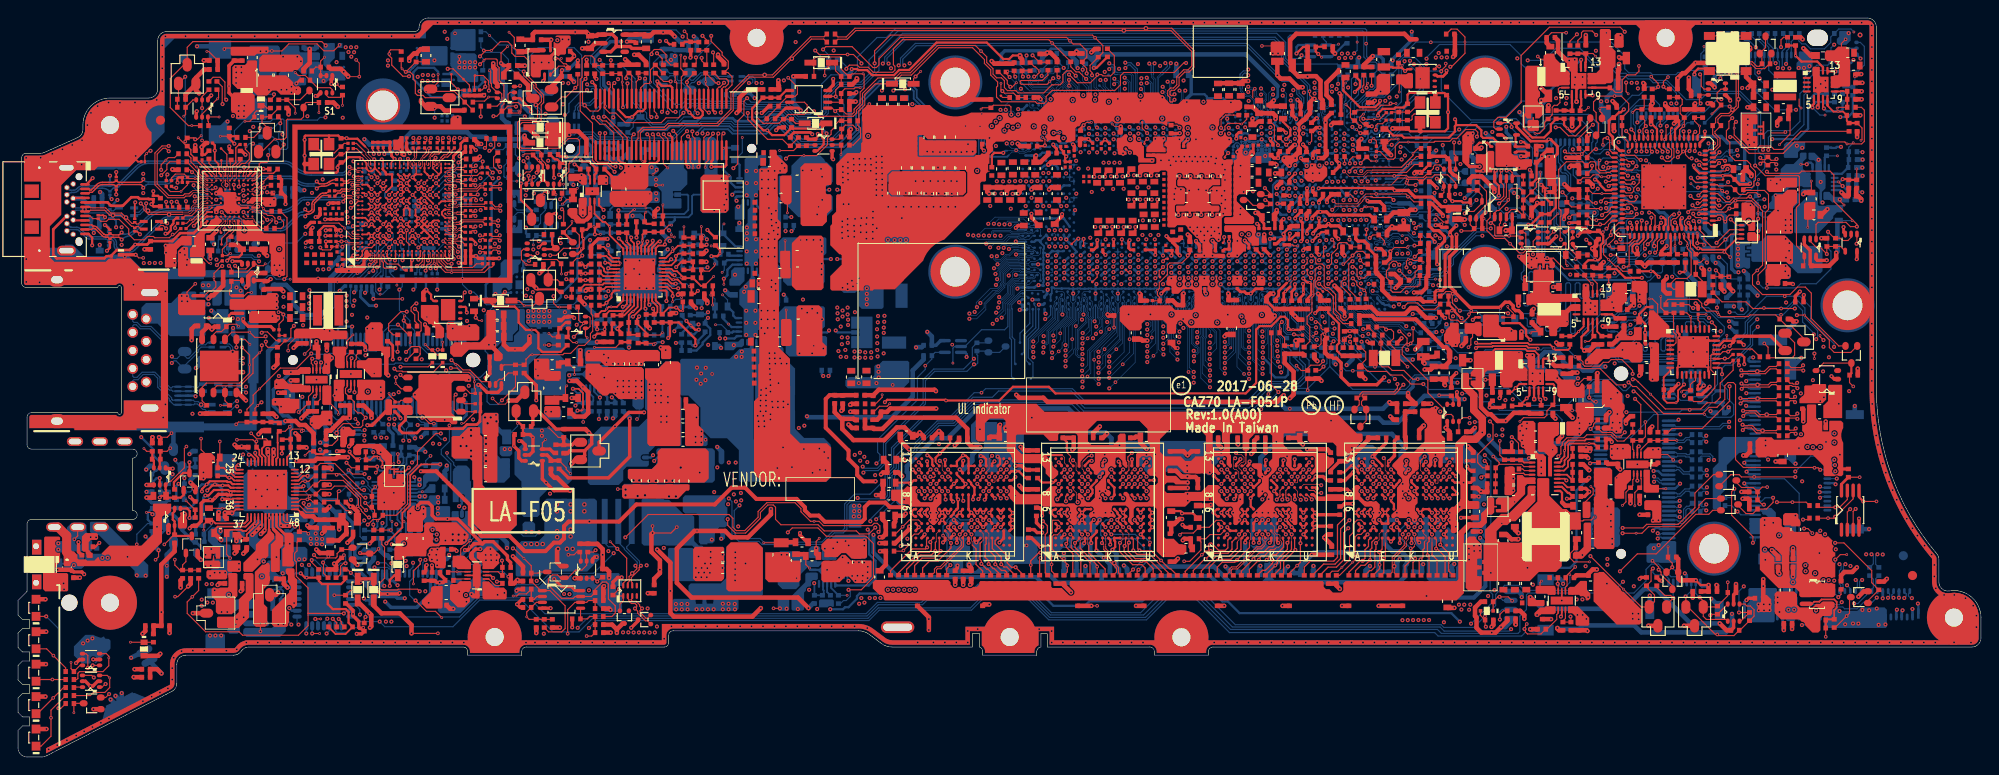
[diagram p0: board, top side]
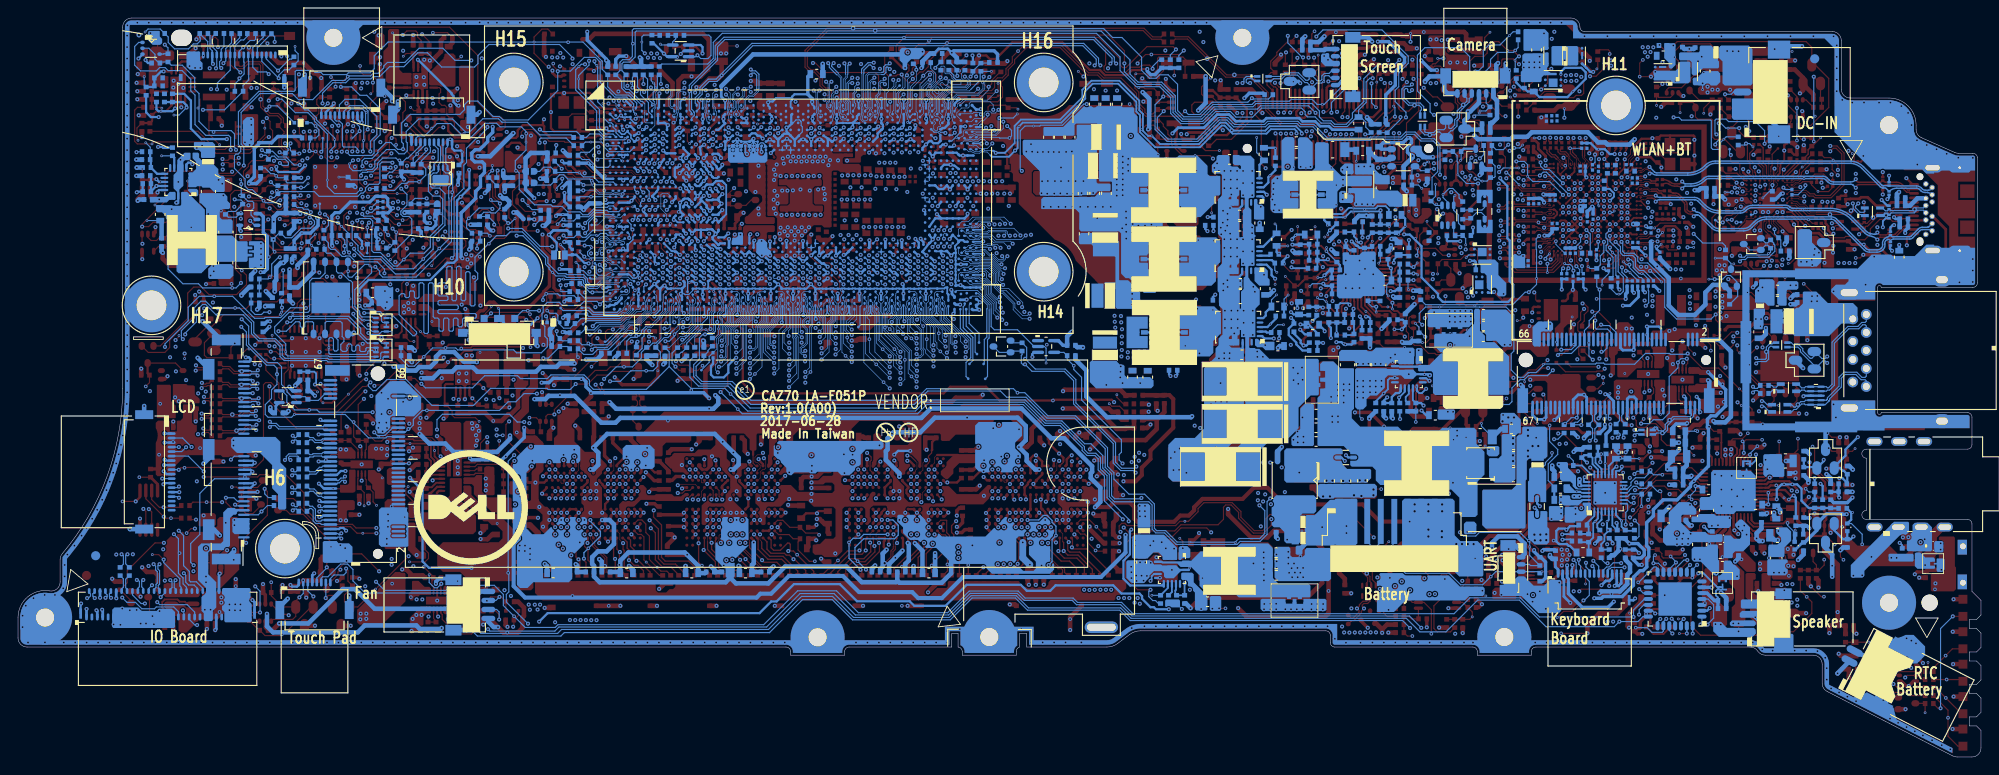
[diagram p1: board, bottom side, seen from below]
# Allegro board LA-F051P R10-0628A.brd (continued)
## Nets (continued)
DDI2_PTX_TBRX_N2_C: CT34.1 UT1.AC19
DDI2_PTX_TBRX_N3: CT36.2 UCPU1.D51
DDI2_PTX_TBRX_N3_C: CT36.1 UT1.AC21
DDI2_PTX_TBRX_P0: CT29.2 UCPU1.D50
DDI2_PTX_TBRX_P0_C: CT29.1 UT1.AB15
DDI2_PTX_TBRX_P1: CT31.2 UCPU1.D52
DDI2_PTX_TBRX_P1_C: CT31.1 UT1.AB17
DDI2_PTX_TBRX_P2: CT33.2 UCPU1.B50
DDI2_PTX_TBRX_P2_C: CT33.1 UT1.AB19
DDI2_PTX_TBRX_P3: CT35.2 UCPU1.C51
DDI2_PTX_TBRX_P3_C: CT35.1 UT1.AB21
DDR_A0_ZQ0: RD51.1 UD19.B3
DDR_A0_ZQ1: RD53.1 UD19.B4
DDR_A1_ZQ0: RD52.1 UD20.B3
DDR_A1_ZQ1: RD54.1 UD20.B4
DDR_A_CA1_0: RD59.1 UCPU1.BA51 UD19.R2
DDR_A_CA1_1: RD61.1 UCPU1.BB54 UD19.P2
DDR_A_CA1_2: RD63.1 UCPU1.BA52 UD19.N2
DDR_A_CA1_3: RD65.1 UCPU1.AY52 UD19.N3
DDR_A_CA1_4: RD67.1 UCPU1.AW52 UD19.M3
DDR_A_CA1_5: RD69.1 UCPU1.AY55 UD19.F3
DDR_A_CA1_6: RD71.1 UCPU1.AW54 UD19.E3
DDR_A_CA1_7: RD73.1 UCPU1.BA54 UD19.E2
DDR_A_CA1_8: RD75.1 UCPU1.BA55 UD19.D2
DDR_A_CA1_9: RD77.1 UCPU1.AY54 UD19.C2
DDR_A_CA2_0: RD79.1 UCPU1.AU46 UD20.R2
DDR_A_CA2_1: RD81.1 UCPU1.AU48 UD20.P2
DDR_A_CA2_2: RD83.1 UCPU1.AT46 UD20.N2
DDR_A_CA2_3: RD85.1 UCPU1.AU50 UD20.N3
DDR_A_CA2_4: RD87.1 UCPU1.AU52 UD20.M3
DDR_A_CA2_5: RD89.1 UCPU1.AY51 UD20.F3
DDR_A_CA2_6: RD91.1 UCPU1.AT48 UD20.E3
DDR_A_CA2_7: RD93.1 UCPU1.AT50 UD20.E2
DDR_A_CA2_8: RD95.1 UCPU1.BB50 UD20.D2
DDR_A_CA2_9: RD97.1 UCPU1.AY50 UD20.C2
DDR_A_CKE0: RD103.1 UCPU1.BA56 UD19.K3
DDR_A_CKE1: RD105.1 UCPU1.BB56 UD19.K4
DDR_A_CKE2: RD107.1 UCPU1.AW56 UD20.K3
DDR_A_CKE3: RD109.1 UCPU1.AY56 UD20.K4
DDR_A_CLK0: RD35.1 UCPU1.AT53 UD19.J3
DDR_A_CLK1: RD46.1 UCPU1.AT55 UD20.J3
DDR_A_CLK#0: RD37.1 UCPU1.AU53 UD19.J2
DDR_A_CLK#1: RD45.1 UCPU1.AU55 UD20.J2
DDR_A_CS#0: RD99.1 UCPU1.AU45 UD19.L3 UD20.L3
DDR_A_CS#1: RD101.1 UCPU1.AU43 UD19.L4 UD20.L4
DDR_A_D0: UCPU1.AL71 UD19.C8
DDR_A_D1: UCPU1.AL68 UD19.B11
DDR_A_D2: UCPU1.AN68 UD19.C9
DDR_A_D3: UCPU1.AN69 UD19.B10
DDR_A_D4: UCPU1.AL70 UD19.B9
DDR_A_D5: UCPU1.AL69 UD19.B8
DDR_A_D6: UCPU1.AN70 UD19.C11
DDR_A_D7: UCPU1.AN71 UD19.C10
DDR_A_D8: UCPU1.AR70 UD19.R10
DDR_A_D9: UCPU1.AR68 UD19.R11
DDR_A_D10: UCPU1.AU71 UD19.R9
DDR_A_D11: UCPU1.AU68 UD19.T10
DDR_A_D12: UCPU1.AR71 UD19.T11
DDR_A_D13: UCPU1.AR69 UD19.R8
DDR_A_D14: UCPU1.AU70 UD19.T9
DDR_A_D15: UCPU1.AU69 UD19.T8
DDR_A_D16: UCPU1.AF65 UD19.N9
DDR_A_D17: UCPU1.AF64 UD19.M8
DDR_A_D18: UCPU1.AK65 UD19.N11
DDR_A_D19: UCPU1.AK64 UD19.N10
DDR_A_D20: UCPU1.AF66 UD19.M9
DDR_A_D21: UCPU1.AF67 UD19.P9
DDR_A_D22: UCPU1.AK67 UD19.M11
DDR_A_D23: UCPU1.AK66 UD19.M10
DDR_A_D24: UCPU1.AF70 UD19.F11
DDR_A_D25: UCPU1.AF68 UD19.F10
DDR_A_D26: UCPU1.AH71 UD19.D9
DDR_A_D27: UCPU1.AH68 UD19.F8
DDR_A_D28: UCPU1.AF71 UD19.E10
DDR_A_D29: UCPU1.AF69 UD19.E11
DDR_A_D30: UCPU1.AH70 UD19.E9
DDR_A_D31: UCPU1.AH69 UD19.F9
DDR_A_D32: UCPU1.BB65 UD20.B9
DDR_A_D33: UCPU1.AW65 UD20.C11
DDR_A_D34: UCPU1.AW63 UD20.B11
DDR_A_D35: UCPU1.AY63 UD20.C8
DDR_A_D36: UCPU1.BA65 UD20.B8
DDR_A_D37: UCPU1.AY65 UD20.B10
DDR_A_D38: UCPU1.BA63 UD20.C10
DDR_A_D39: UCPU1.BB63 UD20.C9
DDR_A_D40: UCPU1.BA61 UD20.T9
DDR_A_D41: UCPU1.AW61 UD20.R9
DDR_A_D42: UCPU1.BB59 UD20.T11
DDR_A_D43: UCPU1.AW59 UD20.T10
DDR_A_D44: UCPU1.BB61 UD20.R8
DDR_A_D45: UCPU1.AY61 UD20.T8
DDR_A_D46: UCPU1.BA59 UD20.R10
DDR_A_D47: UCPU1.AY59 UD20.R11
DDR_A_D48: UCPU1.AT66 UD20.E10
DDR_A_D49: UCPU1.AU66 UD20.F10
DDR_A_D50: UCPU1.AP65 UD20.F8
DDR_A_D51: UCPU1.AN65 UD20.D9
DDR_A_D52: UCPU1.AN66 UD20.E9
DDR_A_D53: UCPU1.AP66 UD20.E11
DDR_A_D54: UCPU1.AT65 UD20.F9
DDR_A_D55: UCPU1.AU65 UD20.F11
DDR_A_D56: UCPU1.AT61 UD20.N9
DDR_A_D57: UCPU1.AU61 UD20.M9
DDR_A_D58: UCPU1.AP60 UD20.N11
DDR_A_D59: UCPU1.AN60 UD20.N10
DDR_A_D60: UCPU1.AN61 UD20.M8
DDR_A_D61: UCPU1.AP61 UD20.P9
DDR_A_D62: UCPU1.AT60 UD20.M10
DDR_A_D63: UCPU1.AU60 UD20.M11
DDR_A_DQS0: UCPU1.AM69 UD19.D10
DDR_A_DQS1: UCPU1.AT70 UD19.P10
DDR_A_DQS2: UCPU1.AH65 UD19.L10
DDR_A_DQS3: UCPU1.AG70 UD19.G10
DDR_A_DQS4: UCPU1.AY64 UD20.D10
DDR_A_DQS5: UCPU1.BA60 UD20.P10
DDR_A_DQS6: UCPU1.AR65 UD20.G10
DDR_A_DQS7: UCPU1.AR60 UD20.L10
DDR_A_DQS#0: UCPU1.AM70 UD19.D11
DDR_A_DQS#1: UCPU1.AT69 UD19.P11
DDR_A_DQS#2: UCPU1.AH66 UD19.L11
DDR_A_DQS#3: UCPU1.AG69 UD19.G11
DDR_A_DQS#4: UCPU1.BA64 UD20.D11
DDR_A_DQS#5: UCPU1.AY60 UD20.P11
DDR_A_DQS#6: UCPU1.AR66 UD20.G11
DDR_A_DQS#7: UCPU1.AR61 UD20.L11
DDR_A_ODT0: RD117.1 UCPU1.AT45 UD19.J8 UD20.J8
DDR_B0_ZQ0: RD57.1 UD21.B3
DDR_B0_ZQ1: RD58.1 UD21.B4
DDR_B1_ZQ0: RD55.1 UD22.B3
DDR_B1_ZQ1: RD56.1 UD22.B4
DDR_B_CA1_0: RD60.1 UCPU1.AY48 UD21.R2
DDR_B_CA1_1: RD62.1 UCPU1.AP50 UD21.P2
DDR_B_CA1_2: RD64.1 UCPU1.BA48 UD21.N2
DDR_B_CA1_3: RD66.1 UCPU1.BB48 UD21.N3
DDR_B_CA1_4: RD68.1 UCPU1.AP48 UD21.M3
DDR_B_CA1_5: RD70.1 UCPU1.AP52 UD21.F3
DDR_B_CA1_6: RD72.1 UCPU1.AN50 UD21.E3
DDR_B_CA1_7: RD74.1 UCPU1.AN48 UD21.E2
DDR_B_CA1_8: RD76.1 UCPU1.AN53 UD21.D2
DDR_B_CA1_9: RD78.1 UCPU1.AN52 UD21.C2
DDR_B_CA2_0: RD80.1 UCPU1.BA43 UD22.R2
DDR_B_CA2_1: RD82.1 UCPU1.AY43 UD22.P2
DDR_B_CA2_2: RD84.1 UCPU1.AY44 UD22.N2
DDR_B_CA2_3: RD86.1 UCPU1.AW44 UD22.N3
DDR_B_CA2_4: RD88.1 UCPU1.BB44 UD22.M3
DDR_B_CA2_5: RD90.1 UCPU1.AY47 UD22.F3
DDR_B_CA2_6: RD92.1 UCPU1.BA44 UD22.E3
DDR_B_CA2_7: RD94.1 UCPU1.AW46 UD22.E2
DDR_B_CA2_8: RD96.1 UCPU1.AY46 UD22.D2
DDR_B_CA2_9: RD98.1 UCPU1.BA46 UD22.C2
DDR_B_CKE0: RD104.1 UCPU1.AN56 UD21.K3
DDR_B_CKE1: RD106.1 UCPU1.AP55 UD21.K4
DDR_B_CKE2: RD108.1 UCPU1.AN55 UD22.K3
DDR_B_CKE3: RD110.1 UCPU1.AP53 UD22.K4
DDR_B_CLK0: RD36.1 UCPU1.AP45 UD21.J3
DDR_B_CLK1: RD47.1 UCPU1.AP46 UD22.J3
DDR_B_CLK#0: RD38.1 UCPU1.AN45 UD21.J2
DDR_B_CLK#1: RD48.1 UCPU1.AN46 UD22.J2
DDR_B_CS#0: RD100.1 UCPU1.BB42 UD21.L3 UD22.L3
DDR_B_CS#1: RD102.1 UCPU1.AY42 UD21.L4 UD22.L4
DDR_B_D0: UCPU1.AY39 UD21.E11
DDR_B_D1: UCPU1.AW39 UD21.F10
DDR_B_D2: UCPU1.AY37 UD21.F11
DDR_B_D3: UCPU1.AW37 UD21.D9
DDR_B_D4: UCPU1.BB39 UD21.F9
DDR_B_D5: UCPU1.BA39 UD21.E10
DDR_B_D6: UCPU1.BA37 UD21.F8
DDR_B_D7: UCPU1.BB37 UD21.E9
DDR_B_D8: UCPU1.AY35 UD21.T11
DDR_B_D9: UCPU1.AW35 UD21.T10
DDR_B_D10: UCPU1.AY33 UD21.T9
DDR_B_D11: UCPU1.AW33 UD21.R9
DDR_B_D12: UCPU1.BB35 UD21.R11
DDR_B_D13: UCPU1.BA35 UD21.R10
DDR_B_D14: UCPU1.BA33 UD21.T8
DDR_B_D15: UCPU1.BB33 UD21.R8
DDR_B_D16: UCPU1.AU40 UD21.B10
DDR_B_D17: UCPU1.AT40 UD21.B9
DDR_B_D18: UCPU1.AT37 UD21.C11
DDR_B_D19: UCPU1.AU37 UD21.B11
DDR_B_D20: UCPU1.AR40 UD21.B8
DDR_B_D21: UCPU1.AP40 UD21.C8
DDR_B_D22: UCPU1.AP37 UD21.C9
DDR_B_D23: UCPU1.AR37 UD21.C10
DDR_B_D24: UCPU1.AT33 UD21.N11
DDR_B_D25: UCPU1.AU33 UD21.M10
DDR_B_D26: UCPU1.AU30 UD21.N9
DDR_B_D27: UCPU1.AT30 UD21.P9
DDR_B_D28: UCPU1.AR33 UD21.M11
DDR_B_D29: UCPU1.AP33 UD21.N10
DDR_B_D30: UCPU1.AR30 UD21.M8
DDR_B_D31: UCPU1.AP30 UD21.M9
DDR_B_D32: UCPU1.AY31 UD22.E11
DDR_B_D33: UCPU1.AW31 UD22.F8
DDR_B_D34: UCPU1.AY29 UD22.F9
DDR_B_D35: UCPU1.AW29 UD22.E9
DDR_B_D36: UCPU1.BB31 UD22.D9
DDR_B_D37: UCPU1.BA31 UD22.E10
DDR_B_D38: UCPU1.BA29 UD22.F10
DDR_B_D39: UCPU1.BB29 UD22.F11
DDR_B_D40: UCPU1.AY27 UD22.B8
DDR_B_D41: UCPU1.AW27 UD22.C8
DDR_B_D42: UCPU1.AY25 UD22.B9
DDR_B_D43: UCPU1.AW25 UD22.B10
DDR_B_D44: UCPU1.BB27 UD22.C10
DDR_B_D45: UCPU1.BA27 UD22.C9
DDR_B_D46: UCPU1.BA25 UD22.C11
DDR_B_D47: UCPU1.BB25 UD22.B11
DDR_B_D48: UCPU1.AU27 UD22.T10
DDR_B_D49: UCPU1.AT27 UD22.T11
DDR_B_D50: UCPU1.AT25 UD22.T9
DDR_B_D51: UCPU1.AU25 UD22.R9
DDR_B_D52: UCPU1.AP27 UD22.R11
DDR_B_D53: UCPU1.AN27 UD22.R10
DDR_B_D54: UCPU1.AN25 UD22.R8
DDR_B_D55: UCPU1.AP25 UD22.T8
DDR_B_D56: UCPU1.AT22 UD22.M9
DDR_B_D57: UCPU1.AU22 UD22.N9
DDR_B_D58: UCPU1.AU21 UD22.M11
DDR_B_D59: UCPU1.AT21 UD22.N11
DDR_B_D60: UCPU1.AN22 UD22.M8
DDR_B_D61: UCPU1.AP22 UD22.P9
DDR_B_D62: UCPU1.AP21 UD22.M10
DDR_B_D63: UCPU1.AN21 UD22.N10
DDR_B_DQS0: UCPU1.AY38 UD21.G10
DDR_B_DQS1: UCPU1.BA34 UD21.P10
DDR_B_DQS2: UCPU1.AR38 UD21.D10
DDR_B_DQS3: UCPU1.AR32 UD21.L10
DDR_B_DQS4: UCPU1.AY30 UD22.G10
DDR_B_DQS5: UCPU1.BA26 UD22.D10
DDR_B_DQS6: UCPU1.AR27 UD22.P10
DDR_B_DQS7: UCPU1.AR21 UD22.L10
DDR_B_DQS#0: UCPU1.BA38 UD21.G11
DDR_B_DQS#1: UCPU1.AY34 UD21.P11
DDR_B_DQS#2: UCPU1.AT38 UD21.D11
DDR_B_DQS#3: UCPU1.AT32 UD21.L11
DDR_B_DQS#4: UCPU1.BA30 UD22.G11
DDR_B_DQS#5: UCPU1.AY26 UD22.D11
DDR_B_DQS#6: UCPU1.AR25 UD22.P11
DDR_B_DQS#7: UCPU1.AR22 UD22.L11
DDR_B_ODT0: RD118.1 UCPU1.BA42 UD21.J8 UD22.J8
DDR_CHA_EN: RH440.1 RH442.1 UCPU1.U2
DDR_CHB_EN: RH441.1 RH443.1 UCPU1.U1
DDR_ILMT: PR604.2 PR606.1 PU600.17
DDR_VTT_CNTL: UC2.2 UCPU1.AW67
DDR_XDP_SMBCLK: JXDP1.53 QC2.1 RN20.2
DDR_XDP_SMBDAT: JXDP1.51 QC2.4 RN19.2
DISPOFF#: D72.1 JEDP.9 R540.1
DMIC_CLK_CODEC: CA23.2 JKB1.12 RA58.1
DMIC_CLK_CODEC_R: RA58.2 UA2.3
DMIC_DAT_CODEC: CA25.2 JKB1.11 UA2.2
DPSRC_RBIAS: RT2.2 UT1.N6
EC_SLP_S0IX#: RC246.2 UCPU1.AY5 UE5.A43
EDP_AUXN: C1065.1 UCPU1.E45
EDP_AUXN_CONN: C1065.2 JEDP.25
EDP_AUXP: C1064.1 UCPU1.F45
EDP_AUXP_CONN: C1064.2 JEDP.26
EDP_BIA_PWM: D73.2 UCPU1.R11
EDP_COMP: RC2.2 UCPU1.E52
EDP_HPD: JEDP.14 RC1.2 UCPU1.L10
EDP_TXN_P0: C1062.1 UCPU1.C47
EDP_TXN_P0_CONN: C1062.2 JEDP.29
EDP_TXN_P1: C1063.1 UCPU1.D46
EDP_TXN_P1_CONN: C1063.2 JEDP.32
EDP_TXN_P2: C1066.1 UCPU1.A45
EDP_TXN_P2_CONN: C1066.2 JEDP.35
EDP_TXN_P3: C1068.1 UCPU1.A47
EDP_TXN_P3_CONN: C1068.2 JEDP.38
EDP_TXP_P0: C1060.1 UCPU1.C46
EDP_TXP_P0_CONN: C1060.2 JEDP.28
EDP_TXP_P1: C1061.1 UCPU1.C45
EDP_TXP_P1_CONN: C1061.2 JEDP.31
EDP_TXP_P2: C1067.1 UCPU1.B45
EDP_TXP_P2_CONN: C1067.2 JEDP.34
EDP_TXP_P3: C1069.1 UCPU1.B47
EDP_TXP_P3_CONN: C1069.2 JEDP.37
EDRAM_OPIO_RCOMP: RC90.1 UCPU1.H66
EMMC_RCOMP: RC4.1 UCPU1.AT1
EN_INVPWR: Q71.2 R1161.1 UE5.A25
EN_INVPWR_R: C613.2 Q70.3 R535.2 R536.1
EN_PD_HV: PR291.1 R1436.2
ENVDD: D94.1 R1027.2 UZ24.4
ENVDD_PCH: D94.3 UCPU1.U13 UE5.A7
EOPIO_RCOMP: RC91.1 UCPU1.H65
FAN1_PWM: JFAN1.3 R1103.1 UE5.A24
FAN1_TACH: D81.2 R884.1 UE5.B22
FB_GT: PR1079.2 PR1081.2 PR1096.1 PU1000.17
FB_IA: PR1065.2 PR1093.2 PR1098.2 PU1000.5
FB_VSA: PR1060.1 PR1073.1 PR1077.1 PU1000.25
FCCM_GT: PR1103.2 PU1000.21
FCCM_IA: PR1110.2 PR1119.2 PU1000.11
FCCM_VSA: PR1059.2 PU1000.29
FIVR_EN: RC217.1 RC218.2 RC219.2
FIVR_EN_R: JXDP1.45 RC126.2 RC132.2 RC217.2
FWP#: RE81.2 RE82.2 UE5.B65
GPP_B22: RC184.2 UCPU1.AN5
GPP_B23: RC26.1 UCPU1.AM7
GPP_C5: RC25.1 UCPU1.W1
GPP_E1: RC51.1 UCPU1.H3
GT_BST: PC1106.2 PU1100.3
GT_BST_R: PC1106.1 PR1100.1
GT_FCCM: PR1103.1 PU1100.2
GT_SNUB: PC1115.1 PR1101.2
GT_SW: PL1100.1 PR1101.1 PU1100.8
GT_SWH: PR1100.2 PU1100.5
GTP: PL1100.2 PR1102.1
H_CATERR#: RC79.2 UCPU1.D63
H_CPU_SVIDALRT#: RC153.1 UCPU1.B63
H_CPUPWRGD: CA35.1 RC77.2 UCPU1.A68
H_CPUPWRGD_R: RC77.1 T9.1(TP-1)
H_PROCHOT#: PC1006.2 PR316.1 PR405.2 PR1124.1 RC83.2 RC84.1 RE96.2
H_PROCHOT#_EC: RE96.1 UE5.A46
H_PROCHOT#_R: RC84.2 UCPU1.C65
H_THERMTRIP#: QE9.3 RC80.2 UCPU1.C63
H_VCCST_PWRGD: RE93.1 RE94.2 U729.2 UE5.A44
H_VCCST_PWRGD_P: CA32.1 RC71.2 RC78.1 RC123.1 RE94.1 U729.4
H_VCCST_PWRGD_XDP: JXDP1.39 RC123.2 RC124.2
HDA_AUDIO_PD#: RA59.2 UA2.47
HDA_BIT_CLK: RC93.2 UCPU1.AY22
HDA_BIT_CLK_R: CA30.2 CC27.1 RC93.1 UA2.6
HDA_RST#: CR26.2 T192.1(TP-1) UCPU1.AW22
HDA_SDIN0: CR25.2 RA62.1 UCPU1.BA21
HDA_SDIN0_R: RA62.2 UA2.8
HDA_SDOUT: CR24.2 RC94.2 RC187.2 RH24.2 UCPU1.BB22
HDA_SDOUT_R: CA27.2 RC94.1 UA2.5
HDA_SYNC: RC92.2 UCPU1.BA22
HDA_SYNC_R: CA24.2 RC92.1 UA2.10
HOST_DEBUG_TX: JDEG1.8 RE74.2 UE5.B44
HOST_SD_WP#: JIO1.37 RC292.2 UCPU1.AB3
HP2_D_L: RA17.1 RA48.2 RA50.2 RA61.1 UA2.32
HP2_D_L_C: CA29.2 DA2.3 JHP1.1 LA7.2
HP2_D_L_R1: LA7.1 RA17.2
HP2_D_R: RA15.1 RA49.2 RA51.2 RA60.1 UA2.33
HP2_D_R_C: CA69.1 DA2.2 JHP1.2 LA6.2
HP2_D_R_R2: LA6.1 RA15.2
I2C0_SCK_EDP: JEDP.1 R287.2 R291.2 U48.7
I2C0_SCK_EDP_PCH: R291.1 UCPU1.U6
I2C0_SDA_EDP: JEDP.6 R288.2 R292.2 U48.6
I2C0_SDA_EDP_PCH: R292.1 UCPU1.U7
I2C1_SCK: JTP1.3 MD10.3 QH7.4 R1105.1 RH456.2
I2C1_SCK_TP: QH7.3 RC285.2 RH456.1 UCPU1.U9
I2C1_SDA: JTP1.2 MD10.2 QH7.1 R1104.1 RH461.2
I2C1_SDA_TP: QH7.6 RC284.2 RH461.1 UCPU1.U8
I_ADP: PR315.1 UE5.A12
I_BATT: PR318.1 RE64.2
IA1N: PL1102.3 PR1112.1 PR1115.1
IA1P: PL1102.2 PR1116.2 PR1118.1
IA2N: PL1101.3 PR1107.1 PR1120.2
IA2P: PL1101.2 PR1109.1 PR1111.2
IA_BST1: PC1126.2 PU1102.3
IA_BST1_R: PC1126.1 PR1113.1
IA_BST2: PC1116.2 PU1101.3
IA_BST2_R: PC1116.1 PR1105.1
IA_FCCM1: PR1119.1 PU1102.2
IA_FCCM2: PR1110.1 PU1101.2
IA_SNUB1: PC1130.1 PR1114.2
IA_SNUB2: PC1125.1 PR1106.2
IA_SW1: PL1102.1 PR1114.1 PU1102.8
IA_SW2: PL1101.1 PR1106.1 PU1101.8
IA_SWH1: PR1113.2 PU1102.5
IA_SWH2: PR1105.2 PU1101.5
IMON_GT: PC1065.2 PR1071.2 PU1000.14
IMON_IA: PC1131.2 PR1099.2 PU1000.2
IMON_VSA: PC1080.1 PR1069.1 PU1000.23
IMVP_VR_ON: RE100.2 UC11.2 UE5.A1
IMVP_VR_ON_P: PR1029.1 RE100.1 RE101.1 UC11.4
INA199_OUT: PC204.1 PD201.1 PR214.1 PR227.1 PU201.3
INTRUDER#: RC69.1 UCPU1.AP16
INV_PWM_R: D73.1 JEDP.8 MC3.1 R545.1
IRQ_SERIRQ: RC21.2 UCPU1.AY11 UE5.A28
ISEN1_IA: PC1070.2 PR1118.2 PR1120.1 PR1127.1 PU1000.9
ISEN2_IA: PC1133.2 PR1109.2 PR1112.2 PR1128.1 PU1000.10
ISUMN_GT: PC1067.2 PC1075.2 PC1083.1 PH1009.2 PL1100.3 PR1068.2 PR1078.2 PR1085.2
ISUMN_GT_R: PC1069.1 PR1085.1 PU1000.20
ISUMN_IA: PC1070.1 PC1084.1 PC1085.2 PC1094.2 PC1133.1 PH1005.2 PR1061.1 PR1062.2 PR1087.1 PR1107.2 PR1115.2
ISUMN_IA_R: PC1088.2 PR1061.2 PU1000.8
ISUMN_VSA: PC1071.2 PC1078.2 PC1087.1 PH1006.2 PL1005.3 PR1058.2 PR1075.2 PR1092.2
ISUMN_VSA_R: PC1068.1 PR1075.1 PU1000.28
ISUMP_GT: PC1067.1 PC1075.1 PR1078.1 PR1097.1 PR1102.2 PU1000.19
ISUMP_IA: PC1085.1 PC1094.1 PR1062.1 PR1088.1 PR1111.1 PR1116.1 PU1000.7
ISUMP_VSA: PC1071.1 PC1078.1 PR1058.1 PR1089.1 PR1091.2 PU1000.27
ITP_PMODE: JXDP1.46 RC115.1 UCPU1.E8
JACK_PLUG: DA1.3 JHP1.6 QA3.5 RA26.1 RA35.1
JACK_PLUG_DL: CA74.1 QA3.6 QA6.2 RA20.1 RA26.2 RA31.1 RA38.2
JACK_PLUG_DL#: QA6.1 RA31.2 RA75.1
JTAG_CLK: JDEG1.4 RPE7.3 UE5.B56
JTAG_RST#: CE59.1 JTAG1.1 RE65.2 RE66.1 UE5.B47
JTAG_TDI: JDEG1.2 RPE7.1 UE5.A51
JTAG_TDO: JDEG1.5 RPE7.4 UE5.B55
JTAG_TMS: JDEG1.3 RPE7.2 UE5.A53
K52: T199.1(TP-1) UCPU1.K52
KB_DET#: JKB1.5 RC288.2 UCPU1.BB7
LANWAKE#: RC95.2 UCPU1.AM15 UE5.B27
LCD_TST: JEDP.19 RE58.2 UE5.A38
LCD_VCC_TEST_EN: D94.2 UE5.A39
LDO_EN: PC209.1 PD204.1 PD205.1 PR240.2 PU202.1
LID_CL_SIO#: CE13.1 RE25.2 RE26.2 UE5.A21
LID_SW_IN#: JIO1.44 RE26.1
LINE1-VREFO_L: RA48.1 UA2.31
LINE1-VREFO_R: RA49.1 UA2.30
LINE1_L: CA70.1 UA2.22
LINE1_L_C: CA70.2 RA50.1
LINE1_R: CA71.1 UA2.21
LINE1_R_C: CA71.2 RA51.1
LPC_LAD0: JLPDE1.3 UCPU1.AY13 UE5.A30
LPC_LAD1: JLPDE1.4 UCPU1.BA13 UE5.B32
LPC_LAD2: JLPDE1.5 UCPU1.BB13 UE5.A31
LPC_LAD3: JLPDE1.6 UCPU1.AY12 UE5.B33
LPC_LFRAME#: JLPDE1.7 UCPU1.BA12 UE5.B31
LPM_ZVM_N: T200.1(TP-1) UCPU1.AR56
LPS_PROTECT#: PD206.1 PR274.2 PR287.1 UE5.B2
MCARD_PCIE_SATA#: JNGFF2.61 R220.2 R2665.2 U683.2
ME_EN: R1191.1 RH24.1 SW1.2
ME_FWP_EC: R1191.2 SW1.3 UE5.B1
ME_RESET#: RC225.2 RC227.1 UC12.2
ME_SUS_PWR_ACK: RC74.2 UCPU1.AR13 UE5.A8
MEC_XTAL1: CE62.1 UE5.A61 YE1.1
MEC_XTAL2: CE53.1 RE62.2 YE1.2
MEC_XTAL2_R: RE62.1 UE5.A62
MEDIACARD_IRQ#: JIO1.42 RC13.2 UCPU1.M1
MEM_CONFIG0: RH129.2 RH144.1 UCPU1.AP2
MEM_CONFIG1: RH139.2 RH150.1 UCPU1.AP1
MEM_CONFIG2: RH145.2 RH149.1 UCPU1.AP3
MEM_CONFIG3: RH146.2 RH151.1 UCPU1.AN3
MEM_CONFIG4: RH147.2 RH152.1 UCPU1.AN1
MEM_SMBCLK: QC2.6 RC12.1 UCPU1.R7
MEM_SMBDATA: QC2.3 RC14.1 UCPU1.R8
MIC2-VREFO: RA27.1 RA28.1 UA2.29
MONO_IN: CA34.2 UA2.16
MPHYP_PWR_EN: RH557.1 UCPU1.AM10
MSCLK: JDEG1.6 RE72.2 RE105.1
MSDATA: JDEG1.7 RE75.2 RE85.1 RE104.1
MSM_N: T201.1(TP-1) UCPU1.AP56
NB_MUTE#: RA57.1 RA59.1 UE4.20
NB_PSID: JP100.3 PR108.2
NC: U728.4
NC_B4: RT50.2 UT1.B4
NC_B5: RT48.2 UT1.B5
NC_G2: RT49.2 UT1.G2
NRB_BIT: RC186.2 UCPU1.AR7
NTC_GT: PR1064.2 PU1000.15
NTC_IA: PR1072.2 PU1000.3
P_SYS: PC1538.1 PR319.1 PR1083.1 PR1425.1 UE5.A57
PANEL_BKEN_EC: D72.3 UE4.4
PANEL_BKLEN: D72.2 UCPU1.R12
PBAT_PRES#: PD100.3 PR100.2 PR326.1 PRP100.1 UE5.A49
PBAT_SMBCLK: PD101.3 PRP100.3 RE53.2 UE5.A56
PBAT_SMBDAT: PD101.2 PRP100.2 RE52.2 UE5.B59
PBATT+_C: JBATT1.1 JBATT1.2 PC101.1 PC102.2 PL100.2 PL101.2
PBTN_SW#: CE21.1 JAPS1.11 JIO1.35 RE33.2 SW2.2 SW2.4
PCH_ALW_ON: R1443.1 UE5.A34
PCH_BATLOW#: RC72.1 UCPU1.AU13
PCH_DPWROK: RC221.2 UE5.A36
PCH_DPWROK_R: CC266.1 RC215.1 RC220.1 RC221.1 UCPU1.BB20
PCH_JTAG_TCLK: JXDP1.55 RC86.2 UCPU1.B56
PCH_PCIE_WAKE#: RC67.2 UCPU1.BB15 UE5.B46
PCH_PLTRST#: RC85.2 RC226.2 UC7.1 UC7.2 UCPU1.AN10
PCH_PLTRST#_EC: JIO1.38 JLPDE1.8 JNGFF1.44 JNGFF2.50 R104.1 RC65.1 RC226.1 RE54.2 U15.17 UC7.4 UE5.B30
PCH_POPIRCOMP: RC89.1 UCPU1.AU16
PCH_PWR_EN: R1187.2 R1443.2 R1444.2 U717.3
PCH_PWROK: PR1027.1 RC313.2 UCPU1.BA20
PCH_RSMRST#: RC75.2 RC124.1 RC215.2 UCPU1.AY17 UE5.A45
PCH_RTCRST#: CC25.1 CMOS1.1 JAPS1.9 RC57.1 UCPU1.AM16
PCH_RTCX1: CC23.1 RC54.2 UCPU1.AM18 YC2.1
PCH_RTCX2: RC54.1 RC296.1 UCPU1.AM20
PCH_RTCX2_R: CC26.1 RC296.2 YC2.2
PCH_RTD3_CIO_PWR_EN: RC248.1 UCPU1.H5
PCH_SMB_ALERT#: RC23.1 UCPU1.R10
PCH_SPI_CLK: JSPI1.8 RC60.1 UCPU1.AV2
PCH_SPI_CLK_R: JSPI1.7 RC60.2 RP5.6 RP5.7
PCH_SPI_CLK_TPM: C135.1 RP5.3 U15.19
PCH_SPI_CS0#: JSPI1.10 RC58.1 UCPU1.AU3
PCH_SPI_CS0#_R: JSPI1.9 RC58.2 U18.1
PCH_SPI_CS2#: RC230.2 RH127.1 U15.20 UCPU1.AU1
PCH_SPI_DO2_XDP: JXDP1.60 RC11.1
PCH_SPI_DO_XDP: RC10.1 RC128.1 RC133.2
PCH_SPI_IO2: JSPI1.12 RC11.2 RC61.1 RH59.2 UCPU1.AW2
PCH_SPI_IO2_R: JSPI1.11 RC61.2 RP6.6
PCH_SPI_IO3: JSPI1.14 RC62.1 RH56.2 RH58.2 UCPU1.AU4
PCH_SPI_IO3_R: JSPI1.13 RC62.2 RP6.5
PCH_SPI_SI: JSPI1.4 RC10.2 RC55.1 UCPU1.AV3
PCH_SPI_SI_R: JSPI1.3 RC55.2 RP5.5 RP5.8
PCH_SPI_SI_TPM: RP5.4 U15.21
PCH_SPI_SO: JSPI1.6 RC53.1 UCPU1.AW3
PCH_SPI_SO_R: JSPI1.5 RC53.2 RP6.7 RP6.8
PCH_SPI_SO_TPM: RP6.1 U15.24
PCH_TBT_FORCE_PWR: RC247.1 UCPU1.D7
PCI_CLK_LPC0: RC18.1 UCPU1.AW9
PCI_CLK_LPC1: RC22.1 UCPU1.AY9
PCIE_PRX_CARDTX_N6: JIO1.28 UCPU1.G18
PCIE_PRX_CARDTX_P6: JIO1.26 UCPU1.F18
PCIE_PRX_SSDTX_N9: JNGFF2.5 UCPU1.E22
PCIE_PRX_SSDTX_N10: JNGFF2.17 UCPU1.F25
PCIE_PRX_SSDTX_N11: JNGFF2.29 UCPU1.E28
PCIE_PRX_SSDTX_P9: JNGFF2.7 UCPU1.E23
PCIE_PRX_SSDTX_P10: JNGFF2.19 UCPU1.E25
PCIE_PRX_SSDTX_P11: JNGFF2.31 UCPU1.E27
PCIE_PRX_TBTX_N1: CT3.1 UCPU1.H13
PCIE_PRX_TBTX_N1_C: CT3.2 UT1.V22
PCIE_PRX_TBTX_N2: CT7.1 UCPU1.G11
PCIE_PRX_TBTX_N2_C: CT7.2 UT1.P22
PCIE_PRX_TBTX_P1: CT1.1 UCPU1.G13
PCIE_PRX_TBTX_P1_C: CT1.2 UT1.V23
PCIE_PRX_TBTX_P2: CT5.1 UCPU1.F11
PCIE_PRX_TBTX_P2_C: CT5.2 UT1.P23
PCIE_PRX_WLANTX_N5: JNGFF1.35 UCPU1.F16
PCIE_PRX_WLANTX_P5: JNGFF1.33 UCPU1.E16
PCIE_PTX_CARDRX_N6: CH14.1 UCPU1.D20
PCIE_PTX_CARDRX_N6_C: CH14.2 JIO1.16
PCIE_PTX_CARDRX_P6: CH13.1 UCPU1.C20
PCIE_PTX_CARDRX_P6_C: CH13.2 JIO1.14
PCIE_PTX_SSDRX_N9: CD39.1 UCPU1.B23
PCIE_PTX_SSDRX_N9_C: CD39.2 JNGFF2.11
PCIE_PTX_SSDRX_N10: CD45.1 UCPU1.D23
PCIE_PTX_SSDRX_N10_C: CD45.2 JNGFF2.23
PCIE_PTX_SSDRX_N11: CD53.1 UCPU1.D24
PCIE_PTX_SSDRX_N11_C: CD53.2 JNGFF2.35
PCIE_PTX_SSDRX_P9: CD43.1 UCPU1.A23
PCIE_PTX_SSDRX_P9_C: CD43.2 JNGFF2.13
PCIE_PTX_SSDRX_P10: CD46.1 UCPU1.C23
PCIE_PTX_SSDRX_P10_C: CD46.2 JNGFF2.25
PCIE_PTX_SSDRX_P11: CD51.1 UCPU1.C24
PCIE_PTX_SSDRX_P11_C: CD51.2 JNGFF2.37
PCIE_PTX_TBRX_N1: CT4.2 UCPU1.B17
PCIE_PTX_TBRX_N1_C: CT4.1 UT1.Y22
PCIE_PTX_TBRX_N2: CT8.2 UCPU1.D16
PCIE_PTX_TBRX_N2_C: CT8.1 UT1.T22
PCIE_PTX_TBRX_P1: CT2.2 UCPU1.A17
PCIE_PTX_TBRX_P1_C: CT2.1 UT1.Y23
PCIE_PTX_TBRX_P2: CT6.2 UCPU1.C16
PCIE_PTX_TBRX_P2_C: CT6.1 UT1.T23
PCIE_PTX_WLANRX_N5: CH11.1 UCPU1.C19
PCIE_PTX_WLANRX_N5_C: CH11.2 JNGFF1.29
PCIE_PTX_WLANRX_P5: CH12.1 UCPU1.D19
PCIE_PTX_WLANRX_P5_C: CH12.2 JNGFF1.27
PCIE_RBIAS: RT1.2 UT1.N16
PCIE_RCOMPN: RC45.1 UCPU1.F5
PCIE_RCOMPP: RC45.2 UCPU1.E5
PCIE_WAKE#: JNGFF1.47 RE86.1 RE120.2 UE5.B8
PD_EE_CLK: U722.A3 UT6.6
PD_EE_CS#: R1477.2 U722.B3 UT6.1
PD_EE_DI: U722.B4 UT6.5
PD_EE_DO: R1475.2 U722.A4 UT6.2
PD_EE_WP#: R1474.2 UT6.3
PD_HOLD#: R1476.2 UT6.7
PD_OVP: PQ218.6 PR253.2 PR288.1
PD_SENSEN: TC45.1(TP-1) U722.A10
PD_SENSEP: TC44.1(TP-1) U722.B10
PECI_EC: RE61.2 UCPU1.A54
PECI_EC_R: CE68.1 RE61.1 UE5.A48
PME#: T115.1(TP-1) UCPU1.AU11
POWER_SW_IN#: CE49.1 RE31.2 RE33.1 RE35.1 UE5.B67
PRIM_CORE_B+: PC1413.1 PC1414.1 PC1417.1 PC1418.1 PL1402.2 PU1401.10 PU1401.11 PU1401.12
PRIM_CORE_EN: PC1412.1 PR1412.2 PR1413.1 PU1401.13
PRIM_CORE_FBS: PR1421.1 PR1422.1 PU1401.5
PRIM_CORE_LPM: PR1411.2 PR1424.2 PU1401.14
PRIM_CORE_LX: PL1403.1 PR1416.1 PU1401.2 PU1401.3
PRIM_CORE_SNUB: PC1419.1 PR1416.2
PRIM_CORE_SS: PC1420.1 PU1401.7
PROG1_CORE: PR1094.1 PU1000.32
PROG2_CORE: PR1121.1 PU1000.31
PS_ID: PR102.2 PR103.2 UE5.B24
PSYS_CORE: PR1083.2 PU1000.1
PTP_DIS#: JTP1.6 UE4.21
PTP_INT#_EC: DZ3.1 Q40.1 RPE5.2 UE5.B37
PTP_INT#_R: JTP1.5 Q40.3 R1299.2
PWM1_IA: PU1000.12 PU1102.1
PWM2_IA: PU1000.13 PU1101.1
PWM_GT: PU1000.22 PU1100.1
PWM_VSA: PU1000.30 PU1305.3
PWR_SRC_LIMIT: PC205.1 PD201.2 PR216.1 PR226.2 PR227.2 PU201.1 U722.G10
PWR_SRC_ON: PR218.2 UE5.B42
PWR_SRC_ON_PC: PR229.2 U722.D10
PWR_TB_DOCK#: R1440.2 RE35.2
REM_DIODE1_N: CE47.1 CE58.1 QE3.3 UE5.B13
REM_DIODE1_P: CE47.2 CE58.2 QE3.1 QE3.2 UE5.A13
REM_DIODE2_N: CE48.2 CE57.2 CE67.1 QE4.3 QE11.1 QE11.2 UE5.B14
REM_DIODE2_P: CE48.1 CE57.1 CE67.2 QE4.1 QE4.2 QE11.3 UE5.A14
REM_DIODE3_N: CE39.1 CE66.2 QE10.3 UE5.A15
REM_DIODE3_P: CE39.2 CE66.1 QE10.1 QE10.2 UE5.B16
REM_DIODE4_N: CE51.1 CE60.1 QE8.3 UE5.A16
REM_DIODE4_P: CE51.2 CE60.2 QE8.1 QE8.2 UE5.B17
RESET_OUT#: RC129.1 RE2.2 UCPU1.B6 UE5.B39
RESET_OUT#_R: CC33.1 JXDP1.47 RC128.2 RC129.2
RING2: RA28.2 RA64.1 UA2.17
RING2_R: CA68.2 DA7.1 JHP1.4 QA1.6 RA64.2
RTD3_CIO_PWR_EN: RC248.2 RT26.2 RT39.2 UT1.F1
RTD3_USB_PWR_EN: RT40.2 RT52.2 UT1.D4
RUN_ON: R250.2 UE5.B9
RUN_ON#: QE12.5 QE12.6 RE84.2
RUN_ON_EC: QE12.2 R249.1 R250.1 RE98.2 UC10.2
RUN_ON_P: PR611.1 PR901.1 R290.2 R1445.1 RE98.1 RE99.1 U719.3 U720.5 UC9.2 UC10.4
RUNPWROK: QE12.3 RE83.2 UE5.B26
SA_B+: PC1066.1 PC1076.1 PC1079.1 PC1093.1 PL1004.1 PQ1302.2 PQ1302.3 PQ1302.4 PQ1302.10
SA_BST: PC1082.2 PU1305.2
SA_BST_R: PC1082.1 PR1082.1
SA_FCCM: PR1059.1 PU1305.7
SA_LGATE: PQ1302.8 PU1305.5
SA_SNUB: PC1086.1 PR1086.2
SA_SW: PL1005.1 PQ1302.9 PR1082.2 PR1086.1 PU1305.8
SA_UGATE: PQ1302.1 PU1305.1
SAP: PL1005.2 PR1091.1
SATA_PRX_SSDTX_N2: R2664.1 UCPU1.E30
SATA_PRX_SSDTX_N2_C: JNGFF2.43 R2664.2
SATA_PRX_SSDTX_P2: R2663.1 UCPU1.F30
SATA_PRX_SSDTX_P2_C: JNGFF2.41 R2663.2
SATA_PTX_SSDRX_N2: CD47.1 UCPU1.A25
SATA_PTX_SSDRX_N2_C: CD47.2 JNGFF2.47
SATA_PTX_SSDRX_P2: CD44.1 UCPU1.B25
SATA_PTX_SSDRX_P2_C: CD44.2 JNGFF2.49
SCLK_CORE: PR1070.2 PU1000.37
SD_PWR_EN: R1176.1 R1178.1 U716.5 UCPU1.BA9
SD_RCOMP: RC96.1 UCPU1.AB7
SDA_CORE: PR1028.2 PU1000.35
SIO_EXT_SCI#: RC237.2 UCPU1.AN7 UE5.A33
SIO_EXT_SMI#: RC236.2 UCPU1.A6 UE5.A6
SIO_EXT_WAKE#: RC283.2 UCPU1.AD3 UE5.B5
SIO_PWRBTN#: CC269.1 JXDP1.41 RC241.2 UCPU1.BA15 UE5.B58
SIO_RCIN#: RC16.2 UCPU1.AW13 UE5.A27
SIO_SLP_A#: JAPS1.6 UCPU1.AN16 UE5.B28
SIO_SLP_S0#: JAPS1.15 PR1400.1 PR1411.1 R1006.1 RE92.1 UC9.1 UCPU1.AT11
SIO_SLP_S3#: JAPS1.2 R249.2 RT119.1 U729.1 UC10.1 UC11.1 UCPU1.AP15 UE5.A35
SIO_SLP_S4#: JAPS1.5 R252.2 UC8.1 UCPU1.BA16 UE5.B36
SIO_SLP_S5#: JAPS1.4 UCPU1.AY16 UE5.A18
SIO_SLP_SUS#: PR700.1 PR801.1 PR1412.1 QE13.2 R1444.1 RC97.1 UC13.1 UCPU1.AN15
SIO_SLP_SUS#_R: RC97.2 UE5.B52
SIO_SLP_WLAN#: UCPU1.BB17 UE5.B45
SLEEVE: RA27.2 RA65.1 UA2.18
SLEEVE_R: CA28.1 DA5.1 JHP1.3 QA1.3 RA65.2
SM_PG_CTRL: PR609.1 RE60.2 UC2.4
SM_RCOMP0: RC5.1 UCPU1.AR18
SM_RCOMP1: RC6.1 UCPU1.AT18
SM_RCOMP2: RC7.1 UCPU1.AU18
SML1_SMBCLK: RC15.1 UCPU1.W3 UE5.B6
SML1_SMBDAT: RC17.1 UCPU1.V3 UE5.A5
SPI_CLK_VROM: RC29.2 RP5.2 U18.6
SPI_IO2_VROM: RP6.3 U18.3
SPI_IO3_VROM: RP6.4 U18.7
SPI_SI_VROM: RP5.1 U18.5
SPI_SO_VROM: RP6.2 U18.2
SPK_L+_C: CA55.2 DA3.3 JSPK1.4 L2.2
SPK_L-_C: CA53.2 DA3.2 JSPK1.3 L3.2
SPK_OUT_L+: L2.1 UA2.42
SPK_OUT_L-: L3.1 UA2.43
SPK_OUT_R+: L5.1 UA2.45
SPK_OUT_R-: L4.1 UA2.44
SPK_R+_C: CA56.2 DA4.3 JSPK1.1 L5.2
SPK_R-_C: CA54.2 DA4.2 JSPK1.2 L4.2
SPKR: RA25.1 RC183.2 UCPU1.AW5
SRTCRST#: CC24.1 RC56.1 UCPU1.AN18
SSD_DEVSLP: JNGFF2.38 R1376.2 UCPU1.J3
SSD_IFDET: R2665.1 RC51.2 U683.4 UCPU1.G4
SSD_PCIE_WAKE#: JNGFF2.54 R1377.1
SSD_PWR_EN: R1188.2 R1446.1 UCPU1.W12
SUS_ON_EC: R251.1 R252.1 RE68.1 RE95.2 UC8.2
SUS_ON_P: PR607.1 PR800.1 PR900.1 RE95.1 RE97.1 UC8.4 UC13.2 UZ23.4
SUSACK#: UCPU1.AP11 UE5.B7
SUSCLK: R1255.2 R2662.2 RC48.1 UCPU1.BA17
SYS_RESET#: JAPS1.13 RC224.2 RC291.2 UCPU1.B5
SYS_RESET#_R: RC224.1 RC290.2 UC12.4
SYSTEM_WAKE#: QT19.3 R1439.2 R1462.2
TBT_AUX_N: CT42.2 R1478.2 U722.J2
TBT_AUX_N_C: CT42.1 UT1.W15
TBT_AUX_P: CT41.2 R1472.2 U722.J1
TBT_AUX_P_C: CT41.1 UT1.Y15
TBT_BATLOW#: RT25.2 UT1.F2
TBT_CC1: C1279.1 D77.1 JUSBC1.A5 U722.K9 U722.L9
TBT_CC2: C1280.1 D86.1 JUSBC1.B5 U722.K10 U722.L10
TBT_CIO_PLUG_EVENT#: RT23.2 UCPU1.AB12 UT1.W2
TBT_DBG_CTL1: R1454.2 U722.E4
TBT_DBG_CTL2: R1460.2 U722.D5
TBT_DDC_CLK: RT33.2 UT1.Y2
TBT_DDC_DATA: RT34.2 UT1.Y1
TBT_DEBUG3: R1463.2 RT188.1 U722.L3
TBT_DEBUG4: R1464.2 RT187.1 U722.K3
TBT_FORCE_PWR: RC247.2 RT38.2 UT1.H4
TBT_HPD: R1437.2 RT43.2 UT1.M4
TBT_I2C_B_N: ML7.4 U722.L7
TBT_I2C_B_N_R: D90.1 JUSBC1.B7 ML7.3
TBT_I2C_B_P: ML7.1 U722.K7
TBT_I2C_B_P_R: D91.1 JUSBC1.B6 ML7.2
TBT_I2C_CLK: RT36.2 U722.D2 UT1.U2
TBT_I2C_DATA: RT35.2 U722.D1 UT1.U1
TBT_I2C_INT#: RT47.2 U722.C1 UT1.J4
TBT_JTAG_TCK: RT7.2 TC41.1(TP-1) UT1.T4
TBT_JTAG_TDI: RT9.2 TC39.1(TP-1) UT1.Y4
TBT_JTAG_TDO: RT6.2 TC42.1(TP-1) UT1.W4
TBT_JTAG_TMS: RT8.2 TC40.1(TP-1) UT1.V4
TBT_LDO_BMC: CT144.1 U722.E1
TBT_LSRX: R1461.1 R1464.1 RT45.2 UT1.A4
TBT_LSRX_R: R1461.2 U722.K4
TBT_LSTX: R1459.1 R1463.1 RT44.2 UT1.A5
TBT_LSTX_R: R1459.2 U722.L4
TBT_PCIE_WAKE#: RE120.1 RT22.2 UT1.W1
TBT_PD_SBU1: R1457.1 U722.K8
TBT_PD_SBU2: R1458.1 U722.L8
TBT_PERST_N: R104.2 UT1.L4
TBT_PWR_EN: RH556.1 UCPU1.AW7
TBT_RBIAS: RT10.1 UT1.H6
TBT_RESET_N: RT120.1 U722.F11
TBT_RESET_N_EC: R1465.2 RE90.1 RT121.1 UE5.A4
TBT_RESET_N_R: RT51.2 RT120.2 RT121.2 UT1.F4
TBT_ROM_CLK: UT1.AB4 UT5.6
TBT_ROM_CS#: RT18.2 UT1.AC3 UT5.1
TBT_ROM_DI: UT1.AB3 UT5.5
TBT_ROM_DO: RT16.2 UT1.AC4 UT5.2
TBT_ROM_HOLD#: RT15.2 UT5.7
TBT_ROM_WP#: RT17.2 UT1.V1 UT5.3
TBT_RSENSE: RT10.2 UT1.J6
TBT_SBU1: D78.1 JUSBC1.A8 R1457.2
TBT_SBU2: D87.1 JUSBC1.B8 R1458.2
TBT_SLP_S3#: RT119.2 UT1.D2
TBT_SRC_CFG1: R1403.1 UT1.AA1
TBT_SRC_HPD: R1405.1 UT1.G1
TBT_SVR_IND: CT172.1 CT173.1 LT1.1 UT1.C1 UT1.C2 UT1.D1
TBT_TEST_EN: RT3.2 UT1.E1
TBT_TEST_PWRG: RT4.2 UT1.AB5
TBT_TMU_CLK_OUT: RT37.2 UT1.V2
TBT_USB2_D_N: U722.K5 UT1.D20
TBT_USB2_D_P: U722.L5 UT1.E20
TBT_USB2_T_N: ML6.4 U722.L6
TBT_USB2_T_N_R: D83.1 JUSBC1.A7 ML6.3
TBT_USB2_T_P: ML6.1 U722.K6
TBT_USB2_T_P_R: D82.1 JUSBC1.A6 ML6.2
TBT_USB3_RX0_N: D85.1 JUSBC1.B10 UT1.A21
TBT_USB3_RX0_P: D84.1 JUSBC1.B11 UT1.B21
TBT_USB3_RX1_N: D79.1 JUSBC1.A10 UT1.B15
TBT_USB3_RX1_P: D80.1 JUSBC1.A11 UT1.A15
TBT_USB3_TX0_N: CT40.2 D76.1 JUSBC1.A3
TBT_USB3_TX0_N_C: CT40.1 UT1.B19
TBT_USB3_TX0_P: CT39.2 D75.1 JUSBC1.A2
TBT_USB3_TX0_P_C: CT39.1 UT1.A19
TBT_USB3_TX1_N: CT38.2 D89.1 JUSBC1.B3
TBT_USB3_TX1_N_C: CT38.1 UT1.B17
TBT_USB3_TX1_P: CT37.2 D88.1 JUSBC1.B2
TBT_USB3_TX1_P_C: CT37.1 UT1.A17
TBT_USB_OC0#: R1438.2 RC189.1 UCPU1.A9
TBT_VBUS: C397.2 C398.2 C401.2 C402.2 C1353.1 CT9.1 D123.1 DI7.2 DI7.3 JUSBC1.A4 JUSBC1.A9 JUSBC1.B4 JUSBC1.B9 LT106.2 PQ210.1 PQ210.2 PQ210.5 PQ210.6 PQ210.7 PR264.1
TBT_VBUS_L: C1339.1 LT106.1 U722.H11 U722.J10 U722.J11 U722.K11
TCLK_XDP: JXDP1.57 RC87.1 RC139.2 UCPU1.A59 UCPU1.B61
TDI_XDP: JXDP1.56 RC81.2 RC134.2 UCPU1.D59 UCPU1.D60
TDO_XDP: JXDP1.52 RC82.2 RC135.2 UCPU1.A56 UCPU1.A61
THERMATRIP2#: CE61.1 QE9.1 RE69.2 UE5.B34
THERMATRIP3#: RE67.1 UE5.A2
THERMDA: UT1.AB23 UT1.AC23
THSEL_STRAP: RE78.1 UE5.B29
TMS_XDP: JXDP1.58 RC130.2 RC131.2 UCPU1.C59 UCPU1.C60
TOUCH_SCREEN_PD#: JTS.5 RC277.2 UCPU1.A7
TOUCHPAD_INTR#: DZ3.2 RC272.2 UCPU1.BA5
TP_PW_EN: R1175.2 U716.3 UE4.24
TPM_DET: RH148.2 RH153.1 UCPU1.AP13
TPM_GPIO2: R1006.2 R1873.2 U15.3
TPM_LPM#: Q72.1 R1873.1 RE91.1
TPM_PIRQ#: RH126.2 U15.18 UCPU1.M3
TRST#_XDP: JXDP1.54 RC136.2 UCPU1.B59 UCPU1.C61
UART0_TX: JDEG1.9 UCPU1.AB2
UART1_RXD: JUART.3 RH563.2 UCPU1.AC1
UART1_TXD: JUART.2 RH562.2 UCPU1.AC2
UPD_EN1_4#: RE107.2 UE5.B53
UPD_SMBCLK: CE71.1 RE88.1 U722.B5 UE5.B49
UPD_SMBDAT: CE70.1 RE87.1 U722.A5 UE5.B48
UPD_SMBUS_ALRT#: CE72.2 RE3.2 U722.B6 UE5.A42
USB1_DET#: CE22.1 JIO1.36 RE34.2
USB2_EN: R1216.1 U699.4 US2.4
USB2_ID: RC19.1 UCPU1.AG3
USB2_PWR_EN: RC293.2 U699.1 UCPU1.AY7
USB3RN1: JIO1.2 UCPU1.H8
USB3RN2: ML13.1 UCPU1.J6
USB3RN2_RC_CON: DI1.1 DI1.10 JUSB2.5 ML13.2
USB3RP1: JIO1.4 UCPU1.G8
USB3RP2: ML13.4 UCPU1.H6
USB3RP2_RC_CON: DI1.2 DI1.9 JUSB2.6 ML13.3
USB3TN1: JIO1.8 UCPU1.C13
USB3TN2: C621.1 UCPU1.B13
USB3TN2_C: C621.2 ML12.1
USB3TN2_RC_CON: DI1.4 DI1.7 JUSB2.8 ML12.2
USB3TP1: JIO1.10 UCPU1.D13
USB3TP2: C623.1 UCPU1.A13
USB3TP2_C: C623.2 ML12.4
USB3TP2_RC_CON: DI1.5 DI1.6 JUSB2.9 ML12.3
USB20_N1: JIO1.34 UCPU1.AB9
USB20_N2: ML11.1 UCPU1.AD6
USB20_N2_CONN: DI2.3 JUSB2.2 ML11.2
USB20_N3: ML10.1 UCPU1.AH3
USB20_N3_R: JNGFF1.5 ML10.2
USB20_N4: ML9.1 UCPU1.AD9
USB20_N4_CONN: DI4.3 JTS.3 ML9.2
USB20_N5: L55.4 UCPU1.AJ1
USB20_N5_CONN: DI3.3 JCAM.4 L55.3
USB20_P1: JIO1.32 UCPU1.AB10
USB20_P2: ML11.4 UCPU1.AD7
USB20_P2_CONN: DI2.2 JUSB2.3 ML11.3
USB20_P3: ML10.4 UCPU1.AJ3
USB20_P3_R: JNGFF1.3 ML10.3
USB20_P4: ML9.4 UCPU1.AD10
USB20_P4_CONN: DI4.2 JTS.2 ML9.3
USB20_P5: L55.1 UCPU1.AJ2
USB20_P5_CONN: DI3.2 JCAM.5 L55.2
USB_OC1#: JIO1.24 RC185.1 UCPU1.C9
USB_OC2#: RC188.1 UCPU1.D9 US2.5
USB_OC3#: RC191.1 UCPU1.B9
USB_PWR_SHR_DET_R#: CE56.1 RE34.1 RE36.2 UE5.B63
USB_PWR_SHR_EN_R#: JIO1.18 UE4.19
USB_PWR_SHR_VBUS_EN_R: JIO1.39 RE89.1 UE4.18
USB_VBUS_EN_L: RE59.1 U699.2 UE4.17
USBC_MCP23017_SMBCLK: R1441.1 RE73.1 U48.2 UE4.8 UE5.B4
USBC_MCP23017_SMBCLK_R: R1441.2 U722.L2
USBC_MCP23017_SMBDAT: R1442.1 RE71.1 U48.3 UE4.9 UE5.A3
USBC_MCP23017_SMBDAT_R: R1442.2 U722.K2
USBCOMP: RC44.1 UCPU1.AB6
VCI_IN3#: RPE5.3 UE5.B68
VID0_PRIM_CORE: PR1415.2 PR1418.1 PR1419.2 PU1401.9
VID0_VCCIO: PR1405.2 PR1407.1 PU1400.9
VID1_PRIM_CORE: PR1414.2 PR1417.1 PR1420.2 PU1401.8
VID1_VCCIO: PR1404.2 PR1406.1 PU1400.8
VIDALERT_N: PR1024.1 RC152.2 RC153.2
VIDSCLK: PR1125.1 RC155.2 RC158.2
VIDSCLK_R: RC155.1 UCPU1.A63
VIDSOUT: PR1025.1 RC154.2 RC157.2
VIDSOUT_R: RC154.1 UCPU1.D64
VL: PC523.1 PU501.15
VR_EN_CORE: PR1029.2 PU1000.40
VR_HOT_CORE: PR1124.2 PU1000.38
VR_READY_CORE: PR1027.2 PR1095.2 PU1000.39
VRALERT#: RC73.1 UCPU1.AM11
VSA_SEN+: PC1072.2 PC1077.2 PC1091.1 PR1077.2 RC168.2 UCPU1.H20
VSA_SEN-: PC1074.1 PC1077.1 PU1000.26 RC166.1 UCPU1.H21
VSET_5085: CE55.1 RE77.1 UE5.A17
WLAN_WIGIG60GHZ_DIS#: DZ1.1 RE14.2 UE4.22
WLAN_WIGIG60GHZ_DIS#_R: DZ1.2 JNGFF1.48
XCLK_BIASREF: RC52.1 UCPU1.E42
XDP_DBRESET#: CC32.1 JXDP1.48 RC137.2 RC290.1 UC12.1
XDP_OBS0: JXDP1.21 RC239.2
XDP_OBS0_R: RC239.1 UCPU1.C55
XDP_OBS1: JXDP1.23 RC240.2
XDP_OBS1_R: RC240.1 UCPU1.D55
XDP_OBS2_R: T10.1(TP-1) UCPU1.B54
XDP_OBS3_R: T11.1(TP-1) UCPU1.C56
XDP_PRSNT_PIN1: JXDP1.1 RC121.1 RC122.1
XTAL24_IN: RC316.2 UCPU1.E3
XTAL24_IN_R: CC21.1 RC46.2 RC316.1 YC1.3
XTAL24_OUT: RC317.2 UCPU1.C7
XTAL24_OUT_R: CC22.1 RC46.1 RC317.1 YC1.1
XTAL_25_IN: RT243.2 UT1.D22
XTAL_25_IN_R: CT43.1 RT243.1 YT1.1
XTAL_25_OUT: RT11.2 UT1.D23
XTAL_25_OUT_R: CT44.1 RT11.1 YT1.3
N18292747: PQ100.2 PQ101.1 PR105.1
N22878624: PL102.2 PQ100.1 PR101.1 PR104.1
N22878630: PQ100.3 PR101.2 PR103.1
N22878645: PQ101.2 PR104.2 PR106.1
N28314143: T7.1(TP-1) UCPU1.AT52
N28323796: T8.1(TP-1) UCPU1.AP43
N28323807: T21.1(TP-1) UCPU1.AN43
N28344853: T18.1(TP-1) UCPU1.AT13
N28375965: T1.1(TP-1) UCPU1.G46
N28375966: T2.1(TP-1) UCPU1.F46
N28424999: T113.1(TP-1) UCPU1.AW71
N28425002: T114.1(TP-1) UCPU1.AW70
N28842863: CC204.1 UCPU1.AL1
N28843886: CC214.1 UCPU1.BB10
N28856399: T16.1(TP-1) UCPU1.BA70
N28856402: T17.1(TP-1) UCPU1.BA68
N28857231: T12.1(TP-1) UCPU1.BB68
N28857234: T13.1(TP-1) UCPU1.BB69
N28857237: T14.1(TP-1) UCPU1.AK13
N28857240: T15.1(TP-1) UCPU1.AK12
N28861827: RC120.1 UCPU1.C64
N28891648: RC245.2 UCPU1.BB11
N28938912: CC8.2 RC29.1
N29708559: T126.1(TP-1) UCPU1.AY4
N29708561: T127.1(TP-1) UCPU1.BB3
N29708599: T128.1(TP-1) UCPU1.AU5
N29708601: T129.1(TP-1) UCPU1.AT5
N29708639: T130.1(TP-1) UCPU1.BB5
N31739843: T121.1(TP-1) UCPU1.AY8
N40373163: CD186.2 RD115.1
N40373501: CD187.2 RD116.1
N40376778: CD185.2 RD112.1
N49753304: QA1.2 QA1.5 QA9.1 RA16.2
N49753333: QA9.2 RA18.2 RA41.1 RA57.2
N49753452: QA3.3 RA37.2 RA39.1
N49753456: CA40.1 QA3.2 RA39.2
N49755927: CA33.1 CA34.1 R7.1 RA24.2 RA25.2
N49756342: CA106.1 RA75.2 RA76.2 UA2.13
N49981946: DA1.2 JHP1.5 RA19.2 RA30.1
N50165058: PQ400.1 PR400.2 PR403.2 PU400.7
N50165456: PC406.1 PR408.1 PR409.2 PR412.1 PU400.3
N50165462: PQ400.2 PR408.2 PR411.2 PU400.1
N50170477: PC404.1 PQ400.5 PU401.4
N50170488: PC404.2 PR407.1 PU402.1 PU402.2
N50180903: PD102.1 PL102.1 PR108.1
N50196545: PU401.2 PU402.4
N50196918: PQ400.6 PR404.2 PU401.1
N50197891: PC403.1 PR400.1 PR402.2 PR406.1 PU400.5
N50203343: PQ400.3 PR401.2 PR405.1
N50266801: PD301.1 PD302.1 PR305.1 PR307.1
N50638473: QH8.3 R916.1
N52012213: CE50.1 RT242.2 UE5.B51
N52012553: RE57.1 RE63.1 UE5.A59
N52091760: QE9.2 RE70.2
N52092863: CE52.1 RE80.2
N52116668: RE64.1 UE5.B61
N52475257: JNGFF1.42 R1255.1
N52558730: RE22.2 UE4.13
N52558748: RE23.2 UE4.12
N52558768: RE27.2 UE4.11
N52571191: RE24.2 UE4.14
N52708219: D81.1 JFAN1.2 R886.1
N52893865: R1343.1 U716.8 U716.9
N52893895: R1323.1 U716.13 U716.14
N52893916: C1258.1 U716.10
N52894141: C1257.1 U716.12
N52922903: R1326.1 U717.8 U717.9
N52922958: R1342.1 U717.13 U717.14
N52922960: C1292.1 U717.10
N52923110: C1163.1 U717.12
N52925836: R1320.1 U719.8 U719.9
N52925896: R2669.1 U719.13 U719.14
N52925901: C1278.1 U719.10
N52926051: C355.1 U719.12
N52930519: R1329.1 U720.8 U720.9
N52930575: R1344.1 U720.13 U720.14
N52930580: C1293.1 U720.10
N52930730: C1167.1 U720.12
N52934489: R1125.1 U664.8 U664.9
N52934545: R1318.1 U664.13 U664.14
N52934547: C1214.1 U664.10
N52934693: C1212.1 U664.12
N54529025: JNGFF2.60 R2662.1
N55952962: PR906.2 PU900.7
N56036060: PR806.2 PU800.7
N56242723: T19.1(TP-1) UCPU1.AW50
N56561744: CA86.2 UA2.35
N56561748: CA86.1 UA2.37
N56563648: CA107.2 UA2.19
N56565297: CA108.2 UA2.7
N56565952: CA109.1 RA77.1 UA2.27
N56567001: CA110.2 UA2.39
N56594221: RA54.2 UA2.20
N56696147: PR200.3 PR221.2 PR222.2
N56696285: PR221.1 PU200.5
N56699994: PQ204.2 PR201.2 PR207.1
N56700271: PQ206.6 PR207.2
N56700855: PD200.1 PQ206.2 PR290.1
N56701480: PD200.2 PR213.2 PR289.2
N56701483: PD200.3 PR216.2
N56704066: PC206.2 PQ210.3 PR232.2 PR241.1
N56704068: PC202.2 PQ203.3 PQ205.1 PR205.2 PR212.1
N56704069: PC208.2 PQ212.3 PQ214.1 PR237.2 PR244.1
N56704070: PC200.2 PD202.1 PQ200.3 PQ201.3 PR202.2 PR210.1
N56704076: PR200.2 PR222.1 PR225.2
N56704097: PD202.2 PQ204.1
N56712400: PQ215.2 PR287.2 PR288.2
N56713700: PQ213.2 PR233.2 PR242.1
N56715138: PC207.2 PQ211.3 PR234.2 PR239.2 PR243.1
N56715373: PQ207.2 PQ207.3 PR208.2 PR219.1
N56726680: PQ208.6 PR210.2
N56726937: PC216.1 PR263.1 PR267.2 PR272.1 PU203.3
N56728350: PC200.1 PQ200.4 PQ200.8 PQ201.4 PQ201.8 PR202.1
N56729247: PQ205.2 PR204.2 PR211.1
N56731386: PQ214.2 PR235.2 PR245.1
N56741861: PC203.1 PR223.2 PU200.3
N56821674: R1437.1 U722.C10
N56821678: R1438.1 U722.H6
N56822218: R1465.1 R1468.1 U722.E11
N56822254: C618.1 U722.H7
N56822270: R1473.1 U722.G2
N56822627: TC29.1(TP-1) U722.G4
N56822629: TC25.1(TP-1) U722.F4
N56822683: TC36.1(TP-1) U722.E10
N56822685: TC38.1(TP-1) U722.G11
N56856077: RT190.1 U722.F1
N56859240: R1471.2 U722.F2
N56859647: R1471.1 U722.E2
N56975718: T183.1(TP-1) UE5.A10
N56975734: T184.1(TP-1) UE5.A23
N56977728: R60.1 U15.27
N56984382: T187.1(TP-1) UE5.B23
N56984414: T189.1(TP-1) UE5.B62
N57034346: T124.1(TP-1) UCPU1.AC3
N57034424: R1439.1 U722.D7
N57037386: QT19.1 R1440.1
N57177583: R1327.1 UZ25.6
N57177874: RZ76.2 UZ22.4
N57177931: R1333.1 UZ22.6
N57178338: R1325.1 UZ19.6
N57182329: PQ207.5 PR228.2
N57280922: T193.1(TP-1) U722.B9
N57280925: T194.1(TP-1) U722.A9
N57281646: T185.1(TP-1) UE5.A55
N57313034: RC49.2 UCPU1.AT8
N57313074: RC50.2 UCPU1.AU8
N57317696: RC9.2 SW1.1
N57319429: T195.1(TP-1) UCPU1.AK62
N57319432: T196.1(TP-1) UCPU1.AL61
N57408632: RT164.2 UT1.F19
N57526872: RT199.1 RT200.1 RT201.1 U722.F10
N57670088: T116.1(TP-1) UCPU1.AW15
N57965459: PQ201.1 PQ201.2 PQ201.5 PQ201.6 PQ201.7 PR200.1
N58401690: RE107.1 T197.1(TP-1)
N58453857: Q71.1 R536.2
N58842401: T125.1(TP-1) UCPU1.AD4
N58864976: R1445.2 R1446.2 U717.5
N59418764: R1436.1 U722.C2
N59418771: TC35.1(TP-1) U722.B2
N59894012: RE92.2 U15.29
N59894959: RC230.1 U15.13
N60736253: PQ221.2 PQ223.5 PR275.1 PR281.2
N60750271: PC218.2 PQ222.2 PR278.1 PR279.1
N60753752: PC1536.1 PQ223.2 PR277.2
N60757042: PQ206.5 PR280.1
N60757502: PQ223.6 PR281.1
N60799582: PH1007.2 PR1067.2 PR1072.1
N60799590: PC1014.2 PR1098.1
N60799629: PC1095.2 PR1065.1
N60799636: PC1020.2 PR1122.1
N60799669: PC1088.1 PR1087.2
N60799687: PR1025.2 PR1028.1 PR1074.2
N60799689: PR1024.2 PR1063.2 PR1076.1
N60799691: PR1070.1 PR1084.2 PR1125.2
N60799808: PC1069.2 PR1068.1
N60799810: PH1009.1 PR1097.2
N60799848: PH1008.2 PR1064.1 PR1126.2
N60799854: PC1064.2 PR1123.1
N60799887: PC1096.1 PR1096.2
N60799936: PC1134.1 PR1060.2
N60799960: PC1068.2 PR1092.1
N60799970: PH1006.1 PR1089.2
N61450237: R289.2 U48.8
N61547946: QZ9.1 R2670.1
N61553916: R2671.1 UZ26.6
N62098363: R1322.1 UZ24.1
N63073614: PQ216.5 PR248.2
N63073655: PQ217.5 PR251.2
N63092271: PQ209.2 PR217.2
N63092515: PQ209.5 PR220.2
N63216045: QH8.6 R913.1
N63216077: QH9.3 R912.1
N63216109: QH9.6 R911.1
N63239426: Q41.1 R910.1
N63254653: PQ208.2 PR218.1 PR283.1
N63877984: PQ208.5 PR229.1 PR282.1
N64008725: QE13.5 QE13.6 R78.2
N64008885: QE13.3 R79.2
N64546397: PQ215.5 PR284.2
N64546409: PD206.2 PR285.1 PR291.2
N64570632: PQ215.4 PQ216.6 PR286.2
N64571386: PQ216.2 PR247.1 PR285.2
N64571512: PQ215.3 PR243.2 PR286.1
N64625473: PC211.1 PD203.1 PQ218.3 PR258.1 PR264.2 PR268.1 PU201.5
N64625477: PC212.1 PD203.2 PR252.2 PR258.2 PR265.1 PU201.7
N64625485: PC213.1 PQ218.2 PR265.2
N64625491: PQ218.5 PR274.1
N64625687: PR254.2 PR269.1 PU201.6
N65247919: QE14.5 QE14.6 R81.2
N65247927: QE14.3 R80.2
N65482285: CC125.1 R9.2
N66491485: JSPI1.16 RC64.2 RC66.2
N67232079: PC1535.1 PQ206.3 PR240.1 PR246.1 PU202.4
N67365065: PQ223.3 PR279.2
N67601016: CC225.1 R10.2
N67857646: PH1005.1 PR1088.2
N67859167: PC1090.2 PR1081.1
N67859352: PC1089.1 PR1090.2
N67859430: PC1072.1 PR1073.2
N67997563: D122.1 RTCR2.1
N68203781: Q72.2 RH127.2
N119009545: PQ209.6 PR212.2
N119009632: PC201.2 PQ202.3 PR203.2 PR209.1
N119967293: PQ216.3 PR244.2
N119982384: PR214.2 PU200.6
N122715521: PQ209.3 PR211.2
N122716790: PQ224.1 PR242.2
N122717029: PQ213.1 PR239.1
N122717329: PQ216.4 PQ217.3
N122717720: PQ217.6 PR245.2
N122719403: PQ215.6 PR241.2
N122723381: PR224.2 PR230.1 PU201.2
N122728402: PQ208.1 PQ208.3
N122733349: PC214.1 PR262.1 PR266.2 PR270.1 PU203.5
N122733365: PR259.2 PR271.1 PU203.6
N122733968: PQ219.6 PR257.2
N122734452: PR260.2 PR273.1 PU203.2
N122772225: PQ207.6 PR209.2
N122777610: PQ217.2 PR250.2
N122777613: PQ224.2 PR249.2
N123360127: RT12.1 UT1.H19
N123360144: RT5.1 UT1.Y18
N123959194: PR225.1 PU200.4

Pads without a net: FD1 1; FD2 1; FD3 1; FD4 1; H26 1; JAPS1 16 17 18; JEDP 24 39; JIO1 3 9 40 43 51; JNGFF1 6 8 9 11 12 13 14 17 18 19 20 23 24 26 36 38 40 50 51 52 53 54 56 57 58 59 60 62 63 65; JNGFF2 6 8 10 20 22 24 26 28 30 32 34 36 40 42 44 46 48 56 58 59; JSPI1 1 2 17; JUSBC1 7 8; PD100 2; PRP100 4 5; PU202 3; PU300 4 13 14; PU500 10 15; PU501 10 16; PU700 10 12; PU1100 4 9 10 13; PU1101 4 9 10 13; PU1102 4 9 10 13; PU1400 4; PU1401 4; U15 2 4 5 6 7 10 11 12 15 25 26 28 30 31; U18 9; U48 1; U683 1; UA2 4 11 12 14 15 23 24 48; UC2 1; UCPU1 A3 A4 A11 A15 A19 A21 A26 A27 A29 A31 A33 A36 A38 A40 A52 A65 A69 AB1 AB4 AB13 AB62 AC63 AD1 AD2 AD11 AD12 AE62 AE63 AF6 AF7 AF8 AF9 AF11 AF12 AF13 AG1 AG2 AG62 AH1 AH2 AH7 AH8 AH9 AH10 AH11 AH12 AJ62 AK6 AK7 AK9 AK10 AL25 AL27 AL63 AM1 AM2 AM3 AM4 AM5 AN2 AN8 AP4 AP7 AP8 AT43 AU2 AU56 AW1 AW17 AW20 AW42 AW48 AW68 AW69 AY1 AY2 AY20 AY21 B2 B3 B7 B11 B15 B19 B21 B26 B27 B29 B31 B33 B36 B38 B40 B52 B69 B70 BA3 BA4 BA8 BA11 BA47 BA50 BB2 BB4 BB9 BB46 BB52 C2 C4 C8 C11 C12 C15 C17 C21 C27 C28 C29 C31 C32 C33 C36 C37 C38 C41 C54 C70 C71 D1 D3 D4 D5 D8 D12 D15 D17 D21 D27 D28 D29 D31 D32 D33 D36 D37 D38 D41 D54 D71 E1 E2 E10 E20 E35 E37 E61 F6 F10 F15 F20 F21 F52 F60 F61 G15 G16 G21 G61 H1 H2 H10 H11 H16 H63 J1 J2 J4 J5 J10 J68 J71 K45 K46 L6 M2 M4 N1 N2 N3 N9 N11 N12 P1 P2 P3 P4 P62 R9 U3 U4 U11 U12 V1 V2 V62 W2 W4 W7 W8 W10 W11; UD19 A1 A2 A12 A13 B1 B13 C4 K9 R3 T1 T13 U1 U2 U12 U13; UD20 A1 A2 A12 A13 B1 B13 C4 K9 R3 T1 T13 U1 U2 U12 U13; UD21 A1 A2 A12 A13 B1 B13 C4 K9 R3 T1 T13 U1 U2 U12 U13; UD22 A1 A2 A12 A13 B1 B13 C4 K9 R3 T1 T13 U1 U2 U12 U13; UE4 3 7 10 15 16 29; UE5 B15; UT1 A7 A9 A11 A13 A23 B7 B9 B11 B13 B23 D19 E2 E18 E19 F22 F23 H22 H23 J1 J2 K22 K23 L1 L2 M22 M23 N1 N2 R1 R2 V18 W16 W19 Y16 Y19; UZ24 3

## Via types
v1: diameter 0.305, hole 0.152, TOP to BOTTOM, 447 vias
v2: diameter 0.457, hole 0.203, TOP to BOTTOM, 4979 vias
v3: diameter 0.406, hole 0.203, TOP to BOTTOM, 369 vias
v4: diameter 0.508, hole 0.254, TOP to BOTTOM, 80 vias
v5: diameter 0.559, hole 0.254, TOP to BOTTOM, 1 via

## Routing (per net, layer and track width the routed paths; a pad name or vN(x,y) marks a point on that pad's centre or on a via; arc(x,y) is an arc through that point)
0.6V_DDR_VTTREF: length 1.5
  TOP w0.127: PC614.1 166.95,31.96 167.14,31.77 PU600.3
0.6V_EN: length 8.1
  TOP w0.127: 164.35,32.48 166.84,32.48 167.1,32.22 167.99,32.22 PU600.2 ; 164.35,32.48 PR611.2 PR609.2 163.96,30.34 PR610.1 PC618.1 ; 164.35,32.48 164.35,32.68 v3(163.69,33.34)
1.0V_B+:
  vias: v1(194.49,63.99) v2(195.15,63.61) v2(195.56,64.04)
1.0V_BST: length 2.2
  TOP w0.127: PR703.1 v1(198.98,63.92)
  TOP w0.508: v2(198.1,62.45) 198.27,62.63 PR703.1
1.0V_BST_R: length 1.4
  TOP w0.127: PC703.2 v1(198.59,58.77)
1.0V_EN: length 4.8
  BOTTOM w0.127: PR700.2 203.14,67.66 v1(203.63,68.16)
  BOTTOM w0.254: PR700.2 203.15,67.15 PR701.1 203.07,66.21 PC700.1 202.37,64.71 PU700.11
1.0V_FB: length 4.2
  TOP w0.127: v2(202.46,63.36) 202.46,63.36 v1(202.01,63.81)
  BOTTOM w0.254: PR707.1 203.06,64.44 PC707.2 203.06,62.76 ; 203.06,62.76 PR704.2 ; 203.06,62.76 v2(202.46,63.36) PU700.14
1.0V_ILMT: length 3.8
  TOP w0.127: PR709.1 v1(204.03,65.25)
  TOP w0.254: v2(202.46,64.12) 203.06,64.12 PR708.2 PR709.1
  BOTTOM w0.254: PU700.13 202.16,63.81 v2(202.46,64.12)
1.0V_LDO: length 9.4
  TOP w0.127: v2(202.15,61.87) 202.15,61.72 v1(202.62,61.25)
  IN1 w0.254: v2(202.27,67.7) 201.71,67.7 201.28,67.27 201.28,62.73 v2(202.15,61.87)
  BOTTOM w0.254: PR705.2 201.18,67.62 201.22,67.59 201.7,67.59 201.82,67.7 v2(202.27,67.7)
1.0V_LX: length 9.3
  TOP w0.127: v2(198.48,65.77) v1(197.82,65.77)
  TOP w0.508: v2(200.76,60.79) 200.13,60.16 PC703.1
  IN4 w0.254: v2(198.48,65.77) 199.06,65.19 199.06,61.65 199.85,60.87 200.69,60.87 v2(200.76,60.79)
  BOTTOM w0.254: PU700.6 199.13,65.75 198.93,65.95 198.65,65.95 v2(198.48,65.77)
1.0V_PG: length 2.6
  BOTTOM w0.127: PR705.1 v1(201.88,66.71)
  BOTTOM w0.254: PR705.1 200.48,66.51 PU700.9
1.0V_SNUB: length 3.5
  BOTTOM w0.127: PR702.2 v1(203.51,59.52)
  BOTTOM w0.508: PR702.2 201.88,59.37 PC701.1
1.2V_DDR_B+:
  vias: v1(170.28,34.1)
1.2V_DDR_BS: length 3.1
  TOP w0.254: 171.32,28.26 171.32,29.32 171.12,29.52 PU600.12
  TOP w0.508: 171.32,28.26 171.68,27.9 172.52,27.9 PR612.1
1.2V_DDR_BS_R: length 2.6
  TOP w0.127: v1(174.52,30.01) 174.78,29.75 174.78,29.17 173.94,28.33 PR612.2
1.2V_DDR_FB: length 3.7
  TOP w0.203: PU600.16 171.86,31.32 PC609.2 PR603.2 PR605.1
1.2V_DDR_OT: length 6.4
  TOP w0.203: PU600.19 171.09,32.67 171.25,32.83 171.25,33.02 171.59,33.37 v1(171.59,34.01) 171.67,34.08 171.67,34.75 172.03,35.12 173.86,35.12 174,35.26 PR600.1
1.2V_DDR_PG: length 6.8
  TOP w0.203: PR601.1 174.88,34.78 v1(174.32,34.78) 172.16,34.78 172,34.62 172,33.31 171.6,32.91 171.6,32.44 171.38,32.22 PU600.18
1.2V_DDR_SNUB: length 4.7
  TOP w0.127: v1(174.37,21.65) 172.64,21.65 172.26,22.03 172.26,22.61 PC604.1
  TOP w0.508: PR602.2 172.83,24.06 PC604.1
1.2V_DDR_VCC: length 2
  TOP w0.203: PU600.14 171.41,30.42 171.91,29.93 172.36,29.93 PC607.1
1.2V_EN: length 5.5
  TOP w0.127: v3(164.41,35.08) 164.41,33.51 PC617.1
  TOP w0.203: PU600.1 167.11,32.67 166.83,32.95 PR607.2
  TOP w0.254: PC617.1 PR608.1 166.7,32.98 PR607.2
1.8VA_B+:
  vias: v1(176.25,80.35)
1.8VA_EN: length 4.6
  TOP w0.127: v1(175.06,77.76) 174.75,78.06 PC800.1
  TOP w0.254: PU800.13 173.92,77.08 173.97,77.12 PC800.1 173.1,78.06 PR800.2 PR801.2
1.8VA_FB: length 3.6
  TOP w0.254: PU800.5 172.42,72.55 172.44,72.53 PR804.1 171.91,71.71 171.88,71.74 PR802.2 PC801.2
1.8VA_PG: length 7.5
  TOP w0.127: PU800.4 171.68,74.28 171.07,74.28 170.92,74.13 170.92,73.75 171.09,73.57 171.09,72.62 170.79,72.32 170.45,72.32 170.23,72.09 170.23,71.26 PR805.1 169.39,70.42 169.39,69.76 168.83,69.2 v1(168.33,69.2)
1.8VA_SNUB: length 3.6
  TOP w0.127: v3(171.78,80.37) 170.15,80.37 PC807.1
  TOP w0.508: PR803.2 169.62,79.23 PC807.1
1.8VA_SS: length 7.7
  TOP w0.127: PC806.1 176.74,74.25 177.25,73.74 177.87,73.74 178,73.87 178,75.13 178.57,75.7 179.46,75.7 179.86,76.1 v3(179.86,76.68)
  TOP w0.254: PC806.1 176.61,74.28 174.66,74.28 PU800.9
1.8VA_SW: length 1.5
  TOP w0.127: v3(168.63,77.73) 168.94,77.43 PR803.1
1.8VU_B+:
  vias: v2(170.79,42.04)
1.8VU_EN: length 4.8
  TOP w0.254: PU900.13 169.22,44.11 169.32,44.2 169.72,44.2 v2(170.1,43.82)
  TOP w0.508: v2(170.1,43.82) 170.54,43.39 PC900.1 171.45,43.37 172.26,43.37 172.29,43.39 PR900.2 PR901.2
1.8VU_FB: length 3.8
  TOP w0.203: PR904.1 166.57,38.95 PC901.2 ; PR902.2 PC901.2 ; PC901.2 166.73,39.12 v2(167.4,39.8) 167.72,40.11 167.72,40.65 PU900.5
1.8VU_PG: length 2
  TOP w0.203: PU900.4 166.98,41.38 166.6,41.38 166.18,40.97 v2(166.18,40.94) 165.71,40.47 PR905.1
1.8VU_SNUB: length 2.2
  TOP w0.127: PR903.2 v2(162.83,41.87)
  TOP w0.508: PC907.1 163.59,40.46 PR903.2
1.8VU_SS: length 7.5
  TOP w0.127: v1(166.65,37.25) 167.06,37.65 169.37,37.65 169.65,37.93 169.65,38.41 PC906.1
  TOP w0.203: PU900.9 170.33,41.38 170.47,41.25 170.47,39.23 PC906.1
1.8VU_SW:
  vias: v1(166.55,44.89)
3.3V_CAM_EN#: length 247.6
  TOP w0.127: QZ9.2 60.31,73.24 60.81,73.24 v2(61.83,74.26) 62.12,74.54 R1179.1
  IN4 w0.081: v2(61.83,74.26) 61.6,74.02 61.6,69.85 60.14,68.39 60.14,65.06 60.46,64.74 60.46,63.3 57.89,60.73 57.89,58.3 59.45,56.74 59.45,55.38 58.47,54.4 58.47,53.23 58.08,52.84 56.87,52.84 50.21,46.18 49.66,46.18 44.7,41.22 44.7,38.93 42.28,36.5 42.28,33.63 42.97,32.94 42.97,31.42 44.13,30.25 44.13,28.72 44.73,28.11 45.44,28.11 45.86,27.7 45.86,26.77 46.07,26.56 52.44,26.56 55.97,23.02 58.93,23.02 60.17,21.78 65.85,21.78 68.7,24.63 68.7,25.83 70.75,27.88 70.75,28.09 72.05,29.38 74.71,29.38 76.69,31.37 77.53,31.37 78.23,32.07 78.23,33.04 79.5,34.3 81.49,34.3 81.68,34.11 83.52,34.11 85.22,35.82 90.16,35.82 90.98,34.99 95.77,34.99 97.08,33.68 97.08,31.16 97.87,30.37 97.87,26.98 98.37,26.48 98.65,26.48 99.32,25.81 99.32,23.94 101.06,22.2 110.71,22.2 111.81,21.1 116.87,21.1 117.61,21.85 124.15,21.85 125.55,20.45 144.41,20.45 144.9,20.93 147.75,20.93 148.15,20.53 160.43,20.53 162.92,23.02 162.92,25.6 161.44,27.08 161.44,31.12 161.79,31.47 161.79,33.21 161.14,33.85 160.39,33.85 159.8,34.44 159.8,37.07 156.41,40.46 155.94,40.46 155.29,41.12 155.29,41.49 153.69,43.09 153.69,44.87 152.53,46.03 150.34,46.03 149.91,45.6 148.95,45.6 148.67,45.88 148.67,48.83 145.63,51.87 145.15,51.87 144.78,52.24 144.78,53.35 v2(144.42,53.7)
  BOTTOM w0.127: v2(144.42,53.7) 144.17,53.7 143.97,53.5 UCPU1.AT15
3.3V_TS_EN: length 266
  TOP w0.127: v2(59.65,77.51) 59.93,77.51 60.52,76.92 60.81,76.92 61.06,76.67 R1162.1 60.82,76.46 60.61,76.67 60.01,76.67 59.51,76.16 59.51,76.16 UZ26.4
  IN3 w0.089: v2(59.65,77.51) 56.21,77.51 53.74,75.05 53.74,68.31 53.38,67.94 v2(53.37,67.94)
  IN4 w0.081: v2(149,54.37) 149,54.3 151.01,52.29 151.01,50.46 152.64,48.83 154.51,48.83 154.65,48.7 155.25,48.7 155.86,48.08 155.86,46.74 156.77,45.83 156.77,45.02 157.75,44.04 157.75,42.58 158.79,41.54 158.79,40.45 161.16,38.08 163.34,38.08 164.08,37.33 164.08,35.22 165.1,34.2 165.1,23.43 160.95,19.28 147.63,19.28 147.23,19.68 145.42,19.68 144.91,19.18 123.61,19.18 123.21,19.58 106.86,19.58 106.35,20.09 101.35,20.09 99.33,22.11 97.5,22.11 96.69,22.92 96.69,25.1 96.59,25.2 96.59,28.92 95.63,29.89 94.31,29.89 92.99,31.21 92.99,31.81 92.02,32.79 88.12,32.79 87.92,32.59 85.54,32.59 85.35,32.4 85.35,31.81 84.25,30.71 79.41,30.71 75.43,26.74 72.87,26.74 67.44,21.3 67.44,19.82 67,19.38 64.86,19.38 64.37,18.9 63.08,18.9 61.85,17.67 60.06,17.67 56.54,21.19 54.31,21.19 54.1,20.97 53.25,20.97 53.21,21.02 50.55,21.02 49.47,19.93 43.72,19.93 42.37,21.28 42.37,22.36 42.11,22.61 42.11,24.09 41.57,24.63 41.57,26.57 40.02,28.13 40.02,31.46 38.33,33.15 38.33,34.33 37.17,35.49 37.17,37 39.29,39.12 40.45,39.12 41.08,39.75 41.08,40.21 42.66,41.79 42.69,41.79 43.99,43.09 43.99,45.9 44.29,46.2 48.8,46.2 51.18,48.59 51.18,51.05 54.59,54.46 54.59,61.37 53.95,62.01 53.27,62.01 51.92,63.35 51.92,65.47 53.37,66.91 v2(53.37,67.94)
  BOTTOM w0.076: v2(149,54.37) 149.38,54.75 UCPU1.AP5
  BOTTOM w0.127: v2(59.65,77.51) v1(60.28,77.51)
3V5V_ENLDO: length 53.7
  IN1 w0.254: v2(65.89,39.91) 66.43,39.37 68.35,39.37 68.35,39.37 68.76,39.37 68.76,39.37 69.55,39.37 70.08,38.85 76.66,38.85 79.97,35.54 81.64,35.54 82,35.9 89.37,35.9 90.49,34.78 92.05,34.78 92.85,33.99 v2(92.85,33.52)
  IN2 w0.254: v2(94.29,25.23) 93.85,25.66 93.85,28.91 92.85,29.92 v2(92.85,33.52)
  BOTTOM w0.254: v2(65.89,39.91) 66.27,39.53 PR508.2 PR509.1 65.38,39.94 64.93,40.38 64.58,40.38 64.39,40.58 PU501.11 ; v2(94.29,25.23) 94.44,25.08 94.44,22.49 95.15,21.78 95.15,19.78 94.4,19.03 90.85,19.03 PU500.11
3V_B+:
  vias: v2(89.53,23.11) v2(90.45,23.15) v2(91.82,23.96) v2(92.18,23.48) v2(93.9,24.04) v2(93.91,23.45) v3(90.91,23.83)
3V_BST: length 2.2
  TOP w0.127: v1(88.9,24.27) 88.56,23.93 v2(88.56,23.17)
  TOP w0.508: v2(88.56,23.17) 88.56,22.56 PR500.1
3V_BST_R: length 2.7
  TOP w0.127: PR500.2 87.41,21.36 v1(87.81,20.96)
  TOP w0.508: PR500.2 87.22,22.5 PC504.1
3V_EN: length 2.6
  BOTTOM w0.127: v1(92,17.94) PR503.2
  BOTTOM w0.203: PU500.12 90.23,18.75 PR503.2
3V_FB: length 1.4
  BOTTOM w0.203: PU500.13 89.77,18.31 PC511.1
3V_FB_R: length 0.9
  BOTTOM w0.127: PR504.1 89.26,17 v2(88.67,16.42)
3V_LX:
  vias: v1(86.39,19.85) v2(84.71,22.44) v2(85.32,22.44)
3V_SNUB: length 3.6
  TOP w0.127: PR501.2 v1(82.74,23.77)
  TOP w0.508: PC510.1 84.75,23.83 PR501.2
5V_B+:
  vias: v1(65.3,43.8) v2(63.35,44.92) v2(65.01,44.66) v2(65.51,44.29) v2(66.02,43.62) v2(66.61,43.62) v2(67.2,43.62) v2(67.97,43.63) v2(68.56,43.62) v2(69.15,43.63)
5V_BST: length 1.3
  TOP w0.508: v2(62.4,45.13) 62.4,43.8 PR505.1
5V_BST_R: length 2.8
  TOP w0.127: v1(61.75,42.43) 61.75,43.05 PR505.2
  TOP w0.508: PR505.2 60.22,43.79 PC512.1
5V_EN: length 1.9
  BOTTOM w0.203: PU501.12 63.94,40.52 v2(64.57,39.89) 64.57,39.35 PR510.2
5V_FB: length 1.9
  BOTTOM w0.203: PU501.13 63.49,40.29 63.83,39.95 63.83,39.51 PC525.1
5V_FB_R: length 2.1
  BOTTOM w0.127: PR511.1 v3(62.71,37.18)
  BOTTOM w0.508: PC525.2 PR511.1
5V_LX:
  vias: v1(57.46,43.04) v2(57.7,43.96) v2(57.7,42.31)
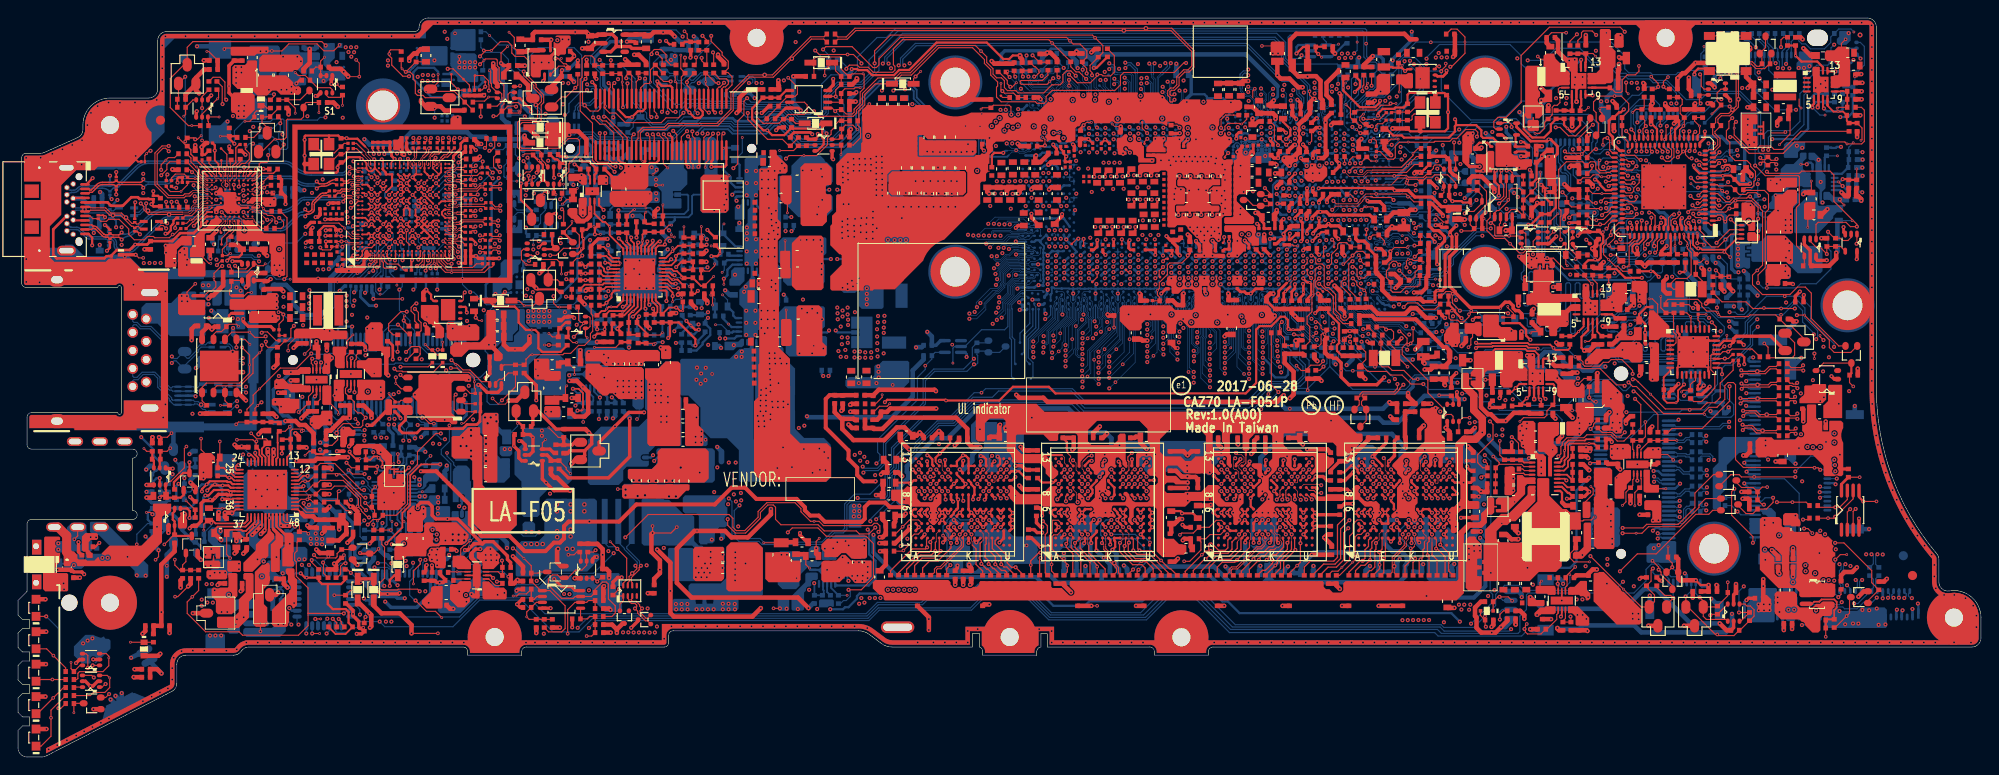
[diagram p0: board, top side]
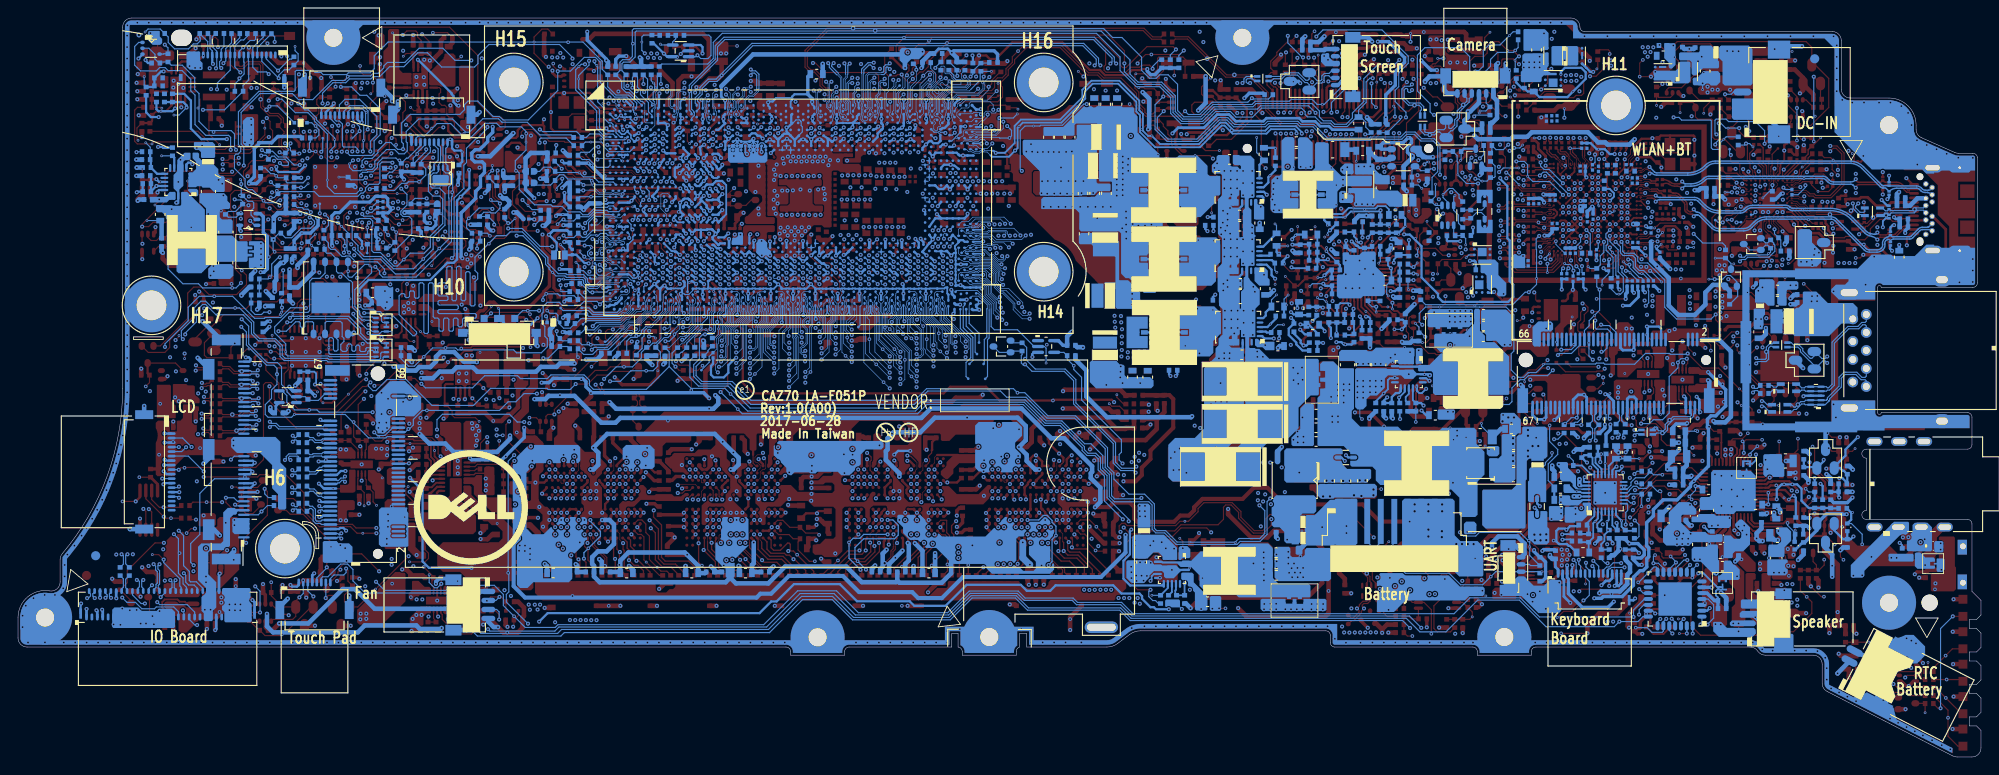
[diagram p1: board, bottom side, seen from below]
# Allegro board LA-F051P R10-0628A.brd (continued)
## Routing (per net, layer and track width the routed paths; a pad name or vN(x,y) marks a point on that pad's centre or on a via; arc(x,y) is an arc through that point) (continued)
5V_PG: length 4
  BOTTOM w0.203: PU501.9 65.6,42.03 65.81,41.82 65.81,40.8 v3(66.28,40.33) 67.16,39.46 PR506.2
5V_SNUB: length 3
  TOP w0.127: v1(60.88,41.18) 60.74,41.04 PC524.1
  TOP w0.508: PR507.2 59.5,39.84 PC524.1
5V_VCC: length 8.2
  TOP w0.508: v2(61.19,41.74) 62,41.74 v1(62.68,41.07) 63.27,40.47 63.27,38.18 62.87,37.78 61.79,37.78 PC517.1
  BOTTOM w0.203: PU501.17 61.55,42.03 61.26,41.74 v2(61.19,41.74)
+0.6VS: length 10.6
  TOP w0.635: 160.12,18.96 160.12,24.86 161,25.74 162.28,25.74 162.66,26.12 162.66,26.88 163.3,27.52
  vias: v3(156.29,17.87)
+0.6VSP:
  vias: v1(166.07,28.3)
+1.0V_AMPHYPLL: length 7.1
  TOP w0.457: RC169.2 145.71,71.46 145.09,70.84 v3(145.09,70.39) 145.09,67.28 CC264.1
  TOP w0.508: v2(144.33,66.46) 144.85,66.46 145.18,66.79 CC264.1
  BOTTOM w0.254: UCPU1.L15 143.99,66.12 v2(144.33,66.46) 143.99,66.8 UCPU1.K15
+1.0V_APLL: length 15.8
  TOP w0.254: 149.69,63.1 149.65,63.14 144.36,63.14 v2(144.32,63.1)
  TOP w0.381: 158.71,61.07 157.94,61.07 156.88,62.14 154.99,62.14 154.25,62.87 v3(152.76,62.87) 152.53,63.1 149.69,63.1
  BOTTOM w0.127: v2(144.32,63.1) 143.99,62.77 UCPU1.V15
+1.0V_APLLEBB: length 16.4
  TOP w0.254: CC218.1 141.07,64.1 v2(141.71,64.74) ; v2(148.34,73.8) 148.9,74.35 148.9,75.04 148.44,75.5 RC310.2
  IN3 w0.254: v2(141.71,64.74) 141.71,64.96 142.88,66.13 142.88,66.48 143.71,67.32 144.58,67.32 145.06,67.8 145.06,70.52 v2(148.34,73.8)
  BOTTOM w0.254: v2(141.71,64.74) 141.71,64.81 142.02,65.2 UCPU1.N18
+1.0V_CLK: length 34.3
  TOP w0.127: v3(143.31,73.87) 143.31,73.47 143.74,73.03
  TOP w0.381: CC220.1 146.79,73.47 146.63,73.62 v2(146.63,73.64) ; v2(128.91,69.22) 128.88,69.2 RC52.2
  TOP w0.457: v2(143.87,73.03) 143.73,73.03 143.36,72.67 RC170.2
  TOP w0.508: RC170.2 143.36,71.42 142.95,71.01 142.95,70.92 142.73,70.69 142.63,70.69 142.42,70.48
  IN1 w0.254: v2(146.63,73.64) 146.63,73.62 146.03,73.01 143.89,73.01 v2(143.87,73.03)
  IN2 w0.254: v2(128.91,69.22) 128.6,69.22 128.28,69.54 128.28,69.96 128.64,70.32 130.06,70.32 130.52,70.78 133.34,70.78 133.79,70.32 134.46,70.32 134.68,70.54 136.41,70.54 137.06,69.9 137.06,68.18 137.73,67.51 137.73,66.11 138.61,65.24 140.26,65.24 140.59,65.57
  BOTTOM w0.203: UCPU1.A14 144.31,72.73 144.01,73.03 v2(143.87,73.03)
  BOTTOM w0.254: UCPU1.L21 v2(140.49,66.46) ; v2(146.63,73.64) 146.63,73.62 146.69,73.57 146.69,72.09 UCPU1.A10 ; v2(141.71,66.46) 141.39,66.78 UCPU1.K19 ; UCPU1.N20 140.74,65.32 v2(141.08,65.66) 141.09,65.66 141.09,65.67 141.38,66.04 UCPU1.L19
+1.0V_DTS: length 4.6
  BOTTOM w0.254: 152.81,64.18 152.79,64.16 UCPU1.T1
  BOTTOM w0.381: 152.81,64.18 v1(154.52,65.9) RC301.2
+1.0V_MPHYAON: length 5.3
  TOP w0.127: RC299.2 152.07,68.28 152.35,68.56 v1(153.14,68.56)
  TOP w0.381: CC203.1 142.59,66.23 v2(142.36,66.46)
  TOP w0.508: RC299.2 151.61,67.53 v2(152.36,66.79)
  BOTTOM w0.254: UCPU1.K17 v2(142.36,66.46) ; v2(152.36,66.79) 151.82,66.79 UCPU1.L1
+1.0V_MPHYGT: length 7.5
  TOP w0.508: RC169.1 145.73,72.91 145.19,73.45 145.19,74.8 146.41,76.02 146.55,76.02 146.55,76.23
  BOTTOM w0.254: UCPU1.P16 143.34,64.46 v2(143.66,64.78) ; UCPU1.N15 143.99,65.19 v2(144.4,64.78) ; v2(143.66,63.94) 143.99,64.27 UCPU1.P15 ; UCPU1.N16 143.34,65.28 143.59,65.52 v2(143.59,65.62) ; UCPU1.N17 142.99,64.89 v2(142.99,64.77)
  vias: v2(146.58,77.56) v2(146.9,78.05) v2(147.26,77.57) v2(147.55,78.08) v2(147.92,77.61) v3(149.58,79.16)
+1.0V_PRIM_CORE: length 8.1
  TOP w0.305: CC205.1 142.34,60.49 141.71,59.86 v2(141.71,59.75)
  TOP w0.508: v2(142.54,74.32) 142.05,74.32 141.08,75.28 140.1,75.28 v3(139.74,75.64) CC274.1
  BOTTOM w0.254: UCPU1.AF18 141.71,59.66 v2(141.71,59.75) ; UCPU1.AF19 v2(141.07,59.78) ; UCPU1.V21 v2(140.39,63.08) ; UCPU1.V20 141.04,63.08 v2(141.04,63.07)
  vias: v2(142.68,73.73) v2(191.95,70.77) v2(191.92,70.14) v2(191.92,69.12) v2(191.95,68.51) v2(192.11,67.93) v2(192.63,68.21)
+1.0V_PRIM_COREP: length 11.5
  TOP w0.127: 194.62,69.25 196.01,69.25 v3(196.11,69.35)
  BOTTOM w0.254: v2(194.64,68.56) 197.46,68.56 198.63,69.73 198.63,72.84 199.38,73.59 PR1421.2
+1.0V_SRAM: length 35.1
  TOP w0.254: v2(151.13,72.82) 151.13,72.65 150.58,72.11 148.89,72.11 147.04,73.96 v1(147.04,74.25) 147.04,75.14 RC309.2
  TOP w0.381: v2(140.42,59.7) 140.18,59.47 CC217.1
  IN3 w0.254: v2(141.76,63.1) 142.34,63.1 142.88,62.57 144.63,62.57 144.93,62.88 144.93,63.38 144.76,63.56 144.76,64.02 145.16,64.42 149.15,64.42 149.71,64.98 149.71,67.69 149.54,67.85 149.54,68.56 149.71,68.73 149.71,70.32 149.99,70.6 149.99,71.41 151.13,72.55 v2(151.13,72.82)
  BOTTOM w0.203: 139.54,59.92 139.23,60.23 139.23,63.46 139.43,63.66
  BOTTOM w0.254: 139.43,63.66 139.69,63.92 140.34,63.92 UCPU1.T20 UCPU1.T19 v2(141.76,63.1) ; UCPU1.AF20 140.42,59.65 v2(140.42,59.7) 140.09,59.37 UCPU1.AF21 139.76,59.66 139.76,59.7 139.54,59.92
+1.0V_VCCST: length 232.9
  TOP w0.254: RC218.1 72.29,79.08 v2(71.91,79.46) ; v2(182.05,53.28) 181.44,53.9 v3(181.18,53.9) RT242.1
  TOP w0.381: v2(141.96,72.93) 142.31,72.58 CC282.1 CC195.1 ; CC283.1 139.82,67 v2(139.82,66.46) 139.37,66.46 CC202.1
  TOP w0.508: RC158.1 114.07,78.01 v2(114.2,78.14) 114.57,78.14 115.29,77.43 RC80.1
  IN1 w0.254: v2(139.82,66.46) 139.82,66.67 140.41,67.27 142.75,67.27 143.28,67.8 143.28,69.96 142.93,70.32 142.93,71.5 141.96,72.47 v2(141.96,72.93) ; v2(86.28,79.33) 85.53,79.33 83.18,76.98 79.73,76.98 77.91,78.8 72.47,78.8 71.91,79.37 v2(71.91,79.46)
  IN2 w0.254: v2(151.19,73.85) 151.19,73.66 150.88,73.34 150.38,73.34 150.06,73.02 150.06,72.62 150.34,72.34 151.49,72.34 151.92,71.9 151.92,71.45 152.32,71.05 153.82,71.05 154.15,70.72 154.15,69.99 155.3,68.84 158.77,68.84 158.99,69.06 160.16,69.06 160.57,69.47 161.11,69.47 161.38,69.2 161.38,68.44 161.66,68.15 165.92,68.15 166.49,68.73 167.03,68.73 167.19,68.56 173.48,68.56 173.53,68.5 174.53,68.5 174.9,68.88 175.69,68.88 175.99,69.17 176.54,69.17 177.49,68.23 v2(177.61,68.23) ; v2(60.11,59.89) 60.02,59.8 59.97,59.8 59.72,59.55 59.72,58.64 59.22,58.15 59.22,56.8 59.75,56.27 64.44,56.27 65.96,54.75 65.96,52.16 v2(65.51,51.7) ; v2(90.51,78.4) 90.71,78.19 91.28,78.19 92.19,79.11 113.23,79.11 v2(114.2,78.14)
  IN2 w0.305: 150.06,72.62 149.64,72.62 149.44,72.42 142.57,72.42 142.06,72.93 v2(141.96,72.93)
  IN3 w0.254: v2(177.61,68.23) 177.64,68.19 182.5,68.19 183.13,68.83 186.24,68.83 186.62,69.21 186.62,69.66 186.87,69.91 187.62,69.91 188.81,68.72 188.81,67.91 187.47,66.57 187.47,65.89 186.49,64.91 184.88,64.91 183.38,63.41 183.38,60.81 183.04,60.46 183.04,58.2 183.76,57.48 183.76,55.56 182.23,54.03 182.23,53.86 182.05,53.68 v2(182.05,53.28)
  IN4 w0.254: v2(86.28,79.33) 86.53,79.09 89.81,79.09 v2(90.51,78.4) ; v2(71.91,79.46) 71.91,79.41 71.31,78.81 65.99,78.81 64.93,79.87 62.46,79.87 62.1,79.51 62.1,78.27 62.61,77.76 62.61,76.21 62.17,75.77 62.17,74.6 62.32,74.46 62.32,67.3 61.27,66.25 61.27,64.3 60.75,63.78 60.75,63.18 58.7,61.12 58.7,60.27 59.16,59.81 60.03,59.81 v2(60.11,59.89) ; 125.4,70.39 124.61,70.39 122.48,72.53 121.85,72.53 121.56,72.81 121.56,72.87 119.68,74.75 118.3,74.75 117.98,75.07 117.98,75.7 117.58,76.11 v2(117.58,76.45) ; 125.76,67.95 126.11,67.6 128.15,67.6 128.23,67.52 133.08,67.52 134.09,66.52 134.74,66.52 135.1,66.15 138.99,66.15 139.3,66.46 v2(139.82,66.46)
  BOTTOM w0.152: UCPU1.A18 141.83,72.76 141.96,72.88 v2(141.96,72.93)
  BOTTOM w0.203: PC1004.1 PR1084.1 PR1063.1 PR1074.1
  BOTTOM w0.254: UCPU1.K20 140.67,66.94 140.15,66.94 UCPU1.K21 139.78,66.57 139.78,66.49 v2(139.82,66.46) ; v2(65.51,51.7) 65,51.7 64.8,51.9 PC1004.1
  BOTTOM w0.305: RC152.1 115.66,78.58 114.64,78.58 v2(114.2,78.14)
  BOTTOM w0.381: RC71.1 109.12,77.99 109.5,78.37 113.98,78.37 v2(114.2,78.14) ; v2(117.58,76.45) 117.45,76.58 RC79.1
  BOTTOM w0.508: RC152.1 116.59,78.06 117.45,77.2 RC79.1 ; RC120.2 RC157.1 113.64,77.59 v2(114.2,78.14)
+1.0V_VCCSTG: length 106.4
  TOP w0.254: v2(92.51,76.34) 93.12,76.34 93.23,76.22 94.2,76.22 94.76,75.66 97.2,75.66 97.77,76.23 98.88,76.23 101.92,79.28 107.5,79.28 109.32,77.45 109.98,77.45 110.38,77.85 111.16,77.85 ; v2(119.38,76.46) 119.66,76.46 RC82.1
  TOP w0.381: R1325.2 160.69,65.9 161.07,65.52 v2(162.18,65.52)
  TOP w0.508: 138.83,72.35 v2(139.34,72.86) ; 138.83,72.35 CC199.1 ; 138.83,72.35 138.96,72.22 RC143.2 ; RC81.1 117.65,78.06 v2(117.45,78.27) 117.25,78.06 RC130.1 ; 111.16,77.85 v2(111.18,77.85) 111.2,77.82 111.2,77.63 111.42,77.42 RC83.1
  IN2 w0.254: v2(160.9,68.96) 160.62,68.68 159.15,68.68 158.93,68.46 155.14,68.46 153.36,70.24 152.1,70.24 151.54,70.79 151.54,71.74 151.33,71.95 150.18,71.95 150.12,72.02 140.18,72.02 v2(139.34,72.86)
  IN4 w0.254: v2(162.18,65.52) 162.18,64.39 163.37,63.2 164.39,63.2 164.82,62.77 164.82,62.17 165.88,61.12 165.88,58.17 v2(167.73,56.32)
  IN4 w0.457: v2(111.18,77.85) 111.2,77.87 111.2,78.01 111.63,78.44 112.83,78.44 113.74,77.53 115.81,77.53 116.55,78.27 v2(117.45,78.27) 117.58,78.27 v2(119.38,76.46)
  BOTTOM w0.203: v2(139.34,72.86) 139.36,72.84 UCPU1.A22
  BOTTOM w0.305: v2(139.34,72.86) 139.78,73.29 139.78,74.43
  BOTTOM w0.381: RC135.1 RC134.1 RC131.1 91.65,75.72 92.12,75.72 92.51,76.1 v2(92.51,76.34)
  BOTTOM w0.508: 119.36,77.12 119.41,77.07 119.41,76.49 v2(119.38,76.46) ; 139.78,74.43 136.25,77.96 119.76,77.96 ; v2(167.73,56.32) 167.55,56.5 167.55,57.12 PR401.1
  vias: v3(161.42,69.17)
+1.0V_VCCSTG_R: length 3.5
  TOP w0.254: v2(140.7,68.58) 140.69,68.58 140.69,68.57 140.74,68.57 141.17,69 141.17,69.68 v1(141.07,69.78) 140.36,70.49 RC143.1
  BOTTOM w0.254: v2(140.7,68.58) 140.94,68.58 UCPU1.G20
+1.0VA: length 188.5
  TOP w0.254: RC299.1 151.87,69.68 152.58,68.97 153.54,68.97 153.78,68.73 158.76,68.73 159.43,69.39 159.43,69.98 159.56,70.11 ; 159.56,70.11 159.56,70.65 v2(159.45,70.76) ; 159.56,70.11 161.8,70.11 162.37,69.54 162.37,68.89 162.56,68.7 163.67,68.7 164.19,68.18
  TOP w0.381: v2(141.04,60.61) 141.04,61.14 CC206.1
  TOP w0.508: RC172.1 160.26,59.69 160.3,59.65 v2(160.53,59.65) ; RC170.1 144.76,72.88 144.53,73.11 144.53,75.04 144.02,75.55 143.1,75.55 v2(143.08,75.52) 142.06,75.52 141.39,76.2 CC273.1 141.16,77 141.16,79.57 141.83,80.25 153.84,80.25 154.45,79.64 155.18,79.64
  IN1 w0.254: v2(157.45,66.12) 157.06,66.12 156.78,66.39 156.78,68.27 157.21,68.7 158.28,68.7 159.17,69.59 159.17,70.48 v2(159.45,70.76) 159.72,71.03 159.72,72.37 158.93,73.16 158.93,74.32 158.13,75.11 157.36,75.11 156.27,76.19 v2(156.27,76.88)
  IN1 w0.305: v2(141.71,62.27) 141.71,62.13 142.11,61.73 142.62,61.73 143.08,62.19 145.64,62.19 146.63,63.17 150.67,63.17 151.17,63.67 151.17,67.47 151.94,68.24 151.94,69.98 152.92,70.96 152.92,72.64 152.37,73.19 v2(152.18,73.19)
  IN1 w0.508: v2(166.6,65.4) 165.61,64.41 163.29,64.41 162.44,63.57 162.44,61.36 160.73,59.65 v2(160.53,59.65)
  IN3 w0.381: v2(89.71,69.2) 91.11,69.2 92.26,70.34 96.07,70.34 97.57,68.84 111.04,68.84 111.98,69.78 111.98,70.96 112.62,71.61 117.83,71.61 118.22,71.21 120.57,71.21 121.15,71.79 122.72,71.79 123.11,71.4 125.99,71.4 126.41,71.82 127.37,71.82 127.53,71.66 129.11,71.66 129.24,71.8 135.18,71.8 135.36,71.62 137.95,71.62 138.71,72.37 138.71,74.46 139.82,75.57 143.03,75.57 v2(143.08,75.52) 143.18,75.62 144.92,75.62 145.27,75.27 151.03,75.27 152.19,74.11 152.19,73.2 v2(152.18,73.19)
  BOTTOM w0.254: UCPU1.Y18 141.39,61.2 UCPU1.AB19 141.39,60.99 141.04,60.64 141.04,60.64 ; UCPU1.Y18 142.04,61.66 UCPU1.AB17 ; UCPU1.Y18 142.04,61.94 v2(141.71,62.27) ; CC281.1 160.58,59.7 v2(160.53,59.65) ; v2(142.42,63.94) 142.04,64.32 UCPU1.P18 ; UCPU1.AK20 140.63,56.82 140.26,56.45 139.95,56.45 v2(139.85,56.35) ; 141.04,60.64 140.96,60.64 140.74,60.86 UCPU1.AB20 ; 141.04,60.64 v2(141.04,60.61)
  BOTTOM w0.305: v2(157.45,66.12) 157.23,65.9 RC301.1 ; RC216.1 71.97,69.62 72.35,70 73.34,70 73.87,70.53 75.3,70.53 75.65,70.88 79.29,70.88 79.62,70.55 82.69,70.55 83.43,71.29 84.76,71.29 86.22,69.83 89.08,69.83 v2(89.71,69.2)
  vias: v2(157.32,77.61) v2(157.64,78.12) v2(157.96,77.63) v2(158.55,77.63) v2(190.85,56.4) v2(190.85,55.79) v2(190.86,56.98) v2(190.86,55.2) v2(190.86,54.57) v3(156.77,79.31)
+1.0VA_XDP: length 115.3
  TOP w0.127: v2(67.49,75.32) 67.49,75.6 CC28.1 68.1,75.6 JXDP1.43 ; v2(77.11,78.19) 77.19,78.11 RC138.1 ; v2(68.33,69.1) 68.1,68.87 JXDP1.44
  IN1 w0.081: v2(77.11,78.19) 76.84,78.47 72.31,78.47 70.69,76.85 70.15,76.85 69.67,76.36 68.55,76.36 67.49,75.31 67.49,75.32 v2(67.49,75.32)
  BOTTOM w0.127: v2(68.33,69.1) 67.87,69.1 CC29.1 68.26,69.9 68.26,70.44 68.83,71.01 RC216.2 ; RC216.2 69.27,71.01 70.32,69.96 71.83,69.96 72.21,70.34 73.19,70.34 73.88,71.03 74.74,71.03 74.99,71.28 74.99,71.61 75.39,72.01 79.82,72.01 80.82,71.01 82.67,71.01 83.29,71.63 84.91,71.63 86.26,70.28 88.77,70.28 89.91,71.41 89.91,73.16 91.12,74.38 93.74,74.38 95.53,76.17 95.53,77.68 98.15,80.3 139.66,80.3 140.67,79.3 140.67,77.5 141.28,76.89 146.38,76.89 RC115.2 ; RC216.2 69.06,71.79 68.22,72.62 68.22,74.91 67.82,75.32 v2(67.49,75.32)
+1.0VAP: length 18.9
  IN1 w0.203: v2(204.64,62.66) 203.64,62.66 203.43,62.44 203.43,58.76 202.46,57.79 202.46,54.97 200.46,52.97 198.69,52.97 196.25,55.41 v2(196.17,55.41)
  BOTTOM w0.254: v2(204.64,62.66) 204.56,62.73 PR704.1 PC707.1
  vias: v2(196.13,57.49) v2(196.55,57.02) v2(196.52,56.17) v3(196.7,55.15)
+1.0VS_VCCIO: length 148.4
  TOP w0.127: v2(75.95,80.02) 76.43,79.54 RC132.1
  TOP w0.381: v2(127.43,57.79) 127.86,57.36 CC252.1 128.12,57.11 128.63,56.6 CC186.1 128.63,55.94 v2(128.91,55.66)
  TOP w0.508: v2(176.94,72.78) 177.39,72.32 RE70.1 ; CC252.1 128.75,57.36 CC249.1 ; CC253.1 CC250.1 CC251.1 CC248.1 ; RC2.1 122.28,67.33 v2(122.62,66.99)
  IN1 w0.381: v2(60.45,74.8) 60.45,74.98 61.75,76.27 66.58,76.27 67.05,76.74 67.57,76.74 68.13,77.31 68.64,77.31 69.08,77.75 69.08,79.07 70.54,80.53 75.44,80.53 v2(75.95,80.02) ; v2(122.62,66.99) 122.16,67.45 122.16,69.36 120.82,70.7 118.16,70.7 117.22,71.64 114.28,71.64 113.28,70.64 113.28,69.7 113,69.43 112.49,69.43 112.49,69.43 111.23,69.43 110.52,68.72 108.18,68.72 107.65,68.18 99.79,68.18 99.52,68.46 94.8,68.46 v2(94.34,68.92)
  IN1 w0.508: v2(125.82,66.18) 125.91,66.18 127.18,64.91 127.18,58.05 v2(127.43,57.79)
  IN2 w0.381: v2(60.45,74.8) 58.38,72.73 58.38,71.52 v2(58.53,71.37) ; v2(165.14,69.94) 165.14,70.46 165.52,70.84 166.75,70.84 167.32,71.41 174.25,71.41 174.68,71.84 176.15,71.84 176.94,72.63 v2(176.94,72.78)
  IN3 w0.381: v2(58.53,71.37) 58.58,71.42 59.12,71.42 60.77,69.77 71.87,69.77 72.12,70.02 73.08,70.02 73.46,69.64 73.46,68.57 74.05,67.97 79.38,67.97 79.95,68.54 81.93,68.54 82.33,68.15 87.09,68.15 87.97,67.27 92.41,67.27 94.06,68.92 v2(94.34,68.92)
  BOTTOM w0.254: UCPU1.AM42 128.51,56.05 v2(128.91,55.66) 128.91,56.5 UCPU1.AL42
  BOTTOM w0.381: v2(165.14,69.94) 165.14,69.3 165.7,68.74 165.7,68.29 166.6,67.39 167.08,67.39 167.46,67.01 167.46,66.37 167.13,66.04 166.31,66.04 166.05,65.78 166.05,64.84 166.5,64.4 166.5,63.29 167.03,62.76 167.03,61.98 168.64,60.37 168.64,55.47 v2(168.51,55.34)
  vias: v2(134.37,55.66) v2(135.3,57.26) v2(135.28,55.66) v2(167.5,55.65) v2(167.54,54.77) v2(167.94,55.2) v2(167.94,54.34) v3(166.57,55.51)
+1.0VS_VCCIOP: length 7.5
  TOP w0.508: PR1408.1 171.27,45.78 170.89,45.78 v2(170.69,45.98)
  IN4 w0.254: v2(170.69,45.98) 168.99,47.68 168.98,47.68 167.46,49.2 167.46,50.2 167.64,50.38 168.4,50.38 168.4,50.37 v2(168.58,50.2)
+1.2V_DDR: length 207.5
  TOP w0.076: 115.83,33.51 115.88,33.46 115.9,33.46 116.1,33.26 116.1,32.64 116.44,32.3 UD20.C12
  TOP w0.127: UD21.E12 135.94,32.3 136.25,32.6 136.25,33.54 ; UD19.E12 101.97,32.56 101.82,32.71 101.82,32.83 ; 141.27,28.3 141.27,28.89 141.06,29.1 UD21.N8 ; UD19.H3 104.17,25.1 ; UD22.F2 152.02,24.3
  TOP w0.152: UD21.M2 140.35,24.12 140.43,24.05 140.43,23.29 139.57,22.44 139.12,22.44 v2(138.56,21.88)
  TOP w0.254: v2(159.56,31.15) 159.21,31.5 UD22.U11 ; UD20.H11 UD20.H12 ; UD20.H12 UD20.G12 ; UD20.H12 119.69,33.34 119.84,33.49 120.52,33.49 v2(120.58,33.55) ; v2(100.87,32.81) 100.92,32.76 100.92,32.3 UD19.C12 ; CD57.1 147.17,31.58 147.93,32.34 v2(148.16,32.34) 148.16,32.34 148.64,31.86 148.64,31.63 UD22.A11 ; UD21.F2 136.43,24.3 136.18,24.04 v2(136.18,23.8) ; v2(104.5,27.1) 104.82,27.43 UD19.J6 ; v2(104.5,27.1) 104.82,26.78 UD19.J5 ; v2(104.5,27.1) 104.17,26.78 UD19.H5 ; UD20.J10 UD20.J9 120.02,29.58 v2(120.02,29.5) 119.69,29.83 UD20.H9 ; UD22.K12 UD22.L12 155.27,33.36 156.01,34.09 v2(156.09,34.09) ; v2(129.72,32.32) 129.04,33 CD7.1 ; v2(153,25.5) 153.32,25.18 UD22.H3 ; UD21.A8 132.72,29.1 v2(132.24,28.63) 132.24,29.5 132.64,29.9 UD21.A9 ; UD19.L2 106.12,24.01 v2(106.32,23.81) 106.77,24.26 UD19.M2 ; UD20.H8 119.69,29.03 v2(120.02,28.7) ; UD19.A9 99.55,29.83 99.24,29.83 99.09,29.68 99.09,28.33 v2(99.11,28.3) 99.62,28.82 UD19.A8 ; v2(101.9,28.7) 102.22,29.03 UD19.E8 ; UD20.U11 v2(126.11,31.5) ; v2(139.83,23.76) 139.7,23.88 UD21.L2 ; UD22.C12 150.07,32.22 v2(149.75,31.9) ; v2(107.26,28.56) 107.42,28.72 UD19.N8 ; UD19.D6 101.57,27.43 v2(101.9,27.1) ; UD22.P6 157.22,27.46 157.32,27.36 157.32,27.33 v2(157.55,27.1) 157.22,26.78 UD22.P5 157.55,26.37 v2(157.55,26.3) 157.22,25.98 UD22.P4 ; 154.96,26.31 v2(154.96,26.3) ; UD19.P4 108.07,25.97 v2(107.75,26.29) ; 117.74,32.3 UD20.E12 ; v2(119.08,23.74) 119.04,23.79 119.04,24.3 UD20.G2 119.69,24.95 UD20.H3 ; v2(118.29,23.72) 118.39,23.82 118.39,24.3 UD20.F2 ; v2(101.9,26.3) 101.9,26.21 101.75,26.07 101.74,26.07 UD19.D4 ; v2(138.06,31.11) 137.75,31.42 UD21.H11 ; v2(135.48,26.3) 135.15,26.63 UD21.D5 134.83,27.02 v2(134.83,27.1) ; v2(99.26,31.89) 99.62,31.53 UD19.A11 ; v2(116.77,27.1) 116.77,27.02 UD20.D5 116.77,26.38 v2(116.77,26.3) ; UD19.N12 107.42,32.3 107.42,33.05 107.14,33.33 106.9,33.33 v2(106.84,33.4) ; UD19.P6 108.07,27.4 v2(107.77,27.1) 108.07,26.8 UD19.P5 ; 104.17,25.1 103.99,25.28 103.99,25.29 103.85,25.43 v2(103.85,25.5) ; UD21.G2 137.1,24.3 137.1,23.77 v2(137.1,23.77) ; v2(129.74,31.73) CD175.1 ; CD158.1 128.45,30.84 128.81,30.48 129.73,30.48 129.76,30.45 v2(129.76,30.46) ; v2(118.07,28.67) 117.74,29 UD20.E8 ; UD19.K11 UD19.K12 ; UD19.K12 105.47,33.12 105.16,33.44 104.9,33.44 v2(104.86,33.47) 104.17,32.79 104.17,32.3 UD19.H12 UD19.G12 ; UD19.K12 UD19.L12 ; UD19.L5 106.12,26.77 v2(105.78,27.11) 105.47,27.42 UD19.K6 UD19.K8 ; 136.25,34.25 136.25,33.54 ; CD60.1 157.28,35.34 v2(157.28,33.52) ; v2(129.8,28.43) 129.29,28.94 CD157.1 ; 101.82,32.83 101.82,33.2 v2(102.29,33.68) 103.42,34.81 CD152.1 ; UD21.H3 137.75,25.03 v2(137.43,24.7) ; CD155.1 113.53,33.51 115.83,33.51 ; UD19.U11 110.23,31.71 110.23,31.71 v2(110.67,31.71) 111.06,31.71 111.82,30.95 CD29.1 ; v2(150.29,33.34) 150.43,33.34 151.37,32.4 UD22.E12 ; UD20.K8 120.99,29.18 v2(120.67,29.5) ; v2(108.71,33.33) 108.97,33.08 108.97,32.55 UD19.R12 ; 101.25,27.04 v2(101.25,27.1) ; UD22.U9 159.17,29.82 159.64,29.35 159.64,29.24 v2(159.66,29.22) 159.54,29.1 UD22.U8 ; UD22.E8 151.7,28.77 v2(151.7,28.7) ; v2(155.47,23.81) 155.47,23.83 155.27,24.03 UD22.L2 UD22.M2 ; v2(126.17,33.58) 125.93,33.82 CD6.1 ; v2(144.13,29.79) 144.02,29.9 UD21.U9 ; v2(156.9,28.7) 156.9,28.77 UD22.N8 ; UD19.H9 UD19.J9 104.83,29.9 105.15,30.21 v2(105.15,30.3) 104.82,30.63 UD19.J10 104.17,31.35 UD19.H11 ; UD19.G5 103.84,27.02 103.84,27.17 104.17,27.5 UD19.H6 104.19,27.5 104.29,27.6 104.29,28.55 v2(104.32,28.57) 104.17,28.72 104.17,29.1 UD19.H8 ; UD20.P6 UD20.P5 ; UD20.R12 124.24,33.22 124.57,33.55 v2(125.2,33.55) ; 152.02,24.3 152.02,24.23 v2(152.35,23.9) 152.67,24.22 UD22.G2 ; v2(121.44,23) 121.74,23.3 121.74,23.91 121.64,24.01 UD20.L2 UD20.M2 ; 142.3,32.3 UD21.R12
  TOP w0.305: UD19.G2 103.52,24.38 v2(103.85,24.7) ; UD19.K5 105.47,26.8 v2(105.78,27.11) ; UD19.F2 102.87,24.04 v2(102.64,23.81)
  TOP w0.32: CD169.1 v2(160.73,32.87) ; CD170.1 162.03,28.94 v2(162.08,28.89) ; CC258.1 127.61,52.75 v2(127.97,53.1) ; CC257.1 131.67,53.06 v2(131.63,53.1) ; v2(134.24,49.08) 134.34,49.18 CC178.1 CC176.1
  TOP w0.381: CD172.1 156.38,34.65 156.13,34.4 156.13,34.13 v2(156.09,34.09) ; CD179.1 151.81,34.86 v2(150.29,33.34) ; CD1.1 118.05,34.72 v2(118.81,33.97) ; CD5.1 122.5,34.86 v2(122.22,34.58) ; CD155.1 CD148.1
  TOP w0.508: v2(106.74,36.36) 106.85,36.24 CD37.1 ; 91.47,37.41 91.47,36.39 92.7,35.16 96.11,35.16 97.52,36.57 98.36,36.57 CD2.1 99.7,35.65 v2(100.05,36) 100.5,35.55 CD33.1 ; 91.47,37.41 90.62,38.26 RD17.1 ; 91.47,37.41 91.58,37.52 92.71,37.52 92.84,37.4 RD21.1 ; CD91.1 v2(143.56,22.44) ; v2(157.3,38.72) 156.89,38.31 RD22.1 ; CD63.1 CD175.1 ; v2(98.4,32.9) 98.32,32.98 CD8.1 ; CD59.1 148.89,35.18 v2(148.01,34.3) 147.45,33.74 CD168.1 ; CD86.1 110.28,35.8 v2(109.6,36.48) ; v2(129.79,57.97) 130.02,57.74 RC171.1 ; CD154.1 CD160.1 v2(127.13,22.59) ; CD151.1 CD149.1 105.77,20.96 105.54,21.19 v2(105.54,21.34) ; CD153.1 97.33,23.73 98.91,25.31 v2(98.91,25.56) ; v2(123.23,49.11) 123.1,48.98 CC179.1 ; CD3.1 97.68,31.58 v2(98.11,31.15)
  IN2 w0.254: v2(118.07,28.67) 118.07,28.01 117.16,27.1 v2(116.77,27.1) v2(116.77,26.3)
  IN3 w0.508: v2(157.3,38.72) 157.45,38.87 157.45,41.76 159.21,43.52 159.66,43.52 160.83,44.69 160.83,45.88 161.64,46.68 162.3,46.68 162.89,47.28 v2(165.71,47.28)
  BOTTOM w0.127: v2(138.03,53.1) 138.33,52.8 UCPU1.AU23
  BOTTOM w0.152: UCPU1.BB41 129.33,49.21 ; v2(134.24,49.08) 134.29,49.13 UCPU1.BB32
  BOTTOM w0.178: v2(123.23,49.11) 123.22,49.12 123.22,49.66 123.22,49.95 UCPU1.BB51 ; v2(139.44,48.96) 139.29,49.12 139.29,49.85 139.27,49.9 UCPU1.BB23
  BOTTOM w0.254: v2(120.58,33.55) 120.16,33.97 v2(118.81,33.97) ; 129.33,49.21 129.33,48.64 129.29,48.6 v2(129.29,48.6) ; v2(125.65,49.11) 125.58,49.19 125.58,49.91 UCPU1.BB47 ; UCPU1.AU35 v2(131.63,53.1) ; UCPU1.AU28 v2(135.28,53.1) ; UCPU1.AU42 v2(127.97,53.1)
  BOTTOM w0.381: UC2.5 102.38,46.2 101.85,45.68 CC240.1
  BOTTOM w0.508: CC240.1 101.4,46.67 v2(100.89,47.18) ; CD34.1 117.45,22.87 v2(118.29,23.72) ; v2(119.08,23.74) 118.97,23.64 118.97,21.8 119.36,21.42 CD41.1 ; v2(136.18,23.8) 136.18,21.49 136.37,21.29 CD62.1 136.25,20.53 CD85.1 ; CD156.1 122.15,20.84 121.87,21.12 121.87,22.56 v2(121.44,23) ; CD171.1 151.11,20.53 CD64.1 150.98,21.8 150.09,22.69 143.82,22.69 v2(143.56,22.44) 142.34,21.22 CD58.1 141.58,20.41 CD89.1
  BOTTOM w0.762: v2(105.54,21.34) 105.56,21.34 106.32,22.11 v2(106.32,23.81)
  vias: v2(98.32,28.58) v2(101.25,26.3) v2(110.62,32.93) v2(110.64,28.98) v2(119.37,27.1) v2(120.67,27.1) v2(121.32,27.1) v2(129.77,29.19) v2(132.24,31.58) v2(133.5,33.74) v2(135.62,28.61) v2(137.44,27.11) v2(138.07,29.49) v2(138.08,27.11) v2(138.73,27.09) v2(138.78,28.61) v2(139.38,27.09) v2(140.81,33.36) v2(141.33,27.1) v2(141.33,26.3) v2(144.15,32.39) v2(150.4,27.1) v2(150.4,26.3) v2(151.05,27.1) v2(153,27.1) v2(153.65,30.3) v2(153.65,29.5) v2(153.65,28.7) v2(154.3,29.5) v2(154.3,27.1) v2(154.95,28.7) v2(160.99,23.13) v2(161,22.51) v2(161.01,21.9) v2(161.55,23.45) v2(161.57,22.86) v2(162.14,23.47) v2(162.22,22.88) v3(145.69,37.32)
+1.2V_DDRP: length 17.5
  TOP w0.508: v2(174.32,30.97) 174.04,30.69 PC609.1 PR603.1
  BOTTOM w0.254: v2(167.49,20.99) 172.21,20.99 172.92,21.7 172.92,29.57 v2(174.32,30.97)
  vias: v1(164.64,25.92)
+1.2V_MEM_CPUCLK: length 9.4
  TOP w0.127: v2(129.79,55.66) 129.79,55.47 129.15,54.82 127.79,54.82 127.53,54.57 127.53,53.54 126.63,52.64 126.63,51.99 v1(126.43,51.79) 126.43,51.25 126.67,51.02 CC194.1 125.91,50.62 CC260.1
  TOP w0.254: v2(129.79,55.66) 130.02,55.89 RC171.2
  BOTTOM w0.254: UCPU1.AM40 129.4,56.05 v2(129.79,55.66)
+1.8V_PGPP: length 8.1
  TOP w0.381: v2(143.6,59.75) 143.6,59.89 144.2,60.49 v3(144.5,60.49) 145.19,60.49 145.53,60.14 149.98,60.14 RC304.2
  BOTTOM w0.254: v2(143.6,59.75) 143.6,59.59 UCPU1.AF16
+1.8VA: length 274.8
  TOP w0.457: RH150.2 156.26,53.22 156.26,52.08 155.73,51.55 v2(154.89,51.55)
  TOP w0.508: C1169.1 v2(30.28,42.71) ; v2(70.92,23.02) 72.39,21.55 v3(72.39,18.42) 72.39,15.96 72.77,15.58 81.48,15.58 v2(82.42,16.52) ; RH150.2 RH144.2 156.52,54.36 RH149.2 RH152.2 RH151.2 ; R79.1 161.2,36.09 v2(161.65,36.53) ; RC304.1 152.63,60.41 CC272.1 154.15,60.41 154.46,60.71 v2(155.05,60.71)
  IN1 w0.508: v2(158.37,61.68) 158.37,62.24 159.57,63.45 160.54,63.45 161.56,64.47 161.56,65.76 161.93,66.13 163.09,66.13 163.81,66.84 164.49,66.84 166.51,68.85 167,68.85 167.89,69.75 v2(167.89,69.91)
  IN2 w0.381: v2(161.65,36.53) 161.9,36.53 162.22,36.85 162.22,38.42 161.84,38.8 161.84,41.78 163.36,43.31 163.36,46.43 161.84,47.95 161.17,47.95 160.83,48.29 160.83,49.55 160.26,50.12 158.92,50.12 157.49,51.55 v2(154.89,51.55) ; v2(167.66,33.15) 167.92,33.41 170.05,33.41 171.17,32.29 171.17,28.36 171.91,27.62 171.91,21.09 170.18,19.36 170.18,18.83 168.3,16.95 164.01,16.95 163.89,16.84 162.81,16.84 161.33,15.35 160.79,15.35 160.55,15.11 160.55,14.6 160.34,14.4 158.56,14.4 158.22,14.74 v2(158.22,14.95)
  IN2 w0.457: v2(70.92,23.02) 70.13,22.23 67.92,22.23 66.31,20.62 64.11,20.62 62.22,18.74 60.36,18.74 60.15,18.53 57.37,18.53 56.83,19.06 53.57,19.06 53.31,18.8 49.53,18.8 49.19,18.46 46.6,18.46 45.59,19.47 43.97,19.47 42.93,18.42 42.93,17.63 v2(42.91,17.61)
  IN3 w0.381: v2(82.42,16.52) 83.24,15.71 94.97,15.71 95.53,16.26 99.59,16.26 100.27,15.59 125.36,15.59 125.53,15.77 131.16,15.77 133.25,13.67 157.11,13.67 158.22,14.78 v2(158.22,14.95)
  IN3 w0.508: v2(155.05,60.71) 155.38,61.05 157.73,61.05 v2(158.37,61.68)
  IN4 w0.356: v2(155.05,60.71) 153.98,60.71 153.09,59.83 153.09,58.58 151.56,57.06 151.56,54.87 153.36,53.08 154.23,53.08 154.89,52.41 v2(154.89,51.55)
  BOTTOM w0.203: 153.18,61.43 153.13,61.38 152.44,61.38 152.31,61.51 UCPU1.AA1
  BOTTOM w0.381: v2(161.65,36.53) 161.65,35.45 164.12,32.98 167.49,32.98 v2(167.66,33.15) ; v2(30.28,42.71) 28.32,40.75 28.32,38.96 29.43,37.85 29.97,37.85 30.35,37.47 30.35,36.6 30.24,36.48 30.24,32.28 32.23,30.29 32.23,30.01 33.71,28.53 35.27,28.53 36.35,27.46 36.35,26.76 37.1,26.01 37.1,23.42 36.86,23.18 36.86,22.23 37.08,22 37.08,21.09 37.5,20.67 37.83,20.67 38.57,19.94 38.57,19.05 39.82,17.8 41.92,17.8 42.11,17.61 v2(42.91,17.61)
  BOTTOM w0.508: 153.18,61.43 154.41,61.43 155.05,60.78 v2(155.05,60.71) 155.38,61.05 CC212.1
+1.8VAP: length 19.7
  TOP w0.254: PR806.1 173.33,70.12 172.64,69.42 172.25,69.42 v1(171.9,69.77) 171.55,70.12 PR802.1 PC801.1 170.66,70.77 170.08,70.19 170.08,69.48 169.34,68.74 168.02,68.74 167.08,69.68 167.08,71.15 167.36,71.43 ; PU800.14 173.42,77.34 v2(173.44,77.36)
  BOTTOM w0.254: v2(173.44,77.36) 173.41,77.36 169.7,73.65 169.7,73.55 169.49,73.35 169.49,72.68 169.21,72.4 169.09,72.27 v2(168.94,72.27)
+1.8VS_AUDIO: length 39.7
  TOP w0.203: v2(23.75,27.06) 24.17,27.48 UA2.36
  TOP w0.508: v2(33.1,23.02) 33.49,22.63 RA81.1 ; v2(23.75,27.06) 23.7,27.11 v2(22.96,27.11) 22.96,26.64 CA78.1
  IN3 w0.508: v2(33.52,34.88) 32.82,35.58 32.82,36.28 33.3,36.76 33.3,37.42 32.94,37.78 32.18,37.78 31.75,38.21 29.86,38.21 v2(29.19,38.88) ; v2(33.1,23.02) 32.39,23.02 32.21,22.84 31.01,22.84 26.8,27.06 v2(23.75,27.06)
  IN4 w0.508: v2(23.75,27.06) 24.41,27.06 26.34,28.99 29.82,28.99 30.91,30.08 30.91,31.61 32.84,33.54 32.84,34.41 33.31,34.88 v2(33.52,34.88)
  BOTTOM w0.508: RA63.1 23.85,26.96 v2(23.75,27.06) ; v2(22.96,27.11) 22.96,26.69 CA83.1 ; RA82.1 v2(33.52,34.88)
  vias: v3(28.55,39.4)
+1.8VU: length 61.9
  TOP w0.254: v2(143.98,31.11) 143.98,31.08 UD21.U10 ; UD22.A5 148.77,26.73 v2(148.39,27.11) 148.77,27.49 UD22.A6 ; UD19.A3 99.62,25.16 99.95,25.48 v2(99.95,25.5) 99.95,25.54 99.62,25.86 UD19.A4 ; CD145.1 113.61,30.46 v2(114.69,30.46) 114.9,30.46 UD20.A10 ; UD20.U10 126.03,30.7 v2(126.05,30.72) ; UD22.A4 148.77,25.83 v2(149.1,25.5) 148.77,25.17 UD22.A3 ; UD20.A3 115.14,25.19 115.45,25.5 v2(115.47,25.5) 115.47,25.55 115.14,25.87 UD20.A4 ; UD20.A6 115.05,27.41 114.88,27.41 v2(114.59,27.12) 115.01,26.7 UD20.A5 ; UD21.U3 143.6,25.17 v2(143.93,25.5) 143.89,25.54 143.76,25.54 143.6,25.7 UD21.U4 143.6,25.98 v2(143.93,26.3) 143.6,26.63 143.6,26.7 ; UD21.A5 133.07,26.7 v2(132.65,27.12) 133.02,27.5 UD21.A6 ; UD19.U10 110.3,30.7 v2(110.67,31.07) ; v2(132.69,31.19) 133.18,30.7 UD21.A10 ; UD20.U6 125.54,27.43 v2(125.87,27.1) 125.54,26.78 UD20.U5 125.54,26.63 v2(125.87,26.3) 125.54,25.98 UD20.U4 125.54,25.83 v2(125.87,25.5) 125.54,25.17 UD20.U3 ; UD19.A5 99.47,26.7 99.07,27.1 99.08,27.12 v2(99.09,27.12) 99.09,27.17 99.42,27.5 UD19.A6 ; v2(160.4,30.45) 159.42,30.45 UD22.U10 ; UD21.U6 143.6,27.43 v2(143.93,27.1) 143.6,26.77 143.6,26.7 ; CD90.1 130.37,27.04 v2(129.16,27.04) 129.16,27.1 128.98,27.28 CD42.1 ; UD21.A3 133.2,25.17 v2(133.53,25.5) 133.2,25.83 UD21.A4 ; UD19.A10 99.4,30.7 v2(99.01,30.31) 98.88,30.44 CD147.1 ; 143.6,26.7 UD21.U5 ; UD22.A10 148.77,30.7 v2(148.4,31.07) ; v2(110.35,26.3) 110.02,26.63 110.02,26.7 UD19.U5 110.03,26.7 v2(110.4,27.08) 110.02,27.46 UD19.U6
  TOP w0.305: v2(110.35,26.3) 110.02,25.98 UD19.U4 110.02,25.83 v2(110.35,25.5) 110.35,25.43 UD19.U3
  TOP w0.32: CD144.1 161.46,30.73 161.19,30.45 v2(160.4,30.45)
  TOP w0.381: v2(113.64,25.54) 113.46,25.54 113.01,25.99 CD143.1 ; CD163.1 145.24,30.69 144.81,31.12 143.98,31.12 v2(143.98,31.11) ; v2(143.93,27.1) 144.15,26.88 CD165.1 ; CD164.1 112.75,25.23 113.08,24.9 v2(113.64,24.9) ; v2(143.93,25.5) 144.04,25.61 CD162.1
  TOP w0.508: CD146.1 97.2,25.99 97.33,26.12 CD92.1 98.27,26.78 v2(98.49,27.01)
  TOP w0.838: 160.57,41.17 160.57,41.09 161.53,40.13 161.53,38.48 162.47,37.54 v3(162.47,36.01) 161.72,35.26 160.5,35.26 159.92,34.68 159.92,31.96 160.4,31.48 v2(160.4,30.45) 160.47,30.39 160.47,28.24 v2(159.97,27.75)
  vias: v2(158.86,27.1) v2(158.86,26.3) v2(159.55,25.55)
+1.8VUP: length 17.5
  TOP w0.203: PL901.2 163.33,44.69 163.91,45.27 167.25,45.27 167.48,45.04 168.3,45.04 168.72,44.63 PU900.14
  TOP w0.508: 162.08,40.9 162.33,40.65 162.33,38.81 163.11,38.03 163.42,38.03 164.17,37.29 v3(165.08,37.29) 165.98,38.19 PC901.1 PR902.1 167.69,38.11 PR906.1
+3.3V_ALW_DEG: length 3.6
  BOTTOM w0.254: RE76.2 168.52,66.06 v1(168.52,67.13) 168.68,67.29 169.39,67.29 169.65,67.55 JDEG1.1
+3.3V_PGPP: length 14.9
  TOP w0.305: v2(143.7,58.07) 143.7,58.2 144.37,58.87 CC268.1 144.37,59.75 v2(144.35,59.78)
  TOP w0.381: RC211.2 147.04,58.44 146.55,58.94 145.66,58.94 v1(145.41,59.18) 145.4,59.18 145.1,58.89 CC268.1 ; v2(143.03,61.4) CC265.1 v2(143.03,63.1) ; v2(144.36,61.51) 144.36,61.7 144.81,62.15 CC267.1
  IN4 w0.381: v2(144.44,57.28) 144.44,57.61 143.98,58.07 v2(143.7,58.07)
  BOTTOM w0.254: v2(143.03,61.4) 143.03,61.55 143.32,61.85 UCPU1.Y16 143.45,61.96 143.88,61.96 UCPU1.Y15 144.02,61.85 v2(144.36,61.51) 144.36,61.16 144.36,61.16 144.36,60.86 144.36,60.85 144.36,60.54 UCPU1.AD15 143.99,60.16 144.35,59.8 v2(144.35,59.78) ; v2(144.44,57.28) 143.99,56.83 UCPU1.AK15 ; v2(143.7,58.07) 143.99,58.36 UCPU1.AG15 ; UCPU1.T16 143.34,63.42 v2(143.03,63.1)
+3.3V_SPI: length 2.5
  TOP w0.254: RC213.2 144.63,58.25 144.26,57.89 ; 144.26,57.89 v2(143.63,57.26) ; 144.26,57.89 v3(144.26,57.89)
  BOTTOM w0.254: v2(143.63,57.26) 143.63,57.36 143.34,57.65 UCPU1.AJ16
+3.3VDX_SSD:
  vias: v2(176.74,26.2) v2(176.75,39.74) v2(176.76,26.91) v2(176.76,25.54) v2(176.95,37.1) v2(176.86,36.5) v2(176.88,24.22) v2(176.89,23.62) v2(177.36,36.14) v2(177.74,37.1) v2(177.82,36.52) v3(176.36,27.8) v3(177.48,40.41) v3(177.47,38.06)
+3V_LDO: length 54.9
  TOP w0.254: PC210.1 60.14,66.65 60.35,66.65 60.4,66.59 v2(60.82,66.59)
  TOP w0.381: v2(69.47,38.24) 67.78,38.24 v3(66.24,36.69) 64.48,34.93 PQ222.1
  IN3 w0.508: v2(60.82,66.59) 60.37,66.59 58.86,65.08 58.86,64.04 61.49,61.41 61.49,57.63 62.52,56.6 63.13,56.6 64.17,55.56 66.38,55.56 66.56,55.74 70.74,55.74 71.34,55.14 71.34,49.59 74.65,46.27 76.27,46.27 76.58,45.96 v2(76.58,45.73)
  IN4 w0.381: v2(76.58,45.73) 76.52,45.67 76.29,45.67 73.64,43.01 73.64,40.08 72.2,38.64 70.89,38.64 70.49,38.24 v2(69.47,38.24)
+3V_PCH: length 339.1
  TOP w0.254: CC223.1 141.79,58 141.22,57.43 R9.1 141.07,58.02 v2(141.12,58.07) ; RC23.2 156.24,65.39 156.23,65.39 156.08,65.24 156.08,65.24 155.7,64.86 RC12.2
  TOP w0.305: RC26.2 150.67,55.61 149.78,56.5 RH148.1
  TOP w0.356: v2(159.59,58.96) 158.9,58.28 v2(158.9,57.95) 159.12,57.73 159.12,56.48 158.35,55.71 158.35,52.07 158.03,51.76 157.41,51.76 157.23,51.57 157.23,50.55 v2(157.2,50.53)
  TOP w0.381: v2(64.19,75.24) 63.98,75.45 RC133.1 ; 155.93,50.53 v2(157.2,50.53) ; v2(141.09,62.26) 141.03,62.32 CC209.1 ; v2(157.44,63.15) 156.75,63.84 RC14.2 ; v2(146.51,57.49) 146.15,57.85 RC213.1 ; CC224.1 142.79,56.42 v2(142.6,56.23) ; RH148.1 149.78,56.83 149.37,57.24 148.68,57.24 148.44,57.49 RC211.1
  TOP w0.508: 155.93,50.53 155.6,50.86 152.34,50.86 151.39,51.82 RC183.1 151.39,53.09 RC186.1 150.67,53.81 RC184.1 RC26.2 ; v2(141.12,39.81) 141.53,40.22 141.53,42.75 140.54,43.75 RC187.1 142.55,44.74 RC74.1 ; v2(154.94,64.78) 155.06,64.9 155.63,64.9 RC12.2
  IN1 w0.254: v2(86.69,80.48) 86.11,80.48 82.99,77.36 79.89,77.36 78.07,79.18 72.69,79.18 72.39,79.48 72.39,79.69 72.14,79.94 70.9,79.94 69.52,78.56 69.52,77.5 68.88,76.87 68.34,76.87 67.77,76.3 67.24,76.3 66.74,75.8 64.75,75.8 v2(64.19,75.24)
  IN1 w0.381: v2(154.94,64.78) 156.11,65.95 156.11,68.58 156.81,69.27 158.22,69.27 158.73,69.78 158.73,70.84 159.27,71.38 159.27,72.19 158.36,73.1 158.36,74.26 157.95,74.67 156.14,74.67 154.14,76.67 153.16,76.67 v2(152.53,77.3) ; v2(158.9,57.95) 157.64,56.69 157.64,55.91 154.99,53.25 153.22,53.25 152.68,53.79 v2(152.68,54.57)
  IN1 w0.508: v2(187.68,54.09) 187.13,53.54 186.53,53.54 185.21,54.87 182.67,54.87 181.44,53.63 181.44,46.61 180.48,45.65 179.76,45.65 v2(179.56,45.85)
  IN2 w0.381: v2(159.59,58.96) 159.59,59.37 158.33,60.63 157.74,60.63 157.42,60.95 155.69,60.95 155.03,61.61 154.88,61.61 153.9,62.59 153.9,63.99 154.69,64.78 v2(154.94,64.78)
  IN2 w0.508: v2(154.76,44.1) 155.14,44.48 156.77,44.48 v2(159.72,41.54)
  IN3 w0.254: v2(196.18,76.91) 196.18,77.21 194.89,78.5 194.89,78.82 193.11,80.6 188.47,80.6 184.76,76.9 179.71,76.9 177.7,78.9 171.63,78.9 170.05,80.49 v2(154.65,80.49) 154.53,80.6 86.82,80.6 v2(86.69,80.48)
  IN3 w0.508: v2(181.41,26.24) 181.41,26.39 180.82,26.99 180.82,28.08 178.77,30.13 178.21,30.13 177.04,31.3 177.04,32.29 178.08,33.33 182.25,33.33 184,35.09 184.86,35.09 186.18,36.41 187.52,36.41 189.5,34.43 192.31,34.43 193.71,35.82 195.81,35.82 196.42,35.21 198.38,35.21 199.06,35.89 201.54,35.89 v2(201.55,35.9)
  BOTTOM w0.127: JSPI1.15 196.26,78.36 196.51,78.61 196.51,80.04 RC64.1
  BOTTOM w0.203: v2(141.09,62.26) 141.39,62.56 UCPU1.V19
  BOTTOM w0.254: RC318.1 158.33,55.95 158.04,56.24 158.04,57.08 v2(158.9,57.95) ; v2(142.6,56.23) 142.69,56.32 UCPU1.AK17 ; JAPS1.1 201.54,35.89 v2(201.55,35.9) ; JSPI1.15 196.26,76.99 v2(196.18,76.91) ; UCPU1.AJ21 139.44,57.66 v2(139,58.1)
  BOTTOM w0.305: RC283.1 156.87,58.43 158.42,58.43 v2(158.9,57.95) ; RH59.1 156.97,50.76 v2(157.2,50.53)
  BOTTOM w0.381: RC288.1 157.05,47.08 157.12,47.15 v2(157.38,47.15) ; v2(152.53,77.3) 152.53,77.43 154.65,79.55 v2(154.65,80.49) ; v2(157.44,63.15) 156.87,63.71 RC17.2 ; v2(141.12,39.81) 141.73,40.42 154.13,40.42 154.79,41.08 154.79,41.65 155.16,42.02 158.42,42.02 158.9,41.54 v2(159.72,41.54)
  BOTTOM w0.508: v2(152.53,77.3) 152.35,77.12 152.35,76.64 RC236.1 ; RH58.1 174.4,44.13 174.11,43.84 v2(174.11,43.83) ; v2(159.59,58.96) 159.36,58.96 158.9,59.42 RC284.1 RC285.1 ; v2(157.35,67.31) 156.82,66.77 RC13.1 ; U18.8 185.01,53.85 186.76,52.1 CC10.1 v2(187.68,54.09) ; RC188.2 RC185.2 RC189.2 ; RC73.2 153.09,44.61 153.6,44.1 v2(154.76,44.1) ; RC189.2 RC191.2 ; RC189.2 148.67,76.85 148.67,77.49 v2(148.81,77.62) ; RC17.2 RC15.2 RC25.2
  vias: v2(182.02,26.27) v3(178.03,45.17)
+3V_PCH_DSW: length 366.7
  TOP w0.305: v2(142.36,57.24) 142.36,57.21 142.52,57.36 142.52,59.29 142.35,59.46 v2(142.35,59.73)
  TOP w0.381: v2(151.6,42.13) 150.77,41.31 147.68,41.31 146.81,42.17 v1(146.81,42.86) 146.81,43.73 146.29,44.26 145.92,44.26 RC67.1
  TOP w0.457: RC214.2 158.85,45.09 158.47,45.47 158.19,45.47 155.09,48.57 150.62,48.57 150.24,48.95 148.84,48.95
  TOP w0.508: RC95.1 148.84,48.95 RC72.2 ; RC67.1 145.41,44.48 145.03,44.86 145.03,46.31 RC243.2 ; v2(68.37,77.92) 68.87,77.92 69.7,77.1 RC241.1 ; v2(156.08,43) 156.74,43 CC280.1 CC279.1 158.85,43.9 RC214.2
  IN1 w0.457: v2(68.37,77.92) 68.37,79.77 67.84,80.3 57.3,80.3 55.89,78.89 ; v2(23.85,71.13) 22.8,71.13 21.36,69.69 17.73,69.69 15.29,67.25 15.29,64.13 15.65,63.77 16.79,63.77 17.44,64.42 18.38,64.42 18.72,64.08 20.22,64.08 20.68,63.62 20.68,61.6 18.92,59.84 18.92,58.64 18.35,58.64 17.23,57.53 17.23,55.75 16.7,55.22 16.7,54.38 18.05,53.03 21.91,53.03 22.4,52.53 22.4,38.95 20.96,37.5 19.94,37.5 v2(19.36,38.08)
  IN1 w0.508: v2(47.63,79.69) 47.63,79.39 48.13,78.89 55.89,78.89 ; v2(151.6,42.13) 152.04,42.58 155.66,42.58 v2(156.08,43)
  IN2 w0.381: v2(156.08,43) 154.93,43 149.56,48.37 149.56,51.98
  IN3 w0.457: v2(78.79,28.05) 77.47,28.05 76.56,28.97 76.56,30.85 72.07,35.34 66.17,35.34 64.92,36.59 63.11,36.59 62.65,36.13 62.65,31.94 60.52,29.8 46.36,29.8 45.82,29.27 45.82,26.48 44.27,24.93 37.69,24.93 35.54,27.09 35.54,32.43 34.76,33.21 34.76,36.93 33.1,38.59 32.37,38.59 31.61,39.35 29.87,39.35 29.55,39.68 28.34,39.68 26.16,37.5 19.94,37.5 v2(19.36,38.08)
  IN4 w0.457: v2(151.6,42.13) 151.99,42.53 153.33,42.53 154.55,41.31 154.55,40.62 157.77,37.4 158.78,37.4 159.39,36.79 159.39,34.28 160.21,33.46 160.98,33.46 161.39,33.04 161.39,31.71 160.99,31.31 160.99,25.35 162.03,24.32 v2(162.23,24.32) ; v2(47.63,79.69) 47.42,79.69 46.37,78.65 42.37,78.65 42.03,78.31 38.42,78.31 36.5,76.39 27.64,76.39 23.85,72.6 v2(23.85,71.13) ; v2(78.79,28.05) 78.79,27.72 79.25,27.26 82.6,27.26 83.44,26.42 91.75,26.42 92.56,25.61 92.99,25.61 93.96,24.65 v2(94.92,24.65)
  BOTTOM w0.254: UCPU1.AD18 142.32,59.88 142.32,59.75 v2(142.35,59.73) ; v2(142.36,57.24) 142.36,57.33 UCPU1.AJ17
  BOTTOM w0.305: v2(142.35,59.73) 142.35,59.83 UCPU1.AD17
  BOTTOM w0.457: v2(162.23,24.32) 162.23,24.22 162.82,23.63 162.82,18.96 161.54,17.69 135.87,17.69 135.43,18.12 134.24,18.12 132.27,20.09 126.28,20.09 124.49,18.3 118.59,18.3 117.93,17.64 115.29,17.64 112.96,19.97 97.64,19.97 94.92,22.69 v2(94.92,24.65)
+3V_TBT: length 19.5
  TOP w0.127: v2(37.25,56.46) 37.57,56.15 UT1.A2 ; v2(39.43,50.83) v3(42.65,50.83)
  TOP w0.203: UT1.H9 40.53,59.12 v2(40.53,59.12)
  TOP w0.254: v2(50.78,56.92) 50.76,56.92 50.76,57.1 50.39,57.46 RT21.1
  TOP w0.356: RT51.1 28.37,47.44 28.04,47.77 25.55,47.77 24.98,48.35 v2(24.98,48.6)
  TOP w0.381: v2(45.16,48.01) 45.16,47.89 45.44,47.61 RT114.2 ; RT46.2 32.51,58.56 v2(32.69,58.74) ; RT33.1 RT34.1 53.35,55.32 v2(53.38,55.34)
  IN1 w0.381: v2(53.38,55.34) 52.76,54.72 50.72,54.72 50.1,55.34 50.1,56.35 50.67,56.92 v2(50.78,56.92)
  IN4 w0.081: 41.38,53.41 41.35,53.39 41.35,53.23
  BOTTOM w0.381: v2(39.43,50.83) 39.43,51.38 39.27,51.54 RT26.1
  vias: v2(24.4,48.59)
+3V_TBT_PWR:
  vias: v1(45.36,48.83)
+3V_TBT_S0: length 1.1
  TOP w0.203: UT1.R13 v2(44.43,61.07)
  BOTTOM w0.127: v2(32.56,56.55) v1(31.88,56.55)
  vias: v2(24.24,52.1) v2(24.7,51.74)
+3V_VC: length 133.4
  TOP w0.203: v2(25.81,64.96) 25.81,64.77 U722.B1 ; U722.H1 22.51,64.6 22.31,64.79 22.31,65.38 22.24,65.45 22.24,65.8 21.83,66.21 v2(21.83,67.29)
  TOP w0.254: C1354.1 21.83,67.88 v2(21.83,67.29)
  TOP w0.305: v2(59.49,19.74) 60.35,18.88 61.39,18.88 61.81,18.46 PU203.8
  TOP w0.381: v2(63.36,35.98) 63.65,35.69 63.65,34.76 62.88,33.98 ; 62.88,33.98 61.23,33.98 60.96,33.71 ; 62.88,33.98 62.88,33.47 PQ222.3 ; v2(55.32,18.45) 55.47,18.6 56.01,18.6 PR260.1 ; PR275.2 57.13,36.86 57.13,38.31 PQ221.3 57.71,38.39 59.71,36.38 PC218.1
  TOP w0.508: PC218.1 62.96,36.38 v2(63.36,35.98) ; PR261.1 56.03,21.14 v2(54.92,22.26) ; PR278.2 60.96,33.71 ; v2(65.74,16.33) 65.59,16.47 PR259.1 ; PQ222.3 61.86,32.99 v2(61.41,32.53) ; PR257.1 PR255.1 64.29,23.66 64.87,23.07 v3(64.87,22.44) PR256.1 65.3,20.86 65.59,20.58 v2(65.59,19.88)
  IN1 w0.508: v2(25.81,64.96) 25.78,64.98 25.78,65.88 25.49,66.18 23.02,66.18 21.9,67.29 v2(21.83,67.29)
  IN2 w0.381: v2(31.62,47.91) 31.62,47.98 30.48,49.12 30.48,55.73 29.71,56.51 29.71,59.87 29.1,60.48 29.1,62.2 28.47,62.82 28.47,63.31 27.33,64.45 26.19,64.45 25.81,64.83 v2(25.81,64.96)
  IN3 w0.381: v2(61.41,32.53) 59.87,32.53 56.25,36.15 56.25,36.53 54.41,38.38 51.56,38.38 50.85,39.09 41.63,39.09 41.07,39.65 41.07,40.99 39.35,42.72 38.58,42.72 38.01,43.29 36.61,43.29 35.43,44.47 35.43,44.72 32.24,47.91 v2(31.62,47.91)
  IN3 w0.508: v2(63.36,35.98) 64.61,34.73 71.81,34.73 75.05,31.5 75.05,28.31 69.6,22.86 68.01,22.86 65.59,20.44 v2(65.59,19.88)
  IN4 w0.508: v2(59.49,19.74) 59.49,19.85 57.07,22.26 v2(54.92,22.26)
+3VA_TBT: length 51.6
  TOP w0.254: v2(39.88,58.47) 40.2,58.79 UT1.F8 ; RT113.1 RT46.1 33.43,58.4 33.94,58.91 35.03,58.91 35.26,58.68 CT57.1
  TOP w0.381: v2(35.8,58.4) 35.73,58.48 CT57.1
  IN2 w0.508: v2(35.8,58.4) 35.64,58.4 35.13,57.9 35.13,54.24 36.28,53.08 36.93,53.08 37.9,52.12 37.9,51.1 38.87,50.12 39.69,50.12 v2(39.73,50.08)
  IN3 w0.508: v2(46.52,51.86) 46.47,51.86 45.89,52.45 44.45,52.45 v2(43.87,51.86) 43.64,51.86 43.21,51.43 43.12,51.43 42.75,51.06 40.91,51.06 v2(40.11,51.86) 40.04,51.79 40.04,50.39 v2(39.73,50.08)
  BOTTOM w0.254: RT35.1 RT36.1 44.12,52.12 v2(43.87,51.86) ; v2(46.52,51.86) 46.52,51.98 46.53,52 RT23.1 RT22.1 ; v2(40.11,51.86) 40.3,52.05 RT47.1
  BOTTOM w0.305: v2(39.73,50.08) 38.97,50.08 38,51.05 38,51.71 38.09,51.79 RT25.1
  BOTTOM w0.508: 36.55,57.2 36.61,57.13 36.6,57.12 36.6,55.11 v3(35.92,54.43) 34.65,53.16 34.65,50.09 33.6,49.04 31.75,49.04 30.58,50.21 30.58,51.55 29.74,52.38 28.53,52.38 QT19.2 27.89,51.74 R1462.1
+3VA_TBT_LC: length 23.6
  TOP w0.127: v2(44.42,57.83) UT1.R6
  IN2 w0.457: 49.01,69.19 v2(49.01,68.69)
  IN2 w0.508: v2(51.71,73.43) 51.47,73.43 50.24,72.2 50.24,70.42 49.01,69.19
  IN3 w0.203: v2(49.01,68.69) 49.01,68.53 45.63,65.15 45.26,65.15 43.7,63.59 43.7,62.94 43.32,62.56 43.32,62.17 43.65,61.85 43.65,59.25 44.42,58.48 v2(44.42,57.83)
  BOTTOM w0.127: v2(44.42,57.83) 44.42,57.16 45,56.59 CT150.1 ; v2(49.01,68.69) v1(49.58,68.69)
  BOTTOM w0.381: CT50.1 CT179.1 45.01,56.47 CT150.1
+3VALW: length 387.3
  TOP w0.102: v3(52.65,39.79) 53.29,39.15 54.05,39.15 54.45,39.55 v2(54.46,39.55) ; v3(183.66,32.96) 183.06,33.56 C1162.1
  TOP w0.127: v2(95.12,25.46) 94.41,24.75 93.36,24.75 93.02,25.09 89.46,25.09 88.77,25.77 84.65,25.77 84.05,26.37 84.05,27.72 83.81,27.96 83.2,27.96 82.37,27.14 82.37,26.49 80.73,24.85 79.6,24.85 78.75,25.71 v2(78.75,26.39)
  TOP w0.254: v2(163.97,65.07) 163.85,64.94 PU400.8 163.85,63.85 164.31,63.38 v2(164.31,62.31) ; PJP15.1 170.36,62.72 170.62,62.46 170.62,60.95 PR404.1 PR403.1 168.44,59.66 168.44,59.63 167.87,59.06 v2(167.59,59.06) ; PU600.13 171.31,29.97 171.98,29.3 172.11,29.3 PC606.1 172.24,28.66 v2(171.86,28.66) ; PU401.5 171.8,58.27 172.26,58.73 173.94,58.73 PU402.5 175.25,58.27 PC405.1 175.9,57.84 175.9,57.1 175.62,56.82 175.62,55.38 175.36,55.12 174.24,55.12 173.84,54.72 PR1423.1
  TOP w0.305: v2(86.86,71.75) 86.6,72.01 PU201.8 85.18,72.01 PR254.1 ; UC9.5 166.28,69.91 167.85,68.33 169.64,68.33 v3(169.85,68.54) 170.05,68.54 170.82,67.78 170.82,66.94 170.41,66.53 ; v2(88.13,69.11) 87.93,69.3 86.11,69.3 85.7,68.89 PR252.1
  TOP w0.381: v2(28.04,53.02) 27.97,53.02 27.74,52.79 C1289.1 27.32,52.88 U699.5 ; v2(45.92,21.27) 45.92,21.22 45.95,21.19 C375.1 ; v2(31.93,57.06) 32.08,57.21 RT113.2 ; QH8.5 7.48,8.4 v2(8.01,7.87) 8.31,7.87 8.84,8.4 QH8.2 ; v2(8.34,10.83) 8.36,10.82 QH9.2 ; v2(66.98,19.92) 66.54,19.92 66.02,19.4 PR100.1 ; PR224.1 92.87,73.62 v2(93.02,73.77) ; PU402.5 173.49,58.27 v2(173.07,57.85) ; QH9.5 7.15,10.82 6.83,10.82 v2(6.44,10.42) ; v2(204.03,55.24) 204.05,55.27 UC8.5 ; v2(200.7,55.11) 200.7,55.11 200.7,55.11 199.67,55.11 199.51,55.27 UC13.5
  TOP w0.406: v2(51.88,42.07) 52.34,42.53 UC11.5 CZ91.1
  TOP w0.508: C1322.1 v2(195.94,14.08) ; PR708.1 203.14,62.34 PC713.1 202.73,62.25 v2(202.34,62.65) ; v2(86.03,75.54) 87.39,75.54 PR226.1 ; v2(156.07,43.67) 155.93,43.8 CC271.1 157.2,44.41 RC214.1 ; PR253.1 92.25,69.5 v2(92.41,69.66) ; PR1424.1 197.78,79.87 v2(198.01,79.64) ; v2(204.06,68.79) PR1414.1 ; RE84.1 187.88,72.53 v2(187.48,72.53) ; PQ221.1 55.32,39.55 v2(54.46,39.55) ; PR1415.1 v2(204.57,72.98) ; Q41.2 v2(8.37,5.3)
  IN1 w0.381: v2(27.06,20.05) 27.39,19.72 35.47,19.72 38.14,17.05 38.61,17.05 38.8,17.24 v2(40.74,17.24)
  IN1 w0.508: v2(27.06,20.05) 26.14,19.12 23.53,19.12 22.61,18.2 19.24,18.2 16.33,15.29 14.25,15.29 13.77,15.77 13.77,18.22 11.01,20.98 6.81,20.98 6.1,20.27 5.04,20.27 4.01,19.24 4.01,13.47 5.77,11.72 7.85,11.72 8.34,11.22 v2(8.34,10.83) 6.85,10.83 v2(6.44,10.42) 6.44,9.44 v2(8.01,7.87) 8.37,7.51 v2(8.37,5.3) ; v2(202.34,62.65) 202.64,62.65 203.4,63.41 203.4,67.7 204.06,68.36 v2(204.06,68.79) 203.66,69.2 203.66,72.07 v2(204.57,72.98)
  IN2 w0.508: v2(49.82,48.38) 51.64,46.57 51.64,45.07 51.88,44.83 v2(51.88,42.07) ; 203.02,78.65 203.02,80.23 v2(203.12,80.32) ; 203.02,78.65 201.99,78.65 201.59,78.25 199.1,78.25 198.88,78.03 197.84,78.03 197.49,78.39 197.49,79.11 v2(198.01,79.64) 197.48,80.17 195,80.17 194.18,79.36 194.18,75.83 194.65,75.36 v2(194.65,74.05) ; 203.02,78.65 203.02,77 203.33,76.69 203.33,74.23 v2(204.57,72.98)
  IN3 w0.381: v2(59.03,29.22) 55.88,26.07 48.79,26.07 47.6,24.88 47.6,24.3 47.22,23.92 47.22,21.16 46.73,20.67 46.28,20.67 45.92,21.03 v2(45.92,21.27)
  IN3 w0.457: v2(86.86,71.75) 85.26,71.75 84.93,72.07 80.5,72.07 78.92,73.65 64.34,73.65 63.61,72.93 62.18,72.93 61.06,74.05 v2(61.06,74.76)
  IN3 w0.508: v2(169.9,66.58) 169.9,66.41 169.52,66.04 164.53,66.04 163.97,65.48 v2(163.97,65.07) ; v2(88.13,69.11) 88.13,68.83 88.47,68.49 91.24,68.49 v2(92.41,69.66) ; v2(167.59,59.06) 170.51,59.06 171.67,57.9 173.01,57.9 v2(173.07,57.85) ; v2(86.86,71.75) 87.38,72.27 90.88,72.27 91.51,72.9 92.15,72.9 v2(93.02,73.77)
  IN4 w0.508: v2(61.09,79.61) 61.1,79.6 61.1,77.39 61.1,77.39 61.1,75.97 61.06,75.93 v2(61.06,74.76) ; v2(194.65,74.05) 194.23,73.63 191.96,73.63 191.11,72.78 191.11,72.16 190.48,71.52 189.19,71.52 188.19,72.53 v2(187.48,72.53) ; 199.83,48.75 203.18,45.4 v2(203.18,40.6) ; 199.83,48.75 199.83,54.24 v2(200.7,55.11) 203.9,55.11 v2(204.03,55.24) 204.65,55.86 204.65,59.39 203.11,60.93 203.11,62.02 202.49,62.65 v2(202.34,62.65) ; 199.83,48.75 199.33,48.75 195.39,52.69 195.39,56.28 193.3,58.37 v2(193.08,58.37)
  IN4 w1.016: 38.66,76.31 36.09,73.75 34.74,73.75 33.48,72.49 32.66,72.49 32.29,72.86 29.57,72.86 28.7,71.99 27.76,71.99 26.63,70.86
  BOTTOM w0.254: PU700.15 202.18,62.91 202.34,62.76 v2(202.34,62.65) ; JAPS1.3 v2(201.54,34.89) ; v2(201.54,32.99) 201.44,32.89 200.76,32.89 JAPS1.7
  BOTTOM w0.305: JIO1.49 195.81,15.54 195.81,14.2 v2(195.94,14.08) ; v2(45.92,21.27) 45.92,21.22 45.92,21.21 JKB1.3 45.92,19.92 45.77,19.77 45.77,19.31
  BOTTOM w0.381: UC10.5 193.2,58.49 v2(193.08,58.37) ; v2(173.07,57.85) 173.07,57.85 173.08,57.85 173.08,58.3 PC402.1 ; 45.77,19.31 45.77,18.13 44.24,16.6 41.38,16.6 v2(40.74,17.24)
  BOTTOM w0.508: v2(86.86,71.75) 86.03,72.57 v2(86.03,75.54) ; PR411.1 163.3,61.29 163.3,61.64 163.64,61.98 163.99,61.98 164.31,62.31 v2(164.31,62.31) ; v2(93.02,73.77) 92.3,73.05 92.3,69.77 v2(92.41,69.66) ; v2(173.09,42.03) 171.77,42.03 171.04,42.77 169.63,42.77 169.16,43.24 167.34,43.24 166.85,42.75 160.33,42.75 159.79,43.29 158.06,43.29 157.69,43.67 v2(156.07,43.67) ; PC400.1 PC401.1 163.97,64.46 v2(163.97,65.07) ; PR410.1 v2(167.59,59.06)
  vias: v2(25.72,69.45) v2(26.1,69.92) v2(34.19,43.6) v2(34.82,44.28) v2(35.13,40.1) v2(35.33,40.75) v2(40.25,41.04) v2(40.27,40.46) v2(40.28,39.87) v2(41.05,77.3) v2(41.05,76.72) v2(57.25,77.05) v2(58.1,77.08) v2(58.9,77.05) v2(60.42,79.64) v2(73,16.98) v2(73.03,16.38) v2(73.64,16.98) v2(73.66,16.38) v2(74.27,16.98) v2(74.3,16.38) v2(75.29,16.39) v2(75.92,16.39) v2(76.56,16.39) v2(77.19,16.39) v2(78.21,17) v2(78.21,16.39) v2(78.84,17) v2(78.84,16.39) v2(79.53,16.98) v2(79.55,16.39) v2(168.55,15.76) v2(173.03,15.76) v2(173.61,15.76) v2(173.99,34.32) v2(174.03,15.32) v2(174.42,33.93) v2(176.84,34.18) v2(176.86,33.48) v2(177.49,46.57) v2(177.47,34.21) v2(178.09,34.21) v2(181.41,34.1) v2(182.02,34.15) v2(199.97,39.48) v2(200.38,39.91)
+3VALW_5085: length 162.2
  TOP w0.203: UE5.A52 180.36,57.82 180.36,57.46 179.85,56.95 179.45,56.95 179.15,56.65 179.15,56.12 179.48,55.79 CE41.1
  TOP w0.254: UE5.A11 188.06,64.52 190.05,64.52 CE38.1 ; UE5.B3 187.21,60.27 186.53,60.27 v2(186.51,60.28) ; CE64.1 183.38,55.94 183.38,57.52 183.36,57.54 183.36,57.82 UE5.A58 ; CE63.1 184.32,70.63 184.32,70.07 183.86,69.61 183.86,68.72 UE5.A22 ; v2(174.98,64.08) 174.99,64.07 175.1,64.07 175.56,63.61 175.56,63.48 176.16,62.88 176.78,62.88 176.91,63.02 UE5.A41 ; RE69.1 177.65,71.54 177.85,71.54 v2(178.18,71.87) ; v2(169,63.48) 169.09,63.48 PJP15.2 169.44,62.09 CE46.1 ; UE5.A26 181.86,68.72 181.86,69.68 181.32,70.21 v2(181.2,70.21)
  TOP w0.305: RE69.1 176.89,70.95 176.53,70.6 176.53,69.22 176.96,68.8 176.96,68.04 177.72,67.27 UE5.B35 ; v2(172.11,59.24) 172.16,59.29 173.15,59.29 RE55.2 ; v2(192.19,63.63) 192.09,63.53 191.02,63.53 190.48,64.08 CE38.1
  TOP w0.381: v2(182.93,56.71) 182.35,56.13 CE17.1 CE64.1 ; CE41.1 179.68,56.46 v2(179.65,56.49)
  TOP w0.508: CE14.1 CE63.1 184,70.54 v2(183.74,70.29) ; v2(171.59,63.55) 172.18,62.96 CE72.1 RE3.1 ; v2(181.2,70.21) CE40.1 ; v2(192.19,78.71) 192.19,78.52 191.68,78.01 189.89,78.01 188.9,77.02 v1(186.13,77.02) 184.98,75.88 184.71,75.88 v2(184.18,75.35) 184.13,75.29 RE25.1
  IN1 w0.381: v2(186.51,60.28) 186.72,60.28 187.1,59.9 187.1,59.17 186.64,58.71 185.32,58.71 183.61,57 183.22,57 v2(182.93,56.71)
  IN2 w0.381: 173.79,63.41 173.79,63.05 174.63,62.21 176.43,62.21 176.81,61.83 176.81,61.29 176.43,60.91 v2(176.21,60.91)
  IN2 w0.508: v2(179.65,56.49) 179.64,56.5 179.64,56.86 180.42,57.64 181.13,57.64 181.61,57.16 181.61,56.85 181.98,56.49 182.72,56.49 182.93,56.7 v2(182.93,56.71)
  IN3 w0.381: v2(186.51,60.28) 190.41,60.28 191.34,61.22 v2(192.24,61.22)
  IN3 w0.508: v2(174.98,64.08) 174.97,64.07 174.92,64.07 174.91,64.06 174.46,64.06 173.18,62.78 173.18,59.9 172.53,59.24 v2(172.11,59.24)
  IN4 w0.508: v2(192.19,78.71) 192.19,78.37 192.96,77.6 199.06,77.6 199.52,78.06 202.94,78.06 v2(203.66,77.34) 203.66,75.72 202.26,74.32 202.26,72.97 200.87,71.58 200.87,69.43 197.61,66.18 197.61,63.8 196.63,62.82 193.19,62.82 ; v2(192.19,63.63) 192.19,63.57 192.93,62.82 193.19,62.82 ; 193.19,62.82 192.81,62.44 192.81,61.82 192.24,61.24 v2(192.24,61.22) ; v2(184.18,75.35) 181.84,75.35 178.36,71.87 v2(178.18,71.87)
  BOTTOM w0.254: v2(203.66,77.34) 203.66,77.28 203.39,77.01 RE93.2 ; v2(179.65,56.49) 179.65,57.23 RE52.1
  BOTTOM w0.356: RE88.2 CE71.2 ; RE88.2 176.75,60.37 v2(176.21,60.91) 176.47,60.91 176.78,61.22 176.78,61.95 177.05,62.21 RE87.2 CE70.2 178.14,62.21 178.78,61.58 180.95,61.58 182.12,60.4 182.63,60.4 182.98,60.05 RE53.1 ; RE88.2 177.31,60.04 176.91,59.65 RE56.2
  BOTTOM w0.381: v2(174.98,64.08) 174.98,64.12 175.29,64.43 RE74.1 174.07,64.96 RE75.1 ; RE76.1 168.89,64.15 168.97,64.07 168.97,63.51 v2(169,63.48) ; RE53.1 182.98,56.85 182.93,56.8 v2(182.93,56.71) ; RE79.1 190.89,64.09 191.35,63.63 v2(192.19,63.63) 192.19,63.8 191.59,64.39 191.59,67.53 191.11,68.02 191.11,68.17 189.68,68.17 189.68,68.17 189.66,68.17 188.98,68.86 186.46,68.86 RE102.1 ; v2(172.11,59.24) 172.47,59.24 172.72,59.5 172.72,60.18 RE65.1
  BOTTOM w0.508: v2(186.51,60.28) 186.59,60.36 CE43.1 187.18,60.35 188.09,60.35 ; RE72.1 RE75.1 ; RE81.1 189.44,58.41 189.44,59.9 188.98,60.35 188.09,60.35 ; 188.09,60.35 RE73.2 188.09,62.17 RE86.2
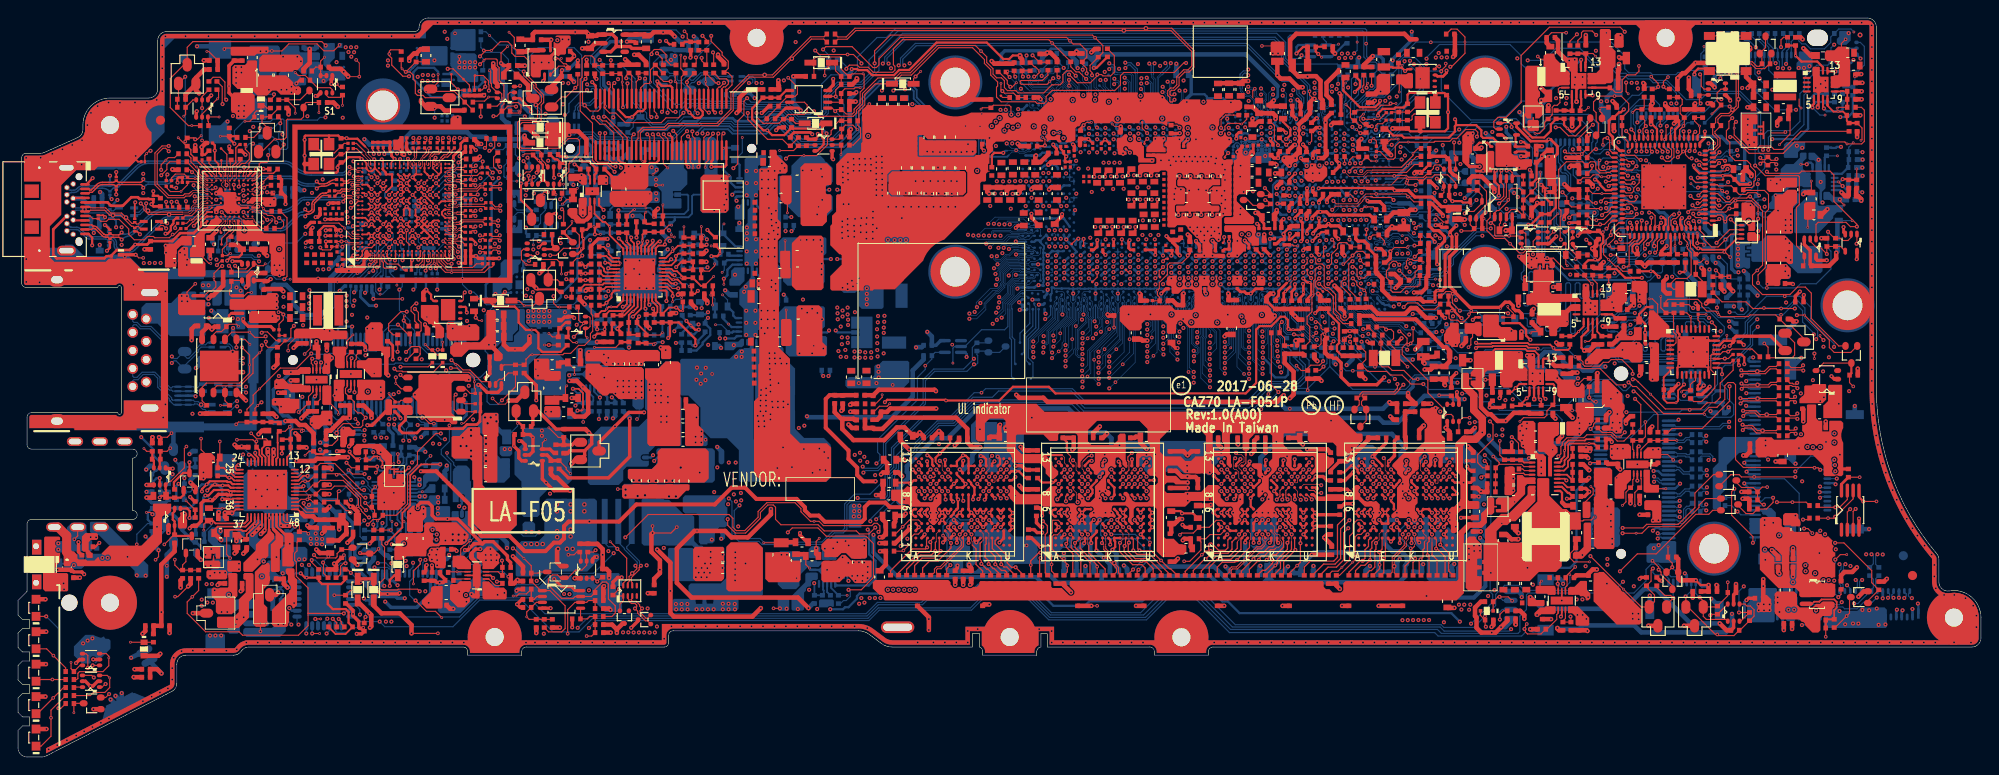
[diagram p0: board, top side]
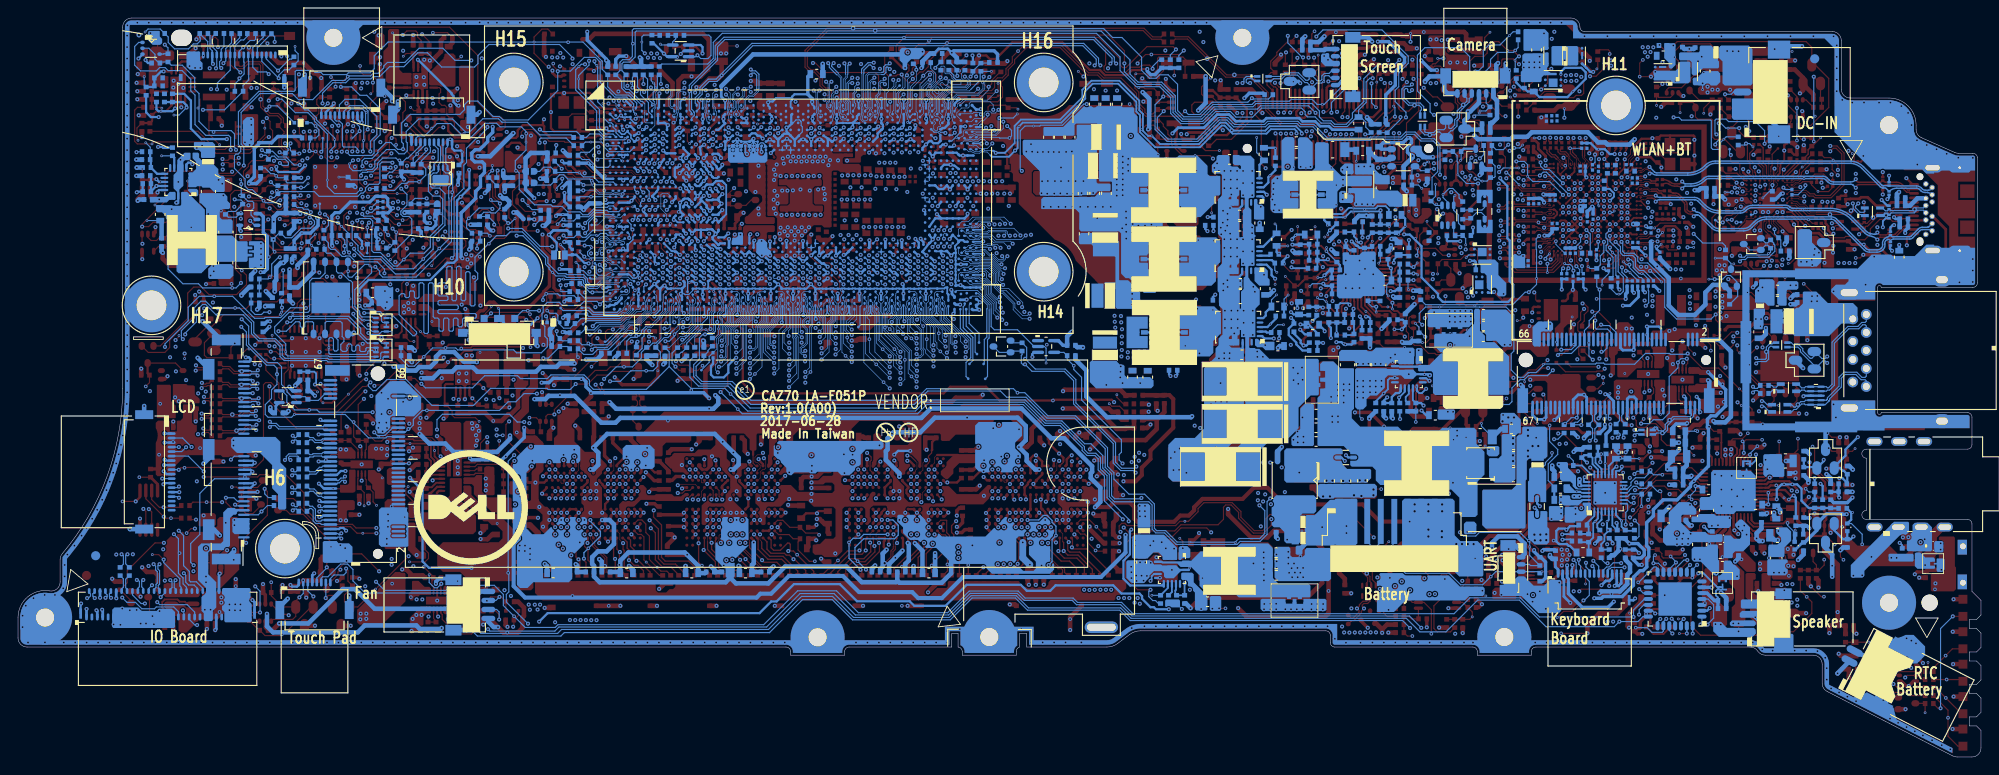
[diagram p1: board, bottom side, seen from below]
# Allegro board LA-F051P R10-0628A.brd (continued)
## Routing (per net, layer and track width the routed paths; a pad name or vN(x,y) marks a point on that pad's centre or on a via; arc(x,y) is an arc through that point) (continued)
+3VALW_23017: length 24.2
  TOP w0.203: RE13.1 35.23,13.65 36.34,13.65 RE14.1
  TOP w0.254: 34.37,19.19 35.84,19.19 36.3,19.64 RE24.1 ; 34.37,19.19 34.37,16.96 34.93,16.41 36.36,16.41 36.68,16.09 36.68,14.88 RE14.1 ; 34.37,19.19 33.73,19.19 33.38,19.54 RE27.1 v3(32.03,19.9) 31.85,19.9 v2(31.37,20.38)
  BOTTOM w0.203: CE3.1 29.19,17.7 29.41,17.93 29.41,18.42 28.98,18.86 ; 28.98,18.86 29.26,18.86 30.79,20.38 v2(31.37,20.38) ; 28.98,18.86 PJP14.2
  BOTTOM w0.381: CE10.1 CE3.1 29.58,17.36 30.4,18.18 30.96,18.18 UE4.5
+3VALW_TPM: length 3
  TOP w0.127: v1(180.98,50.83) 181.36,50.83 181.94,50.25 181.94,48.5
+3VALWP: length 12.7
  IN1 w0.203: v2(88.34,19.29) 88.09,19.03 80.12,19.03 v2(79.57,19.59)
  BOTTOM w0.203: PU500.14 89.33,18.56 89.4,18.48 89.4,18.09 PR504.2 PR502.1 88.37,19.26 v2(88.34,19.29)
  vias: v2(79.59,22.71) v2(79.59,22.11) v2(79.58,21.53) v2(79.57,20.84) v2(79.57,20.2) v3(80.72,21.47)
+3VLP: length 225
  TOP w0.254: v2(184.38,53.76) 184.44,53.81 184.87,53.81 v1(184.99,53.93) 185.01,53.96 RE57.2
  TOP w0.508: v2(15.79,11.45) 15.57,11.23 D122.2
  IN1 w0.254: v2(159.99,15.02) 160.69,14.31 161.48,14.31 162.9,15.73 164.63,15.73 165.19,15.17 166.59,15.17 166.97,14.8 167.85,14.8 168.1,14.55 170.23,14.55 170.47,14.8 175.82,14.8 180.48,19.46 180.48,20.35 180.09,20.74 180.09,25.13 175.95,29.27 175.95,34.89 175.68,35.16 175.68,40.31 176.48,41.11 176.48,42.92 176.68,43.12 176.68,43.88 177.15,44.35 180.73,44.35 182.55,46.17 182.55,48.14 184.38,49.97 v2(184.38,53.76) ; v2(15.79,11.45) 18.49,14.16 26.95,14.16 27,14.21 29.85,14.21 30.14,13.91 31.12,13.91 31.42,14.21 37.98,14.21 38.53,13.65 39.16,13.65 39.65,14.14 39.65,14.82 39.64,14.82 39.64,15.22 39.65,15.22 39.65,15.33 39.84,15.52 41.66,15.52 42.38,14.81 44.26,14.81 44.51,14.56 49.86,14.56 50.86,15.56 54.17,15.56 54.5,15.24 58.47,15.24 58.82,15.59 65.94,15.59 66.15,15.8 70.16,15.8 71.88,17.53 85.42,17.53 v2(86.53,16.42) 87.13,17.02 89.5,17.02 v2(90.12,16.39)
  BOTTOM w0.254: v2(90.12,16.39) 91.54,16.39 91.77,16.62 92.15,16.62 93.09,17.56 93.09,17.85 93.38,18.14 95.38,18.14 96.28,19.04 102.68,19.04 103.28,18.44 105.88,18.44 106.54,19.1 112.55,19.1 114.88,16.77 118.36,16.77 118.87,17.28 124.72,17.28 126.62,19.18 131.71,19.18 133.64,17.26 134.24,17.26 135.53,15.96 159.04,15.96 v2(159.99,15.02)
+3VS: length 645.1
  TOP w0.254: v2(159.16,61.68) 160.17,61.68 160.33,61.53 160.99,61.53 UC7.5
  TOP w0.305: QC2.2 158.8,63.27 RN20.1 158.8,62.04 v2(159.16,61.68)
  TOP w0.356: RC280.2 156.59,58.91 157.1,58.4 157.64,58.4 158.29,57.76 158.29,57.25 157.43,56.39 157.43,54.72 v2(157.47,54.68)
  TOP w0.381: v2(60.36,76.22) 60.3,76.16 C1204.1 ; R1141.2 54.66,21.58 54.31,21.93 54.31,22.31 52.72,23.9 51.78,23.9 51.54,23.65 ; 156.84,48.74 v2(157.33,48.74) ; v2(158.12,60.03) 158.12,60.17 156.86,61.43 RC280.2 ; v2(159.87,64.18) 159.51,64.54 159.37,64.54 159.27,64.64 159.25,64.64 158.87,65.02 158.87,65.23 QC2.5 158.87,65.23 158.87,66.16 RN19.1 158.37,66.66 156.98,66.66 156.95,66.63 RC176.2 RC177.2 ; PR905.2 164.49,39.98 164.39,39.89 v2(164.39,39.81) ; 51.54,23.65 48.78,26.41 v3(47.65,26.41) 46.36,26.41 45.95,26.82 45.95,27.8 45.52,28.23 44.68,28.23 44.35,27.9 v2(44.35,27.62) ; 51.54,23.65 50.58,23.65 49.89,22.96 v2(49.58,22.96) ; PR601.2 PR600.2 176.63,35.26 176.84,35.06 v2(176.84,34.96) ; C377.1 45.24,20.66 45.24,21.19 v2(45.34,21.29) ; v2(62.12,77.3) R1179.2
  TOP w0.457: v2(36.73,34.46) 37.06,34.79 R81.1
  TOP w0.508: 171.43,14.06 170.99,14.06 170.81,14.24 v2(170.81,14.31) ; v2(62.99,51.75) 63.14,51.9 PR1095.1 ; v2(204.04,21.04) 203.53,20.53 202.67,20.53 202.29,20.15 RC190.1 ; RC225.1 145.89,78.3 v2(146.14,78.05) ; v2(41.08,42.35) 40.87,42.56 40.87,44.41 41,44.54 ; C1204.1 60.2,75.41 59.2,74.41 QZ9.3 ; 169.77,71.71 169.77,72.24 v2(169.83,72.3) ; RC49.1 RC237.1 149.53,49.87 RC50.1 150.14,49.92 150.88,49.18 153.92,49.18 154.56,49.82 155.14,49.82 156.23,48.74 156.84,48.74 ; R884.2 163.7,14.64 v2(163.5,14.44) ; v2(176.58,38.26) 176.2,37.88 RC59.1 ; v2(185.39,75.38) 185.39,74.13 185.65,73.87 RE83.1 ; C1324.1 195.3,20.48 v2(195.43,20.35) ; R1103.2 166.68,16.21 167.14,15.75 v2(167.14,15.33) ; v2(150.32,77.78) 149.33,76.78 RC178.2 RC175.2
  IN1 w0.381: v2(185.39,75.38) 185.39,75.46 184.95,75.91 176.08,75.91 175.8,76.19 171.5,76.19 169.83,74.51 v2(169.83,72.3) ; 167.41,66.52 167.17,66.28 167.17,65.16 165.85,63.84 163.52,63.84 163.1,63.42 163.1,61.45 163.37,61.18 163.37,60.19 162.99,59.81 162.57,59.81 157.47,54.72 v2(157.47,54.68) ; v2(150.32,77.78) 150.18,77.63 150.18,76.18 152.75,73.6 152.75,73.52 v2(152.99,73.29) ; v2(196.19,50.43) 196.19,49.13 192.54,45.48 v2(192.54,44.35) ; v2(149.07,46.08) 149.07,45.93 150.78,44.23 v2(151.61,44.23)
  IN1 w0.406: v2(169.83,72.3) 169.83,71.45 168.87,70.49 168.87,69 167.41,67.54 167.41,66.52
  IN1 w0.457: v2(41.08,42.35) 40.89,42.16 40.16,42.16 39.51,41.51 39.51,39.4 38.86,38.76 36.79,38.76 36.14,38.11 36.14,35.54 36.73,34.96 v2(36.73,34.46)
  IN1 w0.508: v2(66.93,79.38) 65.61,78.06 62.88,78.06 v2(62.12,77.3) ; v2(176.84,34.96) 178.1,34.96 179.17,36.03 179.17,39.05 178.82,39.4 178.82,39.85 v2(178.6,40.06) 178.38,40.06 v2(176.58,38.26)
  IN2 w0.381: v2(157.47,54.68) 157.13,54.68 155.33,52.88 154.41,52.88 153.38,51.85 153.38,51.31 154.28,50.41 155.19,50.41 156.86,48.74 v2(157.33,48.74) ; v2(179.68,70.42) 178.31,70.42 177.28,71.45 177.28,72.21 177.55,72.48 177.55,73.02 177.16,73.41 175.53,73.41 174.04,71.92 170.21,71.92 169.83,72.3 v2(169.83,72.3) ; v2(124.27,76.89) 124.25,76.92 124.25,77.62 121.34,80.53 91.57,80.53 91.06,80.02 88.24,80.02 86.66,78.44 85,78.44 83.89,77.34 80.72,77.34 78.61,79.44 76.18,79.44 75.84,79.1 72.33,79.1 71.89,78.66 70.1,78.66 68.59,80.17 67.41,80.17 66.93,79.69 v2(66.93,79.38) ; 145.11,77.02 145.11,77.48 145.47,77.83 145.92,77.83 v2(146.14,78.05) ; 145.11,77.02 145.12,77.01 149.7,77.01 150.32,77.64 v2(150.32,77.78) ; 145.11,77.02 138.76,77.02 138.15,77.63 135.5,77.63 134.86,77 134.86,74.58 134.25,73.97 130.26,73.97 129.74,74.5 128.5,74.5 127.59,73.58 127.59,72.98 126.97,72.36 125.25,72.36 125.02,72.13 124.33,72.13 123.95,72.5 123.95,73.06 124.28,73.39 v2(124.56,73.39)
  IN2 w0.508: v2(44.35,27.62) 43.87,28.1 43.87,30.29 43.11,31.04 42.04,31.04 41.1,31.99 41.1,33.12 42.21,34.23 43.85,34.23 44.73,35.1 v2(44.73,35.49) 44.73,35.6 44.32,36.01 43.99,36.01 43.06,36.94 43.06,40.59 42.32,41.33 41.85,41.33 41.08,42.1 v2(41.08,42.35) ; v2(178.6,40.06) 178.6,39.7 179.86,38.44 183.22,38.44 v2(184.86,40.09) 185.1,39.84 185.1,34.98 186.42,33.66 188.44,33.66 188.92,33.19 188.92,28.24 193.19,23.98 193.19,22.59 v2(195.43,20.35) ; v2(163.5,14.44) 163.5,15.27 164.09,15.86 165.26,15.86 165.8,15.33 v2(167.14,15.33) 167.84,15.33 168.67,14.5 170.62,14.5 v2(170.81,14.31)
  IN3 w0.381: v2(62.99,51.75) 62.47,52.27 60.52,52.27 60.21,51.96 60.21,50.47 59.79,50.04 53.22,50.04 48.64,45.46 48.64,42.57 47.65,41.58 41.7,41.58 41.08,42.19 v2(41.08,42.35) ; v2(158.12,60.03) 159.16,61.07 v2(159.16,61.68) 159.16,61.91 158.91,62.15 158.91,62.69 159.87,63.65 v2(159.87,64.18) ; v2(169.83,72.3) 169.83,72.33 169.22,71.71 167.72,71.71 167.28,72.14 166.41,72.14 165.35,71.08 160.62,71.08 157.46,74.25 153.95,74.25 v2(152.99,73.29)
  IN3 w0.508: v2(164.39,39.81) 164.39,40.01 164.7,40.32 166.92,40.32 167.02,40.42 170.97,40.42 171.05,40.34 173.54,40.34 174.18,40.98 176.72,40.98 177.64,40.06 v2(178.6,40.06) ; v2(147.42,43.49) 147.42,43.58 149.07,45.23 v2(149.07,46.08) ; v2(151.61,44.23) 152.69,44.23 153.11,44.65 153.11,45.51 153.41,45.81 154.4,45.81 v2(157.33,48.74) ; v2(204.04,21.04) 203.51,20.51 200.94,20.51 199.47,21.98 197.05,21.98 v2(195.43,20.35) 193.19,20.35 192.3,19.47 192.3,18.8 190.19,16.69 v2(190.19,15.87)
  IN4 w0.356: v2(45.34,21.29) 45.34,21.09 45.7,20.73 47.36,20.73 v2(49.58,22.96)
  IN4 w0.381: v2(62.99,51.75) 61.74,50.49 60.59,50.49 60.21,50.88 60.21,51.12 59.74,51.58 59.74,53.87 60.71,54.84 60.71,54.97 61.21,55.46 61.21,56.06 61.56,56.42 61.56,60.61 62.89,61.93 62.89,62.74 63.75,63.6 63.75,65.25 66.04,67.54 v2(66.04,70.98) ; v2(196.19,50.43) 194.39,52.22 194.39,54.96 192.08,57.28 192.08,58.06 191.05,59.09 191.05,65.85 191.84,66.64 191.84,67.24 190.93,68.14 190.93,68.61 188.2,71.34 185.57,71.34 185.06,71.85 185.06,72.92 187.31,75.17 187.31,76.23 186.84,76.7 185.71,76.7 185.39,76.38 185.39,75.38 v2(185.39,75.38) ; v2(124.56,73.39) 124.4,73.39 123.95,73.83 123.95,76.58 v2(124.27,76.89)
  IN4 w0.508: v2(62.99,51.75) 63.25,51.75 64.18,50.81 64.18,48.93 62.74,47.48 62.74,46.44 61.65,45.35 61.65,42.88 63.2,41.33 63.2,39.59 63.76,39.02 67.39,39.02 68.94,37.47 69.23,37.47 70.95,35.75 73.21,35.75 74.17,36.71 76.81,36.71 77.82,37.72 78.54,37.72 79.69,36.57 80.55,36.57 81.1,36.02 83.23,36.02 83.82,36.61 83.82,36.88 84.75,37.8 v2(87.54,37.8)
  BOTTOM w0.203: JKB1.4 45.42,20.86 45.34,20.94 v2(45.34,21.29)
  BOTTOM w0.254: JLPDE1.2 180.15,70.74 179.83,70.42 v2(179.68,70.42) 179.65,70.45 JLPDE1.1 ; UC12.5 145.8,77.71 v2(146.14,78.05) 147.28,79.19 RC291.1 ; v2(192.54,44.35) 192.19,44.35 192.02,44.17 192.02,43.97 192.11,43.87 JEDP.40
  BOTTOM w0.305: CS44.1 189.21,38.31 189.21,38.95 188.82,39.33 U683.5 ; v2(149.07,46.08) 149.2,45.96 RC245.1 ; RC292.1 156.82,60.18 157.96,60.18 v2(158.12,60.03) ; JIO1.50 195.51,18.41 195.51,20.27 v2(195.43,20.35)
  BOTTOM w0.381: v2(157.33,48.74) 157.1,48.97 RC246.1 156.73,48.3 RC272.1 ; RH440.2 RH441.2 ; v2(62.12,77.3) 61.04,76.22 v2(60.36,76.22) ; v2(66.93,79.38) 65.74,79.38 63.96,77.6 63.96,77.1 64.99,76.07 64.99,74.54 66.04,73.48 v2(66.04,70.98) ; RH563.1 48.69,19.49 48.31,19.87 48.31,21.63 48.84,22.16 RH562.1 49.58,22.8 v2(49.58,22.96) ; v2(184.86,40.09) 185.37,40.6 R220.1 ; v2(150.32,77.78) 151.12,77.78 151.49,77.41 RC277.1
  BOTTOM w0.457: RC47.1 45.19,35.95 v2(44.73,35.49)
  BOTTOM w0.483: RT241.1 24.32,46.47 23.86,46.92 v2(23.86,47.6)
  BOTTOM w0.508: RH441.2 159.16,63.97 159.38,64.18 v2(159.87,64.18) ; RE60.1 100.48,44.1 99.28,42.9 99.28,40 96.98,37.7 87.64,37.7 v2(87.54,37.8) ; v2(189.81,38.79) 189.81,38.44 189.56,38.19 CS44.1 ; RC63.1 62.27,51.75 v2(62.99,51.75) ; v2(170.81,14.31) 170.91,14.21 173.23,14.21 173.62,14.6 179.34,14.6 180.11,13.83 189.51,13.83 190.19,14.5 v2(190.19,15.87) ; RC27.1 151.18,44.69 151.59,44.28 151.61,44.28 v2(151.61,44.23) ; RC137.1 66.04,70.34 v2(66.04,70.98) ; RC16.1 RC21.1 148.06,44.13 v2(147.42,43.49) ; RC228.1 R220.1
  vias: v2(38.75,47.54) v2(39.34,47.55)
+3VS_AUDIO: length 270.1
  TOP w0.127: v2(18.87,18.93) 17.73,17.79 v3(17.42,17.79)
  TOP w0.381: v2(158.35,48.72) 158.27,48.72 157.99,49.01 157.99,49.08 RC9.1
  TOP w0.457: LA14.1 37.18,24.41 36.55,23.78 v2(36.55,23.78)
  TOP w0.508: RA37.1 14.9,35.45 v2(14.92,35.48) ; RA18.1 19.15,19.21 v2(18.87,18.93)
  IN1 w0.508: v2(14.92,35.48) 14.92,34.95 15.37,34.51 15.37,32.57 16.56,31.38 v2(17.14,31.38) ; v2(36.55,23.78) 36.55,23.78 36.14,23.78 35.03,24.9 35.03,25.89 35.56,26.42 35.56,32.24 34.73,33.07 34.73,36.04 33.73,37.04 v2(32.61,37.04)
  IN2 w0.381: v2(57.56,19.54) 58.03,19.07 59.91,19.07 60.12,19.28 62,19.28 63.88,21.17 64.46,21.17 65.51,22.21 v2(65.51,22.84) ; v2(161.07,37.04) 161.07,37.49 161.32,37.73 161.32,41.99 162.8,43.47 162.8,46.28 161.65,47.43 159.93,47.43 158.64,48.72 v2(158.35,48.72) ; v2(162.66,28.03) 163.53,27.16 163.53,21.54 161.8,19.81 158.44,19.81 156.49,17.87 132.31,17.87 131.34,18.84 126.81,18.84 125.3,17.33 118.61,17.33 116.94,19 108.26,19 106.89,19 106.23,18.34 103.39,18.34 99.16,22.57 99.16,23.72 98.86,24.02 98.86,24.04 v2(98.68,24.22)
  IN3 w0.508: v2(41.48,23.61) 41.48,23.44 40.72,22.69 40.72,20.91 39.58,19.77 38.41,19.77 ; v2(98.68,24.22) 97.48,25.42 97.48,34.23 96.37,35.34 90.86,35.34 89.68,36.52 87.49,36.52 v2(87.25,36.76) ; v2(36.55,23.78) 36.55,22.85 37.39,22.01 37.9,22.01 38.51,21.4 38.51,19.87 38.41,19.77 ; 38.41,19.77 30.84,19.77 30.46,20.15 30.46,21.17 28.93,22.69 27.03,22.69 25.25,20.91 25.25,20.66 24.43,19.84 19.78,19.84 v2(18.87,18.93) ; v2(19.03,33.61) 22.07,36.66 30.49,36.66 30.59,36.76 32.33,36.76 v2(32.61,37.04)
  IN4 w0.381: v2(41.48,23.61) 41.48,22.74 42.01,22.21 42.01,21.13 43.57,19.58 45.74,19.58 46.85,18.46 48.5,18.46 50.7,20.66 53.06,20.66 53.1,20.62 54.25,20.62 54.46,20.83 56.34,20.83 57.56,19.62 v2(57.56,19.54) ; v2(161.07,37.04) 161.07,36.17 162.54,34.71 163.24,34.71 164.3,33.65 164.3,29.66 v2(162.66,28.03)
  IN4 w0.508: v2(87.25,36.76) 86.84,37.17 85.29,37.17 83.5,35.38 79.54,35.38 74.05,29.89 71.9,29.89 65.51,23.5 v2(65.51,22.84) ; v2(17.14,31.38) 17.47,31.38 18.09,32 18.09,32.67 v2(19.03,33.61)
  BOTTOM w0.381: RA80.2 34.2,36.57 33.82,36.95 32.7,36.95 v2(32.61,37.04)
  BOTTOM w0.508: RA38.1 16.68,30.92 v2(17.14,31.38) ; RA19.1 19.36,33.94 v2(19.03,33.61)
+3VS_CAM: length 12.9
  TOP w0.127: v2(53.59,77) 53.59,78.1 v1(54.32,78.83)
  TOP w0.381: v2(53.59,77) 53.86,76.73 C1220.1 54.48,76.54 53.91,75.97 R2670.2
  BOTTOM w0.508: C1221.1 C4.1 54.33,70.38 54.21,70.38 53.7,70.89 53.7,72.82 54.1,73.22 JCAM.1 54.1,74.48 53.78,74.8 53.78,76.81 v2(53.59,77)
+3VS_CR: length 1.1
  TOP w0.508: C1325.1 v2(196.95,20.02)
  vias: v2(179.16,15.91) v2(179.17,15.33) v2(179.8,15.9) v2(179.83,15.27) v2(196.44,16.34) v2(196.95,19.39) v2(197.08,16.34) v3(176.3,19.24)
+3VS_NGFF: length 22.4
  TOP w0.102: C715.1 29.97,45.7 v3(29.97,45.09) ; v3(31.8,44.71) 32.44,45.35 32.44,46.67
  TOP w0.508: R80.1 32.79,35.91 31.86,36.84 31.23,36.84 30.79,37.28 v2(29.68,37.28)
  BOTTOM w0.508: v2(29.68,37.28) 29.53,37.13 28.39,37.13 27.75,37.76 27.75,45.01 29.03,46.29 30.99,46.29
  vias: v2(33.99,47.47) v2(34.58,47.28) v2(47.8,48.05) v2(48.24,47.54) v3(50.09,47.81)
+3VS_TP: length 100.4
  TOP w0.254: v2(187.58,19.08) 186.69,19.08 v3(186.17,19.6)
  TOP w0.381: QH7.2 190.36,15.07 190.36,14.35 R1105.2 ; R1104.2 190.36,17.98 190.36,16.97 QH7.5
  TOP w0.508: RE7.1 173.2,65.54 RE6.1 173.11,65.6 172.3,65.6 v2(172.14,65.44) ; v2(190.63,19.19) R1104.2 ; R1105.2 189.59,14.06 v2(188.82,14.82) ; v3(186.17,19.6) 184.44,19.6 184.22,19.83 Q40.2 184.22,21.96 R1299.1 ; C7.1 C1225.1 187.58,18.4 v2(187.58,19.08)
  IN1 w0.508: v2(172.14,65.44) 172.14,65.26 170.76,63.88 170.76,61.55 168.71,59.5 168.71,56.4 v2(168.1,55.79) ; v2(173.94,21.17) 173.94,20.7 171.84,18.6 168.68,18.6 v2(167.82,17.74)
  IN2 w0.508: v2(173.94,21.17) 172.92,22.19 172.92,32.57 169.92,35.58 169.92,37.77 171.31,39.16 171.31,40.51 170.18,41.64 170.18,42.76 171.3,43.88 171.3,55.23 170.16,56.37 168.68,56.37 v2(168.1,55.79)
  BOTTOM w0.254: v2(187.58,19.08) 187.4,18.91 186.84,18.91 186.66,19.09 JTP1.1
  BOTTOM w0.508: v2(167.82,17.74) 169.11,16.45 178.23,16.45 180.41,18.63 181.79,18.63 185.6,14.82 v2(188.82,14.82)
+3VS_TPM: length 20.9
  TOP w0.127: 189.61,46.19 v1(189.61,46.8)
  TOP w0.254: v2(189.92,45.62) 190.31,46.01 C96.1 190.18,46.19 189.28,46.19 188.79,45.69 U15.22 ; RH126.1 190.89,43.53 v2(190.96,43.47) ; v2(187.05,41.23) 186.63,40.81 C95.1 186.39,41.23 186.62,41.47 186.62,41.72 186.63,41.72 U15.14
  TOP w0.381: C96.1 190.31,46.1 190.39,46.17 190.39,46.43 190.65,46.69 194.48,46.69 Q72.3
  IN2 w0.508: v2(181.36,41.9) 181.82,42.35 186.69,42.35 187.05,42 v2(187.05,41.23)
  BOTTOM w0.508: v2(187.05,41.23) 186.54,41.74 RC229.1
+3VS_TS: length 17.8
  TOP w0.381: RH357.1 68.11,78.63 67.91,78.84 66.36,78.84 ; 66.36,78.84 66.37,78.85 66.37,79.76 65.94,80.2 65.01,80.2 U728.1 ; 66.36,78.84 65.78,78.26 U728.3
  TOP w0.508: R2671.2 55.79,79.59 C1208.1 57.13,80.22 57.35,80.45 v3(61.82,80.45) 63.06,80.45 C8.1 64.22,80.03 64.34,80.16 U728.1
+3VS_TSLDO: length 11.4
  TOP w0.508: v2(72.86,79.96) 72.39,80.43 v3(71.58,80.43) 70.54,80.43 70.14,80.03 RH357.2 69.56,80.17 C1223.1 68.54,80.16 U728.5
  BOTTOM w0.508: JTS.6 71.65,78.56 72.76,78.56 72.87,78.44 C5.1 C1222.1 73.48,79.33 v2(72.86,79.96)
+5V_USB_P2: length 1.7
  TOP w0.127: v3(19.67,52.51) 18.75,51.58 v2(18.75,51.14)
  vias: v2(18.16,51.16) v2(18.19,50.58) v2(18.8,50.56)
+5VALW: length 220.8
  TOP w0.076: 22.32,58.87 22.76,59.31 22.76,59.72 U722.H10
  TOP w0.127: 22.32,58.87 22.01,58.56 v2(22.01,58.33)
  TOP w0.203: v2(179.84,34.48) 179.76,34.48 179.68,34.4 179.68,33.5 U717.4 ; U720.4 36.93,41.48 36.93,40.8 v2(36.78,40.65) ; U719.4 51.93,20.15 52.43,20.15 52.61,19.96 52.61,19.95 52.63,19.93 52.61,19.91 52.61,19.89 52.64,19.92 52.67,19.92 v2(52.72,19.86) ; U664.4 33.12,42.9 33.12,43.7 v2(33.05,43.77) ; v2(171.2,15.58) 171.3,15.68 171.3,16.33 U716.4
  TOP w0.254: UZ19.3 166.28,67.19 167.23,67.19 CZ86.1 ; UZ23.3 49.61,49.95 49.73,49.83 49.73,49.39 v2(49.8,49.32) ; v2(167.81,46.29) 167.34,46.76 167.34,47.41 166.61,48.14 UZ22.3
  TOP w0.305: UZ26.3 58.42,75.17 v2(58.27,75.02) ; v2(158.51,76.16) 158.51,75.92 158.12,75.52 157.51,75.52 157.35,75.68 157.21,75.68 UZ25.3
  TOP w0.381: CZ86.1 167.31,66.66 v2(166.78,66.66)
  TOP w0.457: v2(22.01,58.33) 21.34,57.66 C1347.1
  TOP w0.508: PR1128.2 74.68,50.35 v2(75.22,49.81) ; LED10.2 v2(3.09,10.3) ; LED12.2 v2(3.04,17.5) ; LED14.2 v2(3.12,13.9) ; LED11.2 v2(3.04,6.7) ; v2(35.49,72.14) 35,72.62 PR105.2 ; PR1127.2 69.7,47.96 v2(70.1,47.56) ; v2(193.65,19.73) v3(193.65,18.96) C1321.1 ; LED13.2 v2(3.15,3.1)
  IN1 w0.508: 160.01,76.97 161.2,78.16 164.62,78.16 165.79,77 165.79,76.92 166.36,76.35 166.36,74.48 166.65,74.19 ; v2(166.9,43.82) 166.75,43.98 166.75,44.76 167.81,45.82 v2(167.81,46.29) ; 166.65,74.19 162.86,70.4 v2(162.86,69.23) ; 166.65,74.19 170.73,78.27 174.12,78.27 174.63,77.76 176.16,77.76 176.74,78.34 177.96,78.34 179.37,76.92 186.19,76.92 187.84,78.57 190.38,78.57 191.24,79.42 195.84,79.42 197.93,77.34 199.48,77.34 199.91,76.91 202.05,76.91 202.47,76.49 202.47,73.16 201.49,72.17 201.49,70.45 198.97,67.92 198.97,67.48 196.43,64.95 196.43,62.71 195.1,61.38 195.1,53.31 198.22,50.19 198.22,44.96 200.29,42.89 v2(200.29,42.79)
  IN2 w0.508: v2(179.84,34.48) 179.89,34.43 179.89,34.43 182.28,32.04 184.71,32.04 186.36,30.39 186.36,27.31 187.22,26.45 189.81,26.45 191.87,24.39 191.87,21.51 v2(193.65,19.73) ; v2(35.49,72.14) 35.04,71.69 35.04,70.97 38.37,67.64 41.39,67.64 v2(42.06,66.96)
  IN3 w0.508: v2(200.29,42.79) 200.29,41.45 197.59,38.74 195.73,38.74 192.05,35.06 189.76,35.06 187.71,37.12 185.7,37.12 185.29,36.71 184.2,36.71 182.52,35.04 181.1,35.04 180.49,34.43 179.89,34.43 v2(179.84,34.48)
  IN4 w0.508: v2(22.01,58.33) 22.39,57.95 24.02,57.95 v2(24.51,58.44) ; v2(176.13,43.32) 176.13,42.05 177.93,40.25 177.93,39.3 178.31,38.92 178.74,38.92 179.25,38.41 179.25,34.88 179.65,34.48 v2(179.84,34.48)
  BOTTOM w0.305: C376.1 47.22,21.09 46.92,20.79 JKB1.1
  BOTTOM w0.508: v2(176.13,43.32) 175.07,43.32 174.63,42.88 173.68,42.88 173.3,43.27 172.06,43.27 171.43,43.9 171.43,44.43 170.92,44.94 169.42,44.94 168.35,43.87 166.95,43.87 v2(166.9,43.82) ; v2(162.86,69.23) 162.86,69.22 165.42,66.66 v2(166.78,66.66) ; PR1080.2 65.47,56.47 v2(65.47,56.79) ; v2(47.83,22.41) 47.83,22.25 47.56,21.98 C376.1
  vias: v2(28.45,54.57) v2(28.73,54.01) v2(28.7,51.17) v2(28.7,50.51) v2(28.7,49.9) v2(29.03,54.57) v2(29.01,53.45) v2(29.31,54.01) v2(51.89,22.42) v2(51.92,21.83) v2(52.48,22.42) v2(52.5,21.84) v2(53.13,22.42) v2(53.09,21.83) v2(53.97,18.21) v2(56.61,49.48) v2(56.61,48.89) v2(56.61,48.31) v2(57.2,49.5) v2(57.2,48.9) v2(57.2,48.31) v2(57.78,49.5) v2(57.79,48.9) v2(57.79,48.29) v2(58.37,49.48) v2(58.37,48.85) v2(58.37,48.27) v2(58.97,49.5) v2(58.95,48.91) v2(58.95,48.29) v2(60.68,49.36) v2(67.13,13.83) v2(67.73,13.83) v2(68.31,13.81) v2(68.89,13.81) v2(69.48,13.81) v2(70.08,13.8) v2(70.66,13.82) v2(96.51,18.56) v2(97.1,18.56) v2(97.71,18.56) v2(98.33,18.55) v2(98.93,18.53) v2(99.51,18.56) v2(153.62,15.18) v2(154.21,15.18) v2(154.8,15.19) v2(155.39,15.19) v2(155.98,15.19) v2(156.57,15.2) v2(193.13,16.93) v2(193.15,16.27) v2(193.71,16.94) v2(193.74,16.27) v2(194.35,16.93) v2(194.35,16.3) v3(52.42,23.07) v3(53.21,17.99)
+5VALWP: length 23.4
  TOP w0.508: PC522.1 PC527.1 53.91,47.81 PC521.1 53.91,45.75 54.42,45.25 v1(55.14,45.25) 56.02,45.25 56.74,45.97 v2(56.74,46.69)
  IN1 w0.254: v2(56.74,46.69) 56.13,46.08 56.13,39.71 56.85,39 v2(61.85,39)
  BOTTOM w0.203: PR511.2 63.04,39.6 PU501.14
  BOTTOM w0.254: PR511.2 62.13,39.28 v2(61.85,39)
+5VS: length 265.2
  TOP w0.254: PU1305.6 63.97,64.6 64.16,64.79 PC1097.1 64.16,65.29 63.38,66.07 62.59,66.07 v2(62.43,66.23)
  TOP w0.508: C1102.2 165.25,15.11 v2(164.55,14.41) 163.94,13.8 v3(163.53,13.8) 162.37,13.8 161.84,14.33 161.84,15.48 161.67,15.65 161.67,16.58 162.32,17.23 R886.2
  IN1 w0.508: v2(79.43,45.7) 79.43,53.39 v2(79.55,53.51) ; v2(44.79,44.13) 44.31,44.13 43.8,44.64 43.8,47.99 45.18,49.37 45.47,49.37 49.26,53.16 53.01,53.16 54.3,54.45 59.33,54.45 v2(60.66,55.78) 60.79,55.9 60.79,56.34 61.09,56.65 61.09,59.28 61.47,59.66 61.47,62.45 61.01,62.91 61.01,64.11 62.43,65.52 v2(62.43,66.23)
  IN2 w0.508: v2(79.91,61.05) 79.91,61.05 79.91,60.08 79.4,59.57 79.4,53.67 v2(79.55,53.51)
  IN3 w0.508: v2(54.25,23.2) 54.28,23.17 54.28,21.98 54.69,21.57 54.69,17.82 ; v2(164.55,14.41) 164.52,14.37 164.52,14.36 163.91,13.75 159.68,13.75 158.9,14.53 158.9,15.14 158.43,15.6 157.88,15.6 156.59,14.31 133.43,14.31 131.4,16.34 125.3,16.34 125.12,16.16 100.5,16.16 99.83,16.84 95.19,16.84 94.69,16.34 92.69,16.34 91.8,17.23 80.19,17.23 78.08,19.34 68.94,19.34 67.09,17.49 62.22,17.49 61.85,17.12 60.14,17.12 59.49,17.77 54.74,17.77 54.69,17.82 ; 54.69,17.82 54.69,17.36 54.23,16.9 50.52,16.9 49.71,17.71 v2(49.71,17.97) ; v2(79.43,45.7) 78.27,44.54 71.36,44.54 66.24,49.66 66.24,51.95 63.17,55.03 61.42,55.03 v2(60.66,55.78)
  IN4 w0.508: v2(44.79,44.13) 44.93,43.99 44.93,42.93 43.19,41.2 43.19,40.19 41.14,38.13 40.95,38.13 40.51,37.7 40.51,36.64 41.12,36.03 41.15,36.03 41.5,35.67 41.5,35.65 41.51,35.64 41.51,31.95 42.06,31.41 42.06,30.13 43.38,28.81 43.38,27.05 44.5,25.93 51.53,25.93 v2(54.25,23.2) ; v2(49.71,17.97) 48.84,17.1 v2(45.57,17.1)
  BOTTOM w0.305: JKB1.2 46.42,19.8 46.28,19.65 46.28,17.81 v2(45.57,17.1)
  BOTTOM w0.508: v2(164.55,14.41) 165.03,14.41 165.62,15 JFAN1.4 ; v2(54.25,23.2) 54.25,23.76 53.54,24.47 51.44,24.47 50.65,23.68 50.65,22.55 JUART.1
+5VS_AUDIO:
  vias: v2(21.81,20.45) v2(22.4,20.45) v2(22.98,20.45) v2(32.28,27.97) v2(32.48,24.23) v2(32.51,23.64) v2(33.03,24.8) v2(33.14,24.21) v2(33.15,23.63) v2(33.74,24.19) v2(33.74,23.6) v2(45.66,22.44) v2(45.92,22.97) v2(45.92,21.92) v2(46.41,22.43) v2(46.53,23.02) v2(46.51,21.85) v2(46.51,21.27) v3(21.31,20.1)
+AVDD1: length 15.2
  TOP w0.203: v2(23.7,31.94) 24.16,31.48 UA2.26
  IN2 w0.508: v2(22.48,25.08) 21.46,25.08 18.28,28.26 18.28,29.18 18.87,29.78 19.38,29.78 19.81,30.2 19.81,31.75 20.27,32.22 21.06,32.22 21.34,31.94 v2(23.7,31.94)
  vias: v3(23.9,32.98)
+AVDD2: length 7.9
  TOP w0.203: UA2.40 26.66,25.98 25.38,24.7 CA80.1
  TOP w0.508: CA80.1 25.36,24.15 24.93,24.15 24.42,24.66 CA82.1 v2(24.23,23.96)
  BOTTOM w0.508: v2(24.23,23.96) 24.61,23.96 24.9,24.25 v3(24.9,24.25) 24.9,24.83 24.36,25.36 RA63.2
+DVDD: length 22.3
  TOP w0.203: 31.46,27.06 31.04,27.48 UA2.1
  TOP w0.508: CA5.1 36.43,25.9 36.43,24.85 ; CA5.1 35.9,26.32 CA31.1 CA42.1 CA4.1 32.74,26.7 31.82,26.7 31.46,27.06 ; CA5.1 35.94,26.37 35.64,26.07 v2(35.64,25.26) ; 36.43,24.85 LA14.2 ; 36.43,24.85 35.61,24.02 RA81.2 ; RA76.1 31.95,34.38 v2(32,34.32)
  IN3 w0.508: v2(35.64,25.26) 33.25,27.64 33.25,33.08 v2(32,34.32)
+DVDDIO: length 10.1
  TOP w0.203: v2(32.13,31.2) 31.65,31.2 31.13,30.68 UA2.9
  BOTTOM w0.127: v3(31.47,36.15) RA80.1
  BOTTOM w0.508: RA80.1 RA82.2 32.8,33.51 CA6.1 32.65,32.36 CA7.1 CA104.1 ; CA104.1 33.02,31.1 32.23,31.1 v2(32.13,31.2) ; CA104.1 CA105.1
+PVDD1: length 1.1
  TOP w0.203: v2(26.9,25.56) 27.06,25.72 UA2.41
  vias: v2(26.01,24.67) v2(26.47,25.12) v3(26.27,25.68)
+PVDD2:
  vias: v2(29.19,25.71) v2(29.86,25.64) v3(27.9,26.52)
+VBUS_DC_SS: length 139.9
  TOP w0.127: v2(43.66,13.72) v3(46.59,13.72)
  TOP w0.508: v2(43.66,13.72) 43.66,14.65 42.38,15.94 40.33,15.94 39.47,16.79 PD302.2 ; PR267.1 v2(60.12,14.36)
  IN2 w0.508: v2(28.95,42.27) 29.02,42.35 29.02,46.35 26.75,48.62 26.75,52.43 25.15,54.04 25.15,54.73 23.6,56.28 20.8,56.28 18.9,58.19 18.9,59.89 20.65,61.64 20.65,63.71 19.94,64.43 19.94,65.4 21.21,66.67 21.21,67.81 22.63,69.23 22.63,71.26 24.48,73.11 26.23,73.11 27.09,72.25 30.6,72.25 31.75,71.1 v2(32.11,71.1)
  IN4 w0.508: v2(60.12,14.36) 58.01,14.36 56.44,15.93 51.84,15.93 49.63,13.72 v2(43.66,13.72) 38.39,13.72 37.47,14.64 32.56,14.64 32.09,15.11 32.09,15.71 33.2,16.81 33.2,21.86 34.52,23.18 34.52,26.37 33.3,27.59 33.3,32.88 34.16,33.74 34.16,34.95 34.42,35.2 34.42,38.92 34.06,39.28 34.06,40.45 33.48,41.03 29.93,41.03 28.95,42.02 v2(28.95,42.27) ; v2(46.2,77.3) 45.54,77.96 42.88,77.96 41.76,76.84 41.76,75.78 41.52,75.54 39.14,75.54 36.46,72.86 35.1,72.86 33.85,71.6 32.6,71.6 v2(32.11,71.1)
+VCC0V9_CIO: length 4.7
  TOP w0.203: UT1.R12 UT1.R11 v2(44.43,59.77)
  TOP w0.254: v2(44.43,59.77) 44.11,59.45 ; 44.11,59.45 v2(44.43,59.12) 44.11,58.8 UT1.R8 ; 44.11,59.45 UT1.R9
  TOP w0.305: v2(48.88,54.85) 48.93,54.8 CT101.1
  TOP w0.356: CT101.1 CT102.1 CT103.1
+VCC0V9_DP: length 5
  TOP w0.203: 45.08,60.42 v2(45.08,60.42) ; 45.08,60.42 45.08,60.42 UT1.T11 ; 45.08,60.42 UT1.V11 ; UT1.V12 v2(45.09,61.06) 45.07,61.06 UT1.T12 ; UT1.M6 42.79,58.15 v2(42.48,58.46) 42.17,58.15 UT1.L6 ; UT1.L12 v2(41.83,60.42) 42.15,60.1 UT1.L11
  TOP w0.254: UT1.V13 v2(45.09,61.71) ; UT1.M8 42.79,58.8 v2(42.47,59.11) 42.16,58.8 UT1.L8
  vias: v3(49.1,59.32)
+VCC0V9_PCIE: length 6.5
  TOP w0.203: v2(42.48,63.67) 42.48,63.67 UT1.L19 ; v2(42.48,63.67) UT1.L18 ; v2(42.48,63.67) UT1.M18 v2(42.48,63.02) UT1.M16 v2(42.48,62.37) ; UT1.N18 v2(43.13,63.67) UT1.N19 ; UT1.M15 42.64,61.88 42.62,61.88 42.48,61.74 v2(42.48,61.72) UT1.M13
  BOTTOM w0.127: v2(42.82,66.86) 42.82,66 CT158.1 ; v1(42.39,61.15) 42.48,61.23 v2(42.48,61.72)
+VCC0V9_USB: length 2.4
  TOP w0.127: UT1.R16 44.1,62.69 v2(43.78,62.37) UT1.R15
  TOP w0.381: CT93.1 CT94.1 49.45,67.12 v2(49,66.66)
  vias: v3(46.13,65.62)
+VCC_CORE: length 27.2
  BOTTOM w0.127: UCPU1.K35 132.08,66.97 ; UCPU1.K35 132.39,67.36 ; UCPU1.K35 131.72,67.36 131.7,67.34 ; UCPU1.K35 132.08,67.69 ; 133.35,67.34 133.33,67.36 UCPU1.K33 ; 130.82,56.05 UCPU1.AM37 ; UCPU1.AM37 131.17,55.74 ; UCPU1.AM37 131.17,56.39 131.17,56.4 ; UCPU1.AM37 131.48,56.05 ; UCPU1.K33 132.69,67.36 ; UCPU1.K33 133,67.69 ; UCPU1.AL40 129.8,56.19 ; UCPU1.AL40 129.8,56.82 ; UCPU1.AL40 130.14,56.53 ; UCPU1.AL40 129.46,56.53 ; 129.02,56.99 UCPU1.AK40 ; UCPU1.AK40 129.34,56.61 ; UCPU1.AK40 129.34,57.41 ; UCPU1.J33 132.2,67.83 ; UCPU1.J33 132.54,68.13 ; UCPU1.J33 132.85,67.83 ; UCPU1.J33 132.54,67.5 ; 130.25,57.28 UCPU1.AK38 130.25,56.69 ; v2(130.7,68.54) 130.71,68.53 ; 134.06,67.83 UCPU1.J30 134.37,68.12 ; 131.17,57.34 131.17,57.33
  BOTTOM w0.203: UCPU1.A53 121.97,72.03 121.97,72.96 v2(122.04,73.02) ; v2(134.58,72.64) 134.57,72.63 134.57,72.26 134.4,72.09 UCPU1.A30 ; UCPU1.A34 132.08,72.15 132.08,72.74 131.92,72.9 131.92,73.1 ; UCPU1.G33 133,68.32 v2(132.49,68.6) 132.08,68.37 UCPU1.G35 ; UCPU1.G32 133.97,68.29 v2(134.39,68.52) 134.8,68.29 UCPU1.G30 ; UCPU1.A39 129.44,72.16 129.69,72.41 v2(129.69,72.68) ; UCPU1.A44 v2(126.97,73.17) ; UCPU1.A48 124.54,72.04 v2(124.54,72.8)
  BOTTOM w0.254: UCPU1.G37 130.92,68.54 v2(130.7,68.54) 130.5,68.54 UCPU1.G38 ; v2(134.58,72.64) 134.48,72.74 134.07,72.74 133.71,73.1 131.92,73.1 131.92,73.27 131.65,73.54 130.18,73.54 ; UCPU1.G40 129.09,68.54 v2(128.87,68.54) 128.67,68.54 UCPU1.G42
  BOTTOM w0.381: PC1237.1 130.18,75.5 130.18,73.54 129.69,73.06 v2(129.69,72.68)
  vias: v2(91.43,58.19) v2(91.53,65.52) v2(91.53,64.89) v2(91.53,64.31) v2(91.53,63.72) v2(91.45,59.44) v2(91.45,58.81) v2(91.45,57.58) v2(91.49,52.07) v2(91.59,61.35) v2(92.04,52.5) v2(92.09,66) v2(92.09,65.37) v2(92.09,64.73) v2(92.1,64.05) v2(92.05,59.71) v2(92.05,59.08) v2(92.08,58.4) v2(92.11,57.78) v2(92.06,51.9) v2(92.18,61.35) v2(92.53,52.85) v2(92.65,52.22) v2(92.71,66.38) v2(92.75,65.72) v2(92.71,65.05) v2(92.76,58.96) v2(92.8,58.35) v2(92.79,57.72) v2(92.88,59.71) v2(93.14,52.55) v2(93.35,66.38) v2(93.35,65.05) v2(93.29,53.13) v2(93.38,65.72) v2(93.5,58.96) v2(93.51,58.23) v2(93.57,59.8) v2(93.98,66.38) v2(94.02,65.72) v2(93.98,65.05) v2(94.12,59.14) v2(94.15,58.23) v2(94.13,57.51) v2(94.17,59.81) v2(94.62,66.38) v2(94.62,65.05) v2(94.65,65.72) v2(94.84,58.28) v2(94.84,57.53) v2(94.87,60.52) v2(94.86,59.83) v2(94.86,59.08) v2(95.23,66.63) v2(95.23,66) v2(95.23,65.36) v2(95.23,64.73) v2(95.23,64.09) v2(95.23,63.51) v2(95.24,62.92) v2(95.24,62.34) v2(95.29,58.67) v2(95.86,66.63) v2(95.86,66) v2(95.86,65.36) v2(95.89,64.73) v2(95.89,64.09) v2(95.89,63.51) v2(95.89,62.91) v2(95.9,62.29) v2(96.56,61.05) v2(97.43,61.05) v2(98.26,61.05) v2(99.1,61.05) v2(99.95,61.05) v2(100.81,61.05) v2(101.59,61.05) v2(102.35,61.05) v2(103.21,61.05) v2(104,61.05) v2(123.38,55.67) v2(124.29,57.42) v2(124.31,55.73) v2(124.49,64.55) v2(124.77,57.92) v2(125.19,57.44) v2(125.73,64.55) v2(125.65,57.92) v2(126.14,57.44) v2(126.54,57.92) v2(126.82,66.2) v2(127.71,66.23) v2(127.89,65.67) v2(128.19,66.62) v2(128.3,62.47) v2(128.3,61.88) v2(128.42,63.08) v2(128.48,66.1) v2(128.8,66.62) v2(129.03,62.98) v2(129.07,66.09) v2(129.34,60.13) v2(129.41,66.62) v2(129.52,64.47) v2(129.65,66.08) v2(130,66.62) v2(130.05,58.78) v2(130.29,66.11) v2(130.44,58.35) v2(130.61,66.62) v2(130.72,64.48) v2(130.66,60.16) v2(130.71,55.61) v2(130.85,58.77) v2(130.83,57.87) v2(130.87,66.07) v2(131.19,66.59) v2(131.24,58.32) v2(131.49,66.09) v2(131.6,58.78) v2(131.63,57.89) v2(131.64,57.3) v2(131.62,55.63) v2(131.8,66.62) v2(131.93,64.47) v2(131.93,60.16) v2(132.01,58.33) v2(132.08,66.1) v2(132.39,66.62) v2(132.44,62.85) v2(132.4,58.78) v2(132.4,57.87) v2(132.54,55.63) v2(132.84,65.85) v2(132.77,58.33) v2(132.94,66.43) v2(133.02,62.85) v2(133.1,60.13) v2(133.2,64.47) v2(133.2,58.73) v2(133.23,57.43) v2(133.3,58.08) v2(133.53,61.43) v2(133.63,65.74) v2(133.57,62.28) v2(133.73,60.28) v2(133.77,64.6) v2(133.92,65.17) v2(133.92,64.03) v2(133.87,62.82) v2(133.93,60.87) v2(133.96,61.83) v3(98.07,59.8)
+VCC_CORE_G0: length 1.1
  TOP w0.127: v2(134.28,67.02) 133.91,66.65 T122.1
  BOTTOM w0.254: UCPU1.K32 133.93,67.36 v2(134.28,67.02)
+VCC_CORE_G1: length 1.4
  TOP w0.127: T123.1 133.83,57.18 v2(133.83,57.69)
  BOTTOM w0.127: UCPU1.AK32 133.83,57.07 v2(133.83,57.69)
+VCC_GT: length 27.9
  TOP w0.254: v2(126.42,61.86) 126.42,61.5 PC1225.1 ; v2(123.98,58.81) 123.98,58.43 PC1220.1 ; v2(121.41,58.84) 121.41,58.4 PC1344.1 ; v2(120.14,58.81) 120.14,58.4 PC1333.1 ; v2(125.12,61.86) 125.12,61.48 PC1330.1 ; PC1223.1 123.19,64.88 v2(123.19,64.55) ; v2(122.68,58.81) 122.68,58.4 PC1337.1 ; v2(121.92,64.42) 121.92,64.75 PC1347.1 ; v2(119.43,64.39) 119.43,64.8 PC1349.1 ; PC1348.1 120.63,64.73 v2(120.63,64.39) ; v2(123.85,61.86) 123.85,61.48 PC1228.1
  BOTTOM w0.127: 117.03,61.59 UCPU1.AA63 116.69,61.96 ; 116.76,66.51 116.69,66.43 UCPU1.L63 ; v2(119.46,48.35) 119.56,48.45 UCPU1.BB57 ; v2(113.97,48.6) 114.12,48.6 114.58,49.06 114.58,50.01 UCPU1.BB66 ; 116.82,65.71 UCPU1.M62 ; UCPU1.M62 117.52,65.71 ; UCPU1.M62 117.16,65.4 ; UCPU1.R63 116.98,64.34 ; UCPU1.R63 116.37,64.34 ; UCPU1.R63 116.69,63.97 ; UCPU1.R63 116.69,64.68 ; 117.16,61.72 UCPU1.Y62 ; UCPU1.Y62 117.52,62.05 ; UCPU1.Y62 116.83,62.05 ; 122.02,56.39 UCPU1.AM53 ; UCPU1.AM53 122.02,55.74 ; UCPU1.AM53 121.71,56.05 ; UCPU1.AM53 122.36,56.05 ; 117.16,64.16 UCPU1.T62 ; UCPU1.T62 116.82,63.88 ; UCPU1.T62 117.16,63.55 ; 118.41,56.53 118.36,56.57 118.37,56.58 UCPU1.AK60 ; UCPU1.AK56 120.2,57.36 120.19,57.36 ; UCPU1.AK56 120.48,56.99 ; UCPU1.AK56 120.2,56.65 ; UCPU1.AU63 116.23,53.1 v2(116.08,53.1) ; UCPU1.N63 116.69,64.93 ; UCPU1.N63 117.01,65.25 ; UCPU1.N63 116.69,65.56 ; UCPU1.L63 116.69,65.82 ; UCPU1.L63 116.98,66.17 ; UCPU1.AU58 119.13,52.8 v2(118.82,53.1)
  BOTTOM w0.152: 118.63,56.99 UCPU1.AK60
  BOTTOM w0.178: UCPU1.AK70 111.8,57.19 110.89,57.19 v2(110.71,57.21)
  BOTTOM w0.203: UCPU1.A66 v2(114.58,73) ; v2(119.51,72.94) 119.54,72.91 119.54,71.99 UCPU1.A58 ; v2(117.03,72.9) 117.05,72.87 UCPU1.A62
  BOTTOM w0.254: 113.44,63.56 UCPU1.U68
  vias: v2(90.91,49.87) v2(90.93,49.23) v2(90.96,48.57) v2(91.03,45.04) v2(91.29,47.76) v2(91.29,44.41) v2(91.42,46.57) v2(91.42,45.81) v2(91.49,49.54) v2(91.49,48.88) v2(91.8,45.17) v2(91.9,44.38) v2(92.05,49.87) v2(92.05,49.11) v2(92.1,48.52) v2(92.1,47.94) v2(92.05,46.54) v2(92.08,45.96) v2(92.81,44.99) v2(92.81,44.33) v2(92.86,49.36) v2(93.42,44.99) v2(93.4,44.31) v2(94.01,44.9) v2(94.01,44.31) v2(94.67,44.92) v2(94.67,44.31) v2(95.31,47.47) v2(95.33,46.66) v2(95.34,45.92) v2(95.34,45.16) v2(95.43,48.93) v2(95.4,48.23) v2(95.38,44.45) v2(96.14,48.95) v2(96.11,48.29) v2(96.06,47.65) v2(96.06,47.06) v2(96.05,44.79) v2(105.41,57.95) v2(107.87,61.15) v2(108.38,62.52) v2(108.61,63.89) v2(109.12,62.52) v2(109.3,63.88) v2(110,63.88) v2(110.16,60.84) v2(110.36,62.49) v2(110.63,63.9) v2(111.23,63.92) v2(111.81,61.14) v2(111.86,63.87) v2(112.46,63.88) v2(112.46,62.05) v2(113.11,63.91) v2(113.11,61.14) v2(113.76,64.8) v2(113.76,63.88) v2(114.35,64.8) v2(114.43,63.92) v2(114.41,61.14) v2(116.29,64.76) v2(116.31,62.05) v2(116.36,61.15) v2(117.41,66.15) v2(117.42,62.51) v2(117.68,65.29) v2(117.91,67.12) v2(118.74,65.3) v2(118.85,67.09) v2(118.88,55.67) v2(118.97,57.62) v2(119.74,67.09) v2(119.72,55.63) v2(120.45,65.95) v2(120.65,67.06) v2(120.68,57.43) v2(121.04,65.95) v2(121.59,55.67) v2(121.67,66.99) v2(121.66,65.95) v2(122.25,65.95) v2(122.47,55.67) v3(103.66,45.75)
+VCC_SA: length 19.3
  TOP w0.127: v3(137.24,74.15) 137.01,73.92 137.01,73.16
  TOP w0.305: v2(140.69,69.27) 140.34,69.62 RC168.1 ; PC1323.1 PC1322.1 138.25,58.66 138.25,59.19 138.02,59.42 PC1317.1
  TOP w0.508: PC1317.1 137.54,60.38 v2(137.31,60.38)
  IN4 w0.254: v2(140.69,69.27) 140.36,69.27 139.19,68.11 138.44,68.11 v2(138,68.54)
  BOTTOM w0.127: UCPU1.J23 138.03,67.53 ; UCPU1.J23 138.03,68.15 ; UCPU1.J23 137.67,67.83 ; UCPU1.J23 138.32,67.83 ; UCPU1.J27 136.2,68.18 136.2,68.18 ; UCPU1.J27 136.2,67.52 ; UCPU1.J27 135.89,67.83 ; UCPU1.J27 136.5,67.83 ; 136.65,67.67 UCPU1.K27 ; UCPU1.K27 136.65,67.2 136.54,67.09 ; UCPU1.K27 136.35,67.36 ; 138.18,67.36 UCPU1.K23 ; UCPU1.K23 138.48,67.67 ; UCPU1.K23 138.48,67.06 ; UCPU1.K23 138.82,67.36 138.84,67.34 ; 135.74,67.06 UCPU1.K28 ; UCPU1.K28 136.06,67.36 136.07,67.37 ; UCPU1.K28 135.74,67.67 ; 134.83,67.06 UCPU1.K30 134.83,67.67 ; 136.07,68.29 UCPU1.G28 135.74,67.97 ; 138.94,67.53 UCPU1.J22 138.64,67.83 ; UCPU1.K25 137.87,67.36 ; UCPU1.K25 137.57,67.67 ; UCPU1.K25 137.57,67.06
  BOTTOM w0.203: UCPU1.G23 138.43,68.29 138.43,68.3 v2(138,68.54) 137.59,68.32 137.57,68.32 UCPU1.G25 UCPU1.G27
  BOTTOM w0.254: UCPU1.G27 136.58,68.29 136.27,68.57 136.27,68.6 136.27,68.6 v2(136.2,68.6)
  vias: v2(77.24,60.66) v2(77.88,60.68) v2(78.07,64.21) v2(78.36,61.27) v2(78.49,63.66) v2(78.51,63.03) v2(78.54,62.44) v2(78.49,60.66) v2(78.63,61.86) v2(136.22,67.06) v2(136.55,72.8) v2(137.03,62.77) v2(137.65,57.97) v2(138.38,66.68) v2(138.97,64.05)
+VCCPLL_OC: length 35
  TOP w0.305: v2(138.91,57.48) 138.95,57.48 138.97,57.5 139.39,57.5 CC261.1
  IN4 w0.457: v2(159.52,45.74) 159.52,47.09 160.81,48.39 160.81,49.56 160.26,50.11 158.99,50.11 157.73,51.37 156.13,51.37 155.36,50.6 153.69,50.6 153.31,50.98 152.72,50.98 152.06,51.64 152.06,52.78 150.65,54.18 150.65,55.51 149.16,57 149.16,57.73 148.58,58.31 145.31,58.31 144.89,58.73 140.19,58.73 139.73,58.27 139.73,57.77 139.32,57.36 139.04,57.36 v2(138.91,57.48)
  BOTTOM w0.305: UCPU1.AL23 138.92,56.55 138.92,57.45 138.91,57.45 v2(138.91,57.48)
  vias: v3(158.6,46.06)
AGND: length 37.4
  TOP w0.127: v2(15.65,35.48) 16.57,35.48 v3(17.03,35.94) ; v3(15.26,21.88) 15.6,22.22 v2(15.6,22.95) ; v3(20.31,35.33) 20.31,34.1 20.99,33.42 CA109.2
  TOP w0.203: v2(24.46,32.39) 24.31,32.39 24.16,32.24 24.16,31.98 24.26,31.88 UA2.25 ; UA2.38 25.86,26.17 25.25,25.56 22.15,25.56 21.76,25.17 CA110.1
  TOP w0.254: QA1.4 18.77,27.58 19.05,27.3 19.05,26.55 v2(19.03,26.53)
  TOP w0.381: v2(6.71,23.83) 6.71,22.77 CA68.1 ; v2(17.16,32) 16.46,32 QA3.1
  TOP w0.457: QA9.3 19.93,22.23 v2(20.3,21.87)
  TOP w0.508: CA80.2 25.38,22.95 v2(24.99,22.56) ; CA110.1 21.77,24.85 v2(22.54,24.08) ; CA82.2 24.23,22.79 v2(24.03,22.59) ; v2(26.69,35.82) 27.08,36.22 CA107.1 ; QA3.4 v2(14.27,30.19) ; QA1.1 16.69,25.64 v2(16.69,24.88) ; CA74.2 14.83,28.79 v2(14.26,28.79) ; QA6.3 19.68,29.92 v2(19.15,30.44) ; CA40.2 15.79,35.34 v2(15.65,35.48)
  BOTTOM w0.203: JPA1.1 25.37,32.55 24.97,32.95 v2(24.97,33.56)
  BOTTOM w0.381: v2(19.03,26.53) 19.61,26.53 RA61.2 ; CA103.2 21.17,31.52 20.63,31.52 v2(20.57,31.57) ; v2(14.26,28.79) 14.82,28.23 16.36,28.23 RA60.2
  BOTTOM w0.508: CA69.2 15.29,23.25 v2(15.6,22.95) ; v2(22.54,24.08) 22.91,24.08 CA101.2 ; CA29.1 19.69,22.48 v2(20.3,21.87) ; CA102.2 v2(21.64,32.85) ; v2(14.22,31.89) 14.62,32.29 RA35.2 ; RA20.2 v2(14.26,29.42) ; v2(19.15,30.44) 19.15,30.74 RA30.2
  vias: v2(6.2,21.29) v2(20.57,30.91) v2(20.8,22.44) v2(21.44,23.07)
GND: length 2685.4
  TOP w0.089: v2(39.53,66.32) 39.47,66.32 38.9,66.89 38.9,67.36 38.52,67.74
  TOP w0.102: RC220.2 v3(143.1,40.7) ; CC274.2 v3(138.02,78.9) ; v4(67.41,29.68) 67.36,29.73 v3(66.55,29.73) ; CC179.2 v3(121.62,47.66) ; v2(119.1,16.77) v3(119.74,16.77)
  TOP w0.127: UD20.D12 116.81,32.58 116.81,32.64 116.66,32.79 116.66,33.07 116.79,33.21 116.79,33.38 116.43,33.74 116.43,34.01 ; UT1.A16 37.26,62.59 v2(37.26,62.58) ; v3(83.83,16.49) v2(84.54,16.49) ; UT1.C22 UT1.B22 UT1.A22
  TOP w0.152: UT1.AB12 UT1.AC12 ; UT1.AB8 47.41,58.91 UT1.AC8 48.31,58.91 v2(48.48,58.74) ; UT1.AB18 UT1.AC18 48.31,63.51 v2(48.49,63.33) ; PU600.4 167.21,31.32 167.06,31.48 166.03,31.48 ; UT1.L22 UT1.L23 42.34,66.3 v2(42.39,66.34) ; UT1.B12 37.75,60.75 UT1.A12 ; UT1.R20 44.18,64.72 UT1.R22 44.18,65.8 UT1.R23 ; UT1.AA23 UT1.AA22 ; UT1.B20 37.75,64.43 ; 37.75,64.43 UT1.A20 ; 37.75,64.43 UT1.A20 ; v2(41.8,66.35) 41.43,65.98 41.43,65.81 ; UT1.AC2 UT1.AC1 ; UT1.T2 44.64,56.14 UT1.T1 44.64,55.57 44.44,55.37 44.44,55.21 v2(44.43,55.19) ; 41.43,65.81 41.43,65.35 UT1.J22 ; 41.43,65.81 UT1.J23 ; v2(37.65,55.24) 37.76,55.24 38.01,55.49 UT1.B1 UT1.B2 38.58,56.52 39.23,56.52 UT1.E4 ; UT1.H2 40.97,56.14 40.97,55.69 ; UT1.AB20 UT1.AC20 48.33,64.43 v2(48.36,64.46) ; 40.97,55.69 40.97,55.52 41.22,55.27 41.22,55.26 41.25,55.23 v2(41.25,55.21) ; 40.97,55.69 UT1.H1 ; UT1.B14 UT1.A14 37.4,61.32 37.4,61.31 37.13,61.05 37.04,61.05 v2(36.92,60.93) ; UT1.N22 UT1.N23 v2(43.26,66.37) ; v2(48.48,61.52) 48.48,61.46 48.28,61.66 47.87,61.66 ; UT1.U23 UT1.U22 ; UT1.W23 46.03,65.81 46.03,66.19 v2(46.33,66.49) ; v2(47.75,55.2) 47.4,55.55 UT1.AB1 UT1.AB2 ; UT1.A6 37.43,57.99 v2(37.22,58.19) ; UT1.P2 43.72,56.14 43.72,55.68 ; v2(48.49,59.78) 48.44,59.83 UT1.AC10 UT1.AB10 ; v2(37.26,64.43) 37.74,64.43 UT1.A20 ; UT1.AB22 UT1.AC22 48.04,65.35 v2(48.31,65.62) ; v2(42.66,55.12) 42.67,55.12 42.8,55.26 UT1.M1 UT1.M2 ; UT1.AB16 47.41,62.58 47.86,62.58 UT1.AC16 47.87,62.58 48.3,62.58 48.44,62.44 v2(48.56,62.44) ; 47.87,61.66 47.4,61.66 ; 47.87,61.66 UT1.AC14 ; 43.72,55.68 v2(43.72,55.14) ; 43.72,55.68 UT1.P1 ; UT1.A8 v2(37.17,58.91) ; UT1.A18 v2(37.11,63.51) ; UT1.Y20 46.02,65.33 UT1.W22 ; v2(41.82,55.11) 41.82,55.2 41.88,55.26 UT1.K1 UT1.K2 ; v2(48.44,57.86) 48.31,57.99 UT1.AC6 UT1.AB6 ; UT1.A10 37.26,59.83 v2(37.24,59.85)
  TOP w0.178: UT1.E23 39.58,66.26 v2(39.53,66.32) ; UT1.C22 UT1.C23 38.66,65.9 38.22,66.35 v2(38.12,66.35) ; UT1.G22 UT1.G23 40.5,66.17 v2(40.36,66.31)
  TOP w0.203: UT1.A10 UT1.B10 38.52,59.83 UT1.D9 v2(39.23,59.77) UT1.E9 ; v2(39.88,59.77) 40.2,59.45 UT1.F9 ; UT1.E5 39.55,57.5 v2(39.23,57.82) ; UT1.E16 39.55,62.66 39.88,62.34 v2(39.88,62.37) 39.88,62.39 40.18,62.7 UT1.F16 ; 40.53,61.07 40.85,60.75 UT1.H12 ; 40.53,61.07 v2(40.53,61.07) ; 40.53,61.07 UT1.H13 ; UT1.B16 38.39,62.59 38.61,62.37 v2(38.6,62.37) ; UT1.W6 46.05,58.15 v2(45.73,58.47) ; U716.11 v2(171.3,17.36) ; UT1.N9 43.45,59.45 v2(43.13,59.12) ; UT1.D16 v2(39.23,62.37) ; UT1.W18 46.05,63.35 v2(45.73,63.02) 45.73,63.02 UT1.V16 ; v2(39.23,63.02) UT1.D18 38.9,63.38 38.78,63.51 UT1.B18 ; v2(43.36,32.11) 43.36,32.11 42.91,31.66 PJP300.2 ; UT1.E11 v2(39.23,60.42) UT1.D11 ; UT1.N5 v2(43.78,57.82) 44.1,57.5 UT1.R5 ; UT1.Y13 46.97,61.66 47.4,61.66 UT1.AB14 ; v2(38.6,59.12) 38.38,58.91 UT1.B8 ; UT1.R18 v2(44.43,63.02) 44.62,63.21 UT1.T18 v2(45.08,63.02) ; UT1.E6 v2(39.23,57.82) ; v2(39.23,57.82) UT1.D5 ; v2(39.23,57.82) 38.91,58.15 UT1.D6 38.74,57.99 UT1.B6 ; UT1.J5 41.36,57.35 41,57.35 UT1.H5 ; v2(13.06,66.7) 13.06,66.32 13.31,66.06 D87.2 ; D76.2 v2(10.9,62.42) ; UT1.D8 38.91,58.8 v2(39.23,59.12) 39.55,58.8 UT1.E8 ; UT1.J15 v2(41.18,61.72) 41.18,61.72 UT1.H15 ; UT1.E22 39.58,65.31 39.27,64.99 38.94,64.99 38.66,65.27 UT1.C22 ; UT1.E22 UT1.E23 ; UT1.E22 40.2,64.73 UT1.F20 ; UT1.E15 39.55,62.05 v2(39.23,61.72) 38.9,62.04 UT1.D15 ; UT1.W5 45.73,57.82 ; 45.73,57.82 UT1.V6 ; 45.73,57.82 45.41,57.5 UT1.V5 45.34,57.5 45.25,57.58 44.92,57.58 44.84,57.5 UT1.T5 ; UT1.L5 42.16,57.5 v2(42.48,57.82) 42.8,57.5 UT1.M5 ; v2(32.94,40.01) 33.12,40.19 33.12,40.84 U664.11 ; U719.11 U719.15 ; UT1.T20 UT1.R20 ; PU600.15 171.63,30.87 v2(171.81,30.69) ; UT1.J12 41.5,60.75 v2(41.18,61.07) 41.5,61.4 UT1.J13 ; v2(13.53,58.01) 13.53,58.01 13.21,58.33 12.96,58.33 D83.2 ; U720.11 36.93,44.18 v2(37.01,44.26) ; UT1.F6 v2(39.88,57.82) UT1.F5 ; UT1.J19 UT1.J18 UT1.H16 ; v2(179.68,30.66) 179.68,31.45 U717.11 ; UT1.T9 44.76,59.45 45.08,59.12 45.4,59.44 UT1.V9 ; UT1.L13 42.15,61.39 v2(41.83,61.07) ; UT1.W9 46.16,59.55 46.6,59.55 UT1.Y9 ; UT1.AB12 47.31,60.75 47.03,60.46 47.03,60.2 UT1.AB10 ; UT1.B12 UT1.D12 38.91,60.75 v2(39.23,61.07) UT1.D13 ; D82.2 12.95,61.5 v2(13.01,61.55) ; UT1.T16 v2(45.08,62.37) UT1.V15 UT1.W13 ; v2(37.21,55.65) 37.25,55.69 UT1.A1 ; UT1.L15 v2(41.83,61.72) ; UT1.N15 43.45,62.03 43.15,61.72 43.15,61.73 43.14,61.74 43.13,61.73 v2(43.13,61.72) 43.15,61.74 43.45,61.43 UT1.N13 ; v2(46.37,64.32) 46.69,64.65 UT1.Y20 46.94,64.89 UT1.AA22 ; UT1.T6 44.76,58.15 45.08,58.47 ; PU1305.4 64.47,61.68 64.47,61.22 v2(64.97,60.71) ; D75.2 v2(10.9,64.91) ; UT1.W20 46.04,64.65 v2(45.73,64.33) 45.42,64.65 UT1.V20 45.1,64.95 UT1.U22 ; D78.2 9.41,60.12 arc(9.46,60.11) 9.5,60.08 9.65,59.93 v2(9.65,59.9) ; CT157.2 43.12,68.68 CT80.2 ; UT1.M11 UT1.M12 v2(43.13,61.07) UT1.N12 UT1.N11 ; v2(47.75,55.2) 47.86,55.31 UT1.AC1 ; v2(70.94,74.96) 70.94,74.4 71.1,74.25 JXDP1.31 ; v2(169.49,39.73) 169.22,40.01 PU900.8
  TOP w0.254: UD21.G8 136.78,28.78 v2(136.78,28.7) 136.78,27.82 UD21.G6 ; CD159.2 116.38,34.95 116.38,34.07 116.43,34.01 ; UZ23.5 46.11,50.6 45.83,50.87 45.83,51.29 v2(45.29,51.84) ; v2(155.6,26.3) 155.92,25.98 UD22.M4 ; UD19.N4 107.42,25.83 v2(107.1,25.51) 106.77,25.83 UD19.M4 106.45,26.22 v2(106.45,26.3) ; UD19.T12 109.37,32.37 109.37,32.37 v2(109.7,32.7) ; UD19.G9 103.52,29.99 v2(103.85,30.32) 103.87,30.32 104.17,30.62 UD19.H10 ; v2(150.9,71.18) 150.9,71.4 151.44,71.93 152.69,71.93 152.83,72.07 153.76,72.07 CC22.2 154.18,73.49 154.38,73.69 157.2,73.69 v2(157.21,73.68) 158.27,73.68 CZ92.2 158.53,73.44 158.67,73.3 v2(158.67,71.56) 158.67,69.77 158.33,69.43 154.48,69.43 CC21.2 ; v2(122.62,27.1) 122.62,27.02 UD20.N5 122.62,26.38 v2(122.62,26.3) 122.94,25.98 UD20.N4 ; v2(122.62,27.1) 122.29,27.43 UD20.M6 ; v2(122.62,27.1) 122.94,27.43 UD20.N6 ; UD22.E6 151.37,27.5 151.37,27.43 v2(151.7,27.1) ; v2(23.82,48.69) 23.49,48.69 23.41,48.77 23.41,48.99 23.65,49.23 US2.1 ; UD21.P12 141.65,32.3 141.65,33.03 v2(141.66,33.04) ; UT1.T15 44.75,62.04 v2(44.43,61.72) 44.75,61.4 UT1.T13 ; U15.32 184.13,47.15 184.36,46.92 v2(184.36,46.47) ; PC1205.2 132.51,60.55 v2(132.51,60.16) ; 34.51,68.96 35.54,68.96 CT44.2 36.45,68.65 v2(36.46,68.67) 36.53,68.6 37.66,68.6 38.52,67.74 ; 34.51,68.96 31.89,68.96 31.8,68.87 v2(31.8,68.49) v2(31.8,66.73) 31.8,64.93 31.89,64.84 35.34,64.84 35.48,64.98 35.48,65.38 v2(35.46,65.4) 35.48,65.43 35.48,65.62 CT43.2 36.07,65.97 36.65,66.56 37.91,66.56 v2(38.12,66.35) ; 34.51,68.96 YT1.2 ; v2(105.97,28.58) 105.97,28.95 UD19.L8 UD19.L9 105.76,30.26 105.76,30.41 UD19.K10 ; UD21.T5 142.95,26.63 v2(142.63,26.3) 142.3,26.63 UD21.R5 ; 134.5,25.1 UD21.C3 ; 134.5,25.1 UD21.D3 ; 134.5,25.1 134.5,25.12 134.18,25.45 v2(134.18,25.5) ; UD21.T3 142.95,25.03 v2(142.63,24.7) 142.95,24.38 UD21.T2 ; v2(140.41,58.01) 140.41,58.1 141.08,58.76 CC217.2 ; UD22.H10 153.32,30.62 152.94,30.24 152.94,30.17 UD22.G9 152.67,29.9 152.67,29.98 v2(152.35,30.3) ; CZ85.2 153.18,76.51 153.15,76.49 ; UD20.T2 124.89,24.38 v2(124.57,24.7) 124.89,25.03 UD20.T3 ; v2(143.28,32.7) 142.95,32.37 142.95,32.3 UD21.T12 ; v2(140.68,27.1) 140.35,27.43 UD21.M6 ; v2(140.68,27.1) 140.68,27.15 141,27.47 141,27.5 UD21.N6 ; v2(140.68,27.1) 141,26.78 UD21.N5 141,26.63 v2(140.68,26.3) 140.9,26.08 140.9,26 UD21.N4 141.33,25.57 v2(141.33,25.5) 141.65,25.18 141.65,25.1 UD21.P3 ; UD21.K10 139.33,30.42 139.7,30.05 UD21.L9 139.7,29.82 v2(139.38,29.5) 139.7,29.18 UD21.L8 ; UD22.D12 150.3,32.72 v2(150.3,32.75) ; v2(88.75,69.14) 88.75,68.87 PQ218.1 ; v2(34.16,57.21) 34.16,56.7 RT40.1 ; JXDP1.13 75.6,71.98 75.97,71.61 75.97,71.23 75.67,70.93 75.08,70.93 v2(74.5,71.51) 74.1,71.91 JXDP1.19 ; D79.2 9.68,59.03 v2(9.64,59.03) ; UZ19.5 163.05,68.16 162.15,68.16 161.72,67.73 CZ82.2 ; UT1.W8 46.05,58.8 v2(45.73,59.12) ; v2(157.55,28.7) 157.55,28.77 UD22.P8 ; JXDP1.38 69.6,66.08 69.16,65.64 69.16,65.49 69.09,65.41 ; U722.L11 20.75,59.21 v2(20.75,59.09) ; UD20.E6 117.74,27.43 v2(118.07,27.1) ; UD22.R4 157.87,25.82 v2(157.55,25.5) ; 152.02,26.7 152.02,26.78 v2(151.7,27.1) ; 152.02,26.7 UD22.F5 ; 152.02,26.7 152.02,25.9 UD22.F4 151.37,25.9 ; PC1204.2 131.29,60.6 v2(131.29,60.16) ; UD22.T5 158.52,26.7 158.52,26.62 v2(158.2,26.3) 157.87,26.63 157.87,26.7 UD22.R5 ; v2(138.46,32.94) 138.4,32.88 138.4,32.3 UD21.J12 ; UD19.P3 108.07,25.17 v2(108.4,25.5) 108.72,25.82 UD19.R4 ; v2(118.78,68.55) 119.22,68.11 PC1338.2 ; v2(130.02,60.16) 130.02,60.6 PC1203.2 ; v2(77.34,71.51) 77.1,71.76 JXDP1.7 ; UT1.G22 40.45,65.29 40.45,65.22 40.8,64.87 40.8,64.7 UT1.H20 UT1.J20 UT1.J19 ; v2(109.05,26.31) 109.37,26.63 UD19.T5 ; CT152.2 27.25,65.24 v2(27.23,65.26) ; UD20.M12 122.29,32.3 122.29,32.61 v2(122.12,32.77) ; v2(26.39,65.24) 26.39,64.86 U722.A1 ; v2(102.55,27.1) 102.22,27.43 UD19.E6 ; v2(102.55,27.1) 102.22,26.78 UD19.E5 ; v2(102.55,27.1) 102.55,27.2 102.85,27.5 UD19.F6 ; v2(102.55,27.1) 102.87,26.78 UD19.F5 102.87,26.63 v2(102.55,26.3) ; UD22.B2 149.42,24.38 v2(149.75,24.7) ; UD21.L6 140.03,27.17 v2(140.03,27.1) 140.03,27.02 140.21,26.84 UD21.M5 ; v2(124.57,25.5) 124.57,25.58 UD20.T4 ; UD19.F12 102.87,32.3 102.87,32.96 v2(102.87,32.96) ; CT52.2 36.78,55.22 v2(37.21,55.65) ; C1279.2 15.53,62.28 D77.2 v2(15.01,62.78) ; v2(123.92,28.7) 123.59,29.03 UD20.P8 ; v2(63.7,74.89) 64.1,74.49 JXDP1.59 ; v2(186.39,64.28) 186.38,64.27 187.21,64.27 UE5.B11 ; UD21.B12 133.85,32.38 v2(133.53,32.7) ; v2(103.2,25.5) 103.52,25.82 UD19.G4 ; 67.16,65.87 67.09,65.94 66.93,65.94 66.6,66.28 66.6,67.33 JXDP1.50 ; PC1276.2 115.7,67.48 PC1284.2 116,66.94 v2(116.31,66.63) 116.19,66.52 PC1277.2 116.21,66.05 PC1343.2 ; UD21.G3 UD21.G4 137.1,25.97 v2(137.43,26.3) ; v2(45.73,59.12) 46.05,59.44 UT1.W9 ; v2(45.73,59.12) 45.41,58.8 UT1.V8 45.08,59.12 44.76,58.8 UT1.T8 44.75,58.79 45.4,58.15 UT1.V6 ; UD21.F4 136.45,25.98 v2(136.13,26.3) 135.8,25.98 UD21.E4 ; UT1.N20 v2(43.13,64.32) UT1.M20 ; v2(123.92,26.29) 123.92,26.22 UD20.R4 ; v2(128.75,60.16) 128.75,60.6 PC1202.2 ; v2(153.32,23.74) 153.32,23.75 UD22.H2 ; UD19.D12 101.45,32.42 101.45,33.03 101,33.48 v2(100.89,33.48) ; v2(121.19,23.57) 121.21,23.58 121.21,24.08 UD20.K2 ; v2(106.84,32.81) 106.77,32.74 106.77,32.3 UD19.M12 ; UD21.C6 134.49,27.5 134.18,27.19 v2(134.18,27.1) 134.18,27.01 134.49,26.7 UD21.C5 ; UD22.B12 149.42,32.3 149.42,32.38 v2(149.1,32.7) ; UD20.G6 UD20.F6 118.39,27.43 v2(118.07,27.1) ; UD21.P8 141.65,29.1 141.65,28.63 v2(141.69,28.59) ; JXDP1.2 78.6,65.68 78.42,65.5 v2(76.94,65.5) 76.94,66.1 77.1,66.26 JXDP1.8 ; UD22.G8 152.67,29.02 v2(152.35,28.7) 152.35,28.38 152.67,28.06 152.67,27.5 UD22.G6 ; UD21.T4 142.95,25.82 v2(142.63,25.5) 142.3,25.83 UD21.R4 ; v2(134.18,24.7) 133.85,24.38 UD21.B2 ; UD20.R6 124.24,27.43 v2(124.57,27.1) 124.57,27.18 UD20.T6 ; UD22.P3 157.22,25.18 v2(156.9,25.5) 156.9,25.57 UD22.N4 ; UD21.E5 135.8,26.78 v2(136.13,27.1) ; v2(180.54,47.09) 180.54,48.07 180.18,48.43 C1985.2 179.87,49.13 180.67,49.93 C1984.2 ; v2(182.34,59.87) 182.57,59.87 182.8,59.63 182.8,59.09 182.61,58.9 UE5.B60 ; v2(141.86,78.06) 142.58,78.79 RC227.2 ; UD22.B5 149.42,26.78 v2(149.1,27.1) 149.1,27.18 UD22.B6 ; UD22.R6 157.87,27.5 157.87,27.43 v2(158.2,27.1) 158.52,27.42 158.52,27.5 UD22.T6 ; v2(75.49,65.49) 75.6,65.6 JXDP1.14 ; v2(23.2,55.08) 23.6,55.47 24.52,55.47 24.84,55.79 C1348.2 ; UD19.P12 108.07,32.3 108.07,32.54 v2(108.34,32.81) ; v2(158.21,25.5) 158.21,25.59 UD22.T4 ; R1405.2 43.65,55.07 v2(43.72,55.14) ; v2(132.56,64.45) 132.56,64.16 PC1206.2 ; UD19.G6 103.52,27.43 v2(103.2,27.1) ; JXDP1.20 74.1,65.79 v2(74.4,65.49) ; v2(157.21,57.16) 157.21,57.25 156.59,57.87 RH146.1 ; UD20.C5 116.12,27.02 v2(116.12,27.1) 116.44,27.43 UD20.C6 ; UD22.D3 150.72,25.18 v2(150.4,25.5) 150.07,25.18 150.07,25.1 UD22.C3 ; v2(109.05,25.5) 109.37,25.82 UD19.T4 ; v2(120.67,25.5) 120.43,25.74 120.43,25.82 UD20.J4 ; v2(174.73,73.41) 174.04,73.41 PU800.8 ; v2(179.63,59.31) 179.63,59.3 179.61,59.28 UE5.B54 ; v2(118.07,27.1) 117.74,26.78 UD20.E5 ; v2(118.07,27.1) 118.07,27.02 UD20.F5 118.07,26.38 v2(118.07,26.3) ; UD22.M5 155.92,26.78 v2(155.6,27.1) ; UD20.D8 116.77,28.78 v2(116.77,28.7) ; UD19.E4 102.22,25.98 v2(102.55,26.3) ; UD22.N5 156.57,26.7 156.57,26.63 v2(156.9,26.3) ; UD21.D12 135.15,32.3 135.15,32.49 135.59,32.93 135.59,33 v2(135.64,33.05) ; UD20.H2 119.61,24.22 119.61,22.95 v2(119.67,22.89) ; UD22.E5 151.37,26.78 v2(151.7,27.1) ; UD22.F12 152.02,32.3 152.02,32.71 v2(152.13,32.81) ; JXDP1.49 66.6,73.05 66.6,71.85 67.45,71 v2(68.12,71) 68.78,71.66 69.29,71.66 69.6,71.97 JXDP1.37 ; UD21.H10 137.75,30.55 UD21.G9 137.1,29.9 137.1,29.98 v2(136.78,30.3) ; 151.37,25.9 UD22.E4 ; 151.37,25.9 151.37,25.95 151.05,26.28 v2(151.05,26.3) ; v2(151.7,27.1) 152.02,27.43 152.02,27.5 UD22.F6 ; v2(16.37,58.07) 16.59,58.07 16.97,58.45 16.97,58.48 16.95,58.5 16.95,58.9 17.11,59.06 17.11,59.08 17.25,59.21 17.25,59.52 17.54,59.81 C618.2 ; PC1339.2 121.07,68.09 v2(120.63,68.54) 120.19,68.11 PC1340.2 ; JUSBC1.A1 7.59,63.54 v2(8.28,64.23) ; PC1209.2 128.88,64.03 v2(128.88,64.47) ; v2(120.58,32.9) 120.34,32.66 UD20.J12 ; v2(137.7,23.77) 137.75,23.82 UD21.H2 ; U722.L1 20.55,64.93 v2(20.55,64.91) ; v2(118.07,26.3) 118.39,25.98 UD20.F4 ; v2(118.07,26.3) 117.74,25.98 UD20.E4 ; UD20.H10 119.69,30.62 119.04,29.97 UD20.G9 119.04,29.84 119.22,29.66 119.22,29.28 UD20.G8 119.04,29.03 v2(118.72,28.7) ; JXDP1.26 72.6,68.74 v2(72.24,69.1) ; v2(155.6,27.1) 155.6,27.13 155.92,27.46 UD22.M6 UD22.N6 156.57,27.5 156.57,27.43 v2(156.9,27.1) ; v2(155.6,27.1) 155.27,27.43 UD22.L6 ; v2(134.37,57.21) 134.37,57.24 134.39,57.26 CC181.2 ; UD19.N6 107.42,27.43 v2(107.1,27.11) 106.77,27.44 UD19.M6 106.61,27.34 106.61,27.33 106.44,27.16 v2(106.44,27.12) 106.12,27.44 UD19.L6 ; UD20.B5 115.79,26.78 v2(115.47,27.1) 115.47,27.2 115.76,27.5 UD20.B6 ; UT1.R20 v2(43.78,64.32) UT1.R19 ; UT1.N8 v2(43.13,59.12) ; v2(173.79,45.09) 173.48,45.4 173.48,46.62 174.22,47.36 PU1400.6 ; v2(56.92,71.63) 56.92,71.85 55.68,73.1 PQ217.1 ; v2(99.95,32.7) 99.97,32.7 100.27,32.4 UD19.B12 ; v2(17.7,63.74) 17.67,63.77 17.67,64.19 17.81,64.32 RT188.2 RT187.2 ; UD20.F12 118.39,32.37 118.88,32.86 v2(119.13,32.86) ; v2(139.74,61.4) 139.74,61.4 CC209.2 ; UD21.E6 135.8,27.43 v2(136.13,27.1) ; 153.15,76.49 153.54,76.49 v2(153.91,76.12) 153.96,76.12 154.17,76.33 UZ25.5 ; 153.15,76.49 152.55,76.49 152.48,76.56 CC210.2 ; UD20.L6 122,27.14 122,26.99 UD20.M5 122.29,26.64 v2(121.96,26.32) 121.96,26.23 UD20.M4 122.62,25.57 v2(122.62,25.5) ; U15.23 187.68,46.19 v2(187.4,46.47) ; v2(154.62,23.74) 154.62,23.75 UD22.K2 ; UD21.F5 136.45,26.78 v2(136.13,27.1) ; UD22.T3 158.52,25.03 v2(158.2,24.7) 158.52,24.38 UD22.T2 ; UT1.M19 v2(42.48,64.32) UT1.L20 ; R1472.1 20.74,66.84 C1345.2 ; PC210.2 59.04,66.85 59.57,66.32 59.83,66.32 60.08,66.06 60.08,65.78 ; v2(136.13,27.1) 136.45,27.43 UD21.F6 ; v2(187.4,43.42) 187.55,43.27 187.55,42.82 187.63,42.74 U15.16 ; PR406.2 167.95,63.59 168.5,64.14 168.5,65.95 CZ87.2 ; v2(191.55,43.58) 191.55,44.35 191.24,44.66 C135.2 ; SW2.3 187.4,76.39 186.42,76.39 186.01,75.97 v2(186.01,75.74) ; UD22.C5 150.07,26.74 149.73,27.08 v2(149.75,27.1) 149.75,27.18 UD22.C6 ; v2(116.12,24.7) 115.79,24.38 UD20.B2 ; UD21.R6 142.3,27.43 v2(142.63,27.1) 142.95,27.43 UD21.T6 ; v2(101.25,28.66) 101.25,28.74 101.57,29.07 UD19.D8 ; JUSBC1.A12 7.82,58.04 8.23,57.63 v2(8.23,56.78) ; UE5.B66 185.61,58.67 185.61,58.92 185.35,59.18 v2(185.35,59.28) ; UD21.M4 140.52,25.73 140.53,25.73 140.68,25.57 v2(140.68,25.5) ; v2(123.27,25.5) 123.59,25.18 UD20.P3 ; v2(158.85,32.7) 158.52,32.37 158.52,32.3 UD22.T12 ; UD20.D3 117.09,25.18 v2(116.77,25.5) 116.44,25.17 UD20.C3 ; U15.9 184.13,43.19 v2(184.36,43.42) ; v2(150.4,28.7) 150.4,28.78 UD22.D8 ; UD22.K10 154.62,30.48 155.2,29.9 UD22.L9 155.27,29.82 v2(154.95,29.5) 155.27,29.18 UD22.L8 ; v2(102.55,26.3) 102.87,25.98 UD19.F4 ; 69.72,65.41 69.72,65.54 70.1,65.92 70.82,65.92 71.1,66.2 JXDP1.32 ; v2(40.53,57.82) UT1.H5 ; UD21.B6 133.53,27.18 v2(133.53,27.1) 133.53,27.02 UD21.B5 ; UD20.B12 115.79,32.39 v2(115.48,32.7) ; D80.2 10.2,56.5 v2(9.87,56.17) ; UD22.J4 154.3,25.57 v2(154.3,25.5) ; v2(156.22,32.76) 155.92,32.47 155.92,32.3 UD22.M12 ; v2(161.42,48.51) 161.7,48.79 UZ22.5 ; UD22.G3 152.35,25.42 v2(152.35,25.5) 152.35,25.56 152.67,25.88 UD22.G4 ; v2(70.94,74.96) 71.42,74.48 72.39,74.48 72.6,74.27 JXDP1.25 ; UD20.K10 120.99,30.55 UD20.L9 UD20.L8 121.64,29.03 v2(121.32,28.7) ; v2(134.94,28.62) 135.15,28.83 UD21.D8 ; UD19.N5 107.42,26.61 v2(107.1,26.28) 107.1,26.43 106.82,26.7 UD19.M5 ; UD20.G3 119.04,25.1 119.04,25.9 UD20.G4 119.04,25.98 v2(119.37,26.3) ; v2(140.42,32.91) 140.35,32.84 140.35,32.3 UD21.M12 ; UD22.P12 157.22,32.3 157.22,32.88 v2(157.28,32.94) ; PC1207.2 131.32,64.13 v2(131.32,64.47) ; UD20.T5 124.89,26.7 124.89,26.62 v2(124.57,26.3) 124.24,26.63 UD20.R5 ; v2(138.89,23.77) 139.05,23.93 UD21.K2 ; UD22.J12 154.06,32.39 v2(154.06,32.84) ; UT1.J8 41.5,58.8 v2(41.18,59.12) 40.85,58.8 UT1.H8 ; v2(138.73,26.3) 138.4,25.97 UD21.J4 ; v2(45.08,59.77) UT1.T9
  TOP w0.305: PC1322.2 137.69,59.01 137.49,59.22 137.49,59.17 v2(137.49,59.17) ; UD19.H2 104.17,23.77 v2(104.17,23.77) ; v2(104.5,25.5) 104.82,25.82 UD19.J4 ; CC177.2 138.58,50.58 139.45,49.72 RC5.2 ; C96.2 191.16,46.06 v2(191.49,45.73) ; v2(41.8,66.35) 41.45,66.7 41.45,67.05 41.26,67.24 CT71.2 CT81.2 ; v2(121.57,57.42) 121.57,56.78 PC1279.2 ; v2(143.03,58.07) 143.03,58.45 CC268.2 ; 109.05,27.17 108.9,27.32 108.9,27.32 UD19.R6 ; 109.05,27.17 109.05,27.18 109.21,27.34 109.22,27.34 UD19.T6 ; 109.05,27.17 v2(109.05,27.1) ; UD20.T12 124.89,32.3 124.89,32.37 v2(125.22,32.7) ; v2(135.18,68.62) 135.18,68.62 135.18,69.02 135.47,69.31 PC1327.2 ; v2(136.93,66.91) 137.06,67.04 PC1325.2 ; v2(162.83,60.42) 162.44,60.04 UC7.3 ; v2(120.66,55.71) 120.37,56 PC1278.2 ; PC1324.2 139.24,68.09 138.96,68.38 v2(138.96,68.59) ; UC9.3 164.69,69.03 v2(165.09,68.64) ; PC1301.2 133.88,56.35 CC185.2 134.38,57.2 v2(134.37,57.21) ; v2(126.19,55.71) 126.21,55.73 PC1281.2 PC1283.2 ; C1216.2 41.1,46.14 41.58,45.65 v2(41.58,44.12) ; v2(129.8,68.54) 129.34,68.08 PC1275.2 ; v2(103.2,25.5) 103.2,25.42 UD19.G3 ; PC1285.2 127.39,56.22 CC186.2 128.04,55.71 v2(127.97,55.63) ; RT44.1 v2(34.11,57.84) ; v2(103.76,28.33) 103.76,28.36 103.52,28.59 103.52,29.1 UD19.G8 ; UD19.B2 100.46,24.49 100.6,24.63 v2(100.6,24.7) ; U699.3 24.85,54.89 24.73,55.01 v2(23.79,55.01) ; UD19.K2 105.47,24.3 v2(105.47,23.77) ; v2(109.05,26.31) 108.72,26.64 UD19.R5 ; UD19.F6 103.17,27.21 103.17,27.13 v2(103.2,27.1) ; PC407.2 165.8,58.46 PU400.4 ; UD19.B5 100.1,26.87 100.1,26.88 99.95,27.03 v2(99.95,27.1) 99.95,27.18 100.09,27.32 UD19.B6 ; v2(108.9,23.8) 109.37,24.27 UD19.T2 UD19.T3 ; v2(34.07,59.67) 34.69,59.67 CT83.2 CT84.2 CT74.2 ; UD19.C5 100.72,26.9 100.72,26.91 100.6,27.03 v2(100.6,27.1) 100.6,27.18 100.71,27.29 UD19.C6 ; v2(123.34,57.34) 123.23,57.22 123.23,56.48 123.44,56.27 PC1280.2 ; PC1282.2 119.36,56.27 119.74,56.65 119.74,57.21 119.76,57.24 v2(119.76,57.35) ; CC182.2 136.58,56.84 136.2,57.22 136.2,57.22 v2(136.11,57.3) ; RT164.1 RT12.2 CT100.2 ; v2(123.6,33.04) 123.59,33.03 123.59,32.3 UD20.P12 ; v2(59.16,79.59) 59.07,79.5 UZ26.5 ; v2(187.17,69.4) 187.17,68.69 186.61,68.13 186.61,67.87 UE5.B18 ; UD19.D3 101.57,25.25 101.32,25.5 v2(101.25,25.5) 101.15,25.5 100.92,25.27 UD19.C3 ; v2(42.44,37.58) 42.44,37.69 CT47.2 ; CT94.2 CT93.2 50.39,67.75 v2(50.8,67.34) ; 65.89,64.25 65.89,64.42 PC1097.2 ; UD21.F12 136.6,32.45 136.6,32.73 v2(136.66,32.79) ; RT45.1 v2(34.16,57.21) ; v2(34.14,58.43) 34.19,58.48 CT57.2 ; v2(202.56,58.8) 202.56,58.21 UC8.3 ; v2(108.4,28.7) 108.07,29.03 UD19.P8 ; UD19.J12 104.82,32.3 104.82,32.8 v2(104.88,32.86)
  TOP w0.32: CC256.2 135.64,51.62 136.09,51.62 136.29,51.43 v2(136.79,51.43) 137.31,51.95 CC259.2 ; CC257.2 131.67,51.56 v2(131.81,51.43) ; CD144.2 161.19,31.75 160.81,32.14 v2(160.81,32.24) ; CC258.2 127.38,51.95 v2(126.85,51.43)
  TOP w0.356: CC261.2 139.64,56.94 140.12,57.43 CC125.2 140.49,57.94 v2(140.41,58.01) ; PC1021.1 66.9,47.91 v2(66.51,47.52) 66.9,47.12 PC1095.1 ; CT102.2 50.78,55.56 v2(50.82,55.59) 51.09,55.32 R1403.2 ; CT102.2 CT101.2 ; CT102.2 CT103.2 RT4.1 ; PC1305.2 132.87,56.18 PC1291.2 132.87,56.95 v2(132.54,57.27)
  TOP w0.381: 61.07,48.87 60.96,48.87 60.91,48.81 60.64,48.81 60.31,48.48 PR282.2 ; 61.07,48.87 PQ208.4 ; 61.07,48.87 61.55,48.87 v2(61.71,48.71) ; CD168.2 145.64,31.81 CD163.2 ; v2(110.69,32.32) 111.35,32.32 111.81,31.86 CD29.2 CD145.2 ; v2(179.93,19.77) 180.09,19.92 C1229.2 ; PQ209.1 21.07,73.05 v2(21.44,73.41) ; RE103.2 198.86,54.64 198.86,56.22 198.21,56.87 198.21,57.49 UC13.3 ; CC267.2 145.72,62.37 145.24,61.89 v2(145.24,61.56) ; v2(160.11,26.53) 160.14,26.56 CD38.2 ; C1200.2 48.49,23.05 v2(48.67,22.87) ; v2(74.61,77.61) 74.65,77.65 RC219.1 ; v2(201.22,42.25) 201.54,41.93 UZ24.2 ; v2(60.71,65.88) 60.19,65.88 60.08,65.78 PQ215.1 ; v2(152.13,32.81) 152.73,33.42 152.73,35.09 CD120.2 ; C614.2 198.12,51.23 v2(198.16,51.27) ; v2(147.78,29.42) 147.5,29.7 CD87.2 ; v2(113.64,26.78) 113.64,27.34 113.31,27.67 CD143.2 ; v2(7.34,20.28) 7.09,20.53 6.17,20.53 5.93,20.77 v2(4.39,20.77) ; v2(182.42,19.53) 182.37,19.58 182.18,19.58 C1226.2 ; PC510.2 87.55,23.83 86.77,24.62 v2(86.77,24.85) ; C95.2 186.84,40.23 v2(187.7,41.09) ; CC202.2 139.51,65.87 v2(139.66,65.72) ; CD164.2 112.45,24.32 v2(113.46,23.3) ; v2(51.07,41.3) 51.2,41.3 52.04,40.46 53.24,40.46 53.64,40.85 UC11.3 ; QE13.1 158.58,36.71 v2(158.41,36.53) ; CC224.2 144.12,55.97 v2(144.37,55.72) ; CC204.2 151.61,56.03 151.23,56.41 v2(150.67,56.41) ; C1203.2 61.71,77.87 v2(61.71,77.77) 61.32,77.38 R1162.2 ; v2(37.58,13.66) 38.12,13.66 RE89.2 38.1,14.27 37.9,14.27 37.82,14.36 37.82,15.03 37.17,15.68 v3(37.17,15.88) 37.17,16.27 36.4,17.04 RE59.2 ; CE42.2 169.67,67.32 169.1,66.74 v2(169.1,66.66) 169.1,66.5 168.59,66 CZ87.2 ; C1321.2 192,17.61 v2(191.8,17.41) ; PQ219.4 63.74,21.94 63.98,22.18 v2(64.21,22.18) ; v2(130.1,64.45) 130.1,64.08 PC1208.2 ; v2(142.4,62.24) 142.24,62.08 CC206.2 ; PC212.2 84.43,69.86 v2(84.12,69.56) ; PQ209.4 19.77,71.6 v2(19.84,71.66) ; PR904.2 164.71,38.78 v2(163.29,38.78) 163.29,39.22 PC907.2 ; v2(65.41,57.49) 64.38,57.49 63.58,56.69 PR1121.2 ; v2(157.3,59.01) 157.73,59.01 157.97,58.77 CC225.2 ; v2(43.46,66.99) 43.46,67.12 43.12,67.46 CT72.2 CT80.2 ; PR412.2 168.13,60.92 168.56,61.34 168.56,61.44 ; v2(112.45,60.28) 112.45,59.83 PC1352.2 ; v2(143.68,63.1) 143.68,62.71 CC265.2 ; v2(128.65,45.37) 128.45,45.37 127.99,45.83 CC34.2 ; 168.56,61.44 v2(168.56,61.5) ; 168.56,61.44 168.57,61.43 CE46.2 ; CC25.2 148.39,47.28 v2(147.78,47.28) 147.22,47.28 CC24.2 ; v2(153.52,46.47) 153.04,45.99 CC23.2 ; v2(90.45,75.24) 90.45,74.55 PU201.4 ; v2(118.78,68.55) 118.74,68.59 117.91,68.59 RC114.2 ; v2(55.6,35.06) 55.86,35.06 56.28,34.64 PQ223.4 ; PR273.2 55.91,17.48 v2(55.37,16.95) 55.73,16.6 PC216.2 ; CT144.2 24.81,67.26 v2(25.24,66.83) ; C1223.2 68.43,79.38 v2(67.56,79.38) ; CT92.2 CT91.2 34.54,61.48 v2(34.42,61.35) ; v2(82.53,71.46) 82.5,71.48 82.58,71.48 83.31,72.22 PR269.2 ; v2(61.25,29.55) 59.47,29.55 v3(58.59,30.43) 58.18,30.84 PQ223.1 ; U48.4 v2(204.28,26.45) ; C377.2 C375.2 46.28,19.57 46.49,19.36 v2(46.79,19.36) 47.16,19.36 C355.2 47.4,19.69 46.81,20.28 C1278.2 ; RT190.2 23.65,67.23 23.45,67.43 v2(23.45,67.75) ; PC1326.2 135.83,67.66 v2(135.31,67.14) ; PQ400.4 169.71,56.97 ; 169.71,56.97 PU401.3 ; 169.71,56.97 169.89,56.97 v2(170.69,57.77) ; CA23.1 36.89,27.76 v2(36.89,27.76) ; PU203.4 58.18,16.51 v2(59.1,16.51) ; v2(179.29,50.11) 179.03,50.11 PC1408.2 ; v2(20.37,67.67) 20.42,67.62 C1345.2 ; v2(142.59,67.97) 142.59,67.94 142.98,67.55 CC203.2 ; PC1317.2 139.46,59.86 PC1323.2 ; v2(90.45,66.33) 90.33,66.45 PQ218.4 ; v2(115.85,60.23) 115.85,60.02 115.04,59.21 PC1351.2 ; v2(143.68,66.46) 143.68,66.99 143.88,67.18 CC264.2 ; v2(144.12,70.87) 144.02,70.87 RC3.2 ; R60.2 186.42,50.04 186.14,50.32 v2(186.14,50.33) ; v2(35.08,21.45) 35.23,21.45 35.89,22.11 PR301.2 ; v2(189.99,72.83) 189.99,72.94 189.61,73.32 189.59,73.32 QE12.4 ; v2(110.71,58.72) 110.96,58.97 PC1350.2 ; 162.44,59.77 UC7.3 162.44,59.77 ; 162.44,59.77 162.44,58.68 RC85.1 ; PC607.2 173.97,29.8 v2(174.35,29.42) 173.84,28.91 PC606.2 ; CT100.2 41.25,68.21 CT81.2 ; v2(149.71,46.11) 149.89,45.93 CC26.2 ; v2(129.21,25.76) 129.49,25.49 RD58.2 ; v2(68.04,14.34) 68.81,15.11 PD101.1 ; v2(165.74,34.91) 165.74,33.99 PR608.2 ; PC1292.2 131.09,56.18 PC1303.2 131.09,56.79 130.71,57.17 v2(130.71,57.26) ; RC44.2 151.59,61.13 151.11,61.62 149.85,61.62 v2(149.74,61.72) ; C97.2 180.58,45.92 180.54,45.96 v2(180.54,47.09) ; v2(184.24,41.4) 183.59,40.75 CA72.2 183.2,40.42 C98.2 ; CC282.2 CC195.2 141.4,71.23 v2(141.83,70.79) ; C1167.2 C1293.2 38.23,45.84 38.54,45.53 v2(38.54,45.16) ; v2(33.02,59.9) 33.25,59.9 33.52,60.17 CT85.2 33.52,60.8 CT86.2 ; PU402.3 172.51,56.84 v2(172.84,56.51) ; v2(57.51,39.58) 57.51,41.23 56.16,42.58 RE101.2 ; v2(31.93,58.84) 32.02,58.84 32.5,59.32 RT48.1 ; C1199.2 50.32,22.61 50.78,23.07 v2(51.28,23.07) ; RE85.2 171.86,60.35 171.58,60.08 171.58,59.78 171.54,59.74 v2(171.54,59.68) ; CD57.2 147.22,30.67 v2(148.15,31.6) ; PQ218.1 87.67,68.55 PC213.2 ; PC1342.2 117.2,67.83 v2(117.06,67.97) ; CC211.2 146.61,65.54 v2(146.61,65.87) 146.28,66.2 RC1.1 ; C1347.2 21.34,55.69 21.34,55.68 v2(21.34,55.31) ; C1204.2 61.22,75.38 v2(61.69,74.91) ; v2(148.08,28.1) 147.17,28.1 146.86,27.8 CD165.2 ; v2(159.66,40.48) 159.64,40.46 159.64,40 159.88,39.76 159.88,39.14 QE13.4 ; RC139.1 v2(63.09,77.38) ; v2(57.54,64.84) 57.7,64.99 PQ216.1 ; PC214.2 v2(61.49,14.39)
  TOP w0.406: v2(34.76,74.68) 34.76,75.17 34.87,75.28 PQ207.1 ; PQ207.4 33.22,73.35 v2(33.02,73.35) ; QE14.4 v2(35.38,33.93)
  TOP w0.457: v2(150.54,72.82) 150.34,72.61 CZ78.2 ; QE12.1 187.8,74.76 v2(188.25,74.31) ; CC283.2 140.92,67.26 141.6,67.93 v2(141.68,67.93) ; v2(136.99,70.86) 136.97,70.84 PC1315.2 137.29,70.19 137.63,70.53 RC166.2
  TOP w0.508: v2(77.67,77.94) 77.67,77.71 78.33,77.05 RC122.2 ; v2(71.01,60.84) 70.64,60.47 PC1134.2 ; v2(191.36,28.66) 191.97,28.66 MC3.2 R540.2 ; v2(204.52,61.73) 204.52,61.91 204.18,62.25 PC713.2 203.96,63.06 PR709.2 ; PC603.2 170.89,35.18 v2(171.32,35.61) ; v2(188.47,19.08) 188.52,19.03 C1225.2 ; RH557.2 159.44,80.17 CZ84.2 159.44,77.89 v2(159.23,77.68) ; RC88.2 RC89.2 RC7.2 ; PQ217.4 53.18,74.67 52.95,74.9 52.95,76.3 52.73,76.52 v2(52.73,76.96) ; CE63.2 CE14.2 183.11,71.99 182.78,72.32 v2(182.78,72.53) ; v2(129.33,51.43) 129.26,51.36 CC175.2 128.63,50.15 128.12,50.66 127.62,50.66 CC194.2 ; CC176.2 CC178.2 134.34,51.37 v2(134.29,51.43) ; CD166.2 145.26,34.15 v2(143.05,34.15) ; v2(32.11,25.69) 32.33,25.46 33.07,25.46 CA4.2 ; v2(95.76,31.35) 95.98,31.58 CD3.2 96.44,32.59 CD8.2 ; CD118.2 119.3,35.94 v2(120.04,36.68) ; v2(13.82,13.67) 14.12,13.98 CH95.2 ; v2(175.84,47.81) 175.9,47.76 PR1407.2 ; PC1536.2 59.13,31.38 59.53,30.98 59.82,30.98 v2(61.25,29.55) ; R7.2 CA33.2 28.33,38.08 v2(28.68,37.74) ; PR219.2 31.69,76.34 32.36,77.02 v2(32.36,78.57) ; CA53.1 24.87,18.55 v2(24.71,18.4) ; C1164.2 176.4,32.52 C1158.2 177.52,32.17 v2(177.78,31.91) ; CD176.2 142.08,35.41 CD30.2 142.21,35.04 v2(142.57,34.68) ; v2(92.35,38.31) 92.75,38.31 92.77,38.29 RD115.2 ; v2(76.38,54.95) PC1132.1 ; CD168.2 147.45,32.83 v2(148.23,33.61) 149.8,35.18 CD59.2 CD179.2 ; v2(112.45,62.98) 112.67,63.2 PC1354.2 ; v2(191.9,72.09) PC1406.2 ; CC223.2 141.25,58.91 CC217.2 ; v2(174.14,13.98) 174.07,14.06 172.31,14.06 ; CD167.2 135.33,34.74 v2(135.38,34.68) ; v2(142.98,59.73) 142.98,60.26 CC205.2 ; CD173.2 133.17,34.67 133.48,34.36 v2(133.48,34.38) ; v2(136.5,75.02) 135.93,75.02 135.67,74.76 133.17,74.76 PC1310.2 ; MD10.1 v2(184.86,14.56) ; PR610.2 PC618.2 162.38,29.42 v2(162.33,29.47) 162.32,29.46 161.92,29.85 CD170.2 ; R545.2 v2(191.24,29.42) ; v2(175.94,54.92) 175.62,54.59 PR1402.2 174.85,54.26 PC1400.2 ; H16.1 105.89,72.96 RC109.1 ; CD5.2 123.91,35.41 124.04,35.54 CD6.2 124.53,34.87 v2(125.22,34.18) ; C1215.2 v2(34.27,45.12) ; v2(62.6,78.63) C8.2 64.05,79.21 U728.2 ; v2(204.52,75.78) 203.96,75.78 PC1418.2 ; v2(120.9,49.09) 121.02,48.98 CC179.2 ; PC1316.2 140.08,64.75 v2(139.49,64.75) ; PC1341.2 117.83,68.52 RC114.2 ; PC1405.2 167.23,53.21 v2(167.23,53.22) ; QE14.1 34.18,36.11 C1218.2 34.67,36.2 36.09,37.63 v2(36.78,37.63) 36.81,37.65 R1186.1 C1166.2 ; v2(33.73,24.8) 34.01,25.08 CA42.2 CA31.2 ; v2(179.9,42.33) 180.06,42.49 180.06,43.14 ; CC28.2 66.85,76.82 CC33.2 ; CC28.2 67.79,77 v2(67.36,77.43) ; CC28.2 CC269.2 ; v2(20.63,77.29) 20.64,77.3 PR215.2 ; v2(157.21,73.68) 157.26,73.63 YC1.4 ; C1304.2 C721.2 175.21,42.55 v2(175.26,42.6) ; v2(110.92,68.06) 111.2,67.78 RC90.2 ; PC616.2 165.27,31.59 PC614.2 ; v2(174.35,31.84) 174.31,31.84 173.68,32.47 PR605.2 ; CD60.2 158.85,36.09 v2(158.41,36.53) ; C1324.2 195.3,22.26 v2(194.62,22.95) ; v2(152.86,52.05) 153.43,52.62 RH129.1 152.74,53.59 RH139.1 ; v2(169.01,72.88) 169.02,72.89 169.35,72.89 PC802.2 169.82,73.41 v2(169.06,74.18) ; R1468.2 24.36,56.83 C1348.2 ; CD155.2 CD148.2 111.65,34.02 v2(111.25,34.42) ; CD37.2 107.89,35.54 CD86.2 108.89,36.78 v2(108.97,36.86) ; CD162.2 145.3,24.7 v2(144.96,24.36) 144.96,24.35 145.77,23.53 CD91.2 ; v2(178.41,37.02) 178.41,37.32 178.91,37.82 R1188.1 ; v2(174.22,33.17) 174.03,33.36 PR606.2 ; C352.2 47.96,16.44 v2(48.29,16.44) ; v2(30.79,35.92) 31.17,35.54 CA106.2 ; C1162.2 181.79,32.47 v2(179.68,32.47) ; CA54.1 CA56.1 29.49,19.21 v2(29.9,18.8) ; v2(18.03,18.8) 18.03,19.59 RA41.2 ; v2(177.66,76.89) 177.65,76.89 177.65,76.23 177.56,76.14 PC803.2 PC804.2 PC806.2 ; v2(161.16,44.03) PC902.2 ; v2(163.81,62.7) 163.81,63.03 162.41,64.42 161.39,64.42 161.01,64.04 RC65.2 ; v2(204.57,73.87) PR1418.2 ; v2(192.33,64.45) 192.33,64.65 CE45.2 191.39,64.88 CE38.2 ; v2(172.49,37.65) 171.81,38.34 PC905.2 ; v2(149.5,41.94) 149.05,42.4 CMOS1.2 ; v2(162.38,67.62) 162.28,67.52 CZ82.2 ; v2(34.56,27.78) 34.17,27.39 CA25.1 ; v2(191.44,33.46) 191.77,33.46 C6.2 C1145.2 ; PR106.2 30.02,71.81 v2(30.02,71.31) ; v2(165.08,58.41) 165.11,58.44 PC407.2 ; v2(128.7,22.01) 128.37,21.67 CD160.2 ; PC1402.2 179.29,50.79 v2(179.29,50.11) ; v2(166.83,47.2) 166.8,47.18 CZ89.2 ; CD136.2 v2(133.83,16.77) ; v2(190.31,51.69) 189.84,52.16 CE49.2 ; RC313.1 142.09,48.52 v2(141.71,48.9) 141.33,49.28 RC7.2 ; C1213.2 33.3,45.25 C712.2 v2(33.12,46.11) ; PC1096.2 76.15,50.91 76.48,50.58 v2(76.48,50.35) ; PQ220.3 60.23,21.18 59.82,21.6 59.82,23 v4(59.92,23.1) ; C1220.2 55.56,76.73 55.58,76.72 v2(56.24,76.72) ; CE13.2 CE55.2 ; CE55.2 186.03,72.46 v2(186.09,72.53) ; CE55.2 RE77.2 ; v2(177.11,69.45) 177.11,69.48 177.06,69.53 CE61.2 ; v2(19.26,46.25) 19.26,47.48 19.62,47.84 C1346.2 ; PR407.2 175.06,56.04 v2(174.68,56.42) 174.78,56.42 175.11,56.75 175.11,57.21 PC405.2 ; v2(132.36,27.97) 132.28,27.9 CD90.2 ; C1258.2 172.9,20.15 C1264.2 174.27,20.35 174.73,20.81 v2(175.18,20.81) ; RC7.2 RC6.2 RC5.2 ; CA24.1 34.65,32.09 v2(34.8,31.94) ; v2(173.03,42.66) 172.44,42.66 PC904.2 PC903.2 ; CZ83.2 160.66,46.08 v2(160.17,45.6) ; v2(113.45,73) 113.27,73.19 CA35.2 ; CR25.1 141.83,46.24 v4(141.78,46.19) 141.92,46.04 CR24.1 ; DA4.1 28.6,17.99 v2(28.85,18.25) ; 74.49,38.31 74.11,38.69 C1275.2 ; C1217.2 v2(28.87,40.42) ; C1163.2 v2(179.93,28.09) ; v2(129.25,24.05) 129.41,24.22 RD57.2 130.12,23.32 CD182.2 ; CZ86.2 RZ75.2 v2(169.09,67.78) ; DA3.1 v2(19.41,15.96) ; RC20.2 151.9,58.3 v2(152.46,58.86) 152.61,58.71 CC272.2 153.77,59.52 v2(153.73,59.56) ; v2(177.65,77.66) 177.75,77.56 PC805.2 ; SW2.1 191.75,75.45 PC1416.2 ; CE52.2 180.44,74.68 v2(180.34,74.79) ; v2(191.92,74.24) 192.32,74.63 PC1416.2 ; PC608.2 166.09,25.22 166.47,24.85 v2(166.5,24.85) ; v2(27.64,55.61) 27.28,55.97 C1349.2 C1350.2 ; CD169.2 161.46,33.91 v2(160.91,34.46) ; PC1410.2 168,49.54 v2(168.17,49.72) ; v2(35.08,21.45) 35.28,21.24 RE22.1 RE23.1 ; Q71.3 204.82,18.39 v2(204.22,17.79) ; CD161.2 CD150.2 111.51,29.7 v2(111.1,30.11) ; v2(146.08,52.31) 146.79,51.6 CC214.2 ; PR412.2 PC406.2 ; RE54.1 181.23,71.84 CE40.2 181.2,72.37 v2(181.36,72.53) 181.33,72.55 RE78.2 ; v2(116.99,34.1) 117.14,34.24 CD1.2 CD159.2 ; v2(173.79,45.09) 173.81,45.12 174.37,45.12 174.85,45.6 PC1411.2 PR1406.2 ; PC1419.2 195.2,70.49 v2(195.2,70.06) ; PD100.1 67.11,14.82 66.45,14.16 ; RC227.2 143.09,78.77 CC273.2 ; C2973.2 v2(12.93,9.74) ; CD172.2 155.47,36.28 155.96,36.76 v2(155.98,36.76) ; CC21.2 152.54,69.74 v2(152.53,69.76) ; PC204.2 92.58,74.63 93.09,75.14 93.09,75.28 v2(93.07,75.31) ; C2.2 27.36,51.93 29.19,51.93 v2(29.44,51.67) ; v2(65.02,18.96) 64.95,18.88 PC215.2 PR271.2 ; v2(101.07,14.09) v3(101.07,15.3) 101.07,15.5 CD133.2 ; v2(61.44,39.84) PC524.2 ; MD9.1 v2(180.9,14.56) ; PC1227.2 114.61,66 v2(114.33,65.72) ; v2(30.59,45.4) C715.2 C1297.2 ; RC113.1 110.4,76.93 RC110.1 RC112.1 108.32,76.93 v2(108.03,77.22) ; PC604.2 173.44,22.27 v2(173.58,22.41) ; v2(95.64,22.84) RD51.2 96.29,21.34 CD197.2 ; v2(150.98,16.77) v3(152.26,16.77) CD140.2 ; v2(155.04,45.23) 155.92,46.11 CC271.2 ; PR804.2 172.44,69.98 v2(172.45,69.97) ; CE53.2 187.07,54 v2(186.79,54.28) ; RD56.2 RD55.2 146.28,19.04 v2(146.67,18.65) ; v2(111,62.52) 111.13,62.65 111.13,62.86 111.35,63.09 PC1345.2 PC1346.2 ; CE62.2 182.93,51.44 182.58,51.8 182.58,52.77 182.93,53.12 v2(182.93,53.3) ; v2(50.32,18.07) 50.52,17.87 C1201.2 50.95,20.1 U719.15 50.9,21.52 50.32,22.11 C1199.2 ; v2(167.79,14.18) 167.97,14.18 167.97,14.18 R1175.1 ; CD139.2 v2(140.31,16.77) ; PC1417.2 v2(204.65,74.81) ; CD158.2 128.49,31.75 129.13,31.12 v2(129.75,31.12) 129.8,31.07 130.01,31.07 130.02,31.07 130.65,31.07 CD175.2 CD174.2 ; v2(91.36,38.41) 91.5,38.55 RD19.2 ; PC906.2 170.31,37.83 v2(170.59,37.55) ; v2(105.64,19.11) 105.77,19.23 CD149.2 ; RD54.2 RD52.2 116.05,19.06 v2(116.84,18.27) ; CD178.2 v2(162.3,25.02) ; RE63.2 CE64.2 CE17.2 180.92,54.87 v2(180.51,54.46) 180.09,54.87 CE41.2 ; CC177.2 138.53,51.01 138.94,51.42 v2(139.29,51.42) ; RC242.1 RC312.1 148.76,68.31 v2(149.05,68.59) ; PC1099.1 76.04,55.84 v2(76.38,56.18) ; CD63.2 130.2,33.91 v2(129.77,33.49) 129.34,33.91 CD7.2 ; v2(159.37,16.54) 158.65,16.54 CD196.2 ; v2(129.17,26.41) 128.85,26.41 128.6,26.16 128.6,26.16 128.33,25.89 CD42.2 127.96,24.9 CD154.2 ; v2(139.67,63.14) 139.67,63.28 CC218.2 ; RC220.2 143.97,41.97 RC75.1 144.37,42 v2(144.63,41.74) ; RD25.2 92.53,36.51 v2(92.15,36.89) ; YC1.2 155.56,69.49 155.63,69.43 ; CE21.2 187.58,50.61 v2(187.3,50.33) ; C1169.2 v2(30.28,41.79) ; PC1353.2 114.63,63.2 v2(114.4,62.98) ; v2(112.95,66.74) 112.88,66.67 PC1229.2 113.45,66 114.33,66.87 RC91.2 ; CA5.2 37.66,27.23 37.13,27.76 v2(36.89,27.76) ; CA55.1 22.33,19.26 v2(22.15,19.08) ; v2(147.17,55.64) 146.96,55.85 RH153.2 ; CT151.2 v2(19.66,67.89) ; v2(92.33,39.09) 92.39,39.09 92.49,39.19 RD112.2 ; R1027.1 v2(204.14,43.09) ; v2(181.33,36.66) 181.08,36.41 R1187.1 ; C2983.2 v2(6.86,19.9) ; RE90.2 28.78,43.62 28.37,43.21 v2(28.36,43.21) ; RC293.1 R1216.2 22.76,52.31 21.69,51.24 21.49,51.24 v2(21.13,50.89) ; v2(107.75,62.52) 107.54,62.72 PC1258.2 PC1334.2 PC1346.2 ; PC1416.2 PC1415.2 ; PC217.2 55.55,19.52 v2(55.42,19.64) 55.04,19.26 R290.1 R1140.2 ; v2(22.28,27.15) 22.23,27.1 CA78.2 ; 66.45,14.16 65.91,14.69 PR270.2 ; 66.45,14.16 v2(66.45,13.78) ; v2(62.87,50.24) 62.33,50.77 PC1006.1 ; C1208.2 v2(59.16,79.59) ; PC1346.2 109.73,62.85 v2(109.73,62.52) ; PC1317.2 139.42,60.23 139.66,60.48 v2(139.66,60.69) ; v2(20.37,67.67) 20.83,68.13 C1354.2 ; RE97.2 v2(200.1,57.57) ; v2(207.37,19.77) 207.06,19.47 R1161.2 ; RE91.2 196.72,48.6 196.98,48.35 v2(197.33,48.35) ; v2(51.23,66.62) 50.97,66.35 RT5.2 ; PR268.2 PC211.2 84.43,74.48 84.37,74.55 v2(84.37,75.09) ; v2(144.17,43.93) 143.84,44.26 RC319.2 ; v2(39.22,37.63) 39.22,38.13 38.35,39 C1160.2 ; C1254.2 v2(170.1,15.3) ; v2(107.77,16.93) 107.19,16.93 CD132.2 ; v2(95.2,29.06) CD4.2 95.99,29.12 CD147.2 ; RC167.2 v2(138.28,57.97) ; CC260.2 124.57,50.64 CC174.2 124.56,51.32 v2(124.45,51.43) ; CD151.2 v2(104.88,19.1) ; PC807.2 170.88,79.5 170.88,78.27 171.87,77.28 v2(172.12,77.28) ; CD117.2 104.42,35.06 v2(103.95,34.59) ; PC1084.2 72.49,49.26 v2(73.02,49.26) ; RE2.1 v2(171.76,66.51) ; CA27.1 v2(34.54,29.17) ; C1211.2 v2(200.58,37.22) ; CD135.2 v2(119.1,16.77) ; C1143.2 v2(195.02,32.79) ; PR1094.2 PR1121.2 ; v2(166.48,24.19) 166.45,24.16 165.72,24.16 165.19,24.69 PC610.2 ; YT1.4 31.81,65.79 31.8,65.81 ; CC220.2 145.95,70.37 v2(145.7,70.12) ; CD33.2 101.44,35.41 v2(102.19,36.16) 102.51,35.84 CD152.2 ; v2(129.77,29.85) 129.77,29.85 CD157.2 ; C7.2 v2(185.83,17.69) ; RE68.2 174.12,68.86 v2(174.29,69.03) ; RE58.1 174.33,63.84 174.73,63.44 v2(174.73,63.28) ; PC1404.2 166.47,50.13 v2(166.5,50.1) ; v2(133.89,46.68) 134.09,46.88 CC31.2 ; C1102.1 166.17,14.72 v2(166.19,14.69) ; RD116.2 v2(156.82,39.2) ; C1292.2 v2(178.92,28.15) ; CD2.2 97.89,35.11 v2(98.87,34.14) ; v2(125.3,46.21) 124.76,46.21 124.59,46.38 CC35.2 ; v2(24.97,42.71) 24.22,42.71 23.53,43.39 UT6.9 ; RC141.2 137.01,72.13 PC1311.2 CC199.2 139.24,71.43 139.54,71.14 v2(139.54,70.81) ; PR1126.1 73.33,51.39 v2(73.23,51.29) ; PR272.2 v2(57.51,13.75) ; v2(95.61,24.39) 95.93,24.39 RD53.2 CD146.2 96.29,25.99 95.93,26.35 CD92.2 ; v2(64.24,46.06) PR1067.1 PC1020.1 ; PR1417.2 v2(204.42,71.21) ; C1325.2 v2(196.95,23.15) ; v2(34.6,30.21) 33.99,30.21 CA30.1 ; v2(92.94,72.73) PR230.2 PC205.2 ; C1322.2 v2(196.85,14.21) ; CD153.2 v2(95.58,23.73) ; PC102.1 v2(69.88,18.17) ; CC213.2 CC270.2 144.5,51.16 v2(144.26,51.4) ; v2(45.29,51.84) 44.98,51.52 44.98,50.81 CZ90.2 ; v2(119.1,78.19) 119.48,78.57 RC86.1 ; RD26.2 152.63,37.42 v2(152.27,37.79) ; CD180.2 v2(103.99,19.12) ; PQ219.1 v2(61.76,19.84) ; v2(31.45,37.58) C1214.2 C1212.2 ; C1168.2 198.1,38.57 v2(198.1,37.25) ; CD142.2 v2(124.05,16.77) ; RC96.2 CC267.2 ; RE103.2 200.95,54.5 201.75,55.3 v2(201.75,55.95) ; RT1.1 51.14,68.02 v2(51.39,68.02) ; v2(136.84,33.63) 137.17,33.96 137.17,35.1 CD119.2 ; C1289.2 25.93,53.7 25.54,53.31 25.54,52.36 v2(25.3,52.12) ; CD61.2 CD87.2 ; v2(25.29,39.57) 24.41,40.44 UT6.4 ; PC900.2 v2(170.56,44.31) ; CC280.2 CC279.2 158.28,41.32 v2(158.34,41.26) ; C1280.2 v2(14.03,56.33) ; v2(173.97,80.11) PC800.2 ; CD129.2 v2(146.91,16.77) ; v2(170.33,52.16) PC1403.2 ; C1309.2 v2(16.82,13.75) ; C1161.2 v2(179.93,26.88) ; PC617.2 PR608.2
  GND1 w0.203: H4.1 83.03,78.73 ; H4.1 80.89,80.87 ; H4.1 81.96,78.36 ; H4.1 83.4,79.8 ; H4.1 80.89,78.73 ; H4.1 80.52,79.8 ; H4.1 83.03,80.87 ; H4.1 81.96,81.24 ; JUSB2.11 14.61,39.68 ; JUSB2.11 16.13,38.73 ; JUSB2.11 13.1,39.68 ; JUSB2.11 14.61,37.78 ; JUSB2.11 13.1,38.73 ; JUSB2.11 16.13,37.78 ; JUSB2.11 13.1,37.78 ; JUSB2.11 16.13,39.68 ; 214.81,14.03 H13.1 ; H13.1 214.81,16.91 ; H13.1 215.88,14.4 ; H13.1 213.74,16.54 ; H13.1 213.74,14.4 ; H13.1 213.37,15.47 ; H13.1 216.25,15.47 ; H13.1 215.88,16.54 ; H18.1 53.96,14.38 ; H18.1 53.96,12.24 ; H18.1 51.82,14.38 ; H18.1 52.89,14.75 ; H18.1 51.45,13.31 ; H18.1 52.89,11.87 ; H18.1 54.33,13.31 ; H18.1 51.82,12.24 ; JUSB2.10 14.61,52.48 ; JUSB2.10 13.1,50.58 ; JUSB2.10 16.13,51.53 ; JUSB2.10 14.61,50.58 ; JUSB2.10 16.13,50.58 ; JUSB2.10 16.13,52.48 ; JUSB2.10 13.1,52.48 ; JUSB2.10 13.1,51.53 ; 102.48,76.37 H16.1 ; H16.1 102.48,73.33 ; H16.1 105.52,76.37 ; H16.1 105.52,73.33 ; H16.1 104,76.93 ; H16.1 104,72.77 ; H16.1 101.92,74.85 ; H16.1 106.08,74.85 ; JUSBC1.1 2.37,66.12 ; JUSBC1.1 0.84,65.39 ; JUSBC1.1 0.84,64.66 ; JUSBC1.1 3.6,66.12 ; JUSBC1.1 0.84,66.12 ; JUSBC1.1 3.6,65.39 ; JUSBC1.1 2.37,64.66 ; JUSBC1.1 3.6,64.66 ; H1.1 11.27,71.19 ; H1.1 11.27,69.05 ; H1.1 9.13,71.19 ; H1.1 10.2,68.68 ; H1.1 10.2,71.56 ; H1.1 9.13,69.05 ; H1.1 8.76,70.12 ; H1.1 11.64,70.12 ; 128.02,12.21 H7.1 ; H7.1 130.16,14.35 ; H7.1 127.65,13.28 ; H7.1 130.16,12.21 ; H7.1 128.02,14.35 ; H7.1 129.09,14.72 ; H7.1 130.53,13.28 ; H7.1 129.09,11.84 ; JUSB2.7 13.5,45.11 ; JUSB2.7 12.13,45.71 ; JUSB2.7 13.32,44.51 ; JUSB2.7 13.32,45.71 ; JUSB2.7 12.72,44.33 ; JUSB2.7 11.95,45.11 ; JUSB2.7 12.72,45.89 ; JUSB2.7 12.13,44.51 ; 162.8,72.77 H15.1 ; H15.1 164.88,74.85 ; H15.1 161.28,76.37 ; H15.1 160.72,74.85 ; H15.1 161.28,73.33 ; H15.1 164.32,73.33 ; H15.1 164.32,76.37 ; H15.1 162.8,76.93 ; 201.48,48.6 H17.1 ; H17.1 204.52,51.64 ; H17.1 205.08,50.12 ; H17.1 204.52,48.6 ; H17.1 201.48,51.64 ; H17.1 203,48.04 ; H17.1 200.92,50.12 ; H17.1 203,52.2 ; H19.1 111.11,12.24 ; H19.1 108.6,13.31 ; H19.1 111.48,13.31 ; H19.1 108.97,12.24 ; H19.1 108.97,14.38 ; H19.1 110.04,11.87 ; H19.1 110.04,14.75 ; H19.1 111.11,14.38 ; 38.42,72.3 H11.1 ; H11.1 38.98,70.78 ; H11.1 40.5,70.22 ; H11.1 40.5,74.38 ; H11.1 38.98,73.82 ; H11.1 42.58,72.3 ; H11.1 42.02,70.78 ; H11.1 42.02,73.82 ; H14.1 104,55.93 ; H14.1 104,51.77 ; H14.1 101.92,53.85 ; H14.1 105.52,55.37 ; H14.1 102.48,55.37 ; H14.1 102.48,52.33 ; H14.1 105.52,52.33 ; H14.1 106.08,53.85 ; JUSB2.12 5.53,53.92 ; JUSB2.12 5.53,52.97 ; JUSB2.12 3.12,52.97 ; JUSB2.12 4.33,53.92 ; JUSB2.12 3.12,53.92 ; 161.28,55.37 H10.1 ; H10.1 164.32,55.37 ; H10.1 160.72,53.85 ; H10.1 161.28,52.33 ; H10.1 164.32,52.33 ; H10.1 162.8,55.93 ; H10.1 164.88,53.85 ; H10.1 162.8,51.77 ; 188.2,21.04 H6.1 ; H6.1 188.2,25.2 ; H6.1 186.68,24.64 ; H6.1 186.12,23.12 ; H6.1 189.72,24.64 ; H6.1 190.28,23.12 ; H6.1 186.68,21.6 ; H6.1 189.72,21.6 ; JUSBC1.2 6.6,65.39 ; JUSBC1.2 4.14,66.11 ; JUSBC1.2 4.14,65.39 ; JUSBC1.2 5.37,64.67 ; JUSBC1.2 6.6,66.11 ; JUSBC1.2 5.37,66.11 ; JUSBC1.2 4.14,64.67 ; 1.45,19.88 SW3.4 ; SW3.4 2.54,19.88 ; SW3.4 2.7,19.33 ; SW3.4 2,20.03 ; SW3.4 1.45,18.79 ; SW3.4 2,18.63 ; SW3.4 2.54,18.79 ; JUSB2.4 14.82,41.01 ; JUSB2.4 13.63,42.21 ; JUSB2.4 14.23,40.83 ; JUSB2.4 13.45,41.61 ; JUSB2.4 14.23,42.39 ; JUSB2.4 15,41.61 ; JUSB2.4 14.82,42.21 ; JUSB2.4 13.63,41.01 ; 8.76,17.12 H12.1 ; H12.1 10.2,18.56 ; H12.1 10.2,15.68 ; H12.1 9.13,18.19 ; H12.1 11.64,17.12 ; H12.1 11.27,18.19 ; H12.1 11.27,16.05 ; H12.1 9.13,16.05 ; 5.37,55.47 JUSBC1.3 ; JUSBC1.3 5.37,56.91 ; JUSBC1.3 6.6,55.47 ; JUSBC1.3 4.14,55.47 ; JUSBC1.3 6.6,56.19 ; JUSBC1.3 4.14,56.19 ; JUSBC1.3 4.14,56.91 ; 2.37,55.46 JUSBC1.4 ; JUSBC1.4 3.6,56.92 ; JUSBC1.4 3.6,56.19 ; JUSBC1.4 3.6,55.46 ; JUSBC1.4 0.84,56.92 ; JUSBC1.4 0.84,55.46 ; JUSBC1.4 2.37,56.92 ; JUSBC1.4 0.84,56.19 ; 3.12,36.79 JUSB2.13 ; JUSB2.13 3.12,37.27 ; JUSB2.13 5.53,37.27 ; SW3.3 2.54,22.84 ; SW3.3 1.45,22.84 ; SW3.3 2.54,23.93 ; SW3.3 2,22.68 ; SW3.3 2.7,23.38 ; JUSBC1.B12 6.6,63.59 ; JUSBC1.B12 6.51,63.2 ; JUSBC1.B12 6.12,63.11 ; JUSBC1.B12 5.73,63.98 ; 182.82,78.36 H9.1 ; H9.1 181.75,80.87 ; H9.1 181.75,78.73 ; H9.1 183.89,80.87 ; H9.1 181.38,79.8 ; H9.1 183.89,78.73 ; H9.1 184.26,79.8 ; H9.1 182.82,81.24 ; 5.73,57.6 JUSBC1.B1 ; JUSBC1.B1 6.12,58.47 ; JUSBC1.B1 6.51,58.38
  GND2 w0.203: H14.1 106.08,53.85 ; H14.1 104,51.77 ; H14.1 105.52,52.33 ; H14.1 101.92,53.85 ; H14.1 102.48,55.37 ; H14.1 104,55.93 ; H14.1 102.48,52.33 ; H14.1 105.52,55.37 ; 14.61,50.58 JUSB2.10 ; JUSB2.10 13.1,50.58 ; JUSB2.10 13.1,52.48 ; JUSB2.10 16.13,52.48 ; JUSB2.10 16.13,50.58 ; JUSB2.10 14.61,52.48 ; JUSB2.10 16.13,51.53 ; JUSB2.10 13.1,51.53 ; H1.1 11.64,70.12 ; H1.1 9.13,69.05 ; H1.1 10.2,68.68 ; H1.1 11.27,69.05 ; H1.1 10.2,71.56 ; H1.1 9.13,71.19 ; H1.1 8.76,70.12 ; H1.1 11.27,71.19 ; SW3.4 2.54,19.88 ; SW3.4 2,20.03 ; SW3.4 1.45,18.79 ; SW3.4 2,18.63 ; SW3.4 1.45,19.88 ; SW3.4 2.54,18.79 ; SW3.4 2.7,19.33 ; H11.1 42.02,73.82 ; H11.1 40.5,70.22 ; H11.1 38.98,70.78 ; H11.1 42.02,70.78 ; H11.1 42.58,72.3 ; H11.1 38.98,73.82 ; H11.1 40.5,74.38 ; H11.1 38.42,72.3 ; 161.28,52.33 H10.1 ; H10.1 160.72,53.85 ; H10.1 162.8,51.77 ; H10.1 162.8,55.93 ; H10.1 161.28,55.37 ; H10.1 164.32,55.37 ; H10.1 164.88,53.85 ; H10.1 164.32,52.33 ; 3.12,37.27 JUSB2.13 ; JUSB2.13 5.53,37.27 ; JUSB2.13 3.12,36.79 ; 13.45,41.61 JUSB2.4 ; JUSB2.4 13.63,42.21 ; JUSB2.4 15,41.61 ; JUSB2.4 14.82,42.21 ; JUSB2.4 14.23,40.83 ; JUSB2.4 14.23,42.39 ; JUSB2.4 14.82,41.01 ; JUSB2.4 13.63,41.01 ; SW3.3 2.54,23.93 ; SW3.3 2,22.68 ; SW3.3 2.54,22.84 ; SW3.3 2.7,23.38 ; SW3.3 1.45,22.84 ; 5.37,64.67 JUSBC1.2 ; JUSBC1.2 6.6,66.11 ; JUSBC1.2 4.14,64.67 ; JUSBC1.2 4.14,66.11 ; JUSBC1.2 4.14,65.39 ; JUSBC1.2 5.37,66.11 ; JUSBC1.2 6.6,65.39 ; JUSBC1.3 6.6,55.47 ; JUSBC1.3 5.37,56.91 ; JUSBC1.3 4.14,55.47 ; JUSBC1.3 4.14,56.19 ; JUSBC1.3 4.14,56.91 ; JUSBC1.3 6.6,56.19 ; JUSBC1.3 5.37,55.47 ; JUSB2.12 5.53,52.97 ; JUSB2.12 3.12,53.92 ; JUSB2.12 3.12,52.97 ; JUSB2.12 4.33,53.92 ; JUSB2.12 5.53,53.92 ; 213.74,14.4 H13.1 ; H13.1 214.81,14.03 ; H13.1 215.88,14.4 ; H13.1 214.81,16.91 ; H13.1 215.88,16.54 ; H13.1 216.25,15.47 ; H13.1 213.74,16.54 ; H13.1 213.37,15.47 ; JUSB2.11 16.13,37.78 ; JUSB2.11 16.13,38.73 ; JUSB2.11 14.61,37.78 ; JUSB2.11 13.1,37.78 ; JUSB2.11 14.61,39.68 ; JUSB2.11 13.1,38.73 ; JUSB2.11 13.1,39.68 ; JUSB2.11 16.13,39.68 ; 161.28,76.37 H15.1 ; H15.1 160.72,74.85 ; H15.1 164.88,74.85 ; H15.1 162.8,72.77 ; H15.1 162.8,76.93 ; H15.1 164.32,73.33 ; H15.1 164.32,76.37 ; H15.1 161.28,73.33 ; H4.1 81.96,81.24 ; H4.1 80.89,78.73 ; H4.1 80.89,80.87 ; H4.1 81.96,78.36 ; H4.1 83.03,80.87 ; H4.1 83.4,79.8 ; H4.1 83.03,78.73 ; H4.1 80.52,79.8 ; H19.1 111.11,12.24 ; H19.1 108.97,12.24 ; H19.1 108.6,13.31 ; H19.1 111.11,14.38 ; H19.1 111.48,13.31 ; H19.1 110.04,11.87 ; H19.1 110.04,14.75 ; H19.1 108.97,14.38 ; H12.1 10.2,18.56 ; H12.1 11.27,16.05 ; H12.1 9.13,18.19 ; H12.1 8.76,17.12 ; H12.1 9.13,16.05 ; H12.1 11.27,18.19 ; H12.1 10.2,15.68 ; H12.1 11.64,17.12 ; 181.75,78.73 H9.1 ; H9.1 182.82,78.36 ; H9.1 184.26,79.8 ; H9.1 181.75,80.87 ; H9.1 183.89,78.73 ; H9.1 181.38,79.8 ; H9.1 183.89,80.87 ; H9.1 182.82,81.24 ; 102.48,76.37 H16.1 ; H16.1 104,76.93 ; H16.1 105.52,73.33 ; H16.1 106.08,74.85 ; H16.1 104,72.77 ; H16.1 105.52,76.37 ; H16.1 101.92,74.85 ; H16.1 102.48,73.33 ; 0.84,65.39 JUSBC1.1 ; JUSBC1.1 2.37,64.66 ; JUSBC1.1 0.84,66.12 ; JUSBC1.1 2.37,66.12 ; JUSBC1.1 3.6,65.39 ; JUSBC1.1 0.84,64.66 ; JUSBC1.1 3.6,64.66 ; JUSBC1.1 3.6,66.12 ; H18.1 53.96,12.24 ; H18.1 51.45,13.31 ; H18.1 52.89,11.87 ; H18.1 52.89,14.75 ; H18.1 51.82,12.24 ; H18.1 53.96,14.38 ; H18.1 51.82,14.38 ; H18.1 54.33,13.31 ; 200.92,50.12 H17.1 ; H17.1 204.52,48.6 ; H17.1 201.48,51.64 ; H17.1 203,52.2 ; H17.1 205.08,50.12 ; H17.1 201.48,48.6 ; H17.1 204.52,51.64 ; H17.1 203,48.04 ; 0.84,56.92 JUSBC1.4 ; JUSBC1.4 3.6,56.92 ; JUSBC1.4 0.84,56.19 ; JUSBC1.4 3.6,56.19 ; JUSBC1.4 0.84,55.46 ; JUSBC1.4 3.6,55.46 ; JUSBC1.4 2.37,56.92 ; JUSBC1.4 2.37,55.46 ; H7.1 129.09,14.72 ; H7.1 130.16,12.21 ; H7.1 130.16,14.35 ; H7.1 127.65,13.28 ; H7.1 128.02,14.35 ; H7.1 128.02,12.21 ; H7.1 130.53,13.28 ; H7.1 129.09,11.84 ; H6.1 189.72,21.6 ; H6.1 188.2,25.2 ; H6.1 186.68,24.64 ; H6.1 186.12,23.12 ; H6.1 188.2,21.04 ; H6.1 189.72,24.64 ; H6.1 190.28,23.12 ; H6.1 186.68,21.6 ; 5.73,63.98 JUSBC1.B12 ; JUSBC1.B12 6.6,63.59 ; JUSBC1.B12 6.51,63.2 ; JUSBC1.B12 6.12,63.11 ; JUSB2.7 13.32,44.51 ; JUSB2.7 11.95,45.11 ; JUSB2.7 12.72,45.89 ; JUSB2.7 13.5,45.11 ; JUSB2.7 12.13,44.51 ; JUSB2.7 12.13,45.71 ; JUSB2.7 12.72,44.33 ; JUSB2.7 13.32,45.71 ; JUSBC1.B1 6.12,58.47 ; JUSBC1.B1 6.51,58.38 ; JUSBC1.B1 5.73,57.6
  VCC w0.203: 102.48,52.33 H14.1 ; H14.1 104,51.77 ; H14.1 101.92,53.85 ; H14.1 105.52,55.37 ; H14.1 105.52,52.33 ; H14.1 102.48,55.37 ; H14.1 106.08,53.85 ; H14.1 104,55.93 ; 13.63,42.21 JUSB2.4 ; JUSB2.4 14.82,42.21 ; JUSB2.4 14.82,41.01 ; JUSB2.4 14.23,42.39 ; JUSB2.4 15,41.61 ; JUSB2.4 14.23,40.83 ; JUSB2.4 13.63,41.01 ; JUSB2.4 13.45,41.61 ; H17.1 204.52,51.64 ; H17.1 200.92,50.12 ; H17.1 201.48,51.64 ; H17.1 201.48,48.6 ; H17.1 204.52,48.6 ; H17.1 203,52.2 ; H17.1 203,48.04 ; 13.1,52.48 JUSB2.10 ; JUSB2.10 14.61,52.48 ; JUSB2.10 14.61,50.58 ; JUSB2.10 16.13,50.58 ; JUSB2.10 16.13,52.48 ; JUSB2.10 13.1,50.58 ; JUSB2.10 13.1,51.53 ; JUSB2.10 16.13,51.53 ; 14.61,37.78 JUSB2.11 ; JUSB2.11 16.13,37.78 ; JUSB2.11 13.1,39.68 ; JUSB2.11 13.1,37.78 ; JUSB2.11 14.61,39.68 ; JUSB2.11 16.13,38.73 ; JUSB2.11 13.1,38.73 ; JUSB2.11 16.13,39.68 ; JUSBC1.4 3.6,55.46 ; JUSBC1.4 3.6,56.19 ; JUSBC1.4 2.37,55.46 ; JUSBC1.4 3.6,56.92 ; JUSBC1.4 2.37,56.92 ; JUSBC1.1 3.6,64.66 ; JUSBC1.1 2.37,64.66 ; JUSBC1.1 3.6,65.39 ; 4.14,56.19 JUSBC1.3 ; JUSBC1.3 5.37,56.91 ; JUSBC1.3 6.6,55.47 ; JUSBC1.3 4.14,55.47 ; JUSBC1.3 4.14,56.91 ; JUSBC1.3 5.37,55.47 ; JUSB2.12 4.33,53.92 ; JUSB2.12 3.12,53.92 ; JUSB2.12 5.53,53.92 ; JUSB2.7 13.32,44.51 ; JUSB2.7 13.32,45.71 ; JUSB2.7 13.5,45.11 ; 4.14,64.67 JUSBC1.2 ; JUSBC1.2 4.14,65.39 ; JUSBC1.2 4.14,66.11
  GND3 w0.203: SW3.4 2,20.03 ; SW3.4 2.7,19.33 ; SW3.4 1.45,19.88 ; SW3.4 2,18.63 ; SW3.4 2.54,18.79 ; SW3.4 2.54,19.88 ; SW3.4 1.45,18.79 ; H7.1 130.16,14.35 ; H7.1 128.02,12.21 ; H7.1 129.09,11.84 ; H7.1 130.53,13.28 ; H7.1 127.65,13.28 ; H7.1 130.16,12.21 ; H7.1 128.02,14.35 ; H10.1 164.88,53.85 ; H10.1 164.32,52.33 ; H10.1 160.72,53.85 ; H10.1 162.8,55.93 ; H10.1 164.32,55.37 ; H10.1 161.28,55.37 ; H10.1 162.8,51.77 ; H10.1 161.28,52.33 ; H18.1 54.33,13.31 ; H18.1 53.96,14.38 ; H18.1 51.82,14.38 ; H18.1 52.89,11.87 ; H18.1 53.96,12.24 ; H18.1 51.82,12.24 ; H18.1 51.45,13.31 ; H18.1 52.89,14.75 ; 182.82,78.36 H9.1 ; H9.1 183.89,78.73 ; H9.1 181.38,79.8 ; H9.1 182.82,81.24 ; H9.1 183.89,80.87 ; H9.1 181.75,78.73 ; H9.1 181.75,80.87 ; H9.1 184.26,79.8 ; H12.1 10.2,18.56 ; H12.1 11.27,16.05 ; H12.1 11.27,18.19 ; H12.1 9.13,18.19 ; H12.1 11.64,17.12 ; H12.1 8.76,17.12 ; H12.1 10.2,15.68 ; H12.1 9.13,16.05 ; H4.1 83.03,80.87 ; H4.1 83.4,79.8 ; H4.1 83.03,78.73 ; H4.1 81.96,81.24 ; H4.1 81.96,78.36 ; H4.1 80.89,78.73 ; H4.1 80.52,79.8 ; H4.1 80.89,80.87 ; 14.61,50.58 JUSB2.10 ; JUSB2.10 16.13,51.53 ; JUSB2.10 16.13,52.48 ; JUSB2.10 13.1,52.48 ; JUSB2.10 14.61,52.48 ; JUSB2.10 13.1,50.58 ; JUSB2.10 16.13,50.58 ; JUSB2.10 13.1,51.53 ; 101.92,74.85 H16.1 ; H16.1 104,76.93 ; H16.1 104,72.77 ; H16.1 102.48,73.33 ; H16.1 105.52,73.33 ; H16.1 102.48,76.37 ; H16.1 105.52,76.37 ; H16.1 106.08,74.85 ; 4.14,55.47 JUSBC1.3 ; JUSBC1.3 6.6,56.19 ; JUSBC1.3 5.37,55.47 ; JUSBC1.3 4.14,56.91 ; JUSBC1.3 4.14,56.19 ; JUSBC1.3 5.37,56.91 ; JUSBC1.3 6.6,55.47 ; 5.37,64.67 JUSBC1.2 ; JUSBC1.2 6.6,65.39 ; JUSBC1.2 4.14,66.11 ; JUSBC1.2 6.6,66.11 ; JUSBC1.2 5.37,66.11 ; JUSBC1.2 4.14,65.39 ; JUSBC1.2 4.14,64.67 ; 108.97,12.24 H19.1 ; H19.1 111.11,12.24 ; H19.1 110.04,11.87 ; H19.1 111.48,13.31 ; H19.1 108.97,14.38 ; H19.1 108.6,13.31 ; H19.1 111.11,14.38 ; H15.1 164.32,73.33 ; H15.1 164.32,76.37 ; H15.1 162.8,76.93 ; H15.1 161.28,73.33 ; H15.1 162.8,72.77 ; H15.1 160.72,74.85 ; H15.1 161.28,76.37 ; H15.1 164.88,74.85 ; SW3.3 2.7,23.38 ; SW3.3 2.54,22.84 ; SW3.3 2.54,23.93 ; SW3.3 2,22.68 ; SW3.3 1.45,22.84 ; 12.13,44.51 JUSB2.7 ; JUSB2.7 13.32,44.51 ; JUSB2.7 12.13,45.71 ; JUSB2.7 12.72,44.33 ; JUSB2.7 11.95,45.11 ; JUSB2.7 12.72,45.89 ; JUSB2.7 13.5,45.11 ; JUSB2.7 13.32,45.71 ; 3.12,36.79 JUSB2.13 ; JUSB2.13 5.53,37.27 ; JUSB2.13 3.12,37.27 ; JUSBC1.1 2.37,66.12 ; JUSBC1.1 0.84,65.39 ; JUSBC1.1 0.84,64.66 ; JUSBC1.1 3.6,64.66 ; JUSBC1.1 3.6,65.39 ; JUSBC1.1 2.37,64.66 ; JUSBC1.1 3.6,66.12 ; JUSBC1.1 0.84,66.12 ; JUSB2.11 14.61,39.68 ; JUSB2.11 16.13,37.78 ; JUSB2.11 13.1,37.78 ; JUSB2.11 13.1,38.73 ; JUSB2.11 14.61,37.78 ; JUSB2.11 13.1,39.68 ; JUSB2.11 16.13,39.68 ; JUSB2.11 16.13,38.73 ; 186.12,23.12 H6.1 ; H6.1 186.68,24.64 ; H6.1 190.28,23.12 ; H6.1 186.68,21.6 ; H6.1 189.72,21.6 ; H6.1 189.72,24.64 ; H6.1 188.2,25.2 ; H6.1 188.2,21.04 ; 13.45,41.61 JUSB2.4 ; JUSB2.4 15,41.61 ; JUSB2.4 13.63,41.01 ; JUSB2.4 14.23,42.39 ; JUSB2.4 14.23,40.83 ; JUSB2.4 14.82,41.01 ; JUSB2.4 14.82,42.21 ; JUSB2.4 13.63,42.21 ; 2.37,55.46 JUSBC1.4 ; JUSBC1.4 3.6,55.46 ; JUSBC1.4 2.37,56.92 ; JUSBC1.4 3.6,56.92 ; JUSBC1.4 3.6,56.19 ; JUSBC1.4 0.84,56.19 ; JUSBC1.4 0.84,55.46 ; JUSBC1.4 0.84,56.92 ; 9.13,69.05 H1.1 ; H1.1 11.27,69.05 ; H1.1 10.2,68.68 ; H1.1 11.27,71.19 ; H1.1 8.76,70.12 ; H1.1 9.13,71.19 ; H1.1 10.2,71.56 ; H1.1 11.64,70.12 ; H14.1 106.08,53.85 ; H14.1 104,55.93 ; H14.1 104,51.77 ; H14.1 102.48,55.37 ; H14.1 102.48,52.33 ; H14.1 105.52,52.33 ; H14.1 105.52,55.37 ; H14.1 101.92,53.85 ; 201.48,51.64 H17.1 ; H17.1 204.52,48.6 ; H17.1 200.92,50.12 ; H17.1 203,52.2 ; H17.1 201.48,48.6 ; H17.1 203,48.04 ; H17.1 204.52,51.64 ; H17.1 205.08,50.12 ; 214.81,14.03 H13.1 ; H13.1 213.74,14.4 ; H13.1 215.88,16.54 ; H13.1 216.25,15.47 ; H13.1 213.74,16.54 ; H13.1 215.88,14.4 ; H13.1 213.37,15.47 ; H13.1 214.81,16.91 ; H11.1 42.58,72.3 ; H11.1 42.02,73.82 ; H11.1 40.5,70.22 ; H11.1 42.02,70.78 ; H11.1 38.98,73.82 ; H11.1 38.42,72.3 ; H11.1 40.5,74.38 ; H11.1 38.98,70.78 ; JUSB2.12 4.33,53.92 ; JUSB2.12 5.53,53.92 ; JUSB2.12 3.12,53.92 ; JUSB2.12 3.12,52.97 ; JUSB2.12 5.53,52.97
  BOTTOM w0.102: v3(47.17,57.24) 47.17,56.88 46.18,55.89 CT50.2 ; CT169.2 v3(45.59,67.55) ; v3(68.68,37.5) 68.92,37.74 C1273.2
  BOTTOM w0.127: UCPU1.AW16 142.95,51.75 143.38,51.32 143.82,51.32 143.91,51.4 v2(144.26,51.4) ; UCPU1.F37 131.17,68.98 130.79,69.36 130.79,69.94 130.91,70.06 130.91,70.48 130.99,70.56 130.99,70.58 131.1,70.7 131.48,70.7 131.86,70.32 UCPU1.D34 ; UCPU1.G66 114.21,68.35 113.24,69.32 UCPU1.F68 ; UCPU1.AK18 142.04,56.79
  BOTTOM w0.152: v2(118.22,49.09) 118.25,49.12 118.25,49.99 UCPU1.BB60 ; v2(149,53.74) 149,53.4 149.27,53.13 149.59,53.13 150.02,53.55 UCPU1.AT4 ; v2(150.9,71.18) 151.03,71.18 151.38,70.82 151.61,70.82 152.12,71.33 UCPU1.C1 ; UCPU1.AJ4 150.12,56.87 149.58,57.41 149.58,57.74 UCPU1.AH6
  BOTTOM w0.178: v2(110.71,58.72) 110.73,58.66 110.89,58.5 UCPU1.AG71 ; v2(141.71,48.9) 141.67,48.94 141.67,49.06 141.64,49.09 141.64,49.93 UCPU1.BB18 ; UCPU1.D6 149.38,70.32 149.85,70.79 UCPU1.C5 150.27,71.01 150.28,71 150.72,71 v2(150.9,71.18) ; UCPU1.G5 149.46,68.35 149.8,68.69 149.8,69.01 150.17,69.38 UCPU1.F4 150.52,69.11 150.83,69.11 151.14,69.42 UCPU1.F2 ; UCPU1.BB26 137.97,49.61 137.97,49.1 v2(138.02,49.05) ; UCPU1.BB64 115.92,50 115.9,49.97 115.9,49.11 v2(115.88,49.09) ; v2(130.67,49.03) 130.64,49.05 130.64,50 UCPU1.BB38 ; v2(110.72,53.5) 110.72,53.49 110.89,53.49 UCPU1.AT71 ; v2(110.74,55.76) 110.82,55.84 111.53,55.84 UCPU1.AM71 ; v2(133.07,48.22) 132.99,48.3 132.99,49.71 UCPU1.BB34 ; UCPU1.BB43 128.03,49.15 v2(127.99,49.11) ; UCPU1.BB30 135.62,49.93 135.61,49.92 135.61,49.03 v2(135.76,48.88) ; UCPU1.H71 110.96,68.09 v2(110.92,68.06)
  BOTTOM w0.203: UCPU1.AM13 144.95,56.12 145.16,56.12 145.21,56.17 145.31,56.17 UCPU1.AK11 ; 113.76,52.3 113.76,52.67 113.81,52.72 113.81,52.9 113.76,53.07 UCPU1.AT68 113.76,53.88 113.79,53.91 113.79,54.2 113.76,54.23 UCPU1.AP68 113.76,55.1 113.79,55.13 113.79,55.43 113.76,55.46 UCPU1.AM68 ; UCPU1.G10 146.56,68.29 v2(146.25,67.98) ; UCPU1.P20 140.63,64.25 140.23,64.25 140.11,64.36 UCPU1.P21 ; UCPU1.BA66 UCPU1.AY66 114.71,51.44 UCPU1.AW66 114.91,52.1 115.02,51.98 115.78,51.98 UCPU1.AW64 115.84,51.99 116.62,51.99 116.65,51.96 UCPU1.AW62 117.52,51.96 117.55,51.99 117.85,51.99 117.88,51.96 UCPU1.AW60 118.75,51.96 118.78,51.99 119.07,51.99 119.1,51.96 UCPU1.AW57 120.02,51.96 120.05,51.99 120.35,51.99 120.38,51.96 UCPU1.AW55 121.25,51.96 121.28,51.99 121.57,51.99 121.6,51.96 UCPU1.AW53 122.48,51.96 122.51,51.99 122.8,51.99 122.83,51.96 UCPU1.AW51 123.64,51.96 123.67,51.99 123.97,51.99 124,51.96 UCPU1.AW49 124.9,51.96 124.93,51.99 125.22,51.99 125.25,51.96 UCPU1.AW47 126.06,51.96 126.09,51.99 126.39,51.99 126.42,51.96 UCPU1.AW45 127.29,51.96 127.32,51.99 127.61,51.99 127.64,51.96 UCPU1.AW43 128.52,51.96 128.53,51.98 128.85,51.98 128.87,51.96 UCPU1.AW41 129.33,51.98 v2(129.82,52.47) 130.33,51.96 UCPU1.AW38 131.02,51.96 131.05,51.99 131.34,51.99 131.37,51.96 UCPU1.AW36 132.24,51.96 132.28,51.99 132.57,51.99 132.6,51.96 UCPU1.AW34 133.09,52.08 v2(133.45,52.45) 133.95,51.96 UCPU1.AW32 134.77,51.96 134.8,51.99 135.1,51.99 135.13,51.96 UCPU1.AW30 136,51.96 136.03,51.99 136.32,51.99 136.35,51.96 UCPU1.AW28 137.23,51.96 137.26,51.99 137.55,51.99 137.58,51.96 UCPU1.AW26 138.45,51.96 138.48,51.99 138.78,51.99 138.81,51.96 UCPU1.AW23 139.78,51.96 139.81,51.99 140.1,51.99 140.13,51.96 UCPU1.AW21 140.93,51.96 140.96,51.99 141.25,51.99 ; UCPU1.AM68 113.76,56.33 113.85,56.42 113.85,56.69 113.44,57.1 UCPU1.AK68 113.44,57.29 UCPU1.AH67 ; UCPU1.AM68 113.95,55.94 v2(114.25,55.64) ; UCPU1.BB55 120.86,49.14 v2(120.9,49.09) ; UCPU1.AL66 114.83,56.15 114.88,56.11 115.26,56.11 115.3,56.15 UCPU1.AL65 115.47,56.15 115.51,56.11 115.89,56.11 115.94,56.15 UCPU1.AL64 ; UCPU1.AW12 145.34,51.99 144.16,51.99 UCPU1.AW14 ; UCPU1.J28 135.34,67.77 135.34,67.17 v2(135.31,67.14) ; UCPU1.T21 139.7,63.14 v2(139.67,63.14) ; 141.25,51.99 141.28,51.96 UCPU1.AW18 142.2,51.96 142.23,51.99 142.52,51.99 142.55,51.96 UCPU1.AW16 ; 141.25,51.99 141.23,52.02 UCPU1.AU20 ; UCPU1.AF15 144.62,59.33 144.89,59.6 v2(145.04,59.6) ; PU300.22 43.97,30.51 44.07,30.62 44.07,30.95 v2(43.97,31.05) ; v2(41.18,61.72) 40.72,62.18 40.72,62.56 41.2,63.04 CT97.2 ; UCPU1.J25 137.11,67.09 v2(136.93,66.91) ; v2(152.53,69.76) 152.5,69.73 152.5,69.67 152.3,69.46 UCPU1.F1 ; JEDP.27 v2(191.06,37.37) ; UCPU1.D44 UCPU1.D45 126.28,70.36 125.9,70.36 125.88,70.33 125.58,70.33 125.55,70.36 UCPU1.D47 UCPU1.D48 ; v2(10.88,58.78) 10.88,59.47 10.57,59.78 D91.2 ; v2(191.76,41.72) 191.91,41.87 JEDP.36 ; UCPU1.F38 v2(129.8,68.54) UCPU1.F40 ; D84.2 v2(10.2,64.5)
  BOTTOM w0.254: UCPU1.U10 146.79,62.99 146.97,62.72 146.97,62.7 147.44,62.24 UCPU1.W9 147.41,62.2 147.08,61.87 v2(147.08,61.79) ; v2(150.54,72.82) 150.36,72.82 UCPU1.A5 ; UCPU1.AT35 v2(131.63,53.74) UCPU1.AR35 ; UCPU1.E65 115.37,69.65 115.23,69.8 115,69.8 114.58,70.22 UCPU1.D66 v2(114.58,70.84) UCPU1.B66 ; JNGFF2.27 183.89,29.79 184.38,30.29 184.38,30.33 v2(184.42,30.33) ; UCPU1.AG18 UCPU1.AG19 141.33,58.55 140.79,58.55 UCPU1.AG20 140.41,58.17 v2(140.41,58.01) ; UCPU1.AG18 UCPU1.AG17 142.69,58.41 v2(143.03,58.07) 143.03,58.18 UCPU1.AG16 ; UCPU1.AG18 UCPU1.AJ18 ; UCPU1.AM27 v2(136.2,55.66) ; UCPU1.AA65 v2(115.75,61.12) ; v2(138.96,68.59) 139.27,68.29 UCPU1.G22 139.33,68.22 139.33,67.43 UCPU1.K22 ; v2(138.96,68.59) 139.05,68.59 139.4,68.94 UCPU1.F22 ; v2(138.96,68.59) 138.9,68.59 138.56,68.94 UCPU1.F23 ; UCPU1.AP35 v2(131.63,54.37) ; UCPU1.BA57 v2(119.56,51.43) UCPU1.AW57 119.56,52.38 v2(119.66,52.48) ; UCPU1.AW62 v2(117.08,51.43) UCPU1.BA62 ; UCPU1.B62 117.05,70.84 v2(117.04,70.82) 116.95,70.73 116.95,70.42 UCPU1.D62 ; UCPU1.AR5 v2(149,53.74) ; UCPU1.AW28 v2(136.79,51.43) UCPU1.BA28 ; v2(191.75,38.97) 191.84,38.87 192.75,38.87 JEDP.30 ; UCPU1.G48 v2(124.38,68.59) ; UCPU1.AU32 v2(133.45,52.45) ; v2(145.04,59.6) 145.04,59.86 UCPU1.AD13 ; PU1102.11 81.99,61.18 82.45,60.71 ; v2(184.38,26.63) 184.13,26.63 183.96,26.79 JNGFF2.15 ; v2(125.25,53.74) 125.68,54.08 UCPU1.AR46 ; UCPU1.AL35 v2(132.54,57.27) ; UCPU1.AP28 v2(135.28,55.01) UCPU1.AN28 ; UCPU1.AR20 141.23,54.1 141.23,53.98 140.92,53.74 v2(140.77,53.74) ; v2(141.67,69.78) 141.95,69.78 UCPU1.E18 ; UCPU1.AH63 116.67,57.93 116.67,57.89 v2(116.31,57.43) ; v2(105.25,44.39) 105.28,44.42 105.28,44.69 105.07,44.9 104.88,44.9 104.88,44.9 UC2.3 ; v2(149.74,61.72) 149.74,61.73 ; 149.74,61.73 149.96,61.51 UCPU1.AA4 UCPU1.AA2 ; 149.74,61.73 149.39,62.08 UCPU1.W6 ; UCPU1.BA49 v2(124.45,51.43) UCPU1.AW49 ; v2(204.45,77.5) 204,77.95 U729.3 ; UCPU1.AF2 150.85,58.86 v2(150.62,58.63) 150.4,58.86 UCPU1.AF4 ; UCPU1.E46 125.59,69.68 125.42,69.68 v2(125.22,69.88) 125.16,69.94 UCPU1.D47 124.72,70.8 124.72,71.11 124.52,71.31 124.52,71.31 UCPU1.B48 ; UCPU1.F8 v2(147.17,69.18) ; v2(10.39,61.91) 10.2,62.1 D85.2 ; v2(152.86,52.05) 152.5,52.05 152.38,52.17 UCPU1.AV1 ; UCPU1.F65 UCPU1.G65 115.48,68.35 115.72,68.11 116.24,68.11 UCPU1.G63 116.68,68.35 v2(117.06,67.97) 117.45,67.58 UCPU1.K61 ; UCPU1.AP20 141.23,54.72 v2(140.74,54.32) ; v2(147.2,52.5) 147.07,52.5 146.77,52.8 UCPU1.AU10 ; v2(147.2,52.5) 147.74,51.96 UCPU1.AW8 ; v2(147.2,52.5) 146.66,51.96 UCPU1.AW10 ; v2(148.06,69.91) 148.06,69.88 148.35,69.59 UCPU1.E6 ; v2(114.43,57.48) 114.18,57.82 114.09,57.91 UCPU1.AH67 ; UCPU1.AL48 125.68,56.07 UCPU1.AM46 126.03,55.71 v2(126.19,55.71) ; UCPU1.B18 v2(141.83,70.79) UCPU1.D18 ; UCPU1.D44 v2(126.97,70.84) UCPU1.B44 ; UCPU1.B10 UCPU1.D10 UCPU1.D11 146.04,70.36 v2(145.7,70.12) 145.8,70.02 UCPU1.E11 ; UCPU1.G52 122.43,68.8 122.43,69.19 UCPU1.E53 121.99,69.59 121.84,69.73 121.84,70.16 UCPU1.D53 v2(122.01,70.81) UCPU1.B53 ; v2(140.41,58.01) 140.09,58.34 UCPU1.AG21 ; v2(140.41,58.01) 140.74,57.69 UCPU1.AJ20 140.74,57.47 UCPU1.AK21 139.92,56.99 UCPU1.AK22 ; UCPU1.AN63 116.42,55.3 116.28,55.16 116.26,55.16 v2(116.08,55.01) ; JEDP.11 192.75,29.37 191.29,29.37 v2(191.24,29.42) ; UCPU1.AU15 143.85,52.68 143.85,52.25 UCPU1.AW14 144.13,51.53 v2(144.26,51.4) 144.26,51.23 144.13,51.1 UCPU1.BA14 ; 131.67,68.55 131.69,68.55 UCPU1.F35 132.3,69.16 ; 131.67,68.55 131.63,68.51 UCPU1.J35 ; 131.67,68.55 131.56,68.55 UCPU1.F37 ; UCPU1.AP58 v2(118.82,54.37) ; v2(147.09,67.32) 147.1,67.32 UCPU1.J8 ; UCPU1.AF1 151.84,58.91 152.41,58.91 v2(152.46,58.86) ; v2(45.73,58.47) 45.25,58.47 TC43.1 ; v2(126.18,53.74) 126.18,53.76 126.53,54.1 UCPU1.AR45 ; v2(142.4,62.24) 142.69,62.53 UCPU1.V17 ; v2(142.4,62.24) 142.04,62.6 UCPU1.V18 ; v2(142.4,62.24) 142.69,61.95 UCPU1.Y17 ; UCPU1.AW12 145.73,51.96 v2(146.08,52.31) 146.21,52.31 UCPU1.AW10 ; UCPU1.B34 132.01,71.25 132.01,70.41 UCPU1.D34 132.39,69.86 v2(132.54,69.86) 132.54,69.4 132.3,69.16 ; UCPU1.AP68 v2(113.19,54.67) UCPU1.AP70 ; v2(117.29,60.68) 117.16,60.55 UCPU1.AD62 ; UCPU1.G55 v2(120.63,68.54) ; JEDP.17 192.75,32.37 191.82,32.37 v2(191.54,32.65) 191.76,32.87 192.75,32.87 JEDP.18 ; UCPU1.AV68 113.72,52.34 113.26,52.34 v2(113.24,52.36) 113.12,52.25 112.94,52.25 UCPU1.AV69 UCPU1.AV70 UCPU1.AV71 111.02,52.1 v2(110.89,51.97) ; v2(126.85,51.43) UCPU1.BA45 ; UCPU1.K18 UCPU1.H18 142.14,67.67 v2(141.68,67.93) ; v2(145.24,61.56) 145.24,61.57 144.84,61.98 UCPU1.W13 ; UCPU1.L4 150.48,66.81 v2(150.65,66.64) 150.83,66.81 UCPU1.L2 ; UCPU1.Y21 140.09,61.75 v2(139.74,61.4) 140.09,61.05 UCPU1.AB21 ; UCPU1.Y21 140.09,62.03 v2(139.65,62.46) ; UCPU1.Y21 UCPU1.Y20 140.8,61.79 141.33,61.79 UCPU1.Y19 ; UCPU1.L20 140.74,65.98 140.29,65.54 140.29,65.4 UCPU1.N21 140.04,65.2 139.66,65.57 v2(139.66,65.72) ; UCPU1.T4 150.48,64.16 v2(150.65,63.98) 150.83,64.16 UCPU1.T2 ; 139.32,51.42 139.32,51.91 UCPU1.AW23 ; 139.32,51.42 v2(139.29,51.42) ; 139.32,51.42 139.32,50.79 UCPU1.BA23 ; UCPU1.BA41 v2(129.33,51.43) UCPU1.AW41 ; UCPU1.L16 143.29,66.04 142.99,65.65 v2(142.99,65.59) 142.69,65.98 UCPU1.L17 ; UCPU1.AM45 v2(127.05,55.63) UCPU1.AL45 ; JAPS1.10 201.33,31.39 v2(201.65,31.71) ; RT37.1 45.26,51.86 v2(45.29,51.84) ; JEDP.15 192.08,31.37 v2(191.8,31.66) 192.01,31.87 JEDP.16 ; D90.2 10.39,61.17 v2(11.02,61.81) ; UCPU1.AD19 141.39,60.22 141.69,60.52 v2(141.69,60.59) 142.04,60.94 UCPU1.AB18 ; UCPU1.AD20 UCPU1.AD21 140.09,60.28 139.66,60.7 v2(139.66,60.69) ; v2(148.37,65.88) UCPU1.L8 ; UCPU1.B39 129.65,71.13 v2(129.65,70.82) 129.65,70.52 UCPU1.D39 ; UCPU1.AM43 v2(127.97,55.63) 128.19,55.63 UCPU1.AN42 ; UCPU1.U70 v2(112.45,62.98) UCPU1.U69 ; UCPU1.AB16 143.68,61.35 v2(143.68,61.43) 143.99,61.12 UCPU1.AB15 ; v2(123.34,69.9) 123.65,69.59 UCPU1.E50 ; UCPU1.AN20 141.2,55.4 140.85,55.09 140.81,55.09 v2(140.79,55.11) ; v2(127.97,54.4) 128.4,54.75 UCPU1.AP42 128.63,54.75 128.88,55.01 UCPU1.AN40 ; v2(124.32,53.74) 124.77,54.09 UCPU1.AR48 ; UCPU1.AL32 v2(134.37,57.21) ; UCPU1.N65 115.39,65.39 115.06,65.72 v2(114.33,65.72) 113.89,65.62 UCPU1.N68 ; 142.04,56.79 142.04,56.61 v2(141.68,56.25) ; UCPU1.AW10 UCPU1.BA10 ; v2(116.31,57.43) 116.06,57.82 116.06,57.93 UCPU1.AH64 ; v2(116.31,57.43) 116.61,57.04 116.69,57.04 UCPU1.AK63 UCPU1.AM61 v2(116.99,55.66) ; UCPU1.E21 140.09,69.59 UCPU1.D22 139.54,70.5 v2(139.54,70.81) 139.54,71.15 139.36,71.33 UCPU1.B22 ; v2(112.45,60.28) 112.47,60.26 112.47,60.08 UCPU1.AE69 UCPU1.AE68 UCPU1.AE67 UCPU1.AE66 UCPU1.AE65 ; UCPU1.AT63 v2(116.08,53.74) UCPU1.AR63 ; v2(138.13,44.31) 138.17,44.31 138.99,43.49 138.99,42.63 139.5,42.12 140.61,42.12 140.92,42.43 140.92,43.39 140.69,43.62 CR26.1 ; v2(37.17,58.91) 36.99,58.73 CT171.2 ; UCPU1.AK16 143.04,57.12 v2(143.04,57.24) ; UCPU1.AU20 141.23,52.8 v2(140.77,53.1) 141.23,53.45 UCPU1.AT20 ; PU1100.11 81.92,45.32 82.08,45.16 ; RT49.1 41.31,55.14 v2(41.25,55.21) ; UCPU1.K65 UCPU1.K64 v2(116.31,66.63) UCPU1.K63 ; 136.99,70.86 v2(136.99,70.86) ; 136.99,70.86 136.99,70.44 136.92,70.36 ; 136.99,70.86 137.4,70.86 UCPU1.C25 ; v2(112.71,69.97) 112.72,69.97 UCPU1.D69 UCPU1.F68 ; UCPU1.AW36 v2(131.81,51.43) UCPU1.BA36 ; UCPU1.AP18 142.12,54.73 v2(141.68,54.37) ; JAPS1.12 200.76,30.39 201.55,30.39 v2(201.68,30.26) ; 133.37,68.6 133.03,68.94 UCPU1.F33 133,68.98 132.82,69.16 132.3,69.16 ; 133.37,68.6 133.37,68.59 133.58,68.59 133.91,68.92 UCPU1.F32 ; 133.37,68.6 133.45,68.52 UCPU1.J32 ; UCPU1.F42 128.41,68.94 127.9,68.59 ; UCPU1.AA68 v2(113.77,61.12) ; UCPU1.AR42 v2(127.97,53.74) UCPU1.AT42 ; UCPU1.AN38 130.25,55.31 130.6,55.01 v2(130.71,55.01) UCPU1.AN37 ; UCPU1.BA53 v2(122.04,51.43) UCPU1.AW53 ; UCPU1.A67 113.9,72.49 113.45,72.94 v2(113.45,73) ; 127.9,68.59 127.95,68.54 127.95,67.84 UCPU1.J42 ; 127.9,68.59 127.51,68.31 UCPU1.G43 127.43,68.29 v2(127.1,68.62) ; UCPU1.AM21 v2(139.85,55.64) ; UCPU1.AL65 115.39,55.87 v2(115.17,55.64) ; v2(149.76,63.88) 149.49,64.33 UCPU1.R6 ; v2(184.46,34.3) 183.15,34.3 JNGFF2.45 ; UCPU1.E56 120.07,69.71 119.85,69.71 v2(119.72,69.85) 119.72,69.85 119.53,70.04 UCPU1.D58 UCPU1.B58 ; v2(184.25,37.42) 184.12,37.3 JNGFF2.57 ; UCPU1.AR23 v2(138.03,53.74) UCPU1.AT23 ; v2(145.16,57.36) 144.84,57.69 UCPU1.AH13 144.8,57.97 144.31,57.97 UCPU1.AJ15 ; CC95.2 156.34,56.32 156.59,56.57 156.59,57.06 RC19.2 ; v2(114.02,49.18) 113.9,49.3 UCPU1.BB67 ; v2(137.11,55.66) UCPU1.AM25 ; UCPU1.AL38 v2(130.71,57.26) ; UCPU1.AT58 v2(118.82,53.74) UCPU1.AR58 ; v2(191.36,28.66) 191.58,28.87 192.75,28.87 JEDP.10 ; UCPU1.AE65 UCPU1.AE64 UCPU1.AF63 ; UCPU1.AE65 115.39,59.8 115.82,60.23 v2(115.85,60.23) ; v2(43.78,64.32) 43.89,64.43 CT161.2 CT160.2 ; UCPU1.AT28 v2(135.28,53.74) UCPU1.AR28 ; UCPU1.AP23 v2(138.03,55.01) UCPU1.AN23 ; UCPU1.AD16 142.98,59.81 v2(142.98,59.73) 142.98,59.62 UCPU1.AF17 ; UCPU1.B30 134.17,71.11 v2(134.17,70.82) 134.17,70.55 UCPU1.D30 ; UCPU1.AR43 v2(127.05,53.74) ; v2(143.51,53.74) UCPU1.AR15 ; UCPU1.AR11 145.8,54.08 145.8,54.06 v2(145.39,53.74) ; v2(146.49,59.58) 146.49,59.51 146.79,59.22 UCPU1.AF10 ; 82.35,53.25 81.99,53.61 PU1101.11 ; 191.57,30.34 191.6,30.37 JEDP.13 ; 191.57,30.34 191.57,30.29 191.98,29.87 192.75,29.87 JEDP.12 ; 191.57,30.34 v2(191.54,30.36) ; UCPU1.A70 UCPU1.B71 111.01,71.85 v2(110.97,71.89) ; UCPU1.AK27 136.65,57.91 v2(136.55,58.01) ; v2(122.46,53.74) 122.58,53.74 UCPU1.AR52 ; JAPS1.14 v2(199.92,29.39) ; v2(114.25,55.64) 114.74,56.13 UCPU1.AL66 ; UCPU1.G6 148.26,68.57 v2(148.06,68.57) ; v2(31.55,39.96) 31.25,39.67 JNGFF1.1 ; UCPU1.AN32 v2(133.45,55.01) ; UCPU1.T17 142.52,63.36 142.21,63.36 UCPU1.T18 142.04,63.58 v2(141.71,63.92) 141.39,64.23 UCPU1.P19 ; UCPU1.AK69 112.77,57.17 112.95,57.35 113.26,57.35 UCPU1.AK68 ; UCPU1.F13 144.59,69.23 v2(144.43,69.23) 144.33,69.23 UCPU1.E15 ; UCPU1.BA32 v2(134.29,51.43) UCPU1.AW32 ; v2(37.21,55.65) 38.05,56.49 CT178.2 ; UCPU1.G5 149.35,68.29 v2(149.05,68.59) ; UCPU1.AN30 v2(134.37,55.01) ; JNGFF1.10 35.5,47.52 35.74,47.76 37.07,47.76 ; v2(182.78,72.53) 182.78,72.42 183.65,71.55 JLPDE1.9 ; v2(129.82,52.47) 130.25,52.78 UCPU1.AU38 ; 136.92,70.36 UCPU1.D25 ; 136.92,70.36 UCPU1.D26 ; JEDP.33 v2(191.77,40.37) ; UCPU1.AY71 111.42,50.8 v2(111.08,50.46) 111.39,50.15 UCPU1.BA71 111.49,49.95 v2(111.15,49.62) 111.18,49.59 111.85,49.59 UCPU1.BB70 ; UCPU1.AN35 v2(131.63,55.01) ; D89.2 10.05,58.77 9.79,59.03 v2(9.64,59.03) ; JNGFF2.9 182.18,25.29 182.07,25.41 181.71,25.41 v2(181.41,25.11) ; UCPU1.L11 146.53,65.79 v2(146.61,65.87) 146.61,65.58 UCPU1.N10 ; v2(120.63,53.74) 120.75,53.74 UCPU1.AR55 ; UCPU1.AR53 121.94,54.1 121.64,53.81 v2(121.54,53.81) ; v2(9.87,56.17) 10.08,56.38 10.08,56.74 D88.2 ; UCPU1.G60 118.37,68.32 v2(118.78,68.55) 119.25,68.29 UCPU1.G58 ; v2(111.9,77.85) 111.86,77.81 CA32.2 ; JAPS1.8 v2(201.61,32.39) ; v2(184.38,28.43) 184.28,28.43 184.14,28.29 183.15,28.29 JNGFF2.21 ; UCPU1.AR16 v2(142.6,53.74) ; RT43.1 42.66,55.13 v2(42.66,55.12) ; UCPU1.AL2 150.84,56.21 150.67,56.37 v2(150.67,56.41) 150.67,56.42 150.46,56.21 UCPU1.AL4 UCPU1.AJ4 ; v2(110.93,70.06) 111.1,69.9 UCPU1.E71 ; UC12.3 142.08,79.01 141.86,78.79 v2(141.86,78.06) ; v2(120.66,55.71) 121,56.05 UCPU1.AM55 ; v2(136.11,57.3) 136.2,57.22 UCPU1.AL28 ; UCPU1.J38 v2(129.8,68.54) ; UCPU1.J13 UCPU1.J11 145.92,66.99 v2(146.23,67.3) ; UCPU1.K66 UCPU1.K67 113.66,67.05 UCPU1.K68 113.35,66.74 v2(112.95,66.74) UCPU1.K70 UCPU1.K71 ; UCPU1.AN33 v2(132.54,55.01) ; UCPU1.AP63 v2(116.08,54.37) ; CA111.2 30.2,25.03 v2(30.73,25.56) ; v2(210.81,17.02) 210.86,16.97 JIO1.62 ; v2(147.74,57.43) 148.09,57.08 UCPU1.AK8 ; v2(143.68,66.46) UCPU1.K16 143.97,67.51 UCPU1.H15 ; UCPU1.L18 142,66.04 v2(141.73,65.67) 141.39,65.25 UCPU1.N19 141.39,65.18 v2(141.04,64.75) 140.75,64.36 UCPU1.P20 ; UCPU1.AY3 150.83,50.85 151.37,50.31 UCPU1.BA2 151.65,50.15 UCPU1.BA1 152.27,49.99 v2(152.66,49.99) ; UCPU1.U67 v2(114.4,62.98) UCPU1.U66 115.14,63.02 115.64,63.02 UCPU1.U64 UCPU1.U63 ; PC203.2 59.26,57.32 59.17,57.23 v2(57.78,57.23) ; JNGFF2.51 183.15,35.79 v2(184.46,35.79) ; UCPU1.R13 144.93,64.43 144.93,65.3 UCPU1.N13 144.65,65.4 v2(144.41,65.65) ; UCPU1.B14 144.31,71.07 v2(144.12,70.87) 144.31,70.68 UCPU1.D14 ; UCPU1.AW6 148.95,51.94 v2(148.95,51.4) 148.98,51.38 UCPU1.BA6 UCPU1.BB6 ; UCPU1.BA18 141.84,50.87 v2(141.84,51.32) 141.84,51.83 UCPU1.AW18 ; UCPU1.AN58 v2(118.82,55.01) ; UCPU1.T15 143.68,63.21 v2(143.68,63.1) 143.34,62.77 UCPU1.V16 ; UCPU1.AT4 UCPU1.AT2 ; UCPU1.P17 v2(142.36,64.78) ; UCPU1.AM60 v2(117.91,55.66) ; v2(19.7,40.03) 19.63,40.09 DI1.8 DI1.3 ; v2(181.48,31.73) 181.99,31.73 182.43,31.3 183.15,31.3 JNGFF2.33 ; UCPU1.F27 136.39,69.2 136,69.2 UCPU1.F28 135.5,68.94 v2(135.18,68.62) ; UCPU1.AP38 v2(129.8,54.37) ; JNGFF2.39 v2(184.46,32.79) ; UCPU1.G45 v2(126.19,68.59) ; UCPU1.AP10 146.98,54.75 147.17,54.95 v2(147.17,55.64) UCPU1.AM8 ; UCPU1.N6 149.39,65.37 v2(149.03,65.02) ; v2(144.37,55.72) 144.4,55.72 144.78,56.06 144.79,56.06 UCPU1.AM13 ; UCPU1.AP32 v2(133.45,54.37) ; UCPU1.AB8 148.11,61.13 148.4,60.85 v2(148.4,60.7) 148.4,60.49 148.09,60.18 UCPU1.AD8 ; v2(147.17,53.74) UCPU1.AR8
  BOTTOM w0.305: v2(38.38,17.59) 38.58,17.4 39.03,17.4 JKB1.16 ; JDEG1.10 174.15,68.9 v2(174.29,69.03) ; v2(39.22,37.63) 39.25,37.66 JNGFF1.25 39.25,39.74 39.03,39.96 38.5,39.96 38.25,39.71 JNGFF1.21 ; JIO1.1 210.21,16.42 v2(210.21,16.42) ; v2(206.91,17.61) 206.91,17.62 206.91,18.41 JIO1.12 ; UCPU1.AT56 120.49,53.74 v2(120.63,53.74) ; JKB1.14 40.42,20.36 40.42,19.2 v2(40.64,18.98) 40.21,18.98 39.92,19.27 39.92,20.36 JKB1.15 ; v2(191.8,17.41) 191.56,17.18 191.56,15.91 JIO1.63 ; JNGFF1.22 38.5,46.32 38.5,45.21 v2(38.54,45.16) 38.57,45.14 39.75,45.14 40,45.39 JNGFF1.28 ; JNGFF1.31 40.75,38.78 40.75,39.49 41.52,40.26 v2(41.69,40.26) ; v2(9.65,59.9) 9.46,59.71 C401.1 ; JNGFF1.55 46.75,38.77 46.75,37.92 47.27,37.4 v2(47.35,37.4) ; v2(208.7,17.67) 208.71,17.68 JIO1.6 ; JTP1.4 185.16,19.36 185.16,20.17 v2(184.95,20.38) ; JNGFF1.61 48.25,37.69 48.48,37.46 ; UCPU1.AL52 123.34,56.58 v2(123.34,57.34) ; JNGFF1.16 37,47.69 v2(37.07,47.76) ; v2(32.94,40.01) 32.75,39.82 32.75,38.78 JNGFF1.7 ; RC4.2 156.67,54.11 157.69,54.11 v2(157.73,54.15) ; v2(209.11,16.28) 209.01,16.18 209.01,15.54 JIO1.5 ; JKB1.13 40.92,19.85 41.22,19.54 41.63,19.54 v2(42.11,19.06) ; v2(42.44,37.58) 42.25,37.77 JNGFF1.37 ; UCPU1.AL58 119.74,57.33 v2(119.76,57.35) ; 48.48,37.46 49.29,37.46 49.75,37.92 JNGFF1.67 ; 48.48,37.46 v2(48.46,37.45) ; JIO1.7 208.41,15.54 208.41,16.27 v2(208.48,16.34) ; v2(36.78,37.63) 36.75,37.66 36.75,38.77 JNGFF1.15 ; UCPU1.AM27 136.72,56.05 v2(137.11,55.66) ; JNGFF1.43 43.75,39.56 43.75,39.56 43.75,39.9 v2(44.04,40.19) 44.7,40.19 45.25,39.65 45.25,38.78 JNGFF1.49 ; CC212.2 157.18,61.63 v2(157.18,62.59) ; UCPU1.AR50 123.87,54.1 124.23,53.74 v2(124.32,53.74) ; UCPU1.AL55 v2(121.57,57.42)
  BOTTOM w0.356: v2(171.54,59.68) 171.48,59.62 171.48,59.6 171.44,59.56 171.44,59.04 171.85,58.63 PC402.2 ; v2(37.29,51.56) 37.49,51.76 RT3.1 ; v2(35.69,51.72) 36.22,52.26 RT38.1 ; v2(48.48,61.52) 48.48,61.63 48.83,61.98 CT62.2 49.62,61.98 CT68.2 CT67.2 ; RT39.1 38.68,51.69 v2(38.51,51.51)
  BOTTOM w0.381: UE4.6 30.96,18.83 29.92,18.83 v2(29.9,18.8) ; U683.3 187.3,40.63 187.7,41.03 v2(187.7,41.09) ; v2(81.74,73.11) 81.19,73.66 79.65,73.66 RC136.1 ; PR413.2 165.71,58.8 165.32,58.41 v2(165.08,58.41) ; PC1401.2 179.17,51.29 178.56,50.68 PC1409.2 178.83,50.11 v2(179.29,50.11) ; CT149.2 44.42,61.73 v2(44.43,61.72) ; v2(48.67,22.87) 48.54,23 47.32,23 C376.2 ; v2(189.92,47.74) 190.48,47.17 C616.2 ; CT63.2 CT66.2 47.59,58.24 47.97,57.86 v2(48.44,57.86) ; CE68.2 177.98,56.6 177.98,57.26 v2(177.8,57.44) 178.12,57.76 178.12,58.49 CE50.2 ; v2(190.9,53.79) 190.52,53.79 190.14,54.17 190.14,57.75 190.59,58.19 190.59,59.96 190.93,60.3 191.3,60.3 UC10.3 ; R1473.2 22.81,61.86 22.14,62.52 v2(21.99,62.52) ; v2(157.3,59.01) RH556.2 ; CT153.2 CT178.2 ; RH443.2 161.49,62.98 v2(160.53,62.01) ; CT176.2 43.04,60.98 v2(43.13,61.07) 43.65,60.55 CT154.2 CT175.2 ; C1302.2 42.29,35.95 41.73,36.51 v2(41.73,36.89) ; CE54.2 186.4,64.27 v2(186.39,64.28) ; RC19.2 156.64,57.16 v2(157.21,57.16) ; v2(25.3,52.12) 24.96,52.46 CT163.2 ; v2(75.54,74.77) 75.73,74.97 DI4.1 ; CT155.2 CT156.2 48.5,62.38 v2(48.56,62.44) ; v2(70.94,74.96) 71.35,74.56 JTS.1
  BOTTOM w0.432: v2(171.44,19.22) 171.44,19.45 171.09,19.8 169.63,19.8 JFAN1.6
  BOTTOM w0.457: PC403.2 165.58,63 v2(166.01,62.58) ; v2(69.57,75.27) 69.57,73.38 JTS.8 ; CC266.2 143.61,44.48 v2(144.17,43.93)
  BOTTOM w0.508: PC1312.2 75.34,66.96 75.34,65.62 75.46,65.49 v2(75.49,65.49) ; RH56.1 174.12,45.42 v2(173.79,45.09) ; v2(64.24,46.06) 64.14,45.96 63.32,45.96 63.12,46.16 PR283.2 ; PC712.2 204.39,61.86 v2(204.52,61.73) ; DI2.1 20.57,43.99 v2(19.74,43.15) ; CD34.2 v3(116.05,22) v2(116.05,22.61) ; v2(160.17,45.6) 160.32,45.75 SW1.5 ; v2(171.54,59.68) 171.48,59.74 171.48,60.25 JTAG1.2 ; JCAM.6 59.19,73.63 59.55,73.99 59.55,75.43 59.46,75.52 ; CA83.2 22.29,27.42 22.29,27.16 v2(22.28,27.15) ; JFAN1.5 168.08,14.07 168.05,14.1 167.87,14.1 v2(167.79,14.18) ; CE65.2 187.4,55.28 v2(187.4,54.87) ; 59.46,75.52 JCAM.7 ; 59.46,75.52 61.18,75.52 61.69,75.01 v2(61.69,74.91) ; CD156.2 123.06,20.89 v2(122.71,21.24) ; v2(197.23,32.55) 196.65,33.13 196.65,34.12 JEDP.43 ; JEDP.44 196.65,43.07 v2(197.88,44.29) ; v2(65.41,57.49) 65,57.49 PC1005.2 ; PC1083.2 76.14,55.94 v2(76.38,56.18) ; v2(188.25,74.31) 188.26,74.32 JSPI1.21 ; JTP1.9 188.76,16.68 v2(187.88,17.56) ; v2(67.56,79.38) 68.04,79.86 69.7,79.86 JTS.7 ; JP100.7 22.41,69.69 v2(23.24,70.52) ; CA2.2 31.13,22.82 CA112.2 ; v2(63.72,62.78) 64.06,63.12 PC1535.2 ; PR701.2 v2(204.67,66.29) ; v2(31.77,62.9) 31.32,62.9 31.12,63.1 C1341.2 C2984.2 ; DA2.1 17.25,23.2 16.51,22.46 v3(16.51,21.22) v2(16.51,20) ; CD41.2 v2(118.44,21.19) ; v2(166.85,17.74) 166.85,17.99 166.48,18.37 JFAN1.1 ; CA3.2 26.9,22.06 v2(27.26,21.7) ; PR247.2 55.02,65.21 PQ224.3 55.41,64.78 v2(55.63,64.56) ; v2(78,45.4) 77.8,45.6 PC1114.2 ; PC1064.1 71.6,55.84 v2(72.09,56.32) ; v2(28.85,18.25) 28.27,17.66 CE3.2 CE10.2 ; C398.1 C401.1 ; CA104.2 CA7.2 33.99,31.94 v2(34.8,31.94) 34.8,32.37 34.35,32.81 CA6.2 34.24,33.36 v2(33.5,34.1) ; DA1.1 17.25,36.56 H22.1 ; RT50.1 35.62,55.28 v2(34.49,54.15) ; 14.02,11.75 v2(12.55,11.01) ; PC1538.2 65.66,48.36 v2(66.51,47.52) ; v2(204.67,64.49) 204.08,64.49 PR707.2 ; v2(78.46,51.79) 78.97,51.28 PC1119.2 ; v2(195.43,24.6) 196.05,25.22 196.65,25.22 JEDP.42 ; CC10.2 187.68,50.71 v2(187.3,50.33) ; v2(10.28,6.37) 10.28,6.4 10.82,5.86 JRTC1.3 11.51,6.1 ; v2(159.36,21.42) 159.11,21.17 CD88.2 ; C4.2 C1221.2 55.66,69.62 57.02,69.62 57.1,69.69 DI3.1 57.25,69.77 57.3,69.82 57.3,70.63 56.92,71.01 v2(56.92,71.63) 56.66,71.63 55.7,72.59 JCAM.3 ; v2(133.99,21.14) 134.44,20.68 CD85.2 ; C617.2 v2(190.31,51.69) ; v2(176.3,72.78) 176.3,73.17 177.4,74.27 JLPDE1.12 ; v2(180.54,47.09) 180.69,46.94 U18.4 ; v2(38.6,59.12) 38.56,59.15 CT170.2 ; v2(34.6,30.21) 33.99,30.21 CA30.1 ; v2(67.75,65.53) 67.92,65.7 PC1086.2 66.97,66.32 PC209.2 65.59,66.32 PU202.2 ; v2(201.75,55.95) 201.88,56.08 PC701.2 ; C5.2 C1222.2 75.31,79.64 v2(74.99,79.96) ; PC100.2 78.21,24.39 v2(78.03,24.22) ; JTP1.10 181.06,16.31 v2(181.06,17.91) ; JDEG1.12 166.89,71.27 v2(166.6,71.56) ; v2(10.82,6.78) 10.82,6.79 11.51,6.1 ; v2(146.2,43.57) 146.03,43.75 RC48.2 ; v2(186.79,54.28) 186.79,54.57 185.65,55.71 CC8.1 ; v2(128.52,76.92) 128.52,75.8 PC1237.2 ; v2(65.27,37.57) 65.38,37.68 PR509.2 ; v2(186.01,75.74) 186.01,75.41 186.25,75.16 186.25,74.27 JLPDE1.11 ; v2(52.73,76.96) 52.73,75.65 JCAM.8 ; RT200.2 21.25,56.11 21.25,55.39 v2(21.34,55.31) ; PC107.2 31.88,78.57 v2(32.36,78.57) 32.92,78.57 PC106.2 ; CD64.2 149.58,20.76 v2(150.01,21.19) ; v2(21.13,50.89) 20.75,51.27 20.45,51.27 C3.2 ; PC700.2 204.62,65.41 v2(204.64,65.4) ; v2(51.28,23.07) 51.68,23.47 JUART.6 ; v2(203.81,38.94) 203.81,37.99 JAPS1.19 ; CE22.2 191.03,49.9 v2(191.27,49.66) ; CC32.2 CC29.2 67.67,70.48 68.12,70.93 v2(68.12,71) ; JDEG1.11 175.66,71.86 v2(175.66,72.75) ; v2(180.4,63.25) 180.58,63.43 RE121.1 ; JEDP.41 193.84,22.83 v2(193.84,23.01) ; v2(61.62,63.5) 61.44,63.68 PR246.2 ; 11.51,6.1 v2(11.51,7.09) ; JAPS1.20 205.39,25.29 v2(205.39,25.29) ; PC1087.2 68.17,60.03 v2(68.2,60.05) 69.02,60.05 69.52,59.55 PC1091.2 ; v2(44.04,35.37) 44.04,35.44 C1301.2 ; v2(155.92,21.39) 155.78,21.26 CD177.2 CD184.2 ; v2(163.81,62.7) PC401.2 PC400.2 ; v2(47.57,32.33) 47.57,31.93 47.35,31.71 PC312.2 ; PR1425.2 63.88,49.22 v2(62.87,50.24) ; CD62.2 137.77,21.13 v2(137.85,21.21) ; CS44.2 188.41,38.17 188.02,38.17 187.8,38.39 v2(187.8,38.38) ; CC27.2 141.71,46.12 v4(141.78,46.19) ; CE4.2 v2(29.38,20.39) ; v2(51.07,41.3) 50.85,41.08 50.85,39.55 JNGFF1.69 ; RH147.1 159.07,66.23 RH145.1 160.91,67.03 161.49,66.44 RH442.2 RH443.2 ; v2(197.33,48.35) 195.26,46.27 JEDP.45 ; v2(166.83,47.2) 168.33,47.2 SW1.4 ; CC4.1 CC5.1 158.6,46.64 158.78,46.82 158.78,47.46 158.5,47.74 v2(158.5,48.01) ; v2(191.49,53.93) 191.95,53.48 CE56.2 ; v2(72.31,57.27) 71.5,58.09 PC1074.2 ; PC1129.2 v2(80.04,59.27) ; v2(65.23,51.11) 65.1,50.99 PC1004.2 ; v2(174.92,60.4) 174.86,60.46 CE59.2 RE66.2 ; v2(67.79,45.45) PC1019.1 PC1098.1 ; CD181.2 121.16,21.41 v3(120.46,22.1) v2(119.67,22.89) ; v2(162.83,60.42) 162.45,60.42 CC281.2 ; v2(99.64,45.45) 99.67,45.47 100.28,45.47 CC240.2 ; CA98.2 35.5,26.85 v2(34.56,27.78) ; v2(32.11,25.69) 32.28,25.69 32.74,26.15 CA97.2 ; v2(19.86,78.86) 22.04,78.86 JP100.6 ; v2(21.44,49.51) 21.52,49.51 22.69,48.35 C303.2 21.55,48.35 v2(21.18,48.71) ; C265.2 20.59,50.24 v2(21.13,50.24) ; CD58.2 v2(143.74,21.2) ; CD183.2 CD89.2 140.54,20.76 v2(140.92,21.14) ; CD171.2 153.04,21.68 v2(153.31,21.95) ; RE82.1 187.17,58.68 CE43.2 186.56,59.44 v2(186.54,59.42) ; v2(9.1,62.69) 9.32,62.47 C402.1 C397.1 ; v2(30.28,41.79) 30.15,41.66 JNGFF1.68 ; v2(23.39,17.99) 23.27,18.12 JSPK1.5
  vias: v2(0.9,66.48) v2(0.91,55.25) v2(0.91,53.98) v2(0.91,52.71) v2(2.39,52.66) v2(2.51,66.5) v2(3.4,0.85) v2(3.8,66.93) v2(4.35,1.31) v2(4.47,23.71) v2(4.47,23.01) v2(4.93,67.44) v2(5.43,1.86) v2(6.01,67.91) v2(6.45,2.39) v2(7.1,68.44) v2(7.06,65.74) v2(7.21,12.61) v2(7.34,2.85) v2(7.7,70.12) v2(7.72,12.91) v2(8.09,71.47) v2(8.26,13.17) v2(8.26,3.32) v2(8.83,72.23) v2(9.2,3.79) v2(10.05,72.63) v2(10.09,4.26) v2(11.31,72.61) v2(11.5,58.78) v2(11.5,56.83) v2(12.8,52.41) v2(12.98,72.63) v2(13.18,20.16) v2(13.89,64.71) v2(13.89,62.58) v2(13.86,6.19) v2(13.96,54.81) v2(14.16,20.12) v2(14.28,72.61) v2(14.59,54.81) v2(14.83,6.69) v2(15.19,54.82) v2(15.39,72.91) v2(15.75,7.16) v2(15.82,54.82) v2(16,78.96) v2(16,77.69) v2(16,76.42) v2(16,75.15) v2(16,73.88) v2(16.1,37.68) v2(16.36,79.97) v2(16.38,56.73) v2(16.42,55.97) v2(16.36,51.67) v2(16.36,39.12) v2(16.63,7.61) v2(17.11,9.86) v2(17.11,8.59) v2(17.28,11.01) v2(17.36,54.84) v2(18.15,11.74) v2(18.59,79.99) v2(19.4,11.81) v2(20.52,52.34) v2(20.67,11.81) v2(20.8,21.17) v2(21.13,79.99) v2(21.14,52.34) v2(21.3,13.47) v2(21.39,21.22) v2(21.91,13.47) v2(22.01,60.46) v2(22.54,13.47) v2(23.12,11.8) v2(23.6,60.47) v2(23.69,79.99) v2(24.17,76.55) v2(24.21,75.97) v2(24.19,75.37) v2(24.19,74.79) v2(24.2,60.47) v2(24.28,11.94) v2(24.64,38.37) v2(24.78,76.55) v2(24.79,75.94) v2(25.34,12.7) v2(26.26,79.97) v2(26.39,31.2) v2(26.39,29.68) v2(26.39,27.77) v2(26.61,12.7) v2(27.66,31.2) v2(27.66,29.68) v2(27.66,27.77) v2(27.84,74.04) v2(27.88,12.7) v2(28.24,48.92) v2(28.8,79.97) v2(28.84,48.71) v2(28.8,31.2) v2(28.8,29.68) v2(28.8,27.87) v2(29.15,12.7) v2(29.21,74.04) v2(29.46,51.06) v2(29.46,49.96) v2(29.81,74.05) v2(30.34,74.38) v2(30.34,73.75) v2(30.42,12.7) v2(31.18,21.94) v2(31.31,79.99) v2(31.69,12.7) v2(31.79,21.94) v2(32.16,61.4) v2(32.61,62.59) v2(32.96,12.7) v2(33.12,41.87) v2(33.26,54.09) v2(33.78,79.99) v2(33.81,64.09) v2(33.87,54.11) v2(34.23,12.7) v2(35.5,12.7) v2(36.32,79.99) v2(36.77,12.7) v2(36.93,42.5) v2(36.96,61.55) v2(37.21,66.1) v2(38.04,12.7) v2(38.43,35.11) v2(38.93,79.99) v2(39.31,12.7) v2(40.58,12.7) v2(40.89,35.42) v2(41.45,79.99) v2(41.85,12.7) v2(43.12,12.7) v2(43.99,79.99) v2(44.39,12.7) v2(45.66,12.7) v2(46.55,81.48) v2(46.58,27.62) v2(46.59,26.99) v2(46.93,12.7) v2(47.35,80.48) v2(47.77,81.49) v2(48.2,12.7) v2(48.79,70.97) v2(48.95,81.48) v2(49.47,12.7) v2(50.01,41.87) v2(50.19,81.49) v2(51.32,64.23) v2(51.33,60.69) v2(51.33,58.92) v2(51.4,61.88) v2(51.49,81.48) v2(52.25,45.74) v2(52.81,81.47) v2(52.91,56.96) v2(52.86,45.74) v2(53.08,58.35) v2(54.17,81.48) v2(55.42,81.49) v2(56.37,12.7) v2(56.78,81.48) v2(57.18,56.32) v2(57.37,12.7) v2(57.63,55.91) v2(58.15,81.49) v2(58.57,38.3) v2(58.64,12.7) v2(59.16,38.31) v2(59.32,81.48) v2(59.91,12.7) v2(60.55,81.48) v2(61.16,42.36) v2(61.18,12.7) v2(61.79,81.48) v2(62.45,12.7) v2(63.07,81.49) v2(63.49,42.48) v2(63.72,12.7) v2(64.41,81.5) v2(64.99,12.7) v2(65.7,81.48) v2(66.26,12.7) v2(66.52,41.74) v2(66.52,41.11) v2(66.95,81.5) v2(67.16,41.74) v2(67.16,41.11) v2(67.16,40.47) v2(67.32,64.83) v2(67.43,55.09) v2(67.43,53.56) v2(67.43,52.04) v2(67.53,12.7) v2(67.79,41.74) v2(67.79,41.11) v2(67.79,40.47) v2(68.2,81.48) v2(68.44,65.53) v2(68.56,41.74) v2(68.56,41.11) v2(68.56,40.47) v2(68.56,39.85) v2(68.85,12.68) v2(68.96,55.09) v2(68.96,53.56) v2(68.96,52.04) v2(69.06,65.53) v2(69.19,41.74) v2(69.19,41.11) v2(69.19,40.47) v2(69.2,39.89) v2(69.41,81.48) v2(69.75,21.27) v2(69.86,16.48) v2(70.48,55.09) v2(70.48,53.56) v2(70.48,52.04) v2(70.46,12.68) v2(70.65,81.48) v2(71.32,45.45) v2(71.69,13.12) v2(71.87,45.15) v2(71.96,81.48) v2(72.45,77.35) v2(72.5,14.5) v2(72.89,77.78) v2(73.25,81.48) v2(73.77,14.5) v2(74.5,81.48) v2(75.04,14.5) v2(75.18,35.54) v2(75.18,34.91) v2(75.22,20.97) v2(75.21,19.95) v2(75.29,37.68) v2(75.53,20.45) v2(75.79,81.48) v2(75.81,35.54) v2(75.81,34.91) v2(75.85,20.98) v2(75.82,19.95) v2(76.13,20.46) v2(76.23,21.47) v2(76.31,14.5) v2(76.43,19.95) v2(76.49,20.95) v2(76.77,20.44) v2(76.86,22.76) v2(76.85,22.12) v2(76.86,21.46) v2(77.03,81.48) v2(77.58,14.5) v2(78.18,22.46) v2(78.16,21.71) v2(78.16,20.97) v2(78.85,14.5) v2(79.65,28.36) v2(80.12,14.5) v2(81.39,14.5) v2(82.07,37.85) v2(82.19,52.82) v2(82.19,52.16) v2(82.16,37.26) v2(82.19,36.67) v2(82.45,40.73) v2(82.42,40.14) v2(82.4,39.56) v2(82.37,38.97) v2(82.37,38.36) v2(82.53,74.79) v2(82.54,65.03) v2(82.54,64.07) v2(82.54,63.11) v2(82.54,57.45) v2(82.54,56.49) v2(82.54,55.53) v2(82.48,49.53) v2(82.48,48.57) v2(82.48,47.6) v2(82.69,37.85) v2(82.66,14.5) v2(82.8,37.27) v2(82.82,36.69) v2(82.86,47) v2(83.01,40.9) v2(83.01,40.14) v2(82.98,39.56) v2(83.01,38.97) v2(82.98,38.36) v2(83.25,65.03) v2(83.25,64.07) v2(83.25,63.11) v2(83.19,62.42) v2(83.25,57.45) v2(83.25,56.49) v2(83.25,55.53) v2(83.19,49.53) v2(83.19,48.57) v2(83.19,47.6) v2(83.33,60.92) v2(83.31,58.07) v2(83.36,44.81) v2(83.39,44.23) v2(83.39,43.65) v2(83.41,43.06) v2(83.44,42.48) v2(83.46,41.87) v2(83.49,41.26) v2(83.49,40.55) v2(83.49,38.03) v2(83.49,37.45) v2(83.6,60.27) v2(83.59,59.62) v2(83.64,58.96) v2(83.62,52.9) v2(83.59,52.16) v2(83.67,39.43) v2(83.73,38.81) v2(83.85,58.4) v2(83.89,49.53) v2(83.89,48.57) v2(83.89,47.6) v2(83.93,14.5) v2(83.96,65.03) v2(83.96,64.07) v2(83.96,63.11) v2(83.96,57.45) v2(83.96,56.49) v2(83.96,55.53) v2(83.97,44.81) v2(83.97,44.23) v2(84.02,43.65) v2(84.1,60.61) v2(84.13,59.29) v2(84.06,52.51) v2(84.07,51.77) v2(84.3,58) v2(84.32,39.44) v2(84.32,38.79) v2(84.25,32.06) v2(84.35,58.73) v2(84.56,65.03) v2(84.56,44.23) v2(84.7,43.66) v2(84.76,65.87) v2(84.93,39.46) v2(84.93,38.81) v2(84.89,34.35) v2(85.07,65.36) v2(85.2,14.5) v2(85.29,43.65) v2(85.29,16.46) v2(85.43,39.14) v2(85.93,81.48) v2(85.88,32.17) v2(86.47,14.5) v2(87.1,50.76) v2(87.17,81.49) v2(87.2,34.17) v2(87.74,14.5) v2(88.51,81.48) v2(88.91,34.22) v2(88.98,31.86) v2(89.01,14.5) v2(89.46,33.84) v2(89.6,31.84) v2(89.74,81.49) v2(89.78,20.76) v2(90.28,14.5) v2(91.05,81.48) v2(91.49,22.16) v2(91.55,14.5) v2(92.12,21.54) v2(92.28,81.49) v2(92.55,20.09) v2(92.72,21.6) v2(92.82,14.5) v2(92.92,19.56) v2(93.14,20.12) v2(93.29,41.49) v2(93.31,21.6) v2(93.45,32.88) v2(93.55,81.48) v2(93.74,20.12) v2(93.69,19.54) v2(93.89,21.58) v2(94.18,52) v2(94.18,51.39) v2(94.18,50.81) v2(94.18,50.22) v2(94.23,14.3) v2(94.29,21.11) v2(94.27,20.51) v2(94.27,19.85) v2(94.84,81.49) v2(95.25,41.49) v2(95.45,43.34) v2(95.48,42.74) v2(95.5,42.12) v2(95.86,73.95) v2(96.09,81.48) v2(96.52,57.39) v2(96.87,76.42) v2(97.13,73.95) v2(97.27,57.36) v2(97.4,81.49) v2(97.9,57.36) v2(98.43,74.1) v2(98.51,62.58) v2(98.53,57.36) v2(98.63,81.48) v2(98.93,76.97) v2(99.59,63.9) v2(99.8,62.57) v2(99.82,12.71) v2(99.9,81.48) v2(100.47,63.9) v2(100.76,62.54) v2(100.88,67.19) v2(101.17,81.48) v2(101.24,63.92) v2(101.41,62.51) v2(101.52,67.15) v2(101.58,12.71) v2(102.08,63.9) v2(102.16,62.54) v2(102.19,34.72) v2(102.29,67.12) v2(102.43,81.49) v2(102.76,63.9) v2(102.83,62.52) v2(102.85,12.71) v2(102.89,67.14) v2(103.47,67.13) v2(103.54,63.92) v2(103.61,62.51) v2(103.71,81.48) v2(104.08,67.14) v2(104.12,12.71) v2(104.18,63.89) v2(104.24,62.56) v2(104.67,67.12) v2(104.98,81.49) v2(105.28,67.17) v2(105.39,13.98) v2(105.39,12.71) v2(105.93,67.18) v2(106.15,49.39) v2(106.25,81.48) v2(106.49,14.19) v2(107.16,57.87) v2(107.54,81.48) v2(108.15,48.07) v2(108.51,67.8) v2(108.79,81.48) v2(108.76,49.87) v2(108.86,59.11) v2(109.02,57.84) v2(109.22,55.91) v2(110.06,81.49) v2(111.33,81.48) v2(112.51,81.48) v2(112.67,44.36) v2(113.3,14.19) v2(113.81,46.7) v2(113.76,44.87) v2(113.87,81.48) v2(114.7,13.97) v2(114.7,12.7) v2(115.15,81.48) v2(115.94,12.7) v2(116.23,43.34) v2(116.41,81.48) v2(117.21,12.7) v2(117.64,81.48) v2(118.09,45.3) v2(118.09,43.52) v2(118.11,41.03) v2(118.48,12.7) v2(118.95,81.48) v2(119.14,62.7) v2(119.28,46.47) v2(119.53,58.81) v2(119.75,12.7) v2(119.91,43.8) v2(119.91,41.97) v2(120.02,64.37) v2(120.22,81.48) v2(120.35,63) v2(120.58,76.02) v2(120.8,58.81) v2(121.02,12.7) v2(121.08,43.87) v2(121.28,64.44) v2(121.49,81.48) v2(121.51,63.03) v2(122.07,58.81) v2(122.17,76.36) v2(122.29,12.7) v2(122.56,64.42) v2(122.75,81.48) v2(122.68,63.05) v2(122.81,74.15) v2(123.24,61.86) v2(123.37,58.81) v2(123.56,12.7) v2(123.83,64.55) v2(124.03,81.48) v2(124.21,63.2) v2(124.51,61.86) v2(124.65,75.32) v2(124.82,59.55) v2(124.83,12.7) v2(125.12,64.55) v2(125.31,81.49) v2(125.3,44.41) v2(125.45,63.2) v2(125.81,61.86) v2(126.09,59.55) v2(126.37,64.52) v2(126.57,81.48) v2(126.72,76.69) v2(127.08,47.13) v2(127.08,45.27) v2(127.8,81.49) v2(129.11,81.48) v2(129.33,75.06) v2(129.31,47.61) v2(129.95,62.85) v2(130.4,81.48) v2(130.48,43.9) v2(130.45,41.54) v2(130.86,45.98) v2(130.99,62.98) v2(131.65,81.48) v2(131.83,62.88) v2(132.23,45.98) v2(132.23,44.15) v2(132.26,42.33) v2(132.73,12.7) v2(132.89,81.48) v2(133.91,43.14) v2(134,12.7) v2(134.19,81.48) v2(135.27,12.7) v2(135.47,81.49) v2(135.61,64.4) v2(135.61,60.21) v2(135.66,65.62) v2(135.66,60.87) v2(135.99,62.7) v2(136.54,12.7) v2(136.6,47.3) v2(136.58,46.11) v2(136.6,44.28) v2(136.6,42.53) v2(136.73,81.48) v2(137.81,12.7) v2(138,81.48) v2(138.07,47.23) v2(139.08,12.7) v2(139.23,78.08) v2(139.27,81.48) v2(139.73,45.04) v2(139.81,78.08) v2(140.35,12.7) v2(140.53,81.47) v2(140.51,74.58) v2(141.5,74) v2(141.62,12.7) v2(141.81,81.48) v2(142.89,12.7) v2(143.05,81.47) v2(143.87,74.84) v2(144.16,12.7) v2(144.35,81.48) v2(145.43,12.7) v2(145.64,81.48) v2(146.3,74.13) v2(146.7,12.7) v2(146.89,81.48) v2(147.97,12.7) v2(148.21,81.48) v2(148.4,59.58) v2(149.24,12.7) v2(149.43,81.48) v2(150.51,12.7) v2(150.72,81.47) v2(151.78,12.7) v2(151.97,81.48) v2(153.05,12.7) v2(153.26,81.48) v2(154.06,57.47) v2(154.23,55.89) v2(154.32,12.7) v2(154.51,81.48) v2(155.59,12.7) v2(155.78,81.48) v2(156.86,12.7) v2(157.05,81.48) v2(158.13,12.7) v2(158.27,81.48) v2(159.4,12.7) v2(159.59,81.48) v2(160.67,12.7) v2(160.87,81.48) v2(161.94,12.7) v2(162.13,81.48) v2(163.21,12.7) v2(163.41,81.48) v2(163.83,18.51) v2(164.48,12.7) v2(164.67,81.48) v2(165.65,81.48) v2(165.75,12.7) v2(165.91,30.9) v2(165.87,30.18) v2(165.91,29.58) v2(166.59,81.5) v2(166.67,36.19) v2(166.87,36.74) v2(166.89,35.13) v2(166.99,35.7) v2(167.01,34.55) v2(167.02,12.7) v2(167.44,44.54) v2(167.44,37.04) v2(167.37,36.43) v2(168.04,44.57) v2(168.04,41.7) v2(168.15,81.48) v2(168.06,42.57) v2(168.09,19.12) v2(168.22,39.71) v2(168.29,12.7) v2(168.89,42.56) v2(168.9,41.71) v2(169.01,32.85) v2(169.02,32.15) v2(169.01,31.45) v2(169.56,12.7) v2(169.75,81.48) v2(170.83,12.7) v2(170.99,81.48) v2(172.1,12.7) v2(172.29,81.48) v2(172.74,77.37) v2(172.73,74.59) v2(172.78,75.43) v2(172.93,72.7) v2(173.37,12.7) v2(173.6,81.49) v2(173.6,75.46) v2(173.59,74.59) v2(173.93,50.38) v2(173.93,49.36) v2(173.97,52.28) v2(174.51,50.38) v2(174.46,49.69) v2(174.64,12.7) v2(174.83,81.48) v2(174.98,50.02) v2(174.98,49.34) v2(175.91,12.7) v2(176.02,81.48) v2(177.06,81.47) v2(177.18,12.7) v2(178.45,12.7) v2(179.72,12.7) v2(180.43,65.49) v2(180.42,61.03) v2(180.99,12.7) v2(181.51,23.17) v2(182.04,23.5) v2(182.26,12.7) v2(182.58,65.53) v2(182.61,63.27) v2(182.6,61.02) v2(183.53,12.7) v2(184.36,44.94) v2(184.85,65.48) v2(184.79,63.23) v2(184.84,61.17) v2(184.8,12.7) v2(185.88,46.47) v2(185.88,44.94) v2(185.88,43.42) v2(186.07,12.7) v2(186.79,81.48) v2(187.34,12.7) v2(187.4,44.94) v2(188.07,81.49) v2(188.61,12.7) v2(189.33,81.48) v2(189.88,12.7) v2(190.63,81.49) v2(191.15,12.7) v2(191.87,81.48) v2(192.42,12.7) v2(193.15,81.49) v2(193.69,12.7) v2(194.41,81.48) v2(194.96,12.7) v2(195.1,65.19) v2(195.68,81.48) v2(196.13,59.6) v2(196.13,59) v2(196.13,58.42) v2(196.13,54.48) v2(196.09,53.9) v2(196.23,12.7) v2(196.44,53.43) v2(196.71,60.25) v2(196.71,59.61) v2(196.71,59.02) v2(196.71,58.43) v2(196.95,81.48) v2(196.98,40.55) v2(197.22,26.8) v2(197.5,12.7) v2(197.59,76.46) v2(197.82,40.35) v2(197.84,35.82) v2(198.22,81.48) v2(198.17,76.46) v2(198.35,20.61) v2(198.78,76.67) v2(198.77,12.7) v2(199.16,41.82) v2(199.49,81.48) v2(199.47,74.25) v2(199.7,72.09) v2(199.78,66.26) v2(200.03,74.68) v2(200.03,63.81) v2(200.04,12.7) v2(200.23,61.53) v2(200.54,75.05) v2(200.58,74.28) v2(200.76,81.48) v2(201.31,12.7) v2(201.52,19.57) v2(202.03,81.48) v2(202.11,16.19) v2(202.58,12.7) v2(202.73,14.73) v2(203.3,81.48) v2(203.33,21.19) v2(203.61,14.81) v2(203.85,12.7) v2(204.21,14.8) v2(204.57,81.48) v2(204.65,16.32) v2(205.07,22.49) v2(205.12,12.7) v2(205.41,16.29) v2(205.67,81.19) v2(205.71,80.05) v2(205.71,78.78) v2(205.71,77.51) v2(205.71,76.24) v2(205.71,74.97) v2(205.71,73.7) v2(205.71,72.43) v2(205.71,71.16) v2(205.71,69.89) v2(205.71,68.62) v2(205.71,67.35) v2(205.71,66.08) v2(205.71,64.81) v2(205.71,63.54) v2(205.71,62.27) v2(205.71,61) v2(205.71,59.73) v2(205.71,58.46) v2(205.71,57.19) v2(205.71,55.92) v2(205.71,54.65) v2(205.71,53.38) v2(205.71,52.11) v2(205.7,48.08) v2(205.7,46.81) v2(205.7,45.54) v2(205.7,44.27) v2(205.7,43) v2(205.7,41.73) v2(205.7,40.46) v2(205.75,39.17) v2(205.85,37.91) v2(206,36.8) v2(206.18,35.67) v2(206.25,16.47) v2(206.38,34.63) v2(206.39,12.7) v2(206.45,14.66) v2(206.64,33.59) v2(206.92,32.57) v2(206.91,22.47) v2(207.21,14.71) v2(207.25,31.54) v2(207.62,30.54) v2(207.66,12.7) v2(208,29.62) v2(208.47,28.54) v2(208.93,12.7) v2(209.03,27.43) v2(209.58,26.44) v2(210.21,25.38) v2(210.2,12.7) v2(210.76,24.56) v2(211.47,12.7) v2(211.55,23.46) v2(212.34,22.47) v2(212.64,21.31) v2(212.64,20.04) v2(212.74,12.7) v2(212.8,18.72) v2(213.72,17.98) v2(214.85,17.98) v2(214.82,12.72) v2(216.09,17.62) v2(216.7,12.7) v2(216.95,16.79) v2(217.31,15.68) v2(217.31,14.41) v3(11.85,55.52) v3(12.15,22.21) v3(27.05,28.94) v3(29.52,31.36) v3(48.95,18.38) v3(53.04,37.96) v3(65.05,42.1) v3(68.35,54.16) v3(69.75,52) v3(75.51,22.25) v3(75.84,36.13) v3(76.29,35.2) v3(84.38,41.49) v3(88.16,31.53) v3(89.89,33.18) v3(91.11,19.9) v3(94.46,72.45) v3(97.05,41.28) v3(102.08,65.41) v3(105.41,68) v3(110.74,67.32) v3(194.12,52.5) v3(195.02,62.32) v3(195.29,60.63) v4(51.82,37.68) v4(51.92,35.37) v4(51.92,34.73) v4(51.92,34.1) v4(51.92,33.46) v4(51.92,32.83) v4(51.92,32.19) v4(52.11,37.03) v4(52.45,37.68) v4(53.09,37.25) v4(56.3,23.62) v4(56.95,23.63) v4(57.58,23.63) v4(58.22,23.63) v4(59.79,28.03) v4(59.79,27.26) v4(59.82,25.05) v4(59.83,24.39) v4(60.91,23.1) v4(61.32,28.03) v4(61.32,27.26) v4(61.32,25.23) v4(61.32,24.47) v4(61.54,23.1) v4(62.84,28.03) v4(62.84,27.26) v4(67.41,29.04) v4(68.75,28.96) v4(69.57,29.04) v4(72.24,28.91) v4(73,28.91)
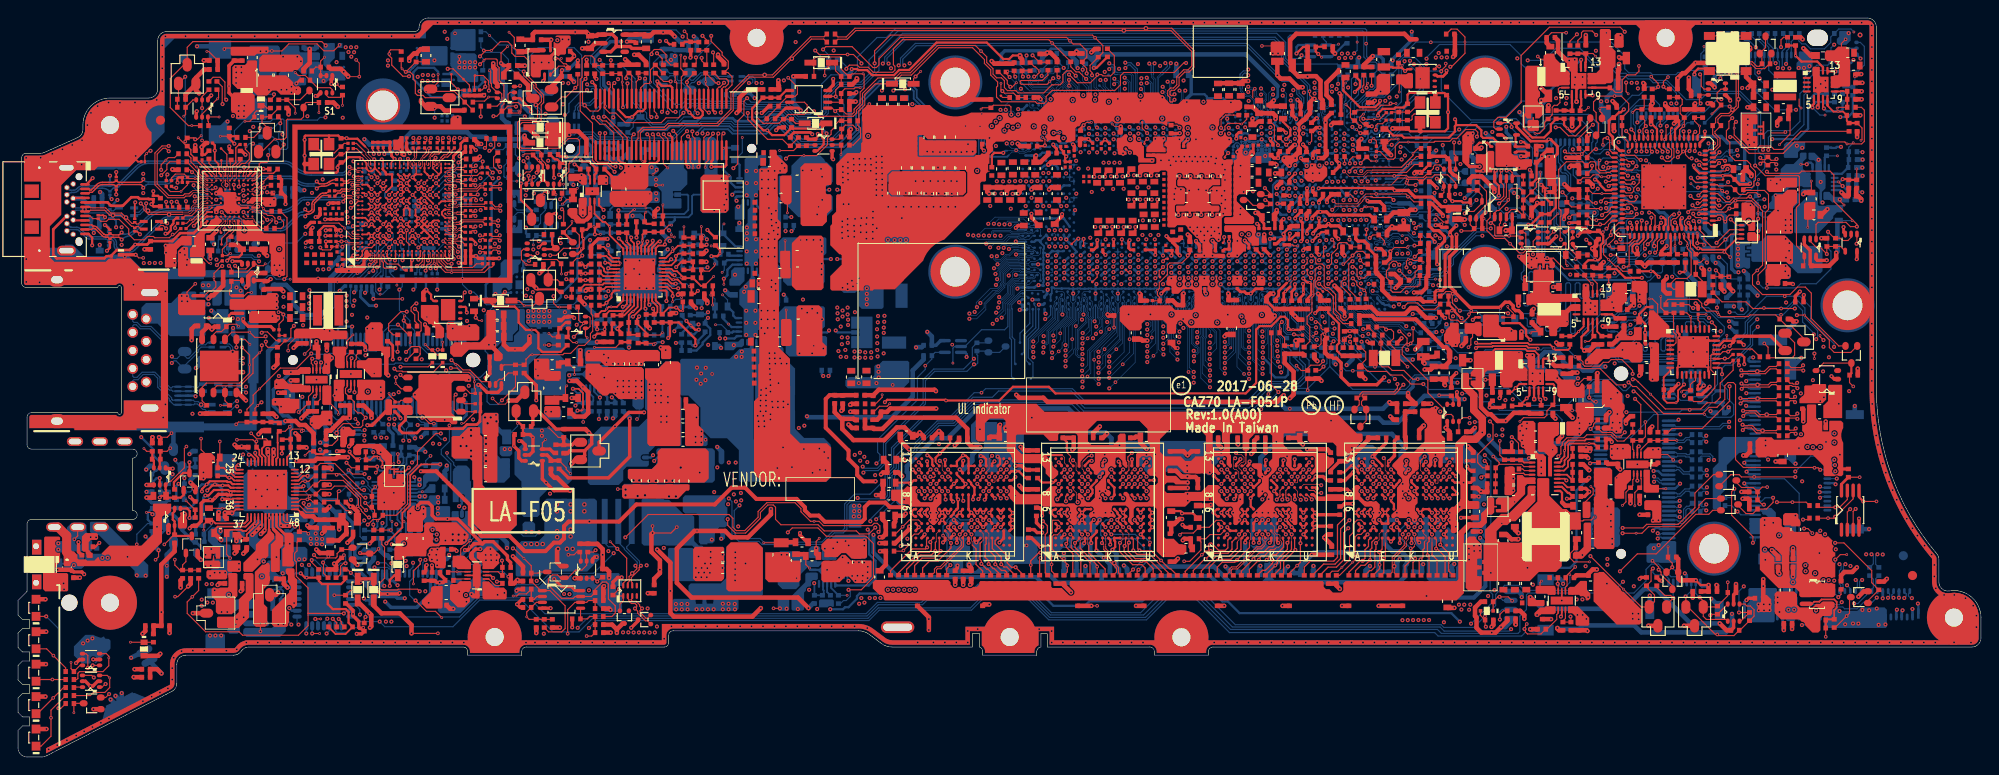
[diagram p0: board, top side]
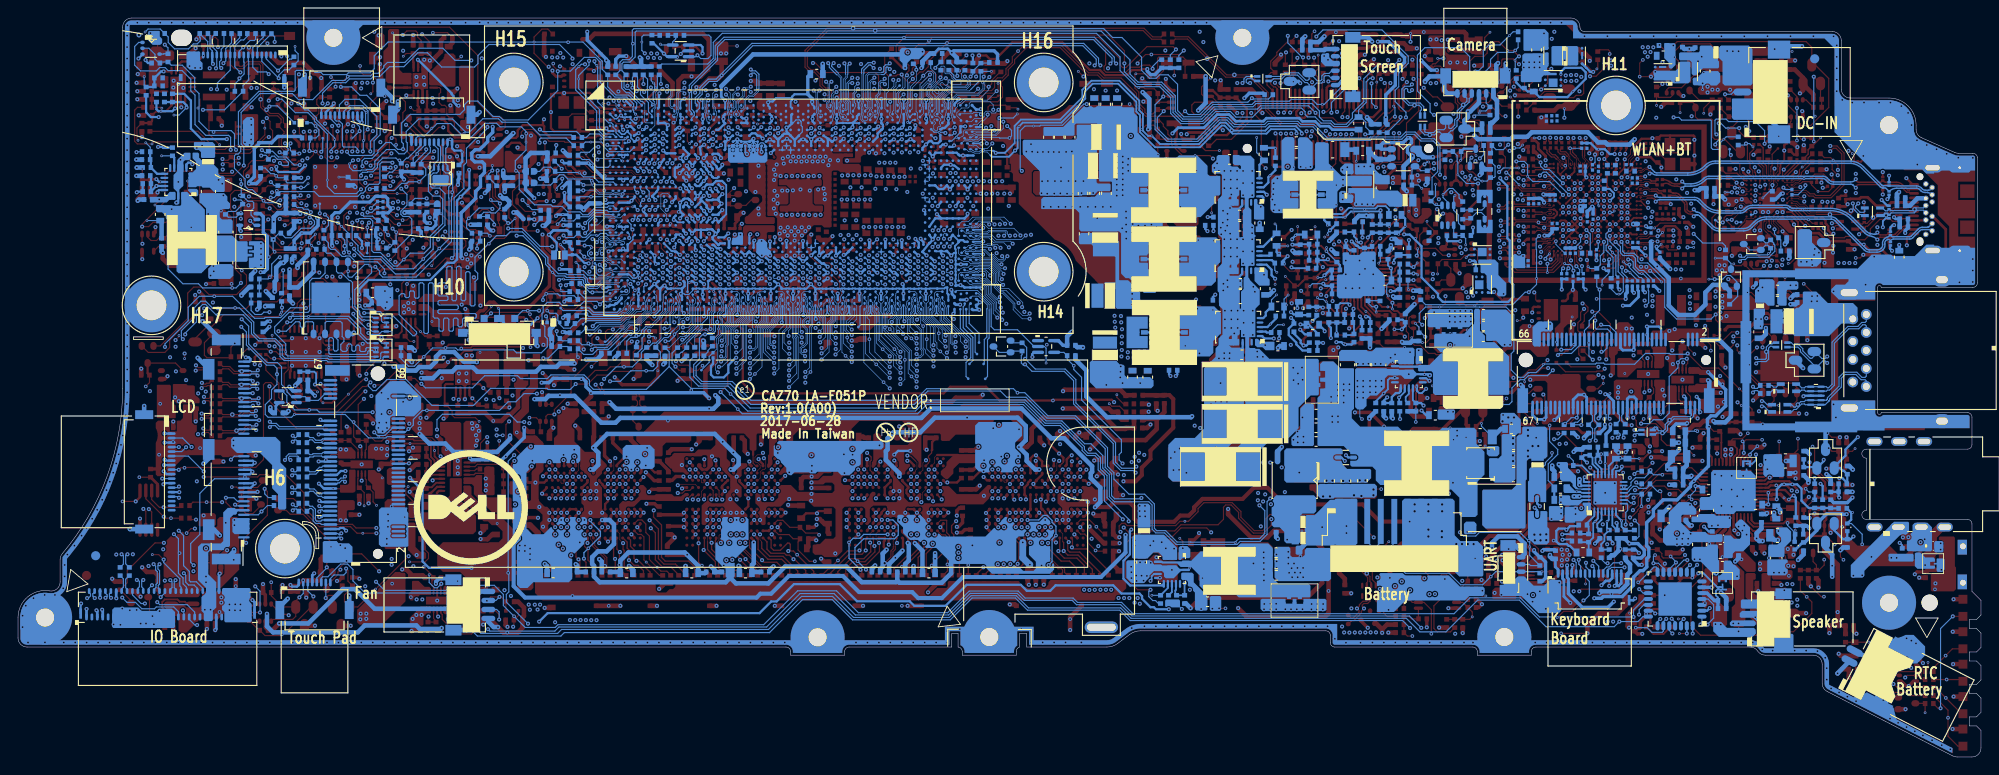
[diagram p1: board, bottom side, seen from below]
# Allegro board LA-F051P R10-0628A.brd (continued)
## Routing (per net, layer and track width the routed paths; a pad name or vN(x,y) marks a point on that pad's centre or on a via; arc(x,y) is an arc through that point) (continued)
GNDA_CHG: length 40.8
  TOP w0.381: PC331.2 39.47,24.14 v2(39.01,23.68)
  TOP w0.508: PQ302.3 37.12,21.84 v2(37.64,21.32)
  IN3 w0.508: v2(45.19,33.87) 44.76,34.3 40.73,34.3 v2(40.23,33.8) ; v2(39.01,23.68) 39.65,24.32 45.11,24.32 v2(46,25.21)
  IN4 w0.508: v2(41.7,29.31) 41.7,27.68 44.15,25.23 45.97,25.23 v2(46,25.21)
  BOTTOM w0.254: PC309.1 45.61,23.43 45.75,23.43 45.95,23.63 46.84,23.63 47.12,23.91 47.12,25.09 46.86,25.34 46.14,25.34 v2(46,25.21) 45.59,25.61 44.76,25.61 PC311.2
  BOTTOM w0.381: v2(37.64,21.32) 38,21.32 38.58,21.9 PR310.1 38.56,22.08 37.72,22.08 37.36,22.44 37.36,22.97 38.08,23.68 v2(39.01,23.68) 39.47,24.14 PC331.2
  BOTTOM w0.508: v2(45.19,33.87) 44.92,34.13 PC334.1 44.06,34.38 PC336.2 ; v2(40.23,33.8) 40.49,34.06 PC337.2 ; PR317.2 40.97,22.39 40.73,22.39 40.21,22.9 40.21,24.11 PC318.1 PC331.2
  vias: v2(40.63,30.38) v2(40.63,28.25) v2(42.77,30.38) v2(42.77,28.25)
VBUS_ACOK: length 88.8
  TOP w0.127: v2(54.92,23.15) 55.02,23.15 v1(56.13,22.03) 56.95,21.22 PR261.2 ; PR248.1 53.24,65.62 53.37,65.49 v2(53.5,65.49) ; PR261.2 PC217.1 58,18.46 PU203.1 59.02,18.46 60.71,16.77 60.71,14.26 60.33,13.88 58.88,13.88 PR263.2 ; PR261.2 57.73,20.41 57.86,20.53 PQ220.1 ; PR213.1 62.28,57.91 62.28,56.59 62.14,56.45 60.51,56.45 59.74,55.67 v2(59.06,55.67)
  IN4 w0.081: v2(53.5,65.49) 53.4,65.39 52.38,65.39 52.15,65.16 52.15,63.61 53.41,62.35 55.46,62.35 56.34,61.46 57.19,61.46 57.67,60.98 57.67,58.22 59.06,56.84 v2(59.06,55.67) 59.06,55.28 58.26,54.48 58.26,53.31 57.99,53.04 56.36,53.04 49.71,46.39 49.57,46.39 44.5,41.32 44.5,39.02 42.07,36.59 42.07,33.54 42.76,32.85 42.76,31.33 43.92,30.17 43.92,27.11 44.68,26.35 52.07,26.35 54.92,23.5 v2(54.92,23.15)
VBUSSENSE: length 3.1
  TOP w0.127: v2(149.99,57.59) 150.32,57.93 RC20.1 151.61,57.29 v1(151.61,56.92)
  BOTTOM w0.127: UCPU1.AG4 149.99,58.02 v2(149.99,57.59)
VCC0V9_LVR_OUT: length 2.4
  TOP w0.203: UT1.H11 40.85,60.1 v2(41.18,60.42) ; UT1.H18 40.53,63.02 v2(40.53,63.02) 40.53,63.02 UT1.F18
  TOP w0.254: UT1.J11 v2(41.18,60.42)
  BOTTOM w0.127: v2(41.18,60.42) 40.86,60.42 v1(40.7,60.59)
VCC0V9_SVR: length 4.1
  TOP w0.203: UT1.F12 39.88,60.42 v2(39.88,60.42) 39.88,60.42 UT1.F11 ; UT1.E12 v2(39.88,61.07) ; v2(39.88,61.07) 39.56,61.4 UT1.E13 ; v2(39.88,61.07) UT1.F13 ; v2(39.88,61.72) 40.2,62.04 UT1.F15
  TOP w0.229: v2(42.48,59.77) 42.8,59.45 UT1.M9 ; UT1.J9 41.51,59.45 v2(41.83,59.77) 42.15,59.45 UT1.L9
  vias: v2(32.33,51.8) v2(32.3,51.08) v2(32.3,50.34) v2(32.28,49.72) v2(36.46,60.51) v2(36.55,59.91) v2(36.67,59.32) v3(33.3,53.09)
VCC1V8A_TBT_LDO: length 5.8
  TOP w0.127: v1(17.78,68.72) 18.71,67.78 RT201.2
  TOP w0.152: RT201.2 19.18,67.38 19.18,66.9 19.66,66.41 CT151.1 20.04,65.99 20.04,65.98 20.16,65.86 20.17,65.86 20.71,65.31 20.72,65.31 20.82,65.21 20.82,65.21 21.4,64.64 21.4,64.59 U722.K1
VCC1V8D_TBT_LDO: length 3.3
  TOP w0.152: CT152.1 28.35,64.78 27.08,64.78 26.27,63.97 U722.A2
VCC3V3_TBT_LDO: length 106.5
  TOP w0.203: U722.G1 23.01,64.48 23.01,65.19 v2(22.91,65.29)
  TOP w0.305: RT17.1 RT16.1 RT18.1 51.26,38.25 51.26,37.25 50.9,36.89 49.81,36.89 49.35,36.43 44.73,36.43 44.26,35.96 42.66,35.96 42.31,36.31 42.31,36.71 43,37.39 43,38.05 UT5.8
  TOP w0.381: R1475.1 29.24,64.07 29.24,63.51 29.19,63.46 29.01,63.46 28.99,63.44 R1454.1 28.98,63.43 29.19,63.23 R1460.1 29.3,62.57 29.68,62.19 v2(29.68,61.35) ; v2(38.76,36.81) 39.29,36.81 40.79,38.31 CT47.1
  TOP w0.508: R1474.1 R1477.1 v2(20.19,38.11) ; v2(17.13,65.21) 17.19,65.16 R1478.1 ; UT6.8 20.42,47.14 20.88,47.6 C1346.1 21.13,47.84 v2(21.51,47.46) 21.81,47.75 R1476.1
  IN1 w0.508: v2(20.19,38.11) 21.51,39.43 v2(21.51,47.46)
  IN2 w0.508: v2(29.68,61.35) 29.68,63.23 28.17,64.74 28.17,65.26 27.31,66.13 24.38,66.13 23.54,65.29 v2(22.91,65.29)
  IN3 w0.381: v2(38.76,36.81) 38.68,36.81 37.31,38.19 34.58,38.19 33.42,39.35 32.82,39.35 32.36,39.81 32.36,40.34 31.52,41.18 28.27,41.18 27.45,42.01 24.09,42.01 v2(20.19,38.11)
  IN3 w0.508: v2(22.91,65.29) 22.25,65.95 17.87,65.95 v2(17.13,65.21) 16.55,65.8 15.62,65.8 15.09,65.27 15.09,63.59 15.81,62.86 15.81,61.2 16.31,60.7 18.52,60.7 19.28,59.94 19.6,59.94 20.13,59.41 20.13,58.59 21.75,56.98 v2(21.75,56.89)
  IN4 w0.508: v2(21.75,56.89) 21.75,56.86 20.73,55.84 20.73,54.54 22.71,52.56 22.71,48.65 v2(21.51,47.46)
  BOTTOM w0.508: RT199.2 21.55,57.17 21.75,56.98 v2(21.75,56.89)
VCC3V3_TBT_SX: length 3.3
  TOP w0.076: 21.76,64.66 21.76,64.38 21.92,64.22 22.26,64.22 U722.H2
  TOP w0.152: C1345.1 20.42,66 21.76,64.66
VCC_3V3_PCIE: length 13
  TOP w0.203: UT1.L16 v2(41.83,62.37)
  IN3 w0.381: v2(41.83,62.37) 41.83,65.03 41.25,65.6 41.25,66.66 41.42,66.82 41.42,67.18 45.12,70.89 46.08,70.89 46.13,70.94 v2(46.23,70.94)
  BOTTOM w0.127: v2(46.23,70.94) v1(46.23,71.94)
VCC_3V3_USB2: length 10.5
  TOP w0.127: CT100.1 40.53,67.38 40.64,67.26 v2(40.64,66.91) ; UT1.J16 v2(41.18,62.37)
  IN4 w0.081: v2(41.18,62.37) 41.18,62.37 41.65,62.83 41.65,64.9 40.92,65.62 40.92,66.63 v2(40.64,66.91)
  BOTTOM w0.254: v2(40.64,66.91) 41.19,66.91 41.73,67.45 v1(42.44,67.45) 42.63,67.45 43.31,68.12 CT168.1 44.29,68.12 CT169.1
VCC_CORE: length 5.5
  TOP w0.203: PU1000.34 65.56,54.16 v2(65.48,54.24)
  BOTTOM w0.127: PC1007.1 65.94,52.36 65.94,51.34 v1(65.76,51.16)
  BOTTOM w0.203: PC1007.1 65.42,54.17 v2(65.48,54.24) 65.8,54.56 PR1080.1
VCC_GT_SENSE: length 79.6
  TOP w0.203: PR1079.1 PC1090.1 74.91,54.92 PC1132.2 PC1092.1 73.61,54.95 v2(73.03,54.36)
  TOP w0.254: v2(109.32,67.04) 108.33,67.04 108.05,66.76 RC161.2
  IN2 w0.254: v2(75.36,69.17) 75.46,69.07 75.46,67.88 73.41,65.83 73.41,62.37 70.46,59.42 67.74,59.42 67.16,58.84 67.16,56.92 68.28,55.8 70.82,55.8 71.88,54.75 72.64,54.75 v2(73.03,54.36)
  BOTTOM w0.076: UCPU1.J70 111.99,67.43 111.85,67.29 111.84,67.29 111.84,67.28 111.59,67.17 111.17,67.17 111.01,67.32 109.81,67.32 109.76,67.27
  BOTTOM w0.203: 109.76,67.27 109.55,67.27 v2(109.32,67.04) 108.31,67.04 107.23,68.12 107.23,70.03 106.52,70.73 102.17,70.73 99.72,73.19 99.72,74.02 98.7,75.04 95.61,75.04 93.4,72.83 93.4,71.76 92.99,71.36 92.99,69.49 92.43,68.92 v1(92,68.92) 91.09,68.02 86.77,68.02 84.39,70.4 83.8,70.4 82.91,69.5 79.41,69.5 78.93,69.99 76.02,69.99 75.36,69.34 v2(75.36,69.17)
VCCHDA: length 26.9
  IN3 w0.089: v2(141.71,57.24) 141.71,56.87 142.2,56.39 142.2,52.02 143.51,50.71 144.59,50.71 145.26,51.38 147.92,51.38 148.51,51.98 149.92,51.98 150.55,52.6 151.59,52.6 152.31,53.33 154.54,53.33 155.34,54.13 155.34,54.53 155.06,54.81 154.53,54.81 v2(154.5,54.77)
  BOTTOM w0.127: v1(157.63,56.88) 157.13,56.38 RC318.2 ; UCPU1.AJ19 141.39,57.56 v2(141.71,57.24)
  BOTTOM w0.254: v2(154.5,54.77) 154.53,54.81 154.95,54.81 155.87,55.74 CC95.1 156.35,55.7 RC318.2
VCCIO_B+:
  vias: v1(176.51,50.99) v2(176.88,50.48) v2(177.04,49.83) v2(177.09,51.7)
VCCIO_EN: length 5
  TOP w0.127: v2(176.51,52.45) PR1401.2 PR1402.1 175.49,53.48 PC1400.1 174.73,53.04 175.22,52.55 PU1400.13
VCCIO_FBS: length 3.4
  TOP w0.203: PU1400.5 173.72,47.77 v1(173.15,47.2) 172.64,46.69 PR1409.1 171.32,46.69 PR1408.2
VCCIO_LPM: length 3.3
  TOP w0.127: PR1400.2 PR1423.2 173.84,53.3 v3(174.65,52.49) 174.72,52.41 PU1400.14
VCCIO_LX:
  vias: v1(171.88,48.32)
VCCIO_SENSE: length 48
  TOP w0.203: v2(161.78,45.97) 161.84,45.91 161.89,45.86 163.45,45.86 163.52,45.93 167.52,45.93 167.69,45.76 170,45.76 v3(170.38,45.39) 170.6,45.17 171.98,45.17 172.19,45.37 PR1409.2
  TOP w0.254: RC165.2 137.39,56.3 v2(138.03,55.66)
  IN2 w0.254: v2(138.03,55.66) 138.03,55.76 139.55,57.29 139.55,58.38 140.18,59.01 147.55,59.01 148.63,57.93 148.63,56.69 151.7,53.62 151.7,49.78 152.81,48.67 155.25,48.67 155.92,47.99 155.92,47.53 157.5,45.96 158.52,45.96 159.36,45.12 160.56,45.12 161.31,45.86 161.68,45.86 v2(161.78,45.97)
  BOTTOM w0.254: v2(138.03,55.66) 138.42,56.05 UCPU1.AM23
VCCIO_SNUB: length 2.6
  TOP w0.127: PR1403.2 168,47.2 v1(167.85,47.06)
  TOP w0.508: PC1410.1 168,48.15 PR1403.2
VCCIO_SS: length 2.9
  TOP w0.127: PC1411.1 174.85,46.64 174.32,46.11 v1(173.89,46.11)
  TOP w0.203: PC1411.1 174.72,46.82 PU1400.7
VCCSENSE: length 98.6
  TOP w0.127: v1(71.5,47.08) 71.25,46.82 PC1014.1 ; v2(133.49,69.81) 133.49,70.73 134,71.24 134.88,71.24 134.9,71.22 RC140.2
  TOP w0.203: PC1014.1 69.7,47.08 68.68,48.09 PR1093.1 68.68,48.6 68.91,48.83 v2(68.91,48.89)
  IN2 w0.089: v2(68.91,48.89) 68.66,49.15 68.66,50.73 68.75,50.82 70.75,50.82 71.67,49.91 72.3,49.91 72.86,50.47 73.27,50.47 73.89,51.08 73.89,58.01 75.34,59.46 75.34,63.53 76.04,64.23 77,64.23 77.85,65.08 77.85,66.02 78.21,66.38 79.3,66.38 79.74,65.93 82.08,65.93 83.19,67.04 96.09,67.04 97.03,66.1 97.03,64.6 98.41,63.22 110.91,63.22 111.61,62.52 114.99,62.52 117.08,64.61 117.97,64.61 118.3,64.94 118.3,65.5 118.84,66.04 119.93,66.04 120.26,66.37 124.09,66.37 125.25,67.53 127.29,67.53 127.6,67.84 132.83,67.84 133.86,68.87 133.86,69.43 v2(133.49,69.81)
  BOTTOM w0.127: v2(133.49,69.81) 133.71,69.59 UCPU1.E32
  BOTTOM w0.254: v2(68.91,48.89) 68.91,48.78 68.68,48.55 PR1093.1 PC1098.2
VCCST_EN: length 63.1
  TOP w0.127: 198.21,55.59 UC13.4 ; 198.21,55.59 198.21,54.63 RE103.1 ; 198.21,55.59 198.21,55.87 197.33,56.74 197.33,60.98 197.65,61.3 197.65,64.39 197.52,64.51 193.87,64.51 v2(192.75,65.63) ; UZ25.4 157.2,76.39 157.42,76.61 157.66,76.61 v2(157.68,76.64)
  IN3 w0.089: v2(167.51,77.3) 167.2,76.98 167.16,77.02 165.67,77.02 164.85,77.85 161.23,77.85 161.16,77.78 161.16,77.76 160.4,76.99 158.03,76.99 v2(157.68,76.64)
  BOTTOM w0.127: v2(167.51,77.3) 169.32,77.3 170.66,78.65 173.31,78.65 174.88,77.07 176.82,77.07 177.23,76.67 177.23,76.46 177.83,75.87 178.4,75.87 178.69,75.57 181.05,75.57 181.55,75.08 182.97,75.08 185.1,72.94 186.7,72.94 187.36,73.61 190.97,73.61 193.05,71.53 193.05,68.01 192.75,67.71 v2(192.75,65.63)
VCCST_PWRGD: length 8.8
  BOTTOM w0.076: UCPU1.B65 115.04,71.87 115.04,72.09 114.99,72.21 114.99,72.47 115.18,72.66 115.18,73.2 114.47,73.91 112.26,73.91 112.09,74.08
  BOTTOM w0.127: v1(109.8,76.08) RC78.2 111.05,76.01 111.05,75.12 112.09,74.08
VCCSTG_EN: length 71.2
  TOP w0.254: UC9.4 166.17,68.92 UZ19.4 166.17,67.74 167.5,67.74 RZ75.1 167.07,68.25 v2(166.76,68.25) ; PR1401.1 176.61,54.15 177.35,54.15 178.33,53.17 v2(180.18,53.17)
  TOP w0.381: v2(159.61,57.97) 159.61,56.27 158.85,55.5 158.85,52.25 159.48,51.62 159.48,51.52 161.1,49.89 164.44,49.89 165.01,50.47 165.5,50.47 165.9,50.06 165.9,49.79 166.17,49.53 166.51,49.53 166.85,49.18 RZ76.1
  IN1 w0.381: v2(166.76,68.25) 166.76,67.58 165.44,66.26 164.21,66.26 163.5,65.55 163.03,65.55 162.13,64.65 162.13,64.18 161.16,63.21 161.16,61.77 159.44,60.05 159.44,59.71 158.97,59.24 158.97,58.71 159.61,58.06 v2(159.61,57.97)
  IN2 w0.254: v2(180.18,53.17) 180.03,53.17 177.75,50.89 177.75,49.86 177.24,49.35 176.84,49.35 174.61,51.58 174.61,55.7 173.53,56.78 173.53,57.59 173.56,57.62 173.56,58.03 173.07,58.52 172.74,58.52 172.54,58.33 171.31,58.33 170.85,58.78 169.41,58.78 168.56,57.93 164.88,57.93 164.06,58.75 164.06,59.29 163.62,59.72 163.09,59.72 161.27,57.9 159.84,57.9 159.76,57.97 v2(159.61,57.97)
VSS_GT_SENSE: length 77.3
  TOP w0.203: PU1000.18 72.49,54.56 73,55.08 v2(73,55.58) 73.28,55.86 PC1092.2 74.85,55.86 PC1099.2
  TOP w0.254: RC163.1 106.91,67.93 106.91,67.55 107.17,67.29 v2(107.17,67.29)
  IN2 w0.254: v2(75.95,69.2) 75.87,69.12 75.87,67.75 73.79,65.67 73.79,62.21 70.62,59.04 67.9,59.04 67.54,58.68 67.54,57.08 68.44,56.18 70.98,56.18 71.45,55.71 72.87,55.71 v2(73,55.58)
  BOTTOM w0.076: UCPU1.J69 112.58,67.43 112.32,67.17 112.04,67.17 111.62,67 111.1,67 110.96,67.13 110.28,67.13 109.91,66.76
  BOTTOM w0.203: 109.91,66.76 109.76,66.61 107.86,66.61 v2(107.17,67.29) 106.9,67.57 106.9,69.82 v1(106.74,69.97) 106.33,70.39 102.05,70.39 99.39,73.05 99.39,73.89 98.57,74.71 95.74,74.71 93.73,72.69 93.73,71.63 93.32,71.22 93.32,69.35 91.63,67.66 86.66,67.66 84.26,70.07 83.94,70.07 83.04,69.17 79.27,69.17 78.79,69.66 76.15,69.66 75.95,69.45 v2(75.95,69.2)
VSSIO_SENSE: length 42.9
  TOP w0.203: v3(168.63,45.33) 168.54,45.41 167.57,45.41 167.38,45.6 163.66,45.6 163.59,45.53 161.99,45.53 161.97,45.51 161.9,45.51 v2(161.78,45.38)
  TOP w0.381: RC167.1 138.28,56.32 v2(138.94,55.66)
  IN2 w0.254: v2(138.94,55.66) 138.94,56.14 139.93,57.13 139.93,58.22 140.34,58.63 147.36,58.63 148.25,57.74 148.25,56.54 151.32,53.46 151.32,49.62 152.66,48.29 155.09,48.29 155.54,47.83 155.54,47.38 157.34,45.58 158.37,45.58 159.2,44.74 160.72,44.74 161.46,45.48 161.67,45.48 v2(161.78,45.38)
  BOTTOM w0.254: v2(138.94,55.66) UCPU1.AM22
VSSSENSE: length 96.7
  TOP w0.127: v2(133.46,69.21) 133.49,69.21 133.91,69.64 133.91,69.97 134.25,70.31 135.51,70.31 135.58,70.24 v1(135.76,70.24) 135.81,70.24 136.34,70.77 RC141.1
  TOP w0.203: v2(68.24,48.86) 69.16,49.78 PU1000.6
  IN2 w0.089: v2(68.24,48.86) 68.44,49.06 68.44,50.82 68.66,51.04 70.84,51.04 71.76,50.12 72.21,50.12 72.77,50.68 73.19,50.68 73.67,51.17 73.67,58.1 75.12,59.55 75.12,63.62 75.95,64.45 76.89,64.45 77.64,65.2 77.64,66.24 77.99,66.59 79.39,66.59 79.83,66.15 81.99,66.15 83.1,67.26 96.18,67.26 97.24,66.19 97.24,64.69 98.5,63.43 115.57,63.43 116.97,64.83 117.88,64.83 118.09,65.03 118.09,65.59 118.75,66.25 119.84,66.25 120.18,66.59 124,66.59 125.16,67.75 127.2,67.75 127.51,68.06 132.61,68.06 132.92,68.36 132.92,68.73 133.41,69.21 v2(133.46,69.21)
  BOTTOM w0.127: UCPU1.E33 133.09,69.59 v2(133.46,69.21)
  BOTTOM w0.203: PC1019.2 67.77,47.38 PC1022.2 67.77,48.66 67.97,48.86 v2(68.24,48.86)
1.2_DDR_LX: length 2.2
  TOP w0.127: 172.92,26.2 173.63,26.2 173.74,26.3 174.57,26.3 v1(174.9,26.63)
+AC_IN: length 1.7
  TOP w0.127: v2(48.97,77.1) v3(48.97,77.71)
  TOP w0.254: PQ213.3 58.93,59.83 59.4,60.3 v2(59.69,60.3)
  vias: v2(48.97,76.51) v2(49.56,77.1) v2(49.56,76.51) v2(50.14,77.1) v2(50.14,76.51) v2(50.72,77.1) v2(50.72,76.51) v2(56.33,62.33) v2(56.4,62.92) v2(58.83,66.16)
+DC_IN: length 41
  TOP w0.102: v3(37.52,77.35) 37.87,77 v3(37.87,75.49) v2(36.62,75.49)
  TOP w0.508: v2(56.21,68.94) 56.21,68.67 PD204.2 ; v2(36.62,75.49) 36.62,75.55 v3(36.14,76.03) 35.81,76.36 34.68,76.36 PR208.1
  IN1 w0.508: v2(36.62,75.49) 36.62,77.11 35.92,77.81 32.01,77.81 v2(31.39,77.2)
  IN2 w0.508: v2(36.62,75.49) 37.26,74.85 37.26,69.71 v2(38.42,68.54)
  BOTTOM w0.508: v2(38.42,68.54) 39.01,67.95 41.44,67.95 41.68,68.2 42.48,68.2 43.62,69.33 49.83,69.33 50.34,68.82 51.92,68.82 52.18,68.55 55.82,68.55 v2(56.21,68.94)
  vias: v2(29.41,77.71) v2(30.99,77.71)
+DC_IN_SS: length 120.5
  TOP w0.508: PR266.1 v2(65.76,13.8) ; PD301.2 37.69,17.26 v1(38.99,15.96) 39.2,15.75 39.2,14.5 v2(39.05,14.35)
  IN2 w0.508: v2(65.76,13.8) 64.75,13.8 63.51,15.04 54.51,15.04 53.91,15.63 51.8,15.63 50.9,14.73 42.31,14.73 41.77,14.19 39.21,14.19 v2(39.05,14.35) 38.48,14.93 37.95,14.93 37.26,15.62 37.26,15.81 33.4,19.67 31.22,19.67 30.53,20.35 30.53,22.44 31.47,23.37 31.47,24.19 33.15,25.87 33.15,31.76 34.13,32.74 34.13,38.58 33.55,39.15 33.55,40.85 32.26,40.85 31.33,41.78 31.33,42.31 31.89,42.87 31.89,43.59 31.55,43.92 31.55,45.3 28.76,48.1 28.17,48.1 27.39,48.88 27.39,52.7 25.79,54.3 25.79,56.08 24.2,57.67 21.13,57.67 20.13,58.67 20.13,60.22 21.29,61.38 21.29,63.98 21.22,64.04 21.22,65.38 21.86,66.02 23,66.02 24.79,67.81 24.79,69.94 26.34,71.48 28.88,71.48 29.9,70.47 32.46,70.47 33.9,71.9 v2(33.9,75.02)
+DCIN_JACK: length 13.2
  TOP w0.127: v2(27.53,78.32) 27.56,78.34 v3(28.17,78.34) 29.26,78.34 30.05,79.13 33.17,79.13 33.93,78.37 35.04,78.37 v3(35.68,79.01) ; 23.98,78.67 23.01,78.67 v3(22.89,78.55)
  TOP w0.508: v2(26.9,78.32) PC103.1 24.99,78.32 PC104.1 PC105.1
+INV_PWR_SRC:
  vias: v2(193.8,26.3) v2(193.8,25.72) v3(193.88,21.88) v3(194.76,25.98) v3(199.88,22.62)
+LCDVDD: length 0.9
  TOP w0.381: 202.16,31.96 202.16,31.96 R289.1
  vias: v2(193.9,35.14) v2(193.91,34.55) v3(197.61,34.27) v3(200.61,34.96) v3(202.16,33.54)
+PBATT: length 65.8
  TOP w0.254: PD300.2 41.77,20.16 41.25,19.64 v2(41.25,18.98)
  IN1 w0.254: v2(41.25,18.98) 41.25,19.11 40.08,20.28 38.94,20.28 38.25,20.96 38.25,21.47 37.43,22.3 37.43,23.95 36.36,25.02 36.36,30.95 39.23,33.82 v2(39.42,33.82)
  IN4 w0.406: v2(76.99,24.11) 74.17,24.11 67.01,16.95 65.35,16.95 64.21,15.81 58.88,15.81 55.63,19.06 55.09,19.06 54.74,18.7 54.74,18.11 53.78,17.15 51.34,17.15 49.76,15.58 43.56,15.58 41.25,17.89 v2(41.25,18.98)
  BOTTOM w0.254: v2(39.42,33.82) 39.22,34.02 PR324.2
+PP_HV: length 91.6
  TOP w0.127: v2(64.01,58) v1(64.62,58)
  TOP w0.254: v2(26.65,61.07) 26.55,60.97 U722.A8 ; PR289.1 64.01,58.64 v2(64.01,58)
  TOP w0.508: v2(57.65,68.84) 57.63,68.86 57.57,68.86 56.74,69.68 PD205.2
  IN1 w0.508: v2(57.65,68.84) 57.65,66.17 56.79,65.31 55.09,65.31 54.03,64.25 v2(53.34,64.25) ; v2(28.4,61.87) 28.4,68.18 28.25,68.33 28.25,71.18 29.72,72.65 34.82,72.65 37.65,75.48 42.47,75.48 44.07,73.87 v2(44.55,73.87)
  IN4 w0.508: v2(53.34,64.25) 53.92,64.25 54.29,64.61 54.29,67.88 53.52,68.65 53.52,71.21 53.01,71.71 46.75,71.71 44.59,73.87 v2(44.55,73.87)
  BOTTOM w0.254: v2(64.01,58) 63.98,57.97 63.37,57.97 62.08,56.68 62.08,53.22 60.25,51.39 60.25,51.04 59.72,50.5 52.45,50.5 51.89,51.06 51.89,52.41 52.3,52.82 52.3,57.31 52.55,57.57 52.55,63.36 53.34,64.14 v2(53.34,64.25)
  BOTTOM w0.508: v2(28.4,61.87) 28.74,62.21 C2984.1 C1341.1
  vias: v2(26.54,61.88) v2(27.14,61.68) v2(27.99,61.3)
+PWR_SRC_AC: length 2.8
  BOTTOM w0.127: v3(47.6,33.74) 47.6,33.4 48.34,32.66 48.34,32.43 PL300.1
+RTC_CELL_VBAT: length 7.3
  TOP w0.254: v2(184.63,59.81) 184.45,59.63 184.45,59.1 184.61,58.93 UE5.B64
  BOTTOM w0.381: CE65.1 187.17,57.34 186.38,58.14 v1(186.3,58.14) 185.35,58.14 184.52,58.96 184.52,59.71 v2(184.63,59.81)
  BOTTOM w0.508: CE65.1 RE32.2
+RTCBATT: length 4.2
  TOP w0.508: v2(15.91,9.28) 15.45,9.74 C2973.1 RTCR1.2
  BOTTOM w0.508: v2(15.91,9.28) 15.91,9.28 JRTC1.1
+RTCVCC: length 307.6
  TOP w0.254: 147.17,44.51 RC56.2 146.91,44.51 146.36,45.07 146.36,45.7 146.58,45.93 146.58,48.08 145.39,49.27 CC213.1
  TOP w0.305: v2(143.93,49.25) 144.42,49.74 CC270.1
  TOP w0.457: v2(98.3,27.72) 96.75,27.72 96.24,28.23 94.45,28.23 93.95,27.73 93.95,26.43 93.62,26.1 89.53,26.1 88.84,26.79 87.9,26.79 87.31,27.37 87.31,27.72 86.39,28.63 81.93,28.63 80.68,29.88 79.17,29.88 77.32,28.03 68.61,28.03 66.7,26.12 v3(63.4,26.12) 61.09,26.12 60.58,25.61 60.58,24.24 60.12,23.78 59.46,23.78 58.52,22.84 56.21,22.84 54.53,24.52 51.44,24.52 50.14,25.82 50.14,27.97 46.41,31.71 v2(44.7,31.71)
  TOP w0.508: RTCR2.2 15.04,13.66 CH95.1 C1309.1 v2(15.9,16.07) 15.9,21.34 17.37,22.82 RA16.1 ; v2(189.33,51.65) 188.95,52.03 RE31.1 ; v2(24.03,34.65) 24.31,34.38 RA54.1 ; 147.17,44.51 RC69.2 RC57.2 ; v2(12.84,8.87) 12.87,8.85 RTCR1.1 ; CC270.1 CC213.1 ; v2(36.6,33.24) 36.58,33.27 35.45,33.27 35.28,33.11 33.16,33.11 32.91,32.85 v2(30.91,32.85)
  IN1 w0.508: v2(24.03,34.65) 26.25,34.65 26.46,34.87 28.94,34.87 30.23,33.59 30.23,33.54 v2(30.91,32.85) 30.91,27.95 31.4,27.46 31.4,24.95 27.45,20.99 26.98,20.99 25.8,19.82 17.49,19.82 15.9,18.23 v2(15.9,16.07)
  IN2 w0.508: v2(183.54,53.29) 183.54,53.73 182.21,55.06 180.12,55.06 178.12,53.06 176.13,53.06 175.72,52.65 v2(175.72,51.8) ; 144.07,50.07 144.83,50.07 146.89,48.02 146.89,45.4 149.53,42.76 154.05,42.76 154.66,42.15 156.16,42.15 158.79,39.52 160.31,39.52 v2(160.5,39.71) ; v2(15.9,16.07) 14.96,15.13 14.96,9.61 14.22,8.87 v2(12.84,8.87)
  IN3 w0.508: v2(175.72,51.8) 175.63,51.71 175.63,48.68 175.16,48.22 175.16,43.9 174.45,43.19 173.71,43.19 173.25,43.65 172.32,43.65 171.71,43.04 169.76,43.04 169.39,43.41 167.38,43.41 166.69,42.72 164.57,42.72 163.03,41.18 162.22,41.18 160.76,39.71 v2(160.5,39.71) ; v2(44.7,31.71) 44.7,32.6 43.97,33.33 41.22,33.33 40.71,32.83 39.07,32.83 38.65,33.24 v2(36.6,33.24) ; v2(193.05,57.7) 193.78,56.97 193.78,51.97 v2(193.02,51.21) 192.06,51.21 190.97,52.29 189.98,52.29 v2(189.33,51.65) ; v2(188.37,54.83) 187.57,55.63 185.24,55.63 183.54,53.93 v2(183.54,53.29)
  BOTTOM w0.152: v2(143.93,49.25) 144.13,49.46 UCPU1.BB14
  BOTTOM w0.254: UCPU1.AK19 141.39,56.82 v2(140.79,56.3)
  BOTTOM w0.508: v2(189.33,51.65) 189.33,52.75 189.16,52.92 189.16,54.32 188.65,54.83 v2(188.37,54.83) 188.06,55.14 RE32.1 ; v2(193.02,51.21) 193.02,51.28 192.14,52.16 RE36.1 ; v2(98.3,27.72) 97.71,28.3 97.71,29.88 98.78,30.95 98.78,31.48 98.63,31.63 98.63,32.27 101.73,35.37 103.15,35.37 106.45,38.67 116.54,38.67 117.58,37.63 150.98,37.63 151.51,37.09 153.09,37.09 156.06,40.07 158.93,40.07 159.3,39.71 v2(160.5,39.71)
+SDC_IN: length 90.4
  TOP w0.508: 19.74,74.66 18.59,73.52 PR204.1 ; 19.74,74.66 PQ205.3 19.74,75.36 20.66,76.29 PR206.1 ; 19.74,74.66 19.74,74 v2(20.09,73.64) ; PR235.1 49.48,71.74 47.35,71.74 46.89,72.2 PQ214.3 45.76,72.21 45.23,72.21 44.72,72.72 v2(44.72,72.88) ; v2(43.41,77.25) 43.41,77.54 43.92,78.05 PR237.1 44.67,78.55 PC208.1
  IN1 w0.508: v2(51.68,49.58) 51.68,48.23 48.81,45.36 48.81,42.95 46.74,40.88 46.74,36.64 43.94,33.84 42.45,33.84 41.4,32.8 41.4,32.19 39.68,30.47 39.68,27.74 41.17,26.25 41.17,25.66 41.63,25.21 44.55,25.21 45.16,25.82 47.13,25.82 v4(48.24,24.71) ; v2(35.35,77.1) 34.68,76.44 29.49,76.44 28.37,77.56 23.85,77.56 22.66,76.36 21.72,76.36 20.09,74.74 v2(20.09,73.64)
  IN2 w0.508: v2(44.72,72.88) 44.88,72.88 46.77,74.77 46.77,75.9 46.08,76.59 44.53,76.59 43.87,77.25 v2(43.41,77.25)
  IN4 w0.508: v2(56.36,58.75) 56.36,55.63 51.83,51.1 51.83,49.73 v2(51.68,49.58)
  BOTTOM w0.254: v2(56.36,58.75) 56.36,58.11 PR223.1
  vias: v2(20.39,17.46) v2(20.38,16.79) v2(20.92,19.18) v2(21.01,17.14) v2(21.51,19.2) v2(21.62,17.13) v2(36.36,78.75) v2(36.67,78.23) v2(36.94,78.76) v2(36.98,77.71) v2(37.29,78.21) v2(37.54,78.76) v3(47.42,24.01) v4(48.24,24.06) v4(48.9,24.67) v4(48.87,24.04) v4(49.51,24.04) v4(49.56,24.67)
+TPM_LPM: length 10.9
  TOP w0.203: v2(184.86,41.33) 184.2,40.68 184.2,39.53 v1(183.97,39.3) 182.98,39.3 182.61,39.67 C98.1 CA72.1 182.61,41.23 182.6,41.25 182.6,42.13 183.33,42.86 U15.8
  BOTTOM w0.203: v2(184.86,41.33) 184.73,41.46 184.73,42.55 184.94,42.76 RC228.2 RC229.2
+V_DDR_REF_CA: length 29.4
  TOP w0.508: RD111.1 94.82,40.14 CD185.1 94.88,40.13 95.5,40.75 101.7,40.75 v2(101.85,40.6)
  IN2 w0.508: v2(114.26,51.84) 113.99,51.57 113.14,51.57 112.93,51.79 111.9,51.79 111.33,51.22 110.9,51.22 110.41,50.73 110.41,48.01 108.54,46.14 108.54,44 106.58,42.05 104.81,42.05 103.69,40.93 102.18,40.93 v2(101.85,40.6)
  BOTTOM w0.305: v2(114.26,51.84) 114.18,51.76 114.18,51.38 113.9,51.1 UCPU1.AY67
+V_DDR_REFA_R: length 26.8
  TOP w0.508: RD113.1 95.33,37.42 95.73,37.83 95.73,38.25 CD186.1 96.42,38.29 96.8,38.67 v2(101.88,38.67)
  IN2 w0.508: v2(112.56,50.75) 112.22,50.42 112.22,48.35 109.73,45.86 109.73,43.49 107.26,41.03 105.23,41.03 102.87,38.67 v2(101.88,38.67)
  BOTTOM w0.305: v2(112.56,50.75) 112.58,50.73 UCPU1.AY68
+V_DDR_REFB_R: length 57.5
  TOP w0.508: v2(140.44,40.14) 139.7,39.4 114.22,39.4 113.77,39.86 111.1,39.86 v2(110.77,40.19) ; RD114.1 CD187.1 152.34,39.2 v2(152.17,39.36)
  IN2 w0.508: v2(110.77,40.19) 110.77,45.4 113.27,47.9 v2(113.27,50.19)
  BOTTOM w0.305: UCPU1.BA67 113.76,50.19 v2(113.27,50.19)
  BOTTOM w0.508: v2(152.17,39.36) 151.45,38.64 v3(141.12,38.64) 140.64,38.64 140.11,39.18 140.11,39.81 v2(140.44,40.14)
+VCHGR:
  vias: v3(75.64,31.56) v4(68.3,30.69) v4(68.94,30.69) v4(70.03,30.65) v4(70.78,30.64) v4(71.95,30.66) v4(72.63,30.66) v4(73.53,32.11)
+VR_CAP: length 7.2
  TOP w0.254: CE45.1 189.89,65.69 189.45,65.69 189.23,65.48 v2(189.15,65.48) ; UE5.B12 187.21,64.77 186.55,64.77 185.95,65.37 v2(185.95,65.64)
  BOTTOM w0.254: v2(189.15,65.48) 189.15,65.14 188.91,64.91 186.66,64.91 185.95,65.61 v2(185.95,65.64)
+VREFCA: length 80.8
  TOP w0.254: v2(120.02,26.3) 119.76,26.04 119.76,25.97 UD20.H4 ; v2(103.84,26.29) 104.17,25.96 UD19.H4 ; UD22.H4 153.32,25.98 v2(153,26.3) ; v2(138.08,26.3) 137.75,25.97 UD21.H4
  TOP w0.381: CD180.1 103.99,20.74 104.22,20.98 104.22,21.23 v2(104.24,21.24)
  TOP w0.457: v2(95.15,30.59) 93.8,30.59 93.12,31.28 93.12,32.1 92.15,33.07 92.15,34.01 89.62,36.53 89.62,39.72 90.06,40.15 RD17.2
  TOP w0.508: RD17.2 90.64,40.13 RD19.1 91.52,40.14 RD111.2
  IN2 w0.508: 100.1,26.37 98.78,26.37 98.57,26.16 98,26.16 96.98,27.19 96.98,28.76 v2(95.15,30.59)
  BOTTOM w0.508: v2(153,26.3) 152.18,26.3 151.69,25.81 151.69,23.63 152.5,22.82 153.47,22.82 154.1,22.18 154.1,21.42 153.9,21.22 CD184.1 153.9,20.02 153.26,19.39 139.29,19.39 138.79,19.9 ; 120.24,19.57 120.41,19.4 124.17,19.4 125.9,21.13 132.7,21.13 134.57,19.26 138.15,19.26 138.79,19.9 ; 120.24,19.57 120.02,19.34 115.32,19.34 114.28,20.38 114.28,21.8 ; 120.24,19.57 CD181.1 ; 138.79,19.9 CD183.1
  vias: v3(111.91,23.48)
+VREFDQ_A: length 46.3
  TOP w0.127: v2(120.02,31.1) 120.34,31.42 UD20.J11
  TOP w0.254: UD19.J11 104.82,31.58 v2(104.5,31.9)
  TOP w0.508: CD118.1 120.37,35.41 v2(120.83,35.87) ; RD21.2 RD25.1 RD113.2 94.95,36.41 95.92,36.41 97.16,37.65 104.09,37.65 105.33,36.41 CD117.1 105.33,34.93 105.88,34.39 v2(106.75,34.39)
  BOTTOM w0.508: v2(120.02,31.1) 120.02,31.47 121.51,32.97 121.51,33.93 121.33,34.12 121.33,35.37 v2(120.83,35.87) 120.67,36.03 117.7,36.03 116.08,37.65 v3(112.5,37.65) 106.91,37.65 105.99,36.74 105.99,35.14 v2(106.75,34.39) 105.89,33.54 105.89,32.85 104.94,31.9 v2(104.5,31.9)
+VREFDQ_B: length 30.7
  TOP w0.254: v2(138.73,31.9) 138.4,31.57 UD21.J11 ; v2(154.3,31.9) 153.97,31.57 153.97,31.5 UD22.J11
  TOP w0.508: v2(153.97,34.31) CD120.1 153.9,35.48 RD26.1 153.9,38.29 RD114.2 RD22.2 ; v2(138.44,33.79) 138.4,33.82 CD119.1
  BOTTOM w0.508: v2(138.73,31.9) 138.41,31.9 137.85,32.46 137.85,33.2 v2(138.44,33.79) v3(139.62,34.97) 140.5,35.85 152.44,35.85 v2(153.97,34.31) 153.42,33.77 153.42,32.43 153.95,31.9 v2(154.3,31.9)
-DCIN_JACK: length 6.6
  TOP w0.381: v2(24.51,72.26) 24.51,72.61 23.41,73.71 v1(23.41,74.45)
  TOP w0.406: PC105.2 23.41,76.71 v1(23.41,74.45)
  TOP w0.508: PC104.2 PC105.2
  vias: v2(24.47,71.68) v2(24.47,71.08) v2(25.11,72.27) v2(25.07,71.69) v2(25.07,71.09)
AC_DET: length 2.6
  TOP w0.127: v1(20.96,78.29) 21.16,78.29 PR215.1
  TOP w0.508: PR206.2 PR215.1
AC_DIS: length 262.2
  TOP w0.127: PQ302.2 36.92,23.02 PR301.1 35.85,23.02 35.41,22.58 35.41,22.23 35.26,22.08 33.17,22.08 v2(32.84,22.41) ; PR228.1 35.68,74.35 v2(35.35,74.69) ; UE5.A50 179.36,57.82 179.36,57.64 178.75,57.02 177.41,57.02 v2(177.32,57.11)
  IN1 w0.081: v2(32.84,22.41) 33.12,22.41 34.39,23.68 34.39,25.65 33.89,26.15 33.89,32.19 32.89,33.2 32.89,35.25 29.87,38.27 28.42,38.27 27.48,37.33 24.22,37.33 23.22,38.34 23.22,52.87 20.32,55.77 20.32,60.09 21.49,61.26 21.49,65.05 18.92,67.62 18.92,68.55 19.41,69.04 20.53,69.04 21.05,68.52 22.87,68.52 25.05,70.69 26.62,70.69 26.62,70.7 29.27,73.35 30.62,73.35 31.29,74.02 31.29,75.68 31.56,75.94 34.09,75.94 v2(35.35,74.69)
  IN2 w0.089: v2(35.35,74.69) 35.35,73.2 36.03,72.51 v2(36.03,70.94)
  IN3 w0.089: v2(170.66,73.11) 171.16,73.61 171.16,76.49 168.94,78.71 152.29,78.71 151.88,79.12 129.11,79.12 129.02,79.03 92.36,79.03 90.16,76.83 84.41,76.83 83.54,75.97 80.37,75.97 79.4,76.94 72.18,76.94 71.53,77.6 70.13,77.6 68.77,78.96 62.97,78.96 62.79,79.14 61.98,79.14 61.75,78.92 56.7,78.92 53.1,75.32 53.1,72.28 52.66,71.84 44.9,71.84 42.07,69.02 39.28,69.02 37.58,70.72 36.25,70.72 v2(36.03,70.94)
  IN4 w0.081: v2(177.32,57.11) 177.29,57.11 177.17,57.24 177.17,58.61 176.26,59.52 176.1,59.52 ; v2(170.66,73.11) 170.66,73.02 171.66,72.02
  IN4 w0.089: 176.1,59.52 175.03,59.52 174.4,60.15 174.4,61.49 173.23,62.66 173.23,64.27 173.14,64.36 173.14,66.4 173.6,66.86 173.6,68.02 172.96,68.65 172.96,71.36 172.3,72.02 171.66,72.02
AC_PRESENT: length 65.1
  TOP w0.127: v2(143.99,48.27) 144.2,48.27 144.58,47.89 144.58,47.6 144.77,47.41 RC243.1 145.21,47.15 145.09,47.02 144.76,47.02 144.59,46.86 144.59,45.84 144.3,45.55 RC319.1 ; UE5.A54 181.36,57.41 v2(180.84,56.89)
  IN3 w0.089: v2(143.99,48.27) 143.82,48.09 143.19,48.09 142.89,48.4 141.68,48.4 141.17,48.9 140.03,48.9 139.52,48.4 139.52,47.48 144.31,42.69 151.19,42.69 151.46,42.96 154.56,42.96 159.88,48.28 160.32,48.28 161.25,49.22 164.7,49.22 168.91,53.43 171.21,53.43 171.54,53.09 172.64,53.09 173.49,53.95 175.65,53.95 178.6,56.89 180.84,56.89 v2(180.84,56.89)
  BOTTOM w0.076: v2(143.99,48.27) 143.72,48 143.45,48 143.14,48.31 143.14,50.14 143.25,50.25 143.25,50.53 UCPU1.AY15
ACAV_IN: length 201.7
  TOP w0.127: v3(187.09,56.81) 186.89,57.01 186.32,57.01 186.32,57.02 v2(186.33,57.02) 186.36,57.05 UE5.A64
  IN1 w0.081: v2(41.44,21.5) 41.44,20.66 43.1,19 43.1,18.02 43.35,17.78 43.35,17.5 43.88,16.96 45.15,16.96 45.4,16.71 45.73,16.71 46.76,17.74 47.49,17.74 48.25,18.51 53.45,18.51 55.17,20.23 62.22,20.23 64.85,17.6 67.17,17.6 69.53,19.96 71.61,19.96 76.26,24.61 78.48,24.61 79.02,24.07 89.33,24.07 89.97,23.43 89.97,22.79 91.2,21.56 91.2,18.36 91.63,17.94 92.41,17.94 93.17,18.7 94.53,18.7 94.78,18.96 101.15,18.96 102.26,17.84 106.97,17.84 107.09,17.96 109.37,17.96 109.49,17.84 115.79,17.84 117.91,15.72 125.63,15.72 127.13,17.21 131.6,17.21 132.44,16.38 147.08,16.38 148.28,17.58 158.5,17.58 159.1,18.19 161.74,18.19 163.25,19.7 172.06,19.7 173.17,20.81 173.17,33.12 171.91,34.39 171.91,36.58 171.46,37.03 171.46,38.08 172.57,39.19 172.57,42.81 172.97,43.21 172.97,44.87 174.59,46.48 174.59,47.15 176.82,49.38 177.16,49.38 178.1,50.33 178.1,52.55 179.28,53.73 179.28,55.37 178.94,55.71 178.94,56.34 179.93,57.33 181.04,57.33 182.72,55.65 184.74,55.65 186.1,57.01 186.32,57.01 186.32,57.02 v2(186.33,57.02)
  BOTTOM w0.127: PR314.1 42.14,21.95 41.68,21.5 v2(41.44,21.5)
ACAV_IN_NB: length 6.2
  TOP w0.127: v2(185.47,67.24) 185.61,67.38 185.61,67.87 UE5.B20
  BOTTOM w0.127: v3(184.79,67.19) 185.42,67.19 v2(185.47,67.24) 185.47,68.16 185.38,68.25 RE102.2 184.75,68.69 184.43,69.01 184.43,69.59 185.22,70.38 DE11.2
AK52: length 1.2
  TOP w0.127: v2(122.48,57.44) 122.48,56.91 T198.1
  BOTTOM w0.127: UCPU1.AK52 v2(122.48,57.44)
ALERT_CORE: length 2.1
  TOP w0.203: PU1000.36 64.96,53.36 PR1076.2
ALW_PWRGD_3V_5V: length 120.2
  TOP w0.381: PR277.1 60.06,31.97 61.06,30.97 65.52,30.97 67.87,33.32 v2(67.87,37.55)
  TOP w0.508: v2(83.54,27.52) 83.54,26.93 80.98,24.37 79.17,24.37 78.46,25.08 v1(75.34,25.08) 75.06,25.08 73.1,23.12 73.1,19.33 74.75,17.69 86.54,17.69 v2(87.71,16.52) ; PR280.2 58.29,54.11 v2(57.86,53.68)
  IN1 w0.508: v2(67.87,37.55) 69.77,35.65 72.01,35.65 74.35,33.31 79.27,33.31 79.63,32.95 v2(79.63,32.67)
  IN2 w0.406: v2(50.02,41.19) 49.9,41.19 49.14,41.95 49.14,49.87 49.78,50.5 50.24,50.5 52.88,53.15 57.33,53.15 v2(57.86,53.68)
  IN2 w0.508: v2(83.54,27.52) 83.54,28.43 79.63,32.34 v2(79.63,32.67) ; v2(92.15,19.54) 91.59,20.1 87.48,20.1 86.72,19.34 86.72,17.51 v2(87.71,16.52)
  IN4 w0.508: v2(50.02,41.19) 50.02,41.2 51,40.22 58.9,40.22 61.32,37.8 63.29,37.8 64.53,36.56 66.88,36.56 v2(67.87,37.55)
  BOTTOM w0.203: v2(92.15,19.54) 92.15,19.57 92.02,19.69 92.02,20.06 91.77,20.31 PU500.9
  BOTTOM w0.508: v2(87.71,16.52) 88.21,17.03 PR502.2 ; v2(67.87,37.55) 67.87,37.65 PR506.1
ALWON: length 181.3
  TOP w0.127: v2(184.46,57.03) 184.36,57.13 UE5.A60 ; v2(92.15,18.55) 93.56,18.55 94.92,19.91 94.92,23.68 94.11,24.49 89.69,24.49 88.77,25.41 85.91,25.41 v2(85.42,24.93)
  IN1 w0.081: v2(64.46,37.5) 66.73,35.22 71.83,35.22 74.17,32.89 78.65,32.89 v2(78.87,32.67)
  IN1 w0.089: v2(184.46,57.03) 183.5,56.08 182.89,56.08 181.15,57.82 179.69,57.82 178.51,56.65 178.51,55.52 178.86,55.17 178.86,53.91 177.56,52.61 177.56,51.51 177.31,51.26 176.66,51.26 175.97,50.57 175.97,49.14 174.16,47.33 174.16,46.66 172.54,45.04 172.54,43.39 172.14,42.99 172.14,39.36 171.03,38.26 171.03,37.26 170.54,36.76 170.54,35.15 172.75,32.94 172.75,20.99 171.88,20.13 163.07,20.13 161.57,18.63 158.92,18.63 158.3,18.01 147.98,18.01 147.37,17.4 132.03,17.4 131.78,17.65 126.95,17.65 125.45,16.15 118.09,16.15 115.97,18.27 109.66,18.27 109.54,18.39 106.91,18.39 106.8,18.27 102.44,18.27 101.23,19.48 94.7,19.48 94.36,19.14 92.74,19.14 v2(92.15,18.55)
  IN2 w0.089: v2(78.87,32.67) 78.87,32.42 82.88,28.41 82.88,27.47 v2(85.42,24.93)
  BOTTOM w0.127: v2(92.15,18.55) 92.34,18.36 92.34,17.8 91.9,17.36 91.59,17.36 91.26,17.03 PR503.1
  BOTTOM w0.203: PR510.1 64.49,37.53 v2(64.46,37.5)
AUD_PWR_EN: length 214.3
  TOP w0.127: v2(33.63,43.77) 33.52,43.66 U664.3 ; U664.5 32.72,43.49 32.54,43.67 32.54,44.1 v2(32.64,44.19) ; v2(37.72,36.99) 37.72,37.22 v3(37.43,37.51) ; v2(53.7,21.79) 53.75,21.74 R1141.1 R1140.1 53.67,20.15 53.27,20.55 U719.5
  IN4 w0.081: v2(37.72,36.99) 37.38,36.65 37.38,35.58 38.54,34.42 38.54,33.98 39.15,33.36 40.39,33.36 40.88,32.86 40.88,31.69 41.03,31.54 41.03,27.46 44.98,23.51 47.8,23.51 47.94,23.38 50.88,23.38 51,23.5 52.83,23.5 53.8,22.54 53.8,21.89 53.72,21.82 ; 53.72,21.82 56.8,21.82 59.3,19.31 61.85,19.31 63.89,21.36 66.02,21.36 69.12,24.46 69.12,25.65 71.57,28.1 74.03,28.1 76.85,30.92 77.7,30.92 78.8,32.02 82.57,32.02 84.03,33.48 84.03,33.48 84.39,33.84 85.63,33.84 85.96,34.17 85.96,34.79 86.55,35.38 90,35.38 90.81,34.57 95.54,34.57 96.61,33.5 96.61,30.08 97.43,29.26 97.43,25.54 97.52,25.45 97.52,23.26 97.84,22.94 99.68,22.94 100.85,21.77 105.85,21.77 107.2,20.41 123.6,20.41 124,20.01 144.57,20.01 145.07,20.51 147.57,20.51 147.98,20.11 160.6,20.11 163.46,22.97 163.46,26.05 162.06,27.44 162.06,28.3 163.73,29.97 163.73,33.41 163,34.14 162.31,34.14 160.44,36.01 160.44,37.32 156.71,41.05 156.71,43.61 155.73,44.59 155.73,45.4 154.82,46.31 154.82,46.99 154.04,47.77 v2(154.04,47.8) ; 53.72,21.82 v2(53.7,21.79)
  BOTTOM w0.076: UCPU1.BA7 148.72,50.03 148.72,49.84 148.87,49.69 149.17,49.69 150.09,48.78 150.34,48.78 150.93,48.19
  BOTTOM w0.127: v2(37.72,36.99) 36.78,36.99 36.35,37.42 35.33,37.42 34.6,38.16 34.6,42.21 33.63,43.18 v2(33.63,43.77) 33.63,43.86 33.29,44.19 v2(32.64,44.19) ; v2(154.04,47.8) 153.65,48.19 150.93,48.19
AUDIO_VREF: length 2.7
  TOP w0.203: UA2.28 23.99,30.68 23.67,31 v2(23.44,31) 23.25,31 23.05,31.2 CA87.1
AUX_EN_WOWL: length 201.9
  TOP w0.127: v2(178.69,65.63) 178.68,65.63 178.53,65.77 178.01,65.77 UE5.B38 ; U720.3 36.53,41.1 36.33,40.89 36.33,40.39 R1186.2 37.31,39.4 37.31,38.56 37.68,38.19 38.05,38.19 v2(38.58,37.65) 38.25,37.32 38.25,36.79 38.04,36.57 37.22,36.57 36.81,36.99 36.09,36.99 35.47,36.38 35.47,35.2 34.85,34.58 QE14.2
  IN2 w0.089: v2(38.58,37.65) 38.58,39.38 39.35,40.14 39.35,46.62 40.56,47.84 40.56,48.37 41.38,49.19 41.38,51.49 42.29,52.4 42.29,54.18 43.1,55 43.1,55.09 43.61,55.59 46.96,55.59 47.91,56.54 47.91,66.39 48.93,67.41 48.93,68.02 51.75,70.84 51.75,72.16 53.15,73.57 53.15,74.93 56.81,78.58 58.89,78.58 v2(59.84,79.54)
  IN3 w0.089: v2(59.84,79.54) 59.84,79.63 60.26,80.04 69.89,80.04 71.3,78.63 72.26,78.63 72.44,78.81 73.24,78.81 73.36,78.69 78.57,78.69 80.64,76.62 83.28,76.62 84.14,77.48 89.2,77.48 89.95,78.24 89.95,78.51 91.12,79.68 152.36,79.68 152.52,79.51 169.99,79.51 171.73,77.77 174.22,77.77 177.77,74.22 179.71,74.22 v2(179.74,74.19)
  IN4 w0.089: v2(179.74,74.19) 179.74,74.09 177.71,72.05 177.71,71.32 177.91,71.13 177.91,69.37 178.32,68.96 178.32,65.99 178.68,65.63 v2(178.69,65.63)
B+: length 100.1
  TOP w0.254: v2(167.75,65.15) 167.95,64.96 PR402.1 ; v2(168.69,62.16) 168.53,62.16 168.18,61.81 PR409.1 ; v2(57.51,52.02) 57.64,51.89 59.77,51.89 60.05,51.61 PR201.1
  TOP w0.381: v2(159.59,42.6) 159.04,42.06 R78.1 ; C615.1 196.89,52.54 v2(196.95,52.47) ; v2(197.71,51.65) 197.21,51.14 C614.1
  TOP w0.508: v2(198.11,78.64) 198.92,77.83 PL1402.1 ; PQ204.3 56.9,52.63 v2(57.51,52.02)
  IN1 w0.381: v2(163.22,35.66) 163.22,36.33 162.36,37.19 162.36,40.47 160.22,42.6 v2(159.59,42.6)
  IN1 w0.508: v2(177.8,80.07) 179.9,77.97 185.76,77.97 188.26,80.48 196.27,80.48 v2(198.11,78.64) 198.36,78.39 202.46,78.39 204.19,80.12 v5(204.39,80.12)
  IN3 w0.762: 198.9,72.83 199.2,73.12 200.27,73.12 200.81,72.58 201.89,72.58 202.65,73.34 202.65,78.37 v5(204.39,80.12)
  BOTTOM w0.254: v2(167.75,65.15) 167.73,65.12 167.73,63.13 v2(168.69,62.16) 169.1,61.75 169.1,55.21 169.47,54.84 170.17,54.84 172.07,52.94 178.93,52.94 179.95,51.91 v2(179.95,51.33)
  BOTTOM w0.381: v2(189.84,48.35) 190.15,48.35 190.41,48.09 C616.1
  BOTTOM w0.508: v2(66.02,37.58) 66.27,37.83 PR508.1 ; v2(163.22,35.66) 163.22,35.29 164.67,33.84 169.47,33.84 170.41,34.78 172.18,34.78 v2(173.25,35.85) ; v2(190.4,50) 190.35,50.05 C617.1
  vias: v2(56.36,51.19) v2(56.51,51.92) v2(56.92,51.02) v2(57.12,51.58) v2(70.08,41.36) v2(70.08,40.73) v2(70.71,41.36) v2(70.71,40.73) v2(70.71,40.09) v2(70.71,39.33) v2(71.35,41.36) v2(71.35,40.73) v2(71.35,40.09) v2(71.35,39.33) v2(71.35,37.8) v2(71.35,37.17) v2(71.98,37.8) v2(71.98,37.17) v2(72.11,39.96) v2(72.11,39.33) v2(92.74,26.7) v2(92.76,27.86) v2(92.77,27.28) v2(93.35,27.87) v2(93.33,26.71) v2(93.33,17) v2(93.36,27.29) v2(93.57,17.64) v2(93.92,17.13) v2(94.5,17.64) v2(95.09,17.64) v2(95.7,17.64) v2(159.89,16.9) v2(160.16,16.36) v2(160.47,16.9) v2(161.01,16.34) v2(161.15,16.91) v2(163.12,17.87) v2(172.95,17.48) v2(173.15,37.63) v2(173.25,36.45) v2(173.26,37.05) v2(173.58,17.48) v2(174.39,36.99) v2(176.35,21.97) v2(176.35,21.33) v2(179.94,50.71) v2(195.25,17.71) v2(195.25,17.13) v2(197.38,67.83) v2(197.97,67.6) v3(195.45,16.09)
BAT1_LED#: length 186.3
  TOP w0.127: v2(175.63,60.86) 174.3,60.86 RE104.2 ; UE5.A40 177.16,63.52 176.63,63.52 176.5,63.39 v2(176.5,63.37)
  IN1 w0.081: v2(175.63,60.86) 175.36,60.59 175.36,59.98 174.88,59.5 174.88,58.33 175.5,57.71 175.5,55.4 174.91,54.82 174.91,54.4 172.57,52.05 172.57,47.2 169.65,44.28 169.65,41.52 168.78,40.66 167.17,40.66 166.52,40.01 166.52,37.96 166.07,37.51 166.07,35.94 166.17,35.84 166.17,32.12 166.31,31.97 166.31,27.76 163.68,25.13 163.68,22.88 160.9,20.1 158.22,20.1 157.6,19.49 126.66,19.49 125.48,18.31 118.97,18.31 117.51,19.77 110.29,19.77 109.44,20.62 103.12,20.62 102.76,20.98 96.94,20.98 94.93,23 94.93,23.57 92.47,26.03 91.93,26.03 91.31,26.64 83.52,26.64 82.88,27.29 76.5,27.29 71.54,22.32 67.99,22.32 67.23,21.57 63.89,21.57 63.04,22.41 56.25,22.41 55.07,23.6 51.25,23.6 50.88,23.23 50.88,22.43 48.65,20.2 43.47,20.2 42.7,20.97 42.7,21.45 v2(43.01,21.77)
  IN2 w0.089: v2(175.63,60.86) 175.98,60.51 176.54,60.51 177.2,61.16 177.2,62.64 176.5,63.33 v2(176.5,63.37)
  BOTTOM w0.127: v2(43.01,21.77) 42.42,21.17 JKB1.10
BAT2_LED#: length 183.8
  TOP w0.127: v2(178.78,63.01) 178.52,63.27 178.01,63.27 UE5.B43
  IN1 w0.081: v2(43.12,21.19) 43.9,20.4 48.56,20.4 50.66,22.5 50.66,23.4 51.07,23.81 55.16,23.81 56.34,22.63 63.13,22.63 63.98,21.78 67.14,21.78 67.9,22.54 71.4,22.54 71.65,22.79 v2(71.65,23.2) 75.95,27.49 82.98,27.49 83.62,26.85 91.94,26.85 95.17,23.63 95.17,23.59 95.5,23.25 95.89,23.25 97.94,21.19 102.88,21.19 103.24,20.84 109.53,20.84 110.39,19.98 117.61,19.98 118.81,18.78 125.65,18.78 126.56,19.7 157.52,19.7 158.13,20.31 160.81,20.31 163.47,22.97 163.47,25.22 165.16,26.91 165.16,34.02 165.31,34.17 165.31,37.09 166.31,38.08 166.31,40.09 167.08,40.87 168.7,40.87 169.44,41.61 169.44,45.33 172.35,48.24 172.35,52.18 174.71,54.53 174.71,54.91 175.28,55.48 175.28,57.63 174.52,58.39 174.52,60.77 174.65,60.9 174.65,61.89 174.8,62.04 177.32,62.04 178.4,63.13 178.66,63.13 v2(178.78,63.01)
  BOTTOM w0.127: v2(178.78,63.01) 178.71,63.08 RE105.2 ; JKB1.9 42.92,20.99 v2(43.12,21.19)
BAT_LED#_LV1: length 12.9
  TOP w0.127: v2(4.49,5.41) 4.76,5.41 R910.2 ; LED12.1 v2(3.13,15.6)
  BOTTOM w0.127: v2(3.13,15.6) 4.49,14.24 v2(4.49,5.41)
BAT_LED#_LV2: length 4.6
  TOP w0.127: LED14.1 3.17,12 v3(3.93,11.25) 5.28,9.89 R911.2
BAT_LED#_LV3: length 3.4
  TOP w0.127: R912.2 v3(3.81,8.59) 2.19,8.59 LED10.1
BAT_LED#_LV4: length 4.5
  TOP w0.127: R913.2 5.06,7.71 v3(3.9,6.55) 2.15,4.8 LED11.1
BAT_LED#_LV5: length 7.3
  TOP w0.127: LED13.1 2.55,1.2 3.66,2.31 v3(3.66,4.35) 3.66,5.19 R916.2
BATBTN#: length 243.4
  TOP w0.203: RPE5.4 190.7,57.51 189.48,56.29 186.87,56.29 186.72,56.44 v2(186.45,56.44) 186.26,56.44 185.86,56.83 UE5.A63
  IN1 w0.508: v2(5.06,19.26) 5.55,19.26 7.26,17.55 7.26,16.49 10.95,12.8 14.92,12.8 17.2,15.07 20.57,15.07 22.89,17.38 36.48,17.38 37.45,16.41 38.78,16.41 39,16.63 42.12,16.63 42.83,15.91 44.72,15.91 44.97,15.66 49.33,15.66 50.34,16.67 54.63,16.67 54.95,16.34 57.45,16.34 58.67,17.56 59.95,17.56 60.34,17.18 65.52,17.18 65.52,17.18 67.35,17.18 69.26,19.09 77.14,19.09 78.79,20.74 78.79,22.78 79.33,23.32 85.64,23.32 91.49,17.48 92.54,17.48 93.35,18.28 95.93,18.28 96.3,17.91 101.07,17.91 101.56,17.42 107.14,17.42 107.26,17.54 109.19,17.54 109.31,17.42 115.61,17.42 117.74,15.3 125.81,15.3 127.31,16.79 131.42,16.79 132.26,15.96 151.02,15.96 152.23,17.16 158.69,17.16 159.3,17.77 161.92,17.77 163.28,19.13 164.48,19.13 166.5,17.1 168.12,17.1 168.98,17.97 172.1,17.97 174.57,20.44 174.57,21.24 175.08,21.75 175.08,25.2 173.6,26.68 173.6,33.3 172.33,34.57 172.33,36.76 171.88,37.21 171.88,37.9 172.99,39.01 172.99,40.49 173.7,41.2 173.7,43 173.46,43.24 173.46,44.05 173.86,44.46 174.01,44.46 174.79,45.24 174.79,45.87 176.76,47.83 176.76,48.05 178.59,49.87 178.59,52.44 179.71,53.55 179.71,54.88 v2(180.5,55.67)
  IN4 w0.381: v2(180.5,55.67) 180.84,55.34 183.06,55.34 183.41,55.69 185.7,55.69 v2(186.45,56.44)
  vias: v3(5.11,18.6)
BATDRV#: length 45.2
  IN3 w0.508: v2(41.12,36.89) 40.87,36.89 40.59,37.17 40.59,37.93 41.17,38.52 49.43,38.52 v2(50.5,37.45)
  IN4 w0.406: v2(77.58,34.4) 77.23,34.04 71.83,34.04 69.9,35.98 64.29,35.98 63.65,36.61 58.83,36.61 58.46,36.97 54.25,36.97 52.96,38.26 51.21,38.26 50.5,37.55 v2(50.5,37.45)
  BOTTOM w0.381: v2(41.12,36.89) 41.12,36.31 41.61,35.82 PR323.2
  BOTTOM w0.508: v2(77.58,34.4) 78.05,33.93 PQ305.4
BATT_LED#_LV1: length 39.9
  TOP w0.127: Q41.3 9.73,6.6 v2(10.11,6.98)
  IN3 w0.089: v2(34.32,15.34) 33.62,16.04 24.17,16.04 23.26,15.13 16.89,15.13 14.88,13.13 11.11,13.13 10.39,12.4 7.79,12.4 6.01,10.63 6.01,8.28 7.3,6.98 v2(10.11,6.98)
  BOTTOM w0.127: UE4.25 33.94,14.97 v2(34.32,15.34)
BATT_LED#_LV2: length 29.5
  TOP w0.127: v2(8.28,10.17) QH9.1 ; v2(32.98,15.32) v1(33.59,15.32)
  IN3 w0.089: v2(32.98,15.32) 32.47,15.83 24.26,15.83 23.35,14.92 16.98,14.92 14.97,12.91 11.28,12.91 8.53,10.17 v2(8.28,10.17)
  BOTTOM w0.127: UE4.26 33.29,15.01 v2(32.98,15.32)
BATT_LED#_LV3: length 32.4
  TOP w0.127: QH9.4 7.54,11.47 7.75,11.26 v2(7.75,9.89) ; v2(32.64,13.7) v1(33.47,13.7)
  IN3 w0.089: v2(7.75,9.89) 7.96,9.67 8.36,9.67 11.38,12.7 16.33,12.7 17.88,14.25 23.95,14.25 23.96,14.24 24.3,14.24 24.31,14.25 24.5,14.25 25.79,15.54 31.61,15.54 32.64,14.51 v2(32.64,13.7)
  BOTTOM w0.127: UE4.27 v2(32.64,13.7)
BATT_LED#_LV4: length 31.9
  TOP w0.127: v2(9.72,8.1) 9.68,8.1 9.33,7.75 QH8.1
  IN3 w0.089: v2(31.99,13.7) 31.99,14.81 31.47,15.33 25.88,15.33 23.53,12.98 16.91,12.98 16.42,12.48 11.49,12.48 7.99,8.98 7.99,8.67 8.26,8.4 9.41,8.4 v2(9.72,8.1)
  BOTTOM w0.127: UE4.28 v2(31.99,13.7)
BATT_LED#_LV5: length 27.6
  TOP w0.127: QH8.4 8.18,9.05 v2(8.41,8.82)
  IN3 w0.089: v2(31.13,14.69) 31.13,14.62 30.35,13.84 24.7,13.84 23.62,12.76 17,12.76 16.49,12.25 11.6,12.25 8.41,9.06 v2(8.41,8.82)
  BOTTOM w0.127: UE4.1 30.96,14.86 v2(31.13,14.69)
BATT_PRS: length 9.9
  TOP w0.127: PRP100.8 67.16,19.29 67.54,19.67 67.54,22.06 v2(66.5,23.1) v1(65.71,23.89)
  BOTTOM w0.127: v2(66.5,23.1) 66.27,23.33 65.51,23.33 65.1,23.73 65.1,26.14 JBATT1.5
BATT_VREF: length 12.1
  TOP w0.127: 164.38,58.47 164.38,58.47 v2(164.97,59.06) ; 164.38,58.47 164.38,59.12 164.5,59.24 PU400.2 ; 164.38,58.47 PC407.1 ; v2(164.34,61.41) 164.4,61.41 165.15,62.16 PU400.6
  BOTTOM w0.127: v3(165.35,61.82) 165.21,61.67 164.55,61.67 164.34,61.45 v2(164.34,61.41) 164.34,60.87 164.84,60.37 165.33,60.37 165.41,60.45 166.13,60.45 PR410.2 PR413.1 165.63,59.98 164.97,59.32 v2(164.97,59.06)
BC_CLK_ECE1117: length 212.6
  TOP w0.127: UE5.A20 184.86,68.72 184.86,69.33 184.81,69.38 v2(184.81,69.43)
  IN1 w0.081: v2(184.81,69.43) 184.81,66.34 183.4,64.92 180.26,64.92 180.03,65.16 178.1,65.16 177.65,64.7 177.65,63.31 177.01,62.66 174.54,62.66 174,62.12 174,61.13 173.9,61.03 173.9,58.13 174.41,57.62 174.41,57.08 174.06,56.74 174.06,56.62 173.98,56.54 173.31,56.54 173.23,56.47 173.23,56.29 173.31,56.22 173.98,56.22 174.06,56.14 174.06,55.97 173.98,55.89 173.26,55.89 173.18,55.81 173.18,55.65 173.26,55.57 173.98,55.57 174.06,55.49 174.06,55.32 173.98,55.24 173.26,55.24 173.18,55.16 173.18,55 173.26,54.92 173.84,54.92 173.91,54.84 173.91,54.64 171.71,52.44 171.71,48.5 168.79,45.58 168.79,44.76 167.04,43.01 166.93,43.01 165.92,44.02 165.8,44.02 165.69,43.9 165.69,43.79 166.7,42.78 166.7,42.67 166.58,42.55 166.47,42.55 165.46,43.56 165.34,43.56 165.23,43.44 165.23,43.33 166.24,42.32 166.24,42.21 166.12,42.09 166.01,42.09 165,43.1 164.88,43.1 164.77,42.98 164.77,42.87 165.78,41.86 165.78,41.75 165.66,41.63 165.55,41.63 164.54,42.64 164.42,42.64 164.31,42.52 164.31,42.41 165.32,41.4 165.32,41.29 165.08,41.05 164.8,41.05 163.93,41.05 163.79,40.91 163.79,39.56 164.06,39.29 164.06,37.12 163.87,36.94 163.87,33.91 164.06,33.73 164.06,28.49 156.1,20.53 126.21,20.53 125.29,19.61 119.15,19.61 117.95,20.82 112.45,20.82 110.8,22.46 102.9,22.46 102.66,22.23 98.09,22.23 96.66,23.65 96.66,26.68 92.26,31.09 91.85,31.09 90.25,32.69 88.19,32.69 87.85,33.03 83.88,33.03 81.59,30.74 76.62,30.74 72.87,27 63.95,27 63.24,26.29 60.14,26.29 58.29,24.44 50.81,24.44 50.03,23.66 50.03,22.82 49.68,22.47 48.38,22.47 47.3,23.55 44.63,23.55 44.52,23.45 44.52,22.73 43.83,22.05 v2(43.83,21.55)
  BOTTOM w0.127: JKB1.8 43.42,20.67 43.83,21.09 v2(43.83,21.55)
BC_DAT_ECE1117: length 217.9
  TOP w0.127: RPE5.1 190.68,59.01 v2(190.05,59.65) ; v2(44.11,17.37) 45.31,16.16 46.32,16.16 v1(47.02,15.46) ; UE5.B21 185.11,67.46 185.02,67.37 185.02,66.84 185.44,66.42 185.69,66.42 v2(185.7,66.43)
  IN1 w0.089: v2(190.05,59.65) 188.12,57.72 186.32,57.72 184.46,55.86 182.8,55.86 181.13,57.54 179.84,57.54 178.73,56.43 178.73,55.63 179.07,55.29 179.07,53.82 177.78,52.52 177.78,51.42 177.4,51.04 176.75,51.04 176.19,50.48 176.19,49.05 174.37,47.24 174.37,46.57 172.76,44.95 172.76,43.3 172.35,42.9 172.35,39.27 171.25,38.17 171.25,37.17 170.92,36.84 170.92,35.07 172.96,33.03 172.96,20.9 171.97,19.91 163.16,19.91 161.65,18.4 159.01,18.4 158.4,17.8 148.07,17.8 147.46,17.18 131.94,17.18 131.69,17.43 127.03,17.43 125.54,15.93 118,15.93 115.88,18.06 109.57,18.06 109.45,18.17 107,18.17 106.88,18.06 102.35,18.06 101.24,19.17 94.7,19.17 94.45,18.92 93.09,18.92 92.32,18.15 91.71,18.15 91.42,18.45 91.42,21.65 91.03,22.03 91.03,23.13 89.88,24.28 79.11,24.28 78.57,24.82 76.17,24.82 71.52,20.18 69.44,20.18 67.08,17.81 64.95,17.81 62.32,20.44 55.09,20.44 53.36,18.72 48.17,18.72 47.4,17.95 45.98,17.95 45.59,17.55 44.34,17.55 44.16,17.37 v2(44.11,17.37)
  IN4 w0.089: v2(185.7,66.43) 186,66.73 186.25,66.73 186.43,66.56 186.76,66.56 186.76,66.56 187.54,65.78 187.54,64.69 189.15,63.08 189.15,61.8 189.46,61.5 189.46,60.58 190.05,59.99 v2(190.05,59.65)
  BOTTOM w0.127: JKB1.7 43.92,19.95 43.46,19.49 43.46,17.94 44.03,17.37 v2(44.11,17.37)
BC_INT#_ECE1117: length 198.4
  TOP w0.127: v1(43.87,19.21) 43.87,20.64 44.63,21.4 v2(44.63,21.88) ; v2(185.45,69.43) 185.36,69.34 UE5.A19
  IN1 w0.081: v2(185.45,69.43) 185.06,69.05 185.06,66.26 183.52,64.72 180.18,64.72 179.94,64.95 178.19,64.95 177.86,64.62 177.86,63.19 177.13,62.46 174.63,62.46 174.21,62.04 174.21,61.05 174.11,60.95 174.11,58.22 174.63,57.69 174.63,57.01 174.27,56.65 174.27,54.69 171.92,52.34 171.92,48.42 169,45.5 169,44.68 165.17,40.84 164.72,40.84 164,40.12 164,39.65 164.27,39.38 164.27,37.04 164.08,36.85 164.08,34 164.27,33.81 164.27,28.34 156.25,20.32 126.29,20.32 125.38,19.4 119.07,19.4 117.86,20.61 112.36,20.61 110.72,22.25 103,22.25 102.76,22.01 98.01,22.01 96.45,23.56 96.45,26.6 92.17,30.88 91.76,30.88 90.17,32.47 88.11,32.47 87.76,32.82 83.97,32.82 81.68,30.53 76.71,30.53 72.96,26.78 64.04,26.78 63.33,26.07 60.22,26.07 58.21,24.06 55.5,24.06 55.33,24.23 50.9,24.23 50.24,23.57 50.24,22.68 48.39,20.82 45.15,20.82 44.63,21.34 v2(44.63,21.88)
  BOTTOM w0.127: JKB1.6 44.42,20.36 44.42,21.19 44.63,21.4 v2(44.63,21.88)
BEEP: length 244.4
  TOP w0.127: RA24.1 25.4,38.59 26.09,39.28 26.09,40.14 v1(26.79,40.85) 29.11,43.16 30.94,43.16 v2(32.54,44.77) ; UE5.B19 186.11,67.29 v2(186.06,67.24)
  IN3 w0.089: v2(61.99,47.96) 62.9,47.05 64.67,47.05 65.55,46.17 68.39,46.17 70.91,43.65 80.63,43.65 82.19,45.21 84.59,45.21 86.03,43.78 86.03,36.48 87.69,34.83 89.87,34.83 90.07,34.63 95.26,34.63 96.74,33.16 96.74,24.04 98.9,21.88 105.79,21.88 107.03,20.64 116.73,20.64 118.19,22.11 124.51,22.11 125.17,21.45 133.22,21.45 133.32,21.54 134.42,21.54 135.22,20.74 155.83,20.74 158.95,23.85 158.95,25.63 159.45,26.13 159.45,27.79 160.53,28.88 160.53,29.83 162.46,31.76 162.64,31.76 163.16,32.28 163.16,33.7 162.2,34.66 162.2,37.45 162.87,38.11 163.22,38.11 163.57,38.46 163.75,38.46 165.9,38.46 166.43,38.99 170.52,38.99 171.23,39.7 173.97,39.7 174.33,39.34 179.81,39.34 180.3,39.83 180.3,42.82 180.21,42.91 179.07,42.91 176.26,45.72 176.26,50.73 176.79,51.26 177.22,51.26 177.49,51.53 177.49,52.42 179.08,54.01 180.63,54.01 181.33,54.71 182.19,54.71 183.45,55.98 183.45,57.37 182.74,58.08 182.74,60.59 183.08,60.94 183.08,63.53 184.38,64.83 184.38,65.68 185.54,66.84 185.66,66.84 v2(186.06,67.24)
  BOTTOM w0.127: v2(61.99,47.96) 62.33,48.3 62.33,49.23 61.63,49.93 55.65,49.93 55.64,49.92 52.69,49.92 51.83,49.06 51.83,45.05 52.13,44.75 52.13,42.95 51.31,42.13 50.76,42.13 50.24,42.65 49.36,42.65 48.41,43.61 42.77,43.61 42.67,43.71 41.87,43.71 41.75,43.58 38.43,43.58 37.24,44.78 34.56,44.78 34.47,44.69 32.63,44.69 v2(32.54,44.77)
BIA_PWM_EC: length 53.8
  TOP w0.127: UE5.B25 183.11,67.72 183.48,67.35 183.48,66.74 183.29,66.56 v2(183.03,66.56) ; D73.3 190.05,31.33 190.98,31.33 191.24,31.07 v3(192.63,31.07) v2(197.21,31.07)
  IN4 w0.089: v2(183.03,66.56) 183.03,66.25 185.5,63.78 186.46,63.78 187.5,62.74 187.5,60.79 187.66,60.64 187.66,58.99 188.3,58.35 188.98,58.35 190.01,57.32 190.01,53.4 190.66,52.76 190.79,52.76 193.21,50.33 193.45,50.33 195.22,48.56 195.22,35.87 197.67,33.42 197.67,31.54 v2(197.21,31.07)
BOARD_ID: length 8.2
  TOP w0.127: UE5.B10 186.12,63.77 v2(185.62,64.27)
  BOTTOM w0.127: v2(185.62,64.27) 186.18,63.71 187.95,63.71 188.06,63.83 CE54.1 188.95,64.27 v3(189.17,64.49) 189.41,64.73 189.76,64.73 190.39,65.35 RE79.2
BQ24777_REGN: length 25.6
  TOP w0.203: v2(36.79,33.88) 36.79,33.75 37.57,32.98 PR325.1 ; v2(46.84,32.47) 44.73,32.47 43.51,31.25 43.51,27.95 42.65,27.09 42.65,25.48 v2(40.87,23.7)
  IN3 w0.203: v2(36.79,33.88) 38.7,33.88 39.26,33.32 40.53,33.32 41.02,33.82 44.35,33.82 45.7,32.47 v2(46.84,32.47)
  BOTTOM w0.203: v2(40.87,23.7) 40.87,23.88 PR312.1
BREATH_LED#: length 68.3
  TOP w0.127: UE5.B57 181.11,58.97 181.24,59.1 v2(181.24,59.85)
  IN4 w0.081: v2(202.36,17.18) 202.5,17.32 203.09,17.32 205.16,19.39 205.16,20.68 203.2,22.64 201.47,22.64 200.4,23.71 198.17,23.71 195.8,26.08 195.8,33.09 194.96,33.93 193.82,33.93 193.5,34.25 193.5,46.1 190.85,48.75 190.85,50.15 190.54,50.45 188.79,50.45 185.89,53.35 185.89,54.59 187.53,56.22 187.53,57 186.39,58.14 182.23,58.14 181.51,58.87 181.51,59.58 v2(181.24,59.85)
  BOTTOM w0.127: v2(202.36,17.18) 202.08,16.9 199.03,16.9 198.21,16.08 198.21,15.54 JIO1.41
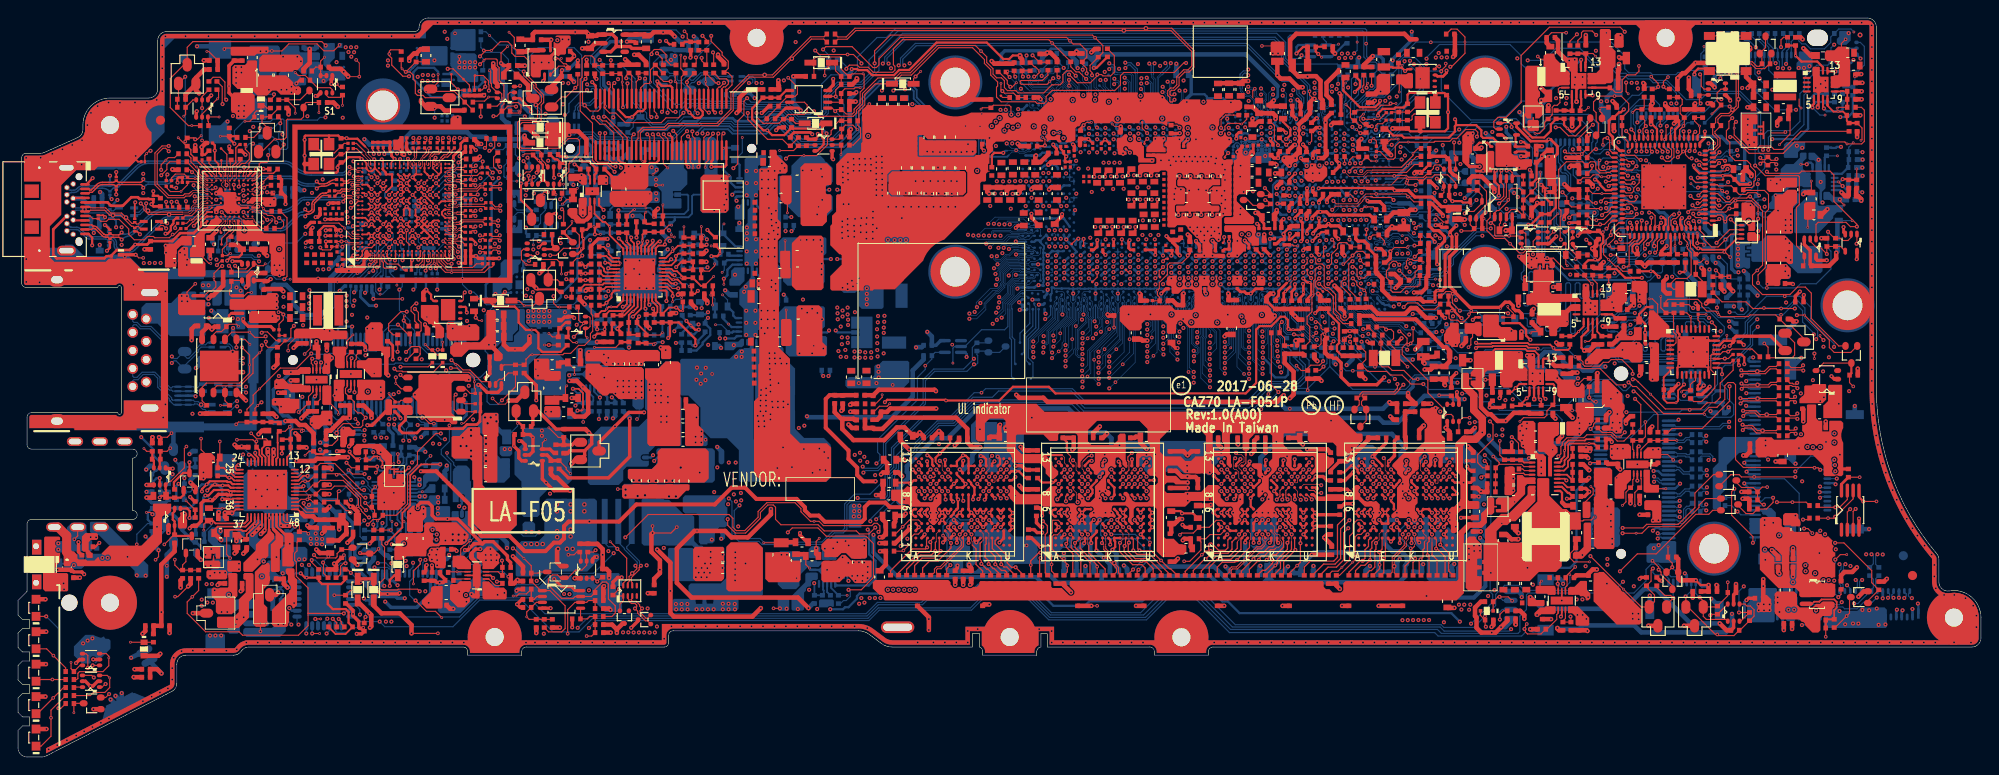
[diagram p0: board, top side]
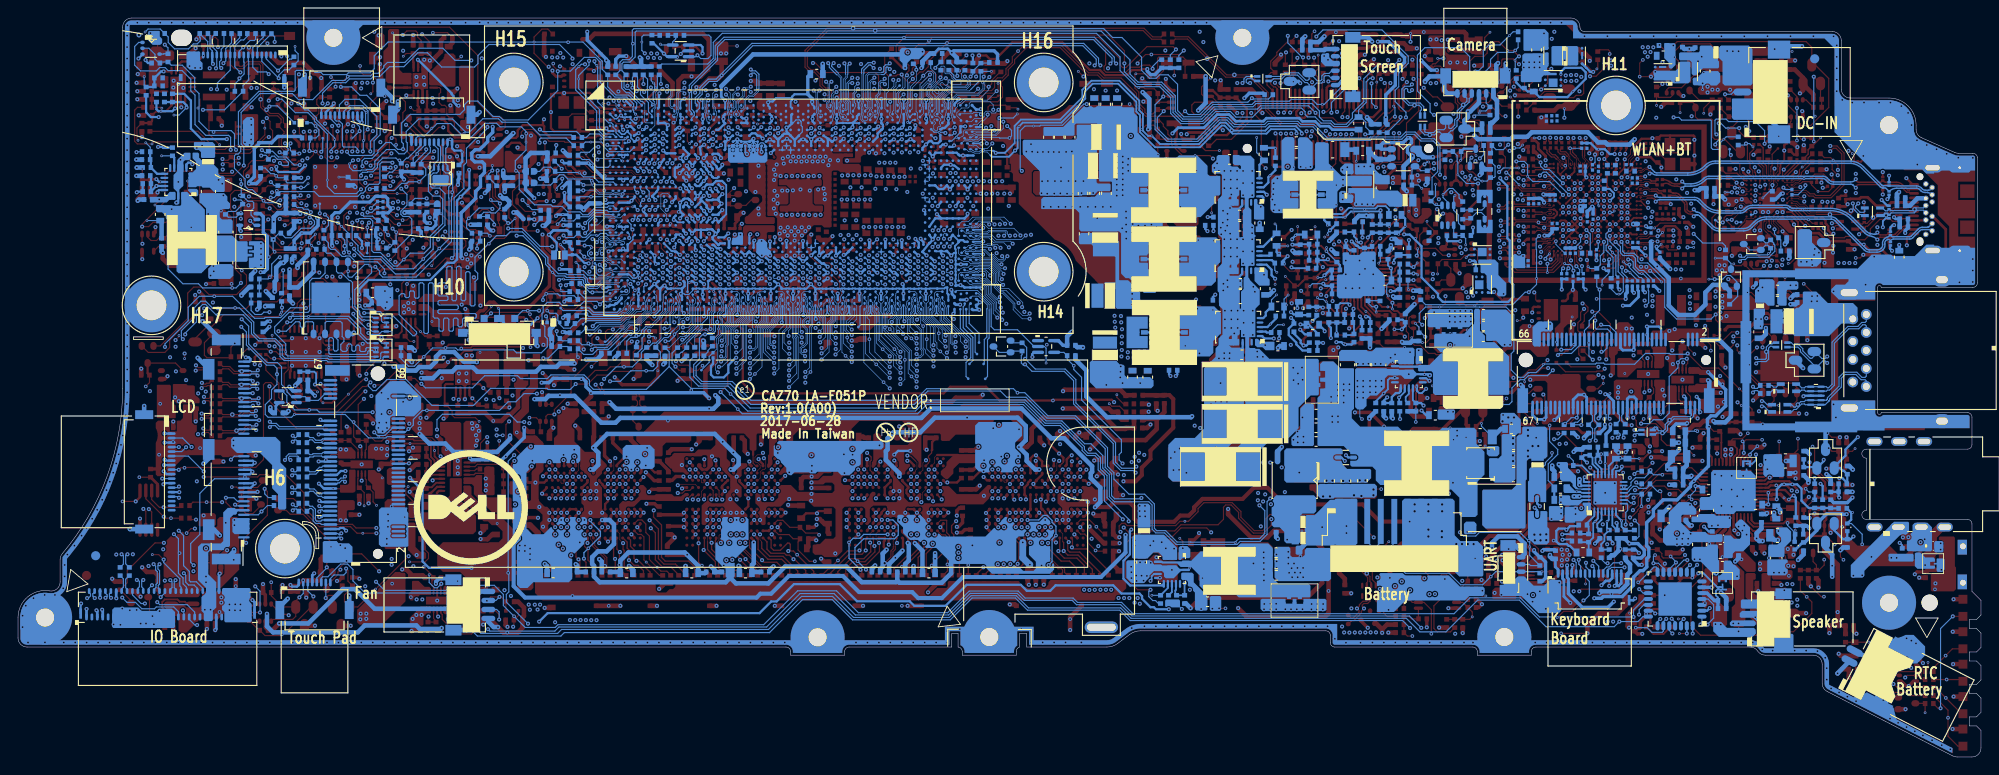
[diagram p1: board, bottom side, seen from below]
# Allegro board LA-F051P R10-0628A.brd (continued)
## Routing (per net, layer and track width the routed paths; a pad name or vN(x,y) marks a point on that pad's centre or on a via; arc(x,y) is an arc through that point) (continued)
BT_RADIO_DIS#: length 46.7
  TOP w0.127: DZ2.1 45.5,43.29 v2(42.44,43.29) ; RE13.2 35.36,14.89 v2(34.93,15.33)
  IN4 w0.081: v2(34.93,15.33) 34.93,16.11 34.44,16.6 34.44,21.76 34.95,22.27 34.95,26.54 33.72,27.77 33.72,32.7 34.59,33.57 34.59,34.77 34.84,35.03 34.84,39.15 34.52,39.47 34.52,41.37 34.65,41.49 34.65,42.54 35.59,43.49 42.25,43.49 v2(42.44,43.29)
  BOTTOM w0.127: v2(34.93,15.33) 35.24,15.01 UE4.23 35.24,13.97 35.37,13.84 36.52,13.84 37.04,14.35 v3(38.31,14.35)
BT_RADIO_DIS#_R: length 5.8
  TOP w0.127: v1(45.19,45.78) 45.81,45.16 DZ2.2 46.53,44.6 v2(46.95,44.6)
  BOTTOM w0.127: JNGFF1.46 44.5,45.72 45.44,44.78 46.77,44.78 v2(46.95,44.6)
CAM_CBL_DET#: length 139
  TOP w0.102: 150.09,62.48 149.54,62.48 148.9,61.84 148.9,61.71 148.57,61.38 146.27,61.38 145.96,61.69 v2(145.96,61.71)
  TOP w0.127: RC280.1 155.5,61.6 154.89,61.6 154.02,62.48 v3(150.7,62.48) 150.09,62.48
  IN3 w0.089: v2(56.24,71.08) 56.24,71.6 57.29,72.65 59.34,72.65 60.35,71.65 64.1,71.65 64.86,72.4 77.88,72.4 79.6,70.68 89.25,70.68 89.59,71.02 90.91,71.02 91.6,71.71 96.63,71.71 97.74,70.6 106.36,70.6 108.57,72.82 109.68,72.82 109.83,72.97 111.58,72.97 112.24,73.63 116.91,73.63 117.21,73.94 118.28,73.94 118.87,73.35 118.87,72.65 119.21,72.31 119.75,72.31 120.98,73.54 123.07,73.54 123.43,73.9 123.43,75.15 124.14,75.86 129.78,75.86 131.86,73.78 134.73,73.78 135.31,73.2 136.64,73.2 137.36,73.92 137.36,75.02 138.47,76.13 145.34,76.13 145.6,75.87 150.95,75.87 152.59,74.23 152.59,73.13 152.95,72.77 152.95,66.24 153.15,66.03 153.15,65.65 150.61,63.11 147.36,63.11 v2(145.96,61.71)
  BOTTOM w0.127: UCPU1.AB11 146.14,61.53 v2(145.96,61.71) ; v2(56.24,71.08) 56.08,71.23 RH438.1
CAM_CBL_DET#_R: length 2.9
  BOTTOM w0.127: v1(55.58,71.69) 54.94,71.69 RH438.2 54.9,72.56 JCAM.2
CFG0: length 51
  TOP w0.127: RC113.2 110.53,75.61 v2(110.66,75.48) ; v2(77.72,74.78) 77.7,74.8 77.41,74.8 RC126.1 v1(76.3,74.93) 76.3,74.6 76.6,74.3 JXDP1.9
  IN4 w0.081: v2(110.66,75.48) 110.34,75.81 108.58,75.81 107.35,74.57 107.35,73.37 105.71,71.73 105.37,71.73 105.03,71.39 101.65,71.39 100.07,72.98 95.6,72.98 95.26,73.31 92.61,73.31 92.11,73.81 87.8,73.81 87.42,73.43 82.61,73.43 82.46,73.58 78.91,73.58 77.98,74.52 77.98,74.52 v2(77.72,74.78)
  BOTTOM w0.076: v2(110.66,75.48) 110.74,75.4 110.74,74.17 111.34,73.57 113.66,73.57 114.18,73.04 114.18,72.84 114.33,72.69 114.33,72.54 114.34,72.54 114.34,72.18 114.33,72.17 114.3,72.08 114.3,71.94 114.31,71.85 114.33,71.77 114.34,71.71 114.34,71.6 114.33,71.59 114.33,71.55 114.31,71.49 114.28,71.4 114.24,71.21 114.2,70.96 114.12,70.69 114.12,70.58 UCPU1.E68
CFG1: length 47.4
  TOP w0.127: v1(110.78,74.82) 110.33,74.37 v2(110.1,74.37) 109.77,74.71 109.77,75.08 108.83,76.02 RC112.2 ; JXDP1.11 76.1,71.93 76.52,71.51 v2(76.66,71.51)
  IN4 w0.081: v2(76.66,71.51) 77.06,71.92 78.61,71.92 79.48,71.04 84.44,71.04 84.59,70.9 91.22,70.9 91.63,71.31 95.37,71.31 96.1,70.58 98.91,70.58 99.31,70.18 105.49,70.18 105.86,70.54 106.2,70.54 108.33,72.68 109.5,72.68 110.1,73.28 v2(110.1,74.37)
  BOTTOM w0.076: UCPU1.B67 113.77,71.79 113.77,71.97 113.54,72.2 113.54,72.43 113.35,72.63 113.23,72.63 112.8,73.06 111.08,73.06 110.1,74.03 v2(110.1,74.37)
CFG2: length 49.2
  TOP w0.127: JXDP1.15 75.1,71.75 v2(75.41,71.43)
  IN4 w0.081: v2(75.41,71.43) 75.41,71.44 76.45,72.48 79.35,72.48 79.97,71.87 83.91,71.87 84.67,71.1 91.13,71.1 91.55,71.52 95.46,71.52 96.19,70.79 99,70.79 99.4,70.39 105.41,70.39 105.77,70.75 106.11,70.75 108.29,72.93 109.37,72.93 109.68,73.24 109.68,74.5 109.99,74.82 110.61,74.82 v2(111.28,74.15)
  BOTTOM w0.076: v2(111.28,74.15) 111.68,73.75 114.39,73.75 114.99,73.14 114.99,72.71 114.82,72.54 114.82,72.18 114.86,72.08 114.86,71.89 114.82,71.8 114.82,71.55 114.83,71.5 114.93,71.18 114.96,71.07 114.96,70.96 115.04,70.69 115.04,70.58 UCPU1.D65
CFG3: length 50.8
  TOP w0.127: JXDP1.17 74.6,74.17 74.22,74.54 v2(74.22,74.88) 74.22,75.07 RC121.2 ; v2(110.03,75.45) 109.64,75.84 RC110.2
  IN4 w0.081: v2(110.03,75.45) 109.58,75.45 108.05,73.92 108.05,73.79 105.79,71.53 105.45,71.53 105.11,71.18 100.08,71.18 99.29,71.97 97.97,71.97 97.61,72.32 92.41,72.32 92.04,72.69 80.24,72.69 79.66,73.27 75.84,73.27 v2(74.22,74.88)
  BOTTOM w0.076: v2(110.03,75.45) 110.54,74.94 110.54,74.14 111.29,73.38 113.61,73.38 114.02,72.97 114.02,72.77 114.17,72.62 114.17,72.21 114.11,72.09 114.11,71.94 114.17,71.75 114.17,71.57 114.08,71.32 114.05,71.26 114.05,71.16 UCPU1.D67
CFG4: length 49.3
  TOP w0.127: v2(110.22,71.29) 110.18,71.33 110.18,72.13 109.98,72.32 108.23,72.32 RC109.2 107.01,72.04 v1(106.86,71.89) ; JXDP1.27 72.1,72.93 72.1,72.09 72.6,71.59 v2(72.96,71.59)
  IN4 w0.081: v2(72.96,71.59) 73.52,71.03 75.79,71.03 75.87,71.1 79.13,71.1 79.4,70.83 84.35,70.83 84.5,70.69 91.3,70.69 91.72,71.1 95.29,71.1 96.02,70.37 98.83,70.37 99.23,69.97 105.58,69.97 105.95,70.34 106.28,70.34 108.4,72.45 109.81,72.45 110.22,72.04 v2(110.22,71.29)
  BOTTOM w0.076: v2(110.22,71.29) 110.22,71.04 110.67,70.6 110.94,70.6 111.33,70.21 111.74,70.21 111.93,70.01 UCPU1.E70
CFG5: length 48.6
  TOP w0.127: v2(71.45,71.59) 71.6,71.73 JXDP1.29
  IN4 w0.081: v2(109.6,71.81) 109.2,72.22 108.46,72.22 106.37,70.13 106.03,70.13 105.67,69.76 99.14,69.76 98.74,70.16 95.93,70.16 95.2,70.9 91.81,70.9 91.39,70.48 84.41,70.48 84.27,70.63 79.31,70.63 79.08,70.85 75.92,70.85 75.88,70.82 72.14,70.82 71.45,71.51 v2(71.45,71.59)
  BOTTOM w0.076: v2(109.6,71.81) 109.6,72.37 109.94,72.71 112.09,72.71 112.27,72.53 112.27,72.14 112.4,72.02 113.11,72.02 113.64,71.48 113.64,71.15 113.18,70.69 UCPU1.C68
CFG6: length 47.6
  TOP w0.127: v2(70.87,71) 70.87,71.4 70.6,71.66 JXDP1.33
  IN4 w0.081: v2(70.87,71) 71.28,70.59 76.56,70.59 76.62,70.65 78.99,70.65 79.22,70.42 84.18,70.42 84.33,70.27 91.48,70.27 91.89,70.69 95.11,70.69 95.84,69.96 98.65,69.96 99.66,68.95 105.53,68.95 105.61,69.03 105.61,69.41 106.12,69.92 106.49,69.92 108.57,72 108.84,72 v2(109.02,71.81)
  BOTTOM w0.076: v2(109.02,71.81) 109.37,71.46 109.78,71.46 109.98,71.66 110.39,71.66 110.62,71.43 110.62,71.05 110.82,70.85 111.67,70.85 111.99,70.53 UCPU1.D68
CFG7: length 48.6
  TOP w0.127: JXDP1.35 70.1,73.05 70.1,71.18 v2(70.28,71)
  IN4 w0.081: v2(110.97,71.31) 110.55,70.88 109.95,70.88 109.45,71.38 108.25,71.38 107.2,70.34 107.2,69.82 106.12,68.74 99.58,68.74 98.57,69.75 95.76,69.75 95.03,70.48 91.98,70.48 91.56,70.06 84.24,70.06 84.09,70.21 79.14,70.21 78.91,70.44 76.71,70.44 76.65,70.38 71.44,70.38 71.35,70.29 70.99,70.29 v2(70.28,71)
  BOTTOM w0.076: v2(110.97,71.31) 110.97,71.4 111.08,71.51 111.77,71.51 111.9,71.38 113.23,71.38 UCPU1.C67
CFG8: length 43.1
  TOP w0.127: v2(77.11,69.17) 77.11,69.07 76.6,68.56 76.6,67.33 JXDP1.10 76.6,66.22 76.25,65.87 v1(76.25,65.44)
  IN4 w0.081: v2(77.11,69.17) 77.11,68.94 77.32,68.74 78.54,68.74 78.76,68.96 82.07,68.96 82.99,68.05 91.43,68.05 91.88,68.5 98.05,68.5 99.83,66.71 107.26,66.71 107.7,67.15 107.7,68.16 109.02,69.48 109.02,69.74 109.28,70 v2(109.82,70)
  BOTTOM w0.076: UCPU1.F71 111.87,69.45 110.19,69.45 109.82,69.82 v2(109.82,70)
CFG9: length 43.3
  TOP w0.127: v2(76.53,69.17) 76.1,68.74 76.1,67.33 JXDP1.12
  IN4 w0.081: v2(108.05,70.01) 108.05,69.66 107.67,69.27 107.54,69.27 106.38,68.11 99.32,68.11 98.31,69.12 95.5,69.12 94.87,69.75 93.74,69.75 93.11,69.12 91.62,69.12 91.17,68.67 83.25,68.67 82.33,69.58 78.88,69.58 78.65,69.81 76.97,69.81 76.53,69.38 v2(76.53,69.17)
  BOTTOM w0.076: UCPU1.G69 112.69,68.56 112.43,68.56 112.22,68.48 112.08,68.48 111.85,68.55 111.71,68.55 111.6,68.49 111.33,68.49 111.07,68.75 108.96,68.75
  BOTTOM w0.127: 108.96,68.75 108.88,68.67 107.81,68.67 v3(107.79,68.69) 107.57,68.91 107.57,69.53 v2(108.05,70.01)
CFG10: length 44.1
  TOP w0.127: JXDP1.16 75.1,68.65 74.83,68.92 v2(74.83,69.43)
  IN4 w0.081: v2(74.83,69.43) 74.83,68.92 75.21,68.53 78.62,68.53 78.84,68.75 81.99,68.75 82.9,67.84 91.51,67.84 91.96,68.29 97.96,68.29 99.75,66.51 107.34,66.51 107.9,67.07 107.9,68.05 108.29,68.44 108.3,68.44 109.37,69.52 v2(109.45,69.52)
  BOTTOM w0.076: v2(109.45,69.52) 109.7,69.27 111.47,69.27 112.04,69.02 112.3,69.02 UCPU1.F70
CFG11: length 47.4
  TOP w0.127: v2(74.35,68.87) 74.6,68.62 JXDP1.18 74.6,66.05 74.91,65.74 v1(74.91,65.36)
  IN4 w0.081: v2(110.4,69.82) 110.4,69.59 109.71,68.9 109.05,68.9 108.38,68.23 108.38,68.23 108.11,67.97 108.11,66.98 107.43,66.3 99.66,66.3 97.88,68.07 92.04,68.07 91.6,67.63 82.81,67.63 81.9,68.54 78.93,68.54 78.71,68.32 74.89,68.32 v2(74.35,68.87)
  BOTTOM w0.076: UCPU1.G68 113.01,68.88 112.93,68.95 112.93,69.43 112.78,69.58 112.17,69.58 112.1,69.65 111.66,69.65 111.64,69.63 110.59,69.63 v2(110.4,69.82)
CFG12: length 47.5
  TOP w0.127: JXDP1.28 72.1,68.58 71.64,69.04 v2(71.64,69.11)
  IN4 w0.081: v2(109.7,68.08) 109.75,68.03 109.75,66.61 108.82,65.67 99.4,65.67 97.63,67.45 92.3,67.45 91.86,67 83.32,67 82.78,66.47 81.03,66.47 79.84,67.65 73.1,67.65 v2(71.64,69.11)
  BOTTOM w0.076: v2(109.7,68.08) 110.26,67.52 111.13,67.52 111.47,67.86 111.62,67.86 111.76,67.81 111.87,67.81 112,67.86 112.23,67.86 UCPU1.H70
CFG13: length 49
  TOP w0.127: v1(72.09,65.36) 71.6,65.85 JXDP1.30 71.6,68.54 v2(71.04,69.1)
  IN4 w0.081: v2(108.48,70.49) 107.95,70.49 107.62,70.16 107.62,69.65 106.3,68.32 99.4,68.32 98.4,69.33 95.59,69.33 94.85,70.06 92.15,70.06 91.74,69.65 88.05,69.65 87.35,68.94 83.27,68.94 82.42,69.79 78.96,69.79 78.74,70.02 76.88,70.02 76.82,69.96 71.91,69.96 v2(71.04,69.1)
  BOTTOM w0.076: UCPU1.G71 111.31,68.94 109.3,68.94 108.48,69.75 v2(108.48,70.49)
CFG14: length 49.4
  TOP w0.127: v2(70.43,69.1) 70.6,68.93 70.6,67.33 JXDP1.34
  IN4 w0.081: v2(70.43,69.1) 70.43,68.69 71.68,67.45 79.75,67.45 80.94,66.26 82.87,66.26 83.41,66.8 91.94,66.8 92.39,67.24 97.54,67.24 99.31,65.46 108.99,65.46 110.31,66.79 v2(110.31,68.08)
  BOTTOM w0.076: UCPU1.H69 112.84,68.36 112.38,68.36 112.22,68.31 112.08,68.31 111.86,68.37 111.74,68.37 111.63,68.33 111.22,68.33 111.03,68.51 110.59,68.51 110.31,68.23 v2(110.31,68.08)
CFG15: length 51.4
  TOP w0.127: v2(69.82,69.1) 70.1,68.82 70.1,67.33 JXDP1.36
  IN4 w0.081: v2(69.82,69.1) 70.63,69.91 71.26,69.91 71.52,70.17 76.73,70.17 76.79,70.23 78.82,70.23 79.05,70 82.5,70 83.35,69.15 87.27,69.15 87.97,69.85 91.65,69.85 92.07,70.27 94.94,70.27 95.67,69.54 98.48,69.54 99.49,68.53 106.21,68.53 107.41,69.73 107.41,70.25 108.06,70.9 v2(108.92,70.9)
  BOTTOM w0.076: UCPU1.G70 111.99,68.76 111.85,68.9 111.84,68.9 111.84,68.91 111.43,69.1 109.37,69.1 109.07,69.4 109.07,70.75 v2(108.92,70.9)
  BOTTOM w0.127: v1(106.93,71.36) 107.39,70.9 v2(108.92,70.9)
CFG16: length 46.4
  TOP w0.127: JXDP1.6 77.6,67.33 77.6,69.07 v2(77.7,69.17) ; v2(114.91,69.25) 115.54,69.25 v1(115.6,69.3)
  IN4 w0.081: v2(114.91,69.25) 115.11,69.25 115.39,69.53 115.39,70.04 115.01,70.42 114.25,70.42 114.18,70.49 111.5,70.49 111.32,70.67 109.36,70.67 107.75,69.07 107.63,69.07 106.47,67.91 99.23,67.91 98.22,68.91 95.41,68.91 94.79,69.54 93.82,69.54 93.2,68.91 91.7,68.91 91.25,68.46 83.16,68.46 82.25,69.38 78.79,69.38 78.56,69.6 78.05,69.6 77.7,69.26 v2(77.7,69.17)
  BOTTOM w0.127: v2(114.91,69.25) 114.99,69.33 116.15,69.33 116.48,69.65 UCPU1.E63
CFG17: length 44.9
  TOP w0.127: JXDP1.4 78.1,69.01 v2(78.28,69.2)
  IN4 w0.081: v2(78.28,69.2) 78.31,69.2 78.34,69.17 82.16,69.17 83.07,68.25 91.34,68.25 91.79,68.71 93.28,68.71 93.91,69.33 94.7,69.33 95.33,68.71 98.14,68.71 99.14,67.7 106.56,67.7 107.72,68.86 107.84,68.86 109.44,70.46 111.15,70.46 112.07,69.55 112.99,69.55 113.24,69.8 113.24,69.88 113.63,70.27 114.1,70.27 114.48,69.89 114.48,69 114.84,68.64 115.98,68.64 v2(116,68.67)
  BOTTOM w0.127: v2(116,68.67) 116.15,68.67 UCPU1.F63
CFG18: length 49.6
  TOP w0.127: v2(72.7,69.48) 73.1,69.07 73.1,67.33 JXDP1.24
  IN4 w0.081: v2(72.7,69.48) 74.31,67.86 79.92,67.86 81.11,66.67 82.7,66.67 83.24,67.21 91.77,67.21 92.22,67.66 97.71,67.66 99.49,65.88 107.6,65.88 109.27,67.55 109.27,68.33 109.42,68.49 113.05,68.49 113.43,68.87 114.02,68.87 114.28,69.12 114.28,69.46 v2(113.87,69.86)
  BOTTOM w0.076: v2(113.87,69.86) 114.45,69.68 UCPU1.E66
CFG19: length 47.4
  TOP w0.127: v2(74.24,69.45) 73.6,68.81 73.6,67.33 JXDP1.22
  IN4 w0.081: v2(113.87,69.28) 113.54,69.28 112.96,68.7 109.33,68.7 109.04,68.41 109.04,67.62 107.52,66.09 99.57,66.09 97.8,67.86 92.13,67.86 91.69,67.42 82.73,67.42 81.81,68.33 79.01,68.33 78.8,68.12 74.51,68.12 73.89,68.74 73.89,69.1 v2(74.24,69.45)
  BOTTOM w0.127: UCPU1.F66 114.15,69 v2(113.87,69.28)
CFG_RCOMP: length 2.3
  TOP w0.127: v1(119.1,70.42) 118.55,70.42 v2(118.24,70.11)
  TOP w0.254: RC114.1 117.9,69.77 v2(118.24,70.11)
  BOTTOM w0.254: UCPU1.E60 118.24,69.72 v2(118.24,70.11)
CHAGER_SRC:
  vias: v3(49.35,35.42) v4(49.12,34.5) v4(49.76,34.5) v4(50.27,36.28) v4(50.27,35.65) v4(50.27,33.99) v4(50.27,33.36)
CHARGER_SMBCLK: length 199.7
  TOP w0.127: v3(36.67,31.85) 37.11,31.4 v2(38.46,31.4) ; UE5.B50 179.22,59.77 179.61,60.17 v2(179.61,60.25)
  IN1 w0.081: v2(38.46,31.4) 37.79,30.74 37.79,29.27 37.8,29.26 37.8,25.91 41.32,22.39 41.74,22.39 42.27,21.87 42.27,20.81 43.3,19.78 49.16,19.78 49.38,20 50.64,20 51.71,21.06 54.2,21.06 54.72,21.58 62.7,21.58 63.45,20.82 67.1,20.82 68.17,21.89 71.72,21.89 76.7,26.87 82.69,26.87 83.33,26.23 91.13,26.23 91.77,25.59 92.23,25.59 93.01,24.81 93.01,23.49 93.66,22.85 94.47,22.85 96.75,20.57 102.52,20.57 102.9,20.19 109.26,20.19 110.11,19.34 117.34,19.34 118.8,17.87 125.65,17.87 126.86,19.07 157.79,19.07 158.4,19.69 161.1,19.69 164.11,22.69 164.11,24.95 166.75,27.59 166.75,32.15 166.66,32.24 166.66,33.32 168.14,34.79 168.14,37.21 170.19,39.26 170.19,42.55 171.47,43.84 171.47,45.49 173,47.02 173,51.9 174.74,53.64 176.04,53.64 177.34,54.94 177.34,56.01 176.34,57.01 176.34,57.79 175.75,58.37 175.75,58.71 176.14,59.09 176.73,59.09 177.63,59.99 179.35,59.99 v2(179.61,60.25)
  BOTTOM w0.127: PR311.1 38.15,31.71 v2(38.46,31.4) ; RE56.1 178,59.55 178.47,60.02 179.46,60.02 179.61,60.17 v2(179.61,60.25)
CHARGER_SMBDAT: length 191.1
  TOP w0.127: RE55.1 174.37,58.99 175.43,58.99 v2(175.55,59.1) 176.03,59.1 176.95,60.02 UE5.A47
  IN1 w0.081: v2(38.25,30.46) 38,30.21 38,29.32 38.01,29.31 38.01,26 41.41,22.6 41.83,22.6 42.47,21.95 42.47,20.9 43.39,19.99 49.07,19.99 49.29,20.21 50.56,20.21 51.62,21.27 54.11,21.27 54.64,21.79 62.78,21.79 63.54,21.03 67.01,21.03 68.08,22.1 71.62,22.1 76.6,27.08 82.79,27.08 83.43,26.44 91.22,26.44 91.85,25.8 92.31,25.8 93.23,24.89 93.23,23.57 93.74,23.05 94.56,23.05 96.84,20.77 102.61,20.77 102.98,20.41 109.35,20.41 110.19,19.56 111.55,19.56 111.55,19.55 117.42,19.55 118.88,18.1 125.58,18.1 126.76,19.28 157.7,19.28 158.31,19.9 160.98,19.9 163.89,22.81 163.89,25.04 166.52,27.67 166.52,32.07 166.43,32.16 166.43,33.39 167.93,34.88 167.93,37.3 169.98,39.35 169.98,42.65 171.25,43.93 171.25,45.58 172.78,47.11 172.78,51.98 174.65,53.85 175.95,53.85 177.13,55.03 177.13,55.92 176.13,56.92 176.13,57.7 175.55,58.28 v2(175.55,59.1)
  BOTTOM w0.127: PR309.1 38.1,30.31 v2(38.25,30.46)
CHG_ACDET: length 11.5
  TOP w0.127: PQ302.1 39.05,22.61 39.52,22.61 v3(40,23.09)
  TOP w0.254: v2(37.95,22.64) 38.02,22.56 39.01,22.56 PQ302.1
  IN2 w0.254: v2(37.95,22.64) 38.53,23.22 38.53,24.06 v2(40.44,25.97)
  BOTTOM w0.203: PC318.2 40.39,25.18 40.9,25.7 40.9,27.26 PU300.6
  BOTTOM w0.254: v2(40.44,25.97) 40.36,25.89 PC318.2 ; v2(37.95,22.64) 38.33,23.02 PR310.2 PR307.2
CHG_ACN: length 3.9
  BOTTOM w0.203: PR304.2 44.37,24.75 PC310.2 43.54,25.56 PC311.1 43.71,25.94 42.9,26.76 PU300.1
CHG_ACOK: length 5.7
  BOTTOM w0.203: PU300.5 41.3,27.26 41.3,26.32 v1(41.49,26.12) 41.49,25.42 PR312.2 41.78,24.65 41.78,23.96 42.14,23.61 PR314.2 PR317.1
CHG_ACP: length 6
  BOTTOM w0.203: PC309.2 43.54,22.75 PC310.1 ; PC310.1 44.35,23.83 PR303.2 ; PC310.1 43.03,24.34 43.03,25.94 v1(42.82,26.14) 42.5,26.47 PU300.2
CHG_BAT: length 4.6
  BOTTOM w0.127: PR324.1 v1(37.93,33.11)
  BOTTOM w0.203: PU300.17 41.3,31.36 41.3,32.29 PC337.1 PR324.1
CHG_BATDRV: length 2.3
  BOTTOM w0.203: PR323.1 41.7,33.54 v1(41.7,32.57) PU300.18
CHG_BATPRES: length 3.3
  TOP w0.127: v2(39.85,32.22) 39.85,31.71 v3(39.7,31.55)
  TOP w0.203: PR326.2 38.74,32.22 v2(39.85,32.22)
  BOTTOM w0.203: v2(39.85,32.22) 39.85,32.04 40.13,31.76 40.42,31.76 40.5,31.68 PU300.15
CHG_BTS:
  vias: v1(44.85,29.43)
CHG_BTS_C: length 9.3
  BOTTOM w0.127: PR308.2 47.35,30 48.02,30.67 48.02,32.53 46.97,33.58 46.97,34.12 47.86,35.02 v3(47.86,36.79)
  BOTTOM w0.254: PC322.1 PR308.2
CHG_CELL: length 4.8
  TOP w0.203: v2(40.44,32.22) 40.44,32.77 v3(40.02,33.2) 39.85,33.36 39.47,33.36 39.09,32.98 PR325.2 38.58,33 PR327.1
  BOTTOM w0.203: PU300.16 40.9,31.83 40.51,32.22 v2(40.44,32.22)
CHG_CMSRC: length 2.4
  BOTTOM w0.203: PU300.3 42.1,26.33 42.57,25.86 42.57,25.46 PR305.2
CHG_IADP: length 3.6
  BOTTOM w0.203: PU300.7 40.5,26.84 39.88,26.22 v1(39.88,26.2) 39.88,25.55 39.69,25.36 39.66,25.36 PC330.1 39.4,25.1 38.53,25.1 PR315.2
CHG_IBAT: length 5.4
  TOP w0.127: v3(41.38,25.18) PR318.2 PC331.1 39.47,25.74 39.44,25.77 39.44,25.79 v2(39.42,25.79)
  BOTTOM w0.127: PU300.8 39.31,28.11 39.21,28.01 39.21,27.35 39.42,27.14 39.42,25.82 39.44,25.8 39.44,25.79 v2(39.42,25.79)
CHG_ILIM: length 4
  BOTTOM w0.127: v3(45.77,33.41) 45.24,32.88 PR320.1
  BOTTOM w0.203: PU300.21 43.29,31.36 44.27,32.34 PR320.1
CHG_LGATE: length 10.3
  IN1 w1.016: 45.44,31.07 45.66,31.29 53.5,31.29 54.29,32.08 54.29,33.15
  vias: v2(44.54,30.79) v2(44.55,30.18) v2(54,34.17) v2(54.59,34.16)
CHG_PMON: length 5.6
  TOP w0.127: v2(38.52,28.19) 39,27.71 PR322.1 ; PR322.1 39.56,27.4 PR319.2 ; PR322.1 39.27,27.73 PC332.1 39.27,29.6 v3(39.63,29.97)
  BOTTOM w0.127: PU300.9 39.47,28.51 39.22,28.51 38.9,28.19 v2(38.52,28.19)
CHG_PROCHOT: length 3.5
  BOTTOM w0.127: v3(37.67,27.82) 37.64,27.85 PR316.2 37.67,29.2 38.91,29.2 39.19,28.91 39.65,28.91 PU300.10
CHG_SCL: length 5.6
  BOTTOM w0.127: v3(35.35,31.32) 36.34,31.32 PR311.2 36.93,31.5 36.93,31.38 37.33,30.98 38.34,30.98 38.84,30.48 38.84,30.15 39.27,29.71 PU300.12
CHG_SDA: length 5.1
  BOTTOM w0.127: v3(35.56,29.46) 35.88,29.46 PR309.2 36.92,30.12 36.92,30.02 37.13,29.81 37.96,29.81 38.19,30.04 38.59,30.04 39.01,29.61 39.01,29.55 39.25,29.31 39.65,29.31 PU300.11
CHG_SNUB: length 3.8
  BOTTOM w0.127: PR321.2 55.42,36.71 v1(55.42,37.02)
  BOTTOM w0.508: PR321.2 54.15,35.52 53.26,36.41 PC333.1
CHG_SRN: length 43
  TOP w0.127: v3(42.14,33.61) 42.14,32.83 v2(42.25,32.72)
  IN2 w0.203: v2(70.59,32.85) 70.59,32.93 71.63,33.98 71.63,34.94 69.66,36.92 58.69,36.92 56.73,38.87 50.57,38.87 48.04,36.34 48.04,34.98 46.19,33.13 43.2,33.13 42.79,32.72 v2(42.25,32.72)
  BOTTOM w0.203: PU300.19 42.1,31.97 42.77,32.64 42.77,33.22 PC335.2 42.25,33.23 42.25,32.73 v2(42.25,32.72)
  BOTTOM w0.254: PC335.2 PC336.1 ; v2(70.59,32.85) 70.97,33.23 PR313.2
CHG_SRP: length 39.4
  IN2 w0.203: v2(43.71,32.67) 46.2,32.67 48.37,34.84 48.37,36.17 50.75,38.54 56.6,38.54 58.55,36.58 69.52,36.58 71.3,34.81 71.3,34.11 70.73,33.55 70.65,33.55 70.59,33.49 v2(70.46,33.49)
  BOTTOM w0.203: PU300.20 42.5,31.9 43.1,32.5 43.1,33.19 43.4,33.49 PC335.1
  BOTTOM w0.254: v2(43.71,32.67) 43.75,32.67 PC334.2 44.03,33.49 PC335.1 ; v2(70.46,33.49) 70.21,33.23 PR313.3
CHG_SW: length 14.8
  IN1 w1.016: 58.14,34.76 58.14,32.2 54.65,28.71 47.78,28.71 47.47,28.41
  vias: v2(46.6,28.84) v2(46.62,28.25) v2(58.13,36.22) v2(58.13,35.64)
CHG_UGATE: length 11
  IN4 w1.016: 55.44,25.39 50.9,29.93 46.46,29.93
  BOTTOM w0.127: v2(57,24.98) 56.87,25.1
  vias: v2(44.55,28.91) v2(45.14,28.92) v2(56.36,24.98)
CHG_VCC:
  vias: v2(45,27.55) v2(44.98,26.95) v3(43.54,27.01)
CL_CK: length 162.5
  TOP w0.127: v2(43.14,49.42) 42.48,49.42 41.12,48.07 41.12,47.34 41.62,46.85 R1212.2
  IN3 w0.089: v2(153.85,77.21) 153.85,77.2 153.54,76.89 151.86,76.89 151.75,77 145.99,77 145.53,77.46 138.02,77.46 137.22,78.26 130.28,78.26 130.01,77.99 121.44,77.99 120.45,77 115.8,77 113.85,75.05 109.19,75.05 106.33,77.91 101.17,77.91 100.91,77.66 92.21,77.66 89.41,74.86 89.41,74.82 88.75,74.17 80.58,74.17 78.88,75.86 71.73,75.86 71.08,76.52 66.88,76.52 66.19,77.2 66.19,77.5 65.96,77.73 65.58,77.73 65.25,77.4 65.25,77.1 64.29,76.13 61.15,76.13 60.62,75.61 60.04,75.61 58.95,74.52 58.95,73.4 58.84,73.3 58.7,73.3 58.59,73.4 58.59,74.08 58.5,74.17 58.21,74.17 58.12,74.08 58.12,73.4 58.01,73.3 57.87,73.3 57.76,73.4 57.76,74.08 57.67,74.17 57.18,74.17 56.44,74.91 55.09,74.91 54.39,74.21 54.39,69.22 55.7,67.9 56.31,67.9 57.36,66.85 57.36,66.16 56.48,65.29 55.48,65.29 54.64,64.45 54.64,55.25 53.59,54.19 51.47,54.19 48.21,50.94 46.55,50.94 44.58,48.97 43.58,48.97 v2(43.14,49.42)
  BOTTOM w0.127: v2(153.85,77.21) 153.85,77 v1(153.58,76.73) 153.5,76.64 153.5,72.71 152.82,72.03 152.82,70.91 152.27,70.37 151.97,70.37 151.79,70.19 151.79,69.92 151.46,69.59 151.46,69.27 150.99,68.8 UCPU1.G3
CL_CK_R: length 2.7
  TOP w0.127: R1212.1 42.14,44.99 v2(42.11,44.96)
  BOTTOM w0.127: JNGFF1.34 41.5,46.32 41.5,45.37 41.91,44.96 v2(42.11,44.96)
CL_DAT: length 160.2
  TOP w0.127: R1210.2 44.27,48.12 44.02,48.37 44.02,49.08 43.61,49.49 43.61,49.89 44.04,50.33 v2(44.21,50.33)
  IN3 w0.089: v2(44.21,50.33) 44.21,50.71 44.65,51.15 48.06,51.15 51.31,54.41 53.5,54.41 54.43,55.34 54.43,64.54 55.39,65.5 56.4,65.5 57.14,66.25 57.14,66.76 56.22,67.69 55.61,67.69 54.18,69.13 54.18,74.58 54.74,75.14 56.64,75.14 57.32,75.82 60.53,75.82 61.06,76.35 64.2,76.35 65.04,77.19 65.04,77.49 65.49,77.95 66.05,77.95 66.41,77.59 66.41,77.29 66.97,76.73 71.17,76.73 71.82,76.08 79.04,76.08 80.73,74.39 88.63,74.39 92.19,77.95 94.53,77.95 94.7,78.13 106.42,78.13 107.73,76.82 115.32,76.82 115.71,77.21 120.36,77.21 121.35,78.21 129.88,78.21 130.12,78.45 144.81,78.45 149.22,78.45 149.31,78.36 149.31,77.36 149.4,77.27 149.58,77.27 149.67,77.36 149.67,78.36 149.76,78.44 150.67,78.44 150.75,78.37 150.75,77.3 150.83,77.22 151.06,77.22 151.14,77.3 151.14,77.63 151.21,77.71 151.43,77.71 151.52,77.62 151.52,77.31 151.61,77.22 151.78,77.22 151.87,77.31 151.87,77.62 151.96,77.71 154.08,77.71 154.45,77.33 v2(154.45,77.25)
  BOTTOM w0.127: UCPU1.G2 151.79,69.13 152.6,69.13 153.29,69.82 153.29,71.84 155.6,74.15 v1(155.6,75.24) 155.6,75.62 154.45,76.77 v2(154.45,77.25)
CL_DAT_R: length 5
  TOP w0.127: v1(42.9,48.95) 42.8,48.85 v2(42.8,48.43) 42.8,48.37 R1210.1
  BOTTOM w0.127: JNGFF1.32 41,47.03 41.15,47.18 41.15,47.19 41.44,47.48 42.67,47.48 42.8,47.61 v2(42.8,48.43)
CL_RST#: length 158.1
  TOP w0.127: R1200.2 44.73,47.3 44.73,48.19 44.43,48.5 44.43,49.34 v2(44.04,49.72)
  IN3 w0.089: v2(154.9,76.87) 154.99,76.96 154.99,77.69 154.8,77.89 151.66,77.89 150.92,78.63 129.93,78.63 129.73,78.42 120.01,78.42 119.02,77.44 108.88,77.44 107.72,78.6 92.54,78.6 88.62,74.68 84.21,74.68 83.57,75.32 80.1,75.32 79.13,76.29 71.91,76.29 71.26,76.95 67.06,76.95 66.62,77.38 66.62,77.68 66.14,78.16 64.57,78.16 62.97,76.56 61.61,76.56 61.24,76.93 60.07,76.93 59.2,76.06 57.19,76.06 56.58,75.45 54.74,75.45 53.96,74.67 53.96,69.01 55.5,67.47 56.13,67.47 56.93,66.67 56.93,66.34 56.31,65.72 55.3,65.72 54.21,64.63 54.21,55.43 53.41,54.62 51.07,54.62 47.82,51.37 44.56,51.37 43.79,50.59 43.79,49.97 v2(44.04,49.72)
  BOTTOM w0.127: UCPU1.G1 152.67,68.8 153.61,69.75 153.61,71.69 155.93,74.01 155.93,76.25 v1(155.58,76.61) 155.32,76.87 v2(154.9,76.87)
CL_RST#_R: length 5.6
  TOP w0.127: v1(43.51,45.96) 43.51,46.9 R1200.1 43.23,46.95 42.21,47.97 v2(42.16,47.97)
  BOTTOM w0.127: v2(42.16,47.97) 41.99,47.97 41.9,47.88 41.25,47.88 40.81,47.43 40.79,47.43 40.5,47.14 JNGFF1.30
CLK0_PCIE_TBT: length 116.5
  TOP w0.127: UT1.V19 v2(45.08,63.67)
  IN4 w0.091: v2(45.08,63.67) 45,63.67 44.69,63.98 44.69,64.96 44.3,65.34 44.3,67.2 43.13,68.36 43.13,69.72 43.66,70.25 43.66,73.87 42.63,74.9 42.63,76.35 42.71,76.43 46.57,76.43 47.17,77.03 47.17,78.24 48.69,79.76 53.61,79.76 54.33,80.49 77.72,80.49 80.93,77.28 83.24,77.28 85.92,79.96 86.37,79.96 86.44,79.88 90.93,79.88 91.52,80.48 126.32,80.48 128.99,77.81 128.99,75.86 128.64,75.5 128.64,74.66 128.07,74.09 127.51,74.09 127.43,74.17 127.43,74.41 127.36,74.48 127.13,74.48 v2(127.02,74.37)
  BOTTOM w0.076: UCPU1.C42 127.53,71.13 127.53,71.19 127.47,71.28 127.38,71.57 127.38,71.75 127.43,71.94 127.43,72.09 127.38,72.21 127.38,72.49 127.53,72.65 127.53,73.54 127.36,73.71 127.36,74.03 v2(127.02,74.37)
CLK0_PCIE_TBT#: length 117
  TOP w0.127: UT1.T19 v2(44.43,63.67)
  IN4 w0.091: v2(126.99,73.79) 127.11,73.9 128.15,73.9 128.83,74.58 128.83,75.42 129.18,75.78 129.18,77.89 126.4,80.67 91.44,80.67 90.85,80.07 86.52,80.07 86.45,80.15 85.84,80.15 83.16,77.47 81.01,77.47 77.8,80.68 54.25,80.68 53.53,79.96 48.61,79.96 46.98,78.32 46.98,77.11 46.49,76.62 42.63,76.62 42.44,76.43 42.44,74.82 43.47,73.79 43.47,70.33 42.94,69.8 42.94,68.28 44.11,67.12 44.11,65.26 44.49,64.88 44.49,63.73 v2(44.43,63.67)
  BOTTOM w0.076: UCPU1.D42 127.43,70.58 127.43,70.69 127.35,70.96 127.35,71.07 127.32,71.18 127.22,71.5 127.21,71.55 127.21,71.8 127.25,71.89 127.25,72.08 127.21,72.18 127.21,72.56 127.37,72.72 127.37,73.41 v2(126.99,73.79)
CLK1_PCIE_WLAN: length 130.3
  IN4 w0.091: v2(127.56,74.93) 127.77,75.14 127.77,75.24 127.3,75.71 125.83,75.71 124.93,76.61 124.93,77.42 122.48,79.88 93.23,79.88 90.78,77.43 88.08,77.43 87.32,76.66 80.71,76.66 78.22,79.15 72.83,79.15 70.38,76.69 66.82,76.69 65.1,74.97 65.1,72.88 63.32,71.1 63.32,70.69 64.09,69.92 64.09,66.46 63.13,65.5 63.13,63.85 62.27,62.99 62.27,62.2 60.95,60.88 60.95,56.69 60.11,55.85 60.11,55.11 59.13,54.12 59.13,52.95 58.79,52.62 58.79,52.04 56.68,49.93 55.14,49.93 50.52,45.31 50.14,45.31 49.09,44.25 49.09,43.29 45.49,39.7 45.49,35.36 44.48,34.35 43.26,34.35 42.99,34.62 42.99,34.87 v2(42.75,35.11)
  BOTTOM w0.076: UCPU1.A42 127.64,72.09 127.69,72.04 127.82,72.04 127.95,72.18 127.95,72.51 127.76,72.7 127.76,74.73 v2(127.56,74.93)
  BOTTOM w0.127: v2(42.75,35.11) 42.85,35.21 42.85,36.41 C1302.1 42.87,37.34 42.87,37.94 42.75,38.06 JNGFF1.39
CLK1_PCIE_WLAN#: length 130.5
  IN4 w0.091: v2(43.41,35.09) 43.18,34.86 43.18,34.7 43.34,34.54 44.4,34.54 45.3,35.44 45.3,39.78 48.9,43.37 48.9,44.33 50.06,45.5 50.44,45.5 55.06,50.13 56.6,50.13 58.6,52.12 58.6,52.7 58.93,53.03 58.93,54.2 59.92,55.19 59.92,55.93 60.75,56.77 60.75,60.96 62.08,62.28 62.08,63.07 62.94,63.93 62.94,65.58 63.9,66.54 63.9,69.84 63.13,70.61 63.13,71.18 64.91,72.96 64.91,75.05 66.74,76.88 70.3,76.88 72.75,79.34 78.3,79.34 80.79,76.85 87.24,76.85 88,77.62 90.7,77.62 93.15,80.07 122.56,80.07 125.13,77.5 125.13,76.69 125.91,75.9 127.38,75.9 127.96,75.32 127.96,75.12 v2(128.14,74.93)
  BOTTOM w0.076: UCPU1.B42 127.67,71.66 128.12,72.11 128.12,72.58 127.93,72.77 127.93,74.72 v2(128.14,74.93)
  BOTTOM w0.127: v2(43.41,35.09) 43.1,35.4 43.1,36.43 C1301.1 43.12,37.28 43.12,37.9 43.25,38.03 JNGFF1.41
CLK_ITPXDP_N: length 28.6
  TOP w0.127: RC297.2 89.44,79.92 87.94,79.92 83.7,75.69 v4(82.84,75.69) 81.05,75.69 79.11,73.74 79.11,71.87 77.54,70.31 72.14,70.31 71.7,69.87 69.33,69.87 68.8,69.34 68.8,68.61 68.6,68.41 JXDP1.42
CLK_ITPXDP_N_R: length 55.3
  TOP w0.127: RC297.1 90.97,79.9 91.9,79.9 92.86,80.87 v4(125.15,80.87) 128.03,80.87 130.48,78.41 130.48,76.55 129.93,76 129.45,76 128.83,75.38 128.83,74.49 128.31,73.98 127.98,73.98 127.82,73.82 127.82,73.53 127.96,73.39 128.17,73.39 v2(128.32,73.54)
  IN4 w0.091: v2(128.32,73.54) 128.5,73.36 129.06,73.36 129.26,73.16 129.26,72.45 129.17,72.36 129.17,70.74 127.74,69.31 127.16,69.31 v2(127.08,69.23)
  BOTTOM w0.127: v2(127.08,69.23) 127.38,68.94 UCPU1.F43
CLK_ITPXDP_P: length 28.2
  TOP w0.127: JXDP1.40 69.1,68.53 69.05,68.58 69.05,69.23 69.44,69.62 71.81,69.62 72.24,70.05 77.65,70.05 79.36,71.77 79.36,73.64 81.16,75.44 83.81,75.44 v4(85.86,77.49) 88.04,79.67 89.4,79.67 RC298.2
CLK_ITPXDP_P_R: length 55.7
  TOP w0.127: v2(128.32,72.93) 128.07,72.68 127.91,72.68 127.81,72.79 127.81,73.19 127.57,73.42 127.57,73.92 127.88,74.23 128.21,74.23 128.58,74.6 128.58,75.49 129.34,76.25 129.83,76.25 130.23,76.65 130.23,78.31 127.92,80.61 v4(122.7,80.61) 92.97,80.61 92,79.65 90.97,79.65 RC298.1
  IN4 w0.091: v2(128.32,72.93) 128.47,72.78 128.65,72.78 128.73,72.86 128.73,73.09 128.8,73.17 128.98,73.17 129.07,73.08 129.07,72.53 128.98,72.44 128.98,70.82 127.66,69.5 127.46,69.5 127.38,69.58 127.38,69.76 127.31,69.83 v2(127.08,69.83)
  BOTTOM w0.127: v2(127.08,69.83) 127.41,69.83 127.51,69.73 UCPU1.E43
CLK_LPC_DEBUG: length 46
  IN1 w0.081: v2(158.04,47.25) 158.38,47.25 159.17,48.04 162.75,48.04 166.48,51.76 166.48,56.61 167.19,57.32 167.19,59.23 169.88,61.92 169.88,64.25 171.21,65.58 171.21,67.37 172.22,68.38 172.94,68.38 174.16,69.6 176.35,69.6 176.85,70.11 177.58,70.11 178.06,70.59 178.45,70.59 179.19,71.34 182.25,71.34 v2(183.44,72.53)
  BOTTOM w0.127: RC22.2 157.43,46.19 CC5.2 158.04,46.8 v2(158.04,47.25) ; v2(183.44,72.53) 184.15,71.81 JLPDE1.10
CLK_PCI_MEC: length 45.8
  TOP w0.127: UE5.A29 180.36,68.72 180.36,69.18 180.3,69.24 180.3,69.69 v2(180.62,70.01) 180.49,70.14 180.49,70.65 RE80.1
  IN1 w0.081: v2(159.53,44.26) 159.77,44.5 164.48,44.5 166.43,46.46 166.43,47.37 167.78,48.71 167.78,50.16 170.98,53.36 170.98,56.33 170.01,57.3 170.01,58.96 172.89,61.84 172.89,63.59 174.25,64.95 174.25,65.77 175.9,67.42 177.37,67.42 178.68,68.72 179.92,68.72 180.32,69.12 180.32,69.71 v2(180.62,70.01)
  BOTTOM w0.127: RC18.2 156.85,45.55 CC4.2 158.98,44.26 v2(159.53,44.26)
CLK_PCIE_MMI: length 130.4
  IN4 w0.091: v2(129.8,69.79) 129.96,69.62 130.13,69.62 130.29,69.77 130.29,72.16 130.74,72.61 130.74,73.42 131.21,73.89 134.46,73.89 134.81,74.23 134.81,77.56 137.24,79.98 152.59,79.98 153.2,79.37 155.46,79.37 156.14,80.05 168.01,80.05 168.62,79.43 169.19,79.43 172.22,76.41 172.22,74.25 175.35,71.12 175.35,68.55 174.69,67.89 174.69,66.29 174.24,65.84 174.24,64.88 174.31,64.81 174.31,63.11 175.19,62.24 176.3,62.24 176.85,61.69 176.85,59.86 178.66,58.05 178.66,57.5 178.45,57.28 178.45,56.03 179.43,55.05 179.43,53.23 179.93,52.72 180.97,52.72 186.61,47.08 186.61,38.99 190.47,35.14 190.6,35.14 193.84,31.9 193.84,28.79 194.79,27.84 194.79,24.47 196.53,22.73 200.09,22.73 202.04,20.78 203.71,20.78 204.43,20.05 204.43,19.83 v2(204.62,19.64)
  BOTTOM w0.127: JIO1.20 204.51,18.72 204.34,18.89 204.34,19.49 204.5,19.64 v2(204.62,19.64) ; UCPU1.E38 129.99,69.59 v2(129.8,69.79)
CLK_PCIE_MMI#: length 130.3
  IN4 w0.091: v2(129.8,69.18) 130.04,69.43 130.21,69.43 130.48,69.69 130.48,72.08 130.94,72.53 130.94,73.34 131.29,73.69 134.54,73.69 135,74.15 135,77.48 137.32,79.79 152.51,79.79 153.12,79.18 155.54,79.18 156.22,79.86 167.93,79.86 168.54,79.24 169.11,79.24 172.02,76.33 172.02,74.17 175.16,71.04 175.16,68.63 174.5,67.97 174.5,66.37 174.05,65.92 174.05,64.8 174.12,64.73 174.12,63.03 175.11,62.04 176.22,62.04 176.66,61.61 176.66,59.78 178.47,57.97 178.47,57.58 178.26,57.36 178.26,55.95 179.23,54.97 179.23,53.15 179.85,52.53 180.89,52.53 186.42,47 186.42,38.91 190.39,34.94 190.52,34.94 193.65,31.82 193.65,28.71 194.6,27.76 194.6,24.39 196.45,22.54 200.01,22.54 201.96,20.58 203.63,20.58 204.24,19.97 204.24,19.8 204.09,19.64 v2(203.91,19.64)
  BOTTOM w0.127: v2(203.91,19.64) 203.99,19.64 204.09,19.54 204.09,18.88 203.91,18.7 JIO1.22 ; UCPU1.E40 129.39,69.59 v2(129.8,69.18)
CLK_PCIE_SSD: length 112.1
  IN4 w0.091: v2(128.88,73.95) 129.08,74.15 129.08,74.27 129.36,74.55 129.87,74.55 130.23,74.91 130.23,79.14 131.7,80.62 152.83,80.62 153.43,80.02 155.02,80.02 155.65,80.64 170.09,80.64 171.86,78.87 173.36,78.87 175.48,76.75 175.48,73.21 175.2,72.93 175.2,72.54 175.94,71.8 175.94,67.14 175.39,66.59 175.39,65 175.71,64.68 175.71,63.49 176.37,62.83 176.55,62.83 177.49,61.89 177.49,60.08 179.26,58.31 179.26,57.13 179.14,57.01 179.14,56.18 180.01,55.3 180.01,54.11 180.29,53.84 180.68,53.84 186.74,47.79 187.29,47.79 188.52,46.56 188.52,37.93 189.33,37.12 189.79,37.12 v2(189.87,37.19)
  BOTTOM w0.076: v2(128.88,73.95) 129.11,73.72 129.11,72.96 129.04,72.89 129.04,72.19 128.99,72.05 128.99,71.94 129,71.9 129,71.85 129.02,71.82 129.04,71.77 129.04,71.57 128.98,71.41 128.83,71.32 128.59,71.32 128.52,71.26 128.52,71.08 128.59,71.01 UCPU1.C40
  BOTTOM w0.127: JNGFF2.55 183.81,36.79 183.95,36.66 188.79,36.66 189.16,37.02 189.69,37.02 v2(189.87,37.19)
CLK_PCIE_SSD#: length 112.1
  IN4 w0.091: v2(189.87,36.61) 189.55,36.93 189.25,36.93 188.33,37.85 188.33,46.48 187.21,47.59 186.66,47.59 180.6,53.65 180.21,53.65 179.82,54.03 179.82,55.22 178.94,56.1 178.94,57.09 179.07,57.21 179.07,58.23 177.29,60 177.29,61.81 176.47,62.63 176.29,62.63 175.51,63.41 175.51,64.6 175.19,64.92 175.19,66.67 175.75,67.22 175.75,71.72 175.01,72.46 175.01,73.01 175.29,73.29 175.29,76.67 173.28,78.67 171.78,78.67 170.01,80.45 155.73,80.45 155.1,79.83 153.35,79.83 152.75,80.43 131.78,80.43 130.42,79.06 130.42,74.83 129.95,74.35 129.44,74.35 129.28,74.19 129.28,74.1 129.43,73.95 v2(129.52,73.95)
  BOTTOM w0.076: UCPU1.D40 129.06,70.65 129.06,71.07 129.12,71.27 129.14,71.35 129.19,71.5 129.19,71.52 129.2,71.55 129.2,71.8 129.17,71.89 129.17,71.89 129.17,71.92 129.15,71.97 129.15,72.02 129.2,72.16 129.2,72.82 129.27,72.89 129.27,73.71 v2(129.52,73.95)
  BOTTOM w0.127: JNGFF2.53 183.86,36.29 183.97,36.4 188.9,36.4 189.26,36.77 189.71,36.77 v2(189.87,36.61)
CLK_SMB: length 8.5
  TOP w0.127: v2(69.11,21.22) 68.92,21.02 68.92,20.77 68.05,19.91 68.05,19.44 68.16,19.33 PRP100.6
  BOTTOM w0.127: v2(69.11,21.22) 68.96,21.37 68.96,21.72 67.54,23.14 67.54,23.33 68.1,23.89 JBATT1.3
CLK_TP_SIO: length 70
  TOP w0.127: v2(181.41,20.91) 181.2,20.71 181.2,19.52 C1229.1 180.7,18.87 181.59,17.98 181.59,17.23 MD9.3 180.11,16.65 v1(178.13,18.63) v2(174.47,22.28) ; UE5.A37 177.16,65.02 176.78,65.02 176.62,64.86 176.28,64.86 176.24,64.82 175.5,64.82 175.07,65.24 175.07,65.91 174.92,66.05 174.48,66.05 RE6.2 173.61,66.05 171.81,66.05 170.96,65.2 170.96,60.91 171.2,60.66 171.2,60.03 171.12,59.96 171.12,57.49 v2(171.2,57.41)
  IN2 w0.089: v2(174.47,22.28) 174.47,26.34 173.48,27.34 173.48,32.83 170.84,35.47 170.84,36.43 171.13,36.72 171.13,38.38 171.74,38.99 171.74,56.87 v2(171.2,57.41)
  BOTTOM w0.127: v2(181.41,20.91) 181.41,20.46 181.67,20.2 182.75,20.2 183.16,19.79 JTP1.8
CLKREQ_PCIE#0: length 260.4
  TOP w0.127: 49.02,57.81 49.13,57.81 49.48,57.46 RT21.2 ; 49.02,57.81 48.69,57.48 48.3,57.48 48.25,57.52 47.87,57.52 UT1.AC5 ; 49.02,57.81 v2(49.02,57.82)
  IN1 w0.081: v2(63.35,18.5) 62.28,18.5 61.72,19.06 54.99,19.06 54.58,18.66 54.58,18.05 54.06,17.53 46.85,17.53 45.82,16.5 45.32,16.5 45.06,16.75 43.19,16.75 41.37,18.57 39.76,18.57 37.08,21.24 37.08,23.85 36.06,24.87 36.06,31.07 37.52,32.53 37.52,35.3 37.06,35.76 37.06,36.99 38.3,38.24 40.12,38.24 41.39,39.51 41.95,39.51 43.49,41.04 43.49,41.53 45.31,43.35 45.31,44.22 44.62,44.92 44.62,48.2 45.36,48.94 45.64,48.94 48.7,52 49.75,52 v2(50.17,51.58)
  IN4 w0.081: v2(146.26,53.74) 146.44,53.74 146.77,54.07 146.77,55.94 147.03,56.19 148.7,56.19 149.64,55.25 149.64,54.01 151.22,52.43 151.22,50.55 152.5,49.27 154.24,49.27 154.56,49.59 154.91,49.59 156.07,48.43 156.07,46.83 156.98,45.92 156.98,45.1 157.96,44.13 157.96,42.67 159.04,41.58 159.04,40.49 161.24,38.29 163.42,38.29 164.29,37.42 164.29,35.3 165.31,34.28 165.31,23.35 161.03,19.07 147.54,19.07 147.14,19.47 145.5,19.47 145,18.97 123.53,18.97 123.12,19.37 106.77,19.37 106.26,19.88 101.27,19.88 99.24,21.9 97.41,21.9 96.48,22.83 96.48,25.02 96.38,25.11 96.38,28.84 95.54,29.68 94.22,29.68 92.78,31.12 92.78,31.73 91.93,32.58 88.2,32.58 87.39,31.76 85.6,31.76 84.32,30.48 79.47,30.48 75.52,26.53 72.96,26.53 67.65,21.22 67.65,19.63 67.11,19.09 66.46,19.09 65.87,18.5 v2(63.35,18.5)
  BOTTOM w0.076: UCPU1.AR10 146.35,53.74 v2(146.26,53.74)
  BOTTOM w0.127: RC63.2 61.62,50.19 51.97,50.19 50.58,51.58 v2(50.17,51.58) 49.31,52.43 v1(49.31,53.09) 49.31,56.31 49.35,56.35 49.35,57.49 v2(49.02,57.82)
CLKREQ_PCIE#1: length 195.1
  IN2 w0.089: v2(44.35,36.84) 44.58,36.84 45.49,35.92 45.49,34.96 44.12,33.59 42.48,33.59 41.74,32.85 41.74,32.34 42.39,31.68 43.66,31.68 44.35,32.37 46.23,32.37 53.54,25.05 55.68,25.05 56.21,24.52 58.01,24.52 60.02,26.53 63.07,26.53 64.43,27.89 75.73,27.89 v2(77.24,29.4)
  IN4 w0.081: v2(148.08,53.74) 148.72,53.1 149.81,53.1 150.8,52.11 150.8,50.38 152.56,48.62 154.43,48.62 154.56,48.49 155.16,48.49 155.65,48 155.65,47.65 155.65,46.66 156.57,45.74 156.57,44.93 157.54,43.96 157.54,41.4 161.07,37.87 163.25,37.87 163.87,37.25 163.87,35.12 164.89,34.1 164.89,23.52 160.86,19.49 147.72,19.49 147.32,19.89 145.33,19.89 144.83,19.38 123.7,19.38 123.3,19.79 106.94,19.79 106.44,20.29 101.44,20.29 99.42,22.32 97.59,22.32 96.9,23 96.9,25.19 96.8,25.29 96.8,29.01 95.71,30.1 94.4,30.1 93.2,31.3 93.2,31.9 91.9,33.19 88.99,33.19 88.58,33.61 88.16,33.61 87.35,32.79 85.44,32.79 85.15,32.5 85.15,31.9 84.17,30.92 79.33,30.92 77.8,29.4 v2(77.24,29.4)
  BOTTOM w0.127: UCPU1.AT7 148.25,53.74 v2(148.08,53.74) ; JNGFF1.45 44.25,37.66 44.76,37.14 45.03,37.14 RC47.2 44.37,36.86 v2(44.35,36.84)
CLKREQ_PCIE#3: length 42.9
  TOP w0.127: v2(174.49,36.4) 174.83,36.73 174.83,36.94 RC59.2
  IN2 w0.089: v2(146.26,53.1) 146.53,52.83 146.53,51.14 148.69,48.98 148.69,46.82 148.57,46.69 148.57,44.32 149.71,43.18 154.23,43.18 154.83,42.58 156.37,42.58 158.98,39.96 159.88,39.96 v2(160.24,40.32)
  BOTTOM w0.076: UCPU1.AT10 146.6,53.45 v2(146.26,53.1)
  BOTTOM w0.127: v2(160.24,40.32) 161.67,40.32 162.57,39.42 163.42,39.42 164.39,38.45 v3(172.44,38.45) 172.94,38.45 173.94,37.45 173.94,36.84 174.38,36.4 v2(174.49,36.4) 174.84,36.05 175.6,36.05 JNGFF2.52
CLKREQ_PCIE#5: length 80.8
  TOP w0.127: v2(201.98,17.74) 202.29,18.04 RC190.2
  IN4 w0.081: v2(149,52.54) 149,51.95 149.42,51.53 149.42,51.1 152.31,48.21 154.25,48.21 154.39,48.07 154.99,48.07 155.24,47.82 155.24,47.04 155.24,46.48 156.15,45.57 156.15,44.76 157.12,43.78 157.12,41.23 160.9,37.45 161.36,37.45 v2(161.65,37.17) ; v2(171.32,36.33) 170.47,35.47 170.47,31.36 173.75,28.07 173.75,26.94 175.83,24.86 175.83,23.19 180.35,18.67 186.55,18.67 187.01,18.21 193.47,18.21 193.65,18.39 196.79,18.39 197.9,17.28 201.52,17.28 v2(201.98,17.74)
  BOTTOM w0.076: v2(149,52.54) 148.93,52.54 148.67,52.8 UCPU1.AU7
  BOTTOM w0.127: v2(171.32,36.33) 171.32,37.42 170.72,38.03 163.27,38.03 162.41,37.17 v2(161.65,37.17) ; JIO1.30 201.51,18.41 201.51,18.21 v2(201.98,17.74)
CLKRUN#: length 57.6
  TOP w0.127: v2(178.44,69.46) 178.51,69.38 178.51,69.38 178.86,69.03 UE5.A32
  IN1 w0.081: v2(178.44,69.46) 178.27,69.46 176.69,67.88 174.73,67.88 173.79,66.94 173.79,65.14 172.43,63.78 172.43,62.53 172.07,62.17 172.07,61.67 169.55,59.15 169.55,57.1 170.52,56.14 170.52,53.55 167.32,50.35 167.32,49.44 162.84,44.97 159.33,44.97 158.63,45.66 150.74,45.66 149.84,46.57 149.35,46.57 v2(149.2,46.72)
  BOTTOM w0.076: UCPU1.AW11 145.95,51.57 146.23,51.29 146.23,50.48 146.28,50.43 146.28,49.45 146.79,48.94 146.79,48.7 147.69,47.8 148.12,47.8 148.13,47.79
  BOTTOM w0.127: 148.13,47.79 148.64,47.28 148.64,46.97 148.9,46.72 v2(149.2,46.72) 149.35,46.57 149.84,46.57 150.27,46.14 RC27.2
COMP_GT: length 4.2
  TOP w0.203: PU1000.16 72.3,53.76 72.61,53.45 v2(72.85,53.45)
  BOTTOM w0.127: v1(73.58,53.2) 73.1,53.2 v2(72.85,53.45)
  BOTTOM w0.254: v2(72.85,53.45) 72.25,54.05 PR1123.2 PC1056.2
COMP_IA: length 3.7
  TOP w0.203: PR1122.2 PC1021.2 67.27,49.01 68.36,50.09 68.36,51.01 PU1000.4
COMP_VSA: length 3.8
  TOP w0.203: v2(69.83,57.21) 69.83,57.21 69.83,56.92 69.56,56.66 PU1000.24
  BOTTOM w0.254: PR1090.1 67.74,56.49 PC1081.1 68.94,56.49 69.18,56.73 69.31,56.73 69.78,57.21 v2(69.83,57.21)
CORE_VID0: length 78.6
  TOP w0.127: v2(189.98,68.79) 190.28,68.79 192.08,66.99 195.89,66.99 195.89,67 197.13,68.25 202.71,68.25 202.92,68.03 v1(202.95,68.03) 204.57,68.03 204.86,68.32 204.86,71.78 204.55,72.09 PR1419.1
  IN3 w0.089: v2(189.98,68.79) 189.93,68.79 187.74,70.99 184.31,70.99 183.83,71.47 179.11,71.47 178.71,71.08 174.82,71.08 173.47,69.74 173.47,69.17 171.93,67.62 171.3,67.62 170.83,67.15 164.06,67.15 162.82,65.92 161.67,65.92 161.15,65.4 161.15,61.59 160.7,61.15 160.17,61.15 159.69,60.67 159.69,60.41 157.6,58.31 157.14,58.31 156.27,57.44 154.67,57.44 154.13,57.98 151.27,57.98 150.03,56.74 145.77,56.74 144.83,55.8 144.83,55.22 145.01,55.03 v2(145.37,55.03)
  BOTTOM w0.076: v2(145.37,55.03) 145.74,55.4 UCPU1.AN11
CORE_VID1: length 88.1
  TOP w0.127: PR1420.1 197.84,69.43 195.83,67.42 194.84,67.42 194.46,67.8 193.31,67.8 192.91,67.4 192.04,67.4 190.42,69.02 v1(190.42,69.78) 190.42,70.27 v2(190.63,70.48)
  IN1 w0.081: v2(144.38,55.14) 144.88,55.64 144.88,55.8 145.33,56.24 148.31,56.24 148.59,55.97 148.59,55.58 148.53,55.52 148.53,53.05 148.55,53.03 148.55,51.18 150.57,49.16 154.05,49.16 155.98,51.09 157.89,51.09 158.88,50.1 163.75,50.1 166.02,52.36 166.02,56.8 166.73,57.51 166.73,59.42 168,60.68 168,62.02 168.77,62.79 169.07,62.79 169.42,63.14 169.42,64.44 170.75,65.77 170.75,67.56 172.03,68.85 172.75,68.85 174.7,70.79 177.32,70.79 177.79,71.26 178.17,71.26 178.92,72.01 181.46,72.01 182.58,73.13 187.47,73.13 189.31,71.3 190.59,71.3 190.74,71.14 190.74,70.59 v2(190.63,70.48)
  BOTTOM w0.127: UCPU1.AN13 144.64,55.4 v2(144.38,55.14)
CPU_B+: length 19.8
  IN1 w0.203: v2(80.86,57.45) 80.57,57.74 77.45,57.74 77.17,58.02 75.77,58.02 75.49,57.74 72,57.74 70.95,58.79 65.8,58.79 64.12,57.11 63.73,57.11 v2(63.48,57.36)
  BOTTOM w0.203: PR1066.2 v2(63.48,57.36)
  vias: v2(75.34,43.21) v2(75.27,41.86) v2(75.79,42.55) v2(75.76,41.41) v2(76.31,43.19) v2(76.28,41.82) v2(79.68,44.41) v2(80.32,44.99) v2(80.29,44.4) v2(80.57,51.62) v2(80.75,52.18) v2(80.8,49.52) v2(80.8,48.18) v2(80.8,46.83) v2(80.86,65.03) v2(80.86,63.68) v2(80.86,62.34) v2(80.87,58.76) v2(80.87,58.12) v2(80.86,56.1) v2(80.86,54.76) v2(81.82,49.52) v2(81.82,48.18) v2(81.82,46.83) v2(81.88,65.03) v2(81.88,63.68) v2(81.88,62.34) v2(81.88,57.45) v2(81.88,56.1) v2(81.88,54.76) v3(77.01,42.5)
CPU_B+_CORE: length 3.7
  TOP w0.203: PU1000.33 66.41,54.56 65.82,54.56 65.53,54.85 v2(65.15,54.85)
  BOTTOM w0.203: v2(65.15,54.85) 65.15,55.18 PC1005.1 63.6,55.71 PR1066.1
CPU_DDI1_AUXN: length 100.3
  TOP w0.127: CT26.2 52.73,56.24 53.11,56.24 v2(53.36,56)
  IN2 w0.076: 122.73,70.54 122.73,70.53 122.76,70.5 122.76,68.26 122.82,68.2 122.92,68.2 122.99,68.27 122.99,68.83 123.04,68.88 123.14,68.88 123.4,68.62 v2(123.4,68.57)
  IN2 w0.102: v2(53.36,56) 53.63,56.26 53.77,56.26 53.89,56.15 53.89,54.96 53.79,54.86 50.97,54.86 50.34,55.49 50.34,60.96 50.44,61.06 51.47,61.06 52.79,62.37 54.51,62.37 55.02,62.88 55.02,64.86 55.28,65.12 57.17,65.12 59.36,67.31 59.57,67.31 63.66,71.41 64.35,71.41 65.07,72.12 67.82,72.12 68.97,73.27 70.44,73.27 70.58,73.4 78.73,73.4 79.38,72.75 80.33,72.75 80.91,72.18 90.91,72.18 91.25,71.84 96.95,71.84 100.25,68.54 107.04,68.54 107.77,69.27 108.38,69.27 109.7,70.6 111.21,70.6 111.64,71.02 111.64,71.71 112.22,72.29 115.43,72.29 115.73,71.99 121.59,71.99 122.73,70.85 122.73,70.54
  BOTTOM w0.127: v2(123.4,68.57) 123.64,68.57 123.85,68.36 UCPU1.G50
CPU_DDI1_AUXN_C: length 9.8
  TOP w0.127: UT1.W11 46.05,60.1 v2(45.73,60.42) ; v2(51.26,55.99) 51.33,56.07 51.71,56.07 CT26.1
  IN4 w0.091: v2(51.26,55.99) 51.25,56 50.39,56 49.79,56.59 49.79,56.99 49.69,57.09 47.74,57.09 47,57.83 47,59.24 46.73,59.52 46.23,59.52 45.97,59.77 45.97,60.18 v2(45.73,60.42)
CPU_DDI1_AUXP: length 100.1
  TOP w0.127: v2(53.36,56.58) 53.28,56.5 52.5,56.5 CT25.2
  IN2 w0.076: 122.95,70.54 122.95,70.53 122.92,70.5 122.92,69.12 123,69.05 123.25,69.05 v2(123.39,69.19)
  IN2 w0.102: 122.95,70.54 122.95,70.95 121.68,72.22 115.82,72.22 115.53,72.51 112.13,72.51 111.42,71.8 111.42,71.12 111.12,70.82 109.61,70.82 108.29,69.5 107.68,69.5 106.94,68.76 100.35,68.76 97.05,72.06 91.34,72.06 91,72.4 81,72.4 80.42,72.98 79.47,72.98 78.82,73.63 70.48,73.63 70.35,73.49 68.87,73.49 67.73,72.35 64.97,72.35 64.26,71.63 63.57,71.63 59.47,67.53 59.27,67.53 57.08,65.35 55.19,65.35 54.8,64.96 54.8,62.97 54.42,62.59 52.69,62.59 51.38,61.28 50.35,61.28 50.12,61.05 50.12,55.4 50.88,54.64 53.88,54.64 54.11,54.87 54.11,56.24 53.87,56.49 53.46,56.49 v2(53.36,56.58)
  BOTTOM w0.127: UCPU1.F50 v2(123.39,69.19)
CPU_DDI1_AUXP_C: length 9.7
  TOP w0.127: UT1.Y11 46.7,60.1 v2(46.38,60.42) ; v2(51.26,56.58) 51.51,56.32 51.59,56.32 CT25.1
  IN4 w0.091: v2(51.26,56.58) 50.87,56.19 50.47,56.19 49.99,56.67 49.99,57.07 49.77,57.29 47.82,57.29 47.2,57.91 47.2,59.32 46.81,59.71 46.31,59.71 46.17,59.85 46.17,60.2 v2(46.38,60.42)
CPU_DDI2_AUXN: length 117.7
  TOP w0.127: v2(53.45,57.89) 53.32,57.76 52.64,57.76 CT107.2
  IN2 w0.076: 123.93,70.46 123.93,70.45 123.9,70.42 123.9,70.22 v2(124.31,69.81)
  IN2 w0.102: v2(53.45,57.89) 54.18,57.89 54.82,57.26 54.82,54.48 54.27,53.93 50.52,53.93 49.4,55.05 49.4,60.84 49.29,60.96 49.29,63.63 49.4,63.75 49.4,67.82 51.14,69.56 52.4,69.56 54.63,71.79 54.63,72.43 55.12,72.93 55.91,72.93 57.59,74.6 57.59,75.48 58.42,76.31 59.06,76.31 59.6,76.86 64.72,76.86 65.13,77.27 65.13,77.71 66.14,78.72 68.75,78.72 69.9,77.57 71.69,77.57 72.6,78.48 76.1,78.48 76.44,78.82 78.35,78.82 80.48,76.69 84.35,76.69 84.85,77.19 87.07,77.19 87.8,77.91 89.56,77.91 89.82,78.17 89.82,78.69 90.49,79.35 91.31,79.35 91.85,79.89 121.09,79.89 123.63,77.36 123.63,76.13 123.52,76.03 123.52,73.81 123.24,73.53 123.24,71.68 123.93,70.98 123.93,70.46
  BOTTOM w0.127: v2(124.31,69.81) 124.53,69.59 UCPU1.E48
CPU_DDI2_AUXN_C: length 9.8
  TOP w0.127: UT1.W12 46.05,60.75 v2(45.73,61.07) ; v2(51.26,57.88) 51.35,57.79 51.66,57.79 CT107.1
  IN4 w0.091: v2(51.26,57.88) 51.22,57.84 50.39,57.84 49.3,58.93 49.3,59.8 48.36,60.74 47.79,60.74 47.64,60.89 47.64,61.4 47.07,61.96 46.21,61.96 45.87,61.62 45.87,61.21 v2(45.73,61.07)
CPU_DDI2_AUXP: length 117.6
  TOP w0.127: v2(53.45,57.31) 53.25,57.51 52.6,57.51 CT108.2
  IN2 w0.076: v2(124.31,69.18) 124.31,69.07 124.08,68.84 123.97,68.84 123.81,69.01 123.81,70.08 123.74,70.15 123.74,70.42 123.71,70.45 123.71,70.46
  IN2 w0.102: v2(53.45,57.31) 53.45,57.37 53.75,57.67 54.09,57.67 54.59,57.16 54.59,54.58 54.17,54.16 50.61,54.16 49.63,55.14 49.63,60.93 49.51,61.05 49.51,63.54 49.63,63.66 49.63,67.73 51.24,69.34 52.49,69.34 54.85,71.7 54.85,72.34 55.22,72.7 56.01,72.7 57.81,74.51 57.81,75.39 58.51,76.09 59.15,76.09 59.69,76.63 64.81,76.63 65.35,77.17 65.35,77.62 66.23,78.49 68.66,78.49 69.81,77.34 71.78,77.34 72.69,78.25 76.19,78.25 76.53,78.6 78.26,78.6 80.39,76.46 84.44,76.46 84.94,76.96 87.17,76.96 87.89,77.69 89.65,77.69 90.04,78.08 90.04,78.6 90.58,79.13 91.4,79.13 91.94,79.67 121,79.67 123.4,77.27 123.4,76.23 123.3,76.12 123.3,73.91 123.01,73.62 123.01,71.59 123.71,70.89 123.71,70.46
  BOTTOM w0.127: UCPU1.F48 124.77,69.05 124.57,69.25 124.39,69.25 v2(124.31,69.18)
CPU_DDI2_AUXP_C: length 9.8
  TOP w0.127: v2(46.38,61.07) 46.38,61.05 46.68,60.75 UT1.Y12 ; CT108.1 51.64,57.54 51.5,57.54 v2(51.26,57.3)
  IN4 w0.091: v2(51.26,57.3) 51.06,57.49 51.06,57.5 50.91,57.65 50.31,57.65 49.11,58.85 49.11,59.72 48.28,60.55 47.71,60.55 47.45,60.81 47.45,61.32 46.99,61.77 46.29,61.77 46.07,61.54 46.07,61.31 46.31,61.07 v2(46.38,61.07)
CPU_DP1_CTRL_CLK: length 265.5
  TOP w0.127: UT1.Y5 46.7,57.52 46.42,57.81 v2(46.38,57.81) ; v2(150.19,74.49) 150.19,75.62 RC175.1
  IN2 w0.089: v2(145.2,65.88) 146.76,64.32 147.33,64.32 147.63,64.02 147.63,63.63 148.11,63.15 149.49,63.15 152.04,60.6 152.04,58.63 152.58,58.1 152.58,56.99 152.83,56.73 154.09,56.73 154.54,57.18 155.7,57.18 156.77,56.11 157.13,56.11 157.13,56.11 157.54,56.11 159.01,54.64 159.01,52.79 164.62,47.19 164.62,41.49 163.77,40.65 163.77,39.53 165.1,38.2 165.1,34.85 164.61,34.35 164.61,21.16 162.13,18.68 158.88,18.68 157.04,16.84 152.03,16.84 151.06,15.86 132.88,15.86 130.92,17.83 127.23,17.83 125.12,15.72 118.22,15.72 115.95,17.99 107.85,17.99 107.31,17.99 106.87,17.55 102.6,17.55 97.84,22.31 96.14,22.31 95.56,22.31 94.97,22.89 93.79,22.89 93.46,23.23 93.46,24.51 92.64,25.33 90.07,25.33 89.17,24.43 87.82,24.43 87.78,24.39 86.13,24.39 86,24.52 79.72,24.52 79.17,25.07 75.79,25.07 70.39,19.67 68.68,19.67 67.13,18.12 63.88,18.12 63.17,17.41 60.04,17.41 59.66,17.79 55.17,17.79 50.91,17.79 50.47,17.35 49.45,17.35 49.03,17.77 43.94,17.77 43.11,16.94 42.68,16.94 42.16,17.46 42.16,17.46 41.33,18.28 39.84,18.28 38.24,19.88 36.62,19.88 35.93,20.57 35.93,24.03 36.79,24.9 36.79,25.48 36.04,26.23 36.04,29.14 36.79,29.89 36.79,31.22 37.88,32.31 37.88,34.48 37.52,34.85 37.52,35.3 36.79,36.03 36.79,37.06 37.19,37.45 37.19,39.4 37.74,39.96 37.74,40.96 38.36,41.58 38.36,42.75 37.9,43.21 37.9,48.48 38.59,49.16 40.02,49.16 40.95,50.09 40.95,51.89 40,52.84 39.94,52.84 38.55,54.23 38.55,55.18 39.08,55.71 42.8,55.71 42.9,55.81 44.28,55.81 44.82,56.35 44.82,56.77 44.69,56.91 44.69,57.29 44.95,57.56 46.13,57.56 v2(46.38,57.81)
  IN3 w0.089: v2(145.2,65.88) 145.2,66.11 145.77,66.68 145.77,69.4 146.43,70.06 146.43,71.18 148.73,73.48 148.73,73.62 148.74,73.63 148.74,73.96 148.73,73.97 148.73,74.13 149.27,74.67 150.01,74.67 v2(150.19,74.49)
  BOTTOM w0.076: v2(145.2,65.88) 144.84,66.28 UCPU1.L13
CPU_DP1_CTRL_DATA: length 259.6
  TOP w0.127: UT1.R4 44.09,56.85 v2(43.78,57.16) ; v2(149.17,73.88) 149.21,73.92 149.21,74.45 149.33,74.56 RC178.1
  IN2 w0.089: v2(145.78,65.88) 145.83,65.83 145.83,65.68 146.96,64.56 147.43,64.56 147.87,64.12 147.87,63.77 148.25,63.39 149.56,63.39 152.23,60.73 152.77,60.73 153.05,60.45 153.05,59.25 153.05,59.07 154.72,57.4 155.79,57.4 156.86,56.33 157.04,56.33 157.63,56.33 159.23,54.73 159.23,52.88 164.84,47.27 164.84,41.41 163.99,40.56 163.99,39.62 165.32,38.29 165.32,34.76 164.82,34.26 164.82,21.07 162.22,18.46 159.08,18.46 157.24,16.62 152.15,16.62 151.17,15.64 132.79,15.64 130.83,17.61 127.32,17.61 125.21,15.5 118.13,15.5 115.86,17.77 107.76,17.77 107.4,17.77 106.96,17.33 102.51,17.33 97.75,22.09 96.23,22.09 95.47,22.09 94.88,22.68 93.7,22.68 93.24,23.14 93.24,24.42 92.55,25.12 90.16,25.12 89.26,24.22 87.91,24.22 87.87,24.18 86.04,24.18 85.92,24.3 79.63,24.3 79.08,24.85 75.88,24.85 70.48,19.45 68.77,19.45 67.22,17.9 63.97,17.9 63.26,17.19 59.95,17.19 59.57,17.57 55.08,17.57 51,17.57 50.56,17.13 49.36,17.13 48.99,17.51 45.22,17.51 44.39,16.68 42.63,16.68 41.24,18.07 39.75,18.07 38.15,19.67 36.53,19.67 35.71,20.48 35.71,24.12 36.58,24.99 36.58,25.39 35.83,26.14 35.83,29.23 36.58,29.98 36.58,31.31 37.67,32.4 37.67,34.39 37.3,34.76 37.3,35.21 36.38,36.13 36.38,40.81 37.47,41.9 37.47,43.8 37.69,44.02 37.69,48.57 38.5,49.38 39.93,49.38 40.73,50.18 40.73,51.8 39.91,52.62 39.85,52.62 38.34,54.14 38.34,55.27 38.99,55.92 42.63,55.92 43.43,56.73 43.43,56.81 v2(43.78,57.16)
  IN3 w0.089: v2(145.78,65.88) 146.71,66.81 146.71,71.15 149.17,73.62 v2(149.17,73.88)
  BOTTOM w0.127: v2(145.78,65.88) 145.49,66.18 UCPU1.L12
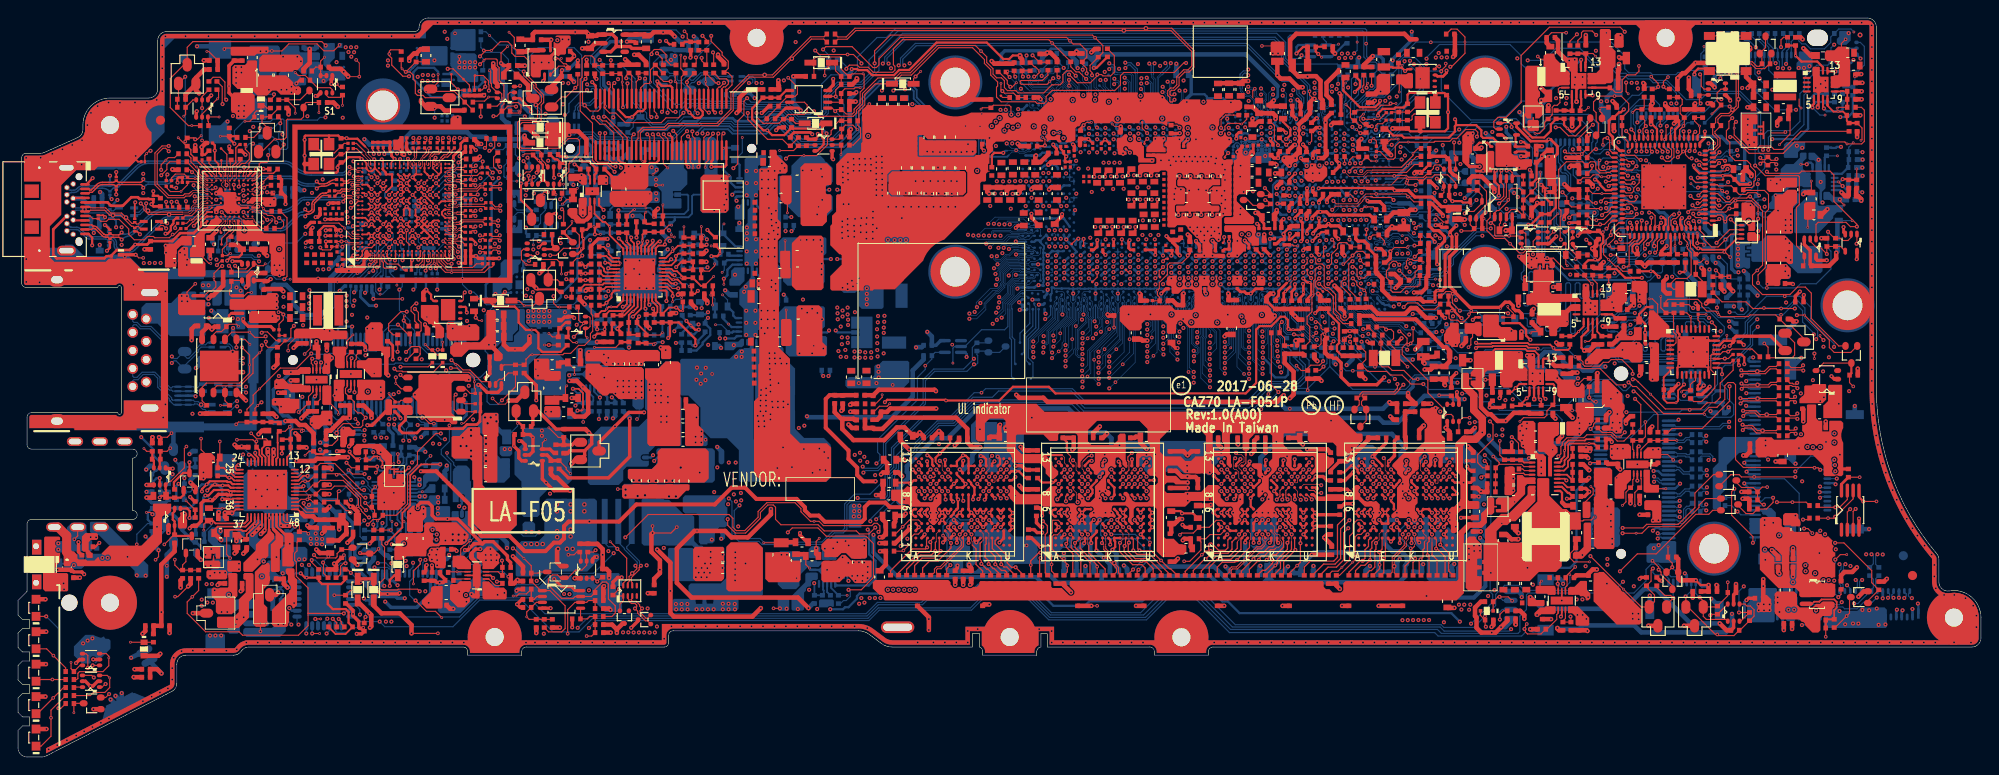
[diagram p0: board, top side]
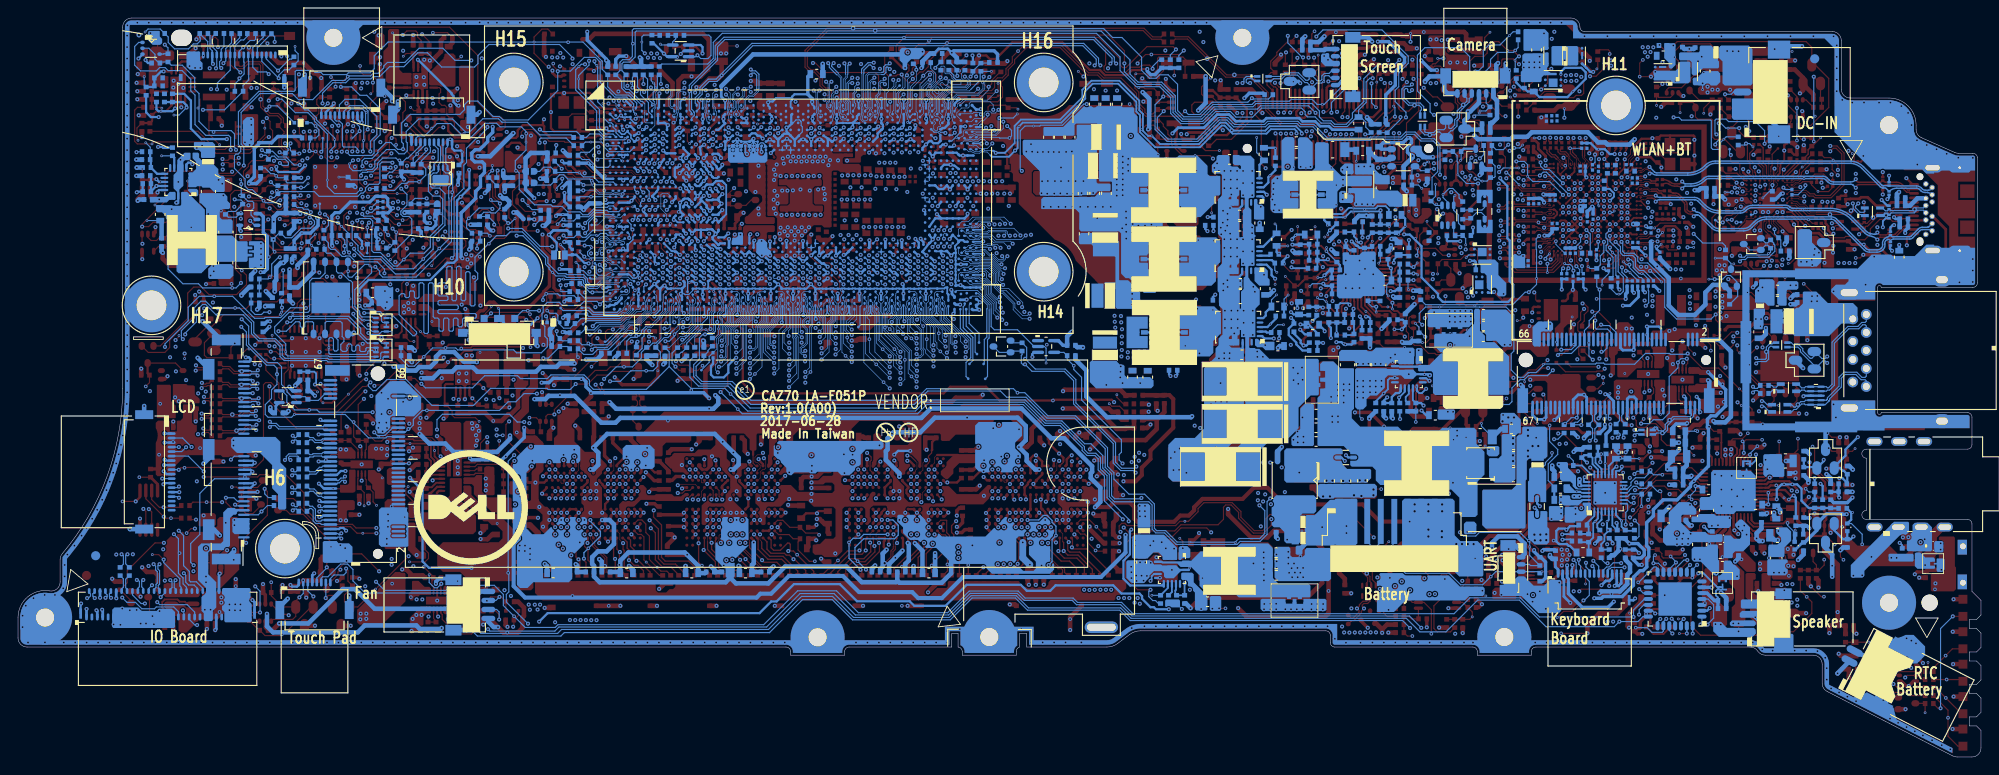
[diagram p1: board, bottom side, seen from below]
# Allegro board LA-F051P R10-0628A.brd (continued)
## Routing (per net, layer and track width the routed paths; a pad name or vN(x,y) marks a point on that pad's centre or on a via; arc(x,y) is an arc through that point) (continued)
CPU_DP1_HPD: length 256.7
  TOP w0.076: 47.17,55.36 47.17,55.92 UT1.AA2
  TOP w0.127: v2(147.78,65.87) 147.78,66.28 148.09,66.59 RC312.2 ; v2(48.11,54.73) 48.1,54.72 47.63,54.72 47.17,55.19 47.17,55.36
  IN1 w0.081: v2(36.45,48.33) 36.58,48.46 37.72,48.46 38.42,49.16 38.71,49.16 38.71,49.16 40.28,49.16 40.93,49.81 40.93,51.37 42.06,52.51 45.66,52.51 46.06,52.92 46.46,52.92 48.11,54.57 v2(48.11,54.73)
  IN2 w0.089: v2(147.78,65.87) 148.18,65.46 150.22,65.46 151.56,64.12 151.56,62.31 152.49,61.38 153.09,61.38 154.61,59.86 155.59,59.86 157.05,58.4 157.35,58.4 157.94,57.81 157.94,57.68 158.51,57.11 164.05,57.11 165.99,55.16 165.99,48.24 166.18,48.05 166.18,42.67 166.58,42.27 166.58,40.78 166.49,40.69 166.49,39.47 168.28,37.68 168.28,34.95 166.49,33.16 166.49,27.16 165.57,26.25 165.57,20.9 162.49,17.81 159.51,17.81 157.58,15.88 152.33,15.88 151.44,15 132.52,15 130.56,16.96 127.59,16.96 125.48,14.86 117.86,14.86 115.59,17.12 108.67,17.12 108.07,16.53 102.4,16.53 97.48,21.45 95.2,21.45 94.61,22.03 93.43,22.03 92.6,22.87 92.6,24.15 92.36,24.39 90.35,24.39 89.53,23.57 88.18,23.57 83.42,18.8 69.04,18.8 67.49,17.26 64.24,17.26 63.53,16.54 59.68,16.54 59.32,16.91 56.42,16.91 55.84,16.32 55.13,16.32 54.53,16.92 51.27,16.92 50.83,16.49 49.09,16.49 48.72,16.86 46.69,16.86 45.86,16.03 42.36,16.03 42.32,16.07 40.3,16.07 39.18,17.19 38.09,17.19 34.46,20.82 34.46,21.7 35.02,22.26 35.02,27.26 35.18,27.41 35.18,29.5 35.93,30.25 35.93,32.29 35.69,32.53 35.69,33.26 36,33.57 36,34.56 35.73,34.82 35.73,41.58 35.52,41.79 35.52,43.7 36.4,44.59 36.4,48.28 v2(36.45,48.33)
  BOTTOM w0.127: UCPU1.L9 147.44,66.26 147.78,65.92 v2(147.78,65.87) ; v2(48.11,54.73) v1(48.11,53.76)
CPU_DP2_CTRL_CLK: length 265
  TOP w0.076: 150.3,65.13 150.28,65.13 150.26,65.11 149.7,65.11 149.21,64.62 148.72,64.62 v2(148.37,64.97)
  TOP w0.127: 150.3,65.13 153.67,65.13 v1(154.18,65.64) 155.17,66.63 RC176.1 ; UT1.Y8 46.7,58.8 v2(46.38,59.11)
  IN1 w0.081: v2(37.06,49.06) 37.96,49.06 38.26,49.37 40.16,49.37 40.72,49.92 40.72,51.46 42,52.74 45.53,52.74 47.36,54.57 47.36,55.95 47.94,56.54 47.94,57.55 v2(46.38,59.11)
  IN2 w0.089: v2(37.06,49.06) 37.06,48.31 36.67,47.93 36.67,44.55 36.22,44.1 36.22,41.54 35.95,41.27 35.95,34.91 36.21,34.64 36.21,33.48 35.9,33.17 35.9,32.62 36.14,32.38 36.14,30.16 35.4,29.41 35.4,27.33 35.24,27.17 35.24,22.17 34.68,21.61 34.68,20.91 37.59,17.99 38.63,17.99 38.99,17.64 41.06,17.64 42.45,16.25 45.63,16.25 46.46,17.07 48.81,17.07 49.18,16.7 50.74,16.7 51.18,17.14 54.62,17.14 55.22,16.54 55.75,16.54 56.35,17.14 59.39,17.14 59.77,16.76 63.44,16.76 64.15,17.47 67.4,17.47 68.95,19.02 70.66,19.02 75.23,23.59 78.75,23.59 79.03,23.87 85.74,23.87 85.86,23.75 88.05,23.75 88.09,23.78 89.44,23.78 90.34,24.68 92.37,24.68 92.81,24.24 92.81,22.96 93.52,22.25 94.7,22.25 95.29,21.66 97.57,21.66 102.49,16.74 106.98,16.74 107.58,17.34 115.68,17.34 117.95,15.07 125.39,15.07 127.5,17.18 130.65,17.18 132.61,15.21 151.35,15.21 152.33,16.19 157.54,16.19 159.38,18.03 162.4,18.03 165.25,20.89 165.25,32.23 168.06,35.04 168.06,37.59 166.27,39.38 166.27,40.23 165.68,40.81 165.68,46.43 165.3,46.81 165.3,48.57 164.88,48.99 164.88,49.91 165.78,50.81 165.78,55.07 163.96,56.89 159.94,56.89 159.28,56.23 158.35,56.23 157.82,56.76 157.04,56.76 156.78,57.02 156.78,57.96 155.1,59.64 154.52,59.64 153,61.16 152.41,61.16 151.35,62.22 151.35,64.03 150.82,64.55 148.79,64.55 v2(148.37,64.97)
  BOTTOM w0.127: UCPU1.N7 148.74,65.33 v2(148.37,64.97)
CPU_DP2_CTRL_DATA: length 258.5
  TOP w0.127: v2(147.74,64.97) 147.74,65.04 148.15,65.45 153.5,65.45 154.78,66.73 v1(154.78,66.97) 155.33,67.52 RC177.1 ; UT1.N4 43.44,56.85 43.08,57.2 43.08,58.41 v2(43.13,58.45)
  IN2 w0.089: v2(147.74,64.97) 148.37,64.33 149.96,64.33 150.22,64.08 150.22,63.04 152.32,60.94 152.86,60.94 153.26,60.54 153.26,59.16 154.81,57.62 155.88,57.62 156.95,56.54 157.72,56.54 159.45,54.82 159.45,52.97 165.08,47.34 165.08,46.72 165.45,46.36 165.45,38.95 166.21,38.2 166.21,33.88 165.04,32.71 165.04,20.98 162.31,18.25 159.26,18.25 157.42,16.4 152.24,16.4 151.26,15.43 132.7,15.43 130.74,17.4 127.41,17.4 125.3,15.29 118.04,15.29 115.77,17.55 107.67,17.55 107.49,17.55 107.05,17.12 102.42,17.12 97.66,21.88 96.32,21.88 95.38,21.88 94.79,22.46 93.61,22.46 93.03,23.05 93.03,24.33 92.46,24.9 90.25,24.9 89.35,24 88,24 87.96,23.96 85.95,23.96 85.83,24.09 79.54,24.09 78.99,24.63 75.97,24.63 70.57,19.24 68.86,19.24 67.31,17.69 64.06,17.69 63.35,16.98 59.86,16.98 59.48,17.35 51.09,17.35 50.65,16.92 49.27,16.92 48.9,17.29 46.37,17.29 45.54,16.46 42.54,16.46 41.15,17.85 39.08,17.85 38.72,18.21 37.68,18.21 35.5,20.39 35.5,24.21 36.36,25.08 36.36,25.3 35.61,26.05 35.61,29.32 36.36,30.07 36.36,31.4 37.45,32.49 37.45,34.3 37.08,34.67 37.08,35.12 36.16,36.04 36.16,41.18 36.5,41.51 36.5,43.14 37.47,44.11 37.47,48.66 38.41,49.6 39.84,49.6 40.52,50.27 40.52,50.89 39.59,51.82 39.59,52.58 38.12,54.05 38.12,55.36 38.9,56.14 41.99,56.14 43.13,57.28 v2(43.13,58.45)
  BOTTOM w0.127: v2(147.74,64.97) 148.09,65.32 UCPU1.N8
CPU_DP2_HPD: length 257.6
  TOP w0.127: v1(150.72,66.13) 150.11,66.13 RC242.2 148.98,65.92 v2(148.98,65.88) ; UT1.Y6 46.7,58.16 v2(46.38,58.48)
  IN1 w0.081: v2(37.33,50.65) 37.33,51.04 37.68,51.4 37.68,51.66 39.87,53.85 42.56,53.85 43.12,54.4 43.12,55.43 43.46,55.77 46.89,55.77 47.73,56.62 47.73,57.47 46.72,58.48 v2(46.38,58.48)
  IN2 w0.089: v2(148.98,65.88) 150.1,65.88 151.79,64.2 151.79,63.29 154.79,60.29 157.28,60.29 158.37,59.2 158.37,57.86 158.69,57.54 161.33,57.54 162.14,58.35 162.88,58.35 163.69,57.54 164.23,57.54 166.42,55.34 166.42,51.11 167.2,50.34 167.2,48.54 168.44,47.3 168.44,43.74 167.01,42.31 167.01,40.6 166.95,40.54 166.95,39.61 168.71,37.86 168.71,34.77 166.97,33.04 166.97,19.78 164.54,17.35 163.78,17.35 163.64,17.21 162.5,17.21 161.15,15.87 158.42,15.87 157.12,14.57 132.24,14.57 130.36,16.44 127.78,16.44 125.76,14.42 117.68,14.42 115.66,16.44 108.71,16.44 108.36,16.1 100.88,16.1 100.05,16.93 95.35,16.93 94.98,16.56 91.45,16.56 91.22,16.79 89.95,16.79 89.18,16.02 83.49,16.02 81.61,17.9 70.83,17.9 69.96,17.04 64.33,17.04 63.4,16.11 55.04,16.11 54.44,16.71 51.36,16.71 50.47,15.82 42.27,15.82 42.23,15.86 40.21,15.86 39.09,16.98 38,16.98 34.25,20.73 34.25,21.79 34.8,22.35 34.8,27.41 34.96,27.57 34.96,29.59 35.71,30.34 35.71,32.2 35.47,32.44 35.47,33.35 35.78,33.66 35.78,34.47 35.51,34.74 35.51,38.72 34.73,39.5 34.73,40.71 35.3,41.28 35.3,43.79 35.91,44.41 35.91,48.49 36.89,49.46 37.49,49.46 37.73,49.7 37.73,50.42 37.5,50.65 v2(37.33,50.65)
  BOTTOM w0.127: UCPU1.L7 148.74,66.13 v2(148.98,65.88)
CPU_ID: length 4.6
  TOP w0.127: UE5.B41 178.01,64.27 178.16,64.27 178.41,64.02 178.94,64.02 179.19,64.26 179.19,64.28 v2(179.2,64.28)
  BOTTOM w0.127: v2(179.2,64.28) 179.28,64.28 179.53,64.04 180.87,64.04 RE121.2 v1(182.21,64.35)
CPU_POPIRCOMP: length 3.8
  TOP w0.254: v2(142.6,53.1) 143.04,52.66 v1(143.33,52.66) 143.5,52.5 143.5,51.31 143.1,50.91 RC88.1
  BOTTOM w0.305: UCPU1.AT16 v2(142.6,53.1)
CPU_XDP_PRDY#: length 51.6
  TOP w0.127: v2(78.34,74.81) 78.34,74.79 77.89,74.34 77.78,74.34 77.6,74.16 JXDP1.5
  IN3 w0.089: v2(119.55,73.52) 119.3,73.52 118.46,74.37 117.03,74.37 116.73,74.06 112.06,74.06 111.4,73.4 109.65,73.4 109.5,73.25 108.34,73.25 106.12,71.03 102.1,71.03 100.08,73.06 95.3,73.06 93.94,74.42 91.67,74.42 91.45,74.2 90,74.2 88.72,72.91 82.59,72.91 82.37,72.69 80.75,72.69 78.63,74.81 v2(78.34,74.81)
  BOTTOM w0.076: v2(119.55,73.52) 119.93,73.15 119.93,72.69 119.78,72.54 119.78,72.17 119.81,72.1 119.81,71.89 119.8,71.86 119.8,71.83 119.79,71.82 119.78,71.8 119.78,71.55 119.92,71.07 119.92,70.96 119.99,70.69 119.99,70.58 UCPU1.D56
CPU_XDP_PREQ#: length 52.1
  TOP w0.127: RC138.2 77.85,75.24 78.61,75.24 78.83,75.03 78.83,74.7 78.48,74.35 78.3,74.35 78.1,74.16 JXDP1.3 78.1,71.63 v2(77.98,71.51)
  IN3 w0.089: v2(77.98,71.51) 78.47,71.51 79.51,70.46 89.34,70.46 89.68,70.8 91,70.8 91.69,71.49 96.54,71.49 97.65,70.38 106.45,70.38 108.28,72.21 110.02,72.21 110.56,72.75 112.52,72.75 113.18,73.41 118.17,73.41 v2(118.2,73.45)
  BOTTOM w0.076: UCPU1.D61 117.73,70.55 118.03,70.85 118.03,71.18 118.01,71.21 118.01,71.48 118.16,71.64 118.16,73.41 v2(118.2,73.45)
CPVEE: length 3.1
  TOP w0.203: UA2.34 23.85,28.28 v2(23.6,28.03)
  BOTTOM w0.127: v2(23.6,28.03) v3(23.6,29.32)
  BOTTOM w0.254: v2(23.6,28.03) 23.62,28 C1205.1
CSI2_COMP: length 3.1
  TOP w0.127: v1(143.28,68.08) 143.54,68.34 143.54,69.46 RC3.1
  TOP w0.381: RC3.1 143.68,69.47 144.05,69.84 v2(144.43,69.84)
  BOTTOM w0.254: UCPU1.E13 144.64,69.84 v2(144.43,69.84)
CSSN_1: length 6.5
  IN3 w0.203: v2(48.95,27.82) 49.05,27.72 49.05,27.47 46.84,25.25 46.84,24.81 46.69,24.67 46.49,24.67 v2(46.46,24.7)
  BOTTOM w0.203: PR304.1 45.52,24.72 46.43,24.72 v2(46.46,24.7)
  BOTTOM w0.254: PR300.2 49.25,28.13 v2(48.95,27.82)
CSSP_1: length 7.1
  IN3 w0.203: v2(46.43,24.11) 46.82,24.11 47.17,24.46 47.17,25.11 49.38,27.33 49.38,27.52 v2(49.53,27.67)
  BOTTOM w0.203: PR303.1 45.57,24.14 46.41,24.14 v2(46.43,24.11)
  BOTTOM w0.254: PR300.3 49.25,27.39 v2(49.53,27.67)
CV2_ON: length 5.8
  TOP w0.127: UE5.A9 188.53,63.52 188.67,63.38 190.09,63.38 R251.2 190.53,62.88 190.98,62.42 191.74,62.42 191.93,62.61 192.88,62.61 v3(193.19,62.3)
DAT_SMB: length 8.6
  TOP w0.127: PRP100.7 67.66,19.32 67.8,19.46 67.8,20.01 v4(68.15,20.37) 68.66,20.88 68.66,21.06 v2(68.5,21.22)
  BOTTOM w0.127: v2(68.5,21.22) 68.71,21.42 68.71,21.62 67.28,23.04 67.28,23.15 66.6,23.83 JBATT1.4
DAT_TP_SIO: length 91.9
  TOP w0.127: UE5.B40 178.01,64.77 178.32,64.77 178.58,64.5 v2(178.64,64.5) ; MD9.2 182.93,16.9 v2(183.67,17.64) 183.38,17.93 182.72,17.93 181.84,18.8 C1226.1 ; RE7.2 174.65,65.26 v2(174.65,65.61)
  IN2 w0.089: v2(174.65,65.61) 174.93,65.33 175.43,65.33 175.76,65 177.25,65 177.8,64.45 178.58,64.45 v2(178.64,64.5)
  IN3 w0.089: v2(183.67,17.64) 184.28,18.24 190.27,18.24 191.03,19.01 191.03,19.65 193.1,21.71 194.83,21.71 196.7,23.58 199.87,23.58 200.41,23.05 v2(201.7,23.05)
  IN4 w0.089: v2(178.64,64.5) 178.69,64.5 179.13,64.94 179.92,64.94 180.56,64.31 180.56,63.88 181.72,62.72 181.72,58.95 182.31,58.36 186.48,58.36 187.74,57.09 187.74,56.13 186.1,54.5 186.1,53.44 188.88,50.67 191.05,50.67 191.93,49.78 191.93,47.97 193.99,45.91 193.99,35.88 196.01,33.86 196.01,26.17 198.22,23.96 200.79,23.96 v2(201.7,23.05)
  BOTTOM w0.127: v2(183.67,17.64) 183.66,17.64 JTP1.7
DBC_I2C_EN: length 193.7
  TOP w0.127: v2(204.75,28.36) v3(206.22,28.36)
  TOP w0.254: U48.5 204.28,28.84 v2(204.75,28.36)
  IN1 w0.254: v2(204.75,28.36) 204.75,27.66 201.67,24.57 201.32,24.57 200.08,23.33 198.81,23.33 197.45,21.97 197.45,20.44 197.87,20.02 197.87,18.8 192.66,13.6 175.38,13.6 175.24,13.46 160.16,13.46 159.57,14.06 132.1,14.06 130.82,15.33 127.91,15.33 126.44,13.86 117.23,13.86 115.04,16.05 109.69,16.05 109.22,15.58 101.23,15.58 100.59,16.21 94.96,16.21 94.16,15.41 71.15,15.41 70.56,14.82 66.55,14.82 66.35,14.62 64.75,14.62 63.93,13.8 58.47,13.8 v2(58.34,13.67)
  IN2 w0.254: v2(30.1,16.52) 30.76,16.52 33.02,14.26 38.18,14.26 38.75,13.69 42.16,13.69 42.7,14.22 51.11,14.22 52.01,15.13 53.7,15.13 54.3,14.53 57.49,14.53 v2(58.34,13.67)
  BOTTOM w0.254: v2(30.1,16.52) 30.39,16.23 30.96,16.23 UE4.2
DCIN_ACOK: length 319.7
  TOP w0.127: v2(52.3,67.27) 52.47,67.27 52.9,67.69 PR249.1 ; v2(55.26,72.17) 55.21,72.23 54.35,72.23 53.79,71.66 PR250.1 ; v2(23.1,72.93) 22.96,73.07 22.96,74.89 22.42,75.43 21.65,75.43 PR217.1 ; PR262.2 65.89,15.58 66.27,15.96 66.27,16.78 65.51,17.54 65.51,19.19 65.28,19.41 64.85,19.41 64.03,18.6 PC215.1 63.6,17.81 PU203.7 61.82,17.81 61.63,17.61 60.31,17.61 58.85,19.07 58.85,19.76 59.29,20.2 59.87,20.2 60.19,19.88 PQ220.2 61.02,19.88 61.87,20.74 62.56,20.74 63.09,21.27 PQ219.5 63.09,22.61 PR255.2 63.88,22.74 v2(64.08,22.95) ; v2(52.76,71.1) 53.12,71.1 PR250.1 ; PR250.1 53.68,72.23 53.93,72.48 53.93,73.92 53.91,73.94 53.91,74.57 53.39,75.09 53.39,76.49 53.18,76.7 53.18,77.33 53.05,77.45 51.85,77.45 v1(51.7,77.31) v2(51.26,76.87)
  IN2 w0.089: v2(64.08,22.95) 64.08,22.94 61.64,20.49 51.78,20.49 51.25,19.96 42.18,19.96 42.11,19.9 38.84,19.9 38.37,20.37 37.91,20.37 37.02,21.26 37.02,21.73 36.88,21.87 36.88,23.06 37.22,23.4 37.22,25.66 36.48,26.41 36.48,28.96 37.22,29.71 37.22,31.04 38.32,32.13 38.32,34.66 37.95,35.03 37.95,36.64 38.18,36.86 38.18,37.14 37.8,37.52 37.8,39.4 38.18,39.78 38.18,40.78 38.91,41.52 38.91,44.21 v2(38.55,44.57) ; v2(51.26,76.87) 51.12,77.01 51.12,77.26 50.41,77.97 40.42,77.97 38.58,76.14 36.36,76.14 35.95,75.73 34.6,75.73 34.2,76.14 33.56,76.14 33.12,75.7 33.12,74.71 31.33,72.92 27.39,72.92 26.55,73.76 23.93,73.76 v2(23.1,72.93)
  IN3 w0.089: v2(189.92,72.18) 190.44,72.7 190.44,73.45 190.19,73.7 185,73.7 183.68,75.01 181.76,75.01 180.15,73.4 176.88,73.4 176.22,74.06 174.52,74.06 173.98,73.52 173.98,73.01 172.75,71.78 170.92,71.78 169.31,73.39 168.55,73.39 167.66,72.51 166.26,72.51 165.2,71.45 160.77,71.45 157.61,74.62 152.92,74.62 151.45,76.08 145.69,76.08 145.43,76.34 137.01,76.34 136.62,76.73 131.79,76.73 131.14,76.08 124.05,76.08 123.21,75.24 123.21,73.99 122.98,73.75 120.89,73.75 119.66,72.52 119.3,72.52 119.08,72.74 119.08,73.44 118.37,74.15 117.12,74.15 116.82,73.85 112.15,73.85 111.49,73.19 109.74,73.19 109.59,73.03 108.48,73.03 106.27,70.82 97.83,70.82 96.72,71.92 91.51,71.92 90.82,71.23 89.5,71.23 89.16,70.9 79.69,70.9 77.97,72.62 64.77,72.62 64.01,71.87 60.43,71.87 59.43,72.87 56,72.87 55.31,72.17 v2(55.26,72.17)
  IN4 w0.081: v2(52.76,71.1) 52.76,68.46 52.93,68.28 52.93,67.83 52.37,67.27 v2(52.3,67.27) 52.3,66.96 52.07,66.73 52.07,65.92 51.71,65.56 51.71,63.18 53.1,61.8 53.81,61.8 54.38,61.23 54.38,54.54 51.83,51.99 49.31,51.99 48.45,51.13 48.45,49.58 45.6,46.72 40.7,46.72 v2(38.55,44.57)
  BOTTOM w0.127: DE11.1 189.03,72.26 189.84,72.26 v2(189.92,72.18)
DCIN_ACOK#: length 186.4
  TOP w0.127: PR256.2 64.74,19.95 v2(64.27,19.48) 63.91,19.84 PQ219.3 PQ219.2 ; PR220.1 22.66,74.38 22.66,72.53 22.7,72.49 v2(22.7,72.45) ; v2(60.15,61.89) 60.36,62.11 PR284.1 ; PR251.1 v2(51.35,71.07)
  IN1 w0.081: v2(51.84,62.43) 52.61,61.66 59.86,61.66 60.09,61.89 v2(60.15,61.89)
  IN2 w0.089: v2(63.3,79.36) 63.3,79.66 62.6,80.36 58.06,80.36 54.15,76.45 51.47,76.45 51.08,76.06 48.76,76.06 47.09,77.72 40.47,77.72 38.67,75.92 36.44,75.92 36.04,75.51 34.51,75.51 34.11,75.92 33.65,75.92 33.34,75.61 33.34,74.62 31.42,72.7 27.3,72.7 26.46,73.54 24.28,73.54 23.19,72.45 v2(22.7,72.45) ; v2(38.75,48.76) 38.12,48.13 38.12,43.38 38.7,42.8 38.7,41.61 37.96,40.87 37.96,39.87 37.4,39.31 37.4,37.36 37.01,36.97 37.01,36.11 37.73,35.39 37.73,34.94 38.1,34.57 38.1,32.22 37.01,31.13 37.01,29.8 36.26,29.05 36.26,26.32 37.01,25.57 37.01,24.81 36.15,23.95 36.15,22.3 36.81,21.64 36.81,21.17 37.82,20.15 38.28,20.15 39.93,18.5 41.42,18.5 42.77,17.15 43.02,17.15 43.85,17.99 49.12,17.99 49.54,17.57 50.38,17.57 51.22,18.4 53.48,18.4 53.73,18.66 54.36,18.66 54.97,18.04 59.71,18.04 60.13,17.62 63.08,17.62 64.27,18.81 v2(64.27,19.48)
  IN4 w0.081: v2(51.35,71.07) 51.36,71.05 51.36,70.13 49.95,68.72 49.95,63.29 50.27,62.98 51.19,62.98 51.74,62.43 v2(51.84,62.43) 52.68,61.59 53.72,61.59 54.09,61.22 54.09,54.55 51.74,52.2 49.19,52.2 48.24,51.25 48.24,49.66 45.51,46.93 40.58,46.93 v2(38.75,48.76) ; v2(60.15,61.89) 61.05,62.79 61.05,63.66 61.77,64.39 61.77,64.97 62.28,65.48 62.28,65.81 62.03,66.06 62.03,66.39 62.64,66.99 62.64,74.55 62.47,74.73 62.47,75.54 63.86,76.93 63.86,78.8 v2(63.3,79.36)
  BOTTOM w0.127: v2(63.3,79.36) v1(63.3,80.3)
DDI1_PTX_TBRX_N0: length 82.8
  TOP w0.127: v2(50.75,58.86) 50.57,58.68 50.41,58.68 CT18.2
  IN2 w0.102: v2(120.65,69.81) 120.52,69.81 120.42,69.91 120.42,70.07 119.69,70.8 117.95,70.8 117.38,70.23 116.6,70.23 116.37,70.46 114.77,70.46 114.69,70.39 114.39,70.39 114.27,70.51 113.6,70.51 113.16,70.08 113.16,69.7 110.98,67.52 109.83,67.52 109.67,67.67 108.96,67.67 108,66.71 100.37,66.71 96.53,70.54 87.3,70.54 86.94,70.19 80.23,70.19 78.2,72.22 71.12,72.22 70.97,72.07 69.93,72.07 68.35,70.49 67.51,70.49 57.21,60.2 53.01,60.2 52.24,59.43 52.24,58.64 52.11,58.52 51.09,58.52 v2(50.75,58.86)
  BOTTOM w0.127: UCPU1.E55 121.07,69.55 120.91,69.55 v2(120.65,69.81)
DDI1_PTX_TBRX_N0_C: length 2.7
  TOP w0.076: UT1.AC7 47.74,58.45 47.65,58.53 47.65,58.61 47.73,58.68 48.03,58.68 48.34,58.38 48.62,58.38 48.93,58.69 48.97,58.69
  TOP w0.127: CT18.1 49.3,58.86 49.13,58.69 48.97,58.69
DDI1_PTX_TBRX_N1: length 77.7
  TOP w0.127: CT20.2 52.44,59.64 52.6,59.48 53.12,59.48 53.16,59.52 v2(53.28,59.52)
  IN2 w0.102: v2(53.28,59.52) 53.31,59.5 57.51,59.5 59.43,61.42 60.44,61.42 63.16,64.13 63.16,65.14 67.79,69.78 68.66,69.78 69.11,70.24 71.6,70.24 72.26,70.9 78.5,70.9 80.13,69.27 82.49,69.27 82.62,69.14 86.93,69.14 87.61,69.83 90.38,69.83 91.01,69.19 93.18,69.19 93.53,69.55 96.51,69.55 100.06,66 110.47,66 111.88,67.42 115.03,67.42 115.37,67.76 115.37,69.08 115.67,69.37 118.03,69.37 118.14,69.48 118.53,69.48 v2(118.84,69.79)
  BOTTOM w0.127: v2(118.84,69.79) 119.04,69.59 UCPU1.E58
DDI1_PTX_TBRX_N1_C: length 4.7
  TOP w0.076: UT1.AC9 47.78,59.45 47.78,59.55 47.82,59.6 48.08,59.6 48.18,59.5 48.18,59.38 48.27,59.29 48.59,59.29 48.65,59.35 48.67,59.35
  TOP w0.127: CT20.1 51.7,59.6 49.25,59.6 49,59.35 48.67,59.35
DDI1_PTX_TBRX_N2: length 85.8
  TOP w0.127: CT22.2 50.23,60.64 50.42,60.45 50.59,60.45 v2(50.75,60.61)
  IN2 w0.102: v2(50.75,60.61) 51.07,60.3 51.61,60.3 51.8,60.49 51.8,60.65 52.98,61.82 57.5,61.82 57.86,62.19 57.86,63.2 58.35,63.69 59.71,63.69 61.12,65.11 61.12,66.21 63.58,68.67 63.58,69.42 64.53,70.37 66.08,70.37 66.48,70.76 66.48,71.22 66.89,71.64 68.04,71.64 69.17,72.77 70.63,72.77 70.78,72.92 78.51,72.92 79.34,72.09 80.02,72.09 80.54,71.57 80.54,71.21 80.83,70.92 86.67,70.92 87.01,71.26 96.84,71.26 100.09,68 107.22,68 107.98,68.76 110.28,68.76 112.14,70.62 112.14,71.33 112.59,71.78 115.12,71.78 115.4,71.5 120.01,71.5 121.36,70.15 121.36,69.71 121.44,69.63 121.67,69.63 121.77,69.53 121.77,69.38 v2(121.57,69.18)
  BOTTOM w0.127: v2(121.57,69.18) 121.81,68.94 UCPU1.F53
DDI1_PTX_TBRX_N2_C: length 2.5
  TOP w0.076: UT1.AC11 47.72,60.29 47.65,60.36 47.65,60.46 47.72,60.53 48.13,60.53 48.23,60.43 48.67,60.43 48.71,60.46 48.72,60.46
  TOP w0.127: 48.72,60.46 48.72,60.47 49.47,60.47 CT22.1
DDI1_PTX_TBRX_N3: length 82.3
  TOP w0.127: v2(53.52,61.19) 53.38,61.06 52.95,61.06 52.49,61.51 CT24.2
  IN1 w0.091: v2(60.2,57.6) 60.05,57.45 59.41,57.45 55.85,61.02 53.71,61 v2(53.52,61.19)
  IN2 w0.102: v2(60.2,57.6) 60.2,57.53 60.3,57.43 60.96,57.43 61.84,58.31 61.84,61.81 63.86,63.83 63.86,64.85 67.32,68.31 72.13,68.31 74,70.18 78.2,70.18 79.82,68.56 82.1,68.56 82.24,68.43 96.61,68.43 99.81,65.24 104.81,65.24 105.43,64.62 107.47,64.62 108.1,65.24 110.71,65.24 111.39,65.92 112.76,65.92 113.19,66.35 114.75,66.35 114.88,66.22 115.18,66.22 115.65,66.69 115.65,66.93 116.27,67.55 117.24,67.55 117.82,68.13 119.01,68.13 119.33,68.45 119.33,68.72 119.74,69.13 119.74,69.13 v2(119.74,69.13)
  BOTTOM w0.127: UCPU1.F56 119.93,68.94 119.74,69.12 119.74,69.13 v2(119.74,69.13)
DDI1_PTX_TBRX_N3_C: length 4.5
  TOP w0.076: 49.18,61.34 49.12,61.28 48.81,61.28 48.66,61.13 48.35,61.13 48.08,61.4 47.88,61.4 47.83,61.35 47.83,61.24 UT1.AC13
  TOP w0.127: CT24.1 51.74,61.34 49.18,61.34
DDI1_PTX_TBRX_P0: length 83
  TOP w0.127: CT17.2 50.43,58.42 50.6,58.42 v2(50.75,58.28)
  IN2 w0.102: v2(50.75,58.28) 50.77,58.29 52.2,58.29 52.46,58.55 52.46,59.34 53.1,59.98 57.31,59.98 67.6,70.27 68.44,70.27 70.02,71.85 71.06,71.85 71.21,71.99 78.11,71.99 80.14,69.96 87.03,69.96 87.39,70.32 96.44,70.32 100.27,66.49 108.09,66.49 109.05,67.45 109.58,67.45 109.73,67.29 111.07,67.29 113.39,69.6 113.39,69.99 113.69,70.29 114.17,70.29 114.3,70.16 114.78,70.16 114.86,70.24 116.28,70.24 116.51,70.01 117.48,70.01 118.04,70.58 119.59,70.58 120.19,69.97 120.19,69.61 v2(120.63,69.18)
  BOTTOM w0.127: v2(120.63,69.18) 120.87,69.18 UCPU1.F55
DDI1_PTX_TBRX_P0_C: length 2.5
  TOP w0.076: UT1.AB7 47.56,58.29 47.64,58.29 47.71,58.21 48.69,58.21 48.91,58.43 48.97,58.43
  TOP w0.127: CT17.1 49.45,58.23 49.25,58.43 48.97,58.43
DDI1_PTX_TBRX_P1: length 77.7
  TOP w0.127: CT19.2 52.55,59.23 52.93,59.23 53.22,58.94 v2(53.28,58.94)
  IN2 w0.102: v2(118.84,69.14) 118.72,69.26 118.23,69.26 118.12,69.15 115.76,69.15 115.6,68.98 115.6,67.67 115.12,67.19 111.98,67.19 110.56,65.77 99.97,65.77 96.42,69.33 93.62,69.33 93.27,68.97 90.92,68.97 90.29,69.6 87.71,69.6 87.02,68.92 82.53,68.92 82.4,69.05 80.04,69.05 78.41,70.67 72.35,70.67 71.7,70.02 69.21,70.02 68.75,69.56 67.89,69.56 63.38,65.05 63.38,64.04 60.54,61.19 59.52,61.19 57.6,59.27 53.61,59.27 v2(53.28,58.94)
  BOTTOM w0.127: v2(118.84,69.14) 119.04,68.94 UCPU1.F58
DDI1_PTX_TBRX_P1_C: length 4.8
  TOP w0.076: UT1.AB9 47.63,59.15 48.18,59.15 48.2,59.12 48.63,59.12 48.66,59.09 48.67,59.09
  TOP w0.127: CT19.1 51.59,59.38 49.39,59.38 49.1,59.09 48.67,59.09
DDI1_PTX_TBRX_P2: length 85.7
  TOP w0.127: v2(50.75,60.03) 50.58,60.2 50.42,60.2 CT21.2
  IN2 w0.102: v2(121.57,68.54) 121.13,68.98 121.13,70.06 119.91,71.28 115.3,71.28 115.03,71.56 112.68,71.56 112.37,71.24 112.37,70.53 110.37,68.54 108.08,68.54 107.32,67.78 100,67.78 96.74,71.03 87.1,71.03 86.77,70.7 80.74,70.7 80.32,71.12 80.32,71.47 79.92,71.87 79.25,71.87 78.42,72.7 70.87,72.7 70.73,72.55 69.27,72.55 68.13,71.41 66.99,71.41 66.7,71.13 66.7,70.67 66.17,70.14 64.62,70.14 63.81,69.33 63.81,68.58 61.34,66.12 61.34,65.01 59.8,63.47 58.44,63.47 58.09,63.11 58.09,62.1 57.59,61.6 53.07,61.6 52.03,60.56 52.03,60.39 51.71,60.07 50.79,60.07 v2(50.75,60.03)
  BOTTOM w0.127: v2(121.57,68.54) 121.77,68.54 UCPU1.G53
DDI1_PTX_TBRX_P2_C: length 2.5
  TOP w0.076: 48.72,60.21 48.71,60.21 48.67,60.26 48.32,60.26 48.11,60.05 47.64,60.05 UT1.AB11
  TOP w0.127: CT21.1 49.43,60.21 48.72,60.21
DDI1_PTX_TBRX_P3: length 82
  TOP w0.127: CT23.2 52.56,60.95 52.69,60.95 52.84,60.8 53.33,60.8 v2(53.52,60.61)
  IN1 w0.091: v2(53.52,60.61) 53.72,60.81 55.77,60.82 59.33,57.26 59.99,57.26 v2(60.23,57.02)
  IN2 w0.102: v2(119.74,68.54) 119.74,68.34 119.56,68.16 119.36,68.16 119.11,67.91 117.91,67.91 117.33,67.32 116.36,67.32 115.88,66.84 115.88,66.6 115.28,66 114.78,66 114.66,66.13 113.28,66.13 112.85,65.69 111.48,65.69 110.8,65.01 108.19,65.01 107.57,64.39 105.34,64.39 104.72,65.01 99.71,65.01 96.52,68.21 82.14,68.21 82.01,68.34 79.73,68.34 78.11,69.96 74.09,69.96 72.22,68.09 67.41,68.09 64.08,64.76 64.08,63.74 62.07,61.72 62.07,58.22 61.05,57.2 60.41,57.2 v2(60.23,57.02)
  BOTTOM w0.127: v2(119.74,68.54) 119.9,68.54 120.15,68.29 UCPU1.G56
DDI1_PTX_TBRX_P3_C: length 4.8
  TOP w0.076: UT1.AB13 47.64,60.97 48.73,60.97 48.88,61.12 49.14,61.12 49.17,61.09 49.18,61.09
  TOP w0.127: 49.18,61.09 49.19,61.08 51.7,61.08 CT23.1
DDI2_PTX_TBRX_N0: length 95.5
  TOP w0.127: CT30.2 50.33,62.32 50.91,62.32 v2(51.01,62.42)
  IN2 w0.102: v2(51.01,62.42) 50.89,62.42 50.47,62.01 50.29,62.01 50.14,62.16 50.14,63.22 50.26,63.33 50.26,67.47 51.5,68.71 52.9,68.71 59.75,75.55 61.64,75.55 61.88,75.8 64.88,75.8 65.71,76.63 79.31,76.63 80.11,75.83 84.97,75.83 85.23,76.1 87.45,76.1 88.35,77 91.25,77 92.54,78.29 108.37,78.29 109.44,77.22 114.38,77.22 115.94,78.78 120.85,78.78 122.15,77.48 122.15,77.2 122.52,76.83 122.52,76.82 122.87,76.46 v2(122.87,76.45)
  BOTTOM w0.076: UCPU1.C50 123.64,71.01 123.52,70.9 123.52,70.74 123.62,70.64 123.98,70.64 124.12,70.79 124.12,71.07 124.04,71.22 124.04,71.42 124.07,71.49 124.07,71.82 arc(124.05,72.01) 124.09,72.2 arc(124.11,72.34) 124.06,72.48 arc(124,72.62) 123.98,72.78 123.98,73 123.98,73 123.98,73.02 123.99,73.09 123.99,73.1 124,73.17 124,75.79 123.96,75.84 123.96,75.86
  BOTTOM w0.127: v2(122.87,76.45) 123.21,76.79 123.39,76.79 123.96,76.22 123.96,75.86
DDI2_PTX_TBRX_N0_C: length 2.7
  TOP w0.076: UT1.AC15 47.72,62.13 47.65,62.2 47.65,62.32 47.7,62.37 48.03,62.37 48.34,62.05 48.66,62.05 48.69,62.08 48.71,62.08
  TOP w0.127: 48.71,62.08 48.99,62.08 49.03,62.12 49.35,62.12 CT30.1
DDI2_PTX_TBRX_N1: length 84.9
  TOP w0.127: CT32.2 52.44,63.62 52.65,63.41 53.28,63.41 53.49,63.62 v2(53.52,63.62)
  IN2 w0.102: v2(53.52,63.62) 53.71,63.43 53.8,63.43 54.09,63.72 54.09,66.26 55.07,67.24 57.97,67.24 59,68.27 59.21,68.27 63.28,72.34 63.93,72.34 64.67,73.08 67.45,73.08 68.59,74.23 70.08,74.23 70.2,74.35 79.14,74.35 79.74,73.75 82.42,73.75 83.01,73.16 89.42,73.16 90.24,73.97 91.23,73.97 91.84,73.36 96.79,73.36 99.63,70.52 106.22,70.52 108.26,72.55 110.74,72.55 112.17,73.97 113.82,73.97 114.43,74.58 120.74,74.58 121.19,75.04 121.43,75.04 v2(121.65,75.26)
  BOTTOM w0.076: UCPU1.C52 122.76,71.09 122.76,71.28 122.7,71.34 122.53,71.34 122.47,71.39 122.43,71.55 122.42,71.57 122.42,71.75 122.48,71.94 122.48,72.09 122.42,72.21 122.42,72.47 122.57,72.62
  BOTTOM w0.089: v2(121.65,75.26) 121.65,75.16 121.78,75.03 122.1,75.03 122.33,74.81 122.33,73.65 122.63,73.35 122.63,72.9 122.57,72.83 122.57,72.62
DDI2_PTX_TBRX_N1_C: length 4.8
  TOP w0.076: 48.83,63.01 48.82,63.01 48.78,62.97 48.28,62.97 48.17,63.07 48.17,63.16 48.06,63.28 47.83,63.28 47.78,63.23 47.78,63.13 UT1.AC17
  TOP w0.127: 48.83,63.01 48.88,63.05 50.91,63.05 51.23,63.37 51.65,63.37 51.84,63.56 CT32.1
DDI2_PTX_TBRX_N2: length 89.8
  TOP w0.127: v2(50.75,64.02) 50.61,63.88 50.42,63.88 CT34.2
  IN2 w0.102: v2(50.75,64.02) 50.95,63.81 51.65,63.81 51.75,63.92 51.75,64.81 55.04,68.09 57.9,68.09 58.92,69.11 59.16,69.11 63.02,72.97 63.64,72.97 64.39,73.72 67.17,73.72 68.32,74.86 69.77,74.86 70.51,75.59 78.83,75.59 80.05,74.38 82.7,74.38 83.26,73.82 89.09,73.82 90.06,74.79 98.67,74.79 102.27,71.18 105.51,71.18 107.56,73.23 109.86,73.23 110.52,73.89 110.52,74.52 110.91,74.91 113.55,74.91 115.76,77.12 120.24,77.12 120.59,76.76 120.87,76.76 v2(121.08,76.97)
  BOTTOM w0.076: 121.97,75.98 121.99,75.98 122.03,75.93 123.45,75.93 123.74,75.65 123.74,72.88 123.54,72.69 123.54,72.14 123.62,72.06 123.72,72.06 123.81,72.15 UCPU1.A50
  BOTTOM w0.127: 121.97,75.98 121.84,75.98 121.76,76.06 121.76,76.6 121.54,76.82 121.24,76.82 v2(121.08,76.97)
DDI2_PTX_TBRX_N2_C: length 2.5
  TOP w0.076: 48.69,64.07 48.68,64.07 48.63,64.01 48.24,64.01 48.06,64.19 47.75,64.19 47.68,64.12 47.68,64.04 47.75,63.97 UT1.AC19
  TOP w0.127: 48.69,64.07 49.05,64.07 49.24,63.88 49.46,63.88 CT34.1
DDI2_PTX_TBRX_N3: length 91.1
  TOP w0.127: CT36.2 50.43,65.16 50.68,65.16 v2(50.8,65.03)
  IN2 w0.102: v2(50.8,65.03) 50.98,65.22 51.58,65.22 52.98,66.61 52.98,66.61 55.89,69.52 57.3,69.52 58.36,70.58 58.64,70.58 59.29,71.24 59.29,72.29 60.38,73.38 63.42,73.38 66.05,76 79.02,76 79.83,75.2 82.75,75.2 83.71,74.23 88.21,74.23 89.64,75.67 91.11,75.67 91.28,75.5 92.62,75.5 92.9,75.78 98.27,75.78 102.41,71.64 105.33,71.64 107.41,73.71 108.22,73.71 109.37,74.86 109.37,75.68 110.19,76.49 114.54,76.49 115.59,77.53 121.13,77.53 121.52,77.14 121.52,76.03 122.1,75.45 122.1,75.23 122.36,74.97 122.61,74.97 v2(122.79,74.79)
  BOTTOM w0.076: UCPU1.D51 123.25,70.88 122.94,71.18 122.94,71.49 123.15,71.7 123.15,71.81 123,71.97 123,72.96 123.24,73.21 123.24,74.81 123.06,74.99 122.91,74.99 122.79,74.87 v2(122.79,74.79)
DDI2_PTX_TBRX_N3_C: length 2.7
  TOP w0.076: 48.81,65.16 48.8,65.16 48.75,65.21 48.67,65.21 48.4,64.94 48.32,64.94 48.03,64.65 47.7,64.65 47.65,64.7 47.65,64.8 47.73,64.89 UT1.AC21
  TOP w0.127: CT36.1 49.44,65.16 48.81,65.16
DDI2_PTX_TBRX_P0: length 95.6
  TOP w0.127: v2(50.83,61.78) 50.83,61.98 50.75,62.06 50.42,62.06 50.23,61.87 CT29.2
  IN2 w0.102: v2(122.86,77.05) 122.62,77.05 122.37,77.29 122.37,77.57 120.94,79 115.85,79 114.29,77.44 109.53,77.44 108.46,78.51 92.45,78.51 91.16,77.22 88.25,77.22 87.35,76.32 85.14,76.32 84.87,76.06 80.2,76.06 79.4,76.85 65.62,76.85 64.79,76.02 61.79,76.02 61.54,75.78 59.65,75.78 52.81,68.93 51.41,68.93 50.03,67.56 50.03,63.43 49.92,63.31 49.92,62.06 50.2,61.78 v2(50.83,61.78)
  BOTTOM w0.076: 124.21,75.86 124.21,75.84 124.17,75.79 124.17,73.16 124.16,73.08 124.16,73.07 124.16,73 124.15,73 124.15,72.78 arc(124.16,72.67) 124.21,72.56 arc(124.27,72.35) 124.24,72.14 arc(124.21,72) 124.23,71.87 124.23,71.84 124.23,71.46 124.21,71.39 124.21,71.26 124.29,71.11 124.29,70.72 124.05,70.48 123.93,70.48 UCPU1.D50
  BOTTOM w0.127: 124.21,75.86 124.21,76.32 123.49,77.04 122.87,77.04 v2(122.86,77.05)
DDI2_PTX_TBRX_P0_C: length 2.4
  TOP w0.076: UT1.AB15 47.58,61.95 47.58,61.94 47.64,61.89 48.65,61.89 48.7,61.83 48.71,61.83
  TOP w0.127: 48.71,61.83 49.1,61.83 49.18,61.91 49.52,61.91 CT29.1
DDI2_PTX_TBRX_P1: length 84.9
  TOP w0.127: CT31.2 52.59,63.15 53.36,63.15 53.4,63.12 53.4,63.12 v2(53.49,63.03)
  IN2 w0.102: v2(121.62,74.66) 121.47,74.81 121.28,74.81 120.83,74.36 114.52,74.36 113.91,73.75 112.26,73.75 110.84,72.33 108.35,72.33 106.32,70.3 99.54,70.3 96.7,73.14 91.75,73.14 91.14,73.75 90.33,73.75 89.51,72.93 82.92,72.93 82.33,73.52 79.65,73.52 79.05,74.13 70.29,74.13 70.17,74 68.69,74 67.54,72.86 64.76,72.86 64.02,72.12 63.37,72.12 59.3,68.05 59.1,68.05 58.06,67.01 55.16,67.01 54.32,66.17 54.32,63.63 53.9,63.21 53.68,63.21 v2(53.49,63.03)
  BOTTOM w0.076: UCPU1.D52 122.42,70.87 122.34,71.26 122.27,71.5 122.25,71.55 122.25,71.77 122.31,71.96 122.31,72.05 122.27,72.13 122.25,72.17 122.25,72.54 122.39,72.67 122.39,72.68
  BOTTOM w0.089: 122.39,72.68 122.39,72.91 122.45,72.97 122.45,73.28 122.15,73.58 122.15,74.74 122.03,74.85 121.82,74.85 v2(121.62,74.66)
DDI2_PTX_TBRX_P1_C: length 4.8
  TOP w0.076: 48.84,62.76 48.84,62.76 48.8,62.8 48.19,62.8 48.16,62.83 47.62,62.83 UT1.AB17
  TOP w0.127: 48.84,62.76 48.87,62.79 50.96,62.79 51.32,63.15 51.68,63.15 CT31.1
DDI2_PTX_TBRX_P2: length 89.8
  TOP w0.127: v2(50.75,63.43) 50.56,63.62 50.42,63.62 CT33.2
  IN2 w0.102: v2(50.75,63.43) 50.91,63.59 51.74,63.59 51.98,63.82 51.98,64.72 55.13,67.87 57.99,67.87 59.01,68.89 59.25,68.89 63.11,72.75 63.73,72.75 64.48,73.5 67.26,73.5 68.41,74.64 69.87,74.64 70.6,75.37 78.74,75.37 79.95,74.16 82.61,74.16 83.17,73.59 89.18,73.59 90.15,74.56 98.57,74.56 102.18,70.96 105.6,70.96 107.66,73.01 109.96,73.01 110.74,73.8 110.74,74.43 111,74.69 113.65,74.69 115.85,76.89 120.14,76.89 120.5,76.54 120.88,76.54 v2(121.08,76.34)
  BOTTOM w0.076: UCPU1.B50 123.81,71.78 123.69,71.9 123.55,71.9 123.38,72.07 123.38,72.76 123.57,72.95 123.57,75.58 123.39,75.77 122.03,75.77 121.99,75.72 121.97,75.72
  BOTTOM w0.127: v2(121.08,76.34) 121.31,76.56 121.43,76.56 121.5,76.49 121.5,75.95 121.74,75.72 121.97,75.72
DDI2_PTX_TBRX_P2_C: length 2.6
  TOP w0.076: 48.69,63.82 48.68,63.82 48.65,63.85 48.18,63.85 48.06,63.72 47.65,63.72 47.54,63.83 UT1.AB19
  TOP w0.127: CT33.1 49.45,63.63 49.14,63.63 48.95,63.82 48.69,63.82
DDI2_PTX_TBRX_P3: length 91.3
  TOP w0.127: v2(50.8,65.62) 50.59,65.41 50.41,65.41 CT35.2
  IN2 w0.102: v2(50.8,65.62) 50.98,65.44 51.49,65.44 52.89,66.84 55.8,69.74 57.21,69.74 58.27,70.81 58.54,70.81 59.07,71.33 59.07,72.39 60.28,73.6 63.33,73.6 65.95,76.22 79.12,76.22 79.92,75.42 82.84,75.42 83.81,74.46 88.11,74.46 89.55,75.89 91.2,75.89 91.37,75.72 92.53,75.72 92.81,76 98.37,76 102.51,71.86 105.24,71.86 107.32,73.93 108.13,73.93 109.15,74.96 109.15,75.77 110.09,76.71 114.45,76.71 115.49,77.75 121.23,77.75 121.74,77.24 121.74,76.12 122.33,75.54 122.33,75.32 122.45,75.19 122.6,75.19 v2(122.79,75.39)
  BOTTOM w0.076: v2(122.79,75.39) 123.02,75.15 123.13,75.15 123.41,74.88 123.41,73.14 123.16,72.89 123.16,72.04 123.32,71.88 123.32,71.71 123.55,71.47 123.55,71.21 123.45,71.11 123.3,71.11 123.25,71.16 UCPU1.C51
DDI2_PTX_TBRX_P3_C: length 2.5
  TOP w0.076: 48.81,65.42 48.8,65.42 48.75,65.37 48.6,65.37 48.33,65.11 47.63,65.11 UT1.AB21
  TOP w0.127: 48.81,65.42 49.47,65.42 CT35.1
DDR_A0_ZQ0: length 4.4
  TOP w0.127: UD19.B3 99.91,24.73 99.45,24.73 99.16,24.44 99.16,23.83 v3(98.25,22.92) 98.17,22.84 RD51.1
DDR_A0_ZQ1: length 3.9
  TOP w0.127: UD19.B4 100.27,25.96 99.93,26.3 98.91,26.3 v3(98.16,25.55) 97.35,24.74 RD53.1
DDR_A1_ZQ0: length 6.5
  TOP w0.127: UD20.B3 115.34,24.65 114.92,24.65 114.77,24.49 114.77,23.04 116.43,21.38 v3(116.43,21.24) 116.43,20.53 RD52.1
DDR_A1_ZQ1: length 7.7
  TOP w0.127: UD20.B4 115.42,26.27 114.81,26.27 114.76,26.23 114.76,24.89 114.45,24.58 114.45,22.68 114.68,22.45 v3(114.68,21.37) 114.68,20.63 RD54.1
DDR_A_CA1_0: length 44.6
  TOP w0.142: UD19.R2 108.72,24.3 108.41,23.99 108.41,23.64 109.76,22.29 109.76,21.53 110.24,21.05 v2(110.69,21.05) 111.48,20.26 RD59.1
  IN2 w0.102: v2(121.08,43.29) 120.66,42.87 120.66,39.47 120.13,38.94 119.99,38.94 119.65,39.28 119.51,39.28 119.36,39.13 119.36,38.99 119.7,38.65 119.7,38.51 119.56,38.36 119.41,38.36 119.07,38.7 118.93,38.7 118.79,38.56 118.79,38.41 119.13,38.07 119.13,37.93 118.98,37.79 118.84,37.79 118.5,38.13 118.36,38.13 118.21,37.98 118.21,37.84 118.55,37.5 118.55,37.36 116.05,34.86 116.05,32.47 115.65,32.07 115.65,30.88 115.96,30.57 115.96,29.01 115.79,28.83 115.79,28.42 115.45,28.09 114.93,28.09 114.15,27.3 114.15,24.62 110.72,21.19 110.69,21.19 v2(110.69,21.05)
  BOTTOM w0.076: UCPU1.BA51 122.99,50.44 122.99,50.21 122.99,50.2 122.99,50.2 122.99,50.2 122.95,50.11 122.95,49.91 122.99,49.82 122.99,49.46 122.73,49.21 122.73,44.94 v2(121.08,43.29)
DDR_A_CA1_1: length 45.4
  TOP w0.142: UD19.P2 108.11,24.26 108.11,23.14 109.1,22.14 v2(109.1,21.38) 109.4,21.08 109.72,21.08 110.59,20.21 RD61.1
  IN2 w0.102: v2(109.1,21.38) 109.86,21.38 110.33,21.85 110.41,21.85 110.88,22.32 110.88,22.47 110.68,22.67 110.68,22.82 110.82,22.96 110.96,22.96 111.17,22.75 111.32,22.75 112.81,24.25 112.81,27.13 113.98,28.3 113.98,31.86 114.08,31.96 114.59,31.96 114.7,32.07 114.7,32.27 114.59,32.37 114.08,32.37 113.98,32.47 113.98,32.72 114.09,32.83 114.61,32.83 115.47,33.69 115.47,34.62 115.37,34.72 114.91,34.72 114.81,34.82 114.81,35.02 114.91,35.13 115.37,35.13 115.47,35.23 115.47,36.08 115.7,36.31 115.84,36.31 116.16,35.99 116.3,35.99 116.45,36.14 116.45,36.28 116.13,36.6 116.13,36.74 116.27,36.88 116.42,36.88 116.73,36.57 116.88,36.57 117.02,36.71 117.02,36.85 116.7,37.17 116.7,37.32 119.76,40.37 119.76,41.18 119.91,41.34 v2(119.91,41.39)
  BOTTOM w0.076: UCPU1.BB54 121.63,49.58 121.63,49.2 121.72,49.11 121.72,47.3 119.41,44.99 v3(119.41,44.08) 119.41,41.89 v2(119.91,41.39)
DDR_A_CA1_2: length 46.5
  TOP w0.142: UD19.N2 107.42,24.3 107.42,23.63 107.32,23.53 107.32,22.15 107.7,21.77 v2(107.7,21.41) 108.19,20.92 108.3,20.92 108.81,20.41 RD63.1
  IN2 w0.102: v2(119.89,42.63) 119.62,42.63 119.47,42.48 119.47,40.49 114.49,35.51 114.49,34.82 114.42,34.75 113.78,34.75 113.65,34.62 113.65,34.44 113.75,34.34 115.06,34.34 115.17,34.22 115.17,34.06 115.06,33.94 113.75,33.94 113.65,33.83 113.65,33.63 113.75,33.53 114.51,33.53 114.63,33.41 114.63,33.26 114.49,33.12 113.75,33.12 113.65,33.02 113.65,28.43 112.48,27.26 112.48,24.41 111.37,23.31 110.22,23.31 109.89,22.97 109.89,22.2 109.69,22.01 108.3,22.01 v2(107.7,21.41)
  BOTTOM w0.076: UCPU1.BA52 122.55,50.11 122.29,49.85 122.29,49.48 122.38,49.39 122.38,46.28 120.68,44.57 120.68,43.42 v2(119.89,42.63)
DDR_A_CA1_3: length 46.1
  TOP w0.076: 107.73,23.72 107.73,24.79 UD19.N3
  TOP w0.142: RD65.1 109.7,20.5 109.51,20.7 109.12,20.7 v2(108.44,21.38) 108.44,22.22 107.73,22.93 107.73,23.72
  IN2 w0.102: v2(108.44,21.38) 108.9,20.93 109.87,20.93 110.47,21.52 110.57,21.52 113.16,24.11 113.16,27.01 114.3,28.15 114.3,29.37 114.4,29.47 114.81,29.47 114.91,29.57 114.91,29.77 114.81,29.87 114.4,29.87 114.4,29.89 114.27,30.03 114.27,31.16 114.99,31.89 114.99,32.8 115.76,33.57 115.76,35.57 115.87,35.68 116.46,35.68 117.48,36.71 117.48,36.85 117.14,37.19 117.14,37.34 117.29,37.48 117.43,37.48 117.77,37.14 117.92,37.14 118.06,37.28 118.06,37.42 117.72,37.77 117.72,37.91 120.37,40.56 120.37,43.75 v2(121.08,44.46)
  BOTTOM w0.076: UCPU1.AY52 122.65,50.72 122.75,50.62 122.82,50.43 122.82,50.23 122.79,50.14 122.79,49.89 122.79,49.88 122.82,49.79 122.82,49.53 122.56,49.26 122.56,45.93 v3(121.87,45.24) v2(121.08,44.46)
DDR_A_CA1_4: length 48.2
  TOP w0.076: UD19.M3 107.09,24.78 107.09,24.05 106.92,23.87
  TOP w0.142: RD67.1 107.93,20.54 107.61,20.85 107.47,20.85 v2(106.89,21.43) 106.89,21.76 106.76,21.89 106.76,23.71 106.92,23.87
  IN2 w0.102: v2(106.89,21.43) 106.45,21.43 106.32,21.56 106.32,21.84 106.45,21.96 107.09,21.96 107.26,22.13 107.4,22.13 107.64,21.89 107.77,21.89 107.93,22.04 107.93,22.18 107.69,22.42 107.69,22.56 107.91,22.79 108.14,22.79 108.24,22.68 108.24,22.4 108.34,22.3 108.42,22.3 108.55,22.3 108.65,22.4 108.65,22.68 108.75,22.79 109.02,22.79 109.11,22.69 109.11,22.4 109.21,22.3 109.49,22.3 109.59,22.4 109.59,23.09 110.1,23.6 111.2,23.6 112.15,24.55 112.15,27.4 113.32,28.57 113.32,34.76 119.18,40.61 119.18,43.23 119.31,43.37 119.74,43.37 v2(119.89,43.21)
  BOTTOM w0.076: v2(119.89,43.21) 120.37,43.7 120.37,44.51 122.21,46.35 122.21,49.32 122.12,49.41 122.12,50.37 122.33,50.58 122.33,51.2 122.65,51.52 UCPU1.AW52
DDR_A_CA1_5: length 50.6
  TOP w0.076: v2(103.52,23.74) 103.21,24.06 103.21,24.76 UD19.F3
  TOP w0.142: RD69.1 100.38,20.98 101.14,21.74 102.06,21.74 103.52,23.2 v2(103.52,23.74)
  IN2 w0.102: v2(118.09,42.25) 117.33,42.25 115.87,40.79 115.87,40.64 116.54,39.97 116.54,39.83 116.39,39.69 116.25,39.69 115.58,40.36 115.43,40.36 115.29,40.21 115.29,40.07 115.96,39.4 115.96,39.26 115.82,39.11 115.67,39.11 115.25,39.53 115.08,39.53 114.96,39.42 114.96,39.25 115.39,38.82 115.39,38.68 112,35.29 112,29.12 110.83,27.95 110.83,25.11 110.48,24.77 108.12,24.77 106.63,23.27 104,23.27 v2(103.52,23.74)
  BOTTOM w0.076: UCPU1.AY55 120.76,51.21 121.06,50.92 121.13,50.76 121.13,50.58 121.08,50.42 121.08,50.27 121.14,50.06 121.14,49.94 121.11,49.86 121.09,49.83 121.09,49.46 121.3,49.26 121.3,49.06 121.39,48.98 121.39,47.79 v3(121.08,47.48) 120.83,47.23 120.83,47 118.87,45.04 118.87,43.04 v2(118.09,42.25)
DDR_A_CA1_6: length 49.9
  TOP w0.076: UD19.E3 101.89,24.76 101.89,23.9
  TOP w0.142: 101.89,23.9 101.78,23.8 v2(101.78,22.86) 101.33,22.4 100.18,22.4 98.6,20.82 RD71.1
  IN2 w0.102: v2(119.91,44.38) 118.85,43.32 118.85,40.72 112.99,34.86 112.99,28.71 111.82,27.54 111.82,24.68 111.02,23.89 109.98,23.89 109.17,23.08 107.79,23.08 106.97,22.25 102.28,22.25 101.78,22.75 v2(101.78,22.86)
  BOTTOM w0.076: UCPU1.AW54 121.43,51.42 121.74,51.11 121.74,50.56 121.96,50.34 121.96,49.34 122.05,49.25 122.05,46.74 v3(120.56,45.25) 120.31,45 120.31,44.78 v2(119.91,44.38)
DDR_A_CA1_7: length 48.7
  TOP w0.142: RD73.1 99.49,21.24 100.32,22.07 101.72,22.07 102.37,22.72 v2(102.37,22.86) 102.22,23 102.22,24.3 UD19.E2
  IN2 w0.102: v2(102.37,22.86) 102.64,22.58 106.89,22.58 107.67,23.37 107.94,23.37 108.08,23.5 108.08,23.78 108.19,23.88 108.36,23.88 108.48,23.76 108.48,23.5 108.61,23.37 109.05,23.37 109.86,24.18 110.85,24.18 111.49,24.82 111.49,27.67 112.66,28.85 112.66,35.01 118.27,40.62 118.28,40.62 118.52,40.86 118.52,44.59 118.64,44.71 118.82,44.71 118.95,44.59 118.95,44.18 119.05,44.08 119.18,44.08 119.38,44.28 119.38,44.7 119.65,44.97 v2(119.89,44.97)
  BOTTOM w0.076: v2(119.89,44.97) 120.2,45.27 120.2,45.41 121.88,47.09 121.88,49.18 121.79,49.27 121.79,49.86 121.53,50.12 UCPU1.BA54
DDR_A_CA1_8: length 49.2
  TOP w0.142: RD75.1 97.71,20.44 100,22.74 101.11,22.74 101.33,22.96 101.33,23.74 v2(101.23,23.85) 101.23,23.95 UD19.D2
  IN2 w0.102: v2(101.23,23.85) 101.56,23.85 101.97,24.25 107.08,24.25 107.89,25.06 109.43,25.06 109.92,25.55 109.92,27.51 111.67,29.26 111.67,35.39 114.3,38.01 114.3,38.16 113.63,38.82 113.63,38.97 113.78,39.11 113.92,39.11 114.58,38.44 114.73,38.44 114.87,38.59 114.87,38.73 114.21,39.4 114.21,39.54 117.52,42.86 v2(118.06,42.86)
  BOTTOM w0.076: v2(118.06,42.86) 118.69,43.49 118.69,45.1 120.63,47.03 120.63,47.58 120.85,47.81 120.9,47.81 121.21,48.12 121.21,48.48 120.99,48.7 120.74,48.7 120.49,48.95 120.49,49.27 120.63,49.41 120.63,49.82 120.58,49.96 120.58,50.06 120.63,50.19 120.63,50.43 UCPU1.BA55
DDR_A_CA1_9: length 51
  TOP w0.142: RD77.1 96.82,20.68 99.23,23.09 100.69,23.09 v2(100.87,23.26) 100.81,23.32 100.81,24.19 UD19.C2
  IN2 w0.102: v2(100.87,23.26) 100.92,23.31 102.73,23.31 103.13,22.91 106.8,22.91 108.36,24.48 110.67,24.48 111.16,24.96 111.16,27.81 112.33,28.98 112.33,35.21 117.08,39.96 117.08,40.1 116.41,40.77 116.41,40.92 116.55,41.06 116.69,41.06 117.36,40.39 117.51,40.39 117.65,40.53 117.65,40.68 117.44,40.89 117.44,41.35 117.75,41.66 v2(118.11,41.66)
  BOTTOM w0.076: UCPU1.AY54 121.33,50.88 121.33,50.63 121.25,50.41 121.25,50.28 121.31,50.05 121.31,49.91 121.26,49.79 121.26,49.53 121.46,49.33 121.46,49.13 121.55,49.04 121.55,47.42 119.04,44.91 119.04,42.59 v3(118.67,42.22) v2(118.11,41.66)
DDR_A_CA2_0: length 47.5
  TOP w0.127: v2(124.44,22.92) 124.24,23.12 124.24,24.3 UD20.R2
  TOP w0.142: RD79.1 127.88,20.89 127.74,20.89 v3(126.83,21.81) 125.77,22.87 124.49,22.87 v2(124.44,22.92)
  IN1 w0.117: v2(124.44,22.92) 124.92,23.4 125.42,23.4 125.58,23.24 125.75,23.24 125.91,23.41 125.91,23.57 125.32,24.17 125.32,24.33 125.51,24.53 125.67,24.53 126.21,23.99 126.5,23.99 127.95,25.44 127.95,35.45 127.64,35.76 127.47,35.76 127.28,35.57 127.12,35.57 126.95,35.74 126.95,35.9 127.14,36.1 127.14,36.26 126.98,36.43 126.81,36.43 126.62,36.23 126.45,36.23 126.29,36.4 126.29,36.56 126.48,36.76 126.48,36.92 126.32,37.09 126.15,37.09 125.96,36.89 125.79,36.89 125.63,37.06 125.63,37.22 125.82,37.42 125.82,37.58 125.65,37.75 125.49,37.75 125.3,37.56 125.13,37.56 124.97,37.72 124.97,37.89 125.16,38.08 125.16,38.25 124.99,38.41 124.83,38.41 124.63,38.22 124.47,38.22 124.3,38.38 124.3,38.55 124.5,38.74 124.5,38.91 124.14,39.27 124.14,50.53 124.31,50.71 124.67,50.71 124.91,50.94 124.91,51.3 125.08,51.48 125.45,51.48 125.62,51.65 125.62,52.29 125.44,52.47 v2(125.25,52.47)
  BOTTOM w0.076: UCPU1.AU46 125.58,52.8 v2(125.25,52.47)
DDR_A_CA2_1: length 44.9
  TOP w0.142: RD81.1 127.74,20.33 125.58,22.49 124.18,22.49 v2(123.75,22.92) 123.75,24.14 UD20.P2
  IN2 w0.102: v2(124.32,52.47) 124.31,52.47 124.21,52.37 124.21,51.95 124,51.75 124,51.27 124.12,51.15 124.12,39 127.79,35.33 127.79,28.6 127.69,28.5 127.36,28.5 127.25,28.4 127.25,28.19 127.36,28.09 127.95,28.09 128.07,27.97 128.07,27.8 127.95,27.69 127.36,27.69 127.25,27.58 127.25,27.38 127.36,27.28 127.95,27.28 128.07,27.16 128.07,26.99 127.95,26.87 127.36,26.87 127.25,26.77 127.25,26.57 127.36,26.47 127.69,26.47 127.79,26.36 127.79,25.59 124.69,22.49 124.18,22.49 v2(123.75,22.92)
  BOTTOM w0.076: UCPU1.AU48 124.66,52.8 v2(124.32,52.47)
DDR_A_CA2_2: length 44.7
  TOP w0.127: UD20.N2 122.89,24.24 122.89,23.52 v2(122.78,23.41)
  TOP w0.142: RD83.1 125.96,20.9 125.18,21.67 123.82,21.67 122.73,22.76 122.73,23.36 v2(122.78,23.41)
  IN1 w0.117: v2(122.78,23.41) 122.69,23.41 122.75,23.35 123.9,23.35 125.38,24.83 126.91,24.83 127.3,25.22 127.3,26.82 127.19,26.94 126.71,26.94 126.59,27.06 126.59,27.29 126.71,27.41 127.19,27.41 127.3,27.52 127.3,27.76 127.19,27.87 126.71,27.87 126.59,27.99 126.59,28.23 126.71,28.34 127.19,28.34 127.3,28.46 127.3,34.83 123.83,38.31 123.83,51.48 124.33,51.99 124.45,51.99 124.82,52.36 124.82,52.67 v2(125.25,53.1)
  BOTTOM w0.076: v2(125.25,53.1) 125.6,53.45 UCPU1.AT46
DDR_A_CA2_3: length 44.9
  TOP w0.076: UD20.N3 123.27,24.77 123.27,23.94
  TOP w0.142: 123.27,23.94 v2(123.27,23.78) 123.19,23.71 123.19,22.77 123.96,22 125.41,22 126.85,20.56 RD85.1
  IN2 w0.102: v2(123.27,23.78) 123.41,23.64 123.82,23.64 123.92,23.75 123.92,23.85 124.02,23.95 124.22,23.95 124.32,23.85 124.93,23.85 126.6,25.52 126.6,27.6 126.5,27.7 126.09,27.7 125.98,27.8 125.98,28.01 126.09,28.11 126.5,28.11 126.6,28.21 126.6,28.41 126.5,28.52 126.09,28.52 125.98,28.62 125.98,28.82 126.09,28.92 126.5,28.92 126.6,29.02 126.6,31.85 126.5,31.95 126.16,31.95 126.06,32.05 126.06,32.25 126.16,32.36 126.5,32.36 126.6,32.46 126.6,32.66 126.5,32.76 126.16,32.76 126.06,32.86 126.06,33.07 126.16,33.17 126.5,33.17 126.6,33.27 126.6,35.59 123.46,38.73 123.46,48.05 122.73,48.78 122.73,49.43 122.83,49.53 122.83,51.91 v2(123.4,52.47)
  BOTTOM w0.076: UCPU1.AU50 123.73,52.8 v2(123.4,52.47)
DDR_A_CA2_4: length 42.7
  TOP w0.076: 122.28,23.83 122.61,24.16 122.61,24.78 UD20.M3
  TOP w0.142: RD87.1 125.07,20.97 124.7,21.34 123.68,21.34 122.23,22.8 122.23,23.78 122.28,23.83 v2(122.28,23.76)
  IN2 w0.102: v2(122.42,52.47) 122.5,52.39 122.5,49.67 122.4,49.56 122.4,48.64 123.13,47.91 123.13,38.59 125.64,36.08 125.64,35.64 125.74,35.53 126.19,35.53 126.29,35.43 126.29,35.23 126.19,35.13 125.74,35.13 125.64,35.03 125.64,34.82 125.74,34.72 126.19,34.72 126.29,34.62 126.29,34.42 126.19,34.32 125.74,34.32 125.64,34.21 125.64,28.2 125.16,27.73 125.16,24.5 124.91,24.24 122.71,24.24 122.28,23.81 v2(122.28,23.76)
  BOTTOM w0.076: v2(122.42,52.47) 122.75,52.8 UCPU1.AU52
DDR_A_CA2_5: length 44
  TOP w0.076: 118.81,23.46 118.7,23.57 118.7,24.68 v2(118.72,24.7)
  TOP w0.142: 118.81,23.46 118.81,22.68 120.63,20.86 RD89.1 ; UD20.F3 118.39,25.03 v2(118.72,24.7)
  IN2 w0.102: v2(118.72,24.7) 118.9,24.89 118.9,27.43 119.47,28 119.47,29.69 120.51,30.73 120.51,32.04 121.16,32.69 121.16,33.92 121.03,34.04 119.98,34.04 119.85,34.17 119.85,34.94 119.98,35.07 120.29,35.07 120.39,34.97 120.39,34.63 120.49,34.53 120.7,34.53 120.8,34.63 120.8,34.97 120.9,35.07 121.1,35.07 121.2,34.97 121.2,34.63 121.31,34.53 121.51,34.53 121.61,34.63 121.61,34.97 121.71,35.07 122.07,35.07 122.2,35.19 122.2,35.38 122.07,35.51 121.46,35.51 121.36,35.61 121.36,35.81 121.46,35.91 122.2,35.91 122.3,36.02 122.3,36.22 122.2,36.32 121.46,36.32 121.36,36.42 121.36,36.63 121.46,36.73 121.81,36.73 121.91,36.83 121.91,41.84 121.62,42.13 121.62,42.4 121.91,42.69 121.91,42.9 121.82,42.99 121.41,42.99 v2(121.08,42.66)
  BOTTOM w0.076: UCPU1.AY51 123.49,51.08 123.49,50.58 123.43,50.42 123.43,50.27 123.49,50.06 123.49,49.94 123.45,49.83 123.45,49.46 123.6,49.31 123.6,48.75 123.34,48.5 v3(123.34,46.36) 123.34,44.92 v2(121.08,42.66)
DDR_A_CA2_6: length 46.8
  TOP w0.076: v2(118.07,24.7) 118.07,24.18 117.86,23.97 117.86,23.74
  TOP w0.142: RD91.1 v3(119.74,21.12) 119.74,21.28 117.86,23.16 117.86,23.74 117.86,23.74 ; UD20.E3 117.74,25.03 v2(118.07,24.7)
  IN2 w0.102: v2(118.07,24.7) 118.54,24.23 119.21,24.23 120.14,23.31 120.31,23.31 121.03,22.59 122.2,22.59 122.61,23 123.22,23 123.57,23.35 124.84,23.35 126.89,25.4 126.89,35.76 123.79,38.86 123.79,51.01 123.67,51.13 123.67,52.1 123.83,52.26 123.83,52.71 124.22,53.1 v2(124.32,53.1)
  BOTTOM w0.076: v2(124.32,53.1) 124.67,53.45 UCPU1.AT48
DDR_A_CA2_7: length 45
  TOP w0.142: RD93.1 118.95,20.25 118.95,21.6 117.28,23.27 v2(117.28,23.74) 117.74,24.21 UD20.E2
  IN1 w0.117: v2(123.39,53.07) 123.83,52.64 123.83,52.28 123.11,51.57 123.11,49.67 122.81,49.36 122.81,48.85 123.52,48.14 123.52,38.18 127,34.71 127,29.29 125.22,27.52 118.95,27.52 118.62,27.19 118.62,26.25 117.28,24.91 v2(117.28,23.74)
  BOTTOM w0.076: v2(123.39,53.07) 123.78,53.45 UCPU1.AT50
DDR_A_CA2_8: length 43.2
  TOP w0.076: 116.87,23.45 116.87,24.07 UD20.D2
  TOP w0.142: UD20.D2 117.09,24.38 v2(116.77,24.7) ; RD95.1 117.93,22.15 116.87,23.21 116.87,23.45
  IN2 w0.102: v2(116.77,24.7) 116.17,24.1 115.5,24.1 115.01,24.59 115.01,27.42 115.23,27.64 116.33,27.64 117.19,28.5 117.19,31.65 117.68,32.14 117.68,32.97 117.78,33.07 118.23,33.07 118.34,33.17 118.34,33.37 118.23,33.47 117.78,33.47 117.68,33.58 117.68,33.78 117.78,33.88 118.23,33.88 118.34,33.98 118.34,34.19 118.23,34.29 117.78,34.29 117.68,34.39 117.68,35.14 118,35.46 118,35.6 117.68,35.92 117.68,36.06 117.83,36.2 117.97,36.2 118.28,35.89 118.43,35.89 118.55,36.01 118.55,36.15 118.26,36.44 118.26,36.6 118.38,36.72 118.55,36.72 118.83,36.44 118.98,36.44 119.12,36.58 119.12,36.73 118.84,37.01 118.84,37.18 118.96,37.3 119.13,37.3 119.41,37.01 119.55,37.01 119.7,37.16 119.7,37.3 119.56,37.44 119.56,37.58 119.71,37.72 119.85,37.72 119.99,37.59 120.13,37.59 120.27,37.73 120.27,37.88 120.14,38.01 120.14,38.18 120.26,38.3 120.43,38.3 120.56,38.16 120.7,38.16 121.13,38.59 121.13,40.85 v2(121.08,40.9)
  BOTTOM w0.076: v2(121.08,40.9) v3(121.77,41.59) 123.96,43.78 123.96,49.61 UCPU1.BB50
DDR_A_CA2_9: length 40.2
  TOP w0.142: UD20.C2 116.44,23.79 v2(116.32,23.66) 116.32,23.29 117.04,22.57 RD97.1
  IN2 w0.102: v2(116.32,23.66) 116.56,23.66 117.58,24.67 117.58,25.1 118.52,26.05 118.52,27.75 119.14,28.37 119.14,30.83 119.56,31.25 119.56,34.66 119.46,34.76 118.46,34.76 118.34,34.88 118.34,35.05 118.46,35.17 119.46,35.17 119.56,35.27 119.56,35.42 119.7,35.56 119.7,35.7 119.46,35.94 119.46,36.08 119.6,36.22 119.75,36.22 119.99,35.99 120.13,35.99 120.97,36.83 120.97,36.98 120.52,37.43 120.52,37.57 120.67,37.71 120.81,37.71 121.26,37.26 121.4,37.26 121.58,37.44 121.58,41.67 121.18,42.07 v2(121.08,42.07)
  BOTTOM w0.076: UCPU1.AY50 123.88,50.83 123.68,50.63 123.61,50.41 123.61,50.28 123.67,50.05 123.67,49.91 123.66,49.88 123.65,49.87 123.61,49.79 123.61,49.53 123.79,49.35 123.79,44.78 v3(122.58,43.57) v2(121.08,42.07)
DDR_A_CKE0: length 59.4
  TOP w0.076: 105.87,23.52 105.87,23.9 105.8,23.98 v2(105.8,24.7)
  TOP w0.142: UD19.K3 105.47,25.03 v2(105.8,24.7) ; 105.87,23.52 106.3,23.09 106.3,21.37 107.04,20.63 RD103.1
  IN2 w0.102: v2(105.8,24.7) 106.15,25.05 107.31,25.05 108.16,25.91 108.48,25.91 108.48,25.9 109.27,25.9 109.51,26.15 109.51,27.68 110.16,28.32 110.16,29.93 111.14,30.91 111.14,33.41 110.71,33.84 109.47,33.84 109.37,33.94 109.37,34.15 109.47,34.25 110.69,34.25 110.8,34.35 110.8,34.55 110.69,34.65 108.86,34.65 108.76,34.76 108.76,34.96 108.86,35.06 110.59,35.06 110.69,35.16 110.69,35.37 110.59,35.47 108.86,35.47 108.76,35.57 108.76,35.77 108.86,35.87 111.4,35.87 111.51,35.98 111.51,36.18 111.4,36.28 110.19,36.28 110.08,36.38 110.08,36.58 110.19,36.69 111.79,36.69 111.91,36.81 111.91,36.97 111.79,37.09 109.39,37.09 109.27,37.21 109.27,37.38 109.39,37.5 111.59,37.5 117.29,43.19 117.29,47.41 117.46,47.58 118.81,47.58 119.45,46.95 v2(119.61,46.95)
  BOTTOM w0.076: UCPU1.BA56 120.2,50.19 120.06,50.04 120.06,50.04 120.05,50.04 119.93,49.79 119.93,49.79 119.93,48.81 120.19,48.55 120.19,47.75 119.61,47.17 v2(119.61,46.95)
DDR_A_CKE1: length 63.7
  TOP w0.142: UD19.K4 105.47,25.98 v2(105.8,26.3) ; v2(103.45,21.29) 103.04,20.88 RD105.1
  IN2 w0.102: v2(105.8,26.3) 106.2,26.71 106.79,26.71 106.8,26.7 107.27,26.7 107.28,26.69 107.56,26.69 107.57,26.68 107.58,26.69 107.92,26.69 107.93,26.69 107.93,26.69 108.19,26.69 108.36,26.87 108.36,27.76 107.77,28.35 107.77,28.71 108.56,29.5 108.56,29.8 109.25,30.49 109.7,30.49 110.18,30.97 110.18,33.34 109.98,33.54 109.27,33.54 108.86,33.94 107.24,33.94 107.14,34.04 107.14,34.25 107.24,34.35 108.26,34.35 108.36,34.45 108.36,34.71 108.26,34.81 106.75,34.81 106.63,34.93 106.63,35.1 106.75,35.22 108.26,35.22 108.36,35.32 108.36,35.52 108.26,35.62 107.24,35.62 107.14,35.72 107.14,35.93 107.24,36.03 108.26,36.03 108.36,36.13 108.36,36.33 108.26,36.43 107.24,36.43 107.14,36.54 107.14,36.74 107.24,36.84 108.44,36.84 108.56,36.96 108.56,37.13 108.44,37.25 106.55,37.25 106.43,37.37 106.43,37.53 106.55,37.65 108.26,37.65 108.36,37.76 108.36,38.21 108.46,38.31 108.73,38.31 108.83,38.21 108.83,37.8 108.93,37.7 109.13,37.7 109.24,37.8 109.24,38.21 109.34,38.31 111.94,38.31 116.99,43.36 116.99,47.53 117.35,47.89 118.92,47.89 119.46,47.35 119.99,47.35 v2(120.16,47.19)
  BOTTOM w0.076: UCPU1.BB56 120.16,49.65 120.16,48.81 120.37,48.6 120.37,47.4 v2(120.16,47.19)
  BOTTOM w0.142: v2(105.8,26.3) 104.54,26.3 104.04,26.81 103.63,26.81 103.07,26.25 103.07,26.04 102.64,25.61 v3(102.64,24.57) 103.07,24.14 103.07,21.68 v2(103.45,21.29)
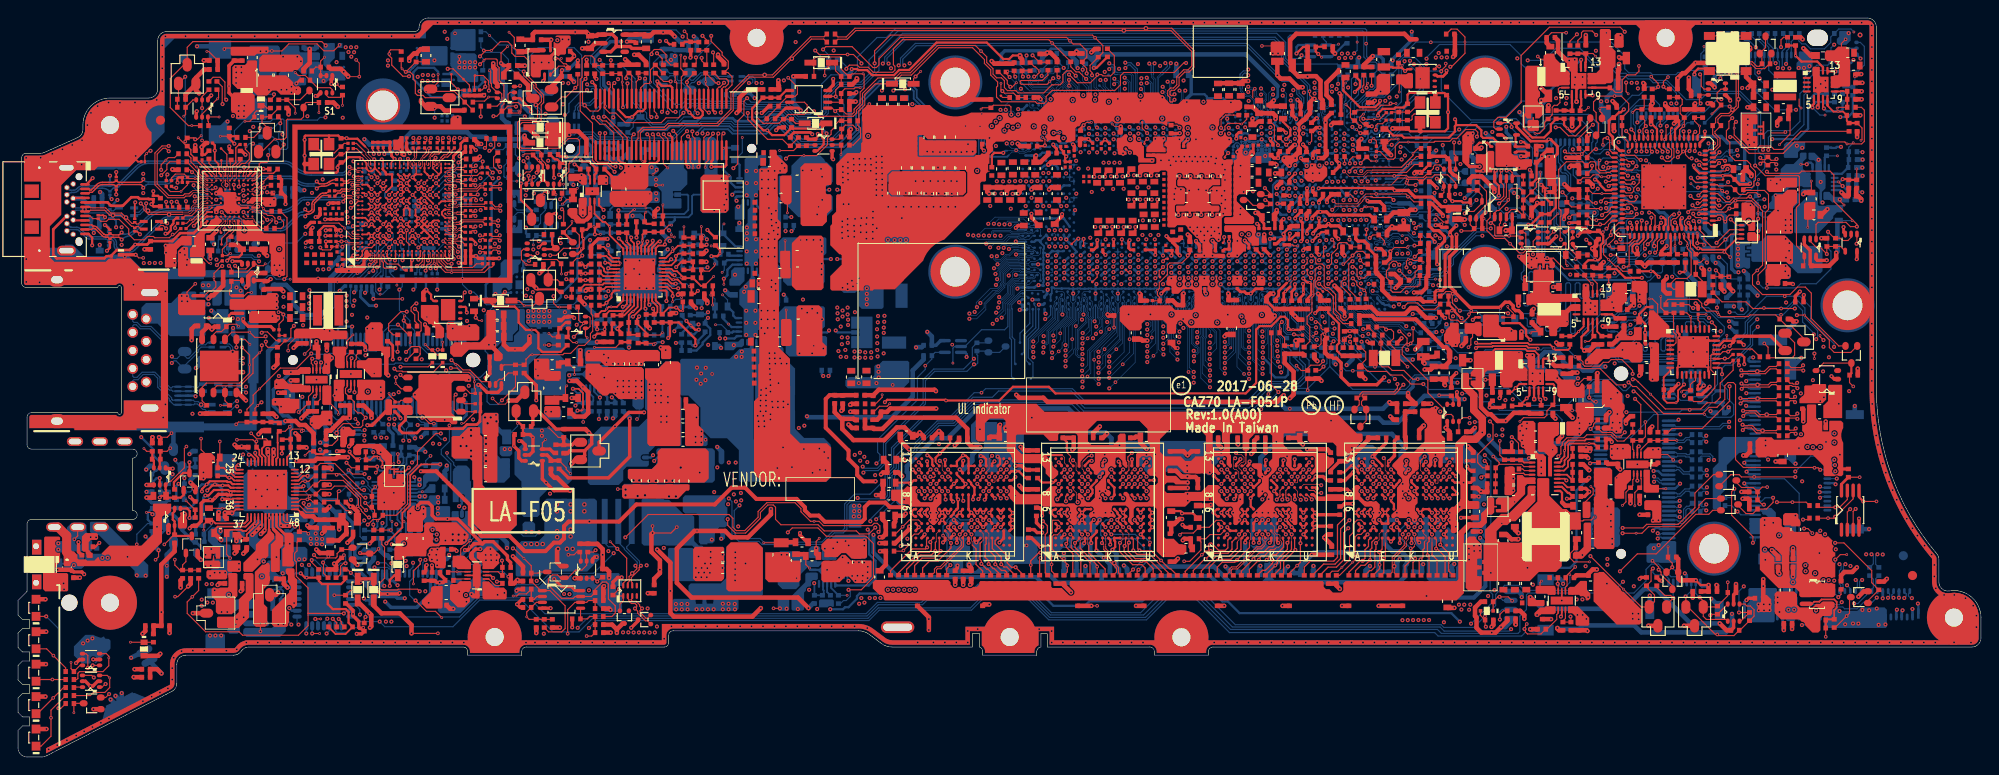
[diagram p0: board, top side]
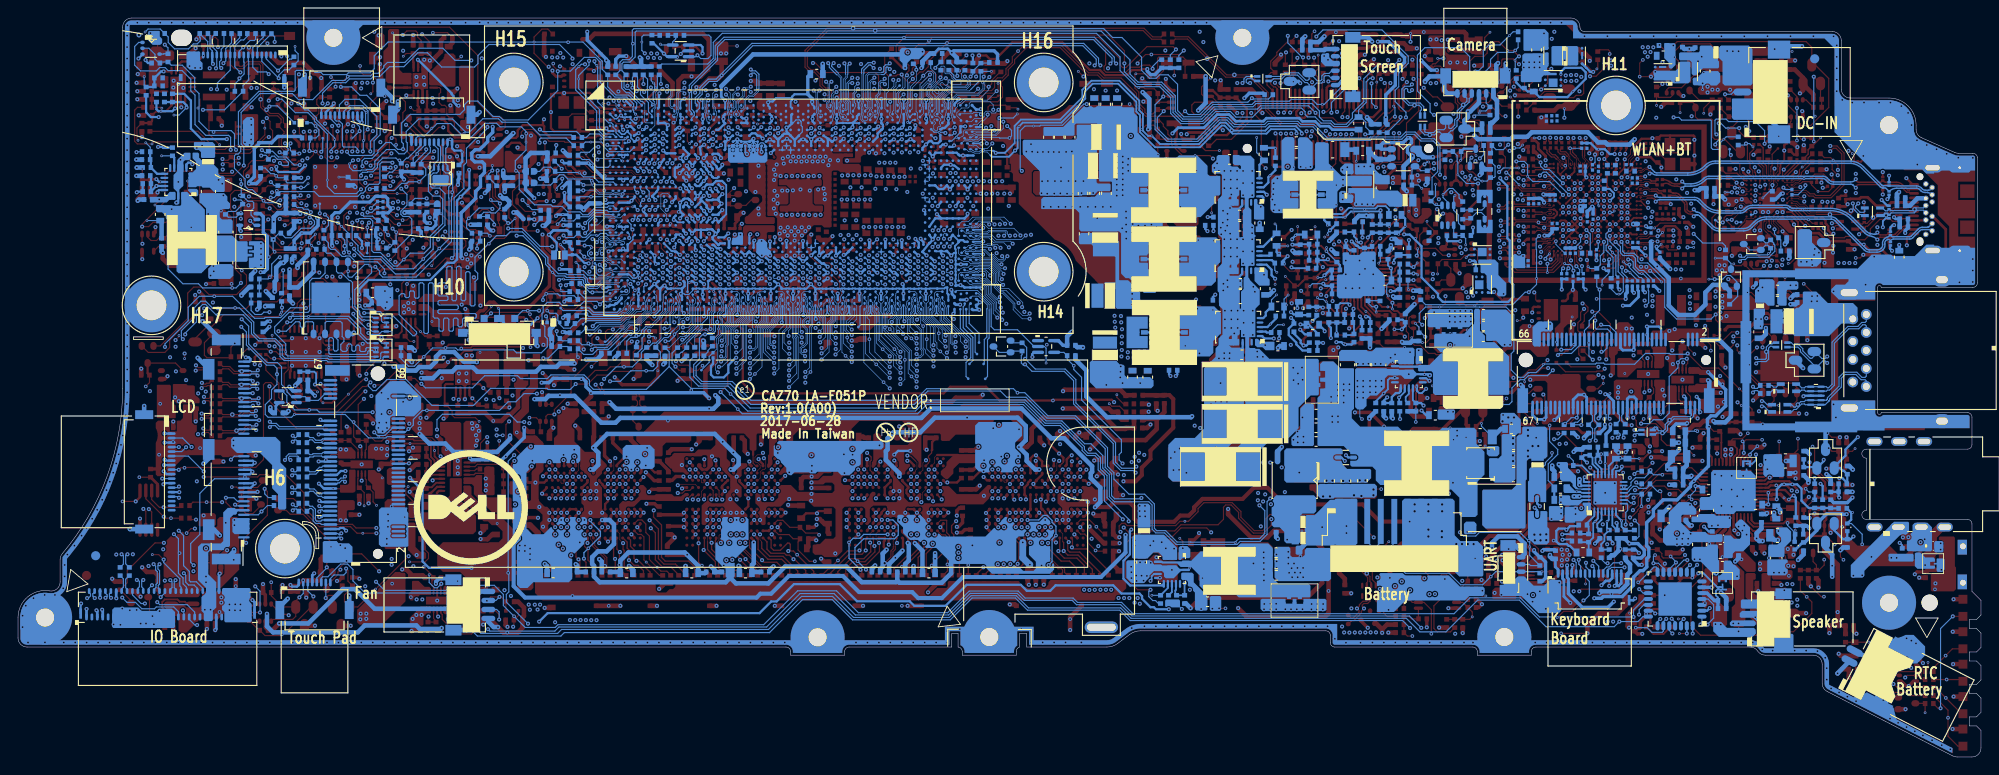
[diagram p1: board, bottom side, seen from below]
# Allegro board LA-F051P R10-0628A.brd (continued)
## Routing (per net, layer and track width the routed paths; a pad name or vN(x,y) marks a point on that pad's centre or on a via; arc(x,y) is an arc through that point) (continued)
DDR_A_CKE2: length 63.8
  TOP w0.142: v2(121.32,24.7) 120.99,25.03 UD20.K3 ; RD107.1 124.18,20.63 v2(124.33,20.78)
  IN2 w0.102: v2(121.32,24.7) 121.32,24.03 121.56,23.78 121.77,23.78 121.87,23.88 121.87,24.88 121.99,25 122.16,25 122.28,24.88 122.28,24.77 122.4,24.65 123.95,24.65 124.1,24.8 124.1,25.71 124,25.82 123.66,25.82 123.37,26.1 123.37,26.98 122.07,28.27 122.07,31.96 122.57,32.46 122.95,32.46 123.06,32.34 123.06,31.71 123.19,31.58 123.37,31.58 123.5,31.71 123.5,32.33 123.62,32.46 123.88,32.46 124,32.59 124,32.93 124.1,33.03 124.31,33.03 124.41,32.93 124.41,32.43 124.52,32.32 124.68,32.32 124.79,32.43 124.79,33.31 124.66,33.44 124.12,33.44 124,33.55 124,33.72 124.12,33.84 124.6,33.84 124.71,33.96 124.71,34.13 124.6,34.25 123.19,34.25 123.09,34.35 123.09,34.55 123.19,34.65 125.12,34.65 125.24,34.77 125.24,34.95 125.12,35.06 123.19,35.06 123.09,35.16 123.09,35.37 123.19,35.47 125.13,35.47 125.24,35.57 125.24,35.77 125.13,35.87 123.19,35.87 123.09,35.98 123.09,36.18 123.19,36.28 124.39,36.28 124.51,36.4 124.51,36.57 124.39,36.69 122.99,36.69 122.89,36.79 122.89,36.99 122.99,37.09 123.58,37.09 123.7,37.21 123.7,37.38 123.58,37.5 122.78,37.5 122.69,37.59 122.69,46.74 121.16,48.27 v2(120.85,48.27)
  BOTTOM w0.076: UCPU1.AW56 120.42,51.42 120.42,51.22 120.47,51.17 120.47,50.86 120.44,50.8 120.43,50.79 120.43,50.52 120.47,50.44 120.47,50.23 120.41,50.12 120.41,49.9 120.47,49.79 120.47,49.49 120.33,49.35 120.33,48.88 120.75,48.46 120.75,48.4 120.88,48.27 v2(120.85,48.27)
  BOTTOM w0.142: v2(124.33,20.78) 125.6,22.05 v3(125.6,23.81) 125.14,24.27 124.39,24.27 123.96,24.7 v2(121.32,24.7)
DDR_A_CKE3: length 65.2
  TOP w0.142: UD20.K4 120.99,26.03 121.26,26.3 v2(121.32,26.3) ; RD109.1 123.29,20.37 v2(123.72,20.8)
  IN2 w0.102: v2(121.32,26.3) 121.32,26.46 121.74,26.88 121.74,27.64 121.64,27.75 121.07,27.75 120.96,27.86 120.96,28.03 121.07,28.15 121.67,28.15 121.74,28.23 121.74,29.17 121.64,29.27 121.26,29.27 121.16,29.37 121.16,29.57 121.26,29.68 121.65,29.68 121.77,29.8 121.77,29.96 121.65,30.08 120.85,30.08 120.75,30.18 120.75,30.39 120.85,30.49 121.56,30.49 121.74,30.67 121.74,32.14 121.56,32.31 121.56,33.23 121.67,33.33 122.68,33.33 122.78,33.23 122.78,32.93 122.89,32.83 123.09,32.83 123.19,32.93 123.19,33.64 123.09,33.74 121.67,33.74 121.56,33.84 121.56,34.02 121.69,34.15 122.51,34.15 122.71,34.35 122.71,36.5 122.35,36.86 122.35,43.29 122.25,43.39 121.67,43.39 121.56,43.49 121.56,43.7 121.67,43.8 122.28,43.8 122.35,43.87 122.35,44.1 122.25,44.2 121.67,44.2 121.56,44.31 121.56,44.51 121.67,44.61 122.26,44.61 122.38,44.73 122.38,44.9 122.26,45.02 120.45,45.02 120.35,45.12 120.35,45.32 120.45,45.42 122.25,45.42 122.35,45.53 122.35,45.75 122.28,45.83 119.94,45.83 119.23,45.12 118.62,45.12 118.52,45.22 118.52,45.42 118.62,45.53 119.13,45.53 119.84,46.24 122.26,46.24 122.38,46.36 122.38,46.52 122.26,46.64 121.61,46.64 121.46,46.79 121.46,47.46 121.36,47.56 121.16,47.56 121.06,47.46 121.06,46.74 120.96,46.64 120.75,46.64 120.65,46.74 120.65,47.66 120.55,47.76 v2(119.63,47.76)
  BOTTOM w0.076: v2(119.63,47.76) 120.03,48.15 120.03,48.48 119.77,48.74 119.77,49.82 119.79,49.87 119.79,49.87 119.93,50.23 119.93,50.52 120.2,50.78 UCPU1.AY56
  BOTTOM w0.142: v2(121.32,26.3) 120.73,26.3 120.14,25.71 120.14,24.62 120.55,24.22 123.96,24.22 124.94,23.24 124.94,22.02 v3(124.65,21.72) v2(123.72,20.8)
DDR_A_CLK0: length 49
  TOP w0.076: v2(104.5,24.7) 104.5,24.11 104.67,23.94 104.67,23.83
  TOP w0.122: v2(104.5,24.7) 104.82,25.02 UD19.J3 ; RD35.1 101.38,20.17 101.68,20.48 101.68,20.85 101.94,21.11 102.32,21.11 104.67,23.46 104.67,23.83
  IN2 w0.076: 121,52.11 121,52.12 121.03,52.15 121.03,52.69 121.23,52.89 121.46,52.89 121.56,52.99 v2(121.56,53.17)
  IN2 w0.102: v2(104.5,24.7) 104.51,24.7 104.71,24.9 104.71,25.09 104.94,25.32 104.94,27.68 105.35,28.09 105.35,28.98 105.59,29.22 105.59,35.69 105.49,35.79 105.02,35.79 104.79,36.02 104.79,36.4 105.02,36.62 105.49,36.62 105.59,36.72 105.59,36.93 105.49,37.03 105.02,37.03 104.79,37.26 104.79,37.64 105.02,37.86 105.49,37.86 105.59,37.96 105.59,38.34 106.21,38.96 110.75,38.96 115.38,43.59 115.38,47.14 118.61,50.36 119.97,50.36 121,51.39 121,52.11
  BOTTOM w0.076: UCPU1.AT53 121.85,53.45 v2(121.56,53.17)
DDR_A_CLK1: length 47.6
  TOP w0.076: 120.7,23.36 120.65,23.4 120.65,23.56 120.71,23.61 120.71,23.97 120.67,24.01 v2(120.67,24.7)
  TOP w0.122: RD46.1 122.11,20.45 122.11,21.04 v4(121.65,21.5) 120.95,22.2 120.95,22.86 120.7,23.11 120.7,23.36 ; v2(120.67,24.7) 120.67,24.77 UD20.J3
  IN4 w0.076: 120.11,52.08 120.11,52.2 120.07,52.24 120.07,52.62 120.29,52.84 120.5,52.84 120.6,52.94 v2(120.6,53.12)
  IN4 w0.114: v2(120.67,24.7) 120.57,24.6 120.57,24.34 120.7,24.21 121.54,24.21 121.85,24.52 124.08,24.52 124.38,24.21 126.4,24.21 126.95,24.76 126.95,26.78 126.83,26.89 126.51,26.89 126.28,27.13 126.28,27.52 126.51,27.76 126.83,27.76 126.95,27.87 126.95,28.1 126.83,28.21 126.35,28.21 126.1,28.46 126.1,28.83 126.35,29.08 126.83,29.08 126.95,29.19 126.95,34.68 122.56,39.07 122.56,47.57 121.62,48.51 121.62,49.56 120.11,51.06 120.11,52.08
  BOTTOM w0.076: v2(120.6,53.12) 120.65,53.12 120.65,53.1 120.76,53.1 UCPU1.AT55
DDR_A_CLK#0: length 48.3
  TOP w0.122: RD37.1 102.15,20.23 101.91,20.48 101.91,20.76 102.03,20.89 102.41,20.89 104.9,23.37 104.9,24.22 UD19.J2 104.82,24.39 v2(105.13,24.7)
  IN2 w0.076: 121.21,52.11 121.2,52.12 121.2,52.62 121.3,52.72 121.48,52.72 121.59,52.61 v2(121.59,52.43)
  IN2 w0.102: 121.21,52.11 121.21,51.3 120.06,50.15 118.69,50.15 115.6,47.05 115.6,43.5 110.84,38.74 106.3,38.74 105.8,38.25 105.8,37.88 105.58,37.65 105.11,37.65 105.01,37.55 105.01,37.34 105.11,37.24 105.58,37.24 105.8,37.02 105.8,36.64 105.58,36.41 105.11,36.41 105.01,36.31 105.01,36.1 105.11,36 105.58,36 105.8,35.78 105.8,29.13 105.56,28.89 105.56,28 105.16,27.59 105.16,25.23 104.92,25 104.92,24.83 105.05,24.7 v2(105.13,24.7)
  BOTTOM w0.076: v2(121.59,52.43) 121.95,52.43 122.02,52.51 UCPU1.AU53
DDR_A_CLK#1: length 46.6
  TOP w0.076: v2(120.28,23.74) 120.3,23.74 120.49,23.56 120.49,23.39 120.47,23.38 120.47,23.32
  TOP w0.122: UD20.J2 120.34,24.3 120.34,23.81 v2(120.28,23.74) ; 120.47,23.32 120.47,23.02 120.73,22.77 120.73,22.11 121.16,21.67 121.88,20.95 121.88,20.52 RD45.1
  IN4 w0.076: v2(120.65,52.47) 120.65,52.53 120.5,52.68 120.36,52.68 120.23,52.55 120.23,52.31 120.29,52.25 120.29,52.12 120.31,52.1 120.31,52.08
  IN4 w0.114: v2(120.28,23.74) 120.54,24.01 121.62,24.01 121.93,24.32 123.99,24.32 124.3,24.01 126.49,24.01 127.15,24.67 127.15,26.86 126.92,27.1 126.6,27.1 126.48,27.21 126.48,27.44 126.6,27.55 126.92,27.55 127.15,27.79 127.15,28.18 126.92,28.42 126.43,28.42 126.31,28.54 126.31,28.75 126.43,28.87 126.92,28.87 127.15,29.11 127.15,34.76 122.76,39.15 122.76,47.66 121.82,48.6 121.82,49.64 120.31,51.15 120.31,52.08
  BOTTOM w0.076: v2(120.65,52.47) 120.78,52.47 UCPU1.AU55
DDR_A_CS#0: length 71.6
  TOP w0.076: UD20.L3 121.64,25.17 v2(121.97,25.5) ; UD19.L3 106.12,25.18 v2(106.45,25.5)
  TOP w0.142: v2(113.45,22.67) 113.28,22.67 112.37,21.76 v3(112.37,21.29) RD99.1
  IN1 w0.117: v2(113.45,22.67) 113.82,23.05 117.98,23.05 118.09,22.94 118.09,22.45 118.21,22.34 118.44,22.34 118.56,22.45 118.56,22.65 118.67,22.77 118.91,22.77 119.02,22.65 119.02,22.45 119.14,22.34 125.45,22.34 128.4,25.29 128.4,35.65 124.56,39.49 124.56,50 126.04,51.48 126.04,52.27 v2(126.22,52.44)
  IN4 w0.117: v2(106.45,25.5) 106.94,25.01 112.32,25.01 112.42,25.11 112.42,25.28 112.55,25.41 112.8,25.41 112.93,25.28 112.93,22.87 113.12,22.67 v2(113.45,22.67) 114.56,22.67 116.05,24.16 116.84,24.16 118.09,25.41 119.79,25.41 120.27,25.89 121.58,25.89 v2(121.97,25.5)
  BOTTOM w0.076: v2(126.22,52.44) 126.57,52.8 UCPU1.AU45
DDR_A_CS#1: length 71.9
  TOP w0.076: v2(105.8,25.5) 106.12,25.82 UD19.L4 ; UD20.L4 121.64,25.82 v2(121.32,25.5)
  TOP w0.142: v2(113.46,22.09) 113.36,21.98 RD101.1
  IN1 w0.117: v2(113.46,22.09) 113.52,22.03 125.58,22.03 128.71,25.16 128.71,28.77 128.83,28.89 128.9,28.89 129.02,29.01 129.02,29.24 128.9,29.36 128.83,29.36 128.71,29.47 128.71,33.43 128.83,33.55 129.27,33.55 129.39,33.66 129.39,33.9 129.27,34.02 128.83,34.02 128.71,34.13 128.71,34.37 128.83,34.48 129.27,34.48 129.39,34.6 129.39,34.83 129.27,34.95 128.83,34.95 128.71,35.07 128.71,35.78 124.87,39.62 124.87,49.87 126.35,51.35 126.35,51.71 127.05,52.42 v2(127.05,52.47)
  IN4 w0.117: v2(121.32,25.5) 120.92,25.1 120.47,25.1 119.66,24.29 119.66,23.61 119.2,23.15 115.6,23.15 114.53,22.09 v2(113.46,22.09) 113.44,22.11 113.03,22.11 112.52,22.62 112.52,23.78 111.61,24.7 106.6,24.7 v2(105.8,25.5)
  BOTTOM w0.076: UCPU1.AU43 127.39,52.8 v2(127.05,52.47)
DDR_A_D0: length 46.8
  TOP w0.142: v2(100.6,28.7) 100.92,29.03 UD19.C8
  IN1 w0.117: v2(100.6,28.7) 100.56,28.74 98.86,28.74 96.62,30.97 96.62,53.12 102.21,58.71 106.22,58.71 106.3,58.63 109.33,58.63 109.95,58.01 v2(109.95,56.37)
  BOTTOM w0.076: v2(109.95,56.37) 110.1,56.52 111.47,56.52 UCPU1.AL71
DDR_A_D1: length 45
  TOP w0.142: UD19.B11 100.27,31.58 v2(99.95,31.9)
  IN1 w0.117: v2(108.69,54.67) 107.67,54.67 107.21,54.21 107.21,52.79 105.01,50.59 102.16,50.59 98.47,46.9 98.47,38.7 98.59,38.58 99.52,38.58 99.64,38.46 99.64,38.23 99.52,38.11 98.59,38.11 98.47,38 98.47,37.76 98.59,37.65 99.52,37.65 99.64,37.53 99.64,37.3 99.52,37.18 98.59,37.18 98.47,37.06 98.47,36.83 98.59,36.71 99.52,36.71 99.64,36.59 99.64,36.36 99.52,36.24 98.59,36.24 98.47,36.13 98.47,35.89 98.59,35.78 99.52,35.78 99.64,35.66 99.64,35.43 99.52,35.31 98.59,35.31 98.47,35.19 98.47,34.84 98.6,34.71 99.28,34.71 99.47,34.53 99.47,32.38 v2(99.95,31.9)
  BOTTOM w0.076: UCPU1.AL68 113.44,55.86 113.23,55.65 112.72,55.65 112.57,55.58 112.38,55.58 112.22,55.63 112.08,55.63 111.86,55.57 111.74,55.57 111.66,55.6 111.63,55.61 111.13,55.61 110.88,55.37 109.66,55.37 108.96,54.67 v2(108.69,54.67)
DDR_A_D2: length 47.3
  TOP w0.142: v2(101.25,29.5) 100.92,29.83 UD19.C9
  IN1 w0.117: v2(108.51,52.38) 108.51,52.32 107.21,51.03 107.21,48.93 106.46,48.18 106.3,48.18 106.08,48.39 105.92,48.39 105.75,48.23 105.75,48.06 105.97,47.85 105.97,47.68 105.8,47.52 105.64,47.52 105.42,47.73 105.26,47.73 105.09,47.57 105.09,47.4 105.31,47.19 105.31,47.02 105.14,46.85 104.97,46.85 103.86,47.97 103.68,47.97 103.52,47.82 103.52,47.64 104.64,46.52 104.64,46.36 104.48,46.19 104.31,46.19 102.98,47.52 102.8,47.52 102.65,47.37 102.65,47.19 103.98,45.86 103.98,45.7 103.82,45.53 103.65,45.53 102.16,47.02 101.98,47.02 101.83,46.87 101.83,46.69 103.32,45.2 103.32,45.04 102.67,44.38 102.67,34.12 103.3,33.49 103.3,32.8 102.46,31.96 102.46,31.71 102.11,31.35 102.11,30.67 102.31,30.46 102.31,30.09 102.15,29.93 101.68,29.93 v2(101.25,29.5)
  BOTTOM w0.076: v2(108.51,52.38) 109.03,52.9 109.03,53.81 109.93,54.71 111.16,54.71 111.2,54.75 112.13,54.75 112.37,54.99 112.86,54.99 UCPU1.AN68
DDR_A_D3: length 44.7
  TOP w0.142: UD19.B10 100.27,30.78 v2(99.95,31.1)
  IN1 w0.117: v2(99.95,31.1) 99.95,31.15 100.43,31.63 100.43,34.81 100.61,34.98 100.61,36.59 100.49,36.7 100.09,36.7 99.98,36.82 99.98,37.06 100.09,37.17 100.49,37.17 100.61,37.29 100.61,37.52 100.49,37.64 100.09,37.64 99.98,37.76 99.98,37.99 100.09,38.11 100.49,38.11 100.61,38.22 100.61,38.46 100.49,38.57 100.09,38.57 99.98,38.69 99.98,38.92 100.09,39.04 100.49,39.04 100.61,39.16 100.61,39.39 100.49,39.51 98.94,39.51 98.81,39.64 98.81,39.85 98.94,39.98 100.49,39.98 100.61,40.09 100.61,40.33 100.49,40.44 98.93,40.44 98.8,40.57 98.8,40.78 98.93,40.91 99.87,40.91 100,41.04 100,41.25 99.87,41.38 99.02,41.38 98.89,41.51 98.89,46.88 102.29,50.28 105.13,50.28 107.47,52.61 107.47,53.65 108.05,54.24 v2(108.29,54.24)
  BOTTOM w0.076: v2(108.29,54.24) 108.76,54.24 109.72,55.2 110.95,55.2 111.2,55.45 111.6,55.45 111.71,55.39 111.73,55.39 111.74,55.39 111.75,55.39 111.85,55.39 112.08,55.46 112.22,55.46 112.43,55.38 112.69,55.38 UCPU1.AN69
DDR_A_D4: length 46.8
  TOP w0.142: UD19.B9 100.27,29.83 v2(100.6,29.5)
  IN1 w0.117: v2(109.37,56.5) 109.58,56.7 109.58,57.95 109.22,58.3 106.2,58.3 106.1,58.4 102.34,58.4 96.93,53 96.93,31.1 98.98,29.05 100.15,29.05 v2(100.6,29.5)
  BOTTOM w0.076: UCPU1.AL70 111.99,56.51 111.82,56.68 111.69,56.74 111.57,56.77 111.07,56.77 110.98,56.69 110.29,56.69 110.22,56.77 109.75,56.77 109.7,56.71 109.47,56.71 109.37,56.61 v2(109.37,56.5)
DDR_A_D5: length 44.2
  TOP w0.142: v2(99.95,29.5) 100.27,29.18 UD19.B8
  IN1 w0.117: v2(108.79,56.5) 108.79,57.06 108.46,57.39 105.82,57.39 105.69,57.51 101.88,57.51 97.26,52.89 97.26,31.2 98.96,29.5 v2(99.95,29.5)
  BOTTOM w0.076: v2(108.79,56.5) 109.17,56.88 109.63,56.88 109.68,56.93 110.29,56.93 110.36,56.85 110.92,56.85 111.01,56.95 111.55,56.95 111.63,56.93 111.68,56.91 111.75,56.9 111.83,56.89 111.96,56.85 111.96,56.85 112.15,56.77 112.32,56.77 112.58,56.51 UCPU1.AL69
DDR_A_D6: length 43.7
  TOP w0.142: UD19.C11 100.92,31.57 v2(101.25,31.9)
  IN1 w0.117: v2(101.25,31.9) 101.73,32.38 101.73,33.97 101.22,34.47 101.22,34.86 101.34,34.98 101.78,34.98 101.91,35.11 101.91,35.32 101.78,35.45 101.34,35.45 101.22,35.56 101.22,35.8 101.34,35.91 101.58,35.91 101.71,36.04 101.71,36.26 101.58,36.38 101.34,36.38 101.22,36.5 101.22,36.73 101.34,36.85 102.2,36.85 102.33,36.98 102.33,37.19 102.2,37.32 101.34,37.32 101.22,37.43 101.22,37.67 101.34,37.78 101.5,37.78 101.62,37.9 101.62,38.13 101.5,38.25 101.34,38.25 101.22,38.37 101.22,43.37 102.1,44.25 102.1,45 101.98,45.12 100.73,45.12 100.62,45.24 100.62,46.53 100.76,46.67 101.21,46.67 101.4,46.86 101.4,47.73 101.22,47.91 101.22,48.09 101.46,48.33 101.64,48.33 102.1,47.87 102.28,47.87 102.43,48.02 102.43,48.2 101.95,48.68 101.95,48.86 102.11,49.01 102.29,49.01 102.99,48.31 103.17,48.31 103.32,48.46 103.32,48.64 102.73,49.22 102.73,49.4 102.88,49.55 103.06,49.55 104.09,48.53 104.25,48.53 104.42,48.69 104.42,48.86 104.11,49.17 104.11,49.33 104.27,49.5 104.44,49.5 104.75,49.19 104.91,49.19 105.85,50.12 105.87,50.12 108.08,52.33 108.08,52.89 108.21,53.02 v2(108.64,53.02)
  BOTTOM w0.076: UCPU1.AN70 111.87,54.91 111.13,54.91 111.09,54.87 109.86,54.87 108.86,53.88 108.86,53.35 108.64,53.13 v2(108.64,53.02)
DDR_A_D7: length 42.8
  TOP w0.142: v2(100.6,31.1) 100.92,30.78 UD19.C10
  IN1 w0.117: v2(100.6,31.1) 100.6,31.26 100.79,31.45 100.79,32.04 101.4,32.65 101.4,33.87 100.92,34.35 100.92,40.83 100.8,40.94 100.43,40.94 100.31,41.06 100.31,41.29 100.43,41.41 100.8,41.41 100.92,41.53 100.92,41.76 100.8,41.88 99.38,41.88 99.25,42 99.25,42.22 99.38,42.34 100.8,42.34 100.92,42.46 100.92,42.69 100.8,42.81 99.37,42.81 99.24,42.94 99.24,43.15 99.37,43.28 100.8,43.28 100.92,43.4 100.92,43.63 100.8,43.75 100.14,43.75 100.01,43.87 100.01,44.09 100.14,44.21 101.4,44.21 101.53,44.34 101.53,44.55 101.4,44.68 100.43,44.68 100.31,44.8 100.31,47.87 102.42,49.97 105.26,49.97 107.77,52.48 107.77,53.22 108.15,53.6 v2(108.46,53.6)
  BOTTOM w0.076: UCPU1.AN71 111.16,55.18 111.02,55.04 109.79,55.04 108.46,53.7 v2(108.46,53.6)
DDR_A_D8: length 32.6
  TOP w0.142: UD19.R10 108.72,30.78 v2(109.05,31.1)
  IN4 w0.117: v2(106.78,50.38) 106.1,50.38 105.72,50 105.13,50 103.19,48.05 103.19,38.85 107.26,34.77 107.26,32.44 107.98,31.73 108.42,31.73 v2(109.05,31.1)
  BOTTOM w0.076: UCPU1.AR70 111.99,54.15 111.72,54.42 111.33,54.42 111.29,54.38 110.07,54.38 109.36,53.67 109.36,52.65 109.16,52.45 109.16,52.26 108.68,51.77 108.18,51.77 v2(106.78,50.38)
DDR_A_D9: length 33.2
  TOP w0.142: v2(109.05,31.9) 108.72,31.57 UD19.R11
  IN4 w0.117: v2(106.4,49.92) 106.07,49.92 105.85,49.69 105.26,49.69 103.53,47.96 103.53,38.95 107.57,34.9 107.57,32.72 108.05,32.24 108.71,32.24 v2(109.05,31.9)
  BOTTOM w0.076: UCPU1.AR68 112.91,54.35 112.37,54.35 112.13,54.58 111.26,54.58 111.22,54.54 110,54.54 109.2,53.74 109.2,52.71 109,52.52 109,52.33 108.65,51.98 107.87,51.98 106.32,50.43 106.32,50 v2(106.4,49.92)
DDR_A_D10: length 31.6
  TOP w0.142: v2(109.04,29.5) 108.72,29.82 UD19.R9
  IN4 w0.117: v2(109.04,29.5) 109.04,29.52 109.45,29.93 110.67,29.93 110.93,29.67 111.55,29.67 113.05,31.17 113.05,33.91 107.65,39.31 107.65,48.42 v2(108.53,49.31)
  BOTTOM w0.076: UCPU1.AU71 111.38,52.72 110.62,52.72 110.11,52.21 110.11,51.36 109.22,50.47 109.22,49.72 108.81,49.31 v2(108.53,49.31)
DDR_A_D11: length 32.7
  TOP w0.142: UD19.T10 109.37,30.78 v2(109.7,31.1)
  IN4 w0.117: v2(105.56,48.62) 104.55,47.61 104.55,39.6 109.73,34.41 109.73,33.59 110.13,33.19 110.13,31.53 v2(109.7,31.1)
  BOTTOM w0.076: UCPU1.AU68 113.44,53.58 113.23,53.78 112.99,53.78 112.97,53.76 112.38,53.76 112.22,53.7 112.08,53.7 111.86,53.77 111.74,53.77 111.66,53.73 111.63,53.72 111.26,53.72 111.1,53.88 110.53,53.88 110.34,53.69 110.34,53.16 109.49,52.31 109.49,52.12 108.81,51.44 108.54,51.44 107.39,50.3 107.39,49.64 106.38,48.62 v2(105.56,48.62)
DDR_A_D12: length 30.3
  TOP w0.142: UD19.T11 109.37,31.57 v2(109.7,31.9)
  IN4 w0.117: v2(105.56,49.21) 105.41,49.21 103.86,47.66 103.86,39.85 109.14,34.57 109.14,32.46 v2(109.7,31.9)
  BOTTOM w0.076: UCPU1.AR71 111.43,54.21 110.14,54.21 109.53,53.6 109.53,52.58 109.33,52.38 109.33,52.19 108.75,51.61 108.47,51.61 107.2,50.34 107.2,49.85 106.32,48.98 105.79,48.98 v2(105.56,49.21)
DDR_A_D13: length 35.1
  TOP w0.142: UD19.R8 108.72,29.03 v2(109.05,28.7)
  IN4 w0.117: v2(109.05,28.7) 109.51,28.24 112.18,28.24 113.97,30.03 113.97,34.29 109.56,38.7 109.56,53.05 v2(109.93,53.43)
  BOTTOM w0.076: UCPU1.AR69 112.69,53.95 112.43,53.95 112.22,53.88 112.08,53.88 111.85,53.94 111.75,53.94 111.74,53.95 111.73,53.94 111.71,53.94 111.6,53.89 111.33,53.89 111.17,54.05 110.43,54.05 109.93,53.55 v2(109.93,53.43)
DDR_A_D14: length 31
  TOP w0.142: v2(109.7,29.49) 109.7,29.58 109.39,29.9 UD19.T9
  IN4 w0.117: v2(108.61,48.5) 108.61,38.78 113.36,34.04 113.36,31.05 111.67,29.36 110.8,29.36 110.54,29.62 109.84,29.62 v2(109.7,29.49)
  BOTTOM w0.076: v2(108.61,48.5) 108.61,48.75 109.4,49.54 109.4,50.38 110.31,51.29 110.31,52.18 110.68,52.55 111.86,52.55 UCPU1.AU70
DDR_A_D15: length 32.2
  TOP w0.142: UD19.T8 109.37,29.03 v2(109.7,28.7)
  IN4 w0.117: v2(109.14,48.75) 109.14,38.68 113.66,34.16 113.66,30.18 112.03,28.55 109.85,28.55 v2(109.7,28.7)
  BOTTOM w0.076: UCPU1.AU69 112.58,52.83 112.2,52.44 112.02,52.44 111.94,52.37 110.73,52.37 110.52,52.15 110.52,51.22 109.6,50.3 109.6,49.21 v2(109.14,48.75)
DDR_A_D16: length 40.1
  TOP w0.142: v2(107.11,29.5) 107.42,29.81 UD19.N9
  IN1 w0.117: v2(115.68,58.45) 115.68,58.57 115.09,59.17 113.31,59.17 111.51,57.37 111.51,55.77 109.47,53.74 109.47,52.26 107.95,50.74 107.95,48.62 103.48,44.15 103.48,34.41 104.06,33.83 104.06,31.36 104.72,30.7 104.72,30.1 105.33,29.5 v2(107.11,29.5)
  BOTTOM w0.076: UCPU1.AF65 115.39,58.73 v2(115.68,58.45)
DDR_A_D17: length 41.6
  TOP w0.142: v2(106.56,28.62) 106.77,28.83 UD19.M8
  IN1 w0.117: v2(116.32,58.43) 116.32,58.41 115.26,59.48 113.18,59.48 111.2,57.5 111.2,56.95 110.16,55.91 110.16,54.86 109.14,53.84 109.14,52.36 107.65,50.86 107.65,48.75 103.17,44.28 103.17,34.28 103.76,33.7 103.76,31.23 104.39,30.59 104.39,30 105.2,29.19 105.99,29.19 v2(106.56,28.62)
  BOTTOM w0.076: v2(116.32,58.43) 116.32,58.41 116.04,58.69 UCPU1.AF64
DDR_A_D18: length 36.7
  TOP w0.076: UD19.N11 107.42,31.64 107.75,31.97 107.75,33.09 v2(108.08,33.42)
  IN1 w0.076: v2(115.73,56.64) 115.55,56.46 115.55,52.21 115.49,52.16
  IN1 w0.117: v2(108.08,33.42) 108.08,36.29 108.2,36.41 108.44,36.41 108.55,36.53 108.55,36.76 108.44,36.88 108.2,36.88 108.08,36.99 108.08,37.35 108.2,37.46 109.71,37.46 109.83,37.58 109.83,37.81 109.71,37.93 108.2,37.93 108.08,38.05 108.08,38.28 108.2,38.4 109.71,38.4 109.83,38.51 109.83,38.75 109.71,38.86 108.87,38.86 108.75,38.99 108.75,39.2 108.87,39.33 109.71,39.33 109.83,39.45 109.83,45.06 112.63,47.86 114.29,47.86 114.82,48.4 114.82,51.14 115.28,51.6 115.28,51.94 115.49,52.16
  BOTTOM w0.076: v2(115.73,56.64) 115.39,56.98 UCPU1.AK65
DDR_A_D19: length 37.1
  TOP w0.142: UD19.N10 107.75,30.37 v2(107.75,30.29)
  IN1 w0.076: v2(116.34,56.59) 116.34,56.53 115.72,55.91 115.72,52
  IN1 w0.117: 115.72,52 115.72,51.61 115.13,51.02 115.13,48.27 114.42,47.56 112.76,47.56 110.13,44.93 110.13,36.06 110.02,35.94 109.46,35.94 109.34,35.82 109.34,35.59 109.46,35.47 110.02,35.47 110.13,35.36 110.13,35.12 110.02,35.01 109.46,35.01 109.34,34.89 109.34,34.66 109.46,34.54 110.02,34.54 110.13,34.42 110.13,34.19 110.02,34.07 109.46,34.07 109.34,33.95 109.34,33.72 109.46,33.6 110.02,33.6 110.13,33.49 110.13,32.96 110.15,32.94 110.15,30.74 109.83,30.41 107.88,30.41 v2(107.75,30.29)
  BOTTOM w0.076: UCPU1.AK64 116.04,56.89 v2(116.34,56.59)
DDR_A_D20: length 37.1
  TOP w0.142: v2(106.44,30.31) 106.77,29.98 UD19.M9
  IN1 w0.117: v2(106.44,30.31) 106.43,30.3 105.78,30.3 104.93,31.15 104.93,32.11 104.39,32.65 104.39,44.63 107.22,47.45 108.48,47.45 109.7,48.67 109.7,51.85 111.15,53.3 111.15,54.97 111.81,55.64 111.81,57.24 113.43,58.86 114.63,58.86 v2(115.04,58.45)
  BOTTOM w0.076: UCPU1.AF66 114.74,58.75 v2(115.04,58.45)
DDR_A_D21: length 37.1
  TOP w0.142: v2(107.74,29.5) 108.07,29.84 UD19.P9
  IN1 w0.076: 106.02,30.74 106.89,30.74 107.21,30.43 107.21,30.09 107.74,29.56 v2(107.74,29.5)
  IN1 w0.117: v2(114.4,58.44) 113.45,58.44 112.12,57.11 112.12,55.51 111.46,54.85 111.46,53.17 110.01,51.72 110.01,48.55 108.61,47.15 107.35,47.15 104.72,44.53 104.72,34.21 105.33,33.6 105.33,31.43 106.02,30.74
  BOTTOM w0.142: UCPU1.AF67 114.09,58.82 114.43,58.47 v2(114.4,58.44)
DDR_A_D22: length 35.2
  TOP w0.142: v2(107.1,31.9) 106.77,31.57 UD19.M11
  IN1 w0.117: v2(107.1,31.9) 107.27,32.07 107.27,40.29 107.39,40.41 107.79,40.41 107.9,40.53 107.9,40.76 107.79,40.88 107.17,40.88 107.04,41 107.04,41.22 107.17,41.34 109.03,41.34 109.15,41.47 109.15,41.69 109.03,41.81 107.1,41.81 106.98,41.94 106.98,42.15 107.1,42.28 108.9,42.28 109.02,42.41 109.02,45.13 113.77,49.87 113.77,55.97 v2(114.43,56.64)
  BOTTOM w0.076: v2(114.43,56.64) 114.09,56.99 UCPU1.AK67
DDR_A_D23: length 35.6
  TOP w0.142: UD19.M10 106.77,30.78 v2(107.09,31.1)
  IN1 w0.117: v2(115.07,56.64) 114.68,56.25 114.68,51.57 114.5,51.39 114.5,48.51 114.16,48.17 112.5,48.17 109.52,45.19 109.52,40.93 109.37,40.78 108.34,40.78 108.21,40.65 108.21,40.44 108.34,40.31 109.41,40.31 109.52,40.2 109.52,39.95 109.41,39.84 107.71,39.84 107.59,39.73 107.59,39.49 107.71,39.38 108.32,39.38 108.44,39.26 108.44,39.03 108.32,38.91 107.71,38.91 107.59,38.79 107.59,31.63 107.09,31.12 v2(107.09,31.1)
  BOTTOM w0.076: UCPU1.AK66 114.74,56.95 115.07,56.62 v2(115.07,56.64)
DDR_A_D24: length 42.9
  TOP w0.076: UD19.F11 102.55,31.83 102.55,32.6 v2(102.29,32.86)
  IN4 w0.117: v2(108.28,59.17) 108.28,59.44 108.13,59.6 102.64,59.6 97.87,54.82 97.87,36.76 100.19,34.44 101.01,34.44 101.64,33.81 101.64,33.51 v2(102.29,32.86)
  BOTTOM w0.076: UCPU1.AF70 111.6,59.7 108.81,59.7 v2(108.28,59.17)
DDR_A_D25: length 45.3
  TOP w0.142: UD19.F10 102.87,30.78 v2(102.55,31.1)
  IN4 w0.117: v2(102.55,31.1) 102.78,31.33 102.78,32.18 103.31,32.71 103.31,33.27 102.38,34.2 101.68,34.2 101.13,34.75 100.32,34.75 98.18,36.89 98.18,54.7 102.77,59.29 107.53,59.29 v2(107.66,59.16)
  BOTTOM w0.076: UCPU1.AF68 113.09,59.41 112.35,59.41 111.86,59.9 108.4,59.9 v2(107.66,59.16)
DDR_A_D26: length 43.4
  TOP w0.142: v2(101.91,29.5) 101.57,29.83 UD19.D9
  IN4 w0.117: v2(105.99,57.87) 105.99,57.67 105.69,57.36 102.62,57.36 100.71,55.45 100.71,48.4 100.09,47.79 100.09,39.17 105.31,33.96 105.31,32.68 105,32.38 105,31.5 104.27,30.77 103.61,30.77 103.07,30.23 102.44,30.23 101.91,29.7 v2(101.91,29.5)
  BOTTOM w0.076: v2(105.99,57.87) 106.43,57.44 109.25,57.44 109.75,57.93 110.99,57.93 111.13,57.93 111.23,57.83 UCPU1.AH71
DDR_A_D27: length 46.1
  TOP w0.142: UD19.F8 102.87,28.63 v2(102.93,28.57)
  IN4 w0.117: v2(106.58,57.87) 106.58,57.74 106.91,57.41 108.05,57.41 108.28,57.18 108.28,56.29 108.06,56.07 107.9,56.07 107.61,55.77 107.61,52.49 105.53,50.42 104.96,50.42 102.76,48.23 102.76,38.68 106.23,35.21 106.23,32.3 105.93,31.99 105.93,29.96 105.13,29.16 103.52,29.16 v2(102.93,28.57)
  BOTTOM w0.076: UCPU1.AH68 113.47,57.86 113.47,58.54 113.32,58.69 112.79,58.69 112.69,58.76 112.37,58.76 112.25,58.72 112.02,58.72 112.01,58.72 112,58.73 112,58.73 111.91,58.76 111.71,58.76 111.62,58.73 111.26,58.73 110.86,59.13 110.61,59.13 110.15,58.67 107.3,58.67 106.58,57.95 v2(106.58,57.87)
DDR_A_D28: length 44.5
  TOP w0.142: UD19.E10 102.22,30.63 v2(101.91,30.31)
  IN4 w0.117: v2(101.91,30.31) 101.91,31.11 102.32,31.52 102.32,32.13 101.33,33.11 101.33,33.68 100.88,34.13 100.07,34.13 97.56,36.64 97.56,54.95 102.52,59.9 108.81,59.9 109.46,59.26 v2(109.46,59.1)
  BOTTOM w0.076: v2(109.46,59.1) 109.82,59.46 111.18,59.46 UCPU1.AF71
DDR_A_D29: length 44.7
  TOP w0.142: UD19.E11 102.22,31.58 v2(101.9,31.9)
  IN4 w0.117: v2(101.9,31.9) 101.46,32.34 100.53,32.34 100.41,32.46 100.41,33.36 97.26,36.51 97.26,55.08 102.39,60.21 109.14,60.21 110.04,59.31 v2(110.04,59.1)
  BOTTOM w0.076: v2(110.04,59.1) 110.24,59.3 110.93,59.3 111.33,58.89 111.59,58.89 111.68,58.93 111.7,58.93 111.94,58.93 112.03,58.89 112.24,58.89 112.32,58.92 112.32,58.92 112.42,58.96 112.69,58.96 UCPU1.AF69
DDR_A_D30: length 43.2
  TOP w0.142: UD19.E9 102.22,29.87 102.54,29.55 v2(102.54,29.5)
  IN4 w0.117: v2(107.44,56.96) 107.39,56.9 102.59,56.9 101.02,55.33 101.02,48.27 100.4,47.66 100.4,39.3 105.61,34.08 105.61,32.55 105.31,32.25 105.31,31.18 104.72,30.59 104.72,30.23 104.37,29.88 102.92,29.88 v2(102.54,29.5)
  BOTTOM w0.076: v2(107.44,56.96) 107.44,57 107.68,57.24 109.4,57.24 109.93,57.77 110.93,57.77 111.06,57.77 111.26,57.57 111.59,57.57 111.84,57.68 111.84,57.69 111.85,57.69 111.99,57.83 UCPU1.AH70
DDR_A_D31: length 43.5
  TOP w0.142: UD19.F9 102.87,29.83 v2(103.2,29.5)
  IN4 w0.117: v2(107.86,56.55) 107.79,56.55 107.08,55.85 107.08,55.56 107.25,55.39 107.25,52.57 105.4,50.73 104.83,50.73 102.46,48.36 102.46,38.55 103.19,37.82 103.19,37.65 102.92,37.38 102.92,37.22 103.08,37.05 103.25,37.05 103.52,37.32 103.68,37.32 103.85,37.16 103.85,36.99 103.58,36.72 103.58,36.56 103.74,36.39 103.91,36.39 104.18,36.66 104.34,36.66 104.51,36.5 104.51,36.33 104.24,36.06 104.24,35.9 104.4,35.73 104.57,35.73 104.84,36 105.01,36 105.17,35.84 105.17,35.67 104.9,35.4 104.9,35.23 105.07,35.07 105.23,35.07 105.5,35.34 105.67,35.34 105.92,35.08 105.92,32.43 105.62,32.12 105.62,30.09 105.01,29.48 103.22,29.48 v2(103.2,29.5)
  BOTTOM w0.076: UCPU1.AH69 112.58,57.83 112.19,57.44 111.71,57.44 111.63,57.4 111.16,57.4 110.96,57.6 110.86,57.6 110.86,57.6 110.08,57.6 109.53,57.06 108.41,57.06 107.91,56.55 v2(107.86,56.55)
DDR_A_D32: length 24.2
  TOP w0.142: v2(115.47,29.5) 115.68,29.72 115.68,29.79 UD20.B9
  IN1 w0.117: v2(112.65,45.53) 112.4,45.53 111.87,45 111.87,38.55 113.44,36.98 113.44,30.69 114.5,29.63 115.34,29.63 v2(115.47,29.5)
  BOTTOM w0.076: v2(112.65,45.53) 112.65,45.53 113.23,46.12 113.23,46.67 115.14,48.58 115.14,49.58 UCPU1.BB65
DDR_A_D33: length 24.1
  TOP w0.076: v2(116.76,31.89) 116.76,31.82 UD20.C11
  IN1 w0.117: v2(116.76,31.89) 116.76,32.09 116.23,32.62 116.23,34.53 116.74,35.04 116.74,36.56 115.11,38.19 115.11,40.96 114.99,41.07 114.7,41.07 114.58,41.19 114.58,41.43 114.7,41.54 114.99,41.54 115.15,41.7 115.15,44.52 114.8,44.87 v2(114.74,44.87)
  BOTTOM w0.076: UCPU1.AW65 115.94,51.64 116.1,51.47 116.1,50.92 116.18,50.76 116.18,50.58 116.12,50.42 116.12,50.27 116.18,50.06 116.18,49.94 116.14,49.83 116.14,49.46 116.32,49.28 116.32,48.91 114.51,47.11 114.51,45.11 v2(114.74,44.87)
DDR_A_D34: length 24.4
  TOP w0.142: UD20.B11 115.79,31.57 v2(116.12,31.9)
  IN1 w0.117: v2(114.73,44.26) 114.27,43.8 114.27,43.59 114.39,43.48 114.69,43.48 114.8,43.36 114.8,43.12 114.69,43.01 114.39,43.01 114.27,42.89 114.27,42.66 114.39,42.54 114.69,42.54 114.8,42.42 114.8,42.19 114.69,42.07 114.39,42.07 114.27,41.96 114.27,38.6 116.43,36.44 116.43,35.17 115.92,34.65 115.92,32.1 v2(116.12,31.9)
  BOTTOM w0.076: v2(114.73,44.26) v3(115.47,45.01) 115.85,45.38 115.85,45.95 116.05,46.15 116.05,47.71 117,48.66 117,50.34 116.78,50.56 116.78,51.11 116.47,51.42 UCPU1.AW63
DDR_A_D35: length 26.4
  TOP w0.142: UD20.C8 116.43,29.1 116.26,28.92 116.26,28.38 v2(116.28,28.38)
  IN1 w0.076: 117.02,29.14 116.56,29.14 116.37,28.96 116.37,28.47 v2(116.28,28.38)
  IN1 w0.117: 117.02,29.14 117.6,29.73 117.6,31.56 117.84,31.79 117.84,32.45 117.66,32.63 117.66,36.51 115.77,38.4 115.77,45.97 114.97,46.77 v2(114.87,46.77)
  BOTTOM w0.076: v2(114.87,46.77) 114.87,47.24 116.48,48.85 116.48,49.35 116.3,49.53 116.3,49.79 116.36,49.91 116.36,50.05 116.29,50.28 116.29,50.41 116.37,50.63 116.37,50.88 UCPU1.AY63
DDR_A_D36: length 25.9
  TOP w0.142: UD20.B8 115.6,28.91 115.6,28.86 v2(115.32,28.58)
  IN1 w0.117: v2(112.65,46.11) 112.54,46.11 111.56,45.13 111.56,38.42 113.14,36.85 113.14,30.56 114.38,29.32 114.86,29.32 115.32,28.86 v2(115.32,28.58)
  BOTTOM w0.076: UCPU1.BA65 115.24,50.19 115.1,50.04 115.1,50.04 115.1,50.04 114.98,49.79 114.98,48.69 112.65,46.36 v2(112.65,46.11)
DDR_A_D37: length 25.1
  TOP w0.142: v2(115.47,30.3) 115.79,30.63 UD20.B10
  IN1 w0.117: v2(115.47,30.3) 115.17,30.01 114.56,30.01 113.75,30.82 113.75,37.1 112.18,38.68 112.18,44.47 v2(112.65,44.94)
  BOTTOM w0.076: v2(112.65,44.94) 112.29,45.3 112.29,46.26 114.81,48.78 114.81,49.83 114.92,50.06 114.92,50.1 114.98,50.23 114.98,50.52 115.24,50.78 UCPU1.AY65
DDR_A_D38: length 23
  TOP w0.142: v2(116.13,31.1) 116.44,30.79 UD20.C10
  IN1 w0.117: v2(114.89,45.54) 114.87,45.54 114.85,45.56 114.85,45.59 114.26,45 114.26,44.78 113.96,44.48 113.96,38.47 116.13,36.31 116.13,35.3 115.61,34.78 115.61,33.92 115.07,33.37 115.07,32.33 116.13,31.27 v2(116.13,31.1)
  BOTTOM w0.076: v2(114.89,45.54) 115.65,46.29 v3(115.65,47.02) 115.65,47.54 116.84,48.73 116.84,49.86 116.57,50.12 UCPU1.BA63
DDR_A_D39: length 23.6
  TOP w0.142: UD20.C9 116.44,29.83 v2(116.77,29.5)
  IN1 w0.117: v2(114.94,46.17) 115.46,45.65 115.46,38.28 117.05,36.69 117.05,34.91 116.53,34.4 116.53,32.75 116.83,32.44 117.41,32.44 117.53,32.32 117.53,31.92 117.3,31.69 117.3,30.03 v2(116.77,29.5)
  BOTTOM w0.076: UCPU1.BB63 116.65,49.61 116.65,48.78 115.26,47.39 115.26,46.49 v2(114.94,46.17)
DDR_A_D40: length 27.5
  TOP w0.142: v2(125.22,29.5) 125.22,29.57 UD20.T9
  IN4 w0.117: v2(116.23,45.12) 116.26,45.12 117.27,44.11 117.27,38.55 121.61,34.21 121.61,32.6 121.95,32.26 121.95,30.74 121.83,30.62 121.83,29.96 122.29,29.5 v2(125.22,29.5)
  BOTTOM w0.076: UCPU1.BA61 117.6,50.11 117.33,49.85 117.33,48.53 116.59,47.78 116.59,45.47 v2(116.23,45.12)
DDR_A_D41: length 29.1
  TOP w0.142: UD20.R9 124.24,29.97 v2(124.57,30.3)
  IN4 w0.117: v2(116.23,45.7) 116.26,45.7 117.58,44.38 117.58,38.68 119.09,37.17 120.3,37.17 122.8,34.67 122.8,34.1 122.66,33.96 122.66,32.5 122.21,32.04 122.21,30.02 122.37,29.86 124.1,29.86 124.55,30.3 v2(124.57,30.3)
  BOTTOM w0.076: v2(116.23,45.7) 116.23,47.66 117.17,48.6 117.17,50.37 117.38,50.58 117.38,51.12 117.7,51.45 UCPU1.AW61
DDR_A_D42: length 23.9
  TOP w0.142: UD20.T11 125.22,31.17 v2(125.22,31.1)
  IN4 w0.117: v2(125.22,31.1) 125.35,31.24 125.35,32.24 125.66,32.55 125.66,32.91 125.46,33.12 125.05,33.12 125.04,33.11 124.98,33.11 124.73,33.36 124.73,35.39 121.5,38.63 121.5,44.93 120.39,46.04 119.03,46.04 118.53,46.53 118.53,46.66 v2(118.14,47.05)
  BOTTOM w0.076: v2(118.14,47.05) 118.77,47.68 118.77,48.64 119.02,48.89 119.02,49.58 UCPU1.BB59
DDR_A_D43: length 27.9
  TOP w0.142: UD20.T10 125.22,30.37 v2(125.22,30.3)
  IN4 w0.117: v2(118.06,48.53) 118.06,48.53 118.06,48.55 118.67,48.55 118.95,48.83 119.76,48.83 120.29,48.29 120.29,48.09 121.8,46.58 121.8,38.75 125.73,34.82 125.73,33.27 125.97,33.04 125.97,32.21 125.66,31.9 125.66,31.1 125.66,31.1 125.66,30.9 125.22,30.46 v2(125.22,30.3)
  BOTTOM w0.076: UCPU1.AW59 118.27,51.64 118.07,51.43 118.07,50.92 118,50.82 118,50.56 118.04,50.44 118.04,50.21 118.03,50.2 118.03,50.2 118.03,50.2 118,50.11 118,49.91 118.03,49.82 118.03,49.46 117.83,49.26 117.83,48.74 118.03,48.53 v2(118.06,48.53)
DDR_A_D44: length 26.8
  TOP w0.142: v2(124.57,28.7) 124.24,29.03 UD20.R8
  IN4 w0.117: v2(124.57,28.7) 124.08,29.18 122.17,29.18 121.52,29.83 121.52,30.66 121.7,30.84 121.7,32.08 121.3,32.47 121.3,34.08 116.96,38.42 116.96,43.83 116.26,44.54 v2(116.23,44.54)
  BOTTOM w0.076: UCPU1.BB61 117.5,49.58 117.5,48.46 116.97,47.94 v3(116.97,46.37) 116.97,45.28 v2(116.23,44.54)
DDR_A_D45: length 29.7
  TOP w0.142: v2(125.22,28.7) 124.89,29.03 UD20.T8
  IN4 w0.117: v2(125.22,28.7) 124.65,28.14 122.51,28.14 121.18,29.47 121.18,29.69 120.93,29.94 120.93,32.18 121,32.25 121,33.95 116.66,38.29 116.66,43.53 v2(116.23,43.95)
  BOTTOM w0.076: UCPU1.AY61 117.8,50.88 117.8,50.62 117.83,50.52 117.84,50.52 117.87,50.43 117.87,50.23 117.83,50.14 117.83,49.89 117.83,49.88 117.87,49.79 117.87,49.53 117.66,49.33 117.66,48.1 v3(117.37,47.81) 117.37,45.41 117.11,45.14 117.11,44.83 v2(116.23,43.95)
DDR_A_D46: length 24.2
  TOP w0.142: UD20.R10 124.24,30.78 v2(124.57,31.1)
  IN4 w0.117: v2(118.11,46.47) 118.16,46.47 118.9,45.73 120.24,45.73 120.65,45.32 120.65,39.04 124.42,35.27 124.42,32.79 125.04,32.17 125.04,31.58 v2(124.57,31.1)
  BOTTOM w0.076: UCPU1.BA59 119.13,49.93 119.19,49.78 119.19,48.83 118.94,48.57 118.94,48.56 118.94,47.29 v2(118.11,46.47)
DDR_A_D47: length 24.2
  TOP w0.142: UD20.R11 124.24,31.56 v2(124.59,31.9)
  IN4 w0.117: v2(118.11,45.88) 118.26,45.88 118.75,45.4 118.8,45.4 118.91,45.28 118.91,45.22 119.03,45.11 119.26,45.11 119.38,45.22 119.38,45.28 119.5,45.4 120.12,45.4 120.35,45.17 120.35,38.91 124.12,35.14 124.12,32.38 124.59,31.9 v2(124.59,31.9)
  BOTTOM w0.076: UCPU1.AY59 118.92,50.78 119.19,50.52 119.19,50.32 119.33,49.89 119.36,49.82 119.36,48.76 119.1,48.5 119.1,48.49 119.1,48.2 119.1,48.2 119.1,48.1 119.1,48.1 119.1,46.87 v3(118.68,46.45) v2(118.11,45.88)
DDR_A_D48: length 29.2
  TOP w0.142: v2(118.07,30.3) 118.04,30.3 117.74,30.6 UD20.E10
  IN4 w0.117: v2(118.07,30.3) 117.47,30.89 117.47,33.14 117.46,33.16 117.46,33.17 117.26,33.36 116.66,33.36 111.46,38.57 111.46,43.44 111.01,43.89 111.01,48.24 111.88,49.12 111.88,51.88 113.11,53.1 v2(114.25,53.1)
  BOTTOM w0.076: v2(114.25,53.1) 114.6,53.45 UCPU1.AT66
DDR_A_D49: length 26.9
  TOP w0.142: UD20.F10 118.39,30.78 v2(118.07,31.1)
  IN4 w0.117: v2(114.25,52.47) 114.25,52.46 113.82,52.03 113.82,51.42 112.19,49.79 112.19,48.99 111.31,48.11 111.31,44.04 112.17,43.19 112.17,38.29 116.79,33.67 117.39,33.67 117.76,33.29 117.76,33.29 117.78,33.27 117.78,31.39 v2(118.07,31.1)
  BOTTOM w0.076: v2(114.25,52.47) 114.58,52.8 UCPU1.AU66
DDR_A_D50: length 29.2
  TOP w0.142: v2(118.72,29.5) 118.39,29.17 UD20.F8
  IN4 w0.076: v2(115.17,54.37) 115.23,54.37 115.55,54.06 115.55,52.86 115.98,52.43 115.98,52.18 116.33,51.82
  IN4 w0.117: 116.33,51.82 116.33,47 115.47,46.14 115.47,38.39 119.86,33.99 119.86,31.56 119.6,31.3 119.6,30.48 118.92,29.8 118.72,29.6 v2(118.72,29.5)
  BOTTOM w0.076: UCPU1.AP65 115.54,54.75 v2(115.17,54.37)
DDR_A_D51: length 33.9
  TOP w0.076: UD20.D9 117.09,29.67 117.43,29.33 117.43,28.43 v2(117.58,28.28)
  IN4 w0.076: v2(115.17,55.01) 115.17,55 115.71,54.45 115.71,52.93 116.38,52.26
  IN4 w0.117: v2(117.58,28.28) 117.58,28.74 117.93,29.1 119.05,29.1 119.33,29.37 119.33,29.68 120.45,30.8 120.45,31.52 120.17,31.8 120.17,34.12 115.77,38.52 115.77,46.01 116.66,46.9 116.66,51.98 116.38,52.26
  BOTTOM w0.076: UCPU1.AN65 115.56,55.4 v2(115.17,55.01)
DDR_A_D52: length 33.1
  TOP w0.142: UD20.E9 117.74,29.83 v2(118.07,29.5)
  IN4 w0.117: v2(114.25,55.01) 114.13,55.01 112.27,53.15 111.25,53.15 109.98,51.87 109.98,39.17 114.52,34.63 114.52,31.95 116.55,29.92 117.65,29.92 v2(118.07,29.5)
  BOTTOM w0.076: UCPU1.AN66 114.65,55.4 v2(114.25,55.01)
DDR_A_D53: length 28.7
  TOP w0.076: UD20.E11 117.41,31.84 117.41,32.62 117.08,32.95 117.08,32.93 v2(117.06,32.93)
  IN4 w0.117: v2(114.25,54.37) 113.94,54.37 111.58,52.01 111.58,49.25 110.29,47.96 110.29,39.3 116.66,32.93 v2(117.06,32.93)
  BOTTOM w0.076: v2(114.25,54.37) 114.63,54.75 UCPU1.AP66
DDR_A_D54: length 27.2
  TOP w0.142: UD20.F9 118.39,29.98 v2(118.72,30.3)
  IN4 w0.076: 115.63,51.95 115.63,52.55 115.17,53.01 v2(115.17,53.1)
  IN4 w0.117: v2(118.72,30.3) 119.29,30.87 119.29,31.42 119.55,31.69 119.55,33.87 115.16,38.26 115.16,43.09 114.28,43.98 114.28,47.26 115.42,48.4 115.42,49.23 115.63,49.44 115.63,51.95
  BOTTOM w0.076: v2(115.17,53.1) 115.51,53.45 UCPU1.AT65
DDR_A_D55: length 26
  TOP w0.076: 118.22,32.84 118.07,32.68 118.07,31.97 118.21,31.83 118.21,31.68 UD20.F11
  TOP w0.142: 118.22,32.84 118.74,33.36 119.04,33.36 v2(119.13,33.45)
  IN4 w0.076: v2(115.17,52.47) 115.29,52.34 115.29,51.86 115.3,51.85
  IN4 w0.117: 115.3,51.85 115.32,51.83 115.32,49.57 115.09,49.34 115.09,48.98 113.23,47.13 113.23,44.35 114.1,43.48 114.1,38.52 118.34,34.27 118.34,33.79 118.69,33.45 v2(119.13,33.45)
  BOTTOM w0.076: UCPU1.AU65 115.5,52.8 v2(115.17,52.47)
DDR_A_D56: length 28.7
  TOP w0.142: v2(123.27,30.3) 122.94,29.98 UD20.N9
  IN1 w0.076: 116.54,50.61 116.52,50.63 116.52,52.55 116.99,53.02 v2(116.99,53.1)
  IN1 w0.117: v2(123.27,30.3) 122.85,29.88 121.75,29.88 121.34,30.29 120.8,30.29 120.5,30.59 120.5,31.91 119.71,32.7 119.71,35.94 117.32,38.33 117.32,49.83 116.54,50.61
  BOTTOM w0.076: v2(116.99,53.1) 117.34,53.45 UCPU1.AT61
DDR_A_D57: length 26.7
  TOP w0.142: UD20.M9 122.29,29.98 v2(122.62,30.3)
  IN1 w0.076: v2(116.99,52.47) 116.69,52.16 116.69,51.06 116.84,50.91 116.84,50.78
  IN1 w0.117: 116.84,50.78 117.63,50 117.63,38.45 120.02,36.06 120.02,32.85 120.81,32.06 120.81,30.72 120.93,30.6 122.32,30.6 v2(122.62,30.3)
  BOTTOM w0.076: UCPU1.AU61 117.33,52.8 v2(116.99,52.47)
DDR_A_D58: length 26.8
  TOP w0.127: UD20.N11 123.27,31.83 123.27,32.79 123.15,32.91 123.15,33.29 v2(123.6,33.74)
  IN1 w0.076: 118.83,52.29 118.83,52.32 118.28,52.87 118.28,54.19 118.09,54.37 v2(117.91,54.37)
  IN1 w0.117: v2(123.6,33.74) 123.6,33.72 123.62,33.75 123.62,35.99 122.04,37.57 122.04,47.53 121.33,48.24 121.33,49.7 120.02,51.01 119.36,51.01 119.08,51.29 119.08,51.83 118.83,52.08 118.83,52.29
  BOTTOM w0.076: UCPU1.AP60 118.29,54.75 v2(117.91,54.37)
DDR_A_D59: length 28.1
  TOP w0.142: v2(123.27,31.1) 123.27,31.03 UD20.N10
  IN1 w0.076: v2(117.91,55.01) 117.95,55.01 118.44,54.52 118.44,52.94 118.8,52.59 118.92,52.59 119.13,52.38
  IN1 w0.117: 119.13,52.38 119.61,51.9 119.71,51.9 121.64,49.98 121.64,48.37 122.35,47.65 122.35,37.69 124.04,36 124.04,32.79 123.36,32.11 123.36,31.2 v2(123.27,31.1)
  BOTTOM w0.076: v2(117.91,55.01) 118.3,55.4 UCPU1.AN60
DDR_A_D60: length 32.3
  TOP w0.142: v2(122.62,28.7) 122.62,28.77 UD20.M8
  IN1 w0.076: 116.03,51.44 116.15,51.57 116.15,52.65 116.46,52.95 116.46,54.59 116.87,55.01 v2(116.99,55.01)
  IN1 w0.117: v2(122.62,28.7) 122.2,29.12 119.85,29.12 119.27,29.7 119.27,31.15 118.91,31.5 118.55,31.5 118.26,31.79 118.26,32.63 118.08,32.8 118.08,36.69 116.71,38.06 116.71,49.57 115.93,50.35 115.93,51.34 116.03,51.44
  BOTTOM w0.076: UCPU1.AN61 117.39,55.4 v2(116.99,55.01)
DDR_A_D61: length 31.5
  TOP w0.142: UD20.P9 123.59,29.97 v2(123.92,30.3)
  IN1 w0.076: 116.23,51.01 116.23,51.25 116.36,51.37 116.36,52.61 116.64,52.9 116.64,54.02 v2(116.99,54.37)
  IN1 w0.117: v2(123.92,30.3) 123.19,29.57 121.62,29.57 121.21,29.98 120.54,29.98 119.58,30.94 119.58,31.73 118.39,32.93 118.39,36.82 117.01,38.19 117.01,49.7 116.23,50.48 116.23,51.01
  BOTTOM w0.076: UCPU1.AP61 117.37,54.75 v2(116.99,54.37)
DDR_A_D62: length 26.7
  TOP w0.142: UD20.M10 122.29,30.78 v2(122.62,31.1)
  IN1 w0.076: 117.91,53.01 118.47,52.45 118.47,51.75
  IN1 w0.117: v2(122.62,31.1) 123.04,31.53 123.04,32.37 123.17,32.49 123.17,36.01 121.74,37.44 121.74,39.71 121.62,39.82 121.14,39.82 121.02,39.94 121.02,40.17 121.14,40.29 121.62,40.29 121.74,40.41 121.74,46.75 120.42,48.07 120.42,49.51 118.47,51.47 118.47,51.75 ; v2(117.91,53.1) 117.91,53.01
  BOTTOM w0.076: v2(117.91,53.1) 118.26,53.45 UCPU1.AT60
DDR_A_D63: length 26
  TOP w0.127: v2(122.62,31.9) 122.39,31.67 122.39,31.6 UD20.M11
  IN1 w0.117: v2(122.62,31.9) 122.74,32.02 122.74,32.6 122.86,32.72 122.86,35.88 120.65,38.09 120.65,38.82 120.77,38.93 121.34,38.93 121.43,39.03 121.43,39.31 121.34,39.4 120.77,39.4 120.65,39.52 120.65,45.83 120.77,45.94 121.07,45.94 121.18,46.06 121.18,46.29 121.07,46.41 120.77,46.41 120.65,46.53 120.65,47.12 120.66,47.13 120.66,47.39 120.11,47.94 120.11,49.38 118.15,51.35 118.15,52.23 v2(117.91,52.47)
  BOTTOM w0.076: v2(117.91,52.47) 118.24,52.8 UCPU1.AU60
DDR_A_DQS0: length 48.8
  TOP w0.122: UD19.D10 101.57,30.63 v2(101.25,30.3)
  IN1 w0.114: v2(108.62,55.57) 108.41,55.78 108.41,55.94 108.18,56.18 106.38,56.18 105.52,57.03 102.13,57.03 97.84,52.73 97.84,51.36 98.07,51.13 99.05,51.13 99.17,51.01 99.17,50.78 99.05,50.67 98.07,50.67 97.84,50.44 97.84,50.04 98.07,49.81 99.05,49.81 99.17,49.69 99.17,49.46 99.05,49.35 98.07,49.35 97.73,49.01 97.73,32.39 99.69,30.43 101.12,30.43 v2(101.25,30.3)
  BOTTOM w0.076: v2(108.62,55.57) 108.43,55.39 108.43,55.28 108.52,55.19 109.01,55.19 109.58,55.77 109.96,55.77 110.52,56.33 110.95,56.33 111.04,56.24 111.58,56.24 111.6,56.24 111.71,56.29 111.92,56.29 112.03,56.24 112.25,56.24 112.33,56.28 112.61,56.28 112.82,56.18 112.88,56.12 112.88,56.12 113.06,55.94 UCPU1.AM69
DDR_A_DQS1: length 33.7
  TOP w0.076: UD19.P10 108.07,30.56 108.16,30.47 108.34,30.47 108.41,30.54 v2(108.41,31.1)
  IN4 w0.114: v2(108.41,31.1) 108.2,30.89 108.2,30.76 108.37,30.59 110.71,30.59 110.83,30.71 111.05,30.71 111.29,30.94 111.29,33.1 110.21,34.18 110.21,34.54 106.75,38 106.75,48.68 108.13,50.06 108.13,50.59 108.37,50.83 108.66,50.83 v2(108.86,51.04)
  BOTTOM w0.076: v2(108.86,51.04) 109,50.9 109.18,50.9 109.78,51.49 109.78,52.36 110.48,53.07 110.94,53.07 111.14,53.26 111.61,53.26 111.66,53.24 111.76,53.21 111.88,53.21 111.96,53.24 112,53.26 112.27,53.26 112.35,53.22 112.57,53.22 112.7,53.28 112.72,53.3 112.72,53.45 112.67,53.49 UCPU1.AT70
DDR_A_DQS2: length 39.5
  TOP w0.122: v2(106.45,31.1) 106.12,30.78 UD19.L10
  IN1 w0.076: 113.63,57.86 113.64,57.88 113.67,57.88 113.86,58.07 115.32,58.07 115.48,57.91 115.48,57.73 v2(115.7,57.51)
  IN1 w0.114: v2(106.45,31.1) 106.3,31.1 105.78,31.63 105.78,34.6 105.66,34.72 105.38,34.72 105.15,34.95 105.15,35.35 105.38,35.58 105.66,35.58 105.78,35.7 105.78,35.92 105.66,36.04 105.38,36.04 105.15,36.27 105.15,36.67 105.38,36.9 105.91,36.9 106.04,37.03 106.04,37.23 105.91,37.36 105.38,37.36 105.15,37.59 105.15,37.99 105.38,38.22 106.04,38.22 106.16,38.35 106.16,38.55 106.04,38.68 105.38,38.68 105.15,38.91 105.15,39.31 105.38,39.54 105.66,39.54 105.78,39.66 105.78,39.89 105.66,40 105.38,40 105.15,40.23 105.15,40.63 105.38,40.87 105.66,40.87 105.78,40.98 105.78,42.09 108.38,44.7 108.38,45.46 111.6,48.68 111.6,51.23 112.42,52.05 112.42,54.93 112.85,55.36 112.85,57.09 113.63,57.86
  BOTTOM w0.076: UCPU1.AH65 115.39,57.82 v2(115.7,57.51)
DDR_A_DQS3: length 45.3
  TOP w0.122: UD19.G10 103.57,30.75 103.57,30.95 103.41,31.1 v2(103.2,31.1)
  IN4 w0.114: v2(103.2,31.1) 103.2,31.39 103.27,31.47 103.64,31.47 103.98,31.8 103.98,33.89 102.22,35.65 101.83,35.65 98.92,38.56 98.92,47.09 99.04,47.21 99.31,47.21 99.54,47.44 99.54,47.84 99.31,48.07 99.04,48.07 98.92,48.19 98.92,48.42 99.04,48.53 99.28,48.53 99.52,48.76 99.52,49.16 99.28,49.39 99.04,49.39 98.92,49.51 98.92,54.5 102.8,58.38 107.82,58.38 107.94,58.26 107.94,58.03 v2(107.75,57.84)
  BOTTOM w0.076: UCPU1.AG70 112.59,58.37 112.59,58.29 112.53,58.23 112.35,58.23 112.27,58.27 112,58.27 111.89,58.22 111.73,58.22 111.63,58.27 110.3,58.27 110.13,58.43 108.19,58.43 108.03,58.27 108.03,58.03 107.84,57.84 v2(107.75,57.84)
DDR_A_DQS4: length 26.3
  TOP w0.122: UD20.D10 117.09,30.63 v2(116.77,30.3)
  IN1 w0.114: v2(113.77,46.06) 113.57,45.86 113.34,45.86 113.11,45.62 113.11,38.4 114.65,36.86 114.65,36.58 114.88,36.35 115.18,36.35 115.29,36.24 115.29,36.01 115.18,35.89 114.88,35.89 114.42,35.43 114.42,32.09 115.17,31.35 115.17,31.19 115.86,30.49 116.57,30.49 v2(116.77,30.3)
  BOTTOM w0.076: v2(113.77,46.06) 113.79,46.06 113.95,45.9 114.09,45.9 114.17,45.98 114.17,47.31 115.34,48.47 115.34,49.36 115.51,49.54 115.51,49.79 115.46,49.9 115.46,50.12 115.51,50.23 115.51,50.44 115.48,50.52 115.48,50.81 115.56,50.99 115.65,51.08 115.77,51.08 115.81,51.12 UCPU1.AY64
DDR_A_DQS5: length 28.3
  TOP w0.122: UD20.P10 123.59,30.77 v2(123.92,31.1)
  IN4 w0.076: 123.28,34.39 123.28,34.37 123.3,34.35 123.3,34.26 122.93,33.9 122.93,32.66 123.16,32.43 123.16,31.74 123.46,31.44 123.79,31.44 123.92,31.31 v2(123.92,31.1)
  IN4 w0.114: v2(118.11,44.13) 118.29,44.31 118.54,44.31 118.72,44.13 118.72,40.78 118.95,40.55 119.61,40.55 119.72,40.43 119.72,40.2 119.61,40.09 118.95,40.09 118.72,39.86 118.72,39.34 118.97,39.09 118.97,38.93 118.61,38.57 118.61,38.24 118.89,37.96 119.22,37.96 119.58,38.32 119.74,38.32 123.28,34.78 123.28,34.39
  BOTTOM w0.076: UCPU1.BA60 118.26,50.87 118.26,50.97 118.3,51.01 118.36,51.01 118.47,50.9 118.53,50.77 118.53,50.55 118.49,50.47 118.49,50.19 118.55,50.06 118.55,49.96 118.46,49.74 118.46,49.43 118.63,49.26 118.63,48.96 118.44,48.78 118.44,48.3 117.54,47.4 117.54,45.35 117.36,45.16 117.36,44.62 117.65,44.33 117.91,44.33 v2(118.11,44.13)
DDR_A_DQS6: length 29.7
  TOP w0.122: v2(118.72,31.1) 119.04,30.78 UD20.G10
  IN4 w0.076: v2(115.17,53.74) 115.17,53.66 114.78,53.27 114.78,51.41 114.58,51.21 114.58,51.18 114.57,51.17 ; v2(118.72,31.1) 119.1,31.49 119.1,32.13 118.53,32.71 118.53,33.34 117.96,33.91 117.96,33.93 117.95,33.95
  IN4 w0.114: 117.95,33.95 117.91,33.99 117.91,34.09 117.24,34.76 117.12,34.76 113.13,38.74 113.13,39.4 113.25,39.51 113.44,39.51 113.68,39.75 113.68,40.14 113.44,40.38 113.25,40.38 113.13,40.49 113.13,40.72 113.25,40.83 113.44,40.83 113.68,41.07 113.68,41.47 113.44,41.7 113.25,41.7 113.13,41.81 113.13,43.15 111.94,44.34 111.94,47.84 114.2,50.1 114.2,50.8 114.57,51.17
  BOTTOM w0.076: UCPU1.AR65 115.53,54.1 v2(115.17,53.74)
DDR_A_DQS7: length 29.8
  TOP w0.122: v2(121.32,31.1) 121.64,30.78 UD20.L10
  IN1 w0.076: v2(117.91,53.74) 117.55,53.37 117.55,52.02 117.69,51.88 117.69,51.3 117.7,51.29 117.7,51.27
  IN1 w0.114: v2(121.32,31.1) 121.59,31.38 121.85,31.38 122.05,31.57 122.05,32.15 121.55,32.64 121.55,36.37 120.09,37.83 120.09,39.2 119.73,39.55 118.47,39.55 118.35,39.68 118.35,39.87 118.47,39.99 119.97,39.99 120.21,40.23 120.21,40.63 119.97,40.86 119.28,40.86 119.16,40.97 119.16,44.91 118.85,45.23 118.85,49.67 117.7,50.81 117.7,51.27
  BOTTOM w0.076: UCPU1.AR60 118.27,54.1 v2(117.91,53.74)
DDR_A_DQS#0: length 48.8
  TOP w0.122: v2(101.25,31.1) 101.32,31.03 101.65,31.03 101.75,31.13 101.75,31.32 UD19.D11
  IN1 w0.114: v2(101.25,31.1) 101.25,30.83 101.06,30.63 99.78,30.63 97.94,32.48 97.94,48.93 98.15,49.14 99.14,49.14 99.37,49.38 99.37,49.78 99.14,50.01 98.15,50.01 98.04,50.12 98.04,50.35 98.15,50.47 99.14,50.47 99.37,50.7 99.37,51.1 99.14,51.33 98.15,51.33 98.04,51.44 98.04,52.65 102.22,56.83 105.44,56.83 106.29,55.97 108.09,55.97 108.2,55.86 108.2,55.68 108.09,55.57 v2(108.03,55.57)
  BOTTOM w0.076: UCPU1.AM70 112.63,55.84 112.72,55.93 112.72,56.03 112.69,56.06 112.57,56.11 112.36,56.11 112.28,56.08 112,56.08 111.87,56.13 111.76,56.13 111.66,56.09 111.62,56.07 110.97,56.07 110.88,56.16 110.59,56.16 110.03,55.6 109.65,55.6 109.07,55.03 108.46,55.03 108.27,55.21 108.27,55.33 v2(108.03,55.57)
DDR_A_DQS#1: length 33.8
  TOP w0.122: v2(107.76,31.1) 108.07,31.41 UD19.P11
  IN4 w0.114: v2(108.86,50.45) 108.69,50.63 108.46,50.63 108.33,50.5 108.33,49.97 106.95,48.59 106.95,38.09 110.42,34.62 110.42,34.26 111.49,33.19 111.49,30.86 111.13,30.5 110.91,30.5 110.8,30.39 108.28,30.39 107.99,30.67 107.99,30.87 v2(107.76,31.1)
  BOTTOM w0.076: UCPU1.AT69 112.94,53.49 112.88,53.43 112.88,53.23 112.8,53.15 112.61,53.06 112.32,53.06 112.24,53.09 112.03,53.09 111.92,53.04 111.73,53.04 111.61,53.08 111.58,53.09 111.2,53.09 111.01,52.9 110.55,52.9 109.94,52.29 109.94,51.43 109.25,50.74 109.15,50.74 v2(108.86,50.45)
DDR_A_DQS#2: length 39.5
  TOP w0.122: v2(106.45,31.9) 106.12,31.57 UD19.L11
  IN1 w0.076: 113.77,57.72 113.78,57.73 113.78,57.75 113.81,57.79 113.81,57.79 113.93,57.91 115.25,57.91 115.32,57.84 115.32,57.67 115.15,57.51 v2(115.07,57.51)
  IN1 w0.114: 113.77,57.72 113.06,57 113.06,55.28 112.62,54.85 112.62,51.96 111.81,51.15 111.81,48.59 108.59,45.37 108.59,44.61 105.98,42.01 105.98,40.9 105.75,40.66 105.46,40.66 105.35,40.55 105.35,40.32 105.46,40.2 105.75,40.2 105.98,39.97 105.98,39.57 105.75,39.34 105.46,39.34 105.35,39.23 105.35,39 105.46,38.88 106.12,38.88 106.37,38.64 106.37,38.27 106.12,38.02 105.46,38.02 105.35,37.91 105.35,37.68 105.46,37.56 106,37.56 106.24,37.32 106.24,36.95 106,36.7 105.46,36.7 105.35,36.59 105.35,36.36 105.46,36.24 105.75,36.24 105.98,36.01 105.98,35.61 105.75,35.38 105.46,35.38 105.35,35.26 105.35,35.04 105.46,34.92 105.75,34.92 105.98,34.69 105.98,31.71 106.21,31.47 106.4,31.47 106.52,31.59 106.52,31.82 v2(106.45,31.9)
  BOTTOM w0.076: UCPU1.AH66 114.74,58 114.81,58.07 115.03,58.07 115.11,58 115.11,57.55 v2(115.07,57.51)
DDR_A_DQS#3: length 45.3
  TOP w0.122: UD19.G11 103.52,31.58 v2(103.2,31.9)
  IN4 w0.114: v2(103.2,31.9) 103.43,31.67 103.55,31.67 103.77,31.89 103.77,33.81 102.13,35.45 101.75,35.45 98.72,38.47 98.72,47.18 98.95,47.41 99.23,47.41 99.34,47.53 99.34,47.76 99.23,47.87 98.95,47.87 98.72,48.1 98.72,48.5 98.95,48.73 99.2,48.73 99.31,48.85 99.31,49.08 99.2,49.19 98.95,49.19 98.72,49.42 98.72,54.58 102.72,58.58 107.9,58.58 108.14,58.34 108.14,58.1 v2(108.4,57.84)
  BOTTOM w0.076: UCPU1.AG69 112.93,58.4 112.6,58.06 112.32,58.06 112.24,58.1 112.03,58.1 111.93,58.05 111.69,58.05 111.59,58.1 110.23,58.1 110.06,58.27 108.26,58.27 108.19,58.2 108.19,58.05 v2(108.4,57.84)
DDR_A_DQS#4: length 26.4
  TOP w0.122: UD20.D11 117.09,31.21 116.99,31.1 v2(116.77,31.1)
  IN1 w0.114: v2(113.8,45.47) 113.62,45.65 113.42,45.65 113.31,45.54 113.31,38.48 114.85,36.94 114.85,36.67 114.96,36.55 115.26,36.55 115.5,36.32 115.5,35.92 115.26,35.69 114.96,35.69 114.62,35.35 114.62,32.18 115.37,31.43 115.37,31.27 115.95,30.7 116.75,30.7 116.83,30.78 116.83,31.04 v2(116.77,31.1)
  BOTTOM w0.076: v2(113.8,45.47) 113.8,45.58 113.95,45.74 114.16,45.74 114.34,45.92 114.34,47.24 115.5,48.4 115.5,49.3 115.68,49.47 115.68,49.83 115.62,49.94 115.62,50.06 115.68,50.19 115.68,50.47 115.64,50.55 115.64,50.77 115.7,50.9 115.72,50.91 115.87,50.91 115.91,50.87 UCPU1.BA64
DDR_A_DQS#5: length 28.2
  TOP w0.076: v2(123.92,31.91) 123.74,31.91 123.59,31.76 123.59,31.5 UD20.P11
  IN4 w0.076: v2(123.92,31.91) 123.92,31.68 123.86,31.61 123.53,31.61 123.32,31.81 123.32,32.5 123.1,32.73 123.1,33.83 123.46,34.2 123.46,34.35 123.48,34.37 123.48,34.39
  IN4 w0.114: v2(118.11,44.71) 118.31,44.51 118.63,44.51 118.92,44.21 118.92,40.87 119.04,40.75 119.69,40.75 119.93,40.52 119.93,40.12 119.69,39.89 119.04,39.89 118.92,39.77 118.92,39.42 119.17,39.17 119.17,38.84 118.81,38.48 118.81,38.32 118.98,38.16 119.14,38.16 119.5,38.52 119.83,38.52 123.48,34.87 123.48,34.39
  BOTTOM w0.076: v2(118.11,44.71) 117.89,44.5 117.72,44.5 117.53,44.69 117.53,45.1 117.71,45.28 117.71,47.33 118.61,48.23 118.61,48.71 118.79,48.9 118.79,49.33 118.63,49.49 118.63,49.71 118.71,49.92 118.71,50.12 118.66,50.23 118.66,50.44 118.69,50.52 118.69,50.81 118.61,50.99 118.36,51.24 UCPU1.AY60
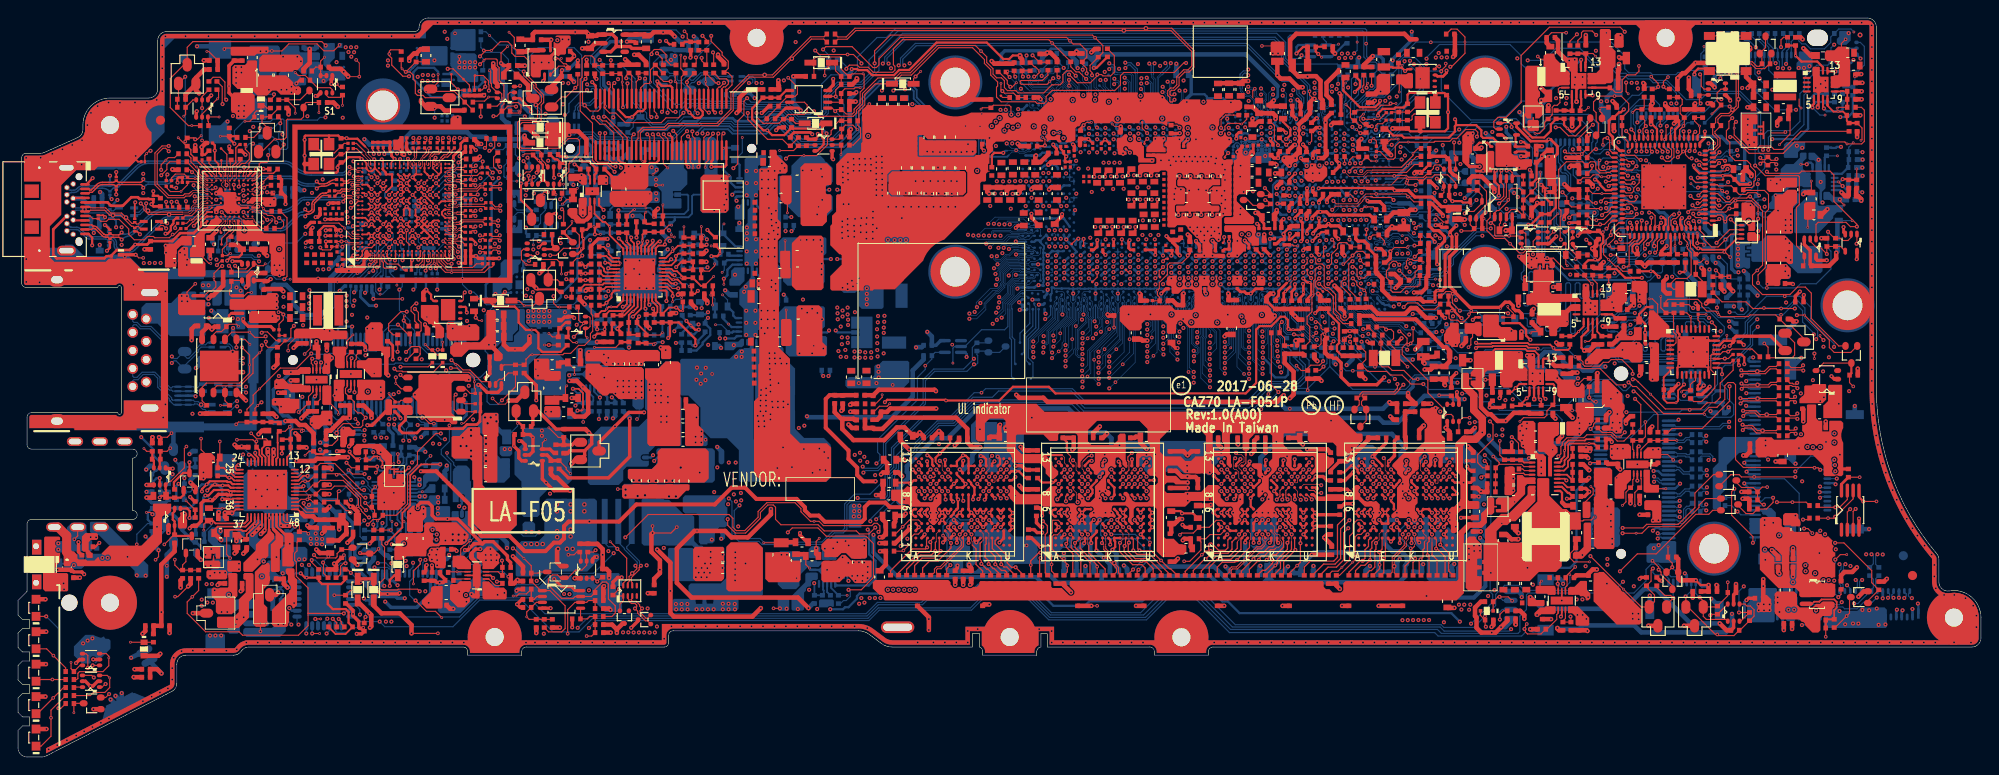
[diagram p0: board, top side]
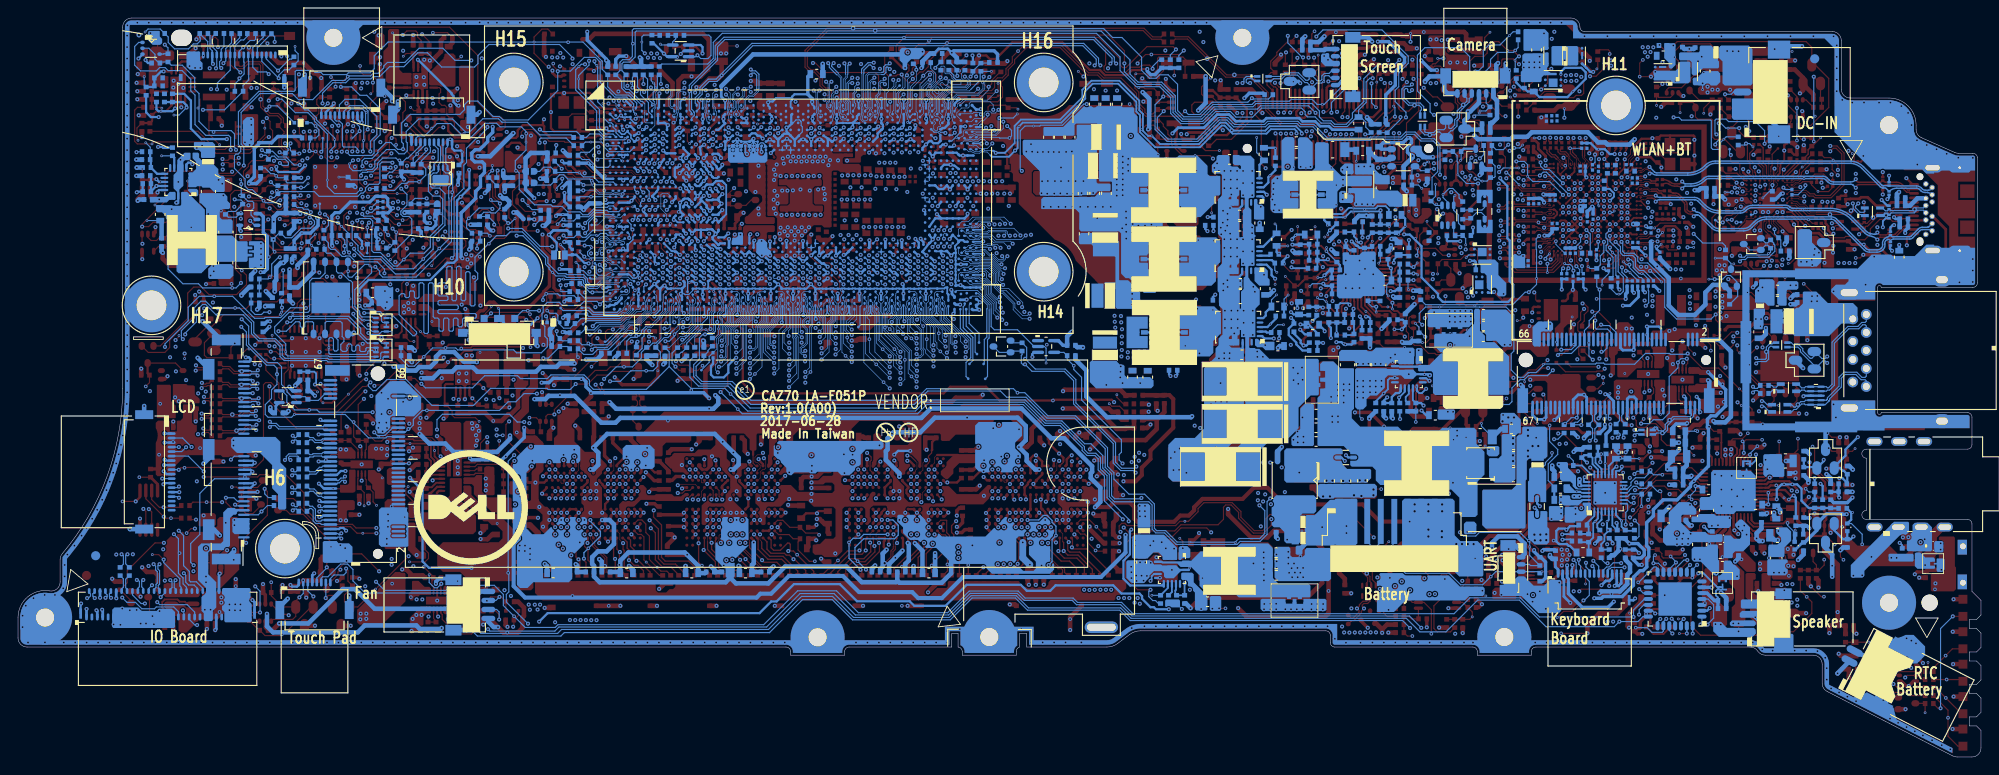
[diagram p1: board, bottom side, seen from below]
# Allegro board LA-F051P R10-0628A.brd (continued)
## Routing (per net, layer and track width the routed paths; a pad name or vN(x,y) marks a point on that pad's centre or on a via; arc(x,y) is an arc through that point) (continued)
DDR_A_DQS#6: length 29.6
  TOP w0.122: UD20.G11 119.04,31.58 v2(118.72,31.9)
  IN4 w0.076: v2(114.25,53.74) 114.25,53.76 114.38,53.88 114.71,53.88 114.79,53.8 114.79,53.51 114.61,53.34 114.61,51.48 114.46,51.33 114.44,51.33 114.42,51.31 ; v2(118.72,31.9) 118.72,32.28 118.36,32.64 118.36,33.27 117.85,33.79 117.82,33.79 117.81,33.8
  IN4 w0.114: 114.42,51.31 114,50.89 114,50.18 111.74,47.92 111.74,44.26 112.93,43.06 112.93,41.73 113.16,41.5 113.36,41.5 113.47,41.38 113.47,41.15 113.36,41.04 113.16,41.04 112.93,40.8 112.93,40.41 113.16,40.17 113.36,40.17 113.47,40.06 113.47,39.83 113.36,39.72 113.16,39.72 112.93,39.48 112.93,38.66 117.04,34.55 117.16,34.55 117.7,34.01 117.7,33.9 117.81,33.8
  BOTTOM w0.076: UCPU1.AR66 114.81,54 114.81,53.82 114.74,53.74 v2(114.25,53.74)
DDR_A_DQS#7: length 29.7
  TOP w0.122: v2(121.32,31.9) 121.64,31.58 UD20.L11
  IN1 w0.076: 117.5,51.27 117.5,51.29 117.52,51.3 117.52,51.81 117.38,51.95 117.38,53.35 v2(116.99,53.74)
  IN1 w0.114: v2(121.32,31.9) 121.32,31.77 121.51,31.58 121.77,31.58 121.84,31.66 121.84,32.06 121.35,32.56 121.35,36.29 119.89,37.75 119.89,39.11 119.65,39.35 118.39,39.35 118.14,39.6 118.14,39.95 118.39,40.2 119.89,40.2 120,40.31 120,40.54 119.89,40.66 119.19,40.66 118.96,40.89 118.96,44.83 118.65,45.14 118.65,49.58 117.5,50.73 117.5,51.27
  BOTTOM w0.076: v2(116.99,53.74) 117.38,53.74 117.45,53.82 UCPU1.AR61
DDR_A_ODT0: length 76.4
  TOP w0.142: UD20.J8 120.34,29.03 v2(120.67,28.7) ; v2(113.72,26.17) 114.22,25.67 114.22,24.91 113.98,24.68 113.98,20.44 RD117.1 ; v2(104.88,28.42) 104.82,28.48 UD19.J8
  IN1 w0.117: v2(126.19,53.13) 126.08,53.13 125.73,53.48 125.73,55.2 124.77,56.17 123.24,56.17 122.96,55.89 122.96,52.1 122.69,51.84 122.69,49.84 122.39,49.54 122.39,48.68 123.1,47.96 123.1,38.01 125.68,35.43 125.68,32.98 126.54,32.11 126.54,29.44 125.04,27.94 118.56,27.94 118.29,27.67 114.48,27.67 114.12,27.31 114.12,26.58 v2(113.72,26.17)
  IN4 w0.117: v2(104.88,28.42) 105.35,27.95 108.71,27.95 109.15,27.52 109.22,27.52 109.25,27.49 110.23,27.49 110.23,27.49 110.57,27.49 110.57,27.49 112.17,27.49 113.44,26.22 113.67,26.22 v2(113.72,26.17) 113.79,26.17 114.15,26.53 114.15,27.29 114.61,27.75 117.04,27.75 117.27,27.52 120.93,27.52 121.06,27.64 121.06,28.31 v2(120.67,28.7)
  BOTTOM w0.142: UCPU1.AT45 126.6,53.43 126.3,53.13 v2(126.19,53.13)
DDR_B0_ZQ0: length 6.9
  TOP w0.127: v3(129.39,21.72) 130.01,21.72 131.26,22.97 131.26,23.87 131.04,24.09 RD57.1 131.8,24.22 132.27,24.68 133.43,24.68 UD21.B3
DDR_B0_ZQ1: length 5.8
  TOP w0.127: UD21.B4 133.85,25.95 133.54,26.27 132.95,26.27 132.17,25.49 RD58.1 130.4,24.85 129.13,24.85 v3(128.93,24.65)
DDR_B1_ZQ0: length 6.7
  TOP w0.127: UD22.B3 149.01,24.69 148.64,24.69 148.36,24.42 148.36,21.88 v1(148.11,21.63) 146.63,20.15 RD55.1
DDR_B1_ZQ1: length 8.8
  TOP w0.127: UD22.B4 149.02,26.3 148.59,26.3 148.14,25.85 148.14,24.91 147.75,24.51 147.75,21.9 v1(146.9,21.05) 146.46,20.62 145.81,20.62 145.39,20.19 RD56.1
DDR_B_CA1_0: length 52
  TOP w0.142: RD60.1 141.07,20.38 v3(141.93,21.24) 142.29,21.6 142.29,23.72 v2(142.3,23.72) 142.3,23.72 142.3,24.3 UD21.R2
  IN4 w0.117: v2(142.3,23.72) 141.87,23.72 140.84,22.69 135.66,22.69 135.03,23.32 133.12,23.32 130.27,26.17 130.27,32.55 130.14,32.67 129.94,32.67 129.82,32.79 129.82,32.98 129.95,33.11 130.14,33.11 130.27,33.23 130.27,33.84 130.09,34.02 129.74,34.02 129.61,34.15 129.61,35.79 125.19,40.21 125.19,40.77 125.31,40.9 125.54,40.9 125.76,40.68 125.97,40.68 126.19,40.9 126.48,40.9 126.61,41.02 126.61,41.21 126.48,41.34 125.32,41.34 125.19,41.46 125.19,42.92 125.31,43.04 126.53,43.04 126.61,43.12 126.61,43.45 126.53,43.53 125.91,43.53 125.72,43.72 125.72,46.71 125.6,46.82 v2(125.3,46.82)
  BOTTOM w0.076: v2(125.3,46.82) 125.88,47.41 125.88,48.37 125.27,48.98 125.27,50.73 UCPU1.AY48
DDR_B_CA1_1: length 50.1
  TOP w0.142: RD62.1 140.44,20.41 140.44,21.68 v2(141.73,22.97) 141.65,23.05 141.65,24.3 UD21.P2
  IN4 w0.076: 123.8,51.47 123.8,54.06 123.49,54.37 v2(123.4,54.37)
  IN4 w0.117: 123.8,51.47 124.88,50.39 124.88,40.08 129.3,35.66 129.3,28.26 129.96,27.6 129.96,26.04 133,23.01 134.9,23.01 135.53,22.38 141.14,22.38 v2(141.73,22.97)
  BOTTOM w0.076: v2(123.4,54.37) 123.77,54.75 UCPU1.AP50
DDR_B_CA1_2: length 51.5
  TOP w0.127: v2(140.85,23.77) 141,23.92 UD21.N2
  TOP w0.142: RD64.1 v3(139.5,21.25) 139.75,21.49 139.75,21.94 140.85,23.04 v2(140.85,23.77)
  IN4 w0.117: v2(125.3,48.04) 125.3,48.55 125.43,48.68 126.04,48.68 126.17,48.55 126.17,48.35 126.04,48.23 125.94,48.23 125.81,48.1 125.81,47.86 125.94,47.74 126.51,47.74 126.62,47.63 126.62,47.28 126.5,47.16 126.45,47.16 126.33,47.05 126.33,46.81 126.45,46.7 126.5,46.7 126.62,46.58 126.62,46.35 126.5,46.23 126.45,46.23 126.33,46.11 126.33,45.88 126.45,45.76 126.5,45.76 126.62,45.65 126.62,45.41 126.5,45.29 126.45,45.29 126.33,45.18 126.33,44.94 126.45,44.83 126.5,44.83 126.62,44.71 126.62,44.29 126.76,44.15 126.99,44.15 127.23,43.91 127.23,42.54 127.1,42.41 125.93,42.41 125.8,42.29 125.8,42.09 125.93,41.96 127.13,41.96 127.23,41.86 127.23,40.32 127.11,40.2 126.56,40.2 126.43,40.07 126.43,39.86 126.56,39.73 127.11,39.73 127.23,39.62 127.23,39.04 130.89,35.38 130.89,35.23 130.77,35.12 130.34,35.12 130.23,35 130.23,34.77 130.34,34.65 130.77,34.65 130.89,34.53 130.89,26.43 133.38,23.93 135.28,23.93 135.92,23.3 140.38,23.3 v2(140.85,23.77)
  BOTTOM w0.076: UCPU1.BA48 124.75,50.07 124.75,48.59 v2(125.3,48.04)
DDR_B_CA1_3: length 49.9
  TOP w0.076: 141.3,23.89 141.33,23.92 v2(141.33,24.7)
  TOP w0.142: UD21.N3 141,25.03 v2(141.33,24.7) ; RD66.1 140.08,20.94 140.08,21.8 141.3,23.02 141.3,23.89
  IN4 w0.117: v2(141.33,24.7) 141.5,24.52 141.5,23.79 140.71,22.99 135.79,22.99 135.16,23.63 133.25,23.63 130.58,26.3 130.58,34.1 130.35,34.33 130.02,34.33 129.92,34.43 129.92,35.92 126.11,39.72 126.11,40.39 126.31,40.58 126.79,40.58 126.92,40.71 126.92,41.52 126.79,41.65 125.62,41.65 125.5,41.77 125.5,42.58 125.64,42.73 126.79,42.73 126.92,42.86 126.92,43.68 126.76,43.84 126.14,43.84 126.03,43.95 126.03,47.24 125.83,47.43 v2(125.3,47.43)
  BOTTOM w0.076: UCPU1.BB48 124.99,49.66 124.99,48.9 125.71,48.19 125.71,47.84 v2(125.3,47.43)
DDR_B_CA1_4: length 55
  TOP w0.142: v2(140.68,24.7) 140.68,24.77 UD21.M3 ; v2(139.21,21.83) 139.21,21.52 139.1,21.42 139.1,21.41 138.41,20.71 138.07,20.71 RD68.1
  IN2 w0.102: v2(140.68,24.7) 140.31,24.33 140.31,22.93 v2(139.21,21.83)
  IN4 w0.076: 124.18,51.95 123.97,52.17 123.97,54.02 v2(124.32,54.37)
  IN4 w0.117: v2(140.68,24.7) 140.79,24.59 140.79,24.31 140.6,24.11 140.06,24.11 139.78,24.39 139.78,24.99 139.66,25.1 139.43,25.1 139.31,24.99 139.31,24.36 139.19,24.24 133.51,24.24 131.19,26.55 131.19,35.51 127.53,39.17 127.53,48.03 126.92,48.65 126.92,48.8 126.77,48.95 126.31,48.95 126.19,49.08 126.19,49.36 126.31,49.49 126.68,49.49 126.84,49.64 126.84,49.82 126.49,50.18 126.31,50.18 125.68,49.55 125.5,49.55 125.35,49.7 125.35,49.88 125.96,50.49 125.96,50.65 125.8,50.82 125.63,50.82 125.34,50.53 125.18,50.53 125.01,50.69 125.01,50.86 125.3,51.15 125.3,51.32 124.67,51.95 124.18,51.95
  BOTTOM w0.076: UCPU1.AP48 124.7,54.75 v2(124.32,54.37)
DDR_B_CA1_5: length 51.9
  TOP w0.076: 136.63,23.8 136.63,24 136.76,24.13 136.76,24.79 UD21.F3
  TOP w0.142: RD70.1 133.07,21.06 133.61,21.6 135.02,21.6 v2(135.25,21.84) 135.25,21.85 136.63,23.24 136.63,23.8
  IN4 w0.076: 122.87,51.55 122.87,54.09 122.58,54.37 v2(122.48,54.37)
  IN4 w0.117: 122.87,51.55 122.87,50.91 123.51,50.27 124.27,49.52 124.27,39.83 128.64,35.45 128.64,23.35 128.81,23.19 129.26,23.19 129.88,23.81 130.09,23.81 130.66,23.24 130.66,23.05 130.1,22.49 130.1,22.35 130.28,22.17 130.42,22.17 130.95,22.69 131.92,22.69 132.25,22.36 132.25,22.02 132.38,21.89 132.63,21.89 132.75,22.02 132.75,22.29 132.85,22.39 134.71,22.39 v2(135.25,21.84)
  BOTTOM w0.142: UCPU1.AP52 122.86,54.75 v2(122.48,54.37)
DDR_B_CA1_6: length 55.6
  TOP w0.076: 135.29,23.8 135.29,23.85 135.31,23.87 135.31,23.92 135.48,24.09 v2(135.48,24.7)
  TOP w0.142: UD21.E3 135.8,25.02 v2(135.48,24.7) ; RD72.1 131.29,20.63 132.93,22.27 134.4,22.27 135.29,23.15 135.29,23.8
  IN4 w0.076: v2(123.4,55.01) 123.66,54.75 124.55,54.75 124.74,54.56
  IN4 w0.117: v2(135.48,24.7) 135.55,24.77 135.55,24.98 135.43,25.11 133.12,25.11 131.5,26.73 131.5,35.64 127.84,39.3 127.84,48.18 128.56,48.9 128.56,49.52 128.44,49.64 127.49,49.64 127.36,49.76 127.36,49.98 127.49,50.11 128.46,50.11 128.56,50.2 128.56,50.54 128.46,50.63 127.31,50.63 127.11,50.43 126.66,50.43 126.54,50.56 126.54,50.88 126.66,51 127.08,51 127.22,51.14 128.24,51.14 128.41,51.31 128.41,51.54 128.03,51.92 126.56,51.92 126.43,51.8 126.43,51.31 126.31,51.18 125.88,51.18 125.71,51.34 125.71,51.51 126,51.8 126,51.97 125.84,52.13 125.67,52.13 125.38,51.84 125.21,51.84 124.82,52.23 124.82,54.48 124.74,54.56
  BOTTOM w0.142: v2(123.4,55.01) 123.79,55.4 UCPU1.AN50
DDR_B_CA1_7: length 56.1
  TOP w0.142: RD74.1 132.18,21.05 133.07,21.94 134.59,21.94 135.69,23.04 135.69,24.19 UD21.E2 135.92,24.42 135.92,24.49 v2(136.14,24.7)
  IN4 w0.117: v2(136.14,24.7) 136.14,25.17 136.27,25.3 137.02,25.3 137.15,25.43 137.15,25.76 137.02,25.89 135.31,25.89 135.3,25.89 135.28,25.89 135.25,25.92 134.94,25.92 134.82,26.03 134.82,26.57 134.71,26.69 134.47,26.69 134.36,26.57 134.36,26.06 134.23,25.93 133.93,25.93 133.81,26.06 133.81,26.57 133.69,26.69 133.42,26.69 133.3,26.57 133.3,26.26 133.23,26.2 132.95,26.2 131.81,27.33 131.81,35.76 128.15,39.42 128.15,48.05 128.87,48.77 128.87,49.28 128.98,49.4 129.83,49.4 129.95,49.51 129.95,49.75 129.83,49.86 128.98,49.86 128.87,49.98 128.87,50.21 128.98,50.33 129.83,50.33 129.95,50.45 129.95,50.68 129.83,50.8 128.98,50.8 128.87,50.92 128.87,51.52 127.53,52.85 127.53,55.83 127.24,56.13 125.55,56.13 124.56,55.14 v2(124.3,55.14)
  BOTTOM w0.142: v2(124.3,55.14) 124.54,55.14 124.77,55.36 UCPU1.AN48
DDR_B_CA1_8: length 49.4
  TOP w0.142: UD21.D2 135.14,24.3 134.73,23.89 134.73,23.88 134.71,23.86 134.71,23.06 134.25,22.61 132.77,22.61 132.56,22.4 132.22,22.4 v2(131.77,21.95) 131.77,21.96 131.67,21.96 130.4,20.69 RD76.1
  IN4 w0.117: v2(121.57,55.01) 121.91,55.01 122.02,54.9 122.02,52.18 122.48,51.72 122.48,50.87 123.21,50.15 123.21,50.14 123.96,49.39 123.96,49.19 123.65,48.88 123.65,48.59 123.96,48.27 123.96,39.7 128.34,35.32 128.34,23.1 128.56,22.88 129.39,22.88 129.91,23.4 130.07,23.4 130.24,23.23 130.24,23.07 129.68,22.51 129.68,22.33 130.19,21.82 130.51,21.82 131.07,22.39 131.66,22.39 131.77,22.28 v2(131.77,21.95)
  BOTTOM w0.142: v2(121.57,55.01) 121.96,55.4 UCPU1.AN53
DDR_B_CA1_9: length 53.1
  TOP w0.142: v2(132.34,22.86) 132.25,22.86 ; 132.25,22.86 132.12,22.98 132.12,23.6 132.25,23.73 132.42,23.73 133.21,22.94 133.98,22.94 134.25,23.21 134.25,24.09 134.46,24.3 UD21.C2 ; 132.25,22.86 131.77,22.86 v3(131.36,22.45) 129.52,20.6 RD78.1
  IN4 w0.076: 123.18,51.52 123.18,52.06 123.04,52.21 123.04,54.45 v2(122.48,55.01)
  IN4 w0.117: 123.18,51.52 123.18,51.04 123.29,50.93 123.46,50.93 123.6,51.06 123.77,51.06 123.9,50.93 123.9,50.76 123.76,50.62 123.76,50.46 123.93,50.29 124.09,50.29 124.24,50.43 124.4,50.43 124.54,50.3 124.54,50.15 124.38,50 124.38,49.83 124.57,49.65 124.57,39.96 129,35.53 129,27.68 129.13,27.54 129.52,27.54 129.66,27.4 129.66,26.17 129.66,25.36 129.54,25.24 129.08,25.24 128.96,25.11 128.96,24.9 129.08,24.77 129.3,24.77 129.43,24.65 129.43,24.48 129.53,24.38 129.76,24.38 129.89,24.51 129.89,24.89 130.11,25.1 130.28,25.1 130.42,24.96 130.42,24.74 130.25,24.57 130.25,24.41 130.36,24.29 130.53,24.29 130.73,24.5 131.01,24.5 131.1,24.42 131.1,24.09 130.96,23.95 130.75,23.95 130.62,23.82 130.62,23.72 130.88,23.46 131.07,23.46 131.43,23.81 131.5,23.89 131.68,23.89 131.86,23.72 131.86,23.59 131.55,23.28 131.55,23.15 131.67,23.03 131.91,23.03 132.11,23.22 132.21,23.22 132.34,23.1 v2(132.34,22.86)
  BOTTOM w0.142: v2(122.48,55.01) 122.88,55.4 UCPU1.AN52
DDR_B_CA2_0: length 56
  TOP w0.142: RD80.1 158.75,20.63 158.75,22.61 v2(157.81,23.55) 157.87,23.62 157.87,24.3 UD22.R2
  IN2 w0.102: v2(157.81,23.55) 157.76,23.61 156.24,23.61 155.96,23.33 153.14,23.33 152.78,23.68 152.78,24.06 152.45,24.39 152.07,24.39 151.46,25 150.19,25 150.01,25.18 149.38,25.18 149.15,24.95 147.26,24.95 146.34,25.88 146.34,32.78 141.77,37.35 132.17,37.35 129.18,40.33 129.18,45.63 v2(128.8,46.01)
  BOTTOM w0.076: v2(128.8,46.01) 128.22,46.59 128.22,48.83 128.4,49.01 128.4,50.29 UCPU1.BA43
DDR_B_CA2_1: length 58.4
  TOP w0.142: 157.35,23.22 158.34,22.23 RD82.1 ; 157.35,23.22 157.38,23.24 157.38,24.14 157.22,24.3 UD22.P2 ; 157.35,23.22 v2(157.35,23.12)
  IN2 w0.102: v2(157.35,23.12) 157.28,23.05 157.28,22.61 156.49,21.83 156.31,21.83 155.58,22.56 152.45,22.56 150.83,24.19 150.42,24.19 150.17,23.94 147.35,23.94 145.68,25.6 145.68,32.51 141.42,36.76 131.92,36.76 128.22,40.47 128.22,44.36 v2(128.65,44.79)
  BOTTOM w0.076: v2(128.65,44.79) 128.58,44.79 127.98,45.39 127.98,48.2 127.61,48.56 127.61,49.27 127.8,49.45 127.8,49.83 127.79,49.86 127.75,49.94 127.75,50.06 127.82,50.27 127.82,50.42 127.76,50.58 127.76,50.76 127.84,50.92 127.84,51.02 UCPU1.AY43
DDR_B_CA2_2: length 56.5
  TOP w0.142: RD84.1 156.57,22.23 v2(156.42,22.37) 156.38,22.41 156.38,23.73 156.57,23.92 156.57,24.3 UD22.N2
  IN2 w0.102: v2(128.65,44.1) 128.6,44.05 128.6,40.5 132.04,37.05 141.65,37.05 146.01,32.7 146.01,25.74 147.48,24.27 150.01,24.27 150.27,24.52 150.97,24.52 152.51,22.97 156.01,22.97 156.36,23.31 156.74,23.31 156.87,23.19 156.87,22.82 v2(156.42,22.37)
  BOTTOM w0.076: UCPU1.AY44 127.47,50.74 127.57,50.64 127.57,50.63 127.64,50.41 127.64,50.28 127.58,50.05 127.58,49.91 127.63,49.79 127.63,49.52 127.43,49.32 127.43,48.51 127.81,48.13 127.81,44.94 v2(128.65,44.1)
DDR_B_CA2_3: length 57.8
  TOP w0.076: 156.9,23.74 v2(156.9,24.7)
  TOP w0.142: v2(156.9,24.7) 156.9,24.77 UD22.N3 ; 156.9,23.74 156.9,22.43 157.46,21.87 RD86.1
  IN2 w0.102: v2(156.9,24.7) 156.47,24.28 155.2,24.28 155.15,24.23 153.14,24.23 152.64,24.72 152.21,24.72 151.87,25.06 151.87,25.69 152.17,26 152.17,27.24 151.28,28.13 149.68,28.13 148.4,29.41 148.4,30.38 147.74,31.05 147.74,33.36 142.35,38.74 140.13,38.74 139.47,39.4 136.36,39.4 135.22,40.55 132.13,40.55 131.8,40.88 131.8,47.71 130.91,48.6 130.39,48.6 129.98,49.01 128.6,49.01 127.38,47.79 v2(127.08,47.79)
  BOTTOM w0.076: UCPU1.AW44 127.47,51.47 127.3,51.31 127.2,51.1 127.17,51.03 127.17,50.56 126.94,50.33 126.94,47.93 v2(127.08,47.79)
DDR_B_CA2_4: length 55.7
  TOP w0.076: UD22.M3 155.92,24.85 156.24,24.53 156.24,24.05 156.05,23.86
  TOP w0.142: 156.05,23.86 156.05,23.16 155.9,23.01 155.9,22.2 v2(155.62,21.93) 155.47,21.78 155.47,20.35 RD88.1
  IN2 w0.102: v2(155.62,21.93) 155.22,21.52 153.03,21.52 151.28,23.27 147.06,23.27 145.02,25.31 145.02,32.23 144.04,33.21 142.29,33.21 141.6,33.9 141.19,33.9 139.39,35.7 131.93,35.7 127.53,40.1 127.53,45.45 127.13,45.86 v2(127.08,45.86)
  BOTTOM w0.076: v2(127.08,45.86) 127.65,46.43 127.65,48.06 127.27,48.44 127.27,49.58 UCPU1.BB44
DDR_B_CA2_5: length 56
  TOP w0.076: UD22.F3 151.7,24.77 151.7,23.76 151.73,23.72
  TOP w0.142: 151.73,23.72 151.73,22.14 v2(151.56,21.98) 151.54,21.98 151.54,20.46 RD90.1
  IN2 w0.102: v2(125.3,45.6) 125.98,45.6 126.16,45.42 126.16,40.53 131.58,35.11 136.96,35.11 137.26,34.81 137.26,32.61 137.49,32.39 137.49,30.88 138.19,30.18 139.34,30.18 140.41,29.12 143.71,29.12 144.04,28.79 144.04,27.88 143.41,27.24 143.41,24.51 145.32,22.61 149.84,22.61 150.22,22.22 151.32,22.22 v2(151.56,21.98)
  BOTTOM w0.076: v2(125.3,45.6) 125.81,46.11 v3(125.81,46.54) 125.81,47.05 126.06,47.3 126.06,49.31 125.91,49.46 125.91,49.83 125.92,49.86 125.95,49.94 125.95,50.06 125.89,50.27 125.89,50.42 125.95,50.58 125.95,51 UCPU1.AY47
DDR_B_CA2_6: length 57.9
  TOP w0.076: UD22.E3 151.04,24.76 151.04,24.09 v2(150.67,23.73)
  TOP w0.142: RD92.1 149.99,20.68 150.17,20.68 150.55,21.07 150.55,22.93 150.67,23.05 v2(150.67,23.73)
  IN2 w0.102: v2(127.08,46.52) 127.53,46.52 127.86,46.19 127.86,40.23 132.11,35.99 139.92,35.99 140.39,36.46 140.56,36.46 140.68,36.34 140.68,36.17 140.11,35.61 140.11,35.44 140.23,35.32 140.4,35.32 141.36,36.28 141.49,36.28 141.65,36.12 141.65,35.99 140.67,35.02 140.67,34.85 140.79,34.73 140.96,34.73 141.93,35.7 142.07,35.7 142.22,35.56 142.22,35.41 141.46,34.65 141.46,34.51 142.43,33.54 144.18,33.54 145.35,32.37 145.35,25.45 147.2,23.6 150.55,23.6 150.67,23.73 v2(150.67,23.73)
  BOTTOM w0.076: v2(127.08,46.52) 127.48,46.92 127.48,47.99 127.1,48.37 127.1,50.07 UCPU1.BA44
DDR_B_CA2_7: length 57.3
  TOP w0.142: UD22.E2 151.36,24.29 151.36,23.07 v2(151.03,22.74) 151.09,22.68 v3(151.09,21.32) 151.09,20.89 RD94.1
  IN2 w0.102: v2(151.03,22.74) 150.83,22.94 145.49,22.94 144.37,24.06 144.37,28.92 143.85,29.45 140.49,29.45 139.43,30.51 139.3,30.51 138.18,31.63 138.18,32.24 137.59,32.83 137.59,34.15 137.69,34.25 138.82,34.25 138.94,34.37 138.94,34.54 138.82,34.65 137.82,34.65 137.72,34.76 137.72,34.96 137.82,35.06 138.84,35.06 138.94,35.16 138.94,35.3 138.84,35.4 131.76,35.4 127.05,40.11 127.05,44.61 v2(127.1,44.66)
  BOTTOM w0.076: UCPU1.AW46 126.24,51.45 126.43,51.26 126.53,51.06 126.53,50.56 126.77,50.33 126.77,49.18 126.57,48.98 126.57,45.2 v2(127.1,44.66)
DDR_B_CA2_8: length 56.9
  TOP w0.142: UD22.D2 150.67,24.3 150.22,23.85 150.22,23.18 150.04,23 150.04,21.86 v2(150.02,21.84) 149.45,21.27 149,21.27 148.41,20.68 148.41,20.3 RD96.1
  IN2 w0.102: v2(125.3,44.99) 125.78,44.51 125.78,39.91 126.11,39.58 126.25,39.58 126.4,39.73 126.55,39.73 126.69,39.59 126.69,39.44 126.54,39.29 126.54,39.15 126.68,39 126.83,39 126.98,39.16 127.12,39.16 127.26,39.01 127.26,38.87 127.11,38.72 127.11,38.57 127.26,38.43 127.4,38.43 127.55,38.58 127.7,38.58 127.84,38.44 127.84,38.29 127.69,38.14 127.69,38 127.83,37.85 127.98,37.85 128.13,38.01 128.27,38.01 128.42,37.86 128.42,37.72 128.26,37.57 128.26,37.42 128.48,37.21 128.62,37.21 128.75,37.33 128.89,37.33 129.04,37.19 129.04,37.05 128.91,36.92 128.91,36.78 129.05,36.63 129.2,36.63 129.32,36.76 129.47,36.76 129.61,36.62 129.61,36.47 129.49,36.35 129.49,36.2 129.63,36.06 129.77,36.06 129.9,36.18 130.04,36.18 130.19,36.04 130.19,35.9 130.06,35.77 130.06,35.63 131.53,34.15 131.53,30.49 133.85,28.17 136.82,28.17 136.95,28.04 142.41,28.04 143.08,27.36 143.08,24.38 145.22,22.23 149.71,22.23 150.02,21.92 v2(150.02,21.84)
  BOTTOM w0.076: v2(125.3,44.99) 126.23,45.92 126.23,49.38 126.07,49.53 126.07,49.79 126.13,49.91 126.13,50.05 126.06,50.28 126.06,50.41 126.14,50.63 126.24,50.73 UCPU1.AY46
DDR_B_CA2_9: length 55.8
  TOP w0.142: UD22.C2 149.85,24.08 149.85,23.38 149.46,22.99 149.46,22.05 v2(149.18,21.77) 149.16,21.74 148.91,21.74 147.68,20.51 RD98.1
  IN2 w0.102: v2(149.18,21.77) 149.17,21.79 144.9,21.79 141.99,24.7 141.99,27.25 141.53,27.71 138.21,27.71 138.05,27.54 134.01,27.54 131.84,29.72 131.69,29.72 131.29,29.31 131.15,29.31 131,29.46 131,29.6 131.4,30 131.4,30.15 131.09,30.47 131.09,33.73 130.63,34.19 130.63,34.33 130.69,34.39 130.69,34.53 130.54,34.68 130.4,34.68 130.34,34.62 130.2,34.62 130.05,34.76 130.05,34.91 130.11,34.96 130.11,35.11 129.97,35.25 129.82,35.25 129.77,35.19 129.62,35.19 129.48,35.34 129.48,35.48 129.54,35.54 129.54,35.68 129.39,35.83 129.25,35.83 129.19,35.77 129.05,35.77 128.9,35.91 128.9,36.06 128.96,36.11 128.96,36.26 128.82,36.4 128.67,36.4 128.62,36.34 128.47,36.34 128.33,36.49 128.33,36.63 128.39,36.69 128.39,36.83 128.24,36.98 128.1,36.98 128.04,36.92 127.9,36.92 127.75,37.06 127.75,37.21 127.81,37.26 127.81,37.41 127.67,37.55 127.52,37.55 127.47,37.49 127.32,37.49 127.18,37.64 127.18,37.78 127.24,37.84 127.24,37.98 127.09,38.13 126.95,38.13 126.89,38.07 126.75,38.07 126.6,38.21 126.6,38.36 126.66,38.41 126.66,38.56 126.52,38.7 126.37,38.7 126.32,38.64 126.17,38.64 126.03,38.79 126.03,38.93 126.09,38.99 126.09,39.13 125.94,39.28 125.8,39.28 125.74,39.22 125.6,39.22 125.3,39.52 v2(125.3,43.82)
  BOTTOM w0.076: UCPU1.BA46 126.34,50.16 126.61,49.89 126.61,49.34 126.39,49.12 126.39,44.92 v3(125.99,44.51) v2(125.3,43.82)
DDR_B_CKE0: length 58.9
  TOP w0.076: 139.4,23.48 139.4,24.67 139.05,25.02 UD21.K3
  TOP w0.142: 139.4,23.48 139.24,23.33 138.82,23.33 138.16,22.67 137.73,22.67 137.08,22.02 v2(137.08,21.95) 137.07,21.95 135.74,20.62 RD104.1
  IN4 w0.076: 121.41,51.93 121.18,52.16 121.18,55.1 120.97,55.32 120.05,55.32 v2(119.74,55.01)
  IN4 w0.117: 121.41,51.93 121.41,51.34 122.78,49.97 122.78,48.85 123.54,48.1 123.54,39.53 127.91,35.15 127.91,24.01 127.8,23.89 127.47,23.89 127.36,23.77 127.36,23.54 127.47,23.42 127.8,23.42 127.91,23.31 127.91,22.72 127.1,21.9 127.1,21.62 127.28,21.45 127.94,21.45 128.07,21.57 128.07,22.16 128.37,22.46 128.99,22.46 129.18,22.26 129.18,21.93 129.71,21.4 132.82,21.4 133.3,21.88 134.49,21.88 134.97,21.4 136.53,21.4 v2(137.08,21.95)
  BOTTOM w0.076: UCPU1.AN56 120.13,55.4 v2(119.74,55.01)
DDR_B_CKE1: length 59.1
  TOP w0.076: UD21.K4 139.4,25.55 139.4,24.92 139.62,24.7 139.9,24.7 140.03,24.57 140.03,24.06 140.2,23.89 140.2,23.61 139.84,23.25 139.64,23.25 139.54,23.15
  TOP w0.142: 139.54,23.15 139.38,22.99 138.96,22.99 138.3,22.33 138.02,22.33 137.69,22 v2(137.69,21.88) 136.63,20.81 RD106.1
  IN4 w0.076: 121.01,52.03 121.01,54.02 v2(120.65,54.37)
  IN4 w0.117: v2(137.69,21.88) 136.91,21.1 134.84,21.1 134.37,21.57 133.43,21.57 132.93,21.08 127.01,21.08 126.54,21.55 126.54,22.84 126.42,22.97 125.63,22.97 125.53,23.07 125.53,23.38 125.63,23.48 126.55,23.48 127.61,24.53 127.61,35.02 123.23,39.4 123.23,47.97 122.48,48.73 122.48,49.84 121.16,51.16 121.16,51.16 121.01,51.32 121.01,52.03
  BOTTOM w0.142: UCPU1.AP55 121.03,54.75 v2(120.65,54.37)
DDR_B_CKE2: length 65.2
  TOP w0.076: v2(154.95,24.7) 154.95,23.93 155.05,23.82 155.05,23.66 154.95,23.55 154.95,23.38
  TOP w0.142: v2(154.95,24.7) 154.62,25.03 UD22.K3 ; 154.95,23.38 154.57,23 154.57,21.85 153.9,21.18 RD108.1
  IN2 w0.102: v2(154.95,24.7) 155.38,24.7 156.08,25.41 156.08,27.66 155.73,28.01 155.73,29.85 155.27,30.31 155.07,30.31 154.53,30.84 154.53,31.47 154.71,31.65 154.71,32.83 154.28,33.26 153.75,33.26 150.98,36.03 147.3,36.03 143.1,40.22 141.96,40.22 140.84,41.33 136.63,41.33 135.17,42.8 135.17,47.17 131.36,50.98 129.19,50.98 127.53,52.64 127.53,55.74 126.7,56.57 121.76,56.57 121.15,55.97 121.15,55.51 120.64,55 v2(120.64,54.96)
  BOTTOM w0.142: v2(120.64,54.96) 120.64,55 121.05,55.4 UCPU1.AN55
DDR_B_CKE3: length 66.1
  TOP w0.142: UD22.K4 154.62,25.98 v2(154.31,26.3) ; v2(155.02,22.01) 155.02,21.82 154.79,21.6 RD110.1
  IN2 w0.102: v2(121.54,54.42) 121.59,54.42 122.03,54.85 122.03,55.95 122.36,56.28 126.35,56.28 126.63,56 126.63,52.17 126.83,51.96 127.21,51.96 128.52,50.65 131.27,50.65 134.88,47.04 134.88,42.68 136.55,41 140.67,41 141.83,39.84 142.98,39.84 147.17,35.65 150.88,35.65 153.55,32.98 153.55,31.07 154.64,29.98 155.14,29.98 155.4,29.71 155.4,28.26 155.3,28.15 154.58,28.15 154.48,28.05 154.48,27.85 154.58,27.75 155.09,27.75 155.19,27.64 155.19,27.2 154.31,26.31 154.31,26.32 154.28,26.32 154.28,26.3 v2(154.31,26.3)
  BOTTOM w0.142: v2(154.31,26.3) 154.31,26.15 153.19,25.03 153.19,24.49 v3(154.52,23.16) 155.02,22.67 v2(155.02,22.01) ; v2(121.54,54.42) 121.88,54.75 UCPU1.AP53
DDR_B_CLK0: length 57.3
  TOP w0.076: 138.3,23.43 138.3,23.48 138.43,23.61 138.43,23.88 138.71,24.16 138.71,24.68
  TOP w0.122: RD36.1 134.61,20.39 134.61,20.72 134.75,20.86 135.31,20.86 137.55,23.1 137.98,23.1 138.3,23.43 ; 138.71,24.68 v2(138.73,24.7) 138.4,25.03 UD21.J3
  IN2 w0.076: 125.14,51.23 125.11,51.26 125.11,51.91 124.87,52.15 124.87,55.24 125.04,55.42 125.55,55.42 125.81,55.16 125.81,54.87 126.16,54.51 v2(126.16,54.42)
  IN2 w0.102: 125.14,51.23 125.14,48.56 124.79,48.22 124.79,39.45 130.56,33.69 130.56,24.9 130.66,24.8 131.09,24.8 131.19,24.9 131.19,26.51 131.44,26.77 132.01,26.77 132.26,26.51 132.26,24.93 132.36,24.82 132.72,24.82 132.82,24.93 132.82,26.3 133.12,26.6 134.19,26.6 134.98,25.81 137.96,25.81 138.53,25.24 138.53,24.9 v2(138.73,24.7)
  BOTTOM w0.122: v2(126.16,54.42) 126.17,54.42 126.5,54.75 UCPU1.AP45
DDR_B_CLK1: length 57.3
  TOP w0.076: v2(153.65,24.7) 153.65,24.18 153.87,23.96 153.87,23.79 153.82,23.73
  TOP w0.122: v2(153.65,24.7) 153.65,24.85 153.89,25.1 UD22.J3 ; RD47.1 152.48,20.51 152.48,22.14 153.82,23.48 153.82,23.73
  IN2 w0.076: v2(125.24,54.35) 125.24,54.58 125.32,54.66 125.33,54.66 125.33,54.66 125.55,54.66 125.64,54.57 125.64,52.11 125.87,51.88 125.87,51.6 125.85,51.58 125.85,51.57
  IN2 w0.102: 125.85,51.57 125.85,51.05 127.24,49.66 130.74,49.66 133.15,47.25 133.15,41.98 133.58,41.55 134.79,41.55 136.49,39.85 139.6,39.85 140.3,39.15 142.65,39.15 146.79,35.01 150.54,35.01 152.88,32.67 152.88,28.33 153.54,27.66 153.54,25.31 153.9,24.95 153.9,24.78 153.82,24.7 v2(153.65,24.7)
  BOTTOM w0.122: UCPU1.AP46 125.53,54.75 125.24,54.46 v2(125.24,54.35)
DDR_B_CLK#0: length 57.3
  TOP w0.076: 138.07,24.7 138.07,24.16 138.27,23.97 138.27,23.71 138.15,23.59
  TOP w0.122: RD38.1 134.05,20.15 134.38,20.48 134.38,20.82 134.65,21.09 135.21,21.09 137.45,23.33 137.89,23.33 138.15,23.59 ; 138.07,24.7 v2(138.08,24.7) 138.4,24.38 UD21.J2
  IN2 w0.076: v2(126.16,55.03) 125.61,55.58 124.98,55.58 124.7,55.31 124.7,52.08 124.94,51.85 124.94,51.24 124.92,51.22
  IN2 w0.102: 124.92,51.22 124.92,48.65 124.58,48.31 124.58,39.36 130.34,33.6 130.34,24.81 130.57,24.59 131.18,24.59 131.4,24.81 131.4,26.42 131.53,26.55 131.92,26.55 132.04,26.42 132.04,24.84 132.27,24.61 132.8,24.61 133.03,24.84 133.03,26.21 133.21,26.39 134.1,26.39 134.89,25.6 137.87,25.6 138.32,25.15 138.32,24.94 v2(138.08,24.7)
  BOTTOM w0.122: UCPU1.AN45 126.6,55.38 126.25,55.03 v2(126.16,55.03)
DDR_B_CLK#1: length 57.2
  TOP w0.076: v2(154.3,24.7) 154.31,24.69 154.31,24.2 154.04,23.93 154.04,23.7
  TOP w0.122: RD48.1 152.7,20.46 v4(152.7,21.16) 152.7,22.05 154.04,23.39 154.04,23.7 ; v2(154.3,24.7) 153.97,24.38 UD22.J2
  IN2 w0.076: 126.06,51.57 126.06,51.58 126.04,51.61 126.04,51.95 125.8,52.18 125.8,54.64 125.62,54.83 125.4,54.83 v2(125.22,55)
  IN2 w0.102: v2(154.3,24.7) 154.11,24.89 154.11,25.04 153.76,25.4 153.76,27.75 153.09,28.42 153.09,32.76 150.63,35.22 146.88,35.22 142.74,39.36 140.39,39.36 139.69,40.06 136.58,40.06 134.87,41.77 133.67,41.77 133.36,42.07 133.36,47.34 130.83,49.87 127.33,49.87 126.06,51.13 126.06,51.57
  BOTTOM w0.122: UCPU1.AN46 125.68,55.33 125.38,55.03 125.25,55.03 125.22,55 v2(125.22,55)
DDR_B_CS#0: length 75.1
  TOP w0.076: v2(155.6,25.5) 155.27,25.17 UD22.L3
  TOP w0.142: UD21.L3 139.7,25.17 v2(140.03,25.5) ; v2(147.6,25.38) 147.1,24.88 147.1,21.87 146.3,21.07 145.36,21.07 144.5,20.21 RD100.1
  IN1 w0.117: v2(155.6,25.5) 155.22,25.12 153.88,25.12 153.77,25.23 153.39,25.23 153.14,24.98 150.22,24.98 149.96,25.23 149.58,25.23 149.33,24.98 148.72,24.98 148.31,25.38 v2(147.6,25.38) 146.96,25.38 146.86,25.49 146.86,25.71 146.74,25.84 146.43,25.84 146.3,25.71 146.3,25.13 146.2,25.03 143.43,25.03 143.36,25.1 140.42,25.1 v2(140.03,25.5)
  IN2 w0.102: v2(147.6,25.38) 147.63,25.41 148.47,25.41 148.59,25.53 148.59,25.7 148.47,25.82 146.98,25.82 146.74,26.05 146.74,26.42 146.85,26.53 147.37,26.53 147.47,26.63 147.47,26.83 147.37,26.93 146.86,26.93 146.74,27.05 146.74,32.95 141.94,37.75 135.84,37.75 135.08,38.51 135.08,39.21 134.96,39.33 134.79,39.33 134.67,39.21 134.67,37.92 134.55,37.8 134.38,37.8 134.26,37.92 134.26,38.72 134.18,38.8 133.94,38.8 133.86,38.72 133.86,37.91 133.76,37.8 133.55,37.8 133.45,37.91 133.45,38.31 133.35,38.41 133.14,38.41 133.05,38.31 133.05,37.91 132.94,37.8 132.74,37.8 132.64,37.91 132.64,38.31 132.54,38.41 132.46,38.41 132.46,38.41 131.68,38.41 129.62,40.47 129.62,45.53 129.72,45.63 130,45.63 130.1,45.73 130.1,45.93 130,46.03 129.49,46.03 129.39,46.14 129.39,46.34 129.49,46.44 130,46.44 130.1,46.54 130.1,46.74 130,46.85 129.29,46.85 129.06,46.62 v2(128.85,46.62)
  BOTTOM w0.076: UCPU1.BB42 128.69,49.07 128.4,48.77 128.4,47.08 v2(128.85,46.62)
DDR_B_CS#1: length 77.2
  TOP w0.076: v2(154.95,25.5) 155.27,25.82 UD22.L4
  TOP w0.142: v2(140.04,26.31) 139.7,25.97 UD21.L4 ; v2(147.73,26.27) 146.75,25.3 146.75,22.02 146.14,21.41 144.87,21.41 RD102.1
  IN1 w0.117: v2(154.95,25.5) 154.56,25.89 154.03,25.89 153.21,26.7 150.14,26.7 149.71,26.27 v2(147.73,26.27) 147.3,26.7 140.44,26.7 v2(140.04,26.31)
  IN2 w0.102: v2(128.98,48.09) 129.55,48.09 129.84,47.8 131.05,47.8 131.39,47.46 131.39,45.55 131.29,45.45 131.01,45.45 130.91,45.35 130.91,45.14 131.01,45.04 131.29,45.04 131.39,44.94 131.39,44.74 131.29,44.64 131.01,44.64 130.91,44.53 130.91,44.33 131.01,44.23 131.29,44.23 131.39,44.13 131.39,43.92 131.29,43.82 131.01,43.82 130.91,43.72 130.91,43.52 131.01,43.42 131.29,43.42 131.39,43.32 131.39,43.11 131.29,43.01 131.01,43.01 130.91,42.91 130.91,42.71 131.01,42.6 131.29,42.6 131.39,42.5 131.39,42.3 131.29,42.2 131.01,42.2 130.91,42.1 130.91,41.89 131.01,41.79 131.29,41.79 131.39,41.69 131.39,41.05 131.39,40.71 131.96,40.14 135.05,40.14 136.2,38.99 139.3,38.99 139.96,38.34 142.18,38.34 147.33,33.19 147.33,30.63 147.5,30.46 147.7,30.46 147.83,30.34 147.83,30.13 147.7,30.01 147.46,30.01 147.33,29.88 147.33,28.36 147.43,28.25 147.57,28.25 147.68,28.36 147.68,28.46 147.78,28.56 148.39,28.56 148.59,28.36 148.59,28.05 148.69,27.95 149.26,27.95 149.38,27.83 149.38,27.66 149.26,27.54 148.18,27.54 147.98,27.34 147.98,26.83 148.18,26.63 149.78,26.63 149.91,26.5 149.91,25.74 149.78,25.61 149.63,25.61 149.5,25.74 149.5,26.09 149.38,26.22 149.2,26.22 149.1,26.12 149.1,26.02 149,25.92 148.79,25.92 148.49,26.22 147.78,26.22 v2(147.73,26.27)
  BOTTOM w0.076: v2(128.98,48.09) 128.83,48.24 128.83,48.74 129.02,48.93 129.02,49.37 129.13,49.47 129.13,49.83 129.11,49.86 129.03,50.07 128.96,50.23 128.96,50.72 UCPU1.AY42
DDR_B_D0: length 25.4
  TOP w0.076: v2(135.15,33.75) 135.36,33.54 135.76,33.54 136.04,33.26 136.04,32.8 135.92,32.67 135.74,32.67 135.51,32.44 135.51,32.43 135.46,32.38 135.46,32.06 135.8,31.72 135.8,31.5 UD21.E11
  IN4 w0.117: v2(130.46,42.15) 130.71,42.4 130.89,42.4 131.05,42.24 131.05,41.18 130.93,41.06 130.35,41.06 130.23,40.93 130.23,40.72 130.35,40.59 130.93,40.59 131.05,40.48 131.05,40.24 130.93,40.13 130.84,40.13 130.71,40 130.71,39.78 130.84,39.66 130.93,39.66 131.05,39.54 131.05,39.39 134.95,35.49 134.95,33.95 v2(135.15,33.75)
  BOTTOM w0.076: UCPU1.AY39 129.97,50.78 129.7,50.52 129.7,50.23 129.6,49.98 129.6,49.96 129.54,49.83 129.54,49.43 129.64,49.32 129.64,47.81 129.79,47.66 129.79,42.81 v3(129.88,42.72) v2(130.46,42.15)
DDR_B_D1: length 26
  TOP w0.076: v2(136.11,31.1) 136.11,31.12 136.45,30.78 UD21.F10
  IN4 w0.117: v2(136.11,31.1) 135.5,31.72 135.25,31.72 133.79,33.18 133.35,33.18 133.04,33.49 133.04,36.09 129.25,39.88 129.25,43.21 129.68,43.64 129.68,46.02 130.81,47.15 v2(130.84,47.15)
  BOTTOM w0.076: v2(130.84,47.15) 130.99,47.3 130.99,48.68 131.07,48.76 131.07,49.25 130.86,49.45 130.86,49.83 130.91,49.94 130.91,50.06 130.85,50.27 130.85,50.42 130.9,50.58 130.9,50.76 130.88,50.8 130.88,51.37 130.62,51.64 UCPU1.AW39
DDR_B_D2: length 23.6
  TOP w0.076: UD21.F11 136.45,31.61 136.15,31.91 v2(136.14,31.91)
  IN4 w0.117: v2(136.14,31.91) 136.09,31.91 135.7,32.29 135.12,32.29 133.99,33.42 133.99,35.58 129.56,40.01 129.56,43.08 129.99,43.51 129.99,45.72 v2(130.84,46.57)
  BOTTOM w0.076: v2(130.84,46.57) 131.23,46.96 131.23,49.32 131.03,49.52 131.03,49.79 131.08,49.91 131.08,50.05 131.02,50.28 131.02,50.41 131.09,50.63 131.09,50.88 UCPU1.AY37
DDR_B_D3: length 30.4
  TOP w0.142: v2(135.48,29.5) 135.46,29.5 135.15,29.81 UD21.D9
  IN4 w0.117: v2(135.48,29.5) 135.87,29.1 137.46,29.1 137.56,29.01 138.25,29.01 138.84,29.6 138.84,31.1 139.57,31.84 139.57,34.43 133.31,40.7 133.31,41.03 132.75,41.59 132.75,42.47 132.31,42.91 v2(132.26,42.91)
  BOTTOM w0.076: UCPU1.AW37 131.2,51.42 131.51,51.11 131.51,50.56 131.73,50.34 131.73,49.32 131.73,49.32 131.73,46.61 131.57,46.46 131.57,43.49 132.16,42.91 v2(132.26,42.91)
DDR_B_D4: length 24.6
  TOP w0.076: UD21.F9 136.43,29.9 136.13,30.2 v2(136.13,30.3)
  IN4 w0.076: 133.83,30.74 133.87,30.7 135.73,30.7 v2(136.13,30.3)
  IN4 w0.117: 133.83,30.74 132.68,31.89 132.68,36.02 128.94,39.75 128.94,43.34 129.37,43.76 129.37,46.57 130.19,47.39 v2(130.19,48.23)
  BOTTOM w0.076: UCPU1.BB39 129.97,49.68 129.97,48.45 v2(130.19,48.23)
DDR_B_D5: length 23.1
  TOP w0.076: v2(135.05,33.16) 135.05,33.18 134.85,32.98 134.85,32.04 135,31.89 135.19,31.89 135.46,31.62 135.46,30.95 135.71,30.7 UD21.E10
  IN4 w0.117: v2(135.05,33.16) 134.6,33.61 134.6,35.41 129.87,40.14 129.87,42.15 v2(130.45,42.73)
  BOTTOM w0.076: v2(130.45,42.73) 130,43.19 130,47.73 129.81,47.92 129.81,49.39 129.7,49.5 129.7,49.79 129.82,50.04 129.83,50.04 129.83,50.04 129.97,50.19 UCPU1.BA39
DDR_B_D6: length 26
  TOP w0.142: v2(136.78,29.5) 136.45,29.17 UD21.F8
  IN4 w0.117: v2(132.26,41.74) 132.26,41.64 133,40.9 133,40.57 139.22,34.35 139.22,31.86 138.53,31.17 138.53,30.96 137.07,29.5 v2(136.78,29.5)
  BOTTOM w0.076: UCPU1.BA37 131.29,50.12 131.56,49.86 131.56,49.39 131.56,49.39 131.56,46.68 131.41,46.52 131.41,42.59 v2(132.26,41.74)
DDR_B_D7: length 25.5
  TOP w0.142: v2(136.13,29.5) 135.91,29.72 135.91,29.79 UD21.E9
  IN4 w0.117: v2(136.13,29.5) 136.52,29.9 137.03,29.9 137.41,30.27 137.41,30.31 137.48,30.39 137.48,31.12 138.23,31.87 138.23,32.02 138.91,32.71 138.91,34.21 132.26,40.86 v2(132.26,41.03)
  BOTTOM w0.076: v2(132.26,41.03) 131.24,42.05 131.24,46.59 131.4,46.75 131.4,49.39 131.29,49.49 UCPU1.BB37
DDR_B_D8: length 30.3
  TOP w0.142: v2(143.28,31.9) 142.95,31.57 UD21.T11
  IN1 w0.117: v2(143.28,31.9) 142.51,32.67 142.51,33.08 141.62,33.97 140.24,33.97 139.85,34.36 137.3,34.36 135.71,35.95 135.71,36.11 135.98,36.38 135.98,36.54 135.81,36.71 135.64,36.71 135.38,36.44 135.21,36.44 135.05,36.61 135.05,36.77 135.31,37.04 135.31,37.21 135.15,37.37 134.98,37.37 134.72,37.11 134.55,37.11 134.38,37.28 134.38,37.45 134.63,37.71 134.63,37.89 132.39,40.13 132.01,40.13 131.53,40.61 131.53,44.08 132.18,44.74 v2(132.23,44.74)
  BOTTOM w0.076: v2(132.23,44.74) 132.21,44.74 132.31,44.64 132.99,45.32 132.99,47.18 132.51,47.67 132.51,49.13 132.59,49.22 132.59,49.79 132.55,49.88 132.55,49.89 132.55,50.14 132.59,50.23 132.59,50.43 132.52,50.62 132.52,50.88 UCPU1.AY35
DDR_B_D9: length 31.1
  TOP w0.142: v2(143.28,31.1) 143.28,31.03 UD21.T10
  IN1 w0.117: v2(132.23,43.52) 131.83,43.12 131.83,40.74 132.14,40.44 132.51,40.44 136.56,36.4 136.56,36.23 136.29,35.96 136.29,35.8 136.46,35.63 136.62,35.63 136.89,35.9 137.06,35.9 137.22,35.73 137.22,35.57 136.95,35.3 136.95,35.14 137.12,34.97 137.28,34.97 137.55,35.24 137.72,35.24 138.29,34.66 141.36,34.66 142.82,33.21 143.38,33.21 143.71,32.88 143.71,31.74 143.28,31.3 v2(143.28,31.1)
  BOTTOM w0.076: UCPU1.AW35 132.42,51.45 132.1,51.12 132.1,50.58 131.89,50.37 131.89,49.25 131.89,49.25 131.89,46.54 131.74,46.39 131.74,44.01 v2(132.23,43.52)
DDR_B_D10: length 33.1
  TOP w0.127: UD21.T9 143.28,29.57 143.79,29.57 144.07,29.29 144.6,29.29 v2(144.6,29.3)
  IN1 w0.117: v2(144.6,29.3) 144.86,29.56 145.29,29.56 145.72,29.99 145.72,33.68 143.24,36.16 138.74,36.16 134.43,40.47 134.43,43.25 133.96,43.72 v2(133.91,43.72)
  BOTTOM w0.076: v2(133.91,43.72) 135.09,44.9 135.09,47.47 134.2,48.35 134.2,48.53 133.88,48.85 133.88,49.26 133.96,49.34 134.08,49.46 134.08,49.83 133.92,50.16 133.92,50.51 133.65,50.78 UCPU1.AY33
DDR_B_D11: length 33.3
  TOP w0.076: v2(144.6,30.16) 144.58,30.16 144.58,30.16 144.56,30.16 144.56,30.13 144.43,30.26 142.67,30.26 142.31,29.9 UD21.R9
  IN1 w0.117: v2(133.91,42.55) 133.93,42.53 133.93,40.53 138.61,35.85 143.09,35.85 145.39,33.55 145.39,30.49 145.06,30.16 v2(144.6,30.16)
  BOTTOM w0.076: v2(133.91,42.55) 133.38,43.09 133.38,47.33 132.67,48.03 132.67,49.06 132.76,49.15 132.76,49.82 132.75,49.82 132.72,49.91 132.72,50.11 132.76,50.2 132.76,50.2 132.76,50.2 132.76,50.21 132.76,50.44 132.72,50.56 132.72,50.82 132.79,50.92 132.79,51.43 133,51.64 UCPU1.AW33
DDR_B_D12: length 28.6
  TOP w0.142: v2(142.63,31.9) 142.3,31.57 UD21.R11
  IN1 w0.117: v2(132.23,45.37) 131.22,44.36 131.22,40.49 131.88,39.83 132.26,39.83 132.82,39.26 132.82,39.05 132.61,38.83 132.61,38.61 132.78,38.44 132.95,38.44 133.21,38.71 133.38,38.71 133.54,38.54 133.54,38.38 133.28,38.11 133.28,37.95 133.44,37.78 133.61,37.78 133.87,38.05 134.04,38.05 134.2,37.88 134.2,37.72 133.94,37.45 133.94,37.28 137.33,33.89 137.33,33.32 138.17,32.48 142.05,32.48 v2(142.63,31.9)
  BOTTOM w0.076: v2(132.23,45.37) 132.82,45.96 132.82,47.1 132.22,47.7 132.22,49.12 132.22,49.12 132.22,49.58 UCPU1.BB35
DDR_B_D13: length 28.9
  TOP w0.142: v2(142.63,31.1) 142.63,31.03 UD21.R10
  IN1 w0.076: 139.48,31.5 140.91,31.5 141.07,31.66 141.98,31.66 142.13,31.5 142.55,31.5 142.62,31.43 142.62,31.11 v2(142.63,31.1)
  IN1 w0.117: 139.48,31.5 139.48,31.51 139.03,31.51 138.99,31.48 138.56,31.48 136.83,33.21 136.65,33.21 135.79,34.07 135.79,34.45 135.81,34.48 135.81,34.97 132.15,38.64 132.15,38.81 132.36,39.02 132.36,39.19 132.2,39.35 132.03,39.35 131.81,39.14 131.65,39.14 130.91,39.87 130.91,44.49 131.71,45.29 131.71,46.13 v2(132.31,46.72)
  BOTTOM w0.076: UCPU1.BA35 132.32,50.11 132.06,49.85 132.06,49.18 132.06,47.56 132.31,47.3 v2(132.31,46.72)
DDR_B_D14: length 33.3
  TOP w0.142: UD21.T8 143.04,29.1 v2(143.56,28.58)
  IN1 w0.117: v2(133.91,44.31) 134.16,44.31 134.77,43.7 134.77,40.6 138.89,36.48 143.45,36.48 146.08,33.85 146.08,29.91 144.82,28.65 143.63,28.65 v2(143.56,28.58)
  BOTTOM w0.076: v2(133.91,44.31) 134.1,44.31 134.89,45.09 134.89,47.44 134.04,48.29 134.04,48.47 133.72,48.79 133.72,49.33 133.92,49.53 133.92,49.79 133.79,50.04 133.65,50.19 UCPU1.BA33
DDR_B_D15: length 34
  TOP w0.142: UD21.R8 142.41,29.1 v2(142.94,28.57)
  IN1 w0.117: v2(133.91,44.89) 134.21,44.89 135.1,44 135.1,40.7 138.94,36.86 143.5,36.86 146.38,33.98 146.38,29.78 144.9,28.29 143.93,28.29 143.79,28.15 143.36,28.15 v2(142.94,28.57)
  BOTTOM w0.076: v2(133.91,44.89) 134.05,44.89 v1(134.56,45.4) 134.68,45.53 134.68,47.41 133.87,48.22 133.87,48.4 133.55,48.72 133.55,49.59 UCPU1.BB33
DDR_B_D16: length 27.5
  TOP w0.142: UD21.B10 133.85,30.63 v2(133.52,30.3)
  IN1 w0.117: v2(133.52,30.3) 132.67,30.3 131.35,31.61 131.35,35.6 126.64,40.31 126.64,48.04 127.1,48.49 127.1,49.71 128.84,51.44 128.84,52.42 v2(128.88,52.47)
  BOTTOM w0.076: UCPU1.AU40 v2(128.88,52.47)
DDR_B_D17: length 29.8
  TOP w0.142: v2(134.18,29.5) 133.94,29.74 133.94,29.81 UD21.B9
  IN1 w0.076: v2(128.91,53.1) 128.91,53.05 128.47,52.61 128.47,52.03
  IN1 w0.117: 128.47,52.03 128.47,51.51 126.79,49.84 126.79,48.62 126.34,48.16 126.34,40.18 131.05,35.47 131.05,31.38 132.53,29.9 133.78,29.9 v2(134.18,29.5)
  BOTTOM w0.076: UCPU1.AT40 129.26,53.45 v2(128.91,53.1)
DDR_B_D18: length 25.5
  TOP w0.142: UD21.C11 134.5,31.58 v2(134.17,31.91)
  IN1 w0.076: v2(130.69,53.1) 130.69,53.02 131.08,52.62 131.08,52.16 131.19,52.04 131.19,51.88
  IN1 w0.117: 131.19,51.88 131.28,51.79 131.28,48.37 130.82,47.91 130.54,47.91 130.04,47.42 130.04,46.15 129.39,45.5 129.39,39.53 133.96,34.96 133.96,32.12 v2(134.17,31.91)
  BOTTOM w0.076: v2(130.69,53.1) 130.82,53.1 UCPU1.AT37
DDR_B_D19: length 25.2
  TOP w0.142: v2(133.53,31.89) 133.85,31.56 UD21.B11
  IN1 w0.117: v2(130.71,52.45) 130.71,51.92 130.88,51.75 130.88,50.28 129.74,49.13 129.74,46.28 129.08,45.63 129.08,43.51 128.97,43.39 128.6,43.39 128.48,43.27 128.48,43.04 128.6,42.92 128.97,42.92 129.08,42.81 129.08,39.4 132.87,35.61 132.87,32.55 v2(133.53,31.89)
  BOTTOM w0.076: UCPU1.AU37 v2(130.71,52.45)
DDR_B_D20: length 30.3
  TOP w0.142: UD21.B8 133.85,29.18 v2(133.53,29.5)
  IN1 w0.076: 128.14,52.2 128.14,52.51 128.54,52.91 128.54,53.48 128.8,53.74 v2(128.88,53.74)
  IN1 w0.117: v2(133.53,29.5) 132.49,29.5 130.74,31.25 130.74,35.35 126.03,40.05 126.03,48.34 126.49,48.79 126.49,49.96 128.14,51.62 128.14,52.2
  BOTTOM w0.076: v2(128.88,53.74) 129.21,54 UCPU1.AR40
DDR_B_D21: length 32.4
  TOP w0.142: v2(134.13,28.64) 134.13,28.73 UD21.C8
  IN1 w0.076: 127.83,52.21 127.83,52.44 128.37,52.98 128.37,53.81 128.88,54.32 v2(128.88,54.37)
  IN1 w0.117: 127.83,52.21 127.83,51.74 126.18,50.09 126.18,48.92 125.72,48.46 125.72,39.93 130.43,35.22 130.43,31.12 132.85,28.7 134.07,28.7 v2(134.13,28.64)
  BOTTOM w0.076: UCPU1.AP40 v2(128.88,54.37)
DDR_B_D22: length 30.7
  TOP w0.142: v2(134.83,29.5) 134.5,29.83 UD21.C9
  IN1 w0.076: v2(130.71,54.37) 130.73,54.37 131.27,53.83 131.27,52.94 131.55,52.66 131.55,52.61
  IN1 w0.117: 131.55,52.61 131.83,52.33 131.95,52.33 132.54,51.75 132.54,48.51 131.29,47.26 131.29,45.7 131.09,45.5 130.26,45.5 130.01,45.24 130.01,39.8 134.6,35.21 134.6,32.85 135.27,32.18 135.27,30.1 134.83,29.66 v2(134.83,29.5)
  BOTTOM w0.076: UCPU1.AP37 v2(130.71,54.37)
DDR_B_D23: length 28.1
  TOP w0.142: v2(134.18,31.1) 134.5,30.78 UD21.C10
  IN1 w0.076: 131.47,52.26 131.24,52.48 131.24,52.69 131.09,52.85 131.09,53.37 130.73,53.74 v2(130.71,53.74)
  IN1 w0.117: v2(134.18,31.1) 134.65,31.57 134.65,32.11 134.27,32.49 134.27,35.08 129.7,39.65 129.7,45.37 130.35,46.03 130.35,47.29 130.67,47.6 131.21,47.6 132.23,48.63 132.23,51.62 131.83,52.03 131.7,52.03 131.47,52.26
  BOTTOM w0.076: v2(130.71,53.74) 131.04,54 UCPU1.AR37
DDR_B_D24: length 38
  TOP w0.142: UD21.N11 141,31.59 v2(140.68,31.91)
  IN4 w0.117: v2(132.54,53.1) 132.14,52.7 132.14,52.22 132.33,52.03 132.33,50.97 132.21,50.86 131.75,50.86 131.63,50.74 131.63,50.51 131.75,50.39 132.21,50.39 132.33,50.27 132.33,50.04 132.21,49.92 131.75,49.92 131.63,49.81 131.63,49.57 131.75,49.46 133.07,49.46 133.19,49.33 133.19,49.12 133.07,48.99 131.75,48.99 131.63,48.87 131.63,48.13 131.75,48.01 132.05,48.01 132.14,48.1 132.14,48.47 132.26,48.59 132.5,48.59 132.63,48.47 132.63,47.7 132.86,47.47 133.13,47.47 133.57,47.91 133.75,47.91 134,47.66 134,47.48 133.47,46.96 133.47,46.51 133.48,46.5 133.48,41.9 134.04,41.34 134.04,41 140.06,34.98 140.29,34.98 141.18,35.88 141.36,35.88 141.56,35.67 141.56,35.49 140.31,34.24 140.31,33.94 140.42,33.84 141.07,33.84 141.25,33.66 141.25,32.93 141.16,32.84 140.94,32.84 140.7,32.6 140.7,31.9 140.69,31.88 140.69,31.9 v2(140.68,31.91)
  BOTTOM w0.076: v2(132.54,53.1) 132.72,53.24 UCPU1.AT33
DDR_B_D25: length 38.1
  TOP w0.076: UD21.M10 140.51,30.54 140.51,30.48 v2(140.69,30.31)
  IN4 w0.117: v2(140.69,30.31) 140.61,30.38 140.61,31.28 141.18,31.84 141.18,32.45 141.31,32.57 141.57,32.57 141.7,32.45 141.7,31.91 141.83,31.79 142.12,31.79 142.21,31.88 142.21,32.31 142.34,32.44 142.76,32.44 142.86,32.54 142.86,32.84 142.76,32.94 142.18,32.94 142.1,33.03 142.1,33.24 142.42,33.56 142.42,33.74 142.21,33.95 142.03,33.95 141.81,33.73 141.61,33.73 141.2,34.15 141.04,34.15 140.92,34.27 140.92,34.42 142.07,35.56 142.07,35.68 141.37,36.38 141.25,36.38 140.28,35.41 140.06,35.41 134.63,40.84 134.63,41.59 134.5,41.72 134.11,41.72 133.99,41.85 133.99,42.06 134.11,42.19 134.5,42.19 134.63,42.32 134.63,42.77 134.51,42.88 134.44,42.88 134.32,43 134.32,43.23 134.44,43.35 134.51,43.35 134.63,43.47 134.63,43.7 134.51,43.82 134.44,43.82 134.32,43.93 134.32,44.17 134.44,44.28 134.51,44.28 134.63,44.4 134.63,44.64 134.51,44.75 134.44,44.75 134.32,44.87 134.32,45.1 134.44,45.22 134.51,45.22 134.63,45.34 134.63,45.57 134.51,45.69 134.44,45.69 134.32,45.8 134.32,46.04 134.44,46.15 134.51,46.15 134.63,46.27 134.63,46.5 134.51,46.62 134.44,46.62 134.32,46.74 134.32,46.97 134.44,47.09 134.51,47.09 134.63,47.21 134.63,47.48 133.5,48.6 133.5,49.67 133.36,49.82 132.81,49.82 132.66,49.97 132.66,52.35 v2(132.54,52.47)
  BOTTOM w0.076: v2(132.54,52.47) 132.72,52.6 UCPU1.AU33
DDR_B_D26: length 36.3
  TOP w0.127: UD21.N9 140.68,29.58 140.68,28.78 v2(140.87,28.58)
  IN4 w0.117: v2(134.37,52.47) 134.37,52.27 134.75,51.89 134.75,50.68 136.37,49.06 136.37,47.84 136.04,47.51 136.04,41.68 136.34,41.38 136.98,41.38 139.91,38.46 141.21,38.46 145.21,34.45 145.21,29.05 144.88,28.72 144.16,28.72 143.79,29.09 141.3,29.09 140.87,28.66 v2(140.87,28.58)
  BOTTOM w0.076: UCPU1.AU30 v2(134.37,52.47)
DDR_B_D27: length 37.2
  TOP w0.076: v2(142.33,28.54) 141.97,28.89 141.97,29.49 141.65,29.81 UD21.P9
  IN4 w0.117: v2(142.33,28.54) 142.71,28.16 144.76,28.16 145.52,28.92 145.52,34.58 141.33,38.76 140.04,38.76 137.03,41.77 137.03,42.28 137.03,48.54 136.9,48.67 136.9,49.03 136.49,49.44 136.49,49.61 136.73,49.85 136.73,50.01 136.56,50.18 136.4,50.18 136.16,49.94 135.99,49.94 135.83,50.11 135.83,50.27 136.07,50.51 136.07,50.67 135.9,50.84 135.74,50.84 135.5,50.6 135.33,50.6 135.05,50.88 135.05,52.03 134.8,52.29 134.8,52.61 134.39,53.02 v2(134.39,53.1)
  BOTTOM w0.076: v2(134.39,53.1) 134.82,53.43 UCPU1.AT30
DDR_B_D28: length 38.1
  TOP w0.142: UD21.M11 140.03,31.82 v2(140.03,31.91)
  IN4 w0.117: v2(140.03,31.91) 140,31.94 140,34.6 133.73,40.87 133.73,41.21 133.17,41.77 133.17,43.01 133.05,43.13 132.82,43.13 132.69,43.25 132.69,43.47 132.82,43.59 133.05,43.59 133.17,43.71 133.17,43.94 133.05,44.06 132.79,44.06 132.66,44.19 132.66,44.4 132.79,44.53 133.05,44.53 133.17,44.64 133.17,44.88 133.05,44.99 132.79,44.99 132.66,45.12 132.66,45.34 132.79,45.46 133.05,45.46 133.17,45.58 133.17,46.38 133.16,46.38 133.16,46.73 132.21,47.69 131.9,47.69 131.8,47.58 131.8,45.37 131.7,45.27 131.4,45.27 131.3,45.37 131.3,49.37 131.17,49.49 130.82,49.49 130.7,49.62 130.7,49.84 130.82,49.96 131.21,49.96 131.32,50.08 131.32,50.31 131.21,50.43 130.83,50.43 130.7,50.56 130.7,50.77 130.83,50.9 131.21,50.9 131.32,51.01 131.32,51.25 131.21,51.36 130.39,51.36 130.27,51.49 130.27,51.7 130.39,51.83 131.21,51.83 131.32,51.95 131.32,52.19 132.14,53.01 132.14,53.34 v2(132.54,53.74)
  BOTTOM w0.076: UCPU1.AR33 132.87,54 v2(132.54,53.74)
DDR_B_D29: length 40.1
  TOP w0.142: v2(141.34,30.3) 141.31,30.3 141,30.61 UD21.N10
  IN4 w0.076: 143.57,31.5 141.1,31.5 140.81,31.21 140.81,30.8 141.34,30.28 v2(141.34,30.3)
  IN4 w0.117: v2(132.54,54.37) 132.98,53.94 132.98,50.23 133.08,50.13 133.49,50.13 133.81,49.8 133.81,48.73 133.99,48.55 134.36,48.55 134.58,48.33 134.58,47.96 134.94,47.6 134.94,40.97 139.95,35.95 140.39,35.95 141.23,36.79 141.4,36.79 142.48,35.71 142.48,35.54 141.44,34.5 141.44,34.34 141.62,34.16 141.78,34.16 142.03,34.41 142.25,34.41 142.49,34.17 142.64,34.02 142.64,33.97 142.85,33.77 142.85,33.3 142.97,33.18 143.33,33.18 143.47,33.31 143.47,34.22 143.6,34.36 143.83,34.36 144.16,34.03 144.16,32.92 144.08,32.84 143.77,32.84 143.7,32.76 143.7,31.63 143.57,31.5
  BOTTOM w0.142: UCPU1.AP33 132.92,54.75 v2(132.54,54.37)
DDR_B_D30: length 37.9
  TOP w0.142: UD21.M8 140.35,28.62 v2(140.28,28.56)
  IN4 w0.117: v2(134.37,53.74) 134.9,53.21 134.9,52.89 135.41,52.38 135.41,51.76 137.21,49.97 137.21,48.8 137.34,48.67 137.34,42.15 137.34,42.15 137.34,41.89 140.16,39.07 141.46,39.07 145.83,34.71 145.83,28.79 144.89,27.85 140.95,27.85 140.28,28.51 v2(140.28,28.56)
  BOTTOM w0.076: UCPU1.AR30 134.7,54 v2(134.37,53.74)
DDR_B_D31: length 41.5
  TOP w0.127: UD21.M9 140.03,29.58 140.03,28.92 v2(139.67,28.57)
  IN4 w0.117: v2(134.37,54.37) 134.56,54.19 135.48,54.19 135.72,53.95 135.72,51.89 137.52,50.09 137.52,48.93 137.65,48.8 137.65,42.02 140.29,39.38 141.59,39.38 146.13,34.83 146.13,28.66 145.02,27.54 140.69,27.54 139.67,28.56 v2(139.67,28.57)
  BOTTOM w0.076: UCPU1.AP30 v2(134.37,54.37)
DDR_B_D32: length 30.1
  TOP w0.142: v2(151.05,31.9) 151.37,31.58 UD22.E11
  IN1 w0.117: v2(136.6,41.94) 136.6,41.54 139.91,38.23 145.16,38.23 149.68,33.72 149.68,32.62 150,32.3 150.65,32.3 v2(151.05,31.9)
  BOTTOM w0.076: UCPU1.AY31 134.95,50.78 134.68,50.52 134.68,50.23 134.53,49.86 134.52,49.83 134.52,49.46 134.6,49.38 134.6,48.2 135.26,47.54 135.26,43.29 v3(136.04,42.5) v2(136.6,41.94)
DDR_B_D33: length 35.3
  TOP w0.142: v2(152.35,29.5) 152.02,29.17 UD22.F8
  IN1 w0.117: v2(152.35,29.5) 152.6,29.5 153.12,30.02 153.12,30.47 153.48,30.82 153.48,32.95 146.15,40.27 142.27,40.27 140.97,41.57 140.03,41.57 139.15,42.45 139.15,43.17 138.86,43.45 138.86,47.05 138.12,47.79 136.98,47.79 136.45,48.32 v2(135.94,48.32)
  BOTTOM w0.076: v2(135.94,48.32) 136.14,48.52 136.14,49.03 136.05,49.12 136.05,49.22 135.84,49.43 135.84,49.83 135.86,49.86 135.89,49.94 135.89,50.06 135.83,50.27 135.83,50.42 135.88,50.58 135.88,50.76 135.86,50.81 135.86,51.14 135.77,51.47 135.69,51.55 135.56,51.6 UCPU1.AW31
DDR_B_D34: length 33.9
  TOP w0.076: UD22.F9 151.7,30.22 v2(151.7,30.3)
  IN1 w0.076: 148.59,29.9 151.3,29.9 v2(151.7,30.3)
  IN1 w0.117: v2(136.6,46.69) 136.55,46.69 135.56,45.7 135.56,41.28 139.55,37.29 143.68,37.29 146.8,34.16 146.8,31.21 148.11,29.9 148.59,29.9
  BOTTOM w0.076: UCPU1.AY29 136.08,50.88 136.08,50.63 136,50.41 136,50.28 136.06,50.05 136.06,49.91 136.01,49.79 136.01,49.5 136.21,49.29 136.21,49.19 136.3,49.1 136.3,47.61 136.14,47.45 136.14,47.15 v2(136.6,46.69)
DDR_B_D35: length 33.5
  TOP w0.142: v2(151.7,29.5) 151.37,29.83 UD22.E9
  IN1 w0.117: v2(138.13,43.72) 138.84,43.01 138.84,42.33 139.9,41.26 140.84,41.26 142.14,39.97 146.02,39.97 153.17,32.82 153.17,30.95 152.81,30.59 152.81,30.15 152.58,29.92 152.11,29.92 v2(151.7,29.5)
  BOTTOM w0.076: v2(138.13,43.72) 138.02,43.72 137.29,44.46 137.29,48.09 136.8,48.58 136.8,49.3 136.71,49.39 136.71,50.34 136.49,50.56 136.49,51.11 136.18,51.42 UCPU1.AW29
DDR_B_D36: length 31.3
  TOP w0.142: UD22.D9 150.72,29.98 v2(151.05,30.3)
  IN1 w0.117: v2(151.05,30.3) 150.64,30.7 150.1,30.7 150.06,30.67 149.57,30.67 149.52,30.72 148.84,30.72 148.72,30.59 148.22,30.59 147.47,31.34 147.47,33.93 143.78,37.62 139.66,37.62 135.86,41.41 135.86,43.01 136.55,43.7 v2(136.6,43.7)
  BOTTOM w0.076: v2(136.6,43.7) 135.59,44.71 135.59,47.67 134.93,48.33 134.93,49.66 UCPU1.BB31
DDR_B_D37: length 31.2
  TOP w0.142: UD22.E10 151.37,30.78 v2(151.05,31.1)
  IN1 w0.076: v2(151.05,31.1) 150.66,31.49 149.42,31.49
  IN1 w0.117: v2(136.6,43.11) 136.53,43.11 136.17,42.76 136.17,41.54 139.78,37.93 145.01,37.93 148.68,34.26 148.68,33.27 148.67,33.26 148.67,31.71 148.9,31.48 149.41,31.48 149.42,31.49
  BOTTOM w0.076: v2(136.6,43.11) 135.42,44.29 135.42,47.61 134.76,48.27 134.76,49.45 134.68,49.53 134.68,49.79 134.8,50.04 134.81,50.04 134.81,50.04 134.95,50.19 UCPU1.BA31
DDR_B_D38: length 31
  TOP w0.142: v2(151.7,31.1) 152.02,30.78 UD22.F10
  IN1 w0.076: v2(138.1,43.11) 138.53,42.68
  IN1 w0.117: 138.53,42.68 138.53,42.2 139.77,40.96 140.71,40.96 142.01,39.66 145.9,39.66 152.85,32.7 152.85,31.07 152.49,30.7 152.09,30.7 v2(151.7,31.1)
  BOTTOM w0.076: UCPU1.BA29 136.28,50.11 136.54,49.84 136.54,49.32 136.63,49.23 136.63,48.51 137.12,48.02 137.12,44.09 v2(138.1,43.11)
DDR_B_D39: length 27.9
  TOP w0.076: v2(151.54,33.17) 151.7,33.01 151.7,31.83 151.78,31.75 151.78,31.74 UD22.F11
  IN1 w0.117: v2(138.1,42.5) 138.1,41.53 140.3,39.33 145.79,39.33 151.54,33.58 v2(151.54,33.17)
  BOTTOM w0.076: v2(138.1,42.5) 137.48,43.13 137.48,43.5 136.96,44.02 136.96,47.95 136.47,48.44 136.47,49.16 136.38,49.26 136.38,49.58 UCPU1.BB29
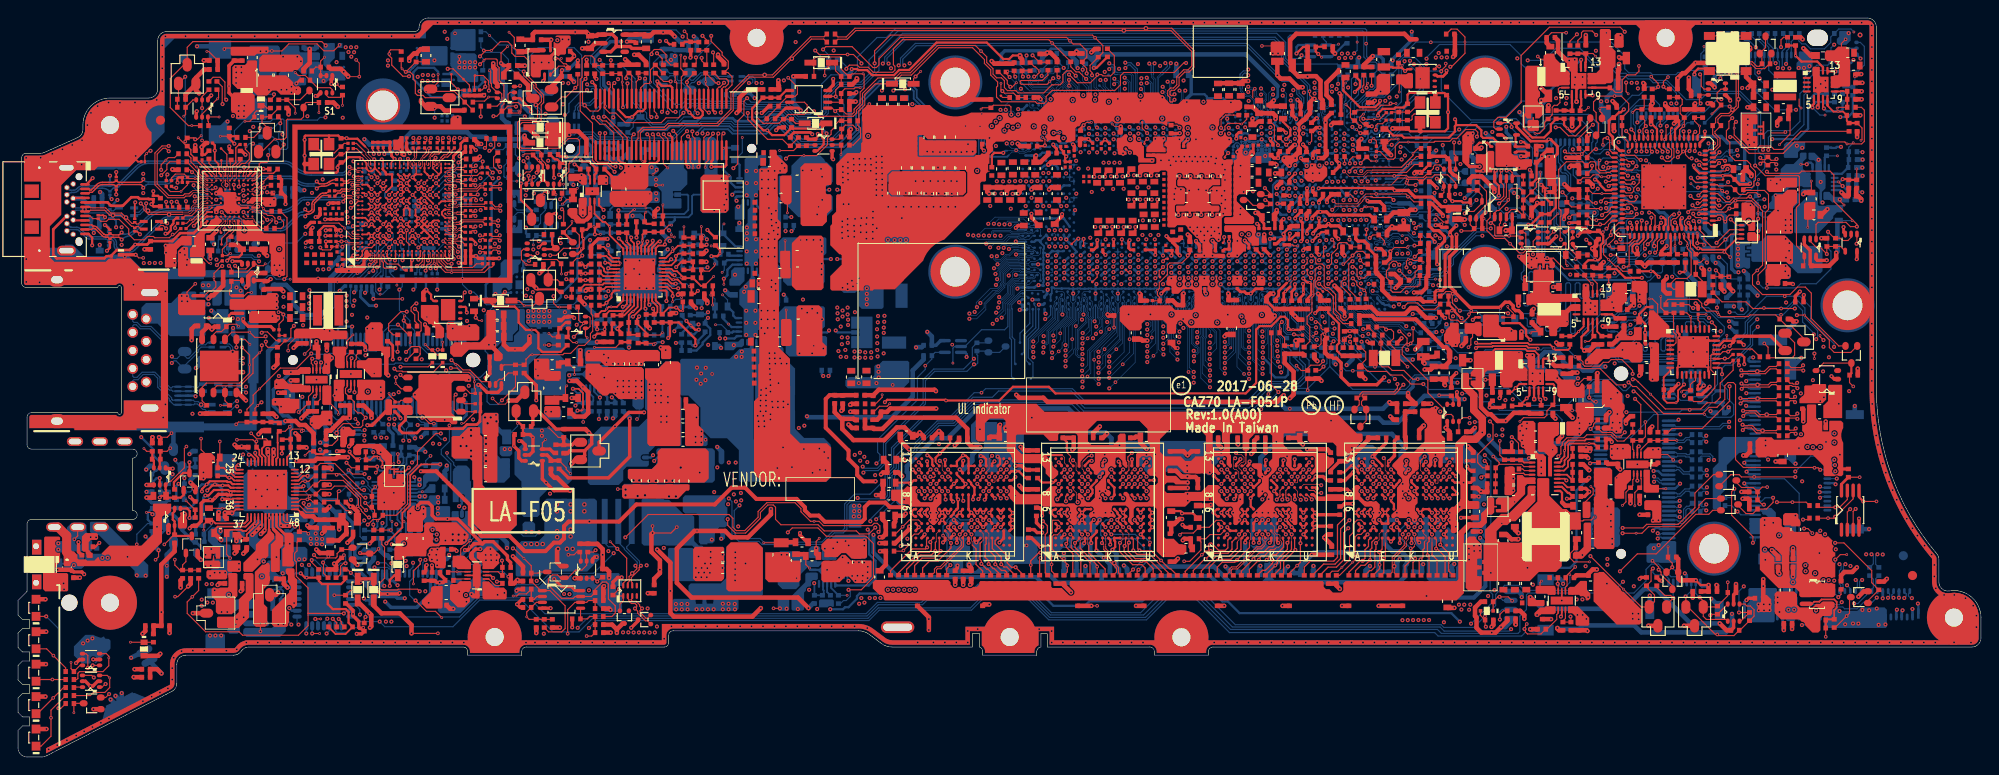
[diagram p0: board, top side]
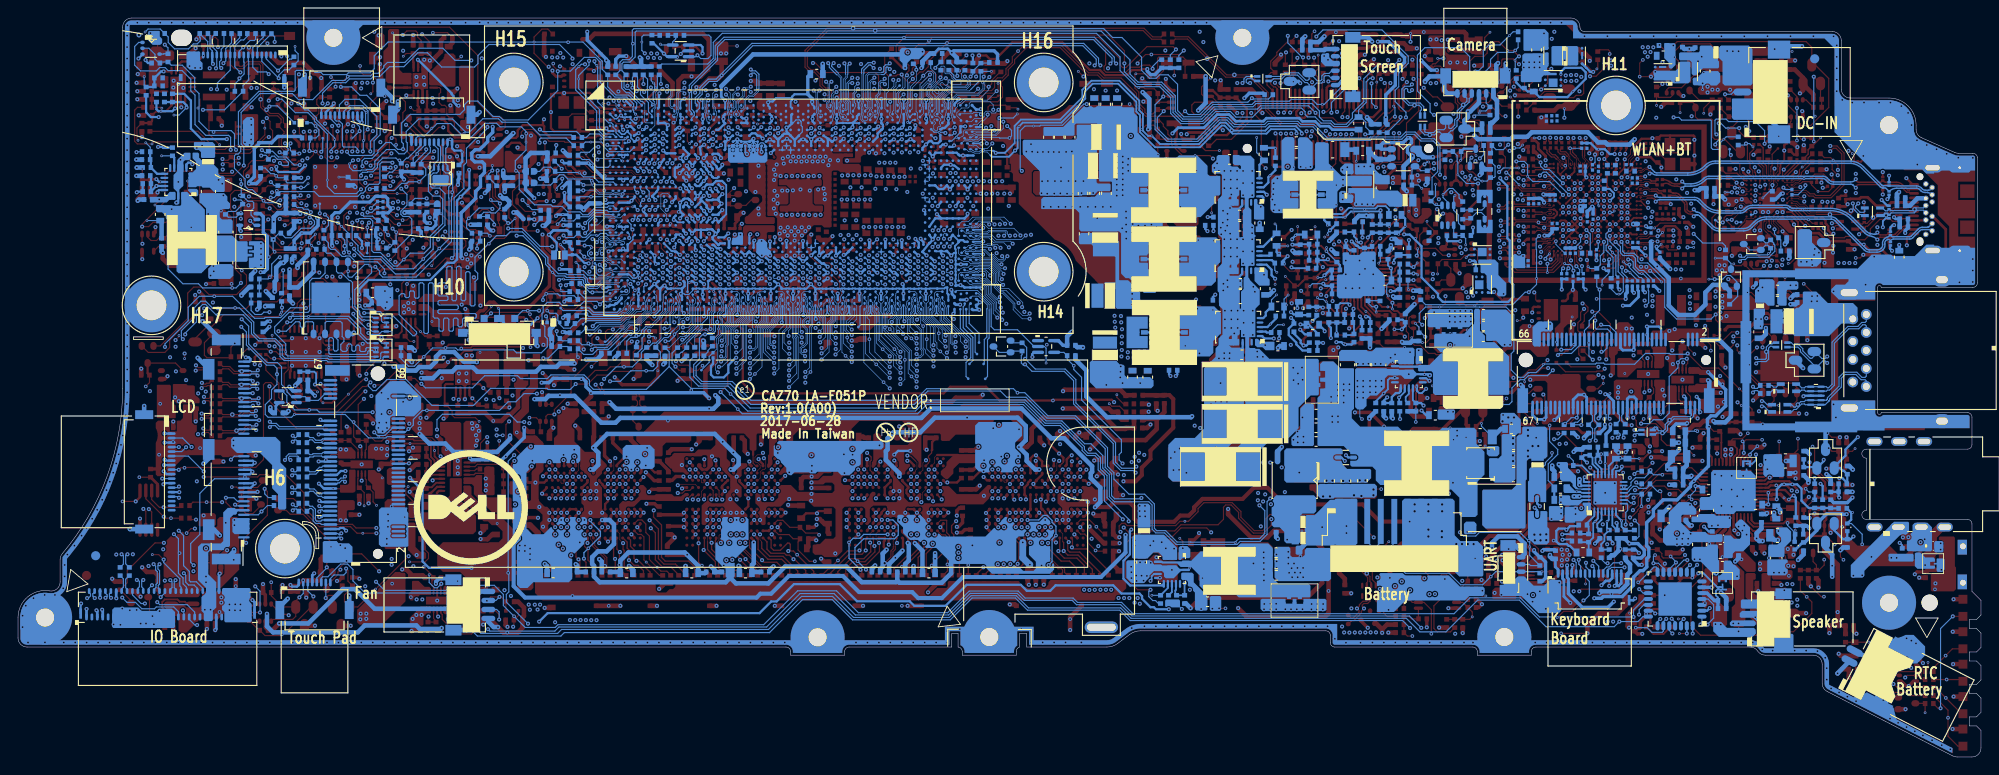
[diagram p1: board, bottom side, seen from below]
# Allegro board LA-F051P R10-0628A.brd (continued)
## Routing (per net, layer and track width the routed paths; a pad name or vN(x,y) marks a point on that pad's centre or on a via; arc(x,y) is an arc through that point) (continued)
FCCM_VSA: length 15.8
  TOP w0.203: PR1059.2 61.86,65.76 v2(61.75,65.76) ; PU1000.29 67.56,56.11 67.56,56.6 67.11,57.06 67.11,57.11 v2(66.66,57.55)
  IN3 w0.203: v2(66.66,57.55) 65.53,58.68 62.52,58.68 61.98,59.23 61.98,61.61 61.15,62.43 61.15,64 61.89,64.74 61.89,65.62 v2(61.75,65.76)
  BOTTOM w0.127: v1(61.29,66.02) 61.48,66.02 v2(61.75,65.76)
FIVR_EN: length 3.4
  TOP w0.127: RC219.2 74.26,79.75 74.26,80.22 v3(73.95,80.53)
  TOP w0.254: RC218.2 73.99,79.36 RC219.2 75.51,79.36 RC217.1
FIVR_EN_R: length 17.7
  TOP w0.127: v2(67.63,74.75) 67.6,74.72 JXDP1.45 ; v2(75.86,77.58) 75.86,77.26 RC126.2 76.43,76.95 RC132.2 RC217.2
  IN1 w0.081: v2(67.63,74.75) 68.13,75.26 68.13,75.66 68.63,76.15 69.76,76.15 70.24,76.64 74.91,76.64 v2(75.86,77.58)
  BOTTOM w0.127: v2(67.63,74.75) 67.63,72.59 v3(67.13,72.09)
FWP#: length 9.8
  TOP w0.127: v2(185.45,59.87) 185.32,59.87 184.91,59.47 184.91,59.1 185.11,58.9 UE5.B65
  BOTTOM w0.127: v2(185.45,59.87) 185.34,59.87 184.91,59.45 184.91,59.11 185.35,58.67 186.38,58.67 187.44,57.62 188.14,57.62 RE82.2 188.85,58.12 189.51,57.47 RE81.2 189.51,56.22 v3(189.33,56.05)
GPP_B22: length 2.3
  TOP w0.127: RC184.2 149.34,54.7 v2(148.93,55.1) 148.93,55.53 v3(148.77,55.68)
  BOTTOM w0.127: v2(148.93,55.1) 149.22,55.4 UCPU1.AN5
GPP_B23: length 4.1
  TOP w0.127: v3(147.04,54.7) 147.14,54.7 v2(148.08,55.64) 148.55,56.11 149.23,56.11 RC26.1
  BOTTOM w0.076: UCPU1.AM7 148.49,56.05 v2(148.08,55.64)
GPP_C5: length 3.7
  BOTTOM w0.076: UCPU1.W1 153.21,62.17
  BOTTOM w0.127: 153.21,62.17 v3(154.23,62.17) 155.44,62.17 RC25.1
GPP_E1: length 2.1
  TOP w0.127: RC51.1 150.72,68.35 v1(150.44,68.63) 150.32,68.63 v2(150.03,68.33)
  BOTTOM w0.127: UCPU1.H3 150.22,68.14 v2(150.03,68.33)
GT_BST: length 2.4
  BOTTOM w0.254: PC1106.2 78.26,48.62 v1(78.84,48.04) 79.18,47.71 PU1100.3
GT_BST_R: length 2.5
  BOTTOM w0.127: PR1100.1 77.33,50.81 v1(76.87,51.27)
  BOTTOM w0.254: PC1106.1 77.33,48.94 PR1100.1
GT_FCCM: length 3.1
  BOTTOM w0.127: v1(77.39,47.96) 78.05,47.96 78.75,47.27 PR1103.1
  BOTTOM w0.254: PU1100.2 79.35,47.21 79.25,47.1 PR1103.1
GT_SNUB: length 1.9
  TOP w0.127: PR1101.2 v1(85.23,49.6)
GT_SW:
  vias: v1(88.29,45.63) v2(86.72,44.79) v2(86.97,49.74) v2(87.57,49.31) v2(88.11,49.74) v2(88.11,44.79) v2(88.7,49.27) v2(89.22,48.57) v2(89.36,45.32)
GT_SWH: length 3.5
  BOTTOM w0.127: PR1100.2 78.73,50.72 v1(78.17,51.28)
  BOTTOM w0.254: PU1100.5 79.64,48.71 79.36,48.98 79.36,49.35 PR1100.2
GTP: length 26.8
  IN2 w0.203: v2(76.43,57.44) 76.51,57.44 77.73,56.22 77.73,49.06 80.55,46.24 84.24,46.24 84.6,46.59 89.97,46.59 90.17,46.8 90.17,47.15 v2(89.99,47.33)
  BOTTOM w0.254: PL1100.2 89.78,47.11 v2(89.99,47.33) ; PR1102.1 75.97,57.97 v1(76.06,57.88) 76.43,57.51 v2(76.43,57.44)
H_CATERR#: length 7.8
  BOTTOM w0.076: UCPU1.D63 116.6,70.58 116.6,70.69 116.67,70.96 116.67,71.07 116.7,71.18 116.8,71.5 116.81,71.55 116.81,71.8 116.78,71.89 116.78,72.08 116.81,72.18 116.81,72.54 116.66,72.69 116.66,73.06 117.04,73.44 117.04,74.17 116.77,74.45 v1(116.73,74.45) 116.54,74.45 116.02,74.96 116.02,75.9 116.54,76.41
  BOTTOM w0.127: RC79.2 116.54,76.41
H_CPU_SVIDALRT#: length 13.4
  BOTTOM w0.076: UCPU1.B63 116.05,71.99 116.05,73.28 116.05,73.28 116.05,73.39 116.37,73.71 116.37,73.83 116.28,73.92 116.16,73.92 115.84,73.6 115.73,73.6 115.62,73.71 115.62,73.82 115.96,74.15 115.96,74.28 115.87,74.37 115.74,74.37 115.41,74.03 115.3,74.03 115.19,74.14 115.19,74.25 115.5,74.56 115.5,74.68 115.37,74.81 115.21,74.81 114.9,74.51 114.82,74.51 114.72,74.61 114.7,74.61 114.62,74.68 114.62,75.05 114.52,75.15 114.4,75.15 114.32,75.07 114.32,74.68 114.24,74.61 113.23,74.61 113.18,74.66 113.18,74.92 113.26,75 113.86,75 114.19,75.33 114.19,75.56 114.44,75.82 114.88,75.82 114.96,75.9 114.96,76.55 115.07,76.66 115.34,76.66 115.42,76.58 RC153.1
H_CPUPWRGD: length 8.5
  TOP w0.127: v1(109.07,74.76) 109.07,74.04 v2(109.22,73.89) 109.45,73.66 110.48,73.66 RC77.2 CA35.1
  BOTTOM w0.076: UCPU1.A68 112.68,72.88 110.23,72.88 v2(109.22,73.89)
H_CPUPWRGD_R: length 1.1
  TOP w0.127: RC77.1 109.25,73.19 T9.1
H_PROCHOT#: length 200.7
  TOP w0.127: v2(60.8,51.07) 60.86,51.01 PC1006.2 61.44,51.04 PR1124.1 ; v2(111.51,75.5) 111.42,75.59 RC83.2 RC84.1 ; RE96.2 172.43,60.16 v2(172.13,59.85)
  IN2 w0.089: v2(172.13,59.85) 171.9,60.08 165.91,60.08 v2(165.18,60.82)
  IN3 w0.089: v2(60.8,51.07) 60.76,51.02 60.76,50.25 59.73,49.22 59.73,36.95 62.07,34.61 62.07,32.18 60.33,30.44 45.92,30.44 45.11,29.63 44.51,29.63 43.22,30.92 39.85,30.92 39.19,30.26 38.66,30.26 38.46,30.06 37.49,30.06 36.94,29.51 v2(36.94,28.52)
  IN4 w0.081: v2(165.18,60.82) 164.27,60.82 162.69,62.4 162.69,62.9 160.6,64.99 159.13,64.99 157.61,66.51 154.52,66.51 153.36,65.36 150.15,65.36 149.2,66.3 146.41,66.3 146.2,66.1 146.2,64.98 145.57,64.35 142.09,64.35 142.06,64.32 141.53,64.32 140.74,63.53 137.94,63.53 137.65,63.24 132.99,63.24 132.87,63.37 128.88,63.37 126.85,65.39 124.75,65.39 124.33,65.81 124.33,66.93 123.47,67.78 123.08,67.78 122.4,68.46 122.4,69.33 120.93,70.8 120.5,70.8 119.94,71.36 119.71,71.36 117.58,73.49 113.51,73.49 v2(111.51,75.5) 111.09,75.08 109.76,75.08 108.67,73.99 108.67,73.85 105.95,71.14 105.61,71.14 105.25,70.77 99.67,70.77 98.86,71.58 97.81,71.58 97.45,71.94 92.18,71.94 91.82,72.3 80.08,72.3 79.5,72.88 71.55,72.88 69.8,71.13 69.8,69.97 69.44,69.61 69.44,69.23 65.79,65.57 65.79,62.42 64.43,61.06 64.43,58.57 64.57,58.43 64.57,56.64 62.04,54.11 62.04,53 60.83,51.8 60.83,51.1 v2(60.8,51.07)
  BOTTOM w0.127: v2(165.18,60.82) 165.28,60.92 166.65,60.92 v3(167.79,59.77) 168.04,59.53 168.04,58.72 PR405.2 ; PR316.1 36.73,28.74 v2(36.94,28.52)
H_PROCHOT#_EC: length 3.7
  TOP w0.127: UE5.A46 177.16,60.52 176.78,60.52 175.9,59.65 175.21,59.65 v3(175.13,59.57) 174.68,59.57 RE96.1
H_PROCHOT#_R: length 9.9
  TOP w0.127: RC84.2 112.78,76.59 112.88,76.59 113.31,76.16 v1(113.31,76.13) 113.31,75.93 112.88,75.5 v2(112.75,75.5)
  BOTTOM w0.076: v2(112.75,75.5) 112.62,75.5 112.12,74.99 112.12,74.53 112.55,74.1 114.53,74.1 115.55,73.08 115.55,71.52 115.25,71.22 UCPU1.C65
H_THERMTRIP#: length 79
  TOP w0.127: QE9.3 174.46,70.54 172.84,68.93 172.05,68.93 171.11,69.87 170.62,69.87 v2(170.62,69.87) ; RC80.2 115.29,75.59 v2(115.47,75.42)
  IN3 w0.089: v2(170.62,69.87) 170.08,69.87 168.97,70.98 166.29,70.98 165.86,70.54 161.76,70.54 160.29,69.08 155.69,69.08 153.71,67.1 v2(153.35,67.1)
  IN4 w0.081: v2(115.47,75.42) 116.18,74.71 117.65,74.71 118.08,74.28 119.47,74.28 120.49,73.26 120.49,72.23 121.12,71.59 122.39,71.59 123.8,70.19 123.8,68.61 124.38,68.04 124.7,68.04 125.71,67.03 132.91,67.03 134.77,65.16 139.83,65.16 141.61,66.94 145.42,66.94 145.69,67.22 145.69,69.33 146.28,69.91 147.47,69.91 148.59,68.79 148.59,68.39 149.79,67.19 153.26,67.19 v2(153.35,67.1)
  BOTTOM w0.076: UCPU1.C63 116.52,71.16 116.52,71.25 116.56,71.32 116.65,71.57 116.65,71.75 116.59,71.94 116.59,72.09 116.65,72.21 116.65,72.47 116.49,72.62 116.49,73.13 116.88,73.51 116.88,73.83 115.47,75.25 v2(115.47,75.42)
H_VCCST_PWRGD: length 41.3
  TOP w0.127: v2(176.2,61.49) 176.23,61.52 UE5.A44
  IN1 w0.081: v2(176.2,61.49) 177.99,61.49 178.24,61.74 179.93,61.74 182.31,64.12 184.07,64.12 184.65,64.69 189.47,64.69 189.53,64.76 190.09,64.76 190.4,65.07 190.56,65.23 192.7,65.23 192.76,65.17 193.6,65.17 193.83,65.41 193.83,67.16 v2(193.62,67.37)
  BOTTOM w0.127: U729.2 203.29,78.65 202.62,77.97 202.62,77.45 202.17,77.01 RE93.1 201.96,77.12 RE94.2 200.81,76.77 199.59,76.77 198.21,75.38 198.21,74.1 197.73,73.62 197.73,70.53 196.7,69.5 194.16,69.5 193.79,69.13 193.79,67.67 193.62,67.51 v2(193.62,67.37)
H_VCCST_PWRGD_P: length 176.5
  TOP w0.127: v2(72.42,74.96) 71.63,74.96 RC123.1
  IN2 w0.089: v2(153.9,66.75) 154.27,66.75 155.82,65.2 155.82,64.8 157.07,63.55 158.33,63.55 158.78,64 158.78,66.08 159.03,66.33 160.81,66.33 161.17,65.96 164.86,65.96 165.73,65.1 166.26,65.1 166.35,65 166.76,65 167.39,65.63 168.49,65.63 168.65,65.48 171.32,65.48 171.76,65.04 174.39,65.04 174.47,65.12 175.34,65.12 175.67,64.78 177.16,64.78 178.36,63.59 178.77,63.59 179.36,63 v2(179.75,63)
  IN3 w0.089: v2(187.95,77.77) 188.76,78.58 190.93,78.58 191.57,79.22 193.13,79.22 193.65,78.7 193.65,77.17 195.1,75.73 199.31,75.73 201.52,77.93 v2(201.52,79.04)
  IN4 w0.081: v2(72.42,74.96) 72.42,75.22 73.23,76.04 78.01,76.04 80.08,73.97 82.62,73.97 82.77,73.82 87.26,73.82 87.64,74.2 94.93,74.2 95.76,73.36 99.97,73.36 101.56,71.78 104.84,71.78 105.18,72.12 105.55,72.12 106.96,73.53 106.96,74.73 108.29,76.06 111.56,76.06 v2(112.12,75.5) 113.72,73.89 118.5,73.89 119.03,73.36 119.03,72.81 120.09,71.74 120.1,71.74 120.63,71.21 122.18,71.21 122.79,70.59 122.79,68.62 123.24,68.17 123.65,68.17 124.71,67.1 124.71,65.97 124.91,65.78 127.01,65.78 129.04,63.76 133.03,63.76 133.15,63.63 137.49,63.63 138.35,64.5 139.13,64.5 139.28,64.35 140.03,64.35 140.87,65.19 144.6,65.19 144.83,65.41 144.83,65.69 144.8,65.72 144.8,66.05 145.03,66.28 145.84,66.28 146.25,66.69 149.89,66.69 150.84,65.74 152.02,65.74 152.97,66.69 153.84,66.69 v2(153.9,66.75) ; v2(187.95,77.77) 187.85,77.68 187.85,74.14 v2(189,73)
  BOTTOM w0.127: v2(179.75,63) 179.79,63 180.26,62.52 182.7,62.52 183.49,63.3 v1(183.49,64.02) 183.49,69.14 184.93,70.58 184.93,70.78 185.64,71.5 187.04,71.5 188.54,73 v2(189,73) ; RC71.2 110.11,77 RC78.1 111.86,76.11 CA32.1 111.86,75.75 v2(112.12,75.5) ; v2(201.52,79.04) 201.17,78.69 RE94.1 201.64,78.04 201.68,78 U729.4
H_VCCST_PWRGD_XDP: length 6
  TOP w0.127: JXDP1.39 69.1,74.26 69.57,74.74 70.03,74.74 v1(70.18,74.89) 70.18,76.26 RC123.2 71.6,75.9 RC124.2
HDA_AUDIO_PD#: length 4.1
  TOP w0.127: v3(32.22,24.77) 31.99,25 RA59.2 31.22,25.69 30.88,26.03 29.69,26.03 29.46,26.26 29.46,26.48 UA2.47
HDA_BIT_CLK: length 5.4
  BOTTOM w0.076: 140.5,46.49 140.09,46.9 v1(140.09,47.51) 140.09,47.84 139.8,48.13 139.8,48.54 139.99,48.73 139.99,49.22 139.69,49.53 139.69,49.79 139.75,49.91 139.75,50.05 139.68,50.28 139.68,50.4 139.75,50.61 139.85,50.72 139.96,50.83 UCPU1.AY22
  BOTTOM w0.127: 140.5,46.49 RC93.2
HDA_BIT_CLK_R: length 138.4
  TOP w0.127: v2(38.62,27.39) 38.55,27.39 38.02,27.92 38.02,28.75 36.08,30.69 33.55,30.69 CA30.2 32.72,30.18 32.01,29.48 UA2.6
  IN2 w0.089: v2(80.06,27.92) 79.78,27.64 77.75,27.64 76.96,26.86 65,26.86 61.85,23.71 59.33,23.71 58.57,22.95 56.19,22.95 55.09,24.04 53.19,24.04 50.95,26.27 44.04,26.27 42.95,27.36 38.67,27.36 38.64,27.39 v2(38.62,27.39)
  BOTTOM w0.127: RC93.1 140.79,45.58 141.25,45.12 141.25,44.97 141.68,44.54 CC27.1 141.71,44.21 142.57,43.34 142.57,42.32 141.92,41.66 138.56,41.66 136.47,39.58 118.29,39.58 117.01,40.86 107.35,40.86 v3(106.91,40.42) 106.1,40.42 103.53,37.85 100.46,37.85 96.92,34.32 96.92,32.26 96.21,31.55 96.21,30.84 94.53,29.16 92.8,29.16 91.72,28.08 91.72,25.38 91.45,25.12 90.47,25.12 89.2,23.85 87.69,23.85 87.68,23.83 82.75,23.83 82.35,24.24 80.03,24.24 79.47,24.8 79.47,27.33 v2(80.06,27.92)
HDA_RST#: length 10
  BOTTOM w0.076: UCPU1.AW22 139.96,51.44 139.74,51.22 139.56,50.66 139.56,50.58 139.51,50.42 139.51,50.27 139.57,50.06 139.57,49.94 139.54,49.86 139.52,49.83 139.52,49.46 139.83,49.16 139.83,48.8 139.64,48.61 139.64,48.06 139.81,47.89 139.81,46.92 140.33,46.4 140.33,45.23 CR26.2
  BOTTOM w0.127: CR26.2 141.12,44.43 141.12,43.79 T192.1
HDA_SDIN0: length 142.2
  TOP w0.127: 142.53,46.82 141.66,46.82 v2(141.58,46.9) ; RA62.1 34.19,31.43 35.71,31.43 38.35,28.79 38.54,28.79 v2(38.55,28.78)
  IN2 w0.089: v2(80.24,28.48) 80.49,28.23 80.49,27.77 79.81,27.09 78.49,27.09 77.58,26.18 65.41,26.18 61.09,21.87 55.89,21.87 55.09,22.67 53.85,22.67 53.28,23.24 52.97,23.24 50.32,25.89 42.93,25.89 42.2,26.62 40.09,26.62 39.72,26.99 38.26,26.99 38.09,27.16 38.09,27.65 38.23,27.79 38.91,27.79 39.14,28.03 39.14,28.54 38.9,28.79 38.56,28.79 v2(38.55,28.78)
  IN4 w0.081: v2(93.16,28.74) 93.16,29.27 91.98,30.45 91.61,30.45 91.33,30.72 89.08,30.72 87.11,28.75 81.63,28.75 81.32,29.06 80.97,29.06 80.39,28.48 v2(80.24,28.48)
  BOTTOM w0.127: v2(93.16,28.74) 93.26,28.64 96.12,28.64 96.46,28.99 96.46,31.44 97.17,32.15 97.17,34.21 100.56,37.6 103.64,37.6 105.96,39.92 108.11,39.92 108.8,40.61 116.86,40.61 118.35,39.12 136.49,39.12 138.79,41.41 142.02,41.41 142.84,42.22 142.84,43.53 142.21,44.16 142.21,46.51 141.82,46.9 v2(141.58,46.9) 140.78,46.9 140.43,47.25 140.43,47.93 140.65,48.15 140.65,49.19 140.49,49.35 140.49,50.22 140.53,50.25 UCPU1.BA21
HDA_SDIN0_R: length 2.7
  TOP w0.127: RA62.2 32.88,31.2 32.28,30.59 v3(31.85,30.59) 31.51,30.59 31.19,30.28 UA2.8
HDA_SDOUT: length 27
  TOP w0.127: v2(140.23,48.27) 139.98,48.01 RC94.2 139.98,47.05 140.54,46.49 RC187.2 CR24.2 ; RH24.2 157.79,50.25 157.22,49.68 156.01,49.68 155.32,50.38 154.2,50.38 v2(153.75,49.92)
  IN3 w0.089: v2(153.75,49.92) 152.52,48.69 148.56,48.69 147.35,47.48 147.35,46.77 145.97,45.4 143.69,45.4 140.82,48.27 v2(140.23,48.27)
  BOTTOM w0.076: UCPU1.BB22 139.96,49.54 140.18,49.31 140.18,48.32 v2(140.23,48.27)
HDA_SDOUT_R: length 138.8
  TOP w0.127: v2(139.85,40.5) 139.07,41.28 RC94.1 ; UA2.5 32.95,29.08 CA27.2 33.58,29.7 34.75,29.7 35.1,30.06 36.36,30.06 37.77,28.65 37.77,27.75 38.1,27.42 38.1,27.3 38.82,26.58 v2(38.95,26.58)
  IN2 w0.089: v2(38.95,26.58) 39.13,26.4 42.11,26.4 42.84,25.68 50.23,25.68 52.88,23.02 53.19,23.02 54.56,21.65 61.18,21.65 65.5,25.97 77.67,25.97 78.58,26.87 79.9,26.87 80.71,27.68 80.71,28.8 v2(80.21,29.3)
  IN4 w0.081: v2(80.21,29.3) 80.39,29.47 81.5,29.47 81.8,29.17 83.89,29.17 85.86,31.14 91.51,31.14 91.78,30.87 92.15,30.87 95.7,27.32 95.7,26.85 v2(95.23,26.37)
  BOTTOM w0.127: v2(95.23,26.37) 97.26,28.41 97.26,31.16 97.96,31.85 97.96,33.08 98.33,33.45 99.18,33.45 99.74,34 99.74,34.32 102.2,36.78 103.94,36.78 106.27,39.11 116.97,39.11 117.99,38.09 137.45,38.09 v3(137.96,38.6) v2(139.85,40.5)
HDA_SYNC: length 8.9
  BOTTOM w0.076: UCPU1.BA22 140.13,50.34 140.25,50.45 140.25,50.78 140.41,50.94 140.72,50.94 140.83,50.84 140.83,50.28 140.68,50.14 140.68,49.46 140.84,49.3 140.84,48.07 140.62,47.85 140.62,47.32 140.86,47.09 141.15,47.09 v1(141.48,47.42) 141.84,47.42 142.72,46.53 RC92.2
HDA_SYNC_R: length 154.8
  TOP w0.127: UA2.10 31.08,31.08 32.09,32.09 CA24.2 33.53,32.57 35.13,32.57 38.09,29.62 v2(38.4,29.62)
  IN4 w0.081: v2(78.87,28.69) 78.56,28.69 75.76,25.89 75.23,25.89 67.17,17.82 63.84,17.82 62.99,16.97 58.95,16.97 55.87,20.06 54.78,20.06 52.88,18.15 51.27,18.15 49.09,15.97 43.69,15.97 41.66,18 41.66,19.37 41.17,19.87 39.47,19.87 38.59,20.75 38.59,24.32 39.83,25.56 39.83,26.46 39.29,26.99 38.2,26.99 38.04,27.16 38.04,29.26 v2(38.4,29.62)
  BOTTOM w0.127: RC92.1 143.26,44 143.26,42.11 142.3,41.16 139.01,41.16 136.58,38.72 118.35,38.72 117.45,39.62 106.05,39.62 103.73,37.29 101.99,37.29 99.45,34.76 98.76,34.76 97.45,33.45 97.45,32.07 96.72,31.34 96.72,28.88 96.15,28.32 92.33,28.32 91.97,27.96 91.97,25.28 91.56,24.86 90.58,24.86 89.31,23.6 87.8,23.6 87.78,23.58 82.55,23.58 82.2,23.93 79.98,23.93 79.22,24.69 79.22,28.34 v2(78.87,28.69)
HOST_DEBUG_TX: length 12.7
  TOP w0.127: v2(179.75,64.5) 179.75,64.42 179.88,64.29 179.88,63.72 179.27,63.11 179.27,62.8 179.07,62.59 178.44,62.59 178.26,62.77 178.01,62.77 UE5.B44
  BOTTOM w0.127: JDEG1.8 173.15,67.85 174.55,66.46 174.7,66.46 175.29,65.87 175.88,66.46 177.34,66.46 177.93,65.87 177.93,65.42 178.42,64.93 179.02,64.93 179.07,64.88 179.58,64.88 179.75,64.7 v2(179.75,64.5)
HOST_SD_WP#: length 81.3
  IN4 w0.081: v2(199.52,16.26) 198.81,16.98 197.91,16.98 196.78,18.11 193.66,18.11 193.56,18 186.91,18 186.46,18.46 178.33,18.46 175.41,21.38 175.41,24.68 173.33,26.77 173.33,27.9 170.05,31.18 170.05,36.15 166.89,39.31 166.89,43.08 167.3,43.49 167.3,44.04 166.69,44.65 166.69,45.17 159.19,52.67 159.19,57.08 158.24,58.02 158.24,58.68 v2(157.28,59.65)
  BOTTOM w0.127: JIO1.37 199.41,16.16 v2(199.52,16.26) ; v3(157.94,59.12) 157.41,59.65 v2(157.28,59.65) 157.11,59.48 156.15,59.48 RC292.2 154.49,59.95 153.78,60.66 152.45,60.66 152.3,60.51 151.15,60.51 UCPU1.AB3
HP2_D_L: length 10.9
  TOP w0.203: UA2.32 23.66,29.08
  TOP w0.381: 23.66,29.08 23.22,29.08 23.14,29.15 22.24,29.15 v1(21.85,28.76) 21.54,28.44 20.63,28.44 20.32,28.14 20.32,26.16 19.82,25.66 RA50.2 19.34,25.66 v2(19.04,25.37)
  BOTTOM w0.381: RA50.2 19.34,25.66 v2(19.04,25.37) ; RA50.2 RA48.2 ; RA50.2 19.71,25.61 RA17.1
HP2_D_L_C: length 12.6
  TOP w0.127: v2(14.91,26.93) 14.71,27.14 v1(14.25,27.14)
  IN4 w0.381: JHP1.1 14,25.51 14.91,26.42 v2(14.91,26.93)
  BOTTOM w0.305: CA29.2 19.79,23.81 20.57,23.03 LA7.2
  BOTTOM w0.381: v2(14.91,26.93) 15.42,26.93 15.47,26.98 17.12,26.98 DA2.3 18.21,25.15 19.56,23.81 CA29.2
HP2_D_L_R1: length 2.5
  BOTTOM w0.127: v3(21.46,25.97) 21.46,25.71 20.63,24.87 RA17.2
  BOTTOM w0.381: RA17.2 20.68,24.67 LA7.1
HP2_D_R: length 12
  TOP w0.203: UA2.33 24.61,28.68 23.84,28.68 23.77,28.6 23.35,28.6
  TOP w0.381: 23.35,28.6 v2(22.66,28.6)
  BOTTOM w0.254: RA15.1 16.64,27.59 RA60.1 RA49.2 RA51.2 19.11,27.63 19.91,28.43 19.91,29.76 20.4,30.25 v3(21.85,30.25) 22.11,30.25 22.66,29.7 v2(22.66,28.6)
HP2_D_R_C: length 25.1
  IN1 w0.254: v2(14.15,24.47) 15.42,25.74 15.42,27.14 14.86,27.69 14.86,34.3 14.4,34.76 14.4,35.59 13.97,36.03 7.34,36.03 JHP1.2
  BOTTOM w0.254: CA69.1 14.45,24.16 v2(14.15,24.47) ; CA69.1 LA6.2 ; CA69.1 15.29,24.16 16.28,25.15 DA2.2
HP2_D_R_R2: length 5.3
  BOTTOM w0.127: LA6.1 14.38,25.91 13.18,24.71 v3(13.18,23.6)
  BOTTOM w0.254: RA15.2 14.4,27.11 14.4,26.34 LA6.1
I2C0_SCK_EDP: length 26.5
  TOP w0.127: R291.2 199.89,27.71 v2(201.65,27.71) 202.12,27.71 202.98,28.56 U48.7 ; v2(192.51,23.76) 192.51,24.46 190.14,26.82 190.14,29.46 v2(190.44,29.76)
  IN1 w0.081: v2(201.65,27.71) 197.76,27.71 195.58,29.89 190.57,29.89 v2(190.44,29.76)
  BOTTOM w0.127: R287.2 190.03,28.79 190.44,29.2 v2(190.44,29.76) ; JEDP.1 192.75,24.01 v2(192.51,23.76)
I2C0_SCK_EDP_PCH: length 107.6
  TOP w0.127: R291.1 198.4,28.28 v3(196.89,28.28) v2(195.17,28.28)
  IN2 w0.089: v2(164.7,36.34) 164.7,38.29 163.56,39.44 163.56,40.74 164.4,41.58 164.4,47.1 158.76,52.74 158.76,54.59 157.47,55.88 156.66,55.88 156.26,56.28 154.71,56.28 154.48,56.5 152.75,56.5 152.36,56.9 152.36,58.01 151.83,58.54 151.83,60.51 149.72,62.62 v2(149.09,62.62)
  IN3 w0.089: v2(195.17,28.28) 195.17,25.74 189.51,20.08 186.05,20.08 185.08,19.12 180.16,19.12 177.62,16.58 163.42,16.58 162.27,15.43 159.55,15.43 158.7,16.28 158.7,18.4 161.72,21.41 163.85,23.55 163.85,25.91 164.63,26.69 164.63,29.31 165.47,30.14 165.47,34.55 165.19,34.83 165.19,35.85 v2(164.7,36.34)
  BOTTOM w0.127: UCPU1.U6 149.39,62.92 v2(149.09,62.62)
I2C0_SDA_EDP: length 20.6
  TOP w0.127: R292.2 v3(200.84,26.5) 201.48,26.5 v2(201.64,26.66) 203.63,28.65 U48.6
  IN1 w0.081: v2(201.64,26.66) 198.3,26.66 197.73,27.24 v2(190.79,27.24)
  BOTTOM w0.127: JEDP.6 192.75,26.87 191.16,26.87 v2(190.79,27.24) 190.13,27.9 R288.2
I2C0_SDA_EDP_PCH: length 107.4
  TOP w0.127: v2(198.06,26.34) 198.62,26.34 R292.1
  IN2 w0.089: v2(148.42,62.64) 148.9,62.16 149.87,62.16 151.61,60.42 151.61,58.45 152.15,57.92 152.15,56.81 152.66,56.29 154.4,56.29 154.62,56.07 156.17,56.07 156.57,55.66 157.38,55.66 158.54,54.5 158.54,52.65 164.18,47.01 164.18,41.67 163.34,40.83 163.34,39.35 164.3,38.39 164.3,36.09 v2(164.7,35.69)
  IN3 w0.089: v2(164.7,35.69) 164.71,35.69 164.93,35.47 164.93,34.7 165.25,34.39 165.25,30.3 164.31,29.37 164.31,26.7 163.62,26.01 163.62,23.64 161.62,21.64 158.46,18.48 158.46,16.22 159.48,15.19 159.48,14.96 159.83,14.61 160.35,14.61 160.95,15.21 162.41,15.21 163.52,16.32 177.72,16.32 180.3,18.9 185.22,18.9 186.11,19.79 189.58,19.79 195.92,26.12 197.85,26.12 v2(198.06,26.34)
  BOTTOM w0.127: UCPU1.U7 148.74,62.96 v2(148.42,62.64) ; v2(164.7,35.69) 164.7,35.69 v3(164.02,35.69)
I2C1_SCK: length 15.4
  TOP w0.127: v2(185.04,17.81) 185.06,17.79 MD10.3 185.29,16.65 188.34,13.6 v3(188.54,13.6) 188.67,13.47 190.4,13.47 R1105.1 191.06,14.06 RH456.2 192.63,15.63 192.63,16.34 192.22,16.75 191.84,16.75 191.62,16.97 QH7.4
  BOTTOM w0.127: v2(185.04,17.81) 185.66,18.43 185.66,19.36 JTP1.3
I2C1_SCK_TP: length 88.6
  TOP w0.127: QH7.3 191.16,15.07 RH456.1 v2(190.96,16.04)
  IN4 w0.081: v2(191.49,18.93) 191.25,18.69 187.19,18.69 186.74,19.14 182.04,19.14 179.02,22.16 179.02,25.31 174.42,29.9 174.17,29.9 173.1,30.98 173.1,31.55 172.59,32.06 172.59,36.97 172.1,37.46 172.1,39.73 170.28,41.54 170.28,43.09 169.71,43.66 169.71,44.95 165.99,48.67 165.34,48.67 164.93,49.07 164.93,50.15 166.25,51.47 166.25,55.51 163.9,57.86 163.9,59.95 162.5,61.35 162.29,61.35 v2(161.83,61.81) 161.83,62.56 160.62,63.77 158.86,63.77 158.06,64.57 155.58,64.57 154.88,63.87 151.33,63.87 150.82,64.38 147.61,64.38 v2(147.1,63.88)
  BOTTOM w0.076: UCPU1.U9 147.44,63.28 147.1,63.61 v2(147.1,63.88)
  BOTTOM w0.127: RC285.2 159.89,60.74 160.77,60.74 v1(161.22,61.19) v2(161.83,61.81) ; v2(190.96,16.04) 190.96,18.4 v2(191.49,18.93)
I2C1_SDA: length 11.8
  TOP w0.127: QH7.1 189.52,15.26 187.33,15.26 187,15.6 MD10.2 ; MD10.2 188.47,16.65 RH461.2 189.71,17.89 R1104.1 v3(189.71,19.39) ; MD10.2 187,17.31 v2(186.59,17.71)
  BOTTOM w0.127: v2(186.59,17.71) 186.16,18.14 JTP1.2
I2C1_SDA_TP: length 83.4
  TOP w0.127: QH7.6 188.58,15.83 RH461.1 187.88,15.83 v2(187.78,15.73)
  IN2 w0.089: v2(179.29,18.95) 180.95,18.95 184.16,15.73 v2(187.78,15.73)
  IN4 w0.081: v2(147.78,61.8) 148.35,61.24 152.92,61.24 153.51,61.83 157.83,61.83 158.88,62.87 160.25,62.87 160.93,62.19 160.93,59.44 v2(160.53,59.04) 160.54,59.02 160.54,57.59 159.4,56.45 159.4,52.75 165.71,46.44 166.23,46.44 167.46,45.2 167.97,45.2 168.44,44.73 168.44,44.33 167.82,43.72 167.82,43.22 167.49,42.88 167.49,40.68 167.82,40.34 167.82,38.68 170.26,36.24 170.26,31.27 173.54,27.99 173.54,26.86 175.62,24.77 175.62,21.5 177.2,19.92 178.31,19.92 v2(179.29,18.95)
  BOTTOM w0.127: v2(160.53,59.04) 160.45,59.04 159.82,59.67 RC284.2 ; UCPU1.U8 148.09,63.08 147.78,62.77 147.78,61.81 v2(147.78,61.8)
I_ADP: length 206.5
  TOP w0.127: UE5.A12 188.16,65.02 188.16,65.02 189.43,65.02 189.66,65.25 v2(189.69,65.25)
  IN1 w0.081: v2(189.69,65.25) 189.48,65.25 189.31,65.08 184.45,65.08 183.88,64.51 180.95,64.51 179.84,63.39 179.59,63.39 179.33,63.13 179.22,63.13 178.95,63.41 178.38,63.41 177.22,62.25 174.71,62.25 174.44,61.98 174.44,60.99 174.32,60.86 174.32,58.3 175.07,57.55 175.07,55.57 174.5,54.99 174.5,54.62 172.14,52.26 172.14,48.33 169.22,45.41 169.22,44.6 166.68,42.07 166.68,40.89 166.12,40.32 165.81,40.32 165.45,39.96 165.45,37.92 164.29,36.76 164.29,34.09 164.47,33.9 164.47,28.25 156.34,20.11 126.38,20.11 125.46,19.2 118.98,19.2 117.78,20.4 112.27,20.4 110.63,22.05 103.1,22.05 102.86,21.8 97.93,21.8 96.25,23.48 96.25,26.51 92.09,30.67 91.68,30.67 90.09,32.26 87.98,32.26 87.63,32.61 84.07,32.61 81.77,30.32 76.8,30.32 73.05,26.56 64.13,26.56 61.3,23.73 59.84,23.73 59.31,23.2 56.07,23.2 55.24,24.02 50.99,24.02 50.45,23.49 50.45,22.59 48.47,20.61 44.07,20.61 43.6,21.07 43.43,21.47 43.43,22.47 43.01,22.89 42.9,22.89 39.6,26.2 39.12,26.2 39.11,26.19 38.72,26.19 38.66,26.25 v2(38.42,26.25)
  BOTTOM w0.127: PR315.1 38.15,24.27 37.95,24.47 37.95,25.78 v2(38.42,26.25)
I_BATT: length 186.7
  TOP w0.127: PR318.1 40.36,23.58 40.67,23.28 40.67,19.83 40.12,19.28 40.12,18.74 40.32,18.54 42.11,18.54 42.19,18.62 44.34,18.62 v2(44.57,18.39)
  IN1 w0.081: v2(44.57,18.39) 44.57,18.47 45.11,19.01 46.19,19.01 46.39,18.8 47.04,18.8 47.81,19.57 49.25,19.57 49.46,19.79 50.73,19.79 51.79,20.85 54.29,20.85 54.81,21.37 62.61,21.37 63.37,20.61 67.19,20.61 68.26,21.68 71.81,21.68 75.95,25.82 78.78,25.82 79.47,25.13 81.8,25.13 82.69,26.02 89.52,26.02 90.55,24.99 91.76,24.99 92.58,24.16 92.58,23.62 93.57,22.64 94.39,22.64 96.67,20.36 102.4,20.36 102.79,19.97 109.17,19.97 110.02,19.13 117.25,19.13 118.72,17.65 125.74,17.65 126.59,18.51 132.13,18.51 132.38,18.25 147.01,18.25 147.63,18.86 157.9,18.86 158.52,19.48 161.2,19.48 164.33,22.6 164.33,24.86 166.93,27.47 166.93,27.48 166.96,27.51 166.96,32.23 166.87,32.32 166.87,33.22 168.35,34.7 168.35,36.78 171.26,39.69 171.26,43.32 171.69,43.75 171.69,45.4 173.22,46.93 173.22,50.52 176.37,53.67 v2(177.15,53.67)
  BOTTOM w0.127: RE64.2 183.36,57.03 183.36,56.6 183.09,56.33 182.62,56.33 181.84,55.54 181.49,55.54 181.44,55.59 180.98,55.59 180.33,54.94 177.95,54.94 177.15,54.14 v2(177.15,53.67)
IA1N: length 36.4
  TOP w0.254: v2(75.54,47.42) 75.12,47.42 v1(74.66,47.88) 74.17,48.37 v2(74.17,48.38)
  IN3 w0.254: v2(75.54,47.42) 75.63,47.51 78.69,47.51 80.23,45.97 84.44,45.97 85.52,47.05 85.52,49.72 86.06,50.25 86.06,51.62 85.75,51.92 85.75,56.85 87.13,58.23 88.81,58.23 90.68,60.09 90.68,62.72 v2(90.91,62.95)
  BOTTOM w0.254: v2(74.17,48.38) 73.7,48.85 PR1112.1 ; PR1115.1 75.02,46.9 v2(75.54,47.42) ; PL1102.3 90.96,62.9 v2(90.91,62.95)
IA1P: length 33.9
  IN3 w0.254: v2(75.51,48) 75.62,47.9 78.85,47.9 80.41,46.35 84.24,46.35 85.13,47.24 85.13,49.88 85.66,50.42 85.66,51.46 85.36,51.76 85.36,57.03 86.96,58.63 88.65,58.63 90.27,60.26 90.27,62.7 v2(90.02,62.95)
  BOTTOM w0.254: v2(90.02,62.95) 89.97,62.9 PL1102.2 ; PR1118.1 73.64,47.02 74.57,47.96 PR1116.2 75.48,47.96 v2(75.51,48)
IA2N: length 25.3
  IN4 w0.203: v2(90.89,55.25) 90.89,55.23 90.7,55.04 90.7,53.51 89.01,51.82 87.14,51.82 85.57,50.26 78.96,50.26 77.62,48.93 76.76,48.93 v2(76.56,48.73)
  BOTTOM w0.254: v2(76.56,48.73) 76.24,48.41 PR1107.1 76.81,47.53 76.81,46.82 75.97,45.98 75.97,45.79 75.29,45.11 PR1120.2 ; v2(90.89,55.25) PL1101.3
IA2P: length 21.1
  IN4 w0.254: v2(90.2,55.25) 90.3,55.15 90.3,53.61 88.87,52.18 86.99,52.18 85.43,50.62 78.78,50.62 77.46,49.3 76.62,49.3 v2(76.56,49.36)
  BOTTOM w0.254: PR1109.1 75.59,49.03 PR1111.2 76.26,49.11 76.51,49.36 v2(76.56,49.36) ; v2(90.2,55.25) PL1101.2
IA_BST1: length 3.4
  BOTTOM w0.254: PU1102.3 79.61,63.21 79.07,63.75 79.07,64.33 v1(78.9,64.51) 78.3,65.11 PC1126.2
IA_BST1_R: length 2.3
  BOTTOM w0.254: PR1113.1 78.35,67.6 v1(78.3,67.55) PC1126.1
IA_BST2: length 1.3
  BOTTOM w0.254: PU1101.3 78.99,55.63 PC1116.2
IA_BST2_R: length 2.3
  BOTTOM w0.127: PR1105.1 v1(76.91,56.71)
  BOTTOM w0.254: PR1105.1 78.16,56.03 PC1116.1
IA_FCCM1: length 7.8
  TOP w0.254: v2(76.49,58.48) 77.29,57.68 PR1119.1
  IN1 w0.254: v2(79.25,62.39) 79.25,60.24 77.48,58.48 v2(76.49,58.48)
  BOTTOM w0.254: PU1102.2 79.57,62.71 v2(79.25,62.39)
IA_FCCM2: length 3
  BOTTOM w0.127: v1(78.13,53.78) 78.36,54.01 PR1110.1
  BOTTOM w0.254: PR1110.1 78.68,55.13 PU1101.2
IA_SNUB1: length 1.6
  TOP w0.127: PC1130.1 v1(85.37,60.38)
IA_SNUB2: length 2
  TOP w0.127: PR1106.2 v1(85.12,57.29)
IA_SW1:
  vias: v1(88.82,61.05) v2(87.07,65.08) v2(88.04,65.11) v2(88.67,60.21) v2(89.1,65.26) v2(89.22,64.39) v2(89.23,61.82)
IA_SW2:
  vias: v1(86.84,57.36) v2(87.5,57.39) v2(88.27,57.37) v2(89.03,57.37) v2(89.18,56.7) v2(89.19,56.05) v2(89.18,54.75) v2(89.15,54.14) v2(89.15,53.53)
IA_SWH1: length 5.1
  BOTTOM w0.127: PR1113.2 79.57,66.26 80.37,67.06 v1(80.37,68.74)
  BOTTOM w0.254: PR1113.2 80.06,65.71 PU1102.5
IA_SWH2: length 3.6
  BOTTOM w0.127: PR1105.2 78.17,58.12 78.17,58.99 v1(78.33,59.15)
  BOTTOM w0.254: PR1105.2 79.64,56.63 PU1101.5
IMON_GT: length 5.2
  TOP w0.203: PU1000.14 71.51,52.96 72.07,52.96 72.5,52.54 72.77,52.54 72.79,52.52 v2(72.98,52.52)
  BOTTOM w0.127: v1(74.47,52.23) 74.19,52.52 v2(72.98,52.52)
  BOTTOM w0.254: v2(72.98,52.52) 72.74,52.28 PC1065.2 PR1071.2
IMON_IA: length 4.6
  TOP w0.203: PU1000.2 67.56,51.01 67.56,50.27 67.25,49.96 v2(67.11,49.96)
  BOTTOM w0.127: PR1099.2 66.71,50.63 PC1131.2 68.01,50.4 67.57,49.96 v2(67.11,49.96) v1(67.11,49.36)
IMON_VSA: length 3.1
  TOP w0.203: v2(70.43,57.29) 70.43,57.07 69.96,56.59 69.96,56.11 PU1000.23
  BOTTOM w0.254: PC1080.1 70.04,56.22 70.45,56.63 PR1069.1 70.49,57.24 v2(70.43,57.29)
IMVP_VR_ON: length 245
  TOP w0.127: UE5.A1 188.6,59.52 v2(188.77,59.7) ; v2(53.7,39.58) 55.2,41.08 RE100.2 54.41,42.6 53.72,41.92 53.4,41.92 52.99,41.5 UC11.2
  IN1 w0.089: v2(188.77,59.7) 186.61,61.86 186.07,61.86 185.83,61.63 182.63,61.63 181.85,60.85 181.85,58.9 181.37,58.42 179.97,58.42 178.29,56.74 178.29,55.43 178.64,55.08 178.64,53.99 175.76,51.11 175.76,49.23 173.94,47.42 173.94,46.75 172.33,45.13 172.33,43.48 171.92,43.08 171.92,39.45 170.19,37.72 170.19,35.19 172.53,32.85 172.53,21.08 171.79,20.34 162.98,20.34 161.48,18.84 158.81,18.84 158.19,18.23 147.89,18.23 147.28,17.62 132.12,17.62 131.87,17.87 126.86,17.87 125.37,16.37 118.17,16.37 116.06,18.49 109.75,18.49 109.63,18.6 106.82,18.6 106.71,18.49 102.57,18.49 101.36,19.7 96.4,19.7 94.1,22 92.49,22 89.14,25.35 82.92,25.35 82.07,24.5 79.2,24.5 78.66,25.04 76.08,25.04 71.43,20.39 69.35,20.39 66.99,18.03 65.04,18.03 62.41,20.66 55,20.66 53.27,18.94 48.08,18.94 47.31,18.17 45.89,18.17 45.5,17.77 43.66,17.77 43.32,18.11 43.32,19.08 41.84,20.56 41.84,21.69 41.58,21.94 40.75,21.94 39.63,23.07 39.06,23.07 38.58,23.55 38.58,24.23 37.37,25.44 37.37,28.73 37.25,28.85 37.25,31.14 39.17,33.05 40.05,33.05 42.13,35.13 42.13,35.56 45.81,39.24 45.81,40.71 47.51,42.41 v2(47.51,42.91)
  BOTTOM w0.127: v2(47.51,42.91) 48.1,42.32 50.22,42.32 50.67,41.87 51.12,41.87 52.05,40.95 52.05,39.42 52.36,39.11 53.23,39.11 v2(53.7,39.58)
IMVP_VR_ON_P: length 15.4
  TOP w0.127: UC11.4 53.92,43.52 RE100.1 RE101.1 56.36,43.72 56.36,44.14 56.38,44.14 56.87,44.64 v1(57.05,44.64) 60.45,44.64 60.6,44.79 61.32,44.79 62.21,45.68 62.87,45.68 63.51,46.33 63.51,46.99 63.77,47.24 63.77,49.01 63.6,49.17 PR1029.1
INA199_OUT: length 51.6
  TOP w0.127: PU201.3 89.85,73.31 90.71,73.31 v2(90.73,73.29) 90.73,74.02 PC204.1 PR227.1 90.71,76.15 90.71,76.67 PD201.1 89.51,76.23 v3(89.51,75.62)
  BOTTOM w0.127: v2(90.73,73.29) 91.64,72.37 91.64,69.65 90.31,68.31 86.9,68.31 84.51,70.69 83.68,70.69 82.92,69.93 79.4,69.93 79.04,70.29 75.9,70.29 75.55,69.94 74.12,69.94 72.61,68.42 67.78,68.42 67.65,68.55 64.28,68.55 63.73,69.1 62.89,69.1 62.15,68.35 60.76,68.35 60.28,67.87 60.28,64.94 60.91,64.32 60.91,62.71 PR214.1
INTRUDER#: length 14
  TOP w0.127: RC69.1 147.93,45.95 v2(147.8,46.08) ; v2(142.6,54.37) 143.05,54.82 v1(143.05,55.33)
  IN4 w0.081: v2(142.6,54.37) 142.89,54.37 143.08,54.19 143.08,52.93 144.14,51.87 144.56,51.87 144.98,51.45 145.46,51.45 148.26,48.65 148.26,46.53 v2(147.8,46.08)
  BOTTOM w0.076: UCPU1.AP16 v2(142.6,54.37)
INV_PWM_R: length 7.1
  TOP w0.127: R545.1 MC3.1 193.55,28 v2(193.73,28) ; R545.1 193.54,29.95 v3(194.09,29.95) ; R545.1 192.53,29.9 191.24,29.9 190.66,30.48 D73.1
  BOTTOM w0.127: JEDP.8 193.6,27.87 v2(193.73,28)
IRQ_SERIRQ: length 62.7
  TOP w0.127: v2(180.72,69.43) 180.72,69.43 180.86,69.29 180.86,68.72 UE5.A28
  IN1 w0.081: v2(180.72,69.43) 180.72,69.43 180.82,69.33 180.82,68.59 180.49,68.26 178.87,68.26 177.2,66.59 175.87,66.59 175.22,65.94 175.22,65.27 173.35,63.4 173.35,61.37 173.27,61.29 173.27,59.71 171.63,58.07 171.63,52.95 171.3,52.61 171.3,48.68 169.57,46.95 167.58,46.95 163.28,42.65 161.11,42.65 160.27,43.49 157.2,43.49 155.85,42.15 152.98,42.15 v2(152.78,41.94)
  BOTTOM w0.076: 146.81,46.14 146.46,46.5 146.46,48.8 145.72,49.54 145.72,50.62 UCPU1.AY11
  BOTTOM w0.127: 146.81,46.14 147.02,45.93 147.37,45.93 147.86,45.45 RC21.2 148.09,45.45 148.64,44.9 148.64,44.28 149.63,43.29 v3(150.57,43.29) 151.44,43.29 v2(152.78,41.94)
ISEN1_IA: length 11
  TOP w0.203: PU1000.9 70.36,50.58 70.94,50 70.94,49.36 70.71,49.13 PC1070.2 ; PC1070.2 70.59,49.62 v2(70.46,49.74) ; PC1070.2 70.56,49.11 PR1127.1
  IN2 w0.254: v2(70.46,49.74) 71,49.74 73.44,47.3 73.44,46.39 v2(73,45.94)
  BOTTOM w0.254: v2(73,45.94) 73.04,45.98 PR1118.2 73.64,45.12 PR1120.1
ISEN2_IA: length 7.5
  TOP w0.203: PR1128.1 v1(73.76,49.51) 73.45,49.51 73.1,49.87 v2(73.03,49.87) 72.21,49.87 PC1133.2 71.29,49.32 71.29,50.14 70.76,50.66 PU1000.10
  BOTTOM w0.254: v2(73.03,49.87) 73.15,49.87 73.23,49.95 PR1112.2 PR1109.2
ISUMN_GT: length 37.2
  TOP w0.127: PR1068.2 v1(75.82,58.86)
  TOP w0.254: PR1068.2 PR1085.2 76.28,56.73 v2(76.41,56.85)
  IN2 w0.203: v2(76.41,56.85) 77.4,55.86 77.4,48.92 80.41,45.91 84.38,45.91 84.71,46.24 89.89,46.24 ; v2(90.73,47.33) 90.5,47.1 90.5,46.49 90.25,46.24 89.89,46.24 ; v2(89.93,42.27) 89.89,42.31 89.89,46.24
  BOTTOM w0.203: PR1078.2 PC1075.2 PC1067.2 75.49,56.9 PC1083.1
  BOTTOM w0.254: v2(89.93,42.27) 89.93,42.3 90.09,42.47 PH1009.2 ; v2(90.73,47.33) 90.95,47.11 PL1100.3 ; v2(76.41,56.85) 76.33,56.85 76.33,56.85 PC1083.1
ISUMN_GT_R: length 4
  TOP w0.203: PU1000.20 71.86,55.36 v3(72.63,56.13) 73.23,56.73 PC1069.1 PR1085.1
ISUMN_IA: length 40
  TOP w0.203: PC1070.1 PC1133.1 PC1084.1
  TOP w0.254: v2(72.14,46.49) 72.34,46.69 72.34,48.19 PC1084.1 73.32,48.22 75.16,46.38 v2(75.16,45.66)
  IN4 w0.254: v2(72.14,46.49) 71.92,46.71 71.92,47.37 72.5,47.95 72.97,47.95 74.14,49.13 74.14,49.62 74.89,50.36 75.3,50.36 76.64,51.71 76.64,52.53 78.51,54.4 79.9,54.4 80.44,53.86 84.42,53.86 86,55.44 86,57.24 85.69,57.55 85.69,58.17 85.83,58.31 v2(85.83,58.35)
  BOTTOM w0.203: PC1133.1 PC1084.1 ; PC1133.1 71.5,48.19 PR1062.2 ; PC1133.1 PC1085.2 PC1094.2
  BOTTOM w0.254: PH1005.2 86.08,58.61 v2(85.83,58.35) ; v2(72.14,46.49) 72.14,47.63 72.37,47.86 PC1084.1 ; PR1107.2 76.24,46.99 75.49,46.24 75.49,45.96 75.2,45.66 v2(75.16,45.66) 74.84,45.66 PR1115.2
ISUMN_IA_R: length 3.4
  TOP w0.203: PU1000.8 69.96,50.27 v2(70.05,50.17)
  BOTTOM w0.203: v2(70.05,50.17) 70.23,50.35 71.1,50.35 PC1088.2
  BOTTOM w0.254: PR1061.2 71.45,49.16 PC1088.2
ISUMN_VSA: length 17.9
  TOP w0.203: PR1075.2 66.65,60 PR1092.2 v2(66.62,60.66)
  BOTTOM w0.203: 66.65,60.64 66.75,60.54 69.91,60.54 v1(70.56,59.89) 74.38,59.89 74.79,60.3 74.79,62.24 74.96,62.4 PL1005.3 ; 66.65,60.64 v2(66.62,60.66) ; 66.65,60.64 PC1087.1 PR1075.2 ; PC1071.2 PR1075.2 ; PR1075.2 PR1058.2
  BOTTOM w0.254: 72.87,59.89 72.87,59.57 72.48,59.18 PH1006.2
ISUMN_VSA_R: length 3.1
  TOP w0.203: PU1000.28 67.96,56.74 67.54,57.16 v1(67.54,57.24) PC1068.1 PR1075.1
ISUMP_GT: length 6.1
  TOP w0.203: PU1000.19 72.2,54.96 v2(72.47,55.23)
  BOTTOM w0.203: PR1078.1 73.64,54.36 PR1097.1 ; PR1078.1 72.57,55.13 v2(72.47,55.23) ; PR1078.1 PC1075.1 PC1067.1 73.64,57.97
ISUMP_IA: length 15.7
  TOP w0.203: v2(69.62,49.74) 69.53,49.83 69.53,50.54 69.56,50.57 PU1000.7
  IN2 w0.254: v2(69.62,49.74) 69.62,49.58 71.96,47.24 v2(72.82,47.24)
  IN4 w0.254: v2(72.82,47.24) 73.71,47.24 75.86,49.39 v2(75.86,49.81)
  BOTTOM w0.203: PR1062.1 69.7,46.82 PR1088.1 69.57,48.09 PC1085.1 PC1094.1 69.7,49.67 v2(69.62,49.74)
  BOTTOM w0.254: v2(75.86,49.81) 75.86,50.31 PR1111.1 ; v2(72.82,47.24) 72.82,47.34 PR1116.1
ISUMP_VSA: length 7.8
  TOP w0.203: v2(68.04,57.64) 68.02,57.62 68.02,57.32 68.36,56.99 68.36,56.11 PU1000.27
  BOTTOM w0.203: PC1071.1 68.02,57.69 68.02,57.66 v2(68.04,57.64)
  BOTTOM w0.254: PR1091.2 63.89,59.75 v1(63.89,58.87) 64.59,58.17 PR1089.1 PR1058.1 PC1078.1 PC1071.1
ITP_PMODE: length 103.6
  TOP w0.127: v2(65.02,71.05) 65.25,71.05 67.6,68.71 67.6,67.33 JXDP1.46
  IN3 w0.089: v2(65.02,71.05) 65.51,70.56 71.54,70.56 71.79,70.82 73.65,70.82 74.41,70.05 78.3,70.05 79.02,69.34 82.26,69.34 82.66,68.94 87.42,68.94 88.29,68.06 92.03,68.06 93.72,69.75 96.15,69.75 97.42,68.48 112.03,68.48 113.37,69.82 113.37,70.21 114.41,71.24 117.68,71.24 118.03,70.89 120.84,70.89 121.39,71.43 122.57,71.43 122.96,71.04 126.14,71.04 126.56,71.46 127.22,71.46 127.38,71.3 129.26,71.3 129.39,71.44 135.03,71.44 135.21,71.26 138.56,71.26 139.76,72.46 139.76,73.1 139.66,73.2 139.66,74.61 140.26,75.21 142.81,75.21 142.93,75.09 143.31,75.09 143.46,75.24 144.07,75.24 144.41,74.91 146.25,74.91 v2(146.47,74.68)
  BOTTOM w0.076: UCPU1.E8 147.15,70.07 147.15,71.92 147.05,72.02 147.05,72.44 146.98,72.5 146.98,73.08 147.05,73.14 147.05,73.77 146.87,73.94
  BOTTOM w0.127: v2(65.02,71.05) 65.02,72.07 v1(65.18,72.22) ; v2(146.47,74.68) 146.47,75.52 RC115.1 146.87,75.49 146.87,73.94
JACK_PLUG: length 14.4
  TOP w0.254: QA3.5 v2(15.72,30.95)
  IN2 w0.254: v2(13.67,35.49) 13.26,35.9 9.96,35.9 9.63,35.57 JHP1.6
  BOTTOM w0.254: v2(13.67,35.49) 15.04,34.12 15.04,33.44 16.28,32.19 DA1.3 15.65,32.06 15.33,31.75 15.21,31.75 RA35.1 14.83,30.36 RA26.1 14.88,30.45 15.38,30.95 v2(15.72,30.95)
JACK_PLUG_DL: length 12.5
  TOP w0.127: v3(18.69,34.45) 18.46,34.22 18.46,32.1 16.96,30.6 16.79,30.6 QA3.6
  TOP w0.254: QA6.2 18.38,29.09 18.06,28.77 RA31.1 16.62,28.77 CA74.1 ; QA3.6 16.37,29.69 16.42,29.64 CA74.1 ; CA74.1 15.91,28.98 v2(15.72,28.79)
  BOTTOM w0.254: RA26.2 RA20.1 ; RA20.1 15.8,28.86 v2(15.72,28.79) ; RA20.1 16.66,29.42 RA38.2
JACK_PLUG_DL#: length 16.6
  TOP w0.203: v2(29.27,33.68) 29.31,33.71 RA75.1
  TOP w0.254: v2(19.03,32.7) QA6.1 18.32,31.52 17.3,30.49 17.3,29.76 RA31.2
  IN4 w0.254: v2(29.27,33.68) 29.27,34.14 28.66,34.76 24.94,34.76 24.36,34.17 20.5,34.17 v2(19.03,32.7)
JTAG_CLK: length 28.4
  TOP w0.127: v2(180.72,59.29) 180.72,59.29 180.61,59.18 UE5.B56
  BOTTOM w0.127: v2(180.72,59.29) 180.73,59.28 180.73,57.41 180.09,56.76 180.09,56.21 179.41,55.53 177.51,55.53 176.15,54.17 173.93,54.17 v3(172.84,55.26) 171.75,56.36 171.75,57.7 170.44,59.01 170.44,62.53 171.03,63.13 171.84,63.13 172.01,63.29 172.01,64.52 171.73,64.8 171.35,64.8 171.15,65 RPE7.3 171.15,65.74 170.92,65.97 170.92,67.68 171.15,67.9 JDEG1.4
JTAG_RST#: length 17.6
  TOP w0.127: v2(179.5,60.84) 179,61.35 178.44,61.35 178.36,61.27 UE5.B47
  IN2 w0.089: v2(179.5,60.84) 179.04,61.3 178.49,61.3 178.19,61.01 178.19,60.01 176.42,58.23 175.85,58.23 172.47,61.61 v2(172.47,61.98)
  BOTTOM w0.127: JTAG1.1 171.32,61.38 RE65.2 RE66.1 CE59.1 174.22,61.53 173.77,61.98 v2(172.47,61.98)
JTAG_TDI: length 26.8
  TOP w0.127: v2(178.16,54.39) 178.54,54.39 178.77,54.62 178.77,56.68 179.33,57.24 179.65,57.24 179.86,57.46 UE5.A51
  BOTTOM w0.127: v2(178.16,54.39) 177.69,53.91 177.69,53.59 177.35,53.25 173.65,53.25 169.72,57.18 169.72,62.13 169.63,62.21 v3(169.63,62.67) 169.58,62.72 169.58,64.67 170.16,65.25 RPE7.1 170.16,65.64 170.35,65.83 170.35,67.53 170.15,67.73 JDEG1.2
JTAG_TDO: length 28.2
  TOP w0.127: UE5.B55 180.11,59.42 180.2,59.5 180.17,59.53 v2(180.17,59.53)
  BOTTOM w0.127: JDEG1.5 171.65,68.22 171.65,67.93 171.19,67.48 171.19,66.23 171.65,65.77 RPE7.4 171.65,65.26 172.28,64.64 172.28,62.75 171.76,62.24 171.02,62.24 170.69,61.91 170.69,59.19 172.06,57.82 172.06,56.59 172.75,55.91 174.29,55.91 v3(175,55.2) 175.72,54.48 176.1,54.48 177.6,55.98 178.35,55.98 178.56,56.19 178.56,58.84 178.45,58.95 178.45,59.47 178.74,59.75 179.95,59.75 v2(180.17,59.53)
JTAG_TMS: length 26.4
  TOP w0.127: UE5.A53 180.86,57.54 180.39,57.07 180.39,56.52 v2(180.52,56.39)
  BOTTOM w0.127: v2(180.52,56.39) 180.52,56.24 179.51,55.23 177.57,55.23 175.94,53.6 173.89,53.6 v3(171.07,56.43) 169.99,57.51 169.99,62.01 170.03,62.05 170.03,63.24 169.84,63.43 169.84,64.56 170.08,64.8 170.36,64.8 170.66,65.1 170.66,65.36 ; 170.66,65.36 RPE7.2 ; 170.66,65.36 170.66,68.22 JDEG1.3
K52: length 1.2
  TOP w0.127: T199.1 122.94,67.5 v2(123.37,67.06)
  BOTTOM w0.127: v2(123.37,67.06) 123.07,67.36 UCPU1.K52
KB_DET#: length 184.9
  TOP w0.127: v3(154.52,45.9) 154.8,46.17 v2(154.8,47.59)
  IN4 w0.081: v2(45.21,21.86) 44.94,21.6 44.94,20.72 45.28,20.39 49.33,20.39 50.38,21.44 53.38,21.44 53.42,21.39 53.93,21.39 54.14,21.61 56.71,21.61 59.22,19.1 61.94,19.1 63.98,21.15 66.1,21.15 69.33,24.37 69.33,25.57 71.65,27.89 74.11,27.89 76.93,30.71 77.79,30.71 78.88,31.81 82.65,31.81 84.47,33.63 85.72,33.63 86.17,34.08 86.17,34.7 86.64,35.17 89.92,35.17 90.72,34.36 95.45,34.36 96.41,33.41 96.41,29.99 97.23,29.17 97.23,25.45 97.32,25.36 97.32,23.17 97.76,22.73 99.59,22.73 101.61,20.71 106.61,20.71 107.12,20.2 123.47,20.2 123.87,19.8 144.65,19.8 145.16,20.3 147.49,20.3 147.89,19.9 160.69,19.9 163.66,22.88 163.66,26.13 162.27,27.53 162.27,28.19 163.94,29.86 163.94,33.5 163.09,34.35 162.39,34.35 160.65,36.09 160.65,37.41 156.92,41.14 156.92,43.7 155.94,44.67 155.94,45.48 155.03,46.4 155.03,47.36 v2(154.8,47.59)
  BOTTOM w0.076: UCPU1.BB7 148.68,49.41 149.15,49.41 149.97,48.59 150.23,48.59 150.82,48 153.3,48 153.46,47.83
  BOTTOM w0.127: v2(45.21,21.86) 44.92,21.57 JKB1.5 ; RC288.2 155.31,47.08 v2(154.8,47.59) 154.6,47.39 153.9,47.39 153.46,47.83
LANWAKE#: length 77.1
  TOP w0.127: UE5.B27 182.11,67.87 182.11,67.63 182.47,67.27 v2(182.47,67.17) ; v2(143.51,55.64) 143.68,55.64 143.99,55.33 143.99,54.83 144.12,54.71 144.7,54.71 144.93,54.48 144.93,52.3 145.15,52.09 145.44,52.09 146.2,51.33 146.2,49.57 146.77,49 146.77,48.71 147.02,48.47 147.39,48.47 RC95.2
  IN1 w0.081: v2(143.51,55.64) 143.51,55.58 143.97,55.13 143.97,54.86 144.11,54.72 144.6,54.72 144.96,54.36 144.96,52.31 145.21,52.05 145.69,52.05 146.85,50.9 147.74,50.9 150.25,48.39 152.27,48.39 152.57,48.09 152.98,48.09 153.78,47.3 153.78,46.8 154.43,46.15 158.53,46.15 158.96,46.57 163.85,46.57 166.9,49.62 166.9,50.52 170.08,53.71 170.08,55.96 169.13,56.91 169.13,59.32 171.65,61.84 171.65,62.37 171.71,62.42 171.73,62.42 172.01,62.7 172.01,63.95 173.38,65.32 173.38,67.16 174.51,68.29 176.52,68.29 177.68,69.46 177.68,69.56 178.25,70.13 178.65,70.13 179.39,70.87 181.48,70.87 181.84,70.52 181.84,69.83 181.95,69.72 181.95,67.71 182.47,67.19 v2(182.47,67.17)
  BOTTOM w0.076: UCPU1.AM15 v2(143.51,55.64)
LCD_TST: length 50.8
  TOP w0.127: RE58.2 173.64,64.28 174.45,64.28 174.78,64.6 175.35,64.6 175.57,64.38 v1(175.72,64.38) v2(176.46,64.38) 176.46,64.39 176.59,64.52 UE5.A38
  IN4 w0.081: v2(176.46,64.38) 176.47,64.38 177.06,63.8 177.06,63.24 177.97,62.33 177.97,60.28 178.6,59.65 179.01,59.65 179.25,59.42 179.25,59.18 180.71,57.71 186.19,57.71 186.98,56.92 186.98,56.26 185.47,54.76 185.47,53 188.01,50.46 188.01,49.03 190.42,46.61 190.42,44.15 189.52,43.25 189.52,40.97 190.24,40.24 191.24,40.24 193.08,38.41 193.08,34.03 194.11,33 v2(194.19,33)
  BOTTOM w0.127: v2(194.19,33) 193.81,33.37 JEDP.19
LCD_VCC_TEST_EN: length 57.2
  TOP w0.127: v2(176.18,63.86) 176.66,63.86 176.82,64.02 UE5.A39 ; D94.2 203.36,44.89 201.52,44.89 200.98,45.43 200.98,46.26 v1(198.22,49.03) v2(197.38,49.03)
  IN1 w0.081: v2(176.18,63.86) 176.5,63.86 177.17,64.52 177.17,64.96 179.01,66.81 181.02,66.81 181.75,66.07 182.63,66.07 182.76,65.94 183.3,65.94 183.74,66.39 183.74,69.38 184.61,70.24 190.13,70.24 190.64,69.73 194.32,69.73 195.8,68.25 195.8,65.04 194.47,63.7 194.47,53.05 197.55,49.97 197.55,49.2 v2(197.38,49.03)
LDO_EN: length 15.1
  TOP w0.508: 60.87,69.43 62.18,69.43 63.07,68.54 v2(63.07,66.69)
  BOTTOM w0.381: PU202.1 66.51,67.45 PC209.1 66.32,68.17 64.12,68.17 v1(63.57,68.72) 63.37,68.72 63.2,68.54 63.2,68.15 63.63,67.71 63.63,67.1 63.33,66.79 63.17,66.79 v2(63.07,66.69)
  BOTTOM w0.508: PR240.2 64.06,65.55 63.07,66.54 v2(63.07,66.69)
LID_CL_SIO#: length 6.3
  TOP w0.127: UE5.A21 184.36,68.72 184.36,69.59 v3(184.79,70.02) 184.89,70.11 CE13.1 184.43,71.41 184.43,72.2 184.66,72.42 184.66,72.96 184.4,73.21 RE25.2 RE26.2
LID_SW_IN#: length 67.9
  TOP w0.127: RE26.1 182.83,74.13 v2(182.57,74.38) 182.57,74.94 v3(183.08,75.45)
  IN4 w0.089: v2(182.57,74.38) 182.32,74.13 182.32,72.35 184.19,70.48 184.19,69.09 184.73,68.54 184.73,66.73 185.55,65.92 185.55,65.39 185.74,65.2 186.73,65.2 188.19,63.74 188.19,61.21 189.64,59.76 189.64,59.38 191.28,57.73 191.28,56.95 193.6,54.63 193.6,51.84 195.87,49.57 195.87,36.14 198.65,33.36 198.65,25.76 199.31,25.1 v2(199.97,25.1)
  BOTTOM w0.127: v2(199.97,25.1) 199.44,24.57 199.44,21.23 198.8,20.59 198.8,19.57 198.67,19.44 198.02,19.44 197.31,18.73 JIO1.44
LINE1-VREFO_L: length 7.4
  TOP w0.127: UA2.31 24.61,29.48
  TOP w0.203: 24.01,29.49 24.04,29.49 24.06,29.48 24.61,29.48
  TOP w0.254: v2(20.79,29.02) 21.13,29.02 21.74,29.62 23.31,29.62 23.44,29.49 24.01,29.49
  BOTTOM w0.127: v2(20.79,29.02) 20.88,29.02 v3(21.32,28.57)
  BOTTOM w0.254: RA48.1 20.55,28.77 v2(20.79,29.02)
LINE1-VREFO_R: length 9.4
  TOP w0.203: UA2.30 23.91,29.88
  TOP w0.254: v2(21,29.57) 21.56,30.13 v3(22.71,30.13) 23.34,30.13 23.6,29.88 23.91,29.88
  IN1 w0.254: v2(17.81,30.31) 18.54,30.31 18.9,29.96 20.78,29.96 21,29.74 v2(21,29.57)
  BOTTOM w0.254: v2(17.81,30.31) 17.56,30.07 RA49.1
LINE1_L: length 12.9
  TOP w0.203: UA2.22 26.26,33.13 25.86,33.54 v2(25.63,33.54)
  TOP w0.381: CA70.1 19.6,28.36 v2(19.1,28.85)
  IN4 w0.254: v2(19.1,28.85) 19.77,29.51 19.77,31.48 20.63,32.34 22.76,32.34 23.47,33.05 25.25,33.05 25.63,33.43 v2(25.63,33.54)
  BOTTOM w0.127: v2(25.63,33.54) 25.63,33.67 v3(24.81,34.49)
LINE1_L_C: length 2.3
  TOP w0.127: v1(18.64,28.43) 19.63,27.44 CA70.2
  TOP w0.254: RA50.1 CA70.2
LINE1_R: length 12.5
  TOP w0.203: v2(26.31,33.74) 26.31,33.54 26.66,33.19 UA2.21
  IN4 w0.254: v2(26.31,33.74) 25.93,34.12 24.84,34.12 24.36,33.64 21.15,33.64 v2(18.45,30.95)
  BOTTOM w0.127: v2(26.31,33.74) 26.31,34.89 v3(26.46,35.03)
  BOTTOM w0.254: CA71.1 v2(18.45,30.95)
LINE1_R_C: length 2
  BOTTOM w0.127: v3(19.45,29.76) 19.1,29.41 CA71.2
  BOTTOM w0.254: RA51.1 CA71.2
LPC_LAD0: length 51.7
  TOP w0.127: UE5.A30 179.86,68.72 179.86,69.41 v2(179.91,69.45)
  IN3 w0.089: v2(144.74,48.89) 146.52,50.67 150.27,50.67 152.49,52.9 154.72,52.9 157.72,55.9 158.82,55.9 161.14,58.22 161.14,59.27 161.9,60.02 162.99,60.02 163.38,60.41 165.51,60.41 168.08,62.99 169.24,62.99 171,64.75 172.34,64.75 172.8,65.22 172.8,66.06 176.95,70.21 179.15,70.21 v2(179.91,69.45)
  BOTTOM w0.076: UCPU1.AY13 144.8,50.83 144.69,50.72 144.59,50.61 144.52,50.4 144.52,50.28 144.59,50.05 144.59,49.91 144.53,49.79 144.53,49.1 v2(144.74,48.89)
  BOTTOM w0.127: v1(180.77,68.69) 180.67,68.69 v2(179.91,69.45) 179.91,69.94 180.65,70.68 180.65,71.22 JLPDE1.3
LPC_LAD1: length 56.1
  TOP w0.127: v2(179.55,67.2) 179.55,67.22 179.61,67.28 UE5.B32
  IN3 w0.089: v2(179.55,67.2) 179.54,67.2 179.12,66.79 178.13,66.79 177.71,66.37 176.01,66.37 175.46,65.82 175.46,65.24 174.88,64.65 174.24,64.65 169.52,59.93 167.21,59.93 166.42,59.14 166.42,58.1 165.58,57.26 161.71,57.26 159.36,54.91 159.36,53.12 157.69,51.44 156.47,51.44 155.81,50.78 153.86,50.78 153.55,51.09 152.33,51.09 150.61,49.38 148.33,49.38 146.66,47.71 146.66,47.43 146.19,46.96 v2(145.9,46.96)
  BOTTOM w0.076: UCPU1.BA13 145.09,50.04 145.09,49.43 145.38,49.13 145.38,47.48 v2(145.9,46.96)
  BOTTOM w0.127: v2(179.55,67.2) 179.55,67.22 179.5,67.27 179.5,68.39 v1(179.48,68.41) 179.45,68.44 179.45,70.05 179.25,70.25 179.25,71.6 179.57,71.92 180.88,71.92 181.15,71.65 JLPDE1.4
LPC_LAD2: length 52.9
  TOP w0.127: UE5.A31 179.36,68.72 179.36,69.26 179.01,69.61 v2(179.01,69.64)
  IN3 w0.089: v2(144.99,48.24) 144.99,48.5 146.94,50.45 150.36,50.45 152.58,52.68 154.81,52.68 157.81,55.68 158.91,55.68 161.36,58.13 161.36,59.18 161.99,59.81 163.08,59.81 163.47,60.2 165.6,60.2 168.17,62.77 169.33,62.77 171.09,64.54 172.56,64.54 173.02,64.99 173.02,65.98 177.04,70 178.65,70 v2(179.01,69.64)
  BOTTOM w0.076: v2(144.99,48.24) 145.14,48.39 145.14,49.13 144.87,49.4 144.87,49.61 UCPU1.BB13
  BOTTOM w0.127: v2(179.01,69.64) 178.97,69.68 178.97,71.68 179.56,72.27 181.02,72.27 181.65,71.64 181.65,71.22 JLPDE1.5
LPC_LAD3: length 60.3
  TOP w0.127: v2(178.72,67.19) 178.72,67.22 179.11,67.61 UE5.B33
  IN3 w0.089: v2(178.72,67.19) 178.69,67.19 178.5,67 177.98,67 177.56,66.58 175.92,66.58 175.25,65.91 175.25,65.73 175.25,65.33 174.79,64.87 174.15,64.87 169.43,60.14 167.12,60.14 166.2,59.23 166.2,58.19 165.49,57.48 163.68,57.48 162.88,58.28 162.25,58.28 162.01,58.04 162.01,57.86 159.14,55 159.14,53.21 157.72,51.78 156.5,51.78 155.72,51 153.95,51 153.64,51.31 152.19,51.31 150.64,49.76 147.31,49.76 146.79,49.23 146.79,48.25 v2(146.08,47.54)
  BOTTOM w0.076: v2(146.08,47.54) 145.7,47.54 145.55,47.7 145.55,49.2 145.29,49.46 145.29,50.16 145.09,50.37 145.09,50.91 145.37,51.19 UCPU1.AY12
  BOTTOM w0.127: JLPDE1.6 182.15,71.22 182.15,72.37 181.53,72.98 179.91,72.98 178,71.07 178,69.04 178.72,68.32 v2(178.72,67.19)
LPC_LFRAME#: length 55.3
  TOP w0.127: UE5.B31 180.11,67.24 180.14,67.22 v2(180.14,67.2)
  IN3 w0.089: v2(145.9,48.13) 146.58,48.81 146.58,49.34 147.27,50.02 150.59,50.02 152.23,51.65 153.02,51.65 153.62,52.25 154.99,52.25 156.21,53.47 157.95,53.47 158.9,54.42 158.9,55.06 161.79,57.95 161.79,58.13 162.16,58.49 162.97,58.49 163.77,57.69 165.4,57.69 165.98,58.27 165.98,59.32 167.03,60.36 169.01,60.36 170.51,61.86 170.51,63.1 171.51,64.11 172.74,64.11 173.45,64.81 173.45,65.68 174.08,66.31 175.14,66.31 176.43,67.6 179.74,67.6 v2(180.14,67.2)
  BOTTOM w0.076: v2(145.9,48.13) 145.9,49.12 145.56,49.47 145.56,50.5 145.4,50.66 UCPU1.BA12
  BOTTOM w0.127: v2(180.14,67.2) 180.14,67.47 180.35,67.69 181.68,67.69 181.81,67.82 181.81,70.24 182.14,70.57 182.5,70.57 182.65,70.72 JLPDE1.7
LPM_ZVM_N: length 1.9
  TOP w0.127: T200.1 119.74,53.25 v2(119.74,53.74)
  BOTTOM w0.076: UCPU1.AR56 120.1,54.1 v2(119.74,53.74)
LPS_PROTECT#: length 144.6
  TOP w0.127: PR274.2 92.69,67.9 93.49,68.7 93.49,69.8 93.18,70.1 PR287.1 93.29,70.71 93.29,71.69 93.95,72.35 93.95,73.53 95.12,74.7 PD206.1 97.04,74.7 98,75.66 99.12,75.66 102.16,78.7 105.91,78.7 107.23,77.39 107.23,76.96 107.93,76.26 107.93,75.67 108.7,74.9 108.7,74.45 108.57,74.33 108.57,73.23 109.09,72.71 112.9,72.71 113.08,72.53 113.85,72.53 114.08,72.75 114.08,73.3 114.75,73.97 121.71,73.97 122.33,74.58 122.33,75.59 122.69,75.95 128.28,75.95 129.34,77.01 v2(129.6,77.01) ; v2(185.88,60.28) 185.88,60.14 186.18,59.85 186.74,59.85 186.82,59.77 UE5.B2
  IN1 w0.081: v2(166.35,77.52) 167.71,78.88 174.57,78.88 v2(175.08,78.37)
  IN3 w0.089: v2(185.88,60.28) 186.28,59.88 186.64,59.88 187.07,59.46 187.07,59.37 187.89,58.54 189.63,58.54 191.61,60.52 192.39,60.52 192.94,61.07 192.94,61.61 193.66,62.33 193.66,65.22 194.05,65.61 194.05,66.26 194.92,67.13 194.92,67.67 193.25,69.34 193.25,70.36 192.42,71.19 192.42,72.36 190.87,73.91 186.2,73.91 184.36,75.76 177.56,75.76 175.08,78.23 v2(175.08,78.37) ; v2(166.35,77.52) 165.8,78.08 160.77,78.08 159.9,77.21 157.49,77.21 156.64,76.36 156.64,75.83 156.53,75.72 152.73,75.72 151.66,76.79 145.9,76.79 145.55,77.14 138.03,77.14 137.13,78.05 130.42,78.05 129.6,77.24 v2(129.6,77.01)
MCARD_PCIE_SATA#: length 77.4
  IN4 w0.081: v2(180.65,66.2) 180.65,65.87 183.23,63.29 183.23,59.21 183.66,58.78 186.65,58.78 187.94,57.49 188.62,57.49 188.86,57.25 188.86,56.58 188.6,56.31 188.22,56.31 186.32,54.41 186.32,53.53 188.97,50.88 191.14,50.88 192.98,49.04 192.98,48.58 v2(192.99,48.57)
  BOTTOM w0.127: v2(192.99,48.57) 192.22,47.8 192.22,45.82 190.15,43.76 189.02,43.76 188.57,43.31 188.57,41.34 187.97,40.73 187.97,40.51 187.44,39.98 186.92,39.98 ; 186.92,39.98 185.94,39.98 R220.2 185.54,39.57 184.48,39.57 183.76,40.29 JNGFF2.61 ; 186.92,39.98 U683.2 ; R2665.2 156.45,69.03 159.91,69.03 161.31,70.43 164.11,70.43 164.49,70.82 166.22,70.82 167.72,69.33 168.13,69.33 169.59,70.79 173.35,70.79 174.74,69.4 174.74,68.27 174.63,68.16 174.63,67.25 174.95,66.93 175.55,66.93 176.02,67.4 176.93,67.4 178.22,66.11 178.22,65.49 178.51,65.21 179.1,65.21 179.17,65.13 179.72,65.13 179.79,65.06 180.65,65.06 181.03,65.44 v1(181.03,65.81) v2(180.65,66.2)
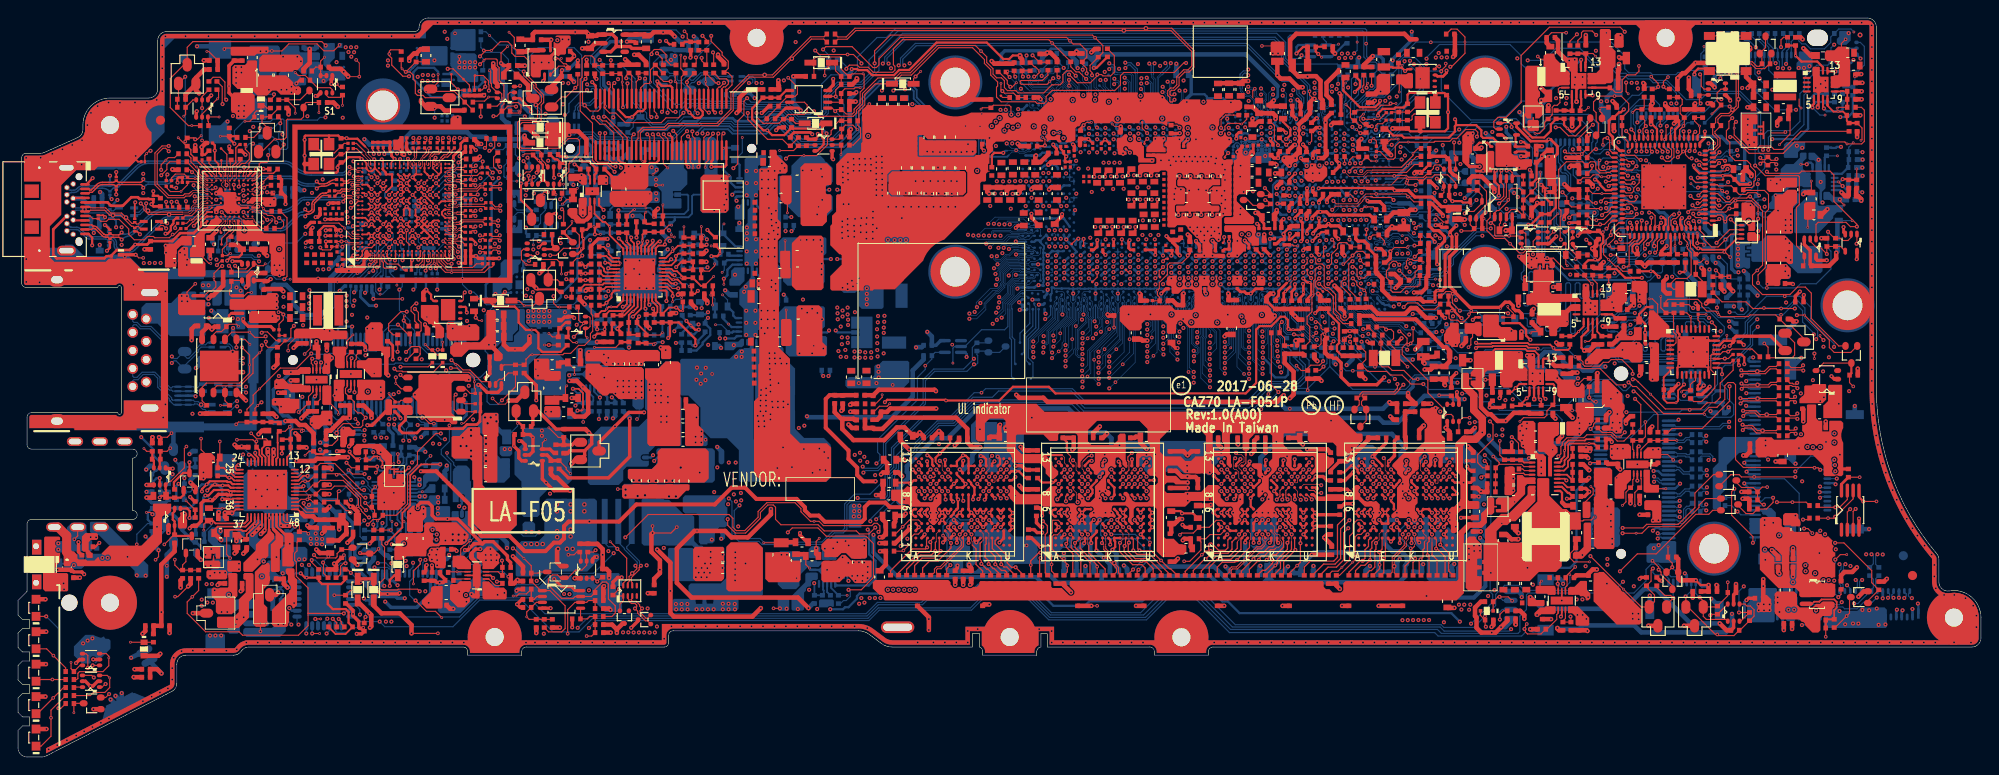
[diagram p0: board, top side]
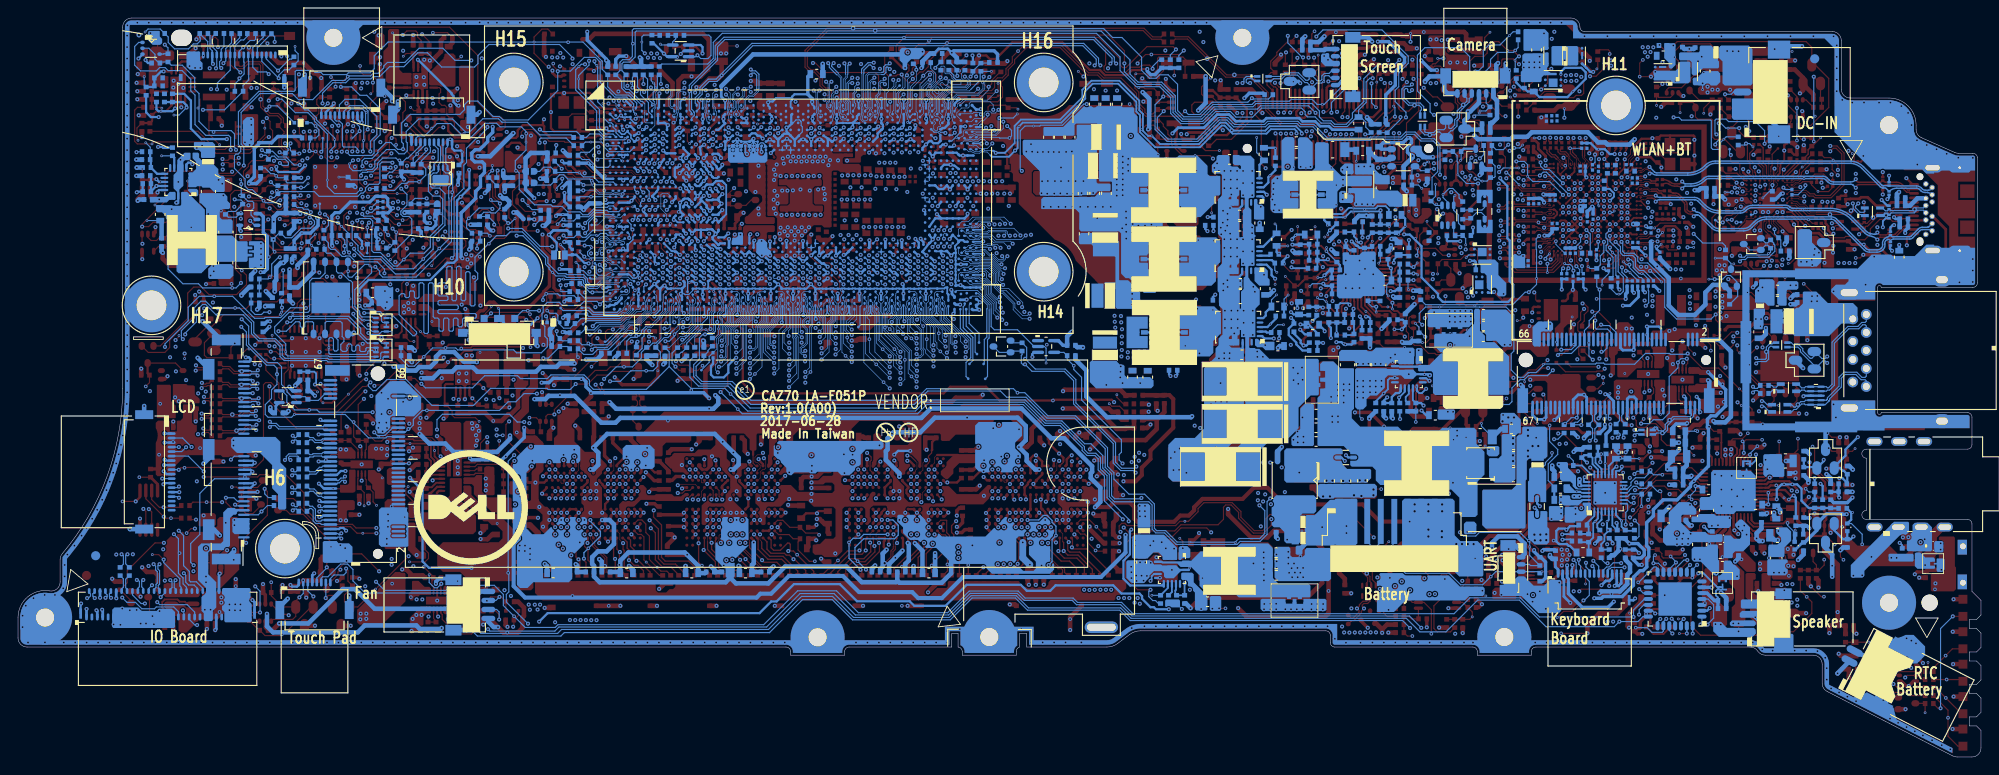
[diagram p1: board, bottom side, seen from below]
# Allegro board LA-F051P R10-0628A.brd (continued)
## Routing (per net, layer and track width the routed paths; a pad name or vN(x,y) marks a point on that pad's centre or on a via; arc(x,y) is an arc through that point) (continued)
ME_EN: length 9.1
  TOP w0.254: v2(160.17,48.7) 160.12,48.7 159.42,49.4 159.42,49.55 RH24.1 R1191.1
  BOTTOM w0.127: v1(164.52,49.79) 164.39,49.67 SW1.2
  BOTTOM w0.254: SW1.2 163.69,47.96 160.9,47.96 v2(160.17,48.7)
ME_FWP_EC: length 43.5
  TOP w0.127: R1191.2 157.94,51.14 158.45,51.65 158.97,51.65 159.14,51.48 159.14,50.7 159.18,50.66 159.18,50.33 v2(159.99,49.52) ; UE5.B1 187.21,59.27 187.57,59.27 187.83,59.01 v2(188.21,59.01)
  IN2 w0.089: v2(180.19,60.38) 180.34,60.38 180.87,60.91 181.61,60.91 182.03,60.49 182.79,60.49 183.56,59.72 184.05,59.72 184.91,58.86 188.06,58.86 v2(188.21,59.01)
  IN3 w0.089: v2(180.19,60.38) 180.19,60.19 179.75,59.76 178.72,59.76 178.44,59.47 178.44,57.05 177.82,56.42 176.87,56.42 174.75,54.31 171.99,54.31 171.79,54.1 168.98,54.1 164.52,49.65 161.07,49.65 160.95,49.53 159.99,49.53 v2(159.99,49.52)
  BOTTOM w0.127: v2(159.99,49.52) v3(161.24,49.52) 161.83,49.52 SW1.3
ME_RESET#: length 3.5
  TOP w0.127: v2(144.27,78.01) v1(144.64,77.64)
  TOP w0.254: v2(144.27,78.01) 143.99,78.29 RC227.1 144.02,78.81 RC225.2
  BOTTOM w0.127: v2(144.27,78.01) 144.27,78.07 143.99,78.36 UC12.2
ME_SUS_PWR_ACK: length 78.7
  TOP w0.127: v2(144.43,54.3) 144.1,54.3 143.93,54.13 143.93,53.02 143.78,52.86 143.78,51.19 143.57,50.99 143.57,49.4 143.04,48.87 143.04,48.03 143.05,48.03 143.33,47.75 143.33,46.33 143.34,46.32 143.34,46.12 142.72,45.5 RC74.2 ; UE5.A8 188.9,63.02 v3(189.09,62.83) 189.27,62.65 v2(189.63,62.65)
  IN3 w0.089: v2(144.43,54.3) 143.96,54.76 143.96,55.99 144.6,56.63 144.6,56.75 144.81,56.96 149.91,56.96 151.16,58.2 154.22,58.2 154.76,57.66 156.18,57.66 157.05,58.53 157.51,58.53 159.47,60.5 159.47,60.76 160.08,61.36 160.61,61.36 160.93,61.68 160.93,65.49 161.58,66.13 162.73,66.13 163.97,67.37 170.74,67.37 171.21,67.84 171.84,67.84 173.26,69.26 173.26,69.83 174.73,71.29 178.62,71.29 179.02,71.69 183.92,71.69 184.4,71.2 188.14,71.2 190.38,68.96 190.38,68.48 189.71,67.8 189.71,66.66 190.49,65.88 190.49,63.52 v2(189.63,62.65)
  BOTTOM w0.076: v2(144.43,54.3) 144.71,54.3 144.88,54.12 UCPU1.AR13
MEC_XTAL1: length 8.9
  TOP w0.127: UE5.A61 184.86,57.47 185.23,57.11 v1(185.23,56.75) 185.23,56.41 185.65,55.99 185.65,53.55 185.19,53.09 183.94,53.09 183.24,52.39 CE62.1 183.69,51.9 YE1.1
MEC_XTAL2: length 4.4
  TOP w0.127: YE1.2 186.88,51.9 186.88,52.83 CE53.1 RE62.2 186.69,54.87 v1(187.08,55.27)
MEC_XTAL2_R: length 6.5
  TOP w0.127: UE5.A62 185.36,57.45 185.57,57.24 185.57,56.51 186.16,55.92 RE62.1 186.45,55.79 186.62,55.96 189.49,55.96 v3(189.98,55.47)
MEDIACARD_IRQ#: length 92.2
  IN4 w0.081: v2(199.41,20.39) 199.47,20.44 199.47,20.76 198.56,21.66 192.4,21.66 190.68,19.95 184.57,19.95 184.25,20.27 184.25,21.37 183.95,21.68 182.45,21.68 179.7,24.42 179.7,25.64 174.94,30.4 174.94,37.16 173.36,38.74 173.36,39.41 171.86,40.91 171.86,44.21 167.01,49.06 167.01,50.48 167.8,51.28 167.8,53.3 166.92,54.18 166.92,55.79 165.58,57.13 165.58,60.97 164.67,61.89 164,61.89 163.07,62.81 163.07,63.06 160.75,65.39 159.28,65.39 157.77,66.9 154.62,66.9 153.81,67.7 v2(153.42,67.7)
  BOTTOM w0.127: v2(199.41,20.39) 199.2,20.18 199.2,19.4 198.88,19.08 198.27,19.08 197.91,18.73 197.91,18.41 JIO1.42 ; v2(153.42,67.7) 153.81,67.7 154.41,67.1 155.35,67.1 RC13.2 155.2,66.29 154.43,66.29 153.57,65.43 152.35,65.43 152.12,65.66 UCPU1.M1
MEM_CONFIG0: length 5.5
  TOP w0.127: v2(153.27,53.99) 153.27,53.97 RH129.2 154.61,52.9 155.02,53.31 155.02,53.78 RH144.1
  BOTTOM w0.076: UCPU1.AP2 151.77,54.06 151.92,54.01 151.97,53.98 152.12,53.93 153.22,53.93 v2(153.27,53.99)
MEM_CONFIG1: length 10.6
  TOP w0.127: RH150.1 155.55,52.46 v1(155.45,52.36) 155.27,52.18 154.02,52.18 153.4,51.57 152.56,51.57 152.34,51.79 RH139.2 151.84,53.18 151.84,53.95 152.13,54.25 152.13,54.63 152.5,55 152.89,55 v2(153.27,54.62)
  BOTTOM w0.127: UCPU1.AP1 152.17,54.16 152.81,54.16 v2(153.27,54.62)
MEM_CONFIG2: length 23.9
  TOP w0.127: RH149.1 155.5,55.1 154.8,55.1 154.68,55.23 v1(154.27,55.23) 154.06,55.02 v2(154.06,54.33)
  IN1 w0.081: v2(158.09,67.9) 157.88,67.69 157.88,65.11 157.38,64.61 157.31,64.61 155.95,63.26 155.95,55.75 155.33,55.12 154.8,55.12 154.69,55.24 154.15,55.24 153.92,55.01 153.92,54.47 v2(154.06,54.33)
  BOTTOM w0.076: v2(154.06,54.33) 154.1,54.36 154.1,54.88 153.88,55.1 152.64,55.1 152.4,54.87 152.19,54.87 151.94,54.62 151.34,54.62 150.93,54.22 UCPU1.AP3
  BOTTOM w0.127: v2(158.09,67.9) 158.09,67.63 158.15,67.57 RH145.2
MEM_CONFIG3: length 7.9
  TOP w0.127: v2(154.94,56.75) 155.37,56.75 RH151.1 RH146.2
  BOTTOM w0.076: UCPU1.AN3 150.53,54.88 150.9,55.25 152.32,55.25 152.51,55.44 154.34,55.44 154.46,55.56
  BOTTOM w0.127: v2(154.94,56.75) 154.33,56.75 v1(154.25,56.68) 154.25,56.4 154.61,56.05 154.61,55.71 154.46,55.56
MEM_CONFIG4: length 17.1
  TOP w0.127: RH152.1 155.03,55.52 v2(154.98,55.52)
  IN1 w0.081: v2(154.98,55.52) 155.03,55.52 155.75,56.24 155.75,63.44 157.48,65.18 v2(157.48,65.28)
  BOTTOM w0.076: v2(154.98,55.52) 154.73,55.27 152.58,55.27 152.38,55.08 151.99,55.08 UCPU1.AN1
  BOTTOM w0.127: RH147.2 158.27,66.09 157.9,65.72 157.9,65.7 157.48,65.29 v2(157.48,65.28) ; v2(154.98,55.52) 155.45,55.99 v1(155.45,56.14)
MEM_SMBCLK: length 11
  TOP w0.076: 150.28,64.47 149.68,64.47 v2(149.09,63.88)
  TOP w0.127: QC2.6 157.75,65.7 157.23,65.7 157.05,65.52 157.05,65.31 RC12.1 156.48,64.86 155.95,64.33 154.28,64.33 154.06,64.54 152.77,64.54 v3(152.71,64.47) 150.28,64.47
  BOTTOM w0.127: UCPU1.R7 148.74,64.22 v2(149.09,63.88)
MEM_SMBDATA: length 13.4
  TOP w0.076: 152.61,63.72 152.37,63.48 148.82,63.48 v2(148.4,63.9)
  TOP w0.127: QC2.3 159.52,63.71 158.62,64.6 157.18,64.6 156.92,64.34 156.28,64.34 155.78,63.84 RC14.1 155.52,63.84 155.26,64.11 154.18,64.11 154.05,64.24 153.13,64.24 152.61,63.72
  BOTTOM w0.127: v2(148.4,63.9) 148.09,64.21 UCPU1.R8
MIC2-VREFO: length 22.5
  TOP w0.203: UA2.29 24.61,30.28 23.96,30.28
  TOP w0.254: 23.96,30.28 23.8,30.28 23.56,30.51 23.24,30.51 23.16,30.59 21.28,30.59 v3(20.93,30.25) 20.41,29.73 v2(20.41,29.47) ; v2(9.02,23.76) 8.59,23.33 RA28.1
  IN4 w0.254: v2(9.02,23.76) 18.49,23.76 20.05,25.32 20.05,29.12 v2(20.41,29.47)
  BOTTOM w0.203: RA27.1 8.74,23.48 v2(9.02,23.76)
MONO_IN: length 4.9
  TOP w0.127: v3(30.16,36.65) 29.65,36.14 CA34.2
  TOP w0.203: CA34.2 28.8,35.95 28.8,34.88 28.82,34.87 28.82,33.23 28.66,33.07 UA2.16
MPHYP_PWR_EN: length 43.9
  TOP w0.127: RH557.1 159.02,80.77 159.68,80.77 160.55,79.89 v1(160.55,79.33) 160.55,78.09 159.06,76.59 v2(158.93,76.59)
  IN1 w0.081: v2(158.93,76.59) 159.84,75.68 159.84,73.62 161.43,72.03 161.43,67.62 160.57,66.76 160.17,66.76 159,65.59 159,65.16 158.08,64.24 158.08,62.94 157.95,62.8 157.95,62.04 156.37,60.46 156.37,55.21 155.12,53.96 154.53,53.96 v2(154.41,53.84)
  IN3 w0.089: v2(146.36,55.73) 146.36,55.85 146.56,56.04 150.05,56.04 152.51,53.58 154.14,53.58 v2(154.41,53.84)
  BOTTOM w0.076: v2(146.36,55.73) 146.69,56.05 UCPU1.AM10
MSCLK: length 9.7
  BOTTOM w0.127: JDEG1.6 172.15,68.22 172.15,67.73 172.06,67.63 172.06,67.14 173.08,66.13 RE72.2 172.57,65.26 172.57,64.56 173.3,63.83 v3(173.31,63.83) 174.48,63.83 174.65,63.66 175.24,63.66 176.03,62.87 176.93,62.87 RE105.1
MSDATA: length 13.9
  TOP w0.127: v2(171.37,62.66) 171.86,62.18 RE85.1 172.36,61.05 RE104.1
  IN1 w0.081: v2(171.37,62.66) 171.19,62.85 171.19,63.72 173.05,65.58 173.05,66.89 v2(172.52,67.42)
  BOTTOM w0.127: v2(172.52,67.42) 172.52,67.21 RE75.2 173.97,66.46 v3(173.52,66.9) 173.52,67.05 172.65,67.92 172.65,68.22 JDEG1.7
MSM_N: length 1.2
  TOP w0.127: T201.1 119.4,54.03 v2(119.74,54.37)
  BOTTOM w0.076: v2(119.74,54.37) 120.12,54.75 UCPU1.AP56
NB_MUTE#: length 34.5
  TOP w0.127: RA59.1 30.96,23.83 30.96,22.87 30.69,22.59 30.69,21.84 30.88,21.64 30.88,20.05 32.18,18.75 32.18,15.93 ; 32.18,15.93 32.19,15.93 v2(36.15,15.93) ; 32.18,15.93 32.18,14.58 31.11,13.51 24.92,13.51 24.53,13.89 20.81,13.89 18.77,15.93 18.77,17.2 v3(19.34,17.77) 20.04,18.47 RA57.1
  BOTTOM w0.127: UE4.20 36.45,16.23 v2(36.15,15.93)
NB_PSID: length 2.8
  TOP w0.127: v2(28.4,73.54) 28.4,73.32 PR108.2
  BOTTOM w0.127: JP100.3 27.46,73.79 27.71,73.54 v2(28.4,73.54)
NC_B4: length 3.8
  TOP w0.076: v2(35.99,56.63) 36.2,56.83 37.44,56.83 37.44,56.83 37.96,56.83 38.19,57.07 UT1.B4
  BOTTOM w0.127: v1(35.48,56.9) 35.76,56.63 v2(35.99,56.63)
  BOTTOM w0.254: RT50.2 35.99,56.38 v2(35.99,56.63)
NC_B5: length 5.5
  TOP w0.076: UT1.B5 37.96,57.77 37.08,57.77 36.22,58.63
  TOP w0.127: 36.22,58.63 v1(36.22,58.71) 36.04,58.89 35.97,58.89 35.61,59.24 33.53,59.24 RT48.2
NC_G2: length 6
  TOP w0.076: 40.28,55.44 40.28,55.93 UT1.G2
  TOP w0.127: 40.28,55.44 40.38,55.35 40.38,55.01 40.54,54.85 40.54,54.36 40.66,54.24 v2(41.89,54.24)
  BOTTOM w0.127: v1(42.04,52.36) 42.04,52.92 41.31,53.64 RT49.2
  BOTTOM w0.254: v2(41.89,54.24) 41.59,53.95 RT49.2
NRB_BIT: length 3.5
  TOP w0.127: v2(148.08,54.38) 148.29,54.38 148.58,54.09 148.58,53.35 148.79,53.14 v3(148.84,53.14) 149.35,53.14 RC186.2
  BOTTOM w0.076: v2(148.08,54.38) 148.1,54.37 148.28,54.37 UCPU1.AR7
NTC_GT: length 2.8
  TOP w0.203: PU1000.15 72.15,53.36 72.55,52.96 v1(72.71,52.96) 72.73,52.98 73.19,52.98 73.86,52.31 PR1064.2
NTC_IA: length 4.2
  TOP w0.203: PR1072.2 65.61,49.49 67.28,49.49 67.96,50.16 PU1000.3
P_SYS: length 247.1
  TOP w0.127: UE5.A57 182.86,57.54 v2(182.43,57.11) ; v2(38.81,25.79) 38.82,25.79 39.39,26.35 40.1,26.35 40.48,26.73 PR319.1 41.97,26.82 43.22,28.07 43.22,31.37 44.32,32.47 44.32,33.86 46.36,35.9 v2(46.91,35.9)
  TOP w0.254: PR1083.1 64.24,47.48 v2(64.26,47.46)
  IN1 w0.081: v2(64.26,47.46) 64.12,47.32 51.36,47.32 49.3,45.26 49.3,42.71 48.07,41.47 48.07,37.05 v2(46.91,35.9)
  IN2 w0.089: v2(41.43,15.02) 41.78,15.37 50.63,15.37 51.53,16.27 54.26,16.27 54.86,15.68 65.06,15.68 65.58,15.16 71.13,15.16 71.69,15.72 81.14,15.72 81.45,15.41 94.98,15.41 95.68,16.11 99.55,16.11 100.37,15.28 108.7,15.28 109.04,15.63 115.32,15.63 117.4,13.55 126.04,13.55 128.11,15.62 129.89,15.62 131.88,13.63 162.99,13.63 163.05,13.56 173.14,13.56 174.7,15.12 174.7,21.29 175.65,22.25 175.65,22.72 175.97,23.03 176.97,23.03 177.39,23.45 178.03,23.45 179.48,24.9 179.48,28.79 179.28,28.98 179.28,38.15 178.03,39.41 178.03,40.2 178.93,41.1 179.55,41.1 182.04,43.6 182.04,48.37 183.07,49.4 183.07,51.38 184.84,53.14 184.84,55 183.78,56.05 183.78,56.99 183.36,57.41 182.74,57.41 v2(182.43,57.11)
  IN4 w0.081: v2(41.43,15.02) 41.43,17.18 38.38,20.23 38.38,24.41 38.81,24.84 v2(38.81,25.79)
  BOTTOM w0.127: v2(64.26,47.46) v3(65.09,47.46)
  BOTTOM w0.254: v2(64.26,47.46) 63.88,47.84 PR1425.1 64.16,48.52 PC1538.1
PANEL_BKEN_EC: length 175
  TOP w0.127: D72.3 188.96,27.37 188.05,27.37 187.61,26.93 186.17,26.93 181.78,22.54 179.68,22.54 v2(177.75,20.61)
  IN1 w0.089: v2(30.33,14.69) 30.78,15.15 31.72,15.15 31.97,14.89 38.6,14.89 38.97,15.26 38.97,15.67 39.5,16.2 41.94,16.2 42.66,15.49 44.54,15.49 44.79,15.23 49.58,15.23 50.58,16.24 54.45,16.24 54.78,15.92 57.63,15.92 58.85,17.14 59.78,17.14 60.16,16.75 66.51,16.75 66.51,16.76 67.52,16.76 69.41,18.64 86.52,18.64 87.01,18.15 90.21,18.15 91.8,16.56 93.92,16.56 94.57,17.22 101.03,17.22 101.72,16.53 108.83,16.53 109.3,16.99 115.44,16.99 117.56,14.87 125.98,14.87 127.48,16.37 131.24,16.37 132.08,15.53 151.2,15.53 152.41,16.74 158.94,16.74 159.51,17.31 165.7,17.31 166.33,16.68 171.43,16.68 171.63,16.88 174.02,16.88 v2(177.75,20.61)
  BOTTOM w0.127: UE4.4 30.29,17.53 29.67,16.9 29.67,15.4 30.33,14.74 v2(30.33,14.69)
PANEL_BKLEN: length 77.7
  TOP w0.127: D72.2 188.96,28.68 187.25,28.68 186.52,27.95 186.52,27.68 184.39,25.55 180.92,25.55 180.19,24.83 v1(179.55,24.83) v2(178.05,24.83)
  IN4 w0.089: v2(145.84,63.82) 147.44,62.23 148.76,62.23 148.76,62.22 149.49,62.22 149.49,62.23 153.18,62.23 153.36,62.04 157.74,62.04 158.79,63.09 160.34,63.09 161.15,62.27 161.15,57.9 159.61,56.36 159.61,52.84 164.46,47.99 165.71,47.99 166.2,47.5 166.2,46.78 167.55,45.42 168.05,45.42 168.99,44.48 168.99,43.41 169.6,42.8 169.6,40.19 171.41,38.38 171.41,37.16 171.91,36.66 171.91,31.78 172.34,31.35 172.34,30.16 175.77,26.73 175.77,25.66 176.59,24.84 178.03,24.84 v2(178.05,24.83)
  BOTTOM w0.127: v2(145.84,63.82) 145.49,64.18 UCPU1.R12
PBAT_PRES#: length 202.1
  TOP w0.127: PD100.3 66.78,16.95 67.16,17.33 PRP100.1 66.12,17.87 PR100.2 v2(66.7,18.65) ; v2(177.57,58) 177.6,58.02 178.66,58.02 UE5.A49 ; v2(36.45,32.65) 37.01,32.09 PR326.1
  IN1 w0.081: v2(45.19,18.39) 45.24,18.39 45.65,18.8 46.1,18.8 46.31,18.59 47.13,18.59 47.9,19.36 49.33,19.36 49.55,19.58 50.82,19.58 51.88,20.64 54.37,20.64 54.89,21.16 62.51,21.16 63.35,20.33 64.57,20.33 66.12,18.78 66.57,18.78 v2(66.7,18.65) 67.01,18.65 69.18,20.82 71.25,20.82 76.04,25.6 76.04,25.61 78.7,25.61 79.38,24.93 81.89,24.93 82.78,25.81 89.28,25.81 92.66,22.43 94.3,22.43 96.58,20.15 102.27,20.15 102.65,19.76 109.08,19.76 109.93,18.92 117.17,18.92 118.64,17.44 125.83,17.44 126.68,18.29 132.04,18.29 132.29,18.04 147.1,18.04 147.71,18.66 158,18.66 158.61,19.27 161.3,19.27 164.54,22.51 164.54,24.77 167.75,27.98 167.75,31.96 167.08,32.63 167.08,33.13 168.56,34.62 168.56,36.7 171.47,39.61 171.47,43.23 171.9,43.66 171.9,45.31 173.43,46.84 173.43,50.44 176.05,53.06 177.1,53.06 177.55,53.51 177.55,56.09 176.92,56.72 176.92,57.35 v2(177.57,58)
  IN4 w0.081: v2(45.19,18.39) 45.19,18.29 44.9,17.99 43.76,17.99 41.68,20.07 39.68,20.07 39.07,20.68 39.07,23.17 39.58,23.69 39.58,25.02 40.04,25.48 40.04,26.54 38.94,27.64 38.94,29.87 38.78,30.03 38.08,30.03 37.8,30.31 37.8,31.3 v2(36.45,32.65)
PBAT_SMBCLK: length 168.1
  TOP w0.127: PRP100.3 68.16,17.59 68.03,17.47 68.03,17.41 68.16,17.28 68.58,17.28 68.98,16.89 68.98,16.74 v2(69.24,16.48) 69.02,16.25 69.02,16.06 69.69,15.39 69.85,15.39 PD101.3 ; UE5.A56 182.36,57.82 182.36,57.63 181.91,57.18 181.91,56.22 v2(181.65,55.97)
  IN1 w0.081: v2(69.24,16.48) 69.01,16.71 69.01,17.19
  IN1 w0.089: 69.01,17.19 69.22,17.4 70.45,17.4 71.26,18.21 86.34,18.21 86.83,17.72 89.92,17.72 91.51,16.13 94.14,16.13 94.75,16.74 100.9,16.74 101.54,16.1 109.01,16.1 109.48,16.56 115.26,16.56 117.38,14.44 126.16,14.44 127.66,15.93 131.06,15.93 131.9,15.1 151.38,15.1 152.58,16.3 158.74,16.3 159.34,15.71 161.34,15.71 162.3,16.67 165.68,16.67 166.11,16.25 171.61,16.25 171.81,16.45 174.46,16.45 179.2,21.18 179.2,22.82 177.17,24.85 176.83,24.85 175.05,26.63 175.05,34.41 173.88,35.58 173.88,40.05 174.73,40.9 174.73,44.08 175.67,45.02 175.67,45.6 177.58,47.51 177.58,47.91 178.26,48.59 179.72,48.59 180.2,49.07 180.2,49.44 181.01,50.25 181.01,53.94 181.5,54.42 181.5,55.81 v2(181.65,55.97)
  BOTTOM w0.127: RE53.2 181.56,57.36 v4(181.56,56.7) 181.56,56.07 181.65,55.98 v2(181.65,55.97)
PBAT_SMBDAT: length 168.9
  TOP w0.127: PD101.2 69.85,15.11 69.61,15.11 68.76,15.96 68.76,16.17 68.46,16.47 v2(68.46,16.48) 68.65,16.67 68.65,16.85 68.47,17.03 68.06,17.03 67.78,17.31 67.78,17.47 67.66,17.6 PRP100.2 ; UE5.B59 182.11,58.67 182.11,59.08 v2(182.31,59.28)
  IN1 w0.081: v2(68.46,16.48) 68.8,16.82 68.8,17.09 68.79,17.1 68.79,17.27 68.84,17.32 68.84,17.33 68.85,17.34
  IN1 w0.089: 68.85,17.34 69.13,17.61 70.36,17.61 71.17,18.42 86.43,18.42 86.92,17.93 90.01,17.93 91.6,16.35 94.05,16.35 94.66,16.96 100.99,16.96 101.63,16.31 108.92,16.31 109.39,16.78 115.35,16.78 117.47,14.65 126.07,14.65 127.57,16.15 131.15,16.15 131.99,15.31 151.29,15.31 152.5,16.52 158.83,16.52 159.43,15.93 161.25,15.93 162.21,16.89 165.77,16.89 166.2,16.46 171.52,16.46 171.72,16.66 174.37,16.66 178.98,21.27 178.98,22.73 177.08,24.63 176.74,24.63 174.83,26.54 174.83,34.32 173.66,35.49 173.66,40.14 174.51,40.99 174.51,44.17 175.45,45.11 175.45,45.69 177.36,47.6 177.36,48 178.17,48.81 179.63,48.81 179.99,49.16 179.99,49.53 180.79,50.34 180.79,54.03 181.28,54.51 181.28,55.76 v2(181.07,55.98)
  BOTTOM w0.127: v2(182.31,59.28) v1(181.92,58.88) 181.2,58.17 RE52.2 181.31,57.77 181.31,56.21 v2(181.07,55.98)
PBATT+_C: length 10.2
  TOP w0.127: v3(70.41,25.63) v2(70.41,24.85) 72.45,24.85 v3(73.1,25.5)
  TOP w0.508: PC102.2 70.59,19.77 71.22,20.41 v3(71.22,20.79) 71.22,21.82 70.28,22.76 70.28,24.72 v2(70.41,24.85)
PBTN_SW#: length 107.9
  TOP w0.127: v2(197.16,49.77) v3(195.63,49.77) 192.48,49.77 191.75,50.5 189.08,50.5 CE21.1 RE33.2 ; SW2.4 SW2.2 191.75,79.92 191.49,79.66 190.61,79.66 v2(190.13,79.18)
  IN4 w0.081: 196.63,75.7 194.26,75.7 190.78,79.18 v2(190.13,79.18) ; v2(206.25,17.69) 206.25,20.3 202.26,24.29 202.26,30.44 v2(201.81,30.89)
  IN4 w0.089: 197.14,49.78 196.55,49.18 196.55,37.27 196.72,37.09 197.59,37.09 199.44,35.24 199.77,35.24 200.91,34.1 200.91,31.81 201.81,30.92 v2(201.81,30.89) ; 197.14,49.78 v2(197.16,49.77) ; 197.14,49.78 197.14,50.04 194.76,52.43 194.76,55.11 192.44,57.43 192.44,59.33 192.68,59.57 192.68,59.89 193.35,60.56 193.35,61.15 193.67,61.47 193.97,61.47 194.18,61.68 194.18,62.08 193.95,62.31 193.53,62.31 193.37,62.15 193.37,61.8 193.29,61.72 193.29,61.69 192.93,61.33 192.93,61.09 192.62,60.79 192.06,60.79 191.76,61.09 191.76,64.5 192.24,64.98 193.45,64.98 194.51,66.05 194.51,66.33 198.26,70.07 198.26,74.08 196.63,75.7
  BOTTOM w0.127: v2(201.81,30.89) 200.76,30.89 JAPS1.11 ; JIO1.35 200.01,15.54 200.01,16.12 200.53,16.65 202.47,16.65 202.67,16.44 204.06,16.44 204.78,17.15 205.72,17.15 v2(206.25,17.69)
PCH_ALW_ON: length 48.7
  TOP w0.127: UE5.A34 177.16,66.52 176.84,66.52 v2(176.38,66.98) ; R1443.1 183.1,36.04 183.52,36.46 186.89,36.46 189.92,39.49 v2(189.92,41.13)
  IN4 w0.081: v2(189.92,41.13) 189.92,43.27 191.04,44.39 191.04,47.91 190.08,48.87 189.58,48.87 189.08,49.38 189.08,49.87 185.68,53.27 185.68,54.67 187.29,56.28 187.29,56.93
  IN4 w0.089: 187.29,56.93 186.3,57.93 182.15,57.93 181.29,58.78 181.29,59.25 180.66,59.89 178.66,59.89 178.18,60.37 178.18,62.42 177.27,63.33 177.27,66.1 176.38,66.98 v2(176.38,66.98)
PCH_BATLOW#: length 7.1
  TOP w0.127: RC72.1 147.02,48.09 146.4,48.72 v1(146.4,48.85) 145.95,49.3 145.95,51.1 145.28,51.78 145.15,51.78 144.43,52.49 v2(144.38,52.49)
  BOTTOM w0.076: UCPU1.AU13 144.72,52.8 144.41,52.49 v2(144.38,52.49)
PCH_DPWROK: length 3.7
  TOP w0.127: v3(175.49,66.2) 175.39,66.11 175.39,65.3 175.61,65.07 176.14,65.07 176.47,65.4 v2(176.47,65.4) 176.6,65.52 UE5.A36
  BOTTOM w0.127: RC221.2 176.56,65.31 v2(176.47,65.4)
PCH_DPWROK_R: length 72
  TOP w0.127: v2(144.81,43.93) 144.81,43.86 144.43,43.48 143.45,43.48 143.1,43.14 RC220.1 142.39,42.88 v3(141.86,43.42)
  IN3 w0.089: v2(175.9,65.49) 175.9,65.28 176.18,65 179.93,65 180.81,64.12 180.81,62.79 179.57,61.55 178.61,61.55 178.07,62.09 174.54,62.09 174.22,61.77 174.22,58.5 174.41,58.31 174.41,57.23 173.3,56.11 171.26,56.11 170.11,57.25 166.51,57.25 166.02,56.76 166.02,52.37 164.28,50.62 161.04,50.62 160.31,51.35 158.98,51.35 157.42,49.79 154.79,49.79 153.42,48.42 149.32,48.42 148.29,47.39 148.29,45.95 146.88,44.55 145.83,44.55 145.21,43.93 v2(144.81,43.93)
  BOTTOM w0.127: UCPU1.BB20 141.3,49.53 141.3,48.7 141.92,48.08 141.92,47.6 143.61,45.91 CC266.1 144.12,44.92 144.22,44.92 RC215.1 144.81,44.33 v2(144.81,43.93) ; v2(175.9,65.49) 175.9,65.28 176.27,64.91 176.58,64.91 177.09,64.4 RC221.1
PCH_JTAG_TCLK: length 73.9
  TOP w0.127: JXDP1.55 65.1,72 65.63,71.46 66.32,71.46 67.38,70.39 71.38,70.39 71.91,70.93 73.28,70.93 v2(73.84,71.48) ; v2(119.18,75.65) 119.18,75.94 118.95,76.16 118.95,76.74 RC86.2 120.37,78.16 120.37,78.95 v3(119.51,79.82) 119.22,80.1 96.79,80.1 95.05,78.36 v2(95.05,76.97)
  BOTTOM w0.076: UCPU1.B56 120.07,71.8 120.07,71.86 120,71.97 120,72.09 119.94,72.21 119.94,72.47 120.13,72.65 120.13,73.6 119.39,74.33 119.39,75.46 119.18,75.68 v2(119.18,75.65)
  BOTTOM w0.127: v2(73.84,71.48) 74.61,72.26 79.93,72.26 80.29,71.9 85,71.9 86.36,70.53 88.67,70.53 89.65,71.52 89.65,73.27 91.02,74.63 93.63,74.63 95.05,76.05 v2(95.05,76.97)
PCH_PCIE_WAKE#: length 54.9
  TOP w0.127: v2(179.57,62.16) 179.58,62.15 179.58,61.84 179.36,61.62 178.75,61.62 178.6,61.77 178.01,61.77 UE5.B46 ; RC67.2 145.69,45.86 v2(145.97,46.14)
  IN3 w0.089: v2(179.57,62.16) 179.57,62.06 179.28,61.77 178.7,61.77 178.16,62.31 174.42,62.31 173.83,61.71 173.83,59.61 172.82,58.6 171.58,58.6 170.68,59.5 167.39,59.5 166.85,58.96 166.85,57.89 165.81,56.85 165.81,52.46 164.19,50.84 161.13,50.84 160.4,51.57 158.42,51.57 157.87,51.01 156.65,51.01 155.99,50.35 153.68,50.35 153.37,50.66 152.6,50.66 150.84,48.91 148.47,48.91 147.12,47.56 147.12,47.08 146.18,46.14 v2(145.97,46.14)
  BOTTOM w0.076: UCPU1.BB15 143.47,49.58 143.47,49.19 144.03,48.62 144.25,48.62 144.38,48.49 144.38,47.5 144.65,47.23
  BOTTOM w0.127: 144.65,47.23 v3(144.97,46.91) 144.97,46.7 145.53,46.14 v2(145.97,46.14)
PCH_PLTRST#: length 27.3
  TOP w0.127: 161.79,59.77 161.79,58.85 RC85.2 ; 161.79,59.77 161.79,60.15 162.94,61.3 162.94,62.77 161.93,63.79 RC226.2 ; 161.79,59.77 UC7.2 ; RC85.2 161.32,58.38 v2(160.15,58.38) ; RC85.2 161.14,59.06 UC7.1
  IN3 w0.089: v2(160.15,58.38) 160.15,57.94 159.56,57.35 158.56,57.35 156.33,55.12 154.77,55.12 154.45,55.44 150.95,55.44 150.09,56.31 146.06,56.31 145.97,56.22 145.97,55.36 146.26,55.08 v2(146.26,55.01)
  BOTTOM w0.076: v2(146.26,55.01) 146.65,55.4 UCPU1.AN10
PCH_PLTRST#_EC: length 366.3
  TOP w0.127: v2(160.53,60.31) 160.76,60.54 161.52,60.54 162.44,61.45 162.44,61.68 ; U15.17 188.95,43.19 189.08,43.06 v2(189.08,42.48) ; 162.44,61.68 UC7.4 ; 162.44,61.68 162.44,62.34 RC226.1 RC65.1 ; UE5.B30 180.61,67.33 180.72,67.22 v2(180.72,67.2) ; v2(182.25,70.06) 182.22,70.09 RE54.2
  IN1 w0.081: v2(38.81,40.55) 38.81,44.14 39.74,45.07 39.74,47.99 41.14,49.39 41.14,50.68 v2(42.32,51.86)
  IN3 w0.089: v2(160.53,60.31) 161.57,60.31 162.71,61.45 162.71,62.54 163.78,63.6 167.85,63.6 169.21,64.97 172.25,64.97 172.59,65.31 172.59,66.15 176.86,70.43 178.98,70.43 179.38,70.82 181.48,70.82 v2(182.25,70.06)
  IN4 w0.081: v2(160.53,60.31) 160.41,60.43 157.49,60.43 156.88,59.81 156.88,58.87 157.17,58.58 157.42,58.58 157.89,58.12 157.89,58.09 158.98,56.99 158.98,52.55 166.48,45.05 166.48,41.48 166.68,41.28 166.68,39.23 167.99,37.91 167.99,34.95 166.94,33.9 166.94,28.91 165.73,27.71 165.73,23.18 161.2,18.65 147.37,18.65 146.98,19.04 145.66,19.04 145.17,18.55 123.35,18.55 123.24,18.67 101.88,18.67 99.07,21.48 97.24,21.48 96.07,22.66 96.07,24.84 95.97,24.94 95.97,27.35 92.24,31.08 91.86,31.08 91.59,31.35 85.77,31.35 83.8,29.38 81.89,29.38 81.57,29.69 79.27,29.69 75.68,26.09 75.15,26.09 67.09,18.03 63.75,18.03 62.9,17.18 59.04,17.18 55.95,20.27 54.7,20.27 52.92,18.49 49.63,18.49 48.82,17.69 46.53,17.69 45.42,18.8 43.25,18.8 41.56,20.49 41.14,20.49 40.59,21.04 40.59,22.23 40.02,22.8 40.02,24.13 40.95,25.06 40.95,26.32 39.39,27.87 39.39,31.21 37.67,32.93 37.67,34.11 35.93,35.85 35.93,37.91 38.57,40.55 v2(38.81,40.55)
  IN4 w0.089: v2(182.25,70.06) 182.3,70.06 182.78,69.59 182.78,69.17 182.45,68.84 182.19,68.84 180.72,67.37 v2(180.72,67.2) 180.72,67.01 181.31,66.43 181.31,65.82 185.27,61.85 186.72,61.85 187.07,61.5 187.07,60.61 187.22,60.46 187.22,58.81 188.12,57.92 188.8,57.92 189.58,57.14 189.58,53.22 190.48,52.32 190.61,52.32 193.03,49.9 193.27,49.9 193.69,49.48 193.69,48.38 v2(193.04,47.73) 194.64,46.14 194.64,35.84 196.44,34.04 196.44,26.35 198.2,24.6 200.38,24.6 v2(200.51,24.72)
  BOTTOM w0.127: JNGFF1.44 44,47.32 43.47,47.85 43.47,48.42 42.32,49.58 v2(42.32,51.86) 42.63,52.18 R104.1 ; v2(200.51,24.72) 200.02,24.23 200.02,20.38 199.49,19.86 199.49,19.2 199.11,18.82 JIO1.38 ; v2(182.25,70.06) 182.37,70.06 183.15,70.84 JLPDE1.8 ; JNGFF2.50 175.6,35.55 176.84,35.55 176.98,35.41 178.91,35.41 181.51,38.01 v1(187.15,38.01) 187.45,37.7 190.07,37.7 190.38,38.01 190.38,39.1 189.68,39.79 189.68,40.73 189.08,41.33 v2(189.08,42.48) 189.08,43.14 189.42,43.48 190.23,43.48 192.47,45.72 192.47,47.16 v2(193.04,47.73)
PCH_POPIRCOMP: length 2.6
  TOP w0.305: RC89.1 142.22,50.91 142.62,51.32 v1(142.62,51.57) 142.62,52.44 v2(142.57,52.49)
  BOTTOM w0.254: UCPU1.AU16 142.99,52.8 v2(142.57,52.49)
PCH_PWR_EN: length 5
  TOP w0.127: v1(184.06,35.12) R1443.2 R1444.2 R1187.2 180.08,34.13 U717.3
PCH_PWROK: length 100.9
  TOP w0.254: v2(63.02,50.96) 63.07,51.01 PR1027.1 ; v2(96.19,39.38) 96.44,39.63 102.9,39.63 v3(102.97,39.56) 108.88,39.56 110.4,41.08 114.38,41.08 115.11,40.34 136.22,40.34 137.39,41.51 137.39,47.43 137.77,47.81 139.07,47.81 140.11,48.85 140.54,48.85 140.89,48.5 140.89,47.57 v2(140.98,47.49) 141.06,47.41 142.27,47.41 RC313.2
  IN3 w0.203: v2(63.02,50.96) 63.25,50.96 65,49.21 65,47.83 66.39,46.44 68.5,46.44 71.02,43.93 80.52,43.93 82.08,45.49 84.71,45.49 86.31,43.88 86.31,41.14 87.91,39.54 96.03,39.54 v2(96.19,39.38)
  BOTTOM w0.076: v2(140.98,47.49) 141.07,47.59 141.07,49.31 140.87,49.51 140.87,50.05 UCPU1.BA20
PCH_RSMRST#: length 181.2
  TOP w0.127: v2(175.76,60.13) 176.07,60.43 176.32,60.43 176.68,60.79 176.68,60.92 176.79,61.02 UE5.A45 ; v2(70.9,78.09) 71.47,77.51 71.47,76.92 RC124.1 ; v2(144.86,43.32) 144.45,42.91 RC75.2
  IN3 w0.089: v2(144.86,43.32) 144.91,43.32 145.92,44.33 146.97,44.33 148.5,45.86 148.5,47.3 149.41,48.21 154.56,48.21 155.71,49.36 157.6,49.36 158.42,50.18 164.44,50.18 166.45,52.19 166.45,56.58 166.69,56.82 169.94,56.82 171.09,55.66 174.48,55.66 175.15,56.33 175.15,59.51 v2(175.76,60.13) ; v2(171.76,72.5) 171.37,72.88 171.37,77.52 169.81,79.08 152.17,79.08 151.96,79.29 128.92,79.29 128.87,79.24 92.27,79.24 90.07,77.05 84.32,77.05 83.46,76.18 80.46,76.18 79.33,77.32 76.68,77.32 75.97,78.03 73.4,78.03 73.18,78.25 72.49,78.25 72.33,78.09 v2(70.9,78.09)
  IN4 w0.081: v2(171.76,72.5) 172.12,72.5 173.18,71.44 173.18,68.74 173.81,68.11 173.81,66.77 173.35,66.31 173.35,64.45 173.44,64.36 173.44,62.75 174.61,61.58 174.61,61.31 175.76,60.17 v2(175.76,60.13)
  BOTTOM w0.076: RC215.2 144.12,45.93 143.89,45.93 142.11,47.71 142.11,49.79 142.17,49.91 142.17,50.05 142.1,50.28 142.1,50.4 142.17,50.61 142.27,50.72 142.38,50.83 UCPU1.AY17
  BOTTOM w0.127: RC215.2 145.24,44.81 145.24,43.7 v2(144.86,43.32)
PCH_RTCRST#: length 96.9
  TOP w0.127: CC25.1 148.44,45.81 RC57.1 149.06,45.42 149.54,44.94 149.54,44.09 148.95,43.49 CMOS1.1 149.21,43.37 149.79,42.78 151.87,42.78 152.27,42.38 153.57,42.38 154.57,41.39 v2(155.93,41.39) ; v2(178.71,41.57) 179.16,41.11 179.57,41.11 182.58,38.11 186.94,38.11 187.63,38.8 188.51,38.8 189.38,39.67 189.38,41.19 189.74,41.55 190.34,41.55 190.58,41.31 190.58,33 191.45,32.13 199.3,32.13 v3(199.34,32.09) 199.75,32.09 v2(199.98,31.86)
  IN4 w0.081: v2(155.93,41.39) 156,41.45 156,41.74 154.36,43.37 154.36,44.46 154.62,44.71 154.62,45.47 154.06,46.02 153.2,46.02 152.72,46.5 151.96,46.5 146.52,51.94 146.52,52.45 146.26,52.7 146.09,52.7 145.83,52.96 145.83,55.83 145.52,56.14 143.1,56.14 v2(142.6,55.64)
  BOTTOM w0.076: UCPU1.AM16 v2(142.6,55.64)
  BOTTOM w0.127: v2(199.98,31.86) 200,31.89 JAPS1.9 ; v2(178.71,41.57) 178.94,41.34 178.94,41.16 178.44,40.65 178.1,40.65 176.86,41.89 174.75,41.89 171.87,39.01 167.27,39.01 165.37,40.9 159.11,40.9 158.98,40.78 156.54,40.78 v2(155.93,41.39)
PCH_RTCX1: length 23.1
  TOP w0.127: RC54.2 151.54,47.71 v2(151.8,47.44) 152.36,47.44 152.63,47.18 152.63,46.44 CC23.1 152.88,45.17 YC2.1 153.21,44.28 v3(154.18,43.31)
  IN1 w0.089: v2(141.68,55.64) 142.15,55.18 142.15,52.25 143.46,50.94 145.26,50.94 146.22,49.97 147.42,49.97 149.95,47.44 v2(151.8,47.44)
  BOTTOM w0.127: v2(141.68,55.64) 141.73,55.64 UCPU1.AM18
PCH_RTCX2: length 16.6
  TOP w0.127: v2(149.25,47.48) 149.61,47.48 RC54.1 150.47,47.08 RC296.1
  IN1 w0.081: v2(140.77,55.69) 140.73,55.69 140.34,55.3 140.34,52.94 141.22,52.05 141.68,52.05 143.27,50.47 145.06,50.47 146.07,49.46 147.27,49.46 v2(149.25,47.48)
  BOTTOM w0.127: UCPU1.AM20 140.87,55.69 v2(140.77,55.69)
PCH_RTCX2_R: length 8.9
  TOP w0.127: v3(155.31,41.92) 154.75,41.92 153.78,42.89 152.48,42.89 152.08,43.29 151.37,43.29 YC2.2 151.23,45.13 CC26.1 151.23,46.67 RC296.2
PCH_RTD3_CIO_PWR_EN: length 6.7
  BOTTOM w0.127: UCPU1.H5 149.93,67.17 152.25,67.17 152.82,67.74 152.82,67.99 153.06,68.24 v1(154.25,68.24) 154.86,68.24 155.23,67.86 RC248.1
PCH_SMB_ALERT#: length 10.1
  TOP w0.076: 150.3,64.87 150.28,64.87 150.26,64.9 149.77,64.9 149.3,64.42 147.71,64.42 v2(147.14,64.99)
  TOP w0.127: RC23.1 154.94,65.74 154.07,64.87 150.3,64.87
  BOTTOM w0.127: v2(147.14,64.99) 146.79,64.64 UCPU1.R10
PCH_SPI_CLK: length 62.5
  IN1 w0.081: v2(157.78,52.94) 158.43,53.59 158.43,54.65 162.28,58.49 163.01,58.49 163.25,58.26 163.63,58.26 163.94,58.57 163.94,59.48 164.57,60.11 164.57,61.07 165.41,61.9 165.41,62.83 165.76,63.18 166.08,63.18 167.07,64.17 167.65,64.17 168.17,64.69 168.17,65.27 168.24,65.34 168.24,67.49 169.77,69.02 169.77,69.94 171.91,72.07 174.07,72.07 175.38,73.38 179.8,73.38 181.42,75 183.14,75 183.28,74.85 186.77,74.85 187.81,75.9 187.81,75.9 188.48,76.56 191.98,76.56 v2(193.24,75.3)
  BOTTOM w0.089: 153.95,51.98 153.51,51.98 153.06,52.43 151.4,52.43 UCPU1.AV2
  BOTTOM w0.127: JSPI1.8 192.76,77.14 192.72,77.1 192.72,75.79 193.22,75.3 v2(193.24,75.3) 193.3,75.24 193.3,75.14 193.75,74.68 RC60.1 ; v2(157.78,52.94) 157.69,53.03 v1(157.28,53.03) 157.22,52.97 155.16,52.97 155.07,52.88 155.07,52.57 154.48,51.98 153.95,51.98
PCH_SPI_CLK_R: length 74.3
  IN2 w0.089: v2(197.29,71.81) 197.99,71.11 199.85,71.11 200.61,70.35 200.61,66.62 203.01,64.22 203.01,61.77 202.16,60.92 202.16,56.47 202.38,56.26 202.38,54 198.85,50.47 198.85,45.87 200.37,44.36 v2(200.94,44.36)
  IN3 w0.089: v2(200.94,44.36) 200.37,44.36 199.55,45.18 190.93,45.18 189.56,43.81 188.6,43.81 187.92,44.48 184.21,44.48 181.14,47.56 180.12,47.56 180.05,47.49 178.69,47.49 178.51,47.67 178.51,48.38 179.39,49.26 v2(179.4,49.26)
  BOTTOM w0.127: RP5.6 RP5.7 177.32,48.21 177.48,48.37 177.48,48.93 177.71,49.16 178.31,49.16 178.42,49.26 v2(179.4,49.26) ; v2(197.29,71.81) 194.9,71.81 RC60.2 192.84,74.51 192.22,75.13 192.22,77.19 192.26,77.23 JSPI1.7
PCH_SPI_CLK_TPM: length 15.1
  TOP w0.127: C135.1 190.23,44.66 190.04,44.47 190.04,44.47 189.78,44.21 v2(189.39,44.21) 188.93,44.21 188.91,44.19 U15.19
  IN3 w0.089: v2(178.91,47.96) 179.02,48.06 181.76,48.06 184.07,45.75 187.32,45.75 188.61,44.46 189.14,44.46 v2(189.39,44.21)
  BOTTOM w0.127: RP5.3 178.67,47.71 v2(178.91,47.96)
PCH_SPI_CS0#: length 72.1
  IN1 w0.081: v2(162.48,57.84) 162.49,57.84 163.8,57.84 164.37,58.41 164.37,59.32 166.81,61.76 166.81,62.02 167.96,63.17 167.96,63.89 168.59,64.51 168.59,65.1 168.65,65.17 168.65,66.77 168.97,67.09 169.26,67.09 169.79,67.62 169.79,68.17 173.28,71.66 175.14,71.66 175.23,71.74 175.23,72.1 175.3,72.18 175.47,72.18 175.55,72.1 175.55,71.74 175.63,71.66 176.53,71.66 177.79,72.92 180.15,72.92 180.84,73.61 181.88,73.61 182.24,73.97 183.71,73.97 183.79,74.05 183.79,74.35 183.87,74.43 184.04,74.43 184.12,74.35 184.12,74.05 184.2,73.97 184.36,73.97 184.44,74.05 184.44,74.35 184.52,74.43 184.69,74.43 184.77,74.35 184.77,74.05 184.85,73.97 185.01,73.97 185.09,74.05 185.09,74.35 185.17,74.43 185.34,74.43 185.42,74.35 185.42,74.05 185.5,73.97 185.66,73.97 185.74,74.05 185.74,74.35 185.82,74.43 185.99,74.43 186.07,74.35 186.07,74.05 186.15,73.97 186.66,73.97 187.61,74.92 189.27,74.92 189.27,74.94 189.65,75.32 190.39,75.32 190.47,75.4 190.47,76.25 190.55,76.34 190.72,76.34 190.8,76.25 190.8,75.4 190.88,75.32 191.04,75.32 191.12,75.4 191.12,76.25 191.2,76.34 191.37,76.34 191.45,76.25 191.45,75.4 191.53,75.32 191.69,75.32 191.77,75.4 191.77,76.15 191.86,76.23 192.02,76.23 192.1,76.15 192.1,75.4 192.18,75.32 192.47,75.32 192.89,74.9 193.41,74.9 193.7,75.2 193.7,75.78 193.51,75.97 v2(193.14,75.97)
  BOTTOM w0.089: UCPU1.AU3 151.09,52.61 153.14,52.61 153.55,52.2 153.89,52.2
  BOTTOM w0.127: RC58.1 192.37,79.97 192.77,79.56 193.09,79.56 193.76,78.89 JSPI1.10 193.76,76.59 v2(193.14,75.97) ; 153.89,52.2 154.39,52.2 154.85,52.66 154.85,53 155.07,53.22 156.97,53.22 157.12,53.37 158.12,53.37 v1(158.5,53.76) 158.88,54.14 158.88,54.27 159.27,54.67 159.27,55.33 161.79,57.84 v2(162.48,57.84)
PCH_SPI_CS0#_R: length 63.1
  IN2 w0.089: v2(196.39,74.11) 196.39,74.08 197.17,73.31 199.7,73.31 201.33,71.68 201.33,66.99 203.66,64.66 203.66,61.5 203.39,61.23 203.39,54.09 199.93,50.62 199.93,45.93 v2(200.33,45.53)
  IN3 w0.089: v2(188.91,47.25) 189.73,46.42 196.27,46.42 197.09,45.61 200.25,45.61 v2(200.33,45.53) ; v2(192.83,78.74) 192.83,77.56 196.27,74.11 v2(196.39,74.11)
  BOTTOM w0.127: U18.1 185.01,48.17 185.14,48.3 185.86,48.3 185.99,48.17 185.99,47.8 186.11,47.67 186.37,47.67 186.49,47.8 186.49,48.17 186.62,48.3 186.99,48.3 188.04,47.25 v2(188.91,47.25) ; RC58.2 191.45,79.63 191.58,79.5 192.06,79.5 v2(192.83,78.74) 193.26,78.31 JSPI1.9
PCH_SPI_CS2#: length 136.3
  TOP w0.127: RC230.2 185.92,39.44 186.79,39.44 188.28,40.92 188.28,42.53 187.83,42.97 187.83,44.57 187.96,44.69 U15.20 188.89,44.69 189.18,44.98 v2(189.76,44.98) 189.91,45.13 190.03,45.13 190.17,45.27 v1(192.18,45.27) 192.41,45.27 RH127.1
  IN3 w0.089: v2(179.91,50.07) 179.91,49.29 180.67,48.53 186.2,48.53 188.57,46.15 188.57,45.38 188.95,45.01 189.74,45.01 v2(189.76,44.98)
  BOTTOM w0.089: 153.93,52.41 153.64,52.41 153.24,52.82 152.19,52.82 UCPU1.AU1
  BOTTOM w0.127: 153.93,52.41 154.3,52.41 154.64,52.75 154.64,53.09 155.07,53.53 156.92,53.53 157.02,53.63 157.87,53.63 159.02,54.77 159.02,55.44 161.85,58.26 163.22,58.26 163.63,57.85 164.72,57.85 167.1,55.46 167.1,53.98 166.81,53.69 166.81,53.05 167.11,52.75 167.11,50.18 167.23,50.06 167.52,50.06 167.64,50.18 167.64,53.7 167.79,53.85 168.01,53.85 168.14,53.73 168.14,50.76 168.27,50.63 168.52,50.63 168.65,50.76 168.65,54.29 168.8,54.44 169.03,54.44 169.16,54.31 169.16,50.76 169.28,50.63 169.54,50.63 169.66,50.76 169.66,54.29 169.82,54.44 170.1,54.44 170.23,54.31 170.23,52.74 170.36,52.62 171.08,52.62 171.2,52.49 171.2,51.29 171.08,51.16 170.23,51.16 170.1,51.04 170.1,50.78 170.23,50.66 171.08,50.66 171.2,50.53 171.2,50.28 171.08,50.15 169.09,50.15 168.96,50.02 168.96,49.79 169.11,49.64 171.09,49.64 171.22,49.51 171.22,49.33 171.09,49.21 167.08,49.21 166.95,49.08 166.95,48.83 167.08,48.7 167.34,48.7 167.47,48.57 167.47,47.86 167.6,47.74 167.85,47.74 167.98,47.86 167.98,48.57 168.1,48.7 168.36,48.7 168.49,48.57 168.49,47.86 168.61,47.74 168.87,47.74 168.99,47.86 168.99,48.57 169.12,48.7 169.37,48.7 169.5,48.57 169.5,47.38 169.63,47.25 169.88,47.25 170.01,47.38 170.01,48.57 170.14,48.7 170.47,48.7 170.59,48.57 170.59,47.38 170.72,47.25 170.98,47.25 171.1,47.38 171.1,48.57 171.23,48.7 171.58,48.7 171.74,48.85 171.74,52.49 171.86,52.62 172.12,52.62 172.27,52.47 172.27,47.12 172.4,46.99 172.65,46.99 172.78,47.12 172.78,52.47 172.93,52.62 173.19,52.62 173.32,52.49 173.32,51.04 173.44,50.91 173.7,50.91 173.83,51.04 173.83,51.58 173.95,51.71 174.25,51.71 174.37,51.58 174.37,51.1 174.5,50.97 174.76,50.97 174.88,51.1 174.88,51.29 175.01,51.42 175.27,51.42 175.53,51.16 175.53,49.09 173.59,47.15 173.59,46.97 173.81,46.75 173.99,46.75 176.3,49.06 177.24,49.06 177.6,49.42 178.11,49.42 178.39,49.69 179.53,49.69 v2(179.91,50.07)
PCH_SPI_DO2_XDP: length 112.6
  TOP w0.127: v2(66.29,65.52) 65.96,65.52 65.48,66 64.32,66 64.1,66.22 JXDP1.60
  IN1 w0.089: v2(157.61,52.35) 157.07,52.89 152.96,52.89 149.51,56.35 149.51,57.47 148.5,58.48 144.18,58.48 143.95,58.7 139.96,58.7 137.86,60.81 137.86,65.02 136.27,66.61 135.05,66.61 134.91,66.75 134.91,67.21 134.59,67.53 125.04,67.53 124.8,67.29 124.8,66.25 124.02,65.46 120.35,65.46 119.15,66.66 118.64,66.66 118.36,66.94 118.36,67.37 118.14,67.6 117.45,67.6 117.32,67.47 113.78,67.47 113.47,67.78 112.12,67.78 111.27,66.93 109.78,66.93 109.48,66.63 108.31,66.63 107.66,65.98 100.4,65.98 99.06,67.32 83.84,67.32 82.49,65.96 79.16,65.96 78.27,65.07 71.72,65.07 71.37,64.73 70.41,64.73 69.61,63.93 67.48,63.93 66.75,64.65 66.75,64.96 66.29,65.41 v2(66.29,65.52)
  BOTTOM w0.127: v2(157.61,52.35) 157.61,51.8 v1(157.56,51.75) 157.46,51.65 RC11.1
PCH_SPI_DO_XDP: length 124.5
  TOP w0.127: RC128.1 RC133.2 63.98,77.48 63.66,77.8 62.92,77.8 62.59,77.48 62.59,75.43 62.38,75.22 62.38,71.69 63.74,70.33 63.74,66.22 64.22,65.74 65.38,65.74 66.19,64.93 v2(66.19,64.93)
  IN1 w0.081: 149.29,57.38 149.29,57.37 149.29,56.26 152.87,52.68 156.68,52.68 v2(157.01,52.35)
  IN1 w0.089: v2(66.19,64.93) 66.19,64.75 67.23,63.71 69.7,63.71 70.5,64.51 71.46,64.51 71.81,64.86 79.78,64.86 80.67,65.74 82.58,65.74 83.93,67.1 98.97,67.1 100.31,65.77 107.75,65.77 108.4,66.42 109.57,66.42 109.87,66.72 111.36,66.72 112.21,67.56 113.38,67.56 113.69,67.25 117.2,67.25 118.05,66.4 119.1,66.4 120.27,65.24 124.09,65.24 125.11,66.25 125.11,67.14 125.28,67.32 133.35,67.32 134.42,66.25 136.09,66.25 137.64,64.7 137.64,60.72 139.88,58.49 143.86,58.49 144.09,58.26 148.41,58.26 149.29,57.38
  BOTTOM w0.127: v2(157.01,52.35) 156.83,52.54 RC10.1
PCH_SPI_IO2: length 71.3
  IN1 w0.081: v2(159.56,50.71) 159.56,54.8 161.79,57.02 164.57,57.02 165.85,58.31 165.85,59.72 167.23,61.09 167.23,61.85 168.38,63 168.38,63.72 169,64.34 169,64.93 170.33,66.26 170.33,67.74 171.86,69.26 172.58,69.26 174.56,71.24 176.7,71.24 177.97,72.51 180.33,72.51 181.02,73.19 182.06,73.19 182.41,73.55 188.16,73.55 188.43,73.82 189.21,73.82 190.14,74.76 192.25,74.76 192.89,74.13 193.88,74.13 194.56,74.81 196,74.81 196.94,75.76 196.94,77.32 196.82,77.44 195.48,77.44 v2(195.02,76.98)
  BOTTOM w0.076: UCPU1.AW2 151.49,51.63 151.98,51.14 152.45,51.14
  BOTTOM w0.127: RC61.1 194.12,79.25 194.76,78.61 JSPI1.12 194.76,77.25 v2(195.02,76.98) ; 152.45,51.14 152.86,51.14 153.06,50.94 154.97,50.94 RC11.2 RH59.2 156.11,51.19 157.71,51.19 157.91,51.39 v3(159.21,51.39) 159.56,51.04 v2(159.56,50.71)
PCH_SPI_IO2_R: length 71.3
  IN2 w0.089: v2(199.52,46.37) 199.67,46.52 199.67,50.68 203.18,54.19 203.18,61.32 203.44,61.59 203.44,64.57 201.12,66.9 201.12,70.45 200.03,71.54 198.45,71.54 196.9,73.09 196.63,73.09 195.73,73.99 v2(195.73,74.09)
  BOTTOM w0.127: v2(199.52,46.37) 199.69,46.53 199.69,47.3 198.27,48.72 198.27,49.83 197.52,50.58 196.99,50.58 196.24,49.83 v3(193.73,49.83) 193.23,49.83 191.65,48.25 191.65,47.07 191,46.42 189.24,46.42 188.49,45.66 188.49,44.56 188.17,44.24 183.45,44.24 183.3,44.09 177.72,44.09 177.56,44.25 177.56,44.79 177.43,44.92 RP6.6 ; RC61.2 193.21,79.81 194.26,78.75 JSPI1.11 194.26,76.22 195.69,74.79 195.69,74.13 v2(195.73,74.09)
PCH_SPI_IO3: length 98
  IN1 w0.081: v2(195.84,76.42) 194.78,75.36 194.49,75.36 193.75,74.62 192.79,74.62 192.41,75 189.79,75 189.52,74.74 189.52,74.71 187.7,74.71 186.74,73.76 182.32,73.76 181.97,73.4 180.93,73.4 180.24,72.71 177.88,72.71 176.61,71.45 173.36,71.45 170.13,68.21 170.13,67.37 169.5,66.74 169.5,65.71 168.79,65.01 168.79,64.43 168.17,63.81 168.17,63.08 167.02,61.93 167.02,61.68 164.58,59.23 164.58,58.07 163.74,57.23 161.7,57.23 158.85,54.38 158.85,52.73 157.66,51.54 155.84,51.54 154.86,50.56 153.57,50.56 v2(153.24,50.22)
  BOTTOM w0.076: 152.58,50.55 152.53,50.51 151.99,50.51 151.84,50.66 151.4,50.66 151.18,50.88 151.18,51.02 150.91,51.29 150.24,51.29 149.96,51.57 149.96,52.04 150.22,52.29 150.22,52.84 UCPU1.AU4
  BOTTOM w0.127: RH56.2 RH58.2 175.31,44.2 174.48,43.37 173.83,43.37 v3(172.79,44.41) 171.81,45.38 169.23,45.38 169.02,45.17 162.81,45.17 162.49,44.85 159.75,44.85 159.08,45.52 159.08,46.41 159.36,46.69 159.36,47.79 159.66,48.1 159.66,49.23 159.54,49.36 159.54,50 159.08,50.45 157.76,50.45 157.4,50.1 155.45,50.1 154.99,50.55 153.57,50.55 v2(153.24,50.22) 152.91,50.55 152.58,50.55 ; RC62.1 196.25,79.91 196.25,78.81 195.76,78.32 JSPI1.14 195.76,76.51 v2(195.84,76.42)
PCH_SPI_IO3_R: length 69.2
  IN2 w0.089: v2(199.26,46.89) 199.26,50.58 202.96,54.28 202.96,61.41 203.23,61.68 203.23,64.48 200.9,66.81 200.9,70.36 199.94,71.33 198.36,71.33 197.43,72.26 196.12,72.26 195.24,73.13 195.24,76.43 v2(195.26,76.45)
  BOTTOM w0.127: RC62.2 194.96,78.84 195.26,78.54 JSPI1.13 195.26,77.34 195.44,77.16 195.44,76.63 v2(195.26,76.45) ; v2(199.26,46.89) 199.26,47.03 198.02,48.27 198.02,49.52 197.34,50.21 196.98,50.21 195.85,49.07 v3(195.62,49.07) 192.83,49.07 191.91,48.15 191.91,46.97 191.11,46.16 189.35,46.16 188.74,45.56 188.74,44.45 188.28,43.99 183.56,43.99 183.41,43.84 177.61,43.84 177.3,44.15 177.3,44.34 177.23,44.42 RP6.5
PCH_SPI_SI: length 63.1
  IN1 w0.081: v2(188.89,75.32) 188.86,75.32 188.67,75.13 187.52,75.13 187.04,74.64 183.19,74.64 183.06,74.78 181.49,74.78 179.89,73.18 175.47,73.18 174.15,71.87 173.19,71.87 169.58,68.26 169.58,67.71 169.25,67.38 168.96,67.38 168.44,66.86 168.44,65.25 168.38,65.19 168.38,64.6 167.65,63.88 167.07,63.88 166.16,62.97 165.84,62.97 165.61,62.74 165.61,61.81 164.78,60.98 164.78,60.02 164.16,59.4 164.16,58.49 163.71,58.05 163.16,58.05 162.93,58.28 162.36,58.28 158.64,54.56 158.64,52.83 157.76,51.94 154.47,51.94 v2(154.08,51.56)
  BOTTOM w0.076: UCPU1.AV3 150.7,52.2 151,51.9 151.77,51.9 151.85,51.82
  BOTTOM w0.127: JSPI1.4 190.76,77.2 188.89,75.33 v2(188.89,75.32) 188.89,75.64 188.27,76.26 187.72,76.26 RC55.1 187.19,76.78 186.73,77.24 186.73,78.03 187.07,78.37 v1(187.07,78.85) ; 151.85,51.82 152.25,51.82 152.48,51.6 154.04,51.6 v2(154.08,51.56) 154.36,51.56 155.34,52.54 RC10.2
PCH_SPI_SI_R: length 78.1
  TOP w0.127: v2(199.33,44.77) v1(199.33,44.21)
  IN2 w0.089: v2(188.6,77.75) 192.63,77.75 193.68,76.7 193.68,74.38 197.36,70.7 199.7,70.7 200.25,70.14 200.25,66.4 201.35,65.31 201.35,61.97 201.94,61.38 201.94,56.38 202.16,56.17 202.16,54.09 198.64,50.56 198.64,45.46 v2(199.33,44.77)
  IN3 w0.089: v2(188.6,77.75) 188.6,76.52 v2(188.96,76.16) ; v2(178.93,47.05) 179.33,46.66 181.69,46.66 184.07,44.27 187.83,44.27 188.51,43.6 189.65,43.6 190.82,44.77 v2(199.33,44.77)
  BOTTOM w0.127: JSPI1.3 190.26,77.46 v2(188.96,76.16) 187.68,77.44 187.45,77.44 RC55.2 ; v2(178.93,47.05) 178.93,47.05 178.77,46.89 177.76,46.89 177.44,47.21 RP5.5 176.47,47.21 176.35,47.34 176.35,48.58 176.48,48.71 RP5.8
PCH_SPI_SI_TPM: length 15
  TOP w0.127: U15.21 188.89,45.19 189.25,45.56 v2(189.34,45.56)
  IN3 w0.089: v2(180.6,49.18) 181.03,48.75 186.62,48.75 189.03,46.34 189.03,45.88 189.34,45.57 v2(189.34,45.56)
  BOTTOM w0.127: RP5.4 178.5,47.21 178.76,47.47 179.09,47.47 180.6,48.99 v2(180.6,49.18)
PCH_SPI_SO: length 68.1
  IN1 w0.081: v2(150.32,51.72) 152.52,49.52 154.12,49.52 155.93,51.33 157.94,51.33 158.96,50.31 163.57,50.31 165.8,52.54 165.8,56.88 166.52,57.6 166.52,60.09 167.44,61.01 167.44,61.76 168.59,62.91 168.59,63.63 169.21,64.25 169.21,64.84 170.54,66.17 170.54,67.65 171.95,69.05 172.66,69.05 174.64,71.03 176.79,71.03 178.05,72.3 180.41,72.3 181.1,72.98 182.14,72.98 182.5,73.34 188.24,73.34 188.52,73.62 190.64,73.62 191.27,74.24 v2(191.31,74.24)
  IN2 w0.089: v2(191.31,74.24) 191.16,74.24 190,75.41 v2(190,75.78)
  BOTTOM w0.127: v2(190,75.78) 190.23,76.02 191.24,76.02 191.76,76.54 JSPI1.6 191.76,78.72 190.6,79.88 RC53.1 ; UCPU1.AW3 150.4,51.64 v2(150.32,51.72)
PCH_SPI_SO_R: length 78.7
  TOP w0.127: v1(199.95,46.77) 199.95,46.65 v2(200.33,46.26)
  IN2 w0.089: v2(196.55,76.42) 197.03,75.94 201.22,75.94 201.77,75.39 201.77,66.86 203.87,64.75 203.87,61.41 203.61,61.14 203.61,54 200.33,50.72 v2(200.33,46.26)
  IN3 w0.089: v2(200.33,46.26) 200.33,46.42 199.42,47.33 189.47,47.33 188.1,48.69 187.68,48.69 v2(187.64,48.73) ; v2(189.33,79.35) 189.33,79.49 189.42,79.58 193.57,79.58 194.35,78.8 194.35,76.78 195.11,76.02 196.15,76.02 v2(196.55,76.42)
  BOTTOM w0.127: v2(187.64,48.73) 187.46,48.9 181.12,48.9 179.79,47.58 179.79,47.03 179.11,46.35 177.86,46.35 177.43,45.92 RP6.8 RP6.7 ; JSPI1.5 191.26,78.69 RC53.2 189.33,79.9 v2(189.33,79.35)
PCH_SPI_SO_TPM: length 13.2
  TOP w0.127: U15.24 188.43,46.99 188.43,46.99 188.43,47.73 187.95,48.21 v2(187.95,48.23)
  BOTTOM w0.127: v2(187.95,48.23) 187.5,48.23 187.1,48.64 181.26,48.64 180.05,47.43 180.05,46.92 179.04,45.92 RP6.1
PCH_TBT_FORCE_PWR: length 3.8
  TOP w0.127: v2(148.92,69.94) 148.92,70 148.31,70.61 RC247.1 148.18,70.62 147.84,70.96 147.84,71.9 v1(147.35,72.4)
  BOTTOM w0.127: UCPU1.D7 148.59,70.26 v2(148.92,69.94)
PCI_CLK_LPC0: length 14.8
  BOTTOM w0.076: 150.78,46.69 150.14,47.33 149.68,47.33 149.45,47.1 149.07,47.1 148.81,47.36 148.81,47.94 147.47,49.28 147.18,49.28 146.86,49.6 146.86,50.53 146.94,50.61 146.94,51.03 147,51.22 147.22,51.44 UCPU1.AW9
  BOTTOM w0.127: 150.78,46.69 150.83,46.69 152.28,45.24 153.48,45.24 154.04,44.68 155.06,44.68 RC18.1 155.8,45.18 155.8,44.49 v3(155.68,44.37)
PCI_CLK_LPC1: length 11.5
  BOTTOM w0.076: 150.81,47.39 150.57,47.39 149.94,48.03 149.2,48.03 147.65,49.57 147.65,50.02 147.47,50.2 147.47,50.85 147.34,50.99 UCPU1.AY9
  BOTTOM w0.127: RC22.1 155.23,45.74 v3(154.25,45.74) 152.47,45.74 150.81,47.39
PCIE_PRX_CARDTX_N6: length 109.9
  IN2 w0.076: v2(141.68,68.59) 141.85,68.59 142.04,68.78 142.04,69.14 142.24,69.34 142.24,70.21 142.39,70.36 142.43,70.36 142.44,70.37
  IN2 w0.102: v2(202.11,21.4) 202.33,21.61 202.33,22.02 201.93,22.42 201.18,22.42 199.04,24.55 199.04,26 192.33,32.71 192.33,43.45 191.9,43.88 191.9,45.94 191.03,46.81 189.95,46.81 188.9,47.86 188.9,48.5 187.87,49.53 187.87,51.14 189.84,53.12 189.84,57.82 190.48,58.46 190.48,59.82 190.3,60 190.3,62.55 189.79,63.06 188.97,63.06 187.11,64.92 185.72,64.92 185.32,65.31 185.32,65.8 184.84,66.29 184.84,67.19 184.42,67.61 178.43,67.61 178.21,67.39 177.1,67.39 176.64,67.86 174.92,67.86 174.82,67.75 173.28,67.75 173.18,67.86 170.89,67.86 170.1,67.06 166.62,67.06 166.55,66.99 161.6,66.99 161.05,67.54 158.78,67.54 157.92,66.68 155.93,66.68 153.77,68.84 152.98,68.84 152.85,68.97 151.97,68.97 149.63,71.31 143.38,71.31 142.44,70.37
  BOTTOM w0.127: v2(141.68,68.59) 141.84,68.59 UCPU1.G18 ; v2(202.11,21.4) 202.29,21.22 202.29,20.86 202.11,20.68 202.11,19.18 202.25,19.04 202.25,18.72 202.11,18.58 JIO1.28
PCIE_PRX_CARDTX_P6: length 110
  IN2 w0.076: v2(141.68,69.18) 141.84,69.18 142.08,69.41 142.08,70.28 142.27,70.48 142.27,70.52 142.28,70.53
  IN2 w0.102: v2(202.77,21.4) 202.55,21.61 202.55,22.11 202.02,22.64 201.27,22.64 199.26,24.65 199.26,26.09 192.55,32.81 192.55,43.54 192.13,43.97 192.13,46.03 191.13,47.03 190.04,47.03 189.12,47.96 189.12,48.6 188.09,49.63 188.09,51.05 190.06,53.03 190.06,57.73 190.7,58.37 190.7,59.91 190.52,60.09 190.52,62.65 189.89,63.28 189.06,63.28 187.2,65.15 185.81,65.15 185.55,65.41 185.55,65.9 185.06,66.38 185.06,67.28 184.52,67.83 178.33,67.83 178.12,67.62 177.2,67.62 176.73,68.08 174.83,68.08 174.73,67.98 173.38,67.98 173.27,68.08 170.8,68.08 170.01,67.29 166.53,67.29 166.45,67.22 161.69,67.22 161.14,67.76 158.69,67.76 157.83,66.9 156.02,66.9 153.86,69.06 153.08,69.06 152.94,69.19 152.06,69.19 149.72,71.54 143.29,71.54 142.28,70.53
  BOTTOM w0.127: UCPU1.F18 141.92,68.94 v2(141.68,69.18) ; v2(202.77,21.4) 202.54,21.17 202.54,20.76 202.36,20.57 202.36,19.29 202.5,19.15 202.5,18.81 202.71,18.6 JIO1.26
PCIE_PRX_SSDTX_N9: length 79.6
  IN4 w0.091: v2(181.94,24.24) 181.78,24.4 181.02,24.4 180.24,25.19 180.24,25.71 175.34,30.62 175.34,37.99 172.25,41.08 172.25,46.94 171.33,47.86 171.33,51.85 168.91,54.27 168.91,55.83 166.38,58.36 166.38,61.29 165.34,62.33 165.34,62.93 164.59,63.68 163.58,63.68 162.66,64.61 162.66,65.72 162.46,65.92 161.74,65.92 160.16,67.5 159.16,67.5 158.75,67.9 158.75,68.17 158.62,68.3 157.92,68.3 157.86,68.25 154.8,68.25 152.57,70.48 150.21,70.48 149.47,71.22 145.33,71.22 144.37,70.27 143.69,70.27 143.56,70.4 142.55,70.4 142.34,70.19 140.49,70.19 139.69,69.39 139.09,69.39 v2(138.96,69.26)
  BOTTOM w0.127: UCPU1.E22 139.25,69.59 139,69.33 139,69.26 138.96,69.22 v2(138.96,69.26) ; v2(181.94,24.24) 182.1,24.4 182.32,24.4 182.42,24.3 183.15,24.3 JNGFF2.5
PCIE_PRX_SSDTX_N10: length 81.4
  IN4 w0.091: v2(138,69.18) 138,69.34 138.12,69.45 138.35,69.45 138.57,69.66 138.57,70.73 139.11,71.28 144.55,71.28 145.09,71.81 149.71,71.81 149.94,71.58 152.3,71.58 155.04,68.84 157.62,68.84 157.68,68.89 158.87,68.89 159.08,68.68 160.23,68.68 160.92,67.99 161.15,67.99 162.51,66.63 162.71,66.63 163.38,65.97 163.38,64.78 163.84,64.32 164.86,64.32 166.98,62.19 166.98,58.66 170.65,55 170.65,53.62 171.94,52.33 171.94,48.23 173.06,47.12 173.06,43.29 173.67,42.68 173.67,41.15 175.95,38.87 175.95,32.7 181.18,27.47 184.23,27.47 184.38,27.31 v2(184.38,27.24)
  BOTTOM w0.127: v2(184.38,27.24) 184.19,27.43 184.06,27.43 183.93,27.3 183.15,27.3 JNGFF2.17 ; UCPU1.F25 137.76,68.94 v2(138,69.18)
PCIE_PRX_SSDTX_N11: length 86
  IN4 w0.091: v2(135.33,69.89) 135.57,69.65 135.57,69.4 135.81,69.16 136.53,69.16 137.02,69.65 137.02,70.16 136.32,70.85 136.32,71.25 137.33,72.26 142.67,72.26 142.8,72.39 144.19,72.39 144.62,72.82 149.95,72.82 150.36,73.23 151.6,73.23 152.45,74.08 157.88,74.08 158.3,73.66 158.3,72.59 160.85,70.04 163.49,70.04 163.99,69.54 163.99,67.14 165.81,65.31 165.81,65.27 167.83,63.26 167.83,61.09 169.14,59.78 169.14,57.9 172.93,54.11 172.93,48.65 173.86,47.73 173.86,46.86 176.64,44.08 177.51,44.08 177.94,43.64 178.6,43.64 179.37,42.87 180.21,42.87 180.3,42.77 180.3,34.25 181.15,33.39 181.15,32.26 180.85,31.96 180.85,30.93 181.08,30.69 181.38,30.69 v2(181.53,30.54)
  BOTTOM w0.127: v2(135.33,69.89) 135.63,69.59 UCPU1.E28 ; JNGFF2.29 182.44,30.29 182.32,30.42 182.16,30.42 181.87,30.7 181.7,30.7 v2(181.53,30.54)
PCIE_PRX_SSDTX_P9: length 79.6
  IN4 w0.091: v2(181.94,24.82) 181.71,24.6 181.1,24.6 180.43,25.27 180.43,25.79 175.53,30.7 175.53,38.07 172.44,41.16 172.44,47.02 171.53,47.94 171.53,51.93 169.1,54.35 169.1,55.91 166.57,58.44 166.57,61.37 165.53,62.41 165.53,63.01 164.67,63.88 163.66,63.88 162.85,64.69 162.85,65.8 162.54,66.11 161.82,66.11 160.24,67.69 159.24,67.69 158.94,67.98 158.94,68.25 158.7,68.5 157.84,68.5 157.78,68.44 154.88,68.44 152.65,70.67 150.29,70.67 149.55,71.42 145.25,71.42 144.29,70.46 143.77,70.46 143.64,70.6 142.47,70.6 142.26,70.38 140.41,70.38 139.61,69.58 139.26,69.58 v2(138.97,69.87)
  BOTTOM w0.127: v2(138.97,69.87) 138.69,69.59 UCPU1.E23 ; v2(181.94,24.82) 182.11,24.65 182.17,24.65 182.32,24.8 183.15,24.8 JNGFF2.7
PCIE_PRX_SSDTX_P10: length 81.3
  IN4 w0.091: v2(137.95,69.89) 137.95,69.76 138.06,69.65 138.27,69.65 138.37,69.74 138.37,70.81 139.03,71.47 144.47,71.47 145.01,72 149.79,72 150.02,71.77 152.38,71.77 155.12,69.03 157.54,69.03 157.6,69.09 158.95,69.09 159.16,68.87 160.31,68.87 161,68.19 161.23,68.19 162.59,66.83 162.79,66.83 163.57,66.05 163.57,64.86 163.92,64.51 164.94,64.51 167.17,62.27 167.17,58.74 170.84,55.08 170.84,53.7 172.14,52.41 172.14,48.31 173.25,47.2 173.25,43.37 173.86,42.76 173.86,41.23 176.14,38.95 176.14,32.78 181.26,27.66 184.19,27.66 v2(184.38,27.85)
  BOTTOM w0.127: v2(184.38,27.85) 184.21,27.68 184.01,27.68 183.9,27.8 183.15,27.8 JNGFF2.19 ; UCPU1.E25 137.7,69.59 137.95,69.83 v2(137.95,69.89)
PCIE_PRX_SSDTX_P11: length 86
  IN4 w0.091: v2(136.17,69.88) 135.91,69.88 135.76,69.73 135.76,69.48 135.89,69.35 136.45,69.35 136.82,69.73 136.82,70.08 136.13,70.77 136.13,71.33 137.25,72.45 142.59,72.45 142.72,72.58 144.11,72.58 144.54,73.01 149.87,73.01 150.28,73.43 151.52,73.43 152.37,74.27 157.96,74.27 158.49,73.74 158.49,72.67 160.93,70.23 163.57,70.23 164.18,69.62 164.18,67.22 166,65.39 166,65.35 168.02,63.34 168.02,61.17 169.33,59.86 169.33,57.98 173.13,54.19 173.13,48.73 174.05,47.81 174.05,46.94 176.72,44.27 177.59,44.27 178.02,43.84 178.68,43.84 179.45,43.06 180.29,43.06 180.49,42.85 180.49,34.33 181.35,33.47 181.35,32.18 181.04,31.88 181.04,31.01 181.16,30.89 181.29,30.89 v2(181.53,31.13)
  BOTTOM w0.127: v2(181.53,31.13) 181.7,30.96 181.98,30.96 182.27,30.67 182.4,30.67 182.53,30.8 183.15,30.8 JNGFF2.31 ; v2(136.17,69.88) 136.45,69.59 UCPU1.E27
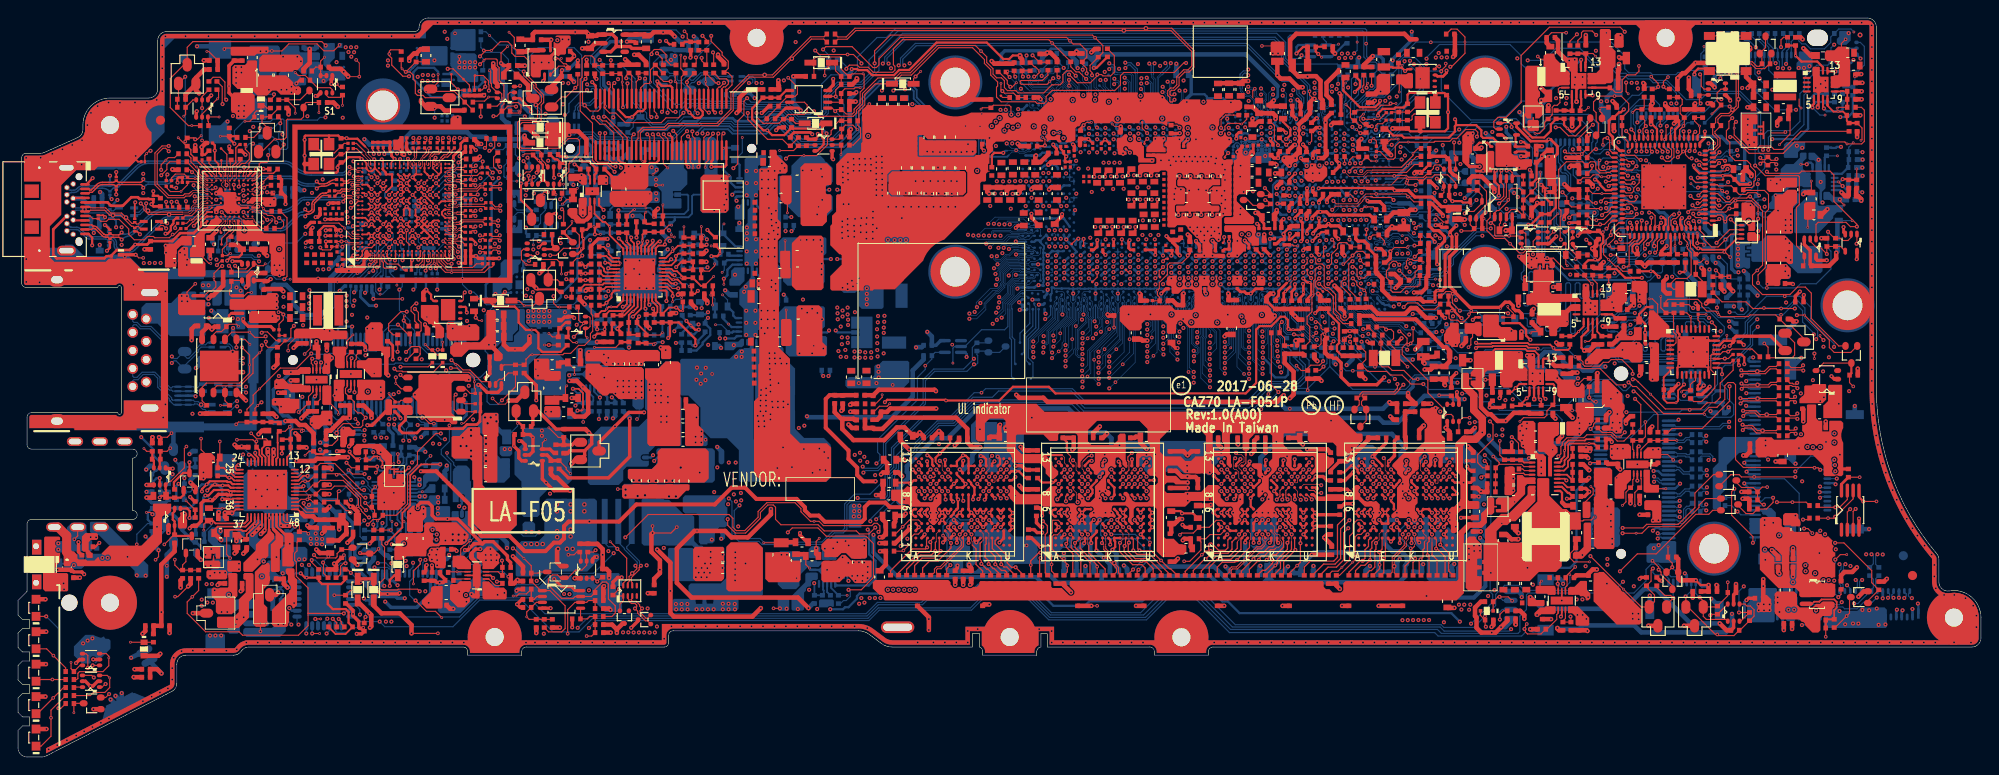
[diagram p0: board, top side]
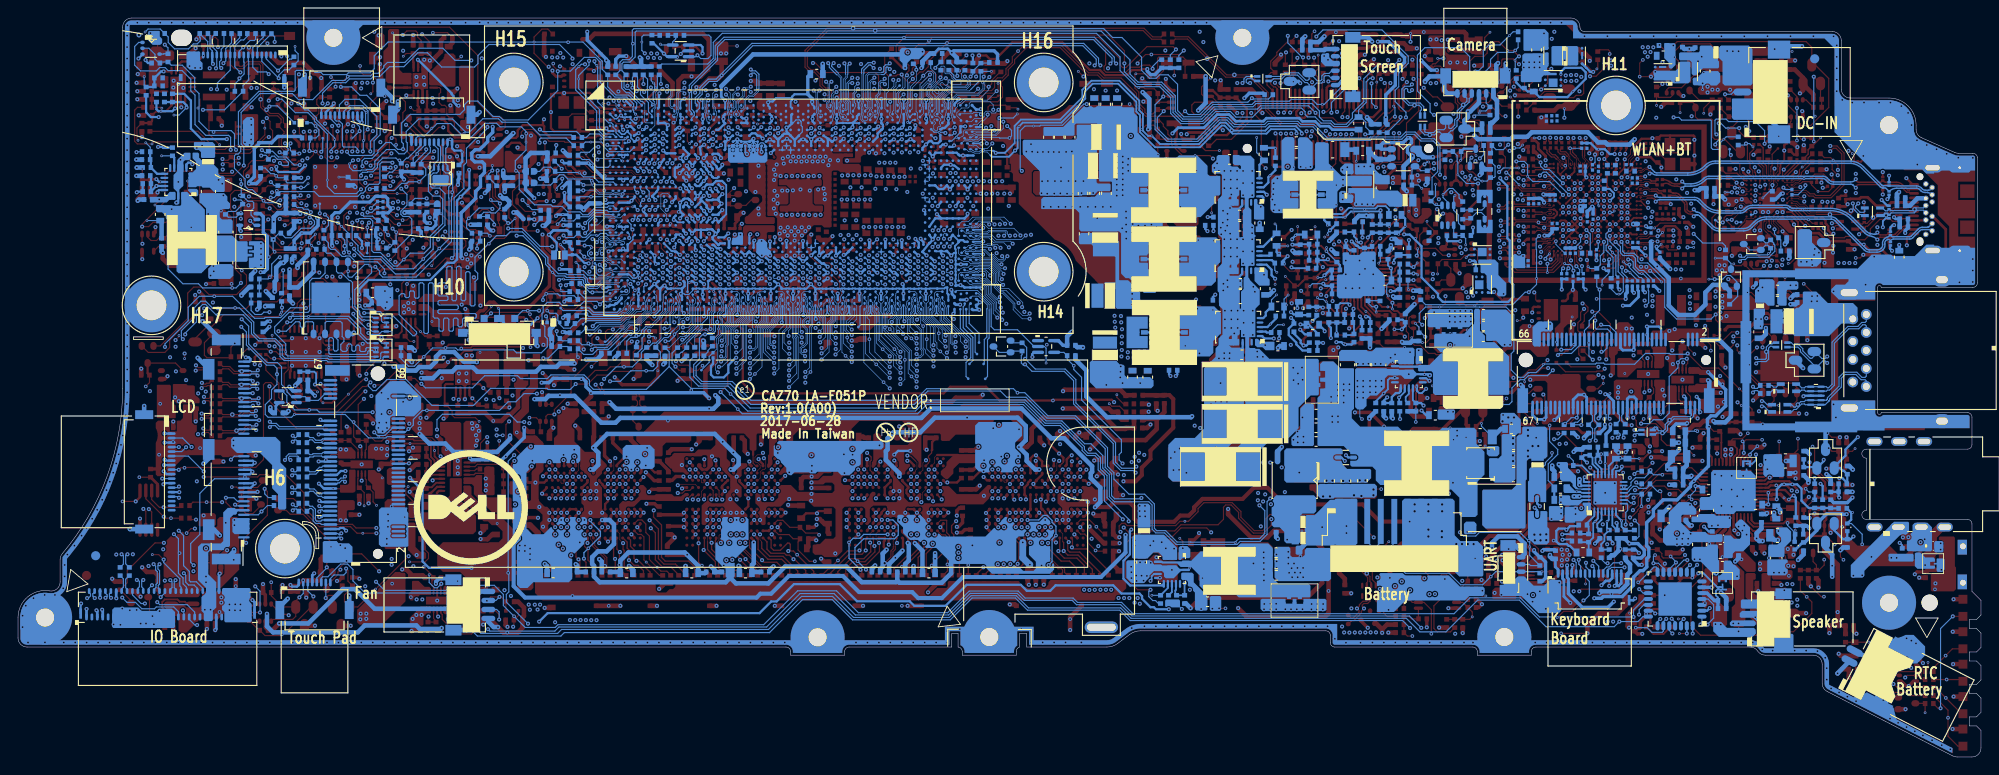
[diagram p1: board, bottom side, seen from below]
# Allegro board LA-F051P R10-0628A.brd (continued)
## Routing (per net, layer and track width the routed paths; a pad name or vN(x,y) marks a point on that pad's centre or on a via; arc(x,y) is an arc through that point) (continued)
PCIE_PRX_TBTX_N1: length 120.6
  TOP w0.127: CT3.1 46.99,68.32 46.99,68.53 v2(47.15,68.69)
  IN1 w0.091: v2(47.15,68.69) 46.93,68.47 46.93,68.12 47.02,68.03 49.07,68.03 50.74,69.69 53.35,69.69 55.89,72.24 57.5,72.24 58.13,71.6 58.13,71.2 59.27,70.07 61.83,70.07 63.35,68.55 72.41,68.55 74.22,70.37 83.09,70.37 83.51,70.79 85.37,70.79 85.74,70.42 86.93,70.42 87.6,71.09 92.44,71.09 92.94,71.59 100.3,71.59 100.63,71.26 105.44,71.26 108.99,74.81 108.99,75.57 109.6,76.18 115.67,76.18 116.07,75.78 116.07,75.1 116.45,74.71 120.98,74.71 121.45,74.24 121.89,74.24 122.18,74.53 122.18,75.65 122.51,75.98 123.73,75.98 123.97,76.22 129.85,76.22 130.34,75.73 130.34,74.08 130.55,73.87 135.42,73.87 135.9,73.39 136.84,73.39 137.15,73.7 137.15,74.33 138.63,75.82 142.04,75.82 143.4,74.46 143.4,72.84 145.21,71.03 145.21,68.43 144.9,68.12 144.63,68.12 v2(144.43,67.91)
  BOTTOM w0.127: v2(144.43,67.91) 144.7,67.64 UCPU1.H13
PCIE_PRX_TBTX_N1_C: length 3.2
  TOP w0.076: UT1.V22 45.78,65.56 45.78,66.57 45.87,66.65 45.92,66.65 45.92,66.66
  TOP w0.127: 45.92,66.66 45.93,66.67 45.94,66.67 46.18,66.91 46.7,66.91 46.94,67.15 46.94,67.38 CT3.2
PCIE_PRX_TBTX_N2: length 120.8
  TOP w0.127: CT7.1 44.02,68.35 44.02,68.54 v2(43.87,68.69)
  IN1 w0.091: v2(146.25,68.61) 146.06,68.81 145.94,68.81 145.84,68.71 145.84,68.31 144.86,67.33 144.06,67.33 143.71,67.67 143.71,70.14 143.42,70.43 143.42,71.68 142.56,72.55 142.56,73.01 141.92,73.65 141.92,74.17 141.08,75.02 139.47,75.02 138.79,74.33 138.79,73.06 137.72,71.99 129.4,71.99 128.92,71.51 127.76,71.51 127.38,71.89 126.49,71.89 126.09,71.49 123.72,71.49 122.56,72.66 122.56,73.12 122.23,73.44 121.13,73.44 120.64,73.93 115.29,73.93 115.09,74.13 112.27,74.13 111.44,73.3 108.61,73.3 105.77,70.45 100.29,70.45 100,70.75 93.52,70.75 93.04,70.27 87.88,70.27 87.25,69.63 85.34,69.63 84.99,69.99 83.85,69.99 83.41,69.55 79.55,69.55 77.76,67.76 62.96,67.76 61.44,69.29 58.92,69.29 57.88,70.33 55.09,70.33 53.67,68.91 51.37,68.91 49.57,67.11 45.7,67.11 45.11,67.71 44.45,67.71 44.08,68.08 44.08,68.48 v2(43.87,68.69)
  BOTTOM w0.127: v2(146.25,68.61) 146.12,68.61 UCPU1.G11
PCIE_PRX_TBTX_N2_C: length 2.6
  TOP w0.076: UT1.P22 43.58,65.49 43.58,65.49 43.49,65.58 43.49,66 44.03,66.55 44.03,66.64 44,66.68 44,66.7
  TOP w0.127: CT7.2 43.97,67.45 43.97,66.72 44,66.7
PCIE_PRX_TBTX_P1: length 120.5
  TOP w0.127: v2(46.57,68.69) 46.74,68.52 46.74,68.33 46.57,68.17 CT1.1
  IN1 w0.091: v2(46.57,68.69) 46.73,68.53 46.73,68.04 46.94,67.84 49.15,67.84 50.82,69.5 53.43,69.5 55.97,72.04 57.42,72.04 57.94,71.52 57.94,71.12 59.19,69.88 61.75,69.88 63.27,68.36 72.49,68.36 74.3,70.17 83.17,70.17 83.59,70.6 85.29,70.6 85.66,70.22 87.01,70.22 87.68,70.9 92.52,70.9 93.02,71.39 100.22,71.39 100.55,71.06 105.52,71.06 109.18,74.73 109.18,75.49 109.68,75.99 115.59,75.99 115.88,75.7 115.88,75.02 116.37,74.52 120.9,74.52 121.37,74.05 121.97,74.05 122.38,74.45 122.38,75.57 122.59,75.79 123.81,75.79 124.05,76.03 129.77,76.03 130.15,75.65 130.15,74 130.47,73.68 135.34,73.68 135.82,73.2 136.92,73.2 137.34,73.62 137.34,74.25 138.71,75.62 141.96,75.62 143.21,74.38 143.21,72.76 145.02,70.95 145.02,68.51 144.82,68.31 144.58,68.31 144.43,68.46 v2(144.43,68.65)
  BOTTOM w0.127: v2(144.43,68.65) 144.78,68.29 UCPU1.G13
PCIE_PRX_TBTX_P1_C: length 3.2
  TOP w0.076: 45.76,66.82 45.75,66.81 45.75,66.76 45.62,66.63 45.62,66.37 45.33,66.09 45.33,65.73 45.42,65.64 45.52,65.64 45.56,65.69 UT1.V23
  TOP w0.127: 45.76,66.82 45.76,66.85 46.08,67.16 46.59,67.16 46.68,67.25 46.68,67.41 CT1.2
PCIE_PRX_TBTX_P2: length 120.7
  TOP w0.127: v2(44.53,68.69) 44.4,68.69 44.27,68.56 44.27,68.31 44.41,68.17 CT5.1
  IN1 w0.091: v2(44.53,68.69) 44.27,68.44 44.27,68.16 44.53,67.9 45.19,67.9 45.78,67.31 49.49,67.31 51.29,69.1 53.59,69.1 55.01,70.52 57.96,70.52 58.02,70.46 59,69.48 61.52,69.48 63.04,67.95 77.68,67.95 79.47,69.75 83.33,69.75 83.77,70.18 85.07,70.18 85.42,69.82 87.17,69.82 87.8,70.46 92.96,70.46 93.44,70.94 100.08,70.94 100.37,70.65 105.69,70.65 108.53,73.49 111.36,73.49 112.19,74.32 115.17,74.32 115.37,74.12 120.72,74.12 121.21,73.63 122.31,73.63 122.75,73.2 122.75,72.74 123.8,71.69 126.01,71.69 126.41,72.08 127.46,72.08 127.84,71.7 128.84,71.7 129.32,72.19 137.64,72.19 138.59,73.14 138.59,74.41 139.39,75.21 141.16,75.21 142.11,74.25 142.11,73.73 142.75,73.09 142.75,72.63 143.61,71.76 143.61,70.51 143.91,70.22 143.91,67.75 144.14,67.52 144.78,67.52 145.64,68.39 145.64,68.79 145.86,69 145.98,69 v2(146.23,69.25)
  BOTTOM w0.127: v2(146.23,69.25) 146.11,69.25 UCPU1.F11
PCIE_PRX_TBTX_P2_C: length 2.8
  TOP w0.076: 44.23,66.72 44.23,66.71 44.2,66.69 44.2,66.48 43.89,66.17 43.89,66.06 43.97,65.98 43.97,65.64 43.92,65.59 43.79,65.59 43.72,65.66 UT1.P23
  TOP w0.127: CT5.2 44.29,67.59 44.23,67.52 44.23,66.72
PCIE_PRX_WLANTX_N5: length 132.1
  IN1 w0.091: v2(142.6,69.18) 142.6,69.32 142.46,69.46 142.28,69.46 142.05,69.7 142.05,69.96 142.04,69.97 142.04,70.37 142.25,70.58 142.25,71.02 141.96,71.31 138.94,71.31 137.98,70.35 137.48,70.35 137.35,70.21 136.4,70.21 136.3,70.32 135.05,70.32 134.95,70.21 132.8,70.21 132.24,70.77 131.08,70.77 130.52,70.21 129.13,70.21 129.08,70.27 123.19,70.27 121.93,71.52 118.45,71.52 117.77,72.21 112.8,72.21 111.15,70.56 109.62,70.56 108.43,69.38 108.05,69.38 107.4,68.73 100.17,68.73 99.52,69.38 94.03,69.38 92.99,68.33 80.01,68.33 78.22,66.54 65.31,66.54 64.15,65.38 64.15,63.28 64.31,63.12 64.31,62.14 63.48,61.3 63.48,59.13 62.48,58.13 62.48,56.07 62.21,55.8 62.21,53.13 61.51,52.42 56.01,52.42 54.37,50.78 51.07,50.78 50.66,50.37 49.26,50.37 46.18,47.28 46.18,45.03 46.52,44.69 46.52,42.82 44.71,41.02 44.71,40.95 44.69,40.93 44.69,39.9 42.82,38.03 41.73,38.03 41.58,37.88 41.58,37.73 v2(41.78,37.52)
  BOTTOM w0.127: JNGFF1.35 41.75,38.15 41.6,38 41.6,37.64 41.72,37.52 v2(41.78,37.52) ; UCPU1.F16 143.06,69.15 142.98,69.22 142.64,69.22 v2(142.6,69.18)
PCIE_PRX_WLANTX_P5: length 132.1
  IN1 w0.091: v2(41.2,37.52) 41.39,37.71 41.39,37.96 41.65,38.23 42.74,38.23 44.5,39.98 44.5,41.01 44.52,41.03 44.52,41.1 46.32,42.9 46.32,44.61 45.98,44.95 45.98,47.36 49.18,50.56 50.58,50.56 50.99,50.97 54.29,50.97 55.93,52.62 61.43,52.62 62.02,53.21 62.02,55.88 62.29,56.15 62.29,58.21 63.29,59.21 63.29,61.38 64.12,62.22 64.12,63.04 63.96,63.2 63.96,65.46 65.23,66.73 78.14,66.73 79.93,68.53 92.91,68.53 93.95,69.57 99.6,69.57 100.25,68.92 107.32,68.92 107.97,69.57 108.35,69.57 109.54,70.75 111.07,70.75 112.72,72.4 117.85,72.4 118.53,71.72 122.01,71.72 123.27,70.46 129.16,70.46 129.21,70.41 130.44,70.41 131,70.97 132.32,70.97 132.88,70.41 134.87,70.41 134.97,70.51 136.38,70.51 136.48,70.41 137.27,70.41 137.4,70.54 137.9,70.54 138.86,71.5 142.04,71.5 142.44,71.1 142.44,70.5 142.23,70.29 142.23,70.05 142.24,70.04 142.24,69.78 142.36,69.66 142.44,69.66 142.64,69.86 v2(142.64,69.87)
  BOTTOM w0.127: UCPU1.E16 142.9,69.59 142.64,69.85 v2(142.64,69.87) ; JNGFF1.33 41.25,38.1 41.35,38 41.35,37.67 v2(41.2,37.52)
PCIE_PTX_CARDRX_N6: length 113.7
  IN2 w0.102: v2(140.34,73.39) 140.44,73.39 140.7,73.65 140.7,73.83 141.61,74.74 143.19,74.74 143.69,75.24 144.07,75.24 144.22,75.09 152.47,75.09 152.79,74.76 158.37,74.76 161.48,71.65 164.3,71.65 166.04,73.39 169.44,73.39 169.99,73.95 177.4,73.95 179.26,72.1 179.83,72.1 180.8,71.13 186.65,71.13 189.97,67.81 189.97,65.54 191.39,64.12 191.39,63.38 191.56,63.21 191.56,60.75 192.45,59.86 192.45,58.74 192.33,58.62 192.33,57.42 192.76,56.99 192.76,53.3 192.36,52.9 192.36,47.52 194.06,45.82 194.06,37.11 195.51,35.65 195.51,31.88 200.32,27.07 202.11,27.07 205.83,23.35 205.83,22.66 v2(205.66,22.49)
  BOTTOM w0.076: UCPU1.D20 140.31,71.21 140.31,71.59 140.43,71.71 140.43,72.07 140.6,72.24 140.6,73.12 140.56,73.16 v2(140.34,73.39)
  BOTTOM w0.127: CH14.1 205.87,21.45 205.87,22.38 205.75,22.49 v2(205.66,22.49)
PCIE_PTX_CARDRX_N6_C: length 1.9
  BOTTOM w0.127: JIO1.16 205.71,18.62 205.87,18.78 205.87,19.72 CH14.2
PCIE_PTX_CARDRX_P6: length 113.7
  IN2 w0.102: v2(206.32,22.49) 206.06,22.76 206.06,23.44 202.2,27.3 200.41,27.3 195.73,31.97 195.73,35.75 194.28,37.2 194.28,45.91 192.58,47.61 192.58,52.81 192.98,53.21 192.98,57.09 192.56,57.51 192.56,58.53 192.67,58.65 192.67,59.96 191.78,60.85 191.78,63.3 191.61,63.48 191.61,64.21 190.19,65.63 190.19,67.9 186.74,71.35 180.89,71.35 179.92,72.32 179.35,72.32 177.5,74.18 169.9,74.18 169.34,73.62 165.95,73.62 164.21,71.88 161.57,71.88 158.46,74.99 152.89,74.99 152.56,75.31 144.31,75.31 144.16,75.47 143.6,75.47 143.09,74.96 141.52,74.96 140.58,74.03 140.55,74.03 140.55,74.02 v2(140.34,74.02)
  BOTTOM w0.076: UCPU1.C20 140.6,72 140.77,72.17 140.77,73.19 140.73,73.23 140.73,73.63 v2(140.34,74.02)
  BOTTOM w0.127: CH13.1 206.12,21.4 206.12,22.34 206.27,22.49 v2(206.32,22.49)
PCIE_PTX_CARDRX_P6_C: length 1.9
  BOTTOM w0.127: CH13.2 206.12,19.77 206.12,18.83 206.31,18.64 206.31,18.41 JIO1.14
PCIE_PTX_SSDRX_N9: length 94.1
  IN4 w0.091: v2(187.33,27.36) 187.33,27.5 187.2,27.63 186.86,27.63 186.6,27.89 186.6,28.39 186.97,28.76 187.66,28.76 188.02,29.13 188.02,30 187.55,30.47 185.92,30.47 183.67,32.72 183.67,37.14 182.37,38.44 182.37,43.73 181.58,44.53 179.99,44.53 179.06,45.46 177.61,45.46 176.86,46.22 176.86,48.75 177.46,49.34 177.46,50.47 176.33,51.6 176.33,51.77 174.69,53.41 174.69,55.5 173.99,56.2 173.99,56.57 173.58,56.98 172.78,56.98 172.19,57.57 172.19,57.93 172.18,57.93 172.18,57.95 170.72,59.41 170.72,60.98 170.11,61.59 170.11,63.41 170.27,63.56 170.27,64.64 168.18,66.73 168.18,68.41 167.06,69.53 167.06,70.04 165.41,71.69 161.35,71.69 159.68,73.35 159.68,74.24 158.46,75.47 153.13,75.47 152.69,75.9 147.51,75.9 147.18,76.23 146.06,76.23 145.77,76.52 140.9,76.52 138.71,74.33 138.71,74.08 138.45,73.82 138.11,73.82 137.92,73.63 v2(137.92,73.5)
  BOTTOM w0.076: v2(137.92,73.5) 138.09,73.67 138.18,73.67 138.39,73.46 138.39,72.95 138.22,72.79 138.22,72.07 138.39,71.9 138.62,71.9 138.68,71.84 UCPU1.B23
  BOTTOM w0.127: CD39.1 186.92,27.52 187.17,27.52 v2(187.33,27.36)
PCIE_PTX_SSDRX_N9_C: length 4.2
  BOTTOM w0.127: CD39.2 185.44,27.57 185.25,27.57 185.06,27.38 185.06,26.19 184.79,25.92 184.25,25.92 184.13,25.79 183.15,25.79 JNGFF2.11
PCIE_PTX_SSDRX_N10: length 88.3
  IN4 w0.091: v2(139.26,73.51) 139.83,74.08 139.83,74.58 141.17,75.93 145.52,75.93 145.81,75.65 146.93,75.65 147.28,75.29 152.46,75.29 152.88,74.88 158.21,74.88 159.09,73.99 159.09,73.11 161.1,71.1 165.14,71.1 166.38,69.85 166.38,69.26 167.44,68.2 167.44,66.63 169.63,64.44 169.63,63.82 169.49,63.68 169.49,61.36 170.11,60.74 170.11,59.16 171.6,57.68 171.6,56.84 173.92,54.51 173.92,52.93 174.97,51.89 174.97,51.38 175.73,50.62 175.73,48.86 175.12,48.26 175.12,47.51 176.07,46.57 176.07,45.89 177.08,44.87 178.75,44.87 179.72,43.9 181.15,43.9 181.78,43.28 181.78,37.96 182.92,36.83 182.92,32.64 186.02,29.53 187.16,29.53 v2(187.4,29.3)
  BOTTOM w0.076: v2(139.26,73.51) 138.95,73.2 138.95,72.7 139.11,72.54 139.11,72.17 139.1,72.14 139.08,72.08 139.08,71.89 139.08,71.89 139.11,71.8 139.11,71.55 139.11,71.52 139.1,71.5 139.06,71.38 139.05,71.35 139.03,71.27 138.97,71.07 138.97,70.96 138.93,70.82 138.93,70.62 UCPU1.D23
  BOTTOM w0.127: CD45.1 186.98,29.48 187.21,29.48 v2(187.4,29.3)
PCIE_PTX_SSDRX_N10_C: length 3
  BOTTOM w0.127: JNGFF2.23 183.15,28.79 184,28.79 184.14,28.93 184.49,28.93 184.83,29.27 185.05,29.49 185.43,29.49 CD45.2
PCIE_PTX_SSDRX_N11: length 97
  IN4 w0.091: v2(187.4,31.25) 187.6,31.45 187.81,31.45 188.01,31.66 188.01,32.17 187.66,32.52 186.49,32.52 185.36,33.65 185.36,37.27 183.18,39.46 183.18,44.3 181.51,45.97 181.51,47.19 180.82,47.87 180.31,47.87 179.64,47.2 179.64,46.95 179.28,46.6 179.04,46.6 179.04,46.6 178.72,46.6 178.37,46.95 178.37,51.44 175.54,54.27 175.54,56.78 172.91,59.4 172.91,59.91 170.92,61.9 170.92,63.08 171.07,63.23 171.07,65 170.5,65.57 170.5,67.39 168.77,69.12 168.77,70.88 166.83,72.82 166.83,75.6 164.42,78.01 160.15,78.01 159.37,77.23 157.43,77.23 157.38,77.17 157.2,77.17 156.34,76.31 154.6,76.31 154.2,76.71 147.8,76.71 147.5,77.02 146.43,77.02 146.15,77.3 140.52,77.3 138.07,74.85 137.33,74.85 136.76,74.28 136.6,74.28 v2(136.5,74.38)
  BOTTOM w0.076: v2(136.5,74.38) 136.64,74.24 137.05,74.24 137.4,73.89 137.4,73.39 138.06,72.73 138.06,71.9 138.25,71.71 138.25,71.62 138.41,71.47 138.41,71.21 138.12,70.92 UCPU1.D24
  BOTTOM w0.127: v2(187.4,31.25) 187.27,31.39 186.98,31.39 CD53.1
PCIE_PTX_SSDRX_N11_C: length 3
  BOTTOM w0.127: CD53.2 185.43,31.39 184.76,31.39 184.26,31.89 184.08,31.89 183.98,31.79 JNGFF2.35
PCIE_PTX_SSDRX_P9: length 94.2
  IN4 w0.091: v2(137.92,74.18) 138.09,74.01 138.37,74.01 138.52,74.16 138.52,74.41 140.82,76.71 145.85,76.71 146.14,76.43 147.26,76.43 147.59,76.1 152.77,76.1 153.21,75.66 158.54,75.66 159.88,74.32 159.88,73.43 161.43,71.88 165.49,71.88 167.25,70.12 167.25,69.61 168.38,68.49 168.38,66.81 170.46,64.72 170.46,63.48 170.31,63.33 170.31,61.67 170.92,61.06 170.92,59.49 172.37,58.03 172.37,58.01 172.38,58.01 172.38,57.65 172.86,57.17 173.66,57.17 174.18,56.65 174.18,56.28 174.88,55.58 174.88,53.49 176.52,51.85 176.52,51.68 177.65,50.55 177.65,49.26 177.05,48.67 177.05,46.3 177.69,45.66 179.14,45.66 180.07,44.72 181.66,44.72 182.57,43.81 182.57,38.52 183.86,37.22 183.86,32.8 186,30.67 187.63,30.67 188.21,30.08 188.21,29.05 187.74,28.57 187.05,28.57 186.79,28.31 186.79,27.97 186.94,27.82 187.12,27.82 v2(187.33,28.03)
  BOTTOM w0.076: UCPU1.A23 138.68,72.12 138.63,72.07 138.46,72.07 138.39,72.14 138.39,72.72 138.55,72.88 138.55,73.52 137.92,74.16 v2(137.92,74.18)
  BOTTOM w0.127: v2(187.33,28.03) 187.08,27.78 186.84,27.78 186.67,27.95 CD43.1
PCIE_PTX_SSDRX_P9_C: length 4.2
  BOTTOM w0.127: CD43.2 185.42,27.82 185.15,27.82 184.81,27.49 184.81,26.3 184.68,26.17 184.2,26.17 184.07,26.29 JNGFF2.13
PCIE_PTX_SSDRX_P10: length 88.3
  IN4 w0.091: v2(139.26,74.14) 139.35,74.05 139.53,74.05 139.63,74.16 139.63,74.66 141.09,76.12 145.6,76.12 145.89,75.84 147.01,75.84 147.36,75.49 152.54,75.49 152.96,75.07 158.29,75.07 159.29,74.07 159.29,73.19 161.18,71.29 165.22,71.29 166.58,69.93 166.58,69.34 167.63,68.28 167.63,66.71 169.82,64.52 169.82,63.74 169.69,63.6 169.69,61.44 170.31,60.82 170.31,59.24 171.79,57.76 171.79,56.92 174.12,54.59 174.12,53.01 175.16,51.97 175.16,51.46 175.92,50.7 175.92,48.78 175.32,48.18 175.32,47.59 176.26,46.65 176.26,45.97 177.16,45.07 178.83,45.07 179.8,44.1 181.23,44.1 181.98,43.36 181.98,38.04 183.11,36.91 183.11,32.72 186.1,29.73 187.2,29.73 v2(187.4,29.93)
  BOTTOM w0.076: UCPU1.C23 138.61,71.09 138.61,71.26 138.67,71.32 138.83,71.32 138.9,71.42 138.95,71.57 138.95,71.77 138.93,71.82 138.91,71.85 138.91,72.11 138.95,72.2 138.95,72.47 138.79,72.64 138.79,73.67 v2(139.26,74.14)
  BOTTOM w0.127: v2(187.4,29.93) 187.21,29.74 186.99,29.74 CD46.1
PCIE_PTX_SSDRX_P10_C: length 3
  BOTTOM w0.127: CD46.2 185.43,29.74 184.95,29.74 184.39,29.18 184.11,29.18 184,29.29 JNGFF2.25
PCIE_PTX_SSDRX_P11: length 97
  IN4 w0.091: v2(136.5,73.8) 136.5,73.62 136.6,73.52 136.8,73.52 136.96,73.67 136.96,74.2 137.41,74.66 138.15,74.66 140.6,77.11 146.07,77.11 146.35,76.82 147.42,76.82 147.72,76.52 154.12,76.52 154.52,76.12 156.42,76.12 157.28,76.98 157.46,76.98 157.51,77.04 159.45,77.04 160.23,77.82 164.34,77.82 166.63,75.52 166.63,72.74 168.58,70.8 168.58,69.04 170.31,67.31 170.31,65.49 170.88,64.92 170.88,63.31 170.72,63.16 170.72,61.82 172.72,59.83 172.72,59.32 175.35,56.7 175.35,54.19 178.17,51.36 178.17,46.87 178.64,46.41 179.37,46.41 179.83,46.87 179.83,47.12 180.39,47.68 180.74,47.68 181.31,47.11 181.31,45.89 182.98,44.22 182.98,39.38 185.17,37.19 185.17,33.57 186.41,32.33 187.58,32.33 187.82,32.09 187.82,31.74 187.73,31.65 187.57,31.65 v2(187.38,31.84)
  BOTTOM w0.076: UCPU1.C24 138.12,71.16 138.01,71.05 137.92,71.05 137.72,71.26 137.72,71.36 138,71.64 138,71.73 137.89,71.83 137.89,72.66 137.23,73.32 137.23,73.83 136.98,74.08 136.7,74.08 136.5,73.87 v2(136.5,73.8)
  BOTTOM w0.127: CD51.1 186.99,31.64 187.18,31.64 v2(187.38,31.84)
PCIE_PTX_SSDRX_P11_C: length 3
  BOTTOM w0.127: CD51.2 185.44,31.65 184.86,31.65 184.37,32.14 184.12,32.14 183.97,32.29 JNGFF2.37
PCIE_PTX_TBRX_N1: length 107.7
  TOP w0.127: v2(48.43,68.69) 48.33,68.69 48.22,68.58 48.22,68.37 CT4.2
  IN1 w0.091: v2(48.43,68.69) 48.17,68.95 48.17,69.5 48.33,69.66 50.14,69.66 50.73,70.25 52.77,70.25 55.15,72.63 58.18,72.63 60.35,70.47 62.05,70.47 62.78,69.74 71.87,69.74 72.92,70.8 82.93,70.8 83.34,71.21 85.6,71.21 85.97,70.83 86.78,70.83 88.02,72.07 93.16,72.07 95.52,74.43 96.21,74.43 98.13,76.35 98.13,76.52 v2(98.35,76.74)
  BOTTOM w0.127: v2(98.35,76.74) 98.17,76.92 98.17,77.43 99.67,78.93 136.28,78.93 140.25,74.96 141.12,74.96 141.89,74.2 141.89,73.56 142.41,73.04 142.41,72.78 142.22,72.58 142.22,71.96 UCPU1.B17
PCIE_PTX_TBRX_N1_C: length 3.3
  TOP w0.076: UT1.Y22 46.48,65.37 46.71,65.59 46.71,65.99 46.73,66.01 46.73,66.01 47.07,66.35 47.11,66.35 47.12,66.36 47.13,66.36
  TOP w0.127: 47.13,66.36 47.14,66.36 47.36,66.57 47.67,66.57 48.16,67.06 48.16,67.33 CT4.1
PCIE_PTX_TBRX_N2: length 114.1
  TOP w0.127: CT8.2 45.62,68.3 45.62,68.48 v2(45.82,68.69)
  IN1 w0.091: v2(45.82,68.69) 45.53,68.98 45.53,69.39 45.9,69.76 46.67,69.76 48.43,71.52 52.7,71.52 54.41,73.22 56.45,73.22 56.92,73.69 58.2,73.69 60.06,71.83 60.88,71.83 61.06,71.65 61.86,71.65 63.13,70.38 69.07,70.38 70.79,72.09 79.46,72.09 79.65,71.9 86.07,71.9 86.84,72.68 92.13,72.68 92.58,73.13 93.31,73.13 96.38,76.2 96.38,76.72 v2(96.6,76.95)
  BOTTOM w0.127: UCPU1.D16 143.07,70.88 142.77,71.19 142.77,71.49 142.82,71.55 142.82,71.63 143.07,71.88 143.07,74.43 140.2,77.31 140.2,78.8 139.38,79.62 98.49,79.62 96.42,77.55 96.42,77.12 v2(96.6,76.95)
PCIE_PTX_TBRX_N2_C: length 2.7
  TOP w0.076: 45.08,66.52 45.07,66.52 45.06,66.51 45.04,66.51 44.87,66.34 44.87,65.57 UT1.T22
  TOP w0.127: CT8.1 45.57,67.41 45.57,66.98 45.09,66.51 45.08,66.52
PCIE_PTX_TBRX_P1: length 107.7
  TOP w0.127: CT2.2 47.96,68.36 47.96,68.63 47.87,68.72 v2(47.8,68.72)
  IN1 w0.091: v2(97.71,76.74) 97.94,76.52 97.94,76.43 96.13,74.62 95.44,74.62 93.08,72.26 87.94,72.26 86.7,71.03 86.05,71.03 85.68,71.4 83.26,71.4 82.85,70.99 72.84,70.99 71.79,69.94 62.86,69.94 62.13,70.66 60.43,70.66 58.26,72.82 55.07,72.82 52.69,70.44 50.65,70.44 50.06,69.85 48.25,69.85 47.98,69.58 47.98,68.91 v2(47.8,68.72)
  BOTTOM w0.127: v2(97.71,76.74) 97.79,76.82 97.79,76.82 97.91,76.95 97.91,77.54 99.56,79.18 136.39,79.18 140.35,75.22 141.23,75.22 142.15,74.3 142.15,73.67 142.67,73.15 142.67,72.56 142.51,72.4 UCPU1.A17
PCIE_PTX_TBRX_P1_C: length 3.4
  TOP w0.076: UT1.Y23 46.48,65.67 46.43,65.62 46.33,65.62 46.25,65.7 46.25,65.99 46.38,66.13 46.61,66.13 46.95,66.46 46.95,66.51 46.96,66.52
  TOP w0.127: 46.96,66.52 46.96,66.54 47.25,66.83 47.57,66.83 47.9,67.16 47.9,67.46 CT2.1
PCIE_PTX_TBRX_P2: length 114.2
  TOP w0.127: CT6.2 45.16,68.17 45.36,68.37 45.36,68.54 v2(45.21,68.69)
  IN1 w0.091: v2(45.21,68.69) 45.25,68.69 45.34,68.78 45.34,69.47 45.82,69.95 46.59,69.95 48.35,71.71 52.62,71.71 54.33,73.41 56.37,73.41 56.84,73.89 58.28,73.89 60.14,72.02 60.96,72.02 61.14,71.84 61.94,71.84 63.21,70.57 68.99,70.57 70.71,72.29 79.54,72.29 79.73,72.09 85.99,72.09 86.76,72.87 92.05,72.87 92.5,73.32 93.23,73.32 96.18,76.28 96.18,76.72 v2(95.96,76.95)
  BOTTOM w0.127: v2(95.96,76.95) 96.16,77.15 96.16,77.65 98.38,79.87 139.49,79.87 140.45,78.91 140.45,77.41 143.33,74.53 143.33,71.78 143.07,71.53 UCPU1.C16
PCIE_PTX_TBRX_P2_C: length 2.7
  TOP w0.076: UT1.T23 44.64,65.69 44.59,65.64 44.5,65.64 44.42,65.73 44.42,65.98 44.7,66.27 44.7,66.41 44.9,66.61 44.9,66.68 44.91,66.69
  TOP w0.127: 44.91,66.69 45.31,67.09 45.31,67.38 CT6.1
PCIE_PTX_WLANRX_N5: length 134.2
  IN1 w0.091: v2(141.22,72.86) 141.22,72.94 141.08,73.08 140.89,73.08 140.69,72.88 140.69,72.64 140.05,72 138.67,72 138.05,71.38 129.62,71.38 129.16,70.92 127.51,70.92 127.15,71.28 126.75,71.28 126.31,70.85 123.44,70.85 122.18,72.11 118.7,72.11 117.5,73.31 115.01,73.31 114.91,73.41 112.7,73.41 111.95,72.66 108.82,72.66 106.01,69.86 100.03,69.86 99.8,70.09 93.73,70.09 92.66,69.02 91.05,69.02 90.4,69.68 88.13,69.68 87.39,68.94 79.78,68.94 77.99,67.15 65.01,67.15 63.22,65.36 63.22,62.33 62.27,61.38 62.27,58.85 61.89,58.48 61.89,56.31 61.58,56.01 61.58,55.37 59.3,53.08 54.1,53.08 53.38,52.36 51.8,52.36 50.4,50.96 49.02,50.96 45.46,47.41 45.46,44.91 45.93,44.45 45.93,43.14 44.07,41.28 44.07,40.8 42.19,38.92 41.63,38.92 40.69,37.98 40.69,37.17 40.01,36.48 40.01,35.65 40.21,35.44 v2(40.31,35.44)
  BOTTOM w0.076: UCPU1.C19 141.16,70.76 141.07,70.67 140.95,70.67 140.88,70.74 140.88,70.8 140.84,70.84 140.84,71.2 140.98,71.35 141.29,71.35 141.38,71.43 141.43,71.57 141.43,71.75 141.37,71.94 141.37,72.09 141.43,72.21 141.43,72.71 141.28,72.86 v2(141.22,72.86)
  BOTTOM w0.127: CH11.1 40.23,36.03 40.04,35.83 40.04,35.68 40.28,35.44 v2(40.31,35.44)
PCIE_PTX_WLANRX_N5_C: length 2
  BOTTOM w0.127: CH11.2 40.12,37.31 40.12,37.96 40.25,38.09 40.25,38.77 JNGFF1.29
PCIE_PTX_WLANRX_P5: length 134.1
  IN1 w0.091: v2(39.65,35.44) 39.81,35.6 39.81,36.56 40.5,37.25 40.5,38.06 41.55,39.11 42.11,39.11 43.88,40.88 43.88,41.36 45.73,43.22 45.73,44.37 45.27,44.83 45.27,47.49 48.94,51.15 50.32,51.15 51.72,52.55 53.3,52.55 54.02,53.28 59.22,53.28 61.39,55.45 61.39,56.09 61.7,56.39 61.7,58.56 62.08,58.93 62.08,61.46 63.03,62.41 63.03,65.44 64.93,67.34 77.91,67.34 79.7,69.14 87.31,69.14 88.05,69.87 90.48,69.87 91.13,69.21 92.58,69.21 93.65,70.28 99.88,70.28 100.11,70.05 105.93,70.05 108.74,72.86 111.87,72.86 112.62,73.61 114.99,73.61 115.09,73.51 117.58,73.51 118.78,72.31 122.26,72.31 123.52,71.04 126.23,71.04 126.67,71.47 127.23,71.47 127.59,71.11 129.08,71.11 129.54,71.58 137.97,71.58 138.59,72.2 139.97,72.2 140.5,72.72 140.5,72.96 140.81,73.28 141.11,73.28 v2(141.28,73.44)
  BOTTOM w0.076: UCPU1.D19 141.38,70.58 141.38,70.69 141.52,71.18 141.53,71.24 141.53,71.35 141.58,71.5 141.59,71.55 141.59,71.8 141.56,71.89 141.56,72.08 141.59,72.18 141.59,73.12 v2(141.28,73.44)
  BOTTOM w0.127: v2(39.65,35.44) 39.75,35.54 39.75,35.81 39.53,36.03 CH12.1
PCIE_PTX_WLANRX_P5_C: length 2
  BOTTOM w0.127: CH12.2 39.86,37.33 39.86,37.92 39.75,38.03 39.75,38.77 JNGFF1.27
PCIE_RBIAS: length 10
  TOP w0.203: UT1.N16 v2(43.13,63.02)
  TOP w0.305: v2(48.31,66.23) 48.31,66.68 49.12,67.49 49.12,68.08 49.56,68.51 RT1.2
  IN1 w0.203: v2(48.31,66.23) 47.31,66.23 46.04,64.96 45.06,64.96 44.26,64.16 44.26,64.15 v2(43.13,63.02)
PCIE_RCOMPN: length 1.9
  TOP w0.102: v1(148.51,69.63) 148.91,69.23 v2(148.95,69.23)
  TOP w0.305: v2(148.95,69.23) 149.52,69.23 RC45.1
  BOTTOM w0.254: UCPU1.F5 149.46,68.96 v2(148.95,69.23)
PCIE_RCOMPP: length 3.5
  TOP w0.102: RC45.2 149.3,70.21 148.87,70.63 148.87,70.99 149.21,71.33 v1(149.3,71.33)
  TOP w0.305: RC45.2 149.81,69.99 v2(150.22,69.99)
  BOTTOM w0.254: v2(150.22,69.99) 149.82,69.99 149.43,69.59 UCPU1.E5
PCIE_WAKE#: length 225.2
  TOP w0.127: v3(46.15,37) 45.67,37 45.62,37.05 45.02,37.65 v2(44.86,37.65) ; v2(186.46,62.32) 186.91,62.77 187.21,62.77 UE5.B8
  IN1 w0.089: v2(186.46,62.32) 186.21,62.32 185.76,61.86 182.55,61.86 181.64,60.94 181.64,58.99 181.28,58.63 179.88,58.63 177.76,56.51 177.76,53.42 177.19,52.85 176.2,52.85 175.13,51.78 175.13,50.96 175.54,50.55 175.54,49.32 173.73,47.51 173.73,46.84 172.11,45.22 172.11,43.57 171.7,43.17 171.7,39.54 169.9,37.74 169.9,35.17 172.31,32.76 172.31,21.17 171.7,20.56 162.89,20.56 161.39,19.06 158.71,19.06 158.09,18.44 147.8,18.44 147.19,17.83 132.2,17.83 131.96,18.08 126.77,18.08 125.92,17.23 118.55,17.23 117.08,18.7 109.84,18.7 109.72,18.82 106.73,18.82 106.62,18.7 102.66,18.7 101.45,19.91 96.49,19.91 94.18,22.22 92.58,22.22 89.19,25.6 82.86,25.6 81.98,24.71 79.29,24.71 78.61,25.4 76.13,25.4 71.34,20.61 69.26,20.61 66.9,18.25 66.35,18.25 64.52,20.08 63.29,20.08 62.42,20.95 54.98,20.95 54.46,20.43 51.97,20.43 50.9,19.37 49.64,19.37 49.42,19.15 47.99,19.15 47.22,18.38 45.8,18.38 45.41,17.99 43.75,17.99 43.54,18.2 43.54,19.17 42.05,20.65 42.05,21.78 41.67,22.16 41.1,22.16 37.59,25.67 37.59,28.82 37.47,28.94 37.47,31.05 39.26,32.84 40.2,32.84 42.34,34.98 42.34,35.42 44.58,37.65 v2(44.86,37.65)
  BOTTOM w0.127: v2(186.46,62.32) 186.6,62.17 RE86.1 ; RE120.2 45.47,37.65 v2(44.86,37.65) 44.75,37.76 JNGFF1.47
PD_EE_CLK: length 24.1
  TOP w0.127: U722.A3 26.15,63.61 v2(26.49,63.61) ; UT6.6 22.96,46.39 23.71,47.14 v1(25.71,47.14) 26.28,46.56 27.36,46.56 v2(27.47,46.67)
  IN1 w0.081: v2(26.49,63.61) 25.93,63.05 25.93,57.34 25.48,56.88 25.48,53.87 27.63,51.72 27.63,48.67 27.69,48.61 27.69,46.9 v2(27.47,46.67)
PD_EE_CS#: length 31.8
  TOP w0.076: U722.B3 v2(25.05,63.47)
  TOP w0.127: v2(24.85,45.45) 25.69,44.61 v1(25.69,43.52) 25.69,42.6 24.58,41.49 20.89,41.49 20.42,41.02 UT6.1 20.42,39.53 R1477.2
  IN1 w0.081: v2(25.05,63.47) 25.52,63.01 25.52,57.51 25.06,57.06 25.06,53.7 26.89,51.87 26.89,49.94 26.42,49.48 26.42,48.03 24.85,46.46 v2(24.85,45.45)
PD_EE_DI: length 26.6
  TOP w0.076: U722.B4 25.76,62.72 26.4,62.72 v2(26.44,62.76)
  TOP w0.127: v2(24.24,45.45) 24.23,45.45 UT6.5 25.17,46.34 v1(25.73,45.78)
  IN1 w0.081: v2(24.24,45.45) 24.24,44.9 24.46,44.67 26.65,44.67 27.98,46 27.98,48.62 27.84,48.76 27.84,51.81 25.69,53.96 25.69,56.8 26.14,57.25 26.14,62.42 26.44,62.72 v2(26.44,62.76)
PD_EE_DO: length 32.7
  TOP w0.127: R1475.2 27.71,64.32 v2(27.12,63.72) 27.12,63.62 26.7,63.21 26.25,63.21 U722.A4 ; v2(27.05,45.68) 27.05,45.12 v1(26.77,44.84) 26.07,44.14 26.07,42.6 24.66,41.19 22.06,41.19 21.69,40.83 UT6.2
  IN1 w0.081: v2(27.05,45.68) 26.37,46.35 26.37,47.69 26.63,47.94 26.63,49.39 27.1,49.86 27.1,51.96 25.27,53.78 25.27,56.97 25.73,57.42 25.73,63.4 26.33,64.01 26.83,64.01 v2(27.12,63.72)
PD_EE_WP#: length 2.6
  TOP w0.127: v1(22.46,39.02) R1474.2 22.96,39.53 UT6.3
PD_HOLD#: length 3.9
  TOP w0.127: v1(24.47,47.8) 24.25,48.02 23.39,48.02 R1476.2 22.57,47.2 22.01,47.2 21.69,46.88 UT6.7
PD_OVP: length 4.2
  TOP w0.127: PQ218.6 91.09,68.55 PR253.2 91.39,68.86 PR288.1 91.81,70.11 92.63,70.11 v1(93.14,69.6)
PD_SENSEN: length 0.5
  BOTTOM w0.127: v2(27.13,59.32) 27.1,59.34 TC45.1
PD_SENSEP: length 1.3
  TOP w0.076: v2(25.02,60.46) 25.51,59.97 U722.B10
  BOTTOM w0.127: TC44.1 25.3,60.18 v2(25.02,60.46)
PECI_EC: length 78.7
  IN2 w0.089: v2(160.05,65.79) 160.05,65.77 160.5,65.31 160.5,65.2 160.59,65.11 162.9,65.11 163.46,64.55 165.94,64.55 166.12,64.37 168.02,64.37 168.25,64.6 171.43,64.6 171.53,64.49 174.62,64.49 174.7,64.57 175.11,64.57 175.66,64.02 175.66,63.43 v2(175.29,63.06)
  IN4 w0.081: v2(120.7,75.14) 120.68,75.12 120.68,74.68 121.41,73.95 122.44,73.95 125.33,71.05 125.73,71.05 126.59,70.19 126.59,68.56 126.93,68.22 128.41,68.22 128.49,68.14 133.34,68.14 133.95,67.54 137.96,67.54 138.02,67.48 144.83,67.48 145.06,67.7 145.06,70.11 145.57,70.62 148.92,70.62 149.66,69.88 149.66,69.66 150.97,68.34 153.94,68.34 154.57,67.7 157.73,67.7 159.31,66.12 159.72,66.12 v2(160.05,65.79)
  BOTTOM w0.076: UCPU1.A54 121.34,72.47 121.45,72.58 121.45,73.64 120.63,74.46 120.63,75.07 v2(120.7,75.14)
  BOTTOM w0.127: RE61.2 174.12,58.07 174.12,59.69 174.42,59.99 175.09,59.99 175.33,60.22 175.33,60.56 174.66,61.24 174.66,62.43 v2(175.29,63.06)
PECI_EC_R: length 4.4
  TOP w0.127: v2(176.25,58.63) 176.48,58.86 176.48,59.09 176.91,59.52 UE5.A48
  BOTTOM w0.127: CE68.1 176.63,56.47 RE61.1 175.85,57.25 v3(175.85,58.24) 176.25,58.63 v2(176.25,58.63)
PME#: length 1.1
  TOP w0.127: v2(145.39,52.49) 145.5,52.49 T115.1
  BOTTOM w0.076: UCPU1.AU11 145.7,52.8 v2(145.39,52.49)
POWER_SW_IN#: length 15.2
  TOP w0.127: v2(185.92,59.48) 186.11,59.29 UE5.B67 ; RE31.2 189.81,53.32 CE49.1 ; RE31.2 188.95,53.45 v2(188.39,54.01) ; RE31.2 188.93,53.3 RE33.1
  IN2 w0.089: v2(188.39,54.01) 187.97,54.43 187.97,57.65 188.81,58.49 188.81,59.05 188.01,59.85 186.28,59.85 v2(185.92,59.48)
  BOTTOM w0.127: v2(188.39,54.01) 188.39,51.65 RE35.1
PRIM_CORE_B+: length 1.7
  TOP w0.127: PC1414.1 202.32,79.17 v3(202.79,79.64)
PRIM_CORE_EN: length 5.3
  TOP w0.254: v2(201.65,76.07) 200.85,76.07 PU1401.13
  BOTTOM w0.127: PR1412.2 203.81,74.56 v1(203.81,75.5)
  BOTTOM w0.254: PR1412.2 202.81,74.34 PC1412.1 PR1413.1 202.66,75.36 201.94,76.07 v2(201.65,76.07)
PRIM_CORE_FBS: length 5.6
  TOP w0.254: PU1401.5 199.28,72.47 199.11,72.31 v2(199.11,72.07)
  BOTTOM w0.127: v2(199.11,72.07) 199.95,71.23 v1(200.51,71.23)
  BOTTOM w0.254: PR1422.1 PR1421.1 199.48,72.68 199.11,72.31 v2(199.11,72.07)
PRIM_CORE_LPM: length 6
  TOP w0.254: PU1401.14 200.28,76.54 199.64,77.17 197.89,77.17 v1(197.23,77.83) PR1424.2 PR1411.2
PRIM_CORE_LX: length 1.1
  TOP w0.127: 197.62,73.01 197.62,72.24 v1(197.85,72.01)
PRIM_CORE_SNUB: length 4.6
  TOP w0.127: v1(195.44,67.94) 196.62,69.12 196.62,70.65 PC1419.1
  TOP w0.508: 196.57,71.97 196.44,71.84 PC1419.1
PRIM_CORE_SS: length 4.2
  TOP w0.203: v2(200.38,71.97) 200.28,72.07 200.28,72.4 PU1401.7
  BOTTOM w0.254: PC1420.1 202.45,71.88 202.24,71.66 v1(201.96,71.66) 200.69,71.66 v2(200.38,71.97)
PROG1_CORE: length 2.2
  TOP w0.203: PR1094.1 65.28,55.58 65.9,54.96 PU1000.32
PROG2_CORE: length 2.6
  TOP w0.203: PR1121.1 65,56.6 65.35,56.24 v1(65.4,56.24) 65.53,56.11 65.53,55.81 65.98,55.36 66.41,55.36 PU1000.31
PS_ID: length 195.4
  TOP w0.127: UE5.B24 183.61,67.63 183.74,67.5 183.74,66.56 183.29,66.1 182.83,66.1 v2(182.4,66.53) ; PR102.2 v1(22.44,68.88)
  TOP w0.254: v2(24.01,68.05) 23.44,68.61 PR102.2 24.19,68.88 PR103.2
  IN1 w0.081: v2(182.4,66.53) 182.47,66.53 182.86,66.15 183.21,66.15 183.54,66.48 183.54,69.46 184.18,70.11 184.18,72.37 v2(184.02,72.53)
  IN3 w0.089: v2(156.29,77.49) 155.99,77.49 155.37,78.11 151.76,78.11 150.94,78.94 130.21,78.94 130.09,78.81 92.45,78.81 89.57,75.94 84.34,75.94 84.16,75.75 80.28,75.75 79.31,76.73 72.09,76.73 71.44,77.38 70.04,77.38 68.68,78.74 63.27,78.74 62.76,78.23 62.43,78.23 61.96,78.7 56.79,78.7 53.31,75.23 53.31,72.19 52.75,71.62 44.98,71.62 42.16,68.8 39.19,68.8 37.54,70.46 35.85,70.46 34.76,71.55 31.81,71.55 29.59,69.33 29.44,69.33 29.35,69.24 v2(29.35,69.08)
  BOTTOM w0.127: v2(29.35,69.08) 29.39,69.08 29.52,69.21 29.52,70.66 29.39,70.79 28.28,70.79 28,70.51 25.02,70.51 24.01,69.49 v2(24.01,68.05) ; v2(184.02,72.53) 184.02,73.66 182.86,74.82 181.44,74.82 181.02,75.24 178.65,75.24 178.4,75.5 177.68,75.5 176.58,76.6 175,76.6 173.46,78.14 172.38,78.14 170.8,76.56 167.15,76.56 166.78,76.94 166.78,77.83 165.55,79.06 157.72,79.06 156.29,77.63 v2(156.29,77.49)
PSYS_CORE: length 4
  TOP w0.127: PR1083.2 64.26,49.01
  TOP w0.203: PU1000.1 67.16,50.66 66.45,49.95 v1(65.81,49.95) 65.56,49.95 65.1,49.49 64.75,49.49 64.26,49.01
PTP_DIS#: length 162.7
  BOTTOM w0.127: UE4.21 37.5,15.58 38.06,15.02 v2(40.13,15.02) 40.69,14.46 48.26,14.46 51.21,17.41 55.85,17.41 59.37,13.88 62.26,13.88 63.77,15.39 94.31,15.39 95.46,16.54 105.69,16.54 107.04,17.9 112.05,17.9 114.46,15.49 125.1,15.49 127.43,17.82 130.87,17.82 134.54,14.15 157.5,14.15 157.94,13.71 166.45,13.71 166.65,13.91 166.65,15.63 167.37,16.35 167.37,17.98 167.59,18.2 179.3,18.2 180.65,19.54 180.65,20.81 181.24,21.41 182.02,21.41 183.43,20 184,20 184.16,19.84 184.16,19.36 JTP1.6
PTP_INT#_EC: length 101.3
  TOP w0.127: v3(181.36,21.76) 182.04,21.08 v2(182.04,20.79) 182.31,20.52 182.31,20.24 183.57,18.98 Q40.1 ; RPE5.2 191.24,58.51 189.92,58.51 v2(188.47,57.06) ; UE5.B37 178.01,66.27 178.49,66.27 178.69,66.07 179.1,66.07 179.15,66.02 179.15,66 179.17,65.97 v2(179.17,65.96)
  IN1 w0.081: v2(182.04,20.79) 182.68,21.42 182.68,41.56 183.63,42.51 184.72,42.51 185.14,42.93 185.14,46.44 185.91,47.21 188.31,47.21 189.34,48.23 189.34,49.63 191.08,51.37 191.08,52.93 190.4,53.6 190.4,55.02 188.47,56.95 v2(188.47,57.06) ; v2(179.17,65.96) 179.09,66.05 178.55,66.05 177.44,64.93 177.44,63.5 176.82,62.89 176.21,62.89 175.43,63.68 174.56,63.68 173.78,62.89 173.78,61.21 173.69,61.12 173.69,59.54 172.33,58.18 172.33,53.62 v2(172.24,53.53)
  IN3 w0.089: v2(172.24,53.53) 171.56,53.53 171.25,53.84 169.02,53.84 164.61,49.43 161.16,49.43 160.85,49.11 159.44,49.11 v2(159.23,48.91)
  IN4 w0.081: v2(179.17,65.96) 179.17,65.27 179.28,65.16 180.16,65.16 183,62.32 183,59.14 183.58,58.57 186.56,58.57 188.08,57.06 v2(188.47,57.06)
  BOTTOM w0.127: DZ3.1 159.11,48.78 v2(159.23,48.91)
PTP_INT#_R: length 5.5
  TOP w0.127: Q40.3 183.02,20.52 v2(183.55,21.05) 183.55,21.51 183.08,21.98 R1299.2 v1(183.08,23.33)
  BOTTOM w0.127: v2(183.55,21.05) 183.55,20.98 184.66,19.87 184.66,19.36 JTP1.5
PWM1_IA: length 19.7
  TOP w0.127: v2(72.64,51.15) v1(72.64,50.51)
  TOP w0.203: PU1000.12 72.01,52.16 72.64,51.54 v2(72.64,51.15)
  IN3 w0.254: v2(79.73,61.72) 79.42,61.41 79.42,60.74 78.18,59.5 75.25,59.5 74.18,58.43 74.18,51.2 73.75,50.77 72.97,50.77 72.64,51.11 v2(72.64,51.15)
  BOTTOM w0.254: PU1102.1 79.76,62.21 79.63,62.09 79.63,61.82 v2(79.73,61.72)
PWM2_IA: length 10.9
  TOP w0.127: PU1000.13 72.03,52.56 72.59,52 v2(73.25,52) ; v2(78.32,53.07) v1(78.32,52.45)
  IN1 w0.254: v2(73.25,52) 74.32,53.07 v2(78.32,53.07)
  BOTTOM w0.254: PU1101.1 79.27,54.63 78.72,54.07 78.72,53.46 v2(78.32,53.07)
PWM_GT: length 20.4
  TOP w0.203: PU1000.22 70.36,56.52 71.04,57.21 v2(71.22,57.21)
  IN1 w0.254: v2(71.22,57.21) 71.22,56.89 71.12,56.79 71.12,51.69 70.79,51.36 70.79,50.33 71.67,49.46 71.67,48.83 72.59,47.91 73.15,47.91 74.65,46.41 77.14,46.41 77.58,45.97 78.23,45.97 78.47,46.21 v2(78.47,46.44)
  BOTTOM w0.254: PU1100.1 79.77,46.71 79.5,46.44 v2(78.47,46.44)
PWM_VSA: length 7.1
  TOP w0.203: PU1305.3 63.97,60.27 64.87,59.37 65.15,59.37 v1(65.66,58.86) 65.66,57.9 67.16,56.4 PU1000.30
PWR_SRC_LIMIT: length 115.3
  TOP w0.127: PR226.2 88.32,76.66 PD201.2 88.56,77.68 91.22,77.68 91.36,77.54 91.36,76.32 92.15,75.52 PR227.2 92.54,75.81 v1(93.78,75.81) 93.88,75.71 93.88,74.22 93.45,73.78 93.45,72.56 92.77,71.89 92.77,71.55 92.58,71.35 91.89,71.35 91.4,71.84 PC205.1 90.86,71.84 v2(90.68,71.66) 90.33,72.01 PU201.1 ; PR216.1 60.55,59.17 60.55,60.58 v2(60.35,60.79) ; U722.G10 23.01,60.04 v2(22.6,60.45)
  IN1 w0.081: v2(60.03,64.6) 60.11,64.6 60.38,64.33 60.38,62.65 60.54,62.49 60.54,60.87 60.46,60.79 v2(60.35,60.79)
  IN3 w0.089: v2(22.6,60.45) 23.27,59.78 24.53,59.78 27.19,57.11 29.49,57.11 33.77,52.83 37.97,52.83 38.06,52.74 38.06,50.9 39.89,49.07 42.88,49.07 43.19,48.76 45.12,48.76 47.08,50.72 50.42,50.72 55.63,55.93 55.63,56.8 56.63,57.8 59.24,57.8 60.64,59.2 60.64,60.45 60.35,60.73 v2(60.35,60.79)
  BOTTOM w0.127: v2(90.68,71.66) 91.39,70.95 91.39,69.75 90.2,68.56 87,68.56 84.62,70.94 83.57,70.94 82.81,70.19 79.5,70.19 79.15,70.54 75.79,70.54 75.44,70.19 74.02,70.19 72.5,68.68 67.88,68.68 67.76,68.8 64.38,68.8 63.83,69.35 62.79,69.35 62.04,68.6 60.66,68.6 60.03,67.98 v2(60.03,64.6)
PWR_SRC_ON: length 191.4
  TOP w0.127: v2(59.42,51.13) 59.42,50.37 59.86,49.93 v1(60.07,49.93) PR218.2 ; UE5.B42 178.26,63.77 178.47,63.56 179,63.56 179.16,63.72 179.26,63.72 v2(179.28,63.7)
  IN3 w0.089: v2(179.63,74.81) 179.63,75.1 179.97,75.45 180.61,75.45 180.91,75.14 180.91,74.63 180.37,74.09 180.37,74.08 179.92,73.63 179.3,73.63 178.92,74.01 177.68,74.01 176.95,74.74 174.7,74.74 174.24,74.28 174.03,74.28 173.14,73.39 172.95,73.39 172.35,72.79 172.35,72.37 171.97,71.99 171.01,71.99 169.88,73.13 169.88,73.55 169.49,73.55 169.36,73.69 167.44,73.69 166.62,72.88 165.82,72.88 164.77,71.83 160.99,71.83 160.34,72.48 160.15,72.48 157.47,75.15 152.68,75.15 151.54,76.3 145.78,76.3 145.5,76.58 137.66,76.58 137.29,76.95 131.7,76.95 131.05,76.29 123.96,76.29 123.45,75.79 122.49,75.79 122.23,75.52 122.23,74.57 121.8,74.15 120.2,74.15 119.76,74.58 116.94,74.58 116.74,74.38 112.07,74.38 111.31,73.62 109.56,73.62 109.41,73.47 108.16,73.47 105.95,71.25 102.19,71.25 100.17,73.28 95.39,73.28 93.89,74.77 91.72,74.77 91.36,74.41 89.91,74.41 89.02,73.52 80.31,73.52 78.61,75.21 76.73,75.21 76,74.48 75.96,74.48 75.75,74.27 71.07,74.27 70.56,74.78 70.56,74.85 69.54,75.87 66.23,75.87 65.95,75.59 65.58,75.59 63.33,73.33 62.38,73.33 62.29,73.42 62.29,75.23 62.21,75.31 60.29,75.31 59.77,74.79 59.77,73.29 59.56,73.08 55.36,73.08 54.86,72.58 54.86,69.73 56.04,68.54 56.28,68.54 57.94,66.88 57.94,64.14 56.84,63.03 56.84,62.34 57.99,61.19 60.75,61.19 60.85,61.09 60.85,57.03 59.46,55.63 59.46,55.2 59.22,54.97 59.22,51.33 v2(59.42,51.13)
  IN4 w0.089: v2(179.28,63.7) 179.26,63.72 179.16,63.72 179.06,63.62 178.35,63.62 178.1,63.86 178.1,68.86 177.69,69.27 177.69,71.04 177.5,71.23 177.5,72.14 178.33,72.98 178.33,73.52 v2(179.63,74.81)
PWR_SRC_ON_PC: length 53.6
  TOP w0.076: 24.77,59.17 24.77,59.72 U722.D10
  TOP w0.127: PR229.2 58.92,45.7 v2(58.9,45.72) v1(58.4,45.72) ; 24.77,59.17 25.12,58.81 v2(25.12,58.43)
  IN2 w0.254: v2(28.98,56.36) 28.98,57.59 28.14,58.43 v2(25.12,58.43)
  IN3 w0.127: v2(58.9,45.72) 58.64,45.45 55.61,45.45 53.9,47.16 50.88,47.16 49.02,45.3 49.02,42.36 47.56,40.9 41.7,40.9 39.44,43.16 38.85,43.16 38.13,43.89 37.25,43.89 37.12,43.76 36.82,43.76 36.25,44.33 36.25,44.6 33.3,47.54 33.3,52.66 29.55,56.41 29.03,56.41 v2(28.98,56.36)
PWR_TB_DOCK#: length 254
  IN1 w0.081: 176.07,44.46 176.68,45.07 180.49,45.07 181.86,46.44 181.86,48.42 182.65,49.21 182.65,50.06 182.51,50.2 182.51,50.2 182.51,53.54 182.39,53.66 182.39,53.99 182.85,54.44 185.03,54.44 188.52,50.96 v2(188.52,49.87)
  IN1 w0.089: v2(40.82,15.02) 40.82,14.72 41.47,14.07 42.57,14.07 42.63,14.13 43.98,14.13 44.23,13.88 50.14,13.88 51.14,14.88 53.89,14.88 54.59,14.18 58.57,14.18 59.31,14.92 66.22,14.92 66.43,15.12 70.44,15.12 71.03,15.71 94.04,15.71 94.84,16.51 100.72,16.51 101.35,15.88 109.1,15.88 109.57,16.35 115.17,16.35 117.36,14.16 126.31,14.16 127.79,15.63 130.94,15.63 131.71,14.87 151.45,14.87 152.67,16.09 158.65,16.09 159.25,15.49 161.43,15.49 162.39,16.46 165.59,16.46 166.02,16.03 167.62,16.03 168.34,15.31 169.13,15.31 169.85,16.03 171.7,16.03 171.9,16.23 174.62,16.23 177.37,18.98 178.2,18.98 178.69,19.48 178.69,20.37 179.41,21.09 179.41,24.85 175.27,28.99 175.27,34.5 174.94,34.82 174.94,38.97 175,39.03 175,40.59 175.76,41.34 175.76,42.93 175.45,43.24 175.45,43.84 176.07,44.46
  IN2 w0.089: v2(40.82,15.02) 40.41,15.43 40.03,15.43 38.91,16.54 37.82,16.54 33.21,21.15 33.21,21.9 34.37,23.06 34.37,25.27 33.79,25.85 33.79,30.36 35.27,31.84 35.27,32.03 34.77,32.53 34.77,38.85 34.3,39.32 34.3,40.89 34.87,41.46 34.87,43.66 33.53,45 33.53,46.44 32.96,47.01 32.65,47.01 32.65,47.76 31.17,49.25 31.17,57.34 v2(31.88,58.05)
  BOTTOM w0.127: R1440.2 28.35,56.7 28.68,57.03 30.86,57.03 v2(31.88,58.05) ; v1(188.58,49.36) 188.52,49.42 v2(188.52,49.87) 188.57,49.92 RE35.2
REM_DIODE1_N: length 74.7
  TOP w0.127: v2(138.35,63.13) 138.96,62.52 CE47.1 138.06,62.29 QE3.3 ; v2(186.55,65.7) 186.54,65.69 186.96,65.27 UE5.B13
  IN3 w0.127: v2(190.75,67.34) 191.21,67.8 191.21,69.3 188.48,72.03 184.95,72.03 184.73,72.25 184.73,72.78 184.15,73.36 181.3,73.36 180.45,72.52 177.54,72.52 177.34,72.32 174.46,72.32 173.05,70.9 172.19,70.9 171.81,70.52 171.81,69 171.48,68.67 169.44,68.67 168.93,69.17 166.77,69.17 165.8,68.2 163.57,68.2 162.33,66.96 159.72,66.96 157.86,65.1 157.86,62.65 157.33,62.11 153.54,62.11 151.7,60.27 145.41,60.27 144.84,60.84 142.95,60.84 142.45,61.34 141.38,61.34 140.69,62.04 139.06,62.04 138.48,62.62 138.48,63 v2(138.35,63.13)
  BOTTOM w0.127: v2(190.75,67.34) 190.7,67.34 190.42,67.06 190.26,67.06 190.09,67.22 CE58.1 189.56,67.22 188.92,66.58 188.07,66.58 187.18,65.7 v2(186.55,65.7)
REM_DIODE1_P: length 76.6
  TOP w0.127: v2(188.75,65.91) 188.37,65.52 UE5.A13 ; v2(138.39,61.8) 138.47,61.72 138.62,61.72 CE47.2 138.75,61.16 QE3.2 137.84,61.21 137.05,61.21 136.45,61.81 QE3.1
  IN3 w0.127: v2(138.39,61.8) 138.6,62.01 138.78,62.01 138.97,61.82 140.6,61.82 141.33,61.09 142.35,61.09 142.85,60.59 144.73,60.59 145.26,60.05 151.79,60.05 153.63,61.9 157.42,61.9 158.08,62.56 158.08,65.01 159.81,66.75 162.47,66.75 163.71,67.99 165.89,67.99 166.86,68.96 168.84,68.96 169.35,68.45 171.57,68.45 172.02,68.91 172.02,70.38 172.29,70.65 173.15,70.65 174.57,72.06 177.39,72.06 177.63,72.3 180.54,72.3 181.35,73.11 184.05,73.11 184.48,72.68 184.48,72.2 184.86,71.82 188.39,71.82 191,69.22 191,68.22 190.32,67.55 190.32,67.12 190.7,66.73 v2(190.83,66.73)
  BOTTOM w0.127: v2(190.83,66.73) 190.8,66.77 190.31,66.77 190.03,66.49 CE58.2 190.01,66.3 189.63,66.67 189.38,66.67 189.03,66.33 188.17,66.33 187.8,65.96 187.8,65.72 187.88,65.65 188.5,65.65 v2(188.75,65.91)
REM_DIODE2_N: length 313.6
  TOP w0.127: v2(186.25,66.2) 186.36,66.2 186.43,66.14 186.65,66.14 187.02,65.77 UE5.B14 ; v2(195.12,66.35) 194.98,66.21 194.53,66.21 CE67.1 193.85,66.28 193.53,66.28 v2(193.32,66.49)
  IN1 w0.127: v2(193.32,66.49) 193.13,66.3 192.93,66.3 192.92,66.3 190.59,66.3 189.05,67.84 188.57,67.84 187.69,66.96 187.69,66.56 187.33,66.2 v2(186.25,66.2) ; v2(93.73,32.22) 93.42,32.22 92.82,32.82 92.56,32.82 91.33,34.04 90.24,34.04 89.08,35.2 82.31,35.2 81.94,34.83 79.51,34.83 77.12,37.22 72.71,37.22 72.23,36.74 70.23,36.74 68.31,38.66 63.05,38.66 61.36,36.97 53.51,36.97 53.13,36.58 51.28,36.58 50.88,36.99 49.87,36.99 47.13,34.25 46.69,34.25 46.51,34.43 46.51,34.55 46.69,34.73 v2(46.76,34.73)
  IN2 w0.127: v2(106.06,44.19) 106.53,43.72 106.53,43.42 106.23,43.12 102.6,43.12 100.91,41.44 100.91,35.87 99.82,34.78 98.2,34.78 98.07,34.65 95.17,34.65 94.29,33.77 94.29,32.77 v2(94.23,32.72)
  IN3 w0.127: v2(94.23,32.72) 94.38,32.57 94.38,31.17 93.93,30.72 93.93,26.2 93.64,25.9 93.64,24.96 94.95,23.65 94.95,22.62 95.65,21.91 96.89,21.91 99.16,19.64 105.94,19.64 106.25,19.33 156.41,19.33 161.82,24.75 161.82,25.29 162.08,25.54 163.46,26.92 163.46,29.94 164.52,31 164.52,34.18 164.05,34.65 164.05,36.57 164.46,36.98 166.52,36.98 167.04,37.5 168.76,37.5 169.57,36.69 170.77,36.69 172.3,38.22 173.36,38.22 173.73,37.84 175.73,37.84 176.05,37.52 180.09,37.52 182,39.43 182,43.23 180.84,44.39 179.73,44.39 178.38,45.74 178.38,46.75 177.89,47.24 177.89,48.63 178.52,49.26 178.52,50.46 179.1,51.05 179.1,51.47 179.57,51.94 181.02,51.94 181.35,51.62 188.13,51.62 189.65,53.13 191.71,53.13 192.15,53.58 192.15,58.2 192.78,58.83 193.16,58.83 196.62,62.29 196.62,65.03 195.55,66.1 195.38,66.1 v2(195.12,66.35) ; v2(26.73,55.62) 27.2,55.15 27.2,54.85 26.81,54.46 26.81,48.44 29.18,46.07 30.82,46.07 31.81,45.08 31.81,42.39 34.98,39.23 38.59,39.23 39.85,37.96 39.85,36.74 40.41,36.18 45.67,36.18 46.53,35.31 46.53,34.96 v2(46.76,34.73)
  BOTTOM w0.127: QE4.3 107.43,45.96 CE48.2 105.89,45.45 105.89,44.36 v2(106.06,44.19) 104.92,43.05 101.61,43.05 100.43,41.87 100.43,39.29 96.03,34.89 96.03,32.72 95.35,32.04 93.91,32.04 v2(93.73,32.22) ; QE11.1 25.67,56.27 QE11.2 23.9,56.79 23.67,56.79 CE57.2 23.34,56.03 23.66,55.71 25.99,55.71 26.24,55.46 26.56,55.46 v2(26.73,55.62)
REM_DIODE2_P: length 313
  TOP w0.127: v2(195.1,65.77) 194.91,65.96 194.45,65.96 CE67.2 193.8,66.02 193.54,66.02 193.5,65.98 193.48,65.98 v2(193.32,65.83) ; UE5.A14 188.06,66.02 188.31,66.02 188.6,66.3 189.14,66.3 189.29,66.15 v2(189.41,66.15)
  IN1 w0.127: v2(193.32,65.83) 193.11,66.04 192.82,66.04 192.82,66.05 190.48,66.05 188.95,67.59 188.67,67.59 187.94,66.86 187.94,66.63 188.24,66.33 189.11,66.33 189.29,66.15 v2(189.41,66.15) ; v2(46.05,34.78) 46.25,34.58 46.25,34.32 46.58,33.99 47.23,33.99 49.98,36.74 50.77,36.74 51.18,36.33 53.24,36.33 53.62,36.71 61.47,36.71 63.16,38.4 68.21,38.4 70.12,36.49 72.33,36.49 72.81,36.97 77.01,36.97 79.4,34.58 82.04,34.58 82.41,34.95 88.98,34.95 90.13,33.79 91.23,33.79 92.45,32.57 92.71,32.57 93.73,31.56 v2(93.8,31.56)
  IN2 w0.127: v2(93.9,33.31) 94.03,33.44 94.03,33.87 95.07,34.91 97.96,34.91 98.09,35.04 99.72,35.04 100.66,35.98 100.66,41.54 102.5,43.38 105.88,43.38 v2(106.07,43.57)
  IN3 w0.127: v2(195.1,65.77) 195.22,65.89 195.23,65.88 195.46,65.88 196.41,64.94 196.41,62.38 193.07,59.05 192.69,59.05 191.94,58.29 191.94,53.67 191.62,53.35 189.56,53.35 188.04,51.83 181.44,51.83 181.11,52.16 179.48,52.16 178.89,51.56 178.89,51.14 178.3,50.55 178.3,49.35 177.67,48.72 177.67,47.15 178.16,46.66 178.16,45.65 179.64,44.17 180.75,44.17 181.78,43.14 181.78,39.52 180,37.74 176.14,37.74 175.82,38.06 173.82,38.06 173.45,38.43 172.21,38.43 170.68,36.9 169.66,36.9 168.85,37.72 166.95,37.72 166.43,37.2 164.37,37.2 163.84,36.66 163.84,34.56 164.31,34.09 164.31,31.09 163.24,30.03 163.24,27.04 161.61,25.41 161.61,24.84 156.32,19.55 106.34,19.55 106.03,19.86 99.24,19.86 96.98,22.13 95.74,22.13 95.16,22.71 95.16,23.74 93.85,25.05 93.85,25.82 94.15,26.11 94.15,30.63 94.6,31.08 94.6,32.02 94.68,32.09 94.68,33 94.38,33.3 93.92,33.3 v2(93.9,33.31) ; v2(46.05,34.78) 46.28,35.01 46.28,35.21 45.56,35.92 40.31,35.92 39.6,36.63 39.6,37.85 38.48,38.97 34.87,38.97 31.6,42.25 31.6,44.99 30.73,45.86 29.09,45.86 26.59,48.35 26.59,54.85 v2(26.75,55)
  BOTTOM w0.127: v2(26.75,55) 26.54,55.2 26.14,55.2 25.88,55.46 23.53,55.46 22.87,56.12 22.87,56.8 22.97,56.9 23,56.9 23,57.03 CE57.1 23.67,57.04 23.9,57.04 QE11.3 ; QE4.1 108.93,44.9 107.68,44.9 QE4.2 107.53,45.04 CE48.1 106.4,44.64 106.48,44.55 106.48,43.71 106.27,43.49 106.15,43.49 v2(106.07,43.57) 105.3,42.8 101.72,42.8 100.69,41.76 100.69,39.19 96.28,34.79 96.28,32.61 95.45,31.78 94.03,31.78 v2(93.8,31.56)
REM_DIODE3_N: length 64.9
  TOP w0.127: v2(153.06,41.39) 153.06,40.91 152.68,40.52 149.17,40.52 148.9,40.25 148.9,40.04 148.69,39.84 CE66.2 148.82,39.56 148.82,39.08 148.3,38.56 QE10.3 ; v2(188.79,67.11) 188.79,67.08 188.23,66.52 188.06,66.52 UE5.A15
  IN3 w0.127: v2(153.06,41.39) 153.21,41.39 153.31,41.49 153.31,41.74 153.64,42.07 154.86,42.07 155.11,42.33 156.36,42.33 158.85,44.81 158.85,45.98 160.59,47.72 161.27,47.72 162.15,48.6 165.73,48.6 167.11,49.97 167.11,50.61 169.29,52.79 170.97,52.79 171.31,52.46 172.87,52.46 173.58,53.17 175.75,53.17 177.82,55.24 180.66,55.24 180.96,55.54 181.84,55.54 182.09,55.79 182.09,56.35 181.76,56.67 181.76,58.4 181.67,58.5 181.67,64 183.49,65.82 183.49,67.53 184.1,68.13 186.53,68.13 187.15,68.75 187.7,68.75 187.97,68.48 187.97,68.31 v2(188.18,68.1)
  BOTTOM w0.127: v2(188.79,67.11) 188.7,67.01 CE39.1 188.12,67.01 187.84,67.3 187.84,67.49 187.97,67.62 187.97,67.89 v2(188.18,68.1)
REM_DIODE3_P: length 66.2
  TOP w0.127: QE10.1 149.6,37.31 QE10.2 149.07,39.08 149.07,39.46 CE66.1 149.32,39.84 149.15,40 149.15,40.14 149.28,40.27 152.78,40.27 153.31,40.8 153.31,40.9 v2(153.72,41.31) ; UE5.B16 186.69,66.77 186.58,66.88 186.58,66.9 186.59,66.91 v2(186.59,66.96)
  IN3 w0.127: v2(153.72,41.31) 153.53,41.5 153.53,41.66 153.73,41.86 154.95,41.86 155.2,42.11 156.45,42.11 159.06,44.72 159.06,45.89 160.68,47.5 161.36,47.5 162.24,48.38 165.82,48.38 167.32,49.88 167.32,50.52 169.38,52.57 170.88,52.57 171.22,52.24 172.96,52.24 173.67,52.96 175.84,52.96 177.91,55.02 180.75,55.02 181.05,55.33 181.93,55.33 182.3,55.7 182.3,56.44 181.98,56.76 181.98,58.49 181.89,58.59 181.89,63.91 183.71,65.73 183.71,67.44 184.19,67.92 186.62,67.92 187.24,68.53 187.61,68.53 187.75,68.39 187.75,68.27 v2(187.58,68.09)
  BOTTOM w0.127: v2(187.58,68.09) 187.58,68.08 187.59,68.08 187.71,67.96 187.71,67.73 187.58,67.6 187.58,67.3 187.3,67.01 CE39.2 186.65,67.01 v2(186.59,66.96)
REM_DIODE4_N: length 17.4
  TOP w0.127: UE5.A16 188.85,67.81 188.85,68.64 188.29,69.2 188.29,69.4 CE60.1 188.62,70.39 188.62,70.77 189.01,71.15 189.93,71.15 190.89,72.12 v4(190.89,72.98) 190.89,76.73 191.06,76.89 192.33,76.89 192.83,76.39 193.8,76.39 194.34,76.92 CE51.1 194.41,77.93 QE8.3
REM_DIODE4_P: length 19.2
  TOP w0.127: QE8.1 193.9,78.72 QE8.2 193.5,77.82 CE51.2 193.22,76.64 192.94,76.64 192.43,77.15 190.95,77.15 190.64,76.83 190.64,72.23 v4(190.24,71.82) 189.82,71.41 188.9,71.41 188.37,70.87 188.37,70.39 CE60.2 188.04,69.09 188.6,68.53 188.6,67.92 188.08,67.4 187.63,67.4 187.51,67.27 187.21,67.27 UE5.B17
RESET_OUT#: length 164.4
  TOP w0.127: v2(175.09,67.45) 174.9,67.45 174.12,66.67 RE2.2 ; v2(157.92,76.1) 157.92,76.17 158.42,76.67 v3(158.42,76.95) ; v2(65.79,77.33) 65.79,76.84 RC129.1 ; UE5.B39 178.32,65.27 178.49,65.11 179.1,65.11 179.55,65.57 179.6,65.57 179.6,65.55 v2(179.59,65.55)
  IN3 w0.089: v2(65.79,77.33) 64.38,75.92 62.94,75.92 62.5,75.48 62.5,74.07 62.97,73.61 63.3,73.61 65.78,76.08 70.73,76.08 72.25,74.56 73.08,74.56 73.95,75.43 78.7,75.43 80.4,73.74 88.93,73.74 89.82,74.63 91.27,74.63 92.34,75.7 92.74,75.7 92.99,75.94 93.62,75.94 93.87,75.7 98.27,75.7 102.3,71.67 106.06,71.67 108.81,74.42 109.32,74.42 109.77,73.97 110.27,73.97 110.57,74.26 110.57,74.42 110.75,74.6 116.64,74.6 116.84,74.8 119.85,74.8 119.94,74.72 120.94,74.72 121.25,75.03 121.25,75.7 121.72,76.17 121.72,77.06 122.35,77.69 128.48,77.69 129.01,77.16 129.01,76.91 129.31,76.61 129.92,76.61 130.33,77.02 130.33,77.6 130.56,77.83 137.04,77.83 137.94,76.93 145.46,76.93 145.81,76.57 151.57,76.57 152.64,75.5 157.21,75.5 157.52,75.82 157.52,75.94 157.68,76.1 v2(157.92,76.1)
  BOTTOM w0.127: UCPU1.B6 149.5,71.57 149.5,71.74 149.57,71.81 149.57,72.15 149.5,72.23 149.5,72.47 150.26,73.23 151.58,73.23 153.21,74.86 153.21,77.11 153.73,77.63 154.99,77.63 156.5,76.12 157.9,76.12 v2(157.92,76.1) 157.93,76.09 157.93,73.95 161.19,70.69 164,70.69 164.39,71.08 165.09,71.08 166.79,72.78 167.88,72.78 168.27,72.39 168.27,71.82 168.78,71.31 174.28,71.31 175.24,70.34 175.24,68.25 175.06,68.07 175.06,67.48 v2(175.09,67.45) 175.12,67.42 175.68,67.42 176.44,68.19 176.98,68.19 177.88,67.29 177.88,67.06 178.51,66.42 179.36,66.42 179.63,66.16 179.63,65.6 v2(179.59,65.55)
RESET_OUT#_R: length 4.8
  TOP w0.127: RC128.2 RC129.2 CC33.1 67.04,75.56 v1(67.04,74.89) 67.04,74.56 67.1,74.51 JXDP1.47
RING2:
  vias: v2(8.06,24.39) v2(8.66,24.37) v2(28.36,34.11) v2(28.37,33.49)
RING2_R: length 4.2
  TOP w1.016: 5.82,22.31 5.4,22.73 5.4,24.56 4.45,25.51 JHP1.4
  vias: v3(15.42,25.53)
RTD3_CIO_PWR_EN: length 246.1
  TOP w0.127: v2(39.84,54.33) 39.9,54.39 39.94,54.39 40.15,54.61 40.15,55.19 40.05,55.3 40.05,55.68 UT1.F1 ; v2(67.39,24.37) 69.93,26.91 78.89,26.91 79.32,26.48 79.32,25.49 79.7,25.12 80.64,25.12 82.12,26.6 82.12,27.24 83.09,28.22 86.22,28.22 86.87,27.56 86.87,27.22 87.94,26.15 v1(88.34,26.15) 88.88,26.15 89.36,25.67 94.73,25.67 94.99,25.93 95.34,25.93 95.63,25.64 95.63,25.13 v2(95.48,24.98)
  IN1 w0.081: v2(159.93,68.17) 158.8,67.03 158.8,65.25 157.87,64.33 157.87,63.02 157.74,62.89 157.74,62.13 156.16,60.55 156.16,55.59 v2(154.94,54.36)
  IN2 w0.089: v2(39.84,54.33) 40.08,54.33 41.17,53.24 41.17,50 39.74,48.58 39.74,47.32 39.13,46.71 39.13,41.43 38.39,40.69 38.39,39.69 38.01,39.31 38.01,37.61 38.41,37.22 38.94,37.22 39.19,36.97 39.19,36.58 38.86,36.25 38.86,34.91 38.53,34.58 38.53,32.04 37.44,30.95 37.44,23.31 37.1,22.97 37.1,21.96 37.34,21.73 37.9,21.73 39.45,20.18 51.04,20.18 51.58,20.71 61.27,20.71 64.92,24.37 v2(67.39,24.37) ; v2(154.94,54.36) 155.02,54.29 155.94,54.29 156.72,55.08 157.66,55.08 158.33,54.41 158.33,52.56 163.97,46.92 163.97,42.38 162.2,40.61 162.2,38.95 163.77,37.38 163.77,35.21 162.32,33.76 162.32,32.46 164.17,30.6 164.17,21.34 161.96,19.12 158.66,19.12 156.8,17.27 132.09,17.27 131.1,18.26 127.05,18.26 126.79,18 126.79,18 124.94,16.15 118.4,16.15 116.13,18.42 108.02,18.42 107.13,18.42 106.69,17.98 102.85,17.98 98.55,22.27 98.55,23.38 97.43,24.49 96.22,24.49 95.73,24.98 v2(95.48,24.98)
  BOTTOM w0.127: RT39.2 RT26.2 39.27,53.22 39.84,53.79 v2(39.84,54.33) ; v2(159.93,68.17) 159.93,68.55 159.8,68.68 156.99,68.68 RC248.2
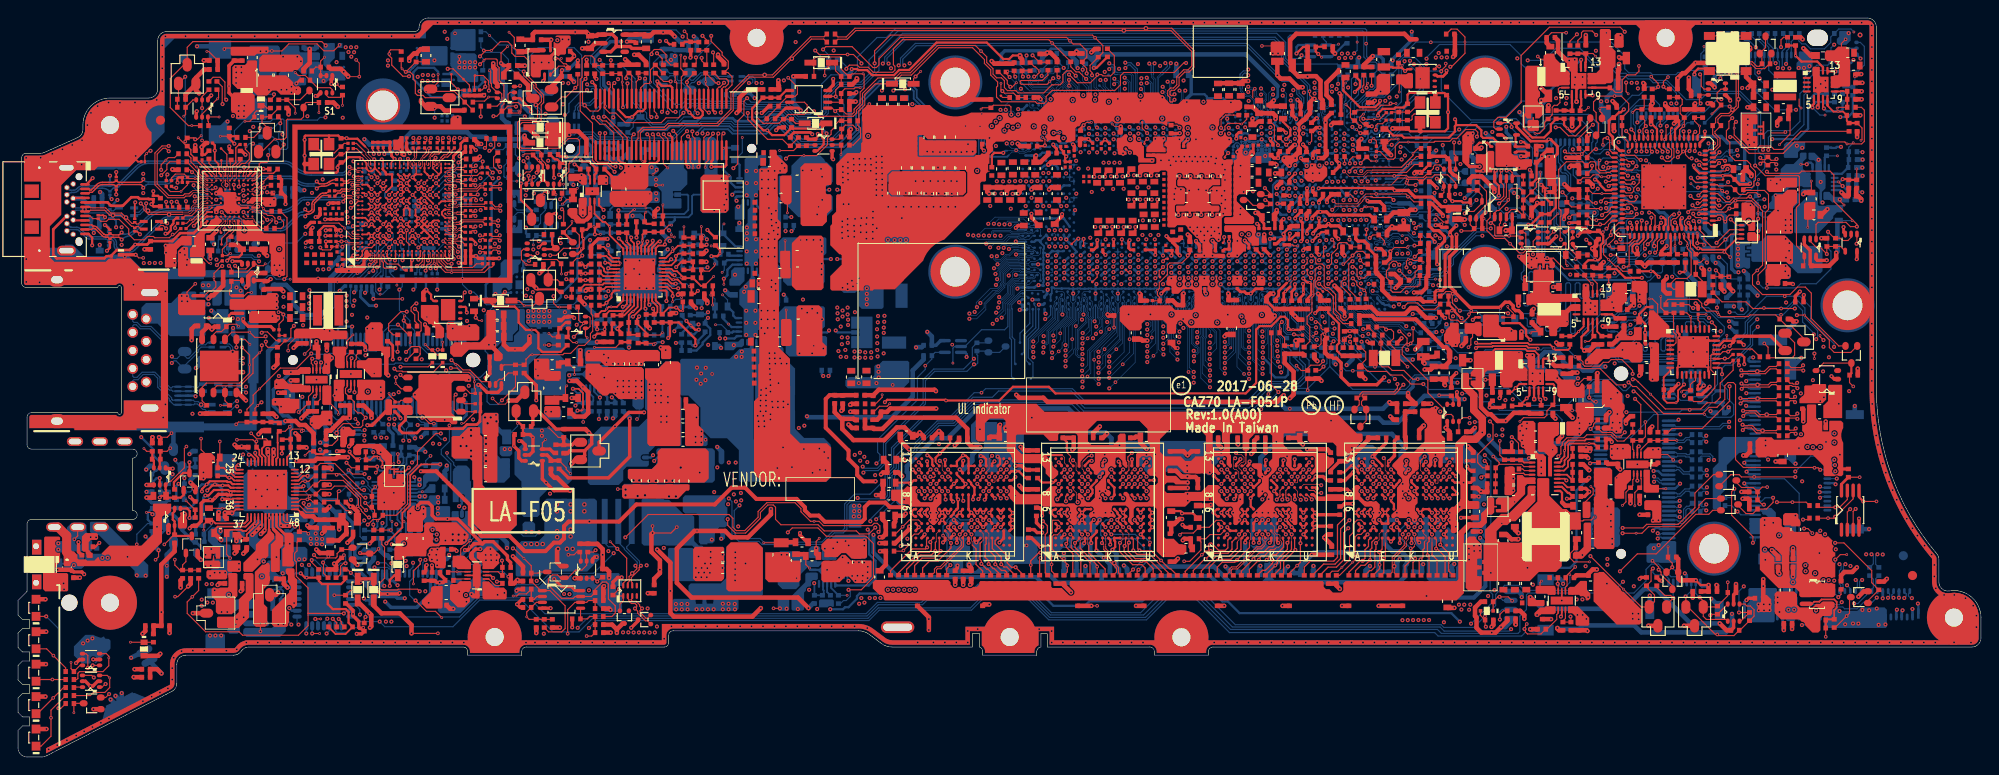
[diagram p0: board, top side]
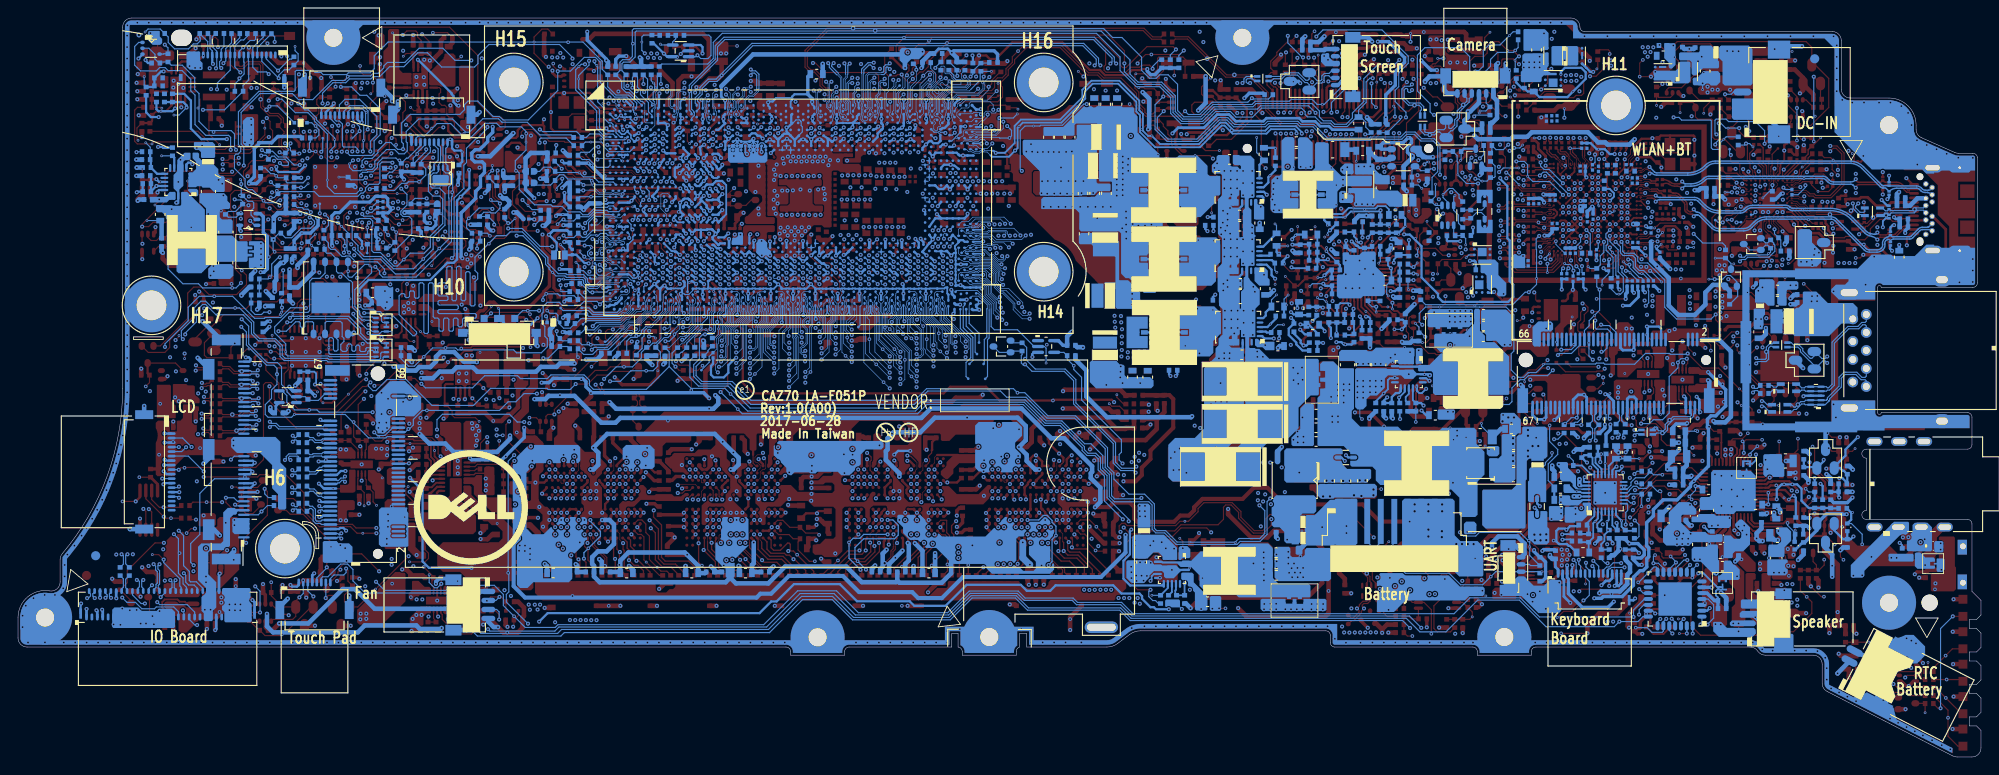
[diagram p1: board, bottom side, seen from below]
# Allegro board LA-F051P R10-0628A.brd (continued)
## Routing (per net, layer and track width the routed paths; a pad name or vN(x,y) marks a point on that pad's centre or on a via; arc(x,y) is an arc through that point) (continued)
RTD3_USB_PWR_EN: length 11.2
  TOP w0.127: UT1.D4 39.22,57.16 39.22,57.16 v2(39.23,57.17) ; RT52.2 34.82,56.63 RT40.2 34.81,56.41 34.67,56.27 33.77,56.27 33.57,56.47 33.57,56.49 v2(33.54,56.53)
  IN2 w0.127: v2(33.54,56.53) 34.39,56.53 34.63,56.78 34.63,58.17 35.33,58.87 35.97,58.87 36.44,58.4 36.44,57.95 37.26,57.12 39.18,57.12 v2(39.23,57.17)
RUN_ON: length 2.6
  TOP w0.127: UE5.B9 187.21,63.27 186.5,63.27 v2(186.41,63.19)
  BOTTOM w0.127: v1(185.62,63.61) 186.05,63.19 v2(186.41,63.19) 187.14,63.19 R250.2
RUN_ON#: length 4.7
  TOP w0.127: QE12.6 QE12.5 188.96,74.11 188.53,73.68 188.53,72.8 RE84.2 188.94,72.35 v1(187.96,71.36)
RUN_ON_EC: length 30
  TOP w0.127: v2(186.64,75.75) 186.77,75.62 186.77,74.43 187.09,74.11 187.55,74.11 QE12.2
  IN1 w0.081: v2(189.75,63.8) 191.76,63.8 192.01,64.06 192.56,64.06 v2(193.04,63.58)
  IN4 w0.081: v2(186.64,75.75) 186.58,75.75 184.42,73.59 184.42,71.09 185.71,69.8 187.38,69.8 190.09,67.09 190.09,64.14 v2(189.75,63.8)
  BOTTOM w0.127: v2(189.75,63.8) 189.36,63.41 R249.1 188.27,63.41 R250.1 ; UC10.2 191.45,59.65 191.95,60.15 191.95,60.62 191.66,60.91 191.66,61.51 191.81,61.66 192.29,61.66 RE98.2 193.04,62.42 v2(193.04,63.58) 193.04,63.99 v1(193.14,64.09)
RUN_ON_P: length 383.2
  TOP w0.127: U720.5 37.33,40.48 v2(37.34,40.47) ; PR901.1 173.65,43.83 173.65,43.57 173.85,43.37 175.47,43.37 175.9,43.8 176.48,43.8 176.78,44.09 177.96,44.09 179.16,42.9 v2(179.16,42.51) ; U719.3 52.23,19.75 52.95,19.03 53.52,19.03 R290.2 53.55,19.46 v2(53.14,19.46) ; v2(178.28,80.48) 177.78,80.98 169.93,80.98 166.79,77.85 166.79,72.63 165.13,70.98 164.21,70.98 163.75,70.52 163.75,69.88 163.96,69.68 164.38,69.68 UC9.2 ; v2(179.43,39.74) 180.06,39.1 R1445.1 ; v2(162.73,32.86) 163.04,32.55 PR611.1 162.53,32.09 161.97,32.65 161.97,33.55 163.67,35.25 163.67,36.89 v2(163.32,37.24)
  IN2 w0.089: v2(77.59,32.14) 78.85,32.14 81.53,29.45 81.53,25.89 80.75,25.1 79.5,25.1 79.32,25.28 75.7,25.28 74.05,23.63 65.48,23.63 64.69,22.84 64.69,22.08 64.24,21.62 63.33,21.62 61.98,20.28 55.22,20.28 54.74,19.8 53.48,19.8 v2(53.14,19.46) ; v2(162.73,32.86) 164.39,31.2 164.39,21.25 162.05,18.9 158.75,18.9 156.9,17.05 151.94,17.05 150.97,16.08 132.97,16.08 131.01,18.04 127.14,18.04 125.03,15.93 118.31,15.93 116.04,18.2 107.94,18.2 107.94,18.2 107.22,18.2 106.78,17.76 102.76,17.76 98.34,22.18 98.34,23.01 v2(97.94,23.4)
  IN3 w0.089: v2(163.32,37.24) 163.89,37.81 166.17,37.81 166.7,38.34 170.79,38.34 171.5,39.05 173.7,39.05 174.08,38.67 180.06,38.67 180.95,39.56 180.95,43.11 180.49,43.56 179.38,43.56 176.93,46.01 176.93,48.85 177.66,49.58 177.66,50.79 178.14,51.27 178.14,51.68 179.23,52.77 181.37,52.77 181.69,52.45 187.73,52.45 189.44,54.16 189.44,57.85 191.9,60.31 192.48,60.31 193.77,61.6 v2(193.77,61.88) ; v2(97.94,23.4) 97.05,24.29 97.05,33.89 96.1,34.84 90.16,34.84 89.96,35.04 87.78,35.04 86.64,36.18 v2(86.64,36.51) ; v2(162.73,32.86) 161.96,32.86 161.62,33.19 161.62,34.64 160.62,35.64 160.62,37.39 162.49,39.25 163.61,39.25 164.18,38.68 165.81,38.68 166.39,39.25 170.48,39.25 171.14,39.91 173.71,39.91 174.35,40.55 176.54,40.55 177.52,39.57 179.33,39.57 179.43,39.67 v2(179.43,39.74) 179.5,39.74 179.52,39.76 179.79,39.76 179.88,39.85 179.88,41.78 179.16,42.5 179.16,42.51 v2(179.16,42.51)
  IN4 w0.081: v2(53.14,19.46) 52.38,18.7 49.54,18.7 48.74,17.9 46.62,17.9 45.5,19.01 43.33,19.01 41.64,20.7 41.22,20.7 40.8,21.13 40.8,22.32 40.23,22.88 40.23,24.05 41.15,24.97 41.15,26.4 39.6,27.96 39.6,31.29 37.91,32.98 37.91,34.16 36.14,35.93 36.14,37.82 38.2,39.89 38.81,39.89 39.27,40.34 39.27,40.73 38.94,41.06 37.92,41.06 v2(37.34,40.47) ; v2(178.28,80.48) 182.12,76.64 184.79,76.64 186.4,78.25 191.42,78.25 194.18,75.49 196.54,75.49 198.04,73.99 198.04,70.16 194.3,66.42 194.3,66.17 193.33,65.19 192.16,65.19 191.55,64.59 191.55,61 191.67,60.88 191.97,60.58 192.71,60.58 193.14,61 193.14,61.24 193.77,61.88 v2(193.77,61.88) ; v2(86.64,36.51) 86.63,36.52 85.24,36.52 83.68,34.96 79.86,34.96 77.59,32.69 v2(77.59,32.14)
  BOTTOM w0.127: UC10.4 193.6,59.9 194.49,59.9 RE99.1 194.46,60.54 193.68,60.54 192.89,61.33 RE98.1 192.89,61.63 193.07,61.81 193.7,61.81 v2(193.77,61.88)
RUNPWROK: length 10.2
  TOP w0.127: UE5.B26 182.61,67.66 183.06,67.22 v2(183.06,67.17) ; QE12.3 187.55,73.46 186.66,73.46 RE83.2 186.56,72.65 186.69,72.53 v2(186.7,72.53)
  BOTTOM w0.127: v2(183.06,67.17) 183.06,67.42 182.68,67.8 v1(182.68,68.51) 182.68,68.68 184.69,70.7 184.69,70.91 185.59,71.8 185.98,71.8 v2(186.7,72.53)
SA_B+:
  vias: v1(70.1,62.49) v2(67.49,61.32) v2(68.07,61.32) v2(68.68,61.35) v2(69.32,61.35)
SA_BST:
  vias: v1(63.48,60.56)
SA_BST_R: length 2.3
  TOP w0.127: PC1082.1 60.92,61.87 v1(60.4,61.35)
  TOP w0.508: PC1082.1 PR1082.1
SA_FCCM: length 1.4
  TOP w0.203: PR1059.1 63.3,64.63 63.47,64.46 PU1305.7
SA_LGATE: length 0.7
  TOP w0.127: v1(70.46,64.65) 70.85,65.05 v2(70.85,65.16)
  vias: v2(65.25,64.28) v2(65.25,63.69) v2(70.31,65.44)
SA_SNUB: length 2.5
  BOTTOM w0.127: PC1086.1 v1(69.32,66.1)
  BOTTOM w0.508: PR1086.2 69.44,67.4 PC1086.1
SA_SW: length 0.7
  TOP w0.127: v2(70.79,63.46) v1(71.53,63.46)
  vias: v2(62.37,63.95) v2(62.52,64.56) v2(70.79,64.07)
SA_UGATE: length 7.4
  IN3 w1.016: 62.78,61.78 66.72,61.78 67.16,62.21 69.98,62.21
  vias: v2(62.68,60.71) v2(62.68,60.12) v2(70.8,62.54) v2(70.83,61.87)
SAP: length 12.8
  BOTTOM w0.203: PR1091.1 65.7,60.77 66.05,61.12 66.93,61.12 67.18,60.87 69.61,60.87 v1(69.67,60.93) 70.16,60.93 70.83,60.25 73.92,60.25 74.37,60.7 74.37,62.29 74.26,62.4 PL1005.2
SATA_PRX_SSDTX_N2: length 101.5
  IN4 w0.091: v2(188.19,32.95) 188.19,36.45 185.49,39.15 185.49,43.33 185.19,43.62 185.19,46.93 180.06,52.05 179.65,52.05 178.76,52.94 178.76,54.66 177.13,56.29 177.13,56.61 173.97,59.78 173.97,61.35 172.82,62.49 172.82,64.02 172.75,64.1 172.75,66.56 173.2,67.02 173.2,67.97 172,69.18 172,71.18 170.26,72.93 170.26,73.31 170.51,73.57 170.97,73.57 171.55,74.15 171.55,76 168.84,78.71 168.34,78.71 167.66,79.39 156.44,79.39 155.74,78.69 152.94,78.69 152.33,79.3 138.25,79.3 135.88,76.93 135.88,72.6 134.74,71.46 134.74,69.67 134.65,69.58 134.47,69.58 134.34,69.7 v2(134.34,69.81)
  BOTTOM w0.127: R2664.1 186.9,33.64 187.76,33.64 188.05,33.34 188.05,33.09 v2(188.19,32.95) ; UCPU1.E30 134.57,69.59 v2(134.34,69.81)
SATA_PRX_SSDTX_N2_C: length 2.8
  BOTTOM w0.127: JNGFF2.43 183.97,33.79 184.11,33.65 185.07,33.65 185.18,33.55 185.43,33.55 R2664.2
SATA_PRX_SSDTX_P2: length 101.4
  IN4 w0.091: v2(134.37,69.18) 134.58,69.39 134.73,69.39 134.93,69.59 134.93,71.38 136.07,72.52 136.07,76.85 138.33,79.11 152.25,79.11 152.86,78.49 155.82,78.49 156.52,79.19 167.58,79.19 168.26,78.52 168.76,78.52 171.36,75.92 171.36,74.23 170.89,73.76 170.43,73.76 170.06,73.39 170.06,72.85 171.81,71.1 171.81,69.1 173.01,67.89 173.01,67.1 172.55,66.64 172.55,64.02 172.63,63.94 172.63,62.41 173.77,61.27 173.77,59.7 176.94,56.53 176.94,56.21 178.57,54.58 178.57,52.86 179.57,51.86 179.98,51.86 185,46.85 185,43.54 185.29,43.25 185.29,39.07 188,36.37 188,33.45 187.88,33.33 187.53,33.33 187.43,33.23 187.43,33.1 v2(187.58,32.95)
  BOTTOM w0.127: R2663.1 186.67,33.29 186.76,33.38 187.65,33.38 187.8,33.24 187.8,33.1 187.65,32.95 v2(187.58,32.95) ; v2(134.37,69.18) 134.61,69.18 134.83,68.97 UCPU1.F30
SATA_PRX_SSDTX_P2_C: length 2.8
  BOTTOM w0.127: R2663.2 185.44,33.29 185.07,33.29 184.97,33.4 184.14,33.4 184.04,33.29 JNGFF2.41
SATA_PTX_SSDRX_N2: length 92.1
  IN4 w0.091: v2(187.33,34.98) 186.92,35.39 186.52,35.39 186.31,35.6 186.31,37.19 183.63,39.88 183.63,45.33 182.89,46.07 182.89,47.43 181.77,48.56 179.13,48.56 178.66,49.03 178.66,51.64 177.6,52.7 177.6,53.88 175.94,55.54 175.94,56.85 173.18,59.61 173.18,60.39 171.87,61.7 171.87,62.4 172.02,62.55 172.02,63.71 171.63,64.1 171.63,65.06 170.94,65.74 170.94,67.57 169.54,68.97 169.54,70.78 167.14,73.18 167.14,75.77 164.4,78.52 156.67,78.52 156.02,77.87 152.58,77.87 151.94,78.51 138.84,78.51 137.65,77.31 137.65,76.52 136.98,75.86 136.71,75.86 v2(136.5,75.65)
  BOTTOM w0.076: UCPU1.A25 137.65,72.31 137.73,72.24 137.73,72.1 137.62,71.99 137.36,71.99 137.3,72.05 137.3,72.14 137.24,72.42 137.24,72.92 136.72,73.44 136.29,73.44 135.81,73.92 135.81,74.13 135.85,74.18 135.85,74.2
  BOTTOM w0.127: v2(136.5,75.65) 136.5,75.75 136.36,75.89 136.08,75.89 135.85,75.66 135.85,74.2 ; CD47.1 186.96,35.18 187.13,35.18 v2(187.33,34.98)
SATA_PTX_SSDRX_N2_C: length 2.9
  BOTTOM w0.127: CD47.2 185.44,35.19 185.17,35.19 184.87,34.89 184.11,34.89 184.01,34.79 JNGFF2.47
SATA_PTX_SSDRX_P2: length 92.1
  IN4 w0.091: v2(187.33,35.65) 187.26,35.58 186.6,35.58 186.5,35.68 186.5,37.27 183.82,39.96 183.82,45.41 183.08,46.15 183.08,47.51 181.85,48.75 179.21,48.75 178.85,49.11 178.85,51.72 177.8,52.78 177.8,53.96 176.13,55.62 176.13,56.93 173.37,59.69 173.37,60.47 172.06,61.78 172.06,62.32 172.21,62.47 172.21,63.79 171.82,64.18 171.82,65.14 171.14,65.82 171.14,67.65 169.73,69.05 169.73,70.86 167.34,73.26 167.34,75.85 164.48,78.71 156.59,78.71 155.94,78.06 152.66,78.06 152.02,78.7 138.76,78.7 137.45,77.39 137.45,76.6 136.9,76.05 136.74,76.05 v2(136.5,76.29)
  BOTTOM w0.076: 135.6,74.2 135.6,74.18 135.64,74.13 135.64,73.85 136.22,73.28 136.65,73.28 137.07,72.85 137.07,72.41 137.13,72.13 137.13,71.98 137.32,71.79 UCPU1.B25
  BOTTOM w0.127: v2(187.33,35.65) 187.11,35.43 187,35.43 CD44.1 ; v2(136.5,76.29) 136.36,76.14 135.97,76.14 135.6,75.77 135.6,74.2
SATA_PTX_SSDRX_P2_C: length 2.9
  BOTTOM w0.127: CD44.2 185.43,35.45 185.06,35.45 184.76,35.14 184.17,35.14 184.02,35.29 JNGFF2.49
SCLK_CORE: length 1.9
  TOP w0.203: PU1000.37 64.56,52.96 PR1070.2
SD_PWR_EN: length 61.6
  TOP w0.127: v2(172.26,15.58) 172.31,15.53 R1176.1 R1178.1 171.43,15.1 171.7,15.37 U716.5
  IN3 w0.089: v2(172.26,15.58) 171.72,15.03 171.27,15.03 171.06,14.83 168.57,14.83 167.43,15.97 163.66,15.97 162.49,14.79 v2(161.23,14.79)
  IN4 w0.081: v2(162.76,33.49) 161.79,33.49 161.23,34.06 160.48,34.06 160.01,34.52 160.01,37.16 156.5,40.67 156.03,40.67 155.5,41.21 155.5,41.58 153.9,43.18 153.9,44.95 v2(154.15,45.19)
  BOTTOM w0.076: UCPU1.BA9 147.22,50.15 147.49,49.88 147.49,49.51 149.13,47.86 149.86,47.86 150.77,46.95 150.92,46.95 152.42,45.46
  BOTTOM w0.127: v2(154.15,45.19) 153.88,45.46 152.42,45.46 ; v2(161.23,14.79) 163.63,17.19 163.63,18.04 163.35,18.32 163.35,20.36 v3(163.42,20.43) 163.42,32.83 v2(162.76,33.49)
SD_RCOMP: length 2
  TOP w0.127: RC96.1 147.84,62.44 148.43,61.86 v2(148.43,61.82)
  BOTTOM w0.127: v2(148.43,61.82) 148.74,61.51 UCPU1.AB7
SDA_CORE: length 2.4
  TOP w0.203: PU1000.35 65.21,53.76 65.02,53.95 65.02,54.19 PR1028.2
SIO_EXT_SCI#: length 59.5
  TOP w0.127: RC237.2 148.69,50.83 147.66,51.87 147.66,54.68 147.98,55.01 v2(148.08,55.01) ; UE5.A33 176.94,67.02 176.61,67.34 176.61,68.43 176.35,68.69 v2(176.34,68.69) 176.34,68.69 175.99,68.69 175.87,68.56 v3(175.87,67.92)
  IN1 w0.081: v2(148.08,55.01) 147.6,54.52 147.6,51.74 150.53,48.81 152.45,48.81 152.71,48.55 154,48.55 154,48.54 154.71,48.54 155.45,47.8 155.45,47.41 156.15,46.72 158.5,46.72 158.77,46.99 162.36,46.99 167.66,52.29 167.66,54.05 167.03,54.68 167.03,55.81 167.33,56.11 167.33,56.7 168.29,57.66 168.29,59.67 170.34,61.72 170.34,64.06 171.72,65.43 171.72,65.61 172.22,66.12 172.22,66.8 172.1,66.92 172.1,67.61 172.4,67.9 173.82,67.9 174.67,68.75 176.28,68.75 v2(176.34,68.69)
  BOTTOM w0.076: v2(148.08,55.01) 148.48,55.4 UCPU1.AN7
SIO_EXT_SMI#: length 69.4
  TOP w0.127: v2(188.72,61.78) 188.48,62.02 188.06,62.02 UE5.A6
  BOTTOM w0.127: v2(188.72,61.78) 188.93,61.78 189.2,61.51 190.36,61.51 v3(190.57,61.72) 191.82,62.97 192.25,62.97 192.62,63.33 192.62,64.14 193.8,65.32 193.8,66.73 193.63,66.9 193.4,66.9 193.1,67.19 193.1,67.7 193.36,67.96 193.36,71.59 191.08,73.87 187.19,73.87 187.06,74 187.06,76.06 186.93,76.19 185.08,76.19 184.85,75.96 184.19,75.96 183.95,75.72 181.35,75.72 181.15,75.92 178.74,75.92 178.28,76.37 178.28,77.8 176.74,79.34 155.12,79.34 152.98,77.2 152.98,76.31 RC236.2 152.38,74.37 151.45,73.44 150.05,73.44 149.16,72.55 149.16,72.1 UCPU1.A6
SIO_EXT_WAKE#: length 59.5
  TOP w0.127: v2(185.8,61.22) 186.06,60.96 186.59,60.96 186.9,61.27 UE5.B5 ; v3(157.77,57.56) 157.46,57.87 v2(157.28,57.87)
  IN3 w0.089: v2(185.8,61.22) 185.8,61.5 186.16,61.86 186.61,61.86 188.33,63.57 188.33,66.14 188.55,66.36 189.03,66.36 189.41,66.73 189.41,69.01 187.65,70.77 184.22,70.77 183.74,71.26 179.2,71.26 178.8,70.86 176.68,70.86 171.88,66.06 171.42,66.06 170.76,65.4 169.03,65.4 167.67,64.03 163.6,64.03 162.28,62.72 162.28,61.63 161.58,60.93 160.26,60.93 159.91,60.58 159.91,60.32 157.46,57.87 v2(157.28,57.87)
  BOTTOM w0.076: UCPU1.AD3 150.82,59.37 151.05,59.14 151.26,59.14 151.42,58.97 151.42,58.66 151.6,58.48 152.14,58.48
  BOTTOM w0.127: v2(157.28,57.87) 157.05,57.64 156.14,57.64 RC283.2 155.19,57.67 154.81,57.67 154.02,58.45 152.32,58.45 152.3,58.48 152.14,58.48
SIO_PWRBTN#: length 157.3
  TOP w0.127: JXDP1.41 68.6,74.93 v2(68.99,75.32) 68.81,75.5 CC269.1 69.67,75.9 RC241.2 ; UE5.B58 181.61,58.99 181.65,59.03 181.65,60.06 181.3,60.41 v2(180.99,60.41)
  IN1 w0.081: v2(106.43,65.03) 107.32,65.03 108.49,66.21 109.66,66.21 109.96,66.51 111.45,66.51 112.29,67.35 113.3,67.35 113.6,67.04 117.12,67.04 117.96,66.19 118.98,66.19 120.19,64.98 124.14,64.98 125.35,66.19 125.35,66.85 125.6,67.1 133.2,67.1 134.98,65.33 134.98,58.81 v2(135.79,58)
  IN2 w0.089: v2(180.99,60.41) 180.88,60.41 180.43,59.96 179.93,59.96 179.73,59.75 178.76,59.75 177.17,58.16 177.17,57.78 176.9,57.51 176.27,57.51 172.67,61.1 167.45,61.1 v2(166.42,62.14)
  IN3 w0.089: v2(99.23,72.45) 98.92,72.14 95.81,72.14 93.76,74.2 92.81,74.2 91.94,73.33 91.33,73.33 90.7,72.7 82.68,72.7 82.46,72.47 80.66,72.47 79.08,74.05 69.86,74.05 68.99,74.93 v2(68.99,75.32) ; v2(135.79,58) 136.15,58.36 136.15,58.36 136.21,58.41 136.72,58.41 136.95,58.18 136.95,58.03 138.18,56.8 140.96,56.8 141.25,56.51 141.25,50.9 v2(143.52,48.62) 143.81,48.62 144.29,49.1 144.29,49.39 145.46,50.56 146.11,50.56 146.43,50.88 150.18,50.88 152.4,53.11 154.63,53.11 157.63,56.11 158.73,56.11 160.93,58.31 160.93,59.36 163.45,61.89 164.56,61.89 164.8,62.12 166.41,62.12 v2(166.42,62.14)
  BOTTOM w0.076: v2(143.52,48.62) 143.3,48.84 143.3,50.07 UCPU1.BA15
  BOTTOM w0.127: v2(106.43,65.03) 106.6,65.21 106.6,69.48 106.07,70.01 v1(105.13,70.01) 104.43,70.01 104.34,70.1 101.93,70.1 99.58,72.45 v2(99.23,72.45)
SIO_RCIN#: length 67
  TOP w0.127: v2(181.31,69.43) 181.31,69.43 181.36,69.37 181.36,68.72 UE5.A27
  IN1 w0.081: v2(181.31,69.43) 181.31,68.77 180.58,68.04 178.96,68.04 177.29,66.38 175.97,66.38 175.44,65.85 175.44,65.19 173.57,63.32 173.57,61.29 173.48,61.21 173.48,59.62 171.84,57.98 171.84,52.87 171.5,52.53 171.5,48.59 169.66,46.74 167.67,46.74 163.37,42.44 161.03,42.44 160.18,43.29 157.29,43.29 155.94,41.94 154.96,41.94 153.87,40.85 152.96,40.85 v2(152.12,41.69)
  BOTTOM w0.076: 145.12,47.32 144.55,47.9 144.55,48.56 144.37,48.74 144.37,49.83 144.41,49.94 144.41,50.06 144.35,50.27 144.35,50.42 144.4,50.58 144.4,50.66 144.58,51.22 UCPU1.AW13
  BOTTOM w0.127: 145.12,47.32 145.42,47.03 145.42,46.82 145.7,46.54 146.11,46.54 147.04,45.61 RC16.2 146.53,44.94 146.53,44.14 146.84,43.83 146.84,43.37 147.35,42.86 v3(148.11,42.86) 149.81,42.86 150.98,41.69 v2(152.12,41.69)
SIO_SLP_A#: length 114.7
  TOP w0.127: v2(181.89,67.17) 181.89,67.27 181.61,67.54 UE5.B28
  IN1 w0.081: v2(142.6,55.01) 142.69,55.01 143,54.7 143,52.92 144.07,51.85 144.45,51.85 144.83,51.47 145.41,51.47 146.42,50.47 147.59,50.47 150.07,47.98 151.98,47.98 152.5,47.46 152.5,46.85 153.42,45.93 158.61,45.93 159.04,46.36 163.94,46.36 167.11,49.53 167.11,50.44 170.3,53.63 170.3,56.05 169.34,57.01 169.34,59.24 171.86,61.76 171.86,62.26 172.22,62.62 172.22,63.87 173.58,65.23 173.58,67.04 174.63,68.09 176.6,68.09 177.9,69.38 177.9,69.48 178.34,69.92 178.74,69.92 178.91,70.1 179.35,70.1 179.44,70.01 179.87,70.01 180.53,70.67 181.39,70.67 181.61,70.44 181.61,69.76 181.74,69.63 181.74,67.34 181.89,67.19 v2(181.89,67.17)
  IN4 w0.089: v2(197.21,31.68) 196.77,32.12 196.77,34.02 194.98,35.81 194.98,48.49 193.36,50.12 193.12,50.12 190.7,52.54 190.57,52.54 189.8,53.31 189.8,57.23 188.89,58.13 188.21,58.13 187.44,58.9 187.44,60.55 187.29,60.7 187.29,62.31 186.87,62.72 186.17,62.72 186.14,62.69 184.74,62.69 181.89,65.54 v2(181.89,67.17)
  BOTTOM w0.076: UCPU1.AN16 v2(142.6,55.01)
  BOTTOM w0.127: JAPS1.6 200.76,33.39 198.91,33.39 v2(197.21,31.68)
SIO_SLP_S0#: length 175.7
  TOP w0.127: v2(165.73,69.91) 165.73,70.14 165.45,70.42 164.86,70.42 164.77,70.33 UC9.1 ; v2(195.62,78.78) 195.62,79.58 195.91,79.87 PR1411.1 ; v2(169.67,55.36) 170.37,55.36 171.56,54.17 172.73,54.17 PR1400.1 ; R1006.1 RE92.1 185.4,50.2 185.78,49.82 185.87,49.82 v2(185.87,49.81)
  IN1 w0.081: v2(165.73,69.91) 165.81,69.99 165.81,72.09 170.47,76.75 176.04,76.75 176.31,76.48 187.4,76.48 188.27,77.35 193.29,77.35 194.72,78.78 v2(195.62,78.78) ; v2(169.67,55.36) 169.67,54.01 165.99,50.33 165.99,49 163.77,46.78 158.86,46.78 158.44,46.36 156.21,46.36 155.25,47.33 155.25,47.71 154.62,48.34 152.63,48.34 152.36,48.6 150.44,48.6 146.34,52.71 146.08,52.71 145.66,53.13 v2(145.39,53.13)
  IN2 w0.089: v2(199.95,28.76) 201.02,29.83 201.02,37.65 202.29,38.92 202.29,44.71 v2(201.51,45.5) 201.51,46.14 200.65,46.99 200.65,50.74 204.7,54.78 204.7,59.69 204.11,60.28 204.11,65.13 203.18,66.07 203.18,69.39 203.63,69.85 203.63,72.8 202.9,73.54 202.9,76.39 201.96,77.33 197.07,77.33 v2(195.62,78.78)
  BOTTOM w0.127: v2(165.73,69.91) 165.73,69.76 166.83,68.66 166.94,68.66 168.05,67.55 168.05,65.96 168.34,65.67 168.34,63.12 169.42,62.03 169.42,55.61 v2(169.67,55.36) ; v2(199.95,28.76) 200.08,28.89 JAPS1.15 ; v2(201.51,45.5) 201.51,45.84 198.93,48.42 198.93,49.9 197.7,51.12 v3(196.04,51.12) 194,51.12 191.56,48.68 190.48,48.68 190.39,48.76 188.66,48.76 187.58,49.85 185.9,49.85 v2(185.87,49.81) ; UCPU1.AT11 145.71,53.45 v2(145.39,53.13)
SIO_SLP_S3#: length 402.2
  TOP w0.127: UC11.1 52.34,41.53 52.21,41.65 51.43,41.65 50.14,42.95 49.38,42.95 48.77,43.56 v1(48.58,43.56) v2(48.1,44.04) ; UE5.A35 177.16,66.02 176.34,66.02 v2(176.27,65.95)
  IN1 w0.081: v2(189.77,62.07) 189.77,61.77 v2(192.04,59.5) 191.11,58.57 189.33,58.57 188.06,57.3 188.06,56.72 190.19,54.59 190.19,53.52 190.87,52.84 190.87,51.46 189.13,49.72 189.13,48.32 188.23,47.41 185.82,47.41 184.93,46.53 184.93,44.47 184.72,44.26 183.92,44.26 183.34,43.68 v2(177.16,43.68)
  IN2 w0.089: v2(177.16,43.68) 176.85,43.36 176.85,42.97 176.45,42.58 176.45,40.8 176.1,40.44 176.1,37.45 175.44,36.79 175.44,22.34 174.49,21.38 174.49,15.21 173.05,13.78 163.19,13.78 163,13.97 131.89,13.97 130.01,15.85 128.03,15.85 125.95,13.76 117.49,13.76 115.41,15.85 108.95,15.85 108.61,15.5 100.46,15.5 99.63,16.33 95.59,16.33 94.89,15.63 81.54,15.63 81.23,15.93 71.6,15.93 71.04,15.38 65.67,15.38 65.15,15.89 54.95,15.89 54.35,16.49 51.45,16.49 50.56,15.6 42.18,15.6 42.14,15.64 40.12,15.64 39,16.76 37.91,16.76 33.43,21.24 33.43,21.8 34.59,22.97 34.59,25.36 34,25.94 34,30.27 35.5,31.76 35.5,32.11 34.98,32.62 34.98,38.94 34.51,39.41 34.51,40.8 35.08,41.37 35.08,43.88 35.7,44.5 35.7,48.69 37.07,50.06 v2(37.2,50.06)
  IN3 w0.089: v2(189.77,62.07) 190.23,61.61 192.17,61.61 193.44,62.88 193.44,65.31 193.84,65.7 193.84,66.62 194.21,66.99 v2(194.21,67.37) ; v2(177.16,43.68) 176.99,43.84 175.71,43.84 174.62,42.76 173.53,42.76 173.08,43.22 172.49,43.22 171.89,42.61 170.53,42.61 170.04,42.12 164.57,42.12 163.2,40.75 162.53,40.75 160.42,38.64 158.11,38.64 v2(157.81,38.34) ; v2(37.2,50.06) 38.01,50.06 39.02,49.06 39.29,49.06 41.24,47.11 45,47.11 46.71,48.83 48.24,48.83 48.64,48.43 48.64,46.52 48.1,45.98 v2(48.1,44.04)
  IN4 w0.081: v2(157.81,38.34) 157.81,38.77 156.33,40.25 155.86,40.25 155.08,41.03 155.08,41.41 153.46,43.03 153.46,44.81 152.45,45.83 150.43,45.83 150,45.39 148.86,45.39 148.46,45.79 148.46,48.74 145.55,51.66 145.06,51.66 144.64,52.08 144.22,52.08 143.92,52.38 143.92,53.97 v2(143.51,54.37)
  IN4 w0.089: v2(198.55,34.4) 197.92,34.4 196.09,36.23 196.09,49.66 193.82,51.93 193.82,54.72 191.5,57.04 191.5,57.82 190.47,58.85 190.47,61.38 v2(189.77,62.07)
  BOTTOM w0.076: UCPU1.AP15 v2(143.51,54.37)
  BOTTOM w0.127: v2(189.77,62.07) 189.4,62.07 R249.2 188.74,62.73 184.92,62.73 184.4,62.21 180.11,62.21 179.75,62.58 179.52,62.58 179.25,62.85 179.25,63.14 178.84,63.55 177.83,63.55 177.65,63.72 177.65,65.79 177.44,66.01 176.33,66.01 v2(176.27,65.95) ; v2(198.55,34.4) 199.54,35.39 JAPS1.2 ; UC10.1 191.56,59 192.06,59.5 v2(192.04,59.5) ; v2(37.2,50.06) 36.87,50.4 36.87,51.71 36.92,51.76 RT119.1 ; U729.1 204.42,79.29 204.87,78.85 204.87,76.77 204.59,76.49 204.58,76.49 204.22,76.13 202.46,76.13 202.1,76.49 201.48,76.49 201.16,76.17 199.61,76.17 198.64,75.21 198.64,73.92 198.17,73.45 198.17,70.18 196.98,68.98 194.45,68.98 194.22,68.75 194.22,67.43 194.21,67.41 v2(194.21,67.37)
SIO_SLP_S4#: length 155.8
  TOP w0.127: UC8.1 204.05,56.99 v2(204.01,56.95) ; v2(171.64,67.2) 171.84,67 173.6,67 R252.2 ; v2(180.06,66.25) 179.91,66.25 179.39,66.77 UE5.B36
  IN1 w0.081: v2(199.16,34.38) 199.16,35.24 198.5,35.9 198.5,40.99 196.75,42.73 196.75,50.47 194.26,52.96 194.26,60.61 v2(193.81,61.05) 194.26,61.5 194.26,63.79 195.52,65.05 195.52,67.07 193.07,69.52 190.56,69.52 190.05,70.03 184.85,70.03 184.41,69.59 184.41,69.19 184.57,69.03 184.57,66.39 183.31,65.13 182.38,65.13 180.91,66.6 180.41,66.6 v2(180.06,66.25)
  IN2 w0.089: v2(171.64,67.2) 172.08,67.2 172.29,66.99 175.61,66.99 176.01,67.38 176.55,67.38 177.57,66.36 179.95,66.36 v2(180.06,66.25)
  IN3 w0.089: v2(180.06,66.25) 180.01,66.2 180.01,65.23 181.03,64.21 181.03,62.7 179.66,61.34 178.43,61.34 178.22,61.12 178.22,57.13 177.73,56.64 176.78,56.64 174.66,54.52 171.9,54.52 171.7,54.32 168.89,54.32 164.53,49.96 158.51,49.96 157.91,49.36 157.91,48.57 155.5,46.16 155.5,44.2 154.47,43.18 151.37,43.18 151.1,42.91 144.45,42.91 139.7,47.66 139.7,48.32 140.1,48.73 141.1,48.73 141.61,48.22 142.82,48.22 143.36,47.67 v2(144.02,47.67)
  IN4 w0.081: v2(193.81,61.05) 198.93,61.05 200.26,59.72 202.66,59.72 203.48,58.9 203.48,57.74 204.01,57.21 v2(204.01,56.95)
  BOTTOM w0.076: v2(144.02,47.67) 143.41,47.67 142.97,48.11 142.97,50.63 UCPU1.BA16
  BOTTOM w0.127: JAPS1.5 200.76,33.89 199.65,33.89 v2(199.16,34.38)
SIO_SLP_S5#: length 102
  TOP w0.127: v2(144.04,47.08) 144.04,47.02 v1(143.69,46.67) ; v2(186.11,69.38) 185.86,69.13 185.86,68.72 UE5.A18
  IN3 w0.089: v2(144.04,47.08) 144.73,47.76 145.19,47.76 145.42,47.99 145.42,48.57 147.08,50.24 150.44,50.24 152.67,52.46 154.9,52.46 156.12,53.69 157.86,53.69 158.69,54.51 158.69,55.15 161.58,58.04 161.58,59.09 162.08,59.59 163.17,59.59 163.56,59.98 165.69,59.98 168.26,62.56 169.42,62.56 171.18,64.32 172.65,64.32 173.23,64.9 173.23,65.77 174.18,66.72 175.24,66.72 177.42,68.89 182.41,68.89 183.34,69.83 185.66,69.83 v2(186.11,69.38)
  IN4 w0.081: 199.71,34.66 199.96,34.41 v2(199.96,34.39)
  IN4 w0.089: 199.71,34.66 197.5,36.88 196.63,36.88 196.3,37.21 196.3,49.75 194.03,52.02 194.03,54.81 191.71,57.13 191.71,57.91 190.68,58.94 190.68,62.17 187.76,65.09 187.76,66.37 186.54,67.59 186.54,68.94 v2(186.11,69.38)
  BOTTOM w0.076: v2(144.04,47.08) 143.68,47.08 142.81,47.95 142.81,50.22 142.64,50.39 142.64,50.81 142.95,51.12 UCPU1.AY16
  BOTTOM w0.127: v2(199.96,34.39) 199.97,34.39 200.76,34.39 JAPS1.4
SIO_SLP_SUS#: length 192.9
  TOP w0.127: v2(153.26,47.23) 153.27,47.24 153.35,47.24 154.13,46.46 154.13,45.97 153.59,45.43 153.59,44.66 156.44,41.81 156.44,40.41 158.3,38.55 v2(158.3,38.01) 159.03,38.01 159.23,37.8 QE13.2 ; UC13.1 199.51,59.09 199.75,59.33 202.83,59.33 203.31,58.85 v2(204.04,58.85) 204.04,59.11 201.49,61.66 201.49,64.59 201.07,65.01 197.92,65.01 197.67,64.77 194.23,64.77 v2(194.06,64.94) ; v2(172.97,80.2) 172.2,79.42 PR801.1 ; R1444.1 181.97,38 179.4,40.57 v2(179.26,40.57) ; RC97.1 177.27,55.7 v2(176.73,55.7)
  IN1 w0.081: v2(194.06,64.94) 193.93,64.94 193.72,64.74 192.61,64.74 192.5,64.85 190.72,64.85 190.25,64.37 189.69,64.37 189.56,64.25 188.57,64.25 188.06,63.73 182.47,63.73 180.09,61.36 178.4,61.36 176.78,59.73 175.41,59.73 175.09,59.41 175.09,58.41 175.77,57.73 175.77,56.7 176.73,55.74 v2(176.73,55.7) ; v2(153.26,47.23) 153.03,47.23 152.07,48.19 150.16,48.19 147.67,50.68 146.51,50.68 145.5,51.68 144.92,51.68 144.54,52.06 144.22,52.06 143.97,52.32 143.97,54.49 143.51,54.95 v2(143.51,55.01) ; v2(202.2,71.01) 202.2,71.02 202.9,71.72 202.9,77.12 202.26,77.76 198.1,77.76 196.01,79.85 188.52,79.85 186.02,77.34 179.55,77.34 177.28,79.61 173.56,79.61 v2(172.97,80.2)
  IN2 w0.089: v2(176.73,55.7) 176.87,55.56 177.71,55.56 180.3,58.15 182.93,58.15 184,57.08 184,56.19 185.09,55.1 185.09,53.09 183.29,51.29 183.29,49.31 182.26,48.28 182.26,43.51 179.32,40.57 v2(179.26,40.57)
  IN3 w0.089: v2(204.04,58.85) 204.12,58.93 204.12,66.58 v2(204.66,67.12) 204.2,67.57 203.77,67.57 203.51,67.84 203.51,69.69 202.2,70.99 v2(202.2,71.01) ; v2(158.3,38.01) 160.1,38.01 162.62,40.53 163.29,40.53 164.33,41.57 167.41,41.57 167.93,41.06 171.24,41.06 171.32,40.98 173.27,40.98 173.91,41.62 176.98,41.62 177.9,40.71 179.12,40.71 v2(179.26,40.57)
  BOTTOM w0.127: UCPU1.AN15 143.58,55.01 v2(143.51,55.01) ; PR700.1 204.61,67.17 v2(204.66,67.12)
  BOTTOM w0.254: PR1412.1 203.59,71.54 203.07,71.01 v2(202.2,71.01)
SIO_SLP_SUS#_R: length 4.9
  TOP w0.127: UE5.B52 178.61,58.67 177.64,58.67 177.15,58.19 177.15,57.54 176.53,56.92 v3(176.53,56.75) 176.87,56.41 177.12,56.41 177.17,56.46 RC97.2
SIO_SLP_WLAN#: length 51.1
  TOP w0.127: UE5.B45 178.88,62.27 178.98,62.17 v2(178.99,62.17)
  IN3 w0.089: v2(144.11,46.3) 144.35,46.54 146.2,46.54 146.89,47.23 146.89,47.63 148.4,49.15 150.76,49.15 152.49,50.88 153.46,50.88 153.77,50.57 155.9,50.57 156.56,51.23 157.78,51.23 159.58,53.03 159.58,54.82 161.8,57.04 165.67,57.04 166.63,58.01 166.63,59.05 167.3,59.71 170.77,59.71 171.67,58.82 172.7,58.82 173.61,59.72 173.61,61.8 174.33,62.52 178.63,62.52 178.98,62.17 v2(178.99,62.17)
  BOTTOM w0.127: UCPU1.BB17 142.38,47.82 143.9,46.3 v2(144.11,46.3)
SLEEVE:
  vias: v2(9.36,22.1) v2(9.95,22.11) v2(27.72,34.15) v2(27.77,33.55)
SLEEVE_R: length 20.3
  TOP w0.127: v3(6.24,24.16) 6.62,24.54 6.62,25.09 JHP1.3
  TOP w0.254: v2(18.47,27.01) 18.47,26.12 QA1.3
  IN1 w0.508: v2(18.47,27.01) 18.42,26.96 18.42,24.75 15.98,22.31 11.59,22.31 10.99,22.92 7.75,22.92 7.42,23.25 7.42,24.09 6.62,24.89 JHP1.3
SM_PG_CTRL: length 108.9
  TOP w0.127: PR609.1 162.54,31.2 v2(162.37,31.03)
  IN2 w0.089: v2(95.25,32.57) 95.25,32.04 94.34,31.12 94.34,29.32 95.56,28.1 95.56,27.39 97.87,25.08 98.61,25.08 98.61,25.08 98.79,25.08 99.61,24.26 99.61,22.64 103.54,18.7 106.08,18.7 106.95,19.57 117.18,19.57 118.85,17.91 125.06,17.91 126.57,19.41 131.58,19.41 132.74,18.25 156.31,18.25 158.26,20.2 161.65,20.2 162.95,21.5 162.95,26.82 162.15,27.62 162.15,28.28 162.8,28.93 162.8,30.59 v2(162.37,31.03)
  BOTTOM w0.127: v2(95.25,32.57) 95.63,32.95 95.63,33.56 95.38,33.81 95.38,35.2 99.8,39.61 99.8,42.13 100.67,43 v3(100.67,43.42) 101.4,44.15 RE60.2 101.76,44.9 102.84,44.9 UC2.4
SM_RCOMP0: length 4.6
  TOP w0.076: 140.77,52.59 140.82,52.59 141.25,53.02 141.25,53.3 v2(141.68,53.74)
  TOP w0.305: 140.77,52.59 139.88,51.7 139.88,51.22 139.55,50.89 RC5.1
  BOTTOM w0.254: v2(141.68,53.74) 142.12,54.08 UCPU1.AR18
SM_RCOMP1: length 3.6
  TOP w0.076: v2(141.68,53.1) 141.15,52.57 141.15,52.18
  TOP w0.305: 141.15,52.18 v1(140.63,51.67) 140.44,51.47 RC6.1
  BOTTOM w0.254: UCPU1.AT18 142.12,53.43 v2(141.68,53.1)
SM_RCOMP2: length 2.6
  TOP w0.305: RC7.1 141.33,51.62 141.68,51.98 v2(141.68,52.47)
  BOTTOM w0.254: UCPU1.AU18 142.12,52.78 v2(141.68,52.47)
SML1_SMBCLK: length 43.3
  TOP w0.127: UE5.B6 187.21,61.77 186.93,61.77 186.61,61.45 v2(186.37,61.45)
  IN2 w0.089: v2(186.37,61.45) 186.18,61.64 181.09,61.64 180.98,61.52 178.4,61.52 177.98,61.1 177.98,60.33 177.15,59.51 174.88,59.51 174.04,60.35 174.04,60.98 172.63,62.38 172.28,62.38 171.73,61.83 169.67,61.83 168.86,62.65 166.75,62.65 165.65,63.75 163.14,63.75 162.94,63.55 158.94,63.55 158.76,63.37 158.76,62.84 157.91,61.98 156.8,61.98 156.16,62.62 156.16,62.94 155.97,63.13 155.34,63.13 v2(155.09,62.87)
  BOTTOM w0.076: v2(155.09,62.87) 155.07,62.9 153.85,62.9 153.4,62.44 152.02,62.44 151.88,62.38 151.75,62.38 151.52,62.45 151.52,62.45 151.39,62.45 151.17,62.37 151.02,62.37 150.82,62.17 UCPU1.W3
  BOTTOM w0.127: v2(155.09,62.87) 155.63,62.87 RC15.1
SML1_SMBDAT: length 47.4
  TOP w0.127: UE5.A5 188.16,61.52 188.16,61.52 188.26,61.52 188.59,61.19 188.78,61.19 v2(188.79,61.2) ; v3(154.07,63.7) 154.3,63.47 v2(155.06,63.47)
  IN2 w0.089: v2(188.79,61.2) 188.74,61.15 187.41,61.15 186.7,61.85 181,61.85 180.89,61.74 178.31,61.74 177.76,61.19 177.76,60.42 177.06,59.73 174.97,59.73 174.25,60.44 174.25,61.07 172.72,62.6 172.19,62.6 171.64,62.05 169.76,62.05 168.95,62.86 166.84,62.86 165.74,63.96 163.05,63.96 162.85,63.76 158.85,63.76 158.55,63.46 158.55,62.93 157.82,62.19 156.89,62.19 156.38,62.71 156.38,63.03 156.06,63.34 155.19,63.34 v2(155.06,63.47)
  BOTTOM w0.076: UCPU1.V3 150.76,62.57 151.23,62.57 151.36,62.61 151.55,62.61 151.57,62.6 151.77,62.55 151.85,62.55 151.98,62.6 153.27,62.6 154.14,63.47 v2(155.06,63.47)
  BOTTOM w0.127: v2(155.06,63.47) 155.3,63.71 RC17.1
SPI_CLK_VROM: length 11.8
  BOTTOM w0.127: RP5.2 178.44,48.21 178.69,48.47 v1(179.41,48.47) 179.64,48.47 180.16,48.98 180.16,49.35 180.7,49.89 180.7,52.65 180.91,52.87 181.05,52.87 181.88,53.7 182.3,53.7 182.47,53.88 U18.6 182.47,55.28 183.1,55.9 183.55,55.9 183.79,56.14 RC29.2
SPI_IO2_VROM: length 11.5
  BOTTOM w0.127: RP6.3 178.27,44.92 178.47,45.13 178.84,45.13 179,44.97 179,44.8 179.12,44.67 183.16,44.67 183.32,44.83 v1(183.32,45.42) 183.32,46.41 183.19,46.53 182.99,46.53 182.81,46.36 182.81,45.19 182.66,45.05 182.45,45.05 182.3,45.19 182.3,46.27 182.47,46.44 U18.3
SPI_IO3_VROM: length 24.9
  BOTTOM w0.127: RP6.4 183.27,44.42 183.35,44.5 187.9,44.5 188.11,44.71 v1(188.11,44.97) 188.11,45.85 189.33,47.07 189.33,47.74 187.73,49.34 185.65,49.34 185.45,49.53 185.45,52.79 185.13,53.11 184.31,53.11 183.74,53.68 U18.7
SPI_SI_VROM: length 13.2
  BOTTOM w0.127: RP5.1 178.36,48.71 178.47,48.83 179.64,48.83 179.9,49.09 179.9,49.46 180.44,50 180.44,51.87 178.57,53.74 178.57,54.3 v1(178.76,54.49) 178.95,54.67 179.33,54.67 180.75,53.25 181.07,53.25 181.2,53.38 U18.5
SPI_SO_VROM: length 13.1
  BOTTOM w0.127: RP6.2 179.11,45.42 179.21,45.32 179.21,45.12 179.33,44.99 179.76,44.99 179.89,45.12 179.89,45.57 180.02,45.69 180.2,45.69 180.33,45.56 180.33,45.15 180.46,45.02 180.64,45.02 180.77,45.15 180.77,45.68 180.92,45.83 181.13,45.83 181.28,45.68 v1(181.28,45.4) 181.28,45.15 181.43,45 181.8,45 182,45.2 182,45.76 181.65,46.11 181.65,46.46 181.84,46.66 181.84,48.15 182.03,48.33 183.58,48.33 183.74,48.17 U18.2
SPK_L+_C:
  vias: v2(22.58,16.09) v2(23.22,16.09) v3(21.82,18.5)
SPK_L-_C:
  vias: v2(24.15,14.71) v2(24.29,15.28) v3(25.04,15.5)
SPK_OUT_L+: length 1.5
  TOP w0.203: 27.46,26.63 27.46,25.26 v2(27.36,25.15)
  vias: v2(24.52,21.45) v2(24.51,20.84) v2(26.94,24.74)
SPK_OUT_L-:
  vias: v3(26.57,21.93)
SPK_OUT_R+:
  vias: v3(30.15,23.66)
SPK_OUT_R-:
  vias: v3(28.68,22.18)
SPK_R+_C:
  vias: v2(28.87,14.71) v2(29.46,14.74) v3(30.63,17.08)
SPK_R-_C: length 0.9
  TOP w0.127: v2(26.9,14.82) v3(26.9,13.94)
  vias: v2(27.49,14.82)
SPKR: length 217.8
  TOP w0.127: v2(27.01,39.35) 26.95,39.35 v1(26.59,39) 26.29,38.69 RA25.1 ; RC183.2 149.89,52.47 v2(149.86,52.49)
  IN3 w0.089: v2(27.01,39.35) 28.48,40.82 31.37,40.82 32,40.19 32,39.66 32.67,38.99 33.27,38.99 35.94,36.32 35.94,27.31 36.59,26.67 37.58,26.67 37.89,26.98 40.95,26.98 41.97,25.96 v2(41.97,25.82)
  IN4 w0.081: v2(149.86,52.49) 149.87,52.49 149.84,52.46 149.84,50.99 152.41,48.41 154.34,48.41 154.47,48.28 155.07,48.28 155.44,47.91 155.44,47.25 155.44,46.57 156.36,45.66 156.36,44.85 157.33,43.87 157.33,41.31 160.98,37.66 162.32,37.66 162.98,37.01 162.98,37 163.66,36.32 163.66,35.03 164.68,34.01 164.68,23.61 160.77,19.69 147.8,19.69 147.4,20.1 145.24,20.1 144.74,19.59 123.78,19.59 123.38,19.99 107.03,19.99 106.52,20.5 101.52,20.5 99.5,22.52 97.67,22.52 97.11,23.09 97.11,25.27 97.02,25.36 97.02,29.09 96.2,29.91 96.2,33.32 95.37,34.15 90.64,34.15 89.83,34.96 86.73,34.96 86.38,34.61 86.38,33.92 85.88,33.42 84.56,33.42 82.74,31.6 78.97,31.6 77.87,30.5 77.02,30.5 74.2,27.68 71.74,27.68 69.54,25.48 69.54,24.29 66.19,20.94 64.07,20.94 62.02,18.9 59.13,18.9 56.63,21.4 54.23,21.4 54.01,21.18 53.34,21.18 53.29,21.23 50.47,21.23 49.42,20.18 44.96,20.18 44.23,20.91 44.23,21.82 43.71,22.34 43.41,22.34 42.39,23.35 42.39,24.32 41.97,24.74 v2(41.97,25.82)
  BOTTOM w0.127: v2(149.86,52.49) 149.87,52.49 149.58,52.21 UCPU1.AW5
SRTCRST#: length 15.8
  TOP w0.127: RC56.1 147.17,45.55 CC24.1 147.52,46.67 v2(147.8,46.67)
  IN2 w0.089: v2(141.68,55.01) 141.75,55.01 142.14,54.62 142.14,52.41 143.66,50.89 146.1,50.89 148.18,48.8 148.18,47.06 v2(147.8,46.67)
  BOTTOM w0.076: UCPU1.AN18 v2(141.68,55.01)
  BOTTOM w0.127: v1(147.09,46.49) 147.27,46.67 v2(147.8,46.67)
SSD_DEVSLP: length 74
  TOP w0.127: v2(174.43,32.59) 174.52,32.67 R1376.2
  IN2 w0.089: v2(152.43,67.93) 152.43,67.9 152.8,67.53 152.8,66.42 153.32,65.9 154.5,65.9 155.39,65.01 155.39,64.6 155.1,64.32 154.91,64.32 154.26,63.67 154.26,62.79 154.8,62.25 154.9,62.25 155.84,61.31 157.57,61.31 157.89,60.99 163.61,60.99 165.14,59.47 170.59,59.47 171.43,58.63 172.42,58.63 172.61,58.82 173.2,58.82 175.1,56.93 175.1,53.29 174.9,53.09 174.9,51.71 175.53,51.08 177.52,51.08 180.13,53.69 180.76,53.69 181.51,52.94 181.51,45.19 180.48,44.15 177.01,44.15 176.63,43.77 176.63,43.06 176.24,42.67 176.24,40.92 175.88,40.56 175.88,37.54 175.22,36.88 175.22,33.17 174.64,32.59 v2(174.43,32.59)
  BOTTOM w0.127: JNGFF2.38 175.6,32.55 174.48,32.55 v2(174.43,32.59) ; v2(152.43,67.93) 152.32,67.83 151.17,67.83 UCPU1.J3
SSD_IFDET: length 77.5
  TOP w0.127: v2(161.87,68.84) 161.97,68.93 161.97,69.33 161.67,69.63 160.63,69.63 159.62,68.62 159.17,68.62 158.88,68.32 157.22,68.32 157.12,68.22 153.27,68.22 152.82,67.76 152.82,66.53 152.62,66.33 151.99,66.33 151.14,67.19 RC51.2
  IN4 w0.081: v2(159.91,69.63) 159.92,69.62 161.47,69.62 162,69.08 162,68.97 v2(161.87,68.84) 161.98,68.84 165.6,65.22 165.6,64.4 167.56,62.44 167.56,60.77 168.68,59.65 168.68,57.81 171.78,54.71 171.78,53.43 172.54,52.66 172.54,48.46 173.65,47.36 173.65,46.17 174.55,45.26 174.55,41.24 177.52,38.26 v2(178.46,38.26)
  BOTTOM w0.127: U683.4 188.5,40.63 187.99,40.12 187.99,39.38 187.12,38.52 v3(185.5,38.52) 184.63,38.52 184.38,38.26 v2(178.46,38.26) ; UCPU1.G4 150.48,68.49 152.68,68.49 153.33,69.14 154.37,69.14 154.76,68.74 R2665.1 155.25,68.82 155.83,69.4 159.61,69.4 159.84,69.63 v2(159.91,69.63)
SSD_PCIE_WAKE#: length 6.8
  TOP w0.127: R1377.1 175.79,36.01 176.87,36.01 177.11,35.76 177.36,35.52 v1(177.77,35.52) v2(178.28,36.03)
  BOTTOM w0.127: v2(178.28,36.03) 177.94,35.68 177.09,35.68 176.23,36.54 175.6,36.54 JNGFF2.54
SSD_PWR_EN: length 80.2
  TOP w0.127: R1188.2 R1446.1 178.19,35.06 177.46,35.06 176.76,35.75 174.08,35.75 173.75,35.43 171.87,35.43 171.35,34.91 171.35,34.6 171.2,34.45 171.2,33.64 v2(170.92,33.36)
  IN2 w0.089: v2(163.42,58.65) 166.64,55.43 166.64,51.2 167.41,50.43 167.41,48.63 168.65,47.39 168.65,43.29 168.47,43.1 168.47,40.82 167.82,40.16 167.82,39.06 168.93,37.95 168.93,35.35 v2(170.92,33.36)
  IN4 w0.081: v2(145.79,59.57) 145.83,59.57 146.27,59.13 148.35,59.13 149.41,58.07 150.21,58.07 151.13,57.15 151.13,54.7 153.34,52.49 154,52.49 154.48,52.01 154.48,51.35 154.48,51.35 154.79,51.04 155.01,51.04 155.51,51.54 155.51,55.55 154.49,56.56 154.49,57.86 154.18,58.17 154.18,59.09 154.73,59.64 155.75,59.64 157.01,58.37 157.34,58.37 157.68,58.03 157.68,57.49 158.51,56.65 v2(158.54,56.65)
  BOTTOM w0.076: v2(145.79,59.57) 145.85,59.63 145.85,60.21 146.48,60.84 146.48,62.39 146.33,62.54 145.72,62.54 145.49,62.31 UCPU1.W12
  BOTTOM w0.127: v2(158.54,56.65) 158.54,56.65 159.88,56.65 161.88,58.65 v2(163.42,58.65)
SUS_ON_EC: length 62.3
  TOP w0.127: R252.1 RE68.1 173.2,68.68 174.67,70.15 v2(174.75,70.15) ; v2(190.21,70.9) 189.84,70.53 189.84,69.78 189.56,69.5 189.56,68.58 189.94,68.2 189.94,66.77 190.53,66.18 191.83,66.18 192.25,65.76 192.25,65.52 192.79,64.99 192.79,64.03 192.61,63.85 192.61,63.43 192.38,63.19 191.68,63.19 R251.1 191.52,62.87 193.78,62.87 194.23,62.41 194.23,60.75 193.87,60.39 193.87,54.3 193.07,53.5 v2(193.07,52.6) ; UC8.2 203.4,57.66 203.05,57.31 202.44,57.31 202.18,57.57 RE95.2 201.55,57.57 v2(200.84,58.28)
  IN1 w0.081: v2(174.75,70.15) 175.19,70.58 177.4,70.58 177.87,71.06 178.26,71.06 179,71.8 181.55,71.8 182.67,72.92 184.19,72.92 186.07,71.04 190.07,71.04 v2(190.21,70.9)
  BOTTOM w0.127: v2(200.84,58.28) 200.84,56.45 201.16,56.13 201.16,54.15 199.53,52.51 197.79,52.51 197.32,52.05 v3(194.05,52.05) 193.63,52.05 v2(193.07,52.6)
SUS_ON_P: length 402.6
  TOP w0.127: UC8.4 202.22,56.65 RE95.1 RE97.1 v2(200.71,55.81) 199.92,56.6 199.49,56.6 198.86,57.24 198.86,57.49 UC13.2 ; v2(49.57,51.55) 49.4,51.38 49.4,50.73 49.28,50.6 UZ23.4 ; PR900.1 173.52,43.09 175.56,43.09 177.36,41.29 178.16,41.29 v2(178.27,41.18) ; PR800.1 173.08,79.51 173.48,79.92 173.48,80.37 173.67,80.56 174.66,80.56 v2(175.11,80.12) ; PR607.1 166.5,34.1 166.5,34.81 165.81,35.5 v2(165.75,35.5)
  IN1 w0.081: v2(200.71,55.81) 199.39,57.13 199.39,67.64 203.24,71.48 203.24,77.11 202.38,77.97 198.19,77.97 196.1,80.05 188.43,80.05 185.93,77.55 179.63,77.55 177.06,80.12 v2(175.11,80.12)
  IN3 w0.089: v2(178.27,41.18) 178.59,41.18 178.8,40.97 179.57,40.97 179.66,40.88 179.66,40.23 179.57,40.14 179.13,40.14 178.77,40.49 177.81,40.49 176.89,41.4 174,41.4 173.36,40.76 171.23,40.76 171.15,40.84 167.84,40.84 167.32,41.36 164.45,41.36 163.95,40.86 163.95,39.54 164.21,39.29 164.8,39.29 165.03,39.52 v2(165.03,39.6) ; v2(200.71,55.81) 201.14,55.38 201.14,53.25 199.31,51.42 199.31,49.03 202.26,46.09 202.26,35.04 201.17,33.94 188,33.94 185.98,31.92 185.98,26.87 181.24,22.13 178.71,22.13 177.04,20.46 177.04,19.55 174.33,16.84 163.34,16.84 162.16,15.66 159.67,15.66 158.97,16.36 158.97,18.13 165.1,24.26 165.1,28.02 166.4,29.32 166.4,34.81 165.72,35.49 165.75,35.49 v2(165.75,35.5)
  IN4 w0.081: v2(49.57,51.55) 49.57,51.24 50.27,50.54 50.27,48.09 48.58,46.41 44.2,46.41 43.78,45.98 43.78,44.79 43.78,43.18 42.6,42 42.58,42 40.87,40.3 40.87,39.84 40.37,39.33 39.07,39.33 36.91,37.17 36.91,35.46 38.12,34.25 38.12,33.06 39.81,31.38 39.81,28.04 41.36,26.49 41.36,24.89 40.44,23.96 40.44,22.97 41.01,22.4 41.01,21.21 41.31,20.91 41.73,20.91 43.42,19.22 45.59,19.22 46.7,18.1 48.65,18.1 50.85,20.3 52.91,20.3 52.95,20.26 54.39,20.26 54.61,20.47 56.04,20.47 59.13,17.39 62.81,17.39 63.67,18.24 67,18.24 67.85,19.1 67.85,21.13 73.04,26.32 75.61,26.32 79.21,29.92 81.64,29.92 81.98,29.58 83.72,29.58 85.69,31.56 87.48,31.56 88.29,32.37 91.85,32.37 92.57,31.64 92.57,31.04 94.14,29.47 95.45,29.47 96.18,28.75 96.18,25.03 96.27,24.93 96.27,22.74 97.33,21.69 99.16,21.69 101.18,19.67 106.18,19.67 106.69,19.16 123.04,19.16 123.44,18.76 145.09,18.76 145.59,19.26 147.06,19.26 147.46,18.86 161.12,18.86 165.52,23.27 165.52,27.8 166.42,28.69 166.42,34.83 v2(165.75,35.5) 165.18,36.08 165.18,39.45 v2(165.03,39.6)
SUSACK#: length 66.4
  TOP w0.127: v2(185.57,62.26) 185.97,61.87 186.62,61.87 187.03,62.27 UE5.B7
  IN3 w0.089: v2(185.57,62.26) 185.31,62.52 185.31,63.49 185.53,63.71 186.74,63.71 188.11,65.08 188.11,66.23 188.46,66.57 188.94,66.57 189.19,66.82 189.19,68.92 187.56,70.55 184.13,70.55 183.65,71.04 179.29,71.04 178.89,70.65 176.77,70.65 171.97,65.85 171.51,65.85 170.85,65.19 169.12,65.19 167.76,63.82 163.69,63.82 162.5,62.63 162.5,61.54 161.67,60.72 160.35,60.72 160.12,60.49 160.12,60.23 157.75,57.85 157.75,57.12 157.3,56.68 156.85,56.68 156.29,57.23 154.8,57.23 154.22,56.64 152.56,56.64 152.3,56.9 150.5,56.9 150.12,56.52 145.95,56.52 145.75,56.32 145.75,54.88 v2(146.25,54.37)
  BOTTOM w0.127: v2(146.25,54.37) 145.88,54.75 UCPU1.AP11
SUSCLK: length 186.2
  TOP w0.127: v2(43.05,44.94) 43.65,45.54 44.52,45.54 44.63,45.43 44.63,44.76 44.62,44.75 44.62,44.64 R1255.2 ; R2662.2 173.76,42.01 173.16,41.41 v2(173.05,41.41)
  IN2 w0.089: v2(43.05,44.94) 43.49,44.51 43.49,37.12 44.17,36.43 44.63,36.43 45.28,35.78 45.28,35.05 44.03,33.8 42.39,33.8 41.52,32.94 41.52,32.25 42.3,31.47 43.75,31.47 44.44,32.15 46.14,32.15 53.45,24.84 55.59,24.84 56.12,24.3 58.1,24.3 60.11,26.31 63.16,26.31 64.52,27.67 76.1,27.67 77.57,29.14 v2(79.43,29.14)
  IN4 w0.081: v2(94.57,26.16) 94.57,26.33 95.16,26.92 95.16,27.57 92.07,30.66 91.69,30.66 91.42,30.93 89,30.93 87.02,28.96 81.72,28.96 81.41,29.26 80.88,29.26 80.5,28.89 79.68,28.89 v2(79.43,29.14)
  BOTTOM w0.076: RC48.1 145.54,45.42 144.3,46.67 143.84,46.67 142.64,47.86 142.64,49.87 142.38,50.13 UCPU1.BA17
  BOTTOM w0.127: RC48.1 145.55,44.95 145.55,43.33 ; 145.55,43.33 143.13,40.9 139.37,40.9 v3(138.74,40.28) 136.86,38.39 118.23,38.39 117.25,39.37 106.16,39.37 103.83,37.04 102.09,37.04 99.48,34.43 99.48,34.11 99.08,33.71 98.22,33.71 97.7,33.19 97.7,31.96 96.97,31.23 96.97,28.78 94.57,26.37 v2(94.57,26.16) ; 145.55,43.33 148.08,40.8 153.97,40.8 154.41,41.24 154.41,41.81 155,42.4 158.67,42.4 159.08,42 162.06,42 162.38,42.31 166.03,42.31 167.38,40.96 172.6,40.96 v2(173.05,41.41)
SYS_RESET#: length 129.6
  IN1 w0.081: v2(148.26,78.08) 149.15,78.08 149.2,78.02 149.5,78.02 149.64,77.89 149.64,76.04 151.7,73.99 151.7,72.83 v2(151.71,72.81) ; v2(163.59,69.35) 163.63,69.31 164.9,69.31 164.97,69.24 165.76,69.24 166.12,69.6 166.12,70.76 166.02,70.86 166.02,72.01 170.56,76.54 175.95,76.54 176.23,76.27 187.49,76.27 188.36,77.14 193.38,77.14 194.44,78.2 196.46,78.2 197.15,77.51 197.15,76.29 197.58,75.85 198.93,75.85 199.57,76.49 201.88,76.49 202.05,76.32 202.05,73.33 201.07,72.35 201.07,70.62 199.7,69.25 197.89,69.25 196.01,67.37 196.01,62.89 194.68,61.55 194.68,53.14 197.79,50.02 197.79,48.01 196.96,47.18 196.96,42.82 198.7,41.07 198.7,36.08 199.57,35.21 199.57,30.39 v2(199.95,30.01)
  IN2 w0.089: v2(163.59,69.35) 163.59,69.56 162.65,70.49 160.14,70.49 159.01,69.36 158.86,69.36 158.65,69.14 155.42,69.14 154.64,69.93 154.64,70.7 153.98,71.36 152.48,71.36 152.22,71.61 152.22,72.03 151.71,72.53 v2(151.71,72.81)
  BOTTOM w0.076: UCPU1.B5 150.47,71.66 150.8,71.99 151.26,71.99 151.46,72.19 151.46,72.47 151.71,72.72 v2(151.71,72.81)
  BOTTOM w0.127: v2(148.26,78.08) 148.59,78.41 v1(148.59,79.33) 148.59,79.9 148.39,80.11 RC291.2 147.45,80.08 RC224.2 ; v2(199.95,30.01) 200.07,29.89 200.76,29.89 JAPS1.13
SYS_RESET#_R: length 3.5
  BOTTOM w0.127: v1(146.53,79.1) 146.44,79.01 UC12.4 145.17,79.35 144.83,79.69 RC290.2 RC224.1
SYSTEM_WAKE#: length 14.5
  TOP w0.127: v2(29.54,53.02) 29.85,53.32 29.85,59.83 29.11,60.56 R1439.2
  BOTTOM w0.127: R1462.2 27,51.11 27,52.15 QT19.3 27.09,52.72 27.8,53.44 28.23,53.44 28.65,53.02 v2(29.54,53.02) v1(30.2,53.02)
TBT_AUX_N: length 54.7
  TOP w0.076: v2(19.31,64.89) 19.38,64.89 20.32,63.95 20.67,63.95 20.89,63.72 21.76,63.72 U722.J2
  TOP w0.127: v2(19.31,64.89) 19.04,65.16 R1478.2 ; CT42.2 52.08,64.71 52.58,64.22 v2(52.68,64.22)
  IN3 w0.089: v2(19.31,64.89) 19.05,64.64 19.05,63.28 19.29,63.05 19.67,63.05 21.69,61.02 22.6,61.02 23.15,60.47 23.15,60.35 23.51,59.99 24.62,59.99 27.28,57.33 30.18,57.33 31.84,55.66 35.59,55.66 36.63,56.69 36.63,56.7 36.78,56.86 37.42,56.86 38.68,55.6 39.31,55.6 42.04,52.87 48.3,52.87 50.09,54.66 50.09,62.21 50.91,63.04 50.92,63.04 52.1,64.22 v2(52.68,64.22)
TBT_AUX_N_C: length 7.6
  TOP w0.127: UT1.W15 v2(45.72,62.38) ; v2(48.95,64.52) 50.95,64.52 51.23,64.8 CT42.1
  BOTTOM w0.127: v2(48.95,64.52) 48.58,64.89 48.21,64.89 48.19,64.88 48.19,64.88 47.95,64.63 47.95,64.63 45.72,62.4 v2(45.72,62.38)
TBT_AUX_P: length 55
  TOP w0.127: CT41.2 v2(52.68,64.84) ; R1472.2 21.18,65.87 v2(21.88,65.18) 22.01,65.05 22.01,64.47 U722.J1
  IN3 w0.089: v2(52.68,64.84) 51.18,64.84 50.92,64.59 50.76,64.59 49.87,63.71 49.87,54.75 48.21,53.09 42.13,53.09 39.4,55.82 38.77,55.82 37.51,57.08 36.91,57.08 36.29,57.7 36.29,58.48 35.83,58.94 34.02,58.94 32.33,57.25 32.33,56.89 32.09,56.66 31.76,56.66 30.45,57.97 27.6,57.97 25.94,59.64 25.94,60.42 25.28,61.08 24.77,61.08 24.54,61.3 24.03,61.3 22.73,62.6 22.73,64.32 v2(21.88,65.18)
  BOTTOM w0.127: v2(52.68,64.84) 52.59,64.84 v1(51.26,63.51)
TBT_AUX_P_C: length 8.6
  TOP w0.127: UT1.Y15 46.7,62.11 46.44,62.37 v2(46.38,62.37) ; CT41.1 51.5,66.02 v2(51.56,66.09)
  BOTTOM w0.127: v2(51.56,66.09) 50.66,66.09 50.31,65.73 v1(50.31,64.44) 49.72,63.85 47.87,63.85 v2(46.38,62.37)
TBT_BATLOW#: length 4.3
  TOP w0.076: UT1.F2 40.05,56.15 39.83,55.93 39.83,55.38
  TOP w0.127: 39.83,55.38 39.83,54.9 39.43,54.5 39.43,54.46 39.4,54.43 v2(39.4,53.94)
  BOTTOM w0.127: RT25.2 38.09,52.88 v1(38.94,53.74) 39.15,53.94 v2(39.4,53.94)
TBT_CC1: length 18.4
  TOP w0.203: U722.K9 21.51,60.47 21.01,60.47 U722.L9 19.51,58.97 v2(19.51,58.93)
  TOP w0.292: v2(14.8,61.34) 15.01,61.55 D77.1 14.53,61.9 14.5,61.93
  TOP w0.305: 14.5,61.93 13.48,61.93 13.31,62.11 12.57,62.11 11.63,61.17 10.31,61.17 9.94,61.55 9.13,61.55 9.12,61.54 JUSBC1.A5 ; C1279.1 15.04,61.1 v2(14.8,61.34)
  IN3 w0.254: v2(19.51,58.93) 19.53,58.93 19.06,58.93 17.81,60.17 15.96,60.17 v2(14.8,61.34)
TBT_CC2: length 24.9
  TOP w0.203: U722.K10 U722.L10 20.92,59.97 20.29,59.34 20.29,58.92
  TOP w0.279: 9.58,55.33 9.82,55.57 10.35,55.57 D86.1 10.35,55.65 10.97,56.26
  TOP w0.305: JUSBC1.B5 5.35,59.99 3.91,58.56 3.91,55.71 4.29,55.33 9.58,55.33 ; 10.97,56.26 12.39,56.26 v3(13,56.87) 14.33,56.87 C1280.1 17.11,57.25 17.98,58.12 19.5,58.12 20.29,58.92
TBT_CIO_PLUG_EVENT#: length 247.7
  TOP w0.076: 46.28,54.59 46.24,54.62 46.24,55.93 46.24,55.93 UT1.W2
  TOP w0.102: 150.14,62.17 149.61,62.17 149.22,61.78 149.22,61.71 148.63,61.12 146.22,61.12 v2(145.82,60.71)
  TOP w0.127: 150.14,62.17 150.27,62.17 150.36,62.08 152.35,62.08 v2(152.63,61.81) ; v2(46.36,54.23) 46.36,54.5 46.28,54.59
  IN2 w0.089: v2(79.91,25.59) 79.86,25.54 65.76,25.54 61.15,20.93 51.49,20.93 50.95,20.39 39.54,20.39 37.99,21.94 37.53,21.94 37.31,22.16 37.31,22.88 37.66,23.22 37.66,29.46 38.23,30.03 38.74,30.03 39.41,30.7 39.41,31.42 39.23,31.59 39.23,32.48 39.61,32.86 39.94,32.86 41.42,34.34 41.42,35.63 39.84,37.21 39.84,45.67 41.59,47.42 41.59,48.44 44.54,51.39 44.54,52.56 44.93,52.96 45.09,52.96 v2(46.36,54.23) ; v2(87.78,18.55) 88.29,18.04 96.06,18.04 96.96,17.15 100.21,17.15 101.05,16.31 108.16,16.31 108.76,16.91 115.5,16.91 117.77,14.64 125.57,14.64 127.68,16.75 130.47,16.75 132.44,14.78 157.03,14.78 159.68,17.44 163.4,17.44 165.79,19.82 165.79,26.16 166.76,27.13 166.76,33.13 168.49,34.86 168.49,37.77 166.73,39.53 166.73,40.62 166.8,40.69 166.8,42.36 166.39,42.76 166.39,48.17 166.98,48.76 166.98,50.25 166.21,51.02 166.21,55.25 164.14,57.32 158.6,57.32 158.15,57.77 158.15,57.9 157.44,58.61 157.14,58.61 155.68,60.07 154.7,60.07 152.97,61.81 v2(152.63,61.81)
  IN3 w0.089: v2(87.78,18.55) 87.76,18.55 86.86,17.66 81.56,17.66 80.32,18.9 80.32,24.7 79.91,25.1 v2(79.91,25.59)
  BOTTOM w0.127: v2(46.36,54.23) 46.53,54.06 RT23.2 ; UCPU1.AB12 145.49,61.05 v2(145.82,60.71)
TBT_DBG_CTL1: length 6
  TOP w0.127: v2(27.31,63.17) 27.34,63.17 27.61,63.44 R1454.2 ; U722.E4 23.94,63.04 v2(23.94,63.5)
  IN2 w0.089: v2(27.31,63.17) 27.3,63.18 26.16,63.18 25.35,63.99 24.26,63.99 23.95,63.68 23.95,63.5 v2(23.94,63.5)
  BOTTOM w0.127: v2(27.31,63.17) 26.86,63.17 v1(26.81,63.12)
TBT_DBG_CTL2: length 5.3
  TOP w0.076: U722.D5 24.51,62.47 24.62,62.47 25,62.85 v2(25,62.89)
  TOP w0.127: R1460.2 27.75,62.57 27.66,62.66 27.65,62.66 v2(27.64,62.67)
  IN2 w0.089: v2(27.64,62.67) 27.64,62.67 27.64,62.53 27.34,62.23 26.89,62.23 26.76,62.36 26.17,62.36 25.65,62.87 25.02,62.87 v2(25,62.89)
  BOTTOM w0.127: v2(27.64,62.67) v1(28.4,62.67)
TBT_DDC_CLK: length 7.4
  TOP w0.076: UT1.Y2 46.7,55.93 46.7,55.35
  TOP w0.127: RT33.2 52.15,54.7 51.48,54.03 47.6,54.03 46.7,54.93 46.7,55.35
TBT_DDC_DATA: length 8.1
  TOP w0.076: UT1.Y1 46.49,55.31
  TOP w0.127: 46.49,55.31 46.49,54.72 47.43,53.78 51.75,53.78 52.32,54.35 52.57,54.35 52.73,54.52 RT34.2
TBT_DEBUG3: length 4.9
  TOP w0.076: 20.13,63.88 20.25,63.76 20.6,63.76 20.89,63.47 U722.L3
  TOP w0.127: 20.13,63.88 19.83,64.18 v1(19.64,64.18) 18.95,64.18 RT188.1 18.45,64.68 17.45,64.68 17.03,64.26 R1463.2
TBT_DEBUG4: length 6.3
  TOP w0.076: U722.K3 21.27,63.23 20.9,63.23 20.54,63.6 20.14,63.6 20.1,63.64 19.99,63.64
  TOP w0.127: R1464.2 16.45,63.21 16.91,62.74 18.05,62.74 v1(18.09,62.77) 18.81,63.5 RT187.1 18.89,63.84 19.79,63.84 19.99,63.64
TBT_FORCE_PWR: length 151.3
  TOP w0.127: UT1.H4 40.54,57.16 v2(40.54,57.16) ; v1(152.9,72.51) v2(152.3,72.51) 152.3,72.48 152.15,72.32 151.25,72.32 150.72,71.79 148.57,71.79 RC247.2
  IN1 w0.081: v2(40.54,57.16) 40.54,56.57 41.22,55.89 42.74,55.89 42.83,55.98 44.74,55.98 44.98,56.22 44.98,56.64 44.69,56.93 44.69,57.32 45.33,57.97 45.33,59.28 45.78,59.72 47.25,59.72 50.35,62.83 52.01,62.83 52.96,61.87 56.56,61.87 v2(57.24,62.55)
  IN3 w0.089: v2(131.53,72.72) 131.25,72.72 130.7,72.16 129.09,72.16 128.96,72.02 127.68,72.02 127.52,72.18 122.75,72.18 122.72,72.15 121,72.15 120.45,71.6 118.35,71.6 117.99,71.97 112.47,71.97 111.02,70.52 109.4,70.52 108.09,69.2 97.72,69.2 96.22,70.71 92.1,70.71 91.42,70.02 90,70.02 89.66,69.68 87.01,69.68 86.49,69.16 82.75,69.16 82.35,69.55 79.11,69.55 78.39,70.27 74.5,70.27 73.74,71.03 71.4,71.03 70.93,71.51 64.35,71.51 64.28,71.43 62.49,71.43 61.91,70.85 60.51,70.85 59.36,72 58.29,72 57.89,71.6 57.89,70.67 56.74,69.53 56.74,68.39 58.16,66.97 58.16,63.49 57.24,62.57 v2(57.24,62.55)
  IN4 w0.081: v2(152.3,72.51) 152.02,72.51 151.91,72.4 144.84,72.4 144.31,71.86 138.87,71.86 137.34,70.33 137.34,68.88 136.54,68.08 134.17,68.08 133.51,68.74 133.15,68.74 133.07,68.82 133.07,70.97 131.53,72.5 v2(131.53,72.72)
  BOTTOM w0.127: v2(40.54,57.16) 40.01,56.63 40.01,55.94 39.71,55.65 38.65,55.65 38.34,55.34 38.34,54.41 37.92,53.98 37.42,53.98 36.35,52.91 RT38.2
TBT_HPD: length 20
  TOP w0.127: R1437.2 29.21,58.66 29.46,58.91 29.46,59.36 29.01,59.82 v2(28.98,59.82) ; v2(42.47,57.18) UT1.M4
  IN3 w0.089: v2(42.47,57.18) 42.42,57.18 41.91,56.68 41.72,56.68 41.4,56.99 40.97,56.99 40.67,56.69 38.77,56.69 37.78,57.68 36.98,57.68 36.74,57.92 36.74,58.64 35.82,59.56 35.12,59.56 34.57,60.11 33.86,60.11 33.1,59.34 29.46,59.34 v2(28.98,59.82)
  BOTTOM w0.127: v2(42.47,57.18) 42.47,56.49 RT43.2
TBT_I2C_B_N: length 11.1
  TOP w0.076: 18.22,60.2 18.24,60.2 18.28,60.25 18.99,60.25 19.06,60.32 19.14,60.32 19.43,60.61 19.43,60.94 19.55,61.06 20.12,61.06 20.5,61.44 20.97,61.44 U722.L7
  TOP w0.127: v2(13.62,61.43) 13.96,61.08 13.96,60.72 14.24,60.44 14.48,60.2 v4(16.76,60.2) 18.22,60.2
  BOTTOM w0.127: v2(13.62,61.43) 13.92,61.13 13.92,60.95 13.42,60.44 12.99,60.44 12.89,60.54 ML7.4
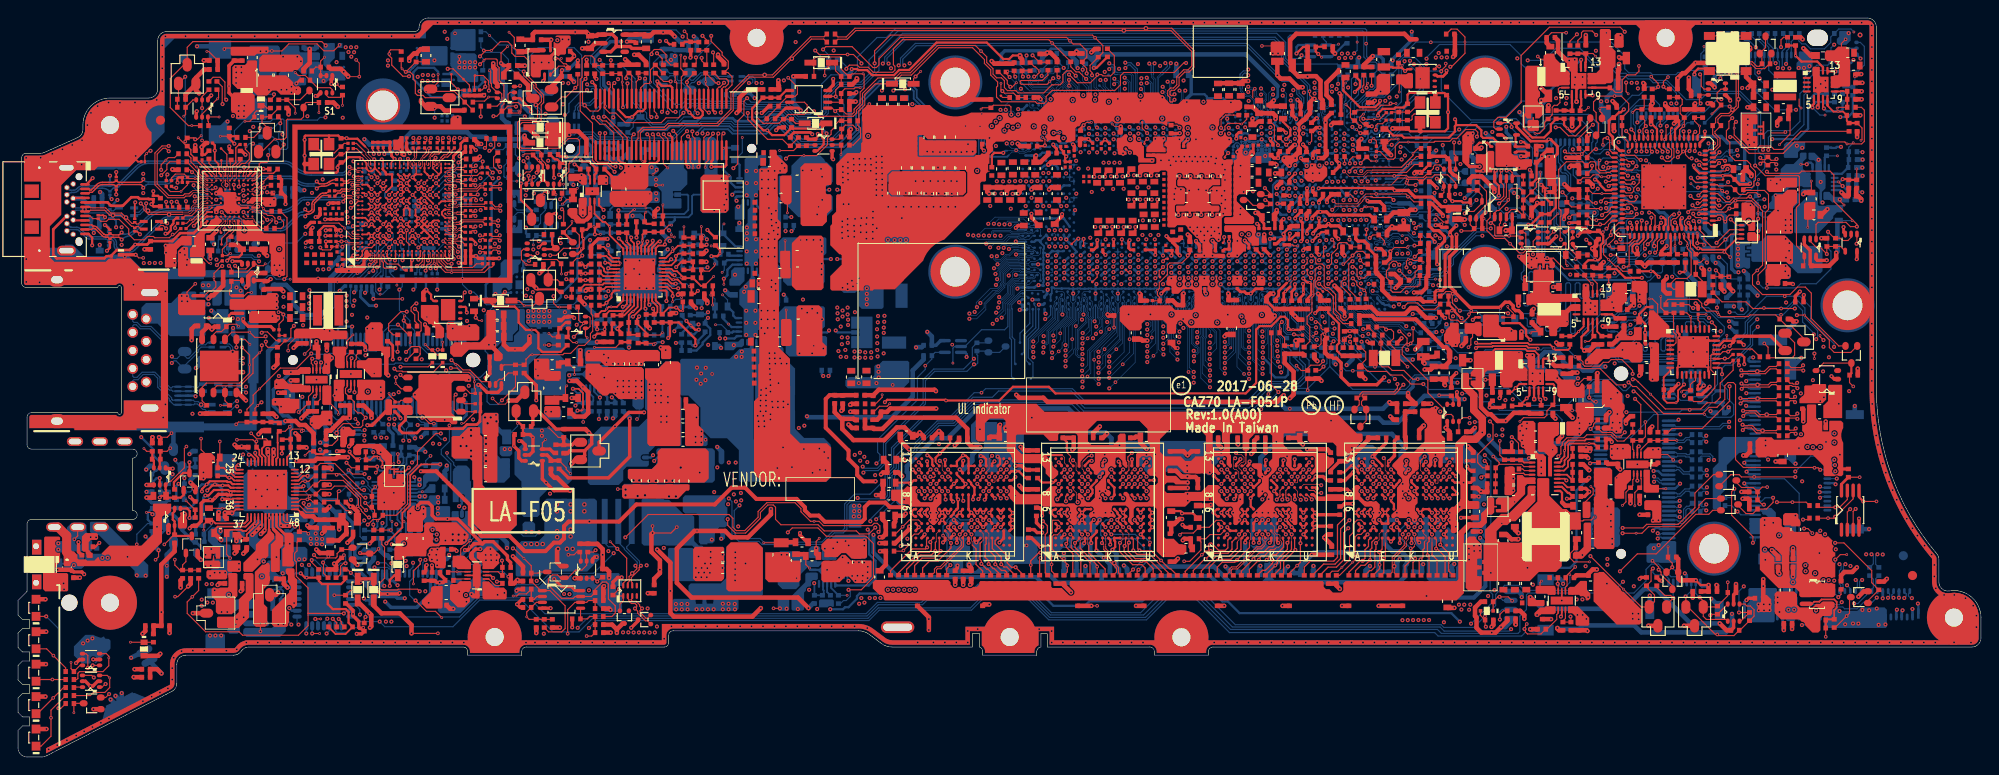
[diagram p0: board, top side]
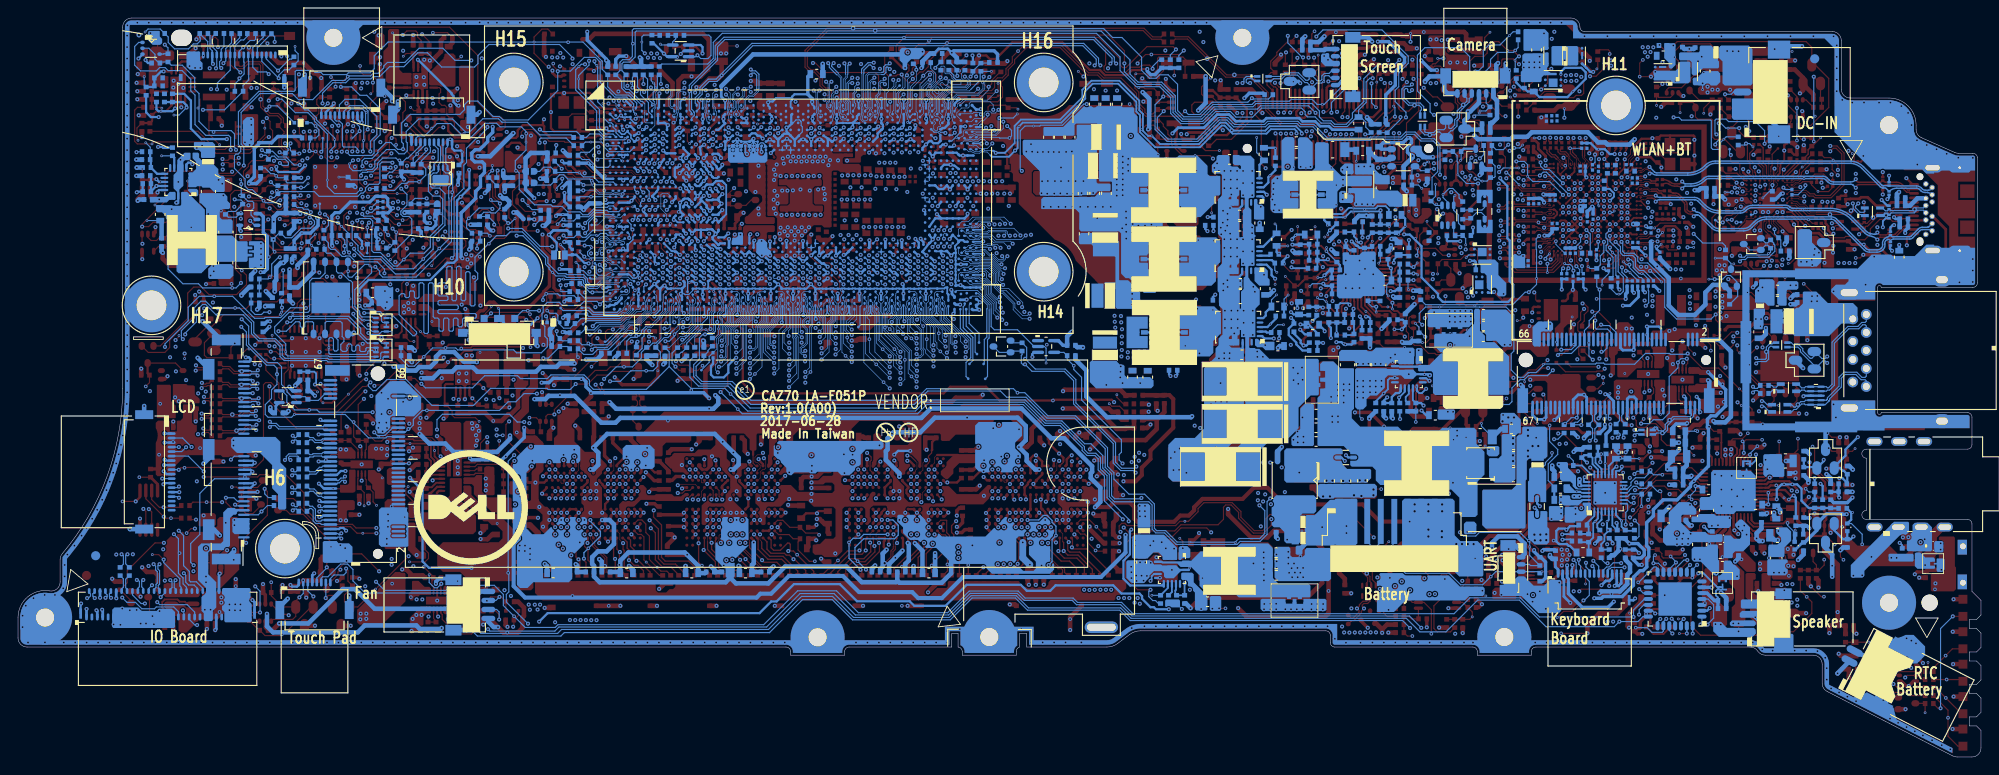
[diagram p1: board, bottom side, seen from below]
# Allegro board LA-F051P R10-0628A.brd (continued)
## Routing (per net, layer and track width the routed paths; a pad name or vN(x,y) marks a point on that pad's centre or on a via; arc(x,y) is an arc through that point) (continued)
TBT_I2C_B_N_R: length 5.6
  BOTTOM w0.127: ML7.3 10.92,60.92 10.61,60.61 10.38,60.61 D90.1 10.19,60.79 10.02,60.63 7.51,60.63 v4(7.37,60.77) 7.21,60.93 6.38,60.93 JUSBC1.B7
TBT_I2C_B_P: length 11.1
  TOP w0.076: U722.K7 21.26,61.72 20.87,61.72 20.79,61.64 20.41,61.64 20.03,61.26 19.46,61.26 19.23,61.03 19.23,60.7 19.05,60.52 18.98,60.52 18.91,60.45 18.24,60.45 18.23,60.46 18.22,60.46
  TOP w0.127: 18.22,60.46 14.59,60.46 v4(14.42,60.62) 14.22,60.83 v2(14.22,61.43)
  BOTTOM w0.127: v2(14.22,61.43) 14.17,61.38 14.17,60.84 13.52,60.19 13.01,60.19 ML7.1
TBT_I2C_B_P_R: length 5.6
  BOTTOM w0.127: JUSBC1.B6 6.41,60.68 7.1,60.68 7.41,60.37 9.98,60.37 D91.1 10.39,60.35 10.68,60.35 10.95,60.07 ML7.2
TBT_I2C_CLK: length 65
  TOP w0.076: UT1.U2 44.87,55.91 44.87,55.45 44.86,55.44
  TOP w0.127: v2(44.27,54.47) 44.35,54.47 44.86,54.97 44.86,55.44 ; U722.D2 24.54,63.95 24.54,63.34 v2(24.49,63.3)
  IN1 w0.081: v2(44.27,54.47) 44.47,54.28 44.47,53.74 43.88,53.15 40.54,53.15 39.26,51.87 39.26,51.52 38.82,51.09 38.82,50.77 37.73,49.67 36.81,49.67 36.43,49.3 34.92,49.3 31.73,46.11 31.73,42.64 27.06,37.96 24.48,37.96 23.84,38.6 23.84,45.74 26.18,48.08 26.18,49.63 26.68,50.13 26.68,51.7 24.84,53.53 24.84,56.06 23.89,57.01 23.89,58.36 24.16,58.63 24.16,59.19 23.2,60.15 23.2,61.25 23,61.46 23,62.81 22.74,63.07 22.74,63.63 23.09,63.98 24.41,63.98 24.48,63.97 24.48,63.97 24.56,63.88 24.5,63.31 v2(24.49,63.3)
  BOTTOM w0.127: v2(44.27,54.47) 44.27,54.47 44.27,53.78 RT36.2
TBT_I2C_DATA: length 65.5
  TOP w0.076: U722.D1 24.51,64.47 24.51,64.83 v2(24.66,64.98)
  TOP w0.127: UT1.U1 45.08,55.66 45.08,54.68 44.9,54.5 v2(44.9,54.45)
  IN1 w0.081: v2(24.66,64.98) 24.59,64.25 24.5,64.18 24.42,64.19 23,64.19 22.53,63.72 22.53,62.98 22.79,62.72 22.79,61.37 22.99,61.17 22.99,60.07 23.95,59.11 23.95,58.72 23.68,58.44 23.68,56.92 24.63,55.97 24.63,53.45 26.47,51.61 26.47,50.22 25.97,49.72 25.97,48.16 23.63,45.83 23.63,38.51 24.39,37.76 27.15,37.76 31.94,42.55 31.94,46.02 35.01,49.09 36.52,49.09 36.89,49.46 37.81,49.46 39.03,50.68 39.03,51 39.47,51.44 39.47,51.79 40.63,52.95 43.97,52.95 44.68,53.65 44.68,54.24 v2(44.9,54.45)
  BOTTOM w0.127: v2(44.9,54.45) 44.53,54.09 44.53,53.79 RT35.2
TBT_I2C_INT#: length 32.2
  TOP w0.127: UT1.J4 41.48,56.85 v2(41.18,56.54) ; U722.C1 25.01,64.77 25.07,64.83 25.07,64.85 25.1,64.88 v2(25.1,65.44)
  IN3 w0.089: v2(25.1,65.44) 24.38,65.44 23.54,64.59 23.54,63.29 23.15,62.91 23.15,62.48 24.12,61.52 24.63,61.52 24.86,61.29 25.37,61.29 26.15,60.51 26.15,59.73 27.63,58.25 30.77,58.25 31.38,57.65 32.39,57.65 33.9,59.16 35.92,59.16 36.51,58.57 36.51,57.79 37,57.29 37.6,57.29 38.71,56.18 40.82,56.18 v2(41.18,56.54)
  BOTTOM w0.127: v2(41.18,56.54) 41.18,56.29 v1(40.89,56) 40.51,55.62 40.51,53.46 RT47.2
TBT_JTAG_TCK: length 28.4
  TOP w0.127: v2(47.68,76.36) 48.28,76.36 TC41.1 50.09,74.56 50.09,74 ; UT1.T4 44.74,56.85 44.43,56.54 v2(44.42,56.54)
  IN2 w0.089: v2(47.68,76.36) 47.68,76.25 47.38,75.95 47.38,74.44 42.78,69.84 42.78,68.23 43.62,67.39 43.63,67.39 44.32,66.69 44.32,64.3 43.61,63.59 43.61,62.89 43.36,62.63 43.36,62.06 43.53,61.89 43.53,59.29 44.12,58.7 44.65,58.7 44.86,58.49 44.86,57.73 44.21,57.08 44.21,56.75 v2(44.42,56.54)
TBT_JTAG_TDI: length 28.4
  TOP w0.127: TC39.1 v2(51.84,74.38) 51.47,74.01 RT9.2 ; UT1.Y4 46.7,56.85 v2(46.39,57.16)
  IN2 w0.089: v2(51.84,74.38) 51.66,74.56 47.8,74.56 42.99,69.75 42.99,68.32 43.74,67.57 45.82,67.57 46.95,66.44 46.95,57.72 v2(46.39,57.16)
TBT_JTAG_TDO: length 27.6
  TOP w0.127: RT6.2 48.9,73.99 v2(48.81,74.08) 48.08,74.8 TC42.1 ; UT1.W4 v2(45.74,57.16)
  IN2 w0.089: v2(45.74,57.16) 46.17,56.73 46.58,56.73 47.17,57.31 47.17,66.53 45.91,67.79 43.9,67.79 43.21,68.48 43.21,69.66 47.5,73.95 48.68,73.95 v2(48.81,74.08)
TBT_JTAG_TMS: length 33.7
  TOP w0.127: UT1.V4 45.4,56.85 45.09,57.16 v2(45.09,57.16) ; v2(52.25,73.95) 52.26,73.96 52.26,74.57 52.2,74.63 52.2,75.04 51.62,75.62 TC40.1 50.65,75.57 RT8.2
  IN2 w0.089: v2(45.09,57.16) 45.18,57.16 45.82,56.51 46.72,56.51 47.38,57.17 47.38,66.62 46,68 43.99,68 43.42,68.57 43.42,69.57 47.24,73.38 49.05,73.38 49.58,73.91 52.21,73.91 v2(52.25,73.95)
TBT_LDO_BMC: length 2.1
  TOP w0.076: 24.08,65.49 24.08,64.54 U722.E1
  TOP w0.127: CT144.1 24.65,66.06 24.08,65.49
TBT_LSRX: length 28.5
  TOP w0.127: UT1.A4 37.74,57.06 36.66,57.06 36.52,57.21 v1(36.4,57.21) v2(35.89,57.21) RT45.2 ; R1464.1 17.2,63.16 v2(17.55,63.16)
  IN1 w0.081: v2(19.48,63.45) 19.28,63.65 18.63,63.65 18.14,63.16 v2(17.55,63.16)
  IN3 w0.089: v2(19.48,63.45) 19.75,63.71 20.47,63.71 21.01,63.18 21.01,62.09 21.86,61.24 22.69,61.24 23.05,60.87 24.36,60.87 24.61,60.62 24.61,60.31 27.37,57.54 30.27,57.54 31.89,55.91 34.32,55.91 35.61,57.21 v2(35.89,57.21)
  BOTTOM w0.127: v2(19.48,63.45) 19.48,63.21 20.3,62.39 R1461.1
TBT_LSRX_R: length 1.5
  TOP w0.076: U722.K4 21.51,62.97 21.71,62.97 v2(21.92,63.18)
  BOTTOM w0.127: v2(21.92,63.18) 21.71,62.97 R1461.2
TBT_LSTX: length 33.3
  TOP w0.127: R1459.1 16.43,61.19 v2(16.43,61.6) ; RT44.2 35.84,57.84 v2(35.89,57.79) 36.7,57.79 36.97,57.52 37.74,57.52 UT1.A5 ; R1463.1 16.45,64.51 v2(16.57,64.64)
  IN3 w0.089: 16.59,64.64 16.43,64.48 v2(16.43,61.6) ; 16.59,64.64 17.31,64.64 18.19,65.52 20.9,65.52 22.52,63.91 22.52,62.51 23.94,61.09 24.45,61.09 24.68,60.86 25.19,60.86 25.72,60.33 25.72,59.55 27.51,57.76 30.36,57.76 31.98,56.13 34.23,56.13 v2(35.89,57.79) ; 16.59,64.64 v2(16.57,64.64)
  BOTTOM w0.127: v1(35.34,58.2) 35.74,57.79 v2(35.89,57.79)
TBT_LSTX_R: length 5.6
  TOP w0.076: U722.L4 20.94,62.97 20.68,63.24 v2(20.04,63.24)
  TOP w0.127: R1459.2 17.03,61.18 v2(17.03,61.6)
  IN1 w0.081: v2(17.03,61.6) 18,62.57 18.14,62.57 18.23,62.66 19.83,62.66 20.04,62.88 v2(20.04,63.24)
TBT_PCIE_WAKE#: length 43
  TOP w0.076: UT1.W1 46.02,55.68 46.02,55.46 46.08,55.41 46.08,54.79 45.92,54.63
  TOP w0.127: v2(45.77,54.23) 45.77,54.48 45.92,54.63
  IN2 w0.089: v2(38.96,30.97) 38.96,31.63 38.75,31.85 38.75,34.49 39.08,34.82 39.08,36.13 39.62,36.67 39.62,45.76 41.34,47.47 41.34,48.49 44.32,51.48 44.32,52.65 44.84,53.17 45,53.17 45.77,53.94 v2(45.77,54.23)
  IN3 w0.089: v2(38.96,30.97) 39.35,30.97 39.82,31.45 44.23,31.45 44.36,31.32 46.22,31.32 46.53,31.63 47.44,31.63 47.97,32.17 47.97,34.66 v2(47.37,35.26)
  BOTTOM w0.127: RT22.2 45.95,54.05 v2(45.77,54.23) ; v2(47.37,35.26) 46.94,35.26 RE120.1
TBT_PD_SBU1: length 3.8
  TOP w0.076: U722.K8 21.36,60.82 21.36,60.82 21.27,60.73 20.82,60.73
  TOP w0.127: 20.82,60.73 19.46,59.37 19.39,59.37 18.65,58.63 R1457.1
TBT_PD_SBU2: length 3.4
  TOP w0.127: U722.L8 20.71,60.97 19.34,59.61 v1(19.14,59.61) 19.1,59.61 18.72,59.22 R1458.1
TBT_PERST_N: length 4.8
  TOP w0.127: v2(41.83,57.16) 41.87,57.13 UT1.L4
  BOTTOM w0.127: v2(41.83,57.16) 41.85,57.15 41.85,55.99 42.24,55.6 42.24,54.61 R104.2 43.38,54.21 v1(43.59,54.42)
TBT_PWR_EN: length 25.1
  TOP w0.127: v2(155.07,58.68) 155.35,58.96 v1(155.6,58.96)
  IN3 w0.089: v2(155.07,58.68) 154.91,58.84 153.21,58.84 152.75,59.31 150.14,59.31 149.92,59.08 145.57,59.08 144.03,57.54 144.03,56.94 143.02,55.93 143.02,52.88 144.02,51.88 147.58,51.88 v2(148.13,52.44)
  BOTTOM w0.127: UCPU1.AW7 148.37,52.2 v2(148.13,52.44) ; v2(155.07,58.68) 155.4,59.01 RH556.1
TBT_RBIAS: length 9.2
  TOP w0.127: UT1.H6 41.18,57.82 v2(41.18,57.82)
  BOTTOM w0.127: RT10.1 41.03,51.94 40.46,51.36 v1(40.18,51.36) 39.99,51.36 39.69,51.66 39.69,53.28 40.26,53.85 40.26,56.29 41.16,57.19 41.16,57.8 v2(41.18,57.82)
TBT_RESET_N: length 16.3
  TOP w0.127: v2(27.04,47.08) 27.14,47.17 27.68,47.17 28.65,46.2 RT120.1 ; v2(23.5,58.86) 23.5,59.46 U722.F11
  IN3 w0.089: v2(27.04,47.08) 27,47.08 25.95,48.13 25.95,54.51 23.5,56.96 v2(23.5,58.86)
TBT_RESET_N_EC: length 291.4
  TOP w0.127: v2(193.08,59.73) v1(193.08,60.44) 193.08,60.98 192.34,61.73 190.4,61.73 189.98,61.3 189.61,61.3 189.03,60.73 188.63,60.73 188.34,61.02 UE5.A4 ; v2(30.61,47.84) 30.28,47.51 30.28,46.58 29.88,46.18 RT121.1 28.9,45.46 RE90.1 27.72,45.46 27.5,45.69 v2(27.5,46.09) ; v2(22.07,54.59) 22.53,55.05 R1465.2
  IN2 w0.089: v2(30.61,47.84) 30.61,46.85 31.98,45.48 31.98,44.1 33.19,42.88 33.71,42.88 34.56,42.03 34.56,41.46 34.08,40.98 34.08,39.23 34.55,38.76 34.55,32.25 33.57,31.28 33.57,25.76 34.14,25.19 34.14,23.14 32.99,21.99 32.99,21.06 37.73,16.33 38.33,16.33 39.52,15.13 39.52,15.01 39.91,14.62 41.59,14.62 42.13,15.16 50.72,15.16 51.62,16.06 54.17,16.06 54.77,15.46 64.97,15.46 65.49,14.94 70.42,14.94 v2(70.89,14.47)
  IN3 w0.089: v2(22.07,54.59) 22.04,54.55 22.04,53.65 25.54,50.15 25.54,47.52 26.97,46.09 v2(27.5,46.09)
  IN4 w0.081: v2(70.89,14.47) 72.04,15.62 95.09,15.62 95.57,16.1 99.51,16.1 99.99,15.62 131.76,15.62 133.85,13.53 200.54,13.53 202.53,15.53 203,15.53 204.37,16.9 210.08,16.9 210.58,17.41 210.58,17.98 209.99,18.58 208,18.58 206.46,20.12 206.46,20.39 202.47,24.38 202.47,32.84 198.6,36.71 198.6,41.28 196.97,42.91 196.97,46.96 198.22,48.21 198.22,49.26 194.97,52.52 194.97,55.2 192.65,57.52 192.65,59.24 193.08,59.68 v2(193.08,59.73)
TBT_RESET_N_R: length 21.1
  TOP w0.127: v2(39.89,57.16) 39.88,57.15 40.18,56.85 UT1.F4 ; RT121.2 28.99,46.77 RT120.2 28.97,47.39 RT51.2 28.96,48.04 29.44,48.52 v2(29.44,49.11) 29.19,49.36 v3(28.91,49.36)
  BOTTOM w0.127: v2(39.89,57.16) 39.75,57.03 39.75,56.1 39.55,55.9 38.49,55.9 38.09,55.49 38.09,55.04 37.86,54.82 36.98,54.82 35.09,52.93 35.09,49.91 33.78,48.6 29.95,48.6 v2(29.44,49.11)
TBT_ROM_CLK: length 22.3
  TOP w0.076: UT1.AB4 47.4,57.06 47.64,56.83 48.13,56.83 48.81,56.15 v2(48.81,56.05)
  TOP w0.127: v2(41.92,42.12) 41.91,42.11 v1(41.91,41.46) 42.52,40.85 UT5.6
  IN1 w0.081: v2(48.81,56.05) 48.86,56.05 49.28,55.63 49.28,54.07 45.21,50 44.92,50 42.95,48.03 42.95,47.74 40.98,45.76 40.98,43.01 41.87,42.12 v2(41.92,42.12)
TBT_ROM_CS#: length 29
  TOP w0.076: v2(48.88,55.47) 48.73,55.47 48.39,55.81 48.39,56.27 48.05,56.61 47.87,56.61 UT1.AC3
  TOP w0.127: v2(48.57,40.22) 48.39,40.04 48.39,38.54 48.62,38.31 UT5.1 RT18.2 50.74,38.3 49.45,37.02 v1(49.23,37.02)
  IN2 w0.089: v2(48.88,55.47) 48.7,55.47 48.44,55.74 47.72,55.74 47.23,55.25 47.23,53.43 48.2,52.46 48.2,49.73 47.4,48.94 47.4,46.26 48.77,44.9 48.77,42.29 48.19,41.72 48.19,39.75 48.49,39.46 48.87,39.46 49.05,39.63 49.05,39.96 48.79,40.22 v2(48.57,40.22)
TBT_ROM_DI: length 25.2
  TOP w0.076: UT1.AB3 47.64,56.38 48.03,56.38 48.16,56.24 48.16,55.38 48.27,55.27 v2(48.33,55.27)
  TOP w0.127: UT5.5 42.71,42.12 v2(42.44,42.4)
  IN1 w0.081: v2(48.33,55.27) 48.33,56.14 48.53,56.33 48.53,56.79 48.77,57.03 49.09,57.03 49.49,56.64 49.49,53.98 45.29,49.79 45.01,49.79 43.16,47.94 43.16,47.65 41.18,45.68 41.18,43.1 41.59,42.69 42.15,42.69 v2(42.44,42.4)
  BOTTOM w0.127: v1(47.88,55.84) 48.33,55.38 v2(48.33,55.27)
TBT_ROM_DO: length 25.9
  TOP w0.127: v2(48.93,56.63) 48.55,57.02 48.03,57.02 47.99,57.07 UT1.AC4 ; RT16.2 49.53,39.2 UT5.2 49.15,39.71 v2(49.63,40.19)
  IN2 w0.089: v2(48.93,56.63) 48.82,56.63 48.14,55.95 47.63,55.95 47.02,55.34 47.02,53.34 47.98,52.37 47.98,49.82 47.19,49.03 47.19,46.17 48.5,44.86 48.5,42.33 47.97,41.81 47.97,39.66 48.4,39.24 48.96,39.24 49.26,39.54 49.26,39.99 49.47,40.19 v2(49.63,40.19)
TBT_ROM_HOLD#: length 2.7
  TOP w0.127: v1(41.17,40.34) 41.17,40.18 41.83,39.52 RT15.2 42.3,39.39 42.49,39.58 UT5.7
TBT_ROM_WP#: length 21.6
  TOP w0.127: v2(45.49,55.1) 45.57,55.18 45.57,55.68 UT1.V1 ; v2(48.03,43.16) 48.71,43.16 49.17,42.69 50.03,42.69 50.64,42.09 v1(50.64,41.64) 50.64,40.98 50.74,40.88 RT17.2 50.18,40.34 49.67,40.85 UT5.3
  IN2 w0.089: v2(48.03,43.16) 47.45,43.75 47.45,45.61 46.97,46.08 46.97,49.11 47.77,49.91 47.77,52.28 46.8,53.25 46.8,54.95 46.65,55.1 v2(45.49,55.1)
TBT_RSENSE: length 6.6
  TOP w0.127: UT1.J6 41.17,58.48 v2(41.17,58.48)
  BOTTOM w0.127: v2(41.17,58.48) 41.62,58.04 41.62,57.62 41.42,57.41 41.42,56.92 41.6,56.74 41.6,56.22 40.83,55.45 40.83,53.33 RT10.2
TBT_SBU1: length 12.9
  TOP w0.127: R1457.2 17.98,58.63 17.32,57.98 v3(17.15,57.98) 16.79,57.62 15.17,57.62 15.02,57.76 14.36,57.76 13.99,57.39 12.9,57.39 12.28,58.01 12.28,58.59 11.21,59.67 10.04,59.67 9.82,59.44 9.18,59.44 D78.1 8.29,59.74 7.99,60.04 JUSBC1.A8
TBT_SBU2: length 30.8
  TOP w0.127: v2(17.43,58.7) 17.43,58.94 R1458.2 ; D87.1 14.07,66.76 v1(14.28,66.96) 14.58,67.26 v2(14.7,67.26)
  IN1 w0.081: JUSBC1.B8 4.13,62.88 4.13,65.71 4.61,66.18 7.76,66.18 8.37,65.57 12.87,65.57 14.56,67.26 v2(14.7,67.26) 14.88,67.08 14.88,63.95 15.72,63.12 15.72,57.78 15.98,57.52 16.38,57.52 17.43,58.57 v2(17.43,58.7)
TBT_SLP_S3#: length 4.9
  TOP w0.076: v2(39.14,55.2) 39.18,55.24 39.21,55.24 39.37,55.4 39.37,55.9 UT1.D2
  BOTTOM w0.127: RT119.2 36.92,53.06 37.5,53.64 v1(37.65,53.64) 37.93,53.64 38.6,54.3 38.6,54.94 38.86,55.2 v2(39.14,55.2)
TBT_SRC_CFG1: length 5.7
  TOP w0.127: R1403.1 50.86,54.73 50.44,54.31 47.68,54.31 46.94,55.05 UT1.AA1
TBT_SRC_HPD: length 3.5
  TOP w0.127: R1405.1 42.84,54.02 42.16,54.7 40.99,54.7 40.67,55.03 40.67,55.52 UT1.G1
TBT_SVR_IND: length 1.8
  BOTTOM w0.127: v2(36.72,53.95) 36.67,53.95 v1(35.43,52.71)
  vias: v2(36.45,51.2) v2(36.44,50.61) v2(36.46,50.02) v2(37.13,54.38) v2(37.72,54.4)
TBT_TEST_EN: length 4.7
  TOP w0.127: v2(39.01,54.63) 39.11,54.63 39.52,55.05 39.52,55.05 39.58,55.11 39.58,55.68 UT1.E1
  BOTTOM w0.127: v1(39.68,54.95) 39.36,54.63 v2(39.01,54.63) 39.01,54.32 37.91,53.21 37.71,53.21 37.49,52.99 RT3.2
TBT_TEST_PWRG: length 2.5
  TOP w0.076: 48.08,57.29 47.64,57.29 UT1.AB5
  TOP w0.127: RT4.2 49.62,56.83 49.21,57.24 48.13,57.24 48.08,57.29
TBT_TMU_CLK_OUT: length 4.8
  TOP w0.076: 45.87,54.94 45.87,55.33 45.8,55.41 45.8,55.91 UT1.V2
  TOP w0.127: 45.87,54.94 45.61,54.68 45.44,54.68 45.32,54.56 45.32,54.07 v2(45.23,53.97)
  BOTTOM w0.127: v1(46.2,54.77) 46.08,54.65 45.57,54.65 45.31,54.38 45.31,54.05 v2(45.23,53.97) 45.23,53.4 RT37.2
TBT_USB2_D_N: length 39.9
  TOP w0.076: 19.14,62.66 19.15,62.67 19.18,62.67 19.22,62.71 19.23,62.71 19.37,62.85 20.76,62.85 20.88,62.73 21.04,62.73 21.04,62.73 21.25,62.73 21.35,62.63 U722.K5
  TOP w0.127: UT1.D20 38.92,64.65 v2(39.23,64.33) ; 19.14,62.66 18.97,62.49 18.5,62.49 18.32,62.31 16.73,62.31 15.44,63.6 15.44,66.91 16.08,67.55 16.39,67.55 16.72,67.22 v2(16.72,67.22)
  IN4 w0.091: v2(16.72,67.22) 16.72,67.23 17.07,67.58 17.63,67.58 19.08,69.03 23.96,69.03 24.5,68.49 30.26,68.49 30.88,69.11 36.68,69.11 38.58,67.21 38.58,66.13 39.69,65.03 39.69,64.68 39.34,64.33 v2(39.23,64.33)
TBT_USB2_D_P: length 40
  TOP w0.076: 19.32,62.48 19.37,62.53 19.37,62.56 19.46,62.65 20.67,62.65 20.79,62.53 20.95,62.53 U722.L5
  TOP w0.127: v2(39.88,64.31) 39.88,64.31 39.55,64.63 UT1.E20 ; 19.32,62.48 19.07,62.24 18.61,62.24 18.42,62.05 16.63,62.05 15.19,63.49 15.19,67.01 15.98,67.8 v2(16.72,67.8)
  IN4 w0.091: v2(16.72,67.8) 16.75,67.77 17.55,67.77 19,69.22 24.04,69.22 24.58,68.68 30.18,68.68 30.8,69.3 36.76,69.3 38.77,67.29 38.77,66.21 39.88,65.11 v2(39.88,64.31)
TBT_USB2_T_N: length 8.5
  TOP w0.076: v2(19.61,61.63) 19.89,61.91 20.21,61.91 20.27,61.97 U722.L6
  TOP w0.127: v2(16.44,58.65) 16.43,58.65 16.11,58.97 15.81,58.97 15.65,58.81 ML6.4
  IN1 w0.091: v2(16.44,58.65) 16.54,58.65 16.9,59.01 17.09,59.01 18.22,60.14 18.22,61.82 18.47,62.08 18.8,62.08 18.96,61.92 19.32,61.92 v2(19.61,61.63)
TBT_USB2_T_N_R: length 7.6
  TOP w0.127: ML6.3 13.64,58.58 13.34,58.87 13.11,58.87 D83.1 12.94,58.71 12.75,58.89 12.6,58.89 12.46,59.03 11.38,60.11 v4(10.53,60.11) 10.19,60.11 9.62,60.68 8.06,60.68 7.92,60.54 JUSBC1.A7
TBT_USB2_T_P: length 8.5
  TOP w0.076: v2(19.61,62.21) 19.71,62.11 20.12,62.11 20.19,62.18 20.79,62.18 20.84,62.23 21.25,62.23 21.33,62.16 U722.K6
  TOP w0.127: ML6.1 15.84,59.23 v2(16.54,59.23)
  IN1 w0.091: v2(19.61,62.21) 19.51,62.11 19.04,62.11 18.88,62.27 18.39,62.27 18.02,61.9 18.02,60.22 17.04,59.23 v2(16.54,59.23)
TBT_USB2_T_P_R: length 7.5
  TOP w0.127: ML6.2 13.62,59.43 13.34,59.14 13.16,59.14 D82.1 12.94,59.35 12.8,59.21 12.64,59.21 v4(11.99,59.86) 11.49,60.36 10.3,60.36 9.72,60.94 8.06,60.94 7.95,61.04 JUSBC1.A6
TBT_USB3_RX0_N: length 34.9
  TOP w0.076: v2(36.77,64.74) 36.77,64.74 arc(36.68,64.77) 36.65,64.85 36.65,64.97 arc(36.65,64.98) 36.65,65 arc(36.73,65.08) 36.84,65.12 36.86,65.12 arc(36.88,65.12) 36.9,65.13 36.97,65.17 arc(37.01,65.19) 37.05,65.2 37.05,65.2 arc(37.06,65.2) 37.07,65.2 arc(37.11,65.2) 37.15,65.19 37.18,65.19 arc(37.25,65.16) 37.31,65.12 37.45,64.98 arc(37.55,64.91) 37.67,64.89 UT1.A21
  BOTTOM w0.163: v2(36.77,64.74) 36.73,64.78 arc(36.62,64.83) 36.5,64.78 arc(36.26,64.62) 35.98,64.56 32.55,64.56 arc(32.54,64.56) 32.53,64.56 arc(31.42,64.78) 30.48,65.41 30.4,65.5 arc(29.98,65.78) 29.48,65.88 14.46,65.88 arc(14.42,65.88) 14.38,65.87 arc(13.75,65.7) 13.22,65.32 11.17,63.27 arc(11.04,63.18) 10.9,63.15 arc(10.9,63.15) 10.9,63.15 10.86,63.14 arc(10.86,63.14) 10.85,63.14 10.65,63.14 arc(10.59,63.13) 10.53,63.09 D85.1 10.2,62.76 arc(9.8,63.02) 9.33,63.12 7.14,63.12 arc(6.97,63.08) 6.82,62.98 6.67,62.83 arc(6.46,62.69) 6.21,62.65 5.96,62.65 arc(5.94,62.64) 5.93,62.64 5.85,62.63 arc(5.62,62.54) JUSBC1.B10
TBT_USB3_RX0_P: length 34.9
  TOP w0.076: v2(36.78,65.47) 36.79,65.46 arc(36.88,65.4) 36.98,65.37 arc(36.99,65.37) 37,65.37 37.1,65.37 arc(37.29,65.33) 37.46,65.22 37.47,65.21 arc(37.47,65.2) 37.48,65.19 arc(37.5,65.18) 37.51,65.17 arc(37.52,65.17) 37.52,65.17 37.52,65.16 arc(37.52,65.16) 37.53,65.16 37.56,65.14 arc(37.57,65.13) 37.58,65.13 37.62,65.12 arc(37.67,65.11) 37.72,65.1 37.8,65.1 arc(37.97,65.07) 38.12,64.97 UT1.B21
  BOTTOM w0.163: v2(36.78,65.47) 36.23,64.92 arc(36.12,64.84) 35.98,64.81 32.55,64.81 arc(32.55,64.81) 32.54,64.82 arc(31.52,65.02) 30.66,65.59 30.58,65.68 arc(30.07,66.01) 29.48,66.13 14.46,66.13 arc(14.41,66.13) 14.35,66.12 arc(13.64,65.92) 13.04,65.5 10.99,63.45 arc(10.94,63.41) 10.88,63.4 arc(10.84,63.4) 10.8,63.4 D84.1 10.17,63.37 7.14,63.37 arc(6.87,63.32) 6.64,63.16 6.49,63.01 arc(6.36,62.93) 6.21,62.9 5.8,62.9 arc(5.65,62.93) 5.53,63.01 5.42,63.12 JUSBC1.B11
TBT_USB3_RX1_N: length 33.5
  TOP w0.076: UT1.B15 38.2,62.16 38.1,62.26 arc(38.01,62.32) 37.91,62.34 37.58,62.34 37.47,62.23 37.15,62.23 arc(37.06,62.25) 36.99,62.29
  TOP w0.163: v2(11.5,58.2) 11.28,57.98 arc(11.22,57.94) 11.16,57.93 10.55,57.93 arc(10.4,57.96) 10.28,58.04 D79.1 10.08,58.01 arc(10,57.95) 9.9,57.93 9.74,57.93 arc(9.62,57.96) 9.51,58.03 8.78,58.76 arc(8.61,58.88) 8.4,58.92 8.3,58.92 8.18,59.04 JUSBC1.A10 ; 36.99,62.29 36.1,62.3 v2(36.09,62.29)
  BOTTOM w0.163: v2(11.5,58.2) 11.5,58.16 11.59,58.06 arc(11.67,58.01) 11.75,58 11.82,58 arc(11.83,58) 11.85,58 12.24,58.07 12.25,58.07 arc(12.28,58.08) 12.31,58.09 12.32,58.09 arc(12.52,58.18) 12.7,58.31 14.23,59.84 arc(15.38,60.61) 16.73,60.88 20.9,60.88 arc(21.04,60.91) 21.16,60.99 21.22,61.05 arc(21.41,61.18) 21.64,61.22 24.7,61.22 25.34,61.22 arc(25.82,61.13) 26.23,60.85 26.31,60.77 26.32,60.76 arc(26.49,60.65) 26.69,60.61 29.03,60.61 arc(29.9,60.78) 30.63,61.27 31.21,61.86 arc(31.47,62.03) 31.77,62.09 35.59,62.09 arc(35.62,62.09) 35.64,62.09 arc(35.89,62.15) v2(36.09,62.29)
TBT_USB3_RX1_P: length 33.5
  TOP w0.076: 37.02,62.02 37.23,61.81 37.42,61.81 37.49,61.88 37.69,61.88 37.77,61.96 37.77,62.1 UT1.A15
  TOP w0.163: JUSBC1.A11 8.18,58.54 8.3,58.66 8.4,58.66 arc(8.51,58.64) 8.6,58.58 8.63,58.55 9.34,57.85 arc(9.52,57.72) 9.74,57.68 9.95,57.68 arc(10,57.67) 10.04,57.64 D80.1 10.28,57.57 arc(10.4,57.65) 10.55,57.68 11.16,57.68 arc(11.22,57.67) 11.28,57.63 v2(11.5,57.41) ; v2(36.09,61.62) 36.08,61.64 36.08,61.74 36.25,61.91 arc(36.37,61.99) 36.52,62.02 37.02,62.02
  BOTTOM w0.163: v2(36.09,61.62) 36.04,61.68 arc(35.87,61.79) 35.66,61.84 31.77,61.84 arc(31.76,61.83) 31.74,61.83 31.74,61.83 arc(31.55,61.79) 31.39,61.68 30.81,61.09 arc(29.99,60.55) 29.03,60.36 26.69,60.36 arc(26.39,60.42) 26.14,60.59 26.05,60.68 arc(25.91,60.79) 25.76,60.88 arc(25.55,60.95) 25.34,60.97 21.64,60.97 arc(21.51,60.94) 21.4,60.87 21.34,60.81 arc(21.14,60.68) 20.9,60.63 16.73,60.63 arc(15.47,60.38) 14.41,59.67 12.87,58.13 arc(12.65,57.96) 12.39,57.85 12.11,57.77 arc(11.78,57.63) v2(11.5,57.41)
TBT_USB3_TX0_N: length 29.5
  TOP w0.163: JUSBC1.A3 7.82,62.54 7.95,62.66 8.23,62.66 8.88,63.32 arc(9.11,63.47) 9.37,63.52 10.49,63.52 arc(10.69,63.48) 10.86,63.37 D76.1 11,63.43 arc(11.1,63.5) 11.22,63.52 13.53,63.52 arc(13.78,63.42) v2(13.89,63.16) ; v2(33.15,63.08) 33.2,63.13 arc(33.44,63.29) 33.73,63.34 33.97,63.34 arc(34.25,63.38) 34.51,63.5 34.62,63.57 arc(34.66,63.6) 34.7,63.62 arc(35.04,63.66) 35.35,63.49 CT40.2
  BOTTOM w0.163: v2(13.89,63.16) 14.17,63.44 arc(14.18,63.45) 14.2,63.47 arc(14.32,63.54) 14.45,63.56 16.37,63.56 arc(16.71,63.63) 17,63.82 17.26,64.08 arc(17.38,64.16) 17.53,64.19 30.18,64.19 arc(30.4,64.15) 30.58,64.02 30.65,63.96 arc(31.35,63.5) 32.18,63.34 32.82,63.34 arc(32.88,63.33) 32.94,63.3 v2(33.15,63.08)
TBT_USB3_TX0_N_C: length 2.6
  TOP w0.076: UT1.B19 37.96,63.72 37.46,63.72 37.32,63.86 36.88,63.86 36.78,63.75
  TOP w0.163: CT40.1 36.12,63.66 36.66,63.66 36.78,63.75
TBT_USB3_TX0_P: length 29.5
  TOP w0.163: JUSBC1.A2 7.82,63.04 7.95,62.92 8.12,62.92 8.71,63.5 arc(9.01,63.7) 9.37,63.77 10.57,63.77 arc(10.69,63.8) 10.8,63.87 D75.1 11,63.87 arc(11.1,63.8) 11.22,63.77 13.56,63.77 arc(13.79,63.87) 13.89,64.11 v2(13.89,64.12) ; v2(33.15,63.86) 33.37,63.64 arc(33.42,63.61) 33.48,63.6 33.97,63.6 arc(34.18,63.63) 34.37,63.71 34.48,63.78 arc(34.54,63.82) 34.6,63.85 34.59,63.86 arc(34.6,63.86) 34.6,63.86 arc(34.96,64.02) CT39.2
  BOTTOM w0.163: v2(33.15,63.86) 32.93,63.64 arc(32.88,63.61) 32.82,63.6 32.18,63.6 arc(31.45,63.74) 30.82,64.14 30.77,64.19 30.76,64.2 arc(30.49,64.38) 30.18,64.44 17.53,64.44 arc(17.29,64.39) 17.08,64.26 16.82,64 arc(16.61,63.86) 16.37,63.81 14.46,63.81 arc(14.15,63.87) 13.89,64.05 v2(13.89,64.12)
TBT_USB3_TX0_P_C: length 2.6
  TOP w0.076: UT1.A19 37.91,63.97 37.96,64.01 37.96,64.12 37.88,64.19 37.54,64.19 37.42,64.07 36.73,64.07
  TOP w0.163: CT39.1 36.1,63.91 36.57,63.91 36.58,63.92 36.73,64.07
TBT_USB3_TX1_N: length 34.9
  TOP w0.163: CT38.2 34.46,62.74 arc(34.32,62.64) 34.16,62.58 34.16,62.58 arc(34.11,62.57) 34.05,62.57 33.83,62.57 arc(33.67,62.54) 33.53,62.44 32.73,61.64 arc(32.64,61.52) 32.61,61.37 32.61,60.78 arc(32.61,60.73) 32.58,60.68 arc(32.57,60.67) 32.56,60.67 32.53,60.63 arc(32.42,60.55) 32.3,60.51 32.3,60.51 arc(32.27,60.51) 32.25,60.51 32.2,60.51 arc(32.09,60.53) 32,60.6 31.87,60.72 v2(31.87,60.77)
  BOTTOM w0.163: v2(31.87,60.77) 31.87,60.73 31.66,60.52 arc(31.58,60.47) 31.48,60.45 arc(31.28,60.41) 31.12,60.3 31.02,60.2 arc(31.01,60.19) 31,60.18 29.67,58.86 arc(29.43,58.69) 29.13,58.63 26.35,58.63 arc(25.94,58.71) 25.6,58.94 25.18,59.37 arc(24.54,59.79) 23.8,59.94 16.61,59.94 arc(16.29,59.87) 16.03,59.69 12.76,56.43 arc(12.59,56.31) 12.38,56.27 11.54,56.27 arc(11.27,56.32) 11.05,56.47 11.04,56.48 arc(10.93,56.67) 10.92,56.88 arc(10.84,57.35) 10.47,57.65 arc(10.24,57.76) D89.1 arc(9.94,57.78) 9.77,57.73 7.9,57.73 arc(7.82,57.74) 7.75,57.79 6.95,58.59 arc(6.75,58.73) 6.51,58.78 5.92,58.78 arc(5.9,58.78) 5.87,58.78 arc(5.8,58.82) 5.73,58.87 5.42,59.18 JUSBC1.B3
TBT_USB3_TX1_N_C: length 3.4
  TOP w0.076: 36.57,63.03 36.58,63.03 36.63,62.98 36.73,62.98 36.9,63.15 37.38,63.15 37.52,63.29 37.96,63.29 UT1.B17
  TOP w0.163: CT38.1 35.7,62.82 35.91,63.03 36.57,63.03
TBT_USB3_TX1_P: length 34.9
  TOP w0.163: v2(31.87,59.99) 31.87,60 31.87,60.07 arc(31.92,60.18) 32.03,60.23 32.18,60.23 arc(32.46,60.29) 32.71,60.45 32.79,60.54 arc(32.85,60.62) 32.87,60.72 32.87,61.31 arc(32.89,61.42) 32.95,61.51 33.63,62.19 arc(33.77,62.28) 33.94,62.32 34.39,62.32 arc(34.49,62.3) CT37.2
  BOTTOM w0.163: v2(31.87,59.99) 31.77,60.09 arc(31.7,60.14) 31.62,60.16 31.51,60.16 arc(31.5,60.16) 31.5,60.16 31.5,60.16 arc(31.45,60.15) 31.41,60.14 arc(31.29,60.1) 31.19,60.02 29.85,58.68 arc(29.52,58.46) 29.13,58.38 26.35,58.38 arc(25.85,58.48) 25.42,58.76 25,59.19 arc(24.45,59.55) 23.8,59.68 16.61,59.68 16.61,59.68 16.6,59.68 arc(16.39,59.64) 16.21,59.52 12.94,56.25 arc(12.68,56.08) 12.38,56.02 11.54,56.02 arc(11.18,56.09) 10.87,56.29 10.86,56.31 arc(10.69,56.59) 10.67,56.93 arc(10.62,57.22) 10.39,57.41 10.36,57.42 arc(10.13,57.39) 10.04,57.18 D88.1 arc(9.95,57.38) 9.72,57.48 7.9,57.48 arc(7.72,57.51) 7.57,57.61 6.77,58.42 arc(6.65,58.5) 6.51,58.52 5.62,58.52 arc(5.56,58.51) 5.51,58.48 JUSBC1.B2
TBT_USB3_TX1_P_C: length 3.4
  TOP w0.076: 36.57,62.77 36.76,62.77 36.97,62.99 37.4,62.99 37.57,62.82 37.82,62.82 37.89,62.9 37.89,62.98 37.83,63.05 UT1.A17
  TOP w0.163: CT37.1 35.15,62.24 35.49,62.57 35.81,62.57 36.01,62.77 36.57,62.77
TBT_USB_OC0#: length 191
  TOP w0.076: R1438.2 18.64,61.16 v2(18.64,61.68)
  IN2 w0.089: v2(22.02,55.19) 21.36,55.86 20.51,55.86 18.34,58.02 18.34,60.74 18.64,61.04 v2(18.64,61.68)
  IN3 w0.089: v2(148.41,74.67) 148.39,74.65 148.39,74.46 147.93,74 147.93,73.88 146.26,72.21 143.75,72.21 143.15,72.81 143.15,74.46 142.95,74.66 142.75,74.66 142.63,74.77 141.39,74.77 140.77,74.15 140.77,72.86 138.37,70.46 137.54,70.46 137.29,70.21 136.65,70.21 136.54,70.33 121.06,70.33 120.86,70.53 118.15,70.53 117.57,69.95 115.05,69.95 114.51,69.41 114.51,69.05 112.9,67.44 108.88,67.44 108.74,67.29 108.37,67.29 107.79,67.88 97.41,67.88 95.97,69.32 93.9,69.32 92.21,67.63 88.12,67.63 87.24,68.51 82.48,68.51 82.08,68.91 79.8,68.91 79.23,68.34 74.2,68.34 73.82,68.72 73.82,69.94 73.38,70.39 71.97,70.39 71.72,70.13 60.92,70.13 59.27,71.78 58.38,71.78 58.1,71.51 58.1,70.58 57.02,69.5 57.02,68.41 58.38,67.06 58.38,63.81 59.72,62.47 59.72,61.59 59.9,61.4 60.84,61.4 61.07,61.18 61.07,56.94 59.67,55.54 59.67,54.48 59.82,54.33 59.82,50.77 59.45,50.4 51.43,50.4 51.16,50.14 47.18,50.14 46.85,49.81 46.85,49.73 45.56,48.43 43.9,48.43 43.29,47.82 42.76,47.82 42.3,47.37 41.62,47.37 41.24,47.75 41.24,48.1 40.51,48.83 39.83,48.83 37.61,51.05 37.19,51.05 36.63,51.6 36.2,51.6 35.99,51.4 35.99,51.06 35.71,50.78 34.57,50.78 34.3,51.05 34.3,51.99 29.4,56.89 24.98,56.89 24.06,57.81 24.06,59.12 23.92,59.26 23.05,59.26 22.41,58.62 22.41,55.58 v2(22.02,55.19)
  BOTTOM w0.127: v2(148.41,74.67) 148.44,74.7 RC189.1 147.96,75.22 147.96,74.44 147.98,74.42 147.98,74.1 147.96,74.08 147.96,73.08 147.47,72.6 UCPU1.A9
TBT_VBUS: length 59.7
  TOP w0.127: v3(13.89,55.38) 13.41,55.38 v2(13.06,55.73)
  TOP w0.254: JUSBC1.A4 6.17,62.04 JUSBC1.B9 ; JUSBC1.A9 6.17,59.54 JUSBC1.B4
  TOP w0.381: D123.1 v2(13.06,55.73)
  TOP w0.508: v2(79.73,71.46) 80.06,71.79 80.06,73.16 80.98,74.08 PR264.1
  IN3 w0.508: v2(60.48,72.42) 60.58,72.32 63.87,72.32 64.59,73.04 78.15,73.04 v2(79.73,71.46)
  IN4 w0.508: v2(46.1,75.02) 47.6,75.02 48.29,75.7 48.29,77.76 49.1,78.57 60,78.57 60.35,78.21 60.35,77.25 59.64,76.54 59.64,73.26 v2(60.48,72.42)
  BOTTOM w0.381: C401.2 C398.2 8.1,58.71 8.41,58.4 v2(8.41,58.15) ; CT9.1 v2(9.07,56.83)
  BOTTOM w0.508: JUSBC1.B9 7.06,61.99 7.87,61.17 C397.2 C402.2
  vias: v2(17.98,55.97) v2(18.44,56.37) v2(18.52,55.71) v2(18.72,54.59) v2(18.77,55.18) v2(19.33,54.95) v2(19.96,54.95) v2(44.35,75.47) v2(44.91,75.68) v2(44.88,75.04) v2(45.49,75.68) v2(45.47,75.02) v2(46.08,75.62)
TBT_VBUS_L: length 2
  TOP w0.127: v1(21.39,54.77) 21.18,54.77 20.01,55.95 19.91,55.95
TCLK_XDP: length 78.3
  TOP w0.127: JXDP1.57 64.6,71.92 64.35,71.67 63.49,71.67 62.64,72.53 62.64,74.91 v2(62.97,75.24) 63.09,75.37 RC139.2 ; v2(116.61,75.13) v3(116.61,74.48)
  IN3 w0.089: v2(62.97,75.24) 63.42,75.7 65.01,75.7 65.61,76.3 70.99,76.3 71.64,75.65 78.79,75.65 80.49,73.95 88.84,73.95 89.73,74.84 91.18,74.84 92.27,75.94 92.67,75.94 92.9,76.16 93.85,76.16 94.07,75.94 98.34,75.94 102.39,71.88 105.97,71.88 108.92,74.83 116.31,74.83 v2(116.61,75.13) 117.62,75.13 118.13,75.65 v2(118.13,76.26)
  BOTTOM w0.076: UCPU1.B61 117.52,71.87 117.52,72.09 117.46,72.21 117.46,72.47 117.56,72.57 117.56,74.36 116.79,75.13 v2(116.61,75.13) ; UCPU1.A59 118.77,72.4 118.77,74.41 118.13,75.04 v2(118.13,76.26)
  BOTTOM w0.127: RC87.1 118.13,76.59 v2(118.13,76.26)
TDI_XDP: length 79.1
  TOP w0.127: v2(65.15,69.22) 65.1,69.17 JXDP1.56 ; v2(89.33,78.52) 89.63,78.82 92.55,78.82 94.86,76.51 95.24,76.51 95.53,76.79 95.53,77.47 97.91,79.85 116.35,79.85 v3(116.73,79.47) 117.09,79.11 117.84,79.11 118.59,78.36 118.59,77.66 RC81.2 118.09,76.9 118.58,76.41 v2(118.58,75.86)
  IN1 w0.081: v2(66.57,75.22) 67.36,76.01 67.89,76.01 68.46,76.57 69,76.57 69.81,77.38 69.81,78.13 71.12,79.43 v2(71.22,79.43)
  IN3 w0.089: v2(71.22,79.43) 71.36,79.43 71.74,79.06 72.08,79.06 72.26,79.24 73.42,79.24 73.75,78.9 78.66,78.9 80.73,76.83 83.19,76.83 84.27,77.91 88.72,77.91 v2(89.33,78.52)
  IN4 w0.081: v2(65.15,69.22) 65.43,69.5 65.43,72.02 66.7,73.29 66.7,75.09 v2(66.57,75.22)
  BOTTOM w0.076: v2(118.58,75.86) 118.58,75.74 119.13,75.19 119.13,72.69 119.29,72.54 119.29,72.18 119.25,72.08 119.25,71.89 119.29,71.8 119.29,71.55 119.28,71.5 119.18,71.16 119.15,71.07 119.15,70.96 119.1,70.78 119,70.61 119,70.51 UCPU1.D59
  BOTTOM w0.127: RC134.2 89.95,77.89 v2(89.33,78.52) ; UCPU1.D60 118.53,70.69 UCPU1.D59
TDO_XDP: length 94
  TOP w0.127: v2(63.81,70.98) 64.57,70.21 65.14,70.21 66.1,69.26 66.1,67.33 JXDP1.52 ; v2(88.46,78.4) 88.9,77.95 v3(92.05,77.95) 92.69,77.95 93.58,77.06 v2(93.58,76.96) ; v2(116.62,75.73) 117.53,74.82 118.98,74.82 119.76,75.6 v2(119.76,75.73) 120.23,75.73 120.38,75.58 121.24,75.58 121.64,75.98 121.64,77.83 RC82.2
  IN3 w0.089: v2(73.75,79.94) 74.58,79.12 78.75,79.12 80.82,77.05 83.1,77.05 84.18,78.13 88.19,78.13 v2(88.46,78.4)
  IN4 w0.081: v2(93.58,76.96) 93.58,77.39 95.1,78.91 108.76,78.91 108.88,79.02 110.17,79.02 110.34,78.85 117.68,78.85 119.78,76.74 119.78,75.75 v2(119.76,75.73)
  BOTTOM w0.076: v2(119.76,75.73) 119.63,75.6 119.63,74.32 120.31,73.65 120.31,72.41 UCPU1.A56 ; UCPU1.A61 117.73,72.32 117.73,74.62 v2(116.62,75.73)
  BOTTOM w0.127: v2(73.75,79.94) 73.01,80.68 66.46,80.68 63.55,77.77 63.55,76.97 64.61,75.91 64.61,74.38 65,73.98 65,72.73 63.81,71.54 v2(63.81,70.98) ; v2(88.46,78.4) 89,77.85 RC135.2
THERMATRIP2#: length 13.8
  TOP w0.127: QE9.1 175.39,69.26 175.39,70.31 175.11,70.59 175.11,71.5 174.82,71.78 174.82,72.7 175.46,73.34 v3(177.14,73.34) 177.9,73.34 178.72,72.52 178.72,71.69 RE69.2 CE61.1 177.98,68.89 178.61,68.26 178.61,67.87 UE5.B34
THERMATRIP3#: length 3.7
  TOP w0.127: UE5.A2 188.46,60.02 188.58,60.14 189,60.14 189.21,59.94 189.21,59.62 v3(189.43,59.39) 189.59,59.55 189.59,59.85 189.87,60.13 190.5,60.13 RE67.1
THERMDA: length 0.5
  TOP w0.127: UT1.AB23 UT1.AC23
THSEL_STRAP: length 16.9
  TOP w0.127: v3(181.23,75.5) 181.99,74.74 v2(181.99,74.36) 181.76,74.13 RE78.1 ; v2(181.31,67.17) 181.31,67.22 181.11,67.41 UE5.B29
  BOTTOM w0.127: v2(181.99,74.36) 180.8,74.36 179.87,73.43 179.11,73.43 177.63,71.94 177.63,69.05 178.3,68.37 178.3,67.02 178.57,66.74 180.97,66.74 181.31,67.08 v2(181.31,67.17)
TMS_XDP: length 76.5
  TOP w0.127: v2(64.56,69.22) 64.6,69.18 JXDP1.58 ; v2(91.91,76.36) 91.91,76.44 92.25,76.77 93.13,76.77 93.36,76.54 94.34,76.54 94.89,75.98 97.06,75.98 97.3,76.22 97.3,76.65 97.13,76.81 97.13,78.58 98.15,79.6 114.37,79.6 v3(114.73,79.23) RC130.2 116.82,76.59 117.39,76.02 117.74,76.02 v2(118.52,75.24)
  IN4 w0.081: v2(64.56,69.22) 64.56,69.16 64.9,68.82 65.38,68.82 65.64,69.08 65.64,71.93 67.04,73.33 67.04,75.63 67.63,76.22 72.05,76.22 72.87,77.05 79.06,77.05 80.3,75.81 85.17,75.81 85.85,75.13 87,75.13 88.23,76.36 v2(91.91,76.36)
  BOTTOM w0.076: UCPU1.C59 118.97,71.12 118.97,71.2 119,71.26 119.04,71.32 119.12,71.57 119.12,71.75 119.07,71.94 119.07,72.09 119.12,72.21 119.12,72.47 118.95,72.64 118.95,74.81 v2(118.52,75.24)
  BOTTOM w0.127: RC131.2 91.16,77.38 91.91,76.62 v2(91.91,76.36) ; UCPU1.C60 118.53,71.34 UCPU1.C59
TOUCH_SCREEN_PD#: length 102.8
  BOTTOM w0.127: UCPU1.A7 150,73.72 150.32,73.72 150.84,74.24 150.84,75.05 RC277.2 151.02,76.17 151.02,77.09 150.74,77.37 149.99,77.37 149.65,77.72 149.65,80.65 149.48,80.82 97.34,80.82 96.36,79.84 95.33,79.84 93.14,77.65 93.14,76.19 92.26,75.32 91.52,75.32 91.13,75.7 90.2,75.7 89.15,74.65 89.15,71.73 88.46,71.04 86.57,71.04 85.21,72.4 80.89,72.4 80.53,72.77 76.76,72.77 76.54,72.98 74.23,72.98 73.67,72.42 v1(73.08,72.42) 72.88,72.42 70.51,74.79 70.51,77.05 71.22,77.76 JTS.5
TOUCHPAD_INTR#: length 12.3
  BOTTOM w0.076: UCPU1.BA5 149.52,50.31 149.86,49.97 149.86,49.53 150.22,49.17 150.53,49.17 150.71,48.99
  BOTTOM w0.127: v3(159.1,49.53) 158.8,49.23 158.12,49.23 157.91,49.03 157.91,48.42 DZ3.2 157.71,48.01 157.28,47.58 156.53,47.58 RC272.2 155.87,48.1 155.32,48.65 151.05,48.65 150.71,48.99
TP_PW_EN: length 148.3
  TOP w0.127: U716.3 170.9,15.97 170.74,15.81 170.74,15.27 169.65,14.18 R1175.2 168.99,13.65 167.48,13.65 167.26,13.88 167.26,14.11 v2(167.16,14.21) 167.26,14.31 167.26,14.6 v3(167.41,14.76)
  IN3 w0.089: v2(63.35,14.31) 62.97,13.93 61.21,13.93 59.64,15.5 56.26,15.5 55.96,15.81 50.4,15.81 48.78,14.19 40.03,14.19 39.39,14.82 35.36,14.82 v2(34.24,13.7)
  BOTTOM w0.127: v2(34.24,13.7) 34.59,14.05 UE4.24 ; v2(167.16,14.21) 167.26,14.11 167.26,13.84 166.84,13.42 157.58,13.42 157.19,13.8 134.42,13.8 130.76,17.46 127.46,17.46 125.22,15.22 114.37,15.22 111.95,17.64 107.15,17.64 105.79,16.29 95.57,16.29 94.41,15.14 64.18,15.14 v2(63.35,14.31)
TPM_DET: length 6.3
  TOP w0.127: v2(145.38,54.38) 145.75,54.76 145.75,55.76 146.43,56.45 146.43,56.87 146.63,57.08 147.4,57.08 RH153.1 RH148.2
  BOTTOM w0.127: UCPU1.AP13 144.97,54.75 145.33,54.38 v2(145.38,54.38)
TPM_GPIO2: length 7.1
  TOP w0.127: v1(182.28,51.09) 182.28,49.86 R1873.2 R1006.2 183.69,49.23 183.69,47.14 183.97,46.86 183.97,45.96 183.71,45.69 U15.3
TPM_LPM#: length 18.3
  TOP w0.127: Q72.1 198.16,46.43 196.8,47.79 196.29,47.79 RE91.1 195.02,49.05 192.19,49.05 192,48.87 188.94,48.87 v1(188.71,49.09) 188.33,49.48 187.39,49.48 186.83,50.03 186.83,50.34 186.39,50.78 183.07,50.78 182.86,50.57 R1873.1
TPM_PIRQ#: length 76.2
  TOP w0.127: U15.18 189.98,43.69 RH126.2 190.31,42.92 188.87,41.49 188.87,39.89 188.3,39.31 187.42,39.31 186.73,38.62 182.79,38.62 v1(181.14,40.26) 179.77,41.63 179.76,41.63 179.48,41.91 v2(179.18,41.91)
  IN2 w0.089: v2(153.52,66.3) 154.4,66.3 155.6,65.1 155.6,64.51 155.19,64.1 155,64.1 154.48,63.58 154.48,62.88 154.89,62.47 154.99,62.47 155.93,61.53 157.66,61.53 157.98,61.21 163.7,61.21 165.23,59.69 170.68,59.69 171.52,58.84 172.33,58.84 172.52,59.04 173.29,59.04 175.31,57.01 175.31,53.2 175.12,53.01 175.12,51.79 175.62,51.3 177.43,51.3 180.04,53.9 180.85,53.9 181.72,53.03 181.72,43.59 180.05,41.91 v2(179.18,41.91)
  BOTTOM w0.076: v2(153.52,66.3) 153.42,66.4 151.07,66.4 UCPU1.M3
TRST#_XDP: length 87
  TOP w0.127: v2(80.9,73.11) 80.54,72.75 80.54,71.26 79.86,70.57 79.86,65.82 v2(79.38,65.34) ; JXDP1.54 65.6,66.26 65.87,65.99 66.43,65.99 66.9,65.52 v2(66.9,65.39) ; v2(117.37,75.59) 116.82,76.14 116.36,76.14 115.94,75.72 115.94,74.9 115.63,74.6 114.72,74.6 113.82,73.69 110.97,73.69 110.72,73.94 109.79,73.94 109.45,74.28 109.45,75.04 109.12,75.37 108.59,75.37 108.19,75.77 108.19,76.37 107.49,77.07 107.49,77.69 v3(106.85,78.33) 106.22,78.96 102.05,78.96 99.01,75.92 97.9,75.92 97.33,75.35 95.41,75.35 93.7,73.63 93.7,72.46 93.03,71.78 93.03,71.44 92.68,71.1 88.88,71.1 v2(88.32,71.66)
  IN4 w0.081: v2(66.9,65.39) 68.67,67.15 78.7,67.15 79.38,66.48 v2(79.38,65.34)
  BOTTOM w0.076: UCPU1.C61 117.33,71.41 117.33,72.08 117.31,72.14 117.3,72.17 117.3,72.54 117.39,72.63 117.39,74.25 116.87,74.78 116.44,74.78 116.21,75.02 116.21,75.84 116.45,76.09 116.87,76.09 v2(117.37,75.59) 117.6,75.36 117.6,75.23 118.59,74.24 118.59,71.93 UCPU1.B59
  BOTTOM w0.127: RC136.2 79.05,73.02 80.81,73.02 v2(80.9,73.11) 81.35,72.66 85.31,72.66 86.68,71.29 87.95,71.29 v2(88.32,71.66)
UART0_TX: length 34.5
  BOTTOM w0.127: JDEG1.9 173.65,68.67 173.41,68.91 172.69,68.91 171.31,70.29 169.8,70.29 168.34,68.82 167.49,68.82 166,70.32 164.71,70.32 164.32,69.93 161.96,69.93 161.44,69.41 v1(161.44,68.23) 161.44,67.34 162.63,66.15 162.63,65.23 162.2,64.8 162.2,62.99 160.49,61.27 158.67,61.27 158.5,61.1 157.43,61.1 156.82,60.49 155.46,60.49 155.14,60.17 154.58,60.17 153.75,60.99 152.42,60.99 152.27,61.15 151.77,61.15 UCPU1.AB2
UART1_RXD: length 174.6
  IN1 w0.081: v2(165.86,39.69) 165.85,39.69 165.81,39.66 165.84,39.63 165.84,37.91 165.1,37.17 165.1,34.25 164.95,34.1 164.95,27 163.26,25.31 163.26,23.06 160.72,20.52 158.05,20.52 157.43,19.9 126.48,19.9 125.56,18.99 118.9,18.99 117.69,20.19 112.19,20.19 110.54,21.84 103.19,21.84 102.93,21.58 97.85,21.58 96.04,23.39 96.04,26.42 92,30.46 91.59,30.46 90.65,31.4 83.53,31.4 81.98,29.85 77.01,29.85 72.72,25.56 70.26,25.56 67.34,22.64 66.12,22.64 v2(66.09,22.61)
  IN4 w0.081: v2(165.86,39.69) 165.76,39.79 165.76,45.47 158.52,52.72 158.52,55.14 156.63,57.03 156.63,57.75 155.14,59.24 v2(154.89,59.24)
  BOTTOM w0.127: v2(66.09,22.61) 63.86,20.38 59.01,20.38 57.74,19.11 55.3,19.11 v3(54.4,20.01) 53.84,20.57 JUART.3 49.11,20.57 RH563.2 ; v2(154.89,59.24) 154.89,59.24 153.72,60.41 152.87,60.41 152.64,60.18 UCPU1.AC1
UART1_TXD: length 175.1
  IN1 w0.089: v2(162.94,40.12) 163.58,39.48 163.58,39.48 163.85,39.21 163.85,37.21 163.78,37.15 163.78,37.15 163.66,37.02 163.66,33.83 163.75,33.73 163.75,33.73 163.85,33.63 163.85,28.58 156.01,20.74 126.12,20.74 125.2,19.82 119.24,19.82 118.04,21.03 112.54,21.03 110.89,22.67 102.81,22.67 102.58,22.44 98.18,22.44 96.87,23.74 96.87,28 95.09,29.78 94.16,29.78 92.76,31.18 92.76,31.65 92.46,31.95 92.19,31.95 90.97,33.17 89.26,33.17 88.62,33.82 88.11,33.82 87.54,33.24 83.43,33.24 81.4,31.21 76.42,31.21 72.67,27.47 63.75,27.47 63.04,26.76 59.64,26.76 v2(57.81,24.93)
  IN4 w0.089: v2(162.94,40.12) 163.56,40.73 163.56,47.38 158.3,52.63 158.3,55.05 155.23,58.12 v2(154.89,58.12)
  BOTTOM w0.076: UCPU1.AC2 151.32,60 151.56,60 151.68,59.93 151.95,59.93 152.07,59.99 153.17,59.99
  BOTTOM w0.127: 153.17,59.99 153.84,59.99 154.51,59.32 154.51,58.51 v2(154.89,58.12) ; JUART.2 50.11,21.37 49.99,21.24 RH562.2 50.07,22.37 v1(50.07,23.32) 50.07,23.84 51.15,24.92 55.66,24.92 56.06,24.52 57.4,24.52 v2(57.81,24.93)
UPD_EN1_4#: length 2.3
  TOP w0.127: v2(178.87,59.29) 178.89,59.29 179.11,59.07 UE5.B53
  BOTTOM w0.127: RE107.2 v3(179.05,58.76) 179.05,59.11 v2(178.87,59.29)
UPD_SMBCLK: length 194.7
  TOP w0.076: U722.B5 25.33,62.29 v2(25.04,62.29)
  TOP w0.127: v2(179.03,60.44) 178.87,60.27 178.01,60.27 UE5.B49
  IN3 w0.089: v2(179.05,74.81) 179.05,74.55 178.94,74.44 177.86,74.44 174.31,77.99 171.82,77.99 170.08,79.73 153.18,79.73 152.81,80.09 90.7,80.09 89.84,79.23 87.37,79.23 86.97,78.83 84.57,78.83 83.01,77.27 80.91,77.27 77.75,80.42 57.58,80.42 52.15,74.99 50.78,74.99 48.67,72.89 46.27,72.89 44.82,74.33 43.5,74.33 42.17,75.66 38.24,75.66 34.95,72.37 30.51,72.37 28.6,70.47 28.6,66.24 28.05,65.69 28.05,62.52 27.65,62.11 27,62.11 26.77,62.34 25.1,62.34 v2(25.04,62.29)
  IN4 w0.089: v2(179.05,74.81) 178.12,73.88 178.12,73.07 176.71,71.67 176.71,69.21 176.96,68.96 176.96,67.24 177.7,66.5 177.7,63.53 178.66,62.57 179.73,62.57 179.98,62.32 179.98,61.95 179.09,61.07 179.09,60.5 v2(179.03,60.44)
  BOTTOM w0.127: v2(179.03,60.44) 178.52,60.44 178,60.96 CE71.1 RE88.1
UPD_SMBDAT: length 192.3
  TOP w0.127: v2(178.44,74.84) 178.44,73.82 v1(178.67,73.59) ; v2(27.05,62.63) 27.05,62.62 26.77,62.34 26.14,62.34 U722.A5 ; UE5.B48 178.53,60.77 v2(178.66,60.9)
  IN3 w0.089: v2(178.44,74.84) 178.17,74.84 175.37,77.63 174.97,77.63 174.4,78.2 171.91,78.2 170.17,79.94 153.75,79.94 153.39,80.3 87.28,80.3 86.72,79.74 85.18,79.74 82.92,77.48 81,77.48 77.85,80.63 56.32,80.63 53.13,77.45 53.13,76.35 51.98,75.21 50.69,75.21 48.58,73.1 46.36,73.1 44.88,74.58 43.71,74.58 42.42,75.88 38.15,75.88 34.86,72.59 30.42,72.59 28.35,70.52 28.35,66.29 27.74,65.68 27.74,65.11 27.41,64.78 26.95,64.78 26.09,63.92 26.09,63.43 26.31,63.2 26.64,63.2 27.06,62.78 27.06,62.65 27.05,62.64 v2(27.05,62.63)
  IN4 w0.089: v2(178.66,60.9) 178.4,61.16 178.4,62.5 177.48,63.42 177.48,66.41 176.75,67.15 176.75,68.87 176.44,69.18 176.44,71.7 177.9,73.16 177.9,74.3 v2(178.44,74.84)
  BOTTOM w0.127: RE87.1 CE70.1 177.93,61.63 v2(178.66,60.9)
UPD_SMBUS_ALRT#: length 190.2
  TOP w0.076: U722.B6 25.33,61.8 25.24,61.71 v2(25.04,61.71)
  TOP w0.127: v2(175.08,61.48) 174.7,61.48 RE3.2 CE72.2 174.28,62.96 174.72,62.52 v1(175.74,62.52) UE5.A42
  IN3 w0.089: v2(171.83,73.12) 171.65,73.3 171.65,77.54 169.9,79.29 152.49,79.29 152.31,79.47 128.78,79.47 128.77,79.46 92.18,79.46 89.98,77.26 84.23,77.26 83.37,76.4 80.55,76.4 79.42,77.54 76.77,77.54 76.06,78.25 73.49,78.25 73.15,78.59 72.53,78.59 72.35,78.41 71.21,78.41 69.84,79.78 62.09,79.78 61.44,79.14 56.61,79.14 52.88,75.41 52.88,72.37 52.57,72.06 44.81,72.06 41.99,69.24 39.37,69.24 37.63,70.98 36.56,70.98 36.2,71.34 35.76,71.34 35.32,71.78 31.74,71.78 29.5,69.54 29.08,69.54 28.89,69.35 28.89,66.22 28.27,65.6 28.27,62.35 27.53,61.61 27.53,61.35 26.84,60.66 26.36,60.66 25.31,61.71 v2(25.04,61.71)
  IN4 w0.081: v2(175.08,61.48) 175.01,61.48 173.65,62.84 173.65,64.44 173.56,64.53 173.56,66.23 174.02,66.68 174.02,68.19 173.38,68.82 173.38,71.53 171.83,73.08 v2(171.83,73.12)
USB1_DET#: length 44
  TOP w0.127: v2(201.65,21.9) 202.2,22.46 v1(202.91,22.46)
  IN4 w0.081: v2(189.91,49.36) 189.91,49.33 193.29,45.96 193.29,34.12 193.68,33.72 194.87,33.72 195.58,33 195.58,25.96 198.1,23.45 200.1,23.45 v2(201.65,21.9)
  BOTTOM w0.127: v2(189.91,49.36) 190.53,49.36 190.78,49.1 191.51,49.1 191.95,49.55 CE22.1 RE34.2 ; v2(201.65,21.9) 201.65,21.58 199.86,19.78 199.86,18.97 199.71,18.83 JIO1.36
USB2_EN: length 5.4
  TOP w0.127: v1(25.91,51.55) 25.48,51.55 25.12,51.18 US2.4 23.6,51.18 23.47,51.32 23.47,51.82 23.67,52.03 R1216.1 23.76,52.88 24.85,52.88 U699.4
USB2_ID: length 5.5
  BOTTOM w0.127: RC19.1 155.5,57.24 154.93,57.24 154.25,57.92 153.67,57.92 v1(153.59,57.84) 153.44,57.84 153.19,58.1 152.55,58.1 152.35,57.9 151.13,57.9 150.83,58.19 UCPU1.AG3
USB2_PWR_EN: length 240.7
  TOP w0.127: v2(23.4,54.5) 23.67,54.23 RC293.2 25.4,53.81 26.15,54.56 U699.1 26.38,54.73 26.59,54.52 27.23,54.52 v1(27.43,54.72)
  IN1 w0.081: v2(42.24,40.48) 43.03,41.27 43.03,43.51 v2(42.34,44.2)
  IN4 w0.081: v2(42.34,44.2) 41.83,43.7 35.51,43.7 34.94,43.13 32.58,43.13 31.69,42.24 29.86,42.24 29.38,42.72 28.53,42.72 27.08,41.27 25.93,41.27 25.64,41.56 24.83,41.56 23.19,43.2 23.19,54.3 v2(23.4,54.5) ; v2(42.24,40.48) 42.24,39.86 41.45,39.07 41.26,39.07 39.23,37.04 39.23,35.28 39.82,34.68 39.95,34.68 41.09,33.54 41.09,31.78 41.24,31.63 41.24,27.55 45.07,23.72 47.89,23.72 48.02,23.59 50.8,23.59 50.92,23.71 52.92,23.71 53.91,22.72 58.94,22.72 60.09,21.57 65.93,21.57 68.91,24.55 68.91,25.74 71.48,28.31 73.94,28.31 76.78,31.15 77.61,31.15 78.69,32.23 82.48,32.23 83.82,33.57 83.82,34.11 85.3,35.59 90.09,35.59 90.9,34.78 95.63,34.78 96.82,33.58 96.82,30.17 97.64,29.35 97.64,25.62 97.73,25.53 97.73,24.25 98.83,23.15 99.77,23.15 100.95,21.97 110.64,21.97 111.72,20.89 116.95,20.89 117.7,21.64 124.06,21.64 125.46,20.24 144.5,20.24 144.98,20.72 147.66,20.72 148.06,20.32 160.51,20.32 163.13,22.93 163.13,25.69 161.67,27.15 161.67,29.6 163.52,31.45 163.52,33.33 162.92,33.93 162.22,33.93 160.22,35.93 160.22,37.24 156.47,40.99 156.47,41.91 155.5,42.88 155.5,45.33 154.37,46.47 v2(154.37,46.87)
  BOTTOM w0.076: UCPU1.AY7 148.26,50.68 148.21,50.55 148.19,50.52 148.16,50.4 148.16,50.2 148.2,50.05 148.19,49.9 148.15,49.79 148.15,49.55 149.32,48.37 150.09,48.37 150.65,47.81 153.18,47.81 154.12,46.87 v2(154.37,46.87)
USB3RN1: length 110.7
  IN2 w0.076: v2(147.17,67.92) 147.35,68.1 147.43,68.1 147.68,68.35 147.68,68.73 147.9,68.96 148.23,68.96 148.46,68.73 148.46,68.38 149.14,67.7 149.33,67.7 149.36,67.67
  IN2 w0.102: 149.36,67.67 150.59,67.67 151.26,68.33 152.59,68.33 152.72,68.21 153.49,68.21 157.07,64.63 158.03,64.63 158.38,64.98 158.38,66.25 158.86,66.73 160.97,66.73 161.34,66.36 165.71,66.36 166.04,66.03 168.72,66.03 168.87,65.88 172.46,65.88 172.94,66.35 176.63,66.35 178.07,64.91 180.12,64.91 180.17,64.86 181.68,64.86 182.91,63.64 187.44,63.64 189.14,61.94 189.14,61.39 189.21,61.32 189.21,53.64 186.55,50.98 186.55,48.21 188.64,46.12 190.07,46.12 190.48,45.71 190.48,44.18 190.32,44.02 190.32,32.19 201.83,20.68 201.94,20.68 205.65,16.98 209.54,16.98 210.15,17.58 v2(210.15,17.63)
  BOTTOM w0.127: UCPU1.H8 147.45,67.64 v2(147.17,67.92) ; v2(210.15,17.63) 210,17.63 209.76,17.87 209.76,18.08 209.91,18.23 JIO1.2
USB3RN2: length 170.7
  IN1 w0.076: v2(148.12,67.33) 147.91,67.53 147.76,67.53 147.53,67.77 147.53,68.88 147.64,68.99 147.64,69.41 147.43,69.62 147.42,69.62 147.42,69.62 147.42,69.61 147.4,69.63
  IN1 w0.091: 147.4,69.63 147,70.03 147,73.95 146.99,73.96 146.99,74.85 144.99,76.85 138.41,76.85 137.16,78.1 120.17,78.1 119.58,77.5 115.46,77.5 115.19,77.24 108.88,77.24 108.08,78.04 94.06,78.04 93.18,77.16 93.18,76.08 91.43,74.33 86.69,74.33 85.9,73.54 80.39,73.54 80.21,73.36 70.33,73.36 69.14,72.17 64.21,72.17 63.55,72.83 61.57,72.83 60.82,73.58 59.98,73.58 58.94,74.62 58.94,75.06 58.58,75.42 57.64,75.42 57.1,74.88 54.92,74.88 54.76,75.04 54.07,75.04 53.59,74.56 53.59,74.07 52.22,72.7 46.42,72.7 41.64,67.92 38.12,67.92 36.45,69.58 31.29,69.58 30.78,69.06 30.78,61.99 30.88,61.89 30.88,49.8 31.2,49.48 31.2,47.56 24.88,41.24 24.88,39.39 24.68,39.19 24.59,39.19 v2(24.31,38.91)
  BOTTOM w0.127: v2(148.12,67.33) 148.46,66.99 UCPU1.J6 ; v2(24.31,38.91) 24.07,38.91 23.45,38.29 ML13.1
USB3RN2_RC_CON: length 12.1
  BOTTOM w0.127: ML13.2 21.01,38.29 20.74,38.56 20.5,38.56 19.89,39.18 19.58,39.18 19.5,39.09 DI1.10 DI1.1 17.28,39.09 17.04,39.34 16.95,39.42 16.87,39.52 16.87,39.53 16.78,39.63 16.78,39.75 15.5,41.04 15.5,42.03 15.09,42.44 13.88,42.44 13.31,41.87 12.87,41.87 12.72,41.73 12.72,41.54 12.72,41.54 JUSB2.5
USB3RP1: length 110.8
  IN2 w0.076: v2(147.12,68.6) 147.12,68.6 147.12,68.4 147.25,68.27 147.37,68.27 147.51,68.41 147.51,68.8 147.83,69.13 148.3,69.13 148.63,68.79 148.63,68.45 149.21,67.86 149.33,67.86 149.36,67.89 149.39,67.89
  IN2 w0.102: v2(209.3,17.64) 209.41,17.75 209.58,17.75 209.68,17.65 209.68,17.43 209.45,17.2 205.75,17.2 202.04,20.91 201.92,20.91 190.55,32.28 190.55,43.93 190.7,44.08 190.7,45.81 190.16,46.35 188.73,46.35 186.77,48.3 186.77,50.88 189.43,53.54 189.43,61.42 189.36,61.49 189.36,62.03 187.54,63.86 183,63.86 181.77,65.08 180.26,65.08 180.21,65.13 178.16,65.13 176.72,66.58 172.84,66.58 172.36,66.1 168.96,66.1 168.81,66.25 166.13,66.25 165.8,66.59 161.43,66.59 161.07,66.95 158.77,66.95 158.16,66.34 158.16,65.07 157.93,64.85 157.16,64.85 153.58,68.43 152.82,68.43 152.69,68.56 151.16,68.56 150.5,67.89 149.39,67.89
  BOTTOM w0.127: UCPU1.G8 147.42,68.29 v2(147.12,68.6) ; v2(209.3,17.64) 209.51,17.85 209.51,18.11 209.31,18.31 209.31,18.41 JIO1.4
USB3RP2: length 170.6
  IN1 w0.076: v2(148.11,67.93) 148.11,67.89 147.93,67.7 147.83,67.7 147.69,67.83 147.69,68.81 147.8,68.92 147.8,69.48 147.55,69.74 147.55,69.76 147.54,69.76
  IN1 w0.091: v2(24.31,39.49) 24.42,39.38 24.6,39.38 24.69,39.47 24.69,41.32 31.01,47.64 31.01,49.4 30.68,49.72 30.68,61.81 30.58,61.91 30.58,69.14 31.21,69.77 36.53,69.77 38.2,68.11 41.56,68.11 46.34,72.89 52.14,72.89 53.4,74.15 53.4,74.64 53.99,75.23 54.84,75.23 55,75.07 57.02,75.07 57.56,75.61 58.66,75.61 59.13,75.14 59.13,74.7 60.06,73.77 60.9,73.77 61.65,73.02 63.63,73.02 64.29,72.36 69.06,72.36 70.25,73.56 80.13,73.56 80.31,73.73 85.82,73.73 86.61,74.52 91.35,74.52 92.99,76.16 92.99,77.24 93.98,78.23 108.16,78.23 108.96,77.43 115.11,77.43 115.38,77.7 119.5,77.7 120.09,78.29 137.24,78.29 138.49,77.05 145.07,77.05 147.19,74.93 147.19,74.04 147.19,74.03 147.19,70.11 147.54,69.76
  BOTTOM w0.127: v2(148.11,67.93) 148.11,67.9 148.38,67.64 UCPU1.H6 ; ML13.4 23.72,39.09 24.12,39.49 v2(24.31,39.49)
USB3RP2_RC_CON: length 12.3
  BOTTOM w0.127: JUSB2.6 12.72,43.11 12.72,42.26 12.87,42.12 13.2,42.12 13.78,42.69 14.98,42.69 15.19,42.69 15.75,42.13 15.75,41.14 17.04,39.86 17.04,39.72 17.06,39.69 17.07,39.68 17.1,39.64 17.14,39.59 DI1.2 DI1.9 19.45,39.59 19.61,39.43 20,39.43 v4(20.32,39.1) 20.61,38.82 20.74,38.82 21.01,39.09 ML13.3
USB3TN1: length 111.8
  IN2 w0.102: v2(208.1,17.66) 207.95,17.82 207.95,18.45 193.21,33.19 193.21,46.04 191.92,47.33 191.92,53.09 192.13,53.3 192.13,56.92 191.33,57.71 191.33,60.17 191.15,60.35 191.15,63.02 190.89,63.29 190.89,63.56 189.82,64.62 189.41,64.62 188.32,65.72 188.32,66.13 185.72,68.73 178.59,68.73 177.9,69.41 177.9,69.56 177.38,70.08 175.82,70.08 175.47,69.73 173.45,69.73 173.1,69.37 167.57,69.37 167.44,69.5 164.81,69.5 163.07,71.25 161.19,71.25 158.09,74.36 152.36,74.36 152.24,74.48 150.75,74.48 150.36,74.08 150.02,74.08 149.4,73.47 148.8,73.47 148.57,73.24 145.22,73.24 144.37,74.1 144.02,74.1 v2(143.87,74.25)
  BOTTOM w0.076: UCPU1.C13 145.15,71.01 145.21,71.08 145.21,71.21 145.09,71.32 144.89,71.32 144.76,71.45 144.72,71.57 144.72,71.75 144.78,71.94 144.78,72.09 144.72,72.21 144.72,73.7 144.37,74.05 144.07,74.05 v2(143.87,74.25)
  BOTTOM w0.127: JIO1.8 208.11,18.18 207.92,17.99 207.92,17.84 v2(208.1,17.66)
USB3TN2: length 166.9
  IN1 w0.091: v2(145.8,73.82) 145.58,74.04 145.35,74.04 143.15,76.23 137.96,76.23 136.69,77.51 120.93,77.51 120.32,76.89 115.7,76.89 115.39,76.59 109.32,76.59 107.32,74.59 107.32,73.69 105.29,71.67 102.66,71.67 100.1,74.23 100.1,76.49 99.17,77.43 94.89,77.43 94.62,77.15 94.62,76.01 92.32,73.72 87.02,73.72 85.81,72.51 79.97,72.51 79.76,72.73 70.56,72.73 69.41,71.58 63.83,71.58 63.17,72.24 61.31,72.24 60.56,72.99 59.74,72.99 58.44,74.28 56.68,74.28 56.2,73.81 54.16,73.81 52.46,72.11 46.67,72.11 41.89,67.32 36.79,67.32 35.23,68.89 31.63,68.89 31.37,68.62 31.37,62.26 31.47,62.16 31.47,50.05 31.81,49.7 31.81,48.98 32.31,48.48 32.31,47.73 27.02,42.44 27.02,41.07 26.66,40.71 25.56,40.71 v2(25.3,40.45)
  BOTTOM w0.076: UCPU1.B13 144.99,71.79 145.16,71.97 145.34,71.97 145.59,72.22 145.59,73.21 145.4,73.41 145.4,73.85 145.47,73.93 145.69,73.93 v2(145.8,73.82)
  BOTTOM w0.127: C621.1 24.79,40.65 25.09,40.65 v2(25.3,40.45)
USB3TN2_C: length 1.6
  BOTTOM w0.127: C621.2 23.47,40.34 23.03,40.79 22.71,40.79 22.5,40.58 ML12.1
USB3TN2_RC_CON: length 14.5
  BOTTOM w0.127: JUSB2.8 12.72,47.82 12.87,47.96 13.12,47.96 13.56,47.52 14.67,47.52 16.27,45.92 16.27,41.25 16.59,40.93 16.81,40.71 17.04,40.71 17.16,40.59 17.74,40.59 DI1.4 DI1.7 19.18,40.59 19.18,40.59 19.47,40.59 19.59,40.71 19.91,40.71 20.05,40.58 ML12.2
USB3TP1: length 111.7
  IN2 w0.102: v2(143.87,73.62) 143.87,73.72 144.01,73.87 144.27,73.87 145.13,73.01 148.66,73.01 148.89,73.24 149.49,73.24 150.11,73.86 150.45,73.86 150.85,74.25 152.15,74.25 152.27,74.13 157.99,74.13 161.1,71.03 162.97,71.03 164.72,69.28 167.35,69.28 167.48,69.15 173.19,69.15 173.55,69.5 175.56,69.5 175.92,69.86 177.28,69.86 177.68,69.46 177.68,69.32 178.5,68.5 185.63,68.5 188.09,66.04 188.09,65.63 189.32,64.4 189.73,64.4 190.67,63.46 190.67,63.19 190.93,62.93 190.93,60.26 191.11,60.08 191.11,57.62 191.9,56.83 191.9,53.39 191.69,53.19 191.69,47.24 192.99,45.95 192.99,33.09 207.72,18.36 207.72,17.81 207.57,17.66 v2(207.49,17.66)
  BOTTOM w0.076: UCPU1.D13 144.75,70.6 144.75,70.78 144.7,70.96 144.7,71.07 144.68,71.14 144.65,71.22 144.62,71.35 144.62,71.35 144.56,71.55 144.56,71.8 144.59,71.89 144.59,72.08 144.56,72.18 144.56,73.63 144.3,73.89 144.01,73.89 143.87,73.74 v2(143.87,73.62)
  BOTTOM w0.127: v2(207.49,17.66) 207.52,17.66 207.67,17.81 207.67,18.09 207.51,18.25 JIO1.10
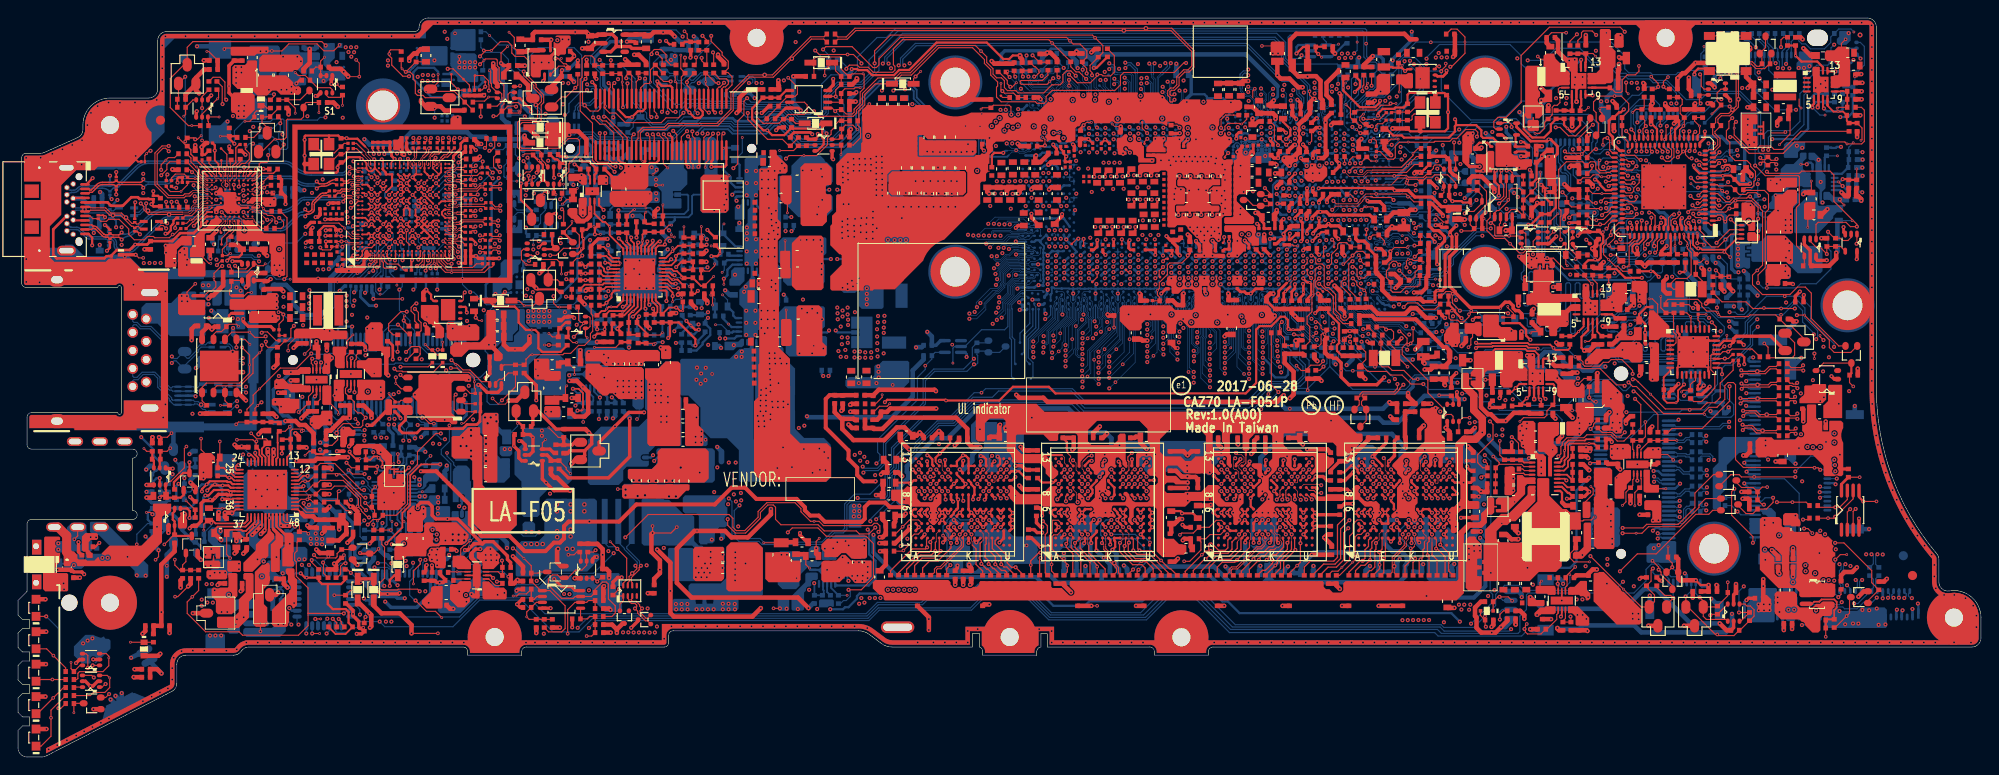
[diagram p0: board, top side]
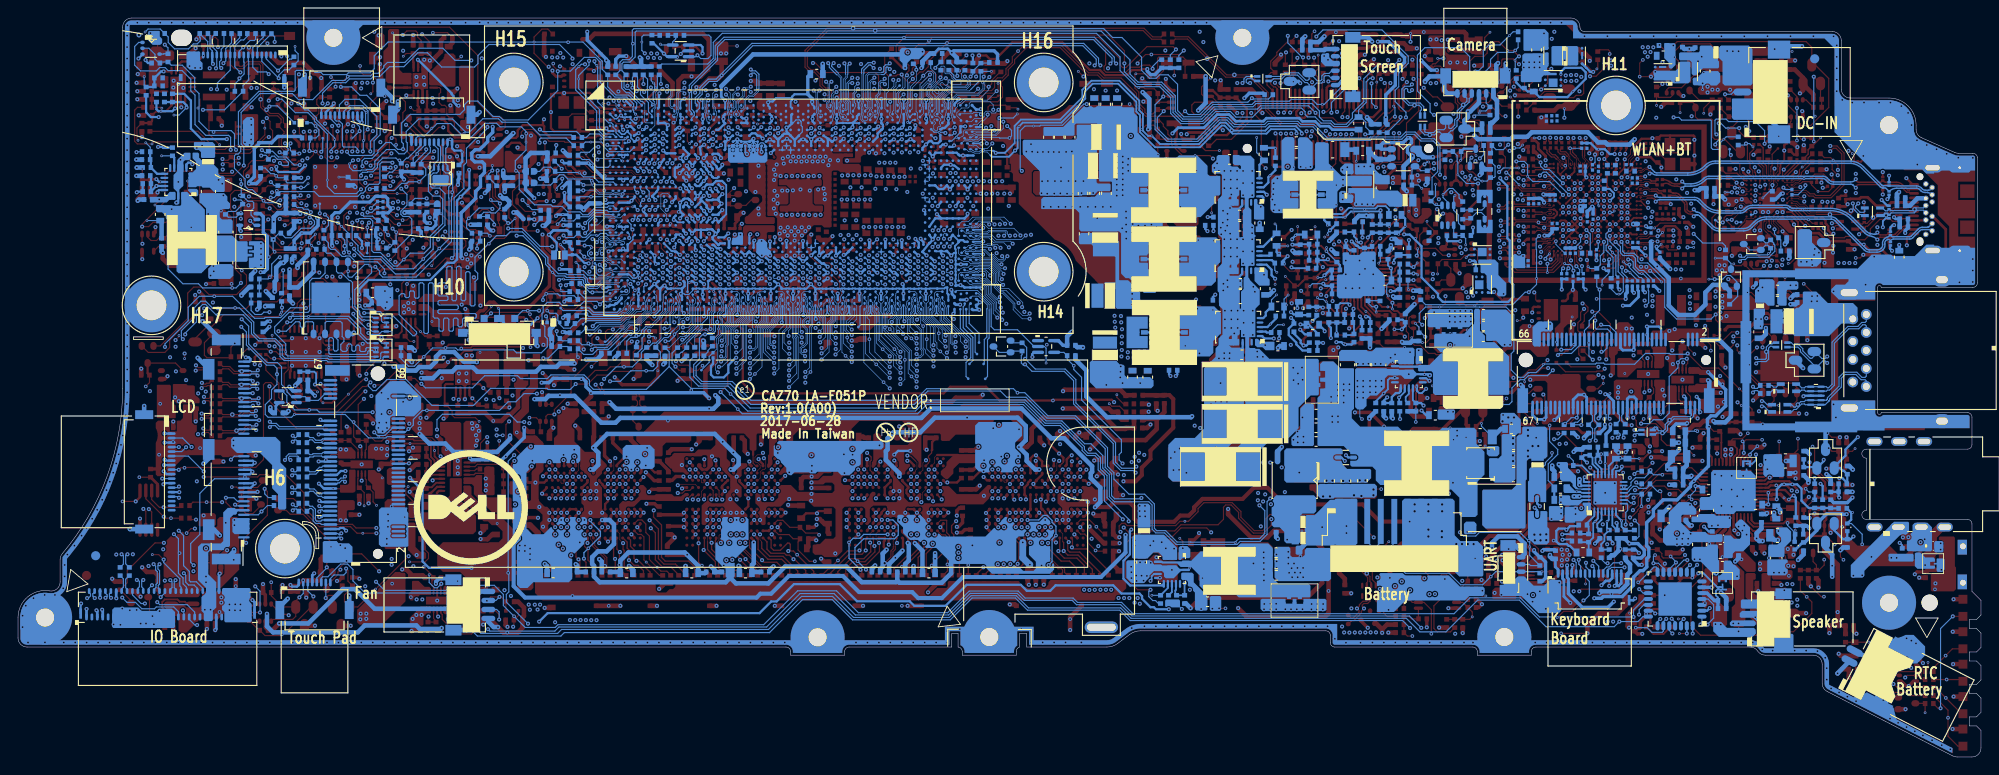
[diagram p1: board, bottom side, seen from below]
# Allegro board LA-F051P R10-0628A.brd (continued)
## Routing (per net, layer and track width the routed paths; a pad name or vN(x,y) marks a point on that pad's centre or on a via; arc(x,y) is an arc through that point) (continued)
USB3TP2: length 166.9
  IN1 w0.091: v2(145.8,74.46) 145.58,74.24 145.43,74.24 143.23,76.43 138.04,76.43 136.77,77.7 120.85,77.7 120.24,77.09 115.62,77.09 115.31,76.78 109.24,76.78 107.12,74.67 107.12,73.77 105.21,71.87 102.74,71.87 100.29,74.31 100.29,76.57 99.25,77.62 94.81,77.62 94.42,77.23 94.42,76.09 92.24,73.91 86.94,73.91 85.73,72.7 80.05,72.7 79.84,72.92 70.48,72.92 69.33,71.77 63.91,71.77 63.25,72.43 61.39,72.43 60.64,73.18 59.82,73.18 58.52,74.48 56.6,74.48 56.12,74 54.08,74 52.38,72.3 46.59,72.3 41.81,67.52 36.87,67.52 35.31,69.08 31.55,69.08 31.17,68.7 31.17,62.18 31.27,62.08 31.27,49.97 31.62,49.62 31.62,48.9 32.12,48.4 32.12,47.81 26.82,42.52 26.82,41.15 26.58,40.9 25.48,40.9 v2(25.3,41.08)
  BOTTOM w0.076: v2(145.8,74.46) 145.8,74.33 145.56,74.1 145.41,74.1 145.23,73.92 145.23,73.34 145.43,73.14 145.43,72.29 145.27,72.13 145.17,72.13 UCPU1.A13
  BOTTOM w0.127: v2(25.3,41.08) 25.12,40.91 24.81,40.91 C623.1
USB3TP2_C: length 1.6
  BOTTOM w0.127: C623.2 23.22,41.23 23.03,41.04 22.71,41.04 22.37,41.38 ML12.4
USB3TP2_RC_CON: length 14.6
  BOTTOM w0.127: 18.89,41.09 17.74,41.09 ; 18.89,41.09 19.47,41.09 19.59,40.97 19.9,40.97 20.31,41.38 ML12.3 ; 18.89,41.09 DI1.6 ; 17.74,41.09 DI1.5 ; 17.74,41.09 17.16,41.09 17.04,40.97 16.91,40.97 16.52,41.36 16.52,46.02 14.77,47.77 13.67,47.77 13.23,48.22 12.87,48.22 12.72,48.36 JUSB2.9
USB20_N1: length 95.6
  IN2 w0.102: v2(200.33,19.62) 200.48,19.47 200.48,19.34 200.34,19.2 199.01,19.2 196.63,21.57 196.63,22.3 194.54,24.4 194.54,26.45 193.6,27.39 192.06,27.39 189.86,29.59 189.86,34.34 188.53,35.67 188.53,45.04 187.94,45.64 186.88,45.64 186.61,45.91 186.61,46.74 185.28,48.07 185.28,52.4 186.26,53.38 186.26,55.5 185.34,56.42 185.34,57.51 184.07,58.78 180.02,58.78 177.93,56.68 176.52,56.68 172.5,60.7 167.2,60.7 164.56,63.35 163.34,63.35 163.14,63.15 159.87,63.15 159.64,62.91 159.64,62.67 159.46,62.48 v2(159.46,62.47)
  IN4 w0.091: v2(159.46,62.47) 159.44,62.48 159.31,62.48 159.23,62.41 159.23,62.15 159.34,62.04 159.67,62.04 159.73,61.99 159.73,61.66 159.33,61.26 156.7,61.26 156.53,61.44 153.68,61.44 152.5,60.26 147.6,60.26 147.5,60.36 147.5,60.62 147.6,60.73 147.71,60.73 v2(147.74,60.7)
  BOTTOM w0.127: UCPU1.AB9 147.44,61 v2(147.74,60.7) ; JIO1.34 200.31,18.63 200.47,18.79 200.47,19.48 v2(200.33,19.62)
USB20_N2: length 186.2
  IN1 w0.091: v2(149.62,59.58) 149.41,59.79 149.41,59.97 149.74,60.3 150.08,60.3 152.55,62.77 152.55,64.48 154.79,66.72 154.79,67.71 154.2,68.3 154.2,74.03 151.51,76.72 151.51,78.42 150.46,79.47 93.18,79.47 90.61,76.89 85.31,76.89 83.85,75.44 80.77,75.44 79.5,74.17 70,74.17 68.8,72.96 64.62,72.96 63.97,73.61 61.92,73.61 61.16,74.36 60.3,74.36 59.88,74.78 59.88,75.6 59.25,76.24 57.35,76.24 56.77,75.66 55.25,75.66 55.04,75.87 52.74,75.87 51.86,74.99 48.88,74.99 47.37,73.48 46.07,73.48 43.81,71.22 43.62,71.22 41.71,69.3 39.01,69.3 37.92,70.39 30.87,70.39 29.91,69.42 29.91,61.75 30.09,61.56 30.09,48.36 30.01,48.28 30.01,47.69 29.51,47.19 29.51,46.97 26.62,44.09 25.12,44.09 v2(24.94,44.27)
  BOTTOM w0.127: UCPU1.AD6 149.37,60.05 149.37,59.71 149.49,59.58 v2(149.62,59.58) ; ML11.1 23.04,45.98 23.19,45.83 23.47,45.83 23.82,45.48 v4(23.82,44.97) 23.82,44.26 23.95,44.13 24.8,44.13 v2(24.94,44.27)
USB20_N2_CONN: length 10.5
  IN4 w0.091: v2(17.07,44.44) 16.81,44.18 16.46,44.18 15.44,45.21 14.32,45.21 14.23,45.3 JUSB2.2
  BOTTOM w0.127: v2(17.07,44.44) 17.29,44.21 17.64,44.21 17.65,44.21 18.43,44.99 DI2.3 18.49,44.52 18.77,44.24 18.95,44.24 19.78,45.07 19.78,45.31 20.2,45.74 20.81,45.74 21.06,45.98 ML11.2
USB20_N3: length 161.1
  IN1 w0.091: v2(38.46,36.28) 38.63,36.1 38.91,36.1 39.22,35.8 39.22,35.26 39.55,34.93 41.05,34.93 41.5,35.39 41.5,35.77 45.11,39.37 45.11,40.85 46.91,42.65 46.91,43.16 47.36,43.6 47.36,45.37 48.76,46.77 48.76,49.3 49.43,49.97 50.88,49.97 51.28,50.38 54.64,50.38 54.93,50.09 60.49,50.09 62.87,52.46 63.48,52.46 63.83,52.81 63.83,56.1 62.88,57.05 62.88,57.77 64.18,59.07 64.18,61.1 64.8,61.71 64.8,63.24 64.57,63.46 64.57,65.17 65.52,66.13 78.37,66.13 79.6,67.36 80.27,67.36 81.06,66.57 82.22,66.57 83.56,67.92 99.29,67.92 100.58,66.63 107.48,66.63 108.19,67.34 108.67,67.34 109.01,67.69 109.59,67.69 109.75,67.52 110.97,67.52 112.12,68.67 114.02,68.67 114.28,68.92 114.28,69.49 114.62,69.84 116.88,69.84 118.96,67.77 120.86,67.77 121.26,67.36 121.26,66.8 121.52,66.54 123.9,66.54 124.21,66.86 124.21,67.68 124.65,68.12 138.01,68.12 138.97,67.15 138.97,64.95 138.5,64.47 138.5,63.89 139.11,63.28 139.11,60.41 140.23,59.29 144.22,59.29 144.34,59.17 150.19,59.17 150.29,59.27 151.38,59.27 152.79,57.86 153.12,57.86 153.45,57.53 153.45,57.27 v2(153.59,57.13)
  BOTTOM w0.076: v2(153.59,57.13) 153.41,57.31 153.41,57.52 153.2,57.74 152.51,57.74 152.07,57.3 151.98,57.3 151.86,57.25 151.75,57.25 151.53,57.32 151.38,57.32 151.22,57.26 151.04,57.26 150.79,57.38 150.65,57.38 UCPU1.AH3
  BOTTOM w0.127: v2(38.46,36.28) 38.32,36.14 38.12,36.14 37.97,36.29 ML10.1
USB20_N3_R: length 6.7
  BOTTOM w0.127: ML10.2 36.42,36.42 36.22,36.62 35.97,36.62 35.87,36.52 35.87,36.32 35.75,36.2 35.22,36.2 35.04,36.39 35.04,36.89 v4(34.55,37.38) 34.16,37.77 32.28,37.77 32.14,37.92 32.14,38.04 32.25,38.16 JNGFF1.5
USB20_N4: length 100.1
  IN1 w0.091: v2(81.94,74.79) 81.74,74.79 81.62,74.67 81.62,74.5 81.78,74.34 85.54,74.34 87.04,75.84 90.52,75.84 93.56,78.88 150.19,78.88 150.92,78.15 150.92,76.48 153.61,73.78 153.61,69.1 153.02,68.5 153.02,67.68 152.57,67.23 152.2,67.23 151.87,66.89 151.87,62.95 150.04,61.12 146.91,61.12 146.66,60.87 146.66,60.51 146.89,60.28 147.29,60.28 147.51,60.05 147.51,59.81 v2(147.74,59.58)
  BOTTOM w0.127: v2(81.94,74.79) 81.79,74.94 81.79,75.24 81.51,75.52 ML9.1 ; v2(147.74,59.58) 147.44,59.89 UCPU1.AD9
USB20_N4_CONN: length 9.7
  BOTTOM w0.127: JTS.3 72.03,76.16 72.33,75.85 72.86,75.85 73.14,75.58 73.14,75.17 73.27,75.04 73.65,75.04 DI4.3 74.54,75.24 74.69,75.09 74.9,75.09 75.73,75.92 77.27,75.92 77.67,75.52 ML9.2
USB20_N5: length 127.1
  IN1 w0.091: v2(153.6,55.84) 153.6,56.15 154.71,57.26 154.71,57.66 153.21,59.16 153.21,60.96 154.01,61.75 154.01,65.1 155.38,66.47 155.38,67.96 154.79,68.54 154.79,74.27 152.12,76.94 152.12,78.84 150.91,80.06 92.91,80.06 90.48,77.63 85.2,77.63 83.62,76.05 80.21,76.05 79.93,75.77 70.73,75.77 68.65,73.69 65.74,73.69 64.96,74.48 63.3,74.48 v2(63.14,74.63)
  BOTTOM w0.076: v2(153.6,55.84) 153.35,56.1 153.35,56.31 153.13,56.53 152.73,56.53 152.63,56.63 152.63,56.95 152.52,57.06 152.31,57.06 UCPU1.AJ1
  BOTTOM w0.127: v2(63.14,74.63) 63.35,74.43 63.95,74.43 64.26,74.12 64.26,73.06 63.52,72.32 v4(62.87,72.32) 62.34,72.32 62.09,72.07 62.09,71.81 62.22,71.69 L55.4
USB20_N5_CONN: length 10.1
  BOTTOM w0.127: L55.3 62.22,69.53 61.72,69.04 v4(61.16,69.04) 60.63,69.04 60.31,69.36 60.06,69.36 59.44,68.73 DI3.3 59.22,68.73 59.1,68.86 59.1,69.21 58.82,69.49 58.66,69.49 58.14,70.01 58.14,70.6 57.86,70.88 57.86,71.6 56.79,72.67 56.79,73.06 56.5,73.35 JCAM.4
USB20_P1: length 95.6
  IN2 w0.102: v2(200.91,19.62) 200.71,19.41 200.71,19.25 200.44,18.97 198.91,18.97 196.41,21.48 196.41,22.21 194.32,24.3 194.32,26.36 193.51,27.17 191.97,27.17 189.64,29.5 189.64,34.25 188.31,35.58 188.31,44.95 187.84,45.42 186.79,45.42 186.39,45.81 186.39,46.65 185.05,47.98 185.05,52.49 186.04,53.48 186.04,55.41 185.12,56.33 185.12,57.41 183.97,58.56 180.12,58.56 178.02,56.46 176.43,56.46 172.41,60.48 167.11,60.48 164.46,63.12 163.43,63.12 163.23,62.92 159.97,62.92 159.86,62.82 159.86,62.66 160.04,62.48 v2(160.04,62.47)
  IN4 w0.091: v2(147.1,60.7) 147.31,60.49 147.31,60.28 147.52,60.06 152.58,60.06 153.76,61.24 156.45,61.24 156.62,61.07 159.41,61.07 159.94,61.6 159.94,62.38 160.04,62.48 v2(160.04,62.47)
  BOTTOM w0.127: UCPU1.AB10 146.79,61.01 v2(147.1,60.7) ; JIO1.32 200.91,18.41 200.91,18.6 200.73,18.79 200.73,19.43 v2(200.91,19.62)
USB20_P2: length 186.1
  IN1 w0.091: v2(24.94,43.67) 25.17,43.9 26.7,43.9 29.7,46.89 29.7,47.11 30.21,47.61 30.21,48.2 30.29,48.28 30.29,61.64 30.1,61.83 30.1,69.34 30.95,70.2 37.84,70.2 38.93,69.11 41.79,69.11 43.7,71.02 43.89,71.02 46.15,73.29 47.45,73.29 48.96,74.8 51.94,74.8 52.82,75.68 54.96,75.68 55.17,75.47 56.85,75.47 57.43,76.04 59.17,76.04 59.69,75.52 59.69,74.7 60.22,74.17 61.08,74.17 61.84,73.42 63.89,73.42 64.54,72.77 68.88,72.77 70.08,73.97 79.58,73.97 80.85,75.24 83.93,75.24 85.39,76.7 90.69,76.7 93.26,79.28 150.38,79.28 151.32,78.34 151.32,76.64 154.01,73.95 154.01,68.22 154.6,67.63 154.6,66.8 152.35,64.56 152.35,62.85 150,60.49 149.66,60.49 149.22,60.05 149.22,59.63 149.18,59.59 v2(149.01,59.59)
  BOTTOM w0.127: ML11.4 23.08,45.48 23.17,45.58 23.36,45.58 23.56,45.38 23.56,44.15 23.84,43.87 24.73,43.87 v2(24.94,43.67) ; UCPU1.AD7 148.94,60.07 149.08,59.92 149.08,59.65 v2(149.01,59.59)
USB20_P2_CONN: length 10.5
  IN4 w0.091: JUSB2.3 14.23,44.92 14.32,45.01 15.36,45.01 16.38,43.99 16.8,43.99 v2(17.07,43.72)
  BOTTOM w0.127: ML11.3 20.31,45.48 20.03,45.2 20.03,44.97 19.05,43.99 19.04,43.99 18.49,43.44 DI2.2 18.44,43.06 17.54,43.96 17.31,43.96 v2(17.07,43.72)
USB20_P3: length 161.1
  IN1 w0.091: v2(38.43,35.7) 38.64,35.91 38.83,35.91 39.03,35.72 39.03,35.18 39.47,34.74 41.13,34.74 41.7,35.31 41.7,35.69 45.3,39.29 45.3,40.77 47.1,42.57 47.1,43.08 47.55,43.52 47.55,45.29 48.95,46.69 48.95,49.22 49.51,49.78 50.96,49.78 51.36,50.18 54.56,50.18 54.85,49.9 60.57,49.9 62.95,52.27 63.56,52.27 64.02,52.73 64.02,56.18 63.07,57.13 63.07,57.69 64.38,58.99 64.38,61.02 64.99,61.63 64.99,63.32 64.76,63.54 64.76,65.09 65.6,65.93 78.45,65.93 79.68,67.17 80.19,67.17 80.98,66.38 82.3,66.38 83.64,67.73 99.21,67.73 100.5,66.44 107.56,66.44 108.27,67.15 108.75,67.15 109.09,67.5 109.51,67.5 109.67,67.33 111.05,67.33 112.2,68.47 114.1,68.47 114.47,68.84 114.47,69.41 114.7,69.65 116.8,69.65 118.88,67.57 120.78,67.57 121.07,67.28 121.07,66.72 121.44,66.35 123.98,66.35 124.4,66.78 124.4,67.6 124.73,67.93 137.93,67.93 138.78,67.07 138.78,65.03 138.3,64.55 138.3,63.81 138.91,63.2 138.91,60.33 140.15,59.1 144.14,59.1 144.26,58.97 150.27,58.97 150.37,59.07 151.3,59.07 152.71,57.67 153.04,57.67 153.25,57.45 153.25,57.39 v2(153,57.13)
  BOTTOM w0.076: v2(153,57.13) 153,57.14 153.25,57.38 153.25,57.45 153.13,57.57 152.58,57.57 152.14,57.14 152.01,57.14 151.89,57.09 151.72,57.09 151.5,57.15 151.41,57.15 151.25,57.1 151.19,57.1 151.18,57.09 151.02,57.09 150.9,57.15 150.76,57.21 150.58,57.21 150.5,57.13 150.5,56.97 150.6,56.87 UCPU1.AJ3
  BOTTOM w0.127: ML10.4 37.96,35.79 38.05,35.89 38.24,35.89 v2(38.43,35.7)
USB20_P3_R: length 6.7
  BOTTOM w0.127: JNGFF1.3 31.75,38.19 31.88,38.05 31.88,37.81 32.18,37.51 34.06,37.51 34.78,36.79 34.78,36.28 35.12,35.95 v4(35.35,35.95) 35.98,35.95 36.14,35.79 ML10.3
USB20_P4: length 100.1
  IN1 w0.091: v2(147.1,59.58) 147.1,59.59 147.32,59.8 147.32,59.97 147.21,60.08 146.81,60.08 146.47,60.43 146.47,60.95 146.83,61.31 149.96,61.31 151.67,63.03 151.67,66.97 152.12,67.42 152.49,67.42 152.83,67.76 152.83,68.58 153.42,69.18 153.42,73.7 150.72,76.4 150.72,78.07 150.11,78.69 93.64,78.69 90.6,75.65 87.12,75.65 85.62,74.15 81.7,74.15 81.43,74.42 81.43,74.62 81.26,74.79 v2(81.1,74.79)
  BOTTOM w0.127: UCPU1.AD10 146.79,59.9 v2(147.1,59.58) ; ML9.4 80.6,75.02 80.84,75.27 81.41,75.27 81.53,75.14 81.53,74.89 81.38,74.74 81.15,74.74 v2(81.1,74.79)
USB20_P4_CONN: length 9.7
  BOTTOM w0.127: ML9.3 78.73,75.02 78.48,75.27 77.57,75.27 77.17,75.67 75.84,75.67 75.01,74.84 74.77,74.84 74.54,74.61 74.54,74 DI4.2 74.51,74 73.73,74.79 73.16,74.79 72.89,75.06 72.89,75.47 72.76,75.6 72.36,75.6 72.12,75.36 JTS.2
USB20_P5: length 127.1
  IN1 w0.091: v2(153.02,55.84) 154.52,57.34 154.52,57.58 153.02,59.08 153.02,61.04 153.81,61.83 153.81,65.18 155.18,66.55 155.18,67.88 154.6,68.46 154.6,74.19 151.93,76.86 151.93,78.76 150.83,79.87 92.99,79.87 90.56,77.44 85.28,77.44 83.7,75.85 80.29,75.85 80.01,75.57 70.81,75.57 68.73,73.5 65.66,73.5 64.88,74.29 63.35,74.29 63.13,74.07 v2(63.13,74.01)
  BOTTOM w0.076: UCPU1.AJ2 151.65,56.87 151.93,56.59 152.44,56.59 152.66,56.37 153.06,56.37 153.18,56.24 153.18,56.01 v2(153.02,55.84)
  BOTTOM w0.127: v2(63.13,74.01) 63.13,73.92 63.3,73.75 63.49,73.75 63.61,73.88 63.61,74.09 63.7,74.18 63.84,74.18 64.01,74.01 64.01,73.17 63.41,72.58 62.24,72.58 61.84,72.18 61.84,71.81 61.72,71.69 L55.1
USB20_P5_CONN: length 10.1
  BOTTOM w0.127: L55.2 61.72,69.39 61.62,69.29 60.73,69.29 60.41,69.61 59.59,69.61 59.4,69.8 59.4,70.59 DI3.2 59.18,70.66 59.05,70.53 59.05,69.82 58.97,69.74 58.77,69.74 58.4,70.12 58.4,70.71 58.11,70.99 58.11,71.7 v4(57.45,72.37) 57.04,72.77 57.04,73.09 57.3,73.35 JCAM.5
USB_OC1#: length 100.7
  TOP w0.127: v2(149.63,74.27) 149.63,74.64 v1(149.76,74.76)
  IN4 w0.081: v2(149.63,74.27) 149.63,74.66 149.86,74.89 152.32,74.89 152.72,74.48 158.05,74.48 158.7,73.83 158.7,72.95 160.94,70.71 163.59,70.71 164.57,69.72 164.57,68.25 167.01,65.82 167.7,65.82 168.57,64.95 168.57,63.09 169.1,62.55 169.1,61.16 169.72,60.54 169.72,58.15 173.46,54.42 173.46,48.7 174.26,47.9 174.26,47.03 176.81,44.48 177.68,44.48 178.11,44.05 179.02,44.05 179.56,43.51 180.64,43.51 180.92,43.23 180.92,38.27 182.52,36.67 182.52,31.07 187.33,26.27 189.87,26.27 191.54,24.6 191.54,23.43 192.91,22.06 199.24,22.06 201.22,20.07 201.93,20.07 v2(202.95,19.06)
  BOTTOM w0.127: UCPU1.C9 147.47,71.22 147.86,71.61 147.86,72.62 148.74,73.5 148.74,74 149.07,74.33 149.07,75.45 RC185.1 149.63,75.4 v2(149.63,74.27) ; JIO1.24 203.31,18.41 203.31,18.69 v2(202.95,19.06)
USB_OC2#: length 188.8
  TOP w0.127: v2(22.66,54.48) 22.56,54.48 21.74,53.67 v1(21.74,53.2) 21.74,52.92 21.95,52.71 21.95,52.16 21.5,51.71 21.2,51.71 20.67,51.18 US2.5
  IN2 w0.089: v2(22.66,54.48) 22.56,54.48 22.21,54.14 21.87,54.14 18.09,57.92 18.09,61.96 18.49,62.37 18.94,62.37 19.09,62.52 19.09,63.24 19.05,63.28 19.05,64.18 18.9,64.34 18.9,65.12 20.78,67.01 20.78,67.98 22.2,69.41 22.2,72.6 23.57,73.97 26.64,73.97 27.48,73.13 31.24,73.13 32.9,74.8 32.9,75.79 33.47,76.35 34.29,76.35 34.69,75.94 35.86,75.94 36.27,76.35 38.49,76.35 40.39,78.25 53.76,78.25 54.18,78.68 56.02,78.68 57.94,80.59 62.68,80.59 64.54,78.72 v2(64.54,77.35)
  BOTTOM w0.076: 148.26,72.48 148.26,71.54 148.31,71.48 148.31,70.52 148.15,70.36 UCPU1.D9
  BOTTOM w0.127: v2(64.54,77.35) 65.02,76.87 66.87,76.87 68.48,75.27 68.48,72.73 69.75,71.46 69.75,70.9 70.43,70.21 71.73,70.21 72.1,70.59 72.98,70.59 73.41,71.03 73.41,71.69 74.24,72.51 80.42,72.51 80.78,72.15 85.1,72.15 86.47,70.79 88.56,70.79 89.4,71.62 89.4,73.38 90.91,74.89 93.52,74.89 94.43,75.79 94.43,77.35 97.63,80.56 149.21,80.56 149.33,80.43 149.33,77.68 149.9,77.11 150.63,77.11 150.8,76.94 150.8,76.16 RC188.1 150.57,75.47 150.57,74.3 150.36,74.08 150.01,74.08 148.68,72.75 148.54,72.75 148.26,72.48
USB_OC3#: length 4.4
  BOTTOM w0.076: UCPU1.B9 147.47,71.84 147.21,72.09 147.21,72.73
  BOTTOM w0.127: RC191.1 147.55,75.04 v1(147.3,74.79) 147.17,74.67 147.17,73.93 147.33,73.77 147.33,72.85 147.21,72.73
USB_PWR_SHR_DET_R#: length 13
  TOP w0.127: v2(183.86,59.32) 184.11,59.06 UE5.B63
  IN3 w0.089: v2(183.86,59.32) 185.18,58 186.22,58 v2(188.75,55.46)
  BOTTOM w0.127: v2(188.75,55.46) 188.9,55.46 189.66,54.7 189.66,53.44 v3(189.86,53.24) 190.06,53.04 CE56.1 RE36.2 RE34.1
USB_PWR_SHR_EN_R#: length 180.4
  IN3 w0.089: v2(62.1,14.33) 62.1,14.34 60.73,15.72 56.35,15.72 56.05,16.02 50.31,16.02 48.69,14.4 40.12,14.4 39.48,15.04 38.31,15.04 37.94,15.41 v2(37.94,15.8)
  IN4 w0.081: v2(165.67,14.18) 166.32,14.18 166.76,14.63 169.41,14.63 170.13,13.9 173.1,13.9 173.62,14.42 174.65,14.42 175.3,13.78 194.79,13.78 195.75,14.73 197.07,14.73 198.02,13.78 200.48,13.78 v2(203.73,17.03)
  BOTTOM w0.127: v2(62.1,14.33) 63.41,15.64 94.2,15.64 95.46,16.9 100.36,16.9 100.84,17.38 106.16,17.38 106.94,18.15 112.16,18.15 114.55,15.76 124.89,15.76 127.27,18.13 131.03,18.13 134.74,14.42 157.79,14.42 158.25,13.97 165.45,13.97 v2(165.67,14.18) ; v2(203.73,17.03) 204.15,17.03 205.11,17.98 JIO1.18 ; UE4.19 37.41,16.88 37.92,16.37 37.92,15.82 v2(37.94,15.8)
USB_PWR_SHR_VBUS_EN_R: length 176.9
  TOP w0.127: v2(38.55,15.54) 38.41,15.4 RE89.1
  IN2 w0.089: v2(178.09,19.44) 179.15,18.37 181.2,18.37 184.13,15.45 187.43,15.45 189.27,13.61 196.91,13.61 v2(197.94,14.64)
  BOTTOM w0.127: UE4.18 37.34,17.53 38.55,16.32 v2(38.55,15.54) 48.98,15.54 51.11,17.66 56.7,17.66 58.47,15.9 94.1,15.9 95.35,17.15 100.25,17.15 100.73,17.63 106.06,17.63 106.83,18.41 112.26,18.41 114.66,16.01 124.56,16.01 126.99,18.43 131.31,18.43 135.07,14.68 157.9,14.68 158.2,14.37 161.53,14.37 v3(162.77,15.61) 163.96,16.8 163.96,18.04 164.97,19.05 166.58,19.05 167.14,18.49 177.14,18.49 v2(178.09,19.44) ; v2(197.94,14.64) 198.17,14.64 198.81,15.28 198.81,15.54 JIO1.39
USB_VBUS_EN_L: length 53.1
  TOP w0.127: v2(24.09,54.5) 24.42,54.16 25.28,54.16 25.5,54.39 U699.2 ; v2(37.92,18.63) 37.74,18.44 36.84,18.44 RE59.1 v3(35.09,17.95)
  IN1 w0.081: v2(37.92,18.63) 35.71,20.84 35.71,21.68 34.6,22.79 34.6,25.74 34.1,26.23 34.1,32.28 33.1,33.28 33.1,35.34 31.57,36.86 31.57,36.86 29.96,38.48 28.33,38.48 27.4,37.55 24.3,37.55 23.42,38.42 23.42,53.84 v2(24.09,54.5)
  BOTTOM w0.127: UE4.17 37.47,18.18 v2(37.92,18.63)
USBC_MCP23017_SMBCLK: length 347.3
  TOP w0.127: v2(15.89,64.56) 16.52,65.18 16.52,65.74 16.82,66.05 R1441.1 ; UE5.B4 186.84,60.77 186.78,60.7 185.56,60.7 v2(185.32,60.46) ; U48.2 202.98,27.19 v2(203.29,27.5)
  IN1 w0.081: v2(61.19,18.07) 60.74,17.62 60.5,17.62 60.13,17.99 55.44,17.99 54.57,17.11 47.02,17.11 45.99,16.08 45.14,16.08 44.89,16.34 43.01,16.34 41.33,18.01 37.68,18.01 35.14,20.56 32.26,20.56 v2(31.5,21.32) 31.06,21.32 30.73,21.64 30.73,23.68 32.61,25.56 32.61,27.39 32.87,27.64 32.87,32.63 32.47,33.02 32.47,35.08 29.78,37.77 29.58,37.77 28.72,36.91 24.05,36.91 22.8,38.16 22.8,52.7 19.9,55.6 19.9,60.26 21.08,61.44 21.08,63.82 20.42,64.47 18.88,64.47 18.54,64.81 16.96,64.81 16.71,65.06 16.39,65.06 v2(15.89,64.56) ; v2(203.29,27.5) 202.44,28.36 199.8,28.36 198.78,29.37 198.78,32.84 193.23,38.39 193.23,42.82 192.14,43.91 192.14,52.26 192.65,52.77 192.65,60.02 191.17,61.5 191.17,62.1 189.92,63.36 189.33,63.36 188.31,62.33 188.31,61.02 189.19,60.13 189.19,59.56 188.94,59.3 188.5,59.3 187.12,60.68 185.57,60.68 185.35,60.46 v2(185.32,60.46)
  IN3 w0.089: v2(185.32,60.46) 185.05,60.19 185.05,59.58 184.92,59.45 184.92,58.88 185.12,58.68 186.46,58.68 187.16,57.98 188.68,57.98 189.23,57.43 189.23,54.25 187.64,52.67 181.78,52.67 180.87,53.57 179.25,53.57 177.92,52.24 177.92,51.36 177.44,50.87 177.44,49.67 176.71,48.94 176.71,45.88 179.25,43.34 180.4,43.34 180.73,43.02 180.73,39.65 179.98,38.89 174.16,38.89 173.79,39.26 171.41,39.26 170.7,38.56 166.61,38.56 166.08,38.03 163.76,38.03 163.41,37.68 163.05,37.68 162.64,37.27 162.64,34.84 163.66,33.81 163.66,31.45 161.03,28.81 161.03,28.35 160.86,28.18 160.86,24.99 156.03,20.16 106.89,20.16 106.47,20.59 99.52,20.59 96.26,23.85 96.26,30.12 v2(95.11,31.28)
  IN4 w0.081: v2(95.11,31.28) 94.9,31.07 93.72,31.07 93.41,31.39 93.41,31.99 91.99,33.4 89.08,33.4 88.66,33.82 88.08,33.82 87.26,33 85.33,33 84.94,32.61 84.94,31.99 84.11,31.16 79.25,31.16 78.05,29.96 77.1,29.96 74.26,27.11 72.07,27.11 69.96,25 69.96,24.12 66.23,20.39 64.25,20.39 61.92,18.07 v2(61.19,18.07)
  BOTTOM w0.127: UE4.8 31.99,20.83 31.99,20.83 v2(31.5,21.32) ; RE73.1 186.83,60.96 186.28,60.96 186.11,60.79 185.65,60.79 v2(185.32,60.46)
USBC_MCP23017_SMBCLK_R: length 3.3
  TOP w0.076: U722.L2 20.94,64.04 20.83,64.04 20.73,64.14 20.39,64.14 20.37,64.17
  TOP w0.127: 20.37,64.17 19.92,64.61 19.92,64.84 R1441.2
USBC_MCP23017_SMBDAT: length 341.9
  TOP w0.127: UE5.A3 188.06,60.52 188.43,60.52 188.49,60.47 189.48,60.47 v2(189.89,60.88) 190.36,60.88 RE71.1 ; R1442.1 17.37,66.51 16.68,66.51 v1(16.4,66.23) 15.88,65.71 v2(15.88,65.14) ; U48.3 203.63,27.25 v2(203.9,27.52)
  IN1 w0.081: v2(203.9,27.52) 203.49,27.11 203.13,27.11 202.9,27.34 202.9,27.59 202.34,28.15 199.71,28.15 198.57,29.29 198.57,29.46 198.57,32.76 193.02,38.31 193.02,42.74 191.91,43.84 191.91,47.98 191.93,48 191.93,52.35 192.44,52.86 192.44,59.93 190.96,61.41 190.96,62.02 189.83,63.15 189.42,63.15 189.22,62.95 189.22,61.61 189.89,60.93 v2(189.89,60.88) ; v2(60.59,18.08) 59.82,18.86 55.07,18.86 54.83,18.62 54.83,18.01 54.15,17.32 46.94,17.32 45.91,16.29 45.23,16.29 44.98,16.54 43.1,16.54 41.42,18.22 37.77,18.22 35.23,20.76 32.9,20.76 32.35,21.31 v2(32.28,21.31) 32.19,21.4 32.19,22.33 31.78,22.75 31.78,24.43 32.82,25.47 32.82,27.3 33.08,27.56 33.08,32.71 32.68,33.11 32.68,35.16 29.86,37.98 29.5,37.98 28.64,37.12 24.14,37.12 23.01,38.25 23.01,52.79 20.11,55.68 20.11,60.18 21.29,61.35 21.29,64.82 20.45,65.65 16.38,65.65 v2(15.88,65.14)
  IN3 w0.089: v2(189.89,60.88) 189.89,61 189.63,60.74 185.7,60.74 185.57,60.87 185.12,60.87 185.01,60.77 183.76,60.77 183.33,60.34 183.33,58.33 184.06,57.61 184.06,55.43 182.53,53.91 182.53,53.19 182.22,52.88 181.87,52.88 180.96,53.79 179.16,53.79 177.71,52.33 177.71,51.44 177.14,50.88 176.71,50.88 176.48,50.64 176.48,45.81 179.16,43.13 180.32,43.13 180.51,42.93 180.51,39.74 179.9,39.12 174.24,39.12 173.88,39.48 171.32,39.48 170.61,38.78 166.52,38.78 165.99,38.24 163.66,38.24 163.31,37.9 162.96,37.9 162.42,37.36 162.42,34.75 163.39,33.77 163.39,31.49 160.81,28.9 160.81,28.58 160.53,28.3 160.53,25.08 155.94,20.49 125.6,20.49 124.2,21.89 118.35,21.89 116.85,20.39 106.97,20.39 106.53,20.84 99.58,20.84 96.52,23.89 96.52,33.07 95.62,33.97 93.63,33.97 v2(93.42,33.76)
  IN4 w0.081: v2(60.59,18.08) 60.59,18.1 60.97,18.48 62.04,18.48 64.17,20.61 66.15,20.61 69.76,24.21 69.76,25.09 71.99,27.32 74.17,27.32 77.01,30.16 77.97,30.16 79.17,31.37 82.8,31.37 84.65,33.21 87.18,33.21 87.91,33.94 87.91,34.49 88.13,34.71 89.79,34.71 90.55,33.95 93.23,33.95 v2(93.42,33.76)
  BOTTOM w0.127: UE4.9 32.64,20.61 32.64,20.61 32.64,20.95 v2(32.28,21.31)
USBC_MCP23017_SMBDAT_R: length 4.5
  TOP w0.076: 20.47,64.37 20.75,64.37 20.9,64.23 21.26,64.23 U722.K2
  TOP w0.127: 20.47,64.37 20.14,64.7 20.14,65.16 v1(19.84,65.46) 19.76,65.46 19.19,66.03 19.19,66.47 R1442.2
USBCOMP: length 2.5
  TOP w0.127: RC44.1 150.37,61.05 v1(149.6,61.05) 149.41,61.05 v2(149.06,60.69)
  BOTTOM w0.127: UCPU1.AB6 149.39,61.05 149.06,60.72 v2(149.06,60.69)
VCI_IN3#: length 6.5
  TOP w0.127: RPE5.3 191.24,58.01 190.06,58.01 v3(189.46,57.41) 188.65,56.6 187.92,56.6 187.06,57.45 187.06,57.97 186.61,58.42 UE5.B68
VID0_PRIM_CORE: length 4.4
  TOP w0.127: PR1419.2 201.96,72.09 v1(201.85,71.99)
  TOP w0.203: PU1401.9 202.22,73.85 202.27,73.89 202.49,73.89 202.51,73.87 PR1418.1 PR1415.2 PR1419.2
VID0_VCCIO: length 2.4
  TOP w0.254: PU1400.9 176.87,49.12 PR1407.1
  TOP w0.508: PR1405.2 PR1407.1
VID1_PRIM_CORE: length 7.4
  TOP w0.127: PR1414.2 204.61,69.8 204.61,68.55 v1(204.5,68.44)
  TOP w0.203: 200.78,72.28 201.45,71.61 202.51,71.61 PR1417.1 202.92,70.6 PR1420.2
  TOP w0.254: 200.78,72.28 200.78,72.38 200.78,72.38 PU1401.8 ; PR1414.2 PR1420.2
VID1_VCCIO: length 2.7
  TOP w0.203: PR1406.1 175.22,47.21 PU1400.8
  TOP w0.254: PR1406.1 176.61,46.69 PR1404.2
VIDALERT_N: length 79.6
  TOP w0.127: v2(60.81,53.6) 61.01,53.81 PR1024.1
  IN4 w0.081: v2(60.81,53.6) 60.81,54.13 62.22,55.54 62.22,55.95 62.87,56.61 62.87,58.65 63.83,59.61 63.83,61.3 64.7,62.17 64.7,63.05 64.32,63.43 64.32,64.94 66.65,67.27 66.65,70.51 70.28,74.15 70.28,75.37 70.72,75.81 72.4,75.81 73.05,76.45 78.73,76.45 79.79,75.39 82.79,75.39 83.95,74.23 87.08,74.23 87.47,74.61 93.97,74.61 94.34,74.98 94.34,77.56 95,78.21 108.31,78.21 109.82,76.7 115.79,76.7 v2(116.03,76.46)
  BOTTOM w0.127: v2(116.03,76.46) 116.03,76.51 RC153.2 115.27,77.28 RC152.2
VIDSCLK: length 78.2
  TOP w0.127: PR1125.1 60.94,52.92 v2(60.83,53.02) ; v2(112.57,77.86) 113.34,77.1 RC158.2 114.25,77.1 RC155.2
  IN4 w0.081: v2(112.57,77.86) 112.57,77.3 112.19,76.92 109.91,76.92 108.41,78.42 94.91,78.42 94.13,77.64 94.13,75.07 93.88,74.82 87.38,74.82 87,74.44 84.04,74.44 82.88,75.6 79.88,75.6 78.82,76.66 72.96,76.66 72.32,76.02 70.63,76.02 70.07,75.45 70.07,74.23 66.44,70.6 66.44,67.35 64.11,65.03 64.11,63.28 64.49,62.9 64.49,62.26 64,61.77 64,61.77 63.62,61.39 63.62,59.7 62.66,58.74 62.66,56.69 62.01,56.04 62.01,55.62 60.33,53.94 60.33,53.32 60.63,53.02 v2(60.83,53.02)
VIDSCLK_R: length 12.2
  TOP w0.127: RC155.1 114.28,75.67 113.67,75.07 111.3,75.07 111.2,74.96 111.2,74.76 111.32,74.65 114.18,74.65 v1(114.47,74.93) v2(114.86,75.32)
  BOTTOM w0.076: v2(114.86,75.32) 115.03,75.32 115.3,75.05 115.43,75.05 116.71,73.77 116.71,73.58 116.31,73.18 116.31,72.39 UCPU1.A63
VIDSOUT: length 79.3
  TOP w0.127: PR1025.1 61.44,54.8 61.98,55.33 62.31,55.33 v2(62.61,55.63)
  IN4 w0.081: v2(113.59,75.57) 114.45,75.57 115.16,76.29 115.16,76.41 115.09,76.49 109.73,76.49 108.22,78 95.14,78 94.59,77.45 94.59,74.94 94.06,74.41 87.55,74.41 87.17,74.02 83.87,74.02 82.71,75.18 79.71,75.18 78.64,76.24 73.14,76.24 72.41,75.52 70.79,75.52 70.49,75.22 70.49,74.06 66.85,70.43 66.85,67.18 64.59,64.92 64.59,63.46 64.91,63.14 64.91,62.09 64.04,61.22 64.04,59.53 63.08,58.57 63.08,56.27 62.61,55.8 v2(62.61,55.63)
  BOTTOM w0.127: v2(62.61,55.63) 62.51,55.74 v1(62.51,56.4) ; v2(113.59,75.57) 113.64,75.62 RC157.2 113.64,76.3 114.47,77.12 RC154.2
VIDSOUT_R: length 13.7
  BOTTOM w0.076: UCPU1.D64 115.82,70.7 115.91,70.8 116.08,70.8 116.19,70.69 116.19,70.58 116.03,70.42 116.03,70.29 116.21,70.11 116.21,69.68 116.05,69.53 115.82,69.53 115.77,69.58 115.77,69.86 115.7,69.94 115.52,69.94 115.47,69.99 115.47,70.16 115.57,70.27 115.57,70.49 115.42,70.65 115.42,70.77 115.7,71.05 115.98,71.05 116.18,71.26 116.18,71.39 115.89,71.68 115.89,73.21 114.65,74.44 112.67,74.44 112.45,74.67 112.45,74.83 112.57,74.95 112.97,74.95 113.21,75.19 113.77,75.19
  BOTTOM w0.127: 113.77,75.19 113.97,75.4 113.97,75.65 RC154.1
VL: length 6.4
  TOP w0.203: v2(61.57,40.85) 62.21,40.85 62.69,40.37 v1(62.69,38.62) 62.51,38.44 v2(62.08,38.44)
  BOTTOM w0.203: v2(61.57,40.85) 62.04,40.38 62.33,40.38 62.59,40.63 PU501.15
  BOTTOM w0.254: PC523.1 61.57,37.93 v2(62.08,38.44)
VR_EN_CORE: length 3.5
  TOP w0.203: PR1029.2 65.02,50.12 v2(65.3,50.4) 65.3,50.43 65.87,50.99 65.87,51.41 66.21,51.76 PU1000.40
  BOTTOM w0.127: v2(65.3,50.4) v1(65.3,49.72)
VR_HOT_CORE: length 4.3
  TOP w0.203: PR1124.2 62.87,52.41 64.87,52.41 65.02,52.56 PU1000.38
VR_READY_CORE: length 2.9
  TOP w0.203: PU1000.39 65.26,52.16 65,51.9 PR1095.2 PR1027.2
VRALERT#: length 15.4
  IN4 w0.089: v2(149.84,46.95) 150.22,47.33 150.22,47.58 145.72,52.08 145.24,52.08 144.99,52.32 144.99,54.18 144.97,54.21 144.97,55.32 v2(145.37,55.72)
  BOTTOM w0.076: v2(145.37,55.72) 145.7,56.05 UCPU1.AM11
  BOTTOM w0.127: RC73.1 152.12,44.81 v1(151.1,45.83) 149.98,46.95 v2(149.84,46.95)
VSA_SEN+: length 95.4
  TOP w0.127: v1(141.22,68.29) 141.17,68.29 140.82,67.93 v2(140.72,67.93) 139.97,68.69 RC168.2
  TOP w0.254: PC1072.2 68.61,58.3 PR1077.2 68.66,57.67 v2(68.62,57.64)
  IN2 w0.089: v2(68.62,57.64) 68.63,57.64 68.78,57.49 69.24,57.49 69.66,57.91 72.44,57.91 74.35,59.81 74.35,64.19 75.03,64.88 76.05,64.88 76.33,65.16 76.33,66 78.07,67.74 80,67.74 81.03,66.71 81.81,66.71 82.81,67.71 96.33,67.71 97.68,66.37 97.68,65.3 98.44,64.54 104.4,64.54 105.02,63.92 107.76,63.92 108.39,64.54 112.94,64.54 113.61,65.21 115.47,65.21 116.16,65.9 116.59,65.9 117.37,66.68 119.08,66.68 119.34,66.94 119.34,67.26 119.57,67.49 120.03,67.49 120.28,67.73 123.33,67.73 123.77,68.18 126.39,68.18 126.68,68.48 126.68,70.15 126.95,70.42 127.35,70.42 128.4,71.47 137.25,71.47 138.44,70.27 138.44,68.44 138.78,68.11 139.32,68.11 139.52,68.31 140.34,68.31 v2(140.72,67.93)
  BOTTOM w0.127: PC1072.2 68.66,59.34 PR1077.2 68.66,57.67 v2(68.62,57.64) ; v2(140.72,67.93) 141.01,67.64 UCPU1.H20
VSA_SEN-: length 96.4
  TOP w0.127: v2(139.8,67.89) 139.8,68.05 139.41,68.45 139.41,70.06 138.94,70.53 RC166.1
  TOP w0.203: PU1000.26 68.76,56.57 68.71,56.63 68.71,56.98 v2(68.81,57.08)
  IN2 w0.089: v2(68.81,57.08) 69,57.27 69.33,57.27 69.75,57.69 72.53,57.69 74.56,59.72 74.56,64.11 75.12,64.66 76.77,64.66 77.42,65.31 77.42,66.79 78.16,67.52 79.91,67.52 80.94,66.49 81.9,66.49 82.9,67.5 96.24,67.5 97.46,66.28 97.46,65.21 98.36,64.32 104.32,64.32 104.94,63.7 107.85,63.7 108.47,64.32 114.88,64.32 116.25,65.69 117.51,65.69 118.29,66.47 119.68,66.47 120.17,66.96 120.17,67.32 120.37,67.52 123.42,67.52 123.86,67.97 127.09,67.97 127.5,68.37 127.5,70.26 128.49,71.26 137.16,71.26 137.59,70.82 137.59,68.39 138.09,67.89 v2(139.8,67.89)
  BOTTOM w0.127: v2(139.8,67.89) 140.06,67.64 UCPU1.H21
  BOTTOM w0.203: PC1074.1 PC1077.1 69.57,57.77 69.28,57.48 v1(69.28,57.28) 69.09,57.08 v2(68.81,57.08)
VSET_5085: length 3.4
  TOP w0.127: RE77.1 CE55.1 186.03,70.57 v1(186.59,70.01) 186.59,69.22 186.36,69 186.36,68.72 UE5.A17
WLAN_WIGIG60GHZ_DIS#: length 44.2
  TOP w0.127: v2(41.76,43.09) 42.03,42.82 42.61,42.82 42.68,42.74 46.1,42.74 DZ1.1 ; v2(35.59,15.32) 35.59,15.31 35.86,15.03 35.86,14.78 RE14.2
  IN4 w0.081: v2(41.76,43.09) 41.57,43.28 35.68,43.28 34.85,42.45 34.85,41.4 34.73,41.28 34.73,39.56 35.05,39.24 35.05,34.94 34.79,34.69 34.79,33.48 33.93,32.62 33.93,27.85 35.15,26.63 35.15,22.18 34.65,21.68 34.65,16.69 35.56,15.77 35.56,15.34 v2(35.59,15.32)
  BOTTOM w0.127: v2(35.59,15.32) 35.59,15.31 35.89,15 UE4.22
WLAN_WIGIG60GHZ_DIS#_R: length 3.9
  TOP w0.127: v1(47.12,46.03) DZ1.2 46.62,45.16 v2(46.58,45.2)
  BOTTOM w0.127: JNGFF1.48 45,45.67 45.46,45.2 v2(46.58,45.2)
XCLK_BIASREF: length 1.6
  TOP w0.127: RC52.1 128.59,70.11 v2(128.87,69.83)
  BOTTOM w0.076: v2(128.87,69.83) 128.64,69.59 UCPU1.E42
XDP_DBRESET#: length 118.1
  TOP w0.127: JXDP1.48 67.1,67.33 67.1,68.75 65.27,70.58 64.84,70.58 v2(64.41,71)
  IN1 w0.081: v2(142.42,77.87) 142.85,77.44 145.23,77.44 147.59,75.08 v2(147.59,74.29)
  IN3 w0.089: v2(147.59,74.29) 147.59,73.84 146.46,72.72 144.15,72.72 144.06,72.63 143.68,72.63 143.37,72.93 143.37,74.55 143.04,74.88 142.84,74.88 142.72,74.99 140.35,74.99 139.88,74.52 139.88,73.29 139.98,73.19 139.98,72.37 138.28,70.67 137.45,70.67 137.2,70.43 136.74,70.43 136.63,70.54 135.61,70.54 134.94,71.22 129.48,71.22 129.35,71.08 127.29,71.08 127.13,71.24 126.65,71.24 126.23,70.82 122.87,70.82 122.48,71.21 121.48,71.21 120.97,70.71 118.08,70.71 117.53,70.16 114.96,70.16 114.3,69.5 114.3,69.14 112.81,67.66 109.58,67.66 109.5,67.73 109.49,67.73 109.02,68.2 97.39,68.2 96.06,69.54 93.81,69.54 92.12,67.85 88.21,67.85 87.33,68.72 82.57,68.72 82.17,69.12 78.93,69.12 78.21,69.84 74.32,69.84 73.56,70.6 71.88,70.6 71.63,70.35 65.12,70.35 64.47,71 v2(64.41,71)
  BOTTOM w0.127: v2(64.41,71) 64.41,70.75 RC137.2 66.75,69.27 CC32.1 ; RC290.1 143.89,80.11 141.16,80.11 140.92,79.87 140.92,77.83 141.25,77.5 142.06,77.5 v2(142.42,77.87) 142.58,77.71 UC12.1
XDP_OBS0: length 5.2
  TOP w0.127: JXDP1.21 73.6,73.05 73.6,75.46 RC239.2 74.02,75.9 73.55,76.37 v1(73.55,77.89)
XDP_OBS0_R: length 63.2
  TOP w0.127: v2(74,77.61) 74,76.81 RC239.1
  IN4 w0.081: v2(74,77.61) 74.99,78.6 78.05,78.6 80.46,76.19 87.51,76.19 88.28,76.96 90.98,76.96 91.57,77.55 91.7,77.55 92.34,76.91 92.48,76.91 92.57,77.01 92.57,77.14 91.94,77.78 91.94,77.92 92.03,78.01 92.17,78.01 92.8,77.37 92.94,77.37 93.04,77.47 93.04,77.6 92.4,78.24 92.4,78.38 92.49,78.47 92.63,78.47 93.27,77.83 93.4,77.83 93.5,77.93 93.5,78.06 92.86,78.7 92.86,78.84 93.43,79.41 110.41,79.41 110.59,79.24 118.92,79.24 120.17,77.98 120.17,75.53 120.1,75.45 v2(120.1,75.12)
  BOTTOM w0.076: UCPU1.C55 120.77,71.62 120.64,71.75 120.64,74.2 120.4,74.45 120.4,74.82 v2(120.1,75.12)
XDP_OBS1: length 2.9
  TOP w0.127: JXDP1.23 73.1,74.75 v1(72.92,74.93) 72.92,75.8 RC240.2
XDP_OBS1_R: length 66.4
  TOP w0.127: v2(70.3,78) 70.3,78.2 70.6,78.51 71.34,78.51 71.91,77.94 71.91,77.29 72.41,76.79 RC240.1
  IN3 w0.089: v2(72.07,71.5) 72.59,72.01 75.56,72.01 76.46,71.11 78.31,71.11 79.35,70.07 89.5,70.07 89.84,70.41 91.16,70.41 91.85,71.1 96.38,71.1 97.88,69.6 106.22,69.6 107.92,71.3 109.66,71.3 110.72,72.36 118.56,72.36 119,71.93 119.93,71.93 120.71,72.71 v2(121.04,72.71)
  BOTTOM w0.076: UCPU1.D55 120.77,70.92 121.09,71.23 121.09,71.46 121.04,71.51 v2(121.04,72.71)
  BOTTOM w0.127: v2(70.3,78) 70.08,77.78 70.08,74.61 72.07,72.61 v2(72.07,71.5)
XDP_OBS2_R: length 4.4
  BOTTOM w0.076: UCPU1.B54 121.62,71.95 121.62,73.89 121.2,74.31 121.2,75.49 T10.1
XDP_OBS3_R: length 3.8
  BOTTOM w0.076: T11.1 120.02,74.51 120.47,74.05 120.47,71.46 120.21,71.19 UCPU1.C56
XDP_PRSNT_PIN1: length 12.9
  TOP w0.127: v2(75.22,77.63) 75.25,77.61 75.25,77.01 RC121.1 ; v2(76.91,80.02) 76.91,79.41 78.13,78.19 78.13,77.89 78.81,77.21 78.81,76.43 RC122.1 78.77,75.95 79.23,75.49 79.23,74.58 78.6,73.95 JXDP1.1
  BOTTOM w0.127: v2(76.91,80.02) 76.91,79.24 75.31,77.63 v2(75.22,77.63)
XTAL24_IN: length 2.4
  TOP w0.127: v2(150.66,69.59) 150.66,70.08 150.85,70.27 151.4,70.27 RC316.2
  BOTTOM w0.127: UCPU1.E3 150.82,69.75 v2(150.66,69.59)
XTAL24_IN_R: length 5.8
  TOP w0.127: RC316.1 153.19,70.67 RC46.2 154.15,70.65 CC21.1 154.57,70.66 154.69,70.77 154.69,71.13 154.92,71.36 156.33,71.36 YC1.3
XTAL24_OUT: length 3.6
  TOP w0.127: v2(149.28,70.82) 149.34,70.76 v1(150.5,70.76) 151.08,70.76 RC317.2
  BOTTOM w0.127: UCPU1.C7 149.09,71.01 v2(149.28,70.82)
XTAL24_OUT_R: length 3.6
  TOP w0.127: YC1.1 154.51,71.57 CC22.1 154.17,71.56 RC46.1 152.46,71.56 RC317.1
XTAL_25_IN: length 3.2
  TOP w0.076: UT1.D22 38.96,65.51 38.96,65.51 38.89,65.58 38.89,66.19 38.38,66.7
  TOP w0.127: 38.38,66.7 37.57,67.51 RT243.2
XTAL_25_IN_R: length 2.9
  TOP w0.127: YT1.1 35.6,66.89 CT43.1 36.13,66.89 36.61,67.37 RT243.1
XTAL_25_OUT: length 3.3
  TOP w0.076: 38.47,67.18 38.6,67.05 38.6,66.83 39.12,66.3 UT1.D23
  TOP w0.127: RT11.2 37.55,68.09 38.47,67.18
XTAL_25_OUT_R: length 4.6
  TOP w0.127: YT1.3 33.76,67.04 35.12,67.04 35.81,67.74 CT44.1 36.2,68.09 RT11.1
N18292747: length 12
  TOP w0.127: PQ100.2 27.05,67.17 28.42,68.54 29.54,68.54 29.77,68.77 29.77,70.65 29.9,70.77 31.42,70.77 31.68,71.04 PQ101.1 31.68,72.35 31.96,72.62 PR105.1 v1(33.39,71.5)
N22878624: length 4.3
  TOP w0.127: PR104.1 PR101.1 27.55,71.05 27.52,71.03 PL102.2 27.07,70.42 27.65,69.85 PQ100.1
N22878630: length 9.6
  TOP w0.127: PR103.1 25.65,68.75 25.67,68.74 26.15,68.74 26.83,69.42 v2(26.83,69.78) ; v2(29.1,70.32) 29.17,70.39 29.17,70.76 PR101.2 ; v2(29.48,67.96) 29.48,67.82 28.83,67.17 PQ100.3
  BOTTOM w0.127: v2(26.83,69.78) v1(28.07,69.78) 28.32,69.78 28.85,70.32 v2(29.1,70.32) 29.1,69.57 28.93,69.4 28.93,68.64 29.48,68.09 v2(29.48,67.96)
N22878645: length 5.7
  TOP w0.127: PR106.1 31.31,72.93 PQ101.2 ; PR106.1 PR104.2 ; PR106.1 30.76,71.99 v1(30.76,71.43)
N28314143: length 1.2
  TOP w0.127: T7.1 123.2,53.78 v2(123.39,53.78)
  BOTTOM w0.127: UCPU1.AT52 123.06,53.45 v2(123.39,53.78)
N28323796: length 1.9
  TOP w0.127: T8.1 126.62,53.35 126.62,53.94 v2(127.05,54.37)
  BOTTOM w0.076: UCPU1.AP43 v2(127.05,54.37)
N28323807: length 1.2
  TOP w0.127: T21.1 127.32,55.28 v2(127.05,55.01)
  BOTTOM w0.127: v2(127.05,55.01) 127.45,55.4 UCPU1.AN43
N28344853: length 2.7
  TOP w0.127: v2(144.38,53.1) 143.99,52.72 143.99,52.23 144.27,51.95 144.49,51.95 T18.1
  BOTTOM w0.076: v2(144.38,53.1) 144.72,53.45 UCPU1.AT13
N28375965: length 1.2
  TOP w0.127: v2(125.31,68.6) 124.99,68.28 T1.1
  BOTTOM w0.127: UCPU1.G46 125.68,68.29 125.38,68.6 v2(125.31,68.6)
N28375966: length 2
  TOP w0.127: v2(125.28,69.23) 124.74,69.78 124.74,70.44 T2.1
  BOTTOM w0.127: UCPU1.F46 125.57,68.94 v2(125.28,69.23)
N28424999: length 10.4
  BOTTOM w0.089: 110.06,49.62 110.06,50.22 111.28,51.45 UCPU1.AW71
  BOTTOM w0.127: 110.06,49.62 110.06,46.49 110.24,46.31 110.24,42.22 T113.1
N28425002: length 9.1
  BOTTOM w0.089: UCPU1.AW70 111.94,51.14 111.23,51.14 110.26,50.17 110.26,49.77
  BOTTOM w0.127: 110.26,49.77 110.31,49.72 110.31,46.6 110.59,46.32 110.59,43.69 T114.1
N28842863: length 4.2
  TOP w0.127: v2(152.28,56.1) 152.72,56.54 v1(154.15,56.54)
  TOP w0.381: CC204.1 151.79,54.87 152.27,55.35 152.27,56.08 v2(152.28,56.1)
  BOTTOM w0.203: v2(152.28,56.1) 152.2,56.18 151.81,56.18 UCPU1.AL1
N28843886: length 2.5
  TOP w0.381: v2(147.2,48.89) 147.2,49.38 CC214.1
  BOTTOM w0.152: UCPU1.BB10 146.55,49.62 147.2,48.97 v2(147.2,48.89)
N28856399: length 4.8
  BOTTOM w0.089: 112.27,49.24 112.27,50.16 UCPU1.BA70
  BOTTOM w0.127: 112.27,49.24 112.27,48.12 111.18,47.02 T16.1
N28856402: length 7.4
  BOTTOM w0.127: UCPU1.BA68 112.77,50.13 112.93,49.97 112.93,47.63 111.86,46.57 111.86,43.99 T17.1
N28857231: length 8.5
  BOTTOM w0.127: UCPU1.BB68 113.25,47.55 112.1,46.39 112.1,44.3 112.62,43.78 112.62,42.22 T12.1
N28857234: length 5.5
  BOTTOM w0.127: T13.1 111.61,44.92 111.61,46.82 112.6,47.81 UCPU1.BB69
N28857237: length 1.6
  TOP w0.127: T14.1 144.87,56.4 v2(145,56.54)
  BOTTOM w0.127: UCPU1.AK13 144.84,56.72 145,56.56 145,56.54 v2(145,56.54)
N28857240: length 1.4
  TOP w0.127: v2(145.81,57.4) 146.03,57.18 T15.1
  BOTTOM w0.127: v2(145.81,57.4) 145.49,57.08 UCPU1.AK12
N28861827: length 8.2
  BOTTOM w0.076: RC120.1 113.13,75.83 113.13,75.35 112.9,75.12 112.5,75.12 112.28,74.9 112.28,74.6 112.6,74.28 114.58,74.28 115.72,73.15 115.72,71.44 UCPU1.C64
N28891648: length 6.7
  BOTTOM w0.076: UCPU1.BB11 145.99,49.5 146.62,48.87 146.62,48.59 147.57,47.63 147.97,47.63 148.11,47.5
  BOTTOM w0.127: RC245.2 149.2,44.7 148.57,45.33 148.57,46.49 148.34,46.71 148.34,47.26 148.11,47.5
N28938912: length 2.5
  BOTTOM w0.127: v1(184.81,58.01) 184.9,57.93 184.91,57.93 CC8.2 184.81,56.35 RC29.1
N29708559: length 9
  BOTTOM w0.076: UCPU1.AY4 150.47,50.56 150.47,50 150.67,49.79 150.67,49.59 150.88,49.39 151,49.39 151.28,49.11
  BOTTOM w0.127: T126.1 157.33,49.54 154.51,49.54 154.08,49.11 151.28,49.11
N29708561: length 4.6
  BOTTOM w0.127: T127.1 154.46,49.84 153.95,49.34 151.35,49.34 UCPU1.BB3
N29708599: length 5.2
  BOTTOM w0.089: 153.92,53.04 152.4,53.04 152.27,53.17 151.82,53.17 151.74,53.25 150.11,53.25 149.77,52.91 149.56,52.91 UCPU1.AU5
  BOTTOM w0.127: T128.1 154.23,53.04 153.92,53.04
N29708601: length 5.7
  BOTTOM w0.076: 153.01,53.46 152.53,53.46 152.42,53.57 152.02,53.78 151.61,53.88 151.49,53.84 149.81,53.84 149.46,53.48 UCPU1.AT5
  BOTTOM w0.127: T129.1 153.66,54.64 153.66,53.72 153.4,53.46 153.01,53.46
N29708639: length 6.3
  BOTTOM w0.076: 151,48.42 150.44,48.98 150.17,48.98 149.59,49.56 UCPU1.BB5
  BOTTOM w0.127: T130.1 155.12,48.02 154.71,48.42 151,48.42
N31739843: length 8
  BOTTOM w0.076: UCPU1.AY8 148.05,50.76 148.07,50.71 148.06,50.62 147.96,50.35 147.96,50.27 148.03,50.06 148.03,49.94 147.98,49.83 147.98,49.48 149.27,48.19 150.04,48.19 150.65,47.58 151.05,47.58 152.08,46.55
  BOTTOM w0.127: 152.08,46.55 152.55,46.08 T121.1
N40373163: length 2.2
  TOP w0.127: v1(96.72,39.2) 96.44,38.92 95.58,38.92 94.95,38.29 CD186.2
N40373501: length 2.6
  TOP w0.508: v3(154.24,40.38) 154.24,40 RD116.1 CD187.2
N40376778: length 1.6
  TOP w0.127: CD185.2 95.14,39.16 95.89,39.91 v1(95.89,40.19)
N49753304: length 6.6
  TOP w0.127: v3(16.24,23.58) 17.32,24.67 RA16.2
  TOP w0.254: QA9.1 17.52,24.53 RA16.2 QA1.2 17.37,26.15 17.17,26.35 17.17,27.06 17.37,27.26 QA1.5
N49753333: length 5.5
  TOP w0.127: RA41.1 18.26,21.31 18.63,21.68 18.63,22.63 QA9.2 ; RA41.1 17.96,20.74 17.4,21.29 v3(17.4,21.9) ; RA41.1 RA18.2 RA57.2
N49753452: length 3
  TOP w0.127: v1(13.97,34.22) 14.28,33.92 RA37.2
  TOP w0.254: RA37.2 14.9,33.05 RA39.1 15.07,32.85 15.07,32.09 QA3.3
N49753456: length 3.1
  TOP w0.127: v3(16.89,34.27) 16.54,33.92 CA40.1
  TOP w0.254: QA3.2 15.72,32.97 RA39.2 15.79,33.05 CA40.1
N49755927: length 4.9
  TOP w0.127: RA24.2 24.46,37.17 v3(24.21,36.92)
  TOP w0.254: CA34.1 28.88,37.17 CA33.1 R7.1 RA25.2 RA24.2
N49756342: length 6.1
  TOP w0.127: CA106.1 30.25,36.18 30.45,36.38 31.55,36.38 v1(31.68,36.25)
  TOP w0.203: UA2.13 29.86,33.28 30.25,33.67 RA76.2 CA106.1 29.36,35.26 RA75.2
N49981946: length 10.1
  IN4 w0.254: v2(17.45,32.98) 16.49,32.98 14.45,35.01 JHP1.5
  BOTTOM w0.254: v2(17.45,32.98) 17.45,32.83 DA1.2 18.31,32.17 RA30.1 RA19.2
N50165058: length 19.5
  TOP w0.127: v2(164.6,65.08) 164.5,64.98 PU400.7 164.5,63.81 164.85,63.46 164.85,62.22 164.5,61.87 163.68,61.87 163.34,61.54 163.34,59.85 162.99,59.49 162.99,58.42 163.86,57.55 164.97,57.55 v3(165.56,56.95) 166.57,55.94 167.01,55.94 167.31,56.24 167.31,58.04 167.18,58.17 166.89,58.17 PQ400.1 167.04,58.52 167.98,58.52 168.78,59.32 PR403.2
  BOTTOM w0.127: PR400.2 164.69,64.98 v2(164.6,65.08)
N50165456: length 8.3
  TOP w0.127: PU400.3 165.15,60.19 165.71,60.76 166.3,60.76 PC406.1 PR412.1 PR409.2 167.06,61.81 PR408.1 168.5,63.25 168.5,63.69 168.91,64.1 v1(168.91,64.91)
N50165462: length 12.8
  TOP w0.127: PQ400.2 166.6,57.81 163.97,57.81 163.86,57.91 163.86,58.95 163.58,59.24 v2(163.42,59.24) 163.85,59.66 PU400.1 163.85,60.37 164.11,60.64 164.31,60.64 165.46,61.8 165.46,62.84 165.73,63.11 166.62,63.11 PR408.2
  BOTTOM w0.127: v1(162.66,59.75) 163.17,59.24 v2(163.42,59.24) 163.81,59.62 PR411.2
N50170477: length 7.7
  TOP w0.127: PQ400.5 168.5,57.62 168.12,57.24 168.12,56.73 168.5,56.35 170.99,56.35 PU401.4 171.74,56.84 PC404.1 171.74,54.68 v1(171.91,54.51)
N50170488: length 4.3
  TOP w0.127: PR407.1 PC404.2 172.87,55.71 172.06,56.52 172.06,57.17 PU402.2 PU402.1
N50180903: length 4.2
  TOP w0.127: v1(25.17,70.54) 25.74,70.54 PL102.1 26.22,71.45 26.46,71.68 26.87,71.68 26.96,71.78 PD102.1 27.36,72.27 27.62,72.01 PR108.1
N50196545: length 6.8
  TOP w0.127: v2(170.41,58.3) 169.72,57.62 PU401.2 ; v2(174.01,57.39) 174.41,57 PU402.4
  IN3 w0.089: v2(174.01,57.39) 173.55,56.93 173.07,56.93 173.06,56.93 172.73,56.93 172.73,56.93 170.74,56.93 170.15,57.52 170.15,58.04 v2(170.41,58.3)
N50196918: length 3.5
  TOP w0.127: PQ400.6 PU401.1 169.71,59.13 PR404.2 v1(170.86,60.27)
N50197891: length 6.4
  TOP w0.127: v2(165.18,65.08) 165.56,65.08 165.8,64.85 PU400.5 166.09,64.47 PR402.2 PR406.1
  BOTTOM w0.127: v1(165.18,65.64) v2(165.18,65.08) 165.58,64.68 PC403.1 164.69,63.41 PR400.1
N50203343: length 3.6
  TOP w0.127: v2(166.88,56.42) 166.88,56.88 PQ400.3
  BOTTOM w0.127: v3(165.45,57.82) 165.74,58.12 PR405.1 PR401.2 166.88,56.88 v2(166.88,56.42)
N50266801: length 19.9
  TOP w0.381: PD301.1 PD302.1 39.47,18.84 40.23,18.09 v3(41,18.09) 42.25,18.09 v2(42.34,18.18)
  IN3 w0.508: v2(42.34,18.18) 42.9,18.74 42.9,20.31 42.07,21.14 42.07,22.93 v2(42.82,23.68)
  BOTTOM w0.381: v2(42.82,23.68) 42.29,24.22 PR305.1
  BOTTOM w0.508: v2(42.34,18.18) 42.15,18.37 40.06,18.37 39.24,19.19 39.24,20.23 38.94,20.53 38.94,21.37 39.41,21.83 39.41,22.04 PR307.1
N50638473: length 6.6
  TOP w0.127: QH8.3 9.05,9.05 9.89,9.05 v1(10.17,8.77) 10.17,7.71 9.63,7.16 8.37,7.16 8.03,6.82 R916.1
N52012213: length 9.2
  TOP w0.127: RT242.2 178.9,53.89 178.07,53.89 177.49,54.47 177.21,54.47 v1(176.48,55.2) 175.93,55.75 175.93,56.69 176.21,56.97 176.21,57.39 v2(176.73,57.91) 176.73,58.39 177.61,59.27 UE5.B51
  BOTTOM w0.127: CE50.1 177.06,58.24 v2(176.73,57.91)
N52012553: length 3
  TOP w0.127: UE5.A59 183.86,57.82 v1(183.86,56.75) 183.86,56.05 RE63.1 RE57.1
N52091760: length 2.2
  TOP w0.127: QE9.2 175.76,71.42 175.53,71.65 v1(175.53,71.95) 175.67,72.09 RE70.2
N52092863: length 2.6
  TOP w0.127: v1(179.17,71.53) 179.5,71.87 RE80.2 180.44,72.12 CE52.1
N52116668: length 4.1
  TOP w0.127: v2(183.76,60.2) 183.5,60.2 183.16,59.85 183.16,58.99 183.11,58.94 UE5.B61
  BOTTOM w0.127: RE64.1 183.35,58.97 183.35,59.79 v2(183.76,60.2)
N52475257: length 3.9
  TOP w0.127: v2(43.07,44.08) 43.15,44.08 R1255.1
  BOTTOM w0.127: JNGFF1.42 43.5,44.51 v2(43.07,44.08)
N52558730: length 5
  TOP w0.127: v2(36.35,21.5) 36.12,21.5 35.79,21.16 35.79,20.28 35.41,19.9 RE22.2
  BOTTOM w0.127: UE4.13 35.24,20.95 35.79,21.5 v2(36.35,21.5) 36.35,22.22 v3(36.16,22.4)
N52558748: length 4.2
  TOP w0.127: v2(33.85,21.58) 33.9,21.53 33.9,20.39 RE23.2
  BOTTOM w0.127: v3(34.44,22.26) 33.85,21.67 33.85,21.59 v2(33.85,21.58) 34.59,20.84 UE4.12
N52558768: length 3.5
  TOP w0.127: RE27.2 32.59,21.6 v2(32.59,21.85)
  BOTTOM w0.127: v2(32.59,21.85) 32.96,21.85 33.94,20.87 33.94,20.63 33.94,20.63 UE4.11
N52571191: length 4.1
  TOP w0.127: v2(36.93,20.43) 36.55,20.81 RE24.2
  BOTTOM w0.127: UE4.14 35.89,20.93 36.04,21.08 36.28,21.08 v2(36.93,20.43) 37.99,19.38 v3(38.05,19.38)
N52708219: length 4.9
  TOP w0.127: D81.1 R886.1 164.21,17.76 v2(164.39,17.76) 165.35,17.76 v3(165.79,17.33)
  BOTTOM w0.127: v2(164.39,17.76) 164.78,17.37 165.62,17.37 JFAN1.2
N52893865:
  vias: v3(174.22,17.74)
N52893895: length 1.1
  TOP w0.127: R1323.1 168.89,19.36 v1(169.04,19.52)
N52893916: length 3.3
  TOP w0.127: U716.10 171.7,18.83 171.88,19.01 171.88,19.54 171.73,19.69 C1258.1 171.73,20.03 v3(172.79,21.09)
N52894141: length 4.2
  TOP w0.127: C1257.1 170.85,19.88 v2(170.85,19.21) 170.9,19.16 U716.12
  BOTTOM w0.127: v2(170.85,19.21) 171.28,18.78 171.6,18.78 172.19,19.36 v1(172.19,20.23)
N52922903:
  vias: v1(177.39,30.97)
N52922958: length 1.5
  TOP w0.127: R1342.1 v1(182.84,29.76)
N52922960: length 4
  TOP w0.127: v1(178.03,27.92) 178.42,28.31 178.42,29.38 C1292.1 179.18,30.14 179.18,30.77 179.28,30.87 U717.10
N52923110: length 3.9
  TOP w0.127: U717.12 180.08,30.88 180.11,30.84 180.11,30.06 C1163.1 179.4,29.35 v1(179.4,27.87)
N52925836: length 2.5
  TOP w0.127: v3(50.17,24.02) 49.6,23.45 49.48,23.45 49.12,23.09 49.12,22.02
N52925896:
  vias: v3(49.76,17.23)
N52925901: length 2.2
  TOP w0.127: C1278.1 47.8,20.55 v1(48.72,20.55) U719.10
N52926051: length 1.6
  TOP w0.127: U719.12 48.47,19.75 C355.1
N52930519:
  vias: v1(39.52,42.55)
N52930575: length 2.7
  TOP w0.127: R1344.1 36.18,45.08 36.5,45.4 36.5,46.19 v1(37.16,46.84)
N52930580: length 1.6
  TOP w0.127: U720.10 37.33,43.53 37.33,43.96 37.54,44.17 37.54,44.59 C1293.1
N52930730: length 1.6
  TOP w0.127: U720.12 36.53,43.87 36.47,43.93 36.47,44.42 C1167.1
N52934489:
  vias: v3(28.68,41.36)
N52934545: length 2.1
  TOP w0.127: v1(35.55,38.02) 35.55,38.33 34.43,39.46 R1318.1
N52934547: length 3.3
  TOP w0.127: U664.10 32.72,40.5 32.23,40.01 C1214.1 31.23,38.28 v3(31.12,38.28)
N52934693: length 1.7
  TOP w0.127: U664.12 33.52,39.68 C1212.1
N54529025: length 3.5
  TOP w0.127: R2662.1 v2(174.35,39.89) 174.82,39.41 v3(175.08,39.41)
  BOTTOM w0.127: v2(174.35,39.89) 174.5,40.04 JNGFF2.60
N55952962: length 1.7
  TOP w0.203: PU900.7 168.72,39.84 v2(168.91,39.65) 169.01,39.55 PR906.2
N56036060: length 3
  TOP w0.127: 173.33,71.71 173.88,71.71 v1(174.25,72.08)
  TOP w0.254: 173.33,71.71 173.33,72.15 173.46,72.27 173.46,73.03 173.42,73.07 PU800.7
N56242723: length 4.2
  BOTTOM w0.076: UCPU1.AW50 123.82,51.54 124.16,51.2 124.16,50.2 124.31,50.05
  BOTTOM w0.127: T19.1 124.38,47.89 124.38,49.98 124.31,50.05
N56561744: length 3.6
  TOP w0.127: CA86.2 21.21,27.59 v1(22.66,27.59) 23.83,27.59 24.11,27.88 UA2.35
N56561748: length 6.3
  TOP w0.127: v1(20.61,25.17) 20.61,25.83 21.01,26.22 CA86.1
  TOP w0.203: UA2.37 25.46,26.24 25.13,25.92 21.91,25.92 21.61,26.22 CA86.1
N56563648: length 4.9
  TOP w0.127: v3(25.87,35.92) 26.48,35.31 27.51,35.31 27.66,35.16 CA107.2
  TOP w0.203: CA107.2 27.07,34.23 27.07,33.65 27.46,33.25 UA2.19
N56565297: length 3.4
  TOP w0.203: v2(31.67,30.06) 31.49,29.88 UA2.7
  BOTTOM w0.127: v3(32.36,28.91) 31.67,29.59 v2(31.67,30.06)
  BOTTOM w0.254: CA108.2 31.28,30.06 v2(31.67,30.06)
N56565952: length 5.9
  TOP w0.127: v3(22.39,35.01) CA109.1
  TOP w0.203: UA2.27 24.08,31.08 23.68,31.47 23.45,31.47 22.84,32.09 RA77.1
  TOP w0.254: RA77.1 22.15,32.99 CA109.1
N56567001: length 7.2
  TOP w0.127: v3(23.54,22.07) 23.15,22.46 CA110.2
  TOP w0.203: CA110.2 23.51,25.21 24.79,25.21 24.92,25.08 25.29,25.08 26.26,26.05 UA2.39
N56594221: length 4.7
  TOP w0.076: 26.42,34.42 RA54.2
  TOP w0.127: v3(24.29,35.2) 26.07,35.2 26.42,34.85 26.42,34.42
  TOP w0.203: RA54.2 26.77,34.07 26.77,33.52 27.06,33.23 UA2.20
N56696147: length 3
  BOTTOM w0.127: PR200.3 55.07,60.99 55.37,60.69 PR222.2 57.48,60.69 PR221.2
N56696285: length 4.7
  BOTTOM w0.127: PU200.5 59.16,61.55 59.69,62.09 v1(59.69,62.42) 59.02,63.09 58.6,63.09 57.91,62.4 57.91,62.04 PR221.1
N56699994: length 3.6
  TOP w0.127: PR201.2 59.86,52.94 PQ204.2 58.83,54.21 PR207.1
N56700271: length 5.3
  TOP w0.127: PQ206.6 56.97,55.7 57.02,55.65 57.3,55.65 57.74,55.2 59.79,55.2 PR207.2 60.3,54.7 v1(60.3,53.6)
N56700855: length 3
  TOP w0.254: PR290.1 59.27,56.85 PD200.1 59.55,56.35 PQ206.2
N56701480: length 4.7
  TOP w0.254: PR289.2 63.45,58.84 63.12,58.51 PR213.2 62.6,57.68 v1(62.74,57.54) 62.74,56.44 62.1,55.81 PD200.2
N56701483: length 3.2
  TOP w0.127: PR216.2 61.47,59.17 v1(61.47,59.44)
  TOP w0.254: PD200.3 61.57,57.16 PR216.2
N56704066: length 13.8
  BOTTOM w0.254: PR241.1 51.56,74.84 50.95,74.23 PR232.2 50.29,73.85 PC206.2 49,73.22 45.88,73.22 v1(45.29,73.82) 43.87,75.24 43.87,75.99 44.35,76.48 46.17,76.48 46.61,76.03 PQ210.3
N56704068: length 27.6
  TOP w0.127: v2(34.14,78.95) 33.71,79.38 19.41,79.38 18.77,78.75 PQ205.1 18.42,76.82 16.89,75.29 16.89,72.07 18.9,70.06 v1(19.28,70.06) PR212.1
N56704069: length 13
  TOP w0.127: v2(43.03,76.02) 43.5,76.02 43.87,75.65 43.87,75.19 44.09,74.97 44.09,73.65 44.32,73.41 44.93,73.41 45.19,73.16 PQ214.1 ; v2(43.03,76.02) 42.96,76.02 v1(42.62,76.36) 42.52,76.46 PR244.1 ; v2(43.03,76.02) 44.15,77.14 PR237.2 44.18,77.15 PC208.2
  BOTTOM w0.254: PQ212.3 44.25,76.92 43.81,76.48 43.79,76.48 43.34,76.02 v2(43.03,76.02)
N56704070: length 23.8
  TOP w0.254: v2(54.03,51.61) 53.06,50.64 PD202.1 ; PD202.1 52.35,50.53 52.9,49.98 55.11,49.98 55.55,49.54 55.55,48.21 56.37,47.39 v1(57,47.39) 57.4,47.39 57.73,47.05 57.73,45.37 58.15,44.95 60.2,44.95 PR210.1 ; PD202.1 51.83,50.64 51.66,50.81 51.32,50.81 51.27,50.86 PC200.2
  IN4 w0.254: v2(54.03,51.61) 56.64,54.23 56.64,55 v2(56.7,55.06)
  BOTTOM w0.254: PQ200.3 54.66,51.51 54.13,51.51 v2(54.03,51.61) ; v2(56.7,55.06) PQ201.3 56.06,54.91 PR202.2
N56704076: length 3.3
  BOTTOM w0.127: PR200.2 55.07,60.05 55.43,60.42 55.97,60.42 PR222.1 56.72,59.67 PR225.2
N56704097: length 3.7
  TOP w0.127: PD202.2 55.59,50.64 v1(56.16,50.07) 57.15,50.07 57.86,50.78 PQ204.1
N56712400: length 40.6
  TOP w0.127: v2(85.22,66.4) 85.56,66.74 v1(87.2,66.74) 88.62,66.74 89.81,67.94 89.81,68.7 90.22,69.11 90.22,69.49 90.73,70 90.73,70.21 91.12,70.61 PR288.2 92.25,70.61 PR287.2
  TOP w0.254: PQ215.2 59.43,64.33 v2(59.49,64.28)
  IN3 w0.089: v2(85.22,66.4) 84.9,66.72 80.64,66.72 79.77,67.59 73.88,67.59 72.77,68.7 63.6,68.7 61.13,66.23 61.13,64.39 60.76,64.02 59.79,64.02 59.53,64.28 v2(59.49,64.28)
N56713700: length 10.8
  TOP w0.254: PQ213.2 57,60.61 55.8,61.81 v2(55.8,63.64)
  BOTTOM w0.127: PR242.1 58.13,66.72 58.13,66.06 58.04,65.98 v1(58.04,64.6) 57.08,63.64 v2(55.8,63.64)
  BOTTOM w0.254: PR233.2 59.47,67.19 PR242.1
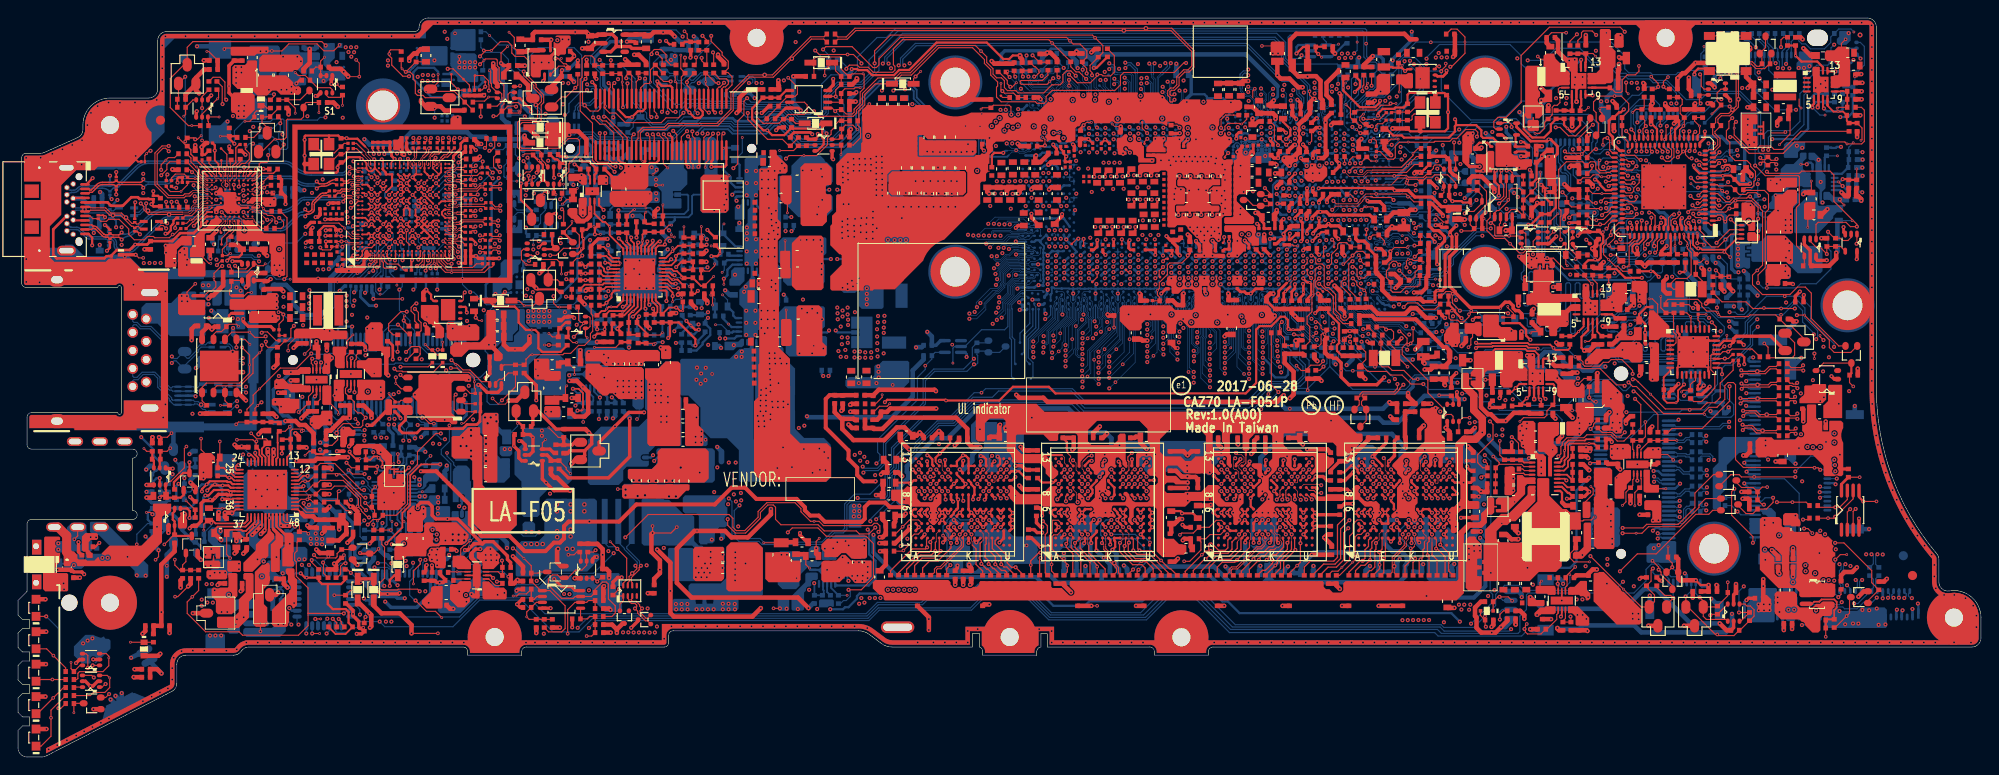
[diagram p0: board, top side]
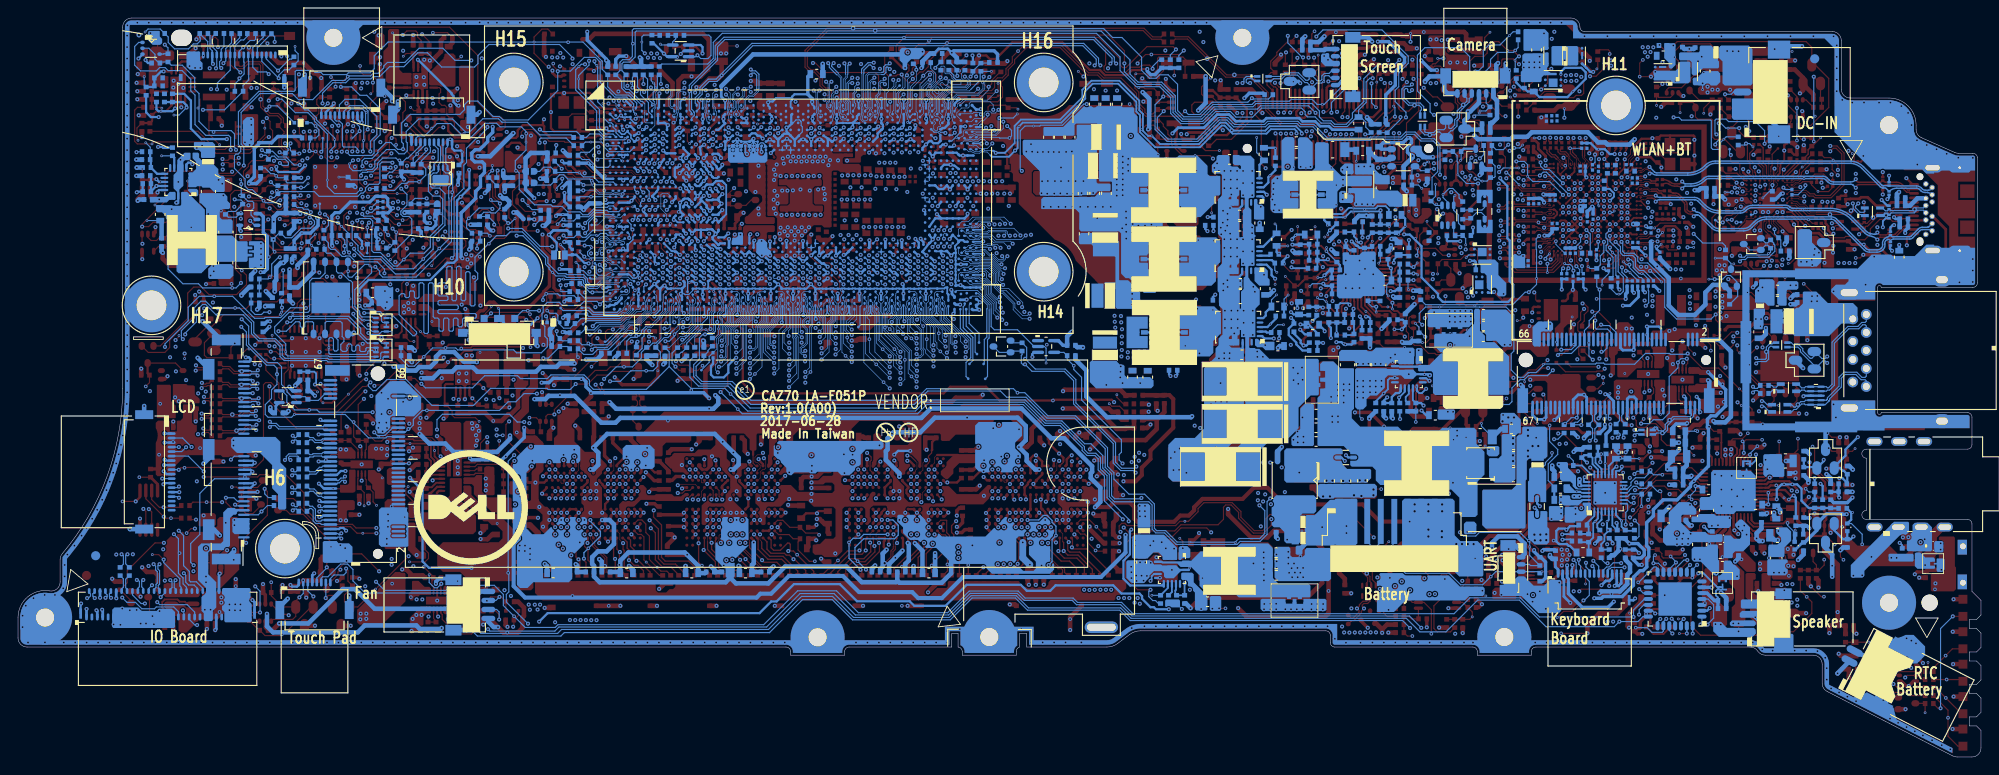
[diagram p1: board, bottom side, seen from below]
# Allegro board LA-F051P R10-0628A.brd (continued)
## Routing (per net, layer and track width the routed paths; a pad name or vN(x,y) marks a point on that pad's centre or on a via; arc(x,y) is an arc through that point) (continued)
N56715138:
  vias: v3(48.49,80.3)
N56715373: length 4
  TOP w0.127: PR208.2 33.58,77.22 v1(34.01,77.66) ; PR208.2 33.03,76.55 PR219.1 ; PR208.2 33.58,76.11 33.57,76.1 PQ207.3 PQ207.2
N56726680: length 2.3
  TOP w0.127: v1(61.98,45.98) 61.56,45.98 PR210.2
  TOP w0.254: PQ208.6 61.06,46.73 PR210.2
N56726937: length 5.7
  TOP w0.127: PR267.2 PR263.1 PR272.1 56.72,15.27 v1(56.45,15.55) 56.45,16.1 PC216.1 57.51,17.16 58.18,17.16 PU203.3
N56728350: length 5.5
  TOP w0.127: v2(50.79,48.75) 51.12,48.42 v1(51.46,48.42)
  TOP w0.254: PC200.1 50.79,49.27 v2(50.79,48.75)
  IN2 w0.254: v2(52.97,51.38) 52.27,51.38 50.79,49.89 v2(50.79,48.75)
N56729247: length 10.9
  TOP w0.127: PR211.1 PR204.2 17.81,73.11 PQ205.2 v2(18.55,75.48)
  BOTTOM w0.127: v2(18.55,75.48) v3(18.55,68.3)
N56731386: length 7.7
  TOP w0.127: v1(46.61,75.73) 46.61,74.86 46.23,74.48 46.13,74.48 PQ214.2 46.04,73.86 48.42,73.86 49.56,72.73 PR245.1 49.57,72.67 PR235.2
N56741861: length 3.2
  BOTTOM w0.127: PU200.3 58.51,58.01 PC203.1 57.91,57.84 57.89,57.87 PR223.2 57.18,57.53 v1(57.18,56.83)
N56821674: length 4.4
  TOP w0.076: 26.31,59.37 26.26,59.43 26.26,59.57 26.1,59.73 25.25,59.73 U722.C10
  TOP w0.127: v1(28.16,59.62) 28.16,59.44 27.55,58.82 R1437.1 27.03,58.66 26.31,59.37
N56821678: length 12.4
  TOP w0.076: U722.H6 22.51,61.97 22.12,61.97 v2(21.98,61.84)
  TOP w0.127: v2(17.61,61.62) 17.88,61.35 R1438.1
  IN3 w0.089: v2(21.98,61.84) 21.28,62.53 21.28,64.84 20.81,65.31 18.4,65.31 16.8,63.71 16.8,62.42 v2(17.61,61.62)
N56822218: length 5.6
  TOP w0.076: 23.93,58.34 24.1,58.5 24.1,59.38 U722.E11
  TOP w0.127: v1(23.57,55.88) 23.46,55.88 23.22,55.63 R1465.1 22.67,56.33 23.18,56.84 23.18,57.58 23.34,57.74 R1468.1 23.65,58.05 23.93,58.34
N56822254: length 5
  TOP w0.076: U722.H7 22.36,61.32 21.84,61.32 21.74,61.22 20.6,61.22
  TOP w0.127: C618.1 18.55,60.07 19.27,60.07 19.77,60.57 v1(19.77,60.74) 20.12,60.74 20.6,61.22
N56822270: length 2.6
  TOP w0.127: U722.G2 23.01,63.97 23.01,63.59 23.14,63.46 v2(23.14,63.46)
  BOTTOM w0.127: v1(24.21,62.04) 23.47,62.77 R1473.1 23.15,63.44 v2(23.14,63.46)
N56822627: length 3.6
  TOP w0.076: 22.54,65.49 22.54,64.99 22.76,64.77 22.76,63.8 22.59,63.64 22.59,63.43 23.01,63.01 U722.G4
  TOP w0.127: 22.54,65.49 22.54,65.56 22.56,65.58 TC29.1
N56822629: length 5
  TOP w0.076: 23.32,64.96 23.32,64.62 23.27,64.57 23.27,63.86 23.5,63.63 23.5,62.98 U722.F4
  TOP w0.127: TC25.1 23.17,66.88 23.17,65.62 23.32,65.48 23.32,64.96
N56822683: length 3.9
  TOP w0.076: 23.67,58.43 23.9,58.66 23.9,59.14 23.76,59.29 23.76,59.68 24.01,59.93 U722.E10
  TOP w0.127: 23.67,58.43 23.55,58.32 23.38,58.32 22.58,57.52 TC36.1
N56822685: length 1.6
  TOP w0.076: U722.G11 23.01,59.23 22.44,58.66 22.44,58.4
  TOP w0.127: TC38.1 22.49,58.19 22.44,58.24 22.44,58.4 22.44,58.4
N56856077: length 1.8
  TOP w0.076: 23.55,65.79 23.55,64.51 U722.F1
  TOP w0.127: 23.55,65.79 23.55,66.15 RT190.1
N56859240: length 4.5
  TOP w0.076: 23.8,64.78 23.77,64.75 23.77,64.23 23.69,64.15 23.69,64.15 U722.F2
  TOP w0.152: R1471.2 24.54,67.97 24.17,67.6 24.17,65.95 23.8,65.58 23.8,64.78
N56859647: length 5.1
  TOP w0.076: 24.44,65.49 24.26,65.3 24.26,64.22 U722.E2
  TOP w0.127: R1471.1 25.22,67.44 25.66,67 25.66,66.32 25.21,65.86 24.82,65.86 24.44,65.49
N56975718: length 1.2
  TOP w0.127: T183.1 189.13,64.02 UE5.A10
N56975734: length 1.1
  TOP w0.127: T184.1 183.36,69.68 183.36,68.72 UE5.A23
N56977728: length 2.6
  TOP w0.127: v1(187.31,49.12) R60.1 186.42,48.76 186.41,48.75 186.41,48.49 186.63,48.26 U15.27
N56984382: length 2.3
  TOP w0.127: UE5.B23 184.11,67.2 v2(184.16,67.15)
  BOTTOM w0.127: v2(184.16,67.15) 184,67.32 T187.1
N56984414: length 3.3
  TOP w0.127: UE5.B62 183.61,58.87 183.43,59.05 183.43,59.51 183.66,59.74 183.96,59.74 184.32,60.1 v2(184.32,60.33)
  BOTTOM w0.127: v2(184.32,60.33) T189.1
N57034346: length 4.2
  BOTTOM w0.076: UCPU1.AC3 150.61,60.18 150.96,59.84 151.51,59.84 151.63,59.76 152,59.76 152.12,59.83 152.69,59.83 153.49,59.03 T124.1
N57034424: length 4.3
  TOP w0.076: 27.08,61 27.08,61.17 26.8,61.45 26.39,61.45 26.17,61.23 24.75,61.23 U722.D7
  TOP w0.127: 27.08,61 v1(27.22,60.86) 27.52,60.56 R1439.1
N57037386: length 2.6
  BOTTOM w0.127: QT19.1 27.74,54.77 28.32,55.36 R1440.1 v1(29.49,55.36)
N57177583: length 1.3
  TOP w0.127: R1327.1 v1(153.26,73.8)
N57177874: length 2.6
  TOP w0.127: UZ22.4 164.81,48.79 165.88,48.79 RZ76.2 165.94,49.22 165.3,49.85 v1(165.3,50)
N57177931: length 2.1
  TOP w0.127: 161.39,47.36 161.39,46.58 161.21,46.39 161.21,45.74 v3(160.94,45.47)
N57178338:
  vias: v3(162.56,65.04)
N57182329: length 3.4
  TOP w0.127: v1(36,72.31) PR228.2 35.76,73.2 34.46,73.2 34.22,73.43 PQ207.5
N57280922: length 5
  TOP w0.076: U722.B9 25.75,60.71 26.21,60.71 26.26,60.66 26.9,60.66 27.28,60.29
  TOP w0.127: v2(28.65,59.32) 28.51,59.46 28.51,59.82 28.23,60.09 27.69,60.09 27.5,60.28 27.29,60.28 27.28,60.29
  BOTTOM w0.127: v2(28.65,59.32) 29.16,59.32 29.42,59.57 T193.1
N57280925: length 2.6
  TOP w0.076: 27.28,59.93 26.74,60.47 26.01,60.47 U722.A9
  TOP w0.127: v2(27.66,59.6) 27.61,59.6 27.28,59.93
  BOTTOM w0.127: T194.1 27.69,59.57 v2(27.66,59.6)
N57281646: length 1.3
  TOP w0.127: UE5.A55 181.86,57.51 181.46,57.1 T185.1
N57313034: length 3.5
  TOP w0.127: RC49.2 147.8,51.27 146.81,52.26 146.81,52.72 v2(147.2,53.11)
  BOTTOM w0.076: UCPU1.AT8 147.54,53.45 v2(147.2,53.11)
N57313074: length 3.6
  TOP w0.127: 149.58,50.83 149.58,51.56 v3(149.36,51.78) 149.14,52 148.94,52 148.56,52.38 148.56,52.67 v2(148.12,53.11)
  BOTTOM w0.127: UCPU1.AU8 147.94,53.11 v2(148.12,53.11)
N57317696: length 9.1
  TOP w0.127: v2(165.33,49.23) 165.23,49.34 161.21,49.34 v3(161,49.13) 161,48.86 160.41,48.27 159.97,48.27 159.77,48.47 159.01,48.47 158.78,48.7 158.78,49.2 RC9.2
  BOTTOM w0.127: v2(165.33,49.23) 165.9,48.66 SW1.1
N57319429: length 1.8
  TOP w0.127: T195.1 117.5,57.51 v2(117.65,57.51)
  BOTTOM w0.254: UCPU1.AK62 117.34,57.13 117.65,57.44 v2(117.65,57.51)
N57319432: length 1.9
  TOP w0.127: T196.1 118.24,56.75 v2(118.24,57.49)
  BOTTOM w0.254: v2(118.24,57.49) 118.24,57.46 117.86,57.09 117.86,56.57 UCPU1.AL61
N57408632: length 5.3
  TOP w0.127: v2(39.48,66.92) 39.48,67.21 39.35,67.34 RT164.2 ; UT1.F19 40.2,63.99 v2(39.88,63.67)
  IN2 w0.089: v2(39.48,66.92) 39.13,66.57 39.13,65.76 40.28,64.61 40.28,64.07 v2(39.88,63.67)
N57526872: length 19.3
  TOP w0.076: v2(22.91,58.56) 22.91,58.84 23.27,59.19 23.27,59.73 U722.F10
  TOP w0.127: v1(20.32,68.94) 19.92,68.54 v2(19.66,68.54)
  TOP w0.152: RT201.1 19.5,68.7 v2(19.66,68.54)
  IN1 w0.081: v2(19.66,68.54) 19.18,68.06 19.18,67.74 20.3,66.63 21.63,66.63 22.32,65.94 22.32,62.75 22.4,62.67 22.4,61.58 21.61,60.79 21.61,59.86 v2(22.91,58.56)
  BOTTOM w0.127: RT200.1 22.2,56.59 22.21,56.6 22.21,57.36 RT199.1 22.91,58.06 v2(22.91,58.56)
N57670088: length 2.6
  TOP w0.127: T116.1 143.05,53.58 v2(143.49,53.15)
  BOTTOM w0.127: UCPU1.AW15 143.52,53.11 v2(143.49,53.15)
N57965459: length 1
  BOTTOM w0.127: PQ201.2 56.82,55.71 v1(57.13,55.41)
N58401690: length 1
  BOTTOM w0.127: RE107.1 179.05,55.94 T197.1
N58453857: length 4.2
  TOP w0.127: Q71.1 203.23,17.6 203.23,15.96 v3(202.9,15.63) 201.62,14.36 R536.2
N58842401: length 1.8
  TOP w0.127: v2(149.63,58.53) 149.63,57.99 T125.1
  BOTTOM w0.127: UCPU1.AD4 150.17,59.47 149.78,59.09 149.78,58.68 v2(149.63,58.53)
N58864976: length 4.9
  TOP w0.127: v3(180.57,37.17) 180.57,35.53 180.16,35.12 R1445.2 R1446.2 179.17,34.15 179.28,34.04 U717.5
N59418764: length 6.4
  TOP w0.076: U722.C2 25.27,64.23 25.27,64.57 25.32,64.63 25.32,64.8
  TOP w0.127: v2(26.07,68.07) 25.92,67.91 25.92,66.18 25.63,65.9 25.63,65.36 25.32,65.06 25.32,64.8
  BOTTOM w0.127: R1436.1 26.24,67.9 v2(26.07,68.07) 25.67,68.07 v1(25.3,67.7)
N59418771: length 5.2
  TOP w0.076: U722.B2 25.76,64.22 26.21,64.22 26.76,64.77 26.76,65.49
  TOP w0.127: 26.76,65.49 26.76,65.81 26.91,65.96 27.6,65.96 27.78,66.14 27.78,66.57 27.79,66.58 27.79,66.76 v2(27.76,66.8)
  BOTTOM w0.127: v2(27.76,66.8) 27.89,66.93 TC35.1
N59894012: length 2.5
  TOP w0.127: U15.29 185.63,48.82 v1(185.57,48.88) 185.17,49.28 RE92.2
N59894959: length 3.1
  TOP w0.127: v1(184.58,40.51) 184.77,40.7 RC230.1 185.57,41.33 185.91,41.67 186.02,41.67 186.13,41.78 U15.13
N60736253: length 6.7
  TOP w0.254: PQ221.2 55.27,37.42 PR275.1 PR281.2
  TOP w0.381: PR281.2 56.81,35.78 v1(57.13,35.46) 57.13,33.89 56.75,33.51 PQ223.5
N60750271: length 5.8
  TOP w0.127: v1(58.9,36.53) 59.96,35.47 PC218.2
  TOP w0.381: PR279.1 59.69,34.63 PR278.1 ; PR278.1 61.48,34.63 61.77,34.92 PQ222.2 ; PR278.1 PC218.2
N60753752: length 4.2
  TOP w0.127: v1(61.29,31.45) 60.83,31.91 60.83,32.09 PR277.2
  TOP w0.381: PQ223.2 58.7,33.51 59.13,33.08 PC1536.1 60.02,32.88 PR277.2
N60757042: length 3.5
  TOP w0.127: PR280.1 57.32,54.59 56.46,54.59 v1(56.37,54.68) 55.86,55.19 55.86,56.13 56.08,56.36 56.48,56.36 PQ206.5
N60757502: length 3.7
  TOP w0.381: PQ223.6 55.89,32.86 55.56,33.19 55.56,33.96 v1(55.02,34.5) 55.02,35.7 PR281.1
N60799582: length 34.4
  TOP w0.254: PR1072.1 65.13,46.97 PR1067.2 64.26,46.97 v2(63.93,46.64)
  IN4 w0.254: v2(63.93,46.64) 70.26,46.64 71.04,47.43 71.04,49.01 72.53,50.49 73.52,50.49 78.7,55.67 78.7,58.72 81.38,61.4 84.32,61.4 v2(85.8,59.91)
  BOTTOM w0.254: PH1007.2 v2(85.8,59.91)
N60799590: length 1.9
  TOP w0.127: PC1014.2 v1(70.71,45.91)
  TOP w0.254: PR1098.1 69.67,45.93 PC1014.2
N60799629: length 4.1
  TOP w0.127: v1(63.96,45.45) 66.32,45.45 PC1095.2
  TOP w0.254: PR1065.1 67.77,46.03 PC1095.2
N60799636: length 1.2
  TOP w0.254: PC1020.2 65.89,47.96 PR1122.1
N60799669: length 2.6
  BOTTOM w0.127: v1(73.64,50.99) 73.43,50.78 72.98,50.78 72.37,50.17 PC1088.1
  BOTTOM w0.203: PR1087.2 PC1088.1
N60799687: length 2.9
  TOP w0.254: PR1028.1 63.3,54.7 v2(62.97,54.36) 62.64,54.7 PR1025.2
  BOTTOM w0.127: PR1074.2 63.25,54.36 v2(62.97,54.36) 62.56,54.77 v1(62.56,54.82)
N60799689: length 2.6
  TOP w0.254: PR1024.2 62.51,53.65 v2(62.97,53.65) 63.45,53.65 PR1076.1
  BOTTOM w0.127: PR1063.2 63.42,53.65 v2(62.97,53.65) 62.64,53.65 v1(62.48,53.49)
N60799691: length 2.9
  TOP w0.254: PR1070.1 v2(62.97,52.92) PR1125.2
  BOTTOM w0.127: v1(63.53,51.84) 63.58,51.89 PR1084.2 v2(62.97,52.92)
N60799808: length 2.2
  TOP w0.127: PC1069.2 v1(73.89,58.84)
  TOP w0.203: PC1069.2 74.88,57.64 PR1068.1
N60799810: length 24.7
  IN2 w0.254: v2(89.35,42.27) 89.35,44.6 88.39,45.55 80.26,45.55 77.04,48.77 77.04,53.8 v2(76.51,54.34)
  BOTTOM w0.203: v2(76.51,54.34) 76.4,54.24 PR1097.2
  BOTTOM w0.254: PH1009.1 89.18,42.44 v2(89.35,42.27)
N60799848: length 12.4
  TOP w0.203: v2(75.44,51.72) 75.11,51.39 PR1126.2 74.73,52.23 PR1064.1
  IN3 w0.203: v2(75.44,51.72) 75.83,51.33 79.72,51.33 80,51.05 84.76,51.05 84.96,51.25 v2(84.96,51.3)
  BOTTOM w0.254: v2(84.96,51.3) 85.23,51.04 PH1008.2
N60799854: length 3.1
  BOTTOM w0.127: PC1064.2 72.62,56.07 v1(72.62,56.52)
  BOTTOM w0.254: PC1064.2 71.13,54.58 PR1123.1
N60799887: length 2.1
  TOP w0.127: PC1096.1 v1(77.06,50.15)
  TOP w0.254: PC1096.1 77.09,51.42 PR1096.2
N60799936: length 2.1
  TOP w0.127: PC1134.1 v1(71.55,61.27)
  TOP w0.254: PC1134.1 71.55,59.24 PR1060.2
N60799960: length 2.1
  TOP w0.127: PR1092.1 68.25,60.74 v1(68.4,60.74)
  TOP w0.254: PR1092.1 PC1068.2
N60799970: length 10.5
  IN1 w0.203: v2(64.97,59.92) 64.97,59.8 65.35,59.42 71.26,59.42 v2(72.24,58.44)
  BOTTOM w0.127: v1(72.49,57.95) 72.49,58.19 v2(72.24,58.44)
  BOTTOM w0.203: PR1089.2 64.87,59.65 64.97,59.75 v2(64.97,59.92)
  BOTTOM w0.254: v2(72.24,58.44) PH1006.1
N61450237: length 3.1
  TOP w0.127: v3(204.35,31.05) R289.2
  TOP w0.305: R289.2 202.33,30.27 U48.8
N61547946: length 3.4
  TOP w0.508: QZ9.1 56.6,73.61 56.6,74.54 55.53,75.61 R2670.1
N61553916: length 4.9
  TOP w0.127: R2671.1 55.49,78.25 55.07,78.67 55.07,79.84 v1(54.48,80.43)
  TOP w0.508: R2671.1 56.37,78.25 56.55,78.43 UZ26.6
N62098363:
  vias: v3(202.04,39.19)
N63073614: length 15.5
  TOP w0.127: v2(57.22,64.36) 57.21,64.36 57.05,64.19 PQ216.5 ; PR248.2 53.24,67.04 52.77,66.57 52.77,65.5 53.36,64.91 v2(53.47,64.91)
  IN1 w0.081: v2(57.22,64.36) 55.25,62.39 53.11,62.39 52.07,63.43 52.07,65.01 52.3,65.24 53.06,65.24 53.39,64.91 v2(53.47,64.91)
  BOTTOM w0.127: v2(53.47,64.91) 53.01,65.36 v1(51.28,65.36)
N63073655: length 5.8
  TOP w0.127: v1(52.3,76.16) 52.45,76.01 52.45,74.79 52.53,74.71 52.53,74.38 53.16,73.75 PQ217.5 53.5,73.75 53.68,73.57 53.68,72.73 53.16,72.22 PR251.2
N63092271: length 6
  TOP w0.127: PR217.2 20.42,73.29 PQ209.2 v2(20.42,72.01)
  BOTTOM w0.127: v2(20.42,72.01) v3(20.42,68.41)
N63092515: length 3.9
  TOP w0.127: PQ209.5 20.42,71.33 v1(22.12,73.03) 22.25,73.16 22.25,73.87 PR220.2
N63216045: length 1
  TOP w0.127: QH8.6 6.25,7.75 R913.1
N63216077: length 7
  TOP w0.127: R912.1 6.52,8.59 6.64,8.72 6.64,9.29 6.82,9.47 9.42,9.47 10.07,10.12 v1(10.07,11.01) 10.07,11.2 9.8,11.47 9.05,11.47 QH9.3
N63216109: length 2.4
  TOP w0.127: v1(5.88,10.5) 5.88,9.8 R911.1 6.88,10.17 QH9.6
N63239426: length 2.1
  TOP w0.127: v1(6.2,4.91) R910.1 6.22,5.95 Q41.1
N63254653: length 6.6
  TOP w0.127: PR218.1 62.21,49.82 62.21,48.47 62.46,48.22 PQ208.2 62.92,48.22 62.38,47.68 62.38,47.33 v2(61.67,46.62)
  BOTTOM w0.127: v1(62.76,48.12) 62.36,47.71 PR283.1 62.13,47.08 v2(61.67,46.62)
N63877984: length 3.5
  TOP w0.127: PR229.1 59.28,46.62 v1(58.9,47)
  TOP w0.254: PR229.1 59.96,47.42 PR282.1 60.76,48.22 PQ208.5
N64008725: length 3.1
  TOP w0.127: v3(157.68,40.14) 158.98,40.14 R78.2 159.23,39.89 QE13.5 QE13.6
N64008885: length 2.5
  TOP w0.127: 159.88,37.23 QE13.3 ; 159.88,37.23 159.88,37.24 160.3,37.65 v3(161.06,37.65) ; 159.88,37.23 159.88,36.18 R79.2
N64546397: length 1
  TOP w0.254: PR284.2 59.45,63.56 PQ215.5
N64546409: length 64.8
  TOP w0.127: PD206.2 99.37,75.29 v2(99.59,75.51) v1(100.16,76.08)
  IN2 w0.089: v2(99.59,75.51) 99.59,77.19 98.97,77.81 92.74,77.81 91.4,76.47 88.49,76.47 87.06,75.04 85.01,75.04 v2(84.98,75.08)
  IN3 w0.089: v2(52.45,67.94) 52.48,67.97 52.48,70.04 53.53,71.09 53.53,75.14 56.88,78.49 61.87,78.49 62.34,78.02 62.85,78.02 63.22,78.38 68.73,78.38 69.95,77.16 71.35,77.16 72,76.51 79.22,76.51 80.19,75.54 84.52,75.54 v2(84.98,75.08)
  BOTTOM w0.127: v2(52.45,67.94) 53,67.4 53.81,67.4 PR291.2 54.27,67.27 54.42,67.12 PR285.1
N64570632: length 6
  TOP w0.127: v1(56.03,66.73) 56.23,66.93 57.02,66.93 PR286.2
  TOP w0.254: PR286.2 57.15,66.77 57.95,65.97 57.98,65.97 58.23,65.72 58.23,64.11 58.06,63.94 ; 58.06,63.94 58.42,63.94 PQ215.4 ; 58.06,63.94 PQ216.6
N64571386: length 6.4
  TOP w0.127: v2(56.11,64.16) 56.05,64.22 56.05,64.57 56.4,64.92 56.81,64.92 57.05,65.16 PQ216.2
  BOTTOM w0.127: PR285.2 53.92,65.58 53.92,64.4 54.02,64.3 PR247.1 54.81,63.9 v1(55.35,63.9) 55.48,63.9 55.7,64.13 56.07,64.13 v2(56.11,64.16)
N64571512: length 23.7
  TOP w0.127: PQ215.3 58.55,65.71 58.55,65.85 58.06,66.33 PR286.1 58.06,67.08 57.85,67.29 55.78,67.29 55.43,67.64 55.43,70.41 55.68,70.66 57.44,70.66 57.65,70.86 57.65,72.3 58.07,72.72 58.07,73.38 57.23,74.22 57.23,74.54 56.11,75.66 v2(56.11,76.06)
  BOTTOM w0.127: PR243.2 51.91,80.48 v1(52.33,80.05) 53.37,79.01 54.6,79.01 55.22,78.39 55.22,76.67 55.71,76.18 55.99,76.18 v2(56.11,76.06)
N64625473: length 19.7
  TOP w0.254: PU201.5 85.23,73.96 PC211.1 PR268.1 PR264.2 81.46,71.97 81.46,70.79 82.71,69.54 v3(83.13,69.54) 83.67,69 85.02,69 85.83,69.81 PR258.1 85.95,69.73 88.49,69.73 89.08,70.32 PD203.1 89.23,69.85 89.23,68.74 89.4,68.58 89.4,67.97 88.68,67.25 88.43,67.25 PQ218.3
N64625477: length 21.1
  TOP w0.127: PC212.1 84.89,70.77 84.43,70.32 82.67,70.32 81.94,71.04 v2(81.94,71.46) ; PC212.1 PR258.2 86.28,70.32 PD203.2 ; PC212.1 85.46,71.29 87.23,71.29 87.56,71.63 87.56,72.35 87.25,72.66 85.61,72.66 PU201.7 ; PR265.1 86.59,68.72 PR252.2 85.54,67.83 84.82,68.54 83.17,68.54 80.98,70.73 v2(80.98,71.46)
  IN1 w0.081: v2(80.98,71.46) v2(81.94,71.46)
N64625485: length 4.2
  TOP w0.127: PQ218.2 88.43,67.9 87.55,67.9 PC213.1 PR265.2 86.06,67.29 v1(84.51,67.29)
N64625491: length 2.1
  TOP w0.127: PQ218.5 90.33,67.9 PR274.1 91.34,66.89 v1(91.31,66.86)
N64625687: length 6.9
  TOP w0.127: v3(85.46,75.37) 86.48,74.35 86.48,73.55 86.23,73.31 85.61,73.31 ; PR254.2 83.08,70.93 PR269.1 84.38,72.3 85.39,73.31 85.61,73.31 ; 85.61,73.31 PU201.6
N65247919:
  vias: v1(36.09,36.42)
N65247927: length 2.8
  TOP w0.127: v1(31.85,33.47) 32.3,33.92 R80.2
  TOP w0.254: QE14.3 33.86,33.61 33.1,33.61 R80.2
N65482285: length 1.6
  TOP w0.127: v1(142,56.72) 141.53,56.72 141.4,56.84 R9.2
  TOP w0.356: R9.2 CC125.1
N66491485: length 11.5
  BOTTOM w0.127: v1(203.71,80.45) 203.38,80.78 202.03,80.78 RC66.2 201.14,79.89 201.14,79.29 200.43,78.58 198.9,78.58 198.35,79.13 197.93,79.13 197.59,79.46 197.59,79.79 197.65,79.85 RC64.2 196.76,79.38 JSPI1.16
N67232079: length 18.4
  TOP w0.254: PQ206.3 58.23,57 57.9,56.66 57.88,56.66 v2(57.78,56.56)
  IN1 w0.081: v2(60.7,65.27) 60.7,64.39 60.59,64.28 60.59,62.74 60.75,62.57 60.75,59.87 60.67,59.79 60.67,56.82 60.2,56.35 58.03,56.35 57.81,56.56 v2(57.78,56.56)
  BOTTOM w0.127: v1(62.05,63.1) 62.42,63.47 PC1535.1 PR240.1 63.14,65.21 PU202.4 62.63,65.55 62.14,65.06 PR246.1 61.28,65.06 61.07,65.27 v2(60.7,65.27)
N67365065: length 2.9
  TOP w0.127: PQ223.3 58.18,34.87 v1(58.52,35.21)
  TOP w0.381: PQ223.3 59.01,34.16 59.44,33.74 PR279.2
N67601016: length 2.2
  TOP w0.127: v1(157.35,60.21) 157.35,60.16 158.16,59.36 CC225.1 158.55,59.37 158.66,59.48 R10.2
N67857646: length 25.9
  IN4 w0.254: v2(85.17,58.35) 85.31,58.21 85.31,57.39 85.62,57.08 85.62,55.6 84.29,54.26 80.62,54.26 80.1,54.78 78.36,54.78 76.26,52.69 76.26,51.86 75.14,50.75 74.73,50.75 73.76,49.78 73.76,49.28 72.81,48.33 72.34,48.33 71.54,47.53 71.54,46.05 v2(71.53,46.03)
  BOTTOM w0.254: PR1088.2 69.83,45.78 v3(70.54,45.78) 70.71,45.78 70.97,46.03 v2(71.53,46.03) ; PH1005.1 v2(85.17,58.35)
N67859167: length 2.9
  TOP w0.127: v1(77.29,54.72) 77.29,54.49 76.71,53.91 76.2,53.91 76.05,54.06 PC1090.2
  TOP w0.203: PR1081.1 75.79,54.03 PC1090.2
N67859352: length 2
  BOTTOM w0.127: PC1089.1 66.65,54.97 v1(66.83,54.8)
  BOTTOM w0.254: PC1089.1 66.68,55.81 66.68,56.64 PR1090.2
N67859430: length 2.3
  TOP w0.127: PC1072.1 69.52,60.31 v1(69.67,60.46)
  TOP w0.254: PR1073.2 69.75,59.17 PC1072.1
N67997563: length 2.6
  TOP w0.127: RTCR2.1 D122.1 v1(12.47,12.73)
N68203781: length 7.6
  TOP w0.127: v3(193.76,45.89) 194.18,45.47 RH127.2 194.29,44.3 196.85,44.3 197.13,44.59 197.13,45.97 Q72.2
N119009545: length 2.2
  TOP w0.127: PR212.2 21.13,70.49 21.07,70.56 PQ209.6 v1(22.32,71.02)
N119009632: length 1.4
  TOP w0.254: v2(30.89,74.75) 31.24,75.1 PR209.1
  BOTTOM w0.127: v2(30.89,74.75) v1(30.89,74.05)
N119967293: length 25
  TOP w0.127: PQ216.3 56.4,65.79 56.09,66.09 v2(56.09,66.12) ; v2(43.38,75.54) 42.71,75.54 41.47,76.78 41.47,77.54 41.2,77.81 v3(41.2,78.01) 41.2,78.32 41.35,78.47 42.33,78.47 PR244.2
  IN4 w0.127: v2(56.09,66.12) 56.06,66.15 56.06,66.74 53.96,68.84 53.96,71.39 53.19,72.16 46.93,72.16 44.77,74.32 44.16,74.32 43.45,75.02 43.45,75.47 v2(43.38,75.54)
N119982384: length 3.5
  BOTTOM w0.127: v1(60.53,63.56) 60.53,62.21 61.02,61.72 PR214.2 60.55,61.21 PU200.6
N122715521: length 2.6
  TOP w0.127: v1(18.39,71.1) 18.59,71.31 PR211.2 19.42,72.92 PQ209.3
N122716790: length 2.8
  BOTTOM w0.127: v1(57.76,66.2) 57.68,66.28 PR242.2
  BOTTOM w0.254: PR242.2 57.38,67.5 PQ224.1
N122717029: length 35.7
  TOP w0.127: PQ213.1 57.96,62.26 58.37,62.67 v2(58.78,62.67)
  IN4 w0.127: v2(60.68,71.25) 61.08,71.25 61.3,71.03 61.3,70.05 60.44,69.19 60.44,69.02 59.91,68.49 59.91,65.47 59.66,65.22 59.66,65.04 59.07,64.45 59.07,62.96 v2(58.78,62.67)
  BOTTOM w0.127: v2(60.68,71.25) 60.79,71.25 61.13,71.59 61.13,72.49 62.54,73.9 62.54,77.87 61.7,78.71 57.72,78.71 56.73,77.72 56.73,75.83 56.38,75.47 55.59,75.47 54.42,76.64 54.42,77.4 53.63,78.19 51.89,78.19 v3(51.68,78.4) 51.36,78.72 PR239.1
N122717329: length 14.7
  TOP w0.127: PQ217.3 55.63,74.4 v2(55.71,74.48) ; PQ216.4 56.4,63.67 56.64,63.91 56.64,64.49 v2(56.65,64.5)
  IN3 w0.089: v2(56.65,64.5) 56.65,64.78 57.58,65.71 57.58,66.94 56.29,68.23 55.83,68.23 54.64,69.42 54.64,73.7 55.42,74.48 v2(55.71,74.48)
  BOTTOM w0.127: v1(56.84,64.01) 56.65,64.21 v2(56.65,64.5)
N122717720: length 3
  TOP w0.127: PR245.2 50.58,72.78 51.77,72.78 v1(52.22,73.24) 53.04,73.24 PQ217.6
N122719403: length 34.6
  TOP w0.127: PQ215.6 60.08,63.92 61.12,64.96 61.12,65.82 62.31,67 62.31,68.4 62.08,68.63 61.08,68.63 60,67.55 55.88,67.55 55.69,67.74 55.69,70.15 55.94,70.4 57.73,70.4 58.05,70.72 58.05,72.34 58.33,72.62 58.33,73.49 57.49,74.33 57.49,74.64 56.69,75.44 56.69,77.23 56.17,77.75 55.16,77.75 54.79,78.11 54.79,78.95 54.37,79.37 53.51,79.37 v1(52.53,78.39) 51.91,78.39 v2(51.26,77.75)
  BOTTOM w0.127: PR241.2 51.68,76.31 51.68,77.41 51.35,77.75 v2(51.26,77.75)
N122723381: length 4.9
  TOP w0.127: PU201.2 89.85,72.66 91.27,72.66 PR230.1 PR224.2 91.34,73.75 91.75,74.15 92.76,74.15 92.88,74.27 v1(93.45,74.27)
N122728402: length 3.2
  TOP w0.127: v1(63.16,46.52) 62.96,46.71 PQ208.1 63.27,47.57 63.48,47.77 63.48,48.73 63.33,48.87 PQ208.3
N122733349: length 5.8
  TOP w0.127: v3(63.09,13.42) 63.65,13.42 PR266.2 PR270.1 PR262.1 63.45,15.58 63.2,15.33 PC214.1 62.42,15.34 62.42,16.51 PU203.5
N122733365: length 7
  TOP w0.127: PR259.2 PR271.1 63.3,17.36 63.1,17.16 PU203.6 61.81,17.16 60.99,16.34 v3(60.99,13.67)
N122733968: length 2.4
  TOP w0.127: v3(61.06,22.44) 61.7,22.44 62,22.74 PR257.2 62.44,22.63 PQ219.6
N122734452: length 4.8
  TOP w0.127: PU203.2 57.91,17.81 57.58,17.81 57.25,17.48 PR273.1 PR260.2 56.41,18.09 55.58,18.09 55.35,17.87 v1(54.94,17.87)
N122772225: length 5.2
  TOP w0.127: v1(30.76,75.95) 31.09,75.62 31.87,75.62 PR209.2 33.23,74.27 34.65,74.27 34.87,74.04 PQ207.6
N122777610: length 5.2
  TOP w0.127: PR250.2 54.8,71.46 v1(55.68,71.46) 55.8,71.59 55.8,72.34 55.52,72.61 54.66,72.61 54.37,72.91 54.37,73.53 54.59,73.75 PQ217.2
N122777613: length 8.6
  TOP w0.127: v2(51.81,67.58) 51.98,67.76 PR249.2
  IN1 w0.081: v2(56.53,66.51) 56.17,66.87 52.11,66.87 51.81,67.17 v2(51.81,67.58)
  BOTTOM w0.127: v1(50.85,67.9) 51.17,67.58 v2(51.81,67.58) ; v2(56.53,66.51) 56.71,66.33 PQ224.2
N123360127: length 4.8
  TOP w0.127: v2(40.53,63.67) 40.85,64 UT1.H19 ; RT12.1 39.94,67.38 40.06,67.26 v2(40.06,66.92)
  IN4 w0.081: v2(40.53,63.67) 40.53,64.32 40.54,64.33 40.54,65.19 39.95,65.78 39.95,66.8 v2(40.06,66.92)
N123360144: length 5.1
  TOP w0.127: RT5.1 49.25,66.35 v2(48.87,65.97) ; UT1.Y18 46.7,63.35 v2(46.38,63.67)
  BOTTOM w0.127: v2(48.87,65.97) 48.87,65.58 48.49,65.2 47.91,65.2 v2(46.38,63.67)
N123959194: length 4
  BOTTOM w0.127: PR225.1 57.98,59.23 57.98,60.13 58.51,60.66 PU200.4 58.51,62.18 v1(58.37,62.32)

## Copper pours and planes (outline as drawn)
1.0V_B+ on TOP (solid shape): 197.4,64.25 197.41,64.25 197.41,63.29 197.32,63.2 196.19,63.2 195.68,62.7 194.29,62.7 194.03,62.95 194.03,64.22 194.1,64.29 197.36,64.29
1.0V_B+ on BOTTOM (solid shape): 198.45,67.01 198.45,66.43 198.06,66.04 198.06,65.25 198.44,64.87 198.81,64.87 198.91,64.77 198.91,63.29 198.84,63.23 198.06,63.23 197.96,63.33 197.46,63.33 197.33,63.2 196.57,63.2 196.06,62.7 195.88,62.7 194.97,62.7 194.87,62.8 194.87,64.32 195.05,64.5 195.35,64.5 195.58,64.73 195.58,65.24 196.14,65.79 197,65.79 197.71,66.51 197.71,66.94 197.84,67.06 198.4,67.06
1.0V_BST_R on TOP (solid shape): 199.42,61.49 199.42,59.89 199.14,59.61 198.29,59.61 198.16,59.74 198.16,61.36 198.36,61.57 199.34,61.57
1.0V_LDO on BOTTOM (solid shape): 201.5,62.16 203.12,62.16 203.19,62.1 203.19,61.59 203.12,61.53 201.31,61.53 201.02,61.82 200.43,61.82 200.34,61.91 200.34,62.63 200.42,62.71 200.95,62.71
1.0V_LX on BOTTOM (solid shape): 199.71,62.61 199.71,61.29 199.82,61.17 200.64,61.17 200.7,61.24 202.48,61.24 202.51,61.2 202.51,60.61 202.34,60.44 201.83,60.44 201.42,60.03 201.42,59.8 199.75,58.12 197.19,58.12 197.08,58.24 197.08,60.75 197.5,61.17 197.51,61.17 199.05,62.71 199.61,62.71
1.2V_DDR_B+ on TOP (solid shape): 170.99,37.09 170.99,36.47 170.97,36.33 170.99,36.2 170.99,35.82 170.79,35.62 170.66,35.62 170.41,35.37 170.41,34.76 170.84,34.32 170.84,33.81 170.73,33.69 170.73,33.68 170.21,33.16 170.21,31.15 170.18,31.12 169.8,31.12 169.8,33.38 169.32,33.87 168.76,33.87 168.63,33.99 168.63,37.02 168.78,37.17 170.92,37.17
1.2V_DDR_BS_R on TOP (solid shape): 174.49,28.24 174.49,26.67 174.33,26.51 173.7,26.51 173.61,26.6 173.61,28.19 173.75,28.33 174.4,28.33
1.8VA_B+ on TOP (solid shape): 176.76,80.6 176.76,78.83 177.27,78.32 177.27,76.67 177.01,76.41 177.01,75.02 176.76,74.76 176.25,74.76 176.14,74.65 174.19,74.65 174.15,74.69 174.15,75.84 174.21,75.9 175.11,75.9 175.49,76.29 175.49,79.59 175.51,79.61 175.51,80.68 175.62,80.78 176.58,80.78
1.8VA_SW on TOP (solid shape): 170.5,77.96 170.5,77.73 170.59,77.64 170.59,77.52 172.19,75.92 172.19,74.63 172.08,74.53 172.06,74.53 171.3,74.53 171.25,74.53 171.19,74.51 171.04,74.51 171,74.47 170.99,74.47 170.9,74.38 169.4,74.38 169.27,74.51 169.27,77.81 169.52,78.06 170.4,78.06
1.8VU_B+ on TOP (solid shape): 170.38,43.01 170.66,43.01 170.92,42.76 170.92,42.25 171.02,42.15 171.02,42.15 171.3,41.87 172.77,41.87 172.79,41.84 172.81,41.81 172.84,41.74 172.81,41.67 172.89,41.09 173.4,41.37 173.41,41.38 173.55,41.52 173.84,41.23 173.84,39.96 173.71,39.84 171.04,39.84 170.79,40.09 170.79,41.36 170.39,41.76 169.5,41.76 169.45,41.81 169.45,42.95 169.51,43.01 170.38,43.01
1.8VU_SW on TOP (solid shape): 167.01,44.88 167.01,44.28 166.98,44.21 166.91,44.18 166.55,43.78 166.99,43.48 167.01,43.48 167.49,43.01 167.49,41.8 167.44,41.76 166.11,41.76 165.84,41.49 165.84,41.11 165.71,40.98 164.82,40.98 164.44,41.36 164.44,44.66 164.82,45.04 166.84,45.04
3V_B+ on TOP (solid shape): 94.21,24.09 94.21,22.21 94.01,22.01 92.51,22.01 91.89,22.62 91.38,22.62 90.94,22.18 89.48,22.18 89.48,22.72 89.13,23.07 89.13,23.58 89.76,24.22 94.08,24.22
3V_B+ on BOTTOM (solid shape): 94.18,24.42 94.18,22.12 94.08,22.02 92.49,22.02 91.82,22.69 91.24,22.69 90.8,22.25 90.8,21.93 90.74,21.87 89.27,21.87 89.2,21.93 89.2,23.21 90.42,24.44 90.42,24.44 90.66,24.67 93.93,24.67
3V_B+ on IN2 (solid shape): 92.42,24.08 92.42,22.8 92.43,22.79 92.43,22.69 92.3,22.56 89.13,22.56 88.88,22.82 88.88,23 88.88,23.01 88.92,23.15 88.89,23.3 88.88,23.33 88.94,23.4 89.6,23.4 90.42,24.21 92.29,24.21
3V_BST on BOTTOM (solid shape): 89.03,23.23 89.03,21.95 88.95,21.88 88.8,21.88 88.62,22.06 87.86,22.06 87.73,22.18 87.73,23.08 88.06,23.4 88.85,23.4
3V_FB_R on BOTTOM (solid shape): 90.53,17.36 90.53,16.72 90.45,16.65 90.37,16.65 90.36,16.66 90.08,16.75 89.83,16.6 89,16.6 88.88,16.72 88.88,17.36 89,17.48 90.4,17.48
3V_LX on TOP (solid shape): 85.67,22.54 85.67,22.08 85.95,21.8 86.72,21.8 86.84,21.68 86.84,19.64 86.59,19.39 83.29,19.39 82.91,19.77 82.91,22.69 82.93,22.72 84.02,22.72 84.05,22.74 85.47,22.74
3V_LX on BOTTOM (solid shape): 87.62,21.79 88.6,21.79 88.67,21.71 90.79,21.71 90.86,21.79 91.7,21.79 91.77,21.71 91.77,21.61 91.7,21.53 90.95,21.53 90.88,21.46 89.19,21.46 88.81,21.08 87.65,21.08 86.72,20.15 86.72,19.01 86.34,18.63 84.81,18.63 84.3,19.14 84.3,22.56 84.56,22.82 86.59,22.82
5V_B+ on TOP (solid shape): 67.57,45.17 67.79,45.09 68.01,45.17 70.97,45.17 71.22,44.92 71.22,44.23 71.22,44.01 71.1,43.89 70.98,43.89 70.98,43.9 69.58,43.9 69.58,43.89 69.52,43.89 69.41,43.77 69.41,43.49 69.3,43.39 69.24,43.39 65.13,43.39 64.62,43.9 63.09,43.9 62.97,44.03 62.97,44.92 63.22,45.17
5V_B+ on BOTTOM (solid shape): 67.41,45.17 67.42,45.17 67.56,45.03 68.03,45.03 68.17,45.17 70.97,45.17 71.22,44.92 71.22,44.03 71.15,43.95 69.58,43.95 69.42,43.79 69.42,43.53 69.28,43.39 65.89,43.39 65.51,43.77 64.75,43.77 64.55,43.58 62.98,43.58 62.91,43.65 62.91,44.42 62.84,44.49 62.84,45.25 63.02,45.42 67.16,45.42
5V_BST on BOTTOM (solid shape): 62.71,45.24 62.71,44.44 62.71,43.66 62.64,43.58 62.47,43.58 62.42,43.63 62.09,43.63 61.95,43.77 61.95,45.26 62.06,45.37 62.58,45.37
5V_LX on TOP (solid shape): 58.97,44.07 58.97,43 59.13,42.83 60.14,42.83 60.23,42.74 60.23,41.93 60.17,41.87 57.51,41.87 57.25,42.12 57.25,44.15 57.3,44.2 58.66,44.2 58.66,44.2 58.83,44.2
5V_LX on BOTTOM (solid shape): 61.2,43.5 62.37,43.5 62.42,43.45 64.6,43.45 64.66,43.5 65.41,43.5 65.48,43.43 65.48,43.32 65.41,43.25 64.61,43.25 64.53,43.18 62.5,43.18 62.46,43.14 62.46,42.88 62.38,42.8 60.98,42.8 60.81,42.63 60.81,40.39 60.58,40.17 57.68,40.17 57.25,40.6 57.25,43.87 58.17,44.79 59.92,44.79
+0.6VS on TOP (solid shape): 163.81,28.66 163.81,27.14 163.55,26.88 163.17,26.88 163.04,27.01 163.04,28.66 163.17,28.79 163.68,28.79
+0.6VS on TOP (solid shape): outline of 313 points within 94.84,17.36 160.44,19.77
+0.6VSP on TOP (solid shape): 167.19,31.03 168.3,31.03 168.38,30.95 168.38,30.34 168.33,30.29 167.46,30.29 167.23,30.06 167.23,29.17 165.2,27.14 164.06,27.14 163.98,27.22 163.98,27.51 164.54,27.51 164.54,28.02 163.98,28.02 163.98,28.55 164.24,28.81 165.69,28.81 166.32,29.43 166.32,31.25 166.33,31.27 166.86,31.27 166.86,31.27 166.94,31.27
+1.0V_APLL on TOP (solid shape): 160.19,61.2 160.19,60.56 160.13,60.51 159.06,60.51 158.9,60.36 158.48,60.36 158.39,60.45 158.39,61.1 158.56,61.26 160.12,61.26
+1.0V_CLK on TOP (solid shape): 142.47,70.18 142.29,69.92 142.39,69.62 142.42,69.54 142.38,69.46 142.24,69.15 142.44,68.86 142.47,68.85 142.47,68.31 142.44,68.3 142.25,68.1 142.26,67.82 142.34,67.72 142.42,67.66 142.47,67.61 142.47,66.91 142.44,66.84 142.37,66.81 142.06,66.63 142.06,66.28 142.08,66.24 141.84,66.01 141.81,66.01 141.47,65.92 141.38,65.58 141.39,65.55 141.2,65.36 140.95,65.36 140.18,66.13 140.18,66.51 140.44,66.76 141.33,66.76 141.83,67.27 141.83,67.61 142.03,67.88 141.93,68.19 141.9,68.26 141.93,68.34 142.04,68.57 141.96,68.82 141.93,68.89 141.96,68.95 142.04,69.19 141.94,69.43 141.91,69.47 141.92,69.53 141.96,69.58 142,69.65 142.02,69.93 141.84,70.14 141.84,70.29 142.38,70.82 142.47,70.82
+1.0V_CLK on IN2 (solid shape): 141.96,66.71 141.96,66.13 141.84,66.01 141.81,66.01 141.47,65.92 141.38,65.58 141.39,65.55 141.33,65.49 140.31,65.49 140.18,65.62 140.18,66.54 140.44,66.8 141.88,66.8
+1.0V_MPHYAON on IN2 (solid shape): outline of 138 points within 142.09,65.9 152.63,67.42
+1.0V_MPHYGT on TOP (solid shape): 143.97,65.87 144.05,65.83 144.06,65.74 144.41,65.29 144.75,65.74 144.74,65.77 144.8,65.83 144.86,65.76 144.87,65.75 144.95,65.63 145.07,65.55 145.08,65.55 145.26,65.36 145.26,64.47 144.63,63.84 143.1,63.84 142.72,64.22 142.72,65.17 142.77,65.25 142.86,65.26 143.24,65.34 143.32,65.73 143.33,65.83 143.41,65.87
+1.0V_MPHYGT on TOP: 148.82,76.29 148.79,76.26 148.17,76.26 147.8,75.89 146.51,75.89 146.25,76.15 146.25,77.81 146.83,78.38 146.83,79.47 147.21,79.85 153.49,79.85 154.45,78.9 154.45,77.71 154.38,77.64 154.1,77.64 154.09,77.66 151.27,77.66 151.26,77.66 150.91,77.66 150.55,78.02 150.55,78.08 150.29,78.16 150.05,78.04 148.95,76.95 148.92,76.95 148.82,76.84
+1.0V_MPHYGT on IN1: outline of 135 points within 142.22,62.35 151.62,78.32
+1.0V_MPHYGT on VCC: 143.08,63.33 141.96,64.45 141.96,66.4 142.85,67.29 142.85,71.48 144.12,72.75 144.12,75.8 146.51,78.19 148.08,78.19 148.44,77.83 148.44,77.41 145.64,74.61 145.64,71.31 144.25,69.91 144.25,67.8 145.01,67.04 145.01,63.94 144.4,63.33
+1.0V_PRIM_CORE on TOP (solid shape): 193.02,71.19 193.02,70.57 193.02,70.56 193.02,70.21 192.52,70.21 192.52,69.7 193.02,69.7 193.02,69.41 192.52,69.41 192.52,68.9 193.02,68.9 193.02,67.78 192.89,67.65 192.09,67.65 191.16,68.58 191.16,71.23 191.26,71.33 192.87,71.33
+1.0V_PRIM_CORE on BOTTOM (solid shape): 192.86,70.58 192.86,68.09 192.51,67.74 191.91,67.74 191.62,68.03 191.62,70.81 191.75,70.94 191.75,70.96 191.79,71 192.44,71
+1.0V_PRIM_CORE on IN1 (solid shape): outline of 215 points within 139.93,59.52 142.47,63.59
+1.0V_PRIM_CORE on IN3: outline of 194 points within 135.36,58.63 143.87,74.6
+1.0V_PRIM_CORE on VCC: 140.14,59.52 139.8,59.85 139.8,66.91 140.44,67.54 140.44,80.73 192.89,80.73 192.89,67.65 181.56,67.65 173.82,75.4 161.75,75.4 158.7,78.44 154.68,78.44 151.99,75.76 151.99,62.42 149.48,59.9 142.36,59.9 141.98,59.52 ; 1 cut-out
+1.0V_PRIM_COREP on TOP: 198.85,75.27 197.71,75.27 196.52,74.08 194.74,74.08 194.41,73.75 194.41,71.59 194.67,71.33 194.67,69.86 194.87,69.66 194.87,68.39 194.77,68.28 193.38,68.28 193.17,68.49 193.17,69.01 193.15,69.03 192.65,69.03 192.65,69.28 193.15,69.28 193.17,69.3 193.17,69.81 193.15,69.83 192.65,69.83 192.65,70.08 193.15,70.08 193.17,70.1 193.17,71.37 193.27,71.47 193.27,75.29 193.71,75.73 194.39,76.41 195.08,76.41 195.41,76.2 195.73,76.41 196.03,76.41 196.34,76.24 196.64,76.41 197.46,76.41 198.35,75.52 198.87,75.52 198.92,75.47 198.92,75.34
+1.0V_VCCST on TOP (solid shape): 152.25,75.73 152.25,73.75 151.99,73.49 150.98,73.49 150.97,73.5 150.75,73.28 149.58,73.28 149.53,73.33 149.53,73.77 149.63,73.87 150.42,73.87 150.72,74.18 150.72,75.5 151.03,75.8 152.17,75.8
+1.0V_VCCST on IN4 (solid shape): outline of 152 points within 124.56,67.78 125.83,70.57
+1.0V_VCCSTG on TOP (solid shape): 161.6,69.35 161.6,69.06 161.52,68.84 161.6,68.62 161.6,68.21 161.34,67.95 161.34,67.88 161.34,67.12 161.04,66.81 161.04,65.92 160.99,65.87 160.39,65.87 160.34,65.99 160.25,66.09 160.25,68.01 160.25,68.02 160.29,68.17 160.25,68.32 160.25,68.33 160.25,68.92 160.76,69.43 161.52,69.43
+1.0V_VCCSTG on BOTTOM (solid shape): 119.99,78.44 119.99,77.3 119.74,77.05 119.1,77.05 118.72,77.43 117.83,77.43 117.2,78.06 117.2,78.22 118.75,78.22 118.75,78.16 118.75,78.11 118.77,78.06 118.79,78.01 118.82,77.97 118.86,77.93 118.9,77.9 118.95,77.87 119,77.85 119.05,77.84 119.1,77.83 119.15,77.84 119.21,77.85 119.26,77.87 119.3,77.9 119.34,77.93 119.38,77.97 119.41,78.01 119.43,78.06 119.45,78.11 119.46,78.16 119.46,78.22 119.45,78.27 119.43,78.32 119.41,78.37 119.38,78.41 119.34,78.45 119.3,78.48 119.26,78.51 119.21,78.53 119.15,78.54 119.1,78.55 119.05,78.54 119,78.53 118.95,78.51 118.9,78.48 118.86,78.45 118.82,78.41 118.79,78.37 118.77,78.32 118.75,78.27 118.75,78.22 117.2,78.22 117.2,78.44 117.45,78.7 119.74,78.7
+1.0VA on TOP (solid shape): 164.75,68.26 165.63,68.26 165.71,68.18 165.71,67.01 165.96,66.76 166.35,66.76 166.42,66.68 166.42,66.66 166.58,66.36 166.93,66.34 166.94,66.34 167.44,66.34 167.45,66.34 167.9,66.34 168,66.25 168,65.62 167.87,65.49 167.84,65.49 167.56,65.45 167.4,65.21 167.4,65.17 166.42,65.17 166.09,65.49 164.06,65.49 163.93,65.62 163.93,68.06 164.17,68.3 164.71,68.3
+1.0VA on BOTTOM (solid shape): 192,57.23 192.13,57.23 192.2,57.17 192.2,56.78 191.63,56.78 191.63,56.22 192.2,56.22 192.2,55.97 191.65,55.97 191.65,55.41 192.2,55.41 192.2,55.13 192.2,55.13 192.2,54.33 192.06,54.19 191.78,54.19 191.76,54.2 191.48,54.31 191.21,54.19 190.67,54.19 190.48,54.38 190.48,56.98 190.73,57.24 192,57.24
+1.0VA on IN4 (solid shape): outline of 1357 points within 136.5,56.09 146.66,64.09
+1.0VA on TOP: 157.26,79.91 157.96,79.21 158.7,79.21 158.8,79.1 158.8,77.74 158.8,77.74 158.78,77.61 158.8,77.48 158.8,77.47 158.8,77.38 158.73,77.3 157.59,77.3 156.78,76.49 156.78,75.56 156.95,75.4 156.96,75.4 157.09,75.27 157.37,75.27 157.39,75.24 158.75,75.24 158.82,75.17 158.82,74.04 158.78,74 158.13,74 157.98,74.15 155.07,74.15 155.01,74.21 155.01,76.56 155.34,76.86 155.12,77.25 154.92,77.46 154.92,79.82 155,79.9 155,79.91
+1.0VA on IN2: 157.01,78.32 158.58,78.32 158.76,78.14 158.76,77.03 157.86,76.13 156.28,76.13 155.79,76.62 155.79,77.09
+1.0VA on VCC: 169.88,53.81 169.65,54.04 169.65,63.33 152.5,63.33 152.5,75.54 154.89,77.94 158.49,77.94 161.54,74.89 173.61,74.89 181.35,67.14 192.89,67.14 192.89,60.36 191.16,58.64 191.16,54.44 190.95,54.24 189.4,54.24 188.97,53.81
+1.0VAP on TOP (solid shape): 196.95,56.98 196.95,54.82 196.83,54.7 196.44,54.7 196.19,54.95 194.16,54.95 194.07,55.04 194.07,57.87 196.06,57.87
+1.0VAP on BOTTOM (solid shape): 197.21,56.73 200.13,56.73 200.23,56.63 200.23,53.91 200,53.68 197.46,53.68 196.19,54.95 192.46,54.95 192.33,55.08 192.33,55.18 192.33,55.18 192.33,55.54 191.83,55.54 191.8,55.57 191.8,55.84 192.33,55.84 192.33,56.34 191.8,56.34 191.8,56.64 192.33,56.64 192.33,57.15 192.41,57.24 193.4,57.24 194.03,57.87 196.06,57.87
+1.0VS_VCCIO on TOP (solid shape): 167.71,55.96 167.76,55.91 167.76,55.9 168.07,55.43 168.45,55.85 168.47,55.93 168.55,55.97 169.36,55.97 169.43,55.89 169.43,55.61 169.45,55.08 169.97,55.16 170.18,55.16 170.54,54.81 170.54,54.38 170.39,54.24 169.96,54.24 169.92,54.24 169.92,54.27 169.92,54.77 169.41,54.77 169.41,54.24 169.12,54.24 169.12,54.77 168.61,54.77 168.61,54.24 168.59,54.24 168.57,54.22 168.14,54.22 168.14,54.19 167.62,54.19 166.35,55.46 166.35,55.69 166.4,55.74 167.11,55.74 167.34,55.97 167.71,55.97
+1.0VS_VCCIO on TOP (solid shape): 137.38,58.77 137.38,58.33 137.39,58.33 137.39,58.22 137.38,58.2 137.32,57.82 137.65,57.62 137.69,57.6 137.7,57.56 137.7,56.79 137.64,56.73 136.89,56.73 136.89,56.78 136.86,56.78 136.86,56.96 136.47,57.35 136.46,57.36 136.36,57.56 136.16,57.66 136.09,57.71 136.09,57.81 136.11,57.84 136.13,57.88 136.17,57.92 136.22,57.88 136.91,57.98 136.25,58.2 136.17,58.15 136.08,58.2 135.49,58.19 135.74,57.64 135.81,57.59 135.81,57.49 135.79,57.16 136.05,56.95 136.07,56.95 136.09,56.94 136.26,56.76 136.26,56.08 135.98,56.08 135.33,55.43 134.2,55.43 134.09,55.54 134.09,55.79 134.27,55.97 134.54,55.97 134.62,56.04 134.7,56.04 134.7,56.12 134.72,56.14 134.72,57.08 134.79,57.14 134.79,57.47 134.72,57.54 134.72,57.54 134.72,58.12 134.6,58.25 133.96,58.25 133.83,58.38 133.83,58.89 133.96,59.01 137.06,59.01 137.14,59.01
+1.0VS_VCCIO on TOP (solid shape): outline of 84 points within 121.92,65.95 126.11,69.11
+1.0VS_VCCIO on BOTTOM (solid shape): 135.75,57.32 135.76,57.3 135.79,57.15 135.89,57.03 135.89,55.94 135.38,55.43 135.08,55.43 135.07,55.47 134.9,55.65 134.66,55.6 134.47,55.43 134.26,55.43 134.14,55.56 134.14,55.81 134.24,55.91 134.24,56.12 134.39,56.27 134.41,56.27 134.55,56.35 134.62,56.48 134.62,56.5 134.67,56.55 134.67,57.03 134.7,57.09 135.08,57.46 135.61,57.46
+1.0VS_VCCIO on IN1: 126.57,55.36 126.49,55.41 126.49,55.52 126.33,56.03 125.84,55.79 125.77,55.72 125.67,55.74 125.58,55.84 125.58,56.18 125.72,56.32 125.72,57.64 126.23,58.15 126.85,58.15 127.05,58.35 127.05,58.89 127.53,59.37 134.09,59.37 135.33,58.12 135.41,58.09 135.43,58.02 135.54,57.74 135.81,57.64 135.85,57.63 135.87,57.59 135.87,57.56 135.85,57.55 135.76,57.29 135.87,57.05 135.87,56.09 135.13,55.36 134.43,55.36 134.37,55.36 134.3,55.36 133.52,55.36 133.45,55.36 133.39,55.36 132.96,55.36 132.88,55.4 132.87,55.5 132.72,55.94 132.27,55.87 131.89,55.87 131.62,55.99 131.35,55.87 130.96,55.87 130.71,55.97 130.46,55.87 130.08,55.87 129.73,56.01 129.45,55.75 129.45,55.74 129.07,55.36 128.88,55.36 128.82,55.36 128.39,55.36 128.3,55.4 128.29,55.5 127.97,55.99 127.64,55.5 127.63,55.4 127.54,55.36 127.47,55.36 127.39,55.4 127.38,55.5 127.05,55.99 126.72,55.5 126.71,55.4 126.63,55.36
+1.0VS_VCCIO on VCC: 146.26,50.12 145.11,51.27 143.46,51.27 142.34,52.39 142.34,52.51 142.28,52.58 142.28,54.65 141.41,55.52 138.58,55.52 137.95,54.89 133.91,54.89 133.91,55.66 135.1,56.85 135.1,57.87 135.63,57.87 136.32,57.18 138.31,57.18 140.14,59.01 142.19,59.01 142.57,59.39 149.69,59.39 152.5,62.21 152.5,62.82 169.14,62.82 169.14,52.51 166.75,50.12
+1.0VS_VCCIOP on TOP (solid shape): 169.79,54.22 169.79,54.22 169.79,54.09 170.34,54.09 170.43,53.99 170.43,53.04 170.43,52.81 169.95,52.33 169.95,52.14 169.95,51.63 170.19,51.39 172.7,51.39 173.37,50.72 173.37,50.55 173.31,50.49 172.62,50.49 172.6,50.5 171.17,50.5 170.79,50.12 168.3,50.12 168.07,50.2 167.84,50.12 167.49,50.12 167.36,50.25 167.36,51.27 167.49,51.39 167.74,51.39 168.12,51.77 168.12,53.96 168.23,54.06 168.27,54.06 168.27,54.09 168.74,54.09 168.74,54.58 168.81,54.64 168.99,54.64 168.99,54.11 168.99,54.09 169.54,54.09 169.54,54.11 169.54,54.64 169.79,54.64
+1.2V_DDR on TOP (solid shape): 161.77,24.34 161.77,24.22 162.41,23.58 162.41,22.01 161.91,22.01 161.91,21.27 162.41,21.27 162.41,20.82 161.92,20.82 161.92,20.05 162.41,20.05 162.41,18.75 162.15,18.5 160.88,18.5 160.63,18.75 160.63,24.09 161.01,24.47 161.65,24.47
+1.2V_DDR on TOP (solid shape): 164.31,48.98 164.31,47.96 164.57,47.71 165.6,47.71 165.85,47.46 165.87,47.46 165.92,47.41 166.22,47.41 166.35,47.28 166.35,46.31 166.22,46.19 164.57,46.19 164.19,46.57 162.66,46.57 162.54,46.69 162.54,48.14 162.54,48.98 162.66,49.11 164.19,49.11
+1.2V_DDR on TOP (solid shape): outline of 92 points within 96.88,25.74 102.46,30.06
+1.2V_DDR on TOP (solid shape): outline of 92 points within 143.36,25.74 151.34,30.18
+1.2V_DDR on TOP (solid shape): outline of 471 points within 152.38,25.99 158.34,38.82
+1.2V_DDR on TOP (solid shape): outline of 739 points within 122.25,46.95 139.68,53.43
+1.2V_DDR on TOP (solid shape): outline of 1634 points within 106.27,22.18 149.2,39.2
+1.2V_DDR on BOTTOM (solid shape): outline of 203 points within 147.17,31.71 150.72,34.63
+1.2V_DDR on BOTTOM (solid shape): outline of 246 points within 121.77,31.26 133.96,35.07
+1.2V_DDR on BOTTOM (solid shape): outline of 392 points within 106.4,31.58 111.61,37.17
+1.2V_DDR on BOTTOM (solid shape): outline of 840 points within 154.66,18.75 162.92,34.63
+1.2V_DDR on IN1 (solid shape): outline of 1109 points within 130.91,21.61 144.12,31.45
+1.2V_DDR on IN1 (solid shape): outline of 1644 points within 98.02,23.58 111.86,33.61
+1.2V_DDR on IN2 (solid shape): 154.53,29.74 154.53,29.23 154.79,28.98 155.11,28.98 155.23,28.86 155.23,28.59 155.04,28.41 154.71,28.41 154.63,28.45 154.62,28.55 154.11,29 154.29,28.35 154.33,28.33 154.34,28.29 154.34,28.16 154.31,28.12 154.31,27.77 154.34,27.74 154.34,27.64 154.53,27.45 154.53,26.95 154.41,26.82 154.03,26.82 153.94,26.91 153.94,27.82 153.9,27.86 153.9,28.09 153.33,28.66 153.33,30.5 153.39,30.57 153.71,30.57
+1.2V_DDR on IN2 (solid shape): 144.5,32.34 144.5,30.82 144.25,30.57 144.25,30.18 144.28,30.02 144.37,29.89 144.37,29.68 144.25,29.55 144,29.55 143.92,29.63 142.77,29.63 142.22,30.18 142.22,30.83 142.24,30.85 142.31,30.87 142.63,30.75 142.88,30.85 142.95,30.88 143.02,30.85 143.3,30.75 143.55,30.88 143.63,30.92 143.71,30.88 144.34,31.12 143.7,31.34 143.63,31.3 143.55,31.33 143.5,31.38 143.45,31.41 143.4,31.5 143.63,31.9 143.4,32.3 143.45,32.39 143.61,32.58 143.61,32.84 143.62,32.93 143.7,32.98 143.87,32.98
+1.2V_DDR on IN2 (solid shape): 141.54,33.53 141.57,33.44 141.51,33.36 141.43,32.77 142,32.94 142.02,32.98 142.85,32.98 142.94,32.93 142.95,32.84 142.94,32.58 143.1,32.39 143.16,32.3 143.1,32.21 143.06,32.19 143.02,32.15 142.95,32.12 142.88,32.15 142.34,32.12 142.45,31.59 142.51,31.5 142.45,31.41 142.41,31.39 142.38,31.35 142.31,31.33 142.23,31.35 142.22,31.37 142.22,31.58 141.83,31.96 141.03,31.96 141.02,32 140.89,32.19 140.67,32.26 140.64,32.26 140.5,32.41 140.47,32.5 140.54,32.58 140.77,32.95 140.45,33.27 140.37,33.33 140.39,33.44 140.56,33.61 141.45,33.61
+1.2V_DDR on IN2 (solid shape): 121.01,29.68 120.98,29.65 120.98,29.3 121.01,29.27 121.01,29.09 120.95,29 120.85,29.01 120.32,28.75 120.76,28.36 120.79,28.37 120.85,28.31 120.82,28.28 120.82,28.15 120.78,28.11 120.78,27.79 120.82,27.75 120.82,27.64 120.94,27.52 121.26,27.52 121.51,27.26 121.51,27.01 121.01,26.5 121.01,26.47 121,26.46 120.96,26.3 121,26.14 121.01,26.13 121.01,25.89 120.95,25.8 120.85,25.81 120.36,25.68 120.49,25.19 120.55,25.1 120.49,25.01 120.36,24.52 120.85,24.4 120.95,24.4 121.01,24.31 121.01,24.22 121.14,24.08 121.14,23.92 121.1,23.91 120.94,23.32 121.53,23.47 121.61,23.54 121.7,23.52 121.77,23.45 121.77,22.95 121.64,22.82 121.05,22.82 120.53,23.35 120.5,23.42 120.53,23.49 120.52,24.01 120,23.98 119.93,23.94 119.86,23.97 119.36,24.47 119.36,25.9 119.37,25.93 119.4,25.95 119.52,25.98 119.62,26.05 119.69,26.08 119.76,26.05 120.37,26.3 119.76,26.55 119.69,26.52 119.62,26.55 119.44,26.65 119.24,26.63 119.15,26.64 119.1,26.73 119.1,27.26 119.61,27.77 119.61,27.88 119.65,27.92 119.65,29.62 119.83,29.8 120.88,29.8
+1.2V_DDR on IN2 (solid shape): outline of 852 points within 97.51,27.39 105.39,34.5
+1.2V_DDR on IN4 (solid shape): outline of 2689 points within 138.28,21.04 162.28,29.55
+1.2V_DDR on IN2: outline of 681 points within 104.75,18.12 162.78,58.25
+1.2V_DDR on IN3: 102.46,37.55 99.28,34.37 99.21,34.34 99.13,34.37 98.54,34.29 98.86,33.78 98.89,33.77 98.91,33.73 98.91,31.07 98.65,30.82 98.15,30.82 97.89,31.07 97.89,35.01 100.94,38.06 100.94,41.36 100.43,41.87 100.43,47.08 100.81,47.46 102.08,47.46 102.46,47.08
+1.2V_DDRP on TOP (solid shape): 168.38,30.06 168.38,28.38 166.14,26.15 165.67,26.15 165.26,25.73 164.74,25.73 164.06,25.05 164.06,24.25 164.48,23.83 165.51,23.83 165.57,23.78 166.6,23.78 166.66,23.83 170.66,23.83 171.3,23.2 171.3,21.17 170.66,20.53 168.76,20.53 167.74,19.52 162.64,19.52 162.61,19.54 162.61,23.66 162.78,23.82 162.78,25.22 163.83,26.27 163.84,26.27 164.55,26.98 165.38,26.98 167.49,29.09 167.49,29.93 167.67,30.11 168.33,30.11
+1.8VA on TOP (solid shape): 32.49,43.14 32.49,42.63 32.36,42.5 31.34,42.5 31.22,42.38 29.54,42.38 29.39,42.53 29.39,42.97 31.01,42.97 31.31,43.27 32.36,43.27
+1.8VA on TOP (solid shape): 168.76,70.57 168.76,69.55 168.63,69.43 168.57,69.43 168.51,69.45 168.44,69.45 168.3,69.48 168.16,69.43 167.69,69.43 167.49,69.63 167.49,70.57 167.62,70.7 168.63,70.7
+1.8VAP on TOP (solid shape): 168.89,76.54 168.89,74.51 168.69,74.23 168.79,73.91 168.89,73.82 168.89,73.29 168.74,73.15 168.67,72.71 169.08,72.51 169.1,72.51 169.27,72.35 169.27,71.33 168.78,70.85 168.34,70.85 168.34,71.41 167.91,71.41 167.91,70.85 167.46,70.85 167.23,71.08 167.23,76.48 167.47,76.71 168.71,76.71
+1.8VS_AUDIO on TOP (solid shape): 30.2,39.75 31.18,39.75 31.22,39.71 31.22,38.71 31.19,38.64 31.12,38.61 30.88,38.5 30.79,38.25 30.77,38.17 30.69,38.13 29.03,38.13 28.93,38.24 28.93,38.89 28.83,38.98 28.3,38.98 28.16,39.13 28.16,39.65 28.35,39.84 30.11,39.84
+1.8VU on TOP (solid shape): 161.01,42.5 161.01,41.11 160.76,40.85 160.19,40.85 160.12,40.92 160.12,42.5 160.25,42.63 160.88,42.63
+1.8VU on TOP (solid shape): 161.01,28.41 162.03,28.41 162.15,28.28 162.15,27.64 162.03,27.52 160.25,27.52 159.61,26.88 159.61,26.25 159.87,25.99 159.87,25.23 159.68,25.04 159.68,25.04 159.49,24.85 159.11,24.85 158.98,24.98 158.98,25.74 158.79,25.92 158.79,25.94 158.74,26.07 158.63,26.15 158.6,26.16 158.6,26.34 158.77,26.52 158.77,26.55 158.85,26.63 158.85,26.76 158.6,27.01 158.6,27.14 158.77,27.32 158.77,27.4 158.79,27.46 159.11,27.77 159.36,27.77 160,28.41 160,28.53 160.12,28.66 160.76,28.66
+1.8VU on BOTTOM: outline of 1117 points within 98.02,24.72 160.93,35.53
+1.8VUP on TOP (solid shape): 163.93,44.92 163.93,43.01 163.81,42.88 163.04,42.88 162.79,42.63 162.79,42.22 162.75,42.22 162.47,41.87 162.75,41.52 162.79,41.51 162.79,41.11 162.41,40.73 161.77,40.73 161.19,41.31 161.19,41.78 161.72,41.78 161.72,42.21 161.19,42.21 161.19,42.68 161.52,43.01 161.52,43.89 161.52,43.9 161.54,44.03 161.52,44.16 161.52,44.17 161.52,44.79 161.76,45.03 161.83,45.03 161.89,45.04 163.81,45.04
+3.3VDX_SSD on TOP (solid shape): 176.89,31.84 176.89,30.35 176.73,30.2 176.45,30.2 176.38,30.12 176.38,28.72 176.39,28.72 176.51,28.61 176.81,28.61 177.14,28.28 177.14,23.2 177.01,23.07 175.21,23.07 174.85,23.43 174.85,26.31 174.89,26.35 174.91,26.35 175.18,26.63 174.9,26.91 174.87,26.92 174.85,26.96 174.85,28.81 175.02,28.97 175.02,29.91 174.85,30.08 174.85,31.96 174.98,32.09 176.63,32.09
+3.3VDX_SSD on TOP (solid shape): 178.03,40.28 178.03,39.33 178.28,39.07 178.28,38.57 178.1,38.26 178.28,37.95 178.28,37.8 178.03,37.55 178.03,37.02 178.03,37 178.03,36.28 177.94,36.14 177.93,35.97 177.93,35.95 177.89,35.9 177.25,35.9 176.95,36.2 175.87,36.2 175.74,36.32 175.74,36.66 175.87,36.79 176.51,36.79 176.63,36.92 176.63,37.77 176.85,37.99 176.96,38.23 176.89,38.48 176.89,38.49 176.89,38.57 176.63,38.82 176,38.82 175.74,39.07 175.74,41.74 175.87,41.87 176.44,41.87
+3.3VDX_SSD on BOTTOM (solid shape): outline of 146 points within 174.5,23.33 177.78,27.7
+3.3VDX_SSD on BOTTOM (solid shape): outline of 170 points within 173.08,35.9 178.16,41.7
+3.3VDX_SSD on IN2: 176.25,23.2 175.83,23.62 175.83,36.83 176.47,37.48 176.61,37.48 177.06,37.93 178.33,37.93 178.34,37.93 178.46,37.91 178.59,37.93 178.59,37.93 178.92,37.93 179.17,37.68 179.17,28.86 179.35,28.69 179.35,25.15 177.39,23.2
+3V_LDO on BOTTOM (solid shape): 63.32,67.55 63.32,67.23 63.2,67.11 63.04,67.11 63,67.07 62.91,67.07 62.69,66.85 62.69,66.73 62.52,66.57 62.24,66.53 62.08,66.3 60.68,66.3 60.58,66.4 60.58,66.57 60.78,66.77 61.21,66.77 61.76,66.93 62.04,67.43 62.04,67.52 62.04,67.6 62.03,67.65 62.02,67.7 62.16,67.85 63.02,67.85
+3V_PCH on TOP (solid shape): 182.35,28.36 182.35,26.12 182.23,26.01 181.25,26.01 181.19,26.07 181.19,26.34 181.33,26.48 181.33,27.26 181.2,27.39 180.57,27.39 180.44,27.52 180.44,28.34 180.58,28.48 182.22,28.48
+3V_PCH on TOP (solid shape): 180.26,45.73 180.26,45.53 180.27,45.53 180.27,45.34 180.27,45.34 180.27,43.98 180.06,43.77 179.05,43.77 178.66,44.15 178.17,44.15 177.98,44.34 176.76,44.34 176.57,44.15 175.87,44.15 175.27,43.56 173.93,43.56 173.85,43.65 173.85,43.91 173.84,43.92 173.84,44.03 175.11,45.3 177.14,45.3 177.9,46.06 179.94,46.06
+3V_PCH on IN1 (solid shape): 157.58,50.68 157.58,49.17 157.54,49.09 157.45,49.07 156.98,48.74 157.45,48.4 157.54,48.38 157.58,48.3 157.58,48.29 157.68,48.19 157.68,47.53 157.56,47.31 157.6,47.07 157.51,46.97 156.13,46.97 155.68,47.43 155.68,50.35 156.19,50.86 157.4,50.86
+3V_PCH on IN2 (solid shape): outline of 2130 points within 137.52,53.93 152.88,64.73
+3V_PCH on IN3 (solid shape): 157.8,67.47 157.8,66.58 157.22,66.58 156.82,66.18 156.82,64.19 157.66,63.35 157.66,62.96 157.62,62.91 157.33,62.91 157.32,62.92 157.18,62.95 157.03,62.92 157.02,62.91 156.66,62.91 155.21,64.37 154.63,64.37 154.35,64.65 154.35,65.21 156.73,67.59 157.68,67.59
+3V_PCH on IN3 (solid shape): outline of 535 points within 159.11,40.84 174.6,48.47
+3V_PCH on IN4 (solid shape): outline of 353 points within 156.44,40.98 160.76,50.78
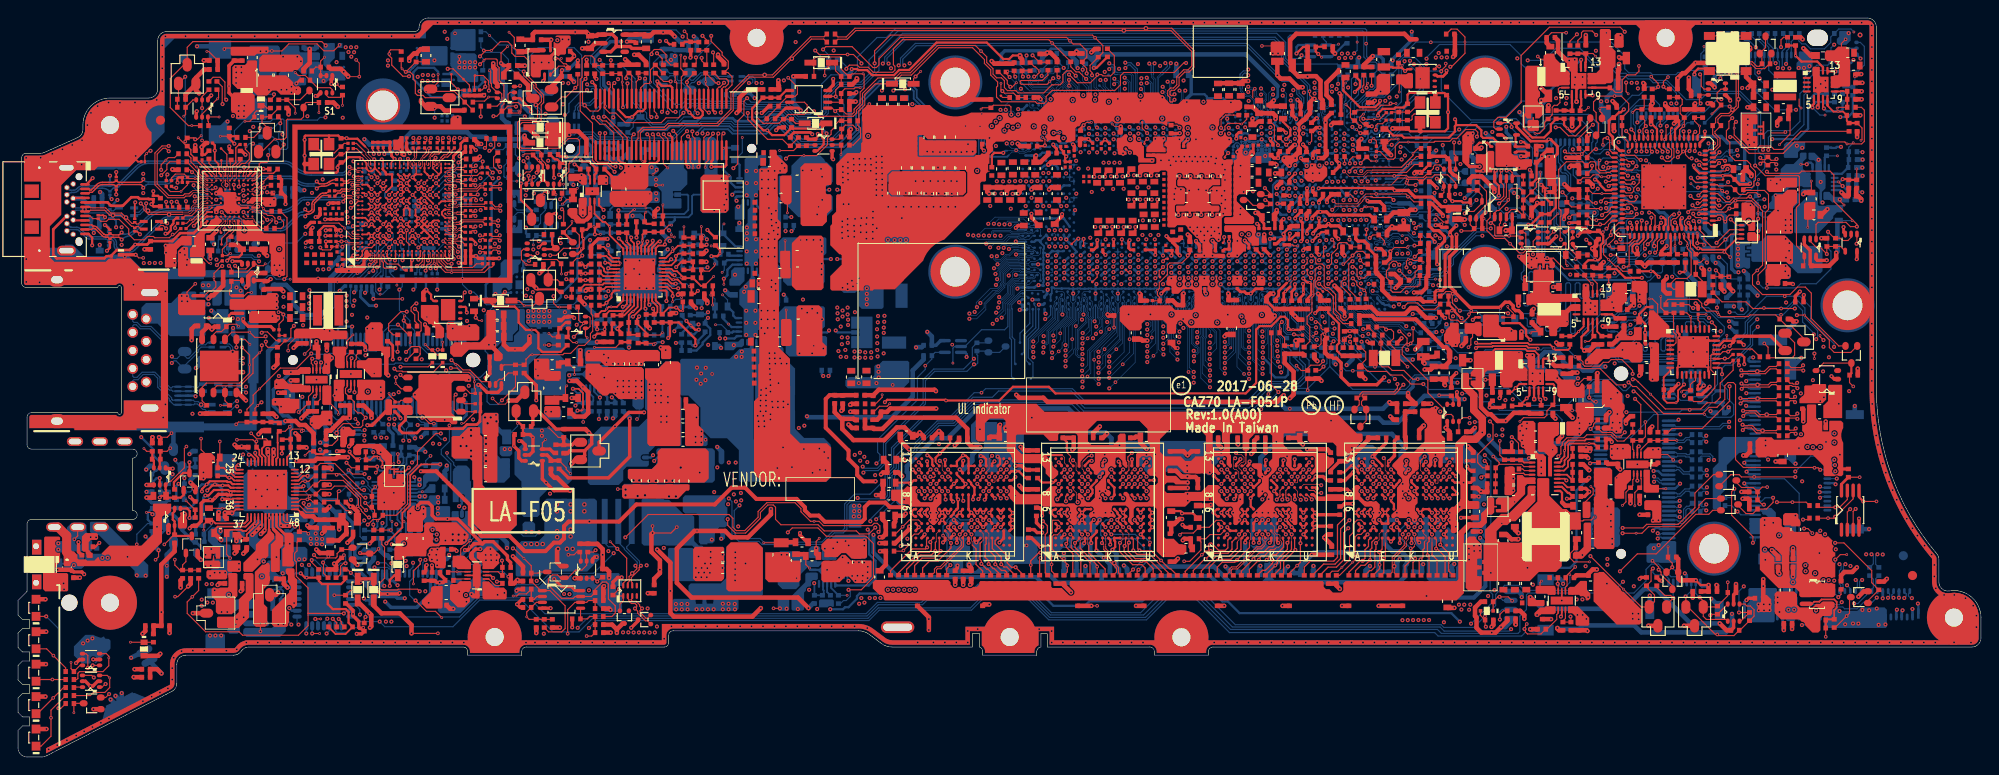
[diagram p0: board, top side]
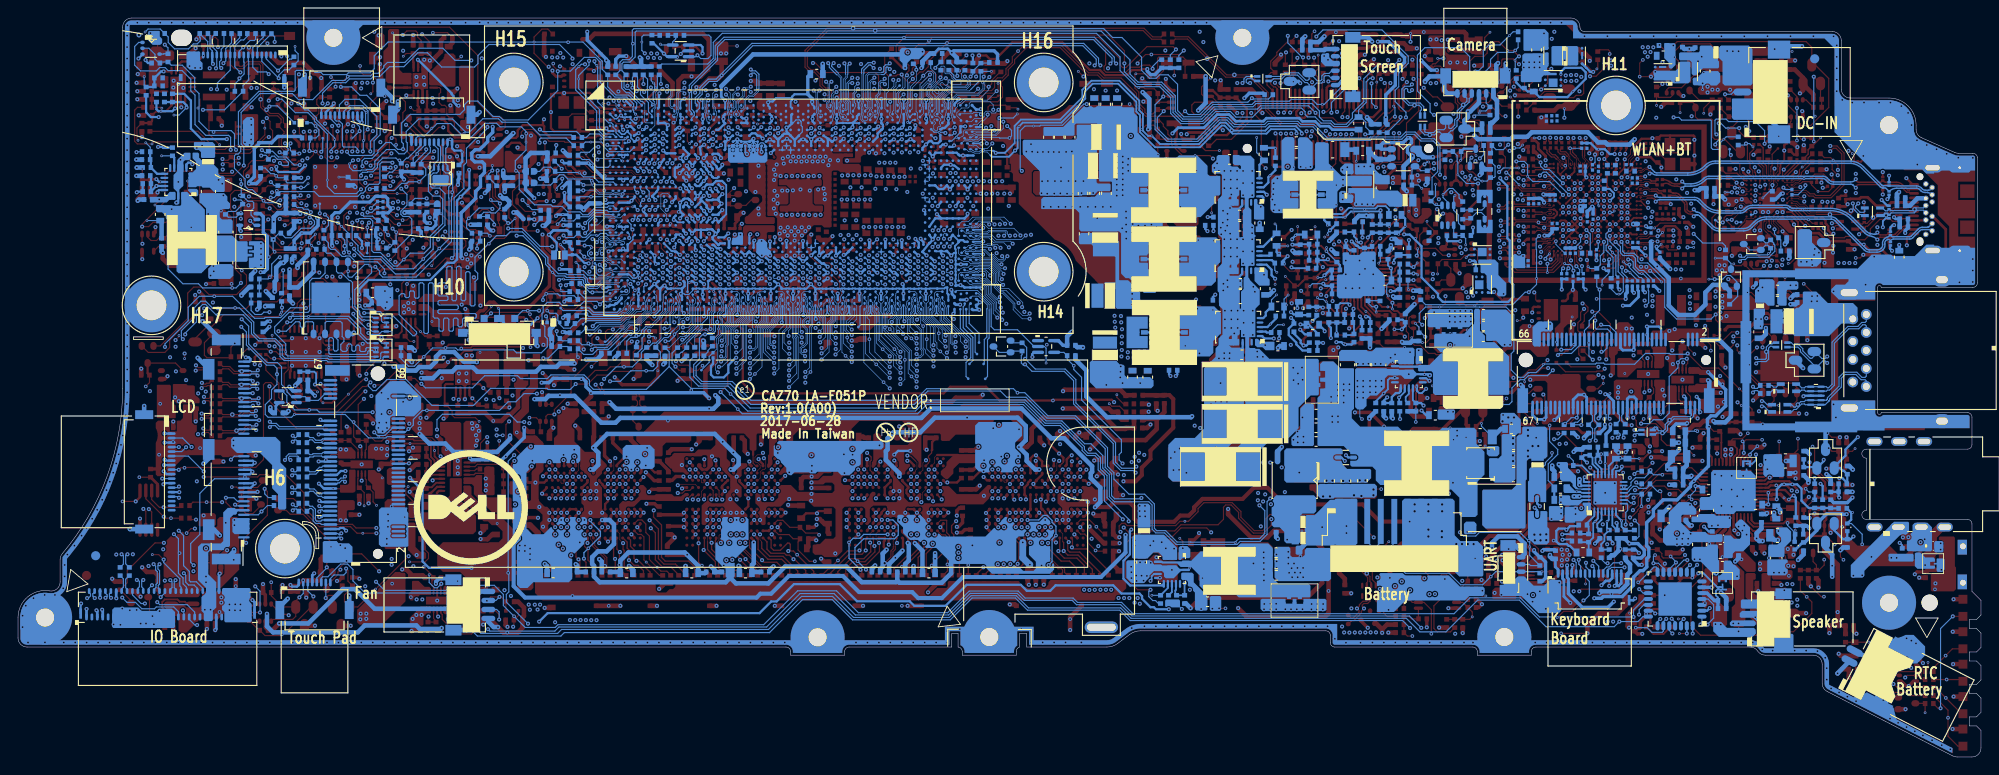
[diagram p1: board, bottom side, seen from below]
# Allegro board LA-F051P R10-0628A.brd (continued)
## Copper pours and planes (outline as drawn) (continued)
+3V_PCH on IN1: 139.12,55.97 139.11,55.97 139.01,56.01 138.89,56.01 138.87,56.01 138.66,56.22 138.66,57.05 138.7,57.13 138.79,57.15 139.27,57.48 138.79,57.82 138.7,57.83 138.66,57.91 138.66,58.25 138.91,58.51 139.42,58.51 139.8,58.12 139.95,58.12 140.39,58.56 142.24,58.56 142.67,58.12 142.67,58.07 142.9,57.74 143.29,57.83 143.36,57.87 143.44,57.83 143.82,57.74 144.06,58.04 144.06,58.09 146.44,58.09 147.04,57.49 147.04,56.6 146.79,56.35 145.45,56.35 145.37,56.38 145.35,56.47 144.89,56.88 144.78,56.27 144.81,56.19 144.78,56.12 144.63,55.97 144.59,55.99 144.34,56.08 144.11,55.97 143.67,55.97 143.66,55.97 143.51,56 143.37,55.97 143.36,55.97 142.75,55.97 142.74,55.97 142.6,56 142.45,55.97 142.44,55.97 142.1,55.97 142.02,56.01 142.01,56.11 141.68,56.61 141.36,56.11 141.35,56.01 141.27,55.97 141.19,55.97 141.1,56.02 141.1,56.12 140.79,56.66 140.49,56.12 140.49,56.02 140.4,55.97 140.22,55.97 140.12,56.02 140.13,56.13 139.85,56.7 139.57,56.13 139.58,56.02 139.49,55.97
+3V_PCH on IN3: 181.64,46.39 184.32,43.72 184.32,37.75 182.09,35.52 180.82,35.52 180.19,34.88 179.55,34.88 179.3,34.63 179.3,33.99 179.68,33.61 182.22,33.61 182.35,33.49 182.35,26.12 182.22,25.99 178.54,25.99 176.89,27.64 176.89,32.72 177.78,33.61 177.78,33.81 177.82,33.89 177.92,33.9 178.44,34.21 177.92,34.53 177.82,34.53 177.78,34.62 177.78,35.01 179.3,36.53 179.93,36.53 182.73,39.33 182.73,43.22 181.01,44.93 179.77,44.93 179.21,45.5 179.21,46.19 179.42,46.39
+3V_PCH on IN4: 148.06,76.92 147.8,77.17 147.8,77.27 147.83,77.31 147.88,77.31 148.32,77.34 148.39,77.78 148.39,77.89 148.48,77.94 149.87,77.94 149.94,77.9 149.97,77.82 150.32,77.42 150.68,77.82 150.7,77.9 150.78,77.94 152.27,77.94 152.51,77.7 153,77.7 153.01,77.68 153.01,77.17 152.76,76.92 148.07,76.92
+3V_PCH_DSW on IN2: outline of 227 points within 141.96,51.27 150.6,58.25
+3V_TBT on BOTTOM (solid shape): 25.22,49.66 25.22,47.57 25.11,47.46 24.24,47.46 24.23,47.47 24.23,47.6 24.2,47.75 24.12,47.87 24.12,48.49 24.18,48.69 24.12,48.88 24.12,48.91 23.96,49.07 23.96,49.71 24.02,49.76 25.12,49.76
+3V_TBT on TOP: 35.33,56.28 35.38,56.33 36.36,56.33 36.37,56.33 36.48,56.33 36.82,56.66 37.5,56.66 37.51,56.67 38.02,56.67 38.05,56.69 38.15,56.69 38.18,56.73 38.25,56.73 38.33,56.65 38.33,56.56 38.14,56.36 38.13,56.36 38.03,56.29 37.98,56.18 37.98,56.16 37.87,56.05 37.76,56.05 37.59,55.88 37.17,55.88 36.86,55.57 35.67,55.57 35.48,55.38 31.79,55.38 31.7,55.47 31.7,56.19 31.79,56.28 34.72,56.28 34.73,56.28
+3V_TBT on IN1: 32.33,56.7 32.33,58.8 32.92,59.39 33.85,59.39 34.07,59.31 34.3,59.39 36.21,59.39 36.28,59.36 36.31,59.3 36.44,59.05 36.7,58.96 36.78,58.94 36.81,58.87 36.86,58.72 36.97,58.61 37.01,58.53 36.98,58.45 37.25,57.83 37.42,58.49 37.38,58.56 37.41,58.65 37.48,59.07 37.09,59.25 37.04,59.26 37.02,59.39 38.17,59.39 38.25,59.35 38.26,59.25 38.4,58.83 38.84,58.87 38.91,58.89 38.98,58.87 39.43,58.82 39.56,59.25 39.58,59.35 39.66,59.39 40.64,59.39 40.77,59.27 40.77,58.26 40.72,58.18 40.63,58.16 40.44,58.17 40.28,58.07 40.21,58.04 40.1,58.15 40.13,58.22 39.88,58.82 39.63,58.22 39.66,58.15 39.63,58.08 39.63,58.07 39.56,58.04 39.48,58.07 38.98,58.07 38.98,57.57 39.01,57.5 38.98,57.42 38.98,56.92 39.49,56.92 39.56,56.95 39.89,56.81 40.14,56.91 40.21,56.94 40.29,56.91 40.33,56.88 40.37,56.85 40.37,56.32 40.19,56.14 32.89,56.14
+3V_TBT on IN4: outline of 90 points within 24.09,47 53.68,56.72
+3V_TBT_PWR on TOP (solid shape): 46.67,50.05 46.67,48.19 47.28,47.58 47.28,46.62 47.12,46.45 46.39,46.45 46.3,46.54 46.3,47.57 45.85,48.03 45.52,48.03 45.52,48.03 45.39,48.29 45.11,48.37 44.69,48.79 44.69,50.08 44.77,50.16 46.56,50.16
+3V_TBT_S0 on BOTTOM (solid shape): 24.62,52.93 24.62,52.26 25.07,51.81 25.07,50.49 25.02,50.43 23.99,50.43 23.64,50.08 22.98,50.08 22.9,50.16 22.9,52.79 23.12,53.02 24.54,53.02
+3V_TBT_S0 on IN4: outline of 239 points within 23.83,51.3 45.25,61.65
+3V_VC on BOTTOM (solid shape): outline of 334 points within 55.08,16.09 67.03,20.41
+3VA_TBT on BOTTOM: 37.92,58.77 39.94,58.77 40.13,58.58 40.13,58.31 39.98,58.16 39.12,58.16 38.94,57.98 38.94,56.99 38.81,56.87 36.46,56.87 36.32,57.01 36.32,57.88 35.88,57.88 35.57,58.19 35.57,58.57 35.64,58.63 37.07,58.63 37.19,58.75 37.9,58.75
+3VA_TBT_LC on TOP (solid shape): 51.94,73.64 51.94,73.36 51.93,73.32 51.92,73.29 51.8,73.17 50.51,73.17 50.51,73.17 49.38,73.17 49.31,73.24 49.31,73.59 49.35,73.62 51.41,73.62 51.48,73.69 51.89,73.69
+3VALW on TOP (solid shape): 182.35,34.25 182.35,33.23 182.22,33.11 180.44,33.11 180.38,33.17 180.38,33.93 180.82,34.38 182.22,34.38
+3VALW on TOP (solid shape): 174.35,15.45 174.35,14.69 174.22,14.56 172.95,14.56 172.82,14.69 172.82,15.58 172.45,15.95 172.06,15.95 172,16.01 172,16.65 172.07,16.72 173.08,16.72
+3VALW on TOP (solid shape): 36.25,41.79 36.25,41.16 36.17,41.08 36.17,41 36.14,40.97 36.14,40.31 36.17,40.28 36.17,39.58 36.04,39.46 35.15,39.46 35.03,39.58 35.03,41.77 35.13,41.87 36.17,41.87
+3VALW on TOP (solid shape): 170.6,16.66 170.6,16.01 170.43,15.83 169.01,15.83 168.86,15.68 168.73,15.68 168.73,15.58 168.38,15.58 168.25,15.71 168.25,15.96 168.89,16.6 169.39,16.6 169.52,16.72 170.54,16.72
+3VALW on TOP (solid shape): 170.66,66.63 170.66,62.57 170.54,62.44 170.28,62.44 170.28,62.45 169.85,62.45 169.7,62.6 169.7,62.91 170.23,62.91 170.23,63.35 169.7,63.35 169.7,64.04 169.39,64.35 169.39,66.35 169.41,66.37 169.41,66.5 169.44,66.55 169.71,66.82 170.47,66.82
+3VALW on TOP (solid shape): 174.2,34.53 174.28,34.5 174.36,34.5 174.44,34.51 174.52,34.53 174.57,34.53 174.73,34.38 174.73,33.99 174.47,33.74 173.89,33.74 173.79,33.74 173.79,33.77 173.18,33.77 173.08,33.87 173.08,34.5 173.1,34.53
+3VALW on TOP (solid shape): 200.64,41.31 200.64,39.66 200.23,39.25 199.5,39.25 198.45,39.25 197.71,39.25 197.66,39.3 197.66,39.73 197.94,40.01 197.95,40.02 198.07,40.1 198.15,40.22 198.16,40.23 198.2,40.27 198.2,41.12 198.31,41.23 198.98,41.23 199.14,41.39 200.56,41.39
+3VALW on TOP (solid shape): 178.98,34.46 178.98,34.07 178.98,34.07 178.98,33.17 178.92,33.11 178.28,33.11 178.16,32.98 176.89,32.98 176.63,33.23 176.63,34.51 176.67,34.59 176.76,34.61 176.97,34.63 177.13,34.76 178.68,34.76
+3VALW on TOP (solid shape): 34.09,44.78 34.27,44.74 34.45,44.78 34.46,44.79 34.59,44.79 34.84,44.55 34.89,44.55 35.03,44.41 35.03,44.15 34.65,43.77 34.65,42.63 34.52,42.5 33.88,42.5 33.76,42.63 33.76,43.27 33.88,43.39 33.88,43.52 33.99,43.77 33.88,44.02 33.88,44.66 34.01,44.79 34.07,44.79
+3VALW on TOP (solid shape): 178.49,48.06 178.49,46.87 178.6,46.76 178.72,46.76 178.74,46.75 179,46.7 179.23,46.86 179.29,46.92 179.29,47.63 179.31,47.65 179.31,47.66 179.32,47.67 180.09,47.67 180.15,47.61 180.15,46.28 180.1,46.23 177.74,46.23 177.03,45.52 176.38,45.52 176.33,45.58 176.33,46.05 176.38,46.1 176.86,46.1 177.23,46.47 177.23,46.72 177.91,47.39 177.91,48.04 178.01,48.14 178.41,48.14
+3VALW on TOP (solid shape): 40.52,41.87 40.54,41.85 40.58,41.81 40.63,41.78 40.66,41.76 40.74,41.68 40.74,39.91 40.41,39.58 37.62,39.58 37.54,39.66 37.54,40.18 37.56,40.19 37.6,40.23 37.64,40.27 37.65,40.3 37.69,40.34 37.69,40.57 38.46,40.57 38.46,40.52 38.46,40.47 38.48,40.42 38.5,40.37 38.53,40.32 38.57,40.29 38.61,40.25 38.66,40.23 38.71,40.21 38.76,40.19 38.81,40.19 38.86,40.19 38.92,40.21 38.97,40.23 39.01,40.25 39.05,40.29 39.09,40.32 39.12,40.37 39.14,40.42 39.16,40.47 39.17,40.52 39.17,40.57 39.16,40.63 39.14,40.68 39.12,40.73 39.09,40.77 39.05,40.81 39.01,40.84 38.97,40.87 38.92,40.89 38.86,40.9 38.81,40.9 38.76,40.9 38.71,40.89 38.66,40.87 38.61,40.84 38.57,40.81 38.53,40.77 38.5,40.73 38.48,40.68 38.46,40.63 38.46,40.57 37.69,40.57 37.69,40.98 37.62,41.06 37.62,41.79 37.69,41.87
+3VALW on TOP (solid shape): 61.32,79.97 61.32,79.08 60.96,78.72 60.88,78.72 60.88,78.65 60.81,78.57 60.81,78.06 60.68,77.94 60.17,77.94 60.02,77.79 59.95,77.76 59.88,77.78 59.35,77.7 59.51,77.19 59.54,77.17 59.54,76.54 59.28,76.29 58.14,76.29 58.01,76.16 58.01,75.52 57.89,75.4 57.11,75.4 56.88,75.63 56.88,77.82 57,77.94 59.03,77.94 59.15,78.05 59.16,78.06 59.27,78.13 59.34,78.24 59.34,78.25 59.41,78.32 59.41,79.3 59.44,79.33 59.46,79.35 59.5,79.37 59.54,79.35 60.18,79.43 59.7,79.86 59.67,79.85 59.6,79.91 59.77,80.07 61.22,80.07
+3VALW on BOTTOM (solid shape): 203.36,80.48 203.36,79.51 202.88,79.02 202.04,79.02 201.81,79.24 201.81,79.68 202.08,79.95 202.08,80.52 202.13,80.58 203.26,80.58
+3VALW on BOTTOM (solid shape): 75.19,17 75.95,17 75.95,17.55 76.38,17.55 76.38,17.02 77.16,17.02 77.16,17.55 79.79,17.55 79.95,17.4 79.95,17.14 79.95,17.14 79.95,16.43 79.71,16.19 73.17,16.19 73.17,16.19 72.77,16.19 72.62,16.34 72.62,17.39 72.78,17.55 75.19,17.55
+3VALW on BOTTOM (solid shape): 28.55,21.68 28.55,20.53 29.19,19.9 29.19,19.77 29.06,19.64 28.46,19.64 26.92,19.64 26.77,19.8 26.77,20.79 27.31,21.32 27.32,21.32 27.53,21.43 27.64,21.64 27.64,21.65 27.79,21.8 28.42,21.8
+3VALW on IN2 (solid shape): outline of 199 points within 171.3,33.74 177.9,58.27
+3VALW on TOP: 48.46,48.41 46.9,48.41 46.82,48.49 46.82,50.78 47,50.96 48.6,50.96 48.68,50.89 48.68,49.54 48.77,49.45 49.25,49.45 49.37,49.34 49.37,48.73 49.45,48.64 49.94,48.64 50.1,48.48 50.1,48.26 49.91,48.07 48.79,48.07 48.46,48.41
+3VALW on TOP: 26.28,70.21 26.39,70.1 26.39,69.36 26.23,69.2 23.01,69.2 22.57,69.64 22.01,69.64 21.78,69.87 21.78,70.37 21.91,70.49 22.81,70.49 23.09,70.21
+3VALW on IN1: 52.43,77.56 45.95,77.56 44.68,76.29 44.65,76.29 44.59,76.22 42.87,76.22 42.81,76.29 41.5,76.29 41.38,76.41 40.84,76.41 40.66,76.6 40.66,78.36 40.89,78.59 45.55,78.59 45.78,78.83 46.4,78.83 46.72,78.5 54.06,78.5 54.12,78.57 55,78.57 55.06,78.5 55.89,78.5 56.09,78.56 56.24,78.72 56.24,78.73 56.33,78.83 59.41,78.83 59.77,79.19 59.8,79.18 60.09,79.28 60.2,79.58 60.19,79.61 60.53,79.94 61.34,79.94 61.44,79.84 61.44,78 61.36,77.78 61.43,77.55 61.44,77.53 61.44,77.43 60.55,76.54 60.52,76.54 60.37,76.58 60.21,76.54 60.2,76.54 56.11,76.54 55.35,77.3 52.83,77.3 52.74,77.35 52.64,77.36 52.62,77.37
+3VALW on IN2: 31.34,48.6 31.34,58.25 30.33,59.27 30.33,60.34 30.35,60.43 30.35,60.51 30.35,60.56 30.33,60.62 30.33,61.15 30.33,61.19 30.33,62.72 29.01,64.04 29.01,64.05 28.91,64.16 28.91,65.88 26.86,67.93 25.59,67.93 25.24,68.28 25.24,69.82 25.71,70.29 28.61,70.29 31.28,67.62 31.28,66.77 31.32,66.76 31.32,65.48 32.7,64.09 32.7,61.49 32.36,61.15 32.36,59.75 33.34,58.76 33.34,57.09 32.75,56.49 32.75,50.21 32.78,50.2 32.81,50.18 34.27,48.72 34.29,48.61 34.2,48.55 33.93,47.94 34.54,48.2 34.61,48.3 34.72,48.28 35.01,47.99 35.02,47.95 35.01,47.92 34.91,47.65 35.04,47.39 35.13,47.34 35.22,47.32 35.24,47.32 35.28,47.27 35.28,44.41 34.9,44.03 34.62,44.03 33.5,45.14 33.5,46.31 32.82,46.99 32.82,47.12 31.77,48.17
+3VALW on IN3: outline of 90 points within 27,39.46 40.87,53.3
+3VALW on VCC: 108.09,12.57 108.03,12.68 107.95,12.79 107.95,14.97 104.61,14.97 104.61,13.47 96.99,13.47 96.76,13.51 96.55,13.62 95.22,14.62 94.29,15.1 93.26,15.27 72.7,15.27 72.17,15.19 71.69,14.96 66.65,20 66.65,20.89 51.64,35.9 47.83,35.9 44.78,38.95 40.72,38.95 39.85,39.81 39.85,46.21 42.12,48.47 51.69,48.47 52.57,47.58 68.96,47.58 69.72,46.82 88.07,46.82 89,47.76 89,51.14 96.6,51.14 96.6,36.2 98.02,34.78 98.02,33.89 99.16,32.75 99.16,24.49 103.25,20.41 158.68,20.41 160.84,22.56 170.26,22.56 171.55,23.86 171.55,34.63 173.69,36.76 180.47,36.76 181.89,38.19 198.33,38.19 201.63,41.49 204.93,41.49 204.93,40.92 206.72,30.76 211.87,21.81 211.87,19.41 212.68,17.68 214.52,17.17 215.93,16.79 216.54,15.47 216.54,13.47 132.59,13.47 131.7,13.23 131.05,12.57 127.13,12.57 126.48,13.23 125.59,13.47 115.47,13.47 115.47,14.97 112.23,14.97 112.23,12.89 112.1,12.74 112,12.57
+3VALW on IN4: 38.49,75.93 38.2,76.22 38.2,77.39 38.61,77.79 41.24,77.79 41.41,77.62 41.41,76.01 41.33,75.93
+3VALW on IN4: 26.8,70.05 26.56,69.95 26.45,69.71 25.88,69.13 25.17,69.13 25.01,69.3 25.01,70.17 26.24,71.4 26.9,71.4 27.18,71.12 27.18,70.43
+3VALW_5085 on TOP (solid shape): 192.76,61.03 192.76,59.88 192.75,59.85 192.73,59.8 192.73,59.75 192.73,59.7 192.73,59.65 192.75,59.6 192.76,59.57 192.76,58.52 192.75,58.49 192.63,58.38 192,58.38 192,58.89 191.36,59.53 191.69,59.53 191.69,59.47 191.7,59.42 191.71,59.37 191.74,59.32 191.77,59.28 191.8,59.24 191.84,59.21 191.89,59.18 191.94,59.16 191.99,59.15 192.04,59.14 192.1,59.15 192.15,59.16 192.2,59.18 192.24,59.21 192.29,59.24 192.32,59.28 192.35,59.32 192.38,59.37 192.39,59.42 192.4,59.47 192.4,59.53 192.39,59.58 192.38,59.63 192.35,59.68 192.32,59.72 192.29,59.76 192.24,59.79 192.2,59.82 192.15,59.84 192.1,59.85 192.04,59.86 191.99,59.85 191.94,59.84 191.89,59.82 191.84,59.79 191.8,59.76 191.77,59.72 191.74,59.68 191.71,59.63 191.7,59.58 191.69,59.53 191.36,59.53 191.23,59.66 191.23,61.43 191.33,61.53 192.26,61.53
+3VALW_5085 on BOTTOM (solid shape): 171.82,64.44 171.82,63.37 171.78,63.33 170.21,63.33 170.03,63.51 170.03,64.47 170.16,64.6 171.66,64.6
+3VALW_5085 on IN2 (solid shape): 171.46,64.32 174.69,64.32 174.77,64.4 175.04,64.4 175.38,64.06 175.38,63.85 175.05,63.53 175.04,63.52 175.02,63.51 174.98,63.53 174.51,63.56 174.42,63.1 174.42,63 174.33,62.95 171.59,62.95 171.37,63.02 171.16,62.95 170.03,62.95 169.77,63.21 168.74,63.21 168.54,63.41 168.54,64.19 168.78,64.43 171.35,64.43
+3VALW_5085 on IN2 (solid shape): 178.79,71.84 179.83,71.84 180.72,70.95 184,70.95 184.25,70.7 184.25,69.55 184,69.3 182.82,69.3 182.75,69.33 182.72,69.41 182.72,69.42 182.68,69.6 182.54,69.74 182.52,69.8 182.54,69.86 182.54,69.87 182.59,69.89 182.63,69.86 183.31,69.96 182.7,70.25 182.61,70.22 182.54,70.27 181.99,70.31 182.04,69.77 182.08,69.72 182.08,69.65 182.02,69.54 182.01,69.42 182.01,69.41 181.98,69.33 181.91,69.3 181.76,69.3 181.69,69.33 181.66,69.41 181.66,69.42 181.45,69.76 181.06,69.69 181.01,69.68 180.96,69.69 180.91,69.73 180.89,69.77 180.9,69.8 180.85,70.28 180.36,70.26 180.25,70.23 180.19,70.33 180.19,70.44 179.81,70.82 178.41,70.82 177.6,71.64 177.6,72.04 177.9,72.35 178.28,72.35
+3VALW_TPM on TOP (solid shape): 183.23,47.83 183.23,47.04 183.44,46.83 183.69,46.83 183.77,46.76 183.77,46.63 183.71,46.57 182.31,46.57 182.02,46.27 181.05,46.27 180.97,46.35 180.97,47.86 180.91,47.92 180.91,48.85 180.96,48.9 180.96,49.42 181.1,49.56 181.5,49.56
+3VALWP on TOP (solid shape): 82.65,23.2 82.65,18.63 82.4,18.37 78.84,18.37 78.59,18.63 78.59,23.33 79.1,23.83 82.02,23.83
+3VALWP on BOTTOM (solid shape): 82.65,23.2 82.65,17.99 82.37,17.71 74.51,17.71 74.4,17.81 74.4,19.01 74.65,19.26 77.97,19.26 78.59,19.88 78.59,23.2 79.1,23.71 82.14,23.71
+3VLP on BOTTOM (solid shape): 88.75,20.35 88.75,19.77 88.55,19.57 88.09,19.54 88.05,19.08 87.87,18.9 87.85,18.9 87.53,18.8 87.43,18.49 87.44,18.46 87.22,18.25 87.22,16.39 87.07,16.24 85.95,16.24 85.83,16.37 85.83,17.87 87.35,19.39 87.35,20.28 87.53,20.46 88.64,20.46
+3VS on TOP (solid shape): 40.49,47.98 40.49,47.61 40.44,47.43 40.49,47.25 40.49,45.68 40.62,45.55 41.25,45.55 41.3,45.5 41.3,44.46 41.12,44.28 40.87,44.28 40.58,44.57 40.53,44.57 40.3,44.8 40.3,45.04 38.9,45.04 38.9,45.71 38.53,46.07 38.53,47.63 39.15,48.25 40.22,48.25
+3VS on IN3: 184.59,41.1 185.21,41.3 184.65,41.62 184.58,41.6 184.51,41.64 184.49,41.66 184.48,41.7 184.49,41.73 184.61,41.96 184.55,42.2 184.55,42.82 185.56,43.83 187.82,43.83 188.09,43.57 189.98,43.57 191.01,44.6 192.83,44.6 193.14,44.28 193.14,37.55 192.89,37.3 191.52,37.3 191.45,37.32 191.42,37.39 191.41,37.42 191.42,37.46 191.46,37.48 191.76,37.7 191.69,38.08 191.67,38.14 191.69,38.21 191.75,38.35 191.75,38.5 191.77,38.58 191.83,38.63 192.08,39.09 191.6,39.3 191.52,39.3 191.47,39.36 191.44,39.41 191.4,39.47 191.37,39.53 191.39,39.6 191.1,40.17 190.85,39.57 190.87,39.51 190.85,39.44 190.87,38.99 191.32,38.92 191.37,38.93 191.39,38.81 191.32,38.77 191.07,38.53 191.14,38.18 191.17,38.12 191.15,38.05 191.09,37.95 191.07,37.82 191.05,37.76 190.99,37.72 190.79,37.61 190.7,37.39 190.67,37.32 190.6,37.3 190.21,37.3 190.2,37.33 189.87,37.55 189.54,37.33 189.52,37.3 188.07,37.3 187.86,37.5 185.54,37.5 185.53,37.51 184.97,37.51 184.59,37.9 184.59,40.17 184.58,40.18 184.58,40.57 184.59,40.58
+3VS on IN4: 40.02,47.75 40.02,46.41 39.25,45.64 39.18,45.61 39.1,45.64 38.67,45.7 38.51,45.29 38.49,45.2 38.41,45.16 35.02,45.16 34.94,45.19 34.92,45.28 34.57,45.7 34.22,45.28 34.2,45.19 34.12,45.16 33.17,45.16 32.85,45.36 32.53,45.16 29.88,45.16 27.07,42.35 25,42.35 23.81,43.53 23.81,47.99 23.97,48.15 25.34,48.15 25.71,47.78 26.88,47.78 27.09,47.56 27.07,47.52 27.02,47.16 27.33,46.95 27.39,46.92 27.42,46.86 27.45,46.75 27.51,46.66 27.54,46.6 27.52,46.53 27.47,46.45 27.45,46.35 27.42,46.29 27.35,46.26 27.09,45.66 27.71,45.87 27.74,45.93 27.81,45.96 28.13,46.18 28.07,46.56 28.04,46.62 28.06,46.69 28.12,46.79 28.13,46.91 28.16,46.99 28.23,47.02 36.79,47.02 37.41,47.64 37.43,47.64 37.61,47.74 37.7,47.92 37.71,47.93 37.8,48.03 39.74,48.03
+3VS_AUDIO on TOP (solid shape): 34.9,38.31 34.9,36.99 34.7,36.79 33.83,36.79 33.4,36.36 32.92,36.36 32.36,36.92 32.36,37.55 32.74,37.93 33.5,37.93 33.63,38.06 33.63,38.31 33.76,38.44 34.77,38.44
+3VS_CR on TOP (solid shape): 177.85,18.64 177.93,18.43 178.14,18.35 180.03,16.45 180.07,16.45 180.19,16.34 180.19,14.94 179.93,14.69 177.39,14.69 174.82,17.27 174.82,20.32 174.93,20.43 175.18,20.43 175.32,20.46 175.44,20.53 175.96,20.53
+3VS_CR on BOTTOM (solid shape): outline of 100 points within 192.13,15.07 197.84,27.64
+3VS_CR on IN3 (solid shape): outline of 552 points within 178.79,13.55 198.98,20.28
+3VS_NGFF on TOP (solid shape): 48.71,47.91 49.86,47.91 49.99,48.04 50.85,48.04 51.19,47.69 51.19,46.35 51.03,46.19 47.92,46.19 47.55,46.55 47.55,48.1 47.73,48.28 48.34,48.28
+3VS_NGFF on TOP (solid shape): 34.93,47.54 35.01,47.42 35.14,47.34 35.27,47.32 35.36,47.33 36.42,47.33 36.55,47.2 36.55,46.51 36.4,46.35 34.96,46.35 34.8,46.19 33.63,46.19 33.38,46.44 33.31,46.44 33.3,46.45 33.12,46.49 32.93,46.44 30.73,46.44 30.61,46.57 30.61,47.29 30.87,47.55 34.93,47.55
+3VS_NGFF on BOTTOM (solid shape): 48.49,48.34 48.62,48.32 48.74,48.34 48.75,48.35 49.12,48.35 49.76,47.71 49.76,45.75 49.56,45.55 48.92,45.55 48.84,45.63 48.84,47.1 48.74,47.2 48.61,47.2 48.61,47.21 48.5,47.23 48.39,47.21 48.38,47.2 48.11,47.2 48.11,47.21 48,47.23 47.89,47.21 47.88,47.2 47.73,47.2 47.47,47.46 47.47,48.09 47.73,48.35 48.48,48.35
+3VS_NGFF on BOTTOM: 30.76,47.33 31.09,47.66 31.09,48.12 31.32,48.35 31.65,47.82 31.94,48.37 33.74,48.37 33.74,48.37 34.65,48.37 34.77,48.24 34.77,47.2 34.52,46.95 33.63,46.95 33.25,47.33 32.49,47.33 32.16,47 32.16,45.63 32.08,45.55 31.12,45.55 30.76,45.91
+3VS_NGFF on IN3: 48.62,47.96 48.62,47.57 44.31,43.27 42.8,43.27 42.8,43.31 42.5,43.64 42.11,43.42 42.05,43.37 41.96,43.38 41.68,43.43 41.45,43.27 39.09,43.27 38.58,43.77 37.57,43.77 37.3,44.04 37.32,44.08 37.26,44.51 36.83,44.57 36.8,44.54 34.65,46.69 34.14,46.69 33.63,47.2 33.63,47.84 33.76,47.97 33.84,48 33.91,47.96 34.33,47.86 34.54,48.23 34.56,48.31 34.64,48.35 35,48.35 35.21,48.28 35.41,48.35 36.42,48.35 36.6,48.29 36.78,48.35 37.06,48.35 37.11,48.29 37.13,48.18 37.04,48.12 36.8,47.51 37.41,47.76 37.47,47.85 37.58,47.83 38.65,46.76 44.74,46.76 45.08,47.1 45.11,47.08 45.52,47.15 45.59,47.55 45.57,47.59 46.97,48.98 47.6,48.98
+3VS_TP on TOP (solid shape): 168.46,17.41 169.34,17.41 169.39,17.36 169.39,16.85 169.27,16.72 168.83,16.72 167.62,16.72 167.49,16.85 167.49,17.83 167.65,17.99 167.88,17.99
+3VS_TP on IN1 (solid shape): outline of 125 points within 186.92,14.18 190.98,19.9
+3VS_TPM on TOP (solid shape): 182.09,45.84 182.09,41.82 181.93,41.65 181.17,41.65 180.95,41.87 180.95,43.57 181.1,43.72 181.1,45.39 180.95,45.54 180.95,45.96 181,46.01 181.93,46.01
+3VS_TPM on IN1: 183.87,39.33 183.62,39.58 183.62,40.73 183.87,40.98 185.27,40.98 186.54,42.25 186.54,43.77 186.61,43.84 186.71,43.87 186.78,43.79 187.38,43.59 187.19,44.19 187.11,44.26 187.13,44.37 188.89,46.12 190.03,46.12 191.11,45.04 191.11,43.26 191.08,43.25 190.91,43.11 190.85,42.9 190.85,42.88 187.3,39.33
+5V_USB_P2 on TOP (solid shape): 18.97,51.24 18.97,50.99 19.23,50.73 20.7,50.73 20.78,50.66 20.78,49.16 20.65,49.03 17.93,49.03 17.76,49.21 17.76,51.27 17.88,51.39 18.82,51.39
+5V_USB_P2 on BOTTOM (solid shape): 19.77,51.55 19.77,50.31 20.24,49.85 20.51,49.85 20.8,49.56 20.8,46.82 20.68,46.69 16.87,46.69 15.47,48.09 13.95,48.09 13.69,48.35 13.69,49.87 14.2,50.38 16.99,50.38 18.26,51.65 19.67,51.65
+5VALW on TOP (solid shape): 194.54,17.48 194.54,16.21 194.41,16.09 193.14,16.09 193.02,16.21 193.02,16.85 193.4,17.23 193.4,17.87 193.52,17.99 194.03,17.99
+5VALW on TOP (solid shape): 52.87,18.84 52.91,18.8 53.9,18.8 54.23,18.47 54.23,17.64 54.08,17.48 51.69,17.48 51.54,17.64 51.54,19.39 51.61,19.47 52.25,19.47
+5VALW on TOP (solid shape): 28.87,51.34 28.87,49.74 28.8,49.67 28.74,49.65 28.69,49.62 23.6,49.62 23.47,49.74 23.47,50.69 23.6,50.82 25.12,50.82 25.54,51.24 27.51,51.24 27.76,51.49 28.72,51.49
+5VALW on TOP (solid shape): 53.52,22.38 53.52,22.1 53.34,21.84 53.45,21.54 52.76,20.85 51.6,20.85 51.54,20.91 51.54,21.37 51.54,21.37 51.54,21.48 50.9,22.11 50.9,22.72 50.94,22.75 51.12,22.75 51.13,22.75 51.41,22.74 51.61,22.94 51.62,22.95 52.03,23.37 52.53,23.37
+5VALW on TOP (solid shape): outline of 132 points within 24.23,53.38 29.65,59.65
+5VALW on BOTTOM (solid shape): 61.41,49.44 61.41,48.9 61.35,48.71 61.41,48.53 61.41,47.82 61.27,47.68 56.81,47.68 56.38,48.12 56.38,49.6 56.48,49.7 61.14,49.7
+5VALW on BOTTOM (solid shape): 195.17,18.63 195.17,18.06 195.14,18.05 194.91,17.81 194.98,17.49 195,17.42 194.98,17.36 194.91,17.03 195.14,16.79 195.17,16.78 195.17,16.34 194.92,16.09 194.92,15.07 194.79,14.94 192,14.94 191.87,15.07 191.87,16.98 192,17.1 192,17.11 192.02,17.13 192.15,17.42 192,17.7 192,18.63 192.13,18.75 195.05,18.75
+5VALW on IN3 (solid shape): 53.34,22.54 53.34,19.91 53.3,19.83 53.22,19.81 52.78,19.46 53.22,19.11 53.3,19.09 53.34,19.01 53.34,18.78 52.81,18.25 51.79,18.25 51.54,18.5 51.54,22.41 51.79,22.67 53.21,22.67
+5VALW on IN3 (solid shape): outline of 398 points within 96.24,14.94 156.95,19.26
+5VALW on IN4 (solid shape): outline of 2755 points within 66.9,13.55 99.8,25.74
+5VALW on IN1: 158.14,77.34 160.01,77.34 160.29,77.06 160.29,76.41 159.84,75.97 158.18,75.97 158.01,76.13 158.01,77.21
+5VALW on GND2: 153.5,13.55 153.39,13.65 153.39,15.35 157.43,19.39 176.4,19.39 177.54,18.25 193.29,18.25 194.54,17 194.54,14.67 193.42,13.55
+5VALW on VCC: outline of 111 points within 1.27,1.27 88.49,80.73 ; 3 cut-outs
+5VALW on IN4: 153.18,13.55 153.03,13.7 153.03,15.35 153.26,15.58 161.77,15.58 163.88,17.69 163.98,17.72 164.05,17.65 164.64,17.51 164.5,18.1 164.44,18.17 164.46,18.27 166.73,20.53 174.96,20.53 175.18,20.46 175.41,20.53 176,20.53 179.05,17.48 183.35,17.48 183.67,17.28 183.99,17.48 184.91,17.48 184.91,17.48 185.04,17.46 185.16,17.48 185.17,17.48 185.53,17.48 185.83,17.33 186.12,17.48 186.32,17.48 186.59,17.36 186.86,17.48 187.53,17.48 187.55,17.45 187.88,17.2 188.22,17.45 188.23,17.48 191.34,17.48 191.41,17.46 191.44,17.39 191.8,17.05 192.15,17.39 192.18,17.46 192.25,17.48 194.03,17.48 194.79,16.72 194.79,14.69 193.9,13.8 175.49,13.8 174.6,14.69 166.55,14.69 166.55,14.73 166.19,15.05 165.84,14.73 165.83,14.69 165.58,14.69 164.44,13.55
+5VALWP on BOTTOM (solid shape): 56.24,49.62 56.24,48.08 57.31,47.01 57.34,46.98 60.52,46.98 60.68,46.82 60.68,45.62 59.97,44.92 58.08,44.92 56.67,43.51 56.67,41.05 55.81,40.19 52.45,40.19 52.35,40.29 52.35,44.42 53.65,45.72 58.55,45.72 58.55,45.66 58.56,45.61 58.58,45.56 58.61,45.52 58.64,45.47 58.68,45.44 58.72,45.41 58.77,45.38 58.82,45.37 58.88,45.36 58.93,45.36 58.98,45.37 59.03,45.38 59.08,45.41 59.13,45.44 59.16,45.47 59.2,45.52 59.22,45.56 59.24,45.61 59.26,45.66 59.26,45.72 59.26,45.77 59.24,45.82 59.22,45.87 59.2,45.92 59.16,45.96 59.13,46 59.08,46.03 59.03,46.05 58.98,46.06 58.93,46.07 58.88,46.07 58.82,46.06 58.77,46.05 58.72,46.03 58.68,46 58.64,45.96 58.61,45.92 58.58,45.87 58.56,45.82 58.55,45.77 58.55,45.72 53.65,45.72 53.97,46.04 54.95,46.04 55.02,46.11 55.02,46.74 55.6,47.32 55.6,49.62 55.73,49.74 56.11,49.74
+5VS on TOP (solid shape): 47.12,18.92 47.12,16.62 46.97,16.47 45.31,16.47 44.81,16.98 44.81,17.36 45.82,18.37 45.82,18.77 46.01,18.96 47.08,18.96
+5VS on BOTTOM (solid shape): 80.67,61.82 80.67,59.72 80.6,59.66 79.54,59.66 79.53,59.67 79.53,61.03 79.78,61.29 80.19,61.29 80.28,61.38 80.28,61.83 80.37,61.92 80.57,61.92
+5VS on BOTTOM (solid shape): 80.61,54.26 80.61,52.82 80.09,52.3 78.99,52.3 78.93,52.36 78.93,52.98 79.13,53.18 79.13,53.97 79.49,54.33 80.54,54.33
+5VS on BOTTOM (solid shape): 80.56,46.31 80.56,45.7 80.32,45.46 79.72,45.46 79.39,45.13 78.44,45.13 78.41,45.16 78.41,46.05 78.45,46.08 79.91,46.08 80.23,46.4 80.47,46.4
+5VS_AUDIO on TOP (solid shape): 23.09,20.61 23.22,20.48 23.22,19.87 23.04,19.69 21.16,19.69 20.9,19.95 20.9,20.61 21.03,20.74 23.09,20.74
+5VS_AUDIO on TOP (solid shape): 47.45,23.3 47.45,21.04 47.35,20.94 46.41,20.94 46.28,21.07 46.28,21.4 46.23,21.44 46.2,21.49 46.15,21.54 45.97,21.62 45.78,21.59 45.57,21.8 45.57,22.95 45.85,23.23 46.76,23.23 46.86,23.33 47.42,23.33
+5VS_AUDIO on BOTTOM (solid shape): 23.72,21.8 23.72,20.28 23.6,20.15 21.69,20.15 21.44,20.41 21.44,20.86 21.48,20.87 21.74,21.22 21.48,21.56 21.44,21.57 21.44,21.8 21.57,21.93 23.6,21.93
+5VS_AUDIO on BOTTOM (solid shape): 34.65,27.14 34.65,25.87 35.28,25.23 35.28,23.83 34.9,23.45 32.36,23.45 31.98,23.83 28.8,23.83 28.68,23.96 28.68,24.52 28.68,24.6 28.8,24.72 29.41,24.72 29.41,24.65 30.23,24.65 30.23,24.72 30.33,24.72 30.43,24.83 33.38,24.83 33.38,24.77 33.38,24.72 33.4,24.67 33.42,24.62 33.45,24.58 33.49,24.54 33.53,24.5 33.58,24.48 33.63,24.46 33.68,24.45 33.73,24.44 33.78,24.45 33.84,24.46 33.89,24.48 33.93,24.5 33.97,24.54 34.01,24.58 34.04,24.62 34.06,24.67 34.08,24.72 34.09,24.77 34.09,24.83 34.08,24.88 34.06,24.93 34.04,24.98 34.01,25.02 33.97,25.06 33.93,25.09 33.89,25.12 33.84,25.14 33.78,25.15 33.73,25.16 33.68,25.15 33.63,25.14 33.58,25.12 33.53,25.09 33.49,25.06 33.45,25.02 33.42,24.98 33.4,24.93 33.38,24.88 33.38,24.83 30.43,24.83 30.58,24.98 32.23,24.98 33.25,25.99 33.25,26.76 33.12,26.88 31.73,26.88 31.6,27.01 31.6,27.52 32.36,28.28 33.5,28.28
+5VS_AUDIO on IN4 (solid shape): 33.41,25.23 33.51,25.17 33.49,25.06 33.47,24.56 33.97,24.53 34.08,24.55 34.14,24.46 34.14,23.66 33.93,23.45 32.99,23.45 31.83,22.29 31.81,22.29 31.67,22.27 31.55,22.2 31.49,22.18 31.42,22.2 30.9,22.15 31,21.63 31.04,21.56 31.02,21.47 29.9,20.36 29.8,20.34 29.73,20.42 29.12,20.64 29.34,20.04 29.43,19.97 29.41,19.86 29.31,19.77 27.49,19.77 27.4,19.82 27.39,19.91 27.06,20.41 26.74,19.91 26.73,19.82 26.64,19.77 21.82,19.77 21.57,20.02 21.57,20.91 21.74,21.16 21.66,21.45 21.65,21.48 21.66,21.52 21.82,21.68 24.08,21.68 24.16,21.63 24.18,21.55 24.17,21.37 24.25,21.21 24.28,21.15 24.25,21.08 24.51,20.48 24.78,21.07 24.75,21.14 24.78,21.21 24.87,21.37 24.86,21.55 24.88,21.63 24.96,21.68 26.9,21.68 26.91,21.63 27.26,21.34 27.61,21.63 27.62,21.68 28.42,21.68 31.98,25.23
+5VS_AUDIO on VCC: 34.32,20.53 31.6,23.25 31.6,26.73 31.34,26.99 31.34,28.55 31.58,28.79 32.13,28.79 32.87,28.05 32.87,26.78 35.3,24.34 37.46,24.34 38.6,23.2 46.48,23.2 46.71,22.97 46.71,20.89 46.35,20.53
+AVDD1 on BOTTOM (solid shape): 22.71,25.36 22.71,24.85 22.2,24.34 22.2,24.25 22.2,24.24 22.19,23.92 22.44,23.71 22.46,23.71 22.58,23.58 23.47,23.58 23.6,23.45 23.6,22.31 23.47,22.18 21.9,22.18 21.81,22.27 21.81,23.23 21.06,23.99 21.06,24.23 21.06,24.23 21.06,25.02 21.52,25.49 22.58,25.49
+AVDD1 on BOTTOM (solid shape): 23.48,33.6 24.02,33.6 24.16,33.46 24.16,32.58 24.1,32.39 24.16,32.21 24.16,31.33 23.9,31.07 23.79,31.07 23.78,31.11 23.44,31.35 23.11,31.11 23.09,31.07 21.95,31.07 21.82,31.2 21.82,32.47 22.07,32.72 22.07,33.49 22.2,33.61 23.47,33.61
+PVDD1 on TOP (solid shape): 27.16,27.02 27.16,25.49 26.11,24.43 25.87,24.43 25.78,24.51 25.78,24.55 25.75,24.55 25.75,24.72 26.95,25.92 26.95,27.02 27.01,27.07 27.11,27.07
+PVDD1 on BOTTOM (solid shape): 27.28,25.87 27.28,25.61 26.61,24.94 26.61,24.86 26.6,24.85 26.59,24.74 26.6,24.63 26.61,24.62 26.61,24.38 26.77,24.22 27.41,24.22 27.79,24.6 28.42,24.6 28.55,24.47 28.55,22.18 28.42,22.06 27.66,22.06 27.53,22.18 27.53,22.56 27.28,22.82 26.39,22.82 25.63,23.58 25.63,25.49 26.49,26.35 26.8,26.35
+PVDD2 on TOP (solid shape): 29.19,27.03 29.19,26.08 29.4,25.88 29.58,25.88 29.62,25.84 30.3,25.84 30.34,25.8 30.34,25.51 30.23,25.41 29.3,25.41 28.95,25.76 28.95,25.94 28.96,25.94 28.96,27.09 29.14,27.09
+PVDD2 on BOTTOM (solid shape): 31.55,26.7 32,26.7 32.11,26.6 32.11,26.09 32.08,26.07 32.03,26.06 31.97,26.04 30.48,26.04 30.33,25.89 30.33,25.54 30.2,25.41 29.41,25.41 29.41,25.41 27.97,25.41 27.74,25.64 27.74,26.63 27.88,26.78 29.41,26.78 29.59,26.96 31.29,26.96
+VBUS_DC_SS on BOTTOM (solid shape): 47.66,78.76 47.66,76.86 47.54,76.73 44.81,76.73 44.68,76.86 44.68,78.76 44.81,78.89 47.54,78.89
+VCC0V9_CIO on BOTTOM: 42.81,59.88 42.81,59.06 43,58.87 44.63,58.87 44.67,58.91 44.67,59.91 44.54,60.04 44.31,60.04 43.92,59.65 43.52,59.65 43.22,59.95 42.89,59.95
+VCC0V9_CIO on IN3: 49.52,60.44 49.52,54.86 48.54,53.88 46.75,53.88 46.66,53.93 46.66,54.04 46.6,54.5 46.13,54.5 46.07,54.48 46,54.5 45.51,54.47 45.53,53.97 45.54,53.95 45.54,53.88 45.42,53.88 45.16,54.14 45.17,54.17 45.07,54.5 44.74,54.59 44.71,54.58 44.62,54.68 44.59,54.76 44.63,54.84 44.7,55.38 44.16,55.36 44.08,55.32 44,55.36 43.92,55.44 43.82,55.48 43.81,55.49 43.28,56.02 43.28,58.13 43.35,58.18 43.41,58.24 43.42,58.25 43.46,58.27 43.5,58.25 43.53,58.22 43.56,58.14 43.53,58.07 43.42,57.82 43.56,57.49 43.53,57.42 43.78,56.8 44.03,57.42 43.99,57.49 44.03,57.56 44.03,57.57 44.11,57.6 44.18,57.57 44.79,57.82 44.18,58.07 44.1,58.04 44,58.14 44.03,58.21 44.03,58.72 43.52,58.71 43.45,58.68 43.38,58.71 43.37,58.71 43.34,58.79 43.37,58.86 43.48,59.18 43.28,59.44 43.28,61.07 43.65,61.44 48.52,61.44
+VCC0V9_DP on BOTTOM: 50.44,58.46 50.39,58.28 50.44,58.09 50.44,56.99 50.44,56.94 50.44,56.88 50.44,54.28 50.44,54.27 49.77,54.27 49.52,54.52 49.52,54.57 49.51,54.58 49.51,56.23 49.51,56.24 49.51,57.69 49.38,57.82 49.38,57.84 49.17,58.14 48.81,58.11 48.75,58.09 48.68,58.12 48.53,58.2 48.35,58.2 48.32,58.19 47.52,58.99 46.84,58.99 46.76,59.02 46.74,59.09 46.53,59.44 46.13,59.37 46.06,59.34 45.99,59.37 45.73,59.48 45.41,59.34 45.33,59.37 45.17,59.46 44.99,59.46 44.9,59.48 44.86,59.56 44.86,61.93 44.9,62.01 44.99,62.03 45.17,62.03 45.33,62.12 45.4,62.15 45.73,62.02 45.97,62.13 46.05,62.16 46.12,62.12 46.3,62.02 46.51,62.03 46.51,62.04 48.29,62.04 48.33,61.99 48.36,61.9 48.31,61.83 48.23,61.27 48.79,61.35 48.79,61.52 48.87,61.6 50.34,61.6 50.39,61.56 50.39,59.02 50.42,58.99 50.4,58.83 50.44,58.68
+VCC0V9_DP on IN1: 41.98,56.15 41.53,56.6 41.53,56.62 41.45,56.76 41.32,56.86 41.29,56.88 41.29,57.48 41.32,57.49 41.53,57.76 41.42,58.08 41.39,58.15 41.42,58.22 41.53,58.48 41.4,58.8 41.43,58.87 41.53,59.19 41.32,59.45 41.29,59.46 41.29,60.08 41.32,60.1 41.5,60.28 41.52,60.53 41.51,60.56 41.69,60.74 41.72,60.73 42.08,60.82 42.17,61.18 42.16,61.21 42.25,61.3 42.73,61.3 42.81,61.22 43.19,60.72 43.38,61.32 43.35,61.4 43.38,61.47 43.44,61.89 43.05,62.07 42.97,62.09 42.93,62.17 42.93,62.47 43.13,62.67 43.15,62.67 43.38,62.77 43.48,63 43.49,63.02 43.62,63.15 43.97,63.15 44.05,63.12 44.07,63.04 44.28,62.7 44.68,62.77 44.76,62.8 44.86,62.7 44.83,62.62 44.8,62.15 45.26,62.06 45.36,62.06 45.41,61.97 45.41,61.22 45.41,61.21 45.37,61.07 45.41,60.92 45.41,60.91 45.41,60.57 45.41,60.56 45.37,60.42 45.41,60.27 45.41,60.26 45.41,58.18 44.49,57.26 44.49,56.69 43.95,56.15
+VCC0V9_PCIE on TOP (solid shape): 42.8,68.83 42.8,67.19 42.88,67.19 43.08,66.99 43.08,66.68 43.02,66.63 42.97,66.58 42.66,66.58 42.59,66.64 42.51,66.68 42.5,66.68 42.38,66.8 42.39,66.83 42.35,67.17 42.05,67.32 41.74,67.32 41.64,67.42 41.64,68.48 41.68,68.51 42.14,68.51 42.29,68.67 42.29,68.83 42.36,68.89 42.74,68.89
+VCC0V9_PCIE on IN1: 42.41,67.04 42.31,67.22 42.28,67.29 42.31,67.36 42.57,67.62 44.22,67.62 44.6,67.24 44.6,64.32 44.27,63.99 44.26,63.99 44.18,63.92 44.12,63.84 44.11,63.83 43.54,63.26 43.46,63.23 43.39,63.26 42.88,63.27 42.89,62.76 42.92,62.69 42.89,62.61 42.82,62.54 42.8,62.52 42.8,61.86 42.8,61.85 42.78,61.77 42.77,61.69 42.58,61.49 42.4,61.49 42.19,61.7 42.16,61.85 42.08,61.97 42.05,62.04 42.08,62.12 42.13,62.57 41.69,62.7 41.6,62.71 41.55,62.79 41.55,65.92 41.6,66 41.69,66.02 41.86,66 42.02,66.08 42.09,66.1 42.15,66.07 42.71,66.18 42.47,66.69 42.4,66.74 42.39,66.83
+VCC0V9_USB on BOTTOM: 47.96,65.67 46.81,64.52 46.73,64.49 46.66,64.53 46.4,64.68 46.13,64.58 46.06,64.56 45.99,64.59 45.38,64.34 45.98,64.07 46.05,64.1 46.12,64.07 46.12,64.06 46.16,63.99 46.13,63.92 46.07,63.85 46.04,63.76 46.04,63.75 45.66,63.37 45.65,63.37 45.55,63.33 45.48,63.27 45.4,63.24 45.3,63.35 45.33,63.42 45.33,63.92 44.83,63.92 44.76,63.89 44.68,63.92 44.18,63.92 44.18,63.42 44.21,63.35 44.18,63.27 44.18,62.77 44.68,62.77 44.76,62.8 44.86,62.7 44.83,62.62 44.77,62.55 44.73,62.46 44.73,62.44 44.36,62.07 43.19,62.07 43.13,62.08 42.89,62.07 42.81,62.12 42.8,62.22 42.83,62.43 42.73,62.62 42.7,62.7 42.73,62.77 42.73,62.77 42.8,62.8 42.88,62.77 43.38,62.77 43.38,63.27 43.35,63.35 43.49,63.67 43.35,64 43.45,64.1 43.53,64.07 43.99,64.04 44.09,64.49 44.29,64.69 44.29,65.03 44.28,65.04 44.28,65.93 45.36,67.01 49.01,67.01 49.25,66.77 49.25,66.51 49.12,66.38 48.63,66.38 48.11,66.52 48.05,65.99 48.07,65.92 48.05,65.85 47.99,65.78 47.96,65.69
+VCC_CORE on TOP (solid shape): outline of 2539 points within 90.12,51.75 135.84,73.75
+VCC_CORE on BOTTOM (solid shape): outline of 154 points within 90.78,51.49 104.28,72.22
+VCC_CORE on IN3 (solid shape): 124.12,73.62 124.2,73.58 124.22,73.49 124.32,73.13 124.68,73.05 124.77,73.04 124.82,72.96 124.82,72.48 124.71,72.37 121.62,72.37 121.39,72.6 121.4,72.71 121.39,72.78 121.39,73.35 123.16,73.35 123.43,73.62
+VCC_CORE on TOP: 124.07,57.5 124.07,57.28 124.23,57.12 126.57,57.12 126.81,57.36 126.81,58.49 126.74,58.56 126.74,58.97 126.53,59.18 124.48,59.18 124.36,59.06 124.36,57.79
+VCC_CORE on BOTTOM: 130.32,55.65 130.25,55.66 130.18,55.68 130.15,55.78 129.92,56 129.8,56.02 129.51,56.31 129.36,56.31 128.51,55.46 123.22,55.46 122.76,55.91 122.76,58.21 122.97,58.42 130.6,58.42 130.64,58.38 131.02,58.38 131.06,58.42 131.43,58.42 131.48,58.38 131.79,58.38 131.84,58.42 132.93,58.42 132.97,58.38 133.38,58.38 133.54,58.22 133.54,57.88 133.52,57.85 133.51,57.84 133.48,57.75 133.48,57.65 133.48,57.08 133.68,56.88 133.73,56.81 133.8,56.76 134.08,56.48 134.08,55.98 133.5,55.39 133.26,55.39 133.25,55.44 133.09,55.64 132.83,55.6 132.6,55.39 132.4,55.39 132.33,55.46 132.16,55.64 131.92,55.6 131.68,55.39 131.43,55.39 131.42,55.44 131.26,55.64 131,55.6 130.77,55.39 130.54,55.39 130.51,55.42 130.5,55.44 130.46,55.54 130.39,55.62
+VCC_CORE on BOTTOM: 133.66,67.23 133.89,66.99 133.89,66.97 133.96,66.78 134.12,66.66 134.21,66.64 134.21,66.44 133.7,65.92 124.11,65.92 122.25,67.78 122.25,67.97 122.31,68.03 127.7,68.03 127.7,67.73 127.79,67.65 127.86,67.59 127.95,67.57 128.17,67.67 128.21,67.9 128.21,67.91 128.21,68.03 128.56,68.03 128.71,68.18 128.71,68.62 128.75,68.67 129.01,68.67 129.07,68.6 129.07,68.18 129.23,68.03 129.54,68.03 129.54,67.83 129.8,67.57 130.05,67.83 130.05,68.03 130.4,68.03 130.53,68.16 130.53,68.6 130.59,68.67 130.79,68.67 130.91,68.54 130.91,68.16 131.04,68.03 131.37,68.03 131.37,67.83 131.63,67.57 131.88,67.83 131.88,68.03 132.18,68.03 132.34,68.19 132.34,68.7 132.37,68.73 132.63,68.73 132.73,68.63 132.73,68.18 132.88,68.03 133.2,68.03 133.2,67.83 133.45,67.57 133.71,67.83 133.71,68.03 134.02,68.03 134.17,68.18 134.17,68.56 134.28,68.67 134.47,68.67 134.55,68.58 134.55,68.08 134.51,68.06 134.46,68.06 134.14,67.95 134.21,67.62 134.25,67.55 134.23,67.47 134.18,67.43 134.14,67.47 134.14,67.48 133.88,67.61 133.66,67.42 133.66,67.39 133.66,67.36
+VCC_CORE on IN1: 133.2,66.84 134.47,65.57 134.47,59.88 134.19,59.6 127.99,59.6 127.9,59.69 127.9,64.68 126.47,66.11 126.47,66.76 126.54,66.84
+VCC_CORE on IN2: outline of 413 points within 91.21,48.4 134.95,68.76
+VCC_CORE on IN3: outline of 112 points within 91.05,47.77 134.98,69.58
+VCC_CORE on VCC: 89,51.65 89,69.58 93.55,74.13 104.24,74.13 104.24,77.17 123.69,77.17 124.18,76.69 124.18,73.77 124.99,72.95 124.99,72.07 125.96,71.1 125.96,68.31 126.74,67.52 134.24,67.52 134.6,67.16 134.6,57.06 133.4,55.87 133.4,54.89 128.83,54.89 128.56,55.16 128.56,55.92 127.82,56.66 125.12,56.66 124.86,56.41 117.24,56.41 117.17,56.47 114,56.47 113.8,56.68 102.82,56.68 101.14,55 101.14,51.83 100.96,51.65
+VCC_CORE on IN4: outline of 83 points within 91.2,51.52 136.1,66.93
+VCC_GT on TOP: outline of 345 points within 90.69,41.23 127.59,68.09
+VCC_GT on BOTTOM: outline of 112 points within 90.65,42.45 122.81,68.07
+VCC_GT on IN1: outline of 95 points within 90.61,43.87 126.86,66.76
+VCC_GT on GND3: 113.72,66.56 112.85,67.42 112.85,72.5 113.72,73.36 114.68,73.36 114.91,73.13 114.91,71.49 114.58,71.16 114.58,69.47 115.34,68.72 116.54,68.72 117.22,69.4 117.22,72.12 117.09,72.25 117.09,72.32 116.74,72.68 116.74,73.11 116.99,73.36 117.19,73.36 117.32,73.24 119.63,73.24 121.95,70.92 121.95,66.66 121.84,66.56
+VCC_SA on TOP (solid shape): 78.85,64.37 78.85,60.68 78.56,60.38 75.95,60.38 75.72,60.61 75.72,64.3 76.05,64.63 78.6,64.63
+VCC_SA on BOTTOM (solid shape): 137.97,58.15 137.95,58.12 138.03,57.72 138.43,57.65 138.46,57.66 138.56,57.56 138.56,57.53 138.57,57.39 138.63,57.26 138.63,56.9 138.56,56.83 137.44,56.83 137.36,56.9 137.36,58.12 137.47,58.23 137.9,58.23
+VCC_SA on BOTTOM (solid shape): 77.62,68.39 77.62,64.7 77.83,64.5 78.26,64.5 78.74,64.02 78.74,62.12 78.84,62.02 78.84,60.79 78.4,60.35 75.98,60.35 75.74,60.59 75.74,61.92 75.81,61.98 76.67,61.98 76.68,62 76.68,62.8 76.67,62.81 75.77,62.81 75.76,62.82 75.76,63.88 76.18,64.3 76.18,65.06 76.19,65.11 76.18,65.13 76.18,65.5 76.58,65.5 76.58,65.45 76.6,65.39 76.62,65.34 76.64,65.3 76.68,65.26 76.71,65.22 76.76,65.19 76.81,65.17 76.86,65.15 76.91,65.14 76.96,65.14 77.02,65.15 77.07,65.17 77.12,65.19 77.16,65.22 77.2,65.26 77.23,65.3 77.26,65.34 77.28,65.39 77.29,65.45 77.29,65.5 77.29,65.55 77.28,65.6 77.26,65.65 77.23,65.7 77.2,65.74 77.16,65.78 77.12,65.81 77.07,65.83 77.02,65.85 76.96,65.85 76.91,65.85 76.86,65.85 76.81,65.83 76.76,65.81 76.71,65.78 76.68,65.74 76.64,65.7 76.62,65.65 76.6,65.6 76.58,65.55 76.58,65.5 76.18,65.5 76.18,68.61 76.35,68.79 77.22,68.79
+VCC_SA on BOTTOM (solid shape): outline of 380 points within 134.66,65.94 139.04,68.73
+VCC_SA on IN1 (solid shape): outline of 187 points within 135.61,57.62 138.02,63.59
+VCC_SA on TOP: 134.52,66.53 134.52,67.73 135.1,68.31 135.28,68.31 135.56,68.59 135.56,68.94 135.64,69.02 136.53,69.02 136.73,69.22 137.62,69.22 137.67,69.17 137.67,68.87 137.69,68.84 138.13,68.84 138.89,68.08 138.89,67.52 138.63,67.27 138.63,65.59 138.79,65.44 139.09,65.44 139.22,65.31 139.22,63.94 138.79,63.51 138.2,63.51 137.19,62.49 136.88,62.49 136.73,62.65 136.73,62.9 136.96,63.13 136.96,66.4 137.44,66.89 137.44,67.65 137.34,67.75 137.34,68.11 137.24,68.21 136.86,68.21 136.65,68 136.65,67.32 136.45,67.12 136.45,66.89 136.37,66.81 136.09,66.81 135.94,66.96 135.94,67.34 136.14,67.55 136.14,67.95 136.07,68.03 135.66,68.03 135.03,67.4 135.03,66.91 135.1,66.84 135.1,66.51 135.05,66.45 134.6,66.45
+VCC_SA on TOP: 132.69,73.72 136.09,73.72 136.4,73.41 137.31,73.41 137.57,73.16 138.13,73.16 138.18,73.11 138.18,72.53 138.13,72.48 136.45,72.48 135.92,73.01 132.72,73.01 132.66,73.06 132.66,73.69
+VCC_SA on VCC: 136.53,57.69 135.84,58.38 135.1,58.38 135.1,67.37 134.45,68.03 126.95,68.03 126.47,68.52 126.47,71.31 125.5,72.28 125.5,73.16 124.69,73.98 124.69,76.9 123.91,77.68 103.73,77.68 103.73,74.63 93.34,74.63 88.49,69.79 88.49,60.28 71.33,60.28 70.84,60.77 70.84,80.73 139.93,80.73 139.93,67.75 139.29,67.12 139.29,59.64 139.67,59.27 138.1,57.69
+VCCPLL_OC on TOP (solid shape): 159.87,48.09 159.87,47.08 160.02,46.92 160.02,45.99 159.9,45.87 159.82,45.74 159.79,45.58 159.79,45.56 159.73,45.5 159.08,45.5 158.75,45.83 158.5,45.83 158.22,46.11 158.22,46.94 158.36,47.11 158.39,47.32 158.88,47.81 158.88,48.12 158.95,48.19 159.77,48.19
AGND on TOP (solid shape): 21.87,33.31 21.87,32.78 21.57,32.48 21.57,31.07 21.44,30.95 20.93,30.95 20.68,30.69 20.17,30.69 20.04,30.82 20.04,33.49 20.3,33.74 21.44,33.74
AGND on TOP (solid shape): 22.45,23.26 22.45,22.06 22.39,21.99 21.95,21.99 21.95,22.56 21.44,22.56 21.44,21.99 20.8,21.99 20.55,22.25 20.55,23.14 20.8,23.39 22.33,23.39
AGND on BOTTOM (solid shape): 7.34,22.56 7.34,21.17 7.06,20.88 5.17,20.88 5.1,20.95 5.1,21.23 5.64,21.23 5.64,21.66 5.1,21.66 5.1,21.98 5.27,22.15 6.19,22.15 6.73,22.69 7.21,22.69
AGND on GND1, GND2, GND3: 5.8,21.04 5.31,21.53 5.31,23.94 4.65,24.6 1.26,24.6 1.26,25.86 1.33,26.03 1.5,26.11 12.72,26.11 13.46,26.73 12.98,27.57 12.98,32.95 13.46,33.79 12.72,34.42 1.5,34.42 1.33,34.49 1.26,34.66 1.26,36.03 24.97,36.03 25.23,36.28 29.59,36.28 30.07,35.79 30.07,32.45 29.97,32.34 25.4,32.34 24.99,31.94 24.99,28.77 24.95,28.72 21.52,28.72 20.93,28.13 20.93,26.14 21.59,25.49 25.23,25.49 25.88,26.14 25.88,26.97 25.92,27.01 26.6,27.01 26.62,26.99 26.62,24.75 25.83,23.96 25.83,23.05 25.09,22.31 21.02,22.31 19.75,21.04
AGND on VCC: 5.8,21.04 5.31,21.53 5.31,23.94 4.65,24.6 2.27,24.6 2.27,25.09 12.72,25.09 14.35,26.17 13.99,28.09 13.99,32.43 14.35,34.35 12.72,35.43 2.27,35.43 2.27,36.03 24.97,36.03 25.23,36.28 29.59,36.28 30.07,35.79 30.07,32.45 29.97,32.34 25.4,32.34 24.99,31.94 24.99,28.77 24.95,28.72 21.52,28.72 20.93,28.13 20.93,26.14 21.59,25.49 25.23,25.49 25.88,26.14 25.88,26.97 25.92,27.01 26.6,27.01 26.62,26.99 26.62,24.75 25.83,23.96 25.83,23.05 25.09,22.31 21.02,22.31 19.75,21.04
GND on TOP (solid shape): 60.17,38.82 60.17,37.8 60.05,37.68 58.87,37.68 58.4,38.15 58.4,38.82 58.52,38.95 60.05,38.95
GND on TOP (solid shape): 105.19,64.83 105.19,62.66 104.85,62.32 96.98,62.32 96.58,62.71 96.58,64.59 96.99,64.99 105.03,64.99
GND on TOP (solid shape): 140.53,79.28 140.53,78.01 140.35,77.83 139.14,77.83 138.99,77.99 138.99,79.24 139.14,79.4 140.41,79.4
GND on TOP (solid shape): 166.09,32.09 166.09,29.42 165.71,29.04 165.08,29.04 164.95,29.17 164.95,32.09 165.08,32.22 165.96,32.22
GND on TOP (solid shape): 49.23,71.03 49.23,70.01 49.07,69.86 47.98,69.86 47.98,70.85 48.31,71.18 49.07,71.18
GND on TOP (solid shape): 6.33,20.66 6.33,20.53 6.2,20.41 5.82,20.41 5.69,20.53 4.42,20.53 4.29,20.66 4.29,20.91 4.42,21.04 5.94,21.04
GND on TOP (solid shape): 54.86,52.6 30.43,52.6 30.43,53.2 54.26,53.2 54.26,69.6 31.03,69.6 31.03,53.2 30.43,53.2 30.43,70.2 54.86,70.2
GND on TOP (solid shape): 21.76,21.8 22.26,21.8 22.45,21.61 22.45,21.1 22.26,20.91 20.61,20.91 20.55,20.98 20.55,21.61 20.74,21.8 21.63,21.8 21.63,22.37 21.76,22.37
GND on TOP (solid shape): 72.49,45.42 72.49,44.28 72.37,44.15 71.48,44.15 71.35,44.28 71.35,45.04 71.1,45.3 71.1,45.55 71.22,45.68 72.24,45.68
GND on TOP (solid shape): 100.74,68.42 106.27,68.42 106.36,68.33 106.36,67.08 106.02,66.73 100.04,66.73 99.96,66.81 99.96,68.72 99.99,68.74 100.42,68.74
GND on TOP (solid shape): 174.55,25.9 174.55,22.97 173.61,22.03 172.59,22.03 172.52,22.11 172.52,22.6 172.7,22.78 173.18,22.78 173.71,23.31 173.71,25.88 173.85,26.02 174.44,26.02
GND on TOP (solid shape): 74.52,30.18 74.52,29.68 74.4,29.55 74.14,29.55 73.25,28.66 67.22,28.66 67.03,28.85 67.03,30.06 67.22,30.25 74.46,30.25
GND on TOP (solid shape): 75.54,38.82 75.54,36.79 76.05,36.28 76.05,34.63 75.92,34.5 74.14,34.5 74.02,34.63 74.02,39.07 74.14,39.2 75.16,39.2
GND on TOP (solid shape): 196.7,54.19 196.7,53.3 196.44,53.04 195.68,53.04 195.56,52.92 195.56,52.41 195.43,52.28 194.03,52.28 193.9,52.41 193.9,54.06 194.07,54.22 194.07,54.6 194.16,54.7 196.19,54.7
GND on TOP (solid shape): 197.4,62.78 197.4,61.49 196.95,61.05 196.95,58.19 196.83,58.07 194.1,58.07 194.07,58.1 194.07,59.94 194.92,60.79 194.92,62.32 195.05,62.44 195.81,62.44 196.32,62.95 197.23,62.95
GND on TOP (solid shape): 78.33,23.2 78.33,19.77 78.08,19.52 75.16,19.52 74.91,19.77 74.91,23.07 75.16,23.33 78.21,23.33
GND on TOP (solid shape): 174.32,52.43 174.35,52.35 174.35,50.93 174.56,50.72 175.32,50.72 175.32,49.02 173.62,49.02 173.62,50.96 173.6,50.98 173.6,52.42 173.71,52.54 174.22,52.54
GND on TOP (solid shape): 197.55,26.89 197.55,26.48 197.71,26.32 197.71,26.31 197.73,26.2 197.79,26.11 197.79,25.7 197.68,25.59 196.77,25.59 196.67,25.7 195.94,25.7 195.85,25.78 195.85,26.86 196.05,27.07 197.38,27.07
GND on TOP (solid shape): 53.32,38.06 53.32,35.65 53.19,35.52 53.19,30.57 53.06,30.44 52.05,30.44 51.66,30.82 51.66,35.57 51.66,35.57 51.66,35.77 51.54,35.9 51.54,37.13 51.54,37.13 51.54,37.93 51.61,38.01 51.64,38.01 51.64,38.03 51.79,38.19 53.19,38.19
GND on TOP (solid shape): 64.87,43.27 69.19,43.27 69.44,43.01 69.44,39.84 69.32,39.71 66.65,39.71 66.02,40.34 65.63,40.34 65.38,40.09 64.87,40.09 62.97,42 62.97,43.52 63.09,43.65 64.49,43.65
GND on TOP (solid shape): 67.54,65.87 69.7,65.87 69.95,65.62 69.95,63.33 69.57,62.95 66.02,62.95 65.76,63.2 65.76,64.35 65.89,64.47 66.52,64.47 67.29,65.24 67.29,65.62 67.03,65.87 67.03,66 67.41,66
GND on TOP (solid shape): 92.43,21.8 94.59,21.8 94.72,21.68 94.72,20.02 93.98,19.29 92.92,19.29 92.18,20.02 91.8,20.02 91.16,19.39 89.38,19.39 89.13,19.64 89.13,21.55 89.36,21.78 90.78,21.78 91.44,22.44 91.8,22.44
GND on TOP (solid shape): 199.9,76.54 199.9,75.62 200.03,75.5 200.88,75.5 200.88,73.8 200.1,73.8 199.92,73.62 199.92,71.97 199.82,71.87 199.59,71.87 199.47,71.99 199.47,72.3 199.53,72.37 199.53,72.39 199.64,72.5 199.64,73.62 199.47,73.8 199.17,73.8 199.17,75.51 199.12,75.56 199.12,76.49 199.23,76.6 199.85,76.6
GND on TOP (solid shape): 19.28,57.74 19.28,56.85 19.19,56.76 18.41,56.76 18.08,56.76 17.63,56.31 17.63,55.85 17.58,55.8 17.58,54.42 17.48,54.31 16.36,54.31 16.29,54.38 16.29,55.77 16.23,55.84 16.23,56.92 16.27,56.96 17.29,56.96 18.17,57.84 19.18,57.84
GND on TOP (solid shape): 53.02,49.42 53.02,45.45 53.79,44.68 53.79,44.19 53.53,43.93 52.93,43.93 52.81,44.05 52.81,44.94 52.56,45.19 50.03,45.19 49.24,44.4 48.33,44.4 47.94,44.79 47.94,45.52 48.45,46.03 51.23,46.03 51.6,46.4 51.6,46.4 51.95,46.74 51.95,49.35 52.01,49.45 52.03,49.56 52.07,49.6 52.84,49.6
GND on TOP (solid shape): 173.08,77.56 173.08,76.93 173.04,76.9 173.04,75.97 173.13,75.88 174.02,75.88 174.02,74.18 173.25,74.18 173.04,73.97 173.04,73.02 173.2,72.86 173.2,72.6 173.08,72.48 172.82,72.48 172.7,72.6 172.7,72.89 172.79,72.99 172.79,74.08 172.69,74.18 172.32,74.18 172.32,76.03 171.86,76.49 171.86,77.52 171.96,77.62 173.01,77.62
GND on TOP (solid shape): 168.34,44.66 168.34,43.09 168.45,42.99 169.32,42.99 169.32,41.28 168.55,41.28 168.34,41.07 168.34,40 168.49,39.85 168.49,39.75 168.5,39.73 168.5,39.58 168.38,39.46 168.12,39.46 168,39.58 168,39.88 168.09,39.98 168.09,41.14 167.95,41.28 167.62,41.28 167.62,43.01 167.62,43.01 167.62,43.16 167.5,43.28 167.5,44.14 167.23,44.41 167.23,44.66 167.39,44.81 168.19,44.81
GND on TOP (solid shape): 126.08,68.86 126.18,68.84 126.29,68.86 126.3,68.86 127.24,68.86 127.33,68.76 127.33,68.46 127.11,68.24 127.11,68.19 127.06,68.14 127.06,67.74 127.18,67.63 127.28,67.63 127.33,67.58 127.33,67.12 127.32,67.1 125.27,67.1 125.22,67.15 125.22,67.55 125.22,67.58 125.21,67.64 125.93,68.37 125.93,68.73 126.06,68.86
GND on TOP (solid shape): 28.47,49.49 28.55,49.46 28.58,49.38 28.69,49.11 28.96,49.03 29.04,49.01 29.08,48.93 29.08,48.57 28.66,48.16 25.76,48.16 25.63,48.29 25.63,49.22 25.9,49.49
GND on TOP (solid shape): 133.38,64.03 133.38,63.52 133.33,63.46 132.56,63.46 132.27,63.16 132.08,62.9 132.18,62.6 132.18,61.43 132.44,61.17 133.2,61.17 133.33,61.05 133.33,60.66 133.2,60.54 128.54,60.54 128.5,60.58 128.5,61.12 128.55,61.17 129.39,61.17 129.64,61.43 129.64,63.08 129.39,63.33 128.75,63.33 128.63,63.46 128.63,63.97 128.75,64.09 133.33,64.09
GND on TOP (solid shape): 26.52,77.17 26.52,75.9 26.77,75.65 29.74,75.65 30.54,74.85 30.54,74.82 30.67,74.47 31.04,74.43 31.05,74.43 31.17,74.43 31.41,74.19 31.41,73.72 31.18,73.49 29.15,73.49 28.69,73.95 28.19,73.95 27.64,73.39 26.57,73.39 25.83,74.13 24.36,74.13 23.77,74.72 23.77,76.55 24.01,76.79 25.18,76.79 25.42,77.03 25.42,77.19 25.53,77.3 26.39,77.3
GND on TOP (solid shape): 168.38,37.04 168.38,33.99 168.76,33.61 169.24,33.61 169.55,33.31 169.55,31.15 169.52,31.12 168.71,31.12 168.61,31.22 168.61,32.98 168.48,33.11 168.01,33.11 167.87,33.44 167.52,33.48 167.51,33.49 167.49,33.49 167.23,33.74 167.23,34.1 167.03,34.3 166.93,34.3 166.73,34.5 166.73,34.91 166.4,35.24 166.4,36.71 166.65,36.97 166.85,37.05 166.93,37.25 166.98,37.3 168.12,37.3
GND on TOP (solid shape): 84.2,67.24 84.2,66.84 85.39,65.65 85.39,64.95 85.19,64.75 84.44,64.75 84.3,64.61 84.3,59.68 84.64,59.35 84.64,57.66 84.3,57.33 84.3,54.26 84.43,54.14 84.43,45.42 85.66,44.19 85.66,41.13 85.69,41.11 85.69,35.93 85.68,35.92 86.78,34.82 89.74,34.82 90.23,34.33 90.23,31.1 89.66,30.53 82.57,30.53 81.66,31.44 81.66,39.47 82.13,39.94 82.13,43.56 82.25,43.67 82.25,51.68 81.96,51.97 81.96,53.02 82.09,53.15 82.09,53.15 82.25,53.3 82.25,65.22 82.32,65.3 82.32,65.31 83.12,65.31 83.4,65.59 83.4,67.33 83.46,67.4 84.05,67.4
GND on TOP (solid shape): 46.4,42.5 46.58,42.45 46.77,42.5 49.95,42.5 50.29,42.17 50.29,41.73 50.2,41.64 49.61,41.64 49.51,41.74 48.36,41.74 48.11,41.49 48.11,38.19 48.74,37.55 48.74,37.04 48.62,36.92 48.11,36.92 47.85,37.17 46.43,37.17 46.16,37.33 45.88,37.19 45.75,37.19 45.2,37.73 45.2,37.75 44.96,37.99 44.63,37.92 44.59,37.91 44.56,37.93 44.3,38.19 44.3,39.46 43.79,39.96 43.79,40.34 44.43,40.98 44.43,42.31 44.61,42.5
GND on TOP (solid shape): 135.9,67.23 135.9,67.22 136.17,66.71 136.57,67.12 136.57,67.14 136.82,67.4 137.01,67.4 137.26,67.14 137.26,66.89 137.2,66.82 136.75,66.38 136.75,63.03 136.7,62.96 136.66,62.87 136.66,62.86 136.25,62.44 135.48,62.44 135.23,62.19 135.23,61.68 136.88,60.03 136.98,60.03 137.16,59.85 137.16,59.29 137.01,59.14 133.96,59.14 133.83,59.27 133.83,59.78 133.96,59.9 134.74,59.9 134.86,60.02 134.86,65.58 134.9,65.62 134.9,66.14 135.01,66.25 135.1,66.25 135.23,66.38 135.23,66.89 135.1,67.01 135.1,67.27 135.23,67.4 135.9,67.4
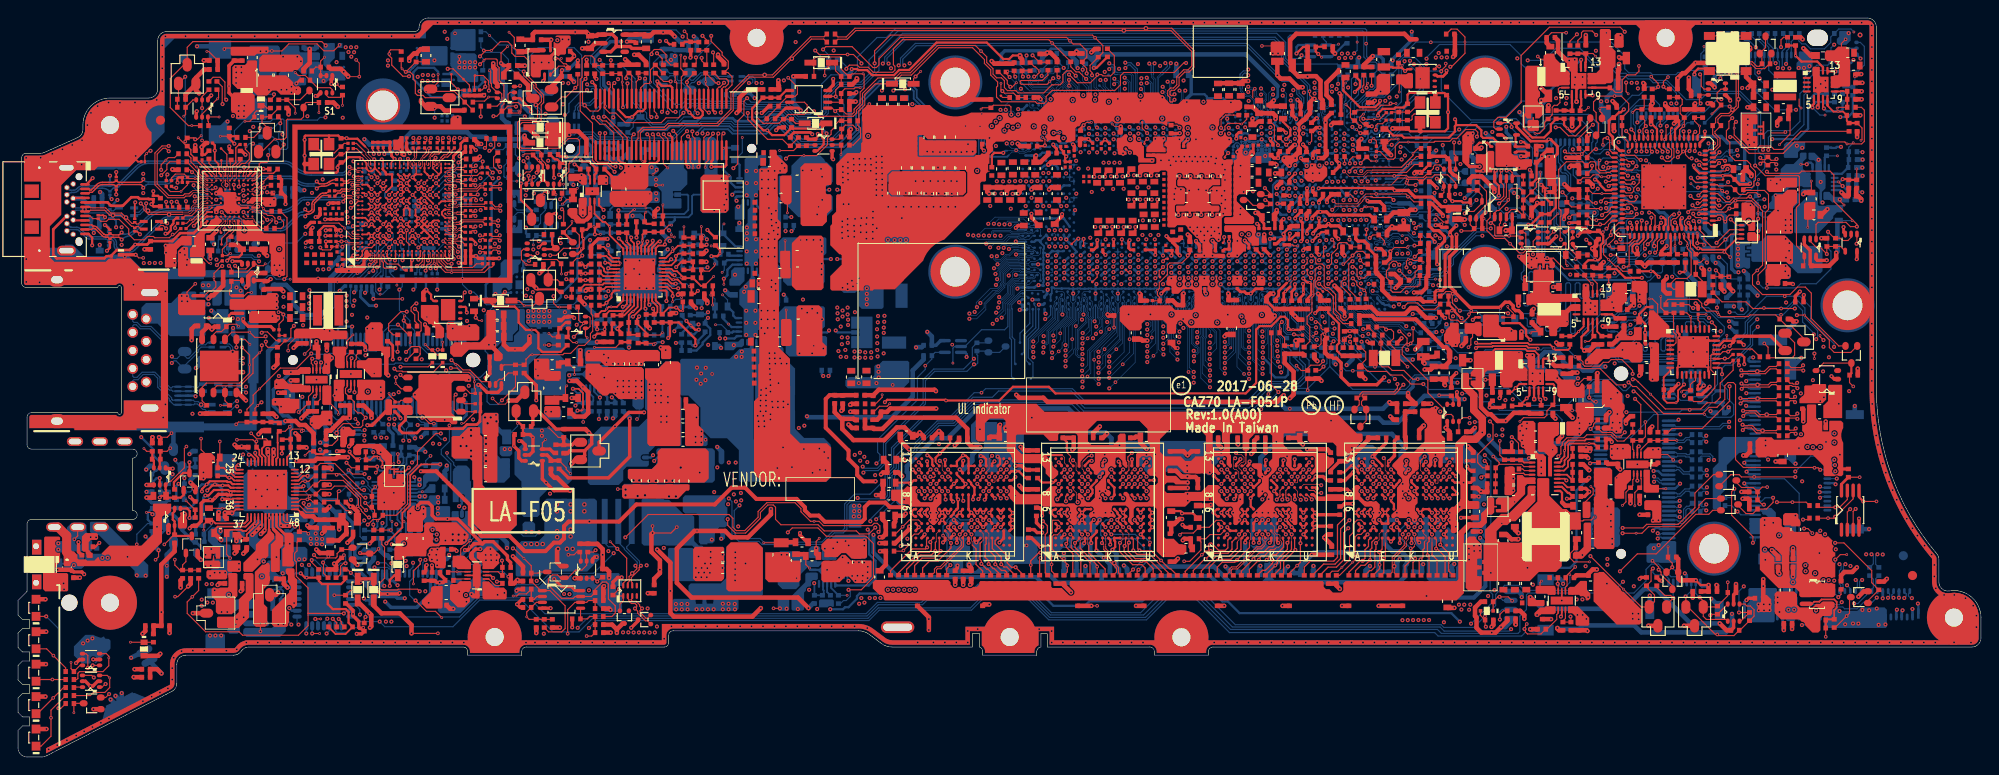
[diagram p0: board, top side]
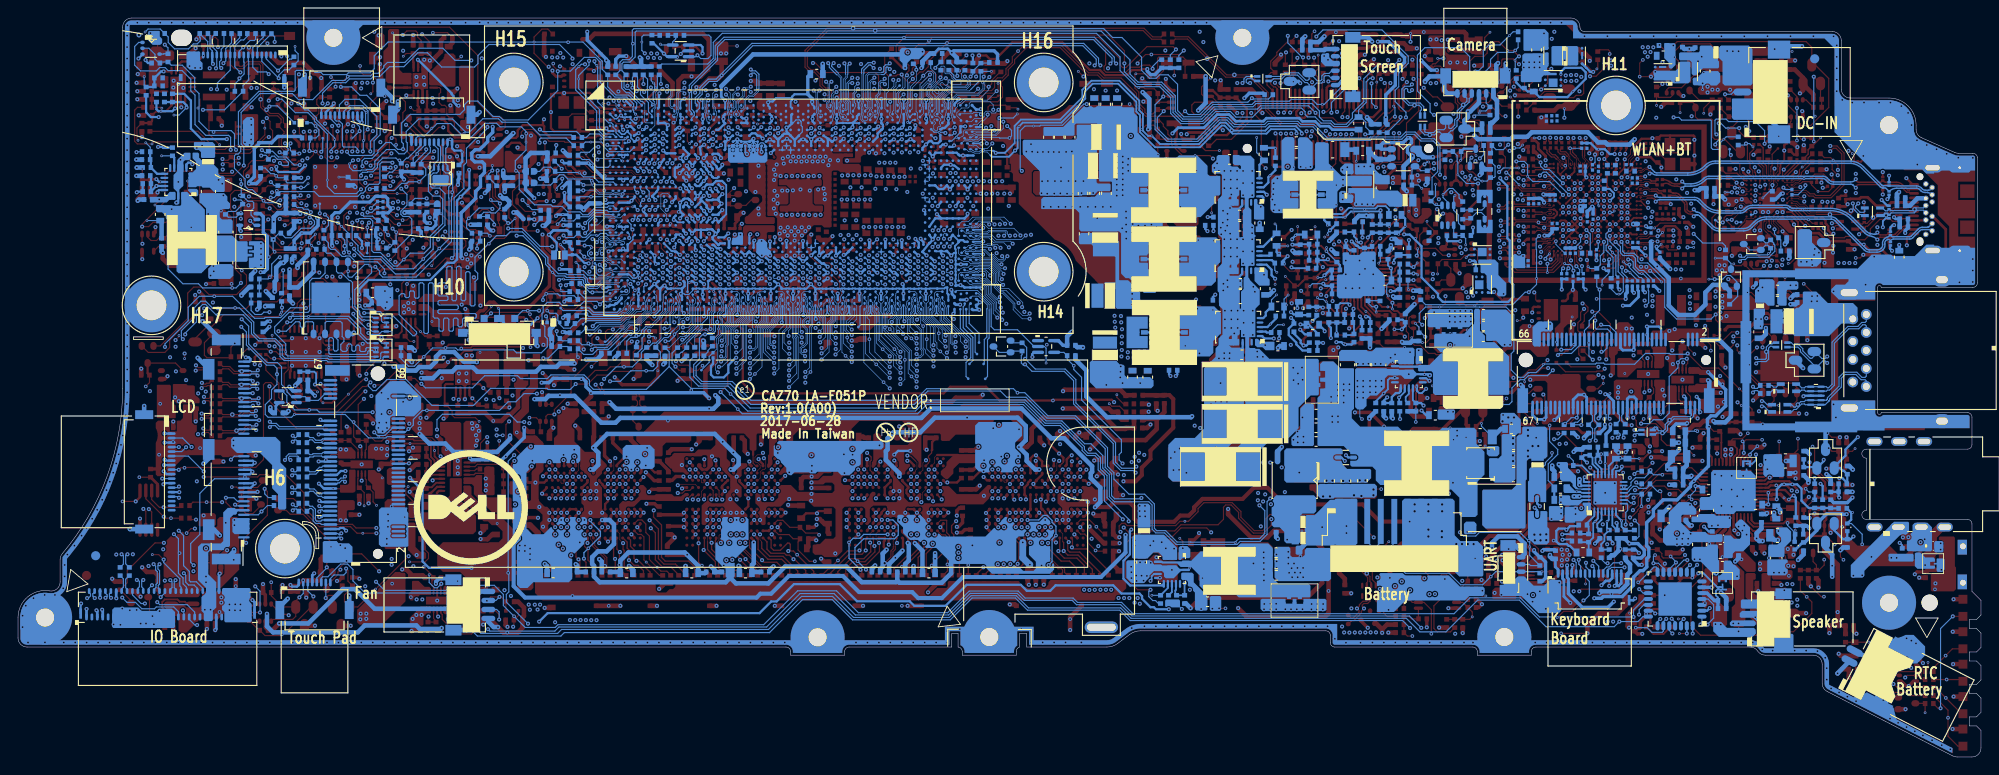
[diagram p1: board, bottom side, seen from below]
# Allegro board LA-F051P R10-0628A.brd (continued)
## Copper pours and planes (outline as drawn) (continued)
GND on TOP (solid shape): 22.59,63.19 22.59,63.16 22.71,63.04 22.71,62.82 22.84,62.7 24.11,62.7 24.23,62.57 24.23,62.32 24.37,62.18 24.68,62.18 24.7,62.15 24.7,61.8 24.69,61.75 24.64,61.69 24.51,61.73 24.38,61.69 24.28,61.69 24.23,61.64 24.23,61.45 24.26,61.42 24.35,61.27 24.52,61.22 24.53,61.22 24.68,61.07 25.61,61.07 25.63,61.05 25.63,60.92 25.53,60.82 24.84,60.82 24.61,60.59 24.61,60.36 24.54,60.28 23.22,60.28 22.93,60.56 22.93,60.57 22.75,60.77 22.49,60.79 22.45,60.79 22.43,60.77 22.27,60.6 22.25,60.37 22.26,60.34 22.2,60.28 21.82,60.28 21.74,60.36 21.75,60.39 21.76,60.53 21.69,60.65 21.69,60.79 22.06,61.16 22.43,61.16 22.44,61.17 22.71,61.17 22.84,61.3 22.84,62.06 22.58,62.32 21.95,62.32 21.82,62.44 21.82,62.72 21.85,62.79 21.92,62.82 22.16,62.92 22.28,63.16 22.28,63.2 22.58,63.2
GND on TOP (solid shape): outline of 249 points within 0.65,0.39 217.56,81.75
GND on BOTTOM (solid shape): 2.59,22.46 1.55,22.46 1.55,24.11 2.59,24.11
GND on BOTTOM (solid shape): 2.59,18.61 1.55,18.61 1.55,20.26 2.59,20.26
GND on BOTTOM (solid shape): 4.93,21.97 4.93,20.66 4.8,20.53 4.29,20.53 4.04,20.79 4.04,21.93 4.14,22.03 4.87,22.03
GND on BOTTOM (solid shape): 5.18,23.83 5.18,22.82 5.06,22.69 4.29,22.69 4.17,22.82 4.17,23.83 4.29,23.96 5.06,23.96
GND on BOTTOM (solid shape): 60.3,38.44 60.3,37.55 60.17,37.42 58.52,37.42 58.4,37.55 58.4,38.44 58.52,38.57 60.17,38.57
GND on BOTTOM (solid shape): 85.57,17.74 85.57,16.34 85.45,16.21 84.43,16.21 84.3,16.34 84.3,17.74 84.43,17.87 85.45,17.87
GND on BOTTOM (solid shape): 196.7,54.19 196.7,53.17 196.57,53.04 194.29,53.04 193.9,53.43 193.9,54.44 194.16,54.7 196.19,54.7
GND on BOTTOM (solid shape): 46.81,27.84 47.87,27.84 47.95,27.77 47.95,26.35 47.83,26.23 46.67,26.23 46.35,26.55 46.35,27.77 46.45,27.87 46.78,27.87
GND on BOTTOM (solid shape): 75.54,38.67 75.54,36.41 76.51,35.43 76.51,34.66 76.36,34.5 74.14,34.5 74.02,34.63 74.02,39.07 74.14,39.2 75.01,39.2
GND on BOTTOM (solid shape): 75.79,68.59 75.79,65.36 75.67,65.24 74.49,65.24 74.48,65.24 74.26,65.24 74.14,65.36 74.14,68.16 74.75,68.77 75.62,68.77
GND on BOTTOM (solid shape): 199.12,78.15 199.12,76.62 198.76,76.26 198.4,76.26 198.37,76.23 197.43,76.23 197.33,76.32 197.33,77.02 197.6,77.28 197.6,78.17 197.71,78.29 198.98,78.29
GND on BOTTOM (solid shape): 22.61,52.62 22.61,50.31 22.38,50.08 21.63,50.08 21.59,50.12 21.59,51.71 21.45,51.85 20.42,51.85 20.26,52.01 20.26,52.65 20.42,52.8 22.43,52.8
GND on BOTTOM (solid shape): 55.47,49.49 55.47,47.41 55.37,47.31 54.89,46.82 54.89,46.2 54.87,46.18 53.79,46.18 53.15,45.53 52.22,45.53 52.06,45.69 52.06,49.03 52.7,49.66 55.3,49.66
GND on BOTTOM (solid shape): 184,23.83 184,21.68 183.87,21.55 182.15,21.55 182.1,21.6 181.16,21.6 181.11,21.55 180.82,21.55 180.7,21.68 180.7,23.33 181.08,23.71 182.22,23.71 182.47,23.96 183.87,23.96
GND on BOTTOM (solid shape): 207.37,16.34 207.37,14.44 207.24,14.31 200.51,14.31 200.38,14.44 200.38,16.09 200.75,16.45 202.17,16.45 202.41,16.21 204.06,16.21 204.1,16.25 204.14,16.25 204.49,16.6 207.11,16.6
GND on BOTTOM (solid shape): 30.46,23.33 31.85,23.33 32.11,23.07 32.11,21.93 31.85,21.68 31.09,21.68 29.57,20.15 29.31,20.15 29.06,20.41 29.06,21.8 29.19,21.93 29.19,23.45 29.31,23.58 30.2,23.58
GND on BOTTOM (solid shape): 98.9,43.79 98.9,42.26 98.89,42.26 98.89,41.6 98.2,40.91 92.08,40.91 91.8,41.18 91.8,41.78 92.19,42.16 94.81,42.16 95.02,42.37 95.02,43.38 95.17,43.53 95.53,43.53 95.96,43.96 98.72,43.96
GND on BOTTOM (solid shape): 72.72,78.06 73.07,78.06 73.23,77.9 73.23,77.13 72.75,76.64 71.27,76.64 71.15,76.77 71.15,77.15 71.25,77.25 71.91,77.25 72.08,77.43 72.16,77.49 72.22,77.57 72.31,77.66 72.31,78.01 72.42,78.11 72.66,78.11
GND on BOTTOM (solid shape): 26.13,31.76 26.64,31.76 26.64,31.84 29.69,31.84 29.95,31.58 29.95,29.05 30.15,28.85 31.04,28.85 31.22,28.67 31.22,27.57 31.06,27.42 29.79,27.42 29.34,26.96 27.46,26.96 27.15,27.26 25.12,27.26 24.99,27.39 24.99,31.2 25.55,31.76 25.89,31.76 25.89,31.84 26.13,31.84
GND on BOTTOM (solid shape): 78.39,23.14 78.39,19.93 77.98,19.52 72.37,19.52 72.11,19.77 72.11,23.07 72.24,23.2 74.8,23.2 75.03,22.97 75.03,22.44 75.29,22.18 76.43,22.18 76.63,22.39 76.63,23.15 76.81,23.33 78.21,23.33
GND on BOTTOM (solid shape): 100.34,70.07 100.34,68.64 100.48,68.5 106.2,68.5 106.32,68.38 106.32,66.88 104.43,64.99 104.43,62.35 104.36,62.28 99.78,62.28 99.71,62.35 98.41,62.35 97.98,62.78 96.67,62.78 96.6,62.86 96.6,63.53 96.7,63.64 97.99,63.64 98.13,63.78 98.13,65.08 98.1,65.12 98.1,69.82 98.43,70.15 100.27,70.15
GND on BOTTOM (solid shape): 200.14,66.25 200.14,65.01 200.56,64.59 200.56,63.1 200.15,62.7 200.15,61.81 200.2,61.76 200.28,61.76 200.47,61.57 200.47,61.43 200.34,61.3 200.04,61.3 199.9,61.44 199.9,62.96 199.45,63.41 199.45,66.06 199.29,66.22 198.82,66.22 198.66,66.38 198.66,67 198.72,67.06 199.33,67.06
GND on BOTTOM (solid shape): 69.16,65.87 69.29,65.82 69.42,65.84 69.48,65.78 69.48,64.74 69.42,64.68 69.42,64.66 69.39,64.64 67.54,64.64 67.32,64.42 67.32,63.72 67.15,63.55 65.68,63.55 65.61,63.62 65.61,64.49 65.68,64.56 66.43,64.56 66.6,64.73 66.76,64.73 67.28,65.25 67.28,65.69 67.46,65.87
GND on BOTTOM (solid shape): 100.1,57.92 100.1,57.02 99.97,56.89 98.72,56.89 98.54,56.71 98.54,55.6 98.5,55.56 96.14,55.56 96.05,55.47 96.05,49.91 95.87,49.73 93.61,49.73 93.29,50.05 93.29,51.57 94.54,52.82 94.63,52.9 95.57,52.9 95.63,52.97 95.63,57.17 96.61,58.15 99.87,58.15
GND on BOTTOM (solid shape): 50.95,55.81 51.26,55.63 51.57,55.81 51.78,55.81 51.98,55.61 51.98,54.36 51.85,54.24 50.62,54.24 50.56,54.3 50.56,54.77 50.57,54.77 50.57,55.38 50.56,55.38 50.56,55.75 50.62,55.81
GND on BOTTOM (solid shape): 68.99,55.71 70.02,55.71 70.13,55.83 70.13,55.97 70.16,55.99 70.75,55.99 70.84,55.9 70.84,54.7 70.67,54.52 70.68,54.52 70.68,53.72 70.84,53.55 71.35,53.55 71.48,53.43 71.48,51.14 71.22,50.89 68.81,50.89 68.56,51.14 66.4,51.14 66.15,51.39 66.15,52.93 66.14,52.93 66.14,53.43 67.15,54.43 67.15,55.94 67.3,56.09 68.61,56.09
GND on BOTTOM (solid shape): 69.44,43.01 69.44,38.82 69.19,38.57 68.56,38.57 68.17,38.95 68.17,39.71 67.79,40.09 67.03,40.09 66.14,40.98 66.14,42 65.79,42.35 64.35,42.35 63.98,41.98 62.98,41.98 62.61,42.35 61.54,42.35 61.32,42.12 61.06,42.12 60.94,42.25 60.94,42.5 61.04,42.6 62.62,42.6 62.99,42.97 64.58,42.97 64.66,43.05 65.89,43.05 65.97,43.14 69.32,43.14
GND on BOTTOM (solid shape): 53.32,38.06 53.32,37.1 53.19,36.98 52.36,36.98 52.36,35.84 52.87,35.84 52.87,35.83 53.05,35.83 53.19,35.69 53.19,33.49 53.53,33.14 54.55,33.14 54.59,33.11 54.59,31.07 53.95,30.44 52.05,30.44 51.66,30.82 51.66,35.57 51.66,35.62 51.38,35.91 51.1,35.91 51.06,35.95 51.06,37.45 51.79,38.19 53.19,38.19
GND on BOTTOM (solid shape): 92.24,21.83 94.68,21.83 94.84,21.66 94.84,19.9 94.34,19.39 94.32,19.39 94.23,19.29 92.89,19.29 92.43,19.76 92.4,19.79 92.36,19.83 92.25,19.93 92.25,20.15 91.77,20.63 90.88,20.63 90.65,20.41 90.65,20.02 90.46,19.83 89.57,19.83 88.77,20.63 87.84,20.63 87.78,20.69 87.78,20.81 87.85,20.89 88.91,20.89 89.28,21.26 90.88,21.26 90.96,21.34 91.71,21.34 92.22,21.85
GND on BOTTOM (solid shape): 197.68,62.44 197.68,61.53 197.57,61.43 197.5,61.43 196.95,60.87 196.95,58.31 196.71,58.07 194.1,58.07 193.99,58.18 193.99,59.5 194.16,59.67 194.54,59.67 194.56,59.65 195.17,59.65 195.43,59.9 195.43,60.54 195.17,60.79 194.41,60.79 194.29,60.92 194.29,61.43 194.58,61.72 194.58,62.2 194.95,62.57 197.21,62.57 197.21,62.58 197.42,62.58 197.42,62.58 197.54,62.58
GND on BOTTOM (solid shape): 9.98,25.77 10,25.74 10.01,25.74 14.45,21.29 14.45,20.02 14.33,19.9 13.18,19.9 12.93,20.15 12.93,20.66 8.99,24.6 8.94,24.6 8.92,24.61 8.69,24.72 8.44,24.65 8.41,24.63 8.38,24.65 8.32,24.68 8.24,24.71 7.98,24.98 7.98,25.99 8.09,26.11 9.64,26.11
GND on BOTTOM (solid shape): 69.86,30.31 70.03,30.27 70.19,30.31 70.2,30.31 70.58,30.31 70.78,30.25 70.98,30.31 71.81,30.31 71.81,30.31 71.95,30.28 72.08,30.31 72.09,30.31 72.47,30.31 72.48,30.31 72.63,30.27 72.79,30.31 72.8,30.31 73.38,30.31 73.64,30.06 73.64,29.04 73.25,28.66 72.29,28.66 72.28,28.67 71.84,28.67 71.73,28.79 69.26,28.79 67.29,28.79 67.03,29.04 67.03,30.06 67.29,30.31 69.85,30.31
GND on BOTTOM (solid shape): 64.24,28.41 64.24,23.4 64.2,23.32 64.12,23.3 63.73,22.95 64.12,22.59 64.38,22.59 64.5,22.46 64.5,21.92 63.16,20.57 58.93,20.57 58.89,20.53 58.4,20.53 57.89,20.02 55.35,20.02 55.22,20.15 55.22,22.08 55.27,22.26 55.22,22.44 55.22,22.96 55.27,23.13 55.24,23.3 55.22,23.33 55.86,23.96 57.76,23.96 58.4,24.6 58.4,28.41 58.65,28.66 63.98,28.66
GND on BOTTOM (solid shape): 52.17,19.26 52.84,19.26 52.86,19.24 52.89,19.2 52.93,19.17 52.97,19.14 53.02,19.12 53.07,19.11 53.12,19.1 53.31,19.1 53.41,19.01 53.41,17.96 53.3,17.85 50.99,17.85 49.1,15.96 46.84,15.96 46.58,16.21 46.58,17.99 49.35,17.99 49.35,17.94 49.36,17.89 49.38,17.84 49.4,17.79 49.43,17.74 49.47,17.71 49.51,17.67 49.55,17.65 49.6,17.63 49.66,17.61 49.71,17.61 49.76,17.61 49.81,17.63 49.86,17.65 49.91,17.67 49.95,17.71 49.99,17.74 50.02,17.79 50.04,17.84 50.06,17.89 50.06,17.94 50.06,17.99 50.06,18.05 50.04,18.1 50.02,18.14 49.99,18.19 49.95,18.23 49.91,18.26 49.86,18.29 49.81,18.31 49.76,18.32 49.71,18.32 49.66,18.32 49.6,18.31 49.55,18.29 49.51,18.26 49.47,18.23 49.43,18.19 49.4,18.14 49.38,18.1 49.36,18.05 49.35,17.99 46.58,17.99 46.58,19.52 46.71,19.64 47.85,19.64 48.49,19.01 49.63,19.01 50.65,20.02 51.41,20.02
GND on BOTTOM (solid shape): 8.36,13.55 9.19,13.23 10.07,13.11 10.26,12.91 10.26,12.02 8.67,10.43 8.6,10.4 8.53,10.43 8.51,10.44 8.49,10.48 8.52,10.52 8.4,11.18 8.08,10.59 8.1,10.52 8.06,10.45 8.02,10.41 7.99,10.37 7.09,10.37 6.2,11.26 6.2,12.28 7.47,13.55
GND on BOTTOM (solid shape): 84.65,66.8 84.82,66.62 84.82,66.21 85.34,65.7 85.34,64.97 85.1,64.73 84.45,64.73 84.44,64.74 84.39,64.74 84.21,64.57 84.21,62.34 84.67,61.88 84.67,58.05 84.21,57.59 84.21,54.77 84.71,54.28 84.71,51.69 84.55,51.53 84.55,50.08 84.16,49.69 84.16,46.88 84.61,46.44 84.61,45.68 84.94,45.35 84.94,44.38 86.21,43.11 86.21,36.43 87.24,35.4 89.42,35.4 90.18,34.64 90.18,31.02 89.73,30.57 84.16,30.57 83.73,31 83.73,34.18 81.79,36.13 81.79,45.3 81.92,45.42 83.17,45.42 83.45,45.7 83.45,46.58 83.27,46.76 82.42,46.76 82.25,46.94 82.25,51.7 81.96,51.98 81.96,53.02 82.35,53.4 83.31,53.4 83.38,53.46 83.38,54.5 83.25,54.63 82.5,54.63 82.31,54.82 82.31,58.23 82.28,58.25 82.28,60.82 82.42,60.96 83.03,60.96 83.48,61.4 83.48,62.04 83.34,62.18 82.49,62.18 82.31,62.35 82.31,65.32 82.51,65.53 83.15,65.53 83.38,65.76 83.38,66.65 83.53,66.8 84.35,66.8
GND on BOTTOM (solid shape): 7.09,55.83 7.1,55.83 7.35,55.58 9.8,55.58 9.98,55.76 12.12,55.76 13.86,54.02 26.48,54.02 26.48,36.22 10.69,36.22 10.69,36.49 1.25,36.49 1.25,37.71 1.33,37.88 1.5,37.96 2.52,37.96 10.78,37.96 10.87,37.94 10.96,37.88 11.1,37.79 11.27,37.76 11.59,37.89 11.72,38.21 11.72,38.74 11.73,38.74 11.73,39.57 16.59,39.57 16.59,37.02 25.68,37.02 25.68,53.22 14.69,53.22 14.69,52.8 15.09,52.41 16.1,52.41 16.61,51.9 16.61,51.6 15.77,50.76 11.73,50.76 11.73,51.08 11.72,51.08 11.72,52.11 11.4,52.54 10.89,52.36 8.33,52.36 4.71,52.36 0.9,52.36 0.73,52.44 0.65,52.61 0.65,54.34 0.65,56.47 0.7,56.51 5.2,56.51 5.2,56.85 6.07,56.85
GND on BOTTOM (solid shape): outline of 201 points within 0.65,0.44 217.56,81.75
GND on IN1 (solid shape): 7.34,55.58 11.37,55.58 12.92,54.04 14.86,54.04 16.61,52.28 16.61,50.89 16.36,50.63 11.72,50.63 11.72,52.11 11.4,52.54 10.89,52.36 0.9,52.36 0.73,52.44 0.65,52.61 0.65,56.98 5.94,56.98
GND on IN1 (solid shape): 16.65,36.49 1.25,36.49 1.25,37.71 1.33,37.88 1.5,37.96 2.56,37.96 10.78,37.96 10.87,37.94 10.96,37.88 11.1,37.79 11.27,37.76 11.59,37.89 11.72,38.21 11.72,38.74 11.73,38.74 11.73,39.57 16.65,39.57
GND on IN1 (solid shape): outline of 187 points within 0.65,0.39 217.56,81.75
GND on IN2 (solid shape): 7.98,54.95 12.93,54.95 16,51.88 16.2,51.88 16.49,51.59 16.49,51.06 16.18,50.76 11.72,50.76 11.72,52.11 11.4,52.54 10.89,52.36 0.9,52.36 0.73,52.44 0.65,52.61 0.65,56.85 6.07,56.85
GND on IN2 (solid shape): 16.65,36.49 1.25,36.49 1.25,37.71 1.33,37.88 1.5,37.96 2.42,37.96 10.78,37.96 10.87,37.94 10.96,37.88 11.1,37.79 11.27,37.76 11.59,37.89 11.72,38.21 11.72,38.74 11.73,38.74 11.73,39.57 16.65,39.57
GND on IN2 (solid shape): outline of 193 points within 0.65,0.42 217.56,81.75
GND on IN3 (solid shape): 7.98,54.95 12.93,54.95 15.85,52.03 16.32,52.03 16.59,51.76 16.59,51.6 15.75,50.76 11.72,50.76 11.72,52.11 11.4,52.54 10.89,52.36 0.9,52.36 0.73,52.44 0.65,52.61 0.65,56.85 6.07,56.85
GND on IN3 (solid shape): 16.59,36.49 1.25,36.49 1.25,37.71 1.33,37.88 1.5,37.96 2.31,37.96 10.78,37.96 10.87,37.94 10.96,37.88 11.1,37.79 11.27,37.76 11.59,37.89 11.72,38.21 11.72,38.74 11.73,38.74 11.73,39.57 16.59,39.57
GND on IN3 (solid shape): outline of 189 points within 0.65,0.43 217.56,81.75
GND on IN4 (solid shape): 6.83,56.09 8.36,56.09 10.77,53.68 14.2,53.68 15.93,51.95 16.4,51.95 16.59,51.76 16.59,51.56 15.79,50.76 11.72,50.76 11.72,52.11 11.4,52.54 10.89,52.36 0.9,52.36 0.73,52.44 0.65,52.61 0.65,56.85 6.07,56.85
GND on IN4 (solid shape): 16.59,36.49 1.25,36.49 1.25,37.71 1.33,37.88 1.5,37.96 2.31,37.96 10.78,37.96 10.87,37.94 10.96,37.88 11.1,37.79 11.27,37.76 11.59,37.89 11.72,38.21 11.72,38.74 11.73,38.74 11.73,39.57 16.59,39.57
GND on IN4 (solid shape): outline of 186 points within 0.65,0.43 217.56,81.75
GND on TOP: 95.25,74.1 95.25,72.83 95.4,72.68 98.86,72.68 98.86,74.02 98.5,74.38 97.97,74.38 97.82,74.23 95.38,74.23
GND on TOP: 30.82,51.75 30.82,48.3 30.73,48.22 29.9,48.22 29.82,48.29 29.82,48.6 29.82,48.6 29.82,49.23 29.07,49.98 29.07,51.74 29.24,51.9 30.66,51.9
GND on TOP: 31.73,55.14 35.47,55.14 35.75,55.42 36.16,55.42 36.25,55.33 36.25,54.48 36.17,54.4 35.07,54.4 34.57,53.91 31.94,53.91 31.67,54.17 31.67,55.09
GND on TOP: 163.62,18.94 167.54,18.94 167.99,19.39 167.99,19.61 168.73,20.35 170.13,20.35 170.29,20.19 170.29,19.26 170.2,19.17 168.48,19.17 168.23,18.91 168.23,18.28 168.09,18.14 167.62,18.14 167.21,17.74 167.21,16.83 167.12,16.75 166.54,16.75 166.32,16.97 166.32,17.65 165.91,18.05 163.71,18.05 163.52,18.25 163.52,18.84
GND on TOP: outline of 137 points within 118.06,57.87 129.52,64.96
GND on TOP: 204.75,78.6 204.91,78.44 204.91,76.39 204.78,76.26 203.68,76.26 203.56,76.39 203.56,77.52 203.38,77.7 203.38,78.56 203.42,78.6
GND on TOP: 92.02,41.88 94.76,41.88 95.14,42.25 95.14,43.46 95.23,43.55 95.68,43.55 95.77,43.46 95.77,41.38 95.48,41.09 91.96,41.09 91.75,41.31 91.75,41.61
GND on TOP: 57.98,58.27 58.61,58.27 58.68,58.2 58.68,57.63 58.48,57.43 58.3,57.43 57.99,57.12 57.99,56.15 58.24,55.9 58.57,55.9 58.71,55.76 58.71,55.52 58.61,55.41 57.73,55.41 56.88,56.27 56.88,56.54 56.76,56.66 56.28,56.66 56.17,56.77 56.17,57.3 56.24,57.37 57.53,57.37 57.92,57.76 57.92,58.21
GND on TOP: 108.67,66.26 108.67,65.62 108.69,65.6 113.98,65.6 114.16,65.43 114.49,65.43 114.69,65.63 115.72,65.63 115.87,65.78 116.92,65.78 116.99,65.85 116.99,66.25 116.97,66.28 116.71,66.28 116.59,66.4 116.59,66.71 116.36,66.94 116.26,66.94 116.26,67.34 116.18,67.42 116,67.42 115.95,67.47 115.95,67.93 115.9,67.98 115.49,67.98 115.44,67.93 115.44,67.45 115.75,67.14 115.75,66.68 115.65,66.58 114.73,66.58 114.68,66.63 114.68,67.28 114.57,67.4 112.55,67.4 112.48,67.46 112.48,68.11 112.41,68.18 111.25,68.18 111.1,68.33 110.76,68.33 110.6,68.18 110.6,67.73 109.39,66.51 108.92,66.51
GND on BOTTOM: 199.44,75.84 201.92,75.84 202.08,75.68 202.08,74.32 202.51,73.9 202.82,73.9 202.89,73.82 202.89,73.42 202.78,73.3 201.33,73.3 201.18,73.46 201.18,73.89 201.04,74.02 199.25,74.02 199.08,74.19 199.08,75.48
GND on BOTTOM: 43.49,67.74 44.59,67.74 44.64,67.69 44.64,67.4 44.21,66.96 44.21,66.54 43.75,66.09 43.17,66.09 43.04,66.21 43.04,66.52 43.21,66.68 43.21,67.46
GND on BOTTOM: 180.57,42.09 180.62,42.27 180.57,42.46 180.57,43.39 180.82,43.65 183.62,43.65 183.77,43.8 184.32,43.8 184.46,43.66 184.46,42.81 184.49,42.77 184.4,42.54 184.51,42.32 184.51,41.37 184.51,41.37 184.53,41.2 184.63,41.06 184.63,40.85 184.46,40.68 184.43,40.7 184.2,40.72 184.01,40.6 180.82,40.6 180.57,40.85
GND on BOTTOM: 60.16,58.24 59.69,58.24 59.59,58.14 59.59,57.58 59.53,57.51 58.97,57.51 58.9,57.58 58.9,58.46 58.95,58.51 58.95,59.33 59.04,59.43 59.06,59.44 60.95,59.44 61.37,59.03 61.37,59.01 61.54,58.84 61.54,57.95 61.47,57.87 60.53,57.87
GND on BOTTOM: 15.98,55.52 15.85,55.65 15.85,58.26 15.93,58.33 17.72,58.33 18.26,57.79 18.26,56.92 16.87,55.52
GND on BOTTOM: 43.61,54.71 43.43,54.89 43.43,55.24 43.61,55.43 43.73,55.43 43.84,55.53 43.84,56.14 43.89,56.19 44.35,56.19 44.43,56.18 44.5,56.19 46.37,56.19 46.44,56.13 46.44,55.75 46.24,55.56 45.3,55.56 44.64,54.9 44.16,54.9 43.97,54.71
GND on BOTTOM: 46.89,71.43 46.86,71.41 46.86,71.01 46.94,70.94 48.46,70.94 48.67,70.74 48.97,70.74 49.09,70.85 49.09,71.33 48.98,71.43
GND on BOTTOM: 38.95,64 37.91,64 37.8,64.12 37.8,64.47 38.01,64.69 38.01,66.1 37.92,66.19 37.92,66.49 38.1,66.67 42.42,66.67 42.66,66.43 42.66,65.4 42.6,65.34 40.25,65.34 39.76,65.82 39.76,66 39.73,66.04 39.12,66.04 39.04,65.96 39.04,65.43 38.89,65.27 38.89,64.08 38.95,64.02
GND on BOTTOM: 43.93,63.9 42.47,63.9 42.22,64.16 42.22,64.55 42.79,65.12 42.79,65.25 42.96,65.43 43.41,65.43 43.6,65.62 43.6,65.74 43.69,65.83 44.13,65.83 44.2,65.77 44.2,64.17
GND on BOTTOM: 94.03,72.7 94.29,72.7 95.99,74.41 98.5,74.41 98.96,73.95 98.96,72.91 98.78,72.73 95.38,72.73 95.15,72.5 95.15,72.22 95.1,72.17 94.01,72.17 93.96,72.22 93.96,72.63
GND on GND1: 149.33,68.92 148.67,69.58 148.67,71.33 148.9,71.56 150.62,71.56 151.31,72.25 153.47,72.25 153.87,72.65 153.87,73.57 154.26,73.95 158.6,73.95 158.95,73.59 158.95,69.58 158.6,69.22 151.43,69.22 151.13,68.92
GND on GND1: 31.68,64.68 31.47,64.88 31.47,69.02 31.6,69.15 36.78,69.15 38.91,67.01 38.91,66.69 39.41,66.2 39.41,65.03 39.1,64.73 38.45,64.73 37.8,65.38 37.8,65.97 37.59,66.18 36.42,66.18 36.22,65.97 36.22,65.47 35.43,64.68
GND on GND1: outline of 166 points within 0.26,0.26 217.56,81.75 ; 9 cut-outs
GND on IN1: 10.12,57.07 9.86,57.33 7.27,57.33 6.85,57.75 6.85,63.76 6.85,63.76 7.21,63.93 7.4,64.3 7.4,64.31 8.1,65.01 13.93,65.01 14.6,64.34 14.6,61.64 14.58,61.62 14.54,61.61 14.51,61.63 14.26,61.78 13.99,61.7 13.92,61.67 13.85,61.7 13.26,61.43 13.85,61.16 13.92,61.18 13.99,61.16 14.19,61.07 14.4,61.12 14.47,61.14 14.53,61.1 14.56,61.07 14.6,61.04 14.6,58.47 13.2,57.07 11.88,57.07 11.8,57.12 11.8,57.22 11.84,57.5 11.68,57.72 11.63,57.81 11.68,57.89 11.5,58.56 11.32,57.89 11.37,57.81 11.32,57.72 11.15,57.5 11.2,57.22 11.2,57.12 11.11,57.07
GND on IN1: 32.18,58.72 32.08,58.62 31.72,58.62 31.62,58.72 31.62,62.56 31.52,62.66 31.52,63.02 31.58,63.08 31.58,64.25 32.35,65.02 32.35,66 33.02,66.67 42.43,66.67 42.67,66.43 42.67,66.26 42.5,66.1 41.54,66.1 41.41,65.97 41.41,62.4 41.9,61.91 42.05,61.91 42.1,61.86 42.1,60.97 41.85,60.71 40.97,60.71 40.86,60.6 40.86,60.07 40.23,59.44 39.6,59.44 39.51,59.36 39.51,59.05 39.29,58.84 38.56,58.84 38.33,59.06 38.33,59.37 38.19,59.51 32.86,59.51 32.18,58.83
GND on GND2: outline of 166 points within 0.26,0.26 217.56,81.75 ; 9 cut-outs
GND on IN3: outline of 583 points within 99.04,20.81 159.87,58.24
GND on IN3: 93.19,66.96 96.62,66.96 97.38,66.2 97.38,64.91 98.63,63.66 115.37,63.66 116.82,65.11 117.35,65.11 118.59,66.35 118.59,66.38 118.62,66.4 119.76,66.4 120.18,66.82 123.89,66.82 124.97,67.9 127.18,67.9 127.56,68.28 127.56,70.19 127.58,70.21 117.96,70.21 117.96,70.11 117.6,69.76 115.47,69.76 112.75,67.04 108.2,67.04 107.67,67.57 107.67,67.62 107.57,67.73 97.31,67.73 95.91,69.12 95.91,69.17 94.79,69.17 92.99,67.37 92.99,67.17
GND on VCC: 103.46,20.91 99.67,24.7 99.67,32.96 98.53,34.1 98.53,34.99 97.1,36.41 97.1,51.14 101.17,51.14 101.65,51.62 101.65,54.79 103.03,56.17 113.59,56.17 113.79,55.97 117.17,55.97 117.24,56.03 125.02,56.03 125.28,56.28 127.66,56.28 128.18,55.76 128.18,55 128.67,54.5 138.1,54.5 138.74,55.14 141.25,55.14 141.9,54.49 141.9,52.58 141.83,52.51 141.83,52.18 143.25,50.76 144.9,50.76 146.05,49.62 166.96,49.62 169.65,52.3 169.65,53.07 169.88,53.3 189.18,53.3 189.62,53.73 191.16,53.73 191.67,54.23 191.67,58.43 193.4,60.15 193.4,80.73 204.93,80.73 204.93,42 201.42,42 198.12,38.69 181.68,38.69 180.26,37.27 173.48,37.27 171.04,34.84 171.04,24.07 170.05,23.07 160.63,23.07 158.47,20.91 ; 1 cut-out
GND on VCC: 2.27,36.53 2.27,36.94 10.53,36.94 12,36.93 12.74,38.21 12.74,52.11 12,53.39 10.53,53.38 1.67,53.38 1.67,65.72 2.49,65.72 2.96,65.77 3.41,65.91 4.55,66.42 4.55,58.02 8.63,53.93 20.78,53.93 22.07,55.22 22.07,65 24.21,67.14 27.43,67.14 27.79,66.78 27.79,57.34 26.77,56.32 26.77,54.34 27.79,53.32 27.79,36.89 27.68,36.79 25.02,36.79 24.76,36.53 ; 1 cut-out
GND on VCC: 31.78,64.68 31.27,65.19 31.27,69.12 31.32,69.17 37.36,69.17 39.39,67.14 39.85,67.14 39.85,65.37 39.16,64.68 37.14,64.68 37.15,64.72 37.15,64.77 37.15,65.42 36.79,65.78 36.42,65.42 36.42,64.77 36.43,64.72 36.43,64.68
GND on IN4: outline of 102 points within 4.76,55.79 37.44,67.89
GND on IN4: 113.44,73.29 117.3,73.29 119.56,71.03 119.86,71.03 122.02,68.87 122.02,67.37 121.79,67.14 117.63,67.14 117.2,67.57 116.66,67.57 115.8,68.44 115.8,70.04 115.24,70.6 111.61,70.6 110.59,71.61 110.59,73.69 110.8,73.9 112.34,73.9 112.37,73.87 112.85,73.87
GND on GND3: outline of 166 points within 0.26,0.26 217.56,81.75 ; 10 cut-outs
GNDA_CHG on TOP (solid shape): 41.5,33.49 41.5,32.22 41.17,31.89 41.13,31.89 41.12,31.88 41.12,31.43 41.14,31.41 41.54,31.41 41.54,30.87 41.98,30.87 41.98,31.41 42.41,31.41 42.42,31.4 42.77,31.4 42.99,31.18 42.99,28.13 42.24,27.38 39.95,27.38 39.85,27.48 39.85,29.72 39.97,29.97 39.85,30.21 39.85,31.07 40.74,31.96 40.74,32.03 40.75,32.04 40.79,32.22 40.74,32.4 40.74,32.79 40.35,33.19 40.35,33.21 40.25,33.43 40.03,33.53 40.01,33.53 39.95,33.59 39.88,33.59 39.76,33.71 39.77,33.73 39.67,34.07 39.34,34.16 39.31,34.16 39.19,34.27 38.2,34.27 38.08,34.15 38.08,33.61 37.95,33.49 37.38,33.49 37.19,33.68 37.19,34.38 37.57,34.76 40.23,34.76
VCC0V9_LVR_OUT on BOTTOM: 40.36,62.8 40.28,62.87 40.28,63.13 40.4,63.24 40.59,63.24 40.81,63.46 40.81,63.84 39.97,64.68 39.12,64.68 39.07,64.73 39.07,65.29 39.14,65.36 39.14,65.88 39.18,65.92 39.57,65.92 39.64,65.86 39.64,65.67 40.15,65.16 42.65,65.16 42.67,65.13 42.67,64.75 42.58,64.66 42.27,64.66 42.1,64.5 42.1,63.46 42.06,63.41 41.66,63.41 41.05,62.8
VCC0V9_LVR_OUT on IN3: outline of 270 points within 29.54,58.23 41.94,65.72
VCC0V9_SVR on TOP: 31.22,48.45 31.22,52.05 31.23,52.07 33.88,52.07 34.01,51.94 34.01,48.33 34,48.33 34,48.08 33.73,47.81 32.56,47.81 32.28,48.09 31.32,48.09 31.19,48.22 31.19,48.42
VCC0V9_SVR on TOP: 36.38,59.03 36.3,59.11 36.3,59.97 36.23,60.04 33.9,60.04 33.87,60.07 33.87,60.55 33.63,60.79 33.63,61.06 33.78,61.21 33.99,61.21 33.99,61.2 34.05,61.14 36.23,61.14 36.61,60.76 36.61,60.76 36.67,60.68 36.74,60.62 36.75,60.62 36.89,60.48 36.89,59.91 36.88,59.85 36.89,59.8 36.89,59.15 36.77,59.03
VCC0V9_SVR on BOTTOM: outline of 89 points within 31.95,49.44 42.7,63.86
VCC0V9_SVR on IN2: outline of 87 points within 35.37,58.48 42.7,64.07
VCC0V9_SVR on IN4: outline of 121 points within 35.71,59.11 42.75,63.68
VCC3V3_TBT_LDO on TOP (solid shape): 41.5,39.57 41.5,39.1 41.53,39.07 43.54,39.07 43.79,38.82 43.79,38.06 43.66,37.93 42.77,37.93 42.14,38.57 42.14,38.62 42.06,38.69 41.63,38.69 41.63,38.69 41.58,38.69 41.5,38.62 41.5,38.06 41.38,37.93 40.87,37.93 40.74,38.06 40.74,39.54 40.91,39.71 41.36,39.71
VCC_3V3_PCIE on BOTTOM: 48.46,70.3 48.49,70.33 48.49,70.72 48.44,70.77 46.88,70.77 46.86,70.79 46.76,70.79 46.38,71.17 46.09,71.17 46.01,71.09 46.01,70.43 46.14,70.3
VCCIO_B+ on TOP (solid shape): 178.54,52.54 178.54,50.63 178.03,50.12 178.03,49.44 177.93,49.35 177.31,49.35 177.16,49.49 175.65,49.49 175.58,49.56 175.58,50.67 175.65,50.75 176.24,50.75 176.89,51.39 176.89,52.46 177.06,52.64 178.44,52.64
VCCIO_B+ on BOTTOM (solid shape): 178.28,52.16 178.28,50.89 178.18,50.78 178.18,50.78 178.03,50.63 178.03,50.09 177.97,50.03 177.58,50.03 177.11,49.56 176.72,49.56 176.17,50.1 176.17,52.1 176.26,52.19 176.56,52.1 176.82,52.28 178.16,52.28
VCCIO_LX on TOP (solid shape): 173.37,50.17 173.37,49.55 173.3,49.49 172.31,49.49 172.06,49.23 172.06,47.96 171.81,47.71 171.04,47.71 170.79,47.46 170.79,46.82 170.66,46.69 170.03,46.69 169.9,46.82 169.9,47.46 169.52,47.84 168.85,47.84 168.5,48.19 168.5,49.23 168.89,49.62 171.68,49.62 172.31,50.25 173.3,50.25
1.2_DDR_LX on TOP (solid shape): 169.9,30.82 169.9,29.02 171.4,27.52 171.83,27.52 172.19,27.16 173.35,27.16 173.41,27.1 173.41,25.31 173.33,25.23 172.36,25.23 171.86,24.72 167.31,24.72 166.98,25.05 166.98,26.76 168.58,28.36 168.58,30.86 168.67,30.95 169.77,30.95
+AC_IN on BOTTOM (solid shape): 48.47,78.08 50.68,78.08 50.9,77.86 50.9,76.2 51.07,76.03 51.07,74.99 50.97,74.89 48.87,74.89 48.74,75.02 48.74,75.4 48.49,75.65 47.09,75.65 47.09,75.9 47.75,75.9 47.8,75.95 47.8,75.96 47.85,76.01 48.14,76.3 47.97,76.67 47.97,78.12 48.02,78.18 48.38,78.18
+AC_IN on BOTTOM: 56.03,61.07 56.01,61.05 54.23,61.05 54.13,61.15 54.13,63.55 54.3,63.72 57.44,63.72 58.12,64.4 58.12,65.79 58.34,66.02 58.34,66.2 58.7,66.56 59.84,66.56 60,66.4 60,63.8 59.99,63.79 59.99,63.15 58.71,63.15 57.53,61.98 57.18,61.98 56.88,61.67 56.88,61.17 56.78,61.07
+AC_IN on IN3: 55.89,63.01 55.89,61.32 57.3,59.91 59.87,59.91 60,60.04 60,60.87 59.78,61.08 57.73,61.08 56.74,62.07 56.74,62.89 56.44,63.19 56.07,63.19
+AC_IN on IN4: 59.7,66.61 59.7,63.66 57.99,61.94 56.27,61.94 55.47,62.75 54.36,62.75 54.12,62.99 54.12,63.86 54.75,64.49 54.75,65.53 54.92,65.7 56.26,65.7 56.34,65.79 56.34,66.69 53.78,69.25 53.78,71.46 52.97,72.27 49.22,72.27 48.67,72.82 48.67,77.78 49.59,78.71 58.61,78.71 59.16,78.16 59.16,77.48 59.11,77.4 59.02,77.38 58.78,77.38 58.6,77.23 58.51,77.18 58.42,77.24 57.74,77.09 58.41,76.9 58.5,76.95 58.58,76.89 58.77,76.72 59.02,76.71 59.11,76.7 59.16,76.62 59.16,74.13 60.37,72.92 60.4,72.83 60.34,72.75 60.15,72.28 60.62,72.1 60.71,72.09 60.76,72 60.76,71.59 60.32,71.25 60.76,70.9 60.76,70.05 59.89,69.19 59.89,69.11 59.88,69.09 59.66,68.88 59.66,66.65
+DC_IN on TOP (solid shape): 31.6,77.56 31.6,76.79 30.96,76.16 30.93,76.18 30.68,76.22 30.5,76.06 30.49,76.03 26.9,76.03 26.77,76.16 26.77,77.56 27.15,77.94 31.22,77.94
+DC_IN on BOTTOM (solid shape): 31.22,78.83 31.22,78.32 31.34,78.19 33.38,78.19 33.5,78.06 33.5,77.43 33.38,77.3 32.31,77.3 32.11,77.1 32.11,75.81 31.95,75.65 31.62,75.65 30.86,76.41 29.19,76.41 29.06,76.54 29.06,77.17 29.19,77.3 29.19,77.5 29.19,77.5 29.19,78.19 29.95,78.95 31.09,78.95
+DC_IN_SS on BOTTOM (solid shape): 33.63,76.92 33.63,76.41 33.88,76.16 36.3,76.16 36.34,76.12 36.34,75.71 36.27,75.49 36.34,75.28 36.34,75.13 36.28,75.07 34.44,75.07 34.11,74.75 32.49,74.75 32.23,75 32.23,75.75 32.23,75.75 32.23,77.05 32.36,77.17 33.38,77.17
+DCIN_JACK on TOP (solid shape): 27.8,78.76 27.8,78.19 27.67,78.06 27.1,78.06 26.52,78.06 26.26,77.81 23.72,77.81 23.6,77.94 23.6,78.7 23.72,78.83 27.74,78.83
+DCIN_JACK on BOTTOM (solid shape): 29.06,78.72 29.06,77.56 28.68,77.17 28.68,74.76 28.42,74.51 26.65,74.51 26.63,74.52 25.54,74.52 25.35,74.71 25.35,78.53 25.77,78.95 28.83,78.95
+INV_PWR_SRC on TOP (solid shape): outline of 571 points within 193.27,17.74 201.65,26.63
+INV_PWR_SRC on BOTTOM (solid shape): 194.03,26.37 194.03,24.98 193.78,24.72 192.25,24.72 192.13,24.85 192.13,26.5 193.9,26.5
+LCDVDD on TOP (solid shape): outline of 425 points within 192.79,31.16 202.53,39.12
+LCDVDD on BOTTOM (solid shape): 194.16,35.26 194.16,34.38 193.52,33.74 191.66,33.74 191.44,33.82 191.22,33.74 190.97,33.74 189.61,32.38 189.61,29.82 188.96,29.17 188.96,27.61 188.8,27.44 188.2,27.44 188.05,27.59 188.05,32.04 188.69,32.68 188.69,34.96 189.25,35.52 193.9,35.52
+PBATT on BOTTOM (solid shape): 78.51,28.73 78.51,28.71 78.53,28.58 78.58,28.47 78.61,28.39 78.57,28.33 78.44,27.99 78.68,27.71 78.72,27.7 78.72,26.75 78.67,26.74 78.39,26.39 78.67,26.04 78.72,26.04 78.72,25.74 78.46,25.49 77.83,25.49 77.32,24.98 77.32,23.96 77.06,23.71 75.67,23.71 75.54,23.83 75.54,26.76 75.29,27.01 74.02,27.01 73.76,27.26 73.76,28.79 74.02,29.04 78.21,29.04
+PP_HV on TOP (solid shape): 26.89,62.12 28.56,62.12 28.68,62.01 28.68,61.2 28.53,61.05 27.44,61.05 26.87,61.61 26.32,61.61 26.1,61.4 25.45,61.4 25.37,61.45 25.36,61.54 25.38,61.58 25.39,61.62 25.49,61.72 25.51,61.72 25.68,61.78 25.76,61.94 25.97,62.15 26.85,62.15 26.86,62.15
+PP_HV on IN2: 25.95,61.07 25.95,61.86 26.2,62.11 26.65,62.11 26.79,61.97 28.69,61.97 28.77,61.88 28.77,61.12 28.5,60.84 26.18,60.84
+PWR_SRC_AC on BOTTOM (solid shape): 50.14,31.96 50.14,30.69 50.27,30.57 50.27,28.41 50.14,28.28 49.89,28.28 49.88,28.27 49.63,28.27 49.61,28.27 49.61,28.84 49.25,29.19 48.89,28.84 48.89,28.27 48.24,28.27 48.24,28.28 48.24,31.72 48.31,31.79 48.31,31.91 48.74,32.34 49.76,32.34
+RTCVCC on TOP (solid shape): 192.76,58.22 192.92,58.05 193.15,58.02 193.23,58 193.27,57.92 193.27,57.36 193.14,57.24 192,57.24 191.87,57.36 191.87,58.12 192,58.25 192.75,58.25
+RTCVCC on IN2 (solid shape): outline of 382 points within 140.18,48.98 144.5,56.85
+SDC_IN on TOP (solid shape): outline of 213 points within 41.76,21.88 49.99,26.05
+SDC_IN on BOTTOM (solid shape): 48.89,26.76 49.25,26.4 49.61,26.76 49.61,27.29 50.15,27.29 50.27,27.17 50.27,24.31 49.87,23.91 49.87,23.9 49.55,23.58 48.17,23.58 47.91,23.84 47.91,25.32 48.11,25.52 48.11,27.19 48.2,27.29 48.89,27.29
+SDC_IN on BOTTOM: 34.9,76.41 34.9,76.92 35.41,77.43 35.41,79.15 35.46,79.21 36.05,79.21 36.05,79.21 39.87,79.21 39.88,79.2 41.29,79.2 41.3,79.21 44.17,79.21 44.43,78.95 44.43,77.43 44.3,77.3 43.79,77.3 43.54,77.05 43.53,77.05 43.38,76.9 41.2,76.9 41.1,76.79 37.95,76.79 37.57,76.41
+SDC_IN on IN2: outline of 289 points within 11.89,14.44 37.82,79.23
+SDC_IN on IN3: outline of 133 points within 19.41,15.33 50.65,25.36
+VCHGR on TOP (solid shape): 76.64,33.9 76.64,30.9 76.18,30.44 68.17,30.44 67.67,30.95 67.67,31.84 67.79,31.96 70.33,31.96 70.96,32.59 70.96,33.88 71.32,34.25 76.3,34.25
+VCHGR on BOTTOM (solid shape): 77.32,33.99 77.32,32.36 77.24,32.14 77.32,31.91 77.32,30.69 77.06,30.44 73.43,30.44 68.17,30.44 67.67,30.95 67.67,31.84 67.79,31.96 70.33,31.96 70.82,32.44 70.82,32.58 70.91,32.7 70.94,32.85 70.97,32.88 71.53,32.88 71.88,33.23 71.53,33.59 70.82,33.59 70.82,34.07 71,34.25 77.06,34.25
+VREFCA on BOTTOM (solid shape): outline of 456 points within 136.75,19.77 140.44,26.63
+VREFCA on BOTTOM (solid shape): outline of 1091 points within 102.85,20.32 120.24,26.88
+VREFCA on IN2 (solid shape): outline of 397 points within 99.42,20.89 104.45,26.76
-DCIN_JACK on TOP (solid shape): 26.26,73.41 26.26,71.81 25.27,70.82 24.26,70.82 24.17,70.87 24.17,70.97 24.14,71.34 23.8,71.48 23.72,71.5 23.68,71.58 23.66,71.67 23.62,71.76 23.62,73.43 23.94,73.75 25.93,73.75
-DCIN_JACK on BOTTOM (solid shape): 27.57,73.07 27.64,73.01 27.64,70.9 27.43,70.7 24.35,70.7 24.16,70.89 24.16,70.94 24.16,70.96 24.21,71.14 24.16,71.31 24.16,72.97 24.27,73.08 27.57,73.08
B+ on TOP (solid shape): 178.16,80.1 178.16,78.83 178.03,78.7 177.27,78.7 177.14,78.83 177.14,80.1 177.39,80.35 177.9,80.35
B+ on TOP (solid shape): 73.51,43.65 73.51,34.63 73.38,34.5 70.08,34.5 69.83,34.76 69.83,41.75 69.57,42.01 69.57,43.08 69.63,43.14 71.09,43.14 71.86,43.9 73.25,43.9
B+ on TOP (solid shape): 174.85,39.07 174.85,37.24 174.64,37.02 174.64,36.89 174.5,36.75 174.48,36.75 174.24,36.65 174.13,36.41 174.13,36.39 173.38,35.64 171.89,35.64 171.81,35.72 171.81,37.14 171.91,37.25 172.64,37.25 172.95,37.55 172.95,38.19 172.82,38.31 172.82,39.2 172.95,39.33 174.6,39.33
B+ on TOP (solid shape): 180.06,52.84 180.18,52.82 180.3,52.84 180.31,52.84 180.57,52.84 180.82,52.59 180.82,51.55 180.7,51.42 180.7,50.35 180.52,50.17 180.26,50.17 180.24,50.21 180.04,50.4 179.76,50.39 179.73,50.38 179.68,50.43 179.68,51.44 179.55,51.57 179.17,51.57 179.05,51.7 179.05,52.71 179.17,52.84 180.05,52.84
B+ on TOP (solid shape): outline of 159 points within 194.92,13.8 201.57,18.37
B+ on BOTTOM (solid shape): 93.57,28 93.57,25.46 93.55,25.44 92.22,25.44 92.16,25.49 92.16,27.88 92.41,28.13 93.45,28.13
B+ on BOTTOM (solid shape): 198.3,68.18 198.3,67.52 198.12,67.34 197.74,67.34 197.51,67.12 197.51,66.56 197.43,66.48 196.04,66.48 195.94,66.58 195.94,67.95 196.22,68.23 198.25,68.23
B+ on BOTTOM (solid shape): 73.33,43.61 73.33,42.84 72.77,42.84 72.77,42.08 73.33,42.08 73.33,41.64 72.77,41.64 72.77,40.88 73.33,40.88 73.33,40.14 73.64,39.84 73.64,34.63 73.51,34.5 70.71,34.5 69.99,33.78 69.99,33.59 69.44,33.59 69.09,33.23 69.44,32.88 69.99,32.88 69.99,32.38 69.83,32.22 67.54,32.22 67.16,31.84 67.16,30.69 66.65,30.18 63.48,30.18 63.22,30.44 63.22,35.19 64.69,36.66 68.89,36.66 69.83,37.6 69.83,38.39 69.57,38.64 69.57,42.63 69.58,42.64 69.58,43.07 69.63,43.13 71.08,43.13 71.86,43.9 73.04,43.9
B+ on IN2 (solid shape): outline of 1011 points within 175.74,14.94 195.68,22.18
B+ on IN4 (solid shape): outline of 417 points within 92.61,15.8 163.42,18.42
B+ on BOTTOM: 55.05,51.19 55.01,51.24 54.97,51.28 54.97,51.46 54.97,51.5 54.97,51.59 54.97,51.64 54.97,53.18 54.97,53.22 54.98,53.31 55.09,53.43 56.52,53.43 56.69,53.6 56.69,55.91 57.68,56.9 58.06,56.9 58.52,57.36 59.13,57.36 59.14,57.37 59.42,57.37 59.59,57.54 61.37,57.54 61.37,57.55 61.69,57.86 61.69,59.09 60.71,60.07 60.71,60.76 60.97,61.02 61.49,61.02 62.1,61.63 62.1,62.34 62.36,62.59 63.34,62.59 63.73,62.2 63.73,59.58 64.05,59.27 64.05,58.34 63.91,58.2 63.82,58.2 63.33,58.26 63.26,57.77 63.28,57.7 63.24,57.63 63.12,57.36 63.25,57.09 63.25,57.06 63.07,56.88 63.07,56.88 62.76,56.57 62.35,56.71 62.15,56.33 62.15,55.78 61.89,55.52 61.89,53.42 59.48,51.01 59.05,51.01 58.76,50.71 55.52,50.71
B+ on IN2: outline of 84 points within 53.95,30.82 81.13,52.41
B+ on IN2: 173.71,35.52 173.08,35.52 172.7,35.9 172.7,37.36 172.85,37.65 172.7,37.94 172.7,38.82 173.53,39.66 173.53,44.43 173.84,44.74 173.86,44.74 174.04,44.84 174.14,45.02 174.14,45.04 175.16,46.06 177.78,46.06 178.03,46.31 178.03,46.95 177.83,47.15 177.83,49.58 178,49.75 178,50.79 179.37,52.15 179.52,52.16 180.57,52.16 181.33,51.39 181.33,45.25 180.4,44.33 176.94,44.33 176.88,44.27 176.87,44.27 176.26,43.65 176.23,43.66 175.82,43.5 175.87,43.07 175.87,40.79 175.71,40.63 175.71,38.15 175.71,38.15 175.71,37.64 174.81,36.74 174.81,36.62
B+ on IN3: 198.07,75.02 199.89,75.02 200.47,74.44 200.47,53.26 198.73,51.52 198.73,48.98 197.26,47.51 193.48,47.51 193.4,47.55 193.38,47.64 193.04,48.09 192.7,47.64 192.68,47.55 192.6,47.51 190.36,47.51 190.27,47.55 190.26,47.64 190,48.08 189.57,47.79 189.5,47.71 189.39,47.74 188.28,48.85 187.99,48.85 187.68,49.05 187.36,48.85 186.76,48.85 186.69,48.92 182.15,48.92 182.14,48.93 181.19,48.93 180.96,49.16 180.85,49.43 180.58,49.53 180.22,49.89 180.24,49.92 180.19,50.3 179.83,50.42 179.71,50.54 179.71,51.44 179.82,51.55 180.8,51.55 181.13,51.22 182.52,51.22 182.54,51.2 188.51,51.2 188.95,50.76 194.29,50.76 197.84,54.31 197.84,66.15 197.03,66.96 197.03,73.98
B+ on IN3: outline of 84 points within 159.61,15.83 176.63,37.87
B+ on IN3: 92.72,16.85 91.95,17.61 87.31,17.61 87.21,17.67 87.23,17.78 87.66,18.21 87.69,18.21 88.05,18.79 87.43,18.5 87.43,18.47 86.79,17.83 82.31,17.83 80.62,19.52 80.62,25.7 80.73,25.96 80.62,26.22 80.62,30.18 80.18,30.63 76.91,30.63 76.91,31 72.21,35.7 71.42,35.7 69.44,37.68 69.44,37.83 69.46,37.86 69.49,37.88 69.83,38.24 69.49,38.59 69.46,38.61 69.44,38.64 69.44,39.63 69.55,39.88 69.46,40.13 69.44,40.15 69.44,40.22 69.46,40.24 69.55,40.48 69.44,40.72 69.44,40.86 69.55,41.11 69.44,41.36 69.44,41.49 69.53,41.64 69.54,41.81 69.54,41.83 69.57,41.87 81.33,41.87 81.33,41.84 81.61,41.56 81.61,36.85 82.08,36.38 85.73,36.38 87.57,34.54 89.11,34.54 89.3,34.34 89.3,34.01 89.34,34.04 92.17,31.21 92.17,31.18 92.19,31.19 93.45,29.93 93.45,28.15 93.57,28.03 93.57,26.45 93.45,26.32 93.45,26.32 93.24,26.11 93.24,23.34 95.99,20.59 95.99,17.48 95.73,17.23 94.84,17.23 94.46,16.85
B+ on GND3: 166.07,14.44 165.56,14.94 100.92,14.94 99.65,16.21 93.68,16.21 93.19,16.7 93.19,18.01 94.44,19.26 99.82,19.26 101.09,17.99 115.9,17.99 116.41,18.5 117.09,18.5 117.6,17.99 163.19,17.99 163.45,17.74 164.16,17.74 164.42,17.99 174.75,17.99 175.11,17.63 175.11,15.56 174.49,14.94 166.75,14.94 166.24,14.44
BATBTN# on TOP (solid shape): 4.67,24.34 4.67,24.15 4.64,24.07 4.55,24.05 4.15,23.87 4.24,23.44 4.28,23.36 4.24,23.28 4.16,22.85 4.55,22.67 4.64,22.65 4.67,22.57 4.67,21.68 4.29,21.29 4.29,21.11 4.04,20.74 4.37,20.4 5.44,20.4 5.56,20.28 5.56,18.5 5.44,18.37 3.02,18.37 2.77,18.63 2.77,21.04 2.9,21.17 2.9,24.34 3.02,24.47 4.55,24.47
BQ24777_REGN on BOTTOM (solid shape): 47.09,32.6 47.09,32.34 46.71,31.96 46.71,30.82 46.46,30.57 45.57,30.57 45.31,30.31 45.31,30.06 44.95,29.69 44.92,29.7 44.83,29.71 44.73,29.68 44.72,29.68 44.37,29.68 44.31,29.61 43.36,29.61 43.31,29.66 43.31,29.77 43.35,29.81 44.19,29.81 44.2,29.8 44.66,29.8 44.67,29.81 44.69,29.81 44.93,30.06 44.93,30.08 44.93,31 44.93,31 44.93,31.2 45.82,32.09 45.82,32.6 45.95,32.72 46.97,32.72
CHAGER_SRC on TOP (solid shape): 51.28,36.53 51.28,35.77 51.54,35.52 51.54,30.18 52.05,29.68 55.22,29.68 55.35,29.55 55.35,25.74 54.59,24.98 51.49,24.98 50.52,25.95 50.52,30.69 50.39,30.82 50.39,32.85 50.14,33.11 48.36,33.11 48.11,33.36 48.11,35.49 48.24,35.62 49,35.62 49.96,36.58 51.23,36.58
CHAGER_SRC on BOTTOM (solid shape): 50.9,36.53 50.9,35.9 51.03,35.77 51.28,35.77 51.54,35.52 51.54,30.18 52.05,29.68 55.22,29.68 55.35,29.55 55.35,25.74 54.95,25.35 51.31,25.35 51.3,25.34 50.68,25.34 50.52,25.5 50.52,30.69 50.39,30.82 50.39,32.85 50.14,33.11 48.36,33.11 48.11,33.36 48.11,36.41 48.36,36.66 50.78,36.66
CHG_BTS on BOTTOM (solid shape): 46.33,30.18 46.33,29.42 46.2,29.3 44.43,29.3 44.33,29.2 44.05,29.2 44.05,29.2 43.37,29.2 43.3,29.27 43.3,29.36 43.37,29.42 44.3,29.42 44.43,29.55 45.06,29.55 45.63,30.12 45.63,30.25 46.27,30.25
CHG_LGATE on BOTTOM (solid shape): 54.84,34.38 54.84,33.61 54.59,33.36 53.7,33.36 53.44,33.61 53.44,34.38 53.57,34.5 54.71,34.5
CHG_LGATE on BOTTOM (solid shape): 44.81,30.95 44.81,30.13 44.6,29.93 44.25,29.93 44.19,30 43.62,30 43.61,29.99 43.31,29.99 43.28,30.02 43.28,30.18 43.32,30.22 44.21,30.22 44.3,30.31 44.3,30.41 44.3,30.42 44.32,30.51 44.3,30.61 44.3,30.62 44.3,30.92 44.31,30.96 44.43,31.07 44.68,31.07
CHG_LGATE on IN1 (solid shape): 54.84,34.25 54.84,32.98 54.71,32.85 53.95,32.85 53.57,33.23 53.57,34.38 53.7,34.5 54.59,34.5
CHG_LGATE on IN1 (solid shape): 45.95,31.33 45.95,31.07 45.57,30.69 44.93,30.69 44.81,30.57 44.81,30.06 44.68,29.93 44.43,29.93 44.3,30.06 44.3,30.91 44.3,30.92 44.32,31.04 44.3,31.17 44.29,31.2 44.51,31.41 44.54,31.39 44.82,31.37 45.02,31.55 45.04,31.58 45.7,31.58
CHG_SW on BOTTOM (solid shape): 46.84,28.91 46.84,28.08 46.76,28 46.4,28 46.3,27.9 46.13,27.9 45.09,27.9 45,27.91 44.9,27.9 44.68,27.9 44.17,28.41 43.36,28.41 43.31,28.46 43.31,28.56 43.36,28.61 44.34,28.61 44.43,28.53 45.44,28.53 45.57,28.66 45.57,28.91 45.7,29.04 46.71,29.04
CHG_SW on BOTTOM (solid shape): 61.44,34.88 61.44,32.89 61.05,32.53 61.44,32.18 61.44,30.69 60.43,29.68 58.78,29.68 57.89,28.79 57.89,26.88 57.63,26.63 56.11,26.63 55.86,26.88 55.86,30.57 55.09,31.33 55.09,33.87 55.98,34.76 55.98,36.28 56.24,36.53 59.79,36.53
CHG_SW on IN1 (solid shape): 58.65,36.27 58.65,34.76 58.52,34.63 57.89,34.63 57.63,34.88 57.63,36.25 57.78,36.4 58.53,36.4
CHG_SW on IN1 (solid shape): 47.73,28.79 47.73,28.15 47.47,27.9 46.8,27.9 46.58,27.97 46.36,27.9 46.33,27.9 46.08,28.15 46.08,28.91 46.2,29.04 47.47,29.04
CHG_UGATE on BOTTOM (solid shape): 57.38,25.87 57.38,24.85 57.25,24.72 56.13,24.72 55.98,24.87 55.98,25.87 56.24,26.12 57.13,26.12
CHG_UGATE on BOTTOM (solid shape): 44.76,29.17 44.85,29.15 44.95,29.17 44.95,29.17 45.31,29.17 45.44,29.04 45.44,28.79 45.31,28.66 44.48,28.66 44.35,28.79 43.35,28.79 43.31,28.83 43.31,28.99 43.33,29.02 44.3,29.02 44.36,29.07 44.38,29.07 44.48,29.17 44.76,29.17
CHG_UGATE on IN4 (solid shape): 57.38,25.49 57.38,24.85 57.25,24.72 54.83,24.72 54.5,25.05 54.5,25.76 54.82,26.08 56.79,26.08
CHG_UGATE on IN4 (solid shape): 46.46,30.18 46.46,29.42 46.2,29.17 45.7,29.17 45.44,28.91 45.44,28.79 45.31,28.66 44.43,28.66 44.3,28.79 44.3,29.3 45.31,30.31 46.33,30.31
CHG_VCC on TOP (solid shape): 44.03,27.78 44.03,27.77 44.33,27.26 44.68,27.74 44.67,27.77 44.8,27.9 45.06,27.9 45.31,27.64 45.31,26.63 44.93,26.25 44.93,25.1 44.81,24.98 43.28,24.98 43.16,25.1 43.16,27.26 43.79,27.9 44.03,27.9
CHG_VCC on BOTTOM (solid shape): 44.2,28.19 44.2,27.94 44.18,27.31 44.7,27.66 44.73,27.74 44.8,27.77 46.08,27.77 46.2,27.64 46.2,26.12 46.08,25.99 45.01,25.99 45.01,26.15 44.27,26.15 43.28,27.14 43.28,28.15 43.35,28.22 44.17,28.22
CPU_B+ on BOTTOM (solid shape): 83.02,66.76 83.02,65.87 82.82,65.67 82.23,65.67 82.12,65.55 82.12,62.12 82.09,62.1 81.75,62.1 81.7,62.05 81.7,60.85 81.9,60.65 81.9,57.69 82.11,57.49 82.11,54.53 82.09,54.52 81.66,54.52 81.64,54.49 81.64,53.35 81.82,53.17 81.82,51.93 82.11,51.64 82.11,46.62 82.08,46.59 81.65,46.59 81.64,46.58 81.64,35.23 82.83,34.03 82.83,30.9 82.47,30.54 80.11,30.54 79.99,30.67 79.99,34.04 78.66,35.37 76.85,35.37 75.72,36.5 75.72,38.77 74.37,40.12 73.58,40.12 73.47,40.23 73.47,44.05 73.61,44.19 78.97,44.19 80.07,45.3 80.48,45.3 80.57,45.39 81.13,45.39 81.2,45.46 81.2,46.52 81.14,46.58 80.53,46.58 80.51,46.61 80.51,49.74 80.03,50.22 80.03,51.84 81.18,52.99 81.18,53.11 81.29,53.22 81.29,54.42 81.18,54.53 80.65,54.53 80.61,54.56 80.61,57.64 80.48,57.77 80.48,57.86 80.64,58.02 80.64,58.94 80.91,59.21 80.95,59.25 80.95,60.71 81.26,61.02 81.26,61.93 81.14,62.05 80.71,62.05 80.62,62.14 80.62,66.32 81.04,66.73 82.23,66.73 82.31,66.81 82.97,66.81
CPU_B+ on TOP: 74.19,44.55 77.76,44.55 79.11,45.89 79.11,63.41 80.35,64.65 80.35,65.69 80.37,65.71 80.37,66.43 80.51,66.57 81.78,66.57 82.07,66.86 82.07,67.09 82.4,67.42 82.96,67.42 83.07,67.31 83.07,65.6 82.96,65.49 82.28,65.49 82.11,65.31 82.11,57.3 82.1,57.29 82.14,57.25 82.14,55.22 82.07,55.14 82.07,53.4 81.8,53.13 81.8,51.85 82.07,51.57 82.07,43.68 82,43.61 82,40.08 80.53,38.62 80.53,36.29 80.28,36.04 77.61,36.04 77.55,36.1 77.55,37.83 76.8,38.58 76.38,38.58 73.71,41.25 73.71,44.07
CPU_B+ on IN1: 75.51,40.55 74.85,41.21 74.85,43.42 75.31,43.87 78.64,43.87 80.42,45.65 80.42,58.4 80.57,58.56 80.57,58.84 80.42,58.99 80.42,65.03 80.77,65.39 84.13,65.39 84.49,65.02 84.49,61.07 84.83,60.73 84.81,60.71 84.81,51.96 84.46,51.62 84.51,51.57 84.51,41.92 83.13,40.55 ; 1 cut-out
GT_SNUB on TOP (solid shape): 85.85,48.41 85.85,45.78 85.67,45.6 84.8,45.6 84.67,45.73 84.67,48.5 84.77,48.6 85.66,48.6
GT_SW on TOP (solid shape): 89.26,49.74 89.26,46.03 89.72,45.57 89.72,44.68 89.55,44.51 86.53,44.51 86.37,44.66 86.37,49.91 86.59,50.12 88.88,50.12
GT_SW on BOTTOM (solid shape): 89.54,49.84 89.54,47.77 89.28,47.52 87.91,47.52 87.85,47.46 87.85,46.78 87.92,46.71 89.61,46.71 89.78,46.54 89.78,44.7 89.51,44.43 85.59,44.43 85.18,44.84 85.18,46.16 84.33,47.01 84.33,49.26 85.08,50.01 89.37,50.01
GT_SW on IN1 (solid shape): 89.51,49.36 89.51,45.04 88.75,44.28 85.83,44.28 85.19,44.92 85.19,48.47 86.72,50 88.88,50
IA_SNUB1 on TOP (solid shape): 85.84,64.39 85.84,61.57 85.6,61.32 85.08,61.32 84.58,61.82 84.58,64.36 84.76,64.54 85.69,64.54
IA_SNUB2 on TOP (solid shape): 85.67,56.11 85.67,54.3 85.74,54.24 85.74,53.22 85.62,53.11 84.77,53.11 84.58,53.3 84.58,56.15 84.6,56.17 85.62,56.17
IA_SW1 on TOP (solid shape): 90.27,65.36 90.27,63.59 90.15,63.46 89.76,63.46 89.64,63.33 89.64,62.57 89.76,62.44 90.15,62.44 90.27,62.32 90.27,60.79 89.76,60.28 89.76,59.41 89.26,58.91 87.05,58.91 86.82,59.14 86.82,65.43 87.27,65.89 89.74,65.89
IA_SW1 on BOTTOM (solid shape): 89.49,66.27 89.49,66.26 89.59,66.08 89.77,65.98 89.79,65.98 90.4,65.36 90.4,63.84 89.87,63.31 87.94,63.31 87.92,63.29 87.92,62.52 87.95,62.49 88.82,62.49 88.88,62.44 90.15,62.44 90.4,62.19 90.4,60.66 89.64,59.9 86.59,59.9 85.07,61.42 85.07,62.12 84.9,62.29 84.54,62.29 84.4,62.43 84.4,64.43 84.47,64.49 84.7,64.49 84.77,64.51 84.83,64.48 84.85,64.47 85.59,64.47 85.81,64.69 85.81,65.6 86.97,66.76 89,66.76
IA_SW1 on IN1 (solid shape): 89.51,65.36 89.51,60.28 89.13,59.9 86.84,59.9 85.07,61.68 85.07,63.97 86.72,65.62 89.26,65.62
IA_SW2 on TOP (solid shape): 89.38,57.62 89.38,52.05 89.13,51.8 86.34,51.8 85.87,52.27 85.87,57.02 86.72,57.87 89.13,57.87
IA_SW2 on BOTTOM (solid shape): 89.7,57.53 89.7,55.9 89.46,55.66 87.95,55.66 87.9,55.61 87.9,54.89 87.94,54.85 89.31,54.85 89.51,54.64 89.51,52.7 89.1,52.29 85.38,52.29 84.89,52.79 84.89,54.43 84.4,54.91 84.4,57.21 84.86,57.67 89.56,57.67
IA_SW2 on IN1 (solid shape): 89.38,57.36 89.38,54.31 89.4,54.3 89.4,52.08 89.12,51.79 86.05,51.79 85.54,52.3 85.54,56.57 86.59,57.62 89.13,57.62
LDO_EN on TOP (solid shape): 61.32,70.21 61.32,69.12 61.3,69.12 59.92,67.74 58.76,67.74 58.5,68 58.5,70.28 58.63,70.41 61.12,70.41
PBATT+_C on BOTTOM (solid shape): 71.72,28.55 72.14,28.55 72.18,28.54 72.24,28.53 73.93,26.84 74.86,26.84 75.03,26.66 75.03,23.96 75.54,23.45 75.92,23.45 76.05,23.33 76.05,22.56 75.92,22.44 75.41,22.44 75.29,22.56 75.29,22.97 74.8,23.45 71.9,23.45 71.65,23.56 71.4,23.45 69.44,23.45 69.19,23.71 69.19,28.53 69.32,28.66 71.6,28.66
PD_SENSEN on TOP: 25.45,60.21 26.68,60.21 27.37,59.52 27.37,59.2 27.26,59.09 26.96,59.09 26.4,59.65 26.4,59.66 26.23,59.84 25.44,59.84 25.36,59.92 25.36,60.12
PRIM_CORE_B+ on TOP (solid shape): 203.21,78.52 203.21,77.46 203.31,77.36 203.31,74.51 203.18,74.38 202.23,74.38 202.12,74.27 201.18,74.27 201.13,74.32 201.13,75.51 201.18,75.56 201.2,75.55 201.37,75.56 201.51,75.65 201.91,75.65 202.03,75.78 202.03,76.59 201.95,76.67 201.89,76.75 201.81,76.81 201.41,77.21 200.74,77.21 200.48,77.47 200.48,78.22 200.69,78.42 201.54,78.42 201.96,78.83 202.9,78.83
PRIM_CORE_LX on TOP: 194.79,71.46 194.67,71.59 194.67,73.62 195.07,74.02 196.72,74.02 197.72,75.02 198.85,75.02 198.92,74.95 198.92,74.34 198.84,74.27 197.98,74.27 197.71,74 197.71,72.86 197.46,72.6 196.01,72.6 195.56,72.15 195.56,71.59 195.43,71.46
RING2 on TOP (solid shape): 28.59,34.29 28.59,33.35 28.38,33.14 28.38,32.34 28.32,32.27 28.2,32.27 28.2,32.28 28.1,32.38 28.1,33.42 28.1,33.43 28.12,33.55 28.1,33.66 28.1,33.67 28.1,34.25 28.21,34.36 28.52,34.36
RING2 on TOP (solid shape): 8.87,24.72 8.87,24.22 8.74,24.09 8.1,24.09 7.85,23.83 7.85,23.07 7.85,23.07 7.85,22.99 8.19,22.66 8.25,22.66 8.28,22.63 8.28,22.15 8.22,22.09 7.69,22.09 7.6,22.18 7.6,22.44 7.49,22.54 7.49,22.77 7.26,22.77 7.09,22.95 7.09,24.47 7.47,24.85 8.74,24.85
RING2 on IN2 (solid shape): outline of 775 points within 7.72,22.87 28.71,36.28
RING2_R on TOP (solid shape): 16.99,27.26 16.61,26.88 16.23,26.88 15.98,26.63 15.98,23.83 13.31,21.17 6.66,21.17 6.58,21.2 6.55,21.27 6.2,21.65 5.84,21.27 5.81,21.2 5.74,21.17 5.18,21.17 5.06,21.29 5.06,22.69 5.56,23.2 5.94,22.82 6.2,22.82 6.58,22.44 6.58,22.06 6.71,21.93 7.52,21.93 7.66,21.79 8.47,21.79 8.83,22.15 8.94,22.17 9,22.08 9.22,21.77 9.59,21.83 9.66,21.85 9.72,21.83 10.3,22.11 9.71,22.38 9.65,22.35 9.58,22.37 9.48,22.43 9.37,22.45 9.28,22.52 9.31,22.62 10.14,23.45 13.69,23.45 14.96,24.72 14.96,26.58 15.27,26.93 14.96,27.29 14.96,28.03 15.06,28.12 16.99,28.12
SA_B+ on TOP (solid shape): 65.96,62.82 69.24,62.82 69.24,62.82 69.62,62.82 69.62,62.82 70.21,62.82 70.4,62.63 70.4,61.82 69.62,61.05 66.14,61.05 65.63,61.55 65.63,62.57 65.89,62.82
SA_B+ on BOTTOM (solid shape): 70.2,62.63 70.14,62.57 69.57,62.57 69.47,62.47 69.47,61.6 69.58,61.49 69.58,61.24 69.44,61.1 67.36,61.1 67.03,61.43 66.01,61.43 65.65,61.06 65.07,61.06 64.97,61.07 64.87,61.06 64.26,61.06 64.11,61.2 64.11,62.25 64.71,62.85 66.82,62.85 66.82,62.86 67.09,63.14 70.2,63.14
SA_BST on TOP (solid shape): 63.59,62 63.59,61.25 63.73,61.11 63.73,59.9 63.23,59.41 63.07,59.41 62.84,59.18 61.96,59.18 61.75,59.4 61.75,59.42 61.67,59.64 61.45,59.72 61.42,59.72 60.96,60.19 60.96,60.69 61.19,60.92 61.98,60.92 62.08,60.82 62.08,60.18 62.51,59.75 62.84,59.75 63.22,60.13 63.22,61.05 63.22,61.07 63.34,61.19 63.34,62.02 63.4,62.07 63.52,62.07
SA_LGATE on TOP (solid shape): 65.49,64.37 65.49,63.57 65.41,63.49 65.16,63.49 65.15,63.49 64.4,63.49 64.33,63.55 64.33,64.44 64.49,64.6 65.27,64.6
SA_LGATE on BOTTOM (solid shape): 71.1,65.36 71.1,64.98 70.78,64.66 69.76,64.66 69.63,64.79 69.63,65.73 69.77,65.87 70.59,65.87
SA_LGATE on IN2 (solid shape): 71.04,65.32 71.04,65.05 69.29,63.29 64.88,63.29 64.71,63.47 64.71,64.32 64.97,64.59 66.1,64.59 66.19,64.57 66.29,64.59 67.06,64.59 67.32,64.47 67.59,64.59 68.83,64.59 69.98,65.73 70.64,65.73
SA_SW on TOP (solid shape): 63.09,64.47 63.09,63.59 63,63.49 62.55,63.49 62.14,63.89 61.15,63.89 61.06,63.98 61.06,64.63 61.16,64.73 62.84,64.73
SA_SW on BOTTOM (solid shape): 73.89,68.03 73.89,65.36 74.27,64.98 74.27,63.56 73.53,62.82 72.67,62.82 72.64,62.8 72.64,62 72.67,61.97 73.56,61.97 73.62,61.91 73.62,60.96 73.52,60.85 71.73,60.85 71.48,61.11 71.48,62.7 70.84,63.33 67.7,63.33 67.59,63.45 67.59,64.39 67.69,64.49 70.98,64.49 71.04,64.55 71.05,64.56 72.37,65.87 72.37,68.03 72.49,68.16 73.76,68.16
SA_SW on IN3 (solid shape): outline of 119 points within 61.95,63.18 73.18,68.52
SA_UGATE on TOP (solid shape): 63.09,62 63.09,61.13 63.09,60.18 62.79,59.88 62.56,59.88 62.21,60.23 62.21,61.93 62.34,62.07 63.02,62.07
SA_UGATE on BOTTOM (solid shape): 71.22,62.62 71.22,61.6 71.09,61.47 69.81,61.47 69.66,61.62 69.66,62.28 69.79,62.4 70.16,62.4 70.57,62.82 71.02,62.82
SA_UGATE on IN3 (solid shape): 63.09,62.19 63.09,60.16 62.84,59.9 62.46,59.9 62.21,60.16 62.21,62.19 62.46,62.44 62.84,62.44
SA_UGATE on IN3 (solid shape): 71.22,62.6 71.22,62.07 71.22,62.06 71.22,61.43 71.1,61.3 70.85,61.32 70.64,61.17 70.33,61.17 69.71,61.79 69.33,61.79 69.32,61.81 69.32,62.71 69.6,62.99 70.82,62.99
SLEEVE on TOP (solid shape): 27.97,34.27 27.97,32.28 27.73,32.28 27.68,32.33 27.69,32.38 27.69,33.35 27.44,33.6 27.44,34.27 27.54,34.37 27.63,34.37 27.63,34.37 27.87,34.37
SLEEVE on BOTTOM (solid shape): 10.26,22.46 10.26,21.84 10.1,21.68 7.6,21.68 7.47,21.8 7.47,22.45 7.57,22.55 10.17,22.55
SLEEVE on IN3 (solid shape): outline of 735 points within 8.74,21.04 28.04,34.5
SLEEVE_R on TOP (solid shape): 18.77,27.01 18.77,26.78 18.67,26.53 18.77,26.28 18.77,25.6 18.72,25.51 18.69,25.42 18.69,25.4 18.64,25.36 17.88,25.36 17.76,25.49 17.76,26.38 17.74,26.46 17.8,26.53 17.99,26.73 17.98,27 17.98,27.1 18.06,27.15 18.18,27.18 18.28,27.26 18.52,27.26
SLEEVE_R on BOTTOM (solid shape): outline of 88 points within 5.44,22.82 8.23,25.99
SPK_L+_C on TOP (solid shape): outline of 89 points within 21.49,15.83 24.36,20.41
